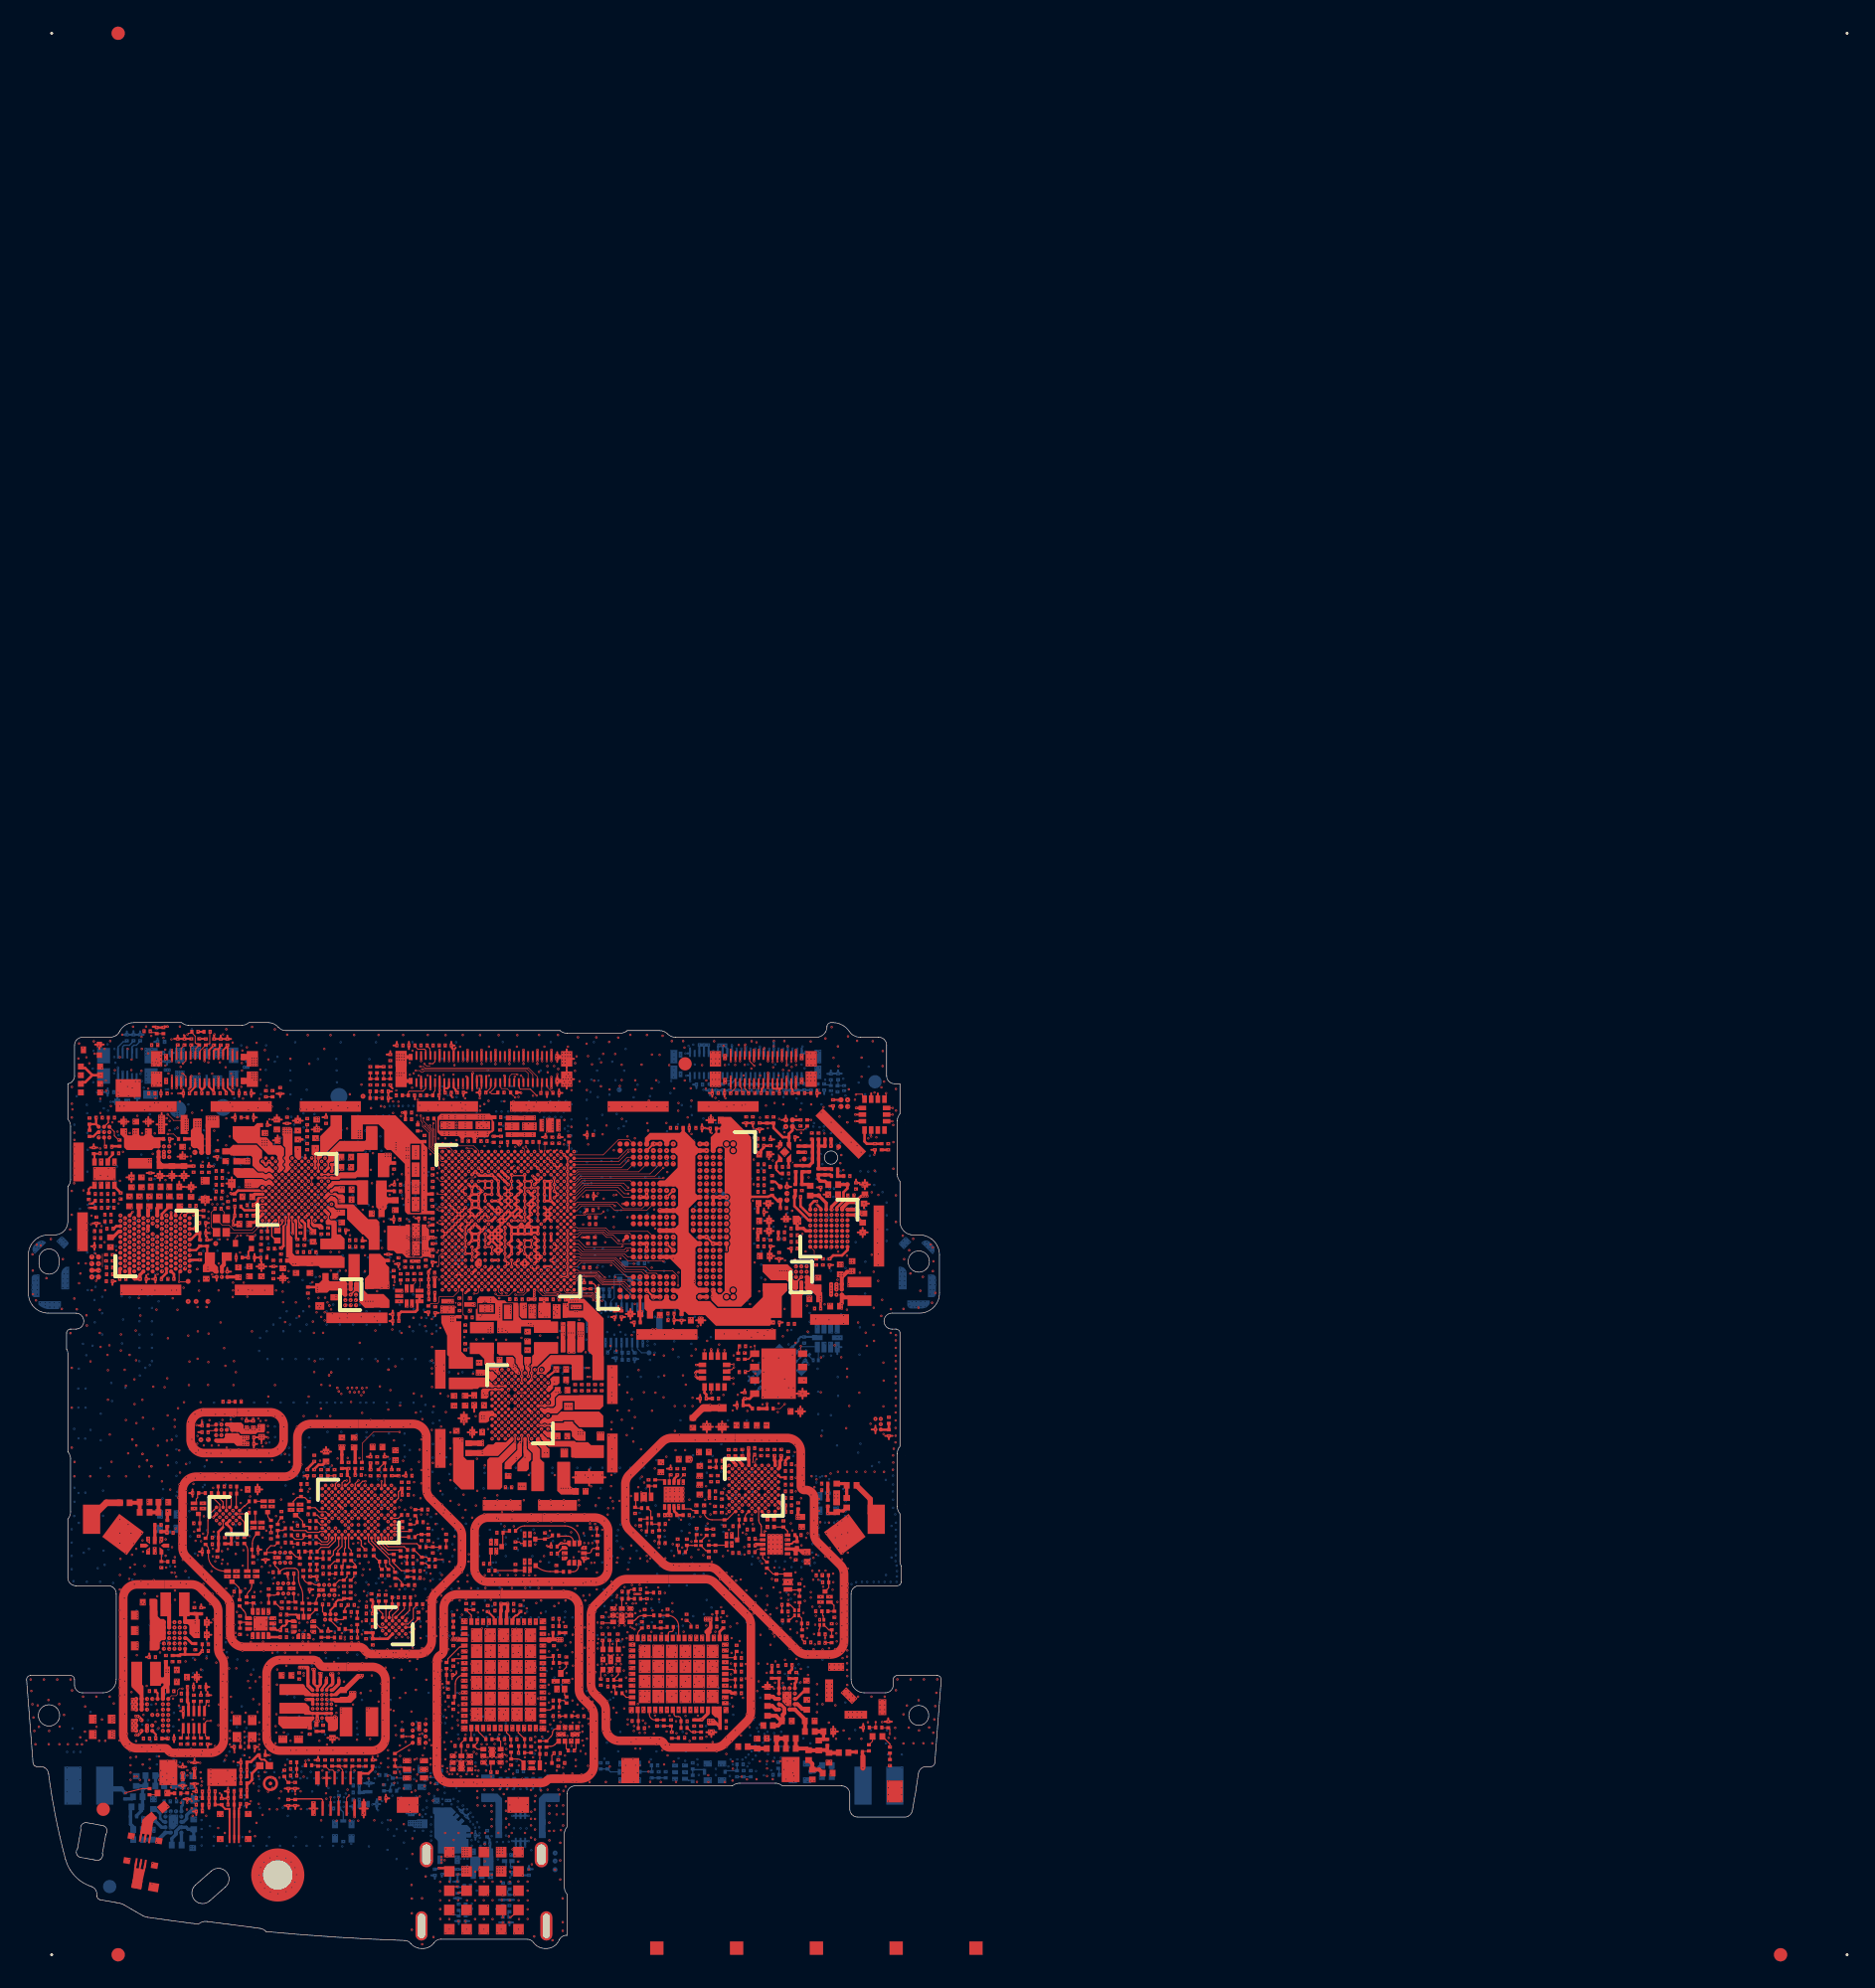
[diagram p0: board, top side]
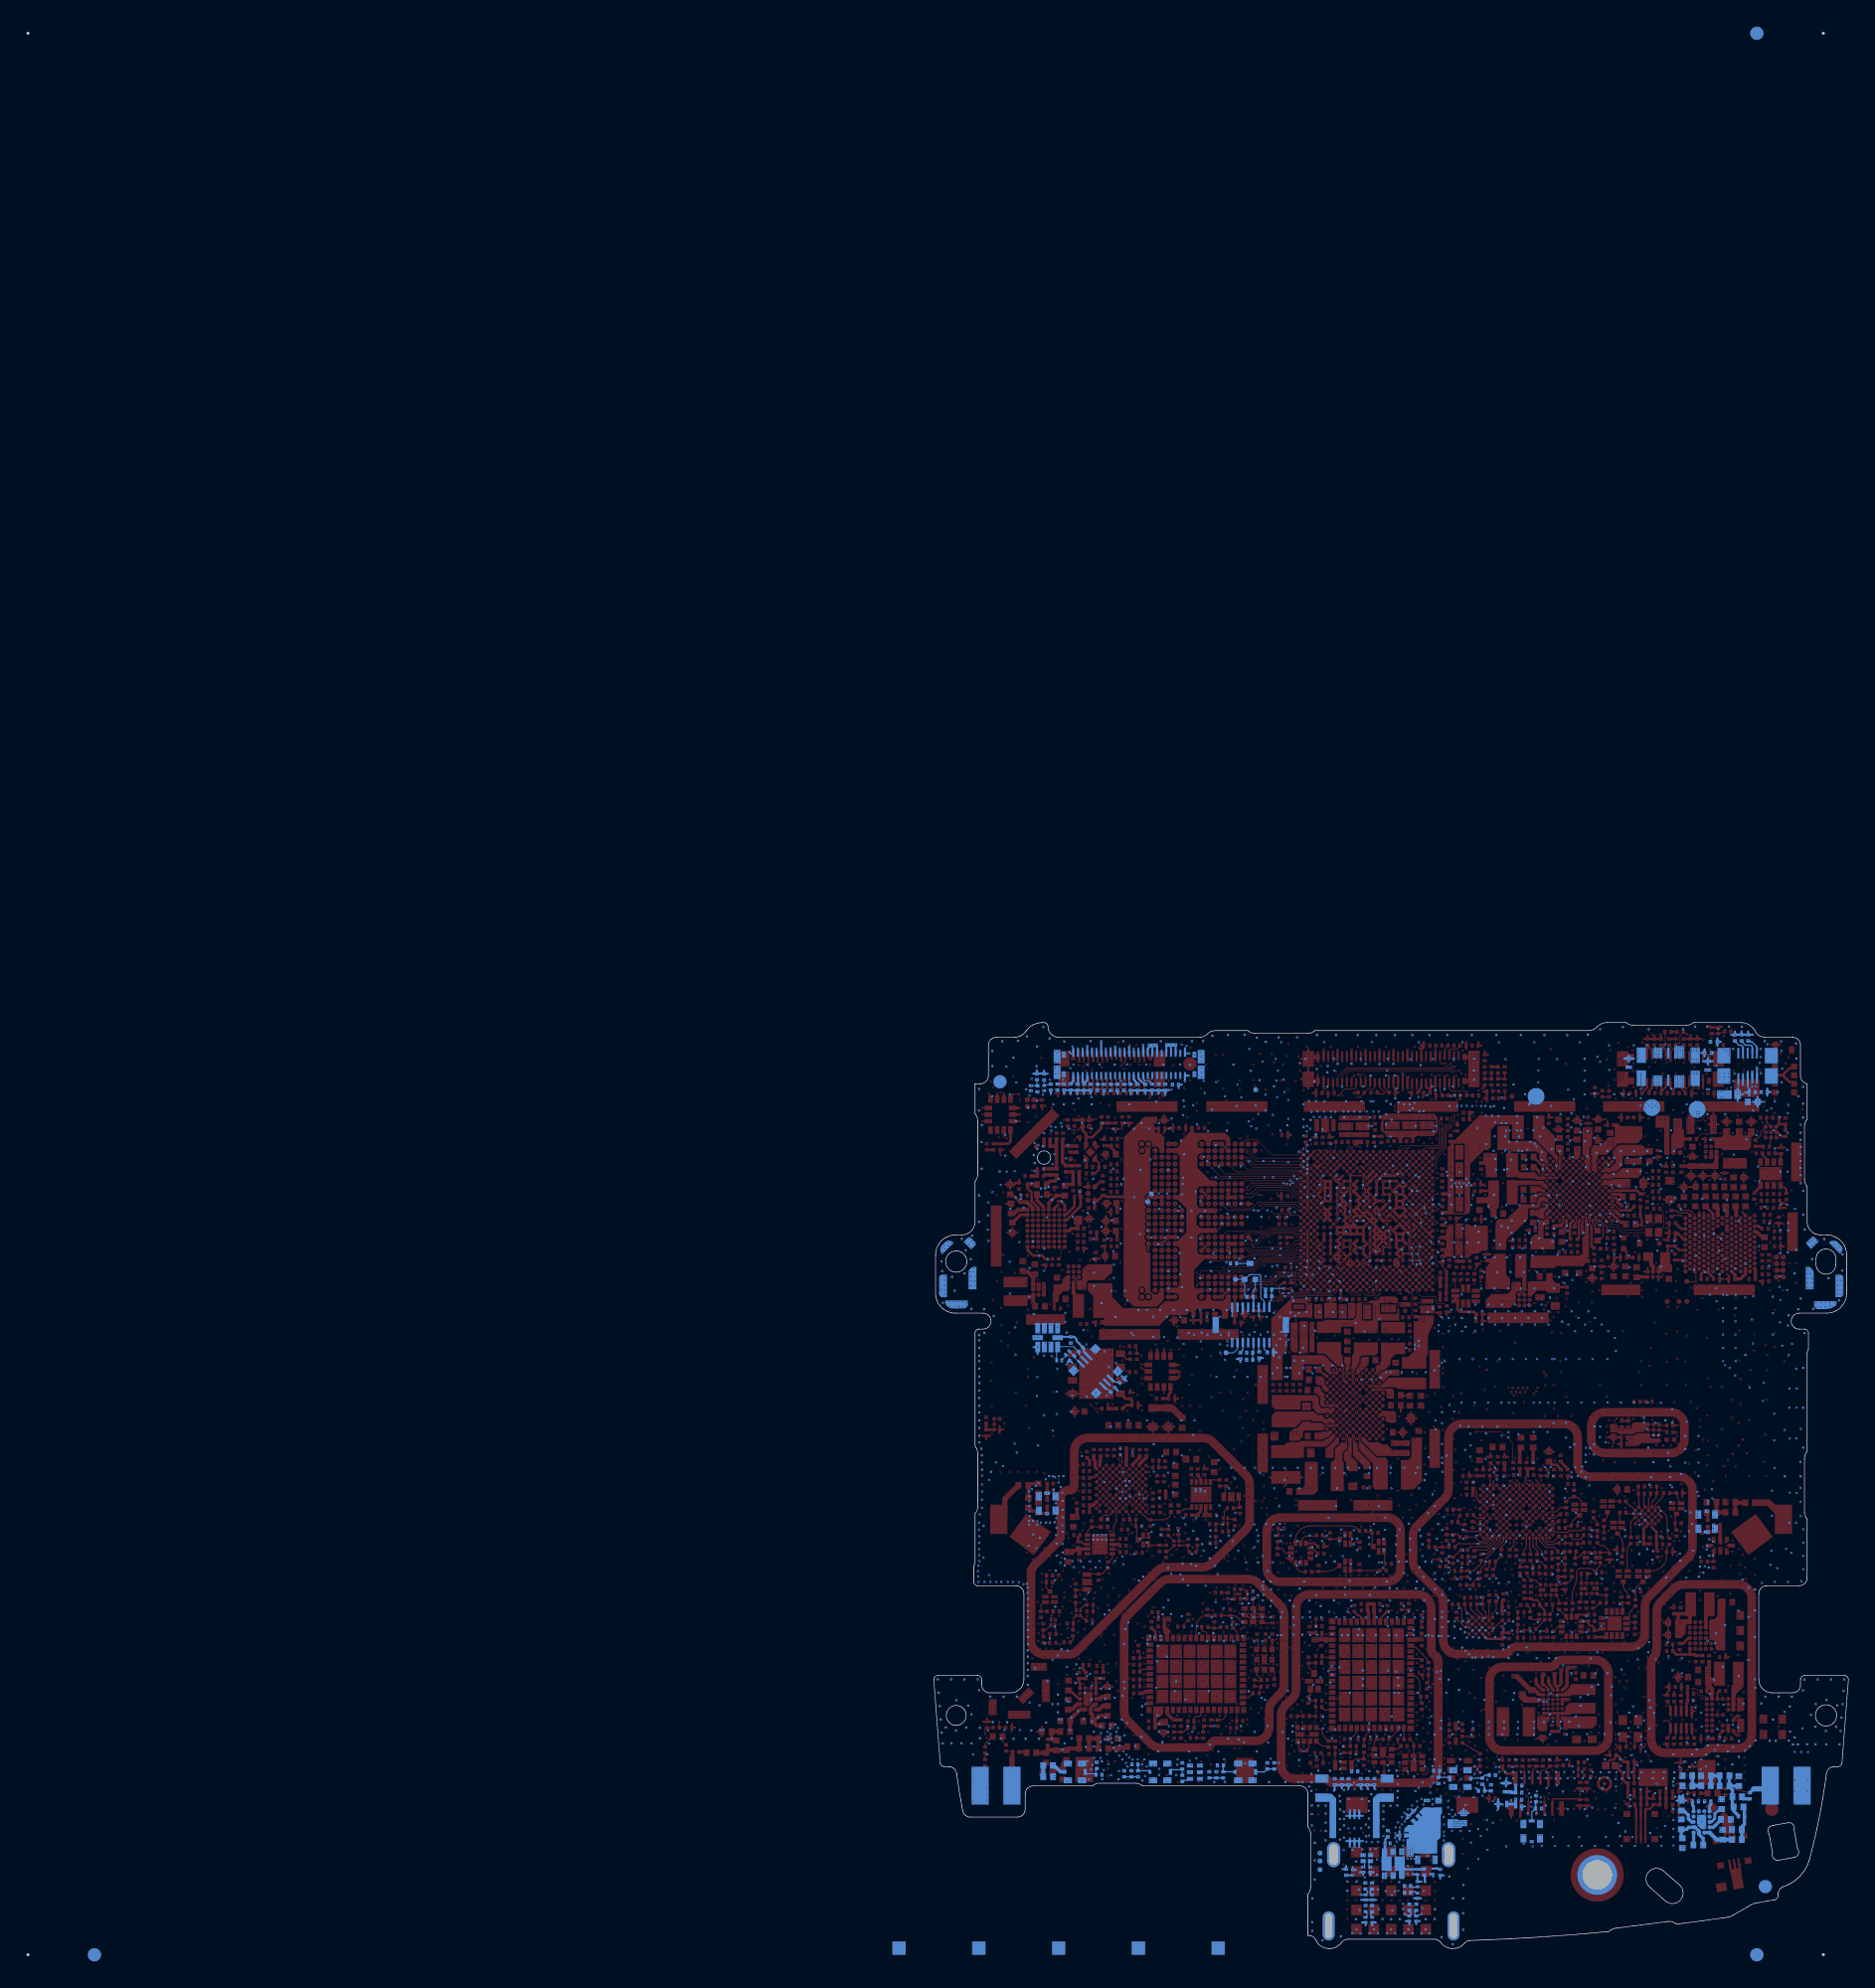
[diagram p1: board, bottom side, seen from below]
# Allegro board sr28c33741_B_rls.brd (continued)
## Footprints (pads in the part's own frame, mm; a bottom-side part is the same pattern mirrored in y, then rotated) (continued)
BGA13X11_5_B0_3_PS0_5_P254_HD
  round 0.4 smd: A1(-5.75,-4.25) A2(-5.75,-3.75) A3(-5.75,-3.25) A4(-5.75,-2.75) A5(-5.75,-2.25) A6(-5.75,-1.75) A7(-5.75,-1.25) A8(-5.75,-0.75) A9(-5.75,-0.25) A13(-5.75,1.75) A14(-5.75,2.25) A15(-5.75,2.75) A16(-5.75,3.25) A17(-5.75,3.75) A18(-5.75,4.25) AA3(4.25,-3.25) AA4(4.25,-2.75) AA5(4.25,-2.25) AA6(4.25,-1.75) AA7(4.25,-1.25) AA8(4.25,-0.75) AA9(4.25,-0.25) AA13(4.25,1.75) AA14(4.25,2.25) AA15(4.25,2.75) AA16(4.25,3.25) AB3(4.75,-3.25) AB4(4.75,-2.75) AB5(4.75,-2.25) AB6(4.75,-1.75) AB7(4.75,-1.25) AB8(4.75,-0.75) AB9(4.75,-0.25) AB13(4.75,1.75) AB14(4.75,2.25) AB15(4.75,2.75) AB16(4.75,3.25) AC1(5.25,-4.25) AC3(5.25,-3.25) AC4(5.25,-2.75) AC5(5.25,-2.25) AC6(5.25,-1.75) AC7(5.25,-1.25) AC8(5.25,-0.75) AC9(5.25,-0.25) AC13(5.25,1.75) AC14(5.25,2.25) AC15(5.25,2.75) AC16(5.25,3.25) AC18(5.25,4.25) AD1(5.75,-4.25) AD2(5.75,-3.75) AD3(5.75,-3.25) AD4(5.75,-2.75) AD5(5.75,-2.25) AD6(5.75,-1.75) AD7(5.75,-1.25) AD8(5.75,-0.75) AD9(5.75,-0.25) AD13(5.75,1.75) AD14(5.75,2.25) AD15(5.75,2.75) AD16(5.75,3.25) AD17(5.75,3.75) AD18(5.75,4.25) B1(-5.25,-4.25) B3(-5.25,-3.25) B4(-5.25,-2.75) B5(-5.25,-2.25) B6(-5.25,-1.75) B7(-5.25,-1.25) B8(-5.25,-0.75) B9(-5.25,-0.25) B13(-5.25,1.75) B14(-5.25,2.25) B15(-5.25,2.75) B16(-5.25,3.25) B18(-5.25,4.25) C3(-4.75,-3.25) C4(-4.75,-2.75) C5(-4.75,-2.25) C6(-4.75,-1.75) C7(-4.75,-1.25) C8(-4.75,-0.75) C9(-4.75,-0.25) C13(-4.75,1.75) C14(-4.75,2.25) C15(-4.75,2.75) C16(-4.75,3.25) D3(-4.25,-3.25) D4(-4.25,-2.75) D5(-4.25,-2.25) D6(-4.25,-1.75) D7(-4.25,-1.25) D8(-4.25,-0.75) D9(-4.25,-0.25) D13(-4.25,1.75) D14(-4.25,2.25) D15(-4.25,2.75) D16(-4.25,3.25) E13(-3.75,1.75) E14(-3.75,2.25) E15(-3.75,2.75) E16(-3.75,3.25) F13(-3.25,1.75) F14(-3.25,2.25) F15(-3.25,2.75) F16(-3.25,3.25) G3(-2.75,-3.25) G4(-2.75,-2.75) G5(-2.75,-2.25) G6(-2.75,-1.75) G7(-2.75,-1.25) G8(-2.75,-0.75) G9(-2.75,-0.25) G13(-2.75,1.75) G14(-2.75,2.25) G15(-2.75,2.75) G16(-2.75,3.25) H3(-2.25,-3.25) H4(-2.25,-2.75) H5(-2.25,-2.25) H6(-2.25,-1.75) H7(-2.25,-1.25) H8(-2.25,-0.75) H9(-2.25,-0.25) H13(-2.25,1.75) H14(-2.25,2.25) H15(-2.25,2.75) H16(-2.25,3.25) J3(-1.75,-3.25) J4(-1.75,-2.75) J5(-1.75,-2.25) J6(-1.75,-1.75) J7(-1.75,-1.25) J8(-1.75,-0.75) J9(-1.75,-0.25) J13(-1.75,1.75) J14(-1.75,2.25) J15(-1.75,2.75) J16(-1.75,3.25) J17(-1.75,3.75) K2(-1.25,-3.75) K3(-1.25,-3.25) K4(-1.25,-2.75) K5(-1.25,-2.25) K6(-1.25,-1.75) K7(-1.25,-1.25) K8(-1.25,-0.75) K9(-1.25,-0.25) K13(-1.25,1.75) K14(-1.25,2.25) K15(-1.25,2.75) K16(-1.25,3.25) K17(-1.25,3.75) L7(-0.75,-1.25) L8(-0.75,-0.75) L9(-0.75,-0.25) L12(-0.75,1.25) L13(-0.75,1.75) L14(-0.75,2.25) L15(-0.75,2.75) L16(-0.75,3.25) L17(-0.75,3.75) M3(-0.25,-3.25) M4(-0.25,-2.75) M5(-0.25,-2.25) M6(-0.25,-1.75) M7(-0.25,-1.25) M8(-0.25,-0.75) M9(-0.25,-0.25) M12(-0.25,1.25) M13(-0.25,1.75) M14(-0.25,2.25) M15(-0.25,2.75) M16(-0.25,3.25) M17(-0.25,3.75) N3(0.25,-3.25) N4(0.25,-2.75) N5(0.25,-2.25) N6(0.25,-1.75) N7(0.25,-1.25) N8(0.25,-0.75) N9(0.25,-0.25) N12(0.25,1.25) N13(0.25,1.75) N14(0.25,2.25) N15(0.25,2.75) N16(0.25,3.25) N17(0.25,3.75) P7(0.75,-1.25) P8(0.75,-0.75) P9(0.75,-0.25) P12(0.75,1.25) P13(0.75,1.75) P14(0.75,2.25) P15(0.75,2.75) P16(0.75,3.25) P17(0.75,3.75) R2(1.25,-3.75) R3(1.25,-3.25) R4(1.25,-2.75) R5(1.25,-2.25) R6(1.25,-1.75) R7(1.25,-1.25) R8(1.25,-0.75) R9(1.25,-0.25) R13(1.25,1.75) R14(1.25,2.25) R15(1.25,2.75) R16(1.25,3.25) R17(1.25,3.75) T3(1.75,-3.25) T4(1.75,-2.75) T5(1.75,-2.25) T6(1.75,-1.75) T7(1.75,-1.25) T8(1.75,-0.75) T9(1.75,-0.25) T13(1.75,1.75) T14(1.75,2.25) T15(1.75,2.75) T16(1.75,3.25) T17(1.75,3.75) U3(2.25,-3.25) U4(2.25,-2.75) U5(2.25,-2.25) U6(2.25,-1.75) U7(2.25,-1.25) U8(2.25,-0.75) U9(2.25,-0.25) U13(2.25,1.75) U14(2.25,2.25) U15(2.25,2.75) U16(2.25,3.25) V3(2.75,-3.25) V4(2.75,-2.75) V5(2.75,-2.25) V6(2.75,-1.75) V7(2.75,-1.25) V8(2.75,-0.75) V9(2.75,-0.25) V13(2.75,1.75) V14(2.75,2.25) V15(2.75,2.75) V16(2.75,3.25) W13(3.25,1.75) W14(3.25,2.25) W15(3.25,2.75) W16(3.25,3.25) Y13(3.75,1.75) Y14(3.75,2.25) Y15(3.75,2.75) Y16(3.75,3.25)
CAP1_2X0_7_HD
  rect 0.45x0.5 smd: 1(-0.37,0) 2(0.37,0)
CAP1_2X0_9_P3_HD
  rect 0.35x0.95 smd: 1(-0.625,0) 3(0.625,0)
  rect 0.6x1.1 smd: 2(0,0)
CAP1X0_5-HT0_5_P3_HD
  rect 0.3x0.3 smd: 1(-0.465,0) 3(0.465,0)
  rect 0.35x0.85 smd: 2(0,0)
CAP0201-HT0_33_HD
  rect 0.25x0.3 smd: 1(-0.23,0) 2(0.23,0)
CAP0201-HT0_35_HD
  rect 0.25x0.3 smd: 1(-0.23,0) 2(0.23,0)
CAP0201_HD
  rect 0.25x0.3 smd: 1(-0.23,0) 2(0.23,0)
CAP0402-HT0_6_HD
  rect 0.45x0.5 smd: 1(-0.37,0) 2(0.37,0)
CAP0402-HT0_55_HD
  rect 0.45x0.5 smd: 1(-0.37,0) 2(0.37,0)
CAP0402-HT0_65_HD
  rect 0.45x0.5 smd: 1(-0.37,0) 2(0.37,0)
CAP0402_1_2X0_7-HT0_65_HD
  rect 0.45x0.5 smd: 1(-0.37,0) 2(0.37,0)
CAP0402_1_2X0_7_HD
  rect 0.45x0.5 smd: 1(-0.37,0) 2(0.37,0)
CAP0603-HT0_6_HD
  rect 0.58x0.68 smd: 1(-0.71,0) 2(0.71,0)
CAP0603-HT1_HD
  rect 0.58x0.68 smd: 1(-0.71,0) 2(0.71,0)
COUPLER0_65X0_5_PS0_39_P4_XD
  rect 0.285x0.215 smd: 1(-0.192,-0.158) 2(0.193,-0.158) 3(0.192,0.158) 4(-0.193,0.158)
CSF1X2JSM_4G_PS1_55-HT0_9_P6_HD
  rect 0.45x0.25 smd: 1(0,-0.773)
  rect 0.3x0.25 smd: 2(0,0.777)
  rect 0.45x0.625 smd: 3(-0.625,-0.536) 4(-0.625,0.54) 5(0.625,0.54) 6(0.625,-0.536)
CSF1X6_1X7R_PS0_6-HT2_14_P13_HD
  rect 1.1x0.36 smd: 1(-1.225,-1.89) 13(-1.225,1.89)
  rect 1x0.36 smd: 2(1.075,-1.59) 12(1.075,1.59)
  rect 1.1x0.18 smd: 3(-1.225,-1.2) 5(-1.225,-0.6) 7(-1.225,0) 9(-1.225,0.6) 11(-1.225,1.2)
  rect 1x0.18 smd: 4(1.075,-0.9) 6(1.075,-0.3) 8(1.075,0.3) 10(1.075,0.9)
CSF2X3BH0_6_4G_PS0_8_P10_HD
  rect 0.71x0.8 smd: 1(-0.8,-1.05) 2(-0.8,1.05) 5(0.8,-1.05) 6(0.8,1.05)
  rect 0.18x0.85 smd: 3(0,-1.025) 4(0,1.025)
  rect 0.7x1.17 smd: G1(-2.025,-0.865) G2(-2.025,0.865) G3(2.025,-0.865) G4(2.025,0.865)
CSF2X3BH0_6_4G_PS0_35_P10_XD
  rect 0.15x0.62 smd: 1(-0.35,-0.94) 2(-0.35,0.94) 3(0,-0.94) 4(0,0.94) 5(0.35,-0.94) 6(0.35,0.94)
  rect 0.51x0.46 smd: G1(-1.055,-0.94) G2(-1.055,0.94) G3(1.055,-0.94) G4(1.055,0.94)
CSF2X3BH0_7_4G_PS0_4-HT0_88_P10_HD
  rect 0.18x0.75 smd: 1(-0.4,-1.175) 2(-0.4,1.175) 3(0,-1.175) 4(0,1.175) 5(0.4,-1.175) 6(0.4,1.175)
  rect 0.6x0.57 smd: G1(-1.15,-1.195) G2(-1.15,1.195) G3(1.15,-1.195) G4(1.15,1.195)
CSF2X3BH1_4G_PS0_35_P10_XD
  rect 0.15x0.5 smd: 1(-0.35,-0.95) 2(-0.35,0.95) 3(0,-0.95) 4(0,0.95) 5(0.35,-0.95) 6(0.35,0.95)
  rect 0.5x0.485 smd: G1(-1.63,-0.482) G2(-1.63,0.482) G3(1.63,-0.482) G4(1.63,0.482)
CSF2X5BH0_7_4G_PS0_35_P14_XD
  rect 0.15x0.8 smd: 1(-0.7,-0.95) 2(-0.7,0.95) 3(-0.35,-0.95) 4(-0.35,0.95) 5(0,-0.95) 6(0,0.95) 7(0.35,-0.95) 8(0.35,0.95) 9(0.7,-0.95) 10(0.7,0.95)
  rect 0.98x1.17 smd: G1(-1.785,-0.765) G2(-1.785,0.765) G3(1.785,-0.765) G4(1.785,0.765)
CSF2X8BH0_98_2G_PS0_4-HT1_08_P18_HD
  rect 0.18x0.73 smd: 1(-1.4,-1.325) 2(-1.4,1.325) 3(-1,-1.325) 4(-1,1.325) 5(-0.6,-1.325) 6(-0.6,1.325) 7(-0.2,-1.325) 8(-0.2,1.325) 9(0.2,-1.325) 10(0.2,1.325) 11(0.6,-1.325) 12(0.6,1.325) 13(1,-1.325) 14(1,1.325) 15(1.4,-1.325) 16(1.4,1.325)
  rect 0.48x1.2 smd: G1(-2.64,0) G2(2.64,0)
CSF2X15BH0_7_PS0_35_P38_XD
  rect 0.15x0.66 smd: 1(-2.45,-1.02) 2(-2.45,1.02) 3(-2.1,-1.02) 4(-2.1,1.02) 5(-1.75,-1.02) 6(-1.75,1.02) 7(-1.4,-1.02) 8(-1.4,1.02) 9(-1.05,-1.02) 10(-1.05,1.02) 11(-0.7,-1.02) 12(-0.7,1.02) 13(-0.35,-1.02) 14(-0.35,1.02) 15(0,-1.02) 16(0,1.02) 17(0.35,-1.02) 18(0.35,1.02) 19(0.7,-1.02) 20(0.7,1.02) 21(1.05,-1.02) 22(1.05,1.02) 23(1.4,-1.02) 24(1.4,1.02) 25(1.75,-1.02) 26(1.75,1.02) 27(2.1,-1.02) 28(2.1,1.02) 29(2.45,-1.02) 30(2.45,1.02)
  rect 0.85x1.17 smd: L1(-3.6,0.765) L2(-3.6,-0.765) R1(3.6,0.765) R2(3.6,-0.765)
  rect 0.3x0.48 smd: L3(-2.885,-0.9) L4(-2.885,0.9) R3(2.885,-0.9) R4(2.885,0.9)
CSF2X25BH0_7_8G_PS0_35_P58_XD
  rect 0.15x0.53 smd: 1(-4.2,-0.835) 2(-4.2,0.835) 3(-3.85,-0.835) 4(-3.85,0.835) 5(-3.5,-0.835) 6(-3.5,0.835) 7(-3.15,-0.835) 8(-3.15,0.835) 9(-2.8,-0.835) 10(-2.8,0.835) 11(-2.45,-0.835) 12(-2.45,0.835) 13(-2.1,-0.835) 14(-2.1,0.835) 15(-1.75,-0.835) 16(-1.75,0.835) 17(-1.4,-0.835) 18(-1.4,0.835) 19(-1.05,-0.835) 20(-1.05,0.835) 21(-0.7,-0.835) 22(-0.7,0.835) 23(-0.35,-0.835) 24(-0.35,0.835) 25(0,-0.835) 26(0,0.835) 27(0.35,-0.835) 28(0.35,0.835) 29(0.7,-0.835) 30(0.7,0.835) 31(1.05,-0.835) 32(1.05,0.835) 33(1.4,-0.835) 34(1.4,0.835) 35(1.75,-0.835) 36(1.75,0.835) 37(2.1,-0.835) 38(2.1,0.835) 39(2.45,-0.835) 40(2.45,0.835) 41(2.8,-0.835) 42(2.8,0.835) 43(3.15,-0.835) 44(3.15,0.835) 45(3.5,-0.835) 46(3.5,0.835) 47(3.85,-0.835) 48(3.85,0.835) 49(4.2,-0.835) 50(4.2,0.835)
  rect 0.52x1.02 smd: G1(-5.415,-0.59) G2(-5.415,0.59) G3(5.415,0.59) G4(5.415,-0.59)
  rect 0.28x0.45 smd: G5(-4.91,0.735) G6(-4.91,-0.735) G7(4.91,-0.735) G8(4.91,0.735)
CSF2X30BH0_7_8G_PS0_35_P68_XD
  rect 0.15x0.66 smd: 1(-5.075,-1.02) 2(-5.075,1.02) 3(-4.725,-1.02) 4(-4.725,1.02) 5(-4.375,-1.02) 6(-4.375,1.02) 7(-4.025,-1.02) 8(-4.025,1.02) 9(-3.675,-1.02) 10(-3.675,1.02) 11(-3.325,-1.02) 12(-3.325,1.02) 13(-2.975,-1.02) 14(-2.975,1.02) 15(-2.625,-1.02) 16(-2.625,1.02) 17(-2.275,-1.02) 18(-2.275,1.02) 19(-1.925,-1.02) 20(-1.925,1.02) 21(-1.575,-1.02) 22(-1.575,1.02) 23(-1.225,-1.02) 24(-1.225,1.02) 25(-0.875,-1.02) 26(-0.875,1.02) 27(-0.525,-1.02) 28(-0.525,1.02) 29(-0.175,-1.02) 30(-0.175,1.02) 31(0.175,-1.02) 32(0.175,1.02) 33(0.525,-1.02) 34(0.525,1.02) 35(0.875,-1.02) 36(0.875,1.02) 37(1.225,-1.02) 38(1.225,1.02) 39(1.575,-1.02) 40(1.575,1.02) 41(1.925,-1.02) 42(1.925,1.02) 43(2.275,-1.02) 44(2.275,1.02) 45(2.625,-1.02) 46(2.625,1.02) 47(2.975,-1.02) 48(2.975,1.02) 49(3.325,-1.02) 50(3.325,1.02) 51(3.675,-1.02) 52(3.675,1.02) 53(4.025,-1.02) 54(4.025,1.02) 55(4.375,-1.02) 56(4.375,1.02) 57(4.725,-1.02) 58(4.725,1.02) 59(5.075,-1.02) 60(5.075,1.02)
  rect 0.85x1.17 smd: L1(-6.225,0.765) L2(-6.225,-0.765) R1(6.225,0.765) R2(6.225,-0.765)
  rect 0.3x0.48 smd: L3(-5.51,-0.9) L4(-5.51,0.9) R3(5.51,-0.9) R4(5.51,0.9)
CSF5X5US_SZ11_09X8_72_4G_PS1_3X1_45_P29_HD
  rect 0.8x0.8 smd: 1(-2.6,2.89) 2(-1.3,2.89) 3(0,2.89) 4(1.3,2.89) 5(2.6,2.89) 6(-2.6,1.44) 7(-1.3,1.44) 8(0,1.44) 9(1.3,1.44) 10(2.6,1.44) 11(-2.6,-0.01) 12(-1.3,-0.01) 13(0,-0.01) 14(1.3,-0.01) 15(2.6,-0.01) 16(-2.6,-1.46) 17(-1.3,-1.46) 18(0,-1.46) 19(1.3,-1.46) 20(2.6,-1.46) 21(-2.6,-2.91) 22(-1.3,-2.91) 23(0,-2.91) 24(1.3,-2.91) 25(2.6,-2.91)
  oval 1x1.9 hole 0.6x1.5: G1(-4.32,2.7) G2(4.32,2.7)
  oval 0.9x2.2 hole 0.5x1.8: G3(4.695,-2.66) G4(-4.695,-2.66)
DFN1_7X2_CTG1_45X1_09_PS0_35_P11_XD
  rect 0.25x0.43 smd: 1(-0.7,-0.935) 2(-0.35,-0.935) 3(0,-0.935) 4(0.35,-0.935) 5(0.7,-0.935) 6(0.7,0.935) 7(0.35,0.935) 8(0,0.935) 9(-0.35,0.935) 10(-0.7,0.935)
  rect 1.55x1.19 smd: G1(0,0)
DFN1SQ_CTG0_48SQ_PS0_65_P5_HD
  custom 0.087x0.087 smd: 1(-0.325,-0.43) 2(0.325,-0.43) 3(0.325,0.43) 4(-0.325,0.43)
  rect 0.53x0.53 smd rot 45: G1(0,0)
DFN2_1X1_8_PS0_4_P10_HD
  rect 0.22x0.79 smd: 1(-0.8,-0.645) 2(-0.4,-0.645) 3(0,-0.645) 4(0.4,-0.645) 5(0.8,-0.645) 6(0.8,0.645) 7(0.4,0.645) 8(0,0.645) 9(-0.4,0.645) 10(-0.8,0.645)
DFN2SQ_CTG1_6X0_9_PS0_5_P9_HD
  rect 0.35x0.55 smd: 1(-0.75,-0.875) 2(-0.25,-0.875) 3(0.25,-0.875) 4(0.75,-0.875) 5(0.75,0.875) 6(0.25,0.875) 7(-0.25,0.875) 8(-0.75,0.875)
  rect 1.7x1 smd: G1(0,0)
DFN2SQ_PS0_65_P8_HD
  rect 0.4x0.5 smd: 1(-0.65,-0.9) 2(0,-0.9) 3(0.65,-0.9) 4(0.65,0.9) 5(0,0.9) 6(-0.65,0.9)
  rect 0.77x1.1 smd: 7(-0.49,0) 8(0.49,0)
DFN4_2X4_CTG3_8X2_6_PS1_P9_HD
  rect 0.5x0.7 smd: 1(-1.5,-1.8) 2(-0.5,-1.8) 3(0.5,-1.8) 4(1.5,-1.8) 5(1.5,1.8) 6(0.5,1.8) 7(-0.5,1.8) 8(-1.5,1.8)
  rect 3.8x2.6 smd: G1(0,0)
DIO0_6X0_3-HT0_32_HD
  rect 0.25x0.3 smd: 1(-0.23,0) 2(0.23,0)
DIO0_6X0_3_PS0_4-HT0_32_HD
  rect 0.15x0.25 smd: 1(-0.2,0) 2(0.2,0)
DIO0_6X0_3_PS0_38_HD
  rect 0.21x0.3 smd: 1(-0.19,0) 2(0.19,0)
DIO0_6X0_3_PS0_525-HT0_33_HD
  rect 0.275x0.3 smd: 1(-0.263,0) 2(0.263,0)
DIO0_6X0_3BI_HD
  rect 0.25x0.3 smd: 1(-0.23,0) 2(0.23,0)
DIO0_6X0_3BI_PS0_38_HD
  rect 0.21x0.3 smd: 1(-0.19,0) 2(0.19,0)
DIO0_62X0_32-HT0_27_HD
  rect 0.25x0.3 smd: 1(-0.23,0) 2(0.23,0)
DIO1_6X0_8K1A2_HD
  rect 1.12x0.645 smd: 1(-0.345,0)
  rect 0.49x0.71 smd: 2(0.66,0)
DIO1X0_6_PS0_65_HD
  rect 0.25x0.5 smd: 1(-0.325,0) 2(0.325,0)
DIO1X0_6BI_HD
  rect 0.25x0.5 smd: 1(-0.325,0) 2(0.325,0)
DIO1X0_6K1A2_PS0_65_HD
  rect 0.25x0.5 smd: 1(-0.325,0) 2(0.325,0)
DIO2SQ_PS1_3_P3_HD
  rect 0.4x0.65 smd: 1(-0.65,-0.825) 2(0.65,-0.825)
  custom 0.375x0.375 smd: 3(0,0.4)
FLTR0_8X1_6_P4_HD
  rect 0.75x0.325 smd: 1(0,-0.613) 3(0,0.613)
  rect 0.32x0.5 smd: 2(0.215,0) 4(-0.215,0)
FLTR0_8X1_6_PS0_5-HT0_7_P6_HD
  rect 0.45x0.3 smd: 1(-0.375,-0.5) 2(-0.375,0) 3(-0.375,0.5) 4(0.375,0.5) 5(0.375,0) 6(0.375,-0.5)
FLTR1_1X0_9-HT0_5_P5_HD
  rect 0.35x0.4 smd: 1(-0.4,0)
  rect 0.3x0.52 smd: 2(0,-0.335) 3(0.4,-0.335) 4(0.4,0.335) 5(0,0.335)
FLTR1_1X0_9_PS0_4X0_5_P5_HD
  rect 0.33x0.38 smd: 1(-0.4,0)
  rect 0.28x0.5 smd: 2(0,-0.335) 3(0.4,-0.335) 4(0.4,0.335) 5(0,0.335)
FLTR1_1X0_9_PS0_4X0_55_P5_HD
  rect 0.33x0.38 smd: 1(-0.425,0)
  rect 0.28x0.5 smd: 2(0,-0.3) 3(0.4,-0.3) 4(0.4,0.3) 5(0,0.3)
FLTR1_5X1_1_PS0_39-HT0_5_P10_HD
  round 0.31 smd: 1(-0.585,-0.385) 2(-0.195,-0.385) 3(0.195,-0.385) 4(0.585,-0.385) 6(0.585,0.385) 7(0.195,0.385) 8(-0.195,0.385) 9(-0.585,0.385)
  rect 0.49x0.28 smd: 5(0.48,0)
  rect 0.59x0.28 smd: 10(-0.43,0)
FLTR1_6X0_8-HT0_65_P3_HD
  rect 0.35x0.65 smd: 1(-0.555,0) 3(0.555,0)
  rect 0.5x0.7 smd: 2(0,0)
FLTR1_6X0_8_PS0_5-HT0_7_P8_HD
  custom 0.075x0.075 smd: 1(-0.5,-0.39) 3(0.5,-0.39) 4(0.77,0) 5(0.5,0.39) 7(-0.5,0.39) 8(-0.77,0)
  rect 0.3x0.58 smd: 2(0,-0.39) 6(0,0.39)
FLTR1_8X1_4_PS0_45_P10_HD
  round 0.32 smd: 1(-0.7,-0.485) 2(-0.225,-0.485) 3(0.225,-0.485) 4(0.7,-0.485) 6(0.7,0.485) 7(0.225,0.485) 8(-0.225,0.485) 9(-0.7,0.485)
  rect 0.7x0.3 smd: 5(0.525,0)
  rect 0.6x0.3 smd: 10(-0.575,0)
FLTR1_8X1_4_PS0_65-HT0_48_P8_HD
  rect 0.45x0.35 smd: 1(-0.65,-0.5) 3(0.65,-0.5) 4(0.65,0) 5(0.65,0.5) 6(0,0.5) 7(-0.65,0.5) 8(-0.65,0)
  rect 0.45x0.8 smd: 2(0,-0.275)
FLTR1_8X1_4_PS0_65_P8_HD
  rect 0.45x0.35 smd: 1(-0.65,-0.5) 3(0.65,-0.5) 4(0.65,0) 5(0.65,0.5) 6(0,0.5) 7(-0.65,0.5) 8(-0.65,0)
  rect 0.45x0.85 smd: 2(0,-0.25)
FLTR1_8X1_35-HT0_5_P10_HD
  rect 0.35x0.4 smd: 1(-0.705,-0.515) 2(-0.235,-0.515) 3(0.235,-0.515) 4(0.705,-0.515) 6(0.705,0.515) 7(0.235,0.515) 8(-0.235,0.515) 9(-0.705,0.515)
  rect 0.7x0.35 smd: 5(0.52,0) 10(-0.52,0)
FLTR1_35X1_05CCW-HT0_5_P5_HD
  rect 0.525x0.425 smd: 1(-0.587,0) 3(0.587,-0.287) 4(0.587,0.287)
  rect 0.35x0.625 smd: 2(0,-0.387) 5(0,0.387)
FLTR1X0_5_P4_HD
  rect 0.27x0.3 smd: 1(-0.48,0) 3(0.48,0)
  rect 0.3x0.25 smd: 2(0,0.24) 4(0,-0.24)
FLTR1X0_5_PS0_5_P4_HD
  rect 0.3x0.32 smd: 1(-0.25,-0.29) 2(0.25,-0.29) 3(0.25,0.29) 4(-0.25,0.29)
FLTR2_5X2_PS0_65_P6_HD
  rect 0.4x0.625 smd: 1(-0.65,-0.637) 2(0,-0.637) 3(0.65,-0.637) 4(0.65,0.637) 5(0,0.637) 6(-0.65,0.637)
FLTR2X1_6_PS0_76X0_58_P9_HD
  rect 0.43x0.39 smd: 1(-0.76,-0.58) 2(0,-0.58) 3(0.76,-0.58) 4(0.76,0) 5(0.76,0.58) 6(0,0.58) 7(-0.76,0.58) 8(-0.76,0)
  rect 0.71x0.39 smd: 9(0,0)
IND0_5X0_65-HT0_35_P4_HD
  rect 0.3x0.4 smd: 1(-0.225,-0.275) 2(-0.225,0.275) 3(0.225,0.275) 4(0.225,-0.275)
IND2_5X2_PS1_95_HD
  rect 0.95x2.2 smd: 1(-0.975,0) 2(0.975,0)
IND2X1_6_PS1_4_HD
  rect 0.8x1.8 smd: 1(-0.7,0) 2(0.7,0)
IND2X1_6_PS1_55_HD
  rect 0.85x1.8 smd: 1(-0.775,0) 2(0.775,0)
IND0201-HT0_33_HD
  rect 0.25x0.3 smd: 1(-0.23,0) 2(0.23,0)
IND0201-HT0_35_HD
  rect 0.25x0.3 smd: 1(-0.23,0) 2(0.23,0)
IND0603-HT0_95_HD
  rect 0.76x0.65 smd: 1(-0.635,0) 2(0.635,0)
IND0603_HD
  rect 0.76x0.65 smd: 1(-0.635,0) 2(0.635,0)
IND0603_SZ1_65X0_99-HT1_HD
  rect 0.61x0.99 smd: 1(-0.72,0) 2(0.72,0)
IND1005-HT0_6_HD
  rect 0.45x0.5 smd: 1(-0.37,0) 2(0.37,0)
INDP0402-HT0_55_HD
  rect 0.45x0.5 smd: 1(-0.37,0) 2(0.37,0)
LGA1_1X0_7-HT0_4_P6_HD
  round 0.32 smd: 1(-0.4,-0.2) 2(0,-0.2) 3(0.4,-0.2) 4(0.4,0.2) 5(0,0.2) 6(-0.4,0.2)
LGA1_6SQ_PS0_4_P12_XD
  custom 0.075x0.075 smd: 1(-0.4,-0.725) 3(0.4,-0.725) 4(0.725,-0.4) 6(0.725,0.4) 7(0.4,0.725) 9(-0.4,0.725) 10(-0.725,0.4) 12(-0.725,-0.4)
  rect 0.3x0.45 smd: 2(0,-0.725) 8(0,0.725)
  rect 0.45x0.3 smd: 5(0.725,0) 11(-0.725,0)
LGA1_6X2_CTG0_6X1_PS0_4_P15_HD
  round 0.32 smd: 1(-0.6,-0.8) 2(-0.2,-0.8) 3(0.2,-0.8) 4(0.6,-0.8) 5(0.6,-0.4) 6(0.6,0) 7(0.6,0.4) 8(0.6,0.8) 9(0.2,0.8) 10(-0.2,0.8) 11(-0.6,0.8) 12(-0.6,0.4) 13(-0.6,0) 14(-0.6,-0.4)
  custom 0.175x0.175 smd: 15(0,0)
LGA2_5X3_PS0_5_P14_HD
  rect 0.35x0.575 smd: 1(-0.75,-1.162) 2(-0.25,-1.162) 3(0.25,-1.162) 4(0.75,-1.162) 8(0.75,1.162) 9(0.25,1.162) 10(-0.25,1.162) 11(-0.75,1.162)
  rect 0.575x0.35 smd: 5(0.912,-0.5) 6(0.912,0) 7(0.912,0.5) 12(-0.912,0.5) 13(-0.912,0) 14(-0.912,-0.5)
LGA2X2_5_PS0_65-HT1_P8_HD
  rect 0.45x0.45 smd: 1(-0.725,-0.975) 2(-0.725,-0.325) 3(-0.725,0.325) 4(-0.725,0.975) 5(0.725,0.975) 6(0.725,0.325) 7(0.725,-0.325) 8(0.725,-0.975)
MECH0_7X2_83_HD
  rect 0.8x2.93 smd: 1(0,0)
MECH0_7X4_5_HD
  rect 0.8x4.6 smd: 1(0,0)
MECH1_2X2_5_HD
  rect 1.3x2.2 smd: 1(0,-0.3)
MECH1_2X3_45EL2_76_HD
  rect 1.3x2.86 smd: 1(0,-0.345)
MECH1_8X4_52-HT0_93_HD
  rect 1.9x1.35 smd: 1(0,-1.633)
MECH2_2X5_09_HD
  rect 2.3x2.15 smd: 1(0,-1.518)
MECH2_4X1_1_HD
  rect 1.64x1.2 smd: 1(0.43,0)
MECH2_97X5_472MX_HD
  custom 0.15x0.15 smd: 1(-0.015,-2.386) 2(1.185,-0.396) 5(-1.026,-0.986)
  custom 0.15x0.15 smd rot 45: 3(1.016,2.249)
  custom 0.125x0.125 smd rot 135: 4(-0.827,1.996)
MECH2_97X5_507_HD
  custom 0.15x0.15 smd: 1(-0.015,-2.454) 2(1.045,-1.004) 5(-1.185,-0.413)
  custom 0.125x0.125 smd rot 45: 3(0.851,2.001)
  custom 0.15x0.15 smd rot 135: 4(-1.005,2.268)
MECH4_5X4_1_HD
  rect 1.7x0.6 smd: 1(0.005,-1.8)
  rect 0.6x1.2 smd: 2(2,-1.232)
  rect 1.2x0.6 smd rot 135: 3(-0.501,-0.367)
  rect 1.2x0.6 smd: 4(-1.471,1.8)
  rect 0.6x1.7 smd: 5(-2,0.013)
PA7_6X6_CTG24_PS0_44_P80_HD
  rect 0.39x0.47 smd: 1(-3.555,-2.715) 17(3.555,-2.715) 29(3.555,2.715) 45(-3.555,2.715)
  rect 0.32x0.5 smd: 2(-3.08,-2.7) 3(-2.64,-2.7) 4(-2.2,-2.7) 5(-1.76,-2.7) 6(-1.32,-2.7) 7(-0.88,-2.7) 8(-0.44,-2.7) 9(0,-2.7) 10(0.44,-2.7) 11(0.88,-2.7) 12(1.32,-2.7) 13(1.76,-2.7) 14(2.2,-2.7) 15(2.64,-2.7) 16(3.08,-2.7) 30(3.08,2.7) 31(2.64,2.7) 32(2.2,2.7) 33(1.76,2.7) 34(1.32,2.7) 35(0.88,2.7) 36(0.44,2.7) 37(0,2.7) 38(-0.44,2.7) 39(-0.88,2.7) 40(-1.32,2.7) 41(-1.76,2.7) 42(-2.2,2.7) 43(-2.64,2.7) 44(-3.08,2.7)
  rect 0.5x0.32 smd: 18(3.5,-2.2) 19(3.5,-1.76) 20(3.5,-1.32) 21(3.5,-0.88) 22(3.5,-0.44) 23(3.5,0) 24(3.5,0.44) 25(3.5,0.88) 26(3.5,1.32) 27(3.5,1.76) 28(3.5,2.2) 46(-3.5,2.2) 47(-3.5,1.76) 48(-3.5,1.32) 49(-3.5,0.88) 50(-3.5,0.44) 51(-3.5,0) 52(-3.5,-0.44) 53(-3.5,-0.88) 54(-3.5,-1.32) 55(-3.5,-1.76) 56(-3.5,-2.2)
  rect 0.9x1.01 smd: G1(-2.55,1.695) G2(-1.53,1.695) G3(-0.51,1.695) G4(0.51,1.695) G5(1.53,1.695) G6(2.55,1.695) G7(-2.55,0.565) G8(-1.53,0.565) G9(-0.51,0.565) G10(0.51,0.565) G11(1.53,0.565) G12(2.55,0.565) G13(-2.55,-0.565) G14(-1.53,-0.565) G15(-0.51,-0.565) G16(0.51,-0.565) G17(1.53,-0.565) G18(2.55,-0.565) G19(-2.55,-1.695) G20(-1.53,-1.695) G21(-0.51,-1.695) G22(0.51,-1.695) G23(1.53,-1.695) G24(2.55,-1.695)
PA8_6X6_5_CTG_PS0_44_P62_HD
  rect 0.45x0.5 smd: 1(-4.025,-2.95) 19(4.025,-2.95) 32(4.025,2.95) 50(-4.025,2.95)
  rect 0.32x0.5 smd: 2(-3.52,-2.95) 3(-3.08,-2.95) 4(-2.64,-2.95) 5(-2.2,-2.95) 6(-1.76,-2.95) 7(-1.32,-2.95) 8(-0.88,-2.95) 9(-0.44,-2.95) 10(0,-2.95) 11(0.44,-2.95) 12(0.88,-2.95) 13(1.32,-2.95) 14(1.76,-2.95) 15(2.2,-2.95) 16(2.64,-2.95) 17(3.08,-2.95) 18(3.52,-2.95) 33(3.52,2.95) 34(3.08,2.95) 35(2.64,2.95) 36(2.2,2.95) 37(1.76,2.95) 38(1.32,2.95) 39(0.88,2.95) 40(0.44,2.95) 41(0,2.95) 42(-0.44,2.95) 43(-0.88,2.95) 44(-1.32,2.95) 45(-1.76,2.95) 46(-2.2,2.95) 47(-2.64,2.95) 48(-3.08,2.95) 49(-3.52,2.95)
  rect 0.5x0.32 smd: 20(4,-2.42) 21(4,-1.98) 22(4,-1.54) 23(4,-1.1) 24(4,-0.66) 25(4,-0.22) 26(4,0.22) 27(4,0.66) 28(4,1.1) 29(4,1.54) 30(4,1.98) 31(4,2.42) 51(-4,2.42) 52(-4,1.98) 53(-4,1.54) 54(-4,1.1) 55(-4,0.66) 56(-4,0.22) 57(-4,-0.22) 58(-4,-0.66) 59(-4,-1.1) 60(-4,-1.54) 61(-4,-1.98) 62(-4,-2.42)
  rect 1.05x0.86 smd: G1(-2.975,2.02) G2(-1.785,2.02) G3(-0.595,2.02) G4(0.595,2.02) G5(1.785,2.02) G6(2.975,2.02) G7(-2.975,1.01) G8(-1.785,1.01) G9(-0.595,1.01) G10(0.595,1.01) G11(1.785,1.01) G12(2.975,1.01) G13(-2.975,0) G14(-1.785,0) G15(-0.595,0) G16(0.595,0) G17(1.785,0) G18(2.975,0) G19(-2.975,-1.01) G20(-1.785,-1.01) G21(-0.595,-1.01) G22(0.595,-1.01) G23(1.785,-1.01) G24(2.975,-1.01) G25(-2.975,-2.02) G26(-1.785,-2.02) G27(-0.595,-2.02) G28(0.595,-2.02) G29(1.785,-2.02) G30(2.975,-2.02)
QFN1_8X1_4_PS0_4-HT0_55_P10_HD
  rect 0.3x0.62 smd: 1(-0.2,-0.565) 2(0.2,-0.565) 6(0.2,0.565) 7(-0.2,0.565)
  rect 0.62x0.3 smd: 3(0.765,-0.4) 4(0.765,0) 5(0.765,0.4) 8(-0.765,0.4) 9(-0.765,0) 10(-0.765,-0.4)
QFN2SQ_CTG0_98SQ_PS0_4-HT0_6_P15_HD
  custom 0.075x0.075 smd: 1(-0.4,-0.905) 3(0.4,-0.905) 4(0.905,-0.6) 7(0.905,0.6) 8(0.4,0.905) 10(-0.4,0.905) 11(-0.905,0.6) 14(-0.905,-0.6)
  rect 0.3x0.53 smd: 2(0,-0.905) 9(0,0.905)
  rect 0.53x0.3 smd: 5(0.905,-0.2) 6(0.905,0.2) 12(-0.905,0.2) 13(-0.905,-0.2)
  rect 1.08x1.08 smd: G1(0,0)
QFN2X1_5_PS0_5-HT0_6_P10_HD
  rect 0.38x0.8 smd: 1(-0.75,-0.71) 2(-0.25,-0.71) 3(0.25,-0.71) 4(0.75,-0.71) 6(0.75,0.71) 7(0.25,0.71) 8(-0.25,0.71) 9(-0.75,0.71)
  rect 0.8x0.38 smd: 5(0.75,0) 10(-0.75,0)
RES0201-HT0_26_HD
  rect 0.25x0.3 smd: 1(-0.23,0) 2(0.23,0)
RES0201-HT0_28_HD
  rect 0.25x0.3 smd: 1(-0.23,0) 2(0.23,0)
RES0201-HT0_33_HD
  rect 0.25x0.3 smd: 1(-0.23,0) 2(0.23,0)
RES0402-HT0_4_HD
  rect 0.45x0.5 smd: 1(-0.36,0) 2(0.36,0)
RES0603-HT0_6_HD
  rect 0.64x0.68 smd: 1(-0.66,0) 2(0.66,0)
RES0805-HT0_4_HD
  rect 0.53x1.45 smd: 1(-0.84,0) 2(0.84,0)
SD_L1
  round 0.1 smd: 1(0,0) 2(0,0)
SHIELD_DRX_HB_SM88C42467
  rect 0.05x0.05 smd: 1(0.117,-2.321)
SHIELD_LB_PA_SM88C42473
  rect 0.05x0.05 smd: 1(1.732,-6.294)
SHIELD_MBHB_PA_SM88C42472
  rect 0.05x0.05 smd: 1(-1.613,-7.001)
SHIELD_OVP_SM88C46177
  rect 0.05x0.05 smd: 1(0.107,-1.431)
SHIELD_QET_SM88C42471
  rect 0.05x0.05 smd: 1(-0.783,-3.391)
SHIELD_SND_BST_SM88C42469
  rect 0.05x0.05 smd: 1(0.942,-6.236)
SHIELD_WIFI_SM88C42468
  rect 0.05x0.05 smd: 1(-3.225,-1.47)
SHIELD_WTR_SM88C42466
  rect 0.05x0.05 smd: 1(0.262,-8.015)
SOT0_8X1_2RB_PS0_8-HT0_55_P3_HD
  rect 0.4x0.42 smd: 1(0.6,-0.4) 2(0.6,0.4)
  rect 0.4x0.52 smd: 3(-0.6,0)
SPACER4C_TH_HD
  round 4 hole 2.2: 1(0,0)
TPSM0_38CAU_HD
  round 0.38 smd: 1(0,0)
TPSM0_175CNG_HD
  round 0.175 smd: 1(0,0)
TPSM1_27CAU_HD
  round 1.27 smd: 1(0,0)
unnamed
  round 0.01 hole 1.2 unplated: (-1.8,-0.6) (1.8,-0.6)
unnamed#3
  round 1 smd: (0,0)
unnamed#4
  round 0.01 hole 1.2 unplated: (-1.35,-0.6) (1.35,-0.6)
WLCSP0_78X1_18_B0_22_PS0_4_P5_HD
  round 0.32 smd: A1(-0.2,-0.4) A3(-0.2,0.4) B1(0.2,-0.4) B2(0.2,0) B3(0.2,0.4)
WLCSP2_64X2_02_B0_22_PS0_35_P34_XD
  round 0.28 smd: 1(-1.05,-0.7) 2(-1.05,-0.35) 3(-1.05,0) 4(-1.05,0.35) 5(-1.05,0.7) 6(-0.7,-0.7) 7(-0.7,-0.35) 8(-0.7,0.35) 9(-0.7,0.7) 10(-0.35,-0.7) 11(-0.35,-0.35) 12(-0.35,0) 13(-0.35,0.35) 14(-0.35,0.7) 15(0,-0.7) 16(0,-0.35) 17(0,0) 18(0,0.35) 19(0,0.7) 20(0.35,-0.7) 21(0.35,-0.35) 22(0.35,0) 23(0.35,0.35) 24(0.35,0.7) 25(0.7,-0.7) 26(0.7,-0.35) 27(0.7,0) 28(0.7,0.35) 29(0.7,0.7) 30(1.05,-0.7) 31(1.05,-0.35) 32(1.05,0) 33(1.05,0.35) 34(1.05,0.7)
WLCSP4_65X5_58_PS0_35_P196_XD
  round 0.28 smd: 1(-2.104,-2.599) 2(-2.104,-2.104) 3(-2.104,-1.609) 4(-2.104,-1.114) 5(-2.104,-0.619) 6(-2.104,-0.124) 7(-2.104,0.371) 8(-2.104,0.866) 9(-2.104,1.361) 10(-2.104,1.856) 11(-2.104,2.351) 12(-1.856,-2.351) 13(-1.856,-1.856) 14(-1.856,-1.361) 15(-1.856,-0.866) 16(-1.856,-0.371) 17(-1.856,0.124) 18(-1.856,0.619) 19(-1.856,1.114) 20(-1.856,1.609) 21(-1.856,2.104) 22(-1.856,2.599) 23(-1.609,-2.599) 24(-1.609,-2.104) 25(-1.609,-1.609) 26(-1.609,-1.114) 27(-1.609,-0.619) 28(-1.609,-0.124) 29(-1.609,0.371) 30(-1.609,0.866) 31(-1.609,1.361) 32(-1.609,1.856) 33(-1.609,2.351) 34(-1.361,-2.351) 35(-1.361,-1.856) 36(-1.361,-1.361) 37(-1.361,-0.866) 38(-1.361,-0.371) 39(-1.361,0.124) 40(-1.361,0.619) 41(-1.361,1.114) 42(-1.361,1.609) 43(-1.361,2.104) 44(-1.361,2.599) 45(-1.114,-2.599) 46(-1.114,-2.104) 47(-1.114,-1.609) 48(-1.114,-1.114) 49(-1.114,-0.619) 50(-1.114,-0.124) 51(-1.114,0.371) 52(-1.114,0.866) 53(-1.114,1.361) 54(-1.114,1.856) 55(-1.114,2.351) 56(-0.866,-2.351) 57(-0.866,-1.856) 58(-0.866,-1.361) 59(-0.866,-0.866) 60(-0.866,-0.371) 61(-0.866,0.124) 62(-0.866,0.619) 63(-0.866,1.114) 64(-0.866,1.609) 65(-0.866,2.104) 66(-0.866,2.599) 67(-0.619,-2.599) 68(-0.619,-2.104) 69(-0.619,-1.609) 70(-0.619,-1.114) 71(-0.619,-0.619) 72(-0.619,-0.124) 73(-0.619,0.371) 74(-0.619,0.866) 75(-0.619,1.361) 76(-0.619,1.856) 77(-0.619,2.351) 78(-0.371,-2.351) 79(-0.371,-1.856) 80(-0.371,-1.361) 81(-0.371,-0.866) 82(-0.371,-0.371) 83(-0.371,0.124) 84(-0.371,0.619) 85(-0.371,1.114) 86(-0.371,1.609) 87(-0.371,2.104) 88(-0.371,2.599) 89(-0.124,-2.599) 90(-0.124,-2.104) 91(-0.124,-1.609) 92(-0.124,-1.114) 93(-0.124,-0.619) 94(-0.124,-0.124) 95(-0.124,0.371) 96(-0.124,0.866) 97(-0.124,1.361) 98(-0.124,1.856) 99(-0.124,2.351) 100(0.124,-2.351) 101(0.124,-1.856) 102(0.124,-1.361) 103(0.124,-0.866) 104(0.124,-0.371) 105(0.124,0.124) 106(0.124,0.619) 107(0.124,1.114) 108(0.124,1.609) 109(0.124,2.104) 110(0.124,2.599) 111(0.371,-2.599) 112(0.371,-2.104) 113(0.371,-1.609) 114(0.371,-1.114) 115(0.371,-0.619) 116(0.371,-0.124) 117(0.371,0.371) 118(0.371,0.866) 119(0.371,1.361) 120(0.371,1.856) 121(0.371,2.351) 122(0.619,-2.351) 123(0.619,-1.856) 124(0.619,-1.361) 125(0.619,-0.371) 126(0.619,0.619) 127(0.619,1.114) 128(0.619,1.609) 129(0.619,2.104) 130(0.619,2.599) 131(0.866,-2.599) 132(0.866,-2.104) 133(0.866,-1.609) 134(0.866,-1.114) 135(0.866,-0.619) 136(0.866,-0.124) 137(0.866,0.371) 138(0.866,0.866) 139(0.866,1.361) 140(0.866,1.856) 141(0.866,2.351) 142(1.114,-2.351) 143(1.114,-1.856) 144(1.114,-1.361) 145(1.114,-0.866) 146(1.114,-0.371) 147(1.114,0.124) 148(1.114,0.619) 149(1.114,1.114) 150(1.114,1.609) 151(1.114,2.104) 152(1.114,2.599) 153(1.361,-2.599) 154(1.361,-2.104) 155(1.361,-1.609) 156(1.361,-1.114) 157(1.361,-0.619) 158(1.361,-0.124) 159(1.361,0.371) 160(1.361,0.866) 161(1.361,1.361) 162(1.361,1.856) 163(1.361,2.351) 164(1.609,-2.351) 165(1.609,-1.856) 166(1.609,-1.361) 167(1.609,-0.866) 168(1.609,-0.371) 169(1.609,0.124) 170(1.609,0.619) 171(1.609,1.114) 172(1.609,1.609) 173(1.609,2.104) 174(1.609,2.599) 175(1.856,-2.599) 176(1.856,-2.104) 177(1.856,-1.609) 178(1.856,-1.114) 179(1.856,-0.619) 180(1.856,-0.124) 181(1.856,0.371) 182(1.856,0.866) 183(1.856,1.361) 184(1.856,1.856) 185(1.856,2.351) 186(2.104,-2.351) 187(2.104,-1.856) 188(2.104,-1.361) 189(2.104,-0.866) 190(2.104,-0.371) 191(2.104,0.124) 192(2.104,0.619) 193(2.104,1.114) 194(2.104,1.609) 195(2.104,2.104) 196(2.104,2.599)
WLCSP4_65X5_81_B0_27_PS0_4_P173_HD
  round 0.32 smd: A1(-2.099,-2.68) A3(-2.099,-1.987) A5(-2.099,-1.294) A7(-2.099,-0.602) A9(-2.099,0.091) A11(-2.099,0.784) A13(-2.099,1.477) A15(-2.099,2.17) AA1(1.901,-2.68) AA3(1.901,-1.987) AA5(1.901,-1.294) AA7(1.901,-0.602) AA9(1.901,0.091) AA11(1.901,0.784) AA13(1.901,1.477) AA15(1.901,2.17) AB2(2.1,-2.334) AB4(2.1,-1.641) AB6(2.1,-0.948) AB8(2.1,-0.255) AB10(2.1,0.438) AB12(2.1,1.13) AB14(2.1,1.823) AB16(2.1,2.516) B2(-1.899,-2.334) B4(-1.899,-1.641) B6(-1.899,-0.948) B8(-1.899,-0.255) B10(-1.899,0.438) B12(-1.899,1.13) B14(-1.899,1.823) B16(-1.899,2.516) C1(-1.7,-2.68) C3(-1.7,-1.987) C5(-1.7,-1.294) C7(-1.7,-0.602) C9(-1.7,0.091) C11(-1.7,0.784) C13(-1.7,1.477) C15(-1.7,2.17) D2(-1.5,-2.334) D4(-1.5,-1.641) D6(-1.5,-0.948) D8(-1.5,-0.255) D10(-1.5,0.438) D12(-1.5,1.13) D14(-1.5,1.823) D16(-1.5,2.516) E1(-1.3,-2.68) E3(-1.3,-1.987) E5(-1.3,-1.294) E7(-1.3,-0.602) E9(-1.3,0.091) E11(-1.3,0.784) E13(-1.3,1.477) E15(-1.3,2.17) F2(-1.099,-2.334) F4(-1.099,-1.641) F6(-1.099,-0.948) F10(-1.099,0.438) F12(-1.099,1.13) F14(-1.099,1.823) F16(-1.099,2.516) G1(-0.899,-2.68) G3(-0.899,-1.987) G5(-0.899,-1.294) G11(-0.899,0.784) G13(-0.899,1.477) G15(-0.899,2.17) H2(-0.7,-2.334) H4(-0.7,-1.641) H6(-0.7,-0.948) H8(-0.7,-0.255) H10(-0.7,0.438) H12(-0.7,1.13) H14(-0.7,1.823) H16(-0.7,2.516) J1(-0.499,-2.68) J3(-0.499,-1.987) J5(-0.499,-1.294) J7(-0.499,-0.602) J9(-0.499,0.091) J11(-0.499,0.784) J13(-0.499,1.477) J15(-0.499,2.17) K2(-0.299,-2.334) K4(-0.299,-1.641) K6(-0.299,-0.948) K8(-0.299,-0.255) K10(-0.299,0.438) K12(-0.299,1.13) K14(-0.299,1.823) K16(-0.299,2.516) L1(-0.1,-2.68) L3(-0.1,-1.987) L5(-0.1,-1.294) L7(-0.1,-0.602) L9(-0.1,0.091) L11(-0.1,0.784) L13(-0.1,1.477) L15(-0.1,2.17) M2(0.101,-2.334) M4(0.101,-1.641) M6(0.101,-0.948) M8(0.101,-0.255) M10(0.101,0.438) M12(0.101,1.13) M14(0.101,1.823) M16(0.101,2.516) N1(0.3,-2.68) N3(0.3,-1.987) N5(0.3,-1.294) N7(0.3,-0.602) N9(0.3,0.091) N11(0.3,0.784) N13(0.3,1.477) N15(0.3,2.17) P2(0.5,-2.334) P4(0.5,-1.641) P6(0.5,-0.948) P8(0.5,-0.255) P10(0.5,0.438) P12(0.5,1.13) P14(0.5,1.823) P16(0.5,2.516) R1(0.701,-2.68) R3(0.701,-1.987) R5(0.701,-1.294) R7(0.701,-0.602) R9(0.701,0.091) R11(0.701,0.784) R13(0.701,1.477) R15(0.701,2.17) T2(0.9,-2.334) T4(0.9,-1.641) T6(0.9,-0.948) T8(0.9,-0.255) T10(0.9,0.438) T12(0.9,1.13) T14(0.9,1.823) T16(0.9,2.516) U1(1.101,-2.68) U3(1.101,-1.987) U5(1.101,-1.294) U7(1.101,-0.602) U9(1.101,0.091) U11(1.101,0.784) U13(1.101,1.477) U15(1.101,2.17) V2(1.3,-2.334) V4(1.3,-1.641) V6(1.3,-0.948) V8(1.3,-0.255) V10(1.3,0.438) V12(1.3,1.13) V14(1.3,1.823) V16(1.3,2.516) W1(1.5,-2.68) W3(1.5,-1.987) W5(1.5,-1.294) W7(1.5,-0.602) W9(1.5,0.091) W11(1.5,0.784) W13(1.5,1.477) W15(1.5,2.17) Y2(1.7,-2.334) Y4(1.7,-1.641) Y6(1.7,-0.948) Y8(1.7,-0.255) Y10(1.7,0.438) Y12(1.7,1.13) Y14(1.7,1.823) Y16(1.7,2.516)
WLCSP5_05X5_64_PS0_35_P219_XD
  round 0.28 smd: 1(-2.351,-2.351) 2(-2.351,-1.856) 3(-2.351,-1.361) 4(-2.351,-0.866) 5(-2.351,-0.371) 6(-2.351,0.124) 7(-2.351,0.619) 8(-2.351,1.114) 9(-2.351,1.609) 10(-2.351,2.104) 11(-2.351,2.599) 12(-2.104,-2.599) 13(-2.104,-2.104) 14(-2.104,-1.609) 15(-2.104,-1.114) 16(-2.104,-0.619) 17(-2.104,-0.124) 18(-2.104,0.371) 19(-2.104,0.866) 20(-2.104,1.361) 21(-2.104,1.856) 22(-2.104,2.351) 23(-1.856,-2.351) 24(-1.856,-1.856) 25(-1.856,-1.361) 26(-1.856,-0.866) 27(-1.856,-0.371) 28(-1.856,0.124) 29(-1.856,0.619) 30(-1.856,1.114) 31(-1.856,1.609) 32(-1.856,2.104) 33(-1.856,2.599) 34(-1.609,-2.599) 35(-1.609,-2.104) 36(-1.609,-1.609) 37(-1.609,-1.114) 38(-1.609,-0.619) 39(-1.609,-0.124) 40(-1.609,0.371) 41(-1.609,0.866) 42(-1.609,1.361) 43(-1.609,1.856) 44(-1.609,2.351) 45(-1.361,-2.351) 46(-1.361,-1.856) 47(-1.361,-1.361) 48(-1.361,-0.866) 49(-1.361,-0.371) 50(-1.361,0.124) 51(-1.361,0.619) 52(-1.361,1.114) 53(-1.361,1.609) 54(-1.361,2.104) 55(-1.361,2.599) 56(-1.114,-2.599) 57(-1.114,-2.104) 58(-1.114,-1.609) 59(-1.114,-1.114) 60(-1.114,-0.619) 61(-1.114,-0.124) 62(-1.114,0.371) 63(-1.114,0.866) 64(-1.114,1.361) 65(-1.114,1.856) 66(-1.114,2.351) 67(-0.866,-2.351) 68(-0.866,-1.856) 69(-0.866,-1.361) 70(-0.866,-0.866) 71(-0.866,-0.371) 72(-0.866,0.124) 73(-0.866,0.619) 74(-0.866,1.114) 75(-0.866,1.609) 76(-0.866,2.104) 77(-0.866,2.599) 78(-0.619,-2.599) 79(-0.619,-2.104) 80(-0.619,-1.609) 81(-0.619,-1.114) 82(-0.619,-0.619) 83(-0.619,-0.124) 84(-0.619,0.371) 85(-0.619,0.866) 86(-0.619,1.856) 87(-0.619,2.351) 88(-0.371,-2.351) 89(-0.371,-1.856) 90(-0.371,-1.361) 91(-0.371,-0.866) 92(-0.371,-0.371) 93(-0.371,0.124) 94(-0.371,0.619) 95(-0.371,1.114) 96(-0.371,1.609) 97(-0.371,2.104) 98(-0.371,2.599) 99(-0.124,-2.599) 100(-0.124,-2.104) 101(-0.124,-1.609) 102(-0.124,-1.114) 103(-0.124,-0.619) 104(-0.124,-0.124) 105(-0.124,0.371) 106(-0.124,0.866) 107(-0.124,1.361) 108(-0.124,1.856) 109(-0.124,2.351) 110(0.124,-2.351) 111(0.124,-1.856) 112(0.124,-1.361) 113(0.124,-0.866) 114(0.124,-0.371) 115(0.124,0.124) 116(0.124,0.619) 117(0.124,1.114) 118(0.124,1.609) 119(0.124,2.104) 120(0.124,2.599) 121(0.371,-2.599) 122(0.371,-2.104) 123(0.371,-1.609) 124(0.371,-1.114) 125(0.371,-0.619) 126(0.371,-0.124) 127(0.371,0.371) 128(0.371,0.866) 129(0.371,1.361) 130(0.371,1.856) 131(0.371,2.351) 132(0.619,-2.351) 133(0.619,-1.856) 134(0.619,-1.361) 135(0.619,-0.866) 136(0.619,-0.371) 137(0.619,0.124) 138(0.619,0.619) 139(0.619,1.114) 140(0.619,1.609) 141(0.619,2.104) 142(0.619,2.599) 143(0.866,-2.599) 144(0.866,-2.104) 145(0.866,-1.609) 146(0.866,-1.114) 147(0.866,-0.619) 148(0.866,-0.124) 149(0.866,0.371) 150(0.866,0.866) 151(0.866,1.361) 152(0.866,1.856) 153(0.866,2.351) 154(1.114,-2.351) 155(1.114,-1.856) 156(1.114,-1.361) 157(1.114,-0.866) 158(1.114,-0.371) 159(1.114,0.124) 160(1.114,0.619) 161(1.114,1.114) 162(1.114,1.609) 163(1.114,2.104) 164(1.114,2.599) 165(1.361,-2.599) 166(1.361,-2.104) 167(1.361,-1.609) 168(1.361,-1.114) 169(1.361,-0.619) 170(1.361,-0.124) 171(1.361,0.371) 172(1.361,0.866) 173(1.361,1.361) 174(1.361,1.856) 175(1.361,2.351) 176(1.609,-2.351) 177(1.609,-1.856) 178(1.609,-1.361) 179(1.609,-0.866) 180(1.609,-0.371) 181(1.609,0.124) 182(1.609,0.619) 183(1.609,1.114) 184(1.609,1.609) 185(1.609,2.104) 186(1.609,2.599) 187(1.856,-2.599) 188(1.856,-2.104) 189(1.856,-1.609) 190(1.856,-1.114) 191(1.856,-0.619) 192(1.856,-0.124) 193(1.856,0.371) 194(1.856,0.866) 195(1.856,1.361) 196(1.856,1.856) 197(1.856,2.351) 198(2.104,-2.351) 199(2.104,-1.856) 200(2.104,-1.361) 201(2.104,-0.866) 202(2.104,-0.371) 203(2.104,0.124) 204(2.104,0.619) 205(2.104,1.114) 206(2.104,1.609) 207(2.104,2.104) 208(2.104,2.599) 209(2.351,-2.599) 210(2.351,-2.104) 211(2.351,-1.609) 212(2.351,-1.114) 213(2.351,-0.619) 214(2.351,-0.124) 215(2.351,0.371) 216(2.351,0.866) 217(2.351,1.361) 218(2.351,1.856) 219(2.351,2.351)
WLCSP5_79X4_43_B0_23_PS0_35_P180_XD
  round 0.28 smd: 1(-2.723,-1.689) 2(-2.723,-1.194) 3(-2.723,-0.699) 4(-2.723,-0.204) 5(-2.723,0.291) 6(-2.723,0.786) 7(-2.723,1.281) 8(-2.723,1.776) 9(-2.475,-1.937) 10(-2.475,-1.442) 11(-2.475,-0.947) 12(-2.475,-0.452) 13(-2.475,0.043) 14(-2.475,0.538) 15(-2.475,1.033) 16(-2.475,1.528) 17(-2.475,2.023) 18(-2.228,-1.689) 19(-2.228,-1.194) 20(-2.228,-0.699) 21(-2.228,-0.204) 22(-2.228,0.291) 23(-2.228,0.786) 24(-2.228,1.281) 25(-2.228,1.776) 26(-1.98,-1.937) 27(-1.98,-1.442) 28(-1.98,-0.947) 29(-1.98,-0.452) 30(-1.98,0.538) 31(-1.98,1.528) 32(-1.98,2.023) 33(-1.732,-1.689) 34(-1.732,-1.194) 35(-1.732,-0.699) 36(-1.732,-0.204) 37(-1.732,0.291) 38(-1.732,1.776) 39(-1.485,-1.937) 40(-1.485,-0.947) 41(-1.485,-0.452) 42(-1.485,0.043) 43(-1.485,0.538) 44(-1.485,1.033) 45(-1.485,1.528) 46(-1.485,2.023) 47(-1.238,-1.689) 48(-1.238,-1.194) 49(-1.238,-0.699) 50(-1.238,-0.204) 51(-1.238,0.291) 52(-1.238,0.786) 53(-1.238,1.281) 54(-1.238,1.776) 55(-0.99,-1.937) 56(-0.99,-1.442) 57(-0.99,-0.947) 58(-0.99,-0.452) 59(-0.99,0.043) 60(-0.99,0.538) 61(-0.99,1.033) 62(-0.99,1.528) 63(-0.99,2.023) 64(-0.743,-1.689) 65(-0.743,-1.194) 66(-0.743,-0.699) 67(-0.743,-0.204) 68(-0.743,0.291) 69(-0.743,0.786) 70(-0.743,1.281) 71(-0.743,1.776) 72(-0.495,-1.937) 73(-0.495,-1.442) 74(-0.495,-0.947) 75(-0.495,-0.452) 76(-0.495,0.043) 77(-0.495,0.538) 78(-0.495,1.033) 79(-0.495,1.528) 80(-0.495,2.023) 81(-0.247,-1.689) 82(-0.247,-1.194) 83(-0.247,-0.699) 84(-0.247,-0.204) 85(-0.247,0.291) 86(-0.247,1.776) 87(0,-1.937) 88(0,-1.442) 89(0,-0.947) 90(0,-0.452) 91(0,0.043) 92(0,0.538) 93(0,1.033) 94(0,1.528) 95(0,2.023) 96(0.247,-1.689) 97(0.247,-1.194) 98(0.247,-0.699) 99(0.247,-0.204) 100(0.247,0.291) 101(0.247,1.776) 102(0.495,-1.937) 103(0.495,-1.442) 104(0.495,-0.947) 105(0.495,-0.452) 106(0.495,0.043) 107(0.495,0.538) 108(0.495,1.033) 109(0.495,1.528) 110(0.495,2.023) 111(0.743,-1.689) 112(0.743,-1.194) 113(0.743,-0.699) 114(0.743,0.291) 115(0.743,0.786) 116(0.743,1.281) 117(0.743,1.776) 118(0.99,-1.937) 119(0.99,-1.442) 120(0.99,-0.947) 121(0.99,-0.452) 122(0.99,0.043) 123(0.99,0.538) 124(0.99,1.033) 125(0.99,1.528) 126(0.99,2.023) 127(1.238,-1.689) 128(1.238,-1.194) 129(1.238,-0.699) 130(1.238,-0.204) 131(1.238,0.291) 132(1.238,0.786) 133(1.238,1.776) 134(1.485,-1.937) 135(1.485,-1.442) 136(1.485,-0.947) 137(1.485,-0.452) 138(1.485,0.043) 139(1.485,0.538) 140(1.485,1.528) 141(1.485,2.023) 142(1.732,-1.689) 143(1.732,-1.194) 144(1.732,-0.699) 145(1.732,-0.204) 146(1.732,0.291) 147(1.732,1.281) 148(1.732,1.776) 149(1.98,-1.937) 150(1.98,-1.442) 151(1.98,-0.947) 152(1.98,-0.452) 153(1.98,0.043) 154(1.98,0.538) 155(1.98,1.528) 156(1.98,2.023) 157(2.228,-1.689) 158(2.228,-1.194) 159(2.228,-0.699) 160(2.228,-0.204) 161(2.228,0.291) 162(2.228,0.786) 163(2.228,1.281) 164(2.228,1.776) 165(2.475,-1.937) 166(2.475,-1.442) 167(2.475,-0.947) 168(2.475,-0.452) 169(2.475,0.538) 170(2.475,1.033) 171(2.475,1.528) 172(2.475,2.023) 173(2.723,-1.689) 174(2.723,-1.194) 175(2.723,-0.699) 176(2.723,-0.204) 177(2.723,0.291) 178(2.723,0.786) 179(2.723,1.281) 180(2.723,1.776)
XTAL1_6X1_2_PS1_03_P4_HD
  rect 0.67x0.57 smd: 1(-0.515,-0.365) 2(0.515,-0.365) 3(0.515,0.365) 4(-0.515,0.365)

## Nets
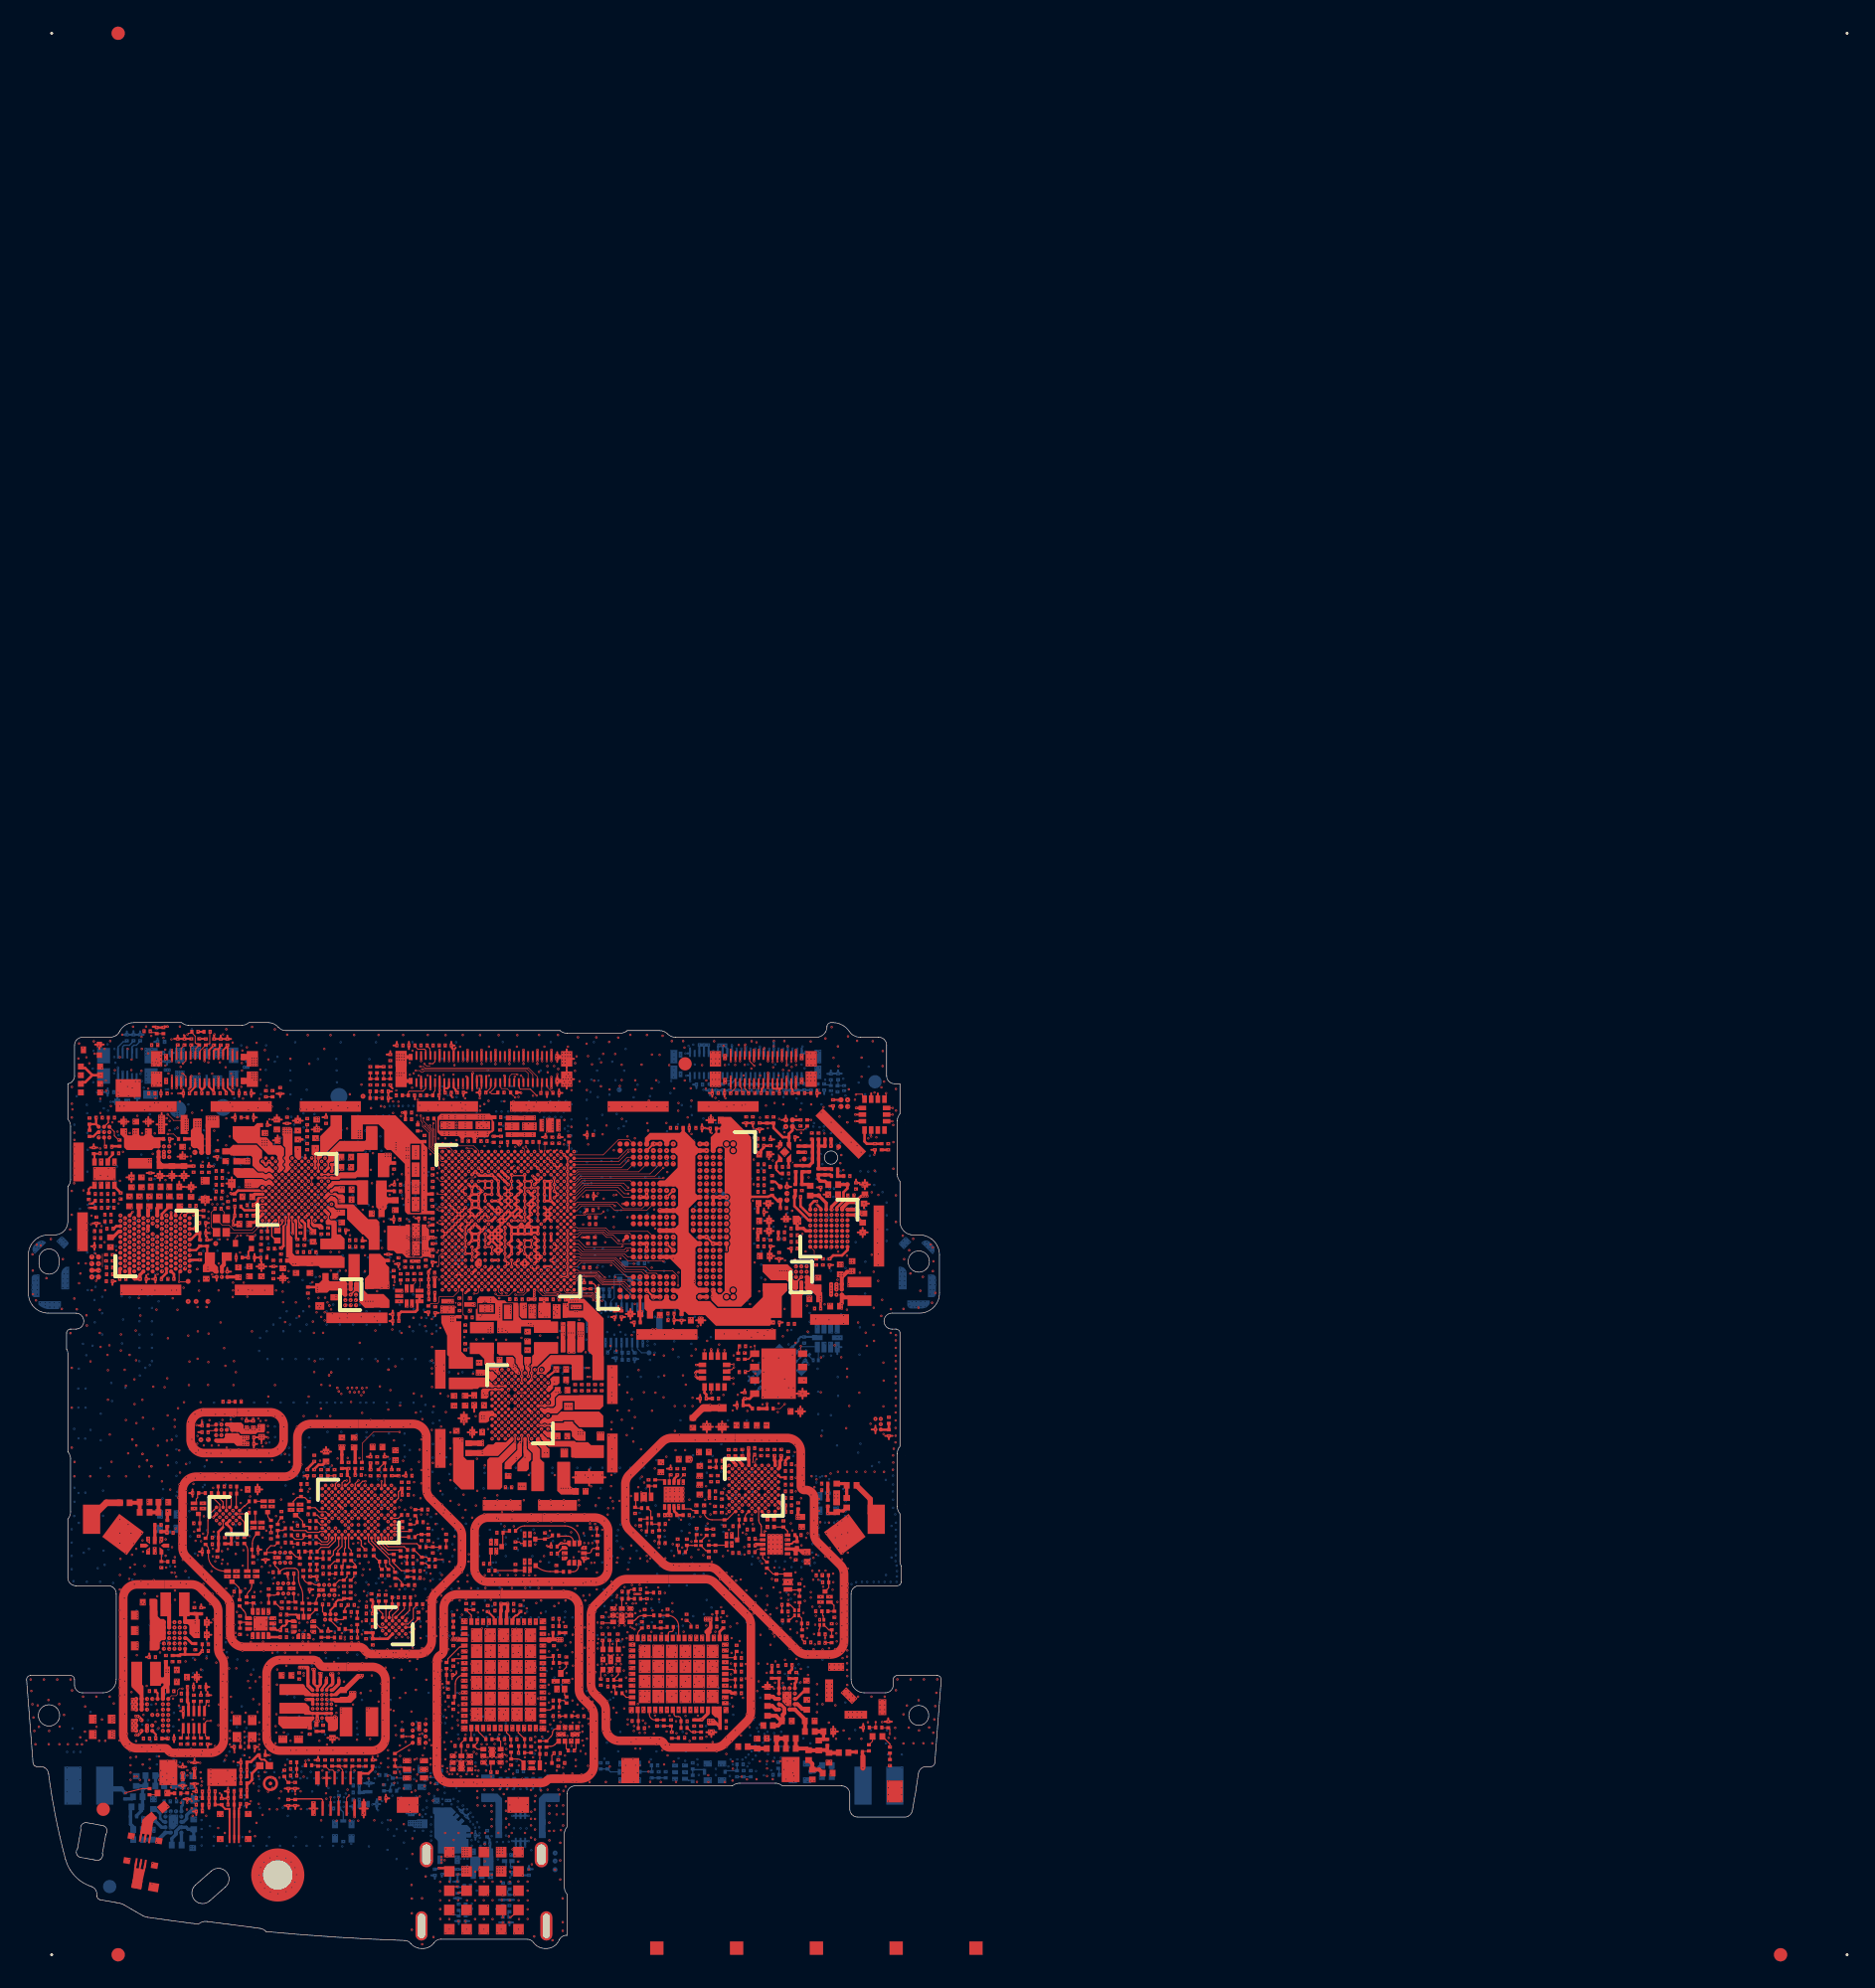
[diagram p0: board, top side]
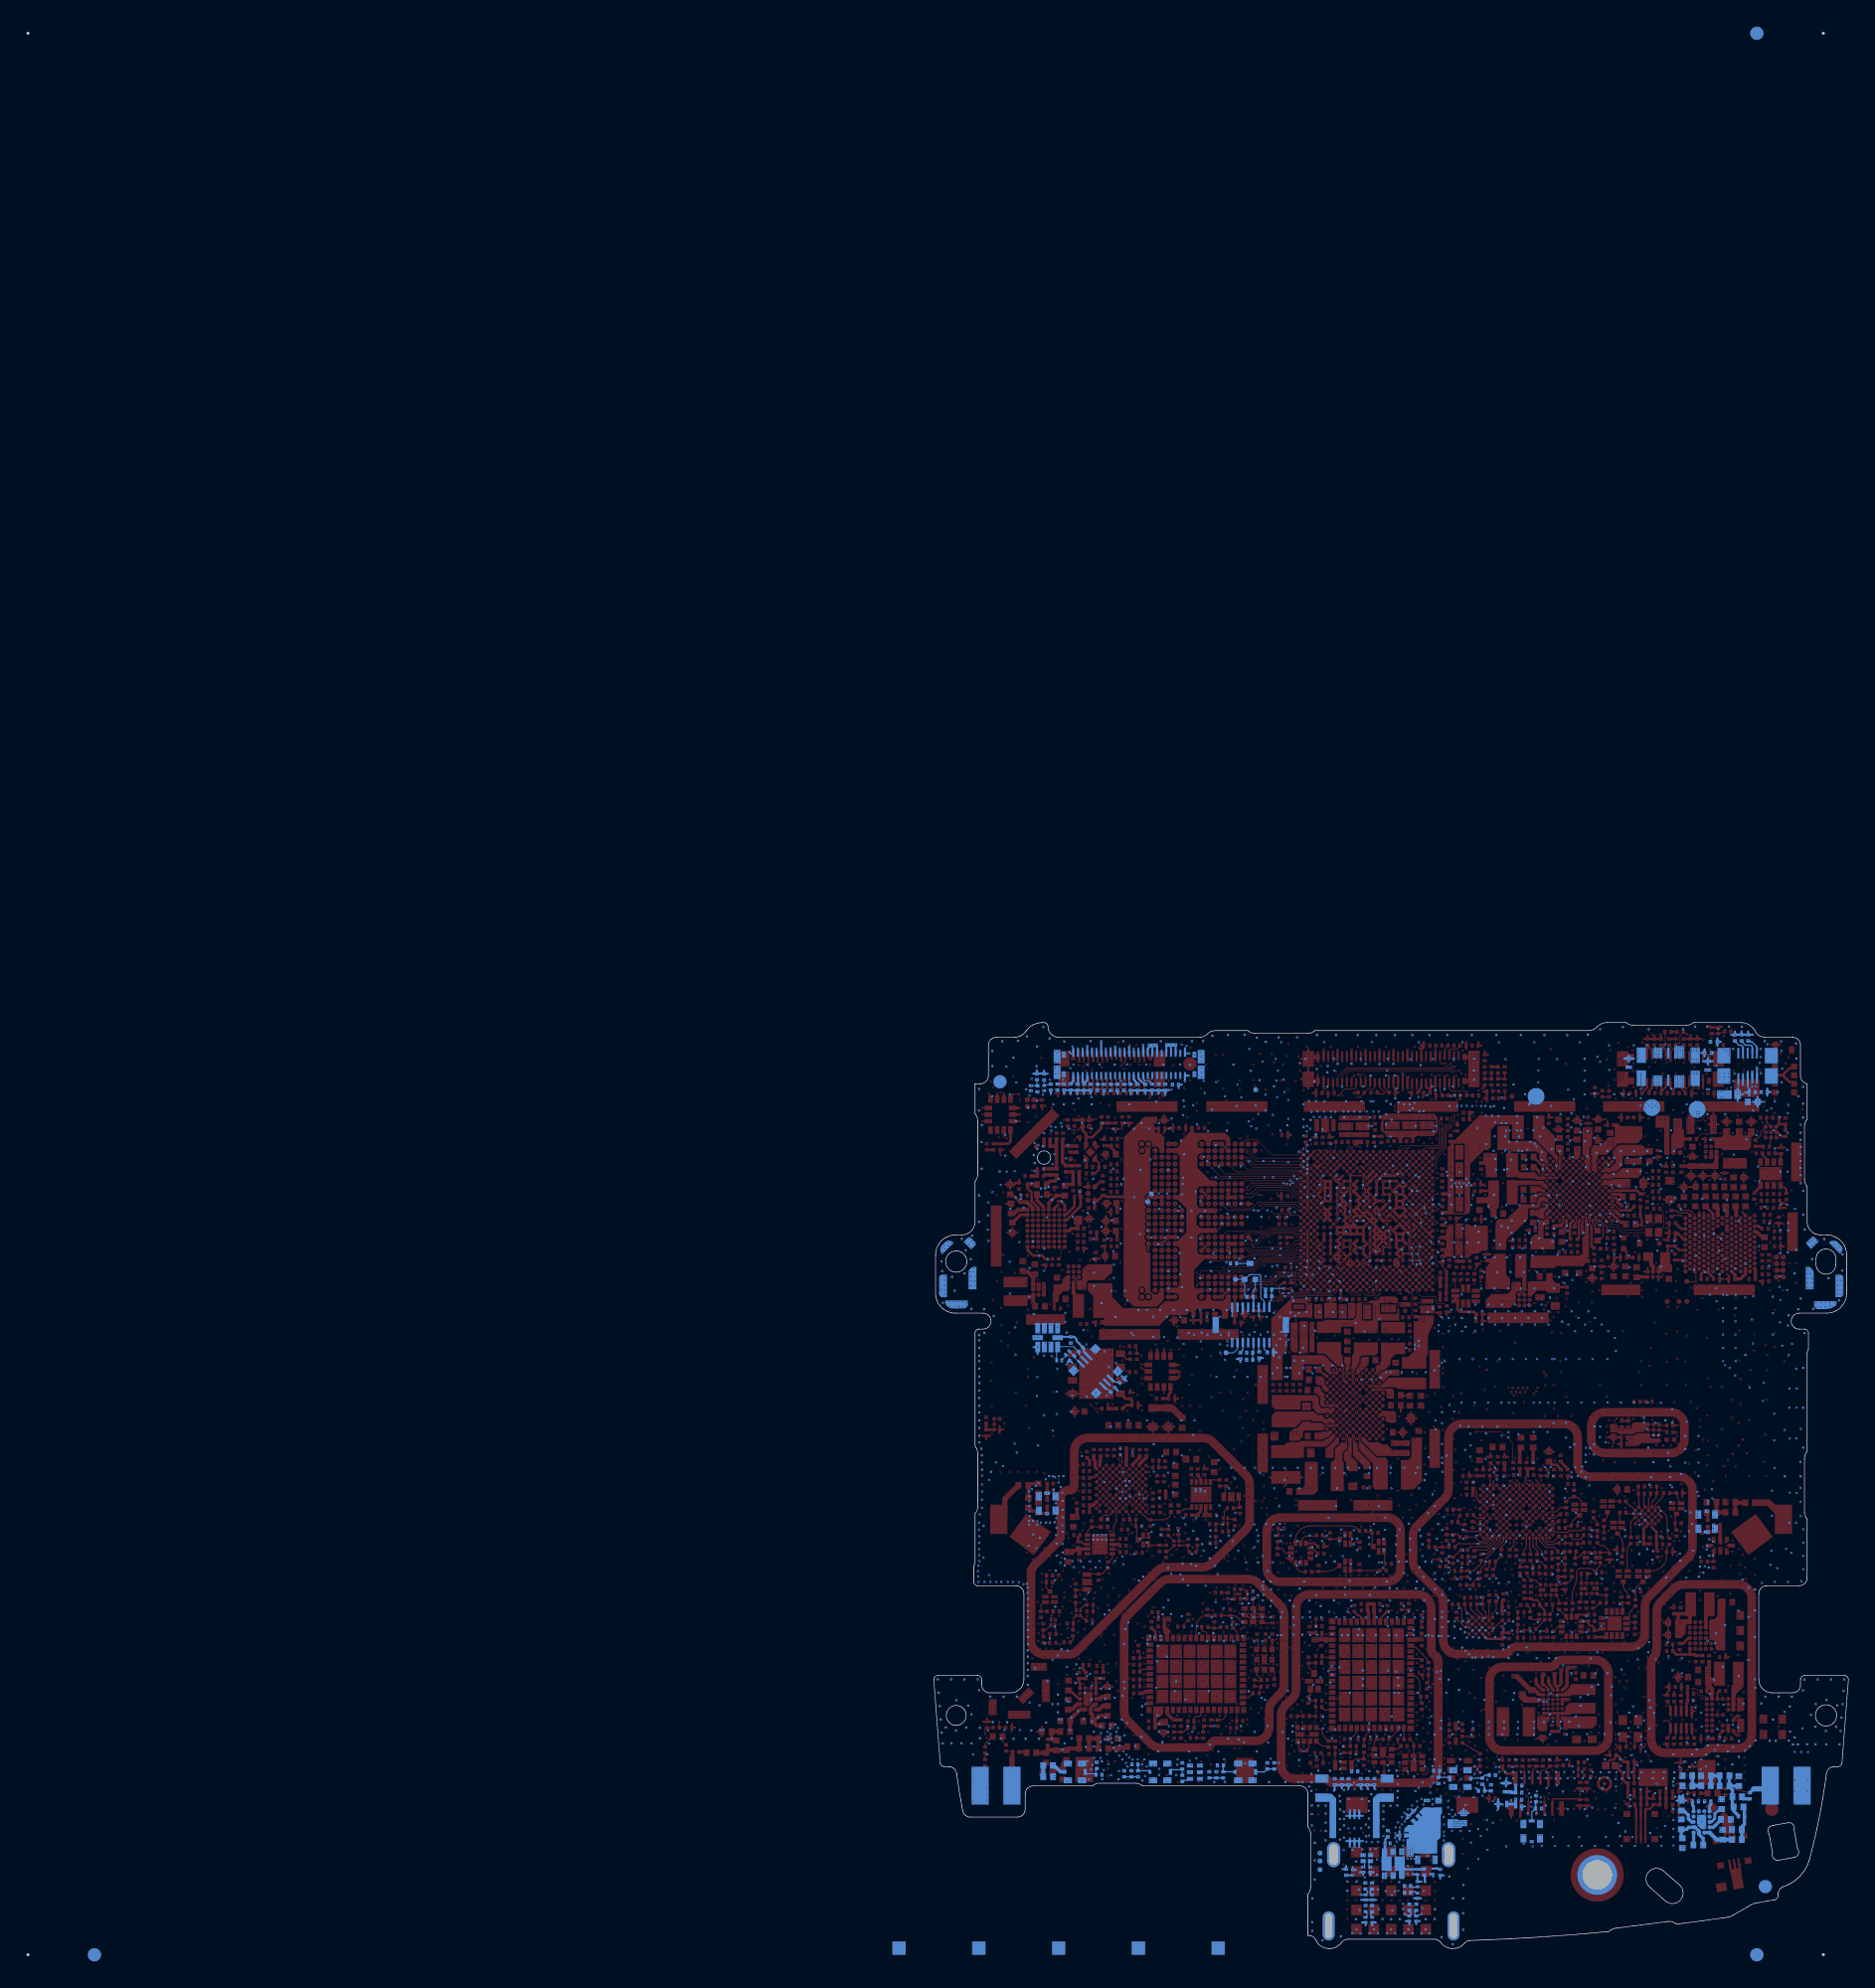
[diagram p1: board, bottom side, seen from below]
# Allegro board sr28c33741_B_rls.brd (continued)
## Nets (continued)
GND: C100.1(A<0>) C102.1(A<0>) C103.1(A<0>) C105.1(A<0>) C121.1(A<0>) C132.1(A<0>) C141.1(A<0>) C174.1(A<0>) C200.1(A<0>) C202.1(A<0>) C203.1(A<0>) C205.1(A<0>) C212.1(A<0>) C221.1(A<0>) C232.1(A<0>) C241.1(A<0>) C261.1(A<0>) C275.1(A<0>) C280.1(A<0>) C281.2(B<0>) C303.1(A<0>) C403.1(A<0>) C501.1(A<0>) C502.1(A<0>) C503.1(A<0>) C504.1(A<0>) C510.1(A<0>) C511.1(A<0>) C515.1(A<0>) C516.1(A<0>) C520.1(A<0>) C521.1(A<0>) C522.1(A<0>) C523.1(A<0>) C1001.1(A<0>) C1003.1(A<0>) C1004.1(A<0>) C1005.2(B<0>) C1007.2(B<0>) C1020.1(A<0>) C1021.1(A<0>) C1022.1(A<0>) C1023.1(A<0>) C1024.1(A<0>) C1049.1(A<0>) C1050.2(GND) C1051.2(GND) C1052.2(GND) C1053.1(A<0>) C1054.1(A<0>) C1057.2(GND) C1058.2(GND) C1059.2(GND) C1060.2(GND) C1064.1(A<0>) C1067.1(A<0>) C1068.1(A<0>) C1070.1(A<0>) C1071.2(GND) C1072.2(GND) C1075.2(GND) C1076.2(GND) C1077.1(A<0>) C1078.1(A<0>) C1080.1(A<0>) C1090.1(A<0>) C1091.1(A<0>) C1092.1(A<0>) C1093.1(A<0>) C1094.1(A<0>) C1095.1(A<0>) C1096.1(A<0>) C1097.1(A<0>) C1098.1(A<0>) C1099.1(A<0>) C1100.1(A<0>) C1101.1(A<0>) C1102.1(A<0>) C1103.1(A<0>) C1104.1(A<0>) C1105.1(A<0>) C1106.1(A<0>) C1107.2(GND) C1108.2(GND) C1109.2(GND) C1110.2(GND) C1111.1(A<0>) C1112.1(A<0>) C1114.2(GND) C1115.2(GND) C1116.2(GND) C1117.2(GND) C1119.1(A<0>) C1120.1(A<0>) C1121.1(A<0>) C1122.1(A<0>) C1123.1(A<0>) C1124.1(A<0>) C1126.1(A<0>) C1127.1(A<0>) C1128.1(A<0>) C1129.1(A<0>) C1130.1(A<0>) C1131.1(A<0>) C1132.1(A<0>) C1133.2(GND) C1140.1(A<0>) C1141.2(GND) C1150.1(A<0>) C1151.1(A<0>) C1152.1(A<0>) C1154.1(A<0>) C1155.1(A<0>) C1156.1(A<0>) C1157.1(A<0>) C1159.1(A<0>) C1164.1(A<0>) C1511.1(A<0>) C1512.1(A<0>) C1513.1(A<0>) C1514.1(A<0>) C1515.1(A<0>) C1516.1(A<0>) C1517.1(A<0>) C1518.1(A<0>) C1532.1(A<0>) C1601.1(A<0>) C1602.1(A<0>) C1603.1(A<0>) C1604.1(A<0>) C1605.1(A<0>) C1606.1(A<0>) C1607.1(A<0>) C1608.1(A<0>) C1609.1(A<0>) C1610.1(A<0>) C1611.1(A<0>) C1612.1(A<0>) C1613.1(A<0>) C1614.1(A<0>) C1615.1(A<0>) C1616.1(A<0>) C1617.1(A<0>) C1618.1(A<0>) C1619.1(A<0>) C1620.1(A<0>) C1621.1(A<0>) C1622.1(A<0>) C1623.1(A<0>) C1624.1(A<0>) C1632.1(A<0>) C1633.1(A<0>) C2002.2(B<0>) C2003.1(A<0>) C2004.1(A<0>) C2018.1(A<0>) C2020.1(A<0>) C2108.2(B<0>) C2253.1(A<0>) C2254.1(A<0>) C2255.1(A<0>) C2256.1(A<0>) C2257.1(A<0>) C2258.1(A<0>) C2262.1(A<0>) C2263.1(A<0>) C2270.1(A<0>) C2271.1(A<0>) C2272.1(A<0>) C2274.1(A<0>) C2275.1(A<0>) C2276.1(A<0>) C2277.1(A<0>) C2278.1(A<0>) C2279.1(A<0>) C2281.1(A<0>) C2282.1(A<0>) C2283.1(A<0>) C2284.1(A<0>) C2285.1(A<0>) C2286.1(A<0>) C2287.1(A<0>) C2288.1(A<0>) C2290.1(A<0>) C2291.1(A<0>) C2292.1(A<0>) C2294.1(A<0>) C2295.1(A<0>) C2296.1(A<0>) C2319.2(B<0>) C2320.2(B<0>) C2330.1(A<0>) C2331.1(A<0>) C2332.1(A<0>) C2333.1(A<0>) C2334.1(A<0>) C2335.1(A<0>) C2336.1(A<0>) C2337.1(A<0>) C2338.1(A<0>) C2339.1(A<0>) C2340.1(A<0>) C2352.1(A<0>) C2353.1(A<0>) C2354.1(A<0>) C2355.1(A<0>) C2357.1(A<0>) C2358.1(A<0>) C2359.1(A<0>) C2360.2(B<0>) C2361.2(B<0>) C2362.2(B<0>) C2363.2(B<0>) C2364.2(B<0>) C2370.1(A<0>) C2371.1(A<0>) C2372.1(A<0>) C2374.1(A<0>) C2375.1(A<0>) C2376.1(A<0>) C2377.1(A<0>) C2380.1(A<0>) C2381.1(A<0>) C2382.1(A<0>) C2383.1(A<0>) C2384.1(A<0>) C2385.1(A<0>) C2386.1(A<0>) C2396.1(A<0>) C2397.1(A<0>) C2398.1(A<0>) C2400.1(A<0>) C2403.1(A<0>) C2404.1(A<0>) C2405.1(A<0>) C2407.1(A<0>) C2409.1(A<0>) C2410.1(A<0>) C2412.1(A<0>) C2416.1(A<0>) C2417.1(A<0>) C2418.1(A<0>) C2420.1(A<0>) C2421.1(A<0>) C2422.1(A<0>) C2430.1(A<0>) C2431.1(A<0>) C2432.1(A<0>) C2433.1(A<0>) C2434.1(A<0>) C2455.1(A<0>) C2501.1(A<0>) C2502.1(A<0>) C2503.1(A<0>) C2504.1(A<0>) C2505.1(A<0>) C2506.1(A<0>) C2507.1(A<0>) C2508.1(A<0>) C2509.1(A<0>) C2510.1(A<0>) C2512.1(A<0>) C2562.1(A<0>) C2572.1(A<0>) C3001.1(A<0>) C3002.2(B<0>) C3003.1(A<0>) C3004.1(A<0>) C3005.1(A<0>) C3006.1(A<0>) C3007.1(A<0>) C3008.1(A<0>) C3009.1(A<0>) C3010.1(A<0>) C3011.1(A<0>) C3012.1(A<0>) C3013.1(A<0>) C3014.1(A<0>) C3015.1(A<0>) C3016.2(B<0>) C3018.1(A<0>) C3102.1(A<0>) C3121.1(A<0>) C3122.1(A<0>) C3123.1(A<0>) C3124.1(A<0>) C3125.1(A<0>) C4000.1(A<0>) C4001.1(A<0>) C4002.1(A<0>) C4003.1(A<0>) C4004.1(A<0>) C4005.1(A<0>) C4006.1(A<0>) C4007.1(A<0>) C4008.1(A<0>) C4009.1(A<0>) C4010.1(A<0>) C4011.1(A<0>) C4012.1(A<0>) C4013.1(A<0>) C4014.1(A<0>) C4015.1(A<0>) C4016.1(A<0>) C4017.1(A<0>) C4018.1(A<0>) C4019.1(A<0>) C4020.1(A<0>) C4021.1(A<0>) C4022.1(A<0>) C4023.1(A<0>) C4024.1(A<0>) C4025.1(A<0>) C4026.1(A<0>) C4027.1(A<0>) C4033.1(A<0>) C4082.1(A<0>) C4083.1(A<0>) C4084.1(A<0>) C4085.2(B<0>) C4086.1(A<0>) C4087.1(A<0>) C4092.1(A<0>) C4093.1(A<0>) C4094.1(A<0>) C4095.2(B<0>) C4096.1(A<0>) C4097.1(A<0>) C4100.1(A<0>) C4101.1(A<0>) C4102.1(A<0>) C4103.1(A<0>) C4105.1(A<0>) C4108.1(A<0>) C4110.1(A<0>) C4115.1(A<0>) C4126.1(A<0>) C4130.1(A<0>) C4131.1(A<0>) C4151.1(A<0>) C4161.2(B<0>) C4214.1(A<0>) C4215.1(A<0>) C4501.1(A<0>) C4502.1(A<0>) C4503.1(A<0>) C4504.1(A<0>) C4505.1(A<0>) C4506.1(A<0>) C4520.1(A<0>) C4523.1(A<0>) C4524.1(A<0>) C4600.1(A<0>) C4601.1(A<0>) C4602.1(A<0>) C4603.1(A<0>) C4604.1(A<0>) C4605.1(A<0>) C4606.1(A<0>) C4607.1(A<0>) C4608.1(A<0>) C4609.1(A<0>) C4610.1(A<0>) C4618.1(A<0>) C4670.1(A<0>) C4671.1(A<0>) C4672.1(A<0>) C4673.1(A<0>) C4674.1(A<0>) C4675.1(A<0>) C5001.1(A<0>) C5002.1(A<0>) C5306.1(A<0>) C5307.1(A<0>) C5308.1(A<0>) C5310.1(A<0>) C5311.1(A<0>) C5313.1(A<0>) C5316.1(A<0>) C5317.1(A<0>) C5318.1(A<0>) C5319.1(A<0>) C5320.1(A<0>) C5321.1(A<0>) C5322.1(A<0>) C5323.1(A<0>) C5369.1(A<0>) C5370.1(A<0>) C5374.1(A<0>) C5382.1(A<0>) C5387.1(A<0>) C5500.1(A<0>) C5501.1(A<0>) C5502.1(A<0>) C5503.1(A<0>) C5504.1(A<0>) C5505.1(A<0>) C5506.1(A<0>) C5507.1(A<0>) C5508.1(A<0>) C5509.1(A<0>) C5510.1(A<0>) C5511.1(A<0>) C5512.1(A<0>) C5513.1(A<0>) C5514.1(A<0>) C5515.1(A<0>) C5516.1(A<0>) C5517.1(A<0>) C5518.1(A<0>) C5519.1(A<0>) C5520.1(A<0>) C5521.1(A<0>) C5524.1(A<0>) C5528.1(A<0>) C5529.1(A<0>) C5530.1(A<0>) C5531.1(A<0>) C5532.1(A<0>) C5533.1(A<0>) C5534.1(A<0>) C5535.1(A<0>) C5536.1(A<0>) C5537.1(A<0>) C5538.1(A<0>) C5539.1(A<0>) C5541.2(B<0>) C5542.2(B<0>) C5549.2(B<0>) C5550.2(B<0>) C5551.2(B<0>) C5620.1(A<0>) C5680.1(A<0>) C6110.1(A<0>) C6115.1(A<0>) C6130.1(A<0>) C6140.1(A<0>) C6150.1(A<0>) C6151.1(A<0>) C6152.1(A<0>) C6153.1(A<0>) C6154.1(A<0>) C6155.1(A<0>) C6180.1(A<0>) C6181.1(A<0>) C6183.1(A<0>) C6184.1(A<0>) C6241.1(A<0>) C6242.1(A<0>) C6243.1(A<0>) C6244.1(A<0>) C6245.1(A<0>) C6260.1(A<0>) C6261.1(A<0>) C6262.1(A<0>) C6263.1(A<0>) C6264.1(A<0>) C6265.1(A<0>) C6266.1(A<0>) C6267.1(A<0>) C6268.1(A<0>) C6269.1(A<0>) C6270.1(A<0>) C6271.1(A<0>) C6283.2(B<0>) C6284.2(B<0>) C6287.2(B<0>) C6288.2(B<0>) C6291.1(A<0>) C6292.2(B<0>) C6293.1(A<0>) C6400.1(A<0>) C6401.1(A<0>) C6402.1(A<0>) C6410.1(A<0>) C6629.1(A<0>) C6630.1(A<0>) C7100.1(A<0>) C7101.1(A<0>) C7102.1(A<0>) C7103.1(A<0>) C7104.1(A<0>) C7105.1(A<0>) C7106.1(A<0>) C7107.1(A<0>) C7109.1(A<0>) C7149.1(A<0>) C7150.1(A<0>) C7151.1(A<0>) C7152.1(A<0>) C7154.1(A<0>) C7155.1(A<0>) C7157.1(A<0>) C7158.1(A<0>) C7160.1(A<0>) C7161.1(A<0>) C7162.1(A<0>) C7199.1(A<0>) C7216.1(A<0>) C7217.1(A<0>) C7218.1(A<0>) C7219.1(A<0>) C7234.2(B<0>) C7235.2(B<0>) C7238.1(A<0>) C7264.1(A<0>) C7273.1(A<0>) C7274.1(A<0>) C7326.2(B<0>) C7327.1(A<0>) C7330.1(A<0>) C7332.1(A<0>) C7335.1(A<0>) C7369.2(B<0>) C7371.2(B<0>) C7376.2(B<0>) C7500.1(A<0>) C7501.1(A<0>) C7510.1(A<0>) C7511.1(A<0>) C7520.1(A<0>) C7521.1(A<0>) C7607.2(B<0>) C7608.2(B<0>) C7613.2(B<0>) C7617.2(B<0>) C7625.1(A<0>) C7700.1(A<0>) C7701.1(A<0>) C7705.1(A<0>) C7711.1(A<0>) C7753.1(A<0>) C7755.1(A<0>) C7760.1(A<0>) C7761.1(A<0>) C7767.1(A<0>) C7768.1(A<0>) C7802.2(B<0>) C7824.2(B<0>) C7867.2(B<0>) C8200.1(A<0>) C8201.1(A<0>) C8202.1(A<0>) C8203.1(A<0>) C8204.1(A<0>) C8205.1(A<0>) C8206.1(A<0>) C8208.1(A<0>) C8209.1(A<0>) C8500.1(A<0>) C8501.1(A<0>) C8505.1(A<0>) C8510.1(A<0>) C8516.1(A<0>) D350.2(A1) D351.2(A1) D352.2(A1) D353.2(A1) D354.2(A1) D355.2(A1) D356.2(A1) D500.1(A1) D500.2(A2) D501.1(IO1) D502.1(IO1) D503.1(IO1) D504.1(IO1) D505.1(IO1) D506.1(IO1) D507.1(IO1) D508.1(IO1) D509.1(IO1) D510.2(POS) D511.1(IO1) D512.1(IO1) D513.2(POS) D514.1(IO1) D516.1(K1) D517.1(K1) D518.2(POS) E519.1(POS) E1056.1(POS) E1069.1(POS) E1073.2(NEG) E1110.1(POS) E1115.1(POS) E1116.1(POS) E2000_XOADC_GND.2(NEG) E2001.2(NEG) E2356.1(POS) E2357.1(POS) E2408.1(POS) E2451.2(NEG) E2452.2(NEG) E2453.2(NEG) E2454.1(POS) E2455.1(POS) E2560.2(NEG) E2570.1(POS) E4120.1(POS) E4520.2(NEG) E6400_GNDA.2(NEG) E6400_GNDP1.2(NEG) FL4040.2(GND) FL4050.2(GND) FL4060.2(GND1) FL4060.3(GND2) FL4060.5(GND3) FL4070.2(GND1) FL4070.3(GND2) FL4070.5(GND3) FL7001.2(GND1) FL7001.3(GND2) FL7001.5(GND3) FL7001.6(GND4) FL7001.7(GND5) FL7001.10(GND6) FL7003.2(GND1) FL7003.4(GND2) FL7003.6(GND3) FL7030.2(GND1) FL7030.3(GND2) FL7030.5(GND3) FL7030.8(GND4) FL7030.10(GND5) FL7050.2(GND1) FL7050.5(GND2) FL7050.7(GND3) FL7141.2(GND1) FL7141.4(GND2) FL7141.6(GND3) FL7150.2(GND1) FL7150.4(GND2) FL7170.2(GND1) FL7170.4(GND2) FL7260.2(GND1) FL7260.4(GND2) FL7260.5(GND3) FL7260.7(GND4) FL7260.8(GND5) FL7300.2(GND1) FL7300.4(GND2) FL7300.5(GND3) FL7300.7(GND4) FL7300.8(GND5) FL7310.2(GND1) FL7310.4(GND2) FL7310.5(GND3) FL7310.7(GND4) FL7310.8(GND5) FL7350.2(GND1) FL7350.3(GND2) FL7350.5(GND3) FL7600.2(GND4) FL7600.3(GND5) FL7600.4(GND1) FL7600.5(GND6) FL7600.7(GND2) FL7600.8(GND3) FL7600.10(GND7) FL7610.2(GND4) FL7610.3(GND5) FL7610.4(GND1) FL7610.5(GND6) FL7610.7(GND2) FL7610.8(GND3) FL7610.10(GND7) FL7620.2(GND4) FL7620.3(GND5) FL7620.4(GND1) FL7620.5(GND6) FL7620.7(GND2) FL7620.8(GND3) FL7620.10(GND7) FL7700.2(GND1) FL7700.3(GND2) FL7700.5(GND3) FL7705.2(GND1) FL7705.3(GND2) FL7705.5(GND3) FL7710.2(GND1) FL7710.3(GND2) FL7710.5(GND3) FL7715.2(GND1) FL7715.3(GND2) FL7715.5(GND3) FL7720.2(GND1) FL7720.3(GND2) FL7720.5(GND3) FL7800.2(GND1) FL7800.3(GND2) FL7800.5(GND3) FL7820.2(GND1) FL7820.3(GND2) FL7820.5(GND3) FL7830.2(GND1) FL7830.3(GND2) FL7830.5(GND3) FL8502.2(GND1) FL8502.3(GND2) FL8502.5(GND3) J110.3(G1) J110.4(G2) J110.5(G3) J110.6(G4) J130.3(G1) J130.4(G2) J130.5(G3) J130.6(G4) J210.3(G1) J210.4(G2) J210.5(G3) J210.6(G4) J230.3(G1) J230.4(G2) J230.5(G3) J230.6(G4) J250.3(G1) J250.4(G2) J250.5(G3) J250.6(G4) J300.3(G1) J300.4(G2) J300.5(G3) J300.6(G4) J350.6(X<0>) J350.G3(X<0>) J350.G4(X<0>) J400.3(G1) J400.4(G2) J400.5(G3) J400.6(G4) J510.G1(X<0>) J510.G2(X<0>) J510.G3(X<0>) J510.G4(X<0>) J4250.3(X<0>) J4250.G1(X<0>) J4250.G2(X<0>) J4250.G3(X<0>) J4250.G4(X<0>) J4500.G1(X<0>) J4500.G2(X<0>) J4500.G3(X<0>) J4500.G4(X<0>) J4700.G1(X<0>) J4700.G2(X<0>) J4700.G3(X<0>) J4700.G4(X<0>) J5300.2(X<0>) J5300.8(X<0>) J5300.14(X<0>) J5300.20(X<0>) J5300.26(X<0>) J5300.32(X<0>) J5300.49(X<0>) J5300.50(X<0>) J5300.G1(X<0>) J5300.G2(X<0>) J5300.G3(X<0>) J5300.G4(X<0>) J5300.G5(X<0>) J5300.G6(X<0>) J5300.G7(X<0>) J5300.G8(X<0>) J5500.1(X<0>) J5500.2(X<0>) J5500.7(X<0>) J5500.13(X<0>) J5500.19(X<0>) J5500.22(X<0>) J5500.25(X<0>) J5500.30(X<0>) J5500.31(X<0>) J5500.32(X<0>) J5500.34(X<0>) J5500.36(X<0>) J5500.37(X<0>) J5500.38(X<0>) J5500.43(X<0>) J5500.49(X<0>) J5500.50(X<0>) J5500.54(X<0>) J5500.58(X<0>) J5500.L1(X<0>) J5500.L2(X<0>) J5500.L3(X<0>) J5500.L4(X<0>) J5501.1(X<0>) J5501.2(X<0>) J5501.6(X<0>) J5501.7(X<0>) J5501.13(X<0>) J5501.14(X<0>) J5501.18(X<0>) J5501.19(X<0>) J5501.20(X<0>) J5501.29(X<0>) J5501.30(X<0>) J5501.L1(X<0>) J5501.L2(X<0>) J5501.L3(X<0>) J5501.L4(X<0>) J5501.R1(X<0>) J5501.R2(X<0>) J5501.R3(X<0>) J5501.R4(X<0>) J5502.3(X<0>) J5502.4(X<0>) J5502.10(X<0>) J5502.15(X<0>) J5502.22(X<0>) J5502.26(X<0>) J5502.28(X<0>) J5502.29(X<0>) J5502.30(X<0>) J5502.R1(X<0>) J5502.R2(X<0>) J5502.R3(X<0>) J5502.R4(X<0>) J6400.1(X<0>) J6400.2(X<0>) J6400.3(X<0>) J6400.4(X<0>) J6400.5(X<0>) J6400.6(X<0>) J6601.1(X<0>) J6601.10(X<0>) J6601.13(X<0>) JTAG.1(X<0>) JTAG.G1(X<0>) JTAG.G2(X<0>) L111.1(A<0>) L113.1(A<0>) L116.1(A<0>) L117.1(A<0>) L118.1(A<0>) L123.1(A<0>) L131.1(A<0>) L143.1(A<0>) L170.1(A<0>) L211.1(A<0>) L214.1(A<0>) L216.1(A<0>) L217.1(A<0>) L218.1(A<0>) L223.1(A<0>) L231.1(A<0>) L243.1(A<0>) L251.1(A<0>) L263.1(A<0>) L270.1(A<0>) L301.1(A<0>) L305.1(A<0>) L401.1(A<0>) L405.1(A<0>) L2503.2(B<0>) L3201.1(A<0>) L4041.1(A<0>) L4042.1(A<0>) L4046.1(A<0>) L4048.1(A<0>) L4051.1(A<0>) L4052.1(A<0>) L4056.1(A<0>) L4058.1(A<0>) L4061.1(A<0>) L4062.1(A<0>) L4066.1(A<0>) L4068.1(A<0>) L4071.1(A<0>) L4072.1(A<0>) L4076.1(A<0>) L4078.1(A<0>) L7001.1(A<0>) L7004.1(A<0>) L7051.1(A<0>) L7056.1(A<0>) L7111.1(A<0>) L7113.1(A<0>) L7115.1(A<0>) L7127.1(A<0>) L7130.1(A<0>) L7132.1(A<0>) L7140.1(A<0>) L7142.1(A<0>) L7144.1(A<0>) L7166.1(A<0>) L7171.1(A<0>) L7172.1(A<0>) L7173.1(A<0>) L7180.1(A<0>) L7183.1(A<0>) L7231.1(A<0>) L7233.1(A<0>) L7236.1(A<0>) L7240.1(A<0>) L7260.1(A<0>) L7262.1(A<0>) L7265.1(A<0>) L7267.1(A<0>) L7268.1(A<0>) L7301.1(A<0>) L7303.1(A<0>) L7311.1(A<0>) L7313.1(A<0>) L7317.1(A<0>) L7350.1(A<0>) L7352.1(A<0>) L7354.1(A<0>) L7505.1(A<0>) L7516.1(A<0>) L7525.1(A<0>) L7601.1(A<0>) L7611.1(A<0>) L7621.1(A<0>) L7623.1(A<0>) L7627.1(A<0>) L7629.2(B<0>) L7630.1(A<0>) L7631.1(A<0>) L7647.1(A<0>) L7648.1(A<0>) L7716.1(A<0>) L7717.1(A<0>) L7721.1(A<0>) L7722.1(A<0>) L7801.1(A<0>) L7820.1(A<0>) L7821.1(A<0>) L7831.1(A<0>) L7833.1(A<0>) L7834.2(B<0>) L8503.1(A<0>) L8504.1(A<0>) L8516.1(A<0>) M001.1(GND) M002.1(GND) M003.1(GND) M004.1(GND) M005.1(GND) M006.1(GND) M007.1(GND) M008.1(GND) M009.1(GND) M010.1(GND) M011.1(GND) M012.1(GND) M013.1(GND) M014.1(GND) M015.1(GND) M021.1(GND) M022.1(GND) M023.1(GND) M024.1(GND) M025.1(GND) M026.1(GND) M057.1(GND) M060.1(GND) M101.1(X) M201.1(X) M301.1(GND) M401.1(GND) M1001.1(GND) M1002.1(X) M1003.1(X) M1004.1(X) M1005.1(GND) M1006.1(GND) M1007.1(X) M2000.1(GND) M3001.1(PIN1) M3001.2(PIN2) M3001.3(PIN3) M3001.4(PIN4) M3001.5(PIN5) M3002.1(PIN1) M3002.2(PIN2) M3002.3(PIN3) M3002.4(PIN4) M3002.5(PIN5) M3003.1(PIN1) M3003.2(PIN2) M3003.3(PIN3) M3003.4(PIN4) M3003.5(PIN5) MK4520.3(GND) Q2031.2(S) Q2032.2(S) Q6268.1(S1) Q6268.4(S2) R500.1(A<0>) R510.2(B<0>) R520.1(A<0>) R1003.1(A<0>) R1004.1(A<0>) R1129.1(A<0>) R1130.1(A<0>) R1171.1(A<0>) R1172.1(A<0>) R1173.2(B<0>) R2016.1(A<0>) R2018.1(A<0>) R2020.1(A<0>) R2406.1(A<0>) R2410.1(A<0>) R2418.1(A<0>) R3301.1(A<0>) R4006.1(A<0>) R4010.1(A<0>) R4044.1(A<0>) R4049.1(A<0>) R4054.1(A<0>) R4059.1(A<0>) R4064.1(A<0>) R4074.1(A<0>) R4081.1(A<0>) R4092.1(A<0>) R4100.1(A<0>) R4256.1(A<0>) R4615.1(A<0>) R4618.1(A<0>) R5001.1(A<0>) R5321.1(A<0>) R5322.1(A<0>) R6181.1(A<0>) R6402.1(A<0>) R7120.1(A<0>) R7122.1(A<0>) R7176.1(A<0>) R7178.1(A<0>) R7314.1(A<0>) R7620.1(A<0>) RT515.2(NEG) RT516.2(NEG) RT1001.2(NEG) RT2401.1(POS) RT6165.2(NEG) RT7149.2(NEG) RT7199.2(NEG) SH1.1 SH2.1 SH3.1 SH4.1 SH5.1 SH6.1 SH7.1 SH8.1 TP_NFC_GND_1.1(X) TP_NFC_GND_2.1(X) TP_UART_GND.1(X) U100.7(GND1) U100.12(USID) U100.15(GND2) U200.7(GND1) U200.15(GND2) U500.1(GND1) U500.5(GND2) U500.21(GND3) U500.22(GND4) U500.23(GND5) U500.24(GND6) U500.25(GND7) U500.G1(GND8) U500.G2(GND9) U500.G3(GND11) U500.G4(GND10) U520.4(GND) U1001.A1(GND3) U1001.A23(GND2) U1001.A43(GND4) U1001.AA1(GND202) U1001.AA13(GND9) U1001.AA35(GND10) U1001.AA43(GND11) U1001.AB12(GND12) U1001.AB14(GND13) U1001.AB16(GND14) U1001.AB18(GND15) U1001.AB24(GND16) U1001.AB26(GND17) U1001.AB28(GND18) U1001.AB30(GND19) U1001.AB32(GND20) U1001.AB34(GND21) U1001.AB36(GND22) U1001.AD4(GND24) U1001.AD36(GND23) U1001.AE1(GND25) U1001.AE43(GND26) U1001.AF10(GND27) U1001.AF12(GND28) U1001.AF14(GND29) U1001.AF24(GND30) U1001.AF30(GND31) U1001.AF32(GND32) U1001.AG7(GND34) U1001.AG21(GND33) U1001.AH10(GND35) U1001.AH12(GND36) U1001.AH14(GND37) U1001.AH16(GND38) U1001.AH18(GND39) U1001.AH20(GND40) U1001.AH26(GND41) U1001.AH28(GND42) U1001.AH30(GND43) U1001.AJ1(GND44) U1001.AJ7(GND48) U1001.AJ21(GND45) U1001.AJ37(GND46) U1001.AJ43(GND47) U1001.AK6(GND51) U1001.AK10(GND49) U1001.AK22(GND50) U1001.AM10(GND52) U1001.AM22(GND53) U1001.AM30(GND54) U1001.AM32(GND55) U1001.AM34(GND56) U1001.AN1(GND57) U1001.AN7(GND61) U1001.AN23(GND58) U1001.AN37(GND59) U1001.AN43(GND60) U1001.AP8(VDD_P2) U1001.AP12(GND62) U1001.AP14(GND63) U1001.AP16(GND64) U1001.AP18(GND65) U1001.AP20(GND66) U1001.AP22(GND67) U1001.AP24(GND68) U1001.AP26(GND69) U1001.AP28(GND70) U1001.AP30(GND71) U1001.AP32(GND72) U1001.AR9(VREF_SDC) U1001.AR13(GND73) U1001.AR19(GND74) U1001.AR21(GND75) U1001.AR39(GND76) U1001.AT20(GND77) U1001.AT22(GND78) U1001.AT38(GND79) U1001.AU1(GND80) U1001.AU19(GND81) U1001.AU21(GND1) U1001.AU23(GND82) U1001.AU33(GND83) U1001.AU39(GND84) U1001.AU43(GND85) U1001.AV18(GND86) U1001.AV22(GND87) U1001.AV24(GND88) U1001.AW17(GND89) U1001.AW25(GND90) U1001.AW43(GND91) U1001.AY26(GND92) U1001.B42(GND5) U1001.BA1(GND94) U1001.BA5(GND106) U1001.BA9(GND107) U1001.BA13(GND95) U1001.BA17(GND96) U1001.BA21(GND97) U1001.BA25(GND98) U1001.BA27(GND99) U1001.BA31(GND100) U1001.BA35(GND101) U1001.BA37(GND102) U1001.BA39(GND103) U1001.BA41(GND104) U1001.BA43(GND105) U1001.C3(GND112) U1001.C5(GND118) U1001.C7(GND119) U1001.C9(GND120) U1001.C11(GND6) U1001.C13(GND7) U1001.C15(GND8) U1001.C17(GND93) U1001.C19(GND108) U1001.C25(GND109) U1001.C27(GND110) U1001.C29(GND111) U1001.C31(GND113) U1001.C33(GND114) U1001.C35(GND115) U1001.C37(GND116) U1001.C39(GND117) U1001.D2(GND121) U1001.E1(GND122) U1001.E3(GND123) U1001.E5(GND126) U1001.E39(GND124) U1001.E43(GND125) U1001.F4(GND130) U1001.F6(GND131) U1001.F14(GND127) U1001.F22(GND128) U1001.F30(GND129) U1001.G5(GND140) U1001.G7(GND141) U1001.G9(GND142) U1001.G11(GND132) U1001.G13(GND133) U1001.G15(GND134) U1001.G19(GND135) U1001.G29(GND136) U1001.G31(GND137) U1001.G33(GND138) U1001.G35(GND139) U1001.H4(GND144) U1001.H8(GND145) U1001.H30(VDD_P7) U1001.H34(GND143) U1001.J1(GND146) U1001.J3(GND147) U1001.J43(GND148) U1001.K4(GND154) U1001.K26(GND149) U1001.K28(GND150) U1001.K30(GND151) U1001.K32(GND152) U1001.K34(GND153) U1001.L5(GND155) U1001.L7(GND158) U1001.M6(GND164) U1001.M12(GND156) U1001.M14(GND157) U1001.M16(GND159) U1001.M18(GND160) U1001.M20(GND161) U1001.M22(GND162) U1001.M36(GND163) U1001.N1(GND165) U1001.N5(GND169) U1001.N37(GND166) U1001.N43(GND167) U1001.P10(GND170) U1001.P12(GND168) U1001.P28(GND171) U1001.P30(GND172) U1001.P32(GND173) U1001.P34(GND174) U1001.P36(GND175) U1001.R33(GND176) U1001.T8(GND188) U1001.T10(GND177) U1001.T12(GND178) U1001.T14(GND179) U1001.T16(GND180) U1001.T18(GND181) U1001.T20(GND182) U1001.T22(GND183) U1001.T28(GND184) U1001.T30(GND185) U1001.T32(GND186) U1001.T40(GND187) U1001.U1(GND189) U1001.U43(GND190) U1001.V22(GND191) U1001.V34(GND192) U1001.V36(GND193) U1001.W35(GND194) U1001.Y8(GND201) U1001.Y10(GND195) U1001.Y12(GND196) U1001.Y14(GND197) U1001.Y16(GND198) U1001.Y18(GND199) U1001.Y22(GND200) U1005.3(GND) U1600.AA4(VSS43) U1600.AA6(VSS44) U1600.AA8(VSS45) U1600.AA14(VSS46) U1600.AA15(VSS47) U1600.AB4(VSS48) U1600.AB5(VSS49) U1600.AB7(VSS50) U1600.AB14(VSS51) U1600.AC4(VSS52) U1600.AC6(VSS53) U1600.AC8(VSS54) U1600.B4(VSS1) U1600.B6(VSS2) U1600.B8(VSS3) U1600.C4(VSS4) U1600.C5(VSS5) U1600.C7(VSS6) U1600.C14(VSS7) U1600.D4(VSS8) U1600.D6(VSS9) U1600.D8(VSS10) U1600.D14(VSS11) U1600.D15(VSS12) U1600.E14(VSS13) U1600.F14(VSS14) U1600.G4(VSS15) U1600.G5(VSS16) U1600.G6(VSS17) U1600.G13(VSS18) U1600.G15(VSS19) U1600.H4(VSS20) U1600.H7(VSS21) U1600.H13(VSS22) U1600.H15(VSS23) U1600.J6(VSS24) U1600.K4(VSS25) U1600.K7(VSS26) U1600.K8(VSS27) U1600.K13(VSS55) U1600.K14(VSS56) U1600.K16(VSS57) U1600.L12(VSS58) U1600.L15(VSS59) U1600.L16(VSS60) U1600.M8(VSS61) U1600.M13(VSS62) U1600.M14(VSS63) U1600.N8(VSS64) U1600.N12(VSS65) U1600.N15(VSS66) U1600.N16(VSS67) U1600.P13(VSS68) U1600.P14(VSS69) U1600.R4(VSS28) U1600.R7(VSS29) U1600.R8(VSS30) U1600.R15(VSS70) U1600.R16(VSS71) U1600.R17(VSS72) U1600.T6(VSS31) U1600.U4(VSS32) U1600.U7(VSS33) U1600.U13(VSS34) U1600.U15(VSS35) U1600.V4(VSS36) U1600.V5(VSS37) U1600.V6(VSS38) U1600.V13(VSS39) U1600.V15(VSS40) U1600.W14(VSS41) U1600.Y14(VSS42) U2000.10(GND_S2_1) U2000.12(PGND_CHG_1) U2000.13(PGND_CHG_2) U2000.21(GND_S3_1) U2000.23(PGND_CHG_3) U2000.24(PGND_CHG_4) U2000.28(PGND_HAP) U2000.32(GND_S2_2) U2000.43(GND_S3_2) U2000.50(HAP_PWM_IN) U2000.58(GND_CHG_1) U2000.59(REF_GND_CHG) U2000.69(GND_CHG_2) U2000.70(GND_CHG_3) U2000.80(DC_SNS) U2000.82(GND_CHG_4) U2000.83(GND_1) U2000.84(GND_HAP) U2000.86(GND_S1_1) U2000.87(GND_S1_2) U2000.91(WIPWR_CHG_OK) U2000.93(GND_2) U2000.94(GND_3) U2000.97(GND_S6_1) U2000.103(QI_PMA_ON) U2000.104(GND_WLP_TST) U2000.105(GND_4) U2000.106(GND_5) U2000.114(GND_6) U2000.115(GND_PD_PHY) U2000.116(GND_7) U2000.124(GND_PSUB_FG) U2000.125(GND_8) U2000.126(GND_9) U2000.127(GND_10) U2000.135(GND_11) U2000.138(GND_12) U2000.144(ISNS_SMB_P) U2000.149(TEST_EN_VPP) U2000.155(ISNS_SMB_M) U2000.163(GND_S5_1) U2000.164(GND_S5_2) U2000.167(REF_GND_FG) U2000.188(GND_XO_ISO) U2000.196(GND_S4_1) U2000.199(GND_XO_1) U2000.207(GND_S4_2) U2000.209(GND_XO_2) U2000.212(GND_RF) U2210.C1(GND1) U2210.C2(GND2) U2210.C3(MODE) U2400.27(GND_FLASH_1) U2400.38(GND_FLASH_2) U2400.46(GND_S3_1) U2400.47(GND_S3_2) U2400.53(PSUB_BOB) U2400.54(GND_DISP_M) U2400.66(PGND_DISP) U2400.71(REF_GND) U2400.76(GND_DISP_P) U2400.78(GND_S4_1) U2400.79(GND_S4_2) U2400.82(GND_1) U2400.84(GND_2) U2400.85(GND_3) U2400.94(TEST_EN_VPP) U2400.95(GND_4) U2400.96(GND_5) U2400.98(GND_OLEDB) U2400.104(GND_6) U2400.105(GND_7) U2400.106(GND_8) U2400.107(WLP_TST) U2400.110(PGND_OLEDB) U2400.116(GND_9) U2400.117(GND_10) U2400.118(GND_11) U2400.119(CDC_PDM_RX1_DRE) U2400.125(GND_12) U2400.127(CDC_PDM_RX0) U2400.136(GND_CFILT) U2400.139(CDC_PDM_RX1) U2400.140(CDC_PDM_CLK) U2400.141(CDC_PDM_RX2) U2400.150(CDC_PDM_RX0_DRE) U2400.153(GND_S5_1) U2400.154(GND_S5_2) U2400.155(GND_S1_1) U2400.161(CDC_PDM_SYNC) U2400.163(GND_BOOST_1) U2400.171(GND_SPKR_PA_1) U2400.172(GND_SPKR_PA_2) U2400.177(GND_S1_2) U2400.195(GND_CP) U2400.196(GND_BOOST_2) U2401.B4(GND1) U2401.B5(GND2) U2560.C3(AGND1) U2560.E1(AGND2) U2570.C3(AGND1) U2570.E1(AGND2) U3100.1(GND68) U3100.4(GND31) U3100.8(GND35) U3100.9(GND69) U3100.12(GND22) U3100.17(GND54) U3100.19(GND23) U3100.20(GND26) U3100.21(GND37) U3100.22(GND38) U3100.23(GND55) U3100.24(GND53) U3100.28(GND25) U3100.30(GND48) U3100.31(GND52) U3100.34(GND12) U3100.36(GND39) U3100.40(GND13) U3100.41(GND36) U3100.42(GND40) U3100.44(GND65) U3100.45(GND51) U3100.48(GND24) U3100.49(GND2) U3100.51(GND58) U3100.52(GND60) U3100.55(GND33) U3100.56(GND41) U3100.58(GND3) U3100.61(GND11) U3100.62(GND50) U3100.67(GND4) U3100.76(GND59) U3100.78(GND63) U3100.79(GND49) U3100.84(GND5) U3100.89(GND7) U3100.91(GND73) U3100.92(GND47) U3100.93(GND64) U3100.94(GND66) U3100.97(GND42) U3100.98(GND6) U3100.99(GND1) U3100.100(GND30) U3100.102(GND67) U3100.105(GND15) U3100.106(GND72) U3100.109(GND16) U3100.115(GND70) U3100.116(GND10) U3100.124(GND71) U3100.125(GND17) U3100.128(GND43) U3100.129(GND14) U3100.131(GND45) U3100.134(GND44) U3100.138(GND9) U3100.139(GND46) U3100.140(GND18) U3100.145(GND56) U3100.147(GND61) U3100.151(GND57) U3100.153(GND29) U3100.155(GND19) U3100.158(GND8) U3100.160(GND28) U3100.162(GND62) U3100.163(GND20) U3100.172(GND21) U3100.174(GND32) U3100.175(GND27) U3100.180(GND34) U4000.4(GND_SEALRING4) U4000.7(GND_WL_BT_RXFE_CH0) U4000.10(GND_BT_CH2) U4000.14(GND_DPD_CH0) U4000.16(GND_FM_RXFE) U4000.17(GND_FM_VCO) U4000.19(GND_BT_BB) U4000.21(GND_WL_BT_DRV_CH0) U4000.22(FM_RX_HEADSET) U4000.24(GND_BT_FM_BBPLL_A) U4000.25(GND_BT_FM_BBPLL_B) U4000.26(GND_BT_SYNTH) U4000.28(GND_WL_2G_PA_CH0) U4000.31(GND_PM) U4000.36(GND_WL_BALUN_CH0) U4000.37(GND_SEALRING3) U4000.41(GND_ESD_0) U4000.42(GND_WL_5G_PA_CH0) U4000.44(SENS_CTS) U4000.47(GND_WL_SYNTH_CH0) U4000.49(GND_WL_5G_DRV_CH0) U4000.56(GND_WL_PDET_BE) U4000.57(GND_WL_5G_RXFE_CH0) U4000.58(GND_ISO_WL) U4000.61(GND_XTAL) U4000.65(GND_WL_2G_RXFE_CH1) U4000.67(GND_DIG) U4000.69(GND_WL_BB_CH0) U4000.72(GND_WL_PDET_FE) U4000.76(GND_ISO) U4000.79(GND_WL_2G_DRV_CH1) U4000.83(GND_WL_SYNTH_CH1) U4000.85(GND_WL_2G_PA_CH1) U4000.87(GND_IO) U4000.93(GND_WL_BALUN_CH1) U4000.98(GND_WL_BB_CH1) U4000.99(GND_ESD_1) U4000.100(GND_WL_5G_PA_CH1) U4000.107(GND_WL_5G_DRV_CH1) U4000.109(GND_SEALRING2) U4000.112(GND_SEALRING5) U4000.115(GND_WL_5G_RXFE_CH1) U4000.116(GND_SEALRING1) U4080.4(GND) U4080.G1(CTGND) U4081.2(GND1) U4081.3(GND2) U4090.4(GND) U4090.G1(CTGND) U4091.2(GND1) U4091.3(GND2) U4100.A2(GND_CDMP) U4100.B2(GND1) U4100.B4(GND_TX_1) U4100.B5(GND_TX_2) U4100.C2(GND_A) U4100.C3(GND_SUB) U4100.C4(GND2) U4100.C6(GND_ALM) U4100.C7(GND_PLL) U4100.D6(GND3) U4100.F8(UART_NRTS_HIS) U4100.G7(GND4) U4100.G8(GND_IO) U4200.1(GND) U4200.G1(CTGND) U4250.5(GND) U4250.6(OE) U4600.A1(NC1) U4600.A2(NC2) U4600.A5(PGND1) U4600.B2(GND1) U4600.B5(PGND2) U4600.C1(NC3) U4600.D1(IFMD) U4600.D2(GND2) U4600.D3(TM1) U4600.D4(TM2) U4600.E5(BGND1) U4600.F2(AD_CSN) U4600.F5(BGND2) U4600.G4(GND3) U4600.G5(BGND3) U5000.2(GND) U5000.G1(CTGND) U5300.B1(GND) U5301.B1(GND) U6110.2(SDX) U6110.3(SCX) U6110.6(GND1) U6110.7(GND2) U6115.2(SDX) U6115.3(SCX) U6115.6(GND1) U6115.7(GND2) U6130.A1(VSS) U6140.1(GND1) U6140.5(SDO) U6140.7(GND2) U6150.5(GND) U6180.7(GND) U6180.G1(CTGND) U6182.B1(GND) U6250.A1(NC1) U6250.A11(NC2) U6250.AB16(DGND8) U6250.B8(CPGND) U6250.C1(AGND1) U6250.C11(NC3) U6250.E11(NC4) U6250.F2(SUBGND1) U6250.G15(AGND2) U6250.H10(NC5) U6250.H16(SUBGND2) U6250.J5(NC7) U6250.J11(NC6) U6250.J15(DGND1) U6250.K6(NC10) U6250.K8(NC11) U6250.K10(NC8) U6250.K12(NC9) U6250.L3(NC13) U6250.L5(NC14) U6250.L7(NC15) U6250.L9(NC16) U6250.L11(NC12) U6250.L15(DGND10) U6250.M2(NC19) U6250.M4(NC20) U6250.M6(NC21) U6250.M8(NC22) U6250.M10(NC17) U6250.M12(NC18) U6250.N1(DGND5) U6250.N5(NC24) U6250.N7(NC25) U6250.N9(NC26) U6250.N11(NC23) U6250.P4(NC29) U6250.P6(NC30) U6250.P8(NC31) U6250.P10(NC27) U6250.P12(NC28) U6250.R11(NC32) U6250.U9(TRST) U6250.U15(DGND2) U6250.W5(DGND6) U6250.Y2(DGND3) U6250.Y8(DGND9) U6250.Y10(DGND7) U6250.Y14(DGND4) U6290.A1(MODE) U6290.C2(GND) U6400.D4(I2C_AD1_SPI_SCLK) U6400.E4(I2C_AD0_SPI_SS) U7100.1(GND1) U7100.3(GND2) U7100.7(GND3) U7100.9(GND4) U7100.10(GND5) U7100.11(GND6) U7100.12(GND7) U7100.17(GND8) U7100.21(GND9) U7100.25(GND10) U7100.27(GND11) U7100.28(GND12) U7100.29(GND13) U7100.31(GND14) U7100.33(GND15) U7100.34(GND16) U7100.35(GND17) U7100.40(GND18) U7100.41(GND19) U7100.42(GND20) U7100.43(GND21) U7100.45(GND22) U7100.46(GND23) U7100.48(GND24) U7100.50(GND25) U7100.52(GND26) U7100.G1(CTGND1) U7100.G2(CTGND2) U7100.G3(CTGND3) U7100.G4(CTGND4) U7100.G5(CTGND5) U7100.G6(CTGND6) U7100.G7(CTGND7) U7100.G8(CTGND8) U7100.G9(CTGND9) U7100.G10(CTGND10) U7100.G11(CTGND11) U7100.G12(CTGND12) U7100.G13(CTGND13) U7100.G14(CTGND14) U7100.G15(CTGND15) U7100.G16(CTGND16) U7100.G17(CTGND17) U7100.G18(CTGND18) U7100.G19(CTGND19) U7100.G20(CTGND20) U7100.G21(CTGND21) U7100.G22(CTGND22) U7100.G23(CTGND23) U7100.G24(CTGND24) U7150.1(GND1) U7150.2(HB_CPL_IN) U7150.3(GND2) U7150.6(GND3) U7150.8(GND4) U7150.10(GND5) U7150.12(GND6) U7150.15(GND7) U7150.17(GND8) U7150.19(GND9) U7150.21(GND10) U7150.30(GND11) U7150.32(GND12) U7150.37(GND13) U7150.40(GND14) U7150.42(GND15) U7150.44(GND16) U7150.46(GND17) U7150.48(GND18) U7150.50(GND19) U7150.53(GND20) U7150.56(GND21) U7150.58(GND22) U7150.60(GND23) U7150.62(GND24) U7150.G1(CTGND1) U7150.G2(CTGND2) U7150.G3(CTGND3) U7150.G4(CTGND4) U7150.G5(CTGND5) U7150.G6(CTGND6) U7150.G7(CTGND7) U7150.G8(CTGND8) U7150.G9(CTGND9) U7150.G10(CTGND10) U7150.G11(CTGND11) U7150.G12(CTGND12) U7150.G13(CTGND13) U7150.G14(CTGND14) U7150.G15(CTGND15) U7150.G16(CTGND16) U7150.G17(CTGND17) U7150.G18(CTGND18) U7150.G19(CTGND19) U7150.G20(CTGND20) U7150.G21(CTGND21) U7150.G22(CTGND22) U7150.G23(CTGND23) U7150.G24(CTGND24) U7150.G25(CTGND25) U7150.G26(CTGND26) U7150.G27(CTGND27) U7150.G28(CTGND28) U7150.G29(CTGND29) U7150.G30(CTGND30) U7216.A2(SW15) U7216.A4(SW14) U7216.C4(GND1) U7216.D3(GND2) U7216.E2(ID0) U7216.E4(GND3) U7216.F5(GND4) U7216.G2(LHB_HB_IN) U7230.2(GND1) U7230.6(GND2) U7230.8(GND3) U7230.9(GND4) U7500.4(GND) U7500.G1(CTGND) U7510.10(GND1) U7510.12(GND2) U7520.10(GND1) U7520.12(NC2) U7701.A2(SW15) U7701.A4(SW14) U7701.B3(SW13) U7701.C4(GND1) U7701.D3(GND2) U7701.E4(GND3) U7701.F5(GND4) U7701.G2(LHB_HB_IN) U8200.3(GND_AMP) U8200.13(GND_SUB) U8200.14(GND1) U8200.15(USID_LSB) U8200.17(GND2) U8200.22(GND3) U8200.25(GND_BOB1) U8200.31(GND_BOB2) U8200.33(GND_SW) U8501.1(GND1) U8501.4(GND2) VR510.2(POS) VR1020.2(A1) VR1021.2(A1) VR1506.1(A2) VR1507.1(A2) VR1508.1(A2) VR1509.1(A2) VR1510.1(A2) VR1511.2(K2) VR1513.2(K2) VR4251.2(A1) VR4252.2(A1) VR4253.2(A1) VR4500.1(A2) VR4501.1(A2) VR4520.1(A2) VR4521.1(A2) VR4670.1(A2) VR4671.1(A2)
GND_FG: C2408.1(A<0>) E2408.2(NEG) U2000.134(GND_FG)
GND_S2B: C2356.1(A<0>) E2356.2(NEG) E2357.2(NEG) U2400.23(GND_S2_1) U2400.45(GND_S2_2)
GND_XOADC: C2000.1(A<0>) E2000_XOADC_GND.1(POS) U2000.193(GND_XOADC) Y2000.2(THRMSTR_OUT_GND)
PGND_BOB: C2451.1(A<0>) C2452.1(A<0>) C2453.1(A<0>) E2451.1(POS) E2452.1(POS) E2453.1(POS) E2454.2(NEG) E2455.2(NEG) U2400.8(PGND_BOB_1) U2400.30(PGND_BOB_2)
VDD11D_PM: C4000.2(B<0>) U4000.80(VDD11D_PM)
VDD_WL_SYNTH_CH0_1P3: C4004.2(B<0>) R4002.2(B<0>) U4000.33(VDD13_WL_SYNTH_CH0)
VDD_WL_SYNTH_CH1_1P3: C4005.2(B<0>) R4003.2(B<0>) U4000.90(VDD13_WL_SYNTH_CH1)
VDDCORE_CDC_1P2: C6260.2(B<0>) C6262.2(B<0>) C6263.2(B<0>) C6264.2(B<0>) C6293.2(B<0>) L6292.2(B<0>) R6268.1(A<0>) U6250.AA3(DCVDD_5) U6250.AA15(DCVDD_2) U6250.AB6(DCVDD_4) U6250.AB12(DCVDD_3) U6250.D10(CPVDD2) U6250.P16(DCVDD_1) U6290.C1(FB)
VDDI__MEMORY: C1611.2(B<0>) U1600.L17(VDDI)
ACC_GYR_VDD_ISO: C6110.2(B<0>) R6110.2(B<0>) U6110.5(VDDIO) U6110.8(VDD)
ACC_GYR_VDD_ISO2: C6115.2(B<0>) R6115.2(B<0>) U6115.5(VDDIO) U6115.8(VDD)
ACCEL_INT: U1001.G41(GPIO_117) U6110.4(INT1) U6115.4(INT1)
ANT1_GPS_MBDRX_HBTRX: C130.1(A<0>) FL7001.1(ANT)
ANT1_MBDRX_HBTRX_50R: C7003.1(A<0>) FL7001.9(CELL)
ANT1_ULBLBDRX: C110.1(A<0>) C7505.1(A<0>)
ANT2_MBTRX_WLAN2GS0: C230.1(A<0>) FL7030.9(ANT) L7030.1(A<0>)
ANT2_UHBDRX_LAAPRX_WLAN5GS0: C250.1(A<0>) C4057.2(B<0>) L4058.2(B<0>)
ANT2_ULBLBTRX: C210.1(A<0>) FL7141.1(IN)
ANT3_HBDRX: C300.1(A<0>) C7526.1(A<0>) L7525.2(B<0>)
ANT4_WLANMIMO: C400.1(A<0>) FL7050.6(COMM) L7056.2(B<0>)
ANT_CSNS_CS0_N: D353.1(A2) J350.10(X<0>) R6155.1(A<0>)
ANT_CSNS_CS2_N: L175.2(B<0>) L177.2(B<0>) R6153.1(A<0>)
ANT_CSNS_CS3_N: L277.2(B<0>) L279.2(B<0>) R6150.1(A<0>)
ANT_GPS: C8503.1(A<0>) C8510.2(B<0>) FL7001.4(BEIDOU_GPS_GLONASS) L8501.2(B<0>)
ANT_HB_TRX: C7181.2(B<0>) C7182.2(B<0>) FL7003.1(HIGH_BAND)
ANT_MB_DRX: C7515.2(B<0>) FL7003.3(LOW_BAND)
ANT_MB_TRX: C7173.2(B<0>) FL7030.4(CELL) L7031.1(A<0>)
ANT_WLAN5G_S1: C4047.2(B<0>) L4048.2(B<0>) R7050.2(B<0>)
ANT_WLAN24_S0: C4067.2(B<0>) FL7030.1(PA) L4068.2(B<0>)
ANT_WLAN24_S1: C4077.2(B<0>) FL7050.1(LO_FREQ) L4078.2(B<0>)
AP_DBG_UART_RX: JTAG.13(X<0>) TP_UART_RX.1(X) U1001.W37(GPIO_5) VR1020.1(A2)
AP_DBG_UART_TX: JTAG.11(X<0>) TP_UART_TX.1(X) U1001.V38(GPIO_4) VR1021.1(A2)
APPS4_I2C_SCL: R1051.1(A<0>) U519.A2(SCL) U1001.AP10(GPIO_90) U2570.E2(SCL) U4600.G1(SCL_SCK)
APPS4_I2C_SDA: R1050.1(A<0>) U519.C1(SDA) U1001.BA3(GPIO_89) U2570.D3(SDA) U4600.F1(SDA_MOSI)
APPS10_I2C_SCL: C5528.2(B<0>) C6155.2(B<0>) J5500.4(X<0>) R1038.1(A<0>) U1001.AU27(GPIO_56) U2560.E2(SCL) U6150.1(SCL) U6400.E5(I2C_SCL_SPI_MISO)
APPS10_I2C_SDA: C5529.2(B<0>) C6154.2(B<0>) J5500.6(X<0>) R1037.1(A<0>) U1001.AT28(GPIO_55) U2560.D3(SDA) U6150.2(SDA) U6400.E3(I2C_SDA_SPI_MOSI)
AUX_THERM_BIAS: R2403.1(A<0>) U2000.145(AUX_THERM_BIAS)
B1_B3_DRX_50R: R7600.1(A<0>) U7510.2(RX1)
B1_B3_DRX_FLT_IN_50R: FL7600.1(UNBAL_PORT_LCH_HCH) L7601.2(B<0>) R7600.2(B<0>)
B1_DRX_FLT_OUT_50R: C7602.2(B<0>) C7644.2(B<0>) L7603.1(A<0>)
B2_B25_B4_DRX_50R: C7610.1(A<0>) U7510.1(RX2)
B2_B25_B4_DRX_FLT_IN_50R: C7610.2(B<0>) FL7610.1(UNBAL_PORT_LCH_HCH) L7611.2(B<0>)
B2_B25_DRX_FLT_OUT_50R: C7615.2(B<0>) C7647.2(B<0>) L7616.1(A<0>)
B3_DRX_FLT_OUT_50R: C7645.1(A<0>) FL7600.9(UNBAL_PORT_LCH) L7648.2(B<0>)
B4_B66_DRX_FLT_OUT_50R: C7646.2(B<0>) L7612.2(B<0>) L7614.1(A<0>)
B5_B26_DRX_50R: C7700.2(B<0>) R7701.1(A<0>) U7500.7(TRX6)
B5_B26_DRX_FLT_IN_50R: FL7700.1(INPUT) R7701.2(B<0>)
B5_B26_DRX_FLT_OUT_50R: C7702.1(A<0>) FL7700.4(OUTPUT)
B7_B30_DRX_SWOUT_50R: C7802.1(A<0>) C7864.1(A<0>) FL7800.4(OUTPUT)
B7_DRX_50R: R7800.1(A<0>) U7520.9(RX3)
B8_DRX_50R: C7705.2(B<0>) R7706.1(A<0>) U7500.5(TRX8)
B8_DRX_FLT_IN_50R: FL7705.1(INPUT) R7706.2(B<0>)
B8_DRX_FLT_OUT_50R: C7707.1(A<0>) FL7705.4(OUTPUT)
B12_B17_B13_DRX_50R: R7715.1(A<0>) U7500.8(TRX5)
B12_B17_B13_DRX_FLT_IN_50R: FL7715.1(UNBAL_PORT1) L7716.2(B<0>) R7715.2(B<0>)
B12_B17_B13_DRX_FLT_OUT_50R: FL7715.4(UNBAL_PORT2) L7717.2(B<0>) R7718.1(A<0>)
B13_ANT_DUP_1_50R: C7264.2(B<0>) C7267.1(A<0>) L7263.2(B<0>) L7265.2(B<0>)
B13_ANT_DUP_50R: FL7260.6(ANT) L7263.1(A<0>)
B13_ANT_DUP_FLT_50R: C7266.1(A<0>) L7267.2(B<0>)
B13_RX_DUP_50R: C7269.1(A<0>) FL7260.1(RX) L7268.2(B<0>)
B13_TX_DUP_50R: C7261.1(A<0>) FL7260.3(TX) L7262.2(B<0>)
B20_DRX_50R: R7710.1(A<0>) U7500.6(TRX7)
B20_DRX_FLT_IN_50R: C7711.2(B<0>) FL7710.1(INPUT) R7710.2(B<0>)
B20_DRX_FLT_OUT_50R: C7712.1(A<0>) FL7710.4(OUTPUT)
B25_DUP_RX_50R: FL7300.1(RX) L7306.1(A<0>)
B28_ANT_DUP_50R: L7236.2(B<0>) L7237.2(B<0>) U7230.1(ANT)
B28_ANT_DUP_MAT_50R: C7238.2(B<0>) L7237.1(A<0>) L7239.2(B<0>)
B28_DPX_CTL: C7235.1(A<0>) U3100.57(W_GRFC_0) U7230.4(VC)
B28_DRX_50R: R7720.1(A<0>) U7500.11(TRX2)
B28_DRX_FLT_IN_50R: FL7720.1(INPUT) L7721.2(B<0>) R7720.2(B<0>)
B28_DRX_FLT_OUT_50R: FL7720.4(OUTPUT) L7722.2(B<0>) R7723.1(A<0>)
B28_RX_DUP_50R: C7241.1(A<0>) L7240.2(B<0>) U7230.3(RX)
B28_TX_DUP_50R: L7232.1(A<0>) L7233.2(B<0>) U7230.7(TX)
B34_DRX_50R: C7620.1(A<0>) R7620.2(B<0>) U7510.8(RX4)
B34_DRX_FLT_IN_50R: C7620.2(B<0>) FL7620.6(PORT2) L7621.2(B<0>)
B34B39_DRX_FLT_OUT_50R: C7648.1(A<0>) FL7620.1(PORT1) L7629.1(A<0>)
B39_DRX_50R: C7622.1(A<0>) U7510.9(RX3)
B39_DRX_FLT_IN_50R: C7622.2(B<0>) FL7620.9(PORT3) L7623.2(B<0>)
B40_DRX_50R: C7822.1(A<0>) U7520.1(RX2)
B41_DRX_50R: C7830.1(A<0>) U7520.2(RX1)
B_PLUS: C2253.2(B<0>) C2254.2(B<0>) C2255.2(B<0>) C2256.2(B<0>) C2257.2(B<0>) C2258.2(B<0>) C2262.2(B<0>) C2263.2(B<0>) C2270.2(B<0>) C2275.2(B<0>) C2276.2(B<0>) C2277.2(B<0>) C2282.2(B<0>) C2283.2(B<0>) C2284.2(B<0>) C2285.2(B<0>) C2286.2(B<0>) C2287.2(B<0>) C2288.2(B<0>) C2355.2(B<0>) C2356.2(B<0>) C2357.2(B<0>) C2358.2(B<0>) C2359.2(B<0>) C2360.1(A<0>) C2361.1(A<0>) C2362.1(A<0>) C2363.1(A<0>) C2364.1(A<0>) C2404.2(B<0>) C2405.2(B<0>) C2416.2(B<0>) C2417.2(B<0>) C2455.2(B<0>) C2501.2(B<0>) C2502.2(B<0>) C2504.2(B<0>) C2507.2(B<0>) C2510.2(B<0>) C2560.2(B<0>) C2561.2(B<0>) C2562.2(B<0>) C2570.2(B<0>) C2571.2(B<0>) C2572.2(B<0>) C4100.2(B<0>) C4101.2(B<0>) C4103.2(B<0>) C4121.2(B<0>) C4601.2(B<0>) C4602.2(B<0>) C4603.2(B<0>) C4610.2(B<0>) C5524.2(B<0>) C6291.2(B<0>) C6400.2(B<0>) C6401.2(B<0>) C6402.2(B<0>) C6410.2(B<0>) C7101.2(B<0>) C7102.2(B<0>) C7150.2(B<0>) C7152.2(B<0>) C7161.2(B<0>) C7162.2(B<0>) C8203.2(B<0>) C8205.2(B<0>) J5502.L1(X<0>) J5502.L2(X<0>) J5502.L3(X<0>) J5502.L4(X<0>) L2270.1(A<0>) L2400.2(B<0>) L2501.2(B<0>) L2502.2(B<0>) L4120.1(A<0>) L4600.2(B<0>) L6400.1(A<0>) R2453.2(B<0>) R4120.2(B<0>) U2000.3(VPH_PWR_1) U2000.6(VDD_HAP) U2000.15(VPH_PWR_2) U2000.20(VDD_S3_1) U2000.25(VPH_PWR_3) U2000.33(VDD_S2_1) U2000.37(VPH_PWR_4) U2000.42(VDD_S3_2) U2000.47(VPH_PWR_5) U2000.55(VDD_S2_2) U2000.65(VDD_S1_1) U2000.66(VDD_S1_2) U2000.120(VDD_S6_1) U2000.130(VPH_PWR1) U2000.131(VDD_S5_1) U2000.141(VDD_S5_2) U2000.175(VDD_S4_1) U2000.186(VDD_S4_2) U2000.208(VDD_S4_3) U2210.A3(VIN) U2400.2(VDD_S2_1) U2400.11(VDD_DISP_M_1) U2400.17(VDD_BOB_1) U2400.21(VDD_DISP_M_2) U2400.24(VDD_S2_2) U2400.39(VDD_BOB_2) U2400.58(VPH_PWR_1) U2400.65(VDD_DISP_P) U2400.67(VDD_S3_1) U2400.68(VDD_S3_2) U2400.74(VPH_PWR_2) U2400.100(VDD_S4_1) U2400.101(VDD_S4_2) U2400.108(VDD_OLEDB) U2400.111(VDD_S4_3) U2400.152(VREG_BOOST) U2400.156(VDD_S1_1) U2400.162(BOOST_SNS) U2400.174(VSW_BOOST) U2400.176(VDD_S5_1) U2400.178(VDD_S1_2) U2400.182(VDD_SPKR_PA_1) U2400.186(VDD_S5_2) U2400.187(VDD_S5_3) U2400.192(VDD_SPKR_PA_2) U2560.A1(VIN1) U2560.B1(VIN2) U2560.C1(VIN3) U2570.A1(VIN1) U2570.B1(VIN2) U2570.C1(VIN3) U4100.A8(VBAT2) U4100.E1(VBAT1) U4120.A3(VIN) U4600.G2(VBAT) U6290.A2(VIN) U6400.A5(VP) U7100.14(VBATT) U7150.25(HB_VBATT) U7150.26(MB_VBATT) U8200.19(VDD_LDO) U8200.20(VIN_BOB) U8200.24(VDD_BAT) U8200.34(VBAT_SW)
BA_N: TP_BA_N.1(X) U2000.157(BA_N) U2400.6(BA_N)
BATT_NEG_CONN: D518.1(NEG) E518.1(POS) E521.1(POS) J510.5(X<0>) J510.6(X<0>) R510.1(A<0>) TP_BASE_BAT_NEG.1(X)
BATT_PLUS: C510.2(B<0>) C511.2(B<0>) C519.2(B<0>) C2409.2(B<0>) D510.1(NEG) E510.1(POS) J510.1(X<0>) J510.2(X<0>) Q5500.A2(S5) Q5500.A3(S4) Q5500.B1(S1) Q5500.B2(S2) Q5500.B3(S3) R5500.2(B<0>) R5501.1(A<0>) TP_BASE_BAT_POS.1(X) U519.B1(VBATT) U2000.4(VBATT_PWR_1) U2000.16(VBATT_PWR_2) U2000.26(VBATT_PWR_3) U2000.38(VBATT_PWR_4) U2000.48(VBATT_PWR_5) U2000.122(IBATT_SNS_P) U2000.133(IBATT_SNS_M) VR510.1(NEG)
BATT_PLUS_FLIP: C5509.2(B<0>) J5500.R1(X<0>) J5500.R2(X<0>) J5500.R3(X<0>) J5500.R4(X<0>) Q5500.C1(D1) Q5500.C2(D2) Q5500.C3(D3) R5501.2(B<0>)
BATT_SENSE_M: E521.2(NEG) U2000.81(VBATT_SNS_M)
BATT_SENSE_P: E510.2(NEG) U2000.102(VBATT_SNS_P)
BATT_THERM: C516.2(B<0>) R2400.2(B<0>) RT516.1(POS) U2000.166(BATT_THERM)
BATT_THERM_BIAS: R2400.1(A<0>) U2000.156(BATT_THERM_BIAS)
BOOST_EN: R4120.1(A<0>) U4100.G1(EN_5V0) U4120.B3(EN)
BOOT_CONFIG_3: TP_BOOT_CONFIG3.1(X) U1001.AA37(GPIO_133)
BT_CTS_AP_RTS: U1001.M2(GPIO_46) U4000.104(CTS)
BT_FM_SLIMBUS_CLK: U1001.AN39(LPI_GPIO_31) U4000.74(SB_CLK)
BT_FM_SLIMBUS_DATA: U1001.AP38(LPI_GPIO_30) U4000.102(SB_DATA)
BT_RFIO_CH2: R4006.2(B<0>) U4000.2(BT_RFIO_CH2)
BT_RTS_AP_CTS: U1001.M4(GPIO_45) U4000.111(RTS)
BT_RX_AP_TX: U1001.N3(GPIO_47) U4000.96(RXD)
BT_TX_AP_RX: U1001.P4(GPIO_48) U4000.103(TXD)
BUA: U1001.AV32(GPIO_113) U2000.19(GPIO_07)
CAM_F_EN: C5551.1(A<0>) J5500.57(X<0>) U2400.146(GPIO_03)
CAM_F_MCLK: E5620.1(A) U1001.AU5(GPIO_14)
CAM_F_MCLK_FL: C5620.2(B<0>) E5620.2(B) J5500.56(X<0>)
CAM_F_RST_N: J5500.14(X<0>) U1001.AT6(GPIO_9)
CAM_R_EN: C5549.1(A<0>) J5500.53(X<0>) U2400.134(GPIO_04)
CAM_R_I2C_SCL: C5505.2(B<0>) J5500.18(X<0>) R1040.1(A<0>) U1001.AT4(GPIO_18)
CAM_R_I2C_SDA: C5506.2(B<0>) J5500.20(X<0>) R1039.1(A<0>) U1001.AR1(GPIO_17)
CAM_R_MCLK: E5680.1(A) U1001.AT2(GPIO_15)
CAM_R_MCLK_FL: C5680.2(B<0>) E5680.2(B) J5500.52(X<0>)
CAM_R_RST_N: J5500.16(X<0>) U1001.Y38(GPIO_7)
CAM_VIO_EN: C5550.1(A<0>) J5500.55(X<0>) U2400.145(GPIO_02)
CC_ALERT_FLIP: J5500.8(X<0>) U1001.AY34(GPIO_49)
CC_ALERT_M: U519.B2(ALRT) U1001.L43(GPIO_123)
CC_CSN_DM: E519.2(NEG) U519.A3(CSN)
CC_CSP_DP: C517.1(A<0>) C518.1(A<0>) C519.1(A<0>) E518.2(NEG) RT517.2(NEG) U519.C3(CSP)
CDC_AIF1_BCLK: TP_SB_SCK.1(X) U6250.N15(AIF1BCLK/GPIO16) U6400.B5(ASP_BCLK)
CDC_AIF1_LRCLK: TP_SB_WS.1(X) U6250.J13(AIF1LRCLK/GPIO18) U6400.C5(ASP_FSYNC)
CDC_AIF1_RXDAT: TP_SB_RX.1(X) U6250.L13(AIF1RXDAT/GPIO17) U6400.B4(ASP_DOUT)
CDC_AIF1_TXDAT: TP_SB_TX.1(X) U6250.M14(AIF1TXDAT/GPIO15) U6400.C4(ASP_DIN)
CDC_EAR_M: C5532.2(B<0>) J5502.8(X<0>) U6250.B12(HPOUT2R)
CDC_EAR_P: C5531.2(B<0>) J5502.6(X<0>) U6250.A13(HPOUT2L)
CDC_GNDA: C6406.2(B<0>) C6407.1(A<0>) E6400_GNDA.1(POS) U6400.F2(GNDA)
CDC_GNDP1: C6403.1(A<0>) C6404.1(A<0>) C6405.1(A<0>) C6408.1(A<0>) E6400_GNDP1.1(POS) U6400.A3(GNDB1) U6400.A4(GNDB2) U6400.B3(GNDB3) U6400.C3(GNDP1) U6400.D3(GNDP2)
CDC_INT1_N: U1001.AU29(GPIO_54) U6250.H12(IRQ_N)
CDC_INT2_N: TP_CDC_DEBUG.1(X) U1001.AT14(GPIO_97) U6250.M16(GPIO1)
CDC_LP_GATE: TP_PDMDATA.1(X) U6250.AB10(SPKDAT/GPIO38) U6400.F3(SYNC_GPIO1)
CDC_MCLK2: TP_CDC_32KHZ.1(X) U2000.51(GPIO_02) U6250.AB14(MCLK2)
CDC_RST_N: TP_CDC_RST.1(X) U1001.W43(GPIO_78) U6250.G11(RESET_N)
CDC_SLIMBUS_CLK: TP_SLIMCLK.1(X) U1001.AP42(LPI_GPIO_18) U6250.V14(SLIMCLK)
CDC_SLIMBUS_DATA: TP_SLIMDAT.1(X) U1001.AN41(LPI_GPIO_20) U6250.W15(SLIMDAT1)
CDC_SPI_CLK: U1001.AE37(GPIO_67) U6250.P14(CIF1SCLK)
CDC_SPI_CS_N: U1001.AD38(GPIO_68) U6250.N13(CIF1SS_N)
CDC_SPI_MISO: U1001.AF38(GPIO_65) U6250.R15(CIF1MISO)
CDC_SPI_MOSI: U1001.AE39(GPIO_66) U6250.R13(CIF1MOSI)
CDC_SSC_WAKE: U1001.H40(GPIO_121) U6250.R7(GPIO2)
CDC_VSNSM: E4671.1(POS) U6400.E1(VSNS_N)
CDC_VSNSP: E4670.1(POS) U6400.F1(VSNS_P)
CP1C1A: C6282.1(A<0>) U6250.E7(CP1C1A)
CP1C1B: C6282.2(B<0>) U6250.D8(CP1C1B)
CP1C2A: C6285.1(A<0>) U6250.C7(CP1C2A)
CP1C2B: C6285.2(B<0>) U6250.B10(CP1C2B)
CP1VOUT1N: C6283.1(A<0>) U6250.E9(CP1VOUT1N)
CP1VOUT1P: C6284.1(A<0>) U6250.F10(CP1VOUT1P)
CP1VOUT2N: C6287.1(A<0>) U6250.A9(CP1VOUT2N)
CP1VOUT2P: C6288.1(A<0>) U6250.C9(CP1VOUT2P)
CP2CA: C6286.1(A<0>) U6250.J9(CP2CA)
CP2VOUT: C6292.1(A<0>) U6250.J7(CP2VOUT)
CXM_CMD<0>: U1001.P6(WCSS_CXM_DATA) U4000.75(COEX_DATA)
CXM_CMD<1>: U1001.R5(WCSS_CXM_CLK) U4000.88(COEX_CLK)
D_VSW_S1: L2300.1(A<0>) U2400.144(VSW_S1_1) U2400.166(VSW_S1_2) U2400.188(VSW_S1_3)
D_VSW_S2: L2301.1(A<0>) U2400.1(VSW_S2_1) U2400.12(VSW_S2_2) U2400.34(VSW_S2_3)
D_VSW_S3: L2302.1(A<0>) U2400.56(VSW_S3_1) U2400.57(VSW_S3_2) U2400.69(VSW_S3_3)
D_VSW_S4: L2303.1(A<0>) U2400.89(VSW_S4_1) U2400.90(VSW_S4_2) U2400.91(VSW_S4_3)
D_VSW_S5: L2304.1(A<0>) U2400.164(VSW_S5_1) U2400.165(VSW_S5_2) U2400.175(VSW_S5_3)
DDR_RESET_N: U1001.C41(DDR_RESET_N) U1600.AA16(RST2_N)
DDR_VDDQ: C1116.1(IN) C1116.3(OUT) C1117.1(IN) C1117.3(OUT) C1119.2(B<0>) C1120.2(B<0>) C1121.2(B<0>) C1612.2(B<0>) C1613.2(B<0>) C1614.2(B<0>) C1616.2(B<0>) C1624.2(B<0>) E1117.1(POS) L2304.2(B<0>) R1011.2(B<0>) R1603.1(A<0>) R1605.1(A<0>) U1001.H18(VDD_EBI_CC1) U1001.H20(VDD_EBI_IO1) U1001.H22(VDD_EBI_CC2) U1001.J19(VDD_EBI_IO2) U1001.J21(VDD_EBI_IO3) U1001.K18(VDD_EBI_IO4) U1001.K20(VDD_EBI_IO5) U1001.K22(VDD_EBI_IO6) U1600.A6(VDDQ1) U1600.A7(VDDQ2) U1600.A13(VDDQ3) U1600.A14(VDDQ4) U1600.AC5(VDDQ16) U1600.AD6(VDDQ17) U1600.AD7(VDDQ18) U1600.AD13(VDDQ19) U1600.AD14(VDDQ20) U1600.B5(VDDQ5) U1600.H5(VDDQ6) U1600.H9(VDDQ7) U1600.J4(VDDQ8) U1600.J5(VDDQ9) U1600.J8(VDDQ10) U1600.T4(VDDQ11) U1600.T5(VDDQ12) U1600.T8(VDDQ13) U1600.U5(VDDQ14) U1600.U9(VDDQ15)
DISP_PWR_EN: TP_DISP_PWR_EN.1(X) U1001.AV28(GPIO_106) U5300.B2(ON)
DISP_SUB_AVDD_EN: C5513.2(B<0>) J5501.22(X<0>) U1001.AW27(GPIO_105)
DISP_SUB_DSI1<0>: J5501.11(X<0>) U1001.R43(MIPI_DSI1_CLK_N)
DISP_SUB_DSI1<1>: J5501.9(X<0>) U1001.T42(MIPI_DSI1_CLK_P)
DISP_SUB_DSI1<2>: J5501.5(X<0>) U1001.V42(MIPI_DSI1_LN0_N)
DISP_SUB_DSI1<3>: J5501.3(X<0>) U1001.W41(MIPI_DSI1_LN0_P)
DISP_SUB_DSI1<4>: J5501.17(X<0>) U1001.U41(MIPI_DSI1_LN1_N)
DISP_SUB_DSI1<5>: J5501.15(X<0>) U1001.V40(MIPI_DSI1_LN1_P)
DISP_SUB_PWR_EN: C5512.2(B<0>) J5501.24(X<0>) U1001.AP6(GPIO_100)
DISP_SUB_RST_N: C5507.2(B<0>) J5501.26(X<0>) U1001.AR7(GPIO_8)
DISP_SUB_TE: C5530.2(B<0>) J5501.28(X<0>) U1001.U37(GPIO_11)
DISP_TE_FL: C5313.2(B<0>) E5302.2(B) J5300.11(X<0>)
DISP_V1_EN: D5301.1(NEG) D5302.1(NEG) TP_DISP_V1_EN.1(X) U1001.AY28(GPIO_107) U5301.B2(ON)
DISP_VCI_FL: C5322.2(B<0>) C5323.2(B<0>) J5300.1(X<0>) U5301.A1(VOUT)
DISP_VIO_FL: C5316.2(B<0>) C5317.2(B<0>) J5300.3(X<0>) U5300.A1(VOUT)
DRX_ASM_HB_50R: C7526.2(B<0>) L7627.2(B<0>) U7520.11(ANT)
DRX_ASM_MB_50R: C7517.1(A<0>) U7510.11(ANT)
DRX_ASM_ULB_LB_50R: C7505.2(B<0>) L7505.2(B<0>) U7500.9(ANT)
DRX_B7_FLT_IN_50R: FL7800.1(INPUT) L7801.2(B<0>) R7800.2(B<0>)
DRX_B40_FLT_OUT_50R: C7896.1(A<0>) FL7820.4(UNBAL_PORT2) L7820.2(B<0>)
DRX_B41FB_B38_FLT_IN_50R: C7830.2(B<0>) FL7830.1(UNBAL_PORT1) L7831.2(B<0>)
DRX_B41FB_B38_FLT_OUT_50R: C7895.1(A<0>) FL7830.4(UNBAL_PORT2) L7833.2(B<0>)
DRX_DIP_MB_MAT_50R: C7515.1(A<0>) C7517.2(B<0>) L7516.2(B<0>)
EBI0_CA<0>: U1001.D14(EBI0_CA_0) U1600.G14(CA0_A)
EBI0_CA<1>: U1001.F12(EBI0_CA_1) U1600.F13(CA1_A)
EBI0_CA<2>: U1001.E7(EBI0_CA_2) U1600.C13(CA2_A)
EBI0_CA<3>: U1001.D10(EBI0_CA_3) U1600.D13(CA3_A)
EBI0_CA<4>: U1001.E11(EBI0_CA_4) U1600.E13(CA4_A)
EBI0_CA<5>: U1001.D6(EBI0_CA_5) U1600.C15(CA5_A)
EBI0_CKE_0: U1001.F8(EBI0_CKE_0) U1600.E16(CKE0_A)
EBI0_CKE_1: U1001.E13(EBI0_CKE_1) U1600.F16(CKE1_A)
EBI0_CLK_M: U1001.E15(EBI0_CK_N) U1600.G16(CLK_C_A)
EBI0_CLK_P: U1001.F16(EBI0_CK_P) U1600.H16(CLK_T_A)
EBI0_CS_0: U1001.F10(EBI0_CS_0) U1600.E15(CS0_A)
EBI0_CS_1: U1001.D12(EBI0_CS_1) U1600.F15(CS1_A)
EBI0_DM<0>: U1001.B8(EBI0_DM_0) U1600.D5(DMI0_A)
EBI0_DM<1>: U1001.B14(EBI0_DM_1) U1600.H3(DMI1_A)
EBI0_DQ<0>: U1001.B2(EBI0_DQ_0) U1600.A3(DQ0_A)
EBI0_DQ<1>: U1001.A3(EBI0_DQ_1) U1600.B3(DQ1_A)
EBI0_DQ<2>: U1001.A5(EBI0_DQ_2) U1600.C3(DQ2_A)
EBI0_DQ<3>: U1001.A7(EBI0_DQ_3) U1600.D3(DQ3_A)
EBI0_DQ<4>: U1001.B4(EBI0_DQ_4) U1600.B7(DQ4_A)
EBI0_DQ<5>: U1001.B6(EBI0_DQ_5) U1600.C6(DQ5_A)
EBI0_DQ<6>: U1001.A9(EBI0_DQ_6) U1600.D7(DQ6_A)
EBI0_DQ<7>: U1001.B10(EBI0_DQ_7) U1600.C8(DQ7_A)
EBI0_DQ<8>: U1001.A17(EBI0_DQ_8) U1600.K5(DQ8_A)
EBI0_DQ<9>: U1001.A19(EBI0_DQ_9) U1600.K6(DQ9_A)
EBI0_DQ<10>: U1001.B18(EBI0_DQ_10) U1600.K3(DQ10_A)
EBI0_DQ<11>: U1001.B16(EBI0_DQ_11) U1600.J3(DQ11_A)
EBI0_DQ<12>: U1001.A15(EBI0_DQ_12) U1600.J7(DQ12_A)
EBI0_DQ<13>: U1001.B12(EBI0_DQ_13) U1600.G3(DQ13_A)
EBI0_DQ<14>: U1001.A13(EBI0_DQ_14) U1600.H6(DQ14_A)
EBI0_DQ<15>: U1001.A11(EBI0_DQ_15) U1600.H8(DQ15_A)
EBI0_DQS_0_M: U1001.E9(EBI0_DQS_0_N) U1600.D9(DQS0_C_A)
EBI0_DQS_0_P: U1001.D8(EBI0_DQS_0_P) U1600.C9(DQS0_T_A)
EBI0_DQS_1_M: U1001.D16(EBI0_DQS_1_N) U1600.J9(DQS1_C_A)
EBI0_DQS_1_P: U1001.E17(EBI0_DQS_1_P) U1600.K9(DQS1_T_A)
EBI1_CA<0>: U1001.D30(EBI1_CA_0) U1600.V14(CA0_B)
EBI1_CA<1>: U1001.F32(EBI1_CA_1) U1600.W13(CA1_B)
EBI1_CA<2>: U1001.E37(EBI1_CA_2) U1600.AB13(CA2_B)
EBI1_CA<3>: U1001.D34(EBI1_CA_3) U1600.AA13(CA3_B)
EBI1_CA<4>: U1001.E33(EBI1_CA_4) U1600.Y13(CA4_B)
EBI1_CA<5>: U1001.D38(EBI1_CA_5) U1600.AB15(CA5_B)
EBI1_CKE_0: U1001.F36(EBI1_CKE_0) U1600.Y16(CKE0_B)
EBI1_CKE_1: U1001.E31(EBI1_CKE_1) U1600.W16(CKE1_B)
EBI1_CLK_M: U1001.E29(EBI1_CK_N) U1600.V16(CLK_C_B)
EBI1_CLK_P: U1001.F28(EBI1_CK_P) U1600.U16(CLK_T_B)
EBI1_CS_0: U1001.F34(EBI1_CS_0) U1600.Y15(CS0_B)
EBI1_CS_1: U1001.D32(EBI1_CS_1) U1600.W15(CS1_B)
EBI1_DM<0>: U1001.A35(EBI1_DM_0) U1600.AA5(DMI0_B)
EBI1_DM<1>: U1001.A29(EBI1_DM_1) U1600.U3(DMI1_B)
EBI1_DQ<0>: U1001.A41(EBI1_DQ_0) U1600.AD3(DQ0_B)
EBI1_DQ<1>: U1001.B40(EBI1_DQ_1) U1600.AC3(DQ1_B)
EBI1_DQ<2>: U1001.B38(EBI1_DQ_2) U1600.AB3(DQ2_B)
EBI1_DQ<3>: U1001.B36(EBI1_DQ_3) U1600.AA3(DQ3_B)
EBI1_DQ<4>: U1001.A39(EBI1_DQ_4) U1600.AC7(DQ4_B)
EBI1_DQ<5>: U1001.A37(EBI1_DQ_5) U1600.AB6(DQ5_B)
EBI1_DQ<6>: U1001.B34(EBI1_DQ_6) U1600.AA7(DQ6_B)
EBI1_DQ<7>: U1001.A33(EBI1_DQ_7) U1600.AB8(DQ7_B)
EBI1_DQ<8>: U1001.B26(EBI1_DQ_8) U1600.R5(DQ8_B)
EBI1_DQ<9>: U1001.B24(EBI1_DQ_9) U1600.R6(DQ9_B)
EBI1_DQ<10>: U1001.A25(EBI1_DQ_10) U1600.R3(DQ10_B)
EBI1_DQ<11>: U1001.A27(EBI1_DQ_11) U1600.T3(DQ11_B)
EBI1_DQ<12>: U1001.B28(EBI1_DQ_12) U1600.T7(DQ12_B)
EBI1_DQ<13>: U1001.A31(EBI1_DQ_13) U1600.V3(DQ13_B)
EBI1_DQ<14>: U1001.B30(EBI1_DQ_14) U1600.U6(DQ14_B)
EBI1_DQ<15>: U1001.B32(EBI1_DQ_15) U1600.U8(DQ15_B)
EBI1_DQS_0_M: U1001.E35(EBI1_DQS_0_N) U1600.AA9(DQS0_C_B)
EBI1_DQS_0_P: U1001.D36(EBI1_DQS_0_P) U1600.AB9(DQS0_T_B)
EBI1_DQS_1_M: U1001.D28(EBI1_DQS_1_N) U1600.T9(DQS1_C_B)
EBI1_DQS_1_P: U1001.E27(EBI1_DQS_1_P) U1600.R9(DQS1_T_B)
EBI_CAL_REXT: R1011.1(A<0>) U1001.C1(EBI_CAL)
ELON1_AVDD: C5369.2(B<0>) D5302.2(POS) J5300.15(X<0>) R5321.2(B<0>) U2400.86(OLEDB_EN)
ELON2: C5370.2(B<0>) D5301.2(POS) J5300.13(X<0>) R5322.2(B<0>) U2400.10(DISP_SCTRL)
ESIM_CLK: R4216.1(A<0>) U4200.5(CLK) U4250.3(MHLPOS)
ESIM_DATA: R4215.1(A<0>) U4200.4(IO0) U4250.4(MHLNEG)
ESIM_POWER: C4214.2(B<0>) C4215.2(B<0>) R4211.1(A<0>) R4218.1(A<0>) U4200.8(VCC)
ESIM_RST: D4250.2(POS) D4251.2(POS) R4217.1(A<0>) R4251.1(A<0>) U4200.6(RST)
ESIM_SWP: R4214.1(A<0>) U4200.2(SWIO)
ETDAC_CH0_M: U3100.47(ETDAC_CH0_M) U8200.11(DAC_N)
ETDAC_CH0_P: U3100.39(ETDAC_CH0_P) U8200.12(DAC_P)
EUD: R2455.1(A<0>) U2000.52(GPIO_11) U2400.167(GPIO_08)
FAULT_N: TP_FAULT_N.1(X) U2000.217(FAULT_N) U2400.80(FAULT_N)
FLAG_N: TP_OVP_FLAG_N.1(X) U2000.63(GPIO_03) U2401.C4(FLAG_N)
FLASH_INHIBIT: J5500.10(X<0>) U1001.AW11(GPIO_135) U2400.83(GPIO_06)
FLASH_RST_N: J5500.12(X<0>) U1001.AV4(GPIO_25)
FLIP_BATT_EN_N: J5500.51(X<0>) Q2031.3(D)
FLIP_BATTPLUS_EN_N: Q2032.3(D) Q5500.A1(G) R5500.1(A<0>)
FLIP_COM_IN: C6181.2(B<0>) D355.1(A2) J350.3(X<0>) U6180.1(LCOM)
FLIP_DET_EN: U1001.AJ39(LPI_GPIO_28) U6182.D1(A2)
FLIP_DET_EN_F: R6182.2(B<0>) U6182.A1(B2)
FLIP_DET_OUT: U1001.AK38(LPI_GPIO_27) U6182.D2(A1)
FLIP_DET_OUT_F: U6180.5(OUT) U6182.A2(B1)
FLIP_REF_IN: D354.1(A2) J350.7(X<0>) U6180.3(LREF)
FLIP_SNS_IN: D356.1(A2) J350.1(X<0>) U6180.2(LSENSE)
FLLVDD: C6261.2(B<0>) R6268.2(B<0>) U6250.K16(FLLVDD)
FOCUS_GPIO1: C5541.1(A<0>) J5500.40(X<0>) R5802.1(A<0>) U1001.AY4(GPIO_22)
FOCUS_GPIO2: C5542.1(A<0>) J5500.42(X<0>) R5801.1(A<0>) U1001.AW1(GPIO_21)
FORCEFLASH: JTAG.12(X<0>) R1006.2(B<0>) U1001.AC43(GPIO_57)
FP_DRDY_N: R1524.1(A<0>) U1001.AW3(GPIO_26)
FP_PWR_1P8_R: C1516.2(B<0>) C6629.2(B<0>) C6630.2(B<0>) J6601.11(X<0>) R1526.2(B<0>) VR1511.1(K1)
FP_RST_N: R1527.1(A<0>) U1001.AY8(GPIO_91)
FP_SPI_CLK: R1528.1(A<0>) U1001.H38(GPIO_83)
FP_SPI_CLK_R: C1514.2(B<0>) J6601.9(X<0>) R1528.2(B<0>) VR1509.2(A1)
FP_SPI_CS_N: R1529.1(A<0>) U1001.J37(GPIO_84)
FP_SPI_CS_N_R: C1513.2(B<0>) J6601.4(X<0>) R1529.2(B<0>) VR1508.2(A1)
FP_SPI_IRQ: C1532.2(B<0>) J6601.5(X<0>) R1524.2(B<0>) VR1513.1(K1)
FP_SPI_MISO: R1531.1(A<0>) U1001.G37(GPIO_81)
FP_SPI_MISO_R: C1511.2(B<0>) J6601.6(X<0>) R1531.2(B<0>) VR1506.2(A1)
FP_SPI_MOSI: R1530.1(A<0>) U1001.G39(GPIO_82)
FP_SPI_MOSI_R: C1512.2(B<0>) J6601.7(X<0>) R1530.2(B<0>) VR1507.2(A1)
FP_SPI_RST: C1515.2(B<0>) J6601.8(X<0>) R1527.2(B<0>) VR1510.2(A1)
G_AVDD_BYP: C2002.1(A<0>) U2000.173(AVDD_BYP)
G_VREG_XO: C2319.1(A<0>) U2000.211(VREG_XO)
G_VSW_S1: L2200.1(A<0>) U2000.75(VSW_S1_1) U2000.76(VSW_S1_2) U2000.77(VSW_S1_3)
G_VSW_S2: L2201.1(A<0>) U2000.11(VSW_S2_1) U2000.22(VSW_S2_2) U2000.44(VSW_S2_3) U2000.54(VSW_S2_4)
G_VSW_S3: L2202.1(A<0>) U2000.9(VSW_S3_1) U2000.31(VSW_S3_2) U2000.53(VSW_S3_3)
G_VSW_S4: L2203.1(A<0>) U2000.185(VSW_S4_1) U2000.197(VSW_S4_2) U2000.219(VSW_S4_3)
G_VSW_S5: L2204.1(A<0>) U2000.142(VSW_S5_1) U2000.153(VSW_S5_2)
G_VSW_S6: L2205.1(A<0>) U2000.98(VSW_S6_1) U2000.109(VSW_S6_2)
GPIO19: R1033.1(A<0>) U1001.AP2(GPIO_19)
GPIO_4: Q6268.2(G1) U6250.T4(GPIO4)
GPIO_5: Q6268.5(G2) U6250.V2(GPIO5)
GPIO_06: R2017.1(A<0>) U2000.159(GPIO_06)
GPIO_12: R2019.1(A<0>) U2000.62(GPIO_12)
GPS_ELNA_EN: C8516.2(B<0>) R8510.1(A<0>) U3100.150(GNSS_ELNA_CTRL)
GPS_LNA_IN_50R: L8502.2(B<0>) U8501.5(AI)
GPS_LNA_OUT_1_50R: C8507.2(B<0>) FL8502.1(UNBAL_PORT1) L8504.2(B<0>)
GPS_LNA_OUT_50R: C8507.1(A<0>) L8503.2(B<0>) U8501.3(AO)
GPS_NOTCH_50R: C8501.2(B<0>) L8501.1(A<0>)
GPS_SAW_IN_50R: C8503.2(B<0>) L8502.1(A<0>)
GPSLNA_VCC: C8500.2(B<0>) C8505.2(B<0>) R8500.2(B<0>) U8501.2(VCC)
GYRO_INT: U1001.H42(GPIO_118) U6110.9(INT2) U6115.9(INT2)
HAP_INT_N: R4614.1(A<0>) U1001.AW33(GPIO_52) U4600.A4(INTN)
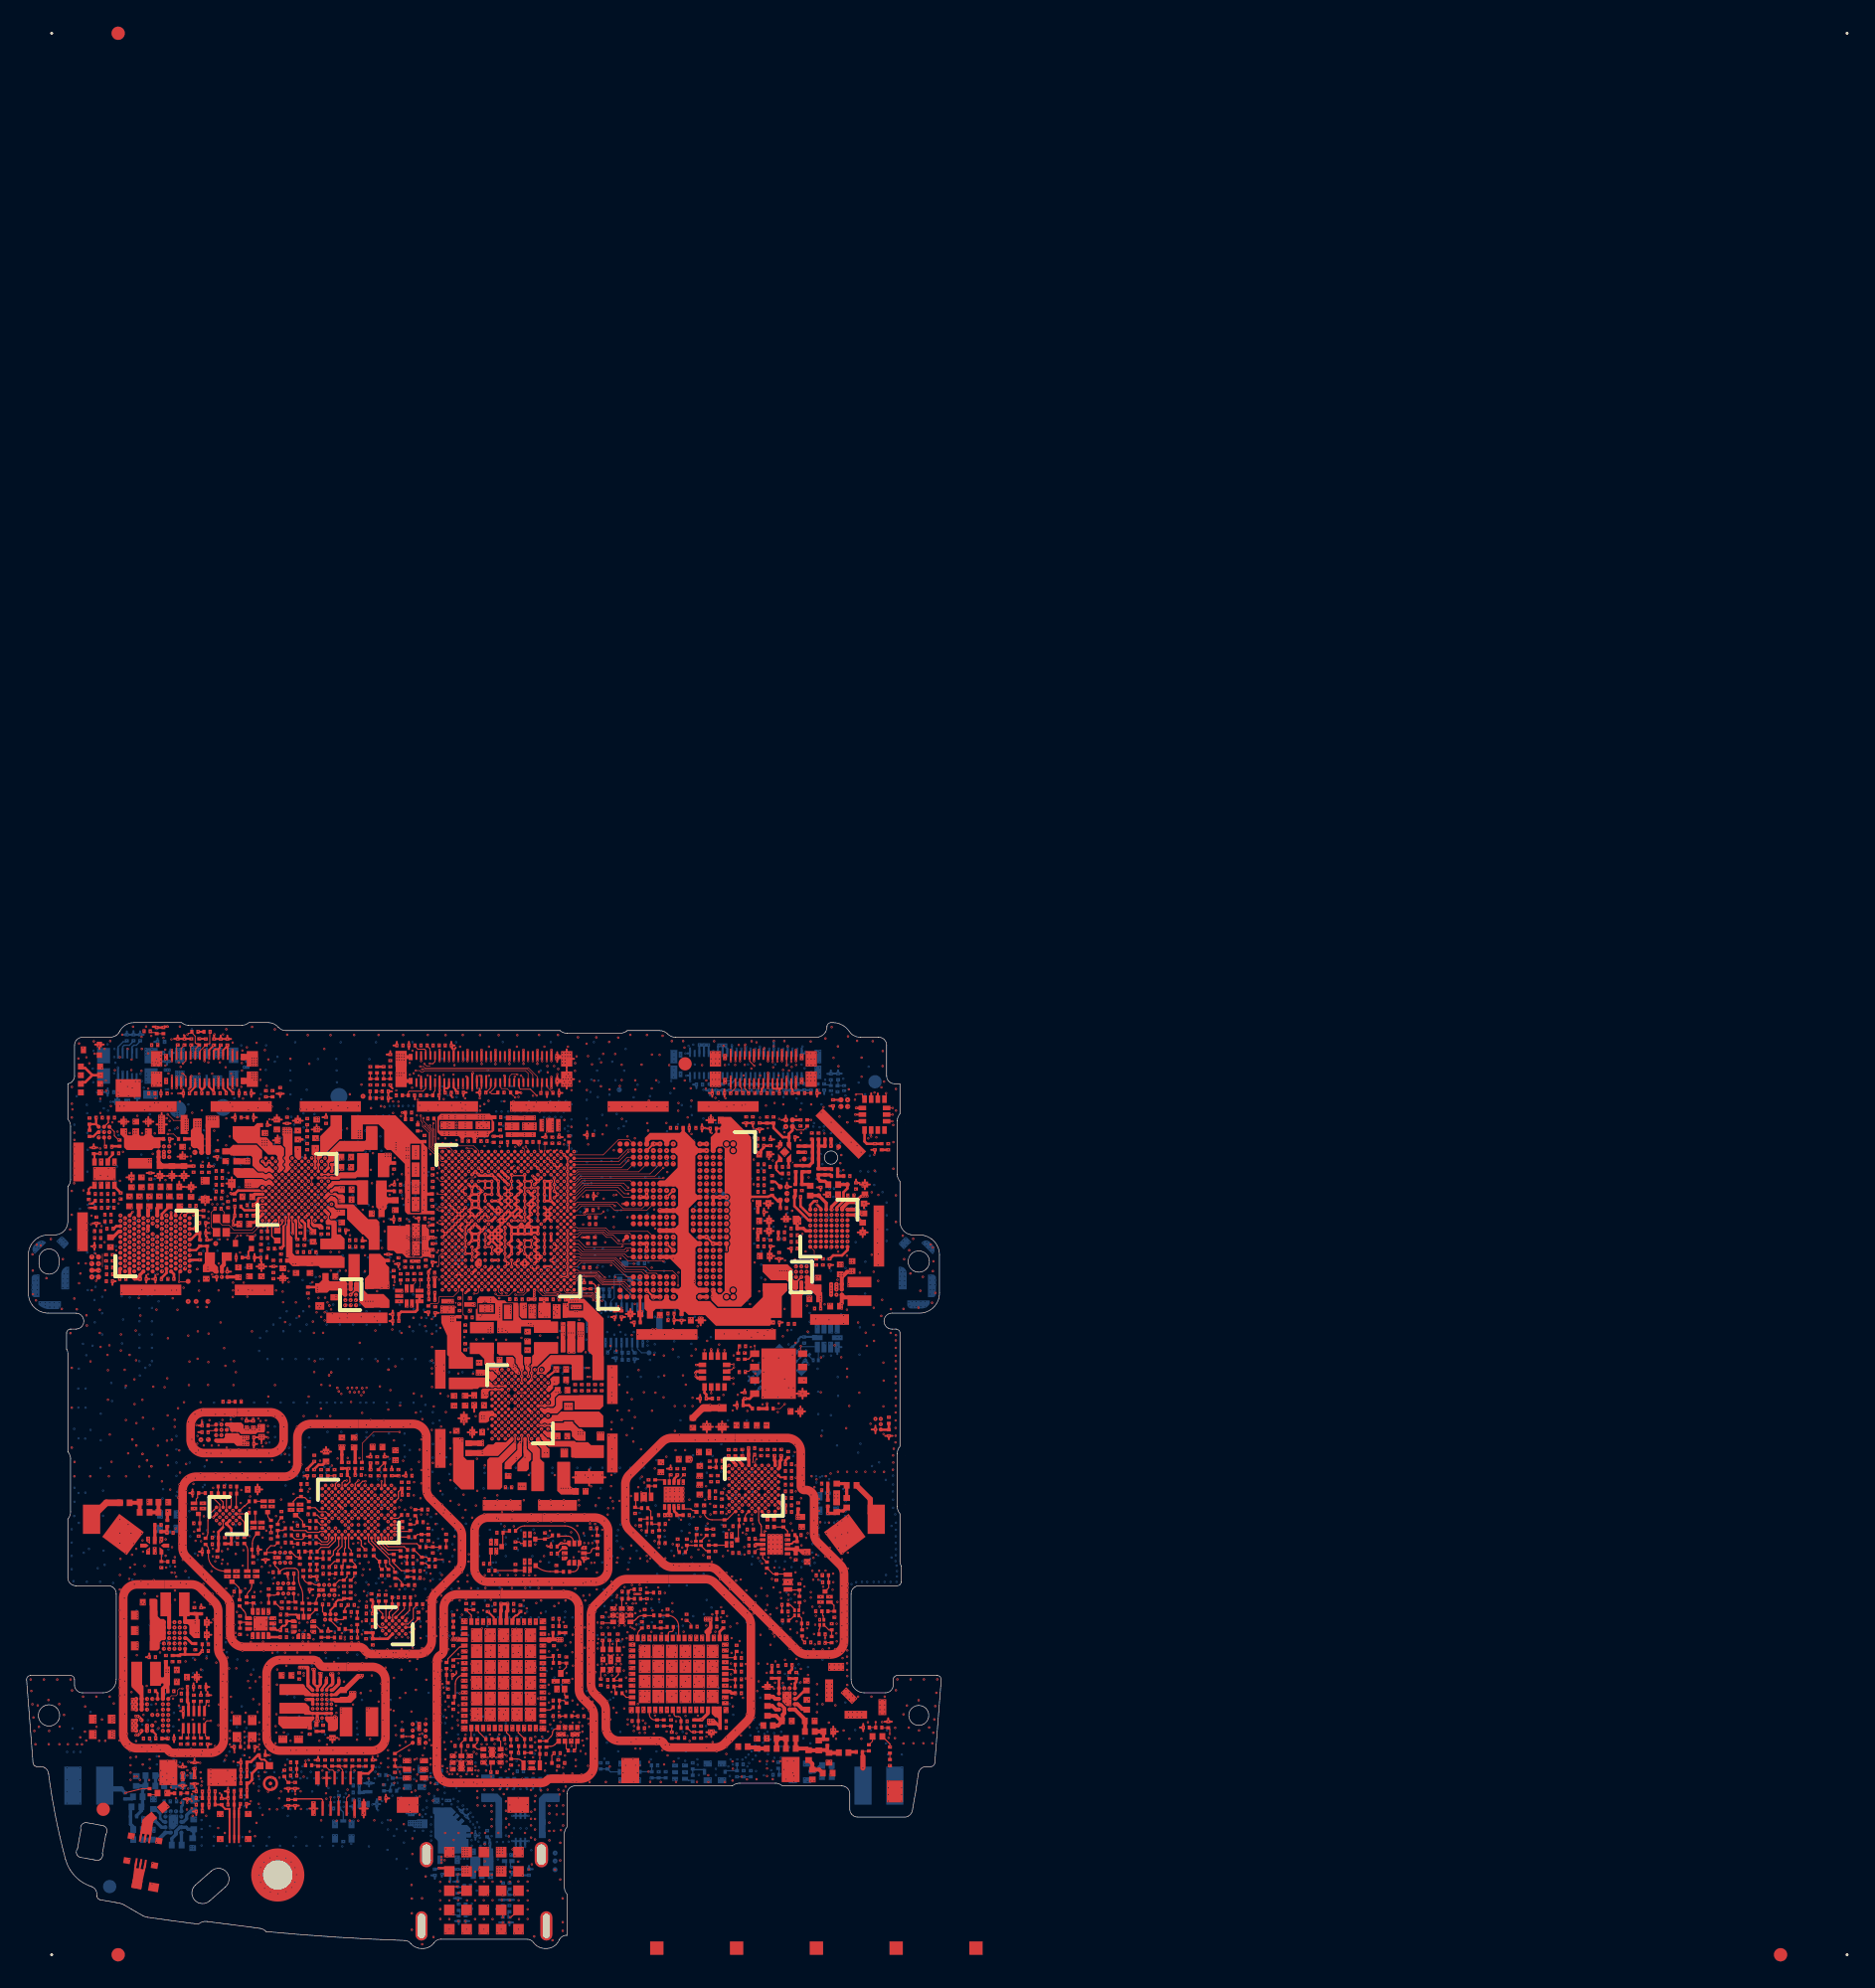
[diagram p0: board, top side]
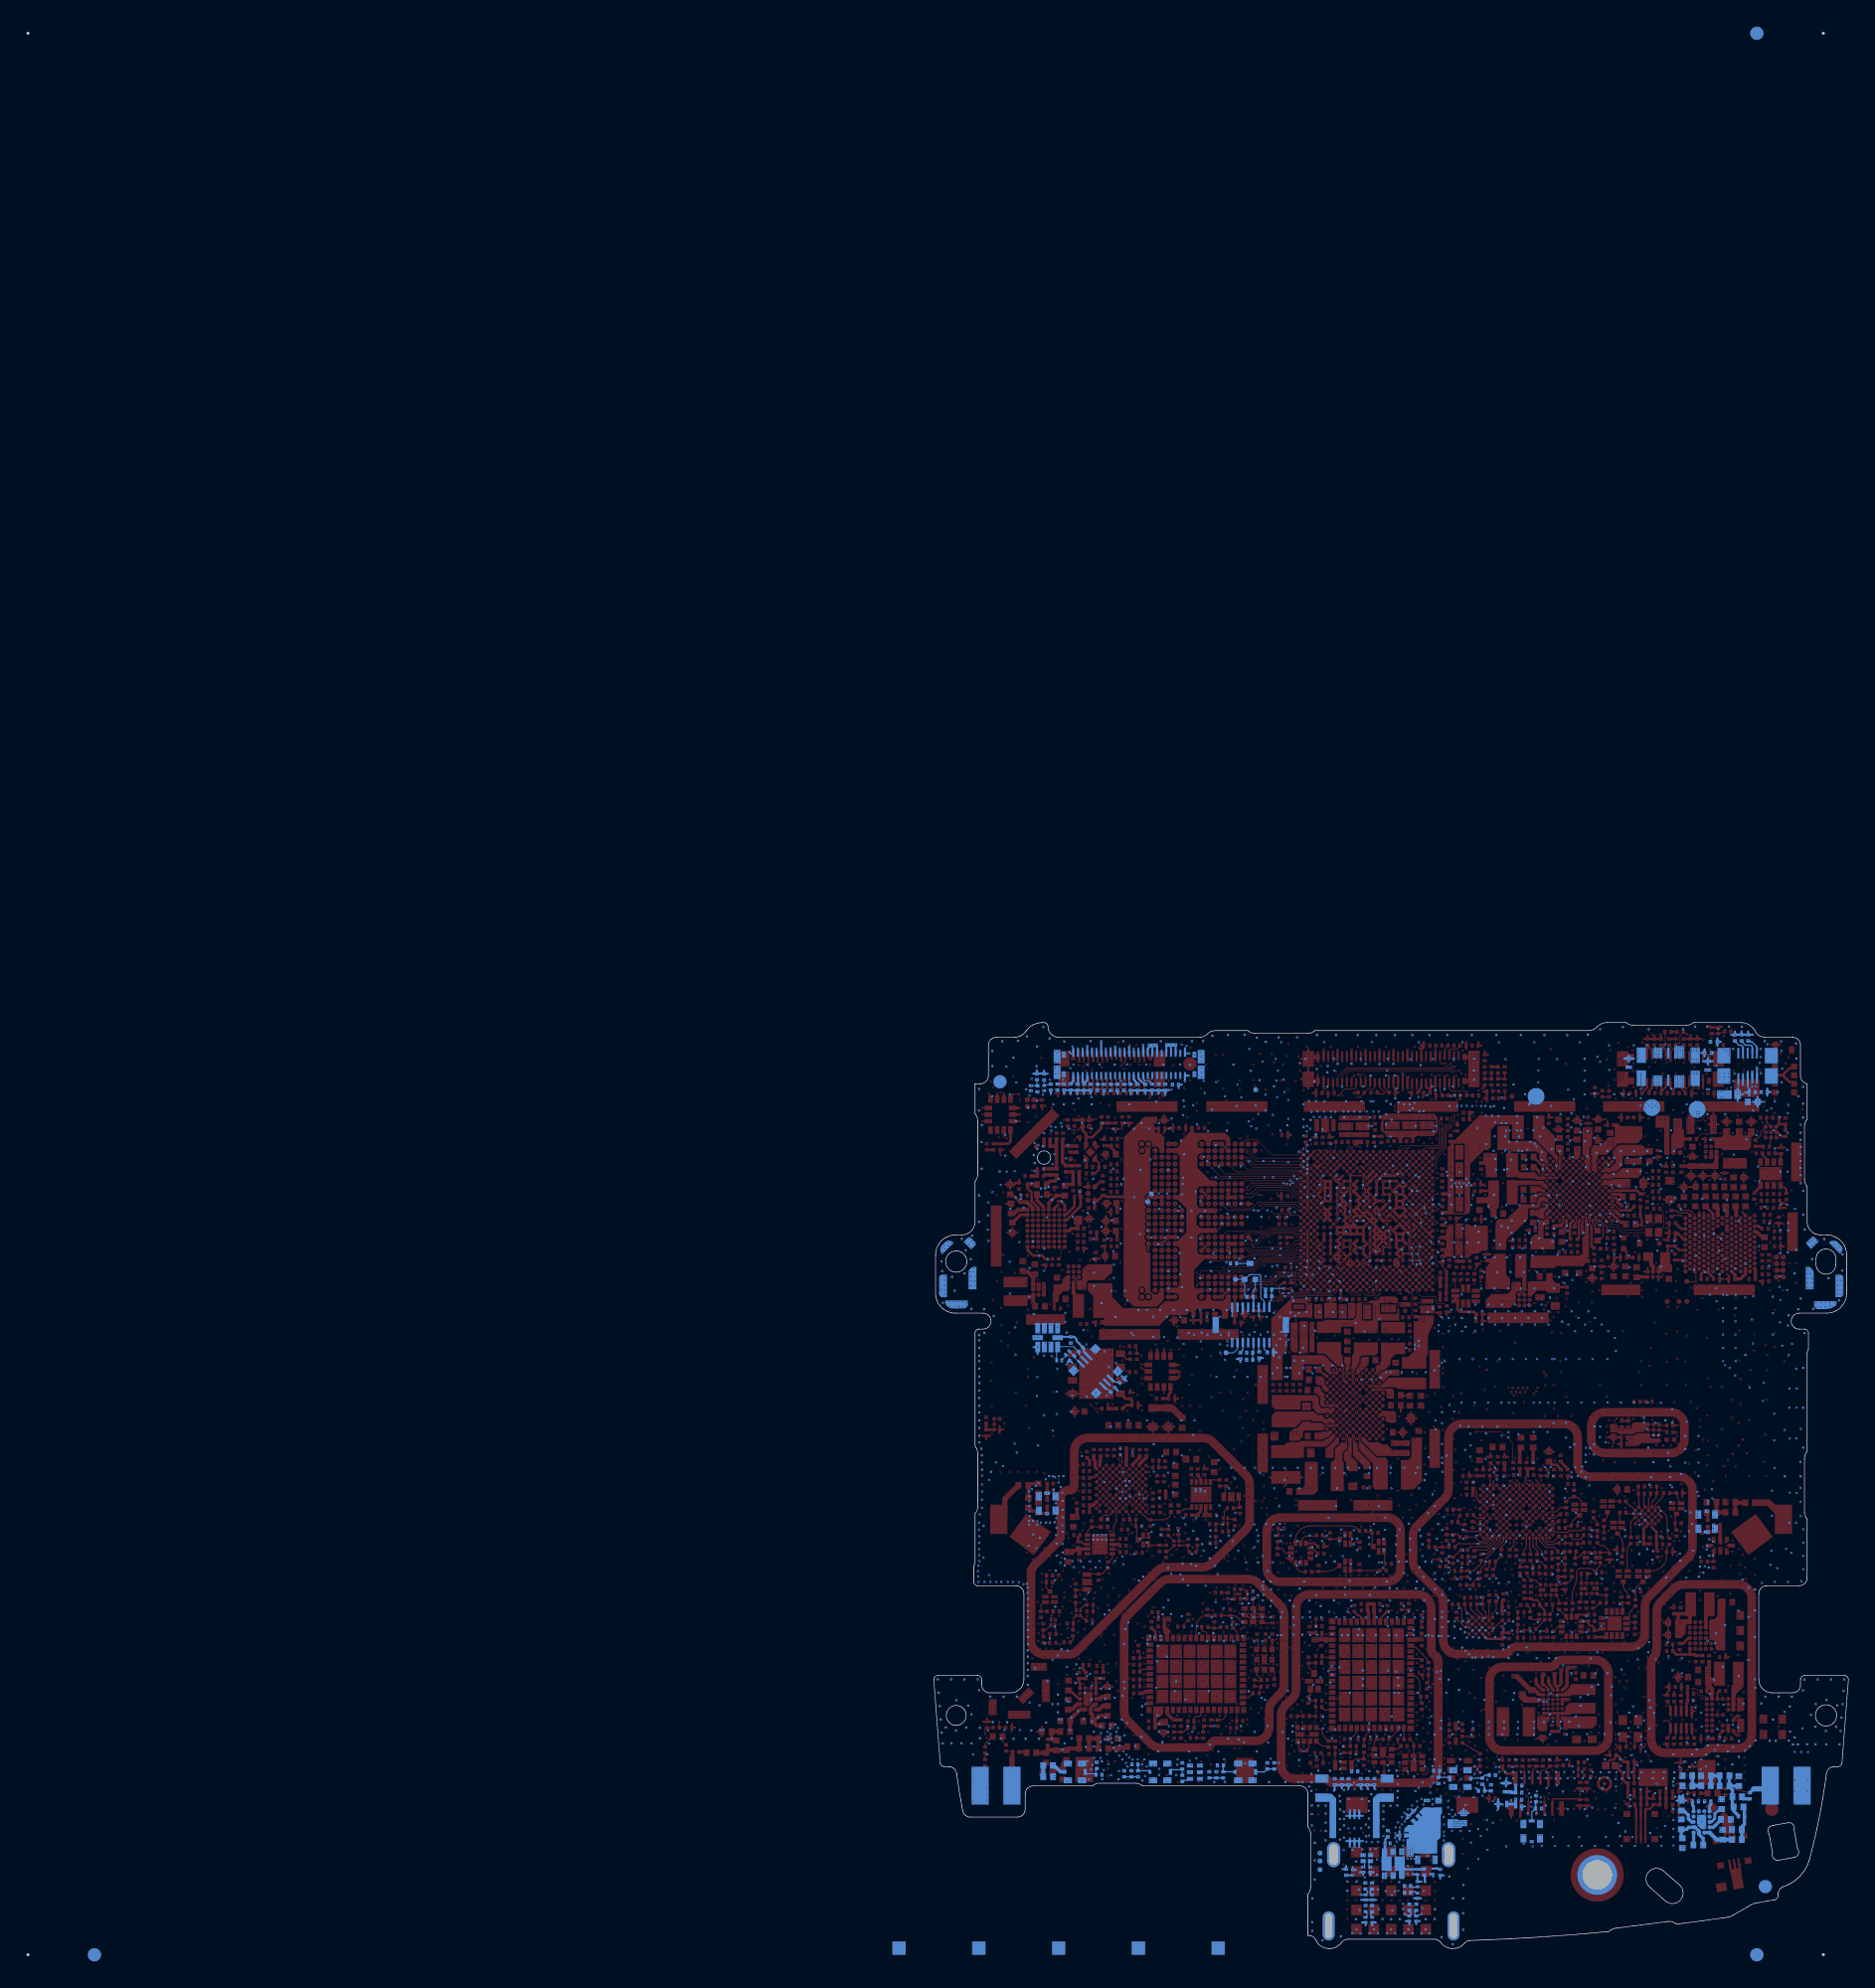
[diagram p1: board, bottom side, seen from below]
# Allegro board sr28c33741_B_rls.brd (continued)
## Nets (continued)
HAP_RESET: R4618.2(B<0>) U1001.AB40(GPIO_80) U4600.B4(RST)
HAPTIC_OUT_N: C4607.2(B<0>) C4608.2(B<0>) L4611.1(A<0>) U4600.A6(HDN)
HAPTIC_OUT_N_F: J4700.2(X<0>) J4700.4(X<0>) J4700.6(X<0>) L4611.2(B<0>)
HAPTIC_OUT_P: C4606.2(B<0>) C4609.2(B<0>) L4610.1(A<0>) U4600.C6(HDP)
HAPTIC_OUT_P_F: J4700.1(X<0>) J4700.3(X<0>) J4700.5(X<0>) L4610.2(B<0>)
HB2_SDR_DRX_50R: C7863.1(A<0>) C7864.2(B<0>) C7867.1(A<0>)
HB2_SDR_PRX_50R: C7366.1(A<0>) C7368.2(B<0>) L7367.2(B<0>)
HB_CPL_ATT_50R: R7176.2(B<0>) R7177.1(A<0>) U7150.61(HB_CPL_OUT)
HB_CPL_OUT_50R: R7177.2(B<0>) R7178.2(B<0>) U7100.5(LB_CPL_IN2)
HS_MIC_BIAS_1A: R6266.2(B<0>) U6250.B6(MICBIAS1A)
HS_MIC_BIAS_1B: R6267.2(B<0>) U6250.D6(MICBIAS1B)
HW_ID_1: R1131.2(B<0>) U1001.AM2(GPIO_29)
HW_ID_2: R1132.2(B<0>) U1001.AN3(GPIO_30)
HWID1: C1130.2(B<0>) R1127.1(A<0>) R1129.2(B<0>) R1131.1(A<0>)
HWID2: C1131.2(B<0>) R1128.1(A<0>) R1130.2(B<0>) R1132.1(A<0>)
I2C_SCL_TS_FL: C5321.2(B<0>) E5304.2(B) J5300.25(X<0>)
I2C_SDA_TS_FL: C5320.2(B<0>) E5305.2(B) J5300.23(X<0>)
JTAG_GPIO: JTAG.14(X<0>) Q1020.1(G) R1021.1(A<0>) TP_FORCEFLASH.1(X)
JTAG_PS_HOLD: JTAG.15(X<0>) U1001.AT30(PS_HOLD) U2000.206(PS_HOLD)
JTAG_RTCK: JTAG.3(X<0>) TP_JTAG_RTCK.1(X)
JTAG_SRST_N: C1007.1(A<0>) C1023.2(B<0>) C1024.2(B<0>) JTAG.16(X<0>) R1007.2(B<0>) U1001.G43(SRST_N)
JTAG_TCK: JTAG.4(X<0>) U1001.E41(TCK)
JTAG_TDI: JTAG.6(X<0>) U1001.C43(TDI)
JTAG_TDO: JTAG.2(X<0>) U1001.D42(TDO)
JTAG_TMS: C1020.2(B<0>) JTAG.5(X<0>) U1001.F42(TMS)
JTAG_TRST_N: C1021.2(B<0>) C1022.2(B<0>) JTAG.9(X<0>) U1001.F40(TRST_N)
KEY_VOL_DN: C5516.2(B<0>) J5500.26(X<0>) TP_KEY_DN.1(X) U2000.184(RESIN_N)
KEY_VOL_UP: C5517.2(B<0>) J5500.28(X<0>) R1005.1(A<0>) U1005.2(A) U2400.97(GPIO_07)
KYPD_PWR_N: C5521.2(B<0>) J5500.24(X<0>) TP_PWR_KEY.1(X) U2000.71(KPD_PWR_N)
LB_PA_IN_50R: C7114.2(B<0>) L7115.2(B<0>) U7100.26(LB_4G_IN3)
LCD_RST_N: C5308.2(B<0>) J5300.17(X<0>) U1001.W39(GPIO_6)
LCD_TE: E5302.1(A) U1001.U39(GPIO_10)
LDC_PWR_KEY: C1517.2(B<0>) J6601.2(X<0>)
LDC_PWRKEEY_COM: C1518.2(B<0>) J6601.3(X<0>)
LDSP_L_DM: C4672.2(B<0>) C4673.2(B<0>) C4675.2(B<0>) C4790.1(A<0>) E4671.2(NEG) L4671.1(A<0>) L6402.2(B<0>) VR4671.2(A1)
LDSP_P_DM: C4670.2(B<0>) C4671.2(B<0>) C4674.2(B<0>) C4790.2(B<0>) E4670.2(NEG) L4670.1(A<0>) L6401.2(B<0>) VR4670.2(A1)
LED_SOL_SRC: J5502.24(X<0>) U2400.61(RGB_RED)
LNA_EN_5G_CH0: C4086.2(B<0>) U4000.20(WL_BT_FEM_1) U4080.9(LNA_EN)
LNA_EN_5G_CH1: C4097.2(B<0>) U4000.46(WL_BT_FEM_7) U4090.9(LNA_EN)
LP4X_BUCK_MODE: U2400.133(GPIO_12) U2570.D1(VSEL)
LP4X_REG_SRC_EN: R2015.1(A<0>) U2570.D2(EN)
LV_LDO_EN: U2400.157(GPIO_11) U2560.D2(EN)
LV_LDO_VSEL: U2400.102(GPIO_01) U2560.D1(VSEL)
M4670_LDSP_L_POS: J6400.G3(X<0>) J6400.G4(X<0>) L4670.2(B<0>)
M4671_LDSP_L_NEG: J6400.G1(X<0>) J6400.G2(X<0>) L4671.2(B<0>)
MAG_DRDY: R6130.1(A<0>) U1001.J41(GPIO_119) U6130.B2(ODDRDY)
MAG_VDD_ISO: C6130.2(B<0>) R6131.1(A<0>) U6130.B1(VDD)
MB_CPL_OUT_50R: U7100.6(LB_CPL_IN1) U7150.54(MB_CPL_OUT)
MB_MAIN_POST_5G_FLT_50R: C7173.1(A<0>) FL7170.3(OUT_IN) L7172.2(B<0>)
MB_MAIN_PRE_5G_FLT_50R: C7170.2(B<0>) FL7170.1(IN_OUT) L7171.2(B<0>)
MBDRX_HBTRX_50R: C7003.2(B<0>) FL7003.5(COMMON) L7004.2(B<0>)
MEM_THERM: RT6165.1(POS) U2000.172(AMUX_2)
MIPI_CSI2_CLK_M: U1001.AC3(MIPI_CSI2_DCLK_N)
MIPI_CSI2_CLK_P: U1001.AB2(MIPI_CSI2_DCLK_P)
MIPI_CSI2_LANE0_M: U1001.AD2(MIPI_CSI2_DLN0_N)
MIPI_CSI2_LANE0_P: U1001.AC1(MIPI_CSI2_DLN0_P)
MIPI_CSI2_LANE1_M: U1001.AF4(MIPI_CSI2_DLN1_N)
MIPI_CSI2_LANE1_P: U1001.AE3(MIPI_CSI2_DLN1_P)
MIPI_CSI2_LANE2_M: U1001.AG3(MIPI_CSI2_DLN2_N)
MIPI_CSI2_LANE2_P: U1001.AF2(MIPI_CSI2_DLN2_P)
MIPI_CSI2_LANE3_M: U1001.AH2(MIPI_CSI2_DLN3_N)
MIPI_CSI2_LANE3_P: U1001.AG1(MIPI_CSI2_DLN3_P)
MIPI_CSI_FRONT<0>: J5500.47(X<0>) U1001.AM4(MIPI_CSI1_DCLK_N)
MIPI_CSI_FRONT<1>: J5500.45(X<0>) U1001.AN5(MIPI_CSI1_DCLK_P)
MIPI_CSI_FRONT<2>: J5500.41(X<0>) U1001.AL5(MIPI_CSI1_DLN0_N)
MIPI_CSI_FRONT<3>: J5500.39(X<0>) U1001.AM6(MIPI_CSI1_DLN0_P)
MIPI_CSI_FRONT<4>: J5500.35(X<0>) U1001.AJ3(MIPI_CSI1_DLN1_N)
MIPI_CSI_FRONT<5>: J5500.33(X<0>) U1001.AK4(MIPI_CSI1_DLN1_P)
MIPI_CSI_REAR<0>: J5500.29(X<0>) U1001.AF6(MIPI_CSI0_DCLK_P)
MIPI_CSI_REAR<1>: J5500.27(X<0>) U1001.AE5(MIPI_CSI0_DCLK_N)
MIPI_CSI_REAR<2>: J5500.21(X<0>) U1001.AE7(MIPI_CSI0_DLN0_P)
MIPI_CSI_REAR<3>: J5500.23(X<0>) U1001.AD6(MIPI_CSI0_DLN0_N)
MIPI_CSI_REAR<4>: J5500.17(X<0>) U1001.AC5(MIPI_CSI0_DLN1_P)
MIPI_CSI_REAR<5>: J5500.15(X<0>) U1001.AB4(MIPI_CSI0_DLN1_N)
MIPI_CSI_REAR<6>: J5500.9(X<0>) U1001.AB6(MIPI_CSI0_DLN2_P)
MIPI_CSI_REAR<7>: J5500.11(X<0>) U1001.AA5(MIPI_CSI0_DLN2_N)
MIPI_CSI_REAR<8>: J5500.5(X<0>) U1001.AA7(MIPI_CSI0_DLN3_P)
MIPI_CSI_REAR<9>: J5500.3(X<0>) U1001.Y6(MIPI_CSI0_DLN3_N)
MIPI_DSI0<0>: J5300.18(X<0>) U1001.M40(MIPI_DSI0_CLK_N)
MIPI_DSI0<1>: J5300.16(X<0>) U1001.N39(MIPI_DSI0_CLK_P)
MIPI_DSI0<2>: J5300.12(X<0>) U1001.R39(MIPI_DSI0_LN0_N)
MIPI_DSI0<3>: J5300.10(X<0>) U1001.T38(MIPI_DSI0_LN0_P)
MIPI_DSI0<4>: J5300.24(X<0>) U1001.P38(MIPI_DSI0_LN1_N)
MIPI_DSI0<5>: J5300.22(X<0>) U1001.R37(MIPI_DSI0_LN1_P)
MIPI_DSI0<6>: J5300.30(X<0>) U1001.L39(MIPI_DSI0_LN2_N)
MIPI_DSI0<7>: J5300.28(X<0>) U1001.M38(MIPI_DSI0_LN2_P)
MIPI_DSI0<8>: J5300.6(X<0>) U1001.K38(MIPI_DSI0_LN3_N)
MIPI_DSI0<9>: J5300.4(X<0>) U1001.L37(MIPI_DSI0_LN3_P)
MSS_CMD<0>: U1001.R3(GPIO_145) U4000.82(COEX_TXD)
MSS_CMD<1>: U1001.P2(GPIO_144) U4000.89(COEX_RXD)
NFC_ANT1: D351.1(A2) J350.4(X<0>) R4152.2(B<0>)
NFC_ANT2: D350.1(A2) J350.2(X<0>) R4162.2(B<0>)
NFC_CLK_IN: TP4104.1(X) U2000.137(BB_CLK3) U4100.D7(SYS_CLK)
NFC_CLK_REQ: TP4103.1(X) U2000.147(GPIO_04) U4100.G6(SYS_CLK_REQ)
NFC_EN: R4100.2(B<0>) U1001.R1(GPIO_12) U4100.H6(NRESET)
NFC_I2C_SCL: R1032.1(A<0>) U1001.U3(GPIO_42) U4100.G5(I2C_SCL)
NFC_I2C_SDA: R1031.1(A<0>) U1001.T2(GPIO_41) U4100.H5(I2C_SDA)
NFC_IRQ: TP4105.1(X) U1001.AV2(GPIO_24) U4100.F6(IRQ_OUT)
NFC_VTX: C4124.2(B<0>) C4125.2(B<0>) C4126.2(B<0>) U4100.A7(VDD_TX) U4120.A1(VOUT1) U4120.A2(VOUT2)
NFC_VTX_GND: C4121.1(A<0>) C4124.1(A<0>) C4125.1(A<0>) E4120.2(NEG) U4120.C1(GND1) U4120.C2(GND2) U4120.C3(GND3)
PA_2GHB_IN_50R: C7110.2(B<0>) L7111.2(B<0>) U7100.22(HB_2G_IN)
PA_2GLB_IN_50R: C7112.2(B<0>) L7113.2(B<0>) U7100.24(LB_2G4G_IN1)
PA_EN_5G_CH0: C4087.2(B<0>) U4000.34(WL_BT_FEM_5) U4080.7(PA_EN)
PA_EN_5G_CH1: C4096.2(B<0>) U4000.97(WL_BT_FEM_8) U4090.7(PA_EN)
PA_THERM1: C7199.2(B<0>) RT7199.1(POS) U2000.160(AMUX_3)
PA_THERM2: C7149.2(B<0>) RT7149.1(POS) U2000.171(AMUX_4)
PA_TRX_B40_50R: C7351.1(A<0>) L7350.2(B<0>) U7150.13(HB_TX2_OUT)
PA_TX_B13_50R: C7261.2(B<0>) L7260.2(B<0>) U7100.37(LB_TX3_OUT)
PA_TX_B25_50R: C7300.1(A<0>) U7150.36(MB_TX1_OUT)
PA_TX_B25_MAT_50R: C7300.2(B<0>) L7301.2(B<0>) L7302.1(A<0>)
PA_TX_B28_50R: C7230.2(B<0>) U7100.39(LB_TX1_OUT)
PA_TX_B28_MAT_50R: C7230.1(A<0>) L7231.2(B<0>) L7232.2(B<0>)
PA_TX_B34_B39_50R: C7312.1(A<0>) L7311.2(B<0>) U7150.41(MB_TX2_OUT)
PA_ULB_LB_ANT_MAT_50R: C7141.1(A<0>) L7140.2(B<0>) U7100.2(LB_ANT)
PAMID_ANT_HB_TRX_50R: C7181.1(A<0>) L7180.2(B<0>) U7150.59(HB_ANT)
PAMID_ANT_MB_TRX_50R: C7170.1(A<0>) L7173.2(B<0>) U7150.57(MB_ANT)
PAMID_PRX_B66_B4_50R: L7184.1(A<0>) U7150.38(B66_RX)
PCM_THERM: C515.2(B<0>) R2403.2(B<0>) RT515.1(POS) U2000.177(AUX_THERM)
PM670A_DIE_TEMP: U2000.183(ANA_IN) U2400.49(DIE_TEMP)
PM_PON_RESET_N: C1001.2(B<0>) U1001.AR31(RESIN_N) U2000.195(PON_RESET_N)
PM_XO_THERM: C2000.2(B<0>) U2000.182(XO_THERM) Y2000.4(THRMSTR_IN)
PM_XTAL_IN: U2000.210(XTAL_IN) Y2000.1(XTAL_IN)
PM_XTAL_OUT: U2000.198(XTAL_OUT) Y2000.3(XTAL_OUT)
PON_OPTION_1: R2015.2(B<0>) R2016.2(B<0>) R2453.1(A<0>) U2000.8(GPIO_01)
PON_OUT: TP_PON_OUT.1(X) U2000.152(PON_OUT) U2400.28(PON_1)
PRI_MIC_BIAS: C4501.2(B<0>) C4505.2(B<0>) C4506.2(B<0>) C6241.2(B<0>) J4500.1(X<0>) J4500.2(X<0>) U6250.C5(MICBIAS2A) VR4501.2(A1)
PRI_MIC_DM: C4503.2(B<0>) C6290.1(A<0>) J4500.5(X<0>) J4500.6(X<0>)
PRI_MIC_DP: C4502.2(B<0>) C4504.2(B<0>) C6289.1(A<0>) J4500.3(X<0>) J4500.4(X<0>) VR4500.2(A1)
PROX_ALS_F_INT_N: C5515.2(B<0>) J5502.23(X<0>) U1001.AR3(GPIO_20)
PROX_ALS_R_INT_N: C5520.2(B<0>) J5502.21(X<0>) U1001.K42(GPIO_120)
PRX_B1_50R: C7387.2(B<0>) U7150.39(B1_RX)
PRX_B2_50R: C7386.2(B<0>) U7150.47(B2_RX)
PRX_B3_50R: C7385.2(B<0>) U7150.45(B3_RX)
PRX_B5_B26_50R: C7285.1(A<0>) U7100.49(B26_RX)
PRX_B7_50R: C7368.1(A<0>) U7150.7(B7_RX)
PRX_B8_50R: C7290.1(A<0>) U7100.44(B8_RX)
PRX_B12_50R: C7271.1(A<0>) U7100.47(B12_RX)
PRX_B20_50R: C7280.1(A<0>) U7100.51(B20_RX)
PRX_B34_B39_50R: R7307.1(A<0>) U7150.43(MB_RX2_OUT)
PRX_B34_B39_B25_50R: C7326.1(A<0>) L7306.2(B<0>) L7326.1(A<0>) R7307.2(B<0>)
PRX_B40_50R: C7390.2(B<0>) U7150.9(HB_RX2_OUT)
PRX_B41_50R: C7389.2(B<0>) U7150.11(B41_RX)
PRX_B66_B4_50R: C7388.2(B<0>) L7184.2(B<0>)
PRX_LB2_SW_CTL1: R1023.1(A<0>) U1001.AT18(GPIO_101)
QLINK_CLK_M: U1001.BA23(QLINK_CLK_N) U3100.81(QLINK_CLK_M)
QLINK_CLK_P: U1001.AY22(QLINK_CLK_P) U3100.96(QLINK_CLK_P)
QLINK_EN: U1001.AV16(GPIO_131) U3100.143(QLINK_EN)
QLINK_REQ: U1001.AV12(GPIO_130) U3100.73(QLINK_REQ)
QLINK_RX0_M: U1001.AW21(QLINK_RXLANE1_N) U3100.88(QLINK_DL0_M)
QLINK_RX0_P: U1001.AV20(QLINK_RXLANE1_P) U3100.103(QLINK_DL0_P)
QLINK_RX1_M: U1001.AY20(QLINK_RXLANE2_N) U3100.111(QLINK_DL1_M)
QLINK_RX1_P: U1001.AW19(QLINK_RXLANE2_P) U3100.127(QLINK_DL1_P)
QLINK_RX2_M: U1001.AY18(QLINK_RXLANE3_N) U3100.135(QLINK_DL2_M)
QLINK_RX2_P: U1001.BA19(QLINK_RXLANE3_P) U3100.119(QLINK_DL2_P)
QLINK_TX_M: U1001.AW23(QLINK_TXLANE1_N) U3100.87(QLINK_UL0_M)
QLINK_TX_P: U1001.AY24(QLINK_TXLANE1_P) U3100.72(QLINK_UL0_P)
QLN_DRX_B5B26_50R: C7702.2(B<0>) U7701.H3(SW23)
QLN_DRX_B8_50R: C7707.2(B<0>) U7701.H5(SW21)
QLN_DRX_B12B13_50R: R7718.2(B<0>) U7701.A6(SW11)
QLN_DRX_B20_50R: C7712.2(B<0>) U7701.G4(SW22)
QLN_DRX_B28_50R: R7723.2(B<0>) U7701.B5(SW12)
QLN_PRX_B5B26_50R: C7285.2(B<0>) U7216.H3(SW23)
QLN_PRX_B8_50R: C7290.2(B<0>) U7216.H5(SW21)
QLN_PRX_B12_50R: C7271.2(B<0>) U7216.A6(SW11)
QLN_PRX_B13_50R: C7269.2(B<0>) U7216.B5(SW12)
QLN_PRX_B20_50R: C7280.2(B<0>) U7216.G4(SW22)
QLN_PRX_B28_50R: C7241.2(B<0>) U7216.B3(SW13)
QLN_PRX_LB1_SW_OUT_50R: C7216.2(B<0>) L7219.2(B<0>) U7216.C6(LB1_SW_OUT)
QLN_PRX_LB2_SW_OUT_50R: C7217.2(B<0>) L7274.2(B<0>) U7216.G6(LB2_SW_OUT)
QREFS_CXO_REXT: R1173.1(A<0>) U1001.AT42(QREFS_CXO_REXT)
QUAT_MIC_BIAS: C5538.2(B<0>) C6244.2(B<0>) J5502.13(X<0>) U6250.K4(MICBIAS2D)
QUAT_MIC_DM: C5536.2(B<0>) C6277.1(A<0>) J5502.5(X<0>) J5502.7(X<0>)
QUAT_MIC_DP: C5537.2(B<0>) C6276.1(A<0>) J5502.9(X<0>) J5502.11(X<0>)
REF_CSNS_CS0_N: D352.1(A2) J350.8(X<0>) R6152.1(A<0>)
REF_CSNS_CS3_N: C280.2(B<0>) R280.1(A<0>) R6151.1(A<0>)
RF_CONN_DET1: C212.2(B<0>) R210.1(A<0>) R211.2(B<0>) U1001.AY10(GPIO_114)
RF_CONN_DET2: C232.2(B<0>) R230.1(A<0>) R231.2(B<0>) U1001.AY16(GPIO_115)
RF_CONN_DET3: C132.2(B<0>) R130.1(A<0>) R131.2(B<0>) U1001.AP4(GPIO_28)
RFFE1_CLK: TP_RFFE1_CLK.1(X) U1001.AY14(GPIO_149) U3100.166(RFFE1_CLK)
RFFE1_DATA: TP_RFFE1_DATA.1(X) U1001.AW15(GPIO_148) U3100.149(RFFE1_DATA)
RFFE2_CLK_1: TP_RFFE2_CLK.1(X) U100.10(CLK) U200.10(CLK) U1001.AW9(GPIO_147)
RFFE2_DATA_1: TP_RFFE2_DATA.1(X) U100.9(DATA) U200.9(DATA) U1001.AV10(GPIO_146)
RFFE3_CLK: TP_RFFE3_CLK.1(X) U1001.AU17(GPIO_138) U7216.F3(CLK) U7701.F3(CLK)
RFFE3_DATA: TP_RFFE3_DATA.1(X) U1001.AT16(GPIO_137) U7216.F1(DATA) U7701.F1(DATA)
RFFE4_CLK: TP_RFFE4_CLK.1(X) U1001.AR15(GPIO_140) U7500.3(SCLK) U7510.6(SCLK) U7520.6(SCLK)
RFFE4_DATA: TP_RFFE4_DATA.1(X) U1001.AU15(GPIO_139) U7500.2(SDATA) U7510.5(SDATA) U7520.5(SDATA)
RFFE5_CLK: TP_RFFE5_CLK.1(X) U1001.AV14(GPIO_142) U7100.18(SCLK) U7150.22(HB_SCLK) U7150.29(MB_SCLK) U8200.27(SCLK)
RFFE5_DATA: TP_RFFE5_DATA.1(X) U1001.AW13(GPIO_141) U7100.19(SDATA) U7150.23(HB_SDATA) U7150.28(MB_SDATA) U8200.23(SDATA)
S1C_PGND: C2560.1(A<0>) C2561.1(A<0>) C2563.2(B<0>) C2564.2(B<0>) E2560.1(POS) U2560.A3(PGND1) U2560.B3(PGND2) U2560.C2(PGND3)
S2C_PGND: C2570.1(A<0>) C2571.1(A<0>) C2573.2(B<0>) C2574.2(B<0>) E2570.2(NEG) U2570.A3(PGND1) U2570.B3(PGND2) U2570.C2(PGND3)
SAR_SENSOR_INT_N: C6153.2(B<0>) R6154.1(A<0>) U1001.AY32(GPIO_40) U6150.10(NIRQ)
SB_INT_N: TP_SB_INT_N.1(X) U1001.AB42(GPIO_79) U6400.F4(INT_GPIO2)
SB_RST_N: R6402.2(B<0>) TP_SB_RST.1(X) U1001.AL1(GPIO_27) U6400.E2(RESET)
SDM_LNBBCLK1: TP_BB_CLK1.1(X) U1001.AM36(CXO) U2000.148(BB_CLK1)
SDM_LNBBCLK1_EN: R2455.2(B<0>) U2000.158(BB_CLK1_EN)
SDM_RESOUT_N: U1001.A21(RESOUT_N) U1005.1(OE)
SDM_THERM: RT1001.1(POS) U2000.161(AMUX_1)
SDR_DRX_HB1: C7835.2(B<0>) U3100.141(DRX_HB1)
SDR_DRX_HB2: C7863.2(B<0>) U3100.133(DRX_HB2)
SDR_DRX_HB3: L7825.2(B<0>) U3100.126(DRX_HB3)
SDR_DRX_HB4: L7614.2(B<0>) U3100.117(DRX_HB4)
SDR_DRX_LB2: C7750.2(B<0>) U3100.170(DRX_LB2)
SDR_DRX_LB4: C7751.2(B<0>) U3100.169(DRX_LB4)
SDR_DRX_MB1: C7606.2(B<0>) U3100.171(DRX_MB1)
SDR_DRX_MB2: L7626.2(B<0>) U3100.164(DRX_MB2)
SDR_DRX_MB3: L7616.2(B<0>) U3100.156(DRX_MB3)
SDR_DRX_MB4: L7603.2(B<0>) U3100.148(DRX_MB4)
SDR_GNSS: L8518.2(B<0>) U3100.161(GNSS_IN)
SDR_PRX_HB1: L7368.2(B<0>) U3100.46(PRX_HB1)
SDR_PRX_HB2: C7366.2(B<0>) U3100.54(PRX_HB2)
SDR_PRX_HB3: L7371.2(B<0>) U3100.63(PRX_HB3)
SDR_PRX_HB4: L7336.2(B<0>) U3100.71(PRX_HB4)
SDR_PRX_LB2: C7215.2(B<0>) U3100.15(PRX_LB2)
SDR_PRX_LB4: C7270.2(B<0>) U3100.14(PRX_LB4)
SDR_PRX_MB1: L7328.2(B<0>) U3100.16(PRX_MB1)
SDR_PRX_MB2: L7326.2(B<0>) U3100.25(PRX_MB2)
SDR_PRX_MB3: L7331.2(B<0>) U3100.32(PRX_MB3)
SDR_PRX_MB4: L7333.2(B<0>) U3100.38(PRX_MB4)
SDR_TX0_LB2: C7114.1(A<0>) U3100.27(TX_CH0_LB2)
SDR_TX_CH0_HB1: R3202.2(B<0>) U7150.20(4GHB_IN)
SDR_TX_CH0_LB1: C7112.1(A<0>) U3100.2(TX_CH0_LB1)
SDR_TX_CH0_MB1: C7165.1(A<0>) U3100.33(TX_CH0_MB1)
SDR_TX_CH0_MB2: C7110.1(A<0>) U3100.10(TX_CH0_MB2)
SDR_TX_FBRX_P: C7126.2(B<0>) R7121.2(B<0>) R7122.2(B<0>) U3100.60(TX_FBRX_P)
SDR_TXFBRX_ATT_50R: R7120.2(B<0>) R7121.1(A<0>) U7100.4(LB_CPL_OUT)
SEC_MIC_BIAS: C5535.2(B<0>) C6243.2(B<0>) J5502.20(X<0>) U6250.E5(MICBIAS2B)
SEC_MIC_DM: C5533.2(B<0>) C6273.1(A<0>) J5502.12(X<0>) J5502.14(X<0>)
SEC_MIC_DP: C5534.2(B<0>) C6272.1(A<0>) J5502.16(X<0>) J5502.18(X<0>)
SENSOR_SPI_CLK: U1001.AJ41(LPI_GPIO_4) U6110.13(SCL) U6115.13(SCL)
SENSOR_SPI_CS_N: U1001.AK42(LPI_GPIO_5) U6110.12(CS) U6115.12(CS)
SENSOR_SPI_MISO: U1001.AK40(LPI_GPIO_2) U6110.1(SDO_SA0) U6115.1(SDO_SA0)
SENSOR_SPI_MOSI: U1001.AH40(LPI_GPIO_3) U6110.14(SDA) U6115.14(SDA)
SIM_CLK: J4250.1(X<0>) U4250.1(USBPOS) VR4252.1(A2)
SIM_DATA: J4250.5(X<0>) U4250.2(USBNEG) VR4253.1(A2)
SIM_PRESENT: D4251.1(NEG) J4250.4(X<0>) R4250.1(A<0>) U4250.9(SEL)
SLB: TP_SLB.1(X) U2000.30(GPIO_08) U2400.63(GPIO_10)
SLEEP_CLK: TP_SLEEP_CLK.1(X) U1001.AU31(SLEEP_CLK) U2000.128(SLEEP_CLK) U4000.59(LF_CLK_IN)
SPK_BOOST_L: C6403.2(B<0>) C6404.2(B<0>) C6405.2(B<0>) C6408.2(B<0>) U6400.A1(VBST1) U6400.B1(VBST2) U6400.C1(VSPK1) U6400.D1(VSPK2)
SPMI_CLK: C1003.2(B<0>) U1001.AR33(SPMI_CLK) U2000.108(SPMI_CLK) U2400.64(SPMI_CLK)
SPMI_DATA: C1004.2(B<0>) U1001.AT34(SPMI_DATA) U2000.118(SPMI_DATA) U2400.75(SPMI_DATA)
SSC_I2C1_SCL: C5519.2(B<0>) J5502.25(X<0>) R1049.1(A<0>) U1001.AG41(LPI_GPIO_1) U6130.A3(SCL) U6140.4(SCK) U6250.T16(CIF2SCLK)
SSC_I2C1_SDA: C5518.2(B<0>) J5502.27(X<0>) R1048.1(A<0>) U1001.AH42(LPI_GPIO_0) U6130.B3(SDA) U6140.3(SDI) U6250.T14(CIF2SDA)
SSC_I2C2_SCL: C5514.2(B<0>) J5502.17(X<0>) R1053.1(A<0>) U1001.AA39(LPI_GPIO_15)
SSC_I2C2_SDA: C5503.2(B<0>) J5502.19(X<0>) R1052.1(A<0>) U1001.AB38(LPI_GPIO_14)
SSC_UART1_RX: U1001.AD42(LPI_GPIO_13) U4000.39(SENS_TXD)
SSC_UART1_TX: U1001.AC41(LPI_GPIO_12) U4000.45(SENS_RXD)
SSRX1_DM: C512.1(A<0>) D509.2(IO2) U500.12(SSRX1_N)
SSRX1_DP: C509.1(A<0>) D508.2(IO2) U500.11(SSRX1_P)
SSRX2_DM: C514.1(A<0>) D503.2(IO2) U500.19(SSRX2_N)
SSRX2_DP: C513.1(A<0>) D502.2(IO2) U500.20(SSRX2_P)
SSTX1_DM: C506.1(A<0>) D514.2(IO2) U500.17(SSTX1_N)
SSTX1_DP: C505.1(A<0>) D507.2(IO2) U500.16(SSTX1_P)
SSTX2_DM: C508.1(A<0>) D504.2(IO2) U500.14(SSTX2_N)
SSTX2_DP: C507.1(A<0>) D501.2(IO2) U500.15(SSTX2_P)
ST21_CDMPN: C4166.1(A<0>) C4167.1(A<0>) U4100.A3(CDMP2)
ST21_CDMPP: C4156.1(A<0>) C4157.1(A<0>) U4100.A1(CDMP1)
ST21_RXN: C4165.1(A<0>) C4169.1(A<0>) U4100.C1(RFI2)
ST21_RXP: C4159.1(A<0>) C4165.2(B<0>) U4100.B1(RFI1)
ST21_TX1: L4150.1(A<0>) TP_NFC_ST21_TX1.1(X) U4100.A6(RFO1)
ST21_TX2: L4160.1(A<0>) TP_NFC_ST21_TX2.1(X) U4100.A4(RFO2)
TER_MIC_BIAS: C4520.2(B<0>) C4523.2(B<0>) C4524.2(B<0>) C6242.2(B<0>) MK4520.1(VDD) U6250.G5(MICBIAS2C) VR4521.2(A1)
TER_MIC_DM: C4521.1(A<0>) C4522.1(A<0>) C6296.1(A<0>) E4520.1(POS)
TER_MIC_DP: C4521.2(B<0>) C4522.2(B<0>) C6295.1(A<0>) MK4520.2(OUTPUT) VR4520.2(A1)
TOUCH_INT_N_FL: C5319.2(B<0>) E5303.2(B) J5300.21(X<0>)
TRX_B13_50R: C7266.2(B<0>) C7267.2(B<0>) U7100.53(LB_TRX4)
TRX_B25_50R: FL7300.6(ANT) L7303.2(B<0>) R7316.1(A<0>)
TRX_B25_B34_50R: R7315.2(B<0>) R7316.2(B<0>) U7150.51(MB_TRX1)
TRX_B28_50R: L7239.1(A<0>) U7100.55(LB_TRX2)
TRX_B34_A_50R: FL7310.3(B34) R7314.2(B<0>) R7315.1(A<0>)
TRX_B34_B39_1_50R: C7312.2(B<0>) FL7310.6(B34_39) L7313.2(B<0>)
TRX_B39_50R: L7318.2(B<0>) U7150.52(MB_TRX2)
TRX_B39_A_50R: FL7310.1(B39) L7317.2(B<0>) L7318.1(A<0>)
TRX_B40_50R: C7355.2(B<0>) U7150.4(HB_TRX2)
TRX_B40_FLTIN_50R: C7351.2(B<0>) FL7350.1(UNBAL_PORT1) L7352.2(B<0>)
TRX_B40_FLTOUT_50R: C7353.1(A<0>) FL7350.4(UNBAL_PORT2)
TRX_B40_FLTOUT_MAT_50R: C7353.2(B<0>) C7355.1(A<0>) L7354.2(B<0>)
TS_I2C_SCL: C5500.2(B<0>) E5304.1(A) J5501.27(X<0>) R1036.1(A<0>) U1001.AW7(GPIO_94)
TS_I2C_SDA: C5501.2(B<0>) E5305.1(A) J5501.25(X<0>) R1035.1(A<0>) U1001.BA7(GPIO_93)
TS_INT_N: E5303.1(A) R5301.1(A<0>) U1001.AW5(GPIO_96)
TS_RST_N: C5318.2(B<0>) J5300.31(X<0>) U1001.AY6(GPIO_95)
TS_SUB_INT_N: C5502.2(B<0>) J5501.23(X<0>) R5502.1(A<0>) U1001.M42(GPIO_125)
TS_SUB_RST_N: J5501.21(X<0>) U1001.J39(GPIO_99)
TX_GSMHB_50R: FL7150.1(IN) L7131.2(B<0>) L7132.2(B<0>) L7142.2(B<0>)
TX_GSMHB_50R_1: FL7150.3(OUT) L7144.2(B<0>) U7150.49(2GHB_TX_IN)
TX_MB3_FLTIN_50R: C7165.2(B<0>) L7166.2(B<0>) U7150.31(4GMB_IN)
TX_PA_OUT_GSMHB_50R: L7130.2(B<0>) L7131.1(A<0>) U7100.8(HB_2G_TX)
TXDUP_B25_50R: FL7300.3(TX) L7302.2(B<0>)
U6290_SW: L6292.1(A<0>) U6290.B1(SW)
UFS_L0_RXN: U1001.E25(UFS_L0_RXN) U1600.P15(DOUT0_C)
UFS_L0_RXP: U1001.F24(UFS_L0_RXP) U1600.P16(DOUT0_T)
UFS_L0_TXN: U1001.F20(UFS_L0_TXN) U1600.M15(DIN0_C)
UFS_L0_TXP: U1001.E21(UFS_L0_TXP) U1600.M16(DIN0_T)
UFS_REF_CLK: U1001.E23(UFS_REF_CLK) U1600.P12(REF_CLK)
UFS_RESET: R1600.1(A<0>) U1001.E19(UFS_RESET)
UFS_RST_R: R1600.2(B<0>) U1600.M12(RST_N)
UIM1_CLK: R4216.2(B<0>) U1001.AV30(GPIO_110) U4250.8(DPOS)
UIM1_DATA: R4213.1(A<0>) R4215.2(B<0>) U1001.BA29(GPIO_109) U4250.7(DNEG)
UIM1_POWER: C4102.2(B<0>) R4218.2(B<0>) U4100.F2(VCC_UICC_OUT)
UIM1_RESET: D4250.1(NEG) J4250.2(X<0>) R4212.1(A<0>) R4217.2(B<0>) U1001.AY30(GPIO_111) VR4251.1(A2)
UIM1_SWP: R4214.2(B<0>) U4100.H1(SWP_UICC)
UIM_PRESENT: R4256.2(B<0>) U1001.AW31(GPIO_112)
UNNAMED_1_BUFFERSINGLETRISTATE5PIN_I58_Y: R1006.1(A<0>) U1005.4(Y)
UNNAMED_1_CAPACITOR_I6_B: C102.2(B<0>) R101.2(B<0>) U100.11(VIO)
UNNAMED_1_CAPACITOR_I9_B: C103.2(B<0>) R104.1(A<0>) U100.8(VDD)
UNNAMED_1_CAPACITOR_I19_B: C130.2(B<0>) J130.1(C1) L131.2(B<0>)
UNNAMED_1_CAPACITOR_I23_B: C110.2(B<0>) J110.1(C1) L111.2(B<0>)
UNNAMED_1_CAPACITOR_I44_A: C133.1(A<0>) J130.2(C2) R131.1(A<0>)
UNNAMED_1_CAPACITOR_I44_B: C133.2(B<0>) C140.1(A<0>)
UNNAMED_1_CAPACITOR_I55_B: L116.2(B<0>) U100.13(SW2_B)
UNNAMED_1_CAPACITOR_I82_A: C172.1(A<0>) L171.2(B<0>)
UNNAMED_1_CAPACITOR_I82_B: C172.2(B<0>) M100.1(X) R109.2(B<0>)
UNNAMED_1_CAPACITOR_I84_A: C112.2(B<0>) C115.1(A<0>) L113.2(B<0>) U100.2(C1_I) U100.14(SW2_A)
UNNAMED_1_CAPACITOR_I87_B: C3014.2(B<0>) R3002.1(A<0>) U3100.112(VDDD_1P8)
UNNAMED_1_CAPACITOR_I93_B: C174.2(B<0>) L177.1(A<0>)
UNNAMED_1_CAPACITOR_I100_A: C144.1(A<0>) L142.2(B<0>) L143.2(B<0>) L144.1(A<0>)
UNNAMED_1_CAPACITOR_I100_B: C124.2(B<0>) C144.2(B<0>) L124.2(B<0>) L144.2(B<0>) L170.2(B<0>) L171.1(A<0>)
UNNAMED_1_CAPACITOR_I101_A: C124.1(A<0>) L122.2(B<0>) L123.2(B<0>) L124.1(A<0>)
UNNAMED_1_CAPACITOR_I609_B: C518.2(B<0>) U519.B3(REG)
UNNAMED_1_CAPACITOR_I611_B: C517.2(B<0>) R519.2(B<0>) RT517.1(POS) U519.A1(AIN)
UNNAMED_1_COAXJACK6PIN4GND_I37_C2: C112.1(A<0>) J110.2(C2)
UNNAMED_1_INDUCTOR_I58_B: C140.2(B<0>) C141.2(B<0>) L142.1(A<0>)
UNNAMED_1_INDUCTOR_I61_B: L118.2(B<0>) U100.5(SW3)
UNNAMED_1_INDUCTOR_I62_B: L117.2(B<0>) U100.6(SW4)
UNNAMED_1_INDUCTOR_I65_B: C121.2(B<0>) L122.1(A<0>) U100.3(C1_O) U100.4(SW_C)
UNNAMED_1_INDUCTORPOLARITY_I96_A: L175.1(A<0>) R109.1(A<0>)
UNNAMED_1_MAX17050_I607_THRM: R519.1(A<0>) U519.C2(THRM)
UNNAMED_1_QAT3550_I85_SW1: C115.2(B<0>) U100.1(SW1)
UNNAMED_1_RESISTOR_I72_B: R1004.2(B<0>) U1001.AK2(REFGEN_REXT1)
UNNAMED_1_RESISTOR_I73_B: R1003.2(B<0>) U1001.AR43(REFGEN_REXT0)
UNNAMED_1_RESISTOR_I89_A: C3011.2(B<0>) C3012.2(B<0>) R3001.1(A<0>) U3100.64(VDDD_1P0_1) U3100.82(VDDD_1P0_2) U3100.118(VDDD_1P0_QLINK) U3100.142(VDDD_1P0_3)
UNNAMED_1_RESISTOR_I129_B: R5000.1(A<0>) R5001.2(B<0>) U5000.3(EN)
UNNAMED_1_RESISTOR_I874_B: R6153.2(B<0>) U6150.3(CSIO2)
UNNAMED_1_RESISTOR_I877_B: R6150.2(B<0>) U6150.8(CSIO3)
UNNAMED_1_RESISTOR_I902_B: R6155.2(B<0>) U6150.7(CSIO0)
UNNAMED_1_RESISTOR_I904_B: R6151.2(B<0>) U6150.9(CSIO4)
UNNAMED_1_RESISTOR_I905_B: R6152.2(B<0>) U6150.6(CSIO1)
UNNAMED_2_CAPACITOR_I8_B: FL7050.3(HI_FREQ) L7051.2(B<0>) R7050.1(A<0>)
UNNAMED_2_CAPACITOR_I18_B: C3102.2(B<0>) R3104.1(A<0>) U3100.114(XO_IN)
UNNAMED_2_FILTERSAW10PIN5GNDSADEN_I48_COIL1: FL7030.6(COIL1) L7031.2(B<0>)
UNNAMED_2_FILTERSAW10PIN5GNDSADEN_I48_COIL2: FL7030.7(COIL2) L7030.2(B<0>)
UNNAMED_2_FILTERSAW10PIN6GNDSADRM1G56AA0F0A_I35_INDUCTOR: FL7001.8(INDUCTOR) L7001.2(B<0>)
UNNAMED_2_P-CHANNELMOSFET3PIN1G1S_I241_D: Q1020.3(D) R1023.2(B<0>)
UNNAMED_2_RESISTOR_I75_B: R3102.2(B<0>) U3100.83(WMSS_RESETN)
UNNAMED_3_CAPACITOR_I2_B: C250.2(B<0>) J250.1(C1) L251.2(B<0>)
UNNAMED_3_CAPACITOR_I8_B: C230.2(B<0>) J230.1(C1) L231.2(B<0>)
UNNAMED_3_CAPACITOR_I14_B: C210.2(B<0>) J210.1(C1) L211.2(B<0>)
UNNAMED_3_CAPACITOR_I22_A: C233.1(A<0>) J230.2(C2) R231.1(A<0>)
UNNAMED_3_CAPACITOR_I22_B: C233.2(B<0>) C240.1(A<0>)
UNNAMED_3_CAPACITOR_I27_A: C213.1(A<0>) J210.2(C2) R211.1(A<0>)
UNNAMED_3_CAPACITOR_I27_B: C213.2(B<0>) C214.1(A<0>)
UNNAMED_3_CAPACITOR_I29_B: C214.2(B<0>) C215.1(A<0>) L214.2(B<0>) U200.2(C1_I) U200.14(SW2_A)
UNNAMED_3_CAPACITOR_I37_B: L216.2(B<0>) U200.13(SW2_B)
UNNAMED_3_CAPACITOR_I40_B: L217.2(B<0>) U200.6(SW4)
UNNAMED_3_CAPACITOR_I43_B: C260.2(B<0>) C261.2(B<0>) L262.1(A<0>)
UNNAMED_3_CAPACITOR_I46_B: C7106.2(B<0>) U7100.30(4G_VCC1)
UNNAMED_3_CAPACITOR_I47_A: C264.1(A<0>) L262.2(B<0>) L263.2(B<0>)
UNNAMED_3_CAPACITOR_I51_B: C7109.2(B<0>) R7108.2(B<0>)
UNNAMED_3_CAPACITOR_I52_A: C240.2(B<0>) C241.2(B<0>) L242.1(A<0>)
UNNAMED_3_CAPACITOR_I56_B: C221.2(B<0>) L222.1(A<0>) U200.3(C1_O) U200.4(SW_C)
UNNAMED_3_CAPACITOR_I59_B: C244.1(A<0>) L242.2(B<0>) L243.2(B<0>) L244.1(A<0>)
UNNAMED_3_CAPACITOR_I62_B: L3201.2(B<0>) R3201.2(B<0>) R3202.1(A<0>)
UNNAMED_3_CAPACITOR_I76_B: C202.2(B<0>) R201.2(B<0>) U200.11(VIO) U200.12(USID)
UNNAMED_3_CAPACITOR_I78_B: C203.2(B<0>) R204.1(A<0>) U200.8(VDD)
UNNAMED_3_CAPACITOR_I82_B: C7141.2(B<0>) FL7141.3(OUT)
UNNAMED_3_CAPACITOR_I83_A: C272.1(A<0>) L271.2(B<0>)
UNNAMED_3_CAPACITOR_I83_B: C272.2(B<0>) M200.1(X) R215.2(B<0>)
UNNAMED_3_CAPACITOR_I93_A: C7126.1(A<0>) L7127.2(B<0>)
UNNAMED_3_CAPACITOR_I93_B: C275.2(B<0>) L279.1(A<0>)
UNNAMED_3_CAPACITOR_I100_A: C224.1(A<0>) L222.2(B<0>) L223.2(B<0>) L224.1(A<0>)
UNNAMED_3_CAPACITOR_I100_B: C224.2(B<0>) C244.2(B<0>) C264.2(B<0>) L224.2(B<0>) L244.2(B<0>) L270.2(B<0>) L271.1(A<0>)
UNNAMED_3_CAPACITOR_I106_A: C281.1(A<0>) R280.2(B<0>) TP_REF_CSNS_CS3.1(X)
UNNAMED_3_CAPACITOR_I158_B: C4084.2(B<0>) R4084.1(A<0>) U4080.3(VCC2)
UNNAMED_3_CAPACITOR_I167_B: C4094.2(B<0>) R4085.1(A<0>) U4090.3(VCC2)
UNNAMED_3_COAXJACK6PIN4GND_I6_C2: C260.1(A<0>) J250.2(C2)
UNNAMED_3_INDUCTOR_I53_B: L218.2(B<0>) U200.5(SW3)
UNNAMED_3_INDUCTORPOLARITY_I95_A: L277.1(A<0>) R215.1(A<0>)
UNNAMED_3_QAT3550_I38_SW1: C215.2(B<0>) U200.1(SW1)
UNNAMED_3_RESISTOR_I32_B: R3301.2(B<0>) U3100.68(TX_FBRX_M)
UNNAMED_3_RESISTOR_I61_A: R3201.1(A<0>) U3100.26(TX_CH0_HB1)
UNNAMED_3_RESISTOR_I215_B: R4010.2(B<0>) U4000.32(WP_IF)
UNNAMED_5_128GBEMMC48GBLPDDR4254PINH9HQ16AECMMDAR_I204_VDDIQ1: C1632.2(B<0>) U1600.T17(VDDIQ1)
UNNAMED_5_128GBEMMC48GBLPDDR4254PINH9HQ16AECMMDAR_I204_VDDIQ2: C1633.2(B<0>) U1600.K17(VDDIQ2)
UNNAMED_5_128GBEMMC48GBLPDDR4254PINH9HQ16AECMMDAR_I204_ZQ0: R1603.2(B<0>) U1600.B16(ZQ0)
UNNAMED_5_128GBEMMC48GBLPDDR4254PINH9HQ16AECMMDAR_I204_ZQ1: R1605.2(B<0>) U1600.C16(ZQ1)
UNNAMED_5_CAPACITOR_I3_B: C400.2(B<0>) J400.1(C1) L401.2(B<0>) R400.1(A<0>)
UNNAMED_5_CAPACITOR_I3_B_1: C7335.2(B<0>) L7335.1(A<0>)
UNNAMED_5_CAPACITOR_I6_B: C7330.2(B<0>) L7332.1(A<0>)
UNNAMED_5_CAPACITOR_I8_B: C300.2(B<0>) J300.1(C1) L301.2(B<0>) R300.1(A<0>)
UNNAMED_5_CAPACITOR_I16_B: C402.2(B<0>) C403.2(B<0>) L404.1(A<0>)
UNNAMED_5_CAPACITOR_I22_B: C406.1(A<0>) L404.2(B<0>) L405.2(B<0>)
UNNAMED_5_CAPACITOR_I29_A: C305.1(A<0>) L304.2(B<0>) L305.2(B<0>)
UNNAMED_5_CAPACITOR_I31_B: C7327.2(B<0>) L7329.1(A<0>)
UNNAMED_5_CAPACITOR_I37_B: C7332.2(B<0>) L7334.1(A<0>)
UNNAMED_5_CAPACITOR_I178_A: C7371.1(A<0>) C7390.1(A<0>) L7371.1(A<0>)
UNNAMED_5_CAPACITOR_I181_A: C7376.1(A<0>) C7389.1(A<0>) L7368.1(A<0>)
UNNAMED_5_CAPACITOR_I193_A: C7369.1(A<0>) L7367.1(A<0>)
UNNAMED_5_CAPACITOR_I204_A: C7385.1(A<0>) L7328.1(A<0>) L7329.2(B<0>)
UNNAMED_5_CAPACITOR_I205_A: C7386.1(A<0>) L7331.1(A<0>) L7332.2(B<0>)
UNNAMED_5_CAPACITOR_I206_A: C7387.1(A<0>) L7333.1(A<0>) L7334.2(B<0>)
UNNAMED_5_CAPACITOR_I207_A: C7388.1(A<0>) L7335.2(B<0>) L7336.1(A<0>)
UNNAMED_5_COAXJACK6PIN4GND_I7_C2: C402.1(A<0>) J400.2(C2) R400.2(B<0>)
UNNAMED_5_COAXJACK6PIN4GND_I12_C2: C303.2(B<0>) J300.2(C2) L304.1(A<0>) R300.2(B<0>)
UNNAMED_5_CONTACT1PIN_I25_X: C406.2(B<0>) M400.1(X)
UNNAMED_5_CONTACT1PIN_I30_X: C305.2(B<0>) M300.1(X)
UNNAMED_5_LDC0851_I24_ADJ: R6180.1(A<0>) R6181.2(B<0>) U6180.4(ADJ)
UNNAMED_5_LDC0851_I24_EN: R6182.1(A<0>) U6180.6(EN)
UNNAMED_7_CAPACITOR_I143_A: C7215.1(A<0>) U7216.B1(OUT1)
UNNAMED_7_CAPACITOR_I152_A: C7270.1(A<0>) U7216.H1(OUT2)
UNNAMED_7_CAPACITOR_I226_B: C7218.2(B<0>) C7219.2(B<0>) R7200.1(A<0>) U7216.D1(VDD_1P8)
UNNAMED_7_CAPACITOR_I230_B: C7273.2(B<0>) C7274.2(B<0>) R7201.1(A<0>) U7216.C2(VDD_1P2)
UNNAMED_7_INDUCTOR_I254_A: L7219.1(A<0>) U7216.D5(LNA1_IN)
UNNAMED_7_INDUCTOR_I256_A: L7274.1(A<0>) U7216.E6(LNA2_IN)
UNNAMED_9_AW8690_I72_DVDD: C4600.2(B<0>) U4600.G3(DVDD)
UNNAMED_9_AW8690_I72_PVDD1: C4604.2(B<0>) C4605.2(B<0>) U4600.A7(PVDD1) U4600.B7(PVDD2) U4600.C7(PVDD3) U4600.E7(VBST1) U4600.F7(VBST2) U4600.G7(VBST3)
UNNAMED_9_AW8690_I72_SW1: L4600.1(A<0>) U4600.E6(SW1) U4600.F6(SW2) U4600.G6(SW3)
UNNAMED_9_AW8690_I72_TRIG1: R4615.2(B<0>) U4600.B1(TRIG1) U4600.C2(TRIG2) U4600.E2(TRIG3)
UNNAMED_10_CAPACITOR_I73_A: C6406.1(A<0>) U6400.D5(LDO_FILT_P)
UNNAMED_10_CS35L41_I10_OUTN: L6402.1(A<0>) U6400.C2(OUT_N)
UNNAMED_10_CS35L41_I10_OUTP: L6401.1(A<0>) U6400.D2(OUT_P)
UNNAMED_10_CS35L41_I10_SW1: L6400.2(B<0>) U6400.A2(SW1) U6400.B2(SW2)
UNNAMED_12_BGA7L1N6_I14_PON: R8510.2(B<0>) U8501.6(PON)
UNNAMED_12_CAPACITOR_I29_B: L8516.2(B<0>) L8519.1(A<0>)
UNNAMED_12_CAPACITOR_I67_B: C2403.2(B<0>) U2000.14(BOOT_PWR)
UNNAMED_12_CAPACITOR_I88_A: C2402.1(A<0>) L2400.1(A<0>) U2000.34(VSW_CHG_1) U2000.35(VSW_CHG_2) U2000.45(VSW_CHG_3) U2000.46(VSW_CHG_4)
UNNAMED_12_CAPACITOR_I88_B: C2402.2(B<0>) U2000.36(BOOT_CAP)
UNNAMED_12_CAPACITOR_I91_B: C2407.2(B<0>) U2000.123(VREG_FG)
UNNAMED_12_CAPACITOR_I92_B: C2408.2(B<0>) U2000.112(VARB)
UNNAMED_12_INDUCTOR_I19_B: L2270.2(B<0>) U2210.B1(SW1) U2210.B2(SW2)
UNNAMED_12_NCP3902FCCTBG_I133_RXN: R2418.2(B<0>) U2401.D5(RX_N)
UNNAMED_12_PM670_I87_BATTID: R2406.2(B<0>) U2000.113(BATT_ID)
UNNAMED_13_CAPACITOR_I12_B: C8200.2(B<0>) C8201.2(B<0>) E8200.1(A) U8200.5(VDD_AMP)
UNNAMED_13_CAPACITOR_I13_B: C2421.2(B<0>) U2400.48(AVDD_BYP)
UNNAMED_13_CAPACITOR_I15_B: C8202.2(B<0>) C8204.2(B<0>) E8200.2(B) U8200.30(VOUT_BOB) U8200.32(VBOB_SW)
UNNAMED_13_CAPACITOR_I15_B_2: C2420.2(B<0>) U2400.60(REF_BYP)
UNNAMED_13_CAPACITOR_I33_B: C8208.2(B<0>) R8201.1(A<0>)
UNNAMED_13_INDUCTOR_I40_A: L8200.1(A<0>) U8200.26(VSW2_BOB)
UNNAMED_13_INDUCTOR_I40_B: L8200.2(B<0>) U8200.21(VSW1_BOB)
UNNAMED_13_INDUCTOR_I41_A: L8201.1(A<0>) U8200.28(VSW1) U8200.29(VSW2)
UNNAMED_14_CAPACITOR_I36_A: C4063.1(A<0>) FL4060.4(UNBAL_PORT2) L4062.2(B<0>)
UNNAMED_14_CAPACITOR_I64_A: C4077.1(A<0>) L4076.2(B<0>) U4070.1(MAIN_OUT)
UNNAMED_14_CAPACITOR_I66_A: C4047.1(A<0>) L4046.2(B<0>) U4040.1(MAIN_OUT)
UNNAMED_14_CAPACITOR_I74_A: C4067.1(A<0>) L4066.2(B<0>) U4060.1(MAIN_OUT)
UNNAMED_14_CAPACITOR_I76_A: C4057.1(A<0>) L4056.2(B<0>) U4050.1(MAIN_OUT)
UNNAMED_14_COUPLER4PINLDJ0Q2G4519CH050_I39_TERMINATE: R4074.2(B<0>) U4070.4(TERMINATE)
UNNAMED_14_COUPLER4PINLDJ0Q2G4519CH050_I42_COUPLEDOUT: R4045.1(A<0>) U4040.3(COUPLED_OUT)
UNNAMED_14_COUPLER4PINLDJ0Q2G4519CH050_I42_TERMINATE: R4044.2(B<0>) U4040.4(TERMINATE)
UNNAMED_14_COUPLER4PINLDJ0Q2G4519CH050_I51_COUPLEDOUT: R4065.1(A<0>) U4060.3(COUPLED_OUT)
UNNAMED_14_COUPLER4PINLDJ0Q2G4519CH050_I51_TERMINATE: R4064.2(B<0>) U4060.4(TERMINATE)
UNNAMED_14_COUPLER4PINLDJ0Q2G4519CH050_I53_COUPLEDOUT: R4055.1(A<0>) U4050.3(COUPLED_OUT)
UNNAMED_14_COUPLER4PINLDJ0Q2G4519CH050_I53_TERMINATE: R4054.2(B<0>) U4050.4(TERMINATE)
UNNAMED_14_FAN53526_I103_SW1: L2560.1(A<0>) U2560.A2(SW1) U2560.B2(SW2)
UNNAMED_14_FAN53526_I131_SW1: L2570.1(A<0>) U2570.A2(SW1) U2570.B2(SW2)
UNNAMED_15_CAPACITOR_I12_A: L7832.1(A<0>) L7834.1(A<0>)
UNNAMED_15_CAPACITOR_I34_A: C7823.1(A<0>) C7824.1(A<0>)
UNNAMED_15_CAPACITOR_I124_B: C7822.2(B<0>) FL7820.1(UNBAL_PORT1) L7821.2(B<0>)
UNNAMED_15_CAPACITOR_I129_B: C7823.2(B<0>) C7896.2(B<0>) L7825.1(A<0>)
UNNAMED_15_CAPACITOR_I130_B: C7835.1(A<0>) C7895.2(B<0>) L7832.2(B<0>)
UNNAMED_19_CAPACITOR_I59_A: C2001.1(A<0>) E2001.1(POS) U2000.169(GND_REF)
UNNAMED_19_CAPACITOR_I59_B: C2001.2(B<0>) U2000.180(REF_BYP)
UNNAMED_19_CAPACITOR_I67_A: C2108.1(A<0>) U2000.64(VCOIN)
UNNAMED_19_CAPACITOR_I122_B: C2018.2(B<0>) Q2031.1(G) R2017.2(B<0>) R2018.2(B<0>)
UNNAMED_19_CAPACITOR_I137_B: C2020.2(B<0>) Q2032.1(G) R2019.2(B<0>) R2020.2(B<0>)
UNNAMED_20_CAPACITOR_I169_B: C4131.2(B<0>) U4100.B8(VDD_A)
UNNAMED_20_CAPACITOR_I171_B: C4130.2(B<0>) U4100.B6(VDD_ASK)
UNNAMED_20_CAPACITOR_I206_B: C4115.2(B<0>) U4100.C5(AGD)
UNNAMED_20_CAPACITOR_I208_B: C4110.2(B<0>) U4100.A5(VDD_DR) U4100.B7(VDD_RF)
UNNAMED_20_CAPACITOR_I233_B: C4154.1(A<0>) C4155.1(A<0>) C4162.1(A<0>) C4163.1(A<0>) C4166.2(B<0>) C4167.2(B<0>) R4155.1(A<0>) R4160.2(B<0>) R4162.1(A<0>)
UNNAMED_20_CAPACITOR_I242_B: C4152.1(A<0>) C4153.1(A<0>) C4154.2(B<0>) C4155.2(B<0>) C4156.2(B<0>) C4157.2(B<0>) R4150.2(B<0>) R4152.1(A<0>) R4155.2(B<0>)
UNNAMED_20_CAPACITOR_I245_A: C4161.1(A<0>) C4162.2(B<0>) C4163.2(B<0>) L4160.2(B<0>) R4161.2(B<0>)
UNNAMED_20_CAPACITOR_I251_B: C4151.2(B<0>) C4152.2(B<0>) C4153.2(B<0>) L4150.2(B<0>) R4151.2(B<0>)
UNNAMED_20_INDUCTOR_I230_B: L4120.2(B<0>) U4120.B1(SW1) U4120.B2(SW2)
UNNAMED_20_RESISTOR_I244_B: C4169.2(B<0>) R4160.1(A<0>) R4161.1(A<0>)
UNNAMED_20_RESISTOR_I252_B: C4159.2(B<0>) R4150.1(A<0>) R4151.1(A<0>)
UNNAMED_20_ST21NFCD_I157_GPIORF1: TP4101.1(X) U4100.D1(GPIO_RF1)
UNNAMED_20_ST21NFCD_I157_GPIORF2: TP4102.1(X) U4100.D2(GPIO_RF2)
UNNAMED_21_CAPACITOR_I17_B: C6295.2(B<0>) U6250.D2(IN2RP)
UNNAMED_21_CAPACITOR_I18_B: C6245.2(B<0>) U6250.A5(MICVDD)
UNNAMED_21_CAPACITOR_I20_B: C6296.2(B<0>) U6250.B2(IN2RN)
UNNAMED_21_CAPACITOR_I52_B: C6290.2(B<0>) U6250.J3(IN2ALN)
UNNAMED_21_CAPACITOR_I53_B: C6289.2(B<0>) U6250.H2(IN2ALP)
UNNAMED_21_CAPACITOR_I54_B: C6277.2(B<0>) U6250.A3(IN1ARN)
UNNAMED_21_CAPACITOR_I55_B: C6276.2(B<0>) U6250.C3(IN1ARP)
UNNAMED_21_CAPACITOR_I56_B: C6273.2(B<0>) U6250.G3(IN1ALN)
UNNAMED_21_CAPACITOR_I57_B: C6272.2(B<0>) U6250.E3(IN1ALP)
UNNAMED_21_CAPACITOR_I132_B: C6286.2(B<0>) U6250.H8(CP2CB)
UNNAMED_21_CAPACITOR_I219_B: C6274.2(B<0>) U6250.D4(IN1BRP)
UNNAMED_21_CAPACITOR_I221_B: C6275.2(B<0>) U6250.B4(IN1BRN)
UNNAMED_21_RESISTOR_I213_A: R6263.1(A<0>) U6250.D14(HPDET1)
UNNAMED_21_RESISTOR_I215_A: R6264.1(A<0>) U6250.C13(HPDET2)
UNNAMED_21_TESTPOINT_I128_X: TP_PDMCLK.1(X) U6250.W9(SPKCLK/GPIO37)
UNNAMED_23_CAPACITOR_I30_A: C7613.1(A<0>) L7612.1(A<0>)
UNNAMED_23_CAPACITOR_I78_A: C7605.2(B<0>) C7608.1(A<0>)
UNNAMED_23_CAPACITOR_I79_A: C7602.1(A<0>) C7607.1(A<0>)
UNNAMED_23_CAPACITOR_I90_A: C7615.1(A<0>) C7617.1(A<0>)
UNNAMED_23_CAPACITOR_I96_A: C7644.1(A<0>) FL7600.6(UNBAL_PORT_HCH) L7647.2(B<0>)
UNNAMED_23_CAPACITOR_I97_B: C7605.1(A<0>) C7606.1(A<0>) C7645.2(B<0>)
UNNAMED_23_CAPACITOR_I98_A: C7646.1(A<0>) FL7610.6(UNBAL_PORT_HCH) L7630.2(B<0>)
UNNAMED_23_CAPACITOR_I99_A: C7647.1(A<0>) FL7610.9(UNBAL_PORT_LCH) L7631.2(B<0>)
UNNAMED_23_CAPACITOR_I100_B: C7625.2(B<0>) C7648.2(B<0>) L7626.1(A<0>)
UNNAMED_24_CAPACITOR_I130_B: C7767.2(B<0>) C7768.2(B<0>) R7731.1(A<0>) U7701.C2(VDD_1P2)
UNNAMED_24_CAPACITOR_I146_A: C7751.1(A<0>) U7701.H1(OUT2)
UNNAMED_24_CAPACITOR_I147_A: C7750.1(A<0>) U7701.B1(OUT1)
UNNAMED_24_CAPACITOR_I151_B: C7753.2(B<0>) C7755.2(B<0>) R7730.1(A<0>) U7701.D1(VDD_1P8) U7701.E2(ID0)
UNNAMED_24_CAPACITOR_I157_B: C7761.2(B<0>) L7708.2(B<0>) U7701.G6(LB2_SW_OUT)
UNNAMED_24_CAPACITOR_I159_B: C7760.2(B<0>) L7703.2(B<0>) U7701.C6(LB1_SW_OUT)
UNNAMED_24_INDUCTOR_I148_A: L7708.1(A<0>) U7701.E6(LNA2_IN)
UNNAMED_24_INDUCTOR_I153_A: L7703.1(A<0>) U7701.D5(LNA1_IN)
UNNAMED_27_CAPACITOR_I33_B: C7155.2(B<0>) R7153.2(B<0>)
UNNAMED_27_CAPACITOR_I39_B: C7157.2(B<0>) R7156.2(B<0>)
UNNAMED_27_CAPACITOR_I115_A: C7182.1(A<0>) L7183.2(B<0>)
UNNAMED_28_INDUCTOR_I23_A: L2503.1(A<0>) U2400.22(VSW_DISP_M_1) U2400.33(VSW_DISP_M_2)
UNNAMED_28_INDUCTOR_I29_A: L2502.1(A<0>) U2400.77(VSW_DISP_P)
UNNAMED_28_INDUCTOR_I42_A: L2501.1(A<0>) U2400.121(VSW_OLEDB)
USB_AUD_SW_SEL: R520.2(B<0>) U520.5(A_LP_SEL) U1001.AV34(GPIO_50)
USB_AUDIO_DET_N: U1001.AV8(GPIO_92) U6250.D12(JACKDET1)
USB_EN: TP_USB_OVP_EN.1(X) U2000.100(USB_EN) U2401.D4(EN_N)
USB_HPOUT1L: R6263.2(B<0>) U520.3(L) U6250.A15(HPOUT1L)
USB_HPOUT1R: R6264.2(B<0>) U520.2(R) U6250.B14(HPOUT1R)
USB_HS_C_DM: FL500.4(P1) U520.6(D_N_L)
USB_HS_C_DP: FL500.3(P2) U520.7(D_P_R)
USB_HS_DM: R2402.1(A<0>) U520.1(D_N) U1001.AV38(USB_HS_DN)
USB_HS_DM_DET: R2402.2(B<0>) U2000.60(USB_DM)
USB_HS_DP: R2401.1(A<0>) U520.10(D_P) U1001.AU37(USB_HS_DP)
USB_HS_DP_DET: R2401.2(B<0>) U2000.49(USB_DP)
USB_IN_MID: C2412.2(B<0>) C2422.2(B<0>) U2000.56(USB_IN_MID_1) U2000.57(USB_IN_MID_2) U2000.67(USB_IN_MID_3) U2000.68(USB_IN_MID_4)
USB_MIC_DM: C6275.1(A<0>) D505.2(IO2) Q6268.3(D2A) Q6268.8(D2B) R6267.1(A<0>) U500.3(SBU1) U6250.E13(MICDET2/HPOUTFB2)
USB_MIC_DP: C6274.1(A<0>) D506.2(IO2) Q6268.6(D1A) Q6268.7(D1B) R6266.1(A<0>) U500.8(SBU2) U6250.F14(MICDET1/HPOUTFB1)
USB_PHY_PS: U1001.AT32(GPIO_38) U2000.39(CC_OUT)
USB_PWR: C502.2(B<0>) C2432.2(B<0>) C2433.2(B<0>) E500.2(B) U2401.A1(USBIN1) U2401.A2(USBIN2) U2401.A3(USBIN3) U2401.A4(USBIN4) U2401.A5(USBIN5) U2401.B1(USBIN6) U2401.B2(USBIN7) U2401.B3(USBIN8)
USB_SNS: C2418.2(B<0>) U2000.101(USB_SNS) U2401.C5(USB_SNS)
USB_VBUS_CONN: C501.2(B<0>) C503.2(B<0>) C504.2(B<0>) D500.3(K) D513.1(NEG) E500.1(A) R500.2(B<0>) U500.2(VBUS1) U500.4(VBUS2) U500.7(VBUS3) U500.9(VBUS4)
USB_VBUS_IN: C2400.2(B<0>) C2430.2(B<0>) C2431.2(B<0>) C2434.2(B<0>) U2000.78(USB_IN_1) U2000.79(USB_IN_2) U2000.88(USB_IN_3) U2000.89(USB_IN_4) U2401.C1(OUT1) U2401.C2(OUT2) U2401.D1(OUT3) U2401.D2(OUT4) U2401.D3(OUT5)
USBC_CC1: C522.2(B<0>) D516.2(K2) U500.6(CC1) U2000.5(CC1_ID)
USBC_CC2: C523.2(B<0>) D517.2(K2) U500.10(CC2) U2000.27(CC2)
USBC_DM: D511.2(IO2) FL500.1(S1) U500.13(HSDM)
USBC_DP: D512.2(IO2) FL500.2(S2) U500.18(HSDP)
USBC_RX1_DM: C512.2(B<0>) U1001.AY36(USB_SS_RX0_N)
USBC_RX1_DP: C509.2(B<0>) U1001.AW35(USB_SS_RX0_P)
USBC_RX2_DM: C514.2(B<0>) U1001.AV40(USB_SS_RX1_N)
USBC_RX2_DP: C513.2(B<0>) U1001.AW41(USB_SS_RX1_P)
USBC_TX1_DM: C506.2(B<0>) U1001.AW37(USB_SS_TX0_N)
USBC_TX1_DP: C505.2(B<0>) U1001.AV36(USB_SS_TX0_P)
USBC_TX2_DM: C508.2(B<0>) U1001.AW39(USB_SS_TX1_N)
USBC_TX2_DP: C507.2(B<0>) U1001.AY40(USB_SS_TX1_P)
VCONN_EN: R2410.2(B<0>) U2000.61(VCONN_EN) U2210.B3(EN)
VCONN_IN: C2279.2(B<0>) C2281.2(B<0>) C2295.2(B<0>) C2296.2(B<0>) C2410.2(B<0>) U2000.17(VCONN_IN) U2210.A1(VOUT1) U2210.A2(VOUT2)
VDISP_M_OUT: C2505.2(B<0>) C5374.2(B<0>) J5300.34(X<0>) J5300.36(X<0>) J5300.38(X<0>) U2400.32(VDISP_M_FB) U2400.44(VDISP_M_OUT)
VDISP_P_MID: C2503.2(B<0>) U2400.87(VDISP_LDO_IN) U2400.88(VDISP_P_MID)
VDISP_P_OUT: C2506.2(B<0>) C5382.2(B<0>) J5300.42(X<0>) J5300.44(X<0>) J5300.46(X<0>) U2400.55(VDISP_P_FB) U2400.99(VDISP_P_OUT)
VPA_APT: C7107.2(B<0>) C7154.2(B<0>) C7158.2(B<0>) L8201.2(B<0>) R7108.1(A<0>) R7153.1(A<0>) R7156.1(A<0>) R8201.2(B<0>) U7100.32(4G_VCC2) U7150.16(4GHB_VCC) U7150.35(4GMB_VCC) U8200.4(VAMP) U8200.6(APT_CAP_SW1) U8200.7(APT_CAP_SW2) U8200.8(BUCKIND_IN1) U8200.9(BUCKIND_IN2)
VPA_APT_GSM: C7103.2(B<0>) C7104.2(B<0>) C7105.2(B<0>) C8209.2(B<0>) U7100.15(2G_VCC1) U7100.16(2G_VCC2) U8200.1(APT_CAP1) U8200.2(APT_CAP2) U8200.18(VOUT_LDO)
VREF_MSM: C1080.2(B<0>) U1001.AG23(VDD_QREFS_1P25) U1001.AR29(VREF_UIM) U2000.151(VREF_MSM)
VREFC: C6266.2(B<0>) U6250.G1(VREFC)
VREG_BOB: C520.2(B<0>) C521.2(B<0>) C2332.2(B<0>) C2451.2(B<0>) C2452.2(B<0>) C2453.2(B<0>) U520.8(USB_SEL) U520.9(VCC) U2000.132(VDD_L15_16_17_18_19) U2000.140(VREG_BOB) U2400.4(VDD_FLASH_2) U2400.20(VREG_BOB_1) U2400.25(VDD_L2) U2400.26(VDD_FLASH_1) U2400.41(VREG_BOB_SNS) U2400.42(VREG_BOB_2) U2400.62(VDD_L4_6) U2400.73(VDD_RGB) U2400.112(VDD_L3_5_7_8_1) U2400.142(VDD_L3_5_7_8_2)
VREG_DISP_1P8: C5002.2(B<0>) C5306.2(B<0>) C5307.2(B<0>) C5508.2(B<0>) J5300.29(X<0>) J5501.4(X<0>) R1035.2(B<0>) R1036.2(B<0>) R5301.2(B<0>) R5502.2(B<0>) U1001.AP34(VDD_P6) U5000.1(OUT) U5300.A2(VIN)
VREG_L1A_1P2: C1095.2(B<0>) C1096.2(B<0>) C1097.2(B<0>) C1155.2(B<0>) C1159.2(B<0>) C2340.2(B<0>) U1001.AA9(VDD_MIPI_CSI0_1P2) U1001.AB8(VDD_MIPI_CSI1_1P2) U1001.AC7(VDD_MIPI_CSI2_1P2) U1001.AH34(VDD_USB_SS_1P2) U1001.H24(VDD_UFS_1P2) U1001.K24(VDD_P10) U1001.L23(VDD_EBI_PHY_HV) U1001.Y34(VDD_MIPI_DSI1_1P2) U1001.Y36(VDD_MIPI_DSI0_1P2) U2000.205(VREG_L1)
VREG_L1B_0P88: C1090.2(B<0>) C1091.2(B<0>) C1092.2(B<0>) C1093.2(B<0>) C1094.2(B<0>) C1154.2(B<0>) C1156.2(B<0>) C1157.2(B<0>) C2370.2(B<0>) U1001.AA11(VDD_MIPI_CSI0_0P9) U1001.AB10(VDD_MIPI_CSI1_0P9) U1001.AD8(VDD_MIPI_CSI2_0P9) U1001.AK34(VDD_USB_SS_CORE) U1001.AK36(VDD_USB_HS_CORE) U1001.AR23(VDD_QLINK) U1001.AR25(VDD_QLINK_CK) U1001.AT24(VDD_QREFS_0P9) U1001.H26(VDD_EBI_PLL) U1001.H28(VDD_UFS_CORE) U1001.R35(VDD_MIPI_DSI0_PLL) U1001.T34(VDD_MIPI_DSI1_0P9) U1001.T36(VDD_MIPI_DSI0_0P9) U1001.U35(VDD_MIPI_DSI1_PLL) U2400.14(VREG_L1)
VREG_L2A_1P0_SDR_AVDD: C2339.2(B<0>) C3001.2(B<0>) C3002.1(A<0>) C3016.1(A<0>) C3121.2(B<0>) C3122.2(B<0>) C3123.2(B<0>) C3124.2(B<0>) C3125.2(B<0>) U2000.187(VREG_L2) U3100.3(VDDA_1P0_TX0) U3100.13(VDDA_1P0_TX0_1) U3100.37(VDDA_1P0_RX2_2) U3100.43(VDDA_1P0_RX2_3) U3100.53(VDDA_1P0_RX2_1) U3100.77(VDDA_1P0_RX1) U3100.95(VDDA_1P0_RX) U3100.107(VDDA_1P0_XO) U3100.132(VDDA_1P0_RX0_1) U3100.144(VDDA_1P0_TX1) U3100.146(VDDA_1P0_GNSS) U3100.154(VDDA_1P0_RX0)
VREG_L2B_SDC2: C2371.2(B<0>) U2400.36(VREG_L2)
VREG_L3A_1P0_SDR_DVDD: C2337.2(B<0>) C3013.2(B<0>) R3001.2(B<0>) U2000.176(VREG_L3)
VREG_L3B_3P0: C2372.2(B<0>) C5310.2(B<0>) C5311.2(B<0>) C5539.2(B<0>) J5300.27(X<0>) J5501.8(X<0>) J5501.10(X<0>) J5501.12(X<0>) R5000.2(B<0>) U2400.123(VREG_L3) U5301.A2(VIN)
VREG_L4B_2P95: C1601.2(B<0>) C1602.2(B<0>) C1603.2(B<0>) U1600.M17(VCC1) U1600.N17(VCC2) U1600.P17(VCC3) U2400.51(VREG_L4)
VREG_L5A_0P8: C1123.2(B<0>) C1132.2(B<0>) C2335.2(B<0>) U1001.L9(VDD_WCSS1) U1001.M10(VDD_WCSS2) U1001.N9(VDD_WCSS_PLL) U1001.N11(VDD_WCSS3) U2000.203(VREG_L5)
VREG_L5B_2P8: C2374.2(B<0>) C5510.2(B<0>) J5500.44(X<0>) U2400.131(VREG_L5)
VREG_L6A_1P3: C1122.2(B<0>) C2338.2(B<0>) C4001.2(B<0>) C4002.2(B<0>) C4003.2(B<0>) C4006.2(B<0>) C4007.2(B<0>) C4008.2(B<0>) C4009.2(B<0>) C4010.2(B<0>) C4011.2(B<0>) R4002.1(A<0>) R4003.1(A<0>) U1001.K8(VDD_WCSS_ADCDAC1) U1001.M8(VDD_WCSS_ADCDAC2) U2000.215(VREG_L6) U4000.1(VDD13_BT_CH2) U4000.8(VDD13_FM) U4000.11(VDD13_BT_BB) U4000.12(VDD13_BT_SYNTH) U4000.18(VDD13_BT_FM_BBPLL) U4000.27(VDD13_WL_CH0) U4000.66(VDD13_PM) U4000.84(VDD13_WL_CH1)
VREG_L6B_3P3: C2375.2(B<0>) C6150.2(B<0>) C6151.2(B<0>) C6152.2(B<0>) C6180.2(B<0>) C6184.2(B<0>) R6180.2(B<0>) U2400.52(VREG_L6) U6150.4(VDD) U6180.8(VDD) U6182.B2(VCCB)
VREG_L7A_1P2_RF: C2336.2(B<0>) C3007.2(B<0>) C3008.2(B<0>) C3009.2(B<0>) C3010.2(B<0>) C3018.2(B<0>) R7201.2(B<0>) R7731.2(B<0>) U2000.216(VREG_L7) U3100.29(VDDA_1P2_TX0) U3100.70(VDDA_1P2_RX2) U3100.75(VDDA_1P2_ANA0_1) U3100.85(VDDA_1P2_FBRX) U3100.90(VDDA_1P2_ANA0_2) U3100.108(VDDA_1P2_RX1) U3100.123(VDDA_1P2_RX0_1) U3100.130(VDDA_1P2_RX0_3) U3100.137(VDDA_1P2_RX0_2)
VREG_L7B_3P125: C1105.2(B<0>) C1164.2(B<0>) C2003.2(B<0>) C2398.2(B<0>) U1001.AH36(VDD_USB_HS_3P1) U2000.72(VDD_PDPHY) U2400.143(VREG_L7)
VREG_L8A_1P8: C1604.2(B<0>) C1605.2(B<0>) C1606.2(B<0>) C1615.2(B<0>) C2380.2(B<0>) U1600.J15(VCCQ2_1) U1600.J16(VCCQ2_2) U1600.J17(VCCQ2_3) U1600.K15(VCCQ2_4) U1600.R13(VCCQ1) U1600.R14(VCCQ2) U1600.T15(VCCQ3) U1600.T16(VCCQ4) U2000.202(VREG_L8)
VREG_L8B_3P3: C2376.2(B<0>) C4017.2(B<0>) C4018.2(B<0>) C4019.2(B<0>) C4020.2(B<0>) C4092.2(B<0>) C4093.2(B<0>) C4095.1(A<0>) R4085.2(B<0>) U2400.122(VREG_L8) U4000.86(VDD33_WL_CH1) U4000.92(VDD33_WL_DRV_CH1) U4090.2(VCC1) U4090.8(VCC3)
VREG_L9A_1P8: C2381.2(B<0>) C4014.2(B<0>) C4015.2(B<0>) C4016.2(B<0>) U2000.192(VREG_L9) U4000.40(VDD18_XTAL) U4000.91(VDD18_VCO_CH1)
VREG_L9B_0P8: C1133.1(IN) C1133.3(OUT) C2397.2(B<0>) U1001.AD34(VDD_LPI_CORE1) U1001.AF34(VDD_LPI_CORE2) U2400.35(VREG_L9)
VREG_L10A_1P8: C1103.2(B<0>) C1104.2(B<0>) C2333.2(B<0>) R1033.2(B<0>) U1001.AE21(VDD_QFPROM) U1001.AF22(VDD_QREFS_1P8) U1001.AH22(VDD_APC_CS_1P8) U1001.AL37(VDD_P11) U1001.AM38(VDD_USB_HS_1P8) U2000.190(VREG_L10)
VREG_L10B_0P8: C1077.2(B<0>) C2377.2(B<0>) U1001.AH32(VDD_LPI_MEM) U2400.13(VREG_L10)
VREG_L11A_1P8: C2352.2(B<0>) U2000.178(VREG_L11)
VREG_L12A_1P8: C2353.2(B<0>) C3003.2(B<0>) C3004.2(B<0>) C3005.2(B<0>) C3006.2(B<0>) R8500.1(A<0>) U2000.201(VREG_L12) U3100.11(VDDA_1P8_TX0) U3100.35(VDDA_1P8_ANA1) U3100.50(VDDA_1P8_FBRX_1) U3100.59(VDDA_1P8_FBRX_2) U3100.69(VDDA_1P8_RX2) U3100.121(VDDA_1P8_ANA2_1) U3100.122(VDDA_1P8_ANA2_2) U3100.152(VDDA_1P8_TX1)
VREG_L13A_1P8: C100.2(B<0>) C200.2(B<0>) C1005.1(A<0>) C1098.2(B<0>) C1099.2(B<0>) C1100.2(B<0>) C1101.2(B<0>) C1102.2(B<0>) C1607.2(B<0>) C1608.2(B<0>) C1609.2(B<0>) C1610.2(B<0>) C2334.2(B<0>) C2512.2(B<0>) C3015.2(B<0>) C4012.2(B<0>) C4013.2(B<0>) C4105.2(B<0>) C4618.2(B<0>) C5504.2(B<0>) C6265.2(B<0>) C6267.2(B<0>) C6268.2(B<0>) C6269.2(B<0>) C6270.2(B<0>) C6271.2(B<0>) C6407.2(B<0>) C7100.2(B<0>) C7151.2(B<0>) C7160.2(B<0>) C7501.2(B<0>) C7510.2(B<0>) C7520.2(B<0>) C7701.2(B<0>) C8206.2(B<0>) J5501.16(X<0>) JTAG.10(X<0>) Q1020.2(S) R101.1(A<0>) R130.2(B<0>) R201.1(A<0>) R210.2(B<0>) R230.2(B<0>) R1005.2(B<0>) R1007.1(A<0>) R1021.2(B<0>) R1031.2(B<0>) R1032.2(B<0>) R1037.2(B<0>) R1038.2(B<0>) R1039.2(B<0>) R1040.2(B<0>) R1050.2(B<0>) R1051.2(B<0>) R1127.2(B<0>) R1128.2(B<0>) R3002.2(B<0>) R4614.2(B<0>) R5801.2(B<0>) R5802.2(B<0>) R6154.2(B<0>) R7200.2(B<0>) R7730.2(B<0>) U1001.AF36(VDD_P3_3) U1001.AG37(VDD_P3_1) U1001.AR11(VDD_P3_4) U1001.AR27(VDD_P3_5) U1001.AT12(VDD_P3_6) U1001.AT26(VDD_P3_7) U1001.H36(VDD_P3_8) U1001.K36(VDD_P3_2) U1001.W7(VDD_P3_9) U1005.5(VCC) U1600.A4(VDD1_1) U1600.A9(VDD1_2) U1600.A15(VDD1_3) U1600.A16(VDD1_4) U1600.AC15(VDD1_6) U1600.AD4(VDD1_7) U1600.AD9(VDD1_8) U1600.AD15(VDD1_9) U1600.AD16(VDD1_10) U1600.B15(VDD1_5) U2000.139(VDD_MSM_IO) U2000.179(VREG_L13) U2400.113(VDD_MSM_IO) U2400.149(VDD_AUDIO_IO) U4000.94(VDD18_IO) U4100.H8(VPS_IO) U6250.A7(CPVDD1) U6250.AA1(DBVDD3_1) U6250.AA5(DBVDD3_2) U6250.AA11(DBVDD2) U6250.E1(AVDD1) U6250.F16(AVDD2) U6250.V16(DBVDD1) U6290.B2(EN) U6400.F5(VA) U7100.20(VIO) U7150.24(HB_VIO) U7150.27(MB_VIO) U7500.1(VIO) U7510.4(VIO) U7520.4(VIO) U8200.16(VDD_1P8)
VREG_L14A_1P8: C2354.2(B<0>) C6140.2(B<0>) C6183.2(B<0>) R1048.2(B<0>) R1049.2(B<0>) R1052.2(B<0>) R1053.2(B<0>) R1526.1(A<0>) R6110.1(A<0>) R6115.1(A<0>) R6130.2(B<0>) R6131.2(B<0>) U2000.181(VREG_L14) U6140.2(CSB) U6140.6(VDDIO) U6140.8(VDD) U6182.C1(VCCA) U6182.C2(OE)
VREG_L15A_UIM1: C1126.2(B<0>) C1127.2(B<0>) C2386.2(B<0>) C4108.2(B<0>) J4250.6(X<0>) R4211.2(B<0>) R4212.2(B<0>) R4213.2(B<0>) R4250.2(B<0>) R4251.2(B<0>) U1001.AP36(VDD_P5) U2000.110(VREG_L15) U4100.E2(VCC_UICC_IN) U4250.10(VCC)
VREG_L16A_2P7: C105.2(B<0>) C205.2(B<0>) C2384.2(B<0>) C7234.1(A<0>) C7500.2(B<0>) C7511.2(B<0>) C7521.2(B<0>) R104.2(B<0>) R204.2(B<0>) U2000.143(VREG_L16) U7230.5(VDD) U7500.14(VDD) U7510.3(VDD) U7520.3(VDD)
VREG_L17A_UIM2: C2383.2(B<0>) U2000.154(VREG_L17)
VREG_L18A_2P7: C2382.2(B<0>) U2000.111(VREG_L18)
VREG_L19A_3P3: C2385.2(B<0>) C4021.2(B<0>) C4022.2(B<0>) C4023.2(B<0>) C4024.2(B<0>) C4025.2(B<0>) C4026.2(B<0>) C4027.2(B<0>) C4082.2(B<0>) C4083.2(B<0>) C4085.1(A<0>) R4084.2(B<0>) U2000.121(VREG_L19) U4000.6(VDD33_WL_BT_DRV_CH0) U4000.9(VDD33_BT_PA_CH2) U4000.23(VDD33_FEM) U4000.29(VDD33_WL_CH0) U4000.30(VDD33_PM_DLDO) U4000.35(VDD33_WL_5G_DRV_CH0) U4080.2(VCC1) U4080.8(VCC3)
VREG_OLEDB: C2508.2(B<0>) C2509.2(B<0>) C5387.2(B<0>) J5300.5(X<0>) J5300.7(X<0>) U2400.129(VREG_OLEDB_FB) U2400.130(VREG_OLEDB)
VREG_RFCLK: C2320.1(A<0>) U2000.200(VREG_RF_CLK)
VREG_S1A_0P752: C1050.1(IN) C1050.3(OUT) C1051.1(IN) C1051.3(OUT) C1052.1(IN) C1052.3(OUT) C1053.2(B<0>) C1054.2(B<0>) C2278.2(B<0>) E1055.1(POS) L2200.2(B<0>) U1001.AC15(VDD_APC0_1) U1001.AC17(VDD_APC0_2) U1001.AD10(VDD_APC0_3) U1001.AD12(VDD_APC0_4) U1001.AD14(VDD_APC0_5) U1001.AD16(VDD_APC0_6) U1001.AE9(VDD_APC0_7) U1001.AF8(VDD_APC0_9) U1001.AF16(VDD_APC0_8) U1001.AG19(VDD_APC0_10) U1001.AH8(VDD_APC0_11) U1001.AK8(VDD_APC0_12) U1001.AL7(VDD_APC0_13) U1001.AM8(VDD_APC0_14)
VREG_S1B_0P752: C1075.1(IN) C1075.3(OUT) C1076.1(IN) C1076.3(OUT) C1078.2(B<0>) C1106.2(B<0>) C1128.2(B<0>) C1129.2(B<0>) C1150.2(B<0>) C1151.2(B<0>) C1152.2(B<0>) E1074.2(NEG) L2300.2(B<0>) U1001.AA19(VDD_MEM15) U1001.AB20(VDD_MEM16) U1001.AB22(VDD_MEM17) U1001.AC19(VDD_MEM18) U1001.AC21(VDD_MEM19) U1001.AC23(VDD_MEM20) U1001.AC25(VDD_MEM21) U1001.AC27(VDD_MEM22) U1001.AC29(VDD_MEM23) U1001.AC31(VDD_MEM24) U1001.AD18(VDD_MEM25) U1001.AD20(VDD_MEM26) U1001.AD22(VDD_MEM27) U1001.AD24(VDD_MEM28) U1001.AD26(VDD_MEM29) U1001.AD28(VDD_MEM30) U1001.AD30(VDD_MEM31) U1001.AD32(VDD_MEM32) U1001.AE19(VDD_APC0_PLL) U1001.AE25(VDD_MEM33) U1001.AE27(VDD_MEM34) U1001.AE31(VDD_LPA_PLL) U1001.AF18(VDD_MEM35) U1001.AF20(VDD_APC1_PLL) U1001.AF26(VDD_MEM36) U1001.AF28(VDD_MEM37) U1001.AG17(VDD_MEM38) U1001.AG25(VDD_MEM39) U1001.AG27(VDD_MEM40) U1001.AG29(VDD_MEM41) U1001.G17(VDD_EBI_CC) U1001.H10(VDD_EBI_PHY1) U1001.H12(VDD_EBI_PHY2) U1001.H16(VDD_EBI_PHY3) U1001.K10(VDD_EBI_PHY4) U1001.K12(VDD_EBI_PHY5) U1001.K14(VDD_EBI_PHY6) U1001.K16(VDD_EBI_PHY7) U1001.U11(VDD_MEM1) U1001.U13(VDD_MEM2) U1001.U19(VDD_MEM3) U1001.U21(VDD_MEM4) U1001.V10(VDD_MEM5) U1001.V12(VDD_MEM6) U1001.V14(VDD_MEM7) U1001.V16(VDD_MEM8) U1001.V18(VDD_MEM9) U1001.V20(VDD_MEM10) U1001.W15(VDD_MEM11) U1001.W17(VDD_MEM12) U1001.W21(VDD_MEM13) U1001.Y20(VDD_MEM14)
VREG_S1C_1P125: C2330.2(B<0>) C2331.2(B<0>) C2396.2(B<0>) C2563.1(A<0>) C2564.1(A<0>) L2560.2(B<0>) U2000.165(VDD_L2_3) U2000.214(VDD_L5) U2400.3(VDD_L1_9_10) U2560.E3(VOUT)
VREG_S2A_S3A_0P752: C1057.1(IN) C1057.3(OUT) C1058.1(IN) C1058.3(OUT) C1059.1(IN) C1059.3(OUT) C1060.1(IN) C1060.3(OUT) C1067.2(B<0>) C1068.2(B<0>) C2271.2(B<0>) E1068.1(POS) L2201.2(B<0>) L2202.2(B<0>) U1001.AJ13(VDD_APC1_1) U1001.AJ19(VDD_APC1_2) U1001.AK12(VDD_APC1_3) U1001.AK14(VDD_APC1_4) U1001.AK16(VDD_APC1_5) U1001.AK18(VDD_APC1_6) U1001.AK20(VDD_APC1_7) U1001.AL11(VDD_APC1_8) U1001.AL21(VDD_APC1_9) U1001.AM12(VDD_APC1_10) U1001.AM14(VDD_APC1_11) U1001.AM16(VDD_APC1_12) U1001.AM18(VDD_APC1_13) U1001.AM20(VDD_APC1_14) U1001.AN11(VDD_APC1_15) U1001.AN15(VDD_APC1_16) U1001.AN19(VDD_APC1_17) U1001.AN21(VDD_APC1_18)
VREG_S2B_0P752: C1111.2(B<0>) C1112.2(B<0>) C1114.1(IN) C1114.3(OUT) C1115.1(IN) C1115.3(OUT) C1140.2(B<0>) C1141.1(IN) C1141.3(OUT) E1114.1(POS) L2301.2(B<0>) U1001.L33(VDD_GFX1) U1001.M28(VDD_GFX2) U1001.M30(VDD_GFX3) U1001.M32(VDD_GFX4) U1001.M34(VDD_GFX5) U1001.N27(VDD_GFX6) U1001.N29(VDD_GFX7) U1001.N31(VDD_GFX8) U1001.N33(VDD_GFX9) U1001.N35(VDD_GFX10) U1001.U29(VDD_GFX11) U1001.U31(VDD_GFX12) U1001.V28(VDD_GFX13) U1001.V30(VDD_GFX14) U1001.V32(VDD_GFX15)
VREG_S2C_1P125: C1124.2(B<0>) C1617.2(B<0>) C1618.2(B<0>) C1619.2(B<0>) C1620.2(B<0>) C1621.2(B<0>) C1622.2(B<0>) C1623.2(B<0>) C2573.1(A<0>) C2574.1(A<0>) E1601.1(POS) L2570.2(B<0>) U1001.G21(VDD_P1) U1600.A5(VDD2_1) U1600.A8(VDD2_2) U1600.AC9(VDD2_20) U1600.AC13(VDD2_21) U1600.AC14(VDD2_22) U1600.AD5(VDD2_23) U1600.AD8(VDD2_24) U1600.B9(VDD2_3) U1600.B13(VDD2_4) U1600.B14(VDD2_5) U1600.G7(VDD2_6) U1600.G8(VDD2_7) U1600.G9(VDD2_8) U1600.J13(ODT_A) U1600.K2(VDD2_9) U1600.L7(VDD2_10) U1600.L8(VDD2_11) U1600.L9(VDD2_12) U1600.P7(VDD2_13) U1600.P8(VDD2_14) U1600.P9(VDD2_15) U1600.R2(VDD2_16) U1600.T13(ODT_B) U1600.V7(VDD2_17) U1600.V8(VDD2_18) U1600.V9(VDD2_19)
VREG_S3B_S4B_0P752: C1107.1(IN) C1107.3(OUT) C1108.1(IN) C1108.3(OUT) C1109.1(IN) C1109.3(OUT) C1110.1(IN) C1110.3(OUT) E1109.1(POS) L2302.2(B<0>) L2303.2(B<0>) U1001.AA23(VDD_CORE1) U1001.AA29(VDD_CORE2) U1001.AA33(VDD_CORE3) U1001.M24(VDD_CORE4) U1001.M26(VDD_CORE5) U1001.N13(VDD_CORE6) U1001.N15(VDD_CORE7) U1001.N17(VDD_CORE8) U1001.P14(VDD_CORE9) U1001.P16(VDD_CORE10) U1001.P18(VDD_CORE11) U1001.P20(VDD_CORE12) U1001.P22(VDD_CORE13) U1001.P24(VDD_CORE14) U1001.P26(VDD_CORE15) U1001.R13(VDD_CORE16) U1001.R17(VDD_CORE17) U1001.R21(VDD_CORE18) U1001.R23(VDD_CORE19) U1001.T24(VDD_CORE20) U1001.T26(VDD_CORE21) U1001.U23(VDD_CORE22) U1001.V24(VDD_CORE23) U1001.V26(VDD_CORE24) U1001.Y24(VDD_CORE25) U1001.Y26(VDD_CORE26) U1001.Y28(VDD_CORE27) U1001.Y30(VDD_CORE28) U1001.Y32(VDD_CORE29)
VREG_S4A_2P04: C2004.2(B<0>) C2272.2(B<0>) C2290.2(B<0>) C2294.2(B<0>) C5001.2(B<0>) C5511.2(B<0>) J5500.46(X<0>) J5500.48(X<0>) L2203.2(B<0>) U2000.174(VREG_S4) U2000.189(VDD_XO_RFCLK) U2000.191(VDD_L8_9_10_11_12_13_14_1) U2000.213(VDD_L8_9_10_11_12_13_14_2) U2400.169(VDD_HPH) U2400.185(VDD_CP) U5000.4(IN)
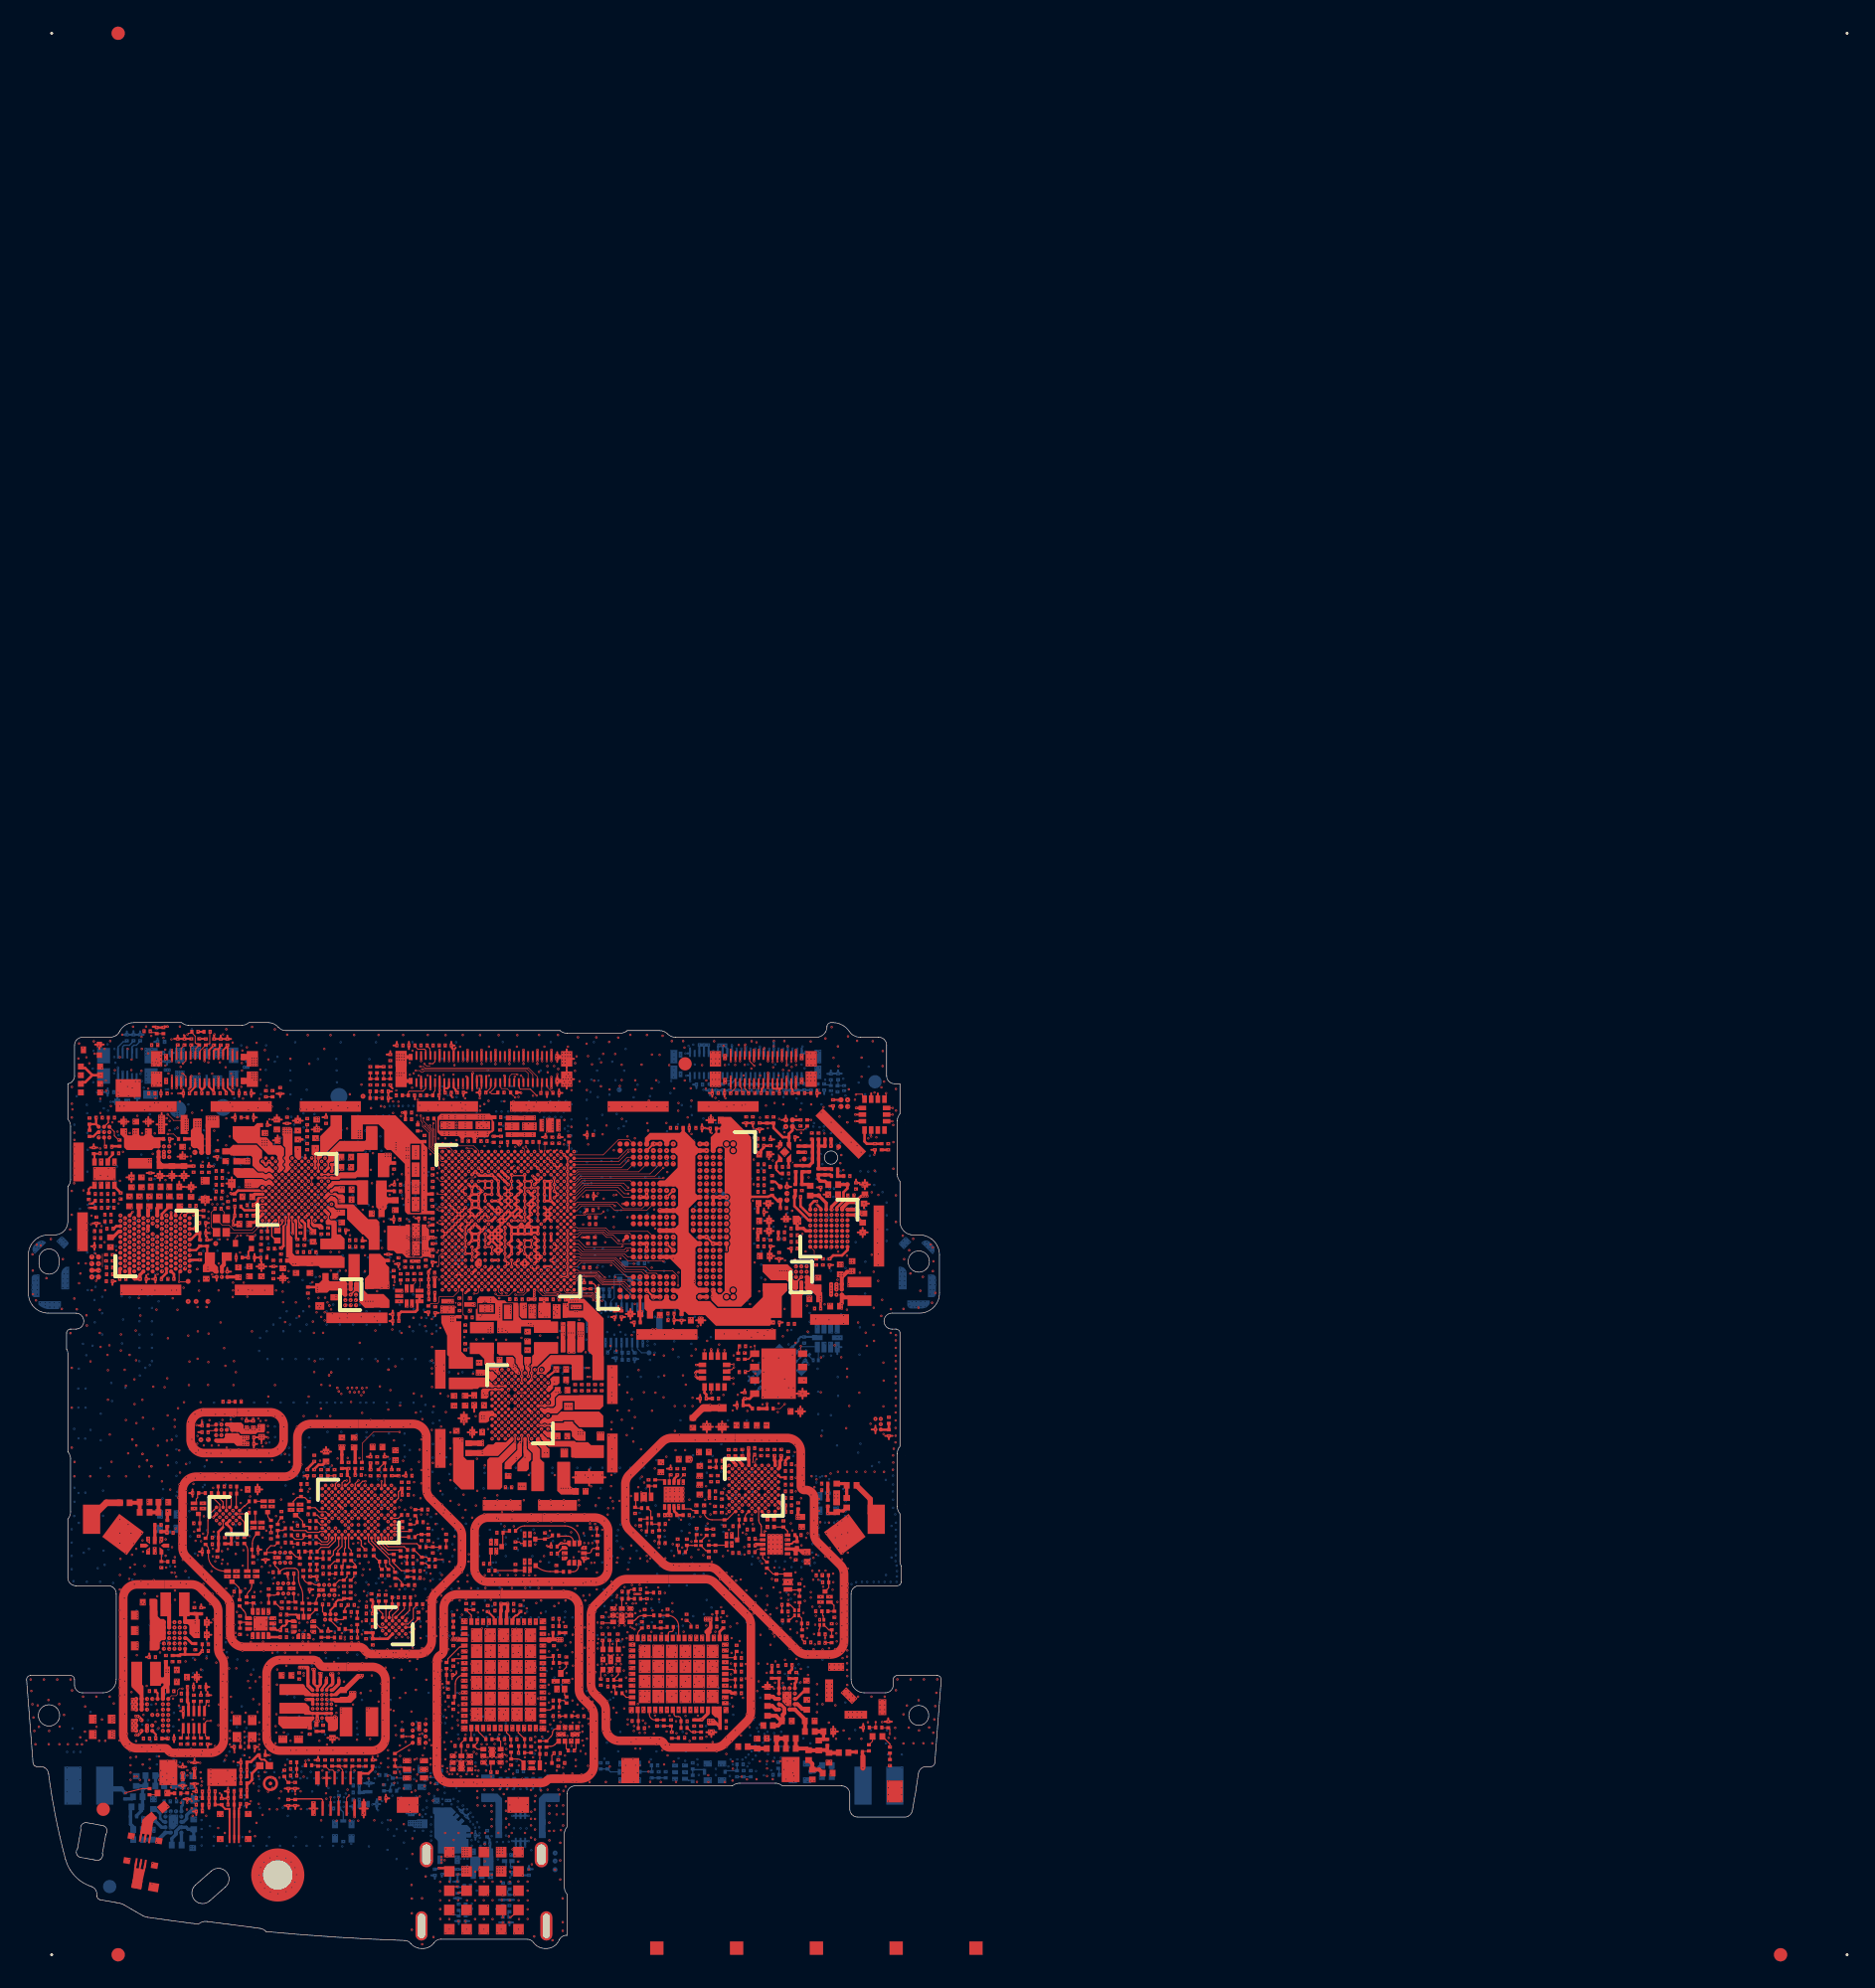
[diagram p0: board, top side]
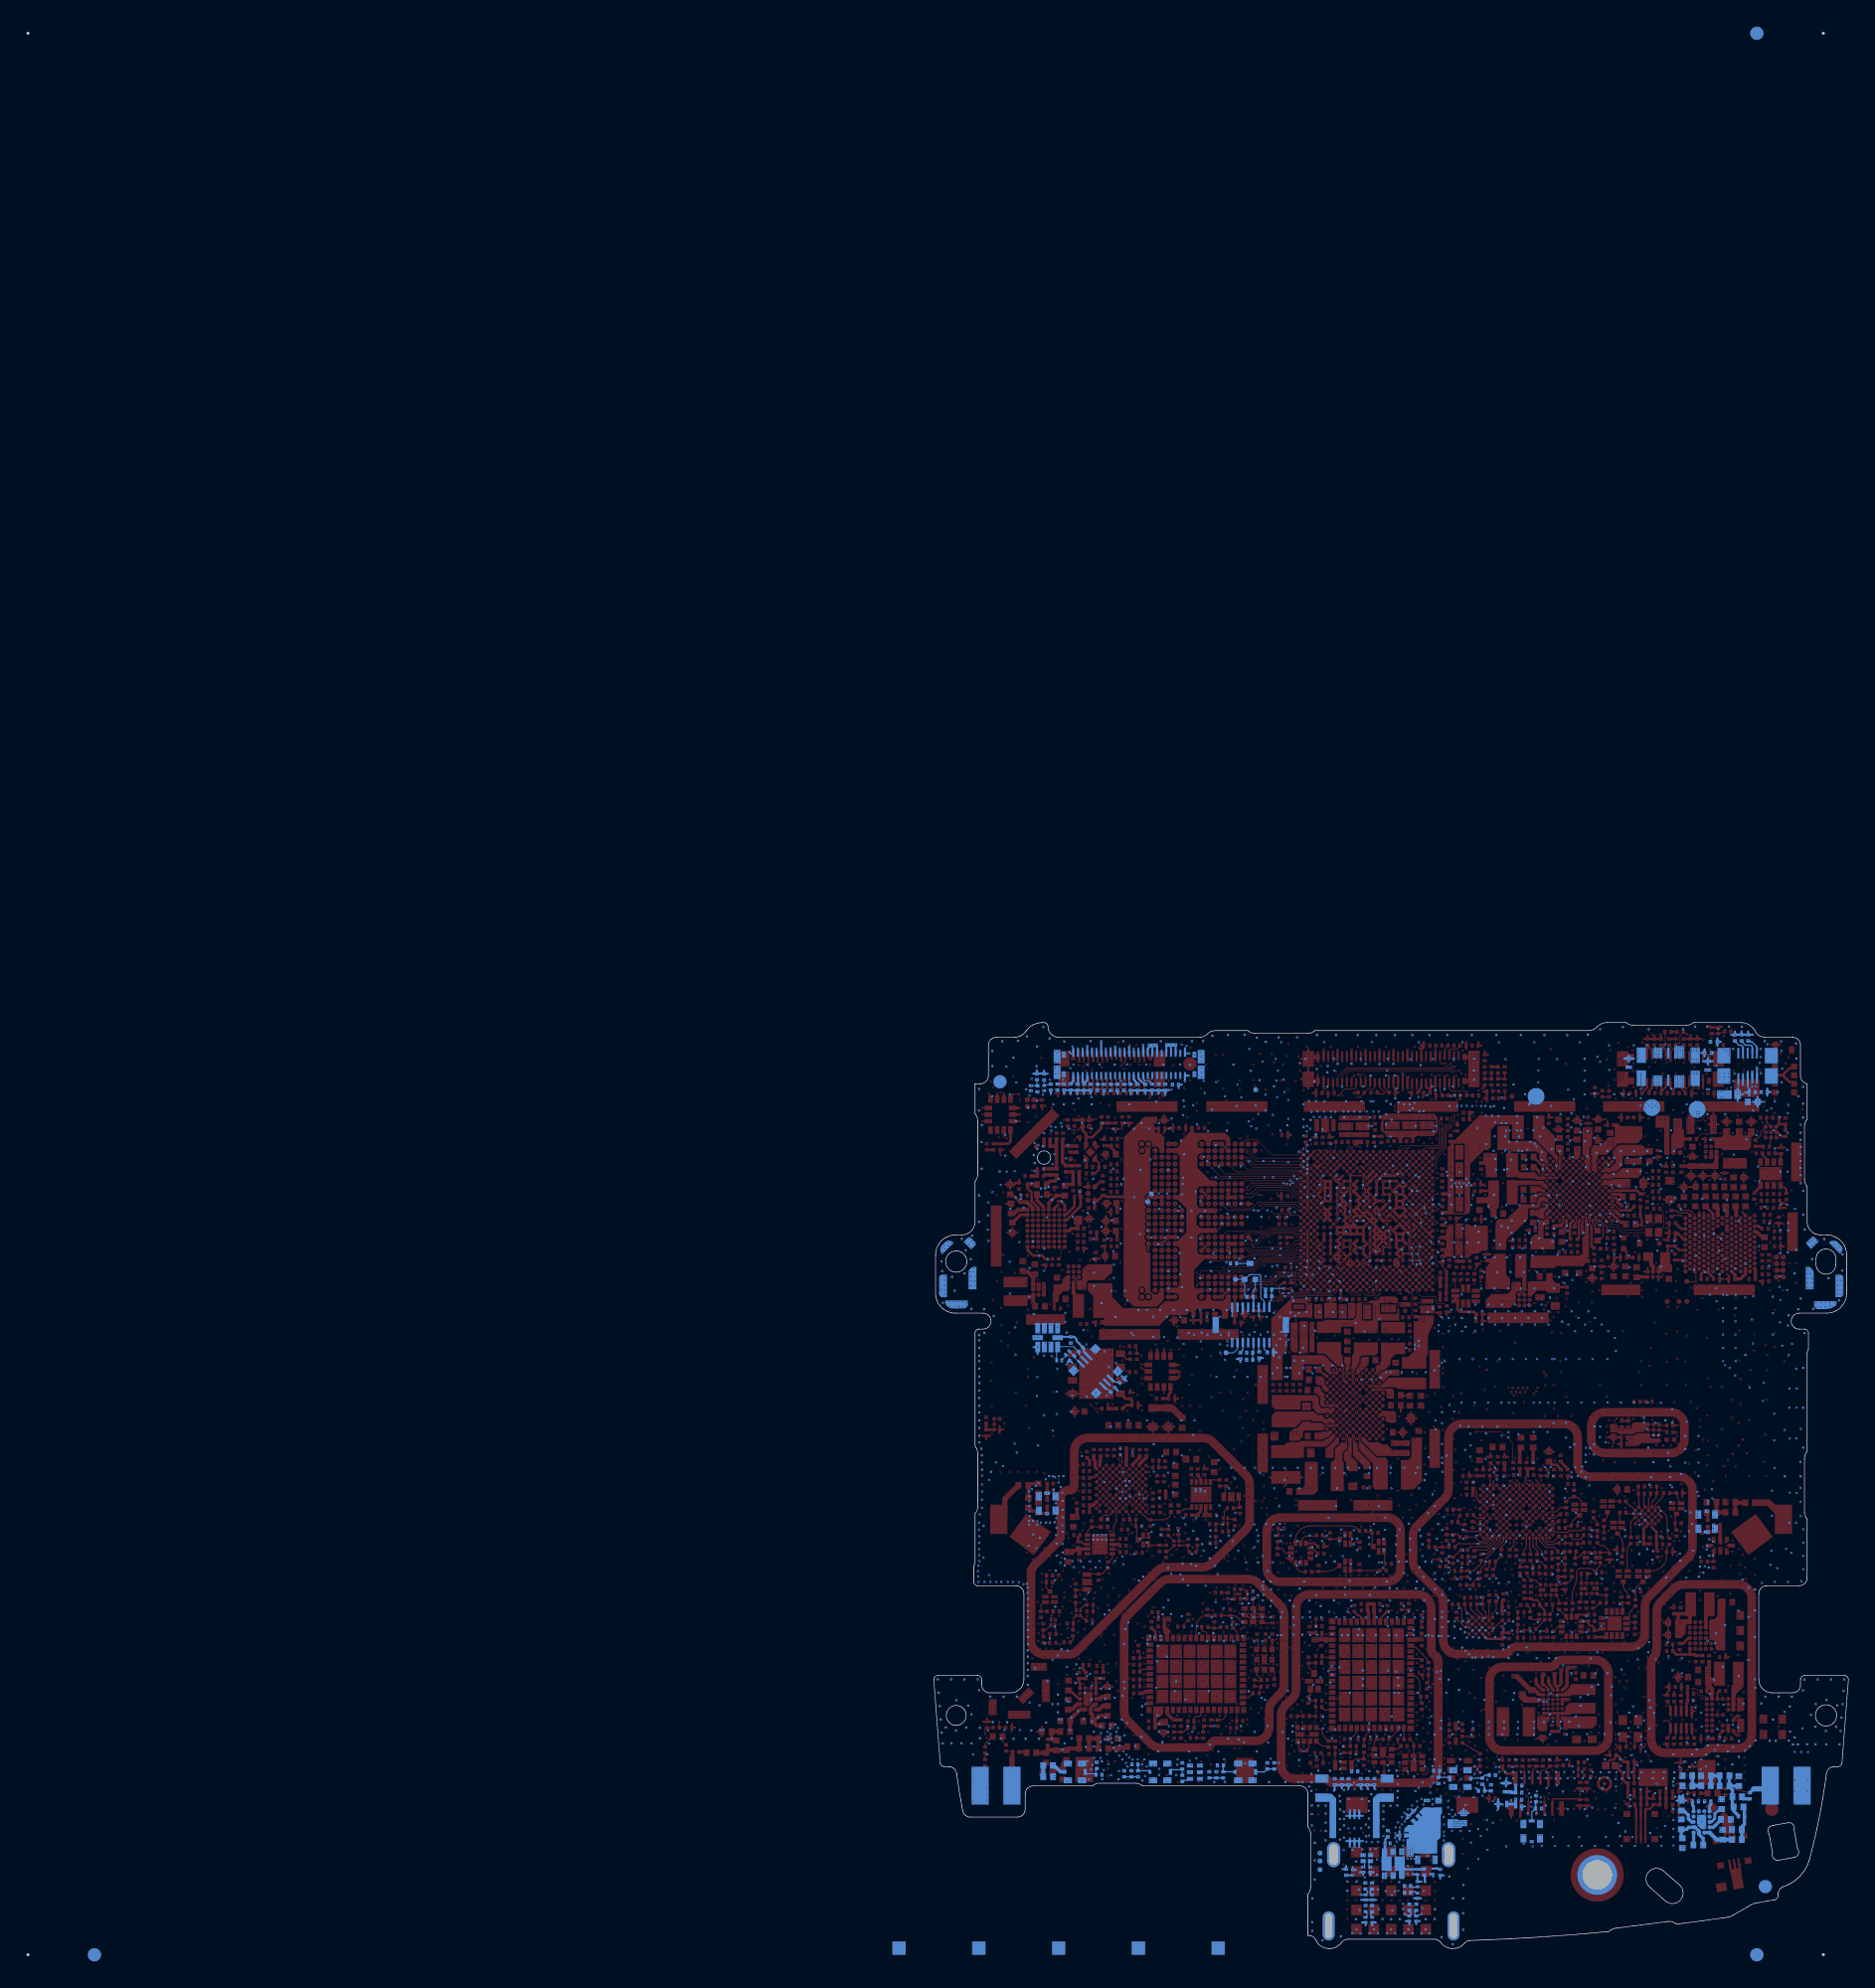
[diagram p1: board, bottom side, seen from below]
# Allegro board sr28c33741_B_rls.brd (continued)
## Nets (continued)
VREG_S5A_0P752: C1049.2(B<0>) C1064.2(B<0>) C1070.2(B<0>) C1071.1(IN) C1071.3(OUT) C1072.1(IN) C1072.3(OUT) E1070.2(NEG) L2204.2(B<0>) U1001.AH24(VDD_MODEM1) U1001.AJ25(VDD_MODEM2) U1001.AK24(VDD_MODEM3) U1001.AK26(VDD_MODEM4) U1001.AK28(VDD_MODEM5) U1001.AK30(VDD_MODEM6) U1001.AK32(VDD_MODEM7) U1001.AL23(VDD_MODEM8) U1001.AL31(VDD_MODEM9) U1001.AL33(VDD_MODEM10) U1001.AM24(VDD_MODEM11) U1001.AM26(VDD_MODEM12) U1001.AM28(VDD_MODEM13) U1001.AN25(VDD_MODEM14) U1001.AN29(VDD_MODEM15)
VREG_S6A_1P35: C2274.2(B<0>) C2291.2(B<0>) C2292.2(B<0>) L2205.2(B<0>) U2000.119(VREG_S6) U2000.194(VDD_L1_6_7_1) U2000.204(VDD_L1_6_7_2)
VSNS_DDR: E1601.2(NEG) U2570.E3(VOUT)
VSNS_S1A_M: E1056.2(NEG) U2000.107(VREF_NEG_S1)
VSNS_S1A_P: E1055.2(NEG) U2000.96(VREG_S1)
VSNS_S1B_M: E1073.1(POS) U2400.115(VREF_NEG_S1)
VSNS_S1B_P: E1074.1(POS) U2400.135(VREG_S1)
VSNS_S2A_S3A_M: E1069.2(NEG) U2000.73(VREF_NEG_S3) U2000.85(VREF_NEG_S2)
VSNS_S2A_S3A_P: E1068.2(NEG) U2000.74(VREG_S3) U2000.95(VREG_S2)
VSNS_S2B_M: E1115.2(NEG) U2400.59(VREF_NEG_S2)
VSNS_S2B_P: E1114.2(NEG) U2400.70(VREG_S2)
VSNS_S3B_S4B_M: E1110.2(NEG) U2400.81(VREF_NEG_S3) U2400.103(VREF_NEG_S4)
VSNS_S3B_S4B_P: E1109.2(NEG) U2400.93(VREG_S3) U2400.114(VREG_S4)
VSNS_S5A: E1070.1(POS) U2000.162(VREG_S5)
VSNS_S5B_M: E1116.2(NEG) U2400.132(VREF_NEG_S5)
VSNS_S5B_P: E1117.2(NEG) U2400.124(VREG_S5)
VSW_BCK_BOB: L2440.1(A<0>) U2400.7(VSW_BCK_BOB_1) U2400.18(VSW_BCK_BOB_2) U2400.29(VSW_BCK_BOB_3)
VSW_BST_BOB: L2440.2(B<0>) U2400.9(VSW_BST_BOB_1) U2400.19(VSW_BST_BOB_2) U2400.31(VSW_BST_BOB_3)
WCN_CLK_IN: C4032.1(A<0>) U2000.146(RF_CLK1)
WCN_XTALI: C4032.2(B<0>) U4000.60(XTALI)
WCSS_PWR_REQ: U1001.L3(WLAN_PWR_EN) U2000.41(GPIO_10) U2400.189(GPIO_09)
WIFI_5G_CH0_HPF_OUT_50R: R4081.2(B<0>) U4080.5(TX) U4081.4(OUT)
WIFI_5G_CH1_HPF_OUT_50R: U4090.5(TX) U4091.4(OUT)
WIFI_THERM: RT2401.2(NEG) U2000.150(AMUX_5)
WL_BB<0>: U1001.H2(WLAN2_ADC_QN) U4000.105(WL_BB_QN_CH1)
WL_BB<1>: U1001.G1(WLAN2_ADC_QP) U4000.113(WL_BB_QP_CH1)
WL_BB<2>: U1001.F2(WLAN2_ADC_IN) U4000.106(WL_BB_IN_CH1)
WL_BB<3>: U1001.G3(WLAN2_ADC_IP) U4000.114(WL_BB_IP_CH1)
WL_BB<4>: U1001.K6(WLAN1_ADC_QN) U4000.62(WL_BB_QN_CH0)
WL_BB<5>: U1001.J5(WLAN1_ADC_QP) U4000.77(WL_BB_QP_CH0)
WL_BB<6>: U1001.J7(WLAN1_ADC_IN) U4000.63(WL_BB_IN_CH0)
WL_BB<7>: U1001.H6(WLAN1_ADC_IP) U4000.70(WL_BB_IP_CH0)
WL_BT_RFIO_2G_CH0: C4060.1(A<0>) R4060.1(A<0>) U4000.15(WL_BT_RFIO_2G_CH0)
WL_BT_RFIO_2G_CH0_BYPASS: R4060.2(B<0>) R4061.1(A<0>)
WL_BT_RFIO_2G_CH0_MAT: C4060.2(B<0>) FL4060.1(UNBAL_PORT1) L4061.2(B<0>)
WL_BT_RFIO_2G_CH1: C4070.1(A<0>) R4070.1(A<0>) U4000.73(WL_BT_RFIO_2G_CH1)
WL_BT_RFIO_2G_CH1_A: C4070.2(B<0>) FL4070.1(UNBAL_PORT1) L4071.2(B<0>)
WL_BT_RFIO_2G_CH1_B: C4073.1(A<0>) FL4070.4(UNBAL_PORT2) L4072.2(B<0>)
WL_BT_RFIO_2G_CH1_BYPASS: R4070.2(B<0>) R4073.1(A<0>)
WL_BT_RFIO_2G_CH1_C: C4073.2(B<0>) R4073.2(B<0>) U4070.2(IN)
WL_CMD<0>: U1001.T6(WCSS2_BBD_DATA) U4000.95(WL_CMD_DATA_CH1) WL_CMD_DATA_CH1.1(X)
WL_CMD<1>: U1001.R7(WCSS2_BBD_CLK) U4000.110(WL_CMD_CLK_CH1)
WL_CMD<2>: U1001.U7(WCSS1_BBD_DATA) U4000.68(WL_CMD_DATA_CH0) WL_CMD_DATA_CH0.1(X)
WL_CMD<3>: U1001.U5(WCSS1_BBD_CLK) U4000.53(WL_CMD_CLK_CH0)
WL_REF_CLK_OUT_R: C4034.1(A<0>) U4000.81(CLK_OUT)
WL_REF_CLK_OUT_R_1: C4033.2(B<0>) C4034.2(B<0>) R4009.1(A<0>)
WL_RF_5G_CH0: C4050.1(A<0>) U4080.10(ANT)
WL_RF_5G_CH0_A: C4050.2(B<0>) FL4050.1(IN) L4051.2(B<0>)
WL_RF_5G_CH0_B: C4053.1(A<0>) FL4050.3(OUT) L4052.2(B<0>)
WL_RF_5G_CH1: C4040.1(A<0>) U4090.10(ANT)
WL_RF_5G_CH1_A: C4040.2(B<0>) FL4040.1(IN) L4041.2(B<0>)
WL_RF_5G_CH1_B: C4043.1(A<0>) FL4040.3(OUT) L4042.2(B<0>)
WL_RF_5G_CH1_C: C4043.2(B<0>) U4040.2(IN)
WL_RF_PDET_IN_CH0: R4055.2(B<0>) R4059.2(B<0>) R4065.2(B<0>) U4000.55(WL_RF_PDET_IN_CH0)
WL_RF_PDET_IN_CH1: R4045.2(B<0>) R4049.2(B<0>) R4075.2(B<0>) U4000.64(WL_RF_PDET_IN_CH1)
WL_RF_PDET_IN_CH1_5G: R4075.1(A<0>) U4070.3(COUPLED_OUT)
WL_RFI_5G_CH0: U4000.50(WL_RFI_5G_CH0) U4080.6(RX)
WL_RFI_5G_CH1: U4000.108(WL_RFI_5G_CH1) U4090.6(RX)
WL_RFO_5G_CH0: U4000.43(WL_RFO_5G_CH0) U4081.1(IN)
WL_RFO_5G_CH1: R4092.2(B<0>) U4000.101(WL_RFO_5G_CH1) U4091.1(IN)
WLAN1_DAC_RSET: R1171.2(B<0>) U1001.L1(WLAN1_DAC_RST)
WLAN2_4G_S1_DIP_50R: C4063.2(B<0>) R4061.2(B<0>) U4060.2(IN)
WLAN2_DAC_RSET: R1172.2(B<0>) U1001.K2(WLAN2_DAC_RST)
WLAN5G_S0_DIP_MAT_50R: C4053.2(B<0>) U4050.2(IN)
WLAN_5G_CLK_OUT: R4009.2(B<0>) U1001.V6(RF_XO_CLK)
WLAN_SW_CTRL: U2000.7(GPIO_05) U2400.40(EXT_CTRL_BOB) U4000.51(SW_CTRL)
WMSS_RESET: R3102.1(A<0>) U1001.AV26(GPIO_53)
WTR0_GPS_A_50R: FL8502.4(UNBAL_PORT2) L8518.1(A<0>) L8519.2(B<0>)
XO_SDR: R3104.2(B<0>) U2000.168(RF_CLK2)

Pads without a net: FL7050 4 8; FL7141 5; J350 5 9 G1 G2; J510 3 4; J5300 9 19 33 35 37 39 40 41 43 45 47 48; J5500 59 60; J5502 1 2; J6601 12; JTAG 7 8; M2001 1; U1001 AA3 AA41 AC37 AC39 AD40 AE41 AF40 AF42 AG5 AG39 AG43 AH4 AH6 AH38 AJ5 AL3 AL39 AL41 AL43 AM40 AM42 AP40 AR5 AR17 AR35 AR37 AR41 AT8 AT10 AT36 AT40 AU3 AU7 AU9 AU11 AU13 AU25 AU35 AU41 AV6 AV42 AW29 AY2 AY12 AY38 AY42 B20 B22 BA11 BA15 BA33 C21 C23 D18 D20 D22 D24 D26 D40 F18 F26 F38 H32 K40 L41 N19 N41 P40 P42 R41 T4 V2 V4 W1 W3 Y2 Y4 Y40 Y42; U1600 A1 A2 A17 A18 AB16 AC1 AC16 AC18 AD1 AD2 AD17 AD18 B1 B18 D16 H14 J14 L13 L14 M3 M4 M5 M6 M7 M9 N3 N4 N5 N6 N7 N9 N13 N14 T14 U14; U2000 1 2 18 29 40 90 92 99 117 129 136 170 218; U2400 5 15 16 37 43 50 72 92 109 120 126 128 137 138 147 148 151 158 159 160 168 170 173 179 180 181 183 184 190 191 193 194; U2401 C3; U3100 5 6 7 18 65 66 74 80 86 101 104 110 113 120 136 157 159 165 167 168 173 176 177 178 179; U4000 3 5 13 38 48 52 54 71 78; U4080 1; U4090 1; U4100 B3 C8 D3 D4 D5 D8 E3 E4 E5 E6 E7 E8 F1 F3 F4 F5 F7 G2 G3 G4 H2 H3 H4 H7; U4200 3 7; U4600 E1; U6110 10 11; U6115 10 11; U6250 AA7 AA9 AA13 AB2 AB4 AB8 B16 C15 D16 E15 F4 F6 F12 G13 H4 H6 H14 J1 K2 K14 L1 N3 P2 R1 R3 R5 R9 T2 T6 T8 T10 T12 U1 U3 U5 U7 U11 U13 V4 V6 V8 V10 V12 W1 W3 W7 W11 W13 Y4 Y6 Y12 Y16; U7100 13 23 36 38 54 56; U7150 5 14 18 33 34 55; U7500 10 12 13; U7510 7; U7520 7 8; U8200 10

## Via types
v1: diameter 0.175, hole 0.075, TOP to LAYER_2, 7384 vias
v2: diameter 0.175, hole 0.075, LAYER_2 to LAYER_3, 7250 vias
v3: diameter 0.175, hole 0.075, LAYER_3 to LAYER_4, 6614 vias
v4: diameter 0.175, hole 0.075, LAYER_4 to LAYER_5, 4844 vias
v5: diameter 0.175, hole 0.075, LAYER_5 to LAYER_6, 4129 vias
v6: diameter 0.175, hole 0.075, LAYER_6 to LAYER_7, 3907 vias
v7: diameter 0.175, hole 0.075, LAYER_7 to BOTTOM, 3425 vias

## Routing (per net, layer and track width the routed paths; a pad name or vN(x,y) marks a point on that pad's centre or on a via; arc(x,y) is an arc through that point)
GND: length 1319.9
  TOP w0.05: E519.1 10.18,62.43 v3(10.18,62.42) v3(10.18,62.23) v3(10.18,62.04) ; 57.56,59.06 57.65,59.15 ; v5(43.73,20.76) 43.85,20.76 43.92,20.83 ; v3(38.16,48.94) 38.16,48.93 38.13,48.89 38.13,48.86 ; 39.22,23.66 v3(39.27,23.61) ; 30.35,66.36 30.08,66.36 v1(29.91,66.53) ; 5.7,52.23 5.7,51.25 ; 40.05,61.01 v7(40.05,61.06) ; 17.95,14.82 v5(17.95,14.89) ; 46.3,21.21 46.48,21.21 ; U1001.J1 v3(39.39,60.04)
  TOP w0.075: 41.57,50.22 41.7,50.35 41.81,50.35 ; v3(54.63,36.57) 54.63,36.99 54.75,37.11 v7(54.75,37.13)
  TOP w0.088: v3(55.47,31.36) 55.51,31.39 55.62,31.38
  TOP w0.1: v7(37.95,57.2) v7(38.44,57.2) v3(38.44,56.71) v3(38.44,56.22) v3(38.44,55.72) v3(38.44,55.23) v3(38.44,54.73) ; v7(37.95,57.2) v3(37.47,57.2) ; v7(37.95,57.2) v1(37.95,57.7) ; U1001.T14 U1001.T12 U1001.T10 ; v3(35.97,51.76) v3(35.97,52.26) v3(35.97,52.75) v3(35.97,53.25) v3(35.97,53.74) U1001.AB24 ; v3(37.45,58.2) 37.38,58.12 36.54,58.12 U1001.Y8 v3(36.46,57.7) v3(36.46,57.2) ; v1(39.68,58.94) v1(39.43,59.19) U1001.J3 ; v3(39.68,57.95) v3(39.68,57.45) v3(39.68,56.96) ; 51.98,45.04 v1(51.98,45.05) ; v1(32.32,20.83) 32.32,20.68 32.21,20.57 v3(32.04,20.57) 32,20.53 32,20.23 ; 30.23,54.88 30.23,54.88 v1(30.54,54.88) ; v7(60.05,23.32) R4064.1 ; v3(37.45,52.75) v3(37.95,52.75) v3(37.95,53.25) ; v3(37.45,52.75) v3(37.45,53.25) ; v3(37.45,52.75) U1001.T32 ; v7(37.45,56.22) v3(37.45,55.72) v3(37.45,55.23) v3(37.45,54.73) v7(36.96,54.73) v7(36.46,54.73) ; 51.48,45.05 v1(51.47,45.05) ; v3(33,52.26) U1001.AP30 U1001.AP28 U1001.AP26 33,54.23 ; v3(19.22,54.74) 19.22,54.54 19.04,54.35 19.04,53.98 C2320.2 ; v1(33.99,58.69) v3(34.24,58.44) ; 34.56,65.12 34.56,64.67 ; v1(52.61,36.19) v1(52.82,36.33) ; U1001.AM34 v3(33.49,52.26) U1001.AM30 ; v1(40.18,59.93) v1(40.42,59.68) ; v3(38.69,58.44) v3(38.44,58.69) ; v1(40.67,53.99) v1(40.67,53.49) v1(40.67,53) v1(40.67,52.5) v1(40.67,52.01) v1(40.67,51.51) v1(40.67,51.02) v1(40.67,50.52) U1001.E39 ; v1(40.67,55.47) v1(40.67,55.97) U1001.C15 v1(40.67,56.96) v1(40.67,57.45) v1(40.67,57.95) v1(40.67,58.44) v7(40.67,58.94) v1(40.67,59.43) ; 33.86,65.12 33.86,64.67 ; J5500.32 34.21,64.67 ; U1001.AH26 U1001.AH28 v3(34.48,52.75) v3(34.98,52.75) U1001.AF32
  TOP w0.125: 10.11,64.59 v3(10.11,64.31) 10.11,64.03
  TOP w0.15: v3(32.04,64.01) 31.91,64.14 v3(31.91,64.3) ; 40.61,66.19 J5500.L2 ; J5500.L2 41.16,66.91 ; J5500.L2 40.61,67.62 ; v3(10.03,58.1) 10.03,58.45 ; v3(10.03,58.1) 10.03,57.75 ; v3(10.03,58.1) 9.65,58.1 ; v3(10.03,58.1) 10.4,58.1 ; v3(11.28,64.7) J5502.28 v3(11.28,65.54) ; U6110.2 64.01,64.3 ; v3(49.25,47.24) 49.52,47.24 ; v3(49.25,47.24) 48.97,47.24 ; v3(49.25,47.24) 49.25,46.99 ; 27.35,67.48 C5509.1 27.07,67.23 ; v1(45.41,47.72) 45.41,48.1 ; v1(45.41,47.72) 45.41,47.34 ; v1(45.41,47.72) 45.76,47.72 ; v1(45.41,47.72) 45.06,47.72 ; U1001.G35 U1001.H34 v3(39.68,52.01) ; 17.37,34.15 C7701.1 ; C7701.1 17.37,34.9 ; C7701.1 17.72,34.52 ; 62.64,57.58 v3(62.37,57.58) 62.37,57.83 ; C5524.1 19.34,64.28 ; C5524.1 19.07,64.03 ; C5524.1 18.79,64.28 ; v3(33.16,66.74) J5500.37 v3(33.16,67.59) ; U1001.K26 v3(38.94,53.25) v3(38.94,52.75) v3(38.94,52.26) ; 13.72,54.56 v3(13.47,54.56) 13.47,54.29 ; R510.2 10.16,62.82 ; R510.2 9.77,61.97 ; R510.2 10.55,61.97 ; 55.43,56.04 C1601.1 ; C1601.1 55.78,55.66 ; C1601.1 56.13,56.04 ; v3(33.08,65.57) 33.16,65.48 33.16,64.69 v3(33.14,64.66) ; 56.37,60.32 v1(56.67,60.32) 56.67,60.72 ; v3(35.97,51.27) U1001.AA35 v3(35.97,51.76) ; U6110.7 v3(62.32,62.21) ; 19.64,27.91 L7629.2 19.39,28.19 ; 45.01,47.49 C1101.1 44.74,47.24 ; C6629.1 20.2,10.74 C6630.1 ; C6629.1 19.4,10.74 ; C6629.1 19.68,10.49 ; C6630.1 20.48,10.74 ; C6630.1 20.2,10.49 ; 63.54,39.03 U6130.A1 ; U6130.A1 63.83,38.74 ; U6130.A1 63.83,39.32 ; 54,42.06 C4214.1 53.72,41.81 ; v5(64.84,38.55) 65.11,38.55 ; v5(64.84,38.55) 64.84,38.3 ; v5(64.84,38.55) 64.56,38.55 ; C2279.1 11.3,58.1 ; C2279.1 10.93,58.45 ; C2279.1 10.93,57.75 ; C2279.1 10.55,58.1 ; 64.51,17.06 C280.1 ; C280.1 64.79,17.31 ; C280.1 65.06,17.06 ; C4100.1 57.46,54.86 ; C4100.1 56.76,54.86 ; C4100.1 57.11,55.24 ; v3(57.15,64.69) J5501.6 v3(57.15,65.55) ; v1(11.48,57.29) 11.48,57.68 ; 26.02,14.42 C1517.1 26.29,14.17 ; 16.9,64.04 v3(16.9,64.32) ; v3(16.9,64.32) 16.9,64.6 ; v3(16.9,64.32) 17.15,64.32 ; v3(9,50.35) 9.25,50.35 ; v3(9,50.35) 9,50.07 ; v3(9,50.35) 9,50.63 ; 21.92,14.42 v3(21.92,14.17) 21.65,14.17 ; 58.19,40.01 C2288.1 ; C2288.1 57.84,40.39 ; C2288.1 58.19,40.77 ; C2288.1 58.54,40.39 ; v3(36.31,66.74) 36.31,67.16 v3(36.31,67.59) ; 15.37,15.16 v3(15.62,15.16) 15.62,14.88 ; 21.27,10.52 J6601.13 21.88,10.52 ; C7607.2 21.81,27.97 v3(21.82,27.98) 21.82,27.73 v3(21.88,27.67) ; 17.95,14.82 VR4521.1 18.2,14.54 ; J5500.L1 41.16,65.38 ; J5500.L1 40.61,64.66 ; J5500.L1 40.61,66.09 ; 29.49,54.63 C1090.1 29.24,54.91 ; 19.27,50.06 C2380.1 ; C2380.1 18.89,50.41 ; C2380.1 19.64,50.41 ; C2380.1 19.27,50.76 ; v1(32.26,50.52) v1(32.5,50.77) v1(32.75,50.52) ; L216.1 56.09,19.68 ; L216.1 55.71,20.03 ; L216.1 55.34,19.68 ; 55.12,61.37 C5306.1 ; C5306.1 54.84,61.62 ; C5306.1 55.39,61.62 ; 27.41,57.45 v1(27.66,57.45) 27.66,57.73 ; v3(27.35,64.94) 27.35,64.85 27.52,64.68 ; L2503.2 42.3,36.03 ; L2503.2 41.07,35.42 ; L2503.2 42.3,34.82 ; L2503.2 43.52,35.42 ; 58.35,41.35 U4200.1 ; U4200.1 58.35,42.11 ; U4200.1 57.87,41.73 ; U4200.1 58.82,41.73 ; 60.66,15.95 L223.1 ; L223.1 60.66,16.7 ; L223.1 61.01,16.32 ; v3(5.25,54.54) 5.52,54.54 ; v3(5.25,54.54) 4.97,54.54 ; v3(5.25,54.54) 5.25,54.29 ; 39.02,61.27 39.02,61.02 38.74,61.02 ; 17.07,62.21 v3(17.07,62.49) ; v3(17.07,62.49) 17.07,62.77 ; v3(17.07,62.49) 17.32,62.49 ; v1(40.67,59.43) v1(40.42,59.68) ; v3(34.98,57.2) v3(34.98,57.7) v7(34.48,57.7) ; v3(34.98,57.2) v3(34.98,56.71) v3(34.52,56.71) U1001.AH14 34.48,56.22 ; v3(34.98,57.2) v3(34.52,57.2) U1001.AH12 v7(34.48,57.7) ; 9.68,50.07 C6271.1 ; C6271.1 9.43,50.35 ; C6271.1 9.68,50.62 ; v1(63.03,57.45) 63.03,57.81 ; v1(63.03,57.45) 62.66,57.45 ; v1(63.03,57.45) 63.41,57.45 ; v1(63.03,57.45) 63.03,57.1 ; 60.38,51.15 C4105.1 60.65,51.4 ; 16.79,10.87 v1(16.54,10.87) 16.54,10.59 ; C6288.2 11.88,57.28 ; 13.61,19.3 C6155.1 13.88,19.05 ; v3(34.73,54.98) v3(34.48,55.23) v3(34.24,54.98) v1(33.99,54.73) ; U1001.V34 v3(36.71,51.51) v3(36.96,51.27) ; 27.53,46.91 v3(27.53,47.19) ; v3(27.53,47.19) C521.1 ; v3(27.53,47.19) 27.28,47.19 ; v1(22.52,37.36) 22.89,37.36 ; v1(22.52,37.36) 22.52,37.71 ; v1(22.52,37.36) 22.14,37.36 ; 13.58,53.53 C6263.1 13.85,53.28 ; C5680.1 31.06,64.22 v7(31.06,64.55) J5500.50 31.06,65.59 ; v3(31.94,67.91) 31.94,68.19 ; v3(31.94,67.91) 31.99,67.86 31.99,67.71 v3(32.11,67.59) ; v3(31.94,67.91) 32.19,67.91 ; v3(36.46,55.72) v3(35.97,56.22) v3(36.46,56.71) v3(36.22,56.96) ; C2360.2 51.15,39.65 ; C2360.2 51.15,38.81 ; C2360.2 51.61,39.23 ; C2360.2 50.68,39.23 ; 25.35,9.85 J6601.1 ; J6601.1 25.35,11.2 ; J6601.1 25.05,10.52 ; J6601.1 25.66,10.52 ; v3(32.11,67.59) 32.27,67.74 ; v3(32.11,67.59) J5500.43 v5(32.11,66.74) ; v3(13.38,66.74) J5502.15 v3(13.38,67.58) ; 14.29,50.21 U6290.C2 14,50.5 ; C4606.1 11.74,13.91 ; C4606.1 11.46,13.66 ; C4606.1 12.01,13.66 ; 24,53.74 C1001.1 24.25,54.02 ; J5501.18 v3(55.05,64.7) ; 9.23,22.19 R6402.1 8.98,21.91 ; C4608.1 12.9,12.39 ; C4608.1 12.63,12.14 ; C4608.1 12.35,12.39 ; v1(33.51,64.56) J5500.36 33.51,65.78 v3(33.56,65.83) ; 48.69,46.97 RT6165.2 ; RT6165.2 48.94,47.25 ; RT6165.2 v5(48.69,47.69) ; C6410.1 13.9,23.59 ; C6410.1 13.55,23.97 ; C6410.1 13.55,23.21 ; 15.43,62.49 v3(15.68,62.49) ; v3(15.68,62.49) 15.68,62.21 ; v3(15.68,62.49) 15.68,62.77 ; v7(35.93,65.64) 35.96,65.61 35.96,65.12 ; C2376.1 33.66,40.36 ; J5500.32 34.21,65.62 ; 7.51,57.99 C6292.2 ; C6292.2 7.89,57.64 ; C6292.2 7.89,58.34 ; 59.71,56.99 v3(59.71,57.24) 59.43,57.24 ; C5517.1 34.08,64.65 ; C5517.1 33.83,64.37 ; C5517.1 34.08,64.09 ; 62.87,53.5 v1(62.87,53.85) ; v1(62.87,53.85) 62.87,54.2 ; v1(62.87,53.85) 63.24,53.85 ; v1(62.87,53.85) 62.49,53.85 ; v3(39.68,56.96) v1(39.93,56.71) v3(39.68,56.46) ; 11.09,68.41 C5518.1 ; C5518.1 C5519.1 ; C5518.1 11.37,68.66 ; C2287.1 9.53,62.18 ; C2287.1 9.16,61.83 ; C2287.1 9.16,62.53 ; C2287.1 8.78,62.18 ; v3(11.74,12.25) 12.01,12.25 ; v3(11.74,12.25) v1(11.74,12.01) ; v3(11.74,12.25) 11.46,12.25 ; 13.89,15.37 C6153.1 13.62,15.12 ; v3(39.68,53) v3(39.93,52.75) v3(39.68,52.5) ; v3(38.44,51.27) U1001.N37 v3(37.95,51.27) ; v5(37.19,64.33) 37.15,64.37 C5521.1 ; v3(34.21,67.59) 34.21,67.16 v3(34.21,66.74) ; C2283.1 18.03,51.29 ; C2283.1 17.66,50.94 ; C2283.1 17.28,51.29 ; C2283.1 17.66,51.64 17.61,51.69 C2333.1 17.6,51.96 R2018.1 ; v3(15.48,65.54) J5502.4 v3(15.48,64.7) ; C5505.1 v3(27.2,64.01) v3(27.2,64.46) 27.48,64.46 ; C5505.1 27.2,63.67 ; C5505.1 27.45,63.95 ; C4607.1 12.9,13.98 ; C4607.1 12.63,14.23 ; C4607.1 12.35,13.98 ; v3(15.1,68.4) 15.1,68.65 ; v3(15.1,68.4) 15.37,68.4 ; v3(15.1,68.4) v3(14.6,68.4) ; v7(32.5,55.23) v1(32.75,54.98) ; v7(32.5,55.23) U1001.AP18 ; v7(32.5,55.23) v1(32.26,55.47) v1(32.01,55.72) v1(31.76,55.97) ; v7(32.5,55.23) v1(32.26,54.98) U1001.AV22 ; v1(32.75,54.98) v1(32.5,54.73) v3(32.26,54.48) v1(32.01,54.23) v1(31.76,53.99) v1(31.51,53.74) ; v1(32.75,54.98) U1001.AP20 ; 39.43,30.5 v3(39.43,30.23) 39.18,30.23 ; 30.82,51.61 C1049.1 30.53,51.31 30.53,51.3 ; 62.91,16.34 v5(62.91,16.62) ; v5(62.91,16.62) 62.91,16.9 ; v5(62.91,16.62) 62.66,16.62 ; v3(14.43,64.7) J5502.10 v3(14.43,65.54) ; 51.41,61.38 v3(51.41,61.66) 51.16,61.66 ; C6402.1 13.55,24.89 ; C6402.1 13.9,24.51 ; C6402.1 13.55,24.13 ; 56.76,62.31 v3(57.09,62.31) 57.09,62.64 ; 13.4,25.63 C6401.1 13.13,25.88 ; 5.48,67.64 Q2032.2 ; Q2032.2 5.8,67.98 ; Q2032.2 5.15,67.98 ; 63.34,56.02 v1(62.97,56.02) 62.97,55.67 ; v1(39.68,58.94) v1(39.93,58.69) v1(40.18,58.94) ; 9.58,58.32 v3(9.31,58.32) 9.03,58.32 ; 56.86,47.08 C1621.1 56.61,46.8 ; 57.79,60.73 v3(57.79,61.01) 58.04,61.01 ; 32.89,39.4 v1(32.89,39.87) ; v1(32.89,39.87) 33.3,39.87 ; v1(32.89,39.87) 32.47,39.87 ; v1(32.89,39.87) 32.89,40.34 ; 49.83,61.98 v1(49.83,61.7) 49.83,61.43 ; 23,15.49 v5(23,15.84) ; v5(23,15.84) 23.37,15.84 ; v5(23,15.84) 22.62,15.84 ; 22.95,23.86 v3(22.67,23.86) 22.67,24.11 ; 51.49,15.91 v1(51.49,16.26) ; v1(51.49,16.26) 51.11,16.26 ; v1(51.49,16.26) 51.86,16.26 ; v1(50.79,61.71) 51.04,61.71 ; v1(50.79,61.71) 50.79,61.99 ; v1(50.79,61.71) 50.79,61.43 ; 14.09,68.67 14.1,68.66 v3(14.1,68.4) v3(14.6,68.4) ; C5528.1 40.29,64.34 ; C5528.1 40.04,64.62 ; C5528.1 40.04,64.06 ; C1164.1 30.25,49.3 C1105.1 ; v1(20.4,62.25) 20.4,62.6 ; v1(20.4,62.25) 20.02,62.25 ; v1(20.4,62.25) 20.77,62.25 ; 27.96,51.23 v1(27.96,51.48) 27.68,51.48 ; v3(36.22,56.96) v3(35.97,56.71) v7(36.46,56.22) U1001.AB18 ; v3(36.22,56.96) v3(35.97,57.2) ; v3(36.22,56.96) v3(36.46,57.2) ; 18.83,51.29 C2334.1 18.28,51.29 ; C2417.1 7.68,62.18 ; C2417.1 7.3,61.83 ; C2417.1 6.93,62.18 ; C2417.1 7.3,62.53 ; 60.36,63.36 v5(60.64,63.36) 60.64,63.11 ; v3(39.46,65.55) J5500.2 v3(39.46,64.7) ; v3(56.8,67.59) v3(56.8,66.74) ; C1608.1 51.46,62.67 ; C1608.1 51.81,62.29 ; C1608.1 51.11,62.29 ; 11.78,17.33 U6150.5 11.54,17.86 ; 15.09,51.19 v1(15.09,50.9) 15.37,50.9 ; 10.76,60.6 v1(10.76,60.88) 11.01,60.88 ; v3(14.6,68.4) 14.6,68.66 ; 54.61,61.8 C5501.1 C5500.1 ; v3(54.7,66.73) J5501.19 v3(54.7,67.59) ; 55.94,52.56 C1624.1 56.21,52.81 ; 53.83,62.08 C5500.1 ; C5500.1 54.11,61.83 ; 28.52,35.83 v1(28.52,35.55) 28.27,35.55 ; 55.83,59.35 C1613.1 56.18,59.73 ; v1(55.45,55.38) 55.7,55.38 ; v1(55.45,55.38) 55.45,55.66 ; v1(55.45,55.38) 55.45,55.1 ; 22.24,62.51 v3(22.52,62.51) 22.52,62.76 ; v1(31.51,53.74) v1(31.27,53.99) ; v1(31.51,53.74) v1(31.27,53.49) ; R4615.1 13.49,19.95 ; R4615.1 13.74,19.67 ; R4615.1 13.49,19.39 ; v3(55.75,64.69) J5501.14 v3(55.75,65.85) ; C2434.1 17.64,38.44 v3(17.09,38.44) v3(17.09,37.94) ; C2434.1 17.67,38.12 ; C2434.1 18.04,38.47 ; 56.59,51.63 C1632.1 ; C1632.1 56.31,51.88 ; C1632.1 56.86,51.88 ; 11.82,68.69 11.88,68.64 C5519.1 ; 12.8,20.03 C2282.1 ; C2282.1 12.8,20.79 ; C2282.1 13.15,20.41 ; C2282.1 12.45,20.41 ; 57.5,57.28 v3(57.17,57.28) 57.17,57.61 ; U1001.R33 U1001.P34 ; U1001.R33 U1001.T32 ; U1001.R33 v3(37.95,52.26) ; C2286.1 21.81,61.94 ; C2286.1 21.44,61.59 ; C2286.1 22.19,61.59 ; 45.69,46.8 v1(45.69,47.08) 45.44,47.08 ; 59.44,64.05 v3(59.44,64.33) ; v3(59.44,64.33) 59.69,64.33 ; v3(59.44,64.33) 59.44,64.61 ; v3(38.41,67.59) J5500.7 v3(38.41,66.74) ; C2403.1 18.82,62.68 ; C2403.1 18.45,62.33 ; C2403.1 19.2,62.33 ; v3(55.83,53.96) 55.83,54.34 ; v3(55.83,53.96) 55.83,53.58 ; v3(55.83,53.96) 55.48,53.96 ; v3(55.83,53.96) 56.18,53.96 ; 41.9,61.18 v3(42.15,61.18) ; v3(42.15,61.18) 42.15,60.9 ; v3(42.15,61.18) 42.15,61.46 ; 34.56,65.12 34.56,65.62 ; C4502.1 15.11,11.28 VR4501.1 14.67,11.58 ; C4502.1 VR4500.1 ; C4502.1 C4504.1 ; v3(31.06,67.59) J5500.49 v3(31.06,66.74) ; 12.23,34.25 L7722.1 ; L7722.1 12.48,34.53 ; L7722.1 12.48,33.97 ; v3(13.19,38.83) 12.91,38.83 ; 53.42,40.57 C4215.1 ; C4215.1 53.17,40.85 ; C4215.1 53.42,41.13 ; C2400.1 15.43,58 ; C2400.1 15.01,57.53 ; C2400.1 15.43,57.06 ; 6.71,50.18 C6183.1 6.46,49.9 ; 12.76,10.03 v3(12.76,10.31) 12.51,10.31 ; 22.35,12.83 22.56,12.83 ; 22.56,12.83 22.78,12.83 ; 22.56,12.83 22.56,12.2 ; 43.95,47.49 C1099.1 44.23,47.24 ; 55.88,51.7 C1623.1 ; C1623.1 55.88,52.46 ; C1623.1 56.23,52.08 ; 27.18,36.98 L3201.1 26.91,37.23 ; C4504.1 15.15,12.1 ; C4504.1 14.9,11.82 ; C521.1 27.28,47.7 ; C521.1 27.53,47.98 ; C5519.1 v3(12.39,68.41) ; v3(17.09,37.94) 17.34,37.94 ; v3(17.09,37.94) 17.09,37.66 ; 29.66,65.58 J5500.58 29.66,64.66 ; 50.69,46.86 C1612.1 ; C1612.1 51.04,47.24 ; C1612.1 50.34,47.24 ; 15.86,13.99 C4523.1 ; C4523.1 v3(16.11,13.44) v1(16.11,12.94) v3(16.11,12.42) ; C4523.1 16.11,14.26 ; 18.53,60.77 C2409.1 18.88,61.15 ; J5501.20 v3(54.7,64.7) ; 21.56,27 v1(21.29,27) 21.29,26.75 ; C2416.1 12.1,59.55 ; C2416.1 11.73,59.9 ; C2416.1 11.35,59.55 ; v3(57.85,66.73) J5501.1 v3(57.85,67.59) ; 17.14,51.68 R2018.1 ; R2018.1 17.14,52.24 ; 19.86,62.05 v1(19.59,62.05) 19.31,62.05 ; 12.96,29.84 L7717.1 ; L7717.1 13.21,30.12 ; L7717.1 13.21,29.57 ; v3(27.61,54.83) 27.61,55.11 ; v3(27.61,54.83) 27.36,54.83 ; v3(27.61,54.83) 27.61,54.55 ; U1001.AN23 33,54.23 ; U1001.AN23 v1(33.49,54.73) ; U1001.AN23 v1(33,54.73) ; v3(17.4,30) 17.4,30.28 ; v3(17.4,30) 17.65,30 ; v3(17.4,30) 17.4,29.72 ; 17.69,29.24 L7648.1 ; L7648.1 18.24,29.24 ; L7648.1 17.97,28.99 ; v3(10.93,66.74) J5502.29 v5(10.93,67.58) ; 18.11,62.2 v1(18.11,61.92) 18.36,61.92 ; 12.96,56.32 v1(13.43,56.32) ; v1(13.43,56.32) 13.43,55.9 ; v1(13.43,56.32) 13.89,56.32 ; C3004.1 27.46,36.26 ; v3(31.04,64.15) 31.04,63.85 ; v3(39.46,66.74) J5500.1 v3(39.46,67.59) ; 29.93,47.86 v1(30.21,47.86) 30.21,47.61 ; v3(12.39,65.61) 12.33,65.55 J5502.22 12.33,64.76 v3(12.2,64.64) ; v3(10.93,64.7) J5502.30 v5(10.93,65.63) ; C1518.1 27.27,11.29 ; C1518.1 27.02,11.01 ; C1518.1 27.02,11.57 ; 63.51,60.06 C6110.1 63.79,59.81 ; 5.11,52.53 C6184.1 ; C6184.1 4.86,52.81 ; C6184.1 5.11,53.09 ; C2275.1 12.74,57.26 ; C2275.1 12.37,56.91 ; C2275.1 11.99,57.26 ; C2275.1 12.37,57.61 ; v3(13.48,68.4) 13.47,68.41 C5503.1 ; 31,47.8 C1106.1 30.73,47.55 ; C2361.2 52.3,39.65 ; C2361.2 52.76,39.23 ; C2361.2 51.83,39.23 ; C2361.2 52.3,38.81 ; 13.48,53.53 C6261.1 ; C6261.1 13.48,54.09 ; C6261.1 13.73,53.81 ; v3(60.28,56.7) 59.93,56.7 ; v7(34.48,57.7) v1(33.99,57.7) ; 55.48,54.72 C1602.1 ; C1602.1 55.83,55.1 ; C1602.1 56.18,54.72 ; C1602.1 55.83,54.34 ; 12.94,39.33 R2418.1 13.19,39.61 ; v3(37.36,66.74) J5500.13 v3(37.36,67.59) ; 39.9,64.87 J5500.L4 39.9,65.61 ; 33.1,64.37 v3(32.85,64.37) 32.85,64.09 ; C1152.1 42.89,56.58 ; C1152.1 42.64,56.3 ; C1152.1 42.64,56.86 ; 52.48,64.05 C5530.1 52.48,64.61 ; 55.95,61.09 C1121.1 56.22,60.84 ; J5501.13 v3(55.75,66.73) ; v3(5.05,60.23) 5.05,60.48 ; v3(5.05,60.23) 5.32,60.23 ; v3(5.05,60.23) 4.77,60.23 ; v3(35.26,66.74) J5500.25 v3(35.26,67.59) ; v7(29.2,64.16) 29.2,63.85 ; v5(52.95,64.7) J5501.30 v1(52.95,65.56) ; 14.06,59.54 v3(14.34,59.54) 14.34,59.29 ; v3(11.63,64.7) J5502.26 v3(11.63,65.54) ; 11.09,16.07 v1(11.09,15.79) 11.09,15.51 ; C1129.1 C1078.1 ; 33.17,38.82 C2501.1 ; C2501.1 33.87,38.82 ; C2501.1 33.52,38.44 ; C2501.1 33.52,39.2 ; 27.84,68.19 C5551.2 27.59,67.91 ; 19.69,11.78 C1514.1 ; C1514.1 19.41,12.03 ; C1514.1 v1(20.19,12.03) ; 12.08,10.99 C174.1 ; C174.1 12.35,11.24 ; C174.1 11.8,11.24 ; 30.37,51.1 30.22,50.95 C1104.1 30.22,50.33 C1091.1 C1156.1 ; 48.15,36.08 v2(48.43,36.08) 48.43,36.33 ; v3(57.85,65.55) J5501.2 v3(57.85,64.69) ; 50.65,41.08 v3(50.65,41.36) ; v3(50.65,41.36) 50.4,41.36 ; v3(50.65,41.36) 50.65,41.64 ; C5513.1 51.56,64.61 ; C5513.1 51.56,64.05 ; C5513.1 51.31,64.33 ; C1132.1 36.17,60.33 ; v1(13.11,19.05) 13.11,19.31 ; v1(33,57.2) 32.75,56.96 v1(33,56.71) ; U6110.3 63.51,64.31 ; 15.98,64.04 v3(15.98,64.32) 15.98,64.6 ; v5(52.95,66.73) J5501.29 v5(52.95,67.59) ; 33.86,65.12 33.86,65.62 ; 11.46,58.1 C2295.1 ; C2295.1 11.84,58.45 ; C2295.1 12.21,58.1 ; C2295.1 11.84,57.75 ; 39.9,66.67 J5500.L3 39.9,67.41 ; 21.11,35.3 v1(21.11,35.55) 20.84,35.55 ; 42.26,29.34 U7520.10 41.91,29.06 ; 27.46,52.2 C2396.1 26.91,52.2 ; 28.75,68.19 C5550.2 28.75,67.63 ; 12.56,19.39 C6150.1 12.56,19.95 ; 11.54,64.31 v3(11.79,64.31) ; v3(11.79,64.31) 11.79,64.59 ; v3(11.79,64.31) 11.79,64.03 ; 17.17,14.88 C4675.1 17.42,15.16 ; v3(16.54,39.67) v3(17.04,39.67) ; 41.64,50.07 C1007.2 41.92,50.32 ; U1001.N5 v3(38.44,58.69) ; 13.71,59.08 R2406.1 13.98,58.83 ; 57.25,52.64 R4100.1 57.5,52.36 ; 25.58,36.98 v1(25.86,36.98) 25.86,37.23 ; 25.26,53.47 RT1001.2 25.53,53.22 ; U6110.6 v3(62.31,62.71) ; 20.19,11.78 v1(20.19,12.03) ; v1(20.19,12.03) 20.47,12.03 ; C5529.1 39.13,64.02 ; v3(37.45,53.25) v3(37.95,53.25) ; 40.31,61.01 40.05,61.01 ; U1001.T14 v7(37.45,56.22) ; v3(37.45,58.2) U1001.T10 ; 12.51,11.81 v5(12.76,11.81) 12.76,12.09 ; v3(33,52.26) v3(33.49,52.26) ; v3(37.47,57.7) v1(37.95,57.7) ; v5(15.48,66.74) J5502.3 v5(15.48,67.58) ; 30.36,65.61 J5500.54 v7(30.36,64.63) ; C2374.1 33.63,41.57 C2355.1 ; 15.76,52.24 v3(15.76,51.96) 15.76,51.68
  TOP w0.175: v3(14.04,32.42) 14.04,32.45 v3(14.28,32.68) ; v1(16,54.48) v3(15.54,54.38) v3(15.54,54.73) v3(15.65,55.11) v3(15.66,55.8) ; v5(45.7,26.66) v5(46.16,26.66) ; v3(13.72,11.82) 13.72,12.13 ; v3(30.79,53.01) v3(30.61,53.01) 30.54,53.01 C1070.1 ; C1156.1 30.23,49.71 30.23,49.56 v5(30.24,49.56) v3(30.24,49.37) C1164.1 ; U2000.24 v3(18.23,59.19) U2000.23 U2000.12 ; U6115.2 51.98,45.04 ; v7(38.17,49.48) v3(38.17,49.3) v3(38.17,49.12) 38.13,48.86 ; v3(16.54,39.67) v3(16.54,39.87) ; 9.5,69.32 9.73,69.32 R2020.1 C2020.1 10.36,69.33 v7(10.61,69.33) ; v3(17.04,39.86) v3(17.04,39.67) ; v7(40.05,61.24) v7(40.05,61.06) ; U6115.3 51.48,45.05 ; v3(50.57,47.43) v3(50.77,47.43) ; v3(32.99,49.29) U1001.AN43
  TOP w0.2: U6115.7 50.46,42.89 v3(50.32,43.03) ; v3(13.72,11.82) v5(13.72,11.32) v5(13.72,10.82) 13.72,10.53 ; v1(20.4,60.84) 20.75,60.84 ; v3(50.31,43.27) 50.31,43.31 50.39,43.39 U6115.6
  TOP w0.25: v1(37.73,48.83) 38.19,48.83 C1112.1
  TOP w0.3: J5500.L3 40.48,67.04 J5500.L2 ; J5500.L4 40.48,65.24 J5500.L1 ; U4600.B5 U4600.A5
  TOP w0.4: C2509.1 C2508.1
  LAYER_2 w0.045: 4.53,54.52 4.55,54.54 v7(4.53,54.56) ; 23.26,33.75 23.39,33.62 ; 17.18,25.44 17.18,25.3 ; 29.94,52.1 29.94,52.16 30.08,52.3 30.32,52.3 ; 4.53,54.05 4.55,54.03 v7(4.53,54.01) ; v3(40.37,16.79) 40.37,16.82 ; 36.76,50.29 36.93,50.46
  LAYER_2 w0.05: 39.16,50.86 39.16,50.88 39.04,51 ; 38.27,42.26 38.45,42.06 ; 37.06,41.61 37.22,41.76 ; 21.76,57.05 22.13,57.4 ; 18.5,56.72 18.62,56.84 18.81,56.84 18.9,56.75 ; 35.53,58.94 35.68,58.72 ; 20.02,58.67 20.19,58.52 ; 36.84,41.79 36.98,41.6 ; 33.52,58.47 33.77,58.6 ; 20.01,58.79 20.17,58.93 ; 19.24,57.02 19.46,57.14
  LAYER_2 w0.1: v3(17.9,61.38) v3(18.08,61.2)
  LAYER_2 w0.175: v3(37.05,34.76) v3(37.23,34.76) v3(37.41,34.76) ; v3(21.48,50.84) v3(21.48,50.67) ; v3(24.29,59.38) v3(24.41,59.52) ; v3(36.19,35.61) v3(36.37,35.61) ; v3(21.67,21) v3(21.49,21) ; v3(22.86,20.68) v3(23.04,20.68) ; v3(16.72,59.16) v3(16.54,59.16) v3(16.54,59.34) ; v3(16.72,59.16) v3(16.72,59.34) v3(16.54,59.34) ; v3(16.72,59.16) v3(16.54,59.34) ; v5(33.52,41.44) v5(33.7,41.44) ; v3(18.66,62.3) v3(18.84,62.3) ; v3(18.48,59) v3(18.23,59.19) v3(17.99,59) v3(17.77,59.22) ; v3(9.12,33.72) v3(9.12,33.54) ; v3(22,20.71) v3(22.18,20.71) ; v7(10.56,33.46) v7(10.56,33.65) ; v3(40.24,37.55) v3(40.42,37.55) v3(40.6,37.55) ; v3(24.28,58.9) v3(24.41,58.75) ; v3(20.64,15.93) v3(20.46,15.93) v3(20.28,15.93) ; v3(58.97,12.59) v3(59.22,12.59) ; v3(22.82,15.84) v5(23,15.84) v3(23.18,15.84) ; v7(54.79,15.85) v7(54.79,15.67) ; v3(19.02,15.94) v3(19.2,15.94) v3(19.38,15.94) ; v3(23.57,54.73) v3(23.57,54.55) ; v7(55.68,15.9) v7(55.68,15.71) ; v3(33.89,44.09) v3(34.06,44.09) ; v3(24.43,57.22) v3(24.54,57.09) ; v3(19.32,20.7) v3(19.32,20.53) ; v3(35.47,44.4) v3(35.65,44.4) ; v3(27.57,55.58) v3(27.57,55.4) ; v3(32.12,40.78) v3(32.3,40.78) ; v5(9.12,16.77) v5(9.12,16.37) ; v2(34.3,38.2) v2(34.3,38.02) v2(34.3,37.84) ; v3(20.21,50.92) v3(20.21,50.74) ; v3(25.96,37.86) v3(26.14,37.86) ; v3(21.73,60.94) v3(21.85,60.81) ; v3(24.44,56.38) v3(24.44,56.2) ; v3(26.08,55.42) v3(26.08,55.24) ; v3(23.72,38.39) v3(23.87,38.29) ; v3(25.09,20.56) v3(25.27,20.56) v3(25.18,20.4) v3(25.09,20.56) ; v3(11.26,20.8) v3(11.35,20.97) v3(11.17,20.97) v3(11.26,20.8) ; v5(11.26,20.04) v3(11.35,20.21) v3(11.17,20.21) v5(11.26,20.04) ; v3(17.9,61.2) v3(18.08,61.2) v3(18.08,61.38) v3(17.9,61.38) v3(17.9,61.2)
  LAYER_3 w0.045: 22.19,37.62 24.12,37.62 24.15,37.65 24.15,37.71 v3(24.15,37.71) ; 30.04,50.6 29.67,50.97 29.1,50.97 28.95,50.82 28.95,50.76 28.92,50.72 28.16,50.72 28.04,50.84 27.44,50.84 v3(27.31,50.97) ; 30.04,50.6 29.97,50.53 29.91,50.53 ; 30.04,50.6 30.12,50.52 30.12,50.32 ; 17.48,12.22 v7(17.48,12.18) ; v3(47.52,47.49) 47.52,47.61 45.77,49.36 45.2,49.36 45.06,49.5 43.86,49.5 43.07,50.29 41.42,50.29 v7(40.95,49.82) ; 57.48,43.32 57.9,43.32 ; 23.89,54.94 23.89,56.44 23.77,56.55 23.34,56.55 23.31,56.52 22.92,56.91 22.16,56.91 22.06,56.81 21.94,56.81 21.82,56.93 21.82,57.07 22.09,57.34 22.22,57.34 22.32,57.24 23.09,57.24 23.43,56.9 23.95,56.9 ; v2(32,50.54) 32.14,50.39 32.14,50.2 31.86,49.91 31.69,49.91 31.57,50.03 v3(31.27,50.03) ; 52.92,34.75 53.08,34.75 53.25,34.58 ; 11.01,22.4 10.94,22.47 10.94,22.66 ; 11.51,15.55 11.34,15.38 10.25,15.38 ; v3(23.71,33.64) 24.03,33.64 24.25,33.42 24.25,32.9 24.05,32.7 24.05,32.55 24.16,32.44 24.22,32.44 ; v3(23.71,33.64) 23.71,33.8 23.54,33.97 23.37,33.97 23.29,34.05 ; v3(23.71,33.64) 23.41,33.64 23.29,33.76 23.29,34.05 ; 44.77,62.43 44.82,62.48 45.9,62.48 46.1,62.28 ; 44.77,62.43 v3(44.77,62.39) ; 44.77,62.43 44.72,62.48 40.61,62.48 v7(40.44,62.31) ; 24.22,32.44 24.27,32.44 24.51,32.68 v3(24.51,32.85) 24.5,32.86 24.5,33.47 23.83,34.14 23.81,34.14 23.8,34.12 v3(23.76,34.12) 23.74,34.12 23.69,34.17 23.45,34.17 23.36,34.26 23.36,34.43 23.5,34.57 23.5,34.81 23.51,34.83 23.51,34.83 23.5,34.83 ; 24.22,32.44 v5(24.22,32.16) 24.21,32.16 24.21,32.29 ; 51.19,40.7 52.38,40.7 ; 13.12,55.92 13.06,55.98 12.66,55.98 12.58,55.9 12.58,55.7 12.73,55.55 12.73,55.07 12.42,54.76 12.42,53.79 13.6,52.6 13.84,52.6 15.41,51.03 15.41,50.35 19.23,46.53 21.32,46.53 21.55,46.3 21.66,46.3 21.93,46.57 21.93,46.79 21.66,47.06 21.53,47.06 21.31,46.84 19.38,46.84 15.76,50.46 15.76,51.21 13.91,53.06 v3(13.91,53.33) 13.69,53.55 13.22,53.55 12.76,54.01 12.76,54.61 13.08,54.93 ; v7(28.79,46.76) 28.79,46.77 29.02,47 29.02,47.36 28.78,47.6 28.78,47.61 ; 39.47,43.61 39.58,43.72 40.02,43.72 40.11,43.63 v3(40.12,43.63) ; 12.55,24.81 12.5,24.76 12.5,24.34 12.6,24.24 ; v3(28.13,49.13) 28.07,49.19 28.07,49.48 28.17,49.58 28.58,49.58 28.73,49.44 28.73,48.6 28.71,48.58 ; v3(32.5,50.98) 32.44,50.93 32.44,50.09 31.96,49.61 31.58,49.61 31.53,49.66 30.54,49.66 30.45,49.75 v3(30.24,49.75) 30.19,49.75 30.17,49.77 29.55,49.77 29.28,50.04 29.19,50.04 29.02,50.2 ; v3(5.97,51.7) 6.14,51.53 6.93,51.53 ; 23.29,34.05 23.16,34.18 23.16,34.47 v3(23.1,34.53) 23.15,34.58 23.15,35.01 23,35.16 23,35.64 23.05,35.69 23.24,35.69 23.33,35.6 23.33,35.14 23.51,34.96 23.51,34.84 23.5,34.83 ; 22.63,43.74 22.69,43.8 24.93,43.8 24.99,43.74 ; v3(39.39,60.04) 39.27,59.92 39.27,59.54 39.31,59.5 v3(39.24,59.43) ; v5(17.49,13.93) 17.27,14.15 16.94,14.15 16.84,14.05 16.8,14.05 v5(16.78,14.07) ; v3(10.17,51.32) 10.17,51.32 ; 28.37,50.43 29.09,50.43 29.2,50.53 29.91,50.53 ; 28.37,50.43 28.04,50.43 28.03,50.43 27.9,50.55 24.5,50.55 v3(24.32,50.37) ; 28.37,50.43 28.37,50.28 arc(28.43,50.14) 28.57,50.08 28.61,50.08 arc(28.72,50.1) 28.81,50.16 28.84,50.19 ; v3(37.26,59.93) 37.38,59.93 37.7,60.25 37.7,60.59 v6(37.71,60.59) ; 12.02,59.91 12.08,59.97 12.08,60.52 11.97,60.63 v3(11.82,60.63) 11.71,60.52 11.71,59.97 ; 23.5,34.83 v3(23.49,34.83) ; 17.61,55.23 17.46,55.39 17.01,55.39 16.84,55.22 16.84,54.64 16.85,54.62 16.85,51.67 18.15,50.37 19,50.37 19.32,50.05 19.63,50.05 v3(19.71,50.13) ; 20.58,50.24 20.73,50.39 20.73,52.21 v3(20.67,52.27) ; 42.1,54.85 42.47,54.85 42.56,54.94 42.65,54.85 43.06,54.85 ; 28.71,48.58 29.05,48.58 29.16,48.48 29.16,47.83 28.94,47.61 28.78,47.61 ; 28.71,48.58 28.7,48.58 28.48,48.36 28.48,47.91 28.53,47.86 v7(28.55,47.86) 28.55,47.84 28.78,47.61 ; 13.05,19.84 13.21,20.01 13.21,20.77 13.11,20.87 v3(13.11,20.98) ; 30.12,50.32 30.19,50.32 30.23,50.28 v5(30.26,50.28) ; 30.12,50.32 29.91,50.53 ; v3(24.83,34.65) 24.71,34.53 v3(24.71,34.09) ; v3(21.61,35.55) 21.51,35.65 21.51,36.26 22.43,37.18 26.75,37.18 v3(26.95,36.98) 27.92,36 28,36 28,35.99 27.99,35.97 v3(27.95,35.97) ; 57.75,51.68 57.66,51.68 56.37,52.97 56.37,56.47 v3(56.42,56.47) ; 34.52,46.59 34.88,46.95 ; 49.97,54.91 50.27,54.91 ; 41.94,30.14 v3(41.91,30.14) ; 11.73,61.36 11.73,62.51 ; 36.41,47.95 v3(36.39,47.97) ; 19.2,51.15 19.42,50.93 19.44,50.93 ; 35,61.04 35,61.07 v3(35.01,61.08) ; 41.59,53.3 42.04,53.3 ; 41.89,56.46 42.33,56.46 ; 18.92,55.85 19.06,55.85 19.08,55.87 19.29,55.87 19.31,55.85 ; 24.08,42.36 23.91,42.19 ; 36.54,49.98 36.54,50.06 36.96,50.48 ; 21.24,36.66 21.24,35.12 21.36,35 21.36,34.64 v7(21.29,34.57) 21.32,34.54 ; 22.57,34.52 22.58,34.52 22.73,34.37 22.73,34.16 v3(23.02,33.87) ; 20.24,56.44 20.51,56.27 ; v3(36.34,43.92) 36.48,44.06 38.08,44.06 39.46,42.68 v3(39.46,42.63) ; 20.73,55.94 20.6,55.81 20.42,55.81 20.05,56.18 20.05,56.28 ; 38.93,47.77 38.55,48.16 ; v3(22.95,32.8) 22.96,32.8 ; 55.81,53.61 55.88,53.61 56.07,53.42 56.07,53.12 55.95,53 v3(55.95,52.84) ; v5(24.87,57.16) 24.87,57.67 24.73,57.81 24.44,57.81 24.42,57.79 21.87,57.79 21.62,57.54 21.62,57.41 21.48,57.27 ; 10.84,57.39 10.84,56.87 ; 41.69,55.13 42.13,55.13 ; 54.15,41.2 53.8,41.2 ; 60.2,60.14 arc(60.42,60.2) 60.65,60.18 ; 37.5,46.97 v3(37.5,47.14) 37.58,47.22 38.02,47.22 38.38,46.86 v3(38.38,46.75) 38.27,46.64 37.83,46.64 37.5,46.97
  LAYER_3 w0.05: 19.05,61.66 18.33,61.66 18.28,61.61 18.28,60.3 ; v3(36.49,62.04) 36.64,62.18 36.64,62.69 ; v3(37.28,60.91) 37.28,61.53 v3(37.38,61.63) ; 36.82,58.66 36.82,58.71 36.85,58.75 36.85,58.76 36.91,58.81 36.91,60.13 v3(36.95,60.17) ; v3(36.34,43.92) 36.33,43.92 36.25,44 34.27,44 ; 37.29,62.69 37.29,62.13 v3(37.38,62.04)
  LAYER_3 w0.075: v5(37.69,41.57) 38,41.57 38.21,41.36 38.45,41.36 38.52,41.43 39.22,41.43 39.24,41.41 ; 29.63,64.29 29.51,64.29 29.39,64.17 ; 24.66,30.82 24.6,30.87 24.6,31.99 24.53,32.07 ; 38.95,45.85 39.96,44.84 v3(40.79,44.84) v3(41.15,44.84) v3(42.04,44.84) ; 9.23,49.74 7.29,49.74 ; v3(35.21,42.57) 35.23,42.55 35.73,42.55 v3(35.78,42.5) 35.81,42.53 36.17,42.53 v5(36.21,42.49)
  LAYER_3 w0.1: v2(43.19,42.38) 43.05,42.33 42.82,41.77 42.47,41.41 39.24,41.41 ; v3(13.03,52.57) 13.03,52.66 11.9,53.78 v3(11.9,53.92) ; v3(36.46,41.27) 36.62,41.11 v5(36.74,41.11) v3(37.23,41.11) ; v7(41.82,49.45) 41.83,49.45 41.92,49.36 42.44,49.36 v7(42.52,49.28) ; v3(17.9,61.38) v3(18.08,61.2) ; v3(16.54,59.34) v3(16.72,59.16)
  LAYER_3 w0.175: v7(39.98,48.88) v3(40.1,48.76) ; v3(26.08,55.42) v3(26.08,55.24) ; v3(24.28,58.9) v3(24.41,58.75) ; v3(33.18,60.81) v3(33.18,60.63) ; v3(30.61,53.01) v3(30.79,53.01) ; v3(29.19,53.45) v3(29.06,53.57) ; v3(29.19,53.45) v3(29.33,53.57) ; v3(29.19,53.45) v3(29.33,53.34) ; v3(29.19,53.45) v3(29.06,53.34) ; v3(29.06,53.57) v3(29.33,53.57) ; v3(29.06,53.57) v3(29.06,53.34) ; v3(34.9,48.35) v3(34.9,48.17) v3(34.9,47.99) ; v3(33.89,44.09) v3(34.06,44.09) ; v3(31.09,52.3) v7(30.86,52.34) v3(30.96,52.5) ; v3(31.09,52.3) v3(31.27,52.46) v3(30.96,52.5) ; v3(31.09,52.3) v3(30.96,52.5) ; v3(32.99,62.12) v3(32.99,61.92) v3(32.99,61.72) ; v3(29.33,53.34) v3(29.33,53.57) ; v3(29.33,53.34) v3(29.5,53.34) ; v3(29.33,53.34) v3(29.06,53.34) ; v3(29.33,53.57) v3(29.5,53.34) ; v3(29.33,53.57) v3(29.5,53.57) v3(29.5,53.34) ; v5(39.56,62.13) v3(39.56,61.95) v3(39.56,61.77) v7(39.56,61.59) ; v3(24.29,59.38) v3(24.41,59.52) ; v3(29.31,52.5) v3(29.16,52.34) ; v3(29.31,52.5) v3(29.07,52.5) ; v3(29.31,52.5) v3(29.32,52.26) ; v3(29.31,52.5) v3(29.49,52.5) v3(29.49,52.32) v3(29.32,52.26) ; v3(29.16,52.34) v3(29.07,52.18) ; v3(29.16,52.34) v3(29.07,52.5) ; v3(29.16,52.34) v3(29.32,52.26) ; v3(10.6,52.32) v3(10.84,52.46) ; v3(17.77,59.22) v3(17.99,59) v3(18.23,59.19) v3(18.48,59) ; v3(32.97,54.27) 33.21,54.51 v3(33.21,54.52) v3(32.75,54.44) 32.7,54.48 v3(32.26,54.48) 32.2,54.48 v3(32,54.68) ; v3(32.12,40.78) v3(32.3,40.78) ; v3(29.07,52.18) v3(29.07,52.5) ; v3(29.07,52.18) v3(29.32,52.26) ; v3(42.1,43.66) v7(42.28,43.66) ; v3(35.47,44.4) v3(35.65,44.4) ; v3(23.72,38.39) v3(23.87,38.29) ; v3(22,20.71) v3(22.18,20.71) ; v3(37.38,62.04) v3(37.38,61.84) v3(37.38,61.63) ; v3(34.46,48.1) v3(34.46,47.92) ; v3(40.6,37.55) v3(40.42,37.55) v3(40.24,37.55) ; v3(24.44,56.38) v3(24.44,56.2) ; v3(20.21,50.92) v3(20.21,50.74) ; v3(19.32,20.7) v3(19.32,20.53) ; v5(60.5,49.23) v3(60.5,49.47) v5(60.5,49.65) ; v3(21.49,21) v3(21.67,21) ; v4(31.8,48.07) v4(31.8,48.25) ; v3(37.53,45) v3(37.71,45) ; v3(39.63,47.98) v3(39.88,47.73) ; v3(36.49,61.67) v3(36.49,61.85) v3(36.49,62.04) ; v3(23.57,54.73) v3(23.57,54.55) ; v7(10.56,33.46) v7(10.56,33.65) ; v3(19.02,15.94) v3(19.2,15.94) v3(19.38,15.94) ; v3(20.28,15.93) v3(20.46,15.93) v3(20.64,15.93) ; v5(33.52,41.44) v5(33.7,41.44) ; v7(54.79,15.85) v7(54.79,15.67) ; v3(27.57,55.58) v3(27.57,55.4) ; v7(55.68,15.9) v7(55.68,15.71) ; v5(9.12,16.77) v5(9.12,16.37) ; v3(29.26,57.22) v3(29.26,57.02) ; v3(29.26,57.22) v7(29.09,57.28) ; v3(29.26,57.22) v7(29.44,57.28) ; v7(40.05,61.06) v7(40.05,61.24) ; v3(18.66,62.3) v3(18.84,62.3) ; v3(24.43,57.22) v3(24.54,57.09) ; v3(21.48,50.84) v3(21.48,50.67) ; v3(58.97,12.59) v3(59.22,12.59) ; v3(38.19,62.05) v3(38.19,61.87) v3(38.19,61.69) ; v3(38.16,48.76) 38.17,48.76 v3(38.17,49.3) v7(38.17,49.48) ; v3(32.34,62.11) v3(32.34,61.91) v3(32.34,61.71) ; v3(25.96,37.86) v3(26.14,37.86) ; v3(40.92,39.65) v3(40.74,39.65) v3(40.56,39.65) v3(40.38,39.65) ; v3(22.82,15.84) v5(23,15.84) v3(23.18,15.84) ; v3(36.19,35.61) v3(36.37,35.61) ; v3(40.53,41.84) v3(40.53,42.02) ; v3(37.05,34.76) v3(37.23,34.76) v3(37.41,34.76) ; v3(9.12,33.72) v3(9.12,33.54) ; v3(21.73,60.94) v3(21.85,60.81) ; v3(22.86,20.68) v3(23.04,20.68) ; 31.79,62.01 v3(31.8,62.02) 31.73,62.02 v3(31.64,62.11) v3(31.64,61.91) v3(31.64,61.7) 31.68,61.7 v3(31.79,61.81) 31.79,62.01 ; v3(11.35,20.97) v3(11.17,20.97) v3(11.26,20.8) v3(11.35,20.97) ; v3(11.17,20.21) v5(11.26,20.04) v3(11.35,20.21) v3(11.17,20.21) ; v3(25.18,20.4) v3(25.27,20.56) v3(25.09,20.56) v3(25.18,20.4) ; v3(16.72,59.16) v3(16.54,59.16) v3(16.54,59.34) v3(16.72,59.34) v3(16.72,59.16) ; v3(17.9,61.38) v3(17.9,61.2) v3(18.08,61.2) v3(18.08,61.38) v3(17.9,61.38) ; v3(33.69,48.51) v3(33.53,48.42) v3(33.69,48.33) v3(33.69,48.51)
  LAYER_3 w0.25: v2(18.48,54.99) 18.23,54.74 v3(17.74,54.74) 17.67,54.67 v2(17.67,53.91)
  LAYER_4 w0.045: v7(46.37,24.84) 46.51,24.74 v3(46.53,24.74)
  LAYER_5 w0.045: 27.53,56.28 30.46,56.28 v5(30.47,56.27) 30.53,56.33 31.27,56.33 v7(31.28,56.32) ; 27.53,56.28 27.05,56.28 26.41,55.64 26.41,55.4 ; 27.53,56.28 26.48,55.24 ; 19.07,50.27 19.22,50.12 19.22,38.65 v5(19.13,38.56) 18.6,38.56 18.57,38.53 18.57,50.07 18.76,50.27 ; 19.07,50.27 18.76,50.27 ; 19.07,50.27 19.01,50.33 v5(18.91,50.33) ; 21.1,55.62 21.16,55.62 22.29,54.49 22.29,52.25 22.23,52.18 22.23,51.24 22.57,50.9 22.57,48.88 22.43,48.73 22.43,43.81 v5(22.12,43.5) 22.12,41.98 22.26,41.84 22.26,39.73 22.08,39.73 22.08,39.31 22.24,39.31 22.33,39.22 22.46,39.22 22.56,39.31 22.56,39.45 22.47,39.54 22.47,41.02 22.5,41.05 ; 21.1,55.62 21.1,55.5 20.86,55.26 20.86,54.96 21.31,54.51 21.51,54.51 21.61,54.42 21.61,54.2 ; 21.1,55.62 v5(21.1,56.16) ; v5(23.68,34.91) 23.65,34.94 ; 23.65,34.94 23.65,34.58 23.54,34.47 23.54,34.31 23.68,34.16 24.97,34.16 25.12,34.31 25.12,34.42 ; 23.65,34.94 23.65,35.36 23.9,35.61 23.9,36.19 25.96,38.25 25.96,54.22 27.64,55.91 30.62,55.91 30.67,55.96 30.77,55.96 v7(30.78,55.97) 30.83,56.02 31.02,56.02 31.33,55.71 31.73,55.71 32.14,55.3 32.14,55.16 31.97,54.99 31.97,54.4 31.59,54.02 31.42,54.02 31.23,53.83 30.08,53.83 30.03,53.88 27.96,53.88 27.65,53.57 27.65,37.35 25.99,35.69 25.94,35.69 25.79,35.54 25.79,35.32 25.8,35.31 25.8,34.81 25.65,34.66 25.56,34.66 ; v5(23.24,35.21) 23.3,35.27 ; 23.3,35.27 23.3,34.68 23.25,34.63 23.25,33.71 23.35,33.61 23.35,33.56 v5(23.42,33.56) ; 23.3,35.27 23.3,35.43 23.6,35.73 23.6,36.34 25.51,38.26 25.51,38.41 v7(25.56,38.45) 25.51,38.49 25.51,38.79 v7(25.56,38.83) 25.51,38.87 25.51,39.34 v5(25.55,39.37) 25.51,39.4 25.51,40.31 v5(25.56,40.35) 25.51,40.39 25.51,41.31 v5(25.55,41.34) 25.58,41.37 25.58,54.33 26.41,55.16 ; 24.42,43.2 23.67,42.45 23.67,42.26 ; 18.76,50.27 19.38,50.88 ; 20.34,54.61 20.34,54.33 20.68,53.99 21.16,53.99 ; 20.34,54.61 20.32,54.63 20.32,56.58 20.34,56.6 19.71,57.23 19.71,57.78 20.13,58.2 20.13,58.54 20.02,58.64 19.71,58.64 ; 20.34,54.61 20.54,54.61 21.16,53.99 ; 19.27,55.98 19.34,56.05 19.34,56.31 19.14,56.51 18.87,56.51 17.34,58.04 16.01,58.04 14.99,57.02 14.99,39.27 v7(15.17,39.09) 15.27,39.09 15.34,39.16 15.34,39.92 v7(15.38,39.96) 15.18,40.16 15.18,52.26 ; 19.27,55.98 19.32,55.96 19.34,55.92 19.34,55.61 19.28,55.55 19.28,53.57 v5(19.34,53.51) 19.71,53.14 19.71,51.51 20.55,50.67 20.55,49.99 21.07,49.47 21.07,37.81 20.95,37.69 v7(20.93,37.69) 20.86,37.62 20.86,36.21 20.92,36.15 20.92,35.99 20.8,35.88 20.67,35.88 20.58,35.97 20.58,36.12 20.64,36.18 20.64,37.93 ; 19.27,55.98 v5(19.08,55.98) 18.99,55.98 ; v7(21.53,47.14) 21.59,47.08 21.59,47 21.6,46.99 ; 21.53,53.8 21.35,53.8 21.16,53.99 ; 21.53,53.8 21.61,53.88 21.61,54.2 ; 21.53,53.8 21.51,53.78 21.51,52.39 21.82,52.08 21.91,52.08 22.01,51.99 22.01,51.68 21.85,51.53 21.72,51.53 21.59,51.66 21.59,51.88 21.21,52.26 21.21,53.39 21.01,53.58 20.65,53.58 19.98,54.25 19.98,56.53 19.42,57.09 19.42,58.16 19.71,58.46 19.71,58.64 ; 15.18,52.26 15.18,56.94 16.09,57.85 17.16,57.85 18.99,56.02 18.99,55.98 ; 15.18,52.26 15.23,52.26 v5(15.32,52.35) 15.51,52.54 15.51,57.1 16.14,57.73 17.11,57.73 17.24,57.6 v7(17.24,57.38) 17.24,56.4 16.91,56.07 16.91,55.72 17.05,55.58 17.05,55.58 17.09,55.53 17.09,45.53 v5(17.68,44.94) 17.75,44.87 v5(17.75,37.75) 17.75,37.74 v5(18.65,36.84) 18.74,36.75 18.74,25.11 arc(18.69,25.01) 18.59,24.96 ; v5(31.29,58.99) 31.15,58.94 30.83,58.94 30.79,58.89 26.64,58.89 26.2,59.33 26.2,60.58 26.6,60.98 v7(26.6,61.07) ; v7(31.65,47.86) 31.65,48.11 31.59,48.18 31.59,48.48 31.54,48.53 31.54,48.71 32.78,49.96 32.78,50.39 32.85,50.45 32.85,50.8 32.64,51.01 32.42,50.8 32.42,50 31.23,48.81 31.23,48.48 31.24,48.47 v7(31.24,48.26) ; 59.15,61.53 59.18,61.5 59.18,61.21 59.13,61.16 ; v7(53.32,34.15) 53.38,34.21 53.65,34.21 53.87,33.99 ; 20.64,37.93 v7(20.61,37.9) ; 20.64,37.93 20.65,37.94 20.74,37.94 20.87,38.07 20.87,49.39 20.35,49.91 20.35,50.6 19.61,51.34 19.6,51.34 ; v7(21.29,34.57) 21.35,34.57 ; 19.6,51.34 19.6,51.11 19.38,50.88 ; 19.6,51.34 19.36,51.58 v4(19.36,52.91) 18.99,53.28 ; v5(22.81,36.93) 22.81,37.13 24.11,38.43 24.11,41.22 v5(24.13,41.24) ; v5(22.81,36.93) 22.85,36.89 22.87,36.59 22.87,36.43 ; v5(22.81,36.93) 22.74,36.93 22.34,36.53 22.34,36.27 v7(22.4,36.21) ; 25.56,34.66 25.64,34.58 25.64,34.23 25.55,34.14 25.3,34.14 25.13,33.97 23.98,33.97 23.72,33.71 ; 25.56,34.66 25.44,34.66 25.31,34.8 25.31,35.63 27.26,37.58 27.26,53.69 28.04,54.48 28.1,54.48 ; 28.82,47.4 28.56,47.4 28.48,47.32 28.48,46.88 28.64,46.72 28.82,46.72 ; 28.82,47.4 28.82,46.72 ; 28.82,47.4 28.82,47.59 v7(28.55,47.86) ; v5(36.21,42.49) 36.21,42.3 36.45,42.06 ; 26.41,55.16 26.41,55.4 ; 26.41,55.16 26.48,55.24 ; 26.41,55.4 v5(26.48,55.33) 26.48,55.24 ; v5(29.06,48.69) 28.83,48.45 28.57,48.45 28.48,48.36 28.48,47.93 v7(28.55,47.86) ; 21.61,54.2 21.6,54.19 21.36,54.19 20.67,54.88 20.67,55.47 20.71,55.51 20.71,56.25 v5(20.73,56.27) 20.71,56.29 20.71,56.45 21.1,56.84 21.23,56.84 21.32,56.75 21.32,56.62 21.29,56.58 21.29,56.34 21.36,56.27 21.36,55.73 22.48,54.6 22.48,52.16 22.42,52.09 22.42,51.34 22.76,51 22.76,49.15 v5(22.85,49.06) 22.94,48.97 22.94,47.98 v5(22.84,47.88) 22.79,47.88 22.76,47.86 22.76,43.73 22.31,43.28 22.31,42.09 22.45,41.95 22.45,41.1 22.5,41.05 ; 28.1,54.48 28.1,54.5 28.27,54.66 29.88,54.66 30.04,54.5 ; 28.1,54.48 28.94,54.48 29.1,54.32 29.91,54.32 29.98,54.39 ; v7(29.09,57.28) 28.81,57.28 28.76,57.23 26.61,57.23 25.48,56.1 25.48,56.06 25.43,56.01 25.43,55.68 25.4,55.68 24.64,54.92 24.64,42.91 23.95,42.23 v5(23.71,42.23) 23.67,42.27 23.67,42.26 ; 18.91,24.22 18.91,24.07 ; 18.91,24.22 18.91,24.66 arc(18.87,24.86) v5(18.75,25.03) arc(18.67,25.01) 18.59,24.96 ; 18.91,24.22 arc(18.89,24.26) v5(18.85,24.28) 18.7,24.28 ; 18.91,24.07 18.91,21.74 ; 18.91,24.07 arc(18.84,24.22) 18.7,24.28 ; 18.99,53.28 18.99,51.13 v5(18.79,50.93) 18.19,50.33 18.19,38.13 v7(18.26,38.06) ; 18.99,53.28 18.99,55.98 ; v5(26.5,60.35) 26.52,60.33 26.52,59.35 26.78,59.09 30.72,59.09 30.85,59.22 v5(30.87,59.22) ; 58.71,45.06 58.71,44.7 ; 24.44,55.17 24.28,55.17 24,54.89 24,54.59 24.05,54.54 24.05,53.39 24,53.35 24,52.85 24.22,52.64 24.34,52.64 24.44,52.74 24.44,55.17 ; 24.44,55.17 24.44,55.31 25.01,55.89 25.01,55.96 26.89,57.84 26.94,57.84 29.82,57.84 v7(29.86,57.8) ; 35.79,43.53 35.79,42.83 v7(35.84,42.78) ; 19.86,49.38 19.86,50.54 19.76,50.63 19.76,50.7 19.62,50.84 19.57,50.84 19.53,50.88 19.38,50.88 ; 19.86,49.38 19.86,37.25 19.76,37.14 v7(19.76,37.12) v7(19.76,36.59) 19.69,36.59 20.03,36.25 20.32,36.25 20.51,36.44 20.51,49.15 20.28,49.38 19.86,49.38 ; 22.5,41.05 v7(22.57,41.05) ; v7(56.91,64.04) 56.94,64.01 57.25,64.01 57.48,63.78 57.48,63.06 ; v5(10.36,61.32) 10.3,61.26 10.3,60.94 10.7,60.54 12.98,60.54 v5(13.06,60.62) ; 28.82,46.72 28.79,46.69 28.79,35.72 35.44,29.07 v7(35.44,28.28) ; 25.93,34.01 25.75,33.83 v5(25.75,33.64) ; 21.6,46.99 21.49,46.99 21.44,46.94 21.44,46.44 21.58,46.3 v5(21.6,46.3) 21.77,46.46 21.77,46.94 21.72,46.99 21.6,46.99 ; 19.71,58.64 18.34,58.64 ; 6.21,60.41 6.21,60.06 ; v7(30.01,5.42) 30.02,5.41 31,5.41 31.81,6.22 v5(31.93,6.22) v7(33.13,6.22) v5(33.96,6.22) ; 18.91,19.52 18.91,19.09 22.22,15.78 23.71,15.78 27.29,12.2 v5(27.76,12.2) ; 7.65,55.7 7.86,55.91 7.98,55.91 ; v7(29.44,57.28) 29.67,57.28 29.88,57.49 30.6,57.49 30.71,57.38 31.13,57.38 31.22,57.29 31.86,57.29 31.99,57.42 v5(32.25,57.42) ; 23.67,42.26 v5(23.67,41.71) 23.67,41.44 v5(23.65,41.42) 23.67,41.4 v7(23.67,41.05) v5(23.67,40.69) v7(23.67,38.85) 23.67,38.4 21.78,36.51 21.78,34.33 21.63,34.18 ; 54.9,36.56 54.43,37.03 54.43,38.06 55.01,38.64 55.35,38.64 55.99,39.27 v5(55.99,40.87) ; E1073.2 32.23,48.25 v4(32.07,48.25) ; 28.55,47.84 v7(28.55,47.86) ; v7(32.27,51.75) 32.28,51.75 32.48,51.55 32.48,51.29 32.13,50.95 32.13,50.11 30.89,48.87 30.89,44.41 30.78,44.3 v7(30.78,43.8) 30.83,43.75 30.83,39.95 30.93,39.85 31.17,39.85 31.3,39.98 31.3,40.3 31.24,40.36 v5(31.24,47.86) ; v7(31.2,6.46) 31.2,6.04 30.98,5.82 30.49,5.82 ; v7(54.55,35.82) 54.55,35.86 54.45,35.96 54.45,36.22 54.54,36.31 ; 12.25,20.72 12.85,20.72 ; v7(30.16,58.13) 30.16,58.15 30.12,58.19 26.62,58.19 v5(26.59,58.15) 26.59,57.95 24.73,56.09 24.73,56.07 23.71,55.05 23.71,54.46 23.76,54.4 23.76,53.51 23.72,53.46 23.72,52.74 24.09,52.37 24.09,43.4 23.21,42.52 v7(23.21,41.05) 23.21,38.35 21.41,36.55 21.41,35.27 ; 18.7,24.28 arc(18.57,24.33) 18.52,24.46 arc(18.52,24.48) 18.52,24.5 18.52,24.79 arc(18.53,24.89) 18.59,24.96 ; v5(54.14,35.83) 54.09,35.83 53.89,36.03 53.89,36.26 v5(54.03,36.4) 54.09,36.4 54.23,36.26 54.23,35.98 54.14,35.89 v5(54.14,35.83)
  LAYER_5 w0.05: 29.98,54.39 30.04,54.45 30.04,54.5 30.48,54.5 30.69,54.29 31.06,54.29 31.5,54.73
  LAYER_5 w0.07: v5(31.37,4.98) 31.37,4.98 ; 31.37,4.98 31.37,4.98 31.21,4.82 29.7,4.82 28.35,6.17 v5(28.35,6.24) ; 31.37,4.98 31.5,5.11 31.5,5.2 31.88,5.57 34.88,5.57 v5(35.07,5.76) 35.12,5.81 35.12,7.49 v5(35.18,7.55)
  LAYER_5 w0.075: v4(31.52,54.73) 31.43,54.73 31.43,54.74 31.22,54.95 30.15,54.95 30.06,55.04 28.05,55.04 26.86,53.85 26.86,37.82 24.77,35.73 24.77,34.77 25.12,34.42 ; 15.13,14.23 15.13,14.43 9.23,20.33 v4(9.23,20.54) 9.16,20.61 9.16,34.6 v4(9.04,34.72) v4(7.11,36.65) 6.87,36.88 6.87,47.78 6.9,47.81 6.9,48.21 6.85,48.27 ; 15.13,14.23 v5(15.12,14.23) ; 15.13,14.23 15.13,13.66 ; 24.34,52.64 24.42,52.56 24.42,43.2 ; v5(21.87,16.84) 21.79,16.84 21.39,17.23 v5(21.39,17.35) ; 22.01,18.09 22.1,18.18 22.67,18.18 22.72,18.23 ; v5(22.29,10.21) 22.29,10.21 ; 22.29,10.21 v5(21.39,11.1) 21.36,11.13 17.6,11.13 v5(17.59,11.13) 17.47,11.13 15.13,13.48 15.13,13.66 ; 22.29,10.21 22.38,10.11 25.14,10.11 28.35,6.9 v5(28.35,6.78) v5(28.35,6.24) ; v5(36.21,42.49) v7(35.84,42.78) ; 15.13,13.66 v5(15.12,13.66)
  LAYER_5 w0.15: E1116.1 40.7,47.06 ; E1116.1 40.87,46.88 ; E1116.1 40.7,46.7 ; 32.26,48.04 E1073.2 32.08,48.22
  LAYER_5 w0.175: v7(12.35,7.51) v7(12.53,7.51) v7(12.53,7.69) ; v7(12.35,7.51) v7(12.53,7.69) ; v7(12.35,7.51) v7(12.35,7.69) v7(12.53,7.69) ; v7(49.09,34.56) v7(49.08,34.38) ; v7(8.11,12.93) v7(8.3,12.93) ; v7(48.73,34.56) v7(48.72,34.38) ; v7(59.68,13.01) v7(59.68,12.82)
  LAYER_6 w0.175: v7(12.35,7.51) v7(12.53,7.51) v7(12.53,7.69) ; v7(12.35,7.51) v7(12.35,7.69) v7(12.53,7.69) ; v7(12.35,7.51) v7(12.53,7.69) ; v7(59.68,13.01) v7(59.68,12.82) ; v7(8.11,12.93) v7(8.3,12.93) ; v7(40.05,61.24) v7(40.05,61.06)
  LAYER_7 w0.045: v7(22.4,36.21) 22.4,36.22 22.4,36.23 22.38,36.26 ; 20.81,35.78 20.61,35.78 20.45,35.94 20.45,36.12 v7(20.54,36.21) 20.59,36.26 22.38,36.26 ; 20.81,35.78 v7(20.83,35.8) ; 20.81,35.78 v7(22.54,35.78) 22.93,35.78 v3(23.16,36.01) 23.16,36.09 22.99,36.26 22.87,36.26 ; 20.75,39.57 21.27,39.57 ; 21.27,39.57 28.9,39.57 ; 21.27,39.57 21.24,39.54 v7(21.24,39.53) ; v7(22.81,36.2) 22.87,36.26 ; 22.87,36.26 22.38,36.26 ; 28.01,62.97 28.38,62.97 ; v7(17.83,57.41) 18.16,57.41 19.45,58.7 19.94,58.7 ; 32.38,51.64 32.38,51.46 32.26,51.34 32.08,51.34 31.42,52 30.69,52 30.55,52.14 26.63,52.14 26.51,52.02 23.86,52.02 v7(23.76,52.12) 22.3,53.58 v7(22.12,53.58) ; 32.38,51.64 32.58,51.64 32.88,51.94 32.88,52.09 32.77,52.2 32.26,52.2 31.68,52.78 26.17,52.78 25.48,53.47 24.2,53.47 24.06,53.33 24.06,52.47 24.21,52.32 26.1,52.32 26.19,52.41 30.8,52.41 v7(30.86,52.34) 31.51,52.34 32.14,51.72 32.24,51.72 v7(32.27,51.75) 32.38,51.64 ; v7(55.4,49.46) 55.4,49.09 53.15,46.85 42.29,46.85 42.23,46.78 v7(42.15,46.78) ; 7.07,49.77 7.07,49.33 ; v7(33.85,62.9) 33.49,62.54 27.36,62.54 v7(27.27,62.63) ; v7(66.39,48.32) v6(66.52,48.45) ; 8.26,50.64 8.26,50.03
  LAYER_7 w0.05: 51.72,35.64 51.71,35.63 51.71,35.44 51.82,35.32 51.85,35.32
  LAYER_7 w0.075: v7(54.06,35.15) 54,35.15 53.83,35.32 51.85,35.32 ; 51.72,35.64 51.72,36.9 v7(51.58,37.04)
  LAYER_7 w0.175: v7(15.82,66.88) v7(15.82,67.06) v7(15.82,67.24) v7(15.82,67.42) ; v7(60.05,65.33) v7(59.05,65.33) ; v7(34.89,5.54) v7(34.89,5.36) ; v7(12.35,7.51) v7(12.53,7.51) v7(12.53,7.69) ; v7(12.35,7.51) v7(12.53,7.69) ; v7(12.35,7.51) v7(12.35,7.69) v7(12.53,7.69) ; v7(33.59,7.36) v7(33.59,7.19) ; v7(59.68,13.01) v7(59.68,12.82) ; v7(8.11,12.93) v7(8.3,12.93) ; v7(10.47,64.61) v7(10.65,64.61)
  BOTTOM w0.05: 7.58,64.9 7.58,64.83 v7(7.59,64.82)
  BOTTOM w0.15: 6.1,64.12 v7(6.1,64.4) ; v7(6.1,64.4) 5.85,64.4 ; v7(6.1,64.4) 6.1,64.68 ; 7.58,64.9 J350.6 7.58,65.96 ; C501.1 33.23,10.11 ; C501.1 33.25,9.74 ; C501.1 33.06,9.94 R500.1 ; v7(38.68,11.88) 38.63,11.93 v7(38.63,12.31) v7(38.09,12.31) ; v7(26.33,10.86) 26.33,11.24 ; v7(26.33,10.86) 26.08,10.86 ; v7(26.33,10.86) 26.58,10.86 ; v7(26.33,10.86) 26.33,10.48 ; 58.98,64.26 v7(58.98,64.55) C5322.1 ; C5307.1 52.37,64.53 C5318.1 ; C5307.1 52.86,64.28 ; C5307.1 53.13,64.53 ; L116.1 12.94,11.11 ; L116.1 12.56,11.46 ; L116.1 12.19,11.11 ; C502.1 28.93,10.52 ; C502.1 29.3,10.17 ; C502.1 28.55,10.17 ; 10.19,66.72 D510.2 ; D510.2 10.94,66.72 ; D510.2 10.57,66.46 ; D510.2 10.57,66.97 ; v7(8.04,68.72) 8.04,68.99 ; v7(8.04,68.72) D354.2 ; v7(8.04,68.72) D356.2 ; 49.69,67.32 J5300.50 49.89,67.71 ; 37.28,6.11 v7(37.28,5.91) 37.03,5.91 ; 32.5,10.5 R500.1 ; R500.1 32.87,10.48 ; J6400.4 J6400.2 ; J6400.4 37.14,10.35 37.13,10.36 ; J6400.4 J6400.6 ; J6400.2 37.69,9.98 ; J6400.2 37.49,10.36 ; 60.96,44.7 v7(60.96,45.23) 61.27,45.23 ; C5311.1 51.86,64.26 ; C5311.1 51.36,64.54 C5374.1 ; C5311.1 C5318.1 ; D354.2 8.54,68.97 ; D354.2 8.81,68.72 ; C5322.1 58.48,64.26 ; C5322.1 58.47,64.54 C5316.1 ; J5300.8 v7(57.24,67.86) ; v7(38.09,12.31) 38.09,12.03 ; v7(38.09,12.31) v7(37.59,12.31) ; 42.98,44.83 VR1020.2 ; VR1020.2 43.23,45.11 ; VR1020.2 43.23,44.56 ; C5310.1 v7(53.97,64.53) 53.97,64.25 ; C5310.1 53.47,64.28 ; C5310.1 53.19,64.53 ; 35.95,5.51 v7(35.95,5.74) 35.68,5.74 ; J5300.32 53.04,67.92 v7(53.03,67.93) ; 16.13,66.92 D518.2 ; D518.2 16.51,67.18 ; D518.2 16.51,66.67 ; D518.2 16.88,66.92 ; 24.56,10.41 C1532.1 24.31,10.69 ; 36.59,8.08 J6400.5 ; J6400.5 J6400.3 ; J6400.5 36.79,7.7 ; D353.2 7.47,64.68 ; D353.2 7.47,64.12 ; D353.2 7.72,64.4 ; 58.49,67.32 J5300.2 58.29,67.71 ; 6.48,63.67 C511.1 ; C511.1 7.18,63.67 ; C511.1 6.83,63.29 ; C511.1 6.83,64.05 ; 37.31,12.31 v7(37.59,12.31) ; v7(37.59,12.31) 37.59,12.06 ; 9.85,67.91 D350.2 ; D350.2 9.59,68.18 ; D350.2 9.85,68.46 ; 32.41,5.34 D506.1 32.68,5.57 ; C504.1 34.03,8.5 ; C504.1 v7(33.75,8.59) 33.75,8.84 ; C504.1 v7(33.75,8.41) 33.75,8.18 ; 54.29,43.04 VR4253.2 ; VR4253.2 54.66,43.06 ; VR4253.2 54.27,42.67 ; C5316.1 57.98,64.24 ; C5316.1 C5387.1 ; 36.75,5.74 D512.1 36.48,5.51 ; R5321.1 60.49,65.79 R5322.1 ; R5321.1 60.48,66.03 ; R5321.1 60.2,65.78 ; J6400.1 37.69,8.08 ; J6400.1 37.49,7.7 ; J6400.1 J6400.3 ; 37.78,6.22 C523.1 38.05,5.97 ; 7.96,64.22 VR510.2 ; VR510.2 8.33,63.74 ; VR510.2 8.33,64.7 ; 45.72,44.09 v7(45.72,44.34) 46,44.34 ; 35.81,1.73 D503.1 35.53,1.96 ; v7(56.19,68.24) v7(56.19,67.67) J5300.14 ; VR1511.2 25.75,12.69 ; VR1511.2 25.75,12.18 ; VR1511.2 25.37,12.44 ; VR1511.2 26.12,12.44 ; v7(59.98,64.53) 59.98,64.25 ; D351.2 10.81,67.63 ; D351.2 11.07,67.35 ; D351.2 10.81,67.07 ; 50.37,64.69 v7(50.37,64.97) 50.12,64.97 ; 32.13,3.78 D509.1 32.68,3.78 ; D356.2 7.54,68.97 ; D356.2 7.26,68.72 ; C5387.1 v7(57.47,64.38) 57.47,64.26 ; C5387.1 C5308.1 56.97,64.27 ; C5374.1 51.08,64.54 ; C5374.1 51.36,64.29 ; J6400.3 37.14,7.69 37.13,7.69 ; v7(55.15,42.17) 55.14,42.17 54.93,41.95 ; 33.02,1.83 D514.1 33.29,2.06 ; 30.7,5.25 v7(30.7,5.5) 30.42,5.5 ; 36.58,1.96 D502.1 36.31,1.73 ; 31.23,5.4 v7(31.23,5.6) 31.48,5.6 ; 32.13,5.03 D508.1 32.41,5.26 ; 44.03,44.41 v7(44.3,44.41) 44.3,44.16 ; v7(35.59,11.98) 35.65,12.04 v7(35.65,12.31) v7(36.17,12.31) ; v7(36.67,12.31) 36.99,12.31 ; v7(36.67,12.31) 36.67,12.01 ; v7(36.67,12.31) v7(36.17,12.31) ; R5322.1 61.02,66.04 ; R5322.1 61.29,65.79 ; 52.37,64.23 52.36,64.24 C5318.1 ; v7(36.17,12.31) 36.17,12.01 ; v7(55.97,64.53) 55.97,64.23 ; 36.59,9.98 J6400.6 ; J6400.6 36.79,10.36 ; 58.35,44.04 VR4251.2 58.72,44.05 ; 49.89,65.26 J5300.49 49.69,65.65 ; J5300.20 v7(55.14,67.83) ; 32.5,1.83 D507.1 32.22,2.06 ; 36.65,3.66 v7(36.3,3.66) D504.1 35.51,3.66 ; J5300.26 v7(54.09,67.83) ; C5320.1 54.97,64.26
  BOTTOM w0.175: 12.43,11.5 12.43,11.25 L116.1 12.71,11.26 12.71,11.5
  BOTTOM w0.2: v7(43.83,49.55) C1024.1
  vias: v1(0.31,20.23) v1(0.36,19.37) v1(0.44,18.37) v1(0.44,52.2) v1(0.46,50.98) v1(0.48,49.2) v1(0.52,17.37) v1(0.59,16.36) v1(0.7,48.74) v1(0.67,15.36) v1(0.76,52.93) v1(0.84,18.28) v1(0.93,16.67) v1(1.07,52.86) v1(1.31,20.23) v1(1.5,50.41) v1(1.65,18.69) v1(1.7,16.36) v1(1.67,15.36) v1(1.82,53.35) v1(2.31,20.23) v1(2.46,18.38) v1(2.49,16.69) v1(2.47,15.36) v1(2.73,51.84) v1(2.65,48.1) v1(2.82,17.57) v1(3.11,15.36) v1(3.28,54.07) v1(3.3,46.28) v1(3.31,20.23) v1(3.41,64.79) v1(3.41,63.53) v1(3.41,62.49) v1(3.4,56.97) v1(3.4,55.18) v1(3.4,43.67) v1(3.4,40.67) v1(3.4,37.67) v1(3.42,19.41) v1(3.45,63.1) v1(3.6,61.35) v1(3.6,60.81) v1(3.6,60.28) v1(3.6,59.75) v1(3.6,59.22) v1(3.6,58.69) v1(3.6,58.16) v1(3.58,57.55) v1(3.59,48.88) v1(3.61,36.59) v1(3.6,35.51) v1(3.78,48.07) v1(3.8,15.35) v1(3.9,66.93) v1(3.91,65.67) v1(3.92,52.55) v1(3.91,51.53) v1(3.95,68.06) v1(3.95,50.03) v1(4.04,15.88) v1(4.05,50.76) v1(4.17,15.35) v1(4.28,57.01) v1(4.25,18.94) v1(4.41,18.2) v1(4.39,16.31) v1(4.5,67.02) v1(4.46,51.52) v1(4.5,47.62) v1(4.54,46.85) v1(4.49,15.64) v1(4.72,66.57) v1(4.74,56.3) v1(4.81,44.15) v1(4.79,35.51) v1(4.89,55.11) v1(4.85,54.46) v1(4.85,51.55) v1(4.91,49.5) v1(5.06,68.22) v1(5.13,57.89) v1(5.07,52.75) v1(5.15,58.65) v1(5.17,56.8) v1(5.17,17.37) v1(5.17,17.19) v1(5.17,17.01) v1(5.16,16.33) v1(5.16,16.15) v1(5.16,15.97) v1(5.25,18.94) v1(5.26,16.67) v1(5.43,67.88) v1(5.53,60.16) v1(5.51,48.03) v1(5.51,46.29) v1(5.46,15.62) v1(5.55,63.9) v1(5.55,62.83) v1(5.61,59.25) v1(5.55,58.13) v1(5.63,54.33) v1(5.57,45.24) v1(5.67,66.19) v1(5.67,17.22) v1(5.87,67.65) v1(5.87,53.12) v1(5.91,49.5) v1(5.92,15.62) v1(5.97,65.26) v1(5.98,64.5) v1(5.95,59.74) v1(6.1,58.08) v1(6.09,56.17) v1(6.04,54.13) v1(6.09,44.64) v1(6.12,43.49) v1(6.12,41.27) v1(6.16,58.67) v1(6.23,45.36) v1(6.19,35.51) v1(6.29,68.24) v1(6.34,63.35) v1(6.32,52.83) v1(6.26,38.65) v1(6.25,18.94) v1(6.39,36.6) v1(6.45,62.13) v1(6.47,50.2) v1(6.64,66.05) v1(6.6,58.66) v1(6.59,57.87) v1(6.56,18.43) v1(6.84,61.43) v1(6.75,52.5) v1(6.9,64.38) v1(6.91,64.11) v1(6.92,56.02) v1(7.02,67.03) v1(7.01,63.34) v1(7.02,57.73) v1(7.02,32.26) v1(7.02,31.24) v1(7.02,30.48) v1(7.02,28.09) v1(7.01,27) v1(7.03,25.44) v1(7.03,23.44) v1(7.03,20.24) v1(7.01,19.62) v1(7.03,19.01) v1(6.99,15.64) v1(7.07,65.19) v1(7.06,55.12) v1(7.06,54.72) v1(7.06,52.72) v1(7.1,46.18) v1(7.09,44.97) v1(7.06,29.3) v1(7.2,68.72) v1(7.15,49.3) v1(7.34,63.35) v1(7.25,59.91) v1(7.34,24.79) v1(7.4,54.12) v1(7.4,52.92) v1(7.41,51.39) v1(7.38,43.52) v1(7.36,26.35) v1(7.37,21.89) v1(7.38,20.88) v1(7.39,20.11) v1(7.37,19.08) v1(7.38,17.64) v1(7.42,15.22) v1(7.44,62.28) v1(7.44,62.06) v1(7.47,50.35) v1(7.47,42.32) v1(7.47,39.74) v1(7.48,35.51) v1(7.44,29.75) v1(7.61,67.65) v1(7.64,37.24) v1(7.64,31.89) v1(7.57,16.14) v1(7.66,64.12) v1(7.72,27.79) v1(7.73,6.72) v1(7.76,61.32) v1(7.83,57.99) v1(7.74,56.56) v1(7.75,53.12) v1(7.75,44.64) v1(7.79,28.65) v1(7.74,15.39) v1(7.78,14.87) v1(7.82,14.35) v1(7.82,13.78) v1(7.82,13.23) v1(7.82,12.68) v1(7.9,66.85) v1(7.88,66.06) v1(7.89,56.45) v1(7.86,31.23) v1(7.93,29.61) v1(7.89,19.28) v1(8.01,69.32) v1(7.95,64.72) v1(8.01,57.99) v1(8.01,8.29) v1(8.08,62.31) v1(8.08,62.11) v1(8.09,52.92) v1(8.09,52.52) v1(8.11,42.8) v1(8.12,40.94) v1(8.05,30.45) v1(8.13,28.15) v1(8.11,27.39) v1(8.19,65.2) v1(8.21,46.47) v1(8.23,44.23) v1(8.14,28.88) v1(8.33,62.62) v1(8.26,39.51) v1(8.25,30.06) v1(8.29,22.06) v1(8.24,15.6) v1(8.24,14.41) v1(8.47,65.19) v1(8.49,56.56) v1(8.44,53.52) v1(8.5,53.08) v1(8.44,52.72) v1(8.52,51.52) v1(8.44,48.92) v1(8.48,36.24) v1(8.52,12.68) v1(8.64,66) v1(8.64,56.44) v1(8.56,47.6) v1(8.61,27.62) v1(8.65,68.56) v1(8.67,67.65) v1(8.69,61.31) v1(8.67,49.53) v1(8.71,41.26) v1(8.67,31.23) v1(8.72,30.69) v1(8.68,15.16) v1(8.79,53.32) v1(8.79,52.92) v1(8.79,52.52) v1(8.75,39.92) v1(8.76,29.84) v1(8.79,17.57) v1(8.74,13.84) v1(8.87,63.06) v1(8.87,28.76) v1(8.88,26.68) v1(8.99,69.33) v1(9.03,62.3) v1(9.03,62.07) v1(9.03,19.75) v1(9.13,53.12) v1(9.13,52.72) v1(9.12,18.76) v1(9.12,18.36) v1(9.12,17.96) v1(9.07,14.82) v1(9.15,67.32) v1(9.15,64.66) v1(9.14,50.72) v1(9.22,35.5) v1(9.16,30.83) v1(9.16,30.65) v1(9.14,27.39) v1(9.19,21.91) v1(9.22,12.67) v1(9.29,63.32) v1(9.34,57.28) v1(9.24,56.56) v1(9.24,19.36) v1(9.25,15.79) v1(9.25,14.22) v1(9.27,13.57) v1(9.38,68.63) v1(9.38,56.69) v1(9.42,51.28) v1(9.39,15.15) v1(9.45,66.63) v1(9.45,66.41) v1(9.45,65.86) v1(9.49,64.9) v1(9.49,59.76) v1(9.48,54.92) v1(9.48,53.32) v1(9.48,52.92) v1(9.53,42.25) v1(9.53,39.08) v1(9.52,18.77) v1(9.45,17.57) v1(9.49,6.41) v1(9.63,65.86) v1(9.63,63.58) v1(9.64,61.3) v1(9.55,52.51) v1(9.63,30.1) v1(9.57,27.7) v1(9.68,66.63) v1(9.7,63.94) v1(9.71,50.35) v1(9.66,49.5) v1(9.7,29.74) v1(9.73,18.39) v1(9.7,17.05) v1(9.8,69.3) v1(9.83,68) v1(9.77,66.87) v1(9.75,66.4) v1(9.81,65.86) v1(9.84,65.1) v1(9.74,64.9) v1(9.83,53.12) v1(9.83,51.92) v1(9.77,48.04) v1(9.83,26.49) v1(9.82,17.92) v1(9.81,15.29) v1(9.76,7.99) v1(9.88,66.61) v1(9.9,63.61) v1(9.85,58.1) v1(9.88,52.68) v1(9.86,50.72) v1(9.88,37.82) v1(9.85,17.57) v1(9.93,16.57) v1(9.99,65.86) v1(9.99,62.6) v1(9.99,62.42) v1(9.99,62.23) v1(9.99,62.04) v1(9.99,61.85) v1(9.99,61.66) v1(10,61.47) v1(9.99,56.56) v1(10.04,22.26) v1(9.96,14.45) v1(9.97,12.68) v1(10.1,67.28) v1(10.1,67.03) v1(10.1,66.72) v1(10.1,66.39) v1(10.09,65.1) v1(10.12,53.77) v1(10.11,52.52) v1(10.13,30.77) v1(10.07,30.6) v1(10.07,28.67) v1(10.05,14.95) v1(10.09,13.38) v1(10.18,62.6) v1(10.18,61.85) v1(10.18,61.66) v1(10.19,61.47) v1(10.17,53.32) v1(10.19,52.98) v1(10.18,35.13) v1(10.17,31.86) v1(10.23,12.94) v1(10.2,12.38) v1(10.29,69.3) v1(10.3,68.48) v1(10.25,18.37) v1(10.25,17.57) v1(10.25,16.77) v1(10.25,16.37) v1(10.43,67.6) v1(10.38,42.21) v1(10.44,67.17) v1(10.44,66.89) v1(10.44,66.4) v1(10.5,65.35) v1(10.5,65.16) v1(10.45,57.79) v1(10.52,55.12) v1(10.52,54.72) v1(10.52,54.32) v1(10.49,53.47) v1(10.46,53.12) v1(10.52,52.72) v1(10.46,30.77) v1(10.46,29.54) v1(10.5,28.65) v1(10.51,22.06) v1(10.59,63.33) v1(10.63,45.89) v1(10.58,42.88) v1(10.61,40.09) v1(10.56,38.19) v1(10.58,37.09) v1(10.64,36.34) v1(10.58,14.09) v1(10.55,13.16) v1(10.54,12.67) v1(10.67,65.8) v1(10.73,60.32) v1(10.73,59.92) v1(10.73,59.52) v1(10.66,50.41) v1(10.65,17.57) v1(10.65,17.17) v1(10.65,16.3) v1(10.72,14.58) v1(10.76,62.23) v1(10.75,61.53) v1(10.77,58.23) v1(10.77,58.05) v1(10.8,34.51) v1(10.89,68.37) v1(10.92,64.3) v1(10.93,63.11) v1(10.91,49.5) v1(10.92,38.26) v1(10.91,28.27) v1(10.86,27.27) v1(10.85,12.4) v1(10.86,12.14) v1(10.94,53.32) v1(10.94,52.93) v1(10.99,48.9) v1(11.02,31.26) v1(10.94,30.18) v1(11.01,18.79) v1(11.02,12.84) v1(11.04,19.35) v1(11.15,60.48) v1(11.14,39.76) v1(11.14,39.23) v1(11.21,31.59) v1(11.15,29.43) v1(11.17,28.72) v1(11.14,28.25) v1(11.16,26.92) v1(11.16,26.22) v1(11.17,14.47) v1(11.2,14.08) v1(11.28,49.51) v1(11.25,27.96) v1(11.24,12.01) v1(11.24,11.31) v1(11.37,68.38) v1(11.41,64.3) v1(11.35,62.51) v1(11.35,61.72) v1(11.35,48.03) v1(11.39,40.63) v1(11.39,33.91) v1(11.41,14.98) v1(11.4,13.75) v1(11.53,69.33) v1(11.44,66.63) v1(11.53,63.69) v1(11.52,56.55) v1(11.48,37.46) v1(11.54,35.79) v1(11.5,34.89) v1(11.49,32.91) v1(11.49,32.13) v1(11.47,31.05) v1(11.47,30.42) v1(11.52,23.39) v1(11.53,22.87) v1(11.46,18.27) v1(11.46,17.2) v1(11.45,16.39) v1(11.59,66.3) v1(11.56,51.32) v1(11.63,29.81) v1(11.58,27.51) v1(11.64,18.66) v1(11.6,10.96) v1(11.65,19.15) v1(11.73,13.65) v1(11.83,59.67) v1(11.83,59.49) v1(11.84,58.22) v1(11.84,58.03) v1(11.8,49.69) v1(11.84,41.08) v1(11.75,29.23) v1(11.78,17.85) v1(11.87,68.38) v1(11.9,53.52) v1(11.9,53.12) v1(11.9,51.92) v1(12,36.44) v1(12,35.44) v1(12,34.44) v1(12,33.44) v1(12,32.44) v1(12,31.44) v1(11.98,30.33) v1(11.95,28.38) v1(12,27.42) v1(11.96,21.59) v1(11.96,14.47) v1(12.09,13.4) v1(12.09,13.01) v1(12.07,11.25) v1(12.08,10.95) v1(12.06,10.45) v1(12.16,46.09) v1(12.21,42.37) v1(12.17,39.61) v1(12.16,14.04) v1(12.15,12.02) v1(12.28,60.16) v1(12.25,53.72) v1(12.26,50.92) v1(12.25,44.14) v1(12.3,29.34) v1(12.34,14.47) v1(12.32,13.2) v1(12.36,66.63) v1(12.35,59.57) v1(12.35,59.23) v1(12.4,57.27) v1(12.43,38.29) v1(12.37,15.02) v1(12.42,11.08) v1(12.42,10.54) v1(12.46,62.85) v1(12.52,34.25) v1(12.49,17.21) v1(12.44,11.6) v1(12.49,9.98) v1(12.56,58.38) v1(12.55,34.94) v1(12.63,33.09) v1(12.6,31.98) v1(12.6,31.35) v1(12.62,26.03) v1(12.63,25.66) v1(12.56,19.71) v1(12.63,14.39) v1(12.73,64.3) v1(12.66,40.18) v1(12.73,37.27) v1(12.68,35.37) v1(12.71,30.66) v1(12.67,21.72) v1(12.68,20.26) v1(12.66,14.01) v1(12.69,12.35) v1(12.78,39.36) v1(12.83,37.96) v1(12.86,48.24) v1(12.88,46.41) v1(12.86,44.35) v1(12.86,38.55) v1(12.92,37.47) v1(12.89,29.57) v1(13.03,68.44) v1(12.98,65.78) v1(12.95,50.2) v1(12.97,49.47) v1(12.94,20.52) v1(13.05,52.24) v1(13.09,41.08) v1(13.09,35.72) v1(13.12,30.63) v1(13.13,25.61) v1(13.05,13.96) v1(13.09,13.25) v1(13.11,12.8) v1(13.18,63.03) v1(13.18,58.37) v1(13.15,40.47) v1(13.19,39.73) v1(13.23,39.27) v1(13.2,28.75) v1(13.22,14.85) v1(13.16,14.59) v1(13.19,12.55) v1(13.15,12.25) v1(13.24,59.16) v1(13.33,37.83) v1(13.25,33.48) v1(13.25,33.08) v1(13.33,32.5) v1(13.27,31.19) v1(13.24,29.9) v1(13.29,28.13) v1(13.3,27.42) v1(13.34,17.26) v1(13.43,56.61) v1(13.43,56.14) v1(13.35,50.38) v1(13.4,35.46) v1(13.36,26.56) v1(13.47,53.76) v1(13.54,37.28) v1(13.52,27.74) v1(13.44,23.59) v1(13.53,21.82) v1(13.51,9.98) v1(13.63,64.3) v1(13.58,53.32) v1(13.55,36.72) v1(13.56,24.65) v1(13.56,24.46) v1(13.64,23.59) v1(13.55,19.01) v1(13.58,15.38) v1(13.67,66.64) v1(13.68,55.42) v1(13.68,54.91) v1(13.68,54.19) v1(13.67,50.36) v1(13.69,46.24) v1(13.67,44.1) v1(13.65,42.38) v1(13.71,18.27) v1(13.77,58.83) v1(13.8,53.8) v1(13.76,39.73) v1(13.81,25.89) v1(13.93,37.82) v1(13.86,37.24) v1(13.91,28.37) v1(13.88,14.6) v1(13.85,13.43) v1(13.86,13.16) v1(13.85,12.86) v1(13.87,12.38) v1(13.96,65.79) v1(13.97,55.97) v1(13.95,50.69) v1(14.03,34.64) v1(13.97,30.9) v1(13.97,30.4) v1(14.01,30.06) v1(14.01,29.49) v1(13.98,26.67) v1(14.04,24.74) v1(14.13,68.75) v1(14.11,61.5) v1(14.05,58.81) v1(14.07,31.34) v1(14.21,57.49) v1(14.21,40.17) v1(14.22,35.73) v1(14.19,29.12) v1(14.17,15.23) v1(14.26,57.95) v1(14.26,56.93) v1(14.34,55.97) v1(14.3,50.5) v1(14.31,38.6) v1(14.28,32.19) v1(14.27,25.17) v1(14.26,24.25) v1(14.26,22.83) v1(14.27,21.5) v1(14.38,60.78) v1(14.34,26.73) v1(14.42,16.8) v1(14.42,12.4) v1(14.4,9.98) v1(14.41,9.06) v1(14.54,66.64) v1(14.52,53.33) v1(14.46,51.51) v1(14.44,49.49) v1(14.44,37.84) v1(14.53,32.44) v1(14.46,18.35) v1(14.46,14.8) v1(14.53,11.67) v1(14.55,64.32) v1(14.59,47.08) v1(14.62,37.24) v1(14.55,23.58) v1(14.58,8.15) v1(14.65,63.03) v1(14.73,39.75) v1(14.65,38.6) v1(14.66,36.58) v1(14.69,29.88) v1(14.68,28.94) v1(14.67,11.24) v1(14.71,9.98) v1(14.77,68.74) v1(14.8,55.98) v1(14.78,41.08) v1(14.84,35.43) v1(14.78,32.68) v1(14.74,29.23) v1(14.81,22.46) v1(14.81,20.64) v1(14.74,20.09) v1(14.74,18.87) v1(14.86,45.15) v1(14.9,40.18) v1(14.86,34.74) v1(14.93,18.01) v1(14.93,15.72) v1(14.92,14.18) v1(14.91,8.69) v1(15.02,69.13) v1(14.97,66.27) v1(15.02,62.43) v1(15.01,60.4) v1(14.95,43.82) v1(15.03,32.44) v1(15.01,27.08) v1(15.01,25.95) v1(15.03,24.97) v1(15.03,24.22) v1(15.03,23.37) v1(14.96,16.55) v1(15.02,14.5) v1(15.04,12.58) v1(15.1,56.57) v1(15.11,53.33) v1(15.05,37.66) v1(15.13,30.04) v1(15.12,28.92) v1(15.11,27.98) v1(15.11,21.88) v1(15.07,20.06) v1(15.12,13.39) v1(15.12,10.8) v1(15.18,58.34) v1(15.23,21.06) v1(15.18,11.88) v1(15.17,11.26) v1(15.3,63.6) v1(15.28,61.07) v1(15.3,57.67) v1(15.33,37.48) v1(15.33,35.73) v1(15.34,34.74) v1(15.28,32.68) v1(15.29,16.36) v1(15.29,15.81) v1(15.29,15.35) v1(15.38,65.79) v1(15.35,39.77) v1(15.37,18.93) v1(15.5,68.13) v1(15.49,63.32) v1(15.49,57.67) v1(15.53,50.08) v1(15.53,49.49) v1(15.51,49) v1(15.52,32.94) v1(15.51,26.51) v1(15.45,26.08) v1(15.47,23) v1(15.45,17.76) v1(15.45,12.91) v1(15.6,44.17) v1(15.56,42.37) v1(15.6,40.01) v1(15.6,26.84) v1(15.61,24.35) v1(15.63,14.75) v1(15.56,14.06) v1(15.7,56.26) v1(15.72,32.19) v1(15.73,29.67) v1(15.71,23.74) v1(15.71,23.42) v1(15.68,12.63) v1(15.74,43.34) v1(15.78,35.38) v1(15.78,28.38) v1(15.78,27.98) v1(15.82,25.31) v1(15.77,21.07) v1(15.93,51.35) v1(15.93,51.17) v1(15.91,49.5) v1(15.86,40.31) v1(15.86,30.93) v1(15.86,30.43) v1(15.95,37.54) v1(16.12,54.63) v1(16.11,53.62) v1(16.05,52.34) v1(16.04,36.58) v1(16.11,33.5) v1(16.05,24.99) v1(16.11,13.99) v1(16.23,67.53) v1(16.19,66.59) v1(16.2,66.02) v1(16.15,64.8) v1(16.23,56.53) v1(16.14,41.23) v1(16.2,39.83) v1(16.21,35.72) v1(16.14,34.48) v1(16.18,22.96) v1(16.23,22.4) v1(16.28,63.92) v1(16.33,50.07) v1(16.31,29.95) v1(16.26,28.79) v1(16.36,56.68) v1(16.39,17.04) v1(16.38,16.3) v1(16.39,15.89) v1(16.4,15.46) v1(16.39,14.99) v1(16.39,14.53) v1(16.54,55.9) v1(16.44,27.07) v1(16.48,17.73) v1(16.51,8.16) v1(16.57,67.77) v1(16.59,55.06) v1(16.59,53.62) v1(16.6,49.02) v1(16.6,37.48) v1(16.62,35.39) v1(16.6,27.98) v1(16.6,23.58) v1(16.59,21.65) v1(16.68,63.08) v1(16.68,49.55) v1(16.69,40.44) v1(16.72,31.06) v1(16.66,20.11) v1(16.66,10.25) v1(16.75,51.39) v1(16.75,51.2) v1(16.81,34) v1(16.77,33.12) v1(16.8,19.6) v1(16.77,14.36) v1(16.78,8.8) v1(16.91,31.69) v1(16.87,23.05) v1(16.88,20.6) v1(16.86,11.07) v1(16.96,69.31) v1(16.98,49.5) v1(16.95,46.41) v1(17.13,27.98) v1(17.13,26.8) v1(17.09,26.46) v1(17.05,18.75) v1(17.07,12.41) v1(17.2,53.65) v1(17.14,28.38) v1(17.18,24.87) v1(17.18,24.03) v1(17.22,20.09) v1(17.15,15.16) v1(17.14,14.81) v1(17.18,8.45) v1(17.3,68.11) v1(17.32,37.53) v1(17.33,22.76) v1(17.29,9.45) v1(17.4,63.21) v1(17.43,39.85) v1(17.36,34.61) v1(17.36,34.43) v1(17.41,29.65) v1(17.37,17.78) v1(17.51,63.9) v1(17.53,51.29) v1(17.53,35.39) v1(17.5,32.09) v1(17.54,20.41) v1(17.5,18.37) v1(17.5,17.01) v1(17.49,16.12) v1(17.49,15.74) v1(17.49,15.34) v1(17.49,14.97) v1(17.46,12.97) v1(17.46,11.86) v1(17.46,10.88) v1(17.58,66.1) v1(17.58,65.32) v1(17.58,52.99) v1(17.61,51.96) v1(17.59,39.67) v1(17.57,38.57) v1(17.57,38.39) v1(17.59,36.58) v1(17.62,27.49) v1(17.61,26.84) v1(17.64,26) v1(17.61,24.38) v1(17.66,53.42) v1(17.66,38) v1(17.66,31.64) v1(17.69,28.71) v1(17.75,51.29) v1(17.75,38.57) v1(17.75,38.39) v1(17.82,33.24) v1(17.75,30.9) v1(17.78,23.07) v1(17.83,22.41) v1(17.79,16.38) v1(17.75,10.05) v1(17.92,67.56) v1(17.91,49.5) v1(17.91,13.27) v1(18,39.72) v1(18.01,38.02) v1(17.99,35.71) v1(18.03,31.42) v1(17.97,29.22) v1(18.04,24.7) v1(18.04,24.22) v1(18.01,15.35) v1(18.06,64.87) v1(18.07,21.29) v1(18.13,16.83) v1(18.18,66.86) v1(18.2,56.26) v1(18.23,55.23) v1(18.18,41.51) v1(18.17,40.44) v1(18.15,39.29) v1(18.15,38.81) v1(18.16,38.41) v1(18.23,37.25) v1(18.22,28.28) v1(18.2,27.04) v1(18.14,25.16) v1(18.18,19.8) v1(18.22,19.3) v1(18.16,11.79) v1(18.24,63.61) v1(18.26,62.36) v1(18.31,28.78) v1(18.26,25.52) v1(18.24,20.43) v1(18.24,18.43) v1(18.24,17.43) v1(18.33,15.88) v1(18.29,14.55) v1(18.27,10.47) v1(18.42,33.64) v1(18.42,33.24) v1(18.38,30.82) v1(18.36,22.78) v1(18.45,63.31) v1(18.49,56.01) v1(18.46,36.73) v1(18.49,22.24) v1(18.46,12.8) v1(18.49,12.07) v1(18.62,51.33) v1(18.54,28.3) v1(18.64,27.88) v1(18.55,27.45) v1(18.6,14.97) v1(18.67,69.12) v1(18.73,58.2) v1(18.72,57.74) v1(18.68,42.37) v1(18.69,40.01) v1(18.73,16.72) v1(18.72,15.44) v1(18.77,55.7) v1(18.76,49.49) v1(18.76,32.52) v1(18.75,29.39) v1(18.81,22.77) v1(18.83,19.84) v1(18.79,17.62) v1(18.78,16.24) v1(18.83,10.46) v1(18.88,37.55) v1(18.91,27.46) v1(18.85,20.98) v1(19.01,60.97) v1(19.01,60.79) v1(19.01,60.61) v1(18.97,57.96) v1(18.97,35.38) v1(19.01,27.08) v1(19.02,21.73) v1(19.02,12.85) v1(18.99,11.29) v1(19.09,64.31) v1(19.12,50.27) v1(19.06,29.78) v1(19.06,29.01) v1(19.12,25.17) v1(19.13,24.55) v1(19.13,11.81) v1(19.22,58.15) v1(19.19,52.25) v1(19.14,51.67) v1(19.24,40.04) v1(19.14,33.76) v1(19.16,32.86) v1(19.14,30.17) v1(19.2,26.05) v1(19.28,56.71) v1(19.26,49.4) v1(19.29,48.6) v1(19.34,39.23) v1(19.25,38.15) v1(19.3,27.46) v1(19.31,26.69) v1(19.43,50.27) v1(19.43,37.19) v1(19.35,32.07) v1(19.35,16.25) v1(19.49,58) v1(19.48,57.44) v1(19.47,56.47) v1(19.44,47.11) v1(19.46,30.53) v1(19.45,29.78) v1(19.45,29.01) v1(19.46,26.37) v1(19.44,22.25) v1(19.45,13.8) v1(19.6,68.72) v1(19.59,29.39) v1(19.55,23.93) v1(19.54,23.41) v1(19.54,21.26) v1(19.65,63.15) v1(19.7,57.66) v1(19.72,57.21) v1(19.72,56.72) v1(19.7,50.94) v1(19.69,27.79) v1(19.66,27.43) v1(19.69,26.69) v1(19.69,12.04) v1(19.67,10.74) v1(19.84,66.91) v1(19.77,35.43) v1(19.76,25.63) v1(19.8,22.8) v1(19.79,21.75) v1(19.89,32.98) v1(19.84,29.01) v1(19.92,27.08) v1(19.85,15.62) v1(19.86,14.9) v1(19.85,13.5) v1(19.86,13) v1(19.96,56.97) v1(20.08,35.86) v1(20.08,34.19) v1(20.06,32.07) v1(20.06,30.19) v1(20.04,23.37) v1(20.23,57.66) v1(20.19,57.18) v1(20.21,56.72) v1(20.21,11.6) v1(20.19,10.76) v1(20.25,48.59) v1(20.34,39.23) v1(20.28,14.91) v1(20.43,58.49) v1(20.38,52.89) v1(20.39,31.75) v1(20.39,31.08) v1(20.36,22.26) v1(20.46,58.95) v1(20.46,57.46) v1(20.46,56.97) v1(20.5,47.54) v1(20.44,26.6) v1(20.52,24.49) v1(20.52,23.91) v1(20.5,20.73) v1(20.61,63.12) v1(20.56,62.13) v1(20.55,60.71) v1(20.6,53.81) v1(20.56,33.39) v1(20.56,32.98) v1(20.6,28.94) v1(20.61,11.82) v1(20.63,10.49) v1(20.69,57.17) v1(20.71,56.72) v1(20.68,36.4) v1(20.7,16.24) v1(20.76,57.69) v1(20.84,52.91) v1(20.83,52.37) v1(20.84,40.04) v1(20.77,23.07) v1(20.79,22.79) v1(20.79,21.75) v1(20.84,20.7) v1(20.84,12.92) v1(20.93,56.95) v1(20.84,20.51) v1(20.99,57.49) v1(20.95,56.47) v1(20.94,23.9) v1(21.05,63.1) v1(21.1,60.53) v1(21.1,34.92) v1(21.13,24.52) v1(21.09,14.91) v1(21.15,68.69) v1(21.23,57.24) v1(21.16,49.29) v1(21.21,48.88) v1(21.21,41.51) v1(21.17,34.36) v1(21.15,26.35) v1(21.19,23.07) v1(21.26,66.53) v1(21.26,48.28) v1(21.34,39.23) v1(21.26,25.49) v1(21.33,22.26) v1(21.24,14.16) v1(21.38,28.01) v1(21.42,24.57) v1(21.5,50.11) v1(21.52,26.56) v1(21.44,23.86) v1(21.52,18.03) v1(21.61,63.12) v1(21.54,53.15) v1(21.63,43.35) v1(21.63,37.09) v1(21.58,23.25) v1(21.63,21.52) v1(21.57,10.98) v1(21.57,10.44) v1(21.67,44.17) v1(21.7,24.67) v1(21.67,23.75) v1(21.65,10.08) v1(21.8,61.73) v1(21.8,61.55) v1(21.77,53.02) v1(21.8,52.31) v1(21.81,47.84) v1(21.84,40.04) v1(21.9,48.34) v1(21.87,18.03) v1(21.98,61.73) v1(21.98,61.55) v1(21.95,48.93) v1(22.02,48.18) v1(22.02,15.62) v1(22.05,50.53) v1(22.1,48.34) v1(22.07,36.68) v1(22.04,22.76) v1(22.04,14.91) v1(22.19,63.32) v1(22.19,59.19) v1(22.19,58.7) v1(22.19,57.71) v1(22.23,55.27) v1(22.17,53.69) v1(22.16,47.5) v1(22.17,42.39) v1(22.14,40.6) v1(22.15,35.55) v1(22.23,34.09) v1(22.24,33.54) v1(22.23,31.12) v1(22.14,26.96) v1(22.19,23.06) v1(22.22,18.73) v1(22.22,18.38) v1(22.22,17.33) v1(22.15,9.63) v1(22.3,46.3) v1(22.34,39.23) v1(22.26,28.69) v1(22.34,28.24) v1(22.3,16.82) v1(22.25,13.38) v1(22.27,12.83) v1(22.39,67.65) v1(22.42,47.84) v1(22.42,47.23) v1(22.34,37.36) v1(22.38,27.34) v1(22.37,26.55) v1(22.39,26.23) v1(22.36,24.29) v1(22.44,59.44) v1(22.44,58.95) v1(22.45,57.41) v1(22.44,55.98) v1(22.48,55.02) v1(22.45,48.94) v1(22.45,30.84) v1(22.45,24.73) v1(22.48,22.25) v1(22.44,14.17) v1(22.52,11.67) v1(22.63,48.59) v1(22.59,15.33) v1(22.55,11.26) v1(22.69,57.71) v1(22.67,53.69) v1(22.7,37.36) v1(22.73,34.09) v1(22.73,33.1) v1(22.73,32.11) v1(22.73,31.61) v1(22.68,25.87) v1(22.66,21.09) v1(22.81,42.34) v1(22.84,40.04) v1(22.75,27.75) v1(22.76,27.34) v1(22.76,26.55) v1(22.85,68.69) v1(22.91,63.09) v1(22.93,55.98) v1(22.87,52.38) v1(22.88,50.98) v1(22.9,48.06) v1(22.92,18.38) v1(22.85,12.82) v1(22.99,47.73) v1(22.96,36.32) v1(22.98,31.36) v1(23.03,26.25) v1(22.97,14.17) v1(23.12,35.21) v1(23.05,26.91) v1(23.13,21.55) v1(23.04,14.91) v1(23.22,33.1) v1(23.22,31.61) v1(23.16,27.84) v1(23.16,26.55) v1(23.18,23.73) v1(23.17,23.04) v1(23.19,22.75) v1(23.34,39.23) v1(23.25,25.21) v1(23.28,18.27) v1(23.3,17.72) v1(23.32,9.61) v1(23.43,63.37) v1(23.39,36.85) v1(23.51,52.38) v1(23.47,32.85) v1(23.47,32.35) v1(23.47,31.36) v1(23.47,27.19) v1(23.49,26.56) v1(23.47,21.11) v1(23.47,20.69) v1(23.5,15.75) v1(23.45,14.17) v1(23.46,13.39) v1(23.56,50.97) v1(23.62,48.55) v1(23.62,47.95) v1(23.55,47.4) v1(23.63,24.4) v1(23.66,35.6) v1(23.72,32.6) v1(23.66,25.82) v1(23.71,23.71) v1(23.91,48.37) v1(23.86,27.24) v1(23.87,26.78) v1(23.93,23.43) v1(23.93,23.24) v1(23.87,20.07) v1(24.01,54.06) v1(24.01,50.97) v1(23.97,31.86) v1(23.97,31.36) v1(24.1,61.66) v1(24.12,47.73) v1(24.11,47.43) v1(24.12,22.26) v1(24.1,14.72) v1(24.15,63.21) v1(24.15,36.89) v1(24.21,36.56) v1(24.17,31.62) v1(24.18,21.44) v1(24.14,11.94) v1(24.31,64.24) v1(24.32,53.64) v1(24.34,39.23) v1(24.31,9.62) v1(24.4,41.1) v1(24.36,27.24) v1(24.41,25.3) v1(24.39,24.96) v1(24.42,24.29) v1(24.42,23.37) v1(24.35,22.74) v1(24.46,34.83) v1(24.46,33.34) v1(24.46,31.36) v1(24.44,23.04) v1(24.49,14.15) v1(24.63,68.7) v1(24.6,38.28) v1(24.57,30.45) v1(24.55,18.35) v1(24.72,52.82) v1(24.71,33.59) v1(24.71,33.1) v1(24.68,32.64) v1(24.73,27.5) v1(24.73,26.58) v1(24.65,25.83) v1(24.66,13.38) v1(24.75,53.27) v1(24.77,49.1) v1(24.78,38.55) v1(24.79,38.28) v1(24.93,30.5) v1(24.85,15.7) v1(24.95,63.35) v1(25.03,36.88) v1(24.96,33.84) v1(24.96,32.85) v1(24.95,32.31) v1(24.96,31.86) v1(25.01,31.36) v1(24.97,29.53) v1(25.03,26.13) v1(24.95,25.66) v1(24.97,23.03) v1(24.99,20.92) v1(25,14.15) v1(24.94,9.61) v1(25.05,45.55) v1(25.05,28.96) v1(25.13,19.21) v1(25.18,64.97) v1(25.16,47.5) v1(25.17,41.61) v1(25.23,40.28) v1(25.16,35.61) v1(25.2,33.1) v1(25.22,24.59) v1(25.21,23.62) v1(25.28,55.55) v1(25.33,28.52) v1(25.26,28.08) v1(25.29,22.23) v1(25.25,21.46) v1(25.34,14.72) v1(25.27,10.07) v1(25.38,26.87) v1(25.4,10.19) v1(25.45,52.13) v1(25.45,50.94) v1(25.48,35.59) v1(25.45,32.85) v1(25.45,31.86) v1(25.45,31.36) v1(25.46,30.45) v1(25.48,29.53) v1(25.56,42.17) v1(25.6,26.53) v1(25.57,26.08) v1(25.55,25.7) v1(25.54,25.19) v1(25.55,21.85) v1(25.7,33.1) v1(25.72,29.05) v1(25.71,27.36) v1(25.72,12.78) v1(25.82,28.51) v1(25.83,15.76) v1(25.85,66.32) v1(25.85,64.93) v1(25.9,63.2) v1(25.88,58.56) v1(25.87,39.74) v1(25.86,35.55) v1(25.92,31.89) v1(25.86,19.38) v1(25.97,57.55) v1(26.03,55.77) v1(25.95,34.83) v1(25.95,34.33) v1(25.95,33.34) v1(25.99,31.34) v1(26.03,24.16) v1(25.96,20.53) v1(26.05,59.81) v1(26.09,22.8) v1(26.09,14.19) v1(26.16,47.5) v1(26.23,46.47) v1(26.19,34.09) v1(26.19,33.59) v1(26.19,32.6) v1(26.19,32.11) v1(26.24,22.38) v1(26.15,9.64) v1(26.34,39.23) v1(26.32,15.05) v1(26.36,49.43) v1(26.36,47.2) v1(26.4,44.17) v1(26.36,36.98) v1(26.4,31.37) v1(26.41,14.48) v1(26.43,13.12) v1(26.47,68.7) v1(26.44,33.84) v1(26.44,33.34) v1(26.44,32.85) v1(26.49,31.87) v1(26.52,26.92) v1(26.47,18.57) v1(26.57,42.27) v1(26.54,22.18) v1(26.65,63.35) v1(26.73,52.68) v1(26.69,34.09) v1(26.69,33.1) v1(26.69,21.91) v1(26.67,19.92) v1(26.71,19.2) v1(26.65,13.94) v1(26.76,27.52) v1(26.75,24.36) v1(26.77,23.9) v1(26.79,17.18) v1(26.82,12.32) v1(26.9,63.3) v1(26.86,54.68) v1(26.93,53.94) v1(26.86,39.72) v1(26.94,33.84) v1(26.94,32.35) v1(26.94,31.36) v1(26.87,18.43) v1(26.88,15.96) v1(27,21.12) v1(27.03,11.34) v1(27.04,26.91) v1(27.13,22.49) v1(27.06,21.96) v1(27.1,19.39) v1(27.22,52.21) v1(27.2,40.53) v1(27.18,34.09) v1(27.18,33.59) v1(27.18,33.1) v1(27.18,32.6) v1(27.18,32.11) v1(27.18,31.61) v1(27.21,28.05) v1(27.17,20.05) v1(27.15,15.42) v1(27.18,14.91) v1(27.19,14.3) v1(27.19,13.64) v1(27.17,12.98) v1(27.33,67.24) v1(27.3,57.34) v1(27.3,56.68) v1(27.31,24.4) v1(27.35,66.33) v1(27.36,41.99) v1(27.34,39.23) v1(27.4,35.98) v1(27.43,34.83) v1(27.43,33.34) v1(27.43,30.87) v1(27.35,27.23) v1(27.37,17.97) v1(27.36,9.64) v1(27.52,47.69) v1(27.5,46.55) v1(27.56,63.7) v1(27.56,62.83) v1(27.63,58.61) v1(27.54,58.23) v1(27.59,51.69) v1(27.62,49.88) v1(27.63,38.21) v1(27.6,37.59) v1(27.56,24.15) v1(27.57,22.24) v1(27.54,21.88) v1(27.63,20.35) v1(27.61,17.88) v1(27.67,59.45) v1(27.73,43.78) v1(27.68,37.4) v1(27.68,34.64) v1(27.68,33.1) v1(27.69,31.12) v1(27.73,23.93) v1(27.73,16.76) v1(27.7,13.25) v1(27.65,12.45) v1(27.8,64.53) v1(27.76,27.36) v1(27.76,24.39) v1(27.79,23.38) v1(27.76,22.24) v1(27.78,16.05) v1(27.83,12.86) v1(27.85,67.91) v1(27.89,57.82) v1(27.9,37.6) v1(27.89,37.37) v1(27.93,26.4) v1(27.92,11.22) v1(27.96,63.68) v1(27.97,63.36) v1(28.02,33.18) v1(27.98,24.62) v1(28.06,51.08) v1(28.13,50.73) v1(28.09,40.84) v1(28.04,26.99) v1(28.04,21.88) v1(28.08,18.85) v1(28.07,15.27) v1(28.09,14.48) v1(28.06,13.29) v1(28.16,62.6) v1(28.22,58.23) v1(28.15,56.89) v1(28.19,46.29) v1(28.21,35.06) v1(28.15,33.71) v1(28.22,28.97) v1(28.24,23.43) v1(28.21,22.52) v1(28.19,20.97) v1(28.24,17.04) v1(28.32,68.7) v1(28.27,56.4) v1(28.32,36.68) v1(28.28,23.92) v1(28.29,21.88) v1(28.25,16.41) v1(28.41,51.74) v1(28.34,39.23) v1(28.41,26.4) v1(28.39,14.24) v1(28.39,14.02) v1(28.39,12.93) v1(28.39,12.72) v1(28.36,12.03) v1(28.37,9.35) v1(28.45,33) v1(28.49,19.22) v1(28.5,15.54) v1(28.6,54.86) v1(28.58,50.74) v1(28.54,22.13) v1(28.63,21.87) v1(28.72,35.06) v1(28.7,34.12) v1(28.69,23.38) v1(28.75,67.96) v1(28.81,66.6) v1(28.82,65.7) v1(28.78,54.67) v1(28.79,22.38) v1(28.82,21.62) v1(28.76,14.91) v1(28.83,14.23) v1(28.83,14.02) v1(28.82,12.93) v1(28.83,12.72) v1(28.78,10.8) v1(28.91,51.27) v1(28.86,39.43) v1(28.93,36.02) v1(28.91,33.16) v1(28.85,32.26) v1(28.84,23.78) v1(28.94,17.82) v1(28.85,10.3) v1(29.02,67.52) v1(28.99,64.73) v1(29.01,16.88) v1(29.01,16.43) v1(28.96,11.76) v1(29.02,8.28) v1(29.01,7.11) v1(28.95,4.78) v1(28.97,3.76) v1(28.97,2.65) v1(28.97,1.41) v1(29.11,65.82) v1(29.05,56.27) v1(29.13,55.02) v1(29.07,54.32) v1(29.08,53.96) v1(29.09,53.01) v1(29.11,47.43) v1(29.12,41.74) v1(29.12,34.08) v1(29.05,29.47) v1(29.07,26.99) v1(29.04,22.63) v1(29.12,13.46) v1(29.14,35.07) v1(29.23,26.52) v1(29.16,24.03) v1(29.17,14.21) v1(29.23,11.87) v1(29.26,60.02) v1(29.26,59.82) v1(29.26,59.62) v1(29.26,58.72) v1(29.26,58.52) v1(29.26,58.32) v1(29.26,57.42) v1(29.25,55.92) v1(29.28,54.17) v1(29.26,53.77) v1(29.26,52.77) v1(29.28,40.3) v1(29.32,20.99) v1(29.28,19.45) v1(29.32,12.6) v1(29.42,63.82) v1(29.35,62.65) v1(29.38,29.22) v1(29.39,21.78) v1(29.35,14.27) v1(29.38,13.08) v1(29.42,10.8) v1(29.49,65.66) v1(29.45,56.27) v1(29.47,55.53) v1(29.49,54.86) v1(29.49,54.32) v1(29.49,53.96) v1(29.47,53.01) v1(29.48,51.23) v1(29.51,36.6) v1(29.47,15.39) v1(29.56,63.41) v1(29.56,37.51) v1(29.62,33.86) v1(29.59,27.88) v1(29.62,24.21) v1(29.63,23.34) v1(29.63,22.23) v1(29.55,16.88) v1(29.55,16.45) v1(29.54,16.11) v1(29.58,15.74) v1(29.57,11.43) v1(29.56,10.07) v1(29.66,67.91) v1(29.69,47.44) v1(29.7,41.54) v1(29.69,38.28) v1(29.69,35.98) v1(29.69,34.98) v1(29.67,32.64) v1(29.74,22.59) v1(29.74,16.17) v1(29.67,13.58) v1(29.67,13.37) v1(29.74,3.78) v1(29.76,39.81) v1(29.77,38.54) v1(29.75,30.68) v1(29.8,25.55) v1(29.8,14.53) v1(29.75,0.32) v1(29.93,61.11) v1(29.87,34.23) v1(29.91,28.43) v1(29.89,27.79) v1(29.94,16.39) v1(29.92,15.08) v1(29.94,12.23) v1(30.02,51.75) v1(29.97,46.8) v1(30.03,15.88) v1(30.11,37.42) v1(30.13,32.65) v1(30.09,26.17) v1(30.08,25.34) v1(30.09,24.59) v1(30.1,22.06) v1(30.06,20.21) v1(30.04,17.26) v1(30.1,13.58) v1(30.11,13.37) v1(30.17,68.7) v1(30.16,65.67) v1(30.21,63.02) v1(30.17,62.41) v1(30.2,54.61) v1(30.22,50.76) v1(30.22,48.86) v1(30.2,36.03) v1(30.24,35.48) v1(30.24,34.63) v1(30.19,33.04) v1(30.18,31.94) v1(30.19,26.38) v1(30.21,25.86) v1(30.29,15.68) v1(30.26,11.64) v1(30.36,59.73) v1(30.38,28.19) v1(30.36,27.65) v1(30.41,22.6) v1(30.44,15.29) v1(30.39,14.3) v1(30.39,13.83) v1(30.39,12.93) v1(30.38,12.46) v1(30.54,58.64) v1(30.48,55.83) v1(30.49,53.97) v1(30.48,47.34) v1(30.49,46.23) v1(30.49,45.23) v1(30.49,44.23) v1(30.48,43.63) v1(30.49,43.23) v1(30.49,42.23) v1(30.47,39) v1(30.51,26.96) v1(30.57,67.91) v1(30.54,57.69) v1(30.59,51.57) v1(30.62,40.76) v1(30.55,36.52) v1(30.59,33.98) v1(30.58,30.53) v1(30.55,24.16) v1(30.62,23.5) v1(30.57,21.54) v1(30.64,18.56) v1(30.62,17.13) v1(30.56,11.12) v1(30.6,0.86) v1(30.73,65.67) v1(30.73,47.81) v1(30.69,33.48) v1(30.69,28.8) v1(30.72,26.84) v1(30.65,20.87) v1(30.71,20.29) v1(30.65,19.79) v1(30.65,17.65) v1(30.72,13.72) v1(30.7,12.36) v1(30.8,32.68) v1(30.76,31.92) v1(30.82,23.5) v1(30.82,14.52) v1(30.94,63.42) v1(30.9,58.31) v1(30.91,54) v1(30.92,36.27) v1(30.84,26.07) v1(30.94,20.79) v1(30.86,15.09) v1(30.92,11.94) v1(30.97,60.91) v1(31.02,50.3) v1(31,34.98) v1(31.11,46.67) v1(31.12,41.74) v1(31.12,38.36) v1(31.09,37.2) v1(31.12,34.41) v1(31.09,24.78) v1(31.08,24.16) v1(31.12,20.5) v1(31.13,19.47) v1(31.13,18.96) v1(31.13,15.88) v1(31.1,5.01) v1(31.08,4.32) v1(31.1,3.63) v1(31.1,2.96) v1(31.11,2.22) v1(31.23,51.54) v1(31.17,39.25) v1(31.14,29.68) v1(31.23,28.09) v1(31.19,26.53) v1(31.21,21.61) v1(31.21,20.92) v1(31.14,20.15) v1(31.14,18.32) v1(31.14,17.64) v1(31.15,16.97) v1(31.23,12.46) v1(31.2,6.9) v1(31.2,6.68) v1(31.24,62.12) v1(31.24,61.72) v1(31.29,60.56) v1(31.24,59.89) v1(31.32,57.95) v1(31.27,56.96) v1(31.27,55.97) v1(31.27,54.98) v1(31.27,51.02) v1(31.27,50.52) v1(31.27,49.53) v1(31.24,48.06) v1(31.24,33.38) v1(31.29,31.54) v1(31.29,23.51) v1(31.24,22.19) v1(31.27,19.89) v1(31.28,13.72) v1(31.31,12.93) v1(31.35,65.69) v1(31.37,63.88) v1(31.37,43.89) v1(31.38,43.44) v1(31.43,32.98) v1(31.35,32.75) v1(31.38,27.59) v1(31.34,19.63) v1(31.4,19.21) v1(31.41,15.52) v1(31.44,6.64) v1(31.51,68.69) v1(31.49,60.92) v1(31.53,40.34) v1(31.5,27.11) v1(31.49,26.19) v1(31.49,25.19) v1(31.49,24.19) v1(31.49,18.58) v1(31.48,17.94) v1(31.49,14.98) v1(31.49,14.23) v1(31.48,8.69) v1(31.52,7.49) v1(31.5,1.16) v1(31.56,31.14) v1(31.57,17.35) v1(31.59,16.23) v1(31.63,13.55) v1(31.63,13.29) v1(31.64,6.95) v1(31.7,41.54) v1(31.66,23.76) v1(31.67,23.32) v1(31.73,22.5) v1(31.76,49.53) v1(31.81,29.09) v1(31.74,19) v1(31.75,18.2) v1(31.78,13.12) v1(31.79,5.04) v1(31.79,3.62) v1(31.79,2.21) v1(31.79,1.45) v1(31.92,60.57) v1(31.88,38.81) v1(31.86,37.61) v1(31.89,36.4) v1(31.88,35.22) v1(31.88,33.66) v1(31.89,32.63) v1(31.92,20.91) v1(31.93,15.56) v1(31.87,13.85) v1(31.96,63.41) v1(31.99,26.19) v1(32.03,25.05) v1(32.02,17.47) v1(32,16.57) v1(31.97,14.56) v1(31.96,14.13) v1(32,13.12) v1(32.1,65.72) v1(32.1,28.09) v1(32.09,22.77) v1(32.05,12.5) v1(32.12,8.16) v1(32.07,7.49) v1(32.07,6.99) v1(32.09,1.14) v1(32.17,66.43) v1(32.2,59.94) v1(32.18,39.05) v1(32.19,31.98) v1(32.19,30.98) v1(32.19,29.98) v1(32.22,15.24) v1(32.17,13.85) v1(32.33,60.79) v1(32.26,52.01) v1(32.26,49.53) v1(32.32,38.93) v1(32.25,28.67) v1(32.28,14.75) v1(32.27,14.44) v1(32.38,25.45) v1(32.42,17.17) v1(32.37,14.11) v1(32.4,13.12) v1(32.43,5.58) v1(32.41,5.04) v1(32.5,48.49) v1(32.47,43.24) v1(32.46,38.8) v1(32.51,33.38) v1(32.45,27.6) v1(32.52,27.09) v1(32.47,22.12) v1(32.45,21.46) v1(32.49,18.29) v1(32.48,17.75) v1(32.45,16.79) v1(32.5,15.76) v1(32.48,13.73) v1(32.48,13.45) v1(32.48,8.69) v1(32.45,3.63) v1(32.48,2.06) v1(32.6,67.82) v1(32.64,63.59) v1(32.56,47.97) v1(32.64,31.53) v1(32.64,30.68) v1(32.64,29.93) v1(32.64,28.69) v1(32.57,26.17) v1(32.57,19.19) v1(32.73,55.52) v1(32.7,14.11) v1(32.66,12.93) v1(32.8,68.7) v1(32.76,63.18) v1(32.75,57.95) v1(32.83,56.99) v1(32.83,41.62) v1(32.83,41.44) v1(32.79,39.64) v1(32.8,32.4) v1(32.74,28.3) v1(32.74,25.1) v1(32.77,24.51) v1(32.76,22.27) v1(32.77,21.09) v1(32.75,20.14) v1(32.8,19.26) v1(32.76,16.69) v1(32.76,16.43) v1(32.79,1.15) v1(32.93,46.45) v1(32.91,45.97) v1(32.86,34.13) v1(32.87,24.74) v1(32.92,18.38) v1(32.92,17.5) v1(32.91,13.66) v1(32.91,13.39) v1(32.89,12.5) v1(32.97,63.94) v1(33,63.47) v1(33,63.03) v1(33,58.2) v1(33.03,55.75) v1(32.97,55.2) v1(32.98,53.76) v1(33,53.28) v1(33,52.7) v1(33,45.03) v1(32.97,39.64) v1(33.01,32.98) v1(33.04,26.26) v1(33.01,16.07) v1(33.04,14.88) v1(33.03,14.11) v1(33.01,2.06) v1(33.05,56.2) v1(33.05,25.94) v1(33.08,24.74) v1(33.07,24.54) v1(33.08,22.4) v1(33.08,20.95) v1(33.05,20.14) v1(33.07,19.26) v1(33.07,16.43) v1(33.09,13.11) v1(33.12,3.62) v1(33.09,1.45) v1(33.2,59.94) v1(33.16,28.07) v1(33.16,27.59) v1(33.19,15.23) v1(33.14,14.63) v1(33.15,14.35) v1(33.16,13.85) v1(33.25,58.44) v1(33.25,51.02) v1(33.26,29.65) v1(33.24,29.1) v1(33.38,38.84) v1(33.38,38.65) v1(33.43,27.1) v1(33.43,17.9) v1(33.42,17.62) v1(33.42,14.13) v1(33.39,1.14) v1(33.49,57.7) v1(33.49,52.7) v1(33.48,51.83) v1(33.51,47.46) v1(33.51,32.4) v1(33.52,23.98) v1(33.53,23.17) v1(33.52,22.74) v1(33.44,21.41) v1(33.44,20.2) v1(33.49,18.54) v1(33.44,17.18) v1(33.45,14.49) v1(33.48,13.85) v1(33.51,13.11) v1(33.48,8.69) v1(33.57,43.22) v1(33.56,40.91) v1(33.56,31.54) v1(33.61,20.74) v1(33.54,19.57) v1(33.63,14.78) v1(33.61,12.5) v1(33.72,41.01) v1(33.73,17.32) v1(33.74,5.78) v1(33.74,5.03) v1(33.73,3.62) v1(33.73,2.21) v1(33.83,45.8) v1(33.77,40.03) v1(33.79,33.31) v1(33.84,19.23) v1(33.84,14.64) v1(33.76,13.7) v1(33.76,13.4) v1(33.87,36.83) v1(33.89,34.42) v1(33.94,26.59) v1(33.94,25.27) v1(33.89,22.44) v1(33.87,20.37) v1(33.85,19.77) v1(33.92,18.02) v1(33.94,17.61) v1(33.89,12.97) v1(33.88,12.37) v1(33.89,11.84) v1(33.9,11.34) v1(33.92,10.76) v1(34.03,62.1) v1(33.99,61.73) v1(33.98,31.93) v1(33.96,28.3) v1(33.96,24.57) v1(34,23.55) v1(33.95,21.4) v1(34.01,20.82) v1(34.02,17.18) v1(33.98,13.38) v1(34.1,68.69) v1(34.08,65.64) v1(34.1,64.37) v1(34.08,63.94) v1(34.11,63.35) v1(34.1,63.01) v1(34.1,19.57) v1(34.09,1.14) v1(34.22,66.52) v1(34.2,61.87) v1(34.23,60.66) v1(34.19,59.93) v1(34.22,27.6) v1(34.23,24.06) v1(34.19,23.11) v1(34.17,22.8) v1(34.16,20.41) v1(34.14,19.23) v1(34.19,18.36) v1(34.22,15.36) v1(34.19,14.62) v1(34.22,13.98) v1(34.28,50.98) v1(34.24,49.53) v1(34.33,45.85) v1(34.34,25.43) v1(34.28,14.34) v1(34.29,12.5) v1(34.42,63.5) v1(34.35,61.72) v1(34.4,33.31) v1(34.42,32.66) v1(34.4,28.99) v1(34.4,16.37) v1(34.43,11.94) v1(34.4,5.04) v1(34.38,3.63) v1(34.39,2.21) v1(34.39,1.45) v1(34.44,60.35) v1(34.53,56.25) v1(34.46,55.69) v1(34.52,53.7) v1(34.49,53.29) v1(34.46,36.33) v1(34.45,33.87) v1(34.46,28.07) v1(34.5,27.11) v1(34.52,23.98) v1(34.54,23.55) v1(34.54,22.34) v1(34.52,20.74) v1(34.52,17.93) v1(34.51,17.15) v1(34.44,10.73) v1(34.48,8.69) v1(34.45,7.85) v1(34.45,6.56) v1(34.58,62.11) v1(34.64,61.72) v1(34.57,21.6) v1(34.55,19.98) v1(34.59,19.23) v1(34.61,15.36) v1(34.55,14.12) v1(34.56,13.84) v1(34.55,13.38) v1(34.74,63.74) v1(34.73,58.44) v1(34.7,39.06) v1(34.68,25.79) v1(34.65,20.9) v1(34.69,20.38) v1(34.69,17.15) v1(34.67,14.36) v1(34.69,1.14) v1(34.77,67.82) v1(34.77,65.64) v1(34.83,16.1) v1(34.79,15.11) v1(34.79,14.81) v1(34.92,30.56) v1(34.91,26.22) v1(34.85,23.66) v1(34.89,22.43) v1(34.89,21.96) v1(34.84,19.68) v1(34.86,18.8) v1(34.86,17.61) v1(34.93,12.92) v1(34.98,54.23) v1(35.02,52.25) v1(35,38.83) v1(35,38.33) v1(35,28.08) v1(34.94,22.79) v1(35.02,17.93) v1(35,14.38) v1(34.96,10.74) v1(34.97,10.3) v1(34.97,9.72) v1(34.96,9.19) v1(34.98,5.54) v1(35.05,11.94) v1(35.04,5.03) v1(35.04,3.63) v1(35.04,2.21) v1(35.17,49.51) v1(35.2,27.58) v1(35.22,25.91) v1(35.24,25.41) v1(35.2,23.66) v1(35.18,23.13) v1(35.2,21.61) v1(35.19,20.95) v1(35.17,20.41) v1(35.19,19.97) v1(35.19,19.22) v1(35.18,18.38) v1(35.2,17.29) v1(35.19,15.38) v1(35.22,15.02) v1(35.22,14.74) v1(35.26,66.51) v1(35.28,59.96) v1(35.31,45.78) v1(35.25,33.33) v1(35.34,32.38) v1(35.26,30.39) v1(35.34,30.06) v1(35.27,29.66) v1(35.33,14.36) v1(35.4,34.08) v1(35.4,33.71) v1(35.37,31.27) v1(35.43,14.03) v1(35.41,13.32) v1(35.39,1.16) v1(35.5,68.69) v1(35.51,59.15) v1(35.52,51.3) v1(35.5,39.82) v1(35.5,39.32) v1(35.5,32.3) v1(35.52,23.98) v1(35.54,23.13) v1(35.54,22.26) v1(35.54,21.6) v1(35.53,19.56) v1(35.52,17.93) v1(35.54,17.18) v1(35.52,14.57) v1(35.48,8.69) v1(35.58,60.31) v1(35.59,28.08) v1(35.56,26.59) v1(35.57,22.79) v1(35.59,19.98) v1(35.61,18.38) v1(35.55,16.11) v1(35.67,62.51) v1(35.67,62.01) v1(35.66,61.08) v1(35.71,43.07) v1(35.72,21.18) v1(35.66,16.56) v1(35.69,14.34) v1(35.66,13.63) v1(35.67,5.04) v1(35.69,1.45) v1(35.75,43.47) v1(35.74,39.57) v1(35.74,38.58) v1(35.75,32.81) v1(35.74,27.03) v1(35.8,21.94) v1(35.77,20.42) v1(35.77,13.92) v1(35.74,3.65) v1(35.81,1.97) v1(35.93,64.38) v1(35.93,63.71) v1(35.87,23.32) v1(35.87,17.61) v1(35.9,15.73) v1(35.87,14.62) v1(35.88,11.61) v1(35.98,55.78) v1(36.03,54.17) v1(35.99,39.32) v1(36.01,34.73) v1(35.94,31.75) v1(35.94,18.84) v1(36.02,17.93) v1(36.04,17.18) v1(36,15.39) v1(36.03,13.34) v1(36,1.15) v1(36.07,61.83) v1(36.13,60.6) v1(36.06,45.78) v1(36.05,33.33) v1(36.05,22.6) v1(36.08,15) v1(36.1,14.49) v1(36.1,14.06) v1(36.12,11.98) v1(36.05,11.07) v1(36.05,10.36) v1(36.06,9.77) v1(36.05,9.11) v1(36.22,59.93) v1(36.17,51.51) v1(36.22,41.03) v1(36.19,28.08) v1(36.23,27.58) v1(36.19,23.66) v1(36.22,23.12) v1(36.16,21.57) v1(36.14,20.83) v1(36.23,20.32) v1(36.18,19.57) v1(36.19,19.17) v1(36.31,66.52) v1(36.27,49.53) v1(36.24,39.57) v1(36.24,39.07) v1(36.24,38.58) v1(36.28,13.48) v1(36.34,10.79) v1(36.28,9.33) v1(36.26,8.43) v1(36.33,5.02) v1(36.34,3.62) v1(36.3,1.97) v1(36.37,48.82) v1(36.4,48.33) v1(36.39,48.15) v1(36.39,47.79) v1(36.4,33.71) v1(36.37,13.82) v1(36.4,10.32) v1(36.35,5.79) v1(36.46,63.37) v1(36.46,63.03) v1(36.53,58.13) v1(36.49,39.82) v1(36.54,32.93) v1(36.5,32.3) v1(36.5,27.11) v1(36.52,23.98) v1(36.49,23.55) v1(36.49,20.91) v1(36.49,20.31) v1(36.49,19.79) v1(36.52,17.93) v1(36.54,17.18) v1(36.49,16.74) v1(36.48,8.69) v1(36.61,63.71) v1(36.64,31.75) v1(36.63,25.91) v1(36.63,25.46) v1(36.57,22.73) v1(36.59,22.18) v1(36.58,19.2) v1(36.58,18.38) v1(36.58,16.43) v1(36.59,13.14) v1(36.55,7.46) v1(36.73,39.58) v1(36.72,6.99) v1(36.69,1.14) v1(36.75,60.29) v1(36.74,40.6) v1(36.74,40.09) v1(36.76,30.11) v1(36.75,28.89) v1(36.78,28.08) v1(36.83,24.03) v1(36.9,68.69) v1(36.87,67.82) v1(36.88,23.55) v1(36.89,23.13) v1(36.88,21.18) v1(36.84,20.05) v1(36.88,17.61) v1(36.87,15.73) v1(36.99,64.04) v1(37,51.79) v1(36.98,41.3) v1(36.98,40.81) v1(36.98,40.31) v1(36.98,39.82) v1(36.98,38.38) v1(36.98,22.26) v1(36.99,21.61) v1(36.99,20.75) v1(36.95,18.84) v1(37.02,17.93) v1(37.04,17.18) v1(37.02,13.76) v1(36.97,12.31) v1(36.97,11.31) v1(36.95,6.53) v1(36.98,5.04) v1(37,3.62) v1(37.03,2.21) v1(36.99,1.45) v1(37.1,33.33) v1(37.1,25.84) v1(37.09,22.73) v1(37.2,49.58) v1(37.21,45.92) v1(37.23,40.6) v1(37.23,40.09) v1(37.21,39.03) v1(37.22,23.66) v1(37.16,21.95) v1(37.23,21.15) v1(37.17,20.37) v1(37.21,19.85) v1(37.22,19.17) v1(37.17,18.4) v1(37.28,27.59) v1(37.27,12.76) v1(37.27,10.29) v1(37.27,7.49) v1(37.27,6.99) v1(37.3,1.15) v1(37.37,66.53) v1(37.42,52.29) v1(37.39,33.71) v1(37.38,28.06) v1(37.38,26.17) v1(37.37,16.36) v1(37.47,56.71) v1(37.45,50.27) v1(37.52,46.31) v1(37.48,43.23) v1(37.53,42.77) v1(37.48,41.3) v1(37.48,40.31) v1(37.48,39.82) v1(37.45,31.12) v1(37.45,29.1) v1(37.5,27.11) v1(37.49,25.21) v1(37.52,23.98) v1(37.52,17.93) v1(37.54,17.18) v1(37.46,16.73) v1(37.47,14.38) v1(37.48,8.69) v1(37.56,63.42) v1(37.61,25.58) v1(37.57,23.12) v1(37.57,22.79) v1(37.58,21.57) v1(37.56,21.06) v1(37.55,20.2) v1(37.67,51.99) v1(37.68,46.39) v1(37.72,39.07) v1(37.67,32.12) v1(37.67,22.04) v1(37.66,19.64) v1(37.66,19.14) v1(37.71,18.4) v1(37.65,10.82) v1(37.67,5.03) v1(37.68,4.35) v1(37.68,3.62) v1(37.68,2.95) v1(37.68,2.22) v1(37.78,63.08) v1(37.74,62.03) v1(37.82,48.38) v1(37.77,35.61) v1(37.78,28.28) v1(37.8,28.06) v1(37.74,14.06) v1(37.74,13.49) v1(37.77,5.95) v1(37.91,48.21) v1(37.87,48.03) v1(37.87,47.85) v1(37.85,31.12) v1(37.85,30.46) v1(37.85,29.1) v1(37.85,28.65) v1(37.87,27.6) v1(37.86,24.42) v1(37.89,23.55) v1(37.89,22.37) v1(37.89,21.18) v1(37.88,19.97) v1(37.89,17.61) v1(37.87,15.75) v1(37.93,11.92) v1(37.93,9.75) v1(37.93,9.26) v1(37.93,8.34) v1(37.99,51.73) v1(38.02,48.38) v1(37.97,38.33) v1(37.95,32.66) v1(37.96,18.84) v1(38.02,17.93) v1(38.04,17.18) v1(37.99,15.21) v1(37.94,10.29) v1(37.99,6.33) v1(38.08,64.13) v1(38.07,60.65) v1(38.05,48.03) v1(38.06,47.85) v1(38.09,14.38) v1(38.11,13.17) v1(38.15,63.32) v1(38.2,59.93) v1(38.23,51.06) v1(38.23,48.38) v1(38.23,48.12) v1(38.23,47.78) v1(38.23,47.58) v1(38.23,43.04) v1(38.22,42.54) v1(38.22,39.57) v1(38.22,39.07) v1(38.2,31.23) v1(38.22,23.65) v1(38.22,23.12) v1(38.21,22.8) v1(38.21,21.96) v1(38.21,21.61) v1(38.22,20.76) v1(38.21,20.16) v1(38.21,19.55) v1(38.22,19.11) v1(38.22,14.06) v1(38.22,13.49) v1(38.22,11.07) v1(38.22,10.45) v1(38.23,9.74) v1(38.23,8.95) v1(38.23,8.2) v1(38.17,0.91) v1(38.24,58.97) v1(38.25,30.39) v1(38.25,28.05) v1(38.33,25.98) v1(38.27,21.14) v1(38.24,18.38) v1(38.25,15.92) v1(38.24,15.51) v1(38.27,14.9) v1(38.27,11.48) v1(38.41,66.53) v1(38.34,63.64) v1(38.44,27.67) v1(38.35,16.42) v1(38.53,65.92) v1(38.47,41.3) v1(38.45,32.12) v1(38.5,27.11) v1(38.45,18.8) v1(38.54,68.7) v1(38.58,62.93) v1(38.62,46.09) v1(38.55,33.71) v1(38.59,33.32) v1(38.63,29.11) v1(38.59,17.5) v1(38.69,58.94) v1(38.71,41.55) v1(38.69,26.17) v1(38.68,25.23) v1(38.67,24.74) v1(38.66,22.76) v1(38.65,19.7) v1(38.67,17) v1(38.67,16.68) v1(38.67,16.42) v1(38.83,23.63) v1(38.82,21.46) v1(38.82,20.58) v1(38.82,18.83) v1(38.77,15.93) v1(38.94,67.82) v1(38.94,53.79) v1(38.91,29.51) v1(38.97,61) v1(39.01,59.18) v1(38.94,51.76) v1(38.95,32.66) v1(38.97,24.49) v1(38.97,22.76) v1(38.96,19.69) v1(38.97,17.5) v1(38.96,16.68) v1(38.98,13.37) v1(39.12,64.38) v1(39.04,31.29) v1(39.12,30.29) v1(39.06,14.63) v1(39.04,13.93) v1(39.16,66.36) v1(39.19,65.89) v1(39.23,63.58) v1(39.17,62.37) v1(39.14,61.45) v1(39.19,49.53) v1(39.21,16.32) v1(39.18,11.94) v1(39.28,27.59) v1(39.29,22.34) v1(39.26,19.84) v1(39.3,19.17) v1(39.28,18.5) v1(39.31,10.74) v1(39.31,10.15) v1(39.31,9.47) v1(39.31,8.84) v1(39.31,8.13) v1(39.43,58.2) v1(39.43,52.75) v1(39.41,33.7) v1(39.44,33.33) v1(39.35,31.42) v1(39.37,16.85) v1(39.48,51.73) v1(39.45,32.12) v1(39.45,29.7) v1(39.5,27.11) v1(39.49,21.05) v1(39.59,60.98) v1(39.59,48.82) v1(39.58,24.8) v1(39.58,24.24) v1(39.57,18.7) v1(39.6,17.49) v1(39.55,0.62) v1(39.67,66.36) v1(39.73,58.42) v1(39.68,55.47) v1(39.72,51.52) v1(39.66,48.37) v1(39.66,47.62) v1(39.72,35.6) v1(39.69,25.75) v1(39.65,22.8) v1(39.69,20.02) v1(39.64,17.15) v1(39.66,8.85) v1(39.73,5.93) v1(39.76,63.3) v1(39.76,47.86) v1(39.78,28.78) v1(39.84,67.11) v1(39.84,66.91) v1(39.91,65.75) v1(39.9,65.23) v1(39.93,59.19) v1(39.93,54.73) v1(39.91,48.37) v1(39.91,48.12) v1(39.92,22.46) v1(39.87,16.2) v1(39.89,15.98) v1(39.87,13.38) v1(39.86,10.74) v1(39.86,10.08) v1(39.96,68.7) v1(39.98,66.14) v1(39.94,45.95) v1(39.95,32.66) v1(40.01,25.98) v1(39.99,19.38) v1(40.03,17.81) v1(39.99,14.18) v1(39.97,13.72) v1(39.99,11.94) v1(40.04,64.36) v1(40.06,22) v1(40.1,21.14) v1(40.1,14.7) v1(40.09,11.58) v1(40.13,7.95) v1(40.13,6.63) v1(40.13,5.19) v1(40.18,59.43) v1(40.15,50.49) v1(40.2,49.57) v1(40.14,17.03) v1(40.16,16.21) v1(40.18,8.9) v1(40.29,67.33) v1(40.29,67.08) v1(40.29,66.83) v1(40.29,66.58) v1(40.26,15.99) v1(40.31,3.77) v1(40.32,1.98) v1(40.32,1.33) v1(40.34,65.38) v1(40.44,65.18) v1(40.34,64.93) v1(40.41,60.47) v1(40.4,33.71) v1(40.35,33.33) v1(40.37,27.51) v1(40.38,26.92) v1(40.37,24.54) v1(40.34,20.03) v1(40.38,16.51) v1(40.34,13.6) v1(40.37,13.13) v1(40.37,12.51) v1(40.37,11.85) v1(40.35,10.76) v1(40.35,10.11) v1(40.35,9.25) v1(40.49,67.33) v1(40.49,67.08) v1(40.49,66.83) v1(40.49,66.58) v1(40.46,60.81) v1(40.53,38.51) v1(40.47,32.11) v1(40.45,30.69) v1(40.53,26.17) v1(40.52,24.21) v1(40.52,22.79) v1(40.52,21.93) v1(40.48,16.23) v1(40.48,14.51) v1(40.59,65.58) v1(40.54,65.38) v1(40.54,64.97) v1(40.61,20.71) v1(40.64,16.67) v1(40.54,12.18) v1(40.71,67.82) v1(40.69,67.33) v1(40.69,67.08) v1(40.74,65.78) v1(40.74,65.38) v1(40.69,56.51) v1(40.66,38.38) v1(40.66,15.99) v1(40.75,64.97) v1(40.81,63.3) v1(40.76,46.29) v1(40.78,20.01) v1(40.83,16.45) v1(40.89,67.33) v1(40.89,67.08) v1(40.84,65.58) v1(40.94,65.38) v1(40.84,65.18) v1(40.94,64.93) v1(40.94,46.29) v1(40.92,26.41) v1(40.9,23.02) v1(40.98,64.55) v1(40.97,61.79) v1(40.99,48.3) v1(40.95,32.66) v1(40.95,31.3) v1(40.95,15.68) v1(40.97,15.23) v1(41.11,48.17) v1(41.12,46.29) v1(41.07,23.6) v1(41.04,22.28) v1(41.09,21.27) v1(41.04,20.28) v1(41.05,18.65) v1(41.07,16.98) v1(41.06,16.53) v1(41.06,15.94) v1(41.04,13.16) v1(41.07,12.51) v1(41.24,66) v1(41.17,59.93) v1(41.17,54.48) v1(41.14,29.42) v1(41.23,24.14) v1(41.15,17.81) v1(41.21,16.23) v1(41.25,66.58) v1(41.29,48.21) v1(41.31,41.89) v1(41.31,35.59) v1(41.26,27.06) v1(41.29,21.83) v1(41.3,14.18) v1(41.3,13.71) v1(41.36,67.09) v1(41.41,31.79) v1(41.43,18.35) v1(41.41,15.98) v1(41.35,12.52) v1(41.46,68.52) v1(41.53,49.9) v1(41.47,48.21) v1(41.53,33.71) v1(41.58,65.22) v1(41.55,47.27) v1(41.55,33.33) v1(41.54,29.85) v1(41.56,17.01) v1(41.58,16.23) v1(41.65,48.17) v1(41.71,25.75) v1(41.71,25.14) v1(41.69,24.29) v1(41.72,23.61) v1(41.72,23.27) v1(41.74,23) v1(41.66,14.85) v1(41.72,13.09) v1(41.75,41.91) v1(41.76,22.17) v1(41.75,21.59) v1(41.76,20.66) v1(41.76,19.66) v1(41.76,18.65) v1(41.78,16.73) v1(41.79,16.3) v1(41.79,15.64) v1(41.84,56.54) v1(41.85,54.45) v1(41.87,51.15) v1(41.92,50.05) v1(41.93,34.55) v1(41.89,31.23) v1(41.94,30.49) v1(41.84,27.46) v1(41.87,26.53) v1(41.84,18.05) v1(41.91,17.47) v1(41.88,15.26) v1(41.99,35.6) v1(41.95,32.66) v1(42.02,29.38) v1(42.01,26.17) v1(41.98,24.14) v1(41.97,22.62) v1(42.11,68.04) v1(42.13,64.56) v1(42.13,34.55) v1(42.08,28.55) v1(42.04,27.54) v1(42.04,14.64) v1(42.22,67.11) v1(42.19,61.9) v1(42.23,60.47) v1(42.18,42.99) v1(42.23,35.41) v1(42.23,17.28) v1(42.14,15.78) v1(42.22,13.74) v1(42.27,53.02) v1(42.25,42.41) v1(42.25,30.48) v1(42.32,25.77) v1(42.32,25.07) v1(42.29,24.39) v1(42.31,23.91) v1(42.29,23.14) v1(42.29,22.58) v1(42.29,21.89) v1(42.31,21.39) v1(42.29,18.89) v1(42.29,17.89) v1(42.29,16.89) v1(42.36,42.99) v1(42.37,32.12) v1(42.37,31.94) v1(42.42,31.6) v1(42.34,26.59) v1(42.34,20.79) v1(42.34,19.94) v1(42.34,12.52) v1(42.52,66.49) v1(42.45,34.76) v1(42.47,29) v1(42.45,27.61) v1(42.5,13.08) v1(42.63,56.59) v1(42.6,55.53) v1(42.6,35.6) v1(42.54,31.04) v1(42.54,30.49) v1(42.61,23.76) v1(42.6,23.16) v1(42.57,19.37) v1(42.57,18.57) v1(42.54,16.28) v1(42.68,65.26) v1(42.71,29.01) v1(42.66,22.23) v1(42.65,18.12) v1(42.84,68.52) v1(42.8,54.49) v1(42.78,53.02) v1(42.75,42.41) v1(42.8,33.33) v1(42.75,31.93) v1(42.84,27.53) v1(42.84,25.78) v1(42.79,25.33) v1(42.79,20.78) v1(42.83,17.1) v1(42.81,15.05) v1(42.76,14.28) v1(42.89,51.2) v1(42.89,28.28) v1(42.88,27.01) v1(42.96,56.79) v1(43.02,55.66) v1(43.02,49.89) v1(42.97,29.67) v1(42.94,24.51) v1(42.99,23.28) v1(42.95,22.95) v1(42.95,22.56) v1(42.95,21.34) v1(43.09,47.97) v1(43.04,33.88) v1(43.09,19.19) v1(43.2,66.64) v1(43.19,64.84) v1(43.2,24.13) v1(43.18,19.76) v1(43.32,61.23) v1(43.28,35.6) v1(43.29,31.49) v1(43.29,24.94) v1(43.32,23.67) v1(43.31,22.08) v1(43.34,21.73) v1(43.26,21.38) v1(43.36,67.28) v1(43.4,56.39) v1(43.39,26.16) v1(43.42,17.79) v1(43.36,16.34) v1(43.53,54.98) v1(43.51,53.11) v1(43.45,32.16) v1(43.46,27.6) v1(43.5,20.55) v1(43.47,17.23) v1(43.61,61.89) v1(43.64,31.03) v1(43.64,28.83) v1(43.64,26.78) v1(43.55,26.57) v1(43.57,25.28) v1(43.6,21.38) v1(43.56,12.52) v1(43.73,33.11) v1(43.7,32.63) v1(43.71,29.95) v1(43.66,28.39) v1(43.72,24.13) v1(43.74,22.08) v1(43.73,21.09) v1(43.7,20.2) v1(43.72,19.71) v1(43.69,18.59) v1(43.81,68.18) v1(43.84,64.6) v1(43.81,63.3) v1(43.78,38.57) v1(43.84,30.09) v1(43.79,24.93) v1(43.83,23.65) v1(43.9,45.32) v1(43.91,33.9) v1(43.87,29.33) v1(43.92,21.74) v1(43.9,17.23) v1(43.9,16.29) v1(43.86,13.68) v1(43.95,51.39) v1(43.99,43.68) v1(44,41.81) v1(44,41.56) v1(44,41.06) v1(44,39.59) v1(43.97,39.04) v1(44.01,37.57) v1(44,36.06) v1(43.98,35.61) v1(43.95,34.77) v1(43.98,27.58) v1(44,27.03) v1(43.97,25.48) v1(44.01,20.86) v1(44.03,20.54) v1(43.99,19.29) v1(44.06,49.7) v1(44.05,42.95) v1(44.05,36.8) v1(44.08,33.63) v1(44.12,33.11) v1(44.07,27.26) v1(44.11,25.21) v1(44.1,24.92) v1(44.07,22.9) v1(44.1,22.08) v1(44.11,21.16) v1(44.16,60.03) v1(44.16,56.65) v1(44.15,55.02) v1(44.16,54.25) v1(44.16,47.45) v1(44.23,38.39) v1(44.16,25.65) v1(44.19,24.13) v1(44.14,18.09) v1(44.26,67.27) v1(44.27,50.5) v1(44.34,25.83) v1(44.32,25.51) v1(44.32,21.38) v1(44.35,56.68) v1(44.35,44.97) v1(44.39,29.03) v1(44.4,26.57) v1(44.38,26.39) v1(44.43,24.92) v1(44.36,17.74) v1(44.42,15.53) v1(44.49,68.5) v1(44.5,48.31) v1(44.44,40.46) v1(44.45,29.38) v1(44.44,25.19) v1(44.46,23.65) v1(44.44,22.08) v1(44.49,21.74) v1(44.61,64.86) v1(44.55,46.88) v1(44.57,42.39) v1(44.58,33.66) v1(44.54,24.61) v1(44.55,24.28) v1(44.6,12.52) v1(44.66,51.9) v1(44.74,47.5) v1(44.7,24.91) v1(44.69,21.38) v1(44.75,66.46) v1(44.75,65.31) v1(44.76,63.3) v1(44.76,39.76) v1(44.83,30.05) v1(44.75,26.89) v1(44.79,25.19) v1(44.81,23.25) v1(44.78,22.08) v1(44.91,22.67) v1(44.91,20.9) v1(44.87,14.23) v1(44.86,13.21) v1(44.97,27.18) v1(44.98,24.63) v1(44.98,24.29) v1(44.94,18.05) v1(45.13,38.61) v1(45.13,34.68) v1(45.13,33.95) v1(45.12,33.27) v1(45.12,32.27) v1(45.09,25.96) v1(45.09,25.19) v1(45.09,24.92) v1(45.13,23.33) v1(45.08,20.37) v1(45.1,19.34) v1(45.04,13.77) v1(45.19,61.07) v1(45.18,54.98) v1(45.18,41.82) v1(45.22,28.51) v1(45.21,25.71) v1(45.22,25.46) v1(45.19,23.78) v1(45.2,17.23) v1(45.2,16.85) v1(45.3,40.45) v1(45.32,21.9) v1(45.32,20.16) v1(45.4,68.71) v1(45.39,29.34) v1(45.41,25.22) v1(45.42,24.98) v1(45.41,24.19) v1(45.38,21.16) v1(45.39,18.04) v1(45.51,46.13) v1(45.51,41.31) v1(45.45,35.61) v1(45.45,34.03) v1(45.47,30.31) v1(45.52,27.34) v1(45.5,22.04) v1(45.51,17.79) v1(45.46,15.51) v1(45.54,63.32) v1(45.55,39.13) v1(45.63,38.12) v1(45.62,31.27) v1(45.58,25.94) v1(45.58,25.57) v1(45.56,24.09) v1(45.56,23.5) v1(45.56,23.24) v1(45.56,22.94) v1(45.56,22.76) v1(45.54,17.11) v1(45.61,14.24) v1(45.64,12.52) v1(45.74,60.93) v1(45.67,51.49) v1(45.74,48.47) v1(45.74,39.96) v1(45.72,24) v1(45.69,21.03) v1(45.69,20.17) v1(45.68,16.73) v1(45.66,16.36) v1(45.77,65.29) v1(45.78,64.59) v1(45.76,32.72) v1(45.8,31.82) v1(45.82,25.96) v1(45.78,25.22) v1(45.84,15.73) v1(45.79,15.04) v1(45.79,13.78) v1(45.86,24.36) v1(45.97,46.17) v1(46.02,43.5) v1(46,34.69) v1(45.97,18.39) v1(45.94,13.2) v1(46.13,60) v1(46.13,59.5) v1(46.13,59) v1(46.13,57.5) v1(46.13,57) v1(46.13,56) v1(46.13,53.5) v1(46.13,52.5) v1(46.13,52.11) v1(46.13,50.5) v1(46.13,50) v1(46.13,49.39) v1(46.1,27.35) v1(46.13,25.38) v1(46.06,22.41) v1(46.09,16.22) v1(46.09,13.78) v1(46.2,37.54) v1(46.22,34.3) v1(46.22,33.63) v1(46.14,29.34) v1(46.16,27.02) v1(46.2,22.76) v1(46.16,21.61) v1(46.16,20.86) v1(46.16,19.71) v1(46.14,19.36) v1(46.15,18.99) v1(46.14,15.03) v1(46.25,66.47) v1(46.27,35.48) v1(46.25,31.46) v1(46.31,21.23) v1(46.33,18.03) v1(46.42,41.83) v1(46.35,36.51) v1(46.39,30.24) v1(46.39,23.55) v1(46.4,23.25) v1(46.35,21.93) v1(46.41,20.25) v1(46.34,17.15) v1(46.44,35.04) v1(46.44,34.16) v1(46.48,25.49) v1(46.48,22.71) v1(46.48,22.35) v1(46.51,19.36) v1(46.48,18.95) v1(46.44,17.84) v1(46.49,16.22) v1(46.61,63.3) v1(46.63,59.5) v1(46.63,57.5) v1(46.64,52.1) v1(46.63,50) v1(46.6,33.65) v1(46.64,29.53) v1(46.61,27.15) v1(46.6,25.95) v1(46.54,16.94) v1(46.65,68.7) v1(46.68,62.07) v1(46.69,29.13) v1(46.68,27.58) v1(46.79,63.77) v1(46.74,61.51) v1(46.76,35.24) v1(46.83,23.35) v1(46.81,20.86) v1(46.81,20.46) v1(46.79,19.77) v1(46.81,19.36) v1(46.81,18.61) v1(46.81,16.67) v1(46.82,14.03) v1(46.77,13.3) v1(46.89,29.34) v1(46.91,15.83) v1(46.89,12.53) v1(47.02,67.22) v1(47.01,64.68) v1(47.01,51.2) v1(46.97,46.17) v1(47.03,40.44) v1(47,26.28) v1(46.97,23.82) v1(47.13,60) v1(47.13,59) v1(47.13,57.5) v1(47.13,56.5) v1(47.13,53) v1(47.13,52) v1(47.13,50.5) v1(47.13,49.5) v1(47.08,46.58) v1(47.1,31.31) v1(47.07,25.42) v1(47.07,21.93) v1(47.19,55.58) v1(47.19,44.65) v1(47.24,36.1) v1(47.23,30.64) v1(47.24,29.78) v1(47.16,22.75) v1(47.18,21.58) v1(47.17,20.88) v1(47.17,20.41) v1(47.16,19.71) v1(47.16,16.16) v1(47.27,54.14) v1(47.32,46.57) v1(47.29,41.8) v1(47.27,23.5) v1(47.27,23.19) v1(47.26,17.52) v1(47.35,65.29) v1(47.41,63.3) v1(47.38,37.54) v1(47.41,16.74) v1(47.36,15.36) v1(47.5,32.53) v1(47.5,27.15) v1(47.5,18.95) v1(47.6,67.2) v1(47.63,59.5) v1(47.63,57) v1(47.63,56) v1(47.63,53.5) v1(47.63,52.5) v1(47.63,50) v1(47.55,30.15) v1(47.59,26.75) v1(47.56,26.27) v1(47.56,22.35) v1(47.56,21.21) v1(47.56,20.09) v1(47.54,18.55) v1(47.58,15.74) v1(47.72,47.49) v1(47.7,36.57) v1(47.69,24.56) v1(47.71,23.18) v1(47.73,19.32) v1(47.69,12.52) v1(47.83,68.64) v1(47.83,36.44) v1(47.8,25.42) v1(47.75,23.72) v1(47.81,22.76) v1(47.81,22.03) v1(47.84,21.43) v1(47.84,20.43) v1(47.84,19.7) v1(47.8,14.92) v1(47.92,44.59) v1(47.9,41.45) v1(47.97,46.17) v1(47.95,43.09) v1(48.03,31.98) v1(47.97,31.44) v1(47.98,30.43) v1(48.03,29.34) v1(48,26.74) v1(48.03,15.32) v1(47.94,13.84) v1(48.11,62.08) v1(48.13,60) v1(48.13,59) v1(48.13,56) v1(48.13,55) v1(48.13,54.5) v1(48.13,53.5) v1(48.11,50.41) v1(48.13,49.5) v1(48.11,36.98) v1(48.09,34.56) v1(48.09,34.26) v1(48.09,33.96) v1(48.09,33.66) v1(48.13,16.32) v1(48.16,63.3) v1(48.18,58.39) v1(48.2,25.51) v1(48.17,21.92) v1(48.2,19.69) v1(48.16,18.55) v1(48.15,17.95) v1(48.2,14.52) v1(48.32,66.43) v1(48.32,32.24) v1(48.27,22.67) v1(48.34,21.43) v1(48.25,20.86) v1(48.25,20.37) v1(48.39,34.56) v1(48.38,34.38) v1(48.39,33.96) v1(48.39,33.66) v1(48.35,17.51) v1(48.36,15.32) v1(48.52,68.24) v1(48.52,21.21) v1(48.52,20.09) v1(48.52,18.95) v1(48.46,17.19) v1(48.6,46.58) v1(48.6,45.06) v1(48.59,30.41) v1(48.64,28.84) v1(48.56,25.97) v1(48.57,25.33) v1(48.7,64.68) v1(48.68,47.31) v1(48.74,40.79) v1(48.73,33.96) v1(48.73,33.66) v1(48.69,29.53) v1(48.72,21.93) v1(48.66,14.06) v1(48.75,38.92) v1(48.8,37.47) v1(48.79,22.27) v1(48.84,21.57) v1(48.84,20.47) v1(48.84,19.68) v1(48.84,19.18) v1(48.84,17.09) v1(48.83,12.52) v1(48.88,61.71) v1(48.93,36.12) v1(48.86,22.76) v1(48.87,16.19) v1(49.02,63.58) v1(49,63) v1(49.02,50.83) v1(48.96,30.79) v1(49.03,17.95) v1(49.09,38.61) v1(49.04,36.79) v1(49.09,33.96) v1(49.09,33.66) v1(49.06,33.33) v1(49.07,28.77) v1(49.16,36.94) v1(49.21,32.24) v1(49.19,19.35) v1(49.21,18.55) v1(49.27,46.17) v1(49.3,30.15) v1(49.28,24.76) v1(49.3,22.74) v1(49.26,21.97) v1(49.25,19.71) v1(49.37,68.24) v1(49.36,43.1) v1(49.43,36.08) v1(49.39,34.56) v1(49.39,34.26) v1(49.39,33.96) v1(49.39,33.66) v1(49.41,23.82) v1(49.35,21.55) v1(49.47,67.75) v1(49.49,65.28) v1(49.49,40.8) v1(49.52,37.48) v1(49.44,20.94) v1(49.5,18.11) v1(49.45,15.9) v1(49.57,42.4) v1(49.63,25.13) v1(49.54,22.35) v1(49.54,21.21) v1(49.54,20.09) v1(49.54,18.95) v1(49.55,17.49) v1(49.62,16.18) v1(49.71,62.5) v1(49.65,30.82) v1(49.67,17.09) v1(49.84,33.75) v1(49.83,32.59) v1(49.83,21.97) v1(49.83,21.58) v1(49.8,20.4) v1(49.81,19.32) v1(49.85,31.26) v1(49.87,28.77) v1(49.85,23.21) v1(49.86,22.76) v1(49.85,18.57) v1(49.91,17.95) v1(49.86,15.61) v1(49.94,64.69) v1(50,63.76) v1(50,61.25) v1(50,44.58) v1(49.95,39.11) v1(49.99,30.61) v1(49.99,29.43) v1(49.98,23.51) v1(50.13,55.5) v1(50.13,54.5) v1(50.08,41.42) v1(50.08,40.79) v1(50.09,39.26) v1(50.15,32.46) v1(50.23,22.04) v1(50.23,19.86) v1(50.21,19.3) v1(50.21,18.55) v1(50.2,16.73) v1(50.2,15.82) v1(50.32,46.17) v1(50.32,45.06) v1(50.27,38.23) v1(50.31,33.28) v1(50.3,23.5) v1(50.27,22.61) v1(50.27,21.57) v1(50.34,20.43) v1(50.42,37.48) v1(50.43,37.19) v1(50.39,31.59) v1(50.42,24.2) v1(50.42,23.24) v1(50.39,20.86) v1(50.36,18.11) v1(50.41,12.53) v1(50.45,46.79) v1(50.52,30) v1(50.48,17.51) v1(50.63,57.5) v1(50.63,56) v1(50.63,55) v1(50.63,54) v1(50.63,52.5) v1(50.63,52) v1(50.62,36.29) v1(50.57,34.01) v1(50.62,28.77) v1(50.56,22.35) v1(50.56,21.17) v1(50.56,20.09) v1(50.56,18.95) v1(50.65,57.02) v1(50.66,32.48) v1(50.73,31.12) v1(50.73,23.2) v1(50.72,16.74) v1(50.72,15.82) v1(50.79,66.43) v1(50.76,36.16) v1(50.75,34.01) v1(50.81,22.04) v1(50.84,21.43) v1(50.93,39.38) v1(50.88,33.27) v1(50.89,29.58) v1(50.85,23.51) v1(50.91,22.76) v1(50.88,20.42) v1(50.91,19.66) v1(50.9,19.34) v1(50.85,18.6) v1(51.02,33.75) v1(51.11,65.28) v1(51.08,64.66) v1(51.13,59.59) v1(51.13,59) v1(51.13,58.5) v1(51.13,58) v1(51.13,56) v1(51.13,55) v1(51.13,54) v1(51.13,51.5) v1(51.13,50.94) v1(51.13,50.5) v1(51.13,50) v1(51.13,39.38) v1(51.09,34.77) v1(51.11,24.29) v1(51.12,15.93) v1(51.17,45.7) v1(51.21,31.96) v1(51.22,18.79) v1(51.14,15.09) v1(51.3,63.32) v1(51.33,62.46) v1(51.33,39.38) v1(51.27,38.23) v1(51.31,36.67) v1(51.33,30.67) v1(51.25,22.72) v1(51.25,21.95) v1(51.34,21.57) v1(51.25,20.48) v1(51.32,19.74) v1(51.26,19.36) v1(51.32,16.39) v1(51.26,13.03) v1(51.26,12.52) v1(51.4,33.44) v1(51.42,32.65) v1(51.37,28.77) v1(51.39,20.89) v1(51.48,67.38) v1(51.47,66.9) v1(51.48,66.55) v1(51.51,61.32) v1(51.47,35.13) v1(51.53,29.07) v1(51.56,65.86) v1(51.56,65.36) v1(51.56,64.86) v1(51.56,64.27) v1(51.57,62.46) v1(51.64,59.04) v1(51.63,57.5) v1(51.63,56.94) v1(51.63,55.5) v1(51.63,54.5) v1(51.63,53.61) v1(51.63,52.5) v1(51.63,52) v1(51.63,50.5) v1(51.59,31.05) v1(51.56,25.13) v1(51.64,22.33) v1(51.58,21.21) v1(51.58,20.09) v1(51.58,18.95) v1(51.59,15.52) v1(51.7,68.23) v1(51.73,23.51) v1(51.73,23.2) v1(51.65,16.39) v1(51.81,67.37) v1(51.82,66.91) v1(51.79,66.55) v1(51.81,65.86) v1(51.81,65.36) v1(51.81,64.86) v1(51.8,63.97) v1(51.78,38.26) v1(51.81,33.87) v1(51.83,32.76) v1(51.8,29.87) v1(51.8,23.82) v1(51.9,24.2) v1(51.91,22.76) v1(51.91,21.96) v1(51.86,21.6) v1(51.91,21.16) v1(51.91,20.5) v1(51.93,19.69) v1(51.91,19.36) v1(51.89,14.84) v1(51.97,35.13) v1(51.99,18.49) v1(52.12,67.35) v1(52.1,66.9) v1(52.1,66.55) v1(52.06,65.86) v1(52.06,65.36) v1(52.06,64.86) v1(52.06,63.68) v1(52.13,56) v1(52.13,55.5) v1(52.13,54.5) v1(52.13,53.61) v1(52.07,45.42) v1(52.12,28.27) v1(52.15,39.37) v1(52.14,27.78) v1(52.23,25.66) v1(52.22,24.9) v1(52.29,34.26) v1(52.28,32.75) v1(52.41,67.88) v1(52.4,41.63) v1(52.36,39.37) v1(52.36,29.5) v1(52.36,25.29) v1(52.4,24.57) v1(52.38,22.78) v1(52.38,22.34) v1(52.51,67.15) v1(52.51,66.91) v1(52.51,66.44) v1(52.52,65.35) v1(52.52,65.1) v1(52.5,64.34) v1(52.46,46.22) v1(52.52,35.56) v1(52.46,34.58) v1(52.48,31.78) v1(52.44,26.59) v1(52.52,23.51) v1(52.53,21.53) v1(52.53,19.77) v1(52.49,18.08) v1(52.51,12.52) v1(52.55,63.94) v1(52.63,53.61) v1(52.58,39.37) v1(52.56,38.3) v1(52.62,33.11) v1(52.62,32.68) v1(52.63,31.07) v1(52.62,28.26) v1(52.58,17.05) v1(52.58,16.65) v1(52.62,15.87) v1(52.62,14.63) v1(52.65,63.32) v1(52.73,29.91) v1(52.67,25) v1(52.69,23.23) v1(52.7,22.92) v1(52.69,22.47) v1(52.66,17.8) v1(52.65,15.17) v1(52.79,37.51) v1(52.8,34.78) v1(52.82,33.36) v1(52.82,32.86) v1(52.81,31.48) v1(52.87,27.52) v1(52.89,27.03) v1(52.92,24.2) v1(53,31.22) v1(53.03,30.39) v1(53.04,27.97) v1(53.02,23.34) v1(53.01,22.23) v1(52.97,21.43) v1(52.97,20.62) v1(52.94,19.68) v1(53.03,18.86) v1(52.98,15.59) v1(53.09,40.46) v1(53.07,33.61) v1(53.11,18.21) v1(53.08,14.07) v1(53.11,13.52) v1(53.09,12.63) v1(53.18,63.43) v1(53.17,44.6) v1(53.15,42.46) v1(53.16,31.76) v1(53.19,25.84) v1(53.28,66.45) v1(53.25,39.37) v1(53.27,38.23) v1(53.29,37.51) v1(53.32,34.35) v1(53.32,33.85) v1(53.32,33.35) v1(53.3,16.4) v1(53.39,64.33) v1(53.42,40.78) v1(53.35,27.66) v1(53.43,24.45) v1(53.48,41.64) v1(53.51,39.33) v1(53.55,67.95) v1(53.56,46.22) v1(53.56,36.08) v1(53.55,33.12) v1(53.55,32.6) v1(53.56,29.75) v1(53.62,23.12) v1(53.7,27.75) v1(53.7,19.71) v1(53.72,16.02) v1(53.79,63.41) v1(53.81,34.89) v1(53.8,33.36) v1(53.78,22.26) v1(53.75,21.84) v1(53.75,20.82) v1(53.75,19.2) v1(53.77,12.92) v1(53.91,65.66) v1(53.91,31.92) v1(53.86,31.27) v1(53.87,26.52) v1(53.93,26.06) v1(53.87,18.85) v1(54,66.45) v1(53.99,41.8) v1(53.97,30.19) v1(53.98,29.63) v1(54.06,63.48) v1(54.04,62.12) v1(54.06,33.6) v1(54.11,31.16) v1(54.12,26.93) v1(54.07,21.39) v1(54.07,20.31) v1(54.18,46.49) v1(54.2,40.43) v1(54.23,38.22) v1(54.19,31.51) v1(54.2,25.23) v1(54.14,17.61) v1(54.17,12.72) v1(54.31,34.79) v1(54.26,33.35) v1(54.32,30.81) v1(54.28,30.3) v1(54.31,29.81) v1(54.4,48.46) v1(54.35,35.8) v1(54.39,25.53) v1(54.36,16.65) v1(54.52,68.23) v1(54.5,66.17) v1(54.51,45.97) v1(54.46,45.23) v1(54.44,24.34) v1(54.51,20.34) v1(54.62,56.24) v1(54.6,44.22) v1(54.55,35.14) v1(54.55,33.11) v1(54.55,32.63) v1(54.61,31.91) v1(54.62,25.77) v1(54.64,25.18) v1(54.72,64.39) v1(54.65,62.09) v1(54.66,61.67) v1(54.66,60.96) v1(54.68,59.33) v1(54.67,57.47) v1(54.67,54.13) v1(54.68,18.62) v1(54.69,18.04) v1(54.71,17.38) v1(54.75,51.59) v1(54.79,43.24) v1(54.75,38.22) v1(54.74,37.57) v1(54.76,33.85) v1(54.8,33.36) v1(54.76,32.86) v1(54.84,26.51) v1(54.79,26.02) v1(54.88,68.15) v1(54.89,12.73) v1(54.97,46.34) v1(55.01,29.37) v1(55.03,21.43) v1(54.94,19.36) v1(55.13,61.63) v1(55.09,49.42) v1(55.05,36.08) v1(55.05,34.59) v1(55.05,33.62) v1(55.05,20.09) v1(55.16,66.48) v1(55.15,65.65) v1(55.15,62.48) v1(55.19,23.59) v1(55.14,14.08) v1(55.27,38.22) v1(55.3,37.49) v1(55.27,36.29) v1(55.25,33.86) v1(55.3,33.36) v1(55.3,28.95) v1(55.25,27.1) v1(55.41,44.41) v1(55.42,43.34) v1(55.38,41.47) v1(55.34,40.92) v1(55.37,25.02) v1(55.45,59.01) v1(55.46,58.45) v1(55.46,57.9) v1(55.46,57.4) v1(55.46,56.9) v1(55.46,53.32) v1(55.45,52.8) v1(55.54,50.3) v1(55.47,46.09) v1(55.51,39.38) v1(55.6,63.39) v1(55.55,42.01) v1(55.55,35.59) v1(55.54,33.11) v1(55.57,28.2) v1(55.59,25.45) v1(55.56,19.54) v1(55.65,64.34) v1(55.72,46.49) v1(55.69,39.38) v1(55.67,37.49) v1(55.71,32.28) v1(55.71,31.7) v1(55.68,26.52) v1(55.7,25.84) v1(55.71,21.41) v1(55.66,20.73) v1(55.68,14.09) v1(55.68,13.54) v1(55.68,12.97) v1(55.74,61.69) v1(55.78,59.57) v1(55.77,56.05) v1(55.76,52.08) v1(55.75,36.35) v1(55.79,35.34) v1(55.79,34.85) v1(55.82,34.36) v1(55.79,33.38) v1(55.82,31.09) v1(55.82,30.74) v1(55.82,30.39) v1(55.82,30.04) v1(55.82,29.69) v1(55.79,29.41) v1(55.9,60.81) v1(55.91,58.78) v1(55.85,54.72) v1(55.85,38.21) v1(55.92,25.12) v1(55.93,24.85) v1(55.89,24.03) v1(55.87,19.56) v1(55.97,59.81) v1(55.98,52.08) v1(56.04,34.64) v1(55.94,22.84) v1(56.12,59.26) v1(56.06,57.1) v1(56.06,46.57) v1(56.08,36.05) v1(56.07,35.62) v1(56.04,33.61) v1(56.13,31.09) v1(56.13,30.74) v1(56.13,30.39) v1(56.13,30.04) v1(56.13,29.69) v1(56.05,27.79) v1(56.12,24.27) v1(56.11,12.73) v1(56.18,67.86) v1(56.14,66.27) v1(56.17,64.28) v1(56.18,37.49) v1(56.23,28.64) v1(56.17,27.15) v1(56.14,23.68) v1(56.2,19.54) v1(56.14,14.08) v1(56.24,63.58) v1(56.29,35.34) v1(56.33,33.37) v1(56.24,23.46) v1(56.31,21.59) v1(56.28,19.99) v1(56.38,27.7) v1(56.42,25.6) v1(56.5,41.47) v1(56.48,40.34) v1(56.44,38.21) v1(56.46,31.09) v1(56.46,30.74) v1(56.46,30.39) v1(56.46,30.04) v1(56.46,29.69) v1(56.51,21.26) v1(56.55,65.66) v1(56.59,62.39) v1(56.56,51.86) v1(56.6,47.07) v1(56.55,44.41) v1(56.55,40.99) v1(56.61,34.58) v1(56.56,33.15) v1(56.64,23.46) v1(56.58,20.78) v1(56.66,26.78) v1(56.71,24.09) v1(56.68,14.09) v1(56.84,58.78) v1(56.8,37.56) v1(56.8,32.5) v1(56.77,31.08) v1(56.77,30.74) v1(56.77,30.39) v1(56.77,30.04) v1(56.77,29.69) v1(56.74,26.35) v1(56.84,24.65) v1(56.88,66.07) v1(56.9,63.48) v1(56.87,46.04) v1(56.91,32.16) v1(56.9,27.37) v1(56.86,19.96) v1(56.92,19.23) v1(56.92,18.73) v1(56.98,68.24) v1(56.99,61.39) v1(57,60.13) v1(57,59.65) v1(57.03,51.75) v1(56.99,48.1) v1(57,42.83) v1(56.97,28.52) v1(56.94,27.75) v1(56.98,23.46) v1(57.03,21.71) v1(56.95,13.46) v1(57.1,64.39) v1(57.11,55.02) v1(57.11,54.71) v1(57.1,30.74) v1(57.1,21.32) v1(57.1,18.43) v1(57.11,12.73) v1(57.22,46.49) v1(57.18,18.98) v1(57.21,14.09) v1(57.33,66.02) v1(57.33,57.88) v1(57.3,42.17) v1(57.25,27.56) v1(57.3,26.6) v1(57.27,26.21) v1(57.29,25) v1(57.43,24.01) v1(57.39,22.53) v1(57.42,19.23) v1(57.43,18.74) v1(57.43,18.32) v1(57.53,66.3) v1(57.49,54.09) v1(57.5,53.64) v1(57.5,53.14) v1(57.49,52.65) v1(57.51,41.46) v1(57.52,36.42) v1(57.52,35.91) v1(57.52,35.33) v1(57.51,34.39) v1(57.52,33.94) v1(57.52,33.33) v1(57.54,32.83) v1(57.47,31.97) v1(57.46,29.38) v1(57.45,23.37) v1(57.5,19.89) v1(57.5,17.27) v1(57.5,16.95) v1(57.59,44.63) v1(57.56,34.94) v1(57.58,31.44) v1(57.58,27.75) v1(57.57,27.37) v1(57.61,13.2) v1(57.66,42.16) v1(57.68,14.09) v1(57.69,12.97) v1(57.68,12.55) v1(57.78,51.82) v1(57.82,45.55) v1(57.79,37.9) v1(57.77,37.33) v1(57.83,36.33) v1(57.84,35.4) v1(57.84,34.38) v1(57.84,29.26) v1(57.82,28.29) v1(57.77,26.62) v1(57.78,26.03) v1(57.82,22.88) v1(57.74,19.22) v1(57.86,66.44) v1(57.87,62.59) v1(57.86,50.56) v1(57.91,24.6) v1(57.89,21.78) v1(57.87,20.76) v1(58,33.51) v1(57.95,23.75) v1(58.1,41.82) v1(58.1,41.59) v1(58.05,40.55) v1(58.11,27.42) v1(58.2,63.08) v1(58.14,61.88) v1(58.19,60.79) v1(58.18,59.26) v1(58.15,31.6) v1(58.21,22.59) v1(58.22,21.03) v1(58.2,20.02) v1(58.27,67.18) v1(58.28,66.91) v1(58.28,65.38) v1(58.29,65.11) v1(58.3,57) v1(58.33,53.74) v1(58.34,41.73) v1(58.24,40.55) v1(58.33,35.59) v1(58.24,33.86) v1(58.24,31.09) v1(58.27,30.32) v1(58.29,27.78) v1(58.4,34.72) v1(58.4,31.6) v1(58.41,25.24) v1(58.46,37.17) v1(58.46,36.17) v1(58.46,35.17) v1(58.49,27.22) v1(58.52,26.14) v1(58.52,20.19) v1(58.58,52.42) v1(58.62,30.88) v1(58.56,29.09) v1(58.7,67.31) v1(58.72,66.9) v1(58.73,66.45) v1(58.7,65.81) v1(58.72,65.54) v1(58.71,65.27) v1(58.66,51.35) v1(58.68,48.34) v1(58.71,28.95) v1(58.69,24.08) v1(58.69,23.35) v1(58.67,18.57) v1(58.81,57.99) v1(58.74,46.39) v1(58.74,31.23) v1(58.74,24.44) v1(58.76,22.02) v1(58.76,20.57) v1(58.79,20.02) v1(58.82,18.74) v1(58.86,29.09) v1(58.96,68.21) v1(58.97,67.3) v1(59,66.89) v1(59,66.44) v1(58.97,65.8) v1(59,65.53) v1(58.98,65.26) v1(59,63.48) v1(59.03,35.52) v1(59,34.11) v1(58.97,26.8) v1(58.97,26.39) v1(58.96,23.02) v1(59.13,51.02) v1(59.09,28.4) v1(59.09,25.7) v1(59.21,33.17) v1(59.21,32.17) v1(59.21,31.17) v1(59.17,29.38) v1(59.15,27.73) v1(59.21,23.65) v1(59.18,22.5) v1(59.18,17.24) v1(59.32,67.31) v1(59.25,66.89) v1(59.3,66.45) v1(59.32,65.81) v1(59.25,65.53) v1(59.28,65.27) v1(59.34,55.63) v1(59.33,55.17) v1(59.33,54.77) v1(59.25,48.12) v1(59.24,34.69) v1(59.3,24.35) v1(59.28,22.87) v1(59.35,47.35) v1(59.4,35.28) v1(59.38,29.63) v1(59.35,25.02) v1(59.43,17.77) v1(59.37,17.24) v1(59.48,31.84) v1(59.53,27.73) v1(59.44,22.03) v1(59.44,19.88) v1(59.44,19.1) v1(59.45,18.38) v1(59.59,33.8) v1(59.6,32.91) v1(59.55,30.97) v1(59.6,28.41) v1(59.64,25.71) v1(59.6,22.99) v1(59.73,54.77) v1(59.72,41.83) v1(59.68,32.06) v1(59.71,30.17) v1(59.7,26.45) v1(59.7,26.05) v1(59.75,62.88) v1(59.74,44.45) v1(59.77,38.55) v1(59.76,34.5) v1(59.93,63.27) v1(59.86,27.54) v1(59.9,27.2) v1(59.86,22.48) v1(59.85,18.37) v1(59.99,61.29) v1(60.01,48.44) v1(60.07,68.44) v1(60.13,55.17) v1(60.13,54.77) v1(60.1,35.52) v1(60.07,29.48) v1(60.08,28.42) v1(60.06,23.59) v1(60.14,31.22) v1(60.18,19.88) v1(60.18,19.58) v1(60.18,19.23) v1(60.18,18.88) v1(60.19,14.09) v1(60.34,47.28) v1(60.34,32.03) v1(60.34,22.58) v1(60.33,16.99) v1(60.4,56.56) v1(60.37,51.41) v1(60.4,30.14) v1(60.37,26.45) v1(60.39,21.85) v1(60.39,21.33) v1(60.39,20.98) v1(60.54,69.29) v1(60.5,62.13) v1(60.53,55.17) v1(60.46,35.72) v1(60.46,29.42) v1(60.53,19.88) v1(60.53,19.58) v1(60.53,19.23) v1(60.53,18.88) v1(60.54,16.44) v1(60.48,14.09) v1(60.61,26.98) v1(60.54,24.42) v1(60.68,66.98) v1(60.65,28.19) v1(60.66,27.55) v1(60.76,45.36) v1(60.77,34.16) v1(60.77,33.89) v1(60.81,30.89) v1(60.8,24.94) v1(60.81,22.52) v1(60.74,21.33) v1(60.74,20.98) v1(60.82,18.29) v1(60.76,16.42) v1(60.93,54.77) v1(60.93,54.37) v1(60.91,24.42) v1(60.89,23.7) v1(60.92,23.1) v1(60.87,15.77) v1(61.01,67.84) v1(60.99,60.12) v1(61.02,52.4) v1(60.98,50.29) v1(61.01,35.85) v1(61,34.16) v1(61,33.89) v1(61,31.84) v1(60.97,26.06) v1(61.05,66.35) v1(61.13,62.56) v1(61.06,30.11) v1(61.09,21.33) v1(61.09,20.98) v1(61.15,63.27) v1(61.19,59.06) v1(61.25,61.38) v1(61.26,59.67) v1(61.33,54.77) v1(61.33,53.17) v1(61.26,44.46) v1(61.31,32.16) v1(61.3,31.14) v1(61.31,29.27) v1(61.31,28.27) v1(61.31,27.27) v1(61.31,26.27) v1(61.31,25.27) v1(61.31,24.27) v1(61.31,23.27) v1(61.31,22.27) v1(61.42,58.54) v1(61.35,29.71) v1(61.36,21.84) v1(61.39,21.33) v1(61.39,20.98) v1(61.37,19.25) v1(61.44,47.6) v1(61.44,47) v1(61.44,16.39) v1(61.63,39.13) v1(61.64,30.3) v1(61.61,19.5) v1(61.61,19) v1(61.73,53.57) v1(61.73,53.17) v1(61.69,52.1) v1(61.69,48.04) v1(61.7,43.6) v1(61.7,42.98) v1(61.7,35.85) v1(61.72,27.14) v1(61.71,26.75) v1(61.7,26.3) v1(61.7,25.83) v1(61.7,25.36) v1(61.7,24.89) v1(61.71,24.42) v1(61.7,23.94) v1(61.7,23.42) v1(61.7,22.88) v1(61.71,22.42) v1(61.7,21.95) v1(61.7,21.45) v1(61.7,20.95) v1(61.71,20.49) v1(61.7,19.82) v1(61.77,68.59) v1(61.83,64.61) v1(61.75,32.47) v1(61.75,31.27) v1(61.75,29.77) v1(61.75,28.57) v1(61.75,27.42) v1(61.8,17.76) v1(61.8,17.41) v1(61.86,40.8) v1(61.86,19.25) v1(61.86,18.75) v1(61.87,15.77) v1(62,60.63) v1(62.11,19) v1(62.07,18.54) v1(62.1,17.76) v1(62.1,17.41) v1(62.29,63.83) v1(62.25,56.69) v1(62.32,18.79) v1(62.4,35.85) v1(62.45,68.26) v1(62.45,60.37) v1(62.52,47.08) v1(62.52,18.94) v1(62.45,17.76) v1(62.45,17.41) v1(62.62,41.8) v1(62.66,50.82) v1(62.79,67) v1(62.79,65.56) v1(62.75,59.88) v1(62.8,17.76) v1(62.8,17.41) v1(62.77,15.77) v1(62.88,57.33) v1(63.09,46.31) v1(63.07,35.85) v1(63.18,45.32) v1(63.29,60.92) v1(63.26,17.02) v1(63.46,39.46) v1(63.52,18.94) v1(63.63,68.23) v1(63.55,56.87) v1(63.55,52.17) v1(63.7,50.89) v1(63.7,48.18) v1(63.68,46.89) v1(63.72,45.69) v1(63.76,64.37) v1(63.78,60.06) v1(63.74,59.69) v1(63.77,58.5) v1(63.83,39.04) v1(63.76,35.85) v1(63.9,61) v1(64.01,55.45) v1(64,54.08) v1(63.98,53.06) v1(64.04,52.22) v1(64.03,51.4) v1(64.03,50.21) v1(64.05,56.67) v1(64.17,18.66) v1(64.17,18.31) v1(64.17,17.96) v1(64.17,17.66) v1(64.28,64.76) v1(64.33,48.78) v1(64.27,47.57) v1(64.33,17.03) v1(64.38,67.49) v1(64.37,66.36) v1(64.42,44.06) v1(64.43,40.77) v1(64.48,65.19) v1(64.45,42.71) v1(64.44,38.69) v1(64.47,35.84) v1(64.52,18.94) v1(64.52,18.66) v1(64.52,18.31) v1(64.52,17.96) v1(64.52,17.66) v1(64.79,17.08) v1(64.82,15.84) v1(64.79,12.58) v1(64.79,12.08) v1(64.79,11.58) v1(64.79,11.08) v1(64.89,13.78) v1(64.99,48.08) v1(64.97,46.29) v1(65.17,61.93) v1(65.18,60.64) v1(65.18,58.64) v1(65.21,37.58) v1(65.16,37.08) v1(65.17,36.55) v1(65.14,36) v1(65.34,38.06) v1(65.31,16.59) v1(65.29,15.82) v1(65.37,64.64) v1(65.37,63.02) v1(65.37,56.64) v1(65.37,54.64) v1(65.37,46.13) v1(65.36,45.73) v1(65.36,45.17) v1(65.36,44.58) v1(65.36,44.17) v1(65.36,43.61) v1(65.36,43.02) v1(65.35,42.52) v1(65.36,41.96) v1(65.36,41.4) v1(65.36,40.81) v1(65.35,40.31) v1(65.35,39.71) v1(65.35,39.15) v1(65.35,38.56) v1(65.37,19.42) v1(65.47,20.24) v1(65.8,12.58) v1(65.8,12.08) v1(65.8,11.58) v1(65.8,11.08) v1(65.88,53.6) v1(65.99,51.84) v1(65.94,48.1) v1(65.94,17.61) v1(65.94,15.42) v1(66.19,18.27) v1(66.33,16.61) v1(66.37,52.51) v1(66.46,50.76) v1(66.47,20.24) v1(66.67,53.37) v1(66.69,15.43) v1(67.07,48.2) v1(67.08,18.67) v1(67.11,16.4) v1(67.2,49.46) v1(67.4,50.51) v1(67.44,15.43) v1(67.47,20.24) v1(67.86,16.62) v1(67.99,52.94) v1(68.09,48.56) v1(68.1,15.43) v1(68.15,52.71) v1(68.19,51.68) v1(68.15,50.94) v1(68.18,16.23) v1(68.33,49.31) v1(68.32,18.23) v1(68.25,17.23) v1(68.41,19.23) v1(68.47,20.24) v2(0.31,20.23) v2(0.36,19.37) v2(0.44,18.37) v2(0.44,52.2) v2(0.46,50.98) v2(0.48,49.2) v2(0.52,17.37) v2(0.59,16.36) v2(0.7,48.74) v2(0.67,15.36) v2(0.76,52.93) v2(0.84,18.28) v2(0.93,16.67) v2(1.07,52.86) v2(1.31,20.23) v2(1.5,50.41) v2(1.65,18.69) v2(1.7,16.36) v2(1.67,15.36) v2(1.82,53.35) v2(2.31,20.23) v2(2.46,18.38) v2(2.49,16.69) v2(2.47,15.36) v2(2.73,51.84) v2(2.65,48.1) v2(2.82,17.57) v2(3.11,15.36) v2(3.28,54.07) v2(3.3,46.28) v2(3.31,20.23) v2(3.41,64.79) v2(3.41,63.53) v2(3.41,62.49) v2(3.4,56.97) v2(3.4,55.18) v2(3.4,43.67) v2(3.4,40.67) v2(3.4,37.67) v2(3.42,19.41) v2(3.45,63.1) v2(3.6,61.35) v2(3.6,60.81) v2(3.6,60.28) v2(3.6,59.75) v2(3.6,59.22) v2(3.6,58.69) v2(3.6,58.16) v2(3.58,57.55) v2(3.59,48.88) v2(3.61,36.59) v2(3.6,35.51) v2(3.78,48.07) v2(3.8,15.35) v2(3.9,66.93) v2(3.91,65.67) v2(3.92,52.55) v2(3.91,51.53) v2(3.95,68.06) v2(4.04,15.88) v2(4.05,50.76) v2(4.17,15.35) v2(4.27,58.33) v2(4.28,57.01) v2(4.25,18.94) v2(4.41,18.2) v2(4.39,16.31) v2(4.5,67.02) v2(4.51,57.64) v2(4.46,51.52) v2(4.5,47.62) v2(4.54,46.85) v2(4.49,15.64) v2(4.72,66.57) v2(4.74,56.3) v2(4.81,44.15) v2(4.79,35.51) v2(4.89,55.11) v2(4.85,54.46) v2(4.85,51.55) v2(4.91,49.5) v2(5.06,68.22) v2(5.07,52.75) v2(5.17,56.8) v2(5.17,17.37) v2(5.17,17.19) v2(5.17,17.01) v2(5.16,16.33) v2(5.16,16.15) v2(5.16,15.97) v2(5.25,18.94) v2(5.26,16.67) v2(5.43,67.88) v2(5.53,60.16) v2(5.51,48.03) v2(5.51,46.29) v2(5.46,15.62) v2(5.55,63.9) v2(5.55,62.83) v2(5.61,59.25) v2(5.63,54.33) v2(5.57,45.24) v2(5.67,66.19) v2(5.67,17.22) v2(5.87,67.65) v2(5.87,53.12) v2(5.91,49.5) v2(5.92,15.62) v2(5.97,65.26) v2(5.98,64.5) v2(5.95,59.74) v2(6.1,58.08) v2(6.04,54.13) v2(6.09,44.64) v2(6.12,43.49) v2(6.12,41.27) v2(6.16,58.67) v2(6.23,45.36) v2(6.19,35.51) v2(6.29,68.24) v2(6.34,63.35) v2(6.32,52.83) v2(6.26,38.65) v2(6.25,18.94) v2(6.39,36.6) v2(6.34,15.64) v2(6.47,50.2) v2(6.56,18.43) v2(6.75,52.5) v2(6.91,64.11) v2(7.02,67.03) v2(6.94,66.05) v2(7.01,63.34) v2(7.02,57.73) v2(7.02,32.26) v2(7.02,31.24) v2(7.02,30.48) v2(7.02,28.09) v2(7.01,27) v2(7.03,25.44) v2(7.03,23.44) v2(7.03,20.24) v2(7.01,19.62) v2(7.03,19.01) v2(6.99,15.64) v2(7.06,52.72) v2(7.1,46.18) v2(7.09,44.97) v2(7.06,29.3) v2(7.2,68.72) v2(7.15,49.3) v2(7.34,63.35) v2(7.25,59.91) v2(7.4,52.92) v2(7.41,51.39) v2(7.38,43.52) v2(7.36,26.35) v2(7.37,21.89) v2(7.38,20.88) v2(7.39,20.11) v2(7.37,19.08) v2(7.38,17.64) v2(7.42,15.22) v2(7.44,62.28) v2(7.44,62.06) v2(7.47,50.35) v2(7.47,42.32) v2(7.47,39.74) v2(7.48,35.51) v2(7.44,29.75) v2(7.61,67.65) v2(7.64,37.24) v2(7.64,31.89) v2(7.57,16.14) v2(7.66,64.12) v2(7.72,27.79) v2(7.73,6.72) v2(7.83,57.99) v2(7.74,56.56) v2(7.75,44.64) v2(7.74,15.39) v2(7.78,14.87) v2(7.82,14.35) v2(7.82,13.78) v2(7.82,13.23) v2(7.82,12.68) v2(7.9,66.85) v2(7.88,66.06) v2(7.86,31.23) v2(7.93,29.61) v2(7.89,19.28) v2(8.01,69.32) v2(7.95,64.72) v2(8.01,57.99) v2(8.01,51.8) v2(7.98,25.05) v2(7.97,23.29) v2(8.01,8.29) v2(8.08,62.31) v2(8.08,62.11) v2(8.09,52.92) v2(8.11,42.8) v2(8.12,40.94) v2(8.05,30.45) v2(8.13,28.15) v2(8.11,27.39) v2(8.19,65.2) v2(8.21,46.47) v2(8.23,44.23) v2(8.14,28.88) v2(8.33,62.62) v2(8.31,52.31) v2(8.26,39.51) v2(8.25,30.06) v2(8.29,22.06) v2(8.24,15.6) v2(8.24,14.41) v2(8.47,65.19) v2(8.5,53.08) v2(8.52,51.52) v2(8.44,48.92) v2(8.48,36.24) v2(8.54,16.78) v2(8.52,12.68) v2(8.56,47.6) v2(8.61,27.62) v2(8.57,26.29) v2(8.56,18.55) v2(8.65,68.56) v2(8.67,67.65) v2(8.68,60.6) v2(8.71,41.26) v2(8.67,31.23) v2(8.72,30.69) v2(8.68,15.16) v2(8.79,53.32) v2(8.75,39.92) v2(8.76,29.84) v2(8.79,17.57) v2(8.74,13.84) v2(8.87,63.06) v2(8.87,28.76) v2(8.88,26.68) v2(8.99,69.33) v2(8.94,66) v2(9.01,64.11) v2(9.03,62.3) v2(9.03,62.07) v2(9.03,29.47) v2(9.03,19.75) v2(9.13,55.17) v2(9.12,18.76) v2(9.12,18.36) v2(9.12,17.96) v2(9.07,14.82) v2(9.15,67.32) v2(9.15,64.66) v2(9.14,50.72) v2(9.22,35.5) v2(9.16,30.83) v2(9.16,30.65) v2(9.18,29.07) v2(9.14,27.39) v2(9.19,21.91) v2(9.22,12.67) v2(9.29,63.32) v2(9.34,57.28) v2(9.24,56.56) v2(9.28,54.22) v2(9.24,19.36) v2(9.25,15.79) v2(9.25,14.22) v2(9.27,13.57) v2(9.38,68.63) v2(9.42,51.28) v2(9.41,30.29) v2(9.43,16.09) v2(9.39,15.15) v2(9.45,66.63) v2(9.45,66.41) v2(9.45,65.86) v2(9.49,64.9) v2(9.53,42.25) v2(9.53,39.08) v2(9.45,29.62) v2(9.52,18.77) v2(9.45,17.57) v2(9.49,6.41) v2(9.63,65.86) v2(9.63,63.58) v2(9.55,52.51) v2(9.64,28.34) v2(9.57,27.7) v2(9.68,66.63) v2(9.7,63.94) v2(9.71,50.35) v2(9.66,49.5) v2(9.7,29.74) v2(9.73,28.87) v2(9.73,18.39) v2(9.7,17.05) v2(9.71,12.22) v2(9.8,69.3) v2(9.83,68) v2(9.77,66.87) v2(9.75,66.4) v2(9.81,65.86) v2(9.84,65.1) v2(9.74,64.9) v2(9.78,60.65) v2(9.83,51.92) v2(9.77,48.04) v2(9.83,26.49) v2(9.82,17.92) v2(9.81,15.29) v2(9.76,7.99) v2(9.88,66.61) v2(9.9,63.61) v2(9.85,58.1) v2(9.88,52.68) v2(9.88,37.82) v2(9.9,29.48) v2(9.85,17.57) v2(9.93,16.57) v2(9.99,65.86) v2(9.99,62.6) v2(9.99,62.42) v2(9.99,62.23) v2(9.99,62.04) v2(9.99,61.85) v2(9.99,61.66) v2(10,61.47) v2(10.04,22.26) v2(9.96,14.45) v2(9.97,12.68) v2(10.1,67.28) v2(10.1,67.03) v2(10.1,66.72) v2(10.1,66.39) v2(10.09,65.1) v2(10.12,53.77) v2(10.13,30.77) v2(10.07,28.67) v2(10.05,14.95) v2(10.09,13.38) v2(10.18,62.6) v2(10.18,61.85) v2(10.18,61.66) v2(10.19,61.47) v2(10.19,52.98) v2(10.18,35.13) v2(10.17,31.86) v2(10.19,30.21) v2(10.19,22.73) v2(10.23,12.94) v2(10.2,12.38) v2(10.29,69.3) v2(10.3,68.48) v2(10.31,18.64) v2(10.25,18.37) v2(10.25,17.57) v2(10.25,16.77) v2(10.25,16.37) v2(10.32,15.93) v2(10.43,67.6) v2(10.36,56.31) v2(10.38,42.21) v2(10.44,67.17) v2(10.44,66.89) v2(10.44,66.4) v2(10.5,65.35) v2(10.5,65.16) v2(10.45,57.79) v2(10.52,54.32) v2(10.49,53.47) v2(10.46,30.77) v2(10.46,29.54) v2(10.5,28.65) v2(10.51,22.06) v2(10.63,45.89) v2(10.58,42.88) v2(10.61,40.09) v2(10.56,38.19) v2(10.58,37.09) v2(10.64,36.34) v2(10.61,30.27) v2(10.58,14.09) v2(10.55,13.16) v2(10.54,12.67) v2(10.67,65.8) v2(10.73,60.32) v2(10.73,59.92) v2(10.73,59.52) v2(10.66,50.41) v2(10.73,25.76) v2(10.65,17.57) v2(10.65,17.17) v2(10.65,16.3) v2(10.72,14.58) v2(10.76,62.23) v2(10.75,61.53) v2(10.77,58.23) v2(10.77,58.05) v2(10.83,50.82) v2(10.8,34.51) v2(10.89,68.37) v2(10.92,64.3) v2(10.93,63.11) v2(10.91,49.5) v2(10.92,38.26) v2(10.91,28.27) v2(10.86,27.27) v2(10.85,12.4) v2(10.86,12.14) v2(10.99,48.9) v2(11.02,31.26) v2(10.94,30.18) v2(11.01,18.79) v2(11.02,12.84) v2(11.04,19.35) v2(11.14,39.76) v2(11.14,39.23) v2(11.21,31.59) v2(11.15,29.43) v2(11.17,28.72) v2(11.14,28.25) v2(11.16,26.92) v2(11.16,26.22) v2(11.17,14.47) v2(11.2,14.08) v2(11.28,49.51) v2(11.25,27.96) v2(11.37,68.38) v2(11.41,64.3) v2(11.35,48.03) v2(11.39,40.63) v2(11.39,33.91) v2(11.35,25.6) v2(11.36,25.11) v2(11.41,14.98) v2(11.4,13.75) v2(11.53,69.33) v2(11.44,66.63) v2(11.53,63.69) v2(11.48,37.46) v2(11.54,35.79) v2(11.49,32.91) v2(11.49,32.13) v2(11.47,31.05) v2(11.47,30.42) v2(11.52,23.39) v2(11.53,22.87) v2(11.46,18.27) v2(11.46,17.2) v2(11.45,16.39) v2(11.59,66.3) v2(11.63,29.81) v2(11.58,27.51) v2(11.65,19.15) v2(11.73,13.65) v2(11.83,59.67) v2(11.83,59.49) v2(11.84,58.22) v2(11.84,58.03) v2(11.8,49.69) v2(11.84,41.08) v2(11.75,29.23) v2(11.78,17.85) v2(11.87,68.38) v2(11.93,62.62) v2(11.9,53.12) v2(12,36.44) v2(12,35.44) v2(11.95,28.38) v2(12,27.42) v2(11.96,21.59) v2(11.96,14.47) v2(12.07,18.01) v2(12.09,13.4) v2(12.09,13.01) v2(12.08,10.95) v2(12.06,10.45) v2(12.16,46.09) v2(12.21,42.37) v2(12.17,39.61) v2(12.16,17.01) v2(12.26,50.92) v2(12.25,44.14) v2(12.34,14.47) v2(12.32,13.2) v2(12.36,66.63) v2(12.39,64.03) v2(12.35,59.57) v2(12.4,57.27) v2(12.43,38.29) v2(12.37,15.02) v2(12.42,11.08) v2(12.42,10.54) v2(12.46,62.85) v2(12.52,34.25) v2(12.54,33.54) v2(12.48,18.17) v2(12.49,17.21) v2(12.44,11.6) v2(12.49,9.98) v2(12.56,58.38) v2(12.55,34.94) v2(12.63,33.09) v2(12.63,32.71) v2(12.6,31.98) v2(12.6,31.35) v2(12.62,26.03) v2(12.63,25.66) v2(12.56,19.71) v2(12.63,14.39) v2(12.73,65.29) v2(12.73,64.3) v2(12.66,40.18) v2(12.73,37.27) v2(12.68,35.37) v2(12.73,33.98) v2(12.71,30.66) v2(12.67,21.72) v2(12.68,20.26) v2(12.66,14.01) v2(12.86,48.24) v2(12.88,46.41) v2(12.86,44.35) v2(12.86,38.55) v2(12.92,37.47) v2(12.89,29.57) v2(13.03,68.44) v2(12.98,65.78) v2(13,61.17) v2(12.95,50.2) v2(12.97,49.47) v2(12.94,20.52) v2(13.09,41.08) v2(13.09,35.72) v2(13.12,30.63) v2(13.07,22.57) v2(13.05,13.96) v2(13.09,13.25) v2(13.11,12.8) v2(13.18,63.03) v2(13.15,40.47) v2(13.23,39.27) v2(13.2,28.75) v2(13.22,14.85) v2(13.16,14.59) v2(13.19,12.55) v2(13.15,12.25) v2(13.24,59.16) v2(13.33,37.83) v2(13.33,32.5) v2(13.27,31.19) v2(13.24,29.9) v2(13.29,28.13) v2(13.3,27.42) v2(13.34,17.26) v2(13.43,56.61) v2(13.4,35.46) v2(13.36,26.56) v2(13.47,53.76) v2(13.54,37.28) v2(13.52,27.74) v2(13.44,23.59) v2(13.53,21.82) v2(13.51,9.98) v2(13.63,64.3) v2(13.58,53.32) v2(13.55,36.72) v2(13.56,24.65) v2(13.56,24.46) v2(13.64,23.59) v2(13.55,19.01) v2(13.58,15.38) v2(13.67,66.64) v2(13.68,60.76) v2(13.68,55.42) v2(13.68,54.91) v2(13.68,54.19) v2(13.69,46.24) v2(13.67,44.1) v2(13.65,42.38) v2(13.71,18.27) v2(13.77,58.83) v2(13.8,53.8) v2(13.76,39.73) v2(13.81,25.89) v2(13.93,37.82) v2(13.86,37.24) v2(13.91,28.37) v2(13.88,14.6) v2(13.85,13.43) v2(13.86,13.16) v2(13.85,12.86) v2(13.87,12.38) v2(13.96,65.79) v2(14.04,64.04) v2(13.97,55.97) v2(13.95,50.69) v2(14.03,34.64) v2(13.97,30.9) v2(13.97,30.4) v2(14.01,30.06) v2(14.01,29.49) v2(13.98,26.67) v2(14.04,24.74) v2(14.13,68.75) v2(14.08,65.29) v2(14.05,58.81) v2(14.21,57.49) v2(14.21,40.17) v2(14.22,35.73) v2(14.19,29.12) v2(14.17,15.23) v2(14.34,55.97) v2(14.3,50.5) v2(14.31,38.6) v2(14.28,32.19) v2(14.27,25.17) v2(14.26,24.25) v2(14.38,55.38) v2(14.42,12.4) v2(14.4,9.98) v2(14.41,9.06) v2(14.54,66.64) v2(14.52,53.33) v2(14.44,49.49) v2(14.44,37.84) v2(14.53,32.44) v2(14.52,31.68) v2(14.46,14.8) v2(14.53,11.67) v2(14.47,10.75) v2(14.55,64.32) v2(14.59,47.08) v2(14.62,37.24) v2(14.58,8.15) v2(14.65,63.03) v2(14.73,39.75) v2(14.65,38.6) v2(14.66,36.58) v2(14.69,29.88) v2(14.68,28.94) v2(14.7,17.15) v2(14.67,11.24) v2(14.71,9.98) v2(14.77,68.74) v2(14.8,55.98) v2(14.78,41.08) v2(14.84,35.43) v2(14.78,32.68) v2(14.74,29.23) v2(14.81,22.46) v2(14.81,20.64) v2(14.74,20.09) v2(14.74,18.87) v2(14.86,45.15) v2(14.9,40.18) v2(14.85,39.21) v2(14.86,38.25) v2(14.86,34.74) v2(14.93,18.01) v2(14.93,15.72) v2(14.92,14.18) v2(14.91,8.69) v2(15.02,69.13) v2(14.97,66.27) v2(15.02,62.43) v2(14.95,43.82) v2(15.02,38.5) v2(15.03,32.44) v2(15.01,27.08) v2(15.01,25.95) v2(15.03,24.97) v2(15.03,24.22) v2(15.03,23.37) v2(14.96,16.55) v2(15.04,12.58) v2(15.11,53.33) v2(15.05,37.66) v2(15.13,30.04) v2(15.12,28.92) v2(15.11,27.98) v2(15.11,21.88) v2(15.07,20.06) v2(15.12,10.8) v2(15.18,58.34) v2(15.18,31.83) v2(15.18,11.88) v2(15.17,11.26) v2(15.3,63.6) v2(15.28,61.07) v2(15.3,57.67) v2(15.33,38.76) v2(15.33,37.48) v2(15.33,35.73) v2(15.34,34.74) v2(15.28,32.68) v2(15.31,32.22) v2(15.29,16.36) v2(15.29,15.81) v2(15.29,15.35) v2(15.38,65.79) v2(15.35,39.77) v2(15.4,37.75) v2(15.37,18.93) v2(15.41,8.15) v2(15.5,68.13) v2(15.49,57.67) v2(15.53,50.08) v2(15.53,49.49) v2(15.51,49) v2(15.52,32.94) v2(15.51,26.51) v2(15.45,26.08) v2(15.47,23) v2(15.45,17.76) v2(15.44,17.35) v2(15.57,53.64) v2(15.6,44.17) v2(15.56,42.37) v2(15.6,40.01) v2(15.62,37.99) v2(15.6,26.84) v2(15.61,24.35) v2(15.56,14.06) v2(15.7,56.26) v2(15.72,32.19) v2(15.72,31.84) v2(15.7,31.41) v2(15.73,29.67) v2(15.7,27.09) v2(15.71,23.74) v2(15.71,23.42) v2(15.68,12.63) v2(15.74,43.34) v2(15.8,38.28) v2(15.78,35.38) v2(15.78,28.38) v2(15.78,27.98) v2(15.82,25.31) v2(15.79,10.71) v2(15.93,51.35) v2(15.93,51.17) v2(15.91,49.5) v2(15.86,40.31) v2(15.86,38.76) v2(15.86,30.93) v2(15.97,38.54) v2(15.95,37.54) v2(16.11,53.62) v2(16.05,52.34) v2(16.09,39.35) v2(16.09,39.08) v2(16.09,38.84) v2(16.04,36.58) v2(16.05,24.99) v2(16.11,13.99) v2(16.23,67.53) v2(16.19,66.59) v2(16.2,66.02) v2(16.22,65.12) v2(16.15,64.8) v2(16.14,41.23) v2(16.2,39.83) v2(16.21,39.59) v2(16.21,35.72) v2(16.14,34.48) v2(16.14,23.86) v2(16.18,23.39) v2(16.18,22.96) v2(16.23,22.4) v2(16.28,63.92) v2(16.33,50.07) v2(16.31,29.95) v2(16.26,28.79) v2(16.42,38.76) v2(16.39,17.04) v2(16.38,16.3) v2(16.39,15.89) v2(16.4,15.46) v2(16.39,14.99) v2(16.4,11.21) v2(16.39,10.7) v2(16.44,58.37) v2(16.54,55.9) v2(16.44,27.07) v2(16.48,17.73) v2(16.51,8.16) v2(16.57,67.77) v2(16.62,60.35) v2(16.59,55.06) v2(16.6,49.02) v2(16.6,37.48) v2(16.62,35.39) v2(16.6,27.98) v2(16.6,23.58) v2(16.59,21.65) v2(16.68,63.08) v2(16.69,40.44) v2(16.71,32.24) v2(16.72,31.86) v2(16.72,31.06) v2(16.66,20.11) v2(16.66,10.25) v2(16.81,38.76) v2(16.81,34) v2(16.8,19.6) v2(16.75,12.15) v2(16.75,11.65) v2(16.78,8.8) v2(16.92,58.73) v2(16.87,23.05) v2(16.88,20.6) v2(16.86,11.07) v2(16.96,69.31) v2(16.98,49.5) v2(16.95,46.41) v2(16.97,32.63) v2(16.95,13.21) v2(17.13,27.98) v2(17.13,26.8) v2(17.09,26.46) v2(17.11,25.75) v2(17.05,18.75) v2(17.2,38.76) v2(17.14,28.38) v2(17.18,24.87) v2(17.18,24.03) v2(17.22,20.09) v2(17.15,15.16) v2(17.18,8.45) v2(17.3,68.11) v2(17.32,37.53) v2(17.29,9.45) v2(17.4,63.21) v2(17.43,39.85) v2(17.36,34.61) v2(17.36,34.43) v2(17.37,17.78) v2(17.51,63.9) v2(17.53,35.39) v2(17.5,32.09) v2(17.54,20.41) v2(17.5,18.37) v2(17.5,17.01) v2(17.49,16.12) v2(17.49,15.74) v2(17.49,15.34) v2(17.49,14.97) v2(17.46,12.97) v2(17.5,12.75) v2(17.46,11.86) v2(17.46,10.88) v2(17.58,66.1) v2(17.58,65.32) v2(17.58,52.99) v2(17.61,51.96) v2(17.59,39.67) v2(17.57,38.57) v2(17.57,38.39) v2(17.59,36.58) v2(17.62,27.49) v2(17.61,26.84) v2(17.64,26) v2(17.61,24.38) v2(17.66,38) v2(17.66,31.64) v2(17.69,28.71) v2(17.75,38.57) v2(17.75,38.39) v2(17.75,30.9) v2(17.78,23.07) v2(17.83,22.41) v2(17.75,10.05) v2(17.92,67.56) v2(17.91,49.5) v2(17.91,13.27) v2(18.01,59.43) v2(18,39.72) v2(18.01,38.02) v2(17.99,35.71) v2(18.03,31.42) v2(17.97,29.22) v2(18.04,24.7) v2(18.04,24.22) v2(18.01,15.35) v2(18.06,64.87) v2(18.07,60.13) v2(18.06,25.79) v2(18.05,25.33) v2(18.08,23.26) v2(18.07,21.29) v2(18.13,16.83) v2(18.18,66.86) v2(18.23,55.23) v2(18.18,41.51) v2(18.17,40.44) v2(18.15,39.29) v2(18.15,38.81) v2(18.16,38.41) v2(18.23,37.25) v2(18.22,28.28) v2(18.2,27.04) v2(18.21,26.31) v2(18.18,19.8) v2(18.22,19.3) v2(18.16,11.79) v2(18.24,63.61) v2(18.26,62.36) v2(18.27,61.6) v2(18.31,28.78) v2(18.26,25.52) v2(18.29,20.94) v2(18.24,20.43) v2(18.32,18.93) v2(18.24,18.43) v2(18.24,17.43) v2(18.29,14.55) v2(18.27,10.47) v2(18.39,23.24) v2(18.45,63.31) v2(18.49,56.01) v2(18.46,36.73) v2(18.48,25.53) v2(18.47,24.95) v2(18.48,24.24) v2(18.49,22.24) v2(18.46,12.8) v2(18.49,12.07) v2(18.62,51.33) v2(18.54,28.3) v2(18.64,27.88) v2(18.55,27.45) v2(18.6,14.97) v2(18.67,69.12) v2(18.72,57.74) v2(18.68,42.37) v2(18.69,40.01) v2(18.66,31.21) v2(18.73,20.58) v2(18.73,16.72) v2(18.77,55.7) v2(18.76,49.49) v2(18.75,29.39) v2(18.83,19.84) v2(18.79,17.62) v2(18.78,16.24) v2(18.83,10.46) v2(18.93,59.04) v2(18.88,37.55) v2(18.85,28.56) v2(18.91,27.46) v2(18.87,26.26) v2(18.85,20.98) v2(19.01,60.97) v2(19.01,60.79) v2(19.01,60.61) v2(18.97,35.38) v2(19.01,27.08) v2(19.02,21.73) v2(18.94,16.75) v2(19.02,12.85) v2(18.99,11.29) v2(19.09,64.31) v2(19.06,29.78) v2(19.06,29.01) v2(19.12,25.17) v2(19.13,24.55) v2(19.13,11.81) v2(19.22,58.15) v2(19.19,52.25) v2(19.14,51.67) v2(19.24,40.04) v2(19.16,32.86) v2(19.2,31.35) v2(19.14,30.17) v2(19.2,26.05) v2(19.2,18.32) v2(19.28,56.71) v2(19.26,49.4) v2(19.29,48.6) v2(19.25,38.15) v2(19.3,27.46) v2(19.31,26.69) v2(19.34,25.31) v2(19.28,18.56) v2(19.43,37.19) v2(19.35,32.07) v2(19.35,16.25) v2(19.51,61.01) v2(19.52,59.87) v2(19.44,47.11) v2(19.45,29.78) v2(19.45,29.01) v2(19.46,26.37) v2(19.44,22.25) v2(19.6,68.72) v2(19.59,29.39) v2(19.63,25.76) v2(19.54,23.41) v2(19.54,21.26) v2(19.59,20.48) v2(19.7,57.66) v2(19.7,50.94) v2(19.7,31.34) v2(19.69,27.79) v2(19.66,27.43) v2(19.69,26.69) v2(19.71,24.83) v2(19.69,12.04) v2(19.67,10.74) v2(19.84,66.91) v2(19.77,35.43) v2(19.75,24.02) v2(19.79,21.75) v2(19.82,17.23) v2(19.84,10.48) v2(19.89,32.98) v2(19.84,29.01) v2(19.85,15.62) v2(19.86,14.9) v2(19.86,13) v2(19.98,24.42) v2(20.08,35.86) v2(20.08,34.19) v2(20.06,32.07) v2(20.06,30.19) v2(20.08,29.87) v2(20.04,23.37) v2(20.19,57.18) v2(20.21,56.72) v2(20.24,24.13) v2(20.19,18.02) v2(20.21,16.57) v2(20.21,11.6) v2(20.19,10.76) v2(20.25,48.59) v2(20.3,29.57) v2(20.28,14.91) v2(20.38,52.89) v2(20.36,22.26) v2(20.46,57.46) v2(20.5,47.54) v2(20.44,26.6) v2(20.52,23.91) v2(20.5,20.73) v2(20.53,17.65) v2(20.61,63.12) v2(20.56,62.13) v2(20.55,60.71) v2(20.6,53.81) v2(20.56,33.39) v2(20.57,31.3) v2(20.6,28.94) v2(20.54,28.22) v2(20.58,24.93) v2(20.58,23.25) v2(20.54,18.59) v2(20.62,17.23) v2(20.61,11.82) v2(20.63,10.49) v2(20.69,57.17) v2(20.71,56.72) v2(20.68,36.4) v2(20.65,27.35) v2(20.73,19.49) v2(20.72,18.18) v2(20.7,16.24) v2(20.76,57.69) v2(20.84,40.04) v2(20.82,29.58) v2(20.79,21.75) v2(20.84,20.7) v2(20.84,12.92) v2(20.93,56.95) v2(20.86,24.61) v2(20.84,20.51) v2(20.99,57.49) v2(20.95,56.47) v2(21.01,32.89) v2(21.03,32.09) v2(20.94,23.9) v2(21.01,19.91) v2(20.95,17.66) v2(21.05,63.1) v2(21.1,60.53) v2(21.11,29.12) v2(21.09,28.7) v2(21.13,24.52) v2(21.09,14.91) v2(21.1,10.47) v2(21.15,68.69) v2(21.23,57.24) v2(21.16,49.29) v2(21.21,48.88) v2(21.21,41.51) v2(21.17,34.36) v2(21.15,26.35) v2(21.23,24.29) v2(21.26,66.53) v2(21.26,48.28) v2(21.26,25.49) v2(21.33,22.26) v2(21.29,18.17) v2(21.24,16.95) v2(21.24,14.16) v2(21.41,32.5) v2(21.42,24.57) v2(21.5,50.11) v2(21.52,26.56) v2(21.44,23.86) v2(21.51,19.07) v2(21.61,63.12) v2(21.63,43.35) v2(21.63,37.09) v2(21.54,31.33) v2(21.57,29.61) v2(21.54,29.12) v2(21.56,28.68) v2(21.58,23.25) v2(21.63,21.52) v2(21.57,10.98) v2(21.57,10.44) v2(21.66,59.85) v2(21.67,44.17) v2(21.7,24.67) v2(21.67,23.75) v2(21.64,17.48) v2(21.65,10.08) v2(21.8,61.73) v2(21.8,61.55) v2(21.77,53.02) v2(21.8,52.31) v2(21.81,47.84) v2(21.84,40.04) v2(21.84,32.05) v2(21.92,23.25) v2(21.98,61.73) v2(21.98,61.55) v2(21.95,48.93) v2(22.02,48.18) v2(22.02,15.62) v2(22.05,50.53) v2(22.05,29.13) v2(22.04,14.91) v2(22.19,58.7) v2(22.23,55.27) v2(22.17,53.69) v2(22.16,47.5) v2(22.17,42.39) v2(22.14,40.6) v2(22.19,31.65) v2(22.23,31.12) v2(22.15,30.14) v2(22.15,9.63) v2(22.3,46.3) v2(22.26,28.69) v2(22.34,28.24) v2(22.28,19.45) v2(22.25,13.38) v2(22.27,12.83) v2(22.39,67.65) v2(22.39,58.74) v2(22.42,47.84) v2(22.42,47.23) v2(22.38,27.34) v2(22.37,26.55) v2(22.39,26.23) v2(22.36,24.29) v2(22.43,23.64) v2(22.43,23.24) v2(22.44,58.95) v2(22.45,57.41) v2(22.44,55.98) v2(22.48,55.02) v2(22.45,48.94) v2(22.45,30.84) v2(22.52,29.55) v2(22.45,24.73) v2(22.48,22.25) v2(22.44,14.17) v2(22.52,11.67) v2(22.63,48.59) v2(22.54,34.67) v2(22.55,11.26) v2(22.67,53.69) v2(22.73,31.61) v2(22.68,25.87) v2(22.66,21.09) v2(22.81,42.34) v2(22.84,40.04) v2(22.75,27.75) v2(22.76,27.34) v2(22.76,26.55) v2(22.78,17.83) v2(22.85,68.69) v2(22.91,63.09) v2(22.91,60.61) v2(22.87,52.38) v2(22.88,50.98) v2(22.9,48.06) v2(22.93,23.25) v2(22.85,12.82) v2(22.99,47.73) v2(22.98,31.36) v2(23.03,29.65) v2(23.03,26.25) v2(22.97,14.17) v2(23.04,29.01) v2(23.13,21.55) v2(23.04,14.91) v2(23.22,31.61) v2(23.16,27.84) v2(23.16,26.55) v2(23.18,23.73) v2(23.25,25.21) v2(23.32,9.61) v2(23.43,63.37) v2(23.43,62.52) v2(23.38,23.33) v2(23.53,60.02) v2(23.51,52.38) v2(23.47,32.35) v2(23.47,31.36) v2(23.48,28.45) v2(23.48,27.95) v2(23.47,27.19) v2(23.49,26.56) v2(23.47,21.11) v2(23.47,20.69) v2(23.53,16.96) v2(23.46,16.39) v2(23.45,14.17) v2(23.46,13.39) v2(23.6,51.78) v2(23.56,50.97) v2(23.62,48.55) v2(23.62,47.95) v2(23.63,24.4) v2(23.61,19.76) v2(23.67,29.9) v2(23.65,29.41) v2(23.66,25.82) v2(23.71,23.71) v2(23.76,36.03) v2(23.88,60.36) v2(23.91,48.37) v2(23.87,35.38) v2(23.86,34.66) v2(23.86,27.24) v2(23.93,23.43) v2(23.93,23.24) v2(23.97,59.57) v2(24.01,54.06) v2(24.01,50.97) v2(23.97,31.86) v2(23.97,31.36) v2(23.94,28.92) v2(23.95,28.47) v2(23.97,27.98) v2(24.01,25.35) v2(24.1,61.66) v2(24.05,58.77) v2(24.07,57.38) v2(24.09,56.84) v2(24.12,47.73) v2(24.11,47.43) v2(24.07,29.99) v2(24.1,26.56) v2(24.04,17.98) v2(24.1,14.72) v2(24.15,63.21) v2(24.17,31.62) v2(24.16,29.41) v2(24.14,11.94) v2(24.31,64.24) v2(24.32,53.64) v2(24.31,35.74) v2(24.31,9.62) v2(24.4,41.1) v2(24.41,25.3) v2(24.42,24.29) v2(24.42,23.37) v2(24.49,35.05) v2(24.45,28.91) v2(24.44,28.47) v2(24.45,27.98) v2(24.52,27.03) v2(24.49,14.15) v2(24.63,68.7) v2(24.6,38.28) v2(24.71,55.06) v2(24.67,54.33) v2(24.72,52.82) v2(24.71,37.7) v2(24.71,33.59) v2(24.71,33.1) v2(24.68,29.42) v2(24.73,27.5) v2(24.73,26.58) v2(24.65,25.83) v2(24.66,13.38) v2(24.84,61.78) v2(24.77,49.1) v2(24.93,30.5) v2(24.85,15.7) v2(24.95,63.35) v2(24.96,33.84) v2(24.96,32.85) v2(25.01,31.36) v2(24.97,29.53) v2(24.97,28.47) v2(25.03,26.13) v2(24.99,20.92) v2(25,14.15) v2(24.94,9.61) v2(25.05,45.55) v2(25.05,28.96) v2(25.12,23.28) v2(25.11,20.01) v2(25.13,19.21) v2(25.18,64.97) v2(25.16,47.5) v2(25.17,41.61) v2(25.23,40.28) v2(25.2,33.1) v2(25.15,29.77) v2(25.22,24.59) v2(25.21,23.62) v2(25.26,57.36) v2(25.28,55.55) v2(25.33,28.52) v2(25.26,28.08) v2(25.29,22.23) v2(25.25,21.46) v2(25.34,19.97) v2(25.34,14.72) v2(25.27,10.07) v2(25.38,26.87) v2(25.4,10.19) v2(25.52,62.75) v2(25.45,52.13) v2(25.45,50.94) v2(25.48,29.53) v2(25.56,42.17) v2(25.6,26.53) v2(25.55,25.7) v2(25.56,25.43) v2(25.54,25.19) v2(25.55,21.85) v2(25.68,37.9) v2(25.69,35.83) v2(25.72,29.05) v2(25.71,27.36) v2(25.71,26.98) v2(25.67,24.5) v2(25.72,12.78) v2(25.79,29.88) v2(25.82,28.51) v2(25.83,15.76) v2(25.85,64.93) v2(25.9,63.2) v2(25.88,58.56) v2(25.87,39.74) v2(25.92,31.89) v2(25.85,23.39) v2(25.86,19.38) v2(25.97,57.55) v2(26.03,55.77) v2(25.99,31.34) v2(26.03,24.16) v2(25.96,20.53) v2(26.07,63.98) v2(26.06,36.8) v2(26.09,36.28) v2(26.08,29.06) v2(26.09,22.8) v2(26.09,14.19) v2(26.16,47.5) v2(26.23,46.47) v2(26.24,34.98) v2(26.23,26.62) v2(26.24,22.38) v2(26.15,9.64) v2(26.34,39.23) v2(26.32,15.05) v2(26.36,49.43) v2(26.4,44.17) v2(26.39,35.81) v2(26.4,31.37) v2(26.38,29.75) v2(26.36,28.52) v2(26.43,13.12) v2(26.47,68.7) v2(26.44,33.34) v2(26.49,31.87) v2(26.52,26.92) v2(26.47,18.57) v2(26.63,47.2) v2(26.57,42.27) v2(26.6,25.73) v2(26.58,25.09) v2(26.57,23.4) v2(26.54,22.18) v2(26.65,63.35) v2(26.74,51.83) v2(26.69,34.09) v2(26.69,33.1) v2(26.7,30.62) v2(26.68,30.07) v2(26.69,24.07) v2(26.69,21.91) v2(26.67,19.92) v2(26.71,19.2) v2(26.79,31.02) v2(26.77,28.79) v2(26.76,27.52) v2(26.75,26.35) v2(26.75,24.36) v2(26.77,23.9) v2(26.79,17.18) v2(26.82,12.32) v2(26.9,63.3) v2(26.86,54.68) v2(26.93,53.94) v2(26.86,39.72) v2(26.87,36.53) v2(26.87,18.43) v2(26.92,16.45) v2(26.88,15.96) v2(27,21.12) v2(27.03,11.34) v2(27.04,26.91) v2(27.13,22.49) v2(27.06,21.96) v2(27.1,19.39) v2(27.22,52.21) v2(27.2,40.53) v2(27.18,33.59) v2(27.16,29.59) v2(27.21,28.05) v2(27.17,20.05) v2(27.15,15.42) v2(27.18,14.91) v2(27.19,14.3) v2(27.19,13.64) v2(27.17,12.98) v2(27.33,67.24) v2(27.3,57.34) v2(27.3,29.07) v2(27.26,26.51) v2(27.3,26.15) v2(27.31,24.4) v2(27.29,23.38) v2(27.36,41.99) v2(27.34,39.23) v2(27.4,35.98) v2(27.34,30.15) v2(27.35,27.23) v2(27.43,24.82) v2(27.37,17.97) v2(27.36,9.64) v2(27.52,47.69) v2(27.5,46.55) v2(27.5,28.56) v2(27.56,63.7) v2(27.56,62.83) v2(27.63,58.61) v2(27.59,51.69) v2(27.62,49.88) v2(27.63,38.21) v2(27.61,35.07) v2(27.56,24.15) v2(27.57,22.24) v2(27.54,21.88) v2(27.63,20.35) v2(27.61,17.88) v2(27.73,43.78) v2(27.68,34.64) v2(27.69,31.12) v2(27.71,25.62) v2(27.73,23.93) v2(27.73,16.76) v2(27.7,13.25) v2(27.65,12.45) v2(27.8,64.53) v2(27.76,27.36) v2(27.76,24.39) v2(27.79,23.38) v2(27.76,22.24) v2(27.78,16.05) v2(27.83,12.86) v2(27.85,67.91) v2(27.9,37.6) v2(27.85,30.43) v2(27.93,26.4) v2(27.92,11.22) v2(27.96,63.68) v2(27.97,63.36) v2(27.95,32.18) v2(27.98,24.62) v2(28.09,40.84) v2(28.1,28.06) v2(28.04,26.99) v2(28.04,21.88) v2(28.08,18.85) v2(28.12,18.26) v2(28.07,15.27) v2(28.09,14.48) v2(28.09,13.75) v2(28.06,13.29) v2(28.16,62.6) v2(28.15,56.89) v2(28.19,46.29) v2(28.21,35.06) v2(28.22,28.97) v2(28.2,25.62) v2(28.24,23.43) v2(28.21,22.52) v2(28.19,20.97) v2(28.24,17.04) v2(28.32,68.7) v2(28.27,56.4) v2(28.32,30.72) v2(28.28,23.92) v2(28.29,21.88) v2(28.25,16.41) v2(28.41,51.74) v2(28.4,31.88) v2(28.4,29.74) v2(28.34,24.89) v2(28.36,18.97) v2(28.39,14.24) v2(28.39,14.02) v2(28.39,12.93) v2(28.39,12.72) v2(28.36,12.03) v2(28.37,9.35) v2(28.49,19.22) v2(28.5,15.54) v2(28.6,54.86) v2(28.57,32.84) v2(28.63,31.22) v2(28.63,26.55) v2(28.63,26.09) v2(28.54,22.13) v2(28.63,21.87) v2(28.69,62.32) v2(28.65,25.67) v2(28.69,23.38) v2(28.75,67.96) v2(28.78,54.67) v2(28.79,22.38) v2(28.82,21.62) v2(28.76,14.91) v2(28.83,14.23) v2(28.83,14.02) v2(28.82,12.93) v2(28.83,12.72) v2(28.78,10.8) v2(28.86,39.43) v2(28.91,33.16) v2(28.85,32.26) v2(28.87,30.23) v2(28.88,28.17) v2(28.84,27.63) v2(28.88,24.7) v2(28.84,23.78) v2(28.94,17.82) v2(28.85,10.3) v2(29.02,67.52) v2(29.01,16.88) v2(29.01,16.43) v2(28.96,11.76) v2(29.02,8.28) v2(29.01,7.11) v2(28.95,4.78) v2(28.97,3.76) v2(28.97,2.65) v2(28.97,1.41) v2(29.11,65.82) v2(29.05,56.27) v2(29.07,54.32) v2(29.11,47.43) v2(29.12,41.74) v2(29.13,31.75) v2(29.05,29.47) v2(29.07,26.99) v2(29.12,25.66) v2(29.04,22.63) v2(29.12,13.46) v2(29.23,26.52) v2(29.21,24.7) v2(29.16,24.03) v2(29.17,14.21) v2(29.23,11.87) v2(29.26,60.02) v2(29.26,59.62) v2(29.26,58.72) v2(29.26,58.32) v2(29.28,40.3) v2(29.32,20.99) v2(29.28,19.45) v2(29.32,12.6) v2(29.42,63.82) v2(29.35,62.65) v2(29.4,29.91) v2(29.38,29.22) v2(29.37,28.12) v2(29.35,14.27) v2(29.38,13.08) v2(29.42,10.8) v2(29.45,56.27) v2(29.47,55.53) v2(29.49,54.86) v2(29.49,54.32) v2(29.51,36.6) v2(29.48,32.77) v2(29.45,27.55) v2(29.47,15.39) v2(29.56,37.51) v2(29.62,33.86) v2(29.63,32.21) v2(29.59,27.88) v2(29.62,24.21) v2(29.63,23.34) v2(29.63,22.23) v2(29.55,16.88) v2(29.54,16.11) v2(29.58,15.74) v2(29.57,11.43) v2(29.56,10.07) v2(29.66,67.91) v2(29.68,61.74) v2(29.69,47.44) v2(29.7,41.54) v2(29.69,35.98) v2(29.69,34.98) v2(29.74,24.72) v2(29.74,22.59) v2(29.74,16.17) v2(29.67,13.58) v2(29.67,13.37) v2(29.74,3.78) v2(29.75,64.83) v2(29.76,39.81) v2(29.77,38.54) v2(29.75,30.68) v2(29.8,25.55) v2(29.8,14.53) v2(29.75,0.32) v2(29.93,61.11) v2(29.87,34.23) v2(29.92,31.58) v2(29.91,28.43) v2(29.89,27.79) v2(29.94,16.39) v2(29.92,15.08) v2(29.94,12.23) v2(29.99,54.3) v2(30.02,51.75) v2(29.97,46.8) v2(29.95,30.89) v2(30.03,15.88) v2(30.13,32.65) v2(30.09,26.17) v2(30.08,25.34) v2(30.09,24.59) v2(30.1,22.06) v2(30.06,20.21) v2(30.04,17.26) v2(30.1,13.58) v2(30.11,13.37) v2(30.17,68.7) v2(30.21,63.02) v2(30.17,62.41) v2(30.2,54.61) v2(30.22,50.76) v2(30.22,48.86) v2(30.2,36.03) v2(30.24,35.48) v2(30.24,34.63) v2(30.19,33.04) v2(30.19,26.38) v2(30.21,25.86) v2(30.28,30.4) v2(30.29,15.68) v2(30.26,11.64) v2(30.38,28.19) v2(30.36,27.65) v2(30.41,22.6) v2(30.44,15.29) v2(30.39,14.3) v2(30.39,13.83) v2(30.39,12.93) v2(30.38,12.46) v2(30.5,61.5) v2(30.49,53.97) v2(30.48,47.34) v2(30.48,43.63) v2(30.47,39) v2(30.51,26.96) v2(30.57,67.91) v2(30.59,51.57) v2(30.62,40.76) v2(30.55,36.52) v2(30.59,33.98) v2(30.58,30.53) v2(30.55,24.16) v2(30.62,23.5) v2(30.57,21.54) v2(30.64,18.56) v2(30.62,17.13) v2(30.6,0.86) v2(30.73,47.81) v2(30.69,33.48) v2(30.69,28.8) v2(30.65,20.87) v2(30.71,20.29) v2(30.65,19.79) v2(30.65,17.65) v2(30.72,13.72) v2(30.7,12.36) v2(30.8,32.68) v2(30.81,31.04) v2(30.8,29.93) v2(30.82,23.5) v2(30.82,14.52) v2(30.94,63.42) v2(30.92,36.27) v2(30.84,26.07) v2(30.94,20.79) v2(30.86,15.09) v2(30.92,11.94) v2(30.99,62.65) v2(30.97,60.91) v2(31.02,50.3) v2(31,34.98) v2(31.11,46.67) v2(31.12,41.74) v2(31.12,38.36) v2(31.09,37.2) v2(31.12,34.41) v2(31.09,24.78) v2(31.08,24.16) v2(31.12,20.5) v2(31.13,19.47) v2(31.13,18.96) v2(31.13,15.88) v2(31.1,5.01) v2(31.08,4.32) v2(31.1,3.63) v2(31.1,2.96) v2(31.11,2.22) v2(31.23,51.54) v2(31.19,51.29) v2(31.17,39.25) v2(31.14,29.68) v2(31.23,28.09) v2(31.19,26.53) v2(31.21,21.61) v2(31.21,20.92) v2(31.14,20.15) v2(31.14,18.32) v2(31.14,17.64) v2(31.15,16.97) v2(31.23,12.46) v2(31.2,6.9) v2(31.2,6.68) v2(31.24,62.12) v2(31.24,61.72) v2(31.29,60.56) v2(31.24,59.89) v2(31.27,51.02) v2(31.24,48.06) v2(31.24,33.38) v2(31.29,31.54) v2(31.29,23.51) v2(31.24,22.19) v2(31.27,19.89) v2(31.28,13.72) v2(31.31,12.93) v2(31.42,66.39) v2(31.35,65.69) v2(31.37,63.88) v2(31.37,43.89) v2(31.38,43.44) v2(31.35,32.75) v2(31.38,27.59) v2(31.34,19.63) v2(31.4,19.21) v2(31.41,15.52) v2(31.44,6.64) v2(31.51,68.69) v2(31.54,59.55) v2(31.52,52.17) v2(31.53,40.34) v2(31.5,27.11) v2(31.49,26.19) v2(31.49,25.19) v2(31.49,24.19) v2(31.49,18.58) v2(31.48,17.94) v2(31.49,14.98) v2(31.49,14.23) v2(31.48,8.69) v2(31.52,7.49) v2(31.5,1.16) v2(31.6,67.01) v2(31.56,31.14) v2(31.57,17.35) v2(31.59,16.23) v2(31.63,13.55) v2(31.63,13.29) v2(31.64,6.95) v2(31.7,41.54) v2(31.66,23.76) v2(31.67,23.32) v2(31.73,22.5) v2(31.78,52.25) v2(31.82,46.85) v2(31.81,29.09) v2(31.78,21.79) v2(31.74,19) v2(31.75,18.2) v2(31.78,13.12) v2(31.79,5.04) v2(31.79,3.62) v2(31.79,2.21) v2(31.79,1.45) v2(31.92,60.57) v2(31.88,38.81) v2(31.86,37.61) v2(31.89,36.4) v2(31.88,35.22) v2(31.88,33.66) v2(31.89,32.63) v2(31.91,30.4) v2(31.92,20.91) v2(31.94,19.76) v2(31.93,15.56) v2(31.87,13.85) v2(31.99,52.02) v2(31.99,26.19) v2(32.03,25.05) v2(31.98,19.39) v2(32.02,17.47) v2(32,16.57) v2(31.97,14.56) v2(31.96,14.13) v2(32,13.12) v2(32.1,65.72) v2(32.09,47.83) v2(32.1,28.09) v2(32.09,22.77) v2(32.05,12.5) v2(32.12,8.16) v2(32.07,7.49) v2(32.07,6.99) v2(32.09,1.14) v2(32.17,66.43) v2(32.2,59.94) v2(32.18,39.05) v2(32.19,31.98) v2(32.19,30.98) v2(32.19,29.98) v2(32.22,15.24) v2(32.17,13.85) v2(32.33,60.79) v2(32.26,52.01) v2(32.32,38.93) v2(32.25,28.67) v2(32.27,14.44) v2(32.38,25.45) v2(32.42,17.17) v2(32.37,14.11) v2(32.4,13.12) v2(32.43,5.58) v2(32.41,5.04) v2(32.52,60.11) v2(32.52,53.72) v2(32.5,48.49) v2(32.47,43.24) v2(32.46,38.8) v2(32.51,33.38) v2(32.45,27.6) v2(32.52,27.09) v2(32.49,22.92) v2(32.47,22.54) v2(32.47,22.12) v2(32.47,21.83) v2(32.45,21.46) v2(32.49,18.29) v2(32.48,17.75) v2(32.45,16.79) v2(32.5,15.76) v2(32.48,13.73) v2(32.48,13.45) v2(32.48,8.69) v2(32.45,3.63) v2(32.48,2.06) v2(32.6,67.82) v2(32.64,63.59) v2(32.64,31.53) v2(32.64,30.68) v2(32.64,29.93) v2(32.64,28.69) v2(32.57,26.17) v2(32.57,19.19) v2(32.66,67.04) v2(32.66,65.97) v2(32.7,23.14) v2(32.7,14.11) v2(32.66,12.93) v2(32.8,68.7) v2(32.78,65.03) v2(32.76,63.18) v2(32.75,57.95) v2(32.83,56.99) v2(32.83,52.21) v2(32.83,41.62) v2(32.83,41.44) v2(32.79,39.64) v2(32.8,32.4) v2(32.74,28.3) v2(32.74,25.1) v2(32.77,24.51) v2(32.76,22.27) v2(32.75,20.14) v2(32.8,19.26) v2(32.76,16.69) v2(32.76,16.43) v2(32.79,1.15) v2(32.93,46.45) v2(32.86,34.13) v2(32.87,24.74) v2(32.92,18.38) v2(32.92,17.5) v2(32.91,13.66) v2(32.91,13.39) v2(32.89,12.5) v2(32.97,63.94) v2(33,63.47) v2(33,63.03) v2(32.98,53.76) v2(33,53.28) v2(33,52.7) v2(32.97,52.01) v2(32.97,39.64) v2(33.01,32.98) v2(33.04,26.26) v2(33.01,16.07) v2(33.03,14.11) v2(33.01,2.06) v2(33.12,66.3) v2(33.13,64.18) v2(33.05,56.2) v2(33.05,25.94) v2(33.08,24.74) v2(33.07,24.54) v2(33.08,22.4) v2(33.08,20.95) v2(33.05,20.14) v2(33.07,19.26) v2(33.09,13.11) v2(33.12,3.62) v2(33.09,1.45) v2(33.2,59.94) v2(33.16,28.07) v2(33.16,27.59) v2(33.2,23.15) v2(33.18,16.62) v2(33.19,15.23) v2(33.15,14.35) v2(33.16,13.85) v2(33.33,65.27) v2(33.29,52.47) v2(33.3,47.58) v2(33.25,45.16) v2(33.24,29.1) v2(33.38,38.84) v2(33.38,38.65) v2(33.43,27.1) v2(33.43,17.9) v2(33.42,17.62) v2(33.39,1.14) v2(33.52,53.95) v2(33.49,52.7) v2(33.44,52.04) v2(33.48,51.83) v2(33.51,32.4) v2(33.53,23.17) v2(33.52,22.74) v2(33.44,21.41) v2(33.44,20.2) v2(33.49,18.54) v2(33.44,17.18) v2(33.45,14.49) v2(33.48,13.85) v2(33.51,13.11) v2(33.48,8.69) v2(33.56,31.54) v2(33.61,20.74) v2(33.54,19.57) v2(33.63,14.78) v2(33.61,12.5) v2(33.72,53.68) v2(33.72,41.01) v2(33.65,15.93) v2(33.74,5.78) v2(33.74,5.03) v2(33.73,3.62) v2(33.73,2.21) v2(33.78,52.73) v2(33.83,45.8) v2(33.77,40.03) v2(33.76,37.44) v2(33.79,33.31) v2(33.84,19.23) v2(33.86,67.1) v2(33.94,38.33) v2(33.87,36.83) v2(33.89,34.42) v2(33.94,26.59) v2(33.94,25.27) v2(33.85,22.79) v2(33.89,22.44) v2(33.87,20.37) v2(33.85,19.77) v2(33.92,18.02) v2(33.94,17.61) v2(33.89,12.97) v2(33.88,12.37) v2(33.89,11.84) v2(33.9,11.34) v2(33.92,10.76) v2(33.95,66.26) v2(34.03,62.1) v2(33.98,31.93) v2(34.01,30.98) v2(34.03,28.89) v2(33.96,28.3) v2(33.96,24.57) v2(34,23.55) v2(33.95,21.4) v2(34.01,20.82) v2(34.02,17.18) v2(33.98,13.38) v2(34.1,68.69) v2(34.08,65.64) v2(34.12,64.64) v2(34.1,64.37) v2(34.08,63.94) v2(34.11,63.35) v2(34.1,63.01) v2(34.04,54.48) v2(34.1,19.57) v2(34.09,1.14) v2(34.22,66.52) v2(34.17,65.8) v2(34.17,65.26) v2(34.2,61.87) v2(34.23,60.66) v2(34.18,58.66) v2(34.16,52.52) v2(34.19,29.83) v2(34.22,27.6) v2(34.23,24.06) v2(34.19,23.11) v2(34.17,22.8) v2(34.23,21.57) v2(34.23,21.14) v2(34.16,20.41) v2(34.14,19.23) v2(34.19,18.36) v2(34.17,16.36) v2(34.23,15.93) v2(34.22,15.36) v2(34.19,14.62) v2(34.27,54.24) v2(34.32,53.47) v2(34.3,52.69) v2(34.29,52.18) v2(34.28,50.98) v2(34.33,45.85) v2(34.34,25.43) v2(34.29,12.5) v2(34.42,63.5) v2(34.35,61.72) v2(34.4,59.93) v2(34.4,59.01) v2(34.42,46.38) v2(34.42,32.66) v2(34.4,28.99) v2(34.4,16.37) v2(34.43,11.94) v2(34.4,5.04) v2(34.38,3.63) v2(34.39,2.21) v2(34.39,1.45) v2(34.47,66.18) v2(34.44,60.35) v2(34.5,58.73) v2(34.53,56.25) v2(34.46,55.69) v2(34.52,53.7) v2(34.49,53.29) v2(34.46,36.33) v2(34.45,33.87) v2(34.46,28.07) v2(34.5,27.11) v2(34.54,23.55) v2(34.54,23.12) v2(34.54,22.34) v2(34.52,20.74) v2(34.52,17.93) v2(34.51,17.15) v2(34.44,10.73) v2(34.48,8.69) v2(34.45,7.85) v2(34.45,6.56) v2(34.58,62.11) v2(34.64,61.72) v2(34.59,59.33) v2(34.56,44.55) v2(34.61,21.97) v2(34.57,21.6) v2(34.55,19.98) v2(34.59,19.23) v2(34.55,14.12) v2(34.55,13.38) v2(34.74,63.74) v2(34.71,59.64) v2(34.72,58.94) v2(34.73,58.44) v2(34.7,39.06) v2(34.67,29.62) v2(34.68,25.79) v2(34.65,20.9) v2(34.69,20.38) v2(34.65,18.96) v2(34.69,17.15) v2(34.67,14.36) v2(34.69,1.14) v2(34.77,67.82) v2(34.81,67.03) v2(34.77,65.64) v2(34.83,63.2) v2(34.76,62.72) v2(34.76,53.92) v2(34.78,43.34) v2(34.77,15.92) v2(34.79,15.11) v2(34.79,14.81) v2(34.88,60.27) v2(34.89,54.7) v2(34.91,26.22) v2(34.85,23.66) v2(34.92,23.03) v2(34.89,22.43) v2(34.89,21.96) v2(34.84,19.68) v2(34.86,18.8) v2(34.93,12.92) v2(35.01,66.31) v2(34.99,65.08) v2(34.99,64.62) v2(34.98,63.78) v2(34.97,62.36) v2(34.99,61.68) v2(34.98,54.23) v2(35.02,52.25) v2(34.99,45.32) v2(35,28.08) v2(34.94,22.79) v2(35.02,17.93) v2(35,14.38) v2(34.96,10.74) v2(34.97,10.3) v2(34.97,9.72) v2(34.96,9.19) v2(34.98,5.54) v2(35.08,47.02) v2(35.11,36.21) v2(35.07,29.03) v2(35.05,16.35) v2(35.05,11.94) v2(35.04,5.03) v2(35.04,3.63) v2(35.04,2.21) v2(35.23,59.27) v2(35.17,49.51) v2(35.18,46.45) v2(35.22,41.51) v2(35.2,27.58) v2(35.22,25.91) v2(35.2,23.66) v2(35.18,23.13) v2(35.2,21.61) v2(35.19,20.95) v2(35.17,20.41) v2(35.19,19.97) v2(35.19,19.22) v2(35.18,18.38) v2(35.2,17.29) v2(35.24,15.93) v2(35.19,15.38) v2(35.22,15.02) v2(35.22,14.74) v2(35.26,66.51) v2(35.28,65.98) v2(35.33,58.2) v2(35.27,48.81) v2(35.3,47.27) v2(35.31,45.78) v2(35.26,30.39) v2(35.34,30.06) v2(35.27,29.66) v2(35.33,14.36) v2(35.4,34.08) v2(35.4,33.71) v2(35.37,31.27) v2(35.41,24.57) v2(35.41,13.32) v2(35.39,1.16) v2(35.5,68.69) v2(35.52,62.87) v2(35.53,62.31) v2(35.52,51.3) v2(35.53,50.52) v2(35.5,39.82) v2(35.5,32.3) v2(35.53,25.72) v2(35.54,23.13) v2(35.54,22.26) v2(35.54,21.6) v2(35.51,21.19) v2(35.53,19.56) v2(35.52,17.93) v2(35.54,17.18) v2(35.52,14.57) v2(35.48,8.69) v2(35.58,60.31) v2(35.6,46.87) v2(35.61,35.71) v2(35.59,28.08) v2(35.56,26.59) v2(35.57,22.79) v2(35.57,20.73) v2(35.59,19.98) v2(35.61,18.38) v2(35.58,16.94) v2(35.67,62.51) v2(35.67,62.01) v2(35.66,61.08) v2(35.71,58.33) v2(35.71,43.07) v2(35.72,21.18) v2(35.66,16.56) v2(35.72,15.92) v2(35.66,13.63) v2(35.67,5.04) v2(35.69,1.45) v2(35.75,43.47) v2(35.75,32.81) v2(35.74,27.03) v2(35.8,21.94) v2(35.77,20.42) v2(35.74,3.65) v2(35.81,1.97) v2(35.93,64.38) v2(35.93,63.71) v2(35.85,45.3) v2(35.85,25.1) v2(35.87,23.32) v2(35.9,15.73) v2(35.87,14.62) v2(35.88,11.61) v2(35.98,67.05) v2(35.97,66.16) v2(35.94,64.71) v2(35.98,55.78) v2(36.03,54.17) v2(36.01,34.73) v2(35.94,31.75) v2(35.98,29.62) v2(36,28.95) v2(35.94,18.84) v2(36.02,17.93) v2(35.96,16.92) v2(36,15.39) v2(36.03,13.34) v2(36,1.15) v2(36.06,58.19) v2(36.06,45.78) v2(36.06,36.99) v2(36.05,25.7) v2(36.09,24.58) v2(36.05,22.6) v2(36.08,15) v2(36.1,14.49) v2(36.1,14.06) v2(36.12,11.98) v2(36.05,11.07) v2(36.05,10.36) v2(36.06,9.77) v2(36.05,9.11) v2(36.17,51.51) v2(36.22,41.03) v2(36.19,28.08) v2(36.23,27.58) v2(36.19,23.66) v2(36.22,23.12) v2(36.16,21.57) v2(36.14,20.83) v2(36.23,20.32) v2(36.18,19.57) v2(36.19,19.17) v2(36.19,15.93) v2(36.31,66.52) v2(36.27,49.53) v2(36.24,39.07) v2(36.28,13.48) v2(36.34,10.79) v2(36.28,9.33) v2(36.26,8.43) v2(36.33,5.02) v2(36.34,3.62) v2(36.3,1.97) v2(36.37,48.82) v2(36.4,48.33) v2(36.39,48.15) v2(36.39,47.79) v2(36.4,33.71) v2(36.37,16.35) v2(36.37,13.82) v2(36.4,10.32) v2(36.35,5.79) v2(36.49,65.79) v2(36.46,63.37) v2(36.46,63.03) v2(36.53,58.13) v2(36.45,53.45) v2(36.54,32.93) v2(36.5,32.3) v2(36.5,27.11) v2(36.49,23.55) v2(36.49,20.91) v2(36.49,20.31) v2(36.49,19.79) v2(36.52,17.93) v2(36.49,16.74) v2(36.48,8.69) v2(36.56,65.12) v2(36.57,64.25) v2(36.61,63.71) v2(36.63,58.59) v2(36.59,47.23) v2(36.58,36.47) v2(36.64,31.75) v2(36.61,30.9) v2(36.63,25.91) v2(36.63,25.64) v2(36.57,22.73) v2(36.59,22.18) v2(36.58,19.2) v2(36.58,18.38) v2(36.58,16.43) v2(36.62,15.93) v2(36.59,13.14) v2(36.55,7.46) v2(36.73,39.58) v2(36.66,29.63) v2(36.73,14.98) v2(36.71,14.5) v2(36.72,6.99) v2(36.69,1.14) v2(36.83,64.77) v2(36.74,40.6) v2(36.74,40.09) v2(36.74,37.38) v2(36.76,30.11) v2(36.75,28.89) v2(36.78,28.08) v2(36.83,24.03) v2(36.9,68.69) v2(36.87,67.82) v2(36.93,66.03) v2(36.86,35.61) v2(36.89,23.13) v2(36.84,20.05) v2(36.87,15.73) v2(36.99,64.04) v2(37,51.79) v2(36.98,38.38) v2(37.04,25.11) v2(36.98,22.26) v2(36.99,21.61) v2(36.99,20.75) v2(36.95,18.84) v2(37.02,17.93) v2(37.02,13.76) v2(36.97,12.31) v2(36.97,11.31) v2(36.95,6.53) v2(36.98,5.04) v2(37,3.62) v2(37.03,2.21) v2(36.99,1.45) v2(37.1,53.79) v2(37.06,46.76) v2(37.1,25.84) v2(37.09,22.73) v2(37.18,67.02) v2(37.14,66.36) v2(37.21,45.92) v2(37.21,44.96) v2(37.23,40.6) v2(37.23,40.09) v2(37.21,39.03) v2(37.21,30.39) v2(37.21,24.66) v2(37.22,23.66) v2(37.16,21.95) v2(37.23,21.15) v2(37.17,20.37) v2(37.21,19.85) v2(37.22,19.17) v2(37.17,18.4) v2(37.21,15.91) v2(37.23,14.97) v2(37.33,65.27) v2(37.3,64.53) v2(37.28,27.59) v2(37.3,16.92) v2(37.27,12.76) v2(37.27,10.29) v2(37.27,7.49) v2(37.27,6.99) v2(37.3,1.15) v2(37.37,66.53) v2(37.39,62.83) v2(37.42,52.29) v2(37.39,33.71) v2(37.38,28.06) v2(37.38,26.17) v2(37.37,16.36) v2(37.47,56.71) v2(37.45,50.27) v2(37.52,46.31) v2(37.48,43.23) v2(37.53,42.77) v2(37.45,31.12) v2(37.45,29.1) v2(37.5,27.11) v2(37.49,25.21) v2(37.52,17.93) v2(37.47,14.38) v2(37.48,8.69) v2(37.62,67.03) v2(37.56,63.42) v2(37.57,23.12) v2(37.57,22.79) v2(37.58,21.57) v2(37.56,21.06) v2(37.55,20.2) v2(37.58,16.36) v2(37.69,66.42) v2(37.66,64.88) v2(37.67,51.99) v2(37.67,32.12) v2(37.69,31.51) v2(37.71,29.63) v2(37.67,22.04) v2(37.66,19.64) v2(37.66,19.14) v2(37.71,18.4) v2(37.68,15.93) v2(37.65,10.82) v2(37.67,5.03) v2(37.68,4.35) v2(37.68,3.62) v2(37.68,2.95) v2(37.68,2.22) v2(37.78,63.71) v2(37.78,63.08) v2(37.81,37.05) v2(37.77,35.61) v2(37.78,28.28) v2(37.8,28.06) v2(37.74,13.49) v2(37.77,5.95) v2(37.88,65.2) v2(37.91,48.21) v2(37.87,48.03) v2(37.87,47.85) v2(37.94,45.79) v2(37.85,31.12) v2(37.85,30.46) v2(37.91,29.77) v2(37.85,29.1) v2(37.85,28.65) v2(37.87,27.6) v2(37.86,24.42) v2(37.94,24.12) v2(37.89,22.37) v2(37.87,15.75) v2(37.93,11.92) v2(37.93,9.75) v2(37.93,9.26) v2(37.93,8.34) v2(37.96,66.03) v2(38,53.79) v2(37.99,51.73) v2(37.95,32.66) v2(37.96,18.84) v2(38.02,17.93) v2(37.99,15.21) v2(37.94,10.29) v2(37.99,6.33) v2(38.08,64.13) v2(38.05,48.03) v2(38.06,47.85) v2(38.12,16.36) v2(38.09,14.38) v2(38.11,13.17) v2(38.23,51.06) v2(38.23,43.04) v2(38.22,42.54) v2(38.22,39.57) v2(38.2,31.23) v2(38.22,23.65) v2(38.22,23.12) v2(38.21,22.8) v2(38.21,21.96) v2(38.21,21.61) v2(38.22,20.76) v2(38.21,20.16) v2(38.21,19.55) v2(38.22,19.11) v2(38.22,14.06) v2(38.22,13.49) v2(38.22,11.07) v2(38.22,10.45) v2(38.23,9.74) v2(38.23,8.95) v2(38.23,8.2) v2(38.17,0.91) v2(38.25,30.39) v2(38.25,28.05) v2(38.27,21.14) v2(38.24,18.38) v2(38.25,15.92) v2(38.24,15.51) v2(38.27,14.9) v2(38.27,11.48) v2(38.41,66.53) v2(38.34,63.64) v2(38.38,38.22) v2(38.44,27.67) v2(38.35,16.42) v2(38.53,65.92) v2(38.51,64.57) v2(38.45,32.12) v2(38.5,31.1) v2(38.5,27.11) v2(38.54,68.7) v2(38.58,62.93) v2(38.62,46.09) v2(38.55,33.71) v2(38.61,29.68) v2(38.63,29.11) v2(38.59,17.5) v2(38.69,58.94) v2(38.69,26.17) v2(38.67,24.74) v2(38.66,22.76) v2(38.65,19.7) v2(38.67,17) v2(38.67,16.42) v2(38.75,65) v2(38.81,37.03) v2(38.83,23.63) v2(38.82,21.46) v2(38.82,20.58) v2(38.82,18.83) v2(38.77,15.93) v2(38.94,67.82) v2(38.84,64.64) v2(38.94,53.79) v2(38.86,35.61) v2(38.91,34.75) v2(38.94,24.12) v2(38.97,67) v2(39,65.52) v2(39.01,59.18) v2(38.95,58.45) v2(38.94,51.76) v2(38.97,37.79) v2(38.95,32.66) v2(38.96,28.49) v2(38.97,24.49) v2(38.96,19.69) v2(38.97,17.5) v2(38.98,16.43) v2(38.98,13.37) v2(39.12,64.38) v2(39.04,31.29) v2(39.12,30.29) v2(39.06,14.63) v2(39.04,13.93) v2(39.16,66.36) v2(39.19,65.89) v2(39.23,63.58) v2(39.23,38.15) v2(39.21,16.32) v2(39.19,15.83) v2(39.18,11.94) v2(39.3,30.83) v2(39.29,29.08) v2(39.28,27.59) v2(39.29,22.34) v2(39.26,19.84) v2(39.3,19.17) v2(39.28,18.5) v2(39.31,15.39) v2(39.32,14.91) v2(39.31,10.74) v2(39.31,10.15) v2(39.31,9.47) v2(39.31,8.84) v2(39.31,8.13) v2(39.42,65.17) v2(39.43,58.2) v2(39.43,52.75) v2(39.34,47.07) v2(39.41,33.7) v2(39.35,31.42) v2(39.37,16.85) v2(39.36,14.38) v2(39.52,60.25) v2(39.48,51.73) v2(39.45,32.12) v2(39.48,28.7) v2(39.5,27.11) v2(39.49,21.05) v2(39.59,60.98) v2(39.6,28.15) v2(39.57,18.7) v2(39.6,17.49) v2(39.55,0.62) v2(39.67,66.36) v2(39.73,58.42) v2(39.68,55.47) v2(39.72,51.52) v2(39.72,35.6) v2(39.7,29.99) v2(39.69,25.75) v2(39.74,24.72) v2(39.65,22.8) v2(39.69,20.02) v2(39.7,16.6) v2(39.73,15.73) v2(39.66,8.85) v2(39.73,5.93) v2(39.76,47.86) v2(39.78,28.78) v2(39.75,14.98) v2(39.84,67.11) v2(39.84,66.91) v2(39.91,65.75) v2(39.9,65.23) v2(39.86,38.67) v2(39.91,34.7) v2(39.92,22.46) v2(39.87,16.2) v2(39.89,15.98) v2(39.87,13.38) v2(39.86,10.74) v2(39.86,10.08) v2(39.96,68.7) v2(39.98,66.14) v2(39.95,32.66) v2(40.01,25.98) v2(39.99,19.38) v2(40.03,17.81) v2(39.99,14.18) v2(39.97,13.72) v2(39.99,11.94) v2(40.04,64.36) v2(40.04,30.33) v2(40.11,28.16) v2(40.06,22) v2(40.1,21.14) v2(40.1,14.7) v2(40.13,7.95) v2(40.13,6.63) v2(40.13,5.19) v2(40.15,50.49) v2(40.2,49.57) v2(40.15,28.74) v2(40.14,17.03) v2(40.16,16.21) v2(40.29,67.33) v2(40.29,67.08) v2(40.29,66.83) v2(40.29,66.58) v2(40.26,15.99) v2(40.31,3.77) v2(40.32,1.98) v2(40.32,1.33) v2(40.34,65.38) v2(40.44,65.18) v2(40.34,64.93) v2(40.41,60.47) v2(40.4,55.67) v2(40.4,33.71) v2(40.37,27.51) v2(40.38,26.92) v2(40.37,24.54) v2(40.34,20.03) v2(40.38,16.51) v2(40.34,13.6) v2(40.37,13.13) v2(40.37,12.51) v2(40.37,11.85) v2(40.35,10.76) v2(40.35,10.11) v2(40.35,9.25) v2(40.49,67.33) v2(40.49,67.08) v2(40.49,66.83) v2(40.49,66.58) v2(40.46,60.81) v2(40.51,54.74) v2(40.53,38.51) v2(40.47,32.11) v2(40.45,30.69) v2(40.53,26.17) v2(40.52,24.21) v2(40.52,22.79) v2(40.52,21.93) v2(40.48,14.51) v2(40.59,65.58) v2(40.54,65.38) v2(40.54,64.97) v2(40.61,54.24) v2(40.6,29.54) v2(40.6,28.15) v2(40.61,20.71) v2(40.54,12.18) v2(40.71,67.82) v2(40.69,67.33) v2(40.69,67.08) v2(40.74,65.78) v2(40.74,65.38) v2(40.69,56.51) v2(40.69,51.69) v2(40.7,39.24) v2(40.66,38.38) v2(40.67,35.61) v2(40.73,17.79) v2(40.66,15.99) v2(40.75,64.97) v2(40.76,46.29) v2(40.89,67.33) v2(40.89,67.08) v2(40.84,65.58) v2(40.94,65.38) v2(40.84,65.18) v2(40.94,64.93) v2(40.88,54.54) v2(40.94,46.29) v2(40.93,28.93) v2(40.92,26.41) v2(40.98,64.55) v2(40.97,61.79) v2(40.98,58.24) v2(41,51.15) v2(40.99,48.3) v2(40.95,32.66) v2(40.95,31.3) v2(40.95,15.68) v2(40.97,15.23) v2(41.09,53.44) v2(41.11,48.17) v2(41.12,46.29) v2(41.05,28.15) v2(41.07,23.6) v2(41.04,22.28) v2(41.09,21.27) v2(41.04,20.28) v2(41.05,18.65) v2(41.07,16.98) v2(41.06,16.53) v2(41.06,15.94) v2(41.04,13.16) v2(41.07,12.51) v2(41.24,66) v2(41.24,55.64) v2(41.14,29.42) v2(41.23,24.14) v2(41.15,17.81) v2(41.21,16.23) v2(41.25,66.58) v2(41.26,54.96) v2(41.29,48.21) v2(41.31,41.89) v2(41.31,35.59) v2(41.26,27.06) v2(41.3,14.18) v2(41.3,13.71) v2(41.36,67.09) v2(41.41,31.79) v2(41.43,18.35) v2(41.41,15.98) v2(41.35,12.52) v2(41.46,68.52) v2(41.47,48.21) v2(41.46,43.62) v2(41.53,33.71) v2(41.58,65.22) v2(41.54,29.85) v2(41.57,28.16) v2(41.56,17.01) v2(41.58,16.23) v2(41.69,48.8) v2(41.65,48.17) v2(41.65,47.82) v2(41.71,25.75) v2(41.71,25.14) v2(41.69,24.29) v2(41.72,23.61) v2(41.72,23.27) v2(41.66,14.85) v2(41.72,13.09) v2(41.75,41.91) v2(41.79,39.66) v2(41.76,22.17) v2(41.75,21.59) v2(41.76,20.66) v2(41.76,19.66) v2(41.76,18.65) v2(41.78,16.73) v2(41.79,16.3) v2(41.79,15.64) v2(41.84,56.54) v2(41.87,51.15) v2(41.92,48.06) v2(41.93,34.55) v2(41.89,31.23) v2(41.94,30.49) v2(41.84,27.46) v2(41.84,18.05) v2(41.88,15.26) v2(41.97,37.61) v2(41.99,35.6) v2(41.95,32.66) v2(42.02,29.38) v2(42.02,28.23) v2(42.01,26.17) v2(41.98,24.14) v2(41.97,22.62) v2(42.02,16.67) v2(42.11,68.04) v2(42.13,64.56) v2(42.05,54.45) v2(42.12,46.34) v2(42.13,34.55) v2(42.08,28.55) v2(42.04,27.54) v2(42.04,14.64) v2(42.22,67.11) v2(42.19,61.9) v2(42.23,60.47) v2(42.19,46.08) v2(42.18,42.99) v2(42.23,17.28) v2(42.14,15.78) v2(42.22,13.74) v2(42.25,42.41) v2(42.25,30.48) v2(42.32,25.77) v2(42.32,25.07) v2(42.29,24.39) v2(42.31,23.91) v2(42.29,23.14) v2(42.29,22.58) v2(42.29,21.89) v2(42.31,21.39) v2(42.29,18.89) v2(42.29,17.89) v2(42.29,16.89) v2(42.43,53.52) v2(42.36,42.99) v2(42.37,32.12) v2(42.37,31.94) v2(42.42,31.6) v2(42.34,26.59) v2(42.34,20.79) v2(42.34,19.94) v2(42.34,12.52) v2(42.52,66.49) v2(42.45,34.76) v2(42.47,29) v2(42.45,27.61) v2(42.5,13.08) v2(42.63,56.59) v2(42.6,55.53) v2(42.54,55.17) v2(42.6,35.6) v2(42.54,31.04) v2(42.54,30.49) v2(42.59,29.38) v2(42.61,23.76) v2(42.57,19.37) v2(42.57,18.57) v2(42.54,16.28) v2(42.68,65.26) v2(42.72,54.12) v2(42.7,47.77) v2(42.71,29.01) v2(42.66,22.23) v2(42.65,18.12) v2(42.84,68.52) v2(42.75,42.41) v2(42.75,31.93) v2(42.84,27.53) v2(42.84,25.78) v2(42.79,25.33) v2(42.79,20.78) v2(42.83,17.1) v2(42.81,15.05) v2(42.76,14.28) v2(42.91,55.3) v2(42.89,51.2) v2(42.93,43.66) v2(42.89,28.28) v2(42.88,27.01) v2(42.88,17.85) v2(42.96,56.79) v2(43.02,55.66) v2(43,46.33) v2(42.97,29.67) v2(42.94,24.51) v2(42.99,23.28) v2(42.95,22.95) v2(42.95,22.56) v2(42.95,21.34) v2(43.04,33.88) v2(43.09,19.19) v2(43.2,66.64) v2(43.19,64.84) v2(43.22,59.22) v2(43.14,42.99) v2(43.2,24.13) v2(43.32,61.23) v2(43.28,35.6) v2(43.29,31.49) v2(43.29,24.94) v2(43.32,23.67) v2(43.31,22.08) v2(43.26,21.38) v2(43.36,67.28) v2(43.4,56.39) v2(43.4,45.92) v2(43.37,41.53) v2(43.39,26.16) v2(43.4,19.06) v2(43.42,17.79) v2(43.36,16.34) v2(43.53,54.98) v2(43.51,53.11) v2(43.45,32.16) v2(43.46,27.6) v2(43.47,17.23) v2(43.61,61.89) v2(43.64,31.03) v2(43.64,28.83) v2(43.64,26.78) v2(43.55,26.57) v2(43.57,25.28) v2(43.6,21.38) v2(43.56,12.52) v2(43.73,33.11) v2(43.7,32.63) v2(43.71,29.95) v2(43.66,28.39) v2(43.72,24.13) v2(43.74,22.08) v2(43.73,21.09) v2(43.7,20.2) v2(43.72,19.71) v2(43.69,18.59) v2(43.81,68.18) v2(43.84,64.6) v2(43.82,57.65) v2(43.78,38.57) v2(43.84,30.09) v2(43.79,24.93) v2(43.83,23.65) v2(43.9,45.32) v2(43.91,33.9) v2(43.87,29.33) v2(43.92,21.74) v2(43.9,17.23) v2(43.9,16.29) v2(43.86,13.68) v2(43.99,56.12) v2(43.95,51.39) v2(44,41.81) v2(44,41.56) v2(44,39.59) v2(43.97,39.04) v2(44.01,37.57) v2(43.98,35.61) v2(43.98,27.58) v2(44,27.03) v2(43.97,25.48) v2(44.01,20.86) v2(43.99,19.29) v2(44.11,52.49) v2(44.05,42.95) v2(44.08,33.63) v2(44.12,33.11) v2(44.07,27.26) v2(44.11,25.21) v2(44.1,24.92) v2(44.07,22.9) v2(44.1,22.08) v2(44.11,21.16) v2(44.16,60.03) v2(44.16,56.65) v2(44.15,55.02) v2(44.16,54.25) v2(44.16,47.45) v2(44.16,25.65) v2(44.19,24.13) v2(44.14,18.09) v2(44.26,67.27) v2(44.31,57.31) v2(44.34,25.83) v2(44.32,25.51) v2(44.32,21.38) v2(44.35,56.68) v2(44.35,44.97) v2(44.39,29.03) v2(44.4,26.57) v2(44.38,26.39) v2(44.43,24.92) v2(44.36,17.74) v2(44.42,15.53) v2(44.49,68.5) v2(44.5,48.31) v2(44.44,40.46) v2(44.45,29.38) v2(44.44,25.19) v2(44.46,23.65) v2(44.44,22.08) v2(44.49,21.74) v2(44.61,64.86) v2(44.55,46.88) v2(44.57,42.39) v2(44.61,35.61) v2(44.58,33.66) v2(44.54,24.61) v2(44.55,24.28) v2(44.54,20.18) v2(44.6,12.52) v2(44.66,51.9) v2(44.7,24.91) v2(44.69,21.38) v2(44.75,66.46) v2(44.75,65.31) v2(44.83,30.05) v2(44.75,26.89) v2(44.79,25.19) v2(44.81,23.25) v2(44.78,22.08) v2(44.87,14.23) v2(44.86,13.21) v2(44.97,37.59) v2(44.97,27.18) v2(44.98,24.63) v2(44.98,24.29) v2(44.94,18.05) v2(45.12,53.4) v2(45.13,38.61) v2(45.13,34.68) v2(45.13,33.95) v2(45.12,33.27) v2(45.12,32.27) v2(45.09,25.96) v2(45.09,25.19) v2(45.09,24.92) v2(45.08,20.37) v2(45.1,19.34) v2(45.04,13.77) v2(45.19,61.07) v2(45.18,54.98) v2(45.18,41.82) v2(45.22,28.51) v2(45.21,25.71) v2(45.22,25.46) v2(45.19,23.78) v2(45.2,17.23) v2(45.2,16.85) v2(45.3,40.45) v2(45.32,21.9) v2(45.32,20.16) v2(45.4,68.71) v2(45.39,29.34) v2(45.41,25.22) v2(45.42,24.98) v2(45.41,24.19) v2(45.38,21.16) v2(45.39,18.04) v2(45.51,46.13) v2(45.51,41.31) v2(45.45,35.61) v2(45.45,34.03) v2(45.47,30.31) v2(45.52,27.34) v2(45.5,22.04) v2(45.51,17.79) v2(45.46,15.51) v2(45.55,39.13) v2(45.63,38.12) v2(45.62,31.27) v2(45.58,25.94) v2(45.58,25.57) v2(45.56,24.09) v2(45.56,23.5) v2(45.56,23.24) v2(45.56,22.94) v2(45.56,22.76) v2(45.63,19.51) v2(45.54,17.11) v2(45.61,14.24) v2(45.64,12.52) v2(45.74,60.93) v2(45.73,54.25) v2(45.65,44.63) v2(45.74,39.96) v2(45.72,24) v2(45.69,21.03) v2(45.69,20.17) v2(45.68,16.73) v2(45.66,16.36) v2(45.77,65.29) v2(45.78,64.59) v2(45.76,32.72) v2(45.8,31.82) v2(45.82,25.96) v2(45.78,25.22) v2(45.84,15.73) v2(45.79,15.04) v2(45.79,13.78) v2(45.86,24.36) v2(45.94,52.78) v2(46.02,43.5) v2(46,34.69) v2(45.99,24.76) v2(45.97,18.39) v2(45.94,13.2) v2(46.13,57) v2(46.13,52.11) v2(46.13,49.39) v2(46.1,27.35) v2(46.13,25.38) v2(46.06,22.41) v2(46.09,16.22) v2(46.09,13.78) v2(46.22,34.3) v2(46.22,33.63) v2(46.14,29.34) v2(46.16,27.02) v2(46.2,22.76) v2(46.16,21.61) v2(46.16,20.86) v2(46.16,19.71) v2(46.14,19.36) v2(46.15,18.99) v2(46.24,18.6) v2(46.14,15.03) v2(46.25,66.47) v2(46.26,38.66) v2(46.27,35.48) v2(46.25,31.46) v2(46.31,21.23) v2(46.33,18.03) v2(46.42,41.83) v2(46.35,36.51) v2(46.39,30.24) v2(46.39,23.55) v2(46.4,23.25) v2(46.35,21.93) v2(46.41,20.25) v2(46.34,17.15) v2(46.35,14.88) v2(46.44,35.04) v2(46.48,25.49) v2(46.52,24.02) v2(46.48,22.71) v2(46.51,19.36) v2(46.44,17.84) v2(46.49,16.22) v2(46.64,52.1) v2(46.6,33.65) v2(46.64,29.53) v2(46.61,27.15) v2(46.6,25.95) v2(46.62,19.15) v2(46.54,16.94) v2(46.65,68.7) v2(46.68,62.07) v2(46.69,29.13) v2(46.68,27.58) v2(46.79,63.77) v2(46.74,61.51) v2(46.84,43.26) v2(46.76,35.24) v2(46.82,34.5) v2(46.83,23.35) v2(46.81,20.86) v2(46.81,20.46) v2(46.79,19.77) v2(46.81,19.36) v2(46.81,18.61) v2(46.82,17.69) v2(46.81,16.67) v2(46.81,14.86) v2(46.82,14.03) v2(46.77,13.3) v2(46.87,60.28) v2(46.89,29.34) v2(46.87,24.92) v2(46.91,15.83) v2(46.89,12.53) v2(47.02,67.22) v2(47.01,64.68) v2(46.98,53.37) v2(47.03,40.44) v2(47,26.28) v2(46.98,24.33) v2(46.97,23.82) v2(46.94,21.38) v2(47.08,46.58) v2(47.1,31.31) v2(47.07,25.42) v2(47.07,21.93) v2(47.19,55.58) v2(47.19,44.65) v2(47.21,39.57) v2(47.24,36.1) v2(47.23,30.64) v2(47.24,29.78) v2(47.16,22.75) v2(47.18,21.58) v2(47.17,20.88) v2(47.17,20.41) v2(47.16,19.71) v2(47.16,16.16) v2(47.26,57.28) v2(47.29,41.8) v2(47.27,23.5) v2(47.27,23.19) v2(47.26,17.52) v2(47.35,65.29) v2(47.43,59.26) v2(47.39,51.72) v2(47.38,37.54) v2(47.42,28.16) v2(47.42,17.94) v2(47.36,15.36) v2(47.5,32.53) v2(47.5,27.15) v2(47.5,18.95) v2(47.6,67.2) v2(47.55,30.15) v2(47.63,28.77) v2(47.59,26.75) v2(47.56,26.27) v2(47.56,22.35) v2(47.56,21.21) v2(47.56,20.09) v2(47.54,18.55) v2(47.58,15.74) v2(47.72,47.49) v2(47.69,24.56) v2(47.71,23.18) v2(47.66,22.63) v2(47.73,19.32) v2(47.7,18.81) v2(47.69,12.52) v2(47.83,68.64) v2(47.83,36.44) v2(47.8,25.42) v2(47.75,23.72) v2(47.81,22.76) v2(47.81,22.03) v2(47.84,21.43) v2(47.84,20.43) v2(47.84,19.7) v2(47.84,17.51) v2(47.8,14.92) v2(47.92,44.59) v2(47.9,41.45) v2(47.9,40.35) v2(47.95,43.09) v2(48.03,31.98) v2(47.97,31.44) v2(47.98,30.43) v2(48.03,29.34) v2(48,26.74) v2(48.03,15.32) v2(47.94,13.84) v2(48.11,62.08) v2(48.11,50.41) v2(48.11,36.98) v2(48.09,34.56) v2(48.09,34.26) v2(48.09,33.96) v2(48.09,33.66) v2(48.11,21.15) v2(48.09,19.44) v2(48.13,16.32) v2(48.2,25.51) v2(48.17,21.92) v2(48.2,19.69) v2(48.16,18.55) v2(48.15,17.95) v2(48.2,14.52) v2(48.32,66.43) v2(48.25,61.15) v2(48.33,57.69) v2(48.25,51.9) v2(48.32,32.24) v2(48.27,22.67) v2(48.34,21.43) v2(48.25,20.86) v2(48.25,20.37) v2(48.39,34.56) v2(48.38,34.38) v2(48.39,33.96) v2(48.39,33.66) v2(48.39,24.39) v2(48.35,23.76) v2(48.35,17.51) v2(48.36,15.32) v2(48.52,68.24) v2(48.52,21.21) v2(48.5,20.7) v2(48.52,20.09) v2(48.52,18.95) v2(48.46,17.19) v2(48.6,46.58) v2(48.6,45.06) v2(48.59,30.41) v2(48.64,28.84) v2(48.56,25.97) v2(48.57,25.33) v2(48.56,18.35) v2(48.7,64.68) v2(48.68,47.31) v2(48.74,40.79) v2(48.73,33.96) v2(48.73,33.66) v2(48.69,29.53) v2(48.72,21.93) v2(48.66,14.06) v2(48.75,38.92) v2(48.8,37.47) v2(48.83,23.7) v2(48.79,22.27) v2(48.84,21.57) v2(48.84,20.47) v2(48.84,19.68) v2(48.84,19.18) v2(48.84,17.09) v2(48.83,12.52) v2(48.93,36.12) v2(48.92,24.3) v2(48.86,22.76) v2(48.87,16.19) v2(48.92,15.51) v2(49.02,63.58) v2(49,63) v2(48.97,61.43) v2(49.01,51.9) v2(49.02,50.83) v2(48.96,30.79) v2(49.03,17.95) v2(49.08,54.25) v2(49.07,53.63) v2(49.09,38.61) v2(49.04,36.79) v2(49.09,33.96) v2(49.09,33.66) v2(49.06,33.33) v2(49.07,28.77) v2(49.13,22.21) v2(49.08,15.81) v2(49.16,36.94) v2(49.21,32.24) v2(49.19,19.35) v2(49.21,18.55) v2(49.21,18.15) v2(49.22,14.89) v2(49.27,55.85) v2(49.3,30.15) v2(49.28,24.76) v2(49.3,22.74) v2(49.26,21.97) v2(49.25,19.71) v2(49.37,68.24) v2(49.36,43.1) v2(49.43,36.08) v2(49.39,34.26) v2(49.39,33.96) v2(49.39,33.66) v2(49.41,23.82) v2(49.35,21.55) v2(49.47,67.75) v2(49.5,66.45) v2(49.49,65.28) v2(49.49,40.8) v2(49.52,37.48) v2(49.44,20.94) v2(49.5,18.11) v2(49.45,15.9) v2(49.6,49.9) v2(49.57,42.4) v2(49.54,22.35) v2(49.54,21.21) v2(49.54,20.09) v2(49.54,18.95) v2(49.55,17.49) v2(49.62,16.18) v2(49.71,62.5) v2(49.65,30.82) v2(49.67,17.09) v2(49.77,54.98) v2(49.84,33.75) v2(49.83,32.59) v2(49.83,21.97) v2(49.83,21.58) v2(49.8,20.4) v2(49.93,57.72) v2(49.85,31.26) v2(49.87,28.77) v2(49.91,25.05) v2(49.85,23.21) v2(49.86,22.76) v2(49.85,18.57) v2(49.91,17.95) v2(49.86,15.61) v2(49.94,64.69) v2(50,63.76) v2(49.96,60.14) v2(50,44.58) v2(49.95,39.11) v2(49.99,30.61) v2(49.99,29.43) v2(49.98,23.51) v2(50.08,41.42) v2(50.08,40.79) v2(50.09,39.26) v2(50.14,59.28) v2(50.15,32.46) v2(50.21,25.25) v2(50.23,22.04) v2(50.21,19.3) v2(50.21,18.55) v2(50.2,16.73) v2(50.2,15.82) v2(50.24,50.69) v2(50.32,45.06) v2(50.27,38.23) v2(50.31,33.28) v2(50.3,23.5) v2(50.27,22.61) v2(50.27,21.57) v2(50.42,37.48) v2(50.43,37.19) v2(50.39,31.59) v2(50.42,24.2) v2(50.42,23.24) v2(50.39,20.86) v2(50.36,18.11) v2(50.41,12.53) v2(50.45,46.79) v2(50.52,30) v2(50.48,17.51) v2(50.52,14.93) v2(50.63,55) v2(50.62,36.29) v2(50.57,34.01) v2(50.62,28.77) v2(50.56,22.35) v2(50.56,21.17) v2(50.56,20.09) v2(50.56,18.95) v2(50.65,57.02) v2(50.66,32.48) v2(50.73,31.12) v2(50.72,24.48) v2(50.73,23.2) v2(50.66,16.01) v2(50.72,15.82) v2(50.79,66.43) v2(50.83,55.59) v2(50.76,36.16) v2(50.75,34.01) v2(50.81,22.04) v2(50.84,21.43) v2(50.93,49.19) v2(50.93,39.38) v2(50.88,33.27) v2(50.89,29.58) v2(50.85,23.51) v2(50.91,22.76) v2(50.88,20.42) v2(50.91,19.66) v2(50.9,19.34) v2(50.85,18.6) v2(51.02,33.75) v2(50.96,14.92) v2(51.11,65.28) v2(51.08,64.66) v2(51.13,59.59) v2(51.13,59) v2(51.13,55) v2(51.13,50.94) v2(51.05,40.78) v2(51.13,39.38) v2(51.06,38.51) v2(51.09,34.77) v2(51.11,24.29) v2(51.12,15.93) v2(51.17,54.5) v2(51.21,31.96) v2(51.22,18.79) v2(51.14,15.09) v2(51.3,63.32) v2(51.33,62.46) v2(51.33,39.38) v2(51.27,38.23) v2(51.31,36.67) v2(51.33,30.67) v2(51.25,22.72) v2(51.25,21.95) v2(51.34,21.57) v2(51.25,20.48) v2(51.32,19.74) v2(51.26,19.36) v2(51.32,16.39) v2(51.26,13.03) v2(51.26,12.52) v2(51.4,33.44) v2(51.42,32.65) v2(51.37,28.77) v2(51.39,20.89) v2(51.48,67.38) v2(51.47,66.9) v2(51.48,66.55) v2(51.51,61.32) v2(51.44,51.88) v2(51.47,35.13) v2(51.53,29.07) v2(51.56,64.27) v2(51.57,62.46) v2(51.64,59.04) v2(51.63,57.5) v2(51.63,56.94) v2(51.63,52.5) v2(51.59,31.05) v2(51.56,25.13) v2(51.59,15.52) v2(51.7,68.23) v2(51.73,23.51) v2(51.73,23.2) v2(51.65,16.39) v2(51.81,67.37) v2(51.82,66.91) v2(51.79,66.55) v2(51.8,63.97) v2(51.78,38.26) v2(51.81,33.87) v2(51.83,32.76) v2(51.8,29.87) v2(51.8,23.82) v2(51.9,24.2) v2(51.91,22.76) v2(51.91,21.96) v2(51.86,21.6) v2(51.91,21.16) v2(51.91,20.5) v2(51.93,19.69) v2(51.91,19.36) v2(51.89,14.84) v2(51.97,37.54) v2(51.98,36.37) v2(51.97,35.13) v2(52.01,28.62) v2(51.99,18.49) v2(52.12,67.35) v2(52.1,66.9) v2(52.1,66.55) v2(52.06,63.68) v2(52.07,45.42) v2(52.06,38.51) v2(52.08,36.8) v2(52.12,28.27) v2(52.15,39.37) v2(52.14,27.78) v2(52.23,25.66) v2(52.22,24.9) v2(52.15,16.8) v2(52.33,58.28) v2(52.33,57.32) v2(52.24,50.08) v2(52.24,44.04) v2(52.24,42.44) v2(52.34,35.31) v2(52.29,34.26) v2(52.28,32.75) v2(52.41,67.88) v2(52.35,53.83) v2(52.38,51.33) v2(52.4,41.63) v2(52.36,39.37) v2(52.36,29.5) v2(52.36,25.29) v2(52.4,24.57) v2(52.38,22.78) v2(52.38,22.34) v2(52.51,67.15) v2(52.51,66.91) v2(52.51,66.44) v2(52.5,64.34) v2(52.49,36.43) v2(52.46,34.58) v2(52.48,31.78) v2(52.44,26.59) v2(52.52,23.51) v2(52.53,21.53) v2(52.53,19.77) v2(52.51,12.52) v2(52.55,63.94) v2(52.58,39.37) v2(52.56,38.3) v2(52.62,32.68) v2(52.63,31.07) v2(52.62,28.26) v2(52.58,17.05) v2(52.58,16.65) v2(52.62,15.87) v2(52.62,14.63) v2(52.73,29.91) v2(52.67,25) v2(52.69,23.23) v2(52.7,22.92) v2(52.69,22.47) v2(52.66,17.8) v2(52.65,15.17) v2(52.8,34.78) v2(52.82,33.36) v2(52.82,32.86) v2(52.81,31.48) v2(52.89,55.27) v2(52.87,27.52) v2(52.89,27.03) v2(52.92,24.2) v2(53,31.22) v2(53.03,30.39) v2(53.04,27.97) v2(53.02,23.34) v2(53.01,22.23) v2(52.97,21.43) v2(52.97,20.62) v2(52.94,19.68) v2(53.03,18.86) v2(52.98,15.59) v2(53.06,38.51) v2(53.07,33.61) v2(53.11,18.21) v2(53.11,17.82) v2(53.08,14.07) v2(53.11,13.52) v2(53.09,12.63) v2(53.18,63.43) v2(53.17,44.6) v2(53.15,42.46) v2(53.16,31.76) v2(53.19,25.84) v2(53.19,19.43) v2(53.28,66.45) v2(53.3,65.29) v2(53.25,39.37) v2(53.27,38.23) v2(53.32,34.35) v2(53.32,33.35) v2(53.3,16.4) v2(53.39,64.33) v2(53.42,40.78) v2(53.35,27.66) v2(53.43,24.45) v2(53.48,41.64) v2(53.51,39.33) v2(53.53,18.36) v2(53.55,67.95) v2(53.55,33.12) v2(53.55,32.6) v2(53.56,29.75) v2(53.62,23.12) v2(53.73,28.17) v2(53.7,27.75) v2(53.7,19.71) v2(53.72,16.02) v2(53.79,63.41) v2(53.76,39.11) v2(53.74,37.78) v2(53.84,37.29) v2(53.81,34.89) v2(53.8,33.36) v2(53.78,22.26) v2(53.75,21.84) v2(53.75,20.82) v2(53.77,12.92) v2(53.93,34.39) v2(53.91,31.92) v2(53.86,31.27) v2(53.87,26.52) v2(53.93,26.06) v2(53.87,18.85) v2(54,67.71) v2(54.01,67.07) v2(54,66.45) v2(53.99,41.8) v2(54.02,33.99) v2(53.97,30.19) v2(53.97,24.76) v2(54.06,63.48) v2(54.04,62.12) v2(54.09,36.83) v2(54.06,33.6) v2(54.11,31.16) v2(54.08,28.52) v2(54.05,27.85) v2(54.12,26.93) v2(54.07,21.39) v2(54.07,20.31) v2(54.18,46.49) v2(54.22,39.1) v2(54.23,38.22) v2(54.19,31.51) v2(54.14,17.61) v2(54.17,12.72) v2(54.31,34.79) v2(54.34,33.85) v2(54.26,33.35) v2(54.32,30.81) v2(54.28,30.3) v2(54.31,29.81) v2(54.37,65.28) v2(54.35,35.8) v2(54.41,28.2) v2(54.39,27.51) v2(54.39,25.53) v2(54.36,16.65) v2(54.52,68.23) v2(54.5,66.17) v2(54.51,45.97) v2(54.48,40.78) v2(54.44,24.34) v2(54.51,20.34) v2(54.57,67.17) v2(54.62,56.24) v2(54.62,39.06) v2(54.55,35.14) v2(54.58,34.35) v2(54.55,32.63) v2(54.61,31.91) v2(54.62,25.77) v2(54.64,25.18) v2(54.72,64.39) v2(54.65,62.09) v2(54.66,60.96) v2(54.67,57.47) v2(54.67,54.13) v2(54.68,18.62) v2(54.69,18.04) v2(54.71,17.38) v2(54.75,51.59) v2(54.75,38.22) v2(54.74,37.57) v2(54.83,34.81) v2(54.76,33.85) v2(54.76,32.86) v2(54.84,26.51) v2(54.88,68.15) v2(54.89,12.73) v2(54.97,46.34) v2(55.01,29.37) v2(54.94,28.43) v2(55.03,21.43) v2(54.94,19.36) v2(55.09,49.42) v2(55.05,36.08) v2(55.05,34.59) v2(55.05,20.09) v2(55.17,67.15) v2(55.16,66.48) v2(55.14,36.78) v2(55.19,23.59) v2(55.14,14.08) v2(55.28,65.27) v2(55.29,39.11) v2(55.27,38.22) v2(55.3,37.49) v2(55.27,36.29) v2(55.25,33.86) v2(55.3,28.95) v2(55.25,27.1) v2(55.41,44.41) v2(55.42,43.34) v2(55.38,41.47) v2(55.34,40.92) v2(55.35,25.64) v2(55.37,25.02) v2(55.54,67.44) v2(55.45,59.01) v2(55.46,58.45) v2(55.46,57.9) v2(55.46,57.4) v2(55.46,56.9) v2(55.54,50.3) v2(55.47,46.09) v2(55.51,39.38) v2(55.53,37.34) v2(55.47,32.6) v2(55.6,63.39) v2(55.55,42.01) v2(55.55,35.59) v2(55.54,33.11) v2(55.57,28.2) v2(55.59,25.45) v2(55.56,19.54) v2(55.7,67.9) v2(55.65,64.34) v2(55.72,46.49) v2(55.69,39.38) v2(55.67,37.49) v2(55.71,32.28) v2(55.71,31.7) v2(55.68,26.52) v2(55.7,25.84) v2(55.71,21.41) v2(55.66,20.73) v2(55.78,59.57) v2(55.77,56.05) v2(55.76,52.08) v2(55.75,36.35) v2(55.79,34.85) v2(55.82,34.36) v2(55.79,33.38) v2(55.82,31.09) v2(55.82,30.74) v2(55.82,30.39) v2(55.82,30.04) v2(55.82,29.69) v2(55.79,29.41) v2(55.75,27.1) v2(55.9,60.81) v2(55.91,58.78) v2(55.85,38.21) v2(55.9,36.77) v2(55.92,25.12) v2(55.93,24.85) v2(55.89,24.03) v2(55.87,19.56) v2(55.97,59.81) v2(55.98,52.08) v2(56.04,34.64) v2(55.94,22.84) v2(56.12,59.26) v2(56.06,57.1) v2(56.11,36.38) v2(56.08,36.05) v2(56.07,35.62) v2(56.04,33.61) v2(56.13,31.09) v2(56.13,30.74) v2(56.13,30.39) v2(56.13,30.04) v2(56.13,29.69) v2(56.05,27.79) v2(56.12,24.27) v2(56.11,12.73) v2(56.18,67.86) v2(56.14,66.27) v2(56.17,64.28) v2(56.18,37.49) v2(56.23,28.64) v2(56.17,27.15) v2(56.14,23.68) v2(56.2,19.54) v2(56.14,14.08) v2(56.24,63.58) v2(56.33,33.37) v2(56.24,23.46) v2(56.31,21.59) v2(56.28,19.99) v2(56.38,27.7) v2(56.42,25.6) v2(56.5,41.47) v2(56.44,38.21) v2(56.46,31.09) v2(56.46,30.74) v2(56.46,30.39) v2(56.46,30.04) v2(56.46,29.69) v2(56.51,21.26) v2(56.55,65.66) v2(56.59,62.39) v2(56.56,51.86) v2(56.6,47.07) v2(56.55,44.41) v2(56.55,36.77) v2(56.61,34.58) v2(56.58,33.33) v2(56.64,23.46) v2(56.58,20.78) v2(56.69,32.79) v2(56.66,26.78) v2(56.71,24.09) v2(56.8,37.56) v2(56.8,32.5) v2(56.77,31.08) v2(56.77,30.74) v2(56.77,30.39) v2(56.77,30.04) v2(56.77,29.69) v2(56.74,26.35) v2(56.84,24.65) v2(56.88,66.07) v2(56.9,63.48) v2(56.87,46.04) v2(56.9,27.37) v2(56.86,19.96) v2(56.92,19.23) v2(56.92,18.73) v2(56.98,68.24) v2(57,60.13) v2(57,59.65) v2(57.01,58.62) v2(57.03,51.75) v2(56.99,48.1) v2(57,42.83) v2(56.97,28.52) v2(56.94,27.75) v2(56.98,23.46) v2(57.03,21.71) v2(56.95,13.46) v2(57.1,64.39) v2(57.11,55.02) v2(57.11,54.71) v2(57.07,38.2) v2(57.1,30.74) v2(57.1,21.32) v2(57.06,20.88) v2(57.1,18.43) v2(57.11,12.73) v2(57.18,66.92) v2(57.22,46.49) v2(57.23,35.49) v2(57.21,14.09) v2(57.33,66.02) v2(57.33,57.88) v2(57.3,42.17) v2(57.25,27.56) v2(57.3,26.6) v2(57.27,26.21) v2(57.29,25) v2(57.27,20.09) v2(57.39,22.53) v2(57.42,19.23) v2(57.43,18.74) v2(57.43,18.32) v2(57.53,66.3) v2(57.49,54.09) v2(57.5,53.64) v2(57.49,52.65) v2(57.51,41.46) v2(57.52,36.42) v2(57.52,35.91) v2(57.52,35.33) v2(57.51,34.39) v2(57.52,33.94) v2(57.52,33.33) v2(57.54,32.83) v2(57.47,31.97) v2(57.46,29.38) v2(57.47,26.29) v2(57.45,23.37) v2(57.5,19.89) v2(57.5,17.27) v2(57.5,16.95) v2(57.55,54.58) v2(57.59,44.63) v2(57.56,34.94) v2(57.58,31.44) v2(57.58,27.75) v2(57.57,27.37) v2(57.61,13.2) v2(57.66,42.16) v2(57.69,13.88) v2(57.68,12.55) v2(57.78,51.82) v2(57.82,45.55) v2(57.79,37.9) v2(57.77,37.33) v2(57.83,36.33) v2(57.84,35.4) v2(57.84,34.38) v2(57.84,29.26) v2(57.82,28.29) v2(57.77,26.62) v2(57.78,26.03) v2(57.82,22.88) v2(57.74,19.22) v2(57.86,66.44) v2(57.87,62.59) v2(57.86,50.56) v2(57.91,24.6) v2(57.89,21.78) v2(57.87,20.76) v2(58.02,43.46) v2(58,33.51) v2(57.95,23.75) v2(58.1,41.82) v2(58.1,41.59) v2(58.05,40.55) v2(58.11,27.42) v2(58.2,63.08) v2(58.14,61.88) v2(58.18,59.26) v2(58.15,31.6) v2(58.18,25.74) v2(58.21,22.59) v2(58.22,21.03) v2(58.2,20.02) v2(58.27,67.18) v2(58.28,66.91) v2(58.28,65.38) v2(58.29,65.11) v2(58.34,41.73) v2(58.24,40.55) v2(58.33,35.59) v2(58.24,33.86) v2(58.24,31.09) v2(58.27,30.32) v2(58.29,27.78) v2(58.41,60.1) v2(58.4,34.72) v2(58.4,31.6) v2(58.41,25.24) v2(58.46,37.17) v2(58.46,36.17) v2(58.46,35.17) v2(58.49,27.22) v2(58.52,26.14) v2(58.58,52.42) v2(58.62,30.88) v2(58.56,29.09) v2(58.56,26.98) v2(58.7,67.31) v2(58.72,66.9) v2(58.73,66.45) v2(58.7,65.81) v2(58.72,65.54) v2(58.71,65.27) v2(58.66,51.35) v2(58.68,48.34) v2(58.71,28.95) v2(58.69,24.08) v2(58.69,23.35) v2(58.67,18.57) v2(58.81,57.99) v2(58.83,56.19) v2(58.74,46.39) v2(58.74,31.23) v2(58.77,28.21) v2(58.77,25.57) v2(58.74,24.44) v2(58.76,22.02) v2(58.76,20.57) v2(58.79,20.02) v2(58.82,18.74) v2(58.85,61.55) v2(58.92,52.81) v2(58.86,29.09) v2(58.91,27.7) v2(58.96,68.21) v2(58.97,67.3) v2(59,66.89) v2(59,66.44) v2(58.97,65.8) v2(59,65.53) v2(58.98,65.26) v2(59,63.48) v2(59.03,35.52) v2(59,34.11) v2(58.97,26.8) v2(58.97,26.39) v2(58.96,23.02) v2(59.05,61.08) v2(59.13,51.02) v2(59.09,28.4) v2(59.09,25.7) v2(59.15,59.79) v2(59.16,40.99) v2(59.21,33.17) v2(59.21,32.17) v2(59.21,31.17) v2(59.17,29.38) v2(59.15,27.73) v2(59.21,23.65) v2(59.18,22.5) v2(59.18,17.24) v2(59.32,67.31) v2(59.25,66.89) v2(59.3,66.45) v2(59.32,65.81) v2(59.25,65.53) v2(59.28,65.27) v2(59.31,61.35) v2(59.34,55.63) v2(59.33,54.77) v2(59.25,48.12) v2(59.28,38.2) v2(59.24,34.69) v2(59.3,24.35) v2(59.28,22.87) v2(59.35,47.35) v2(59.4,35.28) v2(59.38,29.63) v2(59.35,25.02) v2(59.43,17.77) v2(59.37,17.24) v2(59.48,31.84) v2(59.53,27.73) v2(59.44,22.03) v2(59.44,19.88) v2(59.44,19.1) v2(59.45,18.38) v2(59.59,33.8) v2(59.6,32.91) v2(59.56,31.19) v2(59.55,30.97) v2(59.6,28.41) v2(59.64,25.71) v2(59.6,22.99) v2(59.66,61.56) v2(59.71,59.74) v2(59.73,54.77) v2(59.72,41.83) v2(59.68,32.06) v2(59.71,30.17) v2(59.7,26.45) v2(59.7,26.05) v2(59.75,62.88) v2(59.79,56.37) v2(59.74,44.45) v2(59.77,38.55) v2(59.76,34.5) v2(59.93,63.27) v2(59.84,58.98) v2(59.88,53.44) v2(59.89,52.93) v2(59.86,27.54) v2(59.9,27.2) v2(59.86,22.48) v2(59.85,18.37) v2(60.01,48.44) v2(60.03,31.46) v2(60.07,68.44) v2(60.13,55.17) v2(60.13,54.77) v2(60.1,35.52) v2(60.07,29.48) v2(60.08,28.42) v2(60.1,27.21) v2(60.14,31.22) v2(60.19,14.09) v2(60.34,47.28) v2(60.34,32.03) v2(60.34,22.58) v2(60.33,16.99) v2(60.4,56.56) v2(60.37,51.41) v2(60.4,30.14) v2(60.37,26.45) v2(60.39,21.85) v2(60.35,19.73) v2(60.35,19.4) v2(60.35,19.04) v2(60.54,69.29) v2(60.5,62.13) v2(60.51,58.66) v2(60.53,55.17) v2(60.46,35.72) v2(60.46,29.42) v2(60.54,16.44) v2(60.48,14.09) v2(60.61,26.98) v2(60.54,24.42) v2(60.55,21.16) v2(60.68,66.98) v2(60.73,60.54) v2(60.65,28.19) v2(60.66,27.55) v2(60.76,45.36) v2(60.77,34.16) v2(60.77,33.89) v2(60.81,30.89) v2(60.8,24.94) v2(60.81,22.52) v2(60.82,18.29) v2(60.76,16.42) v2(60.93,54.77) v2(60.93,54.37) v2(60.91,24.42) v2(60.92,23.1) v2(60.91,21.16) v2(60.87,15.77) v2(61.01,67.84) v2(60.99,60.12) v2(61.02,52.4) v2(60.98,50.29) v2(61.01,35.85) v2(61,34.16) v2(61,33.89) v2(61,31.84) v2(60.97,26.06) v2(61.05,66.35) v2(61.13,62.56) v2(61.06,30.11) v2(61.15,63.27) v2(61.19,59.06) v2(61.25,61.38) v2(61.26,59.67) v2(61.33,54.77) v2(61.33,53.17) v2(61.26,44.46) v2(61.32,40.12) v2(61.31,32.16) v2(61.3,31.14) v2(61.31,29.27) v2(61.31,28.27) v2(61.31,27.27) v2(61.31,26.27) v2(61.31,25.27) v2(61.31,24.27) v2(61.31,23.27) v2(61.31,22.27) v2(61.24,21.16) v2(61.42,58.54) v2(61.35,29.71) v2(61.44,47.6) v2(61.44,47) v2(61.44,16.39) v2(61.63,39.13) v2(61.64,30.3) v2(61.61,19.26) v2(61.56,18.5) v2(61.73,53.57) v2(61.73,53.17) v2(61.69,52.1) v2(61.69,48.04) v2(61.7,43.6) v2(61.7,42.98) v2(61.7,35.85) v2(61.72,27.14) v2(61.71,26.75) v2(61.7,26.3) v2(61.7,25.83) v2(61.7,25.36) v2(61.7,24.89) v2(61.71,24.42) v2(61.7,23.94) v2(61.7,23.42) v2(61.7,22.88) v2(61.71,22.42) v2(61.7,21.95) v2(61.7,21.45) v2(61.7,20.95) v2(61.71,20.49) v2(61.7,19.82) v2(61.77,68.59) v2(61.83,64.61) v2(61.75,32.47) v2(61.75,31.27) v2(61.75,29.77) v2(61.75,28.57) v2(61.75,27.42) v2(61.86,40.8) v2(61.86,19.01) v2(61.87,15.77) v2(62,60.63) v2(61.95,17.58) v2(62.09,18.78) v2(62.29,63.83) v2(62.25,56.69) v2(62.28,17.58) v2(62.4,35.85) v2(62.45,68.26) v2(62.45,60.37) v2(62.52,47.08) v2(62.52,18.94) v2(62.56,48.79) v2(62.62,41.8) v2(62.64,17.58) v2(62.66,50.82) v2(62.79,67) v2(62.79,65.56) v2(62.75,59.88) v2(62.77,15.77) v2(62.88,57.33) v2(63.09,46.31) v2(63.07,35.85) v2(63.18,45.32) v2(63.29,60.92) v2(63.26,17.02) v2(63.39,61.54) v2(63.46,39.46) v2(63.52,18.94) v2(63.63,68.23) v2(63.55,56.87) v2(63.55,52.17) v2(63.68,63.38) v2(63.7,50.89) v2(63.7,48.18) v2(63.68,46.89) v2(63.72,45.69) v2(63.76,64.37) v2(63.77,62.11) v2(63.78,60.06) v2(63.74,59.69) v2(63.77,58.5) v2(63.83,39.04) v2(63.76,35.85) v2(63.9,61) v2(64.01,55.45) v2(64,54.08) v2(63.98,53.06) v2(64.04,52.22) v2(64.03,51.4) v2(64.03,50.21) v2(64.05,56.67) v2(64.28,64.76) v2(64.33,48.78) v2(64.27,47.57) v2(64.33,17.03) v2(64.38,67.49) v2(64.37,66.36) v2(64.36,62.98) v2(64.42,44.06) v2(64.43,40.77) v2(64.35,18.5) v2(64.35,18.14) v2(64.35,17.81) v2(64.48,65.19) v2(64.45,42.71) v2(64.44,38.69) v2(64.47,35.84) v2(64.52,18.94) v2(64.5,16.78) v2(64.82,61.47) v2(64.79,17.08) v2(64.82,15.84) v2(64.79,12.58) v2(64.79,12.08) v2(64.79,11.58) v2(64.79,11.08) v2(64.89,13.78) v2(64.99,48.08) v2(64.97,46.29) v2(65.14,63.56) v2(65.17,61.93) v2(65.18,60.64) v2(65.18,58.64) v2(65.21,37.58) v2(65.16,37.08) v2(65.17,36.55) v2(65.14,36) v2(65.34,38.06) v2(65.31,16.59) v2(65.29,15.82) v2(65.37,64.64) v2(65.37,63.02) v2(65.37,56.64) v2(65.37,54.64) v2(65.37,46.13) v2(65.36,45.73) v2(65.36,45.17) v2(65.36,44.58) v2(65.36,44.17) v2(65.36,43.61) v2(65.36,43.02) v2(65.35,42.52) v2(65.36,41.96) v2(65.36,41.4) v2(65.36,40.81) v2(65.35,40.31) v2(65.35,39.71) v2(65.35,39.15) v2(65.35,38.56) v2(65.37,19.42) v2(65.47,20.24) v2(65.8,12.58) v2(65.8,12.08) v2(65.8,11.58) v2(65.8,11.08) v2(65.88,53.6) v2(65.99,51.84) v2(65.94,48.1) v2(65.94,17.61) v2(65.94,15.42) v2(66.19,18.27) v2(66.33,16.61) v2(66.37,52.51) v2(66.46,50.76) v2(66.47,20.24) v2(66.67,53.37) v2(66.69,15.43) v2(67.07,48.2) v2(67.08,18.67) v2(67.11,16.4) v2(67.2,49.46) v2(67.4,50.51) v2(67.44,15.43) v2(67.47,20.24) v2(67.86,16.62) v2(67.99,52.94) v2(68.09,48.56) v2(68.1,15.43) v2(68.15,52.71) v2(68.19,51.68) v2(68.15,50.94) v2(68.18,16.23) v2(68.33,49.31) v2(68.32,18.23) v2(68.25,17.23) v2(68.41,19.23) v2(68.47,20.24) v3(0.31,20.23) v3(0.36,19.37) v3(0.44,18.37) v3(0.44,52.2) v3(0.46,50.98) v3(0.48,49.2) v3(0.52,17.37) v3(0.59,16.36) v3(0.7,48.74) v3(0.67,15.36) v3(0.76,52.93) v3(0.84,18.28) v3(0.93,16.67) v3(1.07,52.86) v3(1.31,20.23) v3(1.5,50.41) v3(1.65,18.69) v3(1.7,16.36) v3(1.67,15.36) v3(1.82,53.35) v3(2.31,20.23) v3(2.46,18.38) v3(2.49,16.69) v3(2.47,15.36) v3(2.73,51.84) v3(2.65,48.1) v3(2.82,17.57) v3(3.11,15.36) v3(3.28,54.07) v3(3.3,46.28) v3(3.31,20.23) v3(3.41,64.79) v3(3.41,63.53) v3(3.41,62.49) v3(3.4,56.97) v3(3.4,55.18) v3(3.4,43.67) v3(3.4,40.67) v3(3.4,37.67) v3(3.42,19.41) v3(3.45,63.1) v3(3.6,61.35) v3(3.6,60.81) v3(3.6,60.28) v3(3.6,59.75) v3(3.6,59.22) v3(3.6,58.69) v3(3.6,58.16) v3(3.58,57.55) v3(3.59,48.88) v3(3.61,36.59) v3(3.6,35.51) v3(3.78,48.07) v3(3.8,15.35) v3(3.9,66.93) v3(3.91,65.67) v3(3.92,52.55) v3(3.91,51.53) v3(3.95,68.06) v3(4.04,15.88) v3(4.05,50.76) v3(4.17,15.35) v3(4.27,58.33) v3(4.28,57.01) v3(4.25,18.94) v3(4.41,18.2) v3(4.39,16.31) v3(4.5,67.02) v3(4.51,57.64) v3(4.46,51.52) v3(4.5,47.62) v3(4.54,46.85) v3(4.49,15.64) v3(4.72,66.57) v3(4.74,56.3) v3(4.81,44.15) v3(4.79,35.51) v3(4.89,55.11) v3(4.85,54.46) v3(4.85,51.55) v3(4.91,49.5) v3(5.06,68.22) v3(5.07,52.75) v3(5.17,56.8) v3(5.17,17.37) v3(5.17,17.19) v3(5.17,17.01) v3(5.16,16.33) v3(5.16,16.15) v3(5.16,15.97) v3(5.25,18.94) v3(5.26,16.67) v3(5.43,67.88) v3(5.53,60.16) v3(5.51,48.03) v3(5.51,46.29) v3(5.46,15.62) v3(5.55,63.9) v3(5.55,62.83) v3(5.61,59.25) v3(5.63,54.33) v3(5.57,45.24) v3(5.67,66.19) v3(5.67,17.22) v3(5.87,67.65) v3(5.87,53.12) v3(5.91,49.5) v3(5.92,15.62) v3(5.97,65.26) v3(5.98,64.5) v3(5.95,59.74) v3(6.1,58.08) v3(6.04,54.13) v3(6.09,44.64) v3(6.12,43.49) v3(6.12,41.27) v3(6.16,58.67) v3(6.23,45.36) v3(6.19,35.51) v3(6.29,68.24) v3(6.34,63.35) v3(6.32,52.83) v3(6.26,38.65) v3(6.25,18.94) v3(6.39,36.6) v3(6.34,15.64) v3(6.47,50.2) v3(6.56,18.43) v3(6.75,52.5) v3(6.91,64.11) v3(7.02,67.03) v3(6.94,66.05) v3(7.01,63.34) v3(7.02,57.73) v3(7.02,32.26) v3(7.02,31.24) v3(7.02,30.48) v3(7.02,28.09) v3(7.01,27) v3(7.03,25.44) v3(7.03,23.44) v3(7.03,20.24) v3(7.01,19.62) v3(7.03,19.01) v3(6.99,15.64) v3(7.06,52.72) v3(7.1,46.18) v3(7.09,44.97) v3(7.06,29.3) v3(7.2,68.72) v3(7.15,49.3) v3(7.34,63.35) v3(7.25,59.91) v3(7.4,52.92) v3(7.41,51.39) v3(7.38,43.52) v3(7.36,26.35) v3(7.37,21.89) v3(7.38,20.88) v3(7.39,20.11) v3(7.37,19.08) v3(7.38,17.64) v3(7.42,15.22) v3(7.44,62.28) v3(7.44,62.06) v3(7.47,50.35) v3(7.47,42.32) v3(7.47,39.74) v3(7.48,35.51) v3(7.44,29.75) v3(7.61,67.65) v3(7.64,37.24) v3(7.64,31.89) v3(7.57,16.14) v3(7.66,64.12) v3(7.72,27.79) v3(7.73,6.72) v3(7.83,57.99) v3(7.74,56.56) v3(7.75,44.64) v3(7.74,15.39) v3(7.78,14.87) v3(7.82,14.35) v3(7.82,13.78) v3(7.82,13.23) v3(7.82,12.68) v3(7.9,66.85) v3(7.88,66.06) v3(7.86,31.23) v3(7.93,29.61) v3(7.89,19.28) v3(8.01,69.32) v3(7.95,64.72) v3(8.01,57.99) v3(8.01,51.8) v3(7.98,25.05) v3(7.97,23.29) v3(7.95,12.06) v3(8.01,8.29) v3(8.08,62.31) v3(8.08,62.11) v3(8.09,52.92) v3(8.11,42.8) v3(8.12,40.94) v3(8.05,30.45) v3(8.13,28.15) v3(8.11,27.39) v3(8.19,65.2) v3(8.21,46.47) v3(8.23,44.23) v3(8.14,28.88) v3(8.33,62.62) v3(8.31,52.31) v3(8.26,39.51) v3(8.25,30.06) v3(8.29,22.06) v3(8.24,15.6) v3(8.24,14.41) v3(8.47,65.19) v3(8.5,53.08) v3(8.52,51.52) v3(8.44,48.92) v3(8.48,36.24) v3(8.54,16.78) v3(8.52,12.68) v3(8.51,11.52) v3(8.56,47.6) v3(8.61,27.62) v3(8.57,26.29) v3(8.56,18.55) v3(8.65,68.56) v3(8.67,67.65) v3(8.68,60.6) v3(8.71,41.26) v3(8.67,31.23) v3(8.72,30.69) v3(8.68,15.16) v3(8.79,53.32) v3(8.75,39.92) v3(8.76,29.84) v3(8.79,17.57) v3(8.74,13.84) v3(8.87,63.06) v3(8.87,28.76) v3(8.88,26.68) v3(8.99,69.33) v3(8.94,66) v3(9.01,64.11) v3(9.03,62.3) v3(9.03,62.07) v3(9.03,29.47) v3(9.03,19.75) v3(9.13,55.17) v3(9.12,18.76) v3(9.12,18.36) v3(9.12,17.96) v3(9.07,14.82) v3(9.15,67.32) v3(9.15,64.66) v3(9.14,50.72) v3(9.22,35.5) v3(9.16,30.83) v3(9.16,30.65) v3(9.18,29.07) v3(9.14,27.39) v3(9.19,21.91) v3(9.22,12.67) v3(9.29,63.32) v3(9.34,57.28) v3(9.24,56.56) v3(9.28,54.22) v3(9.24,19.36) v3(9.25,15.79) v3(9.25,14.22) v3(9.27,13.57) v3(9.38,68.63) v3(9.42,51.28) v3(9.41,30.29) v3(9.43,16.09) v3(9.39,15.15) v3(9.45,66.63) v3(9.45,66.41) v3(9.45,65.86) v3(9.49,64.9) v3(9.53,42.25) v3(9.53,39.08) v3(9.45,29.62) v3(9.52,18.77) v3(9.45,17.57) v3(9.53,11.52) v3(9.49,6.41) v3(9.63,65.86) v3(9.63,63.58) v3(9.55,52.51) v3(9.64,28.34) v3(9.57,27.7) v3(9.68,66.63) v3(9.7,63.94) v3(9.71,50.35) v3(9.66,49.5) v3(9.7,29.74) v3(9.73,28.87) v3(9.73,18.39) v3(9.7,17.05) v3(9.71,12.22) v3(9.8,69.3) v3(9.83,68) v3(9.77,66.87) v3(9.75,66.4) v3(9.81,65.86) v3(9.84,65.1) v3(9.74,64.9) v3(9.78,60.65) v3(9.83,51.92) v3(9.77,48.04) v3(9.83,26.49) v3(9.82,17.92) v3(9.81,15.29) v3(9.76,7.99) v3(9.88,66.61) v3(9.9,63.61) v3(9.85,58.1) v3(9.88,52.68) v3(9.88,37.82) v3(9.9,29.48) v3(9.85,17.57) v3(9.93,16.57) v3(9.99,65.86) v3(9.99,62.6) v3(9.99,62.42) v3(9.99,62.23) v3(9.99,62.04) v3(9.99,61.85) v3(9.99,61.66) v3(10,61.47) v3(10.04,22.26) v3(9.96,14.45) v3(9.97,12.68) v3(10.1,67.28) v3(10.1,67.03) v3(10.1,66.72) v3(10.1,66.39) v3(10.09,65.1) v3(10.12,53.77) v3(10.13,30.77) v3(10.07,28.67) v3(10.05,14.95) v3(10.09,13.38) v3(10.18,62.6) v3(10.18,61.85) v3(10.18,61.66) v3(10.19,61.47) v3(10.19,52.98) v3(10.18,35.13) v3(10.17,31.86) v3(10.19,30.21) v3(10.19,22.73) v3(10.23,12.94) v3(10.2,12.38) v3(10.21,11.51) v3(10.29,69.3) v3(10.3,68.48) v3(10.31,18.64) v3(10.25,18.37) v3(10.25,17.57) v3(10.25,16.77) v3(10.25,16.37) v3(10.32,15.93) v3(10.43,67.6) v3(10.36,56.31) v3(10.38,42.21) v3(10.44,67.17) v3(10.44,66.89) v3(10.44,66.4) v3(10.5,65.35) v3(10.5,65.16) v3(10.45,57.79) v3(10.52,54.32) v3(10.49,53.47) v3(10.46,30.77) v3(10.46,29.54) v3(10.5,28.65) v3(10.51,22.06) v3(10.63,45.89) v3(10.58,42.88) v3(10.61,40.09) v3(10.56,38.19) v3(10.58,37.09) v3(10.64,36.34) v3(10.61,30.27) v3(10.58,14.09) v3(10.55,13.16) v3(10.54,12.67) v3(10.67,65.8) v3(10.73,60.32) v3(10.73,59.92) v3(10.73,59.52) v3(10.66,50.41) v3(10.73,25.76) v3(10.65,17.57) v3(10.65,17.17) v3(10.65,16.3) v3(10.72,14.58) v3(10.76,62.23) v3(10.75,61.53) v3(10.77,58.23) v3(10.77,58.05) v3(10.83,50.82) v3(10.8,34.51) v3(10.77,22.48) v3(10.75,11.75) v3(10.89,68.37) v3(10.92,64.3) v3(10.93,63.11) v3(10.91,49.5) v3(10.92,38.26) v3(10.91,28.27) v3(10.86,27.27) v3(10.85,23.1) v3(10.85,12.4) v3(10.86,12.14) v3(10.99,48.9) v3(11.02,31.26) v3(10.94,30.18) v3(11.02,22.32) v3(11.01,18.79) v3(11.02,12.84) v3(11.04,19.35) v3(11.14,39.76) v3(11.14,39.23) v3(11.21,31.59) v3(11.15,29.43) v3(11.17,28.72) v3(11.14,28.25) v3(11.16,26.92) v3(11.16,26.22) v3(11.17,14.47) v3(11.2,14.08) v3(11.28,49.51) v3(11.25,27.96) v3(11.37,68.38) v3(11.41,64.3) v3(11.35,48.03) v3(11.39,40.63) v3(11.39,33.91) v3(11.35,25.6) v3(11.36,25.11) v3(11.41,14.98) v3(11.4,13.75) v3(11.53,69.33) v3(11.44,66.63) v3(11.53,63.69) v3(11.48,37.46) v3(11.54,35.79) v3(11.49,32.91) v3(11.49,32.13) v3(11.47,31.05) v3(11.47,30.42) v3(11.52,23.39) v3(11.53,22.87) v3(11.46,18.27) v3(11.46,17.2) v3(11.45,16.39) v3(11.59,66.3) v3(11.63,29.81) v3(11.58,27.51) v3(11.65,19.15) v3(11.73,13.65) v3(11.83,59.67) v3(11.83,59.49) v3(11.84,58.22) v3(11.84,58.03) v3(11.8,49.69) v3(11.84,41.08) v3(11.75,29.23) v3(11.78,17.85) v3(11.87,68.38) v3(11.93,62.62) v3(11.9,53.12) v3(12,36.44) v3(12,35.44) v3(11.95,28.38) v3(12,27.42) v3(11.96,21.59) v3(11.96,14.47) v3(12.07,18.01) v3(12.09,13.4) v3(12.09,13.01) v3(12.08,10.95) v3(12.06,10.45) v3(12.16,46.09) v3(12.21,42.37) v3(12.17,39.61) v3(12.16,17.01) v3(12.26,50.92) v3(12.25,44.14) v3(12.34,14.47) v3(12.32,13.2) v3(12.36,66.63) v3(12.39,64.03) v3(12.35,59.57) v3(12.4,57.27) v3(12.43,38.29) v3(12.37,15.02) v3(12.42,11.08) v3(12.42,10.54) v3(12.46,62.85) v3(12.52,34.25) v3(12.54,33.54) v3(12.48,18.17) v3(12.49,17.21) v3(12.44,11.6) v3(12.49,9.98) v3(12.56,58.38) v3(12.55,34.94) v3(12.63,33.09) v3(12.63,32.71) v3(12.6,31.98) v3(12.6,31.35) v3(12.62,26.03) v3(12.63,25.66) v3(12.56,19.71) v3(12.63,14.39) v3(12.73,65.29) v3(12.73,64.3) v3(12.66,40.18) v3(12.73,37.27) v3(12.68,35.37) v3(12.71,30.66) v3(12.67,21.72) v3(12.68,20.26) v3(12.66,14.01) v3(12.86,48.24) v3(12.88,46.41) v3(12.86,44.35) v3(12.86,38.55) v3(12.92,37.47) v3(12.89,29.57) v3(13.03,68.44) v3(12.98,65.78) v3(13,61.17) v3(12.95,50.2) v3(12.97,49.47) v3(12.94,20.52) v3(13.09,41.08) v3(13.09,35.72) v3(13.12,30.63) v3(13.07,22.57) v3(13.05,13.96) v3(13.09,13.25) v3(13.11,12.8) v3(13.18,63.03) v3(13.15,40.47) v3(13.23,39.27) v3(13.2,28.75) v3(13.22,14.85) v3(13.16,14.59) v3(13.19,12.55) v3(13.15,12.25) v3(13.24,59.16) v3(13.33,37.83) v3(13.33,32.5) v3(13.27,31.19) v3(13.24,29.9) v3(13.29,28.13) v3(13.3,27.42) v3(13.34,17.26) v3(13.43,56.61) v3(13.4,35.46) v3(13.36,26.56) v3(13.47,53.76) v3(13.54,37.28) v3(13.52,27.74) v3(13.44,23.59) v3(13.53,21.82) v3(13.51,9.98) v3(13.63,64.3) v3(13.58,53.32) v3(13.55,36.72) v3(13.56,24.65) v3(13.56,24.46) v3(13.64,23.59) v3(13.55,19.01) v3(13.58,15.38) v3(13.67,66.64) v3(13.68,60.76) v3(13.68,55.42) v3(13.68,54.91) v3(13.68,54.19) v3(13.69,46.24) v3(13.67,44.1) v3(13.65,42.38) v3(13.71,18.27) v3(13.77,58.83) v3(13.8,53.8) v3(13.76,39.73) v3(13.81,25.89) v3(13.93,37.82) v3(13.86,37.24) v3(13.91,28.37) v3(13.88,14.6) v3(13.85,13.43) v3(13.86,13.16) v3(13.85,12.86) v3(13.87,12.38) v3(13.96,65.79) v3(14.04,64.04) v3(13.97,55.97) v3(13.95,50.69) v3(14.03,34.64) v3(13.97,30.9) v3(13.97,30.4) v3(14.01,30.06) v3(14.01,29.49) v3(13.98,26.67) v3(14.04,24.74) v3(14.13,68.75) v3(14.08,65.29) v3(14.05,58.81) v3(14.21,57.49) v3(14.21,40.17) v3(14.22,35.73) v3(14.19,29.12) v3(14.17,15.23) v3(14.27,58.41) v3(14.34,55.97) v3(14.3,50.5) v3(14.31,38.6) v3(14.28,32.19) v3(14.27,25.17) v3(14.26,24.25) v3(14.38,55.38) v3(14.42,12.4) v3(14.4,9.98) v3(14.41,9.06) v3(14.54,66.64) v3(14.52,53.33) v3(14.44,49.49) v3(14.44,37.84) v3(14.53,32.44) v3(14.52,31.68) v3(14.46,14.8) v3(14.53,11.67) v3(14.47,10.75) v3(14.55,64.32) v3(14.59,47.08) v3(14.62,37.24) v3(14.58,8.15) v3(14.65,63.03) v3(14.73,39.75) v3(14.65,38.6) v3(14.66,36.58) v3(14.69,29.88) v3(14.68,28.94) v3(14.7,17.15) v3(14.67,11.24) v3(14.71,9.98) v3(14.77,68.74) v3(14.8,55.98) v3(14.78,41.08) v3(14.84,35.43) v3(14.78,32.68) v3(14.74,29.23) v3(14.81,22.46) v3(14.81,20.64) v3(14.74,18.87) v3(14.86,45.15) v3(14.9,40.18) v3(14.85,39.21) v3(14.86,38.25) v3(14.86,34.74) v3(14.93,18.01) v3(14.93,15.72) v3(14.92,14.18) v3(14.91,8.69) v3(15.02,69.13) v3(14.97,66.27) v3(15.02,62.43) v3(14.95,43.82) v3(15.02,38.5) v3(15.03,32.44) v3(15.01,27.08) v3(15.01,25.95) v3(15.03,24.97) v3(15.03,24.22) v3(15.03,23.37) v3(14.96,16.55) v3(15.04,12.58) v3(15.11,53.33) v3(15.05,37.66) v3(15.13,30.04) v3(15.12,28.92) v3(15.11,27.98) v3(15.11,21.88) v3(15.07,20.06) v3(15.12,10.8) v3(15.18,58.34) v3(15.18,31.83) v3(15.18,11.88) v3(15.17,11.26) v3(15.3,63.6) v3(15.28,61.07) v3(15.3,57.67) v3(15.33,38.76) v3(15.33,37.48) v3(15.33,35.73) v3(15.34,34.74) v3(15.28,32.68) v3(15.31,32.22) v3(15.29,16.36) v3(15.29,15.81) v3(15.29,15.35) v3(15.38,65.79) v3(15.35,39.77) v3(15.4,37.75) v3(15.37,18.93) v3(15.41,8.15) v3(15.5,68.13) v3(15.49,57.67) v3(15.53,50.08) v3(15.53,49.49) v3(15.51,49) v3(15.52,32.94) v3(15.51,26.51) v3(15.45,26.08) v3(15.47,23) v3(15.45,17.76) v3(15.44,17.35) v3(15.57,53.64) v3(15.6,44.17) v3(15.56,42.37) v3(15.6,40.01) v3(15.62,37.99) v3(15.6,26.84) v3(15.61,24.35) v3(15.56,14.06) v3(15.7,56.26) v3(15.72,32.19) v3(15.72,31.84) v3(15.7,31.41) v3(15.73,29.67) v3(15.7,27.09) v3(15.71,23.74) v3(15.71,23.42) v3(15.68,12.63) v3(15.74,43.34) v3(15.8,38.28) v3(15.78,35.38) v3(15.78,28.38) v3(15.78,27.98) v3(15.82,25.31) v3(15.79,10.71) v3(15.93,51.35) v3(15.93,51.17) v3(15.91,49.5) v3(15.86,40.31) v3(15.86,38.76) v3(15.86,30.93) v3(15.97,38.54) v3(15.95,37.54) v3(16.11,53.62) v3(16.05,52.34) v3(16.09,39.35) v3(16.09,39.08) v3(16.09,38.84) v3(16.04,36.58) v3(16.05,24.99) v3(16.11,13.99) v3(16.11,11.42) v3(16.23,67.53) v3(16.19,66.59) v3(16.2,66.02) v3(16.22,65.12) v3(16.15,64.8) v3(16.14,41.23) v3(16.2,39.83) v3(16.21,39.59) v3(16.21,35.72) v3(16.14,34.48) v3(16.14,23.86) v3(16.18,23.39) v3(16.18,22.96) v3(16.23,22.4) v3(16.28,63.92) v3(16.33,50.07) v3(16.31,29.95) v3(16.26,28.79) v3(16.42,38.76) v3(16.39,17.04) v3(16.38,16.3) v3(16.39,15.89) v3(16.4,15.46) v3(16.39,14.99) v3(16.4,11.21) v3(16.39,10.7) v3(16.44,58.37) v3(16.54,55.9) v3(16.44,27.07) v3(16.48,17.73) v3(16.51,8.16) v3(16.57,67.77) v3(16.62,60.35) v3(16.59,55.06) v3(16.6,49.02) v3(16.6,37.48) v3(16.62,35.39) v3(16.6,27.98) v3(16.6,23.58) v3(16.59,21.65) v3(16.68,63.08) v3(16.69,40.44) v3(16.71,32.24) v3(16.72,31.86) v3(16.72,31.06) v3(16.66,20.11) v3(16.66,10.25) v3(16.81,38.76) v3(16.81,34) v3(16.8,19.6) v3(16.75,12.15) v3(16.75,11.65) v3(16.78,8.8) v3(16.92,58.73) v3(16.87,23.05) v3(16.88,20.6) v3(16.86,11.07) v3(16.96,69.31) v3(16.98,49.5) v3(16.95,46.41) v3(16.97,32.63) v3(16.95,13.21) v3(17.13,27.98) v3(17.13,26.8) v3(17.09,26.46) v3(17.11,25.75) v3(17.05,18.75) v3(17.2,38.76) v3(17.14,28.38) v3(17.18,24.87) v3(17.18,24.03) v3(17.22,20.09) v3(17.15,15.16) v3(17.18,8.45) v3(17.3,68.11) v3(17.32,37.53) v3(17.29,9.45) v3(17.4,63.21) v3(17.43,39.85) v3(17.36,34.61) v3(17.36,34.43) v3(17.37,17.78) v3(17.51,63.9) v3(17.53,35.39) v3(17.5,32.09) v3(17.54,20.41) v3(17.5,18.37) v3(17.5,17.01) v3(17.49,16.12) v3(17.49,15.74) v3(17.49,15.34) v3(17.49,14.97) v3(17.46,12.97) v3(17.5,12.75) v3(17.46,11.86) v3(17.46,10.88) v3(17.58,66.1) v3(17.58,65.32) v3(17.58,52.99) v3(17.61,51.96) v3(17.59,39.67) v3(17.57,38.57) v3(17.57,38.39) v3(17.59,36.58) v3(17.62,27.49) v3(17.61,26.84) v3(17.64,26) v3(17.61,24.38) v3(17.66,38) v3(17.66,31.64) v3(17.69,28.71) v3(17.75,38.57) v3(17.75,38.39) v3(17.75,30.9) v3(17.78,23.07) v3(17.83,22.41) v3(17.75,10.05) v3(17.92,67.56) v3(17.91,49.5) v3(17.91,13.27) v3(18.01,59.43) v3(18,39.72) v3(18.01,38.02) v3(17.99,35.71) v3(18.03,31.42) v3(17.97,29.22) v3(18.04,24.7) v3(18.04,24.22) v3(18.01,15.35) v3(18.06,64.87) v3(18.07,60.13) v3(18.06,25.79) v3(18.05,25.33) v3(18.08,23.26) v3(18.07,21.29) v3(18.13,16.83) v3(18.18,66.86) v3(18.23,55.23) v3(18.18,41.51) v3(18.17,40.44) v3(18.15,39.29) v3(18.15,38.81) v3(18.16,38.41) v3(18.23,37.25) v3(18.22,28.28) v3(18.2,27.04) v3(18.21,26.31) v3(18.18,19.8) v3(18.22,19.3) v3(18.16,11.79) v3(18.24,63.61) v3(18.26,62.36) v3(18.27,61.6) v3(18.31,28.78) v3(18.26,25.52) v3(18.29,20.94) v3(18.24,20.43) v3(18.32,18.93) v3(18.24,18.43) v3(18.24,17.43) v3(18.29,14.55) v3(18.27,10.47) v3(18.39,23.24) v3(18.45,63.31) v3(18.49,56.01) v3(18.46,36.73) v3(18.48,25.53) v3(18.47,24.95) v3(18.48,24.24) v3(18.49,22.24) v3(18.46,12.8) v3(18.49,12.07) v3(18.62,51.33) v3(18.54,28.3) v3(18.64,27.88) v3(18.55,27.45) v3(18.6,14.97) v3(18.67,69.12) v3(18.72,57.74) v3(18.68,42.37) v3(18.69,40.01) v3(18.66,31.21) v3(18.73,20.58) v3(18.73,16.72) v3(18.77,55.7) v3(18.76,49.49) v3(18.75,29.39) v3(18.83,19.84) v3(18.79,17.62) v3(18.78,16.24) v3(18.83,10.46) v3(18.93,59.04) v3(18.88,37.55) v3(18.85,28.56) v3(18.91,27.46) v3(18.87,26.26) v3(18.85,20.98) v3(19.01,60.97) v3(19.01,60.79) v3(19.01,60.61) v3(18.97,35.38) v3(19.01,27.08) v3(19.02,21.73) v3(18.94,16.75) v3(19.02,12.85) v3(18.99,11.29) v3(19.09,64.31) v3(19.06,29.78) v3(19.06,29.01) v3(19.12,25.17) v3(19.13,24.55) v3(19.13,11.81) v3(19.22,58.15) v3(19.19,52.25) v3(19.14,51.67) v3(19.24,40.04) v3(19.16,32.86) v3(19.2,31.35) v3(19.14,30.17) v3(19.2,26.05) v3(19.2,18.32) v3(19.28,56.71) v3(19.28,55.46) v3(19.26,49.4) v3(19.29,48.6) v3(19.25,38.15) v3(19.3,27.46) v3(19.31,26.69) v3(19.34,25.31) v3(19.28,18.56) v3(19.43,37.19) v3(19.35,32.07) v3(19.35,16.25) v3(19.51,61.01) v3(19.52,59.87) v3(19.44,47.11) v3(19.45,29.78) v3(19.45,29.01) v3(19.46,26.37) v3(19.44,22.25) v3(19.6,68.72) v3(19.59,29.39) v3(19.63,25.76) v3(19.54,23.41) v3(19.54,21.26) v3(19.59,20.48) v3(19.7,57.66) v3(19.72,55.73) v3(19.7,50.94) v3(19.7,31.34) v3(19.69,27.79) v3(19.66,27.43) v3(19.69,26.69) v3(19.71,24.83) v3(19.69,12.04) v3(19.67,10.74) v3(19.84,66.91) v3(19.77,35.43) v3(19.75,24.02) v3(19.79,21.75) v3(19.82,17.23) v3(19.84,10.48) v3(19.89,32.98) v3(19.84,29.01) v3(19.85,15.62) v3(19.86,14.9) v3(19.86,13) v3(19.94,55.48) v3(19.98,24.42) v3(20.08,35.86) v3(20.08,34.19) v3(20.06,32.07) v3(20.06,30.19) v3(20.08,29.87) v3(20.04,23.37) v3(20.19,57.18) v3(20.21,56.72) v3(20.24,24.13) v3(20.19,18.02) v3(20.21,16.57) v3(20.21,11.6) v3(20.19,10.76) v3(20.25,48.59) v3(20.3,29.57) v3(20.28,14.91) v3(20.38,52.89) v3(20.36,22.26) v3(20.46,57.46) v3(20.5,47.54) v3(20.44,26.6) v3(20.52,23.91) v3(20.5,20.73) v3(20.53,17.65) v3(20.61,63.12) v3(20.56,62.13) v3(20.55,60.71) v3(20.6,53.81) v3(20.56,33.39) v3(20.57,31.3) v3(20.6,28.94) v3(20.54,28.22) v3(20.58,24.93) v3(20.58,23.25) v3(20.54,18.59) v3(20.62,17.23) v3(20.61,11.82) v3(20.63,10.49) v3(20.69,57.17) v3(20.71,56.72) v3(20.71,55.24) v3(20.68,36.4) v3(20.65,27.35) v3(20.73,19.49) v3(20.72,18.18) v3(20.7,16.24) v3(20.76,57.69) v3(20.84,40.04) v3(20.82,29.58) v3(20.79,21.75) v3(20.84,20.7) v3(20.84,12.92) v3(20.93,56.95) v3(20.86,24.61) v3(20.84,20.51) v3(20.99,57.49) v3(20.95,56.47) v3(21.01,32.89) v3(21.03,32.09) v3(20.94,23.9) v3(21.01,19.91) v3(20.95,17.66) v3(21.05,63.1) v3(21.1,60.53) v3(21.11,29.12) v3(21.09,28.7) v3(21.13,24.52) v3(21.09,14.91) v3(21.1,10.47) v3(21.15,68.69) v3(21.23,57.24) v3(21.16,49.29) v3(21.21,48.88) v3(21.21,41.51) v3(21.17,34.36) v3(21.15,26.35) v3(21.23,24.29) v3(21.26,66.53) v3(21.26,48.28) v3(21.26,25.49) v3(21.33,22.26) v3(21.29,18.17) v3(21.24,16.95) v3(21.24,14.16) v3(21.41,32.5) v3(21.42,24.57) v3(21.5,50.11) v3(21.52,26.56) v3(21.44,23.86) v3(21.51,19.07) v3(21.61,63.12) v3(21.63,43.35) v3(21.63,37.09) v3(21.54,31.33) v3(21.57,29.61) v3(21.54,29.12) v3(21.56,28.68) v3(21.58,23.25) v3(21.63,21.52) v3(21.57,10.98) v3(21.57,10.44) v3(21.66,59.85) v3(21.67,44.17) v3(21.7,24.67) v3(21.67,23.75) v3(21.64,17.48) v3(21.65,10.08) v3(21.8,61.73) v3(21.8,61.55) v3(21.77,53.02) v3(21.8,52.31) v3(21.81,47.84) v3(21.84,40.04) v3(21.84,32.05) v3(21.92,23.25) v3(21.98,61.73) v3(21.98,61.55) v3(21.95,48.93) v3(22.02,48.18) v3(22.02,15.62) v3(22.05,50.53) v3(22.05,29.13) v3(22.04,14.91) v3(22.19,58.7) v3(22.23,55.27) v3(22.17,53.69) v3(22.16,47.5) v3(22.17,42.39) v3(22.14,40.6) v3(22.19,31.65) v3(22.23,31.12) v3(22.15,30.14) v3(22.15,9.63) v3(22.3,46.3) v3(22.26,28.69) v3(22.28,19.45) v3(22.25,13.38) v3(22.27,12.83) v3(22.39,67.65) v3(22.39,58.74) v3(22.42,47.84) v3(22.42,47.23) v3(22.38,27.34) v3(22.37,26.55) v3(22.39,26.23) v3(22.36,24.29) v3(22.43,23.24) v3(22.44,58.95) v3(22.45,57.41) v3(22.44,55.98) v3(22.48,55.02) v3(22.45,48.94) v3(22.45,30.84) v3(22.52,29.55) v3(22.45,24.73) v3(22.48,22.25) v3(22.44,14.17) v3(22.52,11.67) v3(22.63,48.59) v3(22.54,34.67) v3(22.55,11.26) v3(22.67,53.69) v3(22.73,31.61) v3(22.68,25.87) v3(22.66,21.09) v3(22.81,42.34) v3(22.84,40.04) v3(22.75,27.75) v3(22.76,27.34) v3(22.76,26.55) v3(22.78,17.83) v3(22.85,68.69) v3(22.91,63.09) v3(22.91,60.61) v3(22.87,52.38) v3(22.88,50.98) v3(22.9,48.06) v3(22.93,23.25) v3(22.85,12.82) v3(22.99,47.73) v3(22.98,31.36) v3(23.03,29.65) v3(23.03,26.25) v3(22.97,14.17) v3(23.04,29.01) v3(23.13,21.55) v3(23.04,14.91) v3(23.22,31.61) v3(23.16,27.84) v3(23.16,26.55) v3(23.18,23.73) v3(23.25,25.21) v3(23.32,9.61) v3(23.43,63.37) v3(23.43,62.52) v3(23.38,23.33) v3(23.53,60.02) v3(23.51,52.38) v3(23.47,32.35) v3(23.47,31.36) v3(23.48,28.45) v3(23.48,27.95) v3(23.47,27.19) v3(23.49,26.56) v3(23.47,21.11) v3(23.47,20.69) v3(23.53,16.96) v3(23.46,16.39) v3(23.45,14.17) v3(23.46,13.39) v3(23.6,51.78) v3(23.56,50.97) v3(23.62,48.55) v3(23.62,47.95) v3(23.63,24.4) v3(23.61,19.76) v3(23.67,29.9) v3(23.65,29.41) v3(23.66,25.82) v3(23.71,23.71) v3(23.76,36.03) v3(23.88,60.36) v3(23.91,48.37) v3(23.87,35.38) v3(23.86,34.66) v3(23.86,27.24) v3(23.93,23.43) v3(23.93,23.24) v3(23.97,59.57) v3(24.01,54.06) v3(24.01,50.97) v3(23.97,31.86) v3(23.97,31.36) v3(23.94,28.92) v3(23.95,28.47) v3(23.97,27.98) v3(24.01,25.35) v3(24.1,61.66) v3(24.05,58.77) v3(24.07,57.38) v3(24.09,56.84) v3(24.12,47.73) v3(24.11,47.43) v3(24.07,29.99) v3(24.1,26.56) v3(24.04,17.98) v3(24.1,14.72) v3(24.15,63.21) v3(24.17,31.62) v3(24.16,29.41) v3(24.14,11.94) v3(24.31,64.24) v3(24.32,53.64) v3(24.31,35.74) v3(24.31,9.62) v3(24.4,41.1) v3(24.41,25.3) v3(24.42,24.29) v3(24.42,23.37) v3(24.49,35.05) v3(24.45,28.91) v3(24.44,28.47) v3(24.45,27.98) v3(24.52,27.03) v3(24.49,14.15) v3(24.63,68.7) v3(24.6,38.28) v3(24.58,23.53) v3(24.71,55.06) v3(24.67,54.33) v3(24.72,52.82) v3(24.71,37.7) v3(24.71,33.59) v3(24.71,33.1) v3(24.72,28.02) v3(24.73,27.5) v3(24.73,26.58) v3(24.65,25.83) v3(24.66,13.38) v3(24.84,61.78) v3(24.77,49.1) v3(24.93,30.5) v3(24.85,15.7) v3(24.95,63.35) v3(24.96,33.84) v3(24.96,32.85) v3(25.01,31.36) v3(24.97,29.53) v3(24.97,28.47) v3(25.03,26.13) v3(24.99,20.92) v3(25,14.15) v3(24.94,9.61) v3(25.05,45.55) v3(25.05,28.96) v3(25.12,23.28) v3(25.11,20.01) v3(25.13,19.21) v3(25.18,64.97) v3(25.16,47.5) v3(25.17,41.61) v3(25.23,40.28) v3(25.2,33.1) v3(25.15,29.77) v3(25.22,24.59) v3(25.21,23.62) v3(25.26,57.36) v3(25.28,55.55) v3(25.26,28.08) v3(25.29,22.23) v3(25.25,21.46) v3(25.34,19.97) v3(25.34,14.72) v3(25.27,10.07) v3(25.38,26.87) v3(25.4,10.19) v3(25.45,52.13) v3(25.45,50.94) v3(25.48,29.53) v3(25.56,42.17) v3(25.6,26.53) v3(25.55,25.7) v3(25.56,25.43) v3(25.54,25.19) v3(25.55,21.85) v3(25.68,37.9) v3(25.69,35.83) v3(25.72,29.05) v3(25.71,27.36) v3(25.71,26.98) v3(25.67,24.5) v3(25.72,12.78) v3(25.79,29.88) v3(25.82,28.51) v3(25.83,15.76) v3(25.85,64.93) v3(25.9,63.2) v3(25.88,58.56) v3(25.87,39.74) v3(25.92,31.89) v3(25.85,23.39) v3(25.86,19.38) v3(25.97,57.55) v3(26.03,55.77) v3(25.99,31.34) v3(26.03,24.16) v3(25.96,20.53) v3(26.07,63.98) v3(26.06,36.8) v3(26.09,36.28) v3(26.09,22.8) v3(26.09,14.19) v3(26.16,47.5) v3(26.23,46.47) v3(26.24,34.98) v3(26.23,26.62) v3(26.24,22.38) v3(26.15,9.64) v3(26.34,39.23) v3(26.32,15.05) v3(26.36,49.43) v3(26.4,44.17) v3(26.39,35.81) v3(26.4,31.37) v3(26.43,13.12) v3(26.47,68.7) v3(26.44,33.34) v3(26.49,31.87) v3(26.52,26.92) v3(26.47,18.57) v3(26.63,47.2) v3(26.57,42.27) v3(26.6,25.73) v3(26.58,25.09) v3(26.57,23.4) v3(26.54,22.18) v3(26.65,63.35) v3(26.74,51.83) v3(26.69,34.09) v3(26.69,33.1) v3(26.7,30.62) v3(26.68,30.07) v3(26.69,24.07) v3(26.69,21.91) v3(26.67,19.92) v3(26.71,19.2) v3(26.79,31.02) v3(26.77,28.79) v3(26.76,27.52) v3(26.75,26.35) v3(26.75,24.36) v3(26.77,23.9) v3(26.79,17.18) v3(26.82,12.32) v3(26.9,63.3) v3(26.86,54.68) v3(26.93,53.94) v3(26.87,50.2) v3(26.86,39.72) v3(26.87,36.53) v3(26.87,18.43) v3(26.92,16.45) v3(26.88,15.96) v3(27,21.12) v3(27.03,11.34) v3(27.04,26.91) v3(27.13,22.49) v3(27.06,21.96) v3(27.1,19.39) v3(27.22,52.21) v3(27.2,40.53) v3(27.18,33.59) v3(27.16,29.59) v3(27.21,28.05) v3(27.17,20.05) v3(27.15,15.42) v3(27.18,14.91) v3(27.19,14.3) v3(27.19,13.64) v3(27.17,12.98) v3(27.33,67.24) v3(27.3,57.34) v3(27.3,29.07) v3(27.26,26.51) v3(27.3,26.15) v3(27.31,24.4) v3(27.29,23.38) v3(27.36,41.99) v3(27.34,39.23) v3(27.4,35.98) v3(27.34,30.15) v3(27.35,27.23) v3(27.43,24.82) v3(27.37,17.97) v3(27.36,9.64) v3(27.52,47.69) v3(27.5,46.55) v3(27.56,63.7) v3(27.56,62.83) v3(27.63,58.61) v3(27.59,51.69) v3(27.62,49.88) v3(27.63,38.21) v3(27.61,35.07) v3(27.56,24.15) v3(27.57,22.24) v3(27.54,21.88) v3(27.63,20.35) v3(27.61,17.88) v3(27.73,43.78) v3(27.68,34.64) v3(27.69,31.12) v3(27.71,25.62) v3(27.73,23.93) v3(27.73,16.76) v3(27.7,13.25) v3(27.65,12.45) v3(27.8,64.53) v3(27.82,52.79) v3(27.76,27.36) v3(27.76,24.39) v3(27.79,23.38) v3(27.76,22.24) v3(27.78,16.05) v3(27.83,12.86) v3(27.85,67.91) v3(27.9,37.6) v3(27.85,30.43) v3(27.93,26.4) v3(27.92,11.22) v3(27.96,63.68) v3(27.97,63.36) v3(27.95,32.18) v3(27.98,24.62) v3(28.09,40.84) v3(28.1,28.06) v3(28.04,26.99) v3(28.04,21.88) v3(28.08,18.85) v3(28.12,18.26) v3(28.07,15.27) v3(28.09,14.48) v3(28.09,13.75) v3(28.06,13.29) v3(28.16,62.6) v3(28.15,56.89) v3(28.19,46.29) v3(28.21,35.06) v3(28.22,28.97) v3(28.2,25.62) v3(28.24,23.43) v3(28.21,22.52) v3(28.19,20.97) v3(28.24,17.04) v3(28.32,68.7) v3(28.27,56.4) v3(28.32,30.72) v3(28.28,23.92) v3(28.29,21.88) v3(28.25,16.41) v3(28.41,51.74) v3(28.4,31.88) v3(28.4,29.74) v3(28.34,24.89) v3(28.36,18.97) v3(28.39,14.24) v3(28.39,14.02) v3(28.39,12.93) v3(28.39,12.72) v3(28.36,12.03) v3(28.37,9.35) v3(28.49,19.22) v3(28.5,15.54) v3(28.6,54.86) v3(28.57,32.84) v3(28.63,31.22) v3(28.63,26.55) v3(28.63,26.09) v3(28.54,22.13) v3(28.63,21.87) v3(28.69,62.32) v3(28.65,25.67) v3(28.69,23.38) v3(28.75,67.96) v3(28.78,54.67) v3(28.79,22.38) v3(28.82,21.62) v3(28.76,14.91) v3(28.83,14.23) v3(28.83,14.02) v3(28.82,12.93) v3(28.83,12.72) v3(28.78,10.8) v3(28.86,39.43) v3(28.91,33.16) v3(28.85,32.26) v3(28.88,28.17) v3(28.84,27.63) v3(28.88,24.7) v3(28.84,23.78) v3(28.94,17.82) v3(28.85,10.3) v3(29.02,67.52) v3(29.01,16.88) v3(29.01,16.43) v3(28.96,11.76) v3(29.02,8.28) v3(29.01,7.11) v3(28.95,4.78) v3(28.97,3.76) v3(28.97,2.65) v3(28.97,1.41) v3(29.11,65.82) v3(29.05,56.27) v3(29.07,54.32) v3(29.11,47.43) v3(29.12,41.74) v3(29.13,31.75) v3(29.05,29.47) v3(29.07,26.99) v3(29.12,25.66) v3(29.04,22.63) v3(29.12,13.46) v3(29.23,26.52) v3(29.21,24.7) v3(29.16,24.03) v3(29.17,14.21) v3(29.23,11.87) v3(29.26,60.02) v3(29.26,59.62) v3(29.26,58.72) v3(29.26,58.32) v3(29.28,40.3) v3(29.32,20.99) v3(29.28,19.45) v3(29.32,12.6) v3(29.42,63.82) v3(29.35,62.65) v3(29.4,29.91) v3(29.38,29.22) v3(29.37,28.12) v3(29.35,14.27) v3(29.38,13.08) v3(29.42,10.8) v3(29.45,56.27) v3(29.49,54.86) v3(29.49,54.32) v3(29.51,36.6) v3(29.48,32.77) v3(29.45,27.55) v3(29.47,15.39) v3(29.56,37.51) v3(29.62,33.86) v3(29.63,32.21) v3(29.59,27.88) v3(29.62,24.21) v3(29.63,23.34) v3(29.63,22.23) v3(29.55,16.88) v3(29.54,16.11) v3(29.58,15.74) v3(29.57,11.43) v3(29.56,10.07) v3(29.66,67.91) v3(29.68,61.74) v3(29.69,47.44) v3(29.7,41.54) v3(29.69,35.98) v3(29.69,34.98) v3(29.74,24.72) v3(29.74,22.59) v3(29.74,16.17) v3(29.67,13.58) v3(29.67,13.37) v3(29.74,3.78) v3(29.75,64.83) v3(29.76,39.81) v3(29.77,38.54) v3(29.75,30.68) v3(29.8,25.55) v3(29.8,14.53) v3(29.75,0.32) v3(29.93,61.11) v3(29.87,34.23) v3(29.92,31.58) v3(29.91,28.43) v3(29.89,27.79) v3(29.94,16.39) v3(29.92,15.08) v3(29.94,12.23) v3(29.99,54.3) v3(30.02,51.75) v3(29.97,46.8) v3(29.95,30.89) v3(30.03,15.88) v3(30.13,32.65) v3(30.09,26.17) v3(30.08,25.34) v3(30.09,24.59) v3(30.1,22.06) v3(30.06,20.21) v3(30.04,17.26) v3(30.1,13.58) v3(30.11,13.37) v3(30.17,68.7) v3(30.21,63.02) v3(30.17,62.41) v3(30.2,54.61) v3(30.22,50.76) v3(30.22,48.86) v3(30.2,36.03) v3(30.24,35.48) v3(30.24,34.63) v3(30.19,33.04) v3(30.19,26.38) v3(30.21,25.86) v3(30.28,30.4) v3(30.29,15.68) v3(30.26,11.64) v3(30.38,28.19) v3(30.36,27.65) v3(30.41,22.6) v3(30.44,15.29) v3(30.39,14.3) v3(30.39,13.83) v3(30.39,12.93) v3(30.38,12.46) v3(30.5,61.5) v3(30.49,53.97) v3(30.48,47.34) v3(30.48,43.63) v3(30.47,39) v3(30.51,26.96) v3(30.57,67.91) v3(30.59,51.57) v3(30.62,40.76) v3(30.55,36.52) v3(30.59,33.98) v3(30.58,30.53) v3(30.55,24.16) v3(30.62,23.5) v3(30.57,21.54) v3(30.64,18.56) v3(30.62,17.13) v3(30.6,0.86) v3(30.73,47.81) v3(30.69,33.48) v3(30.69,28.8) v3(30.65,20.87) v3(30.71,20.29) v3(30.65,19.79) v3(30.65,17.65) v3(30.72,13.72) v3(30.7,12.36) v3(30.8,32.68) v3(30.81,31.04) v3(30.8,29.93) v3(30.82,23.5) v3(30.82,14.52) v3(30.94,63.42) v3(30.92,36.27) v3(30.84,26.07) v3(30.94,20.79) v3(30.86,15.09) v3(30.92,11.94) v3(30.99,62.65) v3(30.97,60.91) v3(31.02,50.3) v3(31,34.98) v3(31.11,46.67) v3(31.12,41.74) v3(31.12,38.36) v3(31.09,37.2) v3(31.12,34.41) v3(31.09,24.78) v3(31.08,24.16) v3(31.12,20.5) v3(31.13,19.47) v3(31.13,18.96) v3(31.13,15.88) v3(31.1,5.01) v3(31.08,4.32) v3(31.1,3.63) v3(31.1,2.96) v3(31.11,2.22) v3(31.23,51.54) v3(31.19,51.29) v3(31.17,39.25) v3(31.14,29.68) v3(31.23,28.09) v3(31.19,26.53) v3(31.21,21.61) v3(31.21,20.92) v3(31.14,20.15) v3(31.14,18.32) v3(31.14,17.64) v3(31.15,16.97) v3(31.23,12.46) v3(31.2,6.9) v3(31.2,6.68) v3(31.24,62.12) v3(31.24,61.72) v3(31.29,60.56) v3(31.24,59.89) v3(31.27,51.02) v3(31.24,48.06) v3(31.24,33.38) v3(31.29,31.54) v3(31.29,23.51) v3(31.24,22.19) v3(31.27,19.89) v3(31.28,13.72) v3(31.31,12.93) v3(31.42,66.39) v3(31.35,65.69) v3(31.37,63.88) v3(31.37,43.89) v3(31.38,43.44) v3(31.35,32.75) v3(31.38,27.59) v3(31.34,19.63) v3(31.4,19.21) v3(31.41,15.52) v3(31.44,6.64) v3(31.51,68.69) v3(31.54,59.55) v3(31.52,52.17) v3(31.53,40.34) v3(31.5,27.11) v3(31.49,26.19) v3(31.49,25.19) v3(31.49,24.19) v3(31.54,19.7) v3(31.49,18.58) v3(31.48,17.94) v3(31.49,14.98) v3(31.49,14.23) v3(31.48,8.69) v3(31.52,7.49) v3(31.5,1.16) v3(31.6,67.01) v3(31.56,31.14) v3(31.57,17.35) v3(31.59,16.23) v3(31.63,13.55) v3(31.63,13.29) v3(31.64,6.95) v3(31.7,41.54) v3(31.66,23.76) v3(31.67,23.32) v3(31.73,22.5) v3(31.78,52.25) v3(31.82,46.85) v3(31.81,29.09) v3(31.78,21.79) v3(31.74,19) v3(31.75,18.2) v3(31.78,13.12) v3(31.79,5.04) v3(31.79,3.62) v3(31.79,2.21) v3(31.79,1.45) v3(31.92,60.57) v3(31.88,38.81) v3(31.86,37.61) v3(31.89,36.4) v3(31.88,35.22) v3(31.88,33.66) v3(31.89,32.63) v3(31.92,20.91) v3(31.94,19.76) v3(31.93,15.56) v3(31.87,13.85) v3(31.99,52.02) v3(31.99,26.19) v3(32.03,25.05) v3(31.98,19.39) v3(31.96,18.19) v3(32.02,17.47) v3(32,16.57) v3(31.97,14.56) v3(31.96,14.13) v3(32,13.12) v3(32.1,65.72) v3(32.09,47.83) v3(32.1,28.09) v3(32.09,22.77) v3(32.05,12.5) v3(32.12,8.16) v3(32.07,7.49) v3(32.07,6.99) v3(32.09,1.14) v3(32.17,66.43) v3(32.2,59.94) v3(32.18,39.05) v3(32.19,31.98) v3(32.19,30.98) v3(32.19,29.98) v3(32.22,15.24) v3(32.17,13.85) v3(32.33,60.79) v3(32.26,52.01) v3(32.32,38.93) v3(32.25,28.67) v3(32.27,14.44) v3(32.38,25.45) v3(32.42,17.17) v3(32.37,14.11) v3(32.4,13.12) v3(32.43,5.58) v3(32.41,5.04) v3(32.52,60.11) v3(32.52,53.72) v3(32.5,48.49) v3(32.47,43.24) v3(32.46,38.8) v3(32.51,33.38) v3(32.45,27.6) v3(32.52,27.09) v3(32.49,22.92) v3(32.47,22.54) v3(32.47,22.12) v3(32.47,21.83) v3(32.45,21.46) v3(32.49,18.29) v3(32.48,17.75) v3(32.45,16.79) v3(32.5,15.76) v3(32.48,13.73) v3(32.48,13.45) v3(32.48,8.69) v3(32.45,3.63) v3(32.48,2.06) v3(32.6,67.82) v3(32.64,63.59) v3(32.64,31.53) v3(32.64,30.68) v3(32.64,29.93) v3(32.64,28.69) v3(32.57,26.17) v3(32.57,19.19) v3(32.66,67.04) v3(32.66,65.97) v3(32.7,23.14) v3(32.7,14.11) v3(32.66,12.93) v3(32.8,68.7) v3(32.78,65.03) v3(32.76,63.18) v3(32.75,57.95) v3(32.83,56.99) v3(32.83,52.21) v3(32.83,41.62) v3(32.83,41.44) v3(32.79,39.64) v3(32.8,32.4) v3(32.74,28.3) v3(32.74,25.1) v3(32.77,24.51) v3(32.76,22.27) v3(32.75,20.14) v3(32.8,19.26) v3(32.76,16.69) v3(32.76,16.43) v3(32.79,1.15) v3(32.93,46.45) v3(32.86,34.13) v3(32.87,24.74) v3(32.92,18.38) v3(32.92,17.5) v3(32.91,13.66) v3(32.91,13.39) v3(32.89,12.5) v3(32.97,63.94) v3(33,63.47) v3(33,63.03) v3(32.98,53.76) v3(33,53.28) v3(33,52.7) v3(32.97,52.01) v3(32.97,39.64) v3(33.01,32.98) v3(33.04,26.26) v3(33.01,16.07) v3(33.03,14.11) v3(33.01,2.06) v3(33.12,66.3) v3(33.13,64.18) v3(33.05,56.2) v3(33.05,25.94) v3(33.08,24.74) v3(33.07,24.54) v3(33.08,22.4) v3(33.08,20.95) v3(33.05,20.14) v3(33.07,19.26) v3(33.09,13.11) v3(33.12,3.62) v3(33.09,1.45) v3(33.2,59.94) v3(33.16,28.07) v3(33.16,27.59) v3(33.2,23.15) v3(33.18,16.62) v3(33.19,15.23) v3(33.15,14.35) v3(33.16,13.85) v3(33.33,65.27) v3(33.29,52.47) v3(33.3,47.58) v3(33.25,45.16) v3(33.24,29.1) v3(33.38,38.84) v3(33.38,38.65) v3(33.43,27.1) v3(33.43,17.9) v3(33.42,17.62) v3(33.39,1.14) v3(33.52,53.95) v3(33.49,52.7) v3(33.44,52.04) v3(33.48,51.83) v3(33.51,32.4) v3(33.53,23.17) v3(33.52,22.74) v3(33.44,21.41) v3(33.44,20.2) v3(33.49,18.54) v3(33.44,17.18) v3(33.45,14.49) v3(33.48,13.85) v3(33.51,13.11) v3(33.48,8.69) v3(33.56,31.54) v3(33.61,20.74) v3(33.54,19.57) v3(33.63,14.78) v3(33.61,12.5) v3(33.72,53.68) v3(33.72,41.01) v3(33.65,15.93) v3(33.74,5.78) v3(33.74,5.03) v3(33.73,3.62) v3(33.73,2.21) v3(33.78,52.73) v3(33.83,45.8) v3(33.77,40.03) v3(33.76,37.44) v3(33.79,33.31) v3(33.84,19.23) v3(33.86,67.1) v3(33.94,38.33) v3(33.87,36.83) v3(33.89,34.42) v3(33.94,26.59) v3(33.94,25.27) v3(33.85,22.79) v3(33.89,22.44) v3(33.87,20.37) v3(33.85,19.77) v3(33.92,18.02) v3(33.94,17.61) v3(33.89,12.97) v3(33.88,12.37) v3(33.89,11.84) v3(33.9,11.34) v3(33.92,10.76) v3(33.95,66.26) v3(34.03,62.1) v3(33.98,31.93) v3(33.96,28.3) v3(33.96,24.57) v3(34,23.55) v3(33.95,21.4) v3(34.01,20.82) v3(34.02,17.18) v3(33.98,13.38) v3(34.1,68.69) v3(34.08,65.64) v3(34.12,64.64) v3(34.1,64.37) v3(34.08,63.94) v3(34.11,63.35) v3(34.1,63.01) v3(34.04,54.48) v3(34.1,19.57) v3(34.09,1.14) v3(34.22,66.52) v3(34.17,65.8) v3(34.17,65.26) v3(34.2,61.87) v3(34.23,60.66) v3(34.18,58.66) v3(34.16,52.52) v3(34.19,29.83) v3(34.22,27.6) v3(34.23,24.06) v3(34.19,23.11) v3(34.17,22.8) v3(34.23,21.57) v3(34.23,21.14) v3(34.16,20.41) v3(34.14,19.23) v3(34.19,18.36) v3(34.17,16.36) v3(34.23,15.93) v3(34.22,15.36) v3(34.19,14.62) v3(34.27,54.24) v3(34.32,53.47) v3(34.3,52.69) v3(34.29,52.18) v3(34.28,50.98) v3(34.33,45.85) v3(34.34,25.43) v3(34.29,12.5) v3(34.42,63.5) v3(34.35,61.72) v3(34.4,59.93) v3(34.4,59.01) v3(34.42,46.38) v3(34.42,32.66) v3(34.4,28.99) v3(34.4,16.37) v3(34.43,11.94) v3(34.4,5.04) v3(34.38,3.63) v3(34.39,2.21) v3(34.39,1.45) v3(34.47,66.18) v3(34.44,60.35) v3(34.5,58.73) v3(34.53,56.25) v3(34.46,55.69) v3(34.52,53.7) v3(34.49,53.29) v3(34.46,36.33) v3(34.45,33.87) v3(34.46,28.07) v3(34.5,27.11) v3(34.54,23.55) v3(34.54,23.12) v3(34.54,22.34) v3(34.52,20.74) v3(34.52,17.93) v3(34.51,17.15) v3(34.44,10.73) v3(34.48,8.69) v3(34.45,7.85) v3(34.45,6.56) v3(34.58,62.11) v3(34.64,61.72) v3(34.59,59.33) v3(34.56,44.55) v3(34.61,21.97) v3(34.57,21.6) v3(34.55,19.98) v3(34.59,19.23) v3(34.55,14.12) v3(34.55,13.38) v3(34.74,63.74) v3(34.71,59.64) v3(34.72,58.94) v3(34.73,58.44) v3(34.7,39.06) v3(34.67,29.62) v3(34.68,25.79) v3(34.65,20.9) v3(34.69,20.38) v3(34.65,18.96) v3(34.66,18.04) v3(34.69,17.15) v3(34.67,14.36) v3(34.69,1.14) v3(34.77,67.82) v3(34.81,67.03) v3(34.77,65.64) v3(34.83,63.2) v3(34.76,62.72) v3(34.76,53.92) v3(34.78,43.34) v3(34.77,15.92) v3(34.79,15.11) v3(34.79,14.81) v3(34.88,60.27) v3(34.89,54.7) v3(34.86,40.66) v3(34.91,26.22) v3(34.85,23.66) v3(34.92,23.03) v3(34.89,22.43) v3(34.89,21.96) v3(34.84,19.68) v3(34.86,18.8) v3(34.93,12.92) v3(35.01,66.31) v3(34.99,65.08) v3(34.99,64.62) v3(34.98,63.78) v3(34.97,62.36) v3(34.99,61.68) v3(34.98,54.23) v3(35.02,52.25) v3(34.99,45.32) v3(35,28.08) v3(34.94,22.79) v3(35.02,17.93) v3(35,14.38) v3(34.96,10.74) v3(34.97,10.3) v3(34.97,9.72) v3(34.96,9.19) v3(34.98,5.54) v3(35.08,47.02) v3(35.11,36.21) v3(35.07,29.03) v3(35.05,16.35) v3(35.05,11.94) v3(35.04,5.03) v3(35.04,3.63) v3(35.04,2.21) v3(35.23,59.27) v3(35.17,49.51) v3(35.18,46.45) v3(35.22,41.51) v3(35.2,27.58) v3(35.22,25.91) v3(35.2,23.66) v3(35.18,23.13) v3(35.2,21.61) v3(35.19,20.95) v3(35.17,20.41) v3(35.19,19.97) v3(35.19,19.22) v3(35.18,18.38) v3(35.2,17.29) v3(35.24,15.93) v3(35.19,15.38) v3(35.22,15.02) v3(35.22,14.74) v3(35.26,66.51) v3(35.28,65.98) v3(35.33,58.2) v3(35.27,48.81) v3(35.3,47.27) v3(35.31,45.78) v3(35.26,30.39) v3(35.34,30.06) v3(35.27,29.66) v3(35.33,14.36) v3(35.4,34.08) v3(35.4,33.71) v3(35.37,31.27) v3(35.41,24.57) v3(35.41,13.32) v3(35.39,1.16) v3(35.5,68.69) v3(35.52,62.87) v3(35.53,62.31) v3(35.52,51.3) v3(35.53,50.52) v3(35.44,43.41) v3(35.5,39.82) v3(35.5,32.3) v3(35.53,25.72) v3(35.54,23.13) v3(35.54,22.26) v3(35.54,21.6) v3(35.51,21.19) v3(35.53,19.56) v3(35.52,17.93) v3(35.54,17.18) v3(35.52,14.57) v3(35.48,8.69) v3(35.58,60.31) v3(35.6,46.87) v3(35.63,40.53) v3(35.61,35.71) v3(35.59,28.08) v3(35.56,26.59) v3(35.57,22.79) v3(35.57,20.73) v3(35.59,19.98) v3(35.61,18.38) v3(35.58,16.94) v3(35.67,62.51) v3(35.67,62.01) v3(35.66,61.08) v3(35.71,58.33) v3(35.71,43.07) v3(35.72,21.18) v3(35.66,16.56) v3(35.72,15.92) v3(35.66,13.63) v3(35.67,5.04) v3(35.69,1.45) v3(35.75,43.47) v3(35.75,32.81) v3(35.74,27.03) v3(35.8,21.94) v3(35.77,20.42) v3(35.74,3.65) v3(35.81,1.97) v3(35.93,64.38) v3(35.93,63.71) v3(35.85,45.3) v3(35.85,25.1) v3(35.87,23.32) v3(35.9,15.73) v3(35.87,14.62) v3(35.88,11.61) v3(35.98,67.05) v3(35.97,66.16) v3(35.94,64.71) v3(35.98,55.78) v3(36.03,54.17) v3(36.01,34.73) v3(35.94,31.75) v3(35.98,29.62) v3(36,28.95) v3(35.94,18.84) v3(36.02,17.93) v3(35.96,16.92) v3(36,15.39) v3(36.03,13.34) v3(36,1.15) v3(36.06,58.19) v3(36.06,45.78) v3(36.06,36.99) v3(36.05,25.7) v3(36.09,24.58) v3(36.05,22.6) v3(36.08,15) v3(36.1,14.49) v3(36.1,14.06) v3(36.12,11.98) v3(36.05,11.07) v3(36.05,10.36) v3(36.06,9.77) v3(36.05,9.11) v3(36.17,51.51) v3(36.22,41.03) v3(36.19,28.08) v3(36.23,27.58) v3(36.19,23.66) v3(36.22,23.12) v3(36.16,21.57) v3(36.14,20.83) v3(36.23,20.32) v3(36.18,19.57) v3(36.19,19.17) v3(36.19,15.93) v3(36.31,66.52) v3(36.27,49.53) v3(36.24,39.07) v3(36.28,13.48) v3(36.34,10.79) v3(36.28,9.33) v3(36.26,8.43) v3(36.33,5.02) v3(36.34,3.62) v3(36.3,1.97) v3(36.37,48.82) v3(36.4,48.33) v3(36.39,48.15) v3(36.39,47.79) v3(36.4,33.71) v3(36.37,16.35) v3(36.37,13.82) v3(36.4,10.32) v3(36.35,5.79) v3(36.49,65.79) v3(36.46,63.37) v3(36.46,63.03) v3(36.53,58.13) v3(36.45,53.45) v3(36.54,32.93) v3(36.5,32.3) v3(36.5,27.11) v3(36.49,23.55) v3(36.49,20.91) v3(36.49,20.31) v3(36.49,19.79) v3(36.52,17.93) v3(36.49,16.74) v3(36.48,8.69) v3(36.56,65.12) v3(36.57,64.25) v3(36.61,63.71) v3(36.63,58.59) v3(36.59,47.23) v3(36.62,38.38) v3(36.58,36.47) v3(36.64,31.75) v3(36.61,30.9) v3(36.63,25.91) v3(36.63,25.64) v3(36.57,22.73) v3(36.59,22.18) v3(36.58,19.2) v3(36.58,18.38) v3(36.58,16.43) v3(36.62,15.93) v3(36.59,13.14) v3(36.55,7.46) v3(36.73,39.58) v3(36.66,29.63) v3(36.73,14.98) v3(36.71,14.5) v3(36.72,6.99) v3(36.69,1.14) v3(36.83,64.77) v3(36.74,40.6) v3(36.74,40.09) v3(36.8,38.38) v3(36.74,37.38) v3(36.76,30.11) v3(36.75,28.89) v3(36.78,28.08) v3(36.83,24.03) v3(36.9,68.69) v3(36.87,67.82) v3(36.93,66.03) v3(36.86,35.61) v3(36.89,23.13) v3(36.84,20.05) v3(36.87,15.73) v3(36.99,64.04) v3(37,51.79) v3(37.02,43.04) v3(37.03,39.03) v3(36.98,38.38) v3(37.04,25.11) v3(36.98,22.26) v3(36.99,21.61) v3(36.99,20.75) v3(36.95,18.84) v3(37.02,17.93) v3(37.02,13.76) v3(36.97,12.31) v3(36.97,11.31) v3(36.95,6.53) v3(36.98,5.04) v3(37,3.62) v3(37.03,2.21) v3(36.99,1.45) v3(37.1,53.79) v3(37.06,46.76) v3(37.1,25.84) v3(37.09,22.73) v3(37.18,67.02) v3(37.14,66.36) v3(37.21,45.92) v3(37.21,44.96) v3(37.23,40.6) v3(37.23,40.09) v3(37.21,39.03) v3(37.21,30.39) v3(37.21,24.66) v3(37.22,23.66) v3(37.16,21.95) v3(37.23,21.15) v3(37.17,20.37) v3(37.21,19.85) v3(37.22,19.17) v3(37.17,18.4) v3(37.21,15.91) v3(37.23,14.97) v3(37.33,65.27) v3(37.3,64.53) v3(37.28,27.59) v3(37.3,16.92) v3(37.27,12.76) v3(37.27,10.29) v3(37.27,7.49) v3(37.27,6.99) v3(37.3,1.15) v3(37.37,66.53) v3(37.39,62.83) v3(37.42,52.29) v3(37.39,33.71) v3(37.38,28.06) v3(37.38,26.17) v3(37.37,16.36) v3(37.47,56.71) v3(37.45,50.27) v3(37.52,46.31) v3(37.48,43.23) v3(37.53,42.77) v3(37.45,31.12) v3(37.45,29.1) v3(37.5,27.11) v3(37.49,25.21) v3(37.52,17.93) v3(37.47,14.38) v3(37.48,8.69) v3(37.62,67.03) v3(37.56,63.42) v3(37.57,23.12) v3(37.57,22.79) v3(37.58,21.57) v3(37.56,21.06) v3(37.55,20.2) v3(37.58,16.36) v3(37.69,66.42) v3(37.66,64.88) v3(37.67,51.99) v3(37.67,32.12) v3(37.69,31.51) v3(37.71,29.63) v3(37.67,22.04) v3(37.66,19.64) v3(37.66,19.14) v3(37.71,18.4) v3(37.68,15.93) v3(37.65,10.82) v3(37.67,5.03) v3(37.68,4.35) v3(37.68,3.62) v3(37.68,2.95) v3(37.68,2.22) v3(37.78,63.71) v3(37.78,63.08) v3(37.81,37.05) v3(37.77,35.61) v3(37.78,28.28) v3(37.8,28.06) v3(37.74,13.49) v3(37.77,5.95) v3(37.88,65.2) v3(37.91,48.21) v3(37.87,48.03) v3(37.87,47.85) v3(37.94,45.79) v3(37.85,31.12) v3(37.85,30.46) v3(37.91,29.77) v3(37.85,29.1) v3(37.85,28.65) v3(37.87,27.6) v3(37.86,24.42) v3(37.94,24.12) v3(37.89,22.37) v3(37.87,15.75) v3(37.93,11.92) v3(37.93,9.75) v3(37.93,9.26) v3(37.93,8.34) v3(37.96,66.03) v3(38,53.79) v3(37.99,51.73) v3(37.95,32.66) v3(37.96,18.84) v3(38.02,17.93) v3(37.99,15.21) v3(37.94,10.29) v3(37.99,6.33) v3(38.08,64.13) v3(38.05,48.03) v3(38.06,47.85) v3(38.12,16.36) v3(38.09,14.38) v3(38.11,13.17) v3(38.23,51.06) v3(38.23,43.04) v3(38.22,42.54) v3(38.22,39.57) v3(38.2,31.23) v3(38.22,23.65) v3(38.22,23.12) v3(38.21,22.8) v3(38.21,21.96) v3(38.21,21.61) v3(38.22,20.76) v3(38.21,20.16) v3(38.21,19.55) v3(38.22,19.11) v3(38.22,14.06) v3(38.22,13.49) v3(38.22,11.07) v3(38.22,10.45) v3(38.23,9.74) v3(38.23,8.95) v3(38.23,8.2) v3(38.17,0.91) v3(38.25,30.39) v3(38.25,28.05) v3(38.27,21.14) v3(38.24,18.38) v3(38.25,15.92) v3(38.24,15.51) v3(38.27,14.9) v3(38.27,11.48) v3(38.41,66.53) v3(38.34,63.64) v3(38.38,38.22) v3(38.44,27.67) v3(38.35,16.42) v3(38.53,65.92) v3(38.51,64.57) v3(38.45,38.89) v3(38.45,32.12) v3(38.5,31.1) v3(38.5,27.11) v3(38.54,68.7) v3(38.58,62.93) v3(38.62,46.09) v3(38.55,33.71) v3(38.61,29.68) v3(38.63,29.11) v3(38.59,17.5) v3(38.69,58.94) v3(38.69,26.17) v3(38.67,24.74) v3(38.66,22.76) v3(38.65,19.7) v3(38.67,17) v3(38.67,16.42) v3(38.75,65) v3(38.81,37.03) v3(38.83,23.63) v3(38.82,21.46) v3(38.82,20.58) v3(38.82,18.83) v3(38.77,15.93) v3(38.94,67.82) v3(38.84,64.64) v3(38.94,53.79) v3(38.92,39.74) v3(38.86,35.61) v3(38.91,34.75) v3(38.94,24.12) v3(38.97,67) v3(39,65.52) v3(39.01,59.18) v3(38.95,58.45) v3(38.94,51.76) v3(38.97,37.79) v3(38.95,32.66) v3(38.96,28.49) v3(38.97,24.49) v3(38.96,19.69) v3(38.97,17.5) v3(38.98,16.43) v3(38.98,13.37) v3(39.12,64.38) v3(39.04,31.29) v3(39.12,30.29) v3(39.06,14.63) v3(39.04,13.93) v3(39.16,66.36) v3(39.19,65.89) v3(39.23,63.58) v3(39.23,38.15) v3(39.21,16.32) v3(39.19,15.83) v3(39.18,11.94) v3(39.3,30.83) v3(39.29,29.08) v3(39.28,27.59) v3(39.29,22.34) v3(39.26,19.84) v3(39.3,19.17) v3(39.28,18.5) v3(39.31,15.39) v3(39.32,14.91) v3(39.31,10.74) v3(39.31,10.15) v3(39.31,9.47) v3(39.31,8.84) v3(39.31,8.13) v3(39.42,65.17) v3(39.43,58.2) v3(39.43,52.75) v3(39.34,47.07) v3(39.41,33.7) v3(39.35,31.42) v3(39.37,16.85) v3(39.36,14.38) v3(39.52,60.25) v3(39.48,51.73) v3(39.5,43.27) v3(39.45,32.12) v3(39.5,27.11) v3(39.49,21.05) v3(39.59,60.98) v3(39.6,28.15) v3(39.57,18.7) v3(39.6,17.49) v3(39.55,0.62) v3(39.67,66.36) v3(39.73,58.42) v3(39.68,55.47) v3(39.72,51.52) v3(39.72,35.6) v3(39.7,29.99) v3(39.69,25.75) v3(39.74,24.72) v3(39.65,22.8) v3(39.7,16.6) v3(39.73,15.73) v3(39.66,8.85) v3(39.73,5.93) v3(39.76,47.86) v3(39.78,28.78) v3(39.75,14.98) v3(39.84,67.11) v3(39.84,66.91) v3(39.91,65.75) v3(39.9,65.23) v3(39.86,38.67) v3(39.91,34.7) v3(39.92,22.46) v3(39.87,16.2) v3(39.89,15.98) v3(39.87,13.38) v3(39.86,10.74) v3(39.86,10.08) v3(39.96,68.7) v3(39.98,66.14) v3(39.95,32.66) v3(40.01,25.98) v3(39.99,19.38) v3(40.03,17.81) v3(39.99,14.18) v3(39.97,13.72) v3(39.99,11.94) v3(40.04,64.36) v3(40.04,30.33) v3(40.11,28.16) v3(40.06,22) v3(40.1,21.14) v3(40.1,14.7) v3(40.13,7.95) v3(40.13,6.63) v3(40.13,5.19) v3(40.15,50.49) v3(40.2,49.57) v3(40.15,28.74) v3(40.14,17.03) v3(40.16,16.21) v3(40.29,67.33) v3(40.29,67.08) v3(40.29,66.83) v3(40.29,66.58) v3(40.26,15.99) v3(40.31,3.77) v3(40.32,1.98) v3(40.32,1.33) v3(40.34,65.38) v3(40.44,65.18) v3(40.34,64.93) v3(40.41,60.47) v3(40.4,55.67) v3(40.4,33.71) v3(40.37,27.51) v3(40.38,26.92) v3(40.37,24.54) v3(40.34,20.03) v3(40.38,16.51) v3(40.34,13.6) v3(40.37,13.13) v3(40.37,12.51) v3(40.37,11.85) v3(40.35,10.76) v3(40.35,10.11) v3(40.35,9.25) v3(40.49,67.33) v3(40.49,67.08) v3(40.49,66.83) v3(40.49,66.58) v3(40.46,60.81) v3(40.51,54.74) v3(40.45,43.62) v3(40.53,38.51) v3(40.47,32.11) v3(40.45,30.69) v3(40.53,26.17) v3(40.52,24.21) v3(40.52,22.79) v3(40.52,21.93) v3(40.48,14.51) v3(40.59,65.58) v3(40.54,65.38) v3(40.54,64.97) v3(40.61,54.24) v3(40.63,43.62) v3(40.6,29.54) v3(40.6,28.15) v3(40.61,20.71) v3(40.54,12.18) v3(40.71,67.82) v3(40.69,67.33) v3(40.69,67.08) v3(40.74,65.78) v3(40.74,65.38) v3(40.69,56.51) v3(40.73,53.08) v3(40.69,51.69) v3(40.7,39.24) v3(40.66,38.38) v3(40.67,35.61) v3(40.73,17.79) v3(40.66,15.99) v3(40.75,64.97) v3(40.76,46.29) v3(40.89,67.33) v3(40.89,67.08) v3(40.84,65.58) v3(40.94,65.38) v3(40.84,65.18) v3(40.94,64.93) v3(40.88,54.54) v3(40.94,46.29) v3(40.93,28.93) v3(40.92,26.41) v3(40.98,64.55) v3(40.97,61.79) v3(40.98,58.24) v3(41,51.15) v3(40.99,48.3) v3(40.94,45.81) v3(40.95,32.66) v3(40.95,31.3) v3(40.95,15.68) v3(40.97,15.23) v3(41.09,53.44) v3(41.11,48.17) v3(41.12,46.29) v3(41.05,28.15) v3(41.07,23.6) v3(41.04,22.28) v3(41.09,21.27) v3(41.04,20.28) v3(41.05,18.65) v3(41.07,16.98) v3(41.06,16.53) v3(41.06,15.94) v3(41.04,13.16) v3(41.07,12.51) v3(41.24,66) v3(41.24,55.64) v3(41.14,29.42) v3(41.23,24.14) v3(41.15,17.81) v3(41.21,16.23) v3(41.25,66.58) v3(41.26,54.96) v3(41.29,48.21) v3(41.31,41.89) v3(41.31,35.59) v3(41.26,27.06) v3(41.3,14.18) v3(41.3,13.71) v3(41.36,67.09) v3(41.41,31.79) v3(41.43,18.35) v3(41.41,15.98) v3(41.35,12.52) v3(41.46,68.52) v3(41.47,48.21) v3(41.46,43.62) v3(41.53,33.71) v3(41.46,28.8) v3(41.58,65.22) v3(41.54,29.85) v3(41.56,17.01) v3(41.58,16.23) v3(41.69,48.8) v3(41.65,48.17) v3(41.65,47.82) v3(41.71,25.75) v3(41.71,25.14) v3(41.69,24.29) v3(41.72,23.61) v3(41.72,23.27) v3(41.66,14.85) v3(41.72,13.09) v3(41.75,41.91) v3(41.79,39.66) v3(41.76,22.17) v3(41.75,21.59) v3(41.76,20.66) v3(41.76,19.66) v3(41.76,18.65) v3(41.78,16.73) v3(41.79,16.3) v3(41.79,15.64) v3(41.84,56.54) v3(41.87,51.15) v3(41.92,48.06) v3(41.93,34.55) v3(41.89,31.23) v3(41.94,30.49) v3(41.84,27.46) v3(41.84,18.05) v3(41.88,15.26) v3(41.97,37.61) v3(41.99,35.6) v3(41.95,32.66) v3(42.02,29.38) v3(42.02,28.23) v3(42.01,26.17) v3(41.98,24.14) v3(41.97,22.62) v3(42.02,16.67) v3(42.11,68.04) v3(42.13,64.56) v3(42.05,54.45) v3(42.12,46.34) v3(42.13,34.55) v3(42.08,28.55) v3(42.04,27.54) v3(42.04,14.64) v3(42.22,67.11) v3(42.19,61.9) v3(42.23,60.47) v3(42.19,46.08) v3(42.18,42.99) v3(42.23,17.28) v3(42.14,15.78) v3(42.22,13.74) v3(42.25,42.41) v3(42.25,30.48) v3(42.32,25.77) v3(42.32,25.07) v3(42.29,24.39) v3(42.31,23.91) v3(42.29,23.14) v3(42.29,22.58) v3(42.29,21.89) v3(42.31,21.39) v3(42.29,18.89) v3(42.29,17.89) v3(42.29,16.89) v3(42.43,53.52) v3(42.36,42.99) v3(42.37,32.12) v3(42.37,31.94) v3(42.42,31.6) v3(42.34,26.59) v3(42.34,20.79) v3(42.34,19.94) v3(42.34,12.52) v3(42.52,66.49) v3(42.45,34.76) v3(42.47,29) v3(42.45,27.61) v3(42.5,13.08) v3(42.63,56.59) v3(42.6,55.53) v3(42.54,55.17) v3(42.6,35.6) v3(42.54,31.04) v3(42.54,30.49) v3(42.59,29.38) v3(42.61,23.76) v3(42.57,19.37) v3(42.57,18.57) v3(42.54,16.28) v3(42.68,65.26) v3(42.72,54.12) v3(42.7,47.77) v3(42.71,29.01) v3(42.66,22.23) v3(42.65,18.12) v3(42.84,68.52) v3(42.75,42.41) v3(42.75,31.93) v3(42.84,27.53) v3(42.84,25.78) v3(42.79,25.33) v3(42.79,20.78) v3(42.83,17.1) v3(42.81,15.05) v3(42.76,14.28) v3(42.91,55.3) v3(42.89,51.2) v3(42.93,43.66) v3(42.86,39.9) v3(42.89,28.28) v3(42.88,27.01) v3(42.88,17.85) v3(42.96,56.79) v3(43.02,55.66) v3(43,46.33) v3(42.95,39.74) v3(42.97,29.67) v3(42.94,24.51) v3(42.99,23.28) v3(42.95,22.95) v3(42.95,22.56) v3(42.95,21.34) v3(43.04,39.9) v3(43.13,39.74) v3(43.04,33.88) v3(43.09,19.19) v3(43.2,66.64) v3(43.19,64.84) v3(43.22,59.22) v3(43.14,42.99) v3(43.22,39.9) v3(43.2,24.13) v3(43.32,61.23) v3(43.28,35.6) v3(43.29,31.49) v3(43.29,24.94) v3(43.32,23.67) v3(43.31,22.08) v3(43.26,21.38) v3(43.36,67.28) v3(43.4,56.39) v3(43.4,45.92) v3(43.37,41.53) v3(43.39,26.16) v3(43.4,19.06) v3(43.42,17.79) v3(43.36,16.34) v3(43.53,54.98) v3(43.51,53.11) v3(43.51,44.52) v3(43.45,32.16) v3(43.46,27.6) v3(43.47,17.23) v3(43.61,61.89) v3(43.64,31.03) v3(43.64,28.83) v3(43.64,26.78) v3(43.55,26.57) v3(43.57,25.28) v3(43.6,21.38) v3(43.56,12.52) v3(43.73,33.11) v3(43.7,32.63) v3(43.71,29.95) v3(43.66,28.39) v3(43.72,24.13) v3(43.74,22.08) v3(43.73,21.09) v3(43.7,20.2) v3(43.72,19.71) v3(43.69,18.59) v3(43.81,68.18) v3(43.84,64.6) v3(43.82,57.65) v3(43.78,38.57) v3(43.84,30.09) v3(43.79,24.93) v3(43.83,23.65) v3(43.9,45.32) v3(43.91,33.9) v3(43.87,29.33) v3(43.92,21.74) v3(43.9,17.23) v3(43.9,16.29) v3(43.86,13.68) v3(43.99,56.12) v3(43.95,51.39) v3(44,41.81) v3(44,41.56) v3(44,39.59) v3(43.97,39.04) v3(44.01,37.57) v3(43.98,35.61) v3(43.98,27.58) v3(44,27.03) v3(43.97,25.48) v3(44.01,20.86) v3(43.99,19.29) v3(44.11,52.49) v3(44.05,42.95) v3(44.08,33.63) v3(44.12,33.11) v3(44.07,27.26) v3(44.11,25.21) v3(44.07,22.9) v3(44.1,22.08) v3(44.11,21.16) v3(44.16,60.03) v3(44.16,56.65) v3(44.15,55.02) v3(44.16,54.25) v3(44.16,47.45) v3(44.16,25.65) v3(44.19,24.13) v3(44.14,18.09) v3(44.26,67.27) v3(44.31,57.31) v3(44.34,25.83) v3(44.32,25.51) v3(44.32,21.38) v3(44.35,56.68) v3(44.35,44.97) v3(44.39,29.03) v3(44.4,26.57) v3(44.38,26.39) v3(44.43,24.92) v3(44.36,17.74) v3(44.42,15.53) v3(44.49,68.5) v3(44.5,48.31) v3(44.44,40.46) v3(44.45,29.38) v3(44.44,25.19) v3(44.46,23.65) v3(44.44,22.08) v3(44.49,21.74) v3(44.61,64.86) v3(44.55,46.88) v3(44.57,42.39) v3(44.61,35.61) v3(44.58,33.66) v3(44.54,24.61) v3(44.55,24.28) v3(44.54,20.18) v3(44.6,12.52) v3(44.66,51.9) v3(44.7,24.91) v3(44.69,21.38) v3(44.75,66.46) v3(44.75,65.31) v3(44.83,30.05) v3(44.75,26.89) v3(44.79,25.19) v3(44.81,23.25) v3(44.78,22.08) v3(44.87,14.23) v3(44.86,13.21) v3(44.97,37.59) v3(44.97,27.18) v3(44.98,24.63) v3(44.98,24.29) v3(44.94,18.05) v3(45.12,53.4) v3(45.13,38.61) v3(45.13,34.68) v3(45.13,33.95) v3(45.12,33.27) v3(45.12,32.27) v3(45.09,25.96) v3(45.09,25.19) v3(45.09,24.92) v3(45.08,20.37) v3(45.1,19.34) v3(45.04,13.77) v3(45.19,61.07) v3(45.18,54.98) v3(45.18,41.82) v3(45.22,28.51) v3(45.21,25.71) v3(45.22,25.46) v3(45.19,23.78) v3(45.22,22.23) v3(45.2,17.23) v3(45.2,16.85) v3(45.3,40.45) v3(45.32,21.9) v3(45.32,20.16) v3(45.4,68.71) v3(45.39,29.34) v3(45.41,25.22) v3(45.42,24.98) v3(45.41,24.19) v3(45.38,21.16) v3(45.39,18.04) v3(45.51,46.13) v3(45.51,41.31) v3(45.45,35.61) v3(45.45,34.03) v3(45.47,30.31) v3(45.52,27.34) v3(45.5,22.04) v3(45.51,17.79) v3(45.46,15.51) v3(45.55,39.13) v3(45.63,38.12) v3(45.62,31.27) v3(45.58,25.94) v3(45.58,25.57) v3(45.56,24.09) v3(45.56,23.5) v3(45.56,23.24) v3(45.56,22.94) v3(45.56,22.76) v3(45.55,22.26) v3(45.63,19.51) v3(45.54,17.11) v3(45.61,14.24) v3(45.64,12.52) v3(45.74,60.93) v3(45.73,54.25) v3(45.65,44.63) v3(45.74,39.96) v3(45.72,24) v3(45.69,21.03) v3(45.69,20.17) v3(45.68,16.73) v3(45.66,16.36) v3(45.77,65.29) v3(45.78,64.59) v3(45.76,32.72) v3(45.8,31.82) v3(45.82,25.96) v3(45.78,25.22) v3(45.84,15.73) v3(45.79,15.04) v3(45.79,13.78) v3(45.86,24.36) v3(45.94,52.78) v3(46.02,43.5) v3(46,34.69) v3(45.99,24.76) v3(45.97,18.39) v3(45.94,13.2) v3(46.13,57) v3(46.13,52.11) v3(46.13,49.39) v3(46.1,27.35) v3(46.13,25.38) v3(46.06,22.41) v3(46.09,16.22) v3(46.09,13.78) v3(46.22,34.3) v3(46.22,33.63) v3(46.14,29.34) v3(46.16,27.02) v3(46.2,22.76) v3(46.16,21.61) v3(46.16,20.86) v3(46.16,19.71) v3(46.14,19.36) v3(46.15,18.99) v3(46.24,18.6) v3(46.14,15.03) v3(46.25,66.47) v3(46.26,38.66) v3(46.27,35.48) v3(46.25,31.46) v3(46.31,21.23) v3(46.33,18.03) v3(46.42,41.83) v3(46.35,36.51) v3(46.39,30.24) v3(46.39,23.55) v3(46.4,23.25) v3(46.35,21.93) v3(46.41,20.25) v3(46.34,17.15) v3(46.35,14.88) v3(46.52,46.81) v3(46.44,35.04) v3(46.48,25.49) v3(46.52,24.02) v3(46.48,22.71) v3(46.51,19.36) v3(46.44,17.84) v3(46.49,16.22) v3(46.64,52.1) v3(46.6,33.65) v3(46.64,29.53) v3(46.61,27.15) v3(46.6,25.95) v3(46.62,19.15) v3(46.54,16.94) v3(46.65,68.7) v3(46.68,62.07) v3(46.69,29.13) v3(46.68,27.58) v3(46.79,63.77) v3(46.74,61.51) v3(46.84,43.26) v3(46.76,35.24) v3(46.82,34.5) v3(46.83,23.35) v3(46.81,20.86) v3(46.81,20.46) v3(46.79,19.77) v3(46.81,19.36) v3(46.81,18.61) v3(46.82,17.69) v3(46.81,16.67) v3(46.81,14.86) v3(46.82,14.03) v3(46.77,13.3) v3(46.87,60.28) v3(46.89,29.34) v3(46.87,24.92) v3(46.91,15.83) v3(46.89,12.53) v3(47.02,67.22) v3(47.01,64.68) v3(46.98,53.37) v3(47.03,40.44) v3(47,26.28) v3(46.98,24.33) v3(46.97,23.82) v3(46.94,21.38) v3(47.08,46.58) v3(47.1,31.31) v3(47.07,25.42) v3(47.07,21.93) v3(47.19,55.58) v3(47.19,44.65) v3(47.21,39.57) v3(47.24,36.1) v3(47.23,30.64) v3(47.24,29.78) v3(47.16,22.75) v3(47.18,21.58) v3(47.17,20.88) v3(47.17,20.41) v3(47.16,19.71) v3(47.16,16.16) v3(47.26,57.28) v3(47.29,41.8) v3(47.27,23.5) v3(47.27,23.19) v3(47.26,17.52) v3(47.35,65.29) v3(47.43,59.26) v3(47.39,51.72) v3(47.38,37.54) v3(47.42,28.16) v3(47.42,17.94) v3(47.36,15.36) v3(47.5,32.53) v3(47.5,27.15) v3(47.5,18.95) v3(47.6,67.2) v3(47.55,30.15) v3(47.63,28.77) v3(47.59,26.75) v3(47.56,26.27) v3(47.56,22.35) v3(47.56,21.21) v3(47.56,20.09) v3(47.54,18.55) v3(47.58,15.74) v3(47.72,47.49) v3(47.69,24.56) v3(47.71,23.18) v3(47.66,22.63) v3(47.73,19.32) v3(47.7,18.81) v3(47.69,12.52) v3(47.83,68.64) v3(47.83,36.44) v3(47.8,25.42) v3(47.75,23.72) v3(47.81,22.76) v3(47.81,22.03) v3(47.84,21.43) v3(47.84,20.43) v3(47.84,19.7) v3(47.84,17.51) v3(47.8,14.92) v3(47.92,44.59) v3(47.9,41.45) v3(47.9,40.35) v3(47.95,43.09) v3(48.03,31.98) v3(47.97,31.44) v3(47.98,30.43) v3(48.03,29.34) v3(48,26.74) v3(48.03,15.32) v3(47.94,13.84) v3(48.11,62.08) v3(48.11,50.41) v3(48.11,36.98) v3(48.09,34.56) v3(48.09,34.26) v3(48.09,33.96) v3(48.09,33.66) v3(48.11,21.15) v3(48.09,19.44) v3(48.13,16.32) v3(48.2,25.51) v3(48.17,21.92) v3(48.2,19.69) v3(48.16,18.55) v3(48.15,17.95) v3(48.2,14.52) v3(48.32,66.43) v3(48.25,61.15) v3(48.33,57.69) v3(48.25,51.9) v3(48.32,32.24) v3(48.27,22.67) v3(48.34,21.43) v3(48.25,20.86) v3(48.25,20.37) v3(48.39,34.56) v3(48.38,34.38) v3(48.39,33.96) v3(48.39,33.66) v3(48.39,24.39) v3(48.35,23.76) v3(48.35,17.51) v3(48.36,15.32) v3(48.52,68.24) v3(48.52,21.21) v3(48.5,20.7) v3(48.52,20.09) v3(48.52,18.95) v3(48.46,17.19) v3(48.6,46.58) v3(48.6,45.06) v3(48.59,30.41) v3(48.64,28.84) v3(48.56,25.97) v3(48.57,25.33) v3(48.56,18.35) v3(48.7,64.68) v3(48.68,47.31) v3(48.74,40.79) v3(48.73,33.96) v3(48.73,33.66) v3(48.69,29.53) v3(48.72,21.93) v3(48.66,14.06) v3(48.75,38.92) v3(48.8,37.47) v3(48.83,23.7) v3(48.79,22.27) v3(48.84,21.57) v3(48.84,20.47) v3(48.84,19.68) v3(48.84,19.18) v3(48.84,17.09) v3(48.83,12.52) v3(48.92,24.3) v3(48.86,22.76) v3(48.87,16.19) v3(48.92,15.51) v3(49.02,63.58) v3(49,63) v3(48.97,61.43) v3(49.01,51.9) v3(49.02,50.83) v3(48.96,30.79) v3(49.03,17.95) v3(49.08,54.25) v3(49.07,53.63) v3(49.09,38.61) v3(49.04,36.79) v3(49.09,33.96) v3(49.09,33.66) v3(49.06,33.33) v3(49.07,28.77) v3(49.13,22.21) v3(49.08,15.81) v3(49.16,36.94) v3(49.21,32.24) v3(49.19,19.35) v3(49.21,18.55) v3(49.21,18.15) v3(49.22,14.89) v3(49.27,55.85) v3(49.3,30.15) v3(49.28,24.76) v3(49.3,22.74) v3(49.26,21.97) v3(49.25,19.71) v3(49.37,68.24) v3(49.36,43.1) v3(49.39,34.26) v3(49.39,33.96) v3(49.39,33.66) v3(49.41,23.82) v3(49.35,21.55) v3(49.47,67.75) v3(49.5,66.45) v3(49.49,65.28) v3(49.49,40.8) v3(49.52,37.48) v3(49.44,20.94) v3(49.5,18.11) v3(49.45,15.9) v3(49.6,49.9) v3(49.57,42.4) v3(49.54,22.35) v3(49.54,21.21) v3(49.54,20.09) v3(49.54,18.95) v3(49.55,17.49) v3(49.62,16.18) v3(49.71,62.5) v3(49.65,30.82) v3(49.67,17.09) v3(49.77,54.98) v3(49.84,33.75) v3(49.83,32.59) v3(49.83,21.97) v3(49.83,21.58) v3(49.8,20.4) v3(49.93,57.72) v3(49.85,31.26) v3(49.87,28.77) v3(49.91,25.05) v3(49.85,23.21) v3(49.86,22.76) v3(49.85,18.57) v3(49.91,17.95) v3(49.86,15.61) v3(49.94,64.69) v3(50,63.76) v3(49.96,60.14) v3(50,44.58) v3(49.95,39.11) v3(49.99,30.61) v3(49.99,29.43) v3(49.98,23.51) v3(50.08,41.42) v3(50.08,40.79) v3(50.09,39.26) v3(50.14,59.28) v3(50.15,32.46) v3(50.21,25.25) v3(50.23,22.04) v3(50.21,19.3) v3(50.21,18.55) v3(50.2,16.73) v3(50.2,15.82) v3(50.24,50.69) v3(50.32,45.06) v3(50.27,38.23) v3(50.31,33.28) v3(50.3,23.5) v3(50.27,22.61) v3(50.27,21.57) v3(50.42,37.48) v3(50.43,37.19) v3(50.39,31.59) v3(50.42,24.2) v3(50.42,23.24) v3(50.39,20.86) v3(50.36,18.11) v3(50.41,12.53) v3(50.45,46.79) v3(50.52,30) v3(50.48,17.51) v3(50.52,14.93) v3(50.63,55) v3(50.57,34.01) v3(50.62,28.77) v3(50.56,22.35) v3(50.56,21.17) v3(50.56,20.09) v3(50.56,18.95) v3(50.65,57.02) v3(50.66,32.48) v3(50.73,31.12) v3(50.73,23.2) v3(50.66,16.01) v3(50.72,15.82) v3(50.79,66.43) v3(50.83,55.59) v3(50.75,34.01) v3(50.81,22.04) v3(50.84,21.43) v3(50.93,49.19) v3(50.93,39.38) v3(50.88,33.27) v3(50.89,29.58) v3(50.85,23.51) v3(50.91,22.76) v3(50.88,20.42) v3(50.91,19.66) v3(50.9,19.34) v3(50.85,18.6) v3(50.97,41.33) v3(51.02,33.75) v3(50.96,14.92) v3(51.11,65.28) v3(51.08,64.66) v3(51.13,59.59) v3(51.13,59) v3(51.13,55) v3(51.13,50.94) v3(51.05,40.78) v3(51.13,39.38) v3(51.06,38.51) v3(51.09,34.77) v3(51.11,24.29) v3(51.12,15.93) v3(51.17,54.5) v3(51.21,31.96) v3(51.22,18.79) v3(51.14,15.09) v3(51.3,63.32) v3(51.33,62.46) v3(51.33,39.38) v3(51.27,38.23) v3(51.31,36.67) v3(51.33,30.67) v3(51.25,22.72) v3(51.25,21.95) v3(51.34,21.57) v3(51.25,20.48) v3(51.32,19.74) v3(51.26,19.36) v3(51.32,16.39) v3(51.26,13.03) v3(51.26,12.52) v3(51.36,44.74) v3(51.4,33.44) v3(51.42,32.65) v3(51.37,28.77) v3(51.39,20.89) v3(51.48,67.38) v3(51.47,66.9) v3(51.48,66.55) v3(51.51,61.32) v3(51.44,51.88) v3(51.47,35.13) v3(51.56,64.27) v3(51.57,62.46) v3(51.64,59.04) v3(51.63,57.5) v3(51.63,56.94) v3(51.63,52.5) v3(51.59,31.05) v3(51.56,25.13) v3(51.59,15.52) v3(51.7,68.23) v3(51.73,23.51) v3(51.73,23.2) v3(51.65,16.39) v3(51.81,67.37) v3(51.82,66.91) v3(51.79,66.55) v3(51.8,63.97) v3(51.78,38.26) v3(51.81,33.87) v3(51.83,32.76) v3(51.8,29.87) v3(51.8,23.82) v3(51.9,24.2) v3(51.91,22.76) v3(51.91,21.96) v3(51.86,21.6) v3(51.91,21.16) v3(51.91,20.5) v3(51.93,19.69) v3(51.91,19.36) v3(51.89,14.84) v3(51.97,37.54) v3(51.97,35.13) v3(51.99,18.49) v3(52.12,67.35) v3(52.1,66.9) v3(52.1,66.55) v3(52.06,63.68) v3(52.07,45.42) v3(52.06,38.51) v3(52.08,36.8) v3(52.12,28.27) v3(52.15,39.37) v3(52.14,27.78) v3(52.23,25.66) v3(52.22,24.9) v3(52.15,16.8) v3(52.33,58.28) v3(52.33,57.32) v3(52.24,50.08) v3(52.24,44.04) v3(52.24,42.44) v3(52.34,35.31) v3(52.29,34.26) v3(52.28,32.75) v3(52.41,67.88) v3(52.35,53.83) v3(52.38,51.33) v3(52.4,41.63) v3(52.36,39.37) v3(52.36,29.5) v3(52.36,25.29) v3(52.4,24.57) v3(52.38,22.78) v3(52.38,22.34) v3(52.51,67.15) v3(52.51,66.91) v3(52.51,66.44) v3(52.5,64.34) v3(52.49,36.43) v3(52.46,34.58) v3(52.48,31.78) v3(52.44,26.59) v3(52.52,23.51) v3(52.53,21.53) v3(52.53,19.77) v3(52.51,12.52) v3(52.55,63.94) v3(52.58,39.37) v3(52.56,38.3) v3(52.62,32.68) v3(52.63,31.07) v3(52.62,28.26) v3(52.58,17.05) v3(52.58,16.65) v3(52.62,15.87) v3(52.62,14.63) v3(52.73,29.91) v3(52.67,25) v3(52.69,23.23) v3(52.7,22.92) v3(52.69,22.47) v3(52.66,17.8) v3(52.65,15.17) v3(52.8,34.78) v3(52.82,33.36) v3(52.82,32.86) v3(52.81,31.48) v3(52.89,55.27) v3(52.87,27.52) v3(52.89,27.03) v3(52.92,24.2) v3(53,31.22) v3(53.03,30.39) v3(53.04,27.97) v3(53.02,23.34) v3(53.01,22.23) v3(52.97,21.43) v3(52.97,20.62) v3(52.94,19.68) v3(53.03,18.86) v3(52.98,15.59) v3(53.06,38.51) v3(53.07,33.61) v3(53.11,18.21) v3(53.11,17.82) v3(53.08,14.07) v3(53.11,13.52) v3(53.09,12.63) v3(53.18,63.43) v3(53.17,44.6) v3(53.15,42.46) v3(53.16,31.76) v3(53.19,25.84) v3(53.19,19.43) v3(53.28,66.45) v3(53.3,65.29) v3(53.25,39.37) v3(53.27,38.23) v3(53.32,34.35) v3(53.32,33.35) v3(53.3,16.4) v3(53.39,64.33) v3(53.42,40.78) v3(53.35,27.66) v3(53.43,24.45) v3(53.48,41.64) v3(53.51,39.33) v3(53.53,18.36) v3(53.55,67.95) v3(53.55,33.12) v3(53.55,32.6) v3(53.56,29.75) v3(53.62,23.12) v3(53.73,28.17) v3(53.7,27.75) v3(53.7,19.71) v3(53.72,16.02) v3(53.79,63.41) v3(53.76,39.11) v3(53.74,37.78) v3(53.84,37.29) v3(53.81,34.89) v3(53.8,33.36) v3(53.78,22.26) v3(53.75,21.84) v3(53.75,20.82) v3(53.77,12.92) v3(53.93,34.39) v3(53.91,31.92) v3(53.86,31.27) v3(53.87,26.52) v3(53.93,26.06) v3(53.87,18.85) v3(54,67.71) v3(54.01,67.07) v3(54,66.45) v3(53.99,41.8) v3(54.02,33.99) v3(53.97,30.19) v3(53.97,24.76) v3(54.06,63.48) v3(54.04,62.12) v3(54.09,36.83) v3(54.06,33.6) v3(54.11,31.16) v3(54.08,28.52) v3(54.05,27.85) v3(54.07,21.39) v3(54.07,20.31) v3(54.18,46.49) v3(54.22,39.1) v3(54.23,38.22) v3(54.19,31.51) v3(54.14,17.61) v3(54.17,12.72) v3(54.31,34.79) v3(54.34,33.85) v3(54.26,33.35) v3(54.32,30.81) v3(54.28,30.3) v3(54.31,29.81) v3(54.37,65.28) v3(54.35,35.8) v3(54.41,28.2) v3(54.39,27.51) v3(54.39,25.53) v3(54.36,16.65) v3(54.52,68.23) v3(54.5,66.17) v3(54.51,45.97) v3(54.48,40.78) v3(54.44,24.34) v3(54.51,20.34) v3(54.57,67.17) v3(54.62,56.24) v3(54.62,39.06) v3(54.55,35.14) v3(54.58,34.35) v3(54.55,32.63) v3(54.61,31.91) v3(54.62,25.77) v3(54.64,25.18) v3(54.72,64.39) v3(54.65,62.09) v3(54.66,60.96) v3(54.67,57.47) v3(54.67,54.13) v3(54.68,18.62) v3(54.69,18.04) v3(54.71,17.38) v3(54.75,51.59) v3(54.75,38.22) v3(54.74,37.57) v3(54.83,34.81) v3(54.76,33.85) v3(54.76,32.86) v3(54.84,26.51) v3(54.88,68.15) v3(54.89,12.73) v3(54.97,46.34) v3(55.01,29.37) v3(54.94,28.43) v3(55.03,21.43) v3(54.94,19.36) v3(55.09,49.42) v3(55.05,36.08) v3(55.05,34.59) v3(55.05,20.09) v3(55.17,67.15) v3(55.16,66.48) v3(55.14,36.78) v3(55.19,23.59) v3(55.14,14.08) v3(55.28,65.27) v3(55.28,64.69) v3(55.29,39.11) v3(55.27,38.22) v3(55.3,37.49) v3(55.27,36.29) v3(55.25,33.86) v3(55.3,28.95) v3(55.25,27.1) v3(55.41,44.41) v3(55.42,43.34) v3(55.38,41.47) v3(55.34,40.92) v3(55.37,25.02) v3(55.54,67.44) v3(55.45,59.01) v3(55.46,58.45) v3(55.46,57.9) v3(55.46,57.4) v3(55.46,56.9) v3(55.54,50.3) v3(55.47,46.09) v3(55.51,39.38) v3(55.53,37.34) v3(55.47,32.6) v3(55.6,63.39) v3(55.55,42.01) v3(55.55,35.59) v3(55.54,33.11) v3(55.57,28.2) v3(55.59,25.45) v3(55.56,19.54) v3(55.7,67.9) v3(55.65,64.34) v3(55.72,46.49) v3(55.69,39.38) v3(55.67,37.49) v3(55.71,32.28) v3(55.71,31.7) v3(55.68,26.52) v3(55.7,25.84) v3(55.71,21.41) v3(55.66,20.73) v3(55.78,59.57) v3(55.77,56.05) v3(55.76,52.08) v3(55.75,36.35) v3(55.79,34.85) v3(55.82,34.36) v3(55.79,33.38) v3(55.82,31.09) v3(55.82,30.74) v3(55.82,30.39) v3(55.82,30.04) v3(55.82,29.69) v3(55.75,27.1) v3(55.9,60.81) v3(55.91,58.78) v3(55.85,38.21) v3(55.9,36.77) v3(55.92,25.12) v3(55.93,24.85) v3(55.89,24.03) v3(55.87,19.56) v3(55.97,59.81) v3(55.98,52.08) v3(56.04,34.64) v3(55.94,22.84) v3(56.12,59.26) v3(56.06,57.1) v3(56.11,36.38) v3(56.08,36.05) v3(56.07,35.62) v3(56.04,33.61) v3(56.13,31.09) v3(56.13,30.74) v3(56.13,30.39) v3(56.13,30.04) v3(56.13,29.69) v3(56.05,27.79) v3(56.12,24.27) v3(56.11,12.73) v3(56.18,67.86) v3(56.14,66.27) v3(56.17,64.28) v3(56.23,28.64) v3(56.17,27.15) v3(56.14,23.68) v3(56.2,19.54) v3(56.14,14.08) v3(56.24,63.58) v3(56.33,33.37) v3(56.31,21.59) v3(56.28,19.99) v3(56.38,27.7) v3(56.42,25.6) v3(56.5,41.47) v3(56.44,38.21) v3(56.46,31.09) v3(56.46,30.74) v3(56.46,30.39) v3(56.46,30.04) v3(56.46,29.69) v3(56.51,21.26) v3(56.55,65.66) v3(56.59,62.39) v3(56.56,51.86) v3(56.6,47.07) v3(56.55,44.41) v3(56.55,36.77) v3(56.58,33.33) v3(56.58,20.78) v3(56.69,32.79) v3(56.66,26.78) v3(56.71,24.09) v3(56.8,37.56) v3(56.8,32.5) v3(56.77,31.08) v3(56.77,30.74) v3(56.77,30.39) v3(56.77,30.04) v3(56.77,29.69) v3(56.74,26.35) v3(56.88,66.07) v3(56.9,63.48) v3(56.87,46.04) v3(56.9,27.37) v3(56.86,19.96) v3(56.92,19.23) v3(56.92,18.73) v3(56.98,68.24) v3(57,60.13) v3(57,59.65) v3(57.01,58.62) v3(57.03,51.75) v3(56.99,48.1) v3(57,42.83) v3(56.97,28.52) v3(56.94,27.75) v3(57.03,21.71) v3(56.95,13.46) v3(57.1,64.39) v3(57.11,55.02) v3(57.11,54.71) v3(57.07,38.2) v3(57.1,30.74) v3(57.1,21.32) v3(57.06,20.88) v3(57.1,18.43) v3(57.11,12.73) v3(57.18,66.92) v3(57.22,46.49) v3(57.23,35.49) v3(57.21,14.09) v3(57.33,66.02) v3(57.33,57.88) v3(57.3,42.17) v3(57.25,27.56) v3(57.3,26.6) v3(57.27,26.21) v3(57.29,25) v3(57.27,20.09) v3(57.39,22.53) v3(57.42,19.23) v3(57.43,18.74) v3(57.43,18.32) v3(57.53,66.3) v3(57.49,54.09) v3(57.5,53.64) v3(57.49,52.65) v3(57.51,41.46) v3(57.52,36.42) v3(57.52,35.91) v3(57.52,35.33) v3(57.51,34.39) v3(57.52,33.94) v3(57.52,33.33) v3(57.54,32.83) v3(57.47,31.97) v3(57.46,29.38) v3(57.47,26.29) v3(57.45,23.37) v3(57.5,19.89) v3(57.5,17.27) v3(57.5,16.95) v3(57.55,54.58) v3(57.59,44.63) v3(57.56,34.94) v3(57.58,31.44) v3(57.58,27.75) v3(57.57,27.37) v3(57.61,13.2) v3(57.66,42.16) v3(57.69,13.88) v3(57.68,12.55) v3(57.78,51.82) v3(57.82,45.55) v3(57.79,37.9) v3(57.77,37.33) v3(57.83,36.33) v3(57.84,35.4) v3(57.84,34.38) v3(57.84,29.26) v3(57.82,28.29) v3(57.77,26.62) v3(57.78,26.03) v3(57.82,22.88) v3(57.74,19.22) v3(57.86,66.44) v3(57.87,62.59) v3(57.86,50.56) v3(57.91,24.6) v3(57.89,21.78) v3(57.87,20.76) v3(58.02,43.46) v3(58,33.51) v3(57.95,23.75) v3(58.1,41.82) v3(58.1,41.59) v3(58.05,40.55) v3(58.11,27.42) v3(58.2,63.08) v3(58.14,61.88) v3(58.18,59.26) v3(58.15,31.6) v3(58.18,25.74) v3(58.21,22.59) v3(58.22,21.03) v3(58.2,20.02) v3(58.27,67.18) v3(58.28,66.91) v3(58.28,65.38) v3(58.29,65.11) v3(58.34,41.73) v3(58.24,40.55) v3(58.33,35.59) v3(58.24,33.86) v3(58.24,31.09) v3(58.27,30.32) v3(58.29,27.78) v3(58.41,60.1) v3(58.4,34.72) v3(58.4,31.6) v3(58.41,25.24) v3(58.46,37.17) v3(58.46,36.17) v3(58.46,35.17) v3(58.49,27.22) v3(58.52,26.14) v3(58.58,52.42) v3(58.62,30.88) v3(58.56,29.09) v3(58.56,26.98) v3(58.7,67.31) v3(58.72,66.9) v3(58.73,66.45) v3(58.7,65.81) v3(58.72,65.54) v3(58.71,65.27) v3(58.66,51.35) v3(58.68,48.34) v3(58.71,28.95) v3(58.69,24.08) v3(58.69,23.35) v3(58.67,18.57) v3(58.81,57.99) v3(58.83,56.19) v3(58.74,46.39) v3(58.74,31.23) v3(58.77,25.57) v3(58.74,24.44) v3(58.76,22.02) v3(58.76,20.57) v3(58.79,20.02) v3(58.82,18.74) v3(58.85,61.55) v3(58.92,52.81) v3(58.86,29.09) v3(58.91,27.7) v3(58.96,68.21) v3(58.97,67.3) v3(59,66.89) v3(59,66.44) v3(58.97,65.8) v3(59,65.53) v3(58.98,65.26) v3(59,63.48) v3(59.03,35.52) v3(59,34.11) v3(58.97,26.8) v3(58.97,26.39) v3(58.96,23.02) v3(59.05,61.08) v3(59.13,51.02) v3(59.09,28.4) v3(59.09,25.7) v3(59.15,59.79) v3(59.16,40.99) v3(59.21,33.17) v3(59.21,32.17) v3(59.21,31.17) v3(59.17,29.38) v3(59.15,27.73) v3(59.21,23.65) v3(59.18,22.5) v3(59.18,17.24) v3(59.32,67.31) v3(59.25,66.89) v3(59.3,66.45) v3(59.32,65.81) v3(59.25,65.53) v3(59.28,65.27) v3(59.31,61.35) v3(59.34,55.63) v3(59.33,54.77) v3(59.25,48.12) v3(59.28,38.2) v3(59.24,34.69) v3(59.3,24.35) v3(59.28,22.87) v3(59.35,47.35) v3(59.4,35.28) v3(59.35,25.02) v3(59.43,17.77) v3(59.37,17.24) v3(59.48,31.84) v3(59.53,27.73) v3(59.44,22.03) v3(59.44,19.88) v3(59.44,19.1) v3(59.45,18.38) v3(59.59,33.8) v3(59.6,32.91) v3(59.56,31.19) v3(59.55,30.97) v3(59.6,28.41) v3(59.64,25.71) v3(59.6,22.99) v3(59.66,61.56) v3(59.71,59.74) v3(59.73,54.77) v3(59.72,41.83) v3(59.68,32.06) v3(59.71,30.17) v3(59.7,26.45) v3(59.75,62.88) v3(59.79,56.37) v3(59.74,44.45) v3(59.77,38.55) v3(59.76,34.5) v3(59.93,63.27) v3(59.84,58.98) v3(59.88,53.44) v3(59.89,52.93) v3(59.86,27.54) v3(59.9,27.2) v3(59.86,22.48) v3(59.85,18.37) v3(60.01,48.44) v3(60.03,31.46) v3(60.07,68.44) v3(60.13,55.17) v3(60.13,54.77) v3(60.1,35.52) v3(60.07,29.48) v3(60.08,28.42) v3(60.1,27.21) v3(60.14,31.22) v3(60.19,14.09) v3(60.34,47.28) v3(60.34,32.03) v3(60.34,22.58) v3(60.33,16.99) v3(60.4,56.56) v3(60.37,51.41) v3(60.4,30.14) v3(60.39,21.85) v3(60.54,69.29) v3(60.5,62.13) v3(60.51,58.66) v3(60.53,55.17) v3(60.5,49.89) v3(60.46,35.72) v3(60.46,29.42) v3(60.54,16.44) v3(60.48,14.09) v3(60.61,26.98) v3(60.73,60.54) v3(60.65,28.19) v3(60.66,27.55) v3(60.76,45.36) v3(60.77,34.16) v3(60.77,33.89) v3(60.81,30.89) v3(60.8,24.94) v3(60.81,22.52) v3(60.82,18.29) v3(60.76,16.42) v3(60.93,54.77) v3(60.93,54.37) v3(60.91,24.42) v3(60.92,23.1) v3(60.87,15.77) v3(61.01,67.84) v3(60.99,60.12) v3(61.02,52.4) v3(60.98,50.29) v3(61.01,35.85) v3(61,34.16) v3(61,33.89) v3(61,31.84) v3(60.97,26.06) v3(61.05,66.35) v3(61.13,62.56) v3(61.06,30.11) v3(61.15,63.27) v3(61.19,59.06) v3(61.25,61.38) v3(61.26,59.67) v3(61.33,54.77) v3(61.33,53.17) v3(61.26,44.46) v3(61.32,40.12) v3(61.31,32.16) v3(61.3,31.14) v3(61.31,29.27) v3(61.31,28.27) v3(61.31,27.27) v3(61.31,26.27) v3(61.31,25.27) v3(61.31,24.27) v3(61.31,23.27) v3(61.31,22.27) v3(61.42,58.54) v3(61.35,29.71) v3(61.44,47.6) v3(61.44,47) v3(61.44,16.39) v3(61.63,39.13) v3(61.64,30.3) v3(61.56,18.5) v3(61.73,53.57) v3(61.73,53.17) v3(61.69,52.1) v3(61.69,48.04) v3(61.7,43.6) v3(61.7,42.98) v3(61.7,35.85) v3(61.72,27.14) v3(61.71,26.75) v3(61.7,26.3) v3(61.7,25.83) v3(61.7,25.36) v3(61.7,24.89) v3(61.71,24.42) v3(61.7,23.94) v3(61.7,23.42) v3(61.7,22.88) v3(61.71,22.42) v3(61.7,21.95) v3(61.7,21.45) v3(61.7,20.95) v3(61.71,20.49) v3(61.7,19.82) v3(61.77,68.59) v3(61.83,64.61) v3(61.75,32.47) v3(61.75,31.27) v3(61.75,29.77) v3(61.75,28.57) v3(61.75,27.42) v3(61.86,40.8) v3(61.87,15.77) v3(62,60.63) v3(62.29,63.83) v3(62.25,56.69) v3(62.4,35.85) v3(62.45,68.26) v3(62.45,60.37) v3(62.52,47.08) v3(62.52,18.94) v3(62.56,48.79) v3(62.62,41.8) v3(62.66,50.82) v3(62.79,67) v3(62.79,65.56) v3(62.75,59.88) v3(62.77,15.77) v3(62.88,57.33) v3(63.09,46.31) v3(63.07,35.85) v3(63.18,45.32) v3(63.29,60.92) v3(63.26,17.02) v3(63.39,61.54) v3(63.51,49.68) v3(63.46,39.46) v3(63.52,18.94) v3(63.63,68.23) v3(63.55,56.87) v3(63.55,52.17) v3(63.68,63.38) v3(63.7,50.89) v3(63.7,48.18) v3(63.68,46.89) v3(63.72,45.69) v3(63.73,15.78) v3(63.76,64.37) v3(63.77,62.11) v3(63.78,60.06) v3(63.74,59.69) v3(63.77,58.5) v3(63.83,39.04) v3(63.76,35.85) v3(63.9,61) v3(64.01,55.45) v3(64,54.08) v3(63.98,53.06) v3(64.04,52.22) v3(64.03,51.4) v3(64.03,50.21) v3(64.05,56.67) v3(64.28,64.76) v3(64.33,48.78) v3(64.27,47.57) v3(64.33,17.03) v3(64.38,67.49) v3(64.37,66.36) v3(64.36,62.98) v3(64.42,44.06) v3(64.43,40.77) v3(64.48,65.19) v3(64.45,42.71) v3(64.44,38.69) v3(64.47,35.84) v3(64.52,18.94) v3(64.5,16.78) v3(64.63,15.42) v3(64.82,61.47) v3(64.79,17.08) v3(64.82,15.84) v3(64.79,12.58) v3(64.79,12.08) v3(64.79,11.58) v3(64.79,11.08) v3(64.89,13.78) v3(64.99,48.08) v3(64.97,46.29) v3(65.14,63.56) v3(65.17,61.93) v3(65.18,60.64) v3(65.18,58.64) v3(65.21,37.58) v3(65.16,37.08) v3(65.17,36.55) v3(65.14,36) v3(65.34,38.06) v3(65.31,16.59) v3(65.29,15.82) v3(65.37,64.64) v3(65.37,63.02) v3(65.37,56.64) v3(65.37,54.64) v3(65.37,46.13) v3(65.36,45.73) v3(65.36,45.17) v3(65.36,44.58) v3(65.36,44.17) v3(65.36,43.61) v3(65.36,43.02) v3(65.35,42.52) v3(65.36,41.96) v3(65.36,41.4) v3(65.36,40.81) v3(65.35,40.31) v3(65.35,39.71) v3(65.35,39.15) v3(65.35,38.56) v3(65.37,19.42) v3(65.47,20.24) v3(65.8,12.58) v3(65.8,12.08) v3(65.8,11.58) v3(65.8,11.08) v3(65.88,53.6) v3(65.99,51.84) v3(65.94,48.1) v3(65.94,17.61) v3(65.94,15.42) v3(66.19,18.27) v3(66.33,16.61) v3(66.37,52.51) v3(66.46,50.76) v3(66.47,20.24) v3(66.67,53.37) v3(66.69,15.43) v3(67.07,48.2) v3(67.08,18.67) v3(67.11,16.4) v3(67.2,49.46) v3(67.4,50.51) v3(67.44,15.43) v3(67.47,20.24) v3(67.86,16.62) v3(67.99,52.94) v3(68.09,48.56) v3(68.1,15.43) v3(68.15,52.71) v3(68.19,51.68) v3(68.15,50.94) v3(68.18,16.23) v3(68.33,49.31) v3(68.32,18.23) v3(68.25,17.23) v3(68.41,19.23) v3(68.47,20.24) v4(0.31,20.23) v4(0.36,19.37) v4(0.44,18.37) v4(0.44,52.2) v4(0.46,50.98) v4(0.48,49.2) v4(0.52,17.37) v4(0.59,16.36) v4(0.7,48.74) v4(0.67,15.36) v4(0.76,52.93) v4(0.84,18.28) v4(0.93,16.67) v4(1.07,52.86) v4(1.31,20.23) v4(1.5,50.41) v4(1.65,18.69) v4(1.7,16.36) v4(1.67,15.36) v4(1.82,53.35) v4(2.31,20.23) v4(2.46,18.38) v4(2.49,16.69) v4(2.47,15.36) v4(2.73,51.84) v4(2.65,48.1) v4(2.82,17.57) v4(3.11,15.36) v4(3.28,54.07) v4(3.3,46.28) v4(3.31,20.23) v4(3.41,64.79) v4(3.41,63.53) v4(3.41,62.49) v4(3.4,56.97) v4(3.4,55.18) v4(3.4,43.67) v4(3.4,40.67) v4(3.4,37.67) v4(3.42,19.41) v4(3.6,61.95) v4(3.6,61.35) v4(3.6,60.81) v4(3.6,60.28) v4(3.6,59.75) v4(3.6,59.22) v4(3.6,58.69) v4(3.6,58.16) v4(3.58,57.55) v4(3.59,48.88) v4(3.61,36.59) v4(3.6,35.51) v4(3.77,64.09) v4(3.78,48.07) v4(3.8,15.35) v4(3.9,66.93) v4(3.92,52.55) v4(3.93,43.6) v4(3.95,68.06) v4(4.01,55.62) v4(4.04,15.88) v4(4.05,50.76) v4(4.17,15.35) v4(4.25,18.94) v4(4.42,56.83) v4(4.41,38.35) v4(4.42,37.01) v4(4.41,18.2) v4(4.39,16.31) v4(4.5,67.02) v4(4.53,63.44) v4(4.5,47.62) v4(4.54,46.85) v4(4.49,44.62) v4(4.44,40.67) v4(4.49,15.64) v4(4.74,56.3) v4(4.79,35.51) v4(5.04,67.5) v4(4.98,66.17) v4(5.06,68.22) v4(5.07,52.75) v4(5.17,17.37) v4(5.17,17.19) v4(5.17,17.01) v4(5.16,16.33) v4(5.16,16.15) v4(5.16,15.97) v4(5.25,18.94) v4(5.35,48.5) v4(5.53,63.71) v4(5.53,60.16) v4(5.51,47.52) v4(5.5,46.06) v4(5.5,43.07) v4(5.5,40.39) v4(5.5,37.54) v4(5.46,15.62) v4(5.61,65.46) v4(5.55,63.9) v4(5.61,61.55) v4(5.55,36.14) v4(5.67,17.22) v4(5.81,62.73) v4(5.84,60.57) v4(5.82,56.46) v4(5.75,34.43) v4(5.87,67.65) v4(5.92,15.62) v4(5.98,49.91) v4(6.13,63.01) v4(6.11,54.32) v4(6.1,52.59) v4(6.2,55.48) v4(6.16,51.45) v4(6.19,35.51) v4(6.29,68.24) v4(6.32,65.04) v4(6.28,60.55) v4(6.25,18.94) v4(6.39,47.55) v4(6.39,46.23) v4(6.39,43.07) v4(6.39,40.12) v4(6.39,36.87) v4(6.39,36.6) v4(6.41,33.79) v4(6.51,48.51) v4(6.61,67.65) v4(6.56,63.87) v4(6.56,18.43) v4(6.71,57.69) v4(6.81,58.81) v4(6.74,49.95) v4(6.91,64.11) v4(6.92,61.16) v4(6.88,34.8) v4(6.94,56.13) v4(7.02,33.16) v4(7.02,32.26) v4(7.02,31.24) v4(7.02,30.48) v4(7.02,29.52) v4(7.02,28.52) v4(7.01,27) v4(7.03,25.44) v4(7.03,23.44) v4(7.03,20.24) v4(7.01,19.62) v4(7.03,19.01) v4(6.99,15.64) v4(7.2,68.72) v4(7.17,63.01) v4(7.31,50.77) v4(7.35,49.36) v4(7.42,15.22) v4(7.44,62.28) v4(7.44,62.06) v4(7.48,58.76) v4(7.52,47.76) v4(7.48,43.04) v4(7.47,39.74) v4(7.48,35.51) v4(7.61,67.65) v4(7.57,60.15) v4(7.57,55.45) v4(7.59,52.93) v4(7.64,63.45) v4(7.74,53.77) v4(7.75,44.64) v4(7.77,37.06) v4(7.83,33.85) v4(7.78,14.87) v4(7.9,18.41) v4(8.01,69.32) v4(7.95,64.72) v4(8.01,55.94) v4(8.06,47.51) v4(8.12,40.94) v4(8.11,19.63) v4(8.19,65.2) v4(8.21,46.47) v4(8.23,44.23) v4(8.28,58.78) v4(8.27,42.14) v4(8.26,39.51) v4(8.27,37.87) v4(8.24,15.6) v4(8.24,14.41) v4(8.29,9.18) v4(8.29,8.52) v4(8.28,8.01) v4(8.38,57.63) v4(8.41,19.32) v4(8.47,65.19) v4(8.52,51.52) v4(8.48,36.24) v4(8.53,34.45) v4(8.63,59.7) v4(8.56,47.6) v4(8.67,67.65) v4(8.66,65.23) v4(8.67,53.16) v4(8.65,50.06) v4(8.71,41.26) v4(8.68,15.16) v4(8.71,9.9) v4(8.82,64.73) v4(8.74,62.31) v4(8.82,36.8) v4(8.83,18.91) v4(8.79,17.57) v4(8.74,13.84) v4(8.99,69.33) v4(9.01,64.11) v4(9.07,14.82) v4(9.19,63.08) v4(9.14,56.28) v4(9.22,35.5) v4(9.23,10.48) v4(9.34,55.51) v4(9.3,48.6) v4(9.34,45.39) v4(9.27,43.87) v4(9.39,66.9) v4(9.39,51.68) v4(9.35,46.65) v4(9.39,18.34) v4(9.39,11.36) v4(9.39,11.11) v4(9.53,42.25) v4(9.53,39.08) v4(9.49,8) v4(9.63,57.87) v4(9.64,15.92) v4(9.55,8.42) v4(9.7,57.4) v4(9.73,52.49) v4(9.69,11.36) v4(9.69,11.11) v4(9.77,48.04) v4(9.75,37.55) v4(9.83,21.04) v4(9.82,17.92) v4(9.81,15.29) v4(9.8,13.84) v4(9.92,10.14) v4(9.93,9.59) v4(9.94,68.59) v4(9.94,8.92) v4(10.12,53.77) v4(10.08,38.12) v4(10.09,36.4) v4(10.07,11.11) v4(10.19,44.3) v4(10.19,41.95) v4(10.21,39.67) v4(10.17,32.86) v4(10.17,32.44) v4(10.17,31.86) v4(10.17,31.6) v4(10.17,31.34) v4(10.18,30.6) v4(10.19,30.21) v4(10.19,29.54) v4(10.21,26.2) v4(10.22,21.44) v4(10.43,67.6) v4(10.35,17.1) v4(10.44,66.4) v4(10.44,63.11) v4(10.52,39.08) v4(10.46,30.77) v4(10.46,29.54) v4(10.5,28.65) v4(10.51,22.06) v4(10.49,9.97) v4(10.61,40.09) v4(10.64,36.34) v4(10.61,30.27) v4(10.58,16.53) v4(10.67,60.64) v4(10.69,44.69) v4(10.69,41.84) v4(10.69,35.76) v4(10.71,24.35) v4(10.72,14.58) v4(10.71,13.7) v4(10.8,46.94) v4(10.75,43.72) v4(10.81,11.11) v4(10.78,9.98) v4(10.78,9.06) v4(10.92,38.26) v4(10.91,28.27) v4(11.04,16.7) v4(10.95,13.13) v4(10.97,10.49) v4(11.08,68.74) v4(11.12,13.46) v4(11.11,13.04) v4(11.15,31.76) v4(11.21,31.59) v4(11.15,29.43) v4(11.17,28.72) v4(11.23,26.46) v4(11.25,67.66) v4(11.25,67.47) v4(11.32,48.41) v4(11.31,32.85) v4(11.25,27.96) v4(11.28,11.11) v4(11.3,9.96) v4(11.3,9.34) v4(11.43,67.66) v4(11.43,67.47) v4(11.35,48.03) v4(11.39,40.63) v4(11.34,39.6) v4(11.35,34.34) v4(11.35,32.48) v4(11.35,25.6) v4(11.43,23.97) v4(11.41,14.98) v4(11.53,69.33) v4(11.52,47.07) v4(11.52,44.68) v4(11.53,42.7) v4(11.54,35.79) v4(11.46,24.68) v4(11.61,67.66) v4(11.61,67.47) v4(11.58,61.59) v4(11.54,34.9) v4(11.64,16.09) v4(11.59,11.51) v4(11.59,9.97) v4(11.65,41.72) v4(11.79,67.66) v4(11.79,67.47) v4(11.79,39.2) v4(11.74,31.92) v4(11.74,26.74) v4(11.78,23.23) v4(11.76,14.59) v4(11.91,22.24) v4(12.01,36.17) v4(11.96,13.67) v4(12.08,47.23) v4(12.04,43.45) v4(12.11,11.59) v4(12.06,10.45) v4(12.12,9.84) v4(12.17,68.59) v4(12.16,46.09) v4(12.21,42.37) v4(12.17,39.61) v4(12.25,44.14) v4(12.32,38) v4(12.24,32.89) v4(12.24,25.8) v4(12.33,14.06) v4(12.42,12.14) v4(12.42,11.08) v4(12.42,10.54) v4(12.44,11.6) v4(12.49,9.98) v4(12.62,18.47) v4(12.73,65.29) v4(12.68,23.08) v4(12.68,17.72) v4(12.7,13.68) v4(12.77,61.48) v4(12.86,48.24) v4(12.88,46.41) v4(12.86,44.35) v4(12.9,40.75) v4(12.86,38.55) v4(13.01,67.6) v4(12.98,65.78) v4(13.02,56.48) v4(12.95,50.2) v4(12.94,20.52) v4(13.02,11.4) v4(13.09,22.05) v4(13.09,13.25) v4(13.11,12.8) v4(13.22,17.82) v4(13.16,14.59) v4(13.19,12.55) v4(13.15,12.25) v4(13.16,10.48) v4(13.16,9.66) v4(13.16,8.99) v4(13.17,8.38) v4(13.34,61.53) v4(13.29,52.46) v4(13.33,37.83) v4(13.25,34.69) v4(13.24,19.69) v4(13.39,36.25) v4(13.4,35.46) v4(13.4,34.86) v4(13.37,33.56) v4(13.54,37.28) v4(13.52,27.74) v4(13.48,20.64) v4(13.51,9.98) v4(13.49,8.15) v4(13.55,36.72) v4(13.56,31.45) v4(13.56,28.7) v4(13.55,25.9) v4(13.56,24.65) v4(13.56,24.46) v4(13.67,66.64) v4(13.65,50.73) v4(13.66,48.51) v4(13.69,46.24) v4(13.67,44.1) v4(13.65,42.38) v4(13.67,41.44) v4(13.69,19.22) v4(13.71,18.27) v4(13.71,12.07) v4(13.77,57.32) v4(13.76,39.73) v4(13.96,65.79) v4(14.04,24.74) v4(14.01,17.67) v4(14.13,68.75) v4(14.08,65.29) v4(14.1,21.89) v4(14.1,19.81) v4(14.16,18.66) v4(14.22,13.6) v4(14.3,67.52) v4(14.31,38.6) v4(14.42,12.4) v4(14.4,9.98) v4(14.41,9.06) v4(14.54,66.64) v4(14.5,39.53) v4(14.47,20.64) v4(14.47,14.36) v4(14.53,11.67) v4(14.47,10.75) v4(14.6,61.52) v4(14.6,28.51) v4(14.61,26.02) v4(14.57,21.96) v4(14.62,17.71) v4(14.58,8.15) v4(14.73,39.75) v4(14.65,38.6) v4(14.66,36.58) v4(14.69,29.88) v4(14.66,20.34) v4(14.65,13.25) v4(14.71,9.98) v4(14.77,68.74) v4(14.84,35.43) v4(14.74,29.23) v4(14.74,18.87) v4(14.85,39.21) v4(14.86,38.25) v4(14.91,8.69) v4(15.02,69.13) v4(14.97,66.27) v4(15.01,58.55) v4(15.02,38.5) v4(15,36.21) v4(14.97,34.89) v4(14.96,16.55) v4(15.05,57.88) v4(15.05,37.66) v4(15.11,33.11) v4(15.13,30.04) v4(15.11,20.65) v4(15.07,20.06) v4(15.12,10.8) v4(15.15,31.15) v4(15.17,26.93) v4(15.17,22.75) v4(15.33,38.76) v4(15.31,32.22) v4(15.29,16.36) v4(15.38,65.79) v4(15.42,57.08) v4(15.35,39.77) v4(15.38,39.55) v4(15.38,16.9) v4(15.41,8.15) v4(15.5,68.13) v4(15.45,17.76) v4(15.64,58.46) v4(15.61,32.7) v4(15.72,32.19) v4(15.72,31.84) v4(15.68,30.6) v4(15.73,29.67) v4(15.7,27.09) v4(15.71,23.74) v4(15.71,23.42) v4(15.73,19.17) v4(15.76,57.42) v4(15.79,22.58) v4(15.75,21.94) v4(15.74,20.92) v4(15.75,20.05) v4(15.78,14.5) v4(15.79,10.71) v4(15.86,38.76) v4(15.93,18.21) v4(16.19,66.59) v4(16.2,66.02) v4(16.22,65.12) v4(16.17,57.78) v4(16.14,23.86) v4(16.18,23.39) v4(16.18,22.96) v4(16.18,21.33) v4(16.18,19.87) v4(16.28,63.92) v4(16.31,18.48) v4(16.28,14.54) v4(16.35,68.6) v4(16.36,66.92) v4(16.42,38.76) v4(16.4,11.21) v4(16.39,10.7) v4(16.54,66.92) v4(16.48,17.73) v4(16.51,8.16) v4(16.57,67.77) v4(16.62,58.46) v4(16.73,12.78) v4(16.66,10.25) v4(16.81,38.76) v4(16.77,14.77) v4(16.78,8.8) v4(16.96,69.31) v4(17.02,57.78) v4(17.2,38.76) v4(17.18,8.45) v4(17.3,68.11) v4(17.25,56.61) v4(17.29,9.45) v4(17.51,63.9) v4(17.49,15.34) v4(17.5,12.75) v4(17.55,10.58) v4(17.65,58.25) v4(17.75,56.31) v4(17.75,10.05) v4(17.92,67.56) v4(17.94,42.92) v4(17.95,40.59) v4(18.19,57.37) v4(18.23,37.25) v4(18.23,13.75) v4(18.32,68.06) v4(18.31,16.48) v4(18.27,10.47) v4(18.43,67.47) v4(18.51,56.31) v4(18.49,12.07) v4(18.55,15.62) v4(18.67,69.12) v4(18.67,39.25) v4(18.69,38.46) v4(18.82,20.43) v4(18.83,19.84) v4(18.83,10.46) v4(18.85,20.98) v4(19.02,21.73) v4(18.99,14.09) v4(19.09,64.31) v4(19.06,53) v4(19.08,39.26) v4(19.13,11.81) v4(19.14,37.93) v4(19.14,37.15) v4(19.16,13.67) v4(19.34,25.31) v4(19.27,10.59) v4(19.43,37.62) v4(19.46,26.37) v4(19.44,19.27) v4(19.6,68.72) v4(19.63,53.23) v4(19.54,21.26) v4(19.65,63.15) v4(19.7,50.94) v4(19.73,37.65) v4(19.72,33.78) v4(19.7,31.34) v4(19.71,25.01) v4(19.74,12.59) v4(19.84,66.91) v4(19.77,35.43) v4(19.82,22.21) v4(19.84,10.48) v4(19.93,51.41) v4(19.91,50.45) v4(19.93,23.61) v4(19.86,14.9) v4(19.95,49.36) v4(19.98,24.42) v4(19.98,21.71) v4(20.02,21.02) v4(20.03,13.28) v4(20.08,35.86) v4(20.15,18.9) v4(20.22,18.51) v4(20.34,35.52) v4(20.31,30.79) v4(20.31,25.76) v4(20.32,22.05) v4(20.42,58.52) v4(20.37,33.72) v4(20.5,23.47) v4(20.5,20.73) v4(20.46,19.05) v4(20.54,56.57) v4(20.55,13.62) v4(20.61,11.82) v4(20.63,10.49) v4(20.67,58.02) v4(20.71,56.72) v4(20.76,57.69) v4(20.83,35.45) v4(20.75,34.14) v4(20.84,22.62) v4(20.79,21.75) v4(20.84,20.7) v4(20.83,17.91) v4(20.86,23.44) v4(20.96,33.09) v4(21.07,13.71) v4(21.1,10.47) v4(21.15,68.69) v4(21.14,53.97) v4(21.22,40.29) v4(21.24,38.42) v4(21.17,34.36) v4(21.17,19.11) v4(21.25,67.46) v4(21.26,54.83) v4(21.33,33.88) v4(21.42,24.57) v4(21.48,11.81) v4(21.54,31.33) v4(21.54,30.75) v4(21.54,29.12) v4(21.54,23.06) v4(21.63,21.52) v4(21.55,12.62) v4(21.74,27.55) v4(21.68,19.51) v4(21.65,10.08) v4(21.81,53.21) v4(21.88,68.03) v4(21.91,66.89) v4(21.84,32.05) v4(21.93,26.07) v4(22,54.55) v4(22.01,26.9) v4(22.01,12.77) v4(22.12,45.64) v4(22.09,44.33) v4(22.12,41.81) v4(22.17,39.52) v4(22.16,38.34) v4(22.21,35.51) v4(22.24,28.12) v4(22.21,25.64) v4(22.16,18.7) v4(22.24,17.06) v4(22.15,9.63) v4(22.3,16.44) v4(22.3,15.81) v4(22.36,24.29) v4(22.41,19.19) v4(22.43,17.6) v4(22.45,50.44) v4(22.45,48.94) v4(22.45,30.84) v4(22.48,22.25) v4(22.52,21.84) v4(22.52,11.67) v4(22.63,40.34) v4(22.63,38.85) v4(22.65,65.96) v4(22.7,55.89) v4(22.73,33.74) v4(22.71,30.16) v4(22.7,29.6) v4(22.66,28.85) v4(22.68,28.4) v4(22.68,25.87) v4(22.66,21.09) v4(22.69,18.57) v4(22.7,12.07) v4(22.77,34.55) v4(22.76,26.55) v4(22.75,10.75) v4(22.85,68.69) v4(23.03,29.65) v4(23.22,39.25) v4(23.16,27.84) v4(23.16,26.55) v4(23.14,16.44) v4(23.15,11.37) v4(23.34,65.14) v4(23.34,45.24) v4(23.3,18.7) v4(23.32,9.61) v4(23.43,63.37) v4(23.43,62.52) v4(23.42,44.33) v4(23.42,29.08) v4(23.37,24.21) v4(23.38,23.33) v4(23.43,11.82) v4(23.46,60.31) v4(23.53,60.02) v4(23.48,28.45) v4(23.46,23.07) v4(23.44,21.84) v4(23.47,21.11) v4(23.6,60.53) v4(23.62,15.81) v4(23.62,10.75) v4(23.65,39.7) v4(23.69,36.53) v4(23.71,23.71) v4(23.76,28.59) v4(23.92,60.66) v4(23.88,60.36) v4(23.93,23.43) v4(23.86,11.37) v4(23.97,59.57) v4(23.94,25.67) v4(23.98,19.41) v4(24,11.66) v4(24.05,58.77) v4(24.07,57.38) v4(24.09,56.84) v4(24.13,38.59) v4(24.12,22.26) v4(24.21,23.52) v4(24.22,20.78) v4(24.19,16.3) v4(24.23,15.31) v4(24.31,64.24) v4(24.27,28.02) v4(24.31,9.62) v4(24.63,68.7) v4(24.61,61.51) v4(24.55,59.97) v4(24.55,57.98) v4(24.6,41.37) v4(24.6,38.47) v4(24.63,24.45) v4(24.63,22.85) v4(24.56,10.74) v4(24.71,55.06) v4(24.71,29.2) v4(24.72,28.02) v4(24.73,27.5) v4(24.74,23.68) v4(24.71,15.41) v4(24.72,11.28) v4(24.81,65.99) v4(24.79,61.06) v4(24.78,14.75) v4(24.92,62.61) v4(24.91,62.06) v4(24.92,61.52) v4(24.93,60.67) v4(24.85,35.62) v4(24.87,22.1) v4(24.85,15.91) v4(24.96,33.84) v4(24.99,20.92) v4(25.01,19.7) v4(25.01,17.63) v4(24.94,9.61) v4(25.09,67.5) v4(25.07,41.42) v4(25.07,38.59) v4(25.13,19.21) v4(25.09,18.23) v4(25.18,64.97) v4(25.23,30.54) v4(25.23,28.84) v4(25.22,24.59) v4(25.21,23.62) v4(25.26,57.36) v4(25.31,55.89) v4(25.26,28.08) v4(25.31,25.71) v4(25.3,23.92) v4(25.29,22.23) v4(25.3,14.93) v4(25.37,14.17) v4(25.35,10.76) v4(25.48,61.51) v4(25.51,60.67) v4(25.49,59.92) v4(25.53,41.05) v4(25.53,23.12) v4(25.52,11.28) v4(25.64,58.61) v4(25.57,53.8) v4(25.57,52.8) v4(25.57,50.8) v4(25.57,48.8) v4(25.57,46.91) v4(25.57,44.8) v4(25.57,42.8) v4(25.55,27.55) v4(25.55,21.85) v4(25.62,20.96) v4(25.62,8.94) v4(25.74,61.5) v4(25.71,31.07) v4(25.74,30.62) v4(25.72,29.05) v4(25.71,27.36) v4(25.69,26.74) v4(25.7,18.49) v4(25.76,62.06) v4(25.76,58.08) v4(25.76,32.6) v4(25.9,63.2) v4(25.88,58.56) v4(25.93,35.48) v4(25.85,23.39) v4(25.88,13.66) v4(25.94,22.49) v4(26,10.82) v4(26.07,63.98) v4(26.08,62.07) v4(26.09,32.61) v4(26.05,32.1) v4(26.1,21.39) v4(26.24,35.49) v4(26.24,34.98) v4(26.24,22.38) v4(26.14,17.15) v4(26.31,62.61) v4(26.29,27.47) v4(26.34,26.38) v4(26.33,16.31) v4(26.27,14.21) v4(26.34,8.22) v4(26.44,35.27) v4(26.43,13.12) v4(26.42,10.4) v4(26.47,68.7) v4(26.53,66.08) v4(26.49,31.87) v4(26.48,27.84) v4(26.47,18.57) v4(26.52,13.65) v4(26.58,62.12) v4(26.58,36.16) v4(26.58,25.09) v4(26.57,23.4) v4(26.65,63.35) v4(26.65,35.8) v4(26.69,34.09) v4(26.7,33.36) v4(26.66,32.36) v4(26.68,30.07) v4(26.69,29.26) v4(26.69,24.07) v4(26.69,21.91) v4(26.67,19.92) v4(26.71,19.2) v4(26.81,62.63) v4(26.82,60.11) v4(26.74,31.43) v4(26.79,31.02) v4(26.77,28.79) v4(26.76,27.52) v4(26.79,17.18) v4(26.79,10.02) v4(26.9,63.3) v4(26.93,53.94) v4(26.88,12.67) v4(26.97,27.81) v4(27,21.12) v4(27.07,57.39) v4(27.11,30.91) v4(27.06,21.96) v4(27.1,19.39) v4(27.14,34.54) v4(27.18,33.59) v4(27.18,32.34) v4(27.17,20.05) v4(27.15,15.42) v4(27.17,9.66) v4(27.17,8.95) v4(27.14,7.42) v4(27.31,63.36) v4(27.29,61.15) v4(27.29,36.82) v4(27.28,31.56) v4(27.28,23.92) v4(27.29,23.38) v4(27.35,28.52) v4(27.35,27.23) v4(27.43,24.82) v4(27.34,21.67) v4(27.41,12.16) v4(27.47,56.25) v4(27.45,31.13) v4(27.52,9.28) v4(27.62,63.36) v4(27.62,62.09) v4(27.56,24.15) v4(27.57,22.24) v4(27.54,21.88) v4(27.63,20.35) v4(27.61,17.88) v4(27.61,14.94) v4(27.7,51.54) v4(27.74,49.39) v4(27.72,47.77) v4(27.72,45.77) v4(27.73,43.78) v4(27.71,41.77) v4(27.72,39.78) v4(27.71,37.77) v4(27.68,34.64) v4(27.69,31.95) v4(27.69,31.52) v4(27.73,23.93) v4(27.73,16.76) v4(27.7,13.25) v4(27.8,64.53) v4(27.79,23.38) v4(27.82,11.73) v4(27.83,6.73) v4(27.87,35.73) v4(27.85,30.43) v4(27.86,29.95) v4(27.88,28.25) v4(27.87,27.78) v4(27.93,26.4) v4(27.84,8.98) v4(27.97,63.36) v4(27.95,54.96) v4(27.97,53.78) v4(27.95,32.18) v4(27.96,29.16) v4(28.1,61.96) v4(28.06,54.34) v4(28.04,21.88) v4(28.08,18.85) v4(28.16,66.91) v4(28.18,66.35) v4(28.21,35.06) v4(28.24,23.43) v4(28.24,17.04) v4(28.17,11.38) v4(28.32,68.7) v4(28.29,63.36) v4(28.32,30.72) v4(28.28,23.92) v4(28.29,21.88) v4(28.3,5.53) v4(28.43,62.39) v4(28.37,57.39) v4(28.42,51.53) v4(28.42,38.72) v4(28.42,37.84) v4(28.44,36.98) v4(28.4,31.88) v4(28.44,29.13) v4(28.44,28.25) v4(28.44,27.79) v4(28.39,14.02) v4(28.45,28.47) v4(28.46,27.04) v4(28.49,19.22) v4(28.51,13.5) v4(28.5,8.85) v4(28.46,8.35) v4(28.59,64.06) v4(28.54,57.55) v4(28.56,39.25) v4(28.57,32.84) v4(28.61,24.56) v4(28.54,22.13) v4(28.63,18) v4(28.71,63.37) v4(28.72,57.39) v4(28.65,25.67) v4(28.68,25.19) v4(28.69,23.38) v4(28.67,13.33) v4(28.81,61.98) v4(28.75,34.03) v4(28.77,24.19) v4(28.79,22.38) v4(28.82,21.62) v4(28.79,17.14) v4(28.78,10.8) v4(28.92,66.52) v4(28.91,57.55) v4(28.9,54.48) v4(28.87,35.23) v4(28.91,33.16) v4(28.85,32.26) v4(28.91,27.45) v4(28.84,23.78) v4(28.94,17.82) v4(28.85,10.3) v4(28.85,10.12) v4(29.02,67.52) v4(28.97,62.81) v4(29.03,24.6) v4(29.03,10.3) v4(29.03,10.12) v4(29.01,7.11) v4(29.01,6.38) v4(28.95,4.78) v4(28.97,3.76) v4(28.97,2.65) v4(28.97,1.41) v4(29.1,63.36) v4(29.07,49.18) v4(29.12,48.06) v4(29.08,28.65) v4(29.04,22.63) v4(29.07,18.52) v4(29.16,24.03) v4(29.17,14.21) v4(29.16,8.84) v4(29.17,7.64) v4(29.25,57.55) v4(29.29,25.59) v4(29.32,20.99) v4(29.28,19.45) v4(29.32,17.33) v4(29.44,66.77) v4(29.42,63.36) v4(29.43,50.22) v4(29.37,28.12) v4(29.41,27.78) v4(29.35,14.27) v4(29.42,10.8) v4(29.46,65.79) v4(29.53,19.07) v4(29.47,16.65) v4(29.47,15.39) v4(29.47,13.72) v4(29.6,64.17) v4(29.57,57.55) v4(29.62,33.86) v4(29.55,33.09) v4(29.6,24.59) v4(29.62,24.21) v4(29.63,23.34) v4(29.63,22.23) v4(29.59,17.91) v4(29.55,16.88) v4(29.54,16.11) v4(29.58,15.74) v4(29.56,10.07) v4(29.67,13.58) v4(29.67,13.37) v4(29.7,4.31) v4(29.74,3.78) v4(29.75,64.83) v4(29.81,62.38) v4(29.77,31.07) v4(29.75,30.68) v4(29.8,14.53) v4(29.8,12.54) v4(29.81,10.43) v4(29.76,9.91) v4(29.81,8.85) v4(29.75,0.32) v4(29.88,64.11) v4(29.86,57.31) v4(29.93,50.7) v4(29.87,34.23) v4(29.94,16.39) v4(29.92,15.08) v4(29.94,12.23) v4(29.94,9.59) v4(29.94,9.2) v4(29.97,65.55) v4(29.98,63.36) v4(29.98,27.04) v4(30.03,15.88) v4(30.01,10.11) v4(30.04,67.54) v4(30.04,54.47) v4(30.13,32.65) v4(30.07,29.09) v4(30.04,28.64) v4(30.06,28.25) v4(30.09,26.17) v4(30.09,24.59) v4(30.09,23.5) v4(30.1,22.06) v4(30.06,20.21) v4(30.04,17.26) v4(30.1,13.58) v4(30.11,13.37) v4(30.17,68.7) v4(30.21,63.02) v4(30.31,17.5) v4(30.29,15.68) v4(30.26,11.64) v4(30.41,32.45) v4(30.44,15.29) v4(30.39,14.3) v4(30.39,13.83) v4(30.39,12.93) v4(30.38,12.46) v4(30.42,8.79) v4(30.41,8.48) v4(30.42,8.12) v4(30.5,16.21) v4(30.55,48.51) v4(30.59,47.48) v4(30.58,44.04) v4(30.55,40.33) v4(30.56,39.51) v4(30.56,37.94) v4(30.55,36.91) v4(30.55,36.52) v4(30.58,30.53) v4(30.59,29.1) v4(30.55,28.25) v4(30.55,27.78) v4(30.55,26.59) v4(30.55,25.33) v4(30.55,25.13) v4(30.56,24.9) v4(30.55,24.16) v4(30.62,23.5) v4(30.57,21.54) v4(30.64,18.56) v4(30.62,17.13) v4(30.6,0.86) v4(30.65,20.87) v4(30.71,20.29) v4(30.65,19.79) v4(30.65,18.2) v4(30.65,17.65) v4(30.66,16.79) v4(30.72,13.72) v4(30.65,11.47) v4(30.82,46.87) v4(30.82,46.42) v4(30.8,32.68) v4(30.81,31.04) v4(30.82,23.5) v4(30.82,14.52) v4(30.87,33.23) v4(30.87,31.93) v4(30.9,22.28) v4(30.94,20.79) v4(30.91,13.22) v4(30.92,11.94) v4(31.04,39.05) v4(30.97,12.58) v4(31.06,39.71) v4(31.1,28.24) v4(31.09,27.76) v4(31.08,27.03) v4(31.09,25.98) v4(31.09,24.78) v4(31.13,19.47) v4(31.13,18.96) v4(31.13,15.88) v4(31.13,14.22) v4(31.08,4.32) v4(31.1,3.63) v4(31.1,2.96) v4(31.11,2.22) v4(31.23,51.54) v4(31.14,29.68) v4(31.14,18.32) v4(31.14,17.64) v4(31.15,16.97) v4(31.23,12.46) v4(31.2,6.9) v4(31.2,6.68) v4(31.24,48.06) v4(31.29,31.54) v4(31.29,23.51) v4(31.27,19.89) v4(31.28,13.72) v4(31.31,12.93) v4(31.27,11.24) v4(31.27,10.84) v4(31.35,32.75) v4(31.4,19.21) v4(31.41,15.52) v4(31.44,6.64) v4(31.51,68.69) v4(31.54,59.55) v4(31.5,21.18) v4(31.47,20.53) v4(31.54,19.7) v4(31.49,18.58) v4(31.48,17.94) v4(31.49,14.98) v4(31.49,14.23) v4(31.5,1.16) v4(31.55,30.52) v4(31.57,17.35) v4(31.59,16.23) v4(31.63,13.55) v4(31.63,13.29) v4(31.64,10.42) v4(31.64,6.95) v4(31.68,64.17) v4(31.7,41.54) v4(31.66,11.55) v4(31.82,46.85) v4(31.78,43.34) v4(31.79,35.68) v4(31.8,31.68) v4(31.81,29.09) v4(31.81,23.52) v4(31.78,13.12) v4(31.79,3.62) v4(31.79,2.21) v4(31.79,1.45) v4(31.94,62.97) v4(31.89,55.68) v4(31.9,50.72) v4(31.88,35.22) v4(31.87,32.23) v4(31.93,15.56) v4(31.96,27.94) v4(31.97,27.04) v4(31.98,25.33) v4(31.99,24.86) v4(31.98,19.39) v4(31.96,18.19) v4(32.02,17.47) v4(32,16.57) v4(31.97,14.56) v4(31.96,14.13) v4(31.96,10.84) v4(32.09,22.77) v4(32.11,21.75) v4(32.12,20.97) v4(32.05,12.5) v4(32.11,11.25) v4(32.09,1.14) v4(32.17,66.43) v4(32.19,55.42) v4(32.18,39.05) v4(32.22,15.24) v4(32.27,62.95) v4(32.29,58.03) v4(32.32,45.71) v4(32.32,45.34) v4(32.32,38.93) v4(32.25,28.67) v4(32.34,64.03) v4(32.4,13.12) v4(32.41,10.64) v4(32.41,5.04) v4(32.44,56.98) v4(32.47,43.24) v4(32.46,38.8) v4(32.54,35.77) v4(32.45,27.6) v4(32.52,27.09) v4(32.48,20.45) v4(32.49,18.29) v4(32.48,17.75) v4(32.45,16.79) v4(32.5,15.76) v4(32.48,13.73) v4(32.44,11.06) v4(32.52,7.88) v4(32.51,7.64) v4(32.51,7.42) v4(32.51,7.19) v4(32.51,6.97) v4(32.48,2.06) v4(32.6,67.82) v4(32.64,63.59) v4(32.55,58.14) v4(32.61,45.42) v4(32.6,45.08) v4(32.57,26.17) v4(32.61,24.89) v4(32.57,19.19) v4(32.64,6.75) v4(32.69,23.56) v4(32.7,23.14) v4(32.67,22.03) v4(32.7,21.23) v4(32.66,12.93) v4(32.69,10.31) v4(32.8,68.7) v4(32.76,63.18) v4(32.75,57.95) v4(32.83,56.99) v4(32.79,55.95) v4(32.78,43.34) v4(32.83,41.62) v4(32.83,41.44) v4(32.79,39.64) v4(32.75,29.01) v4(32.81,10.75) v4(32.78,7.89) v4(32.76,3.02) v4(32.79,1.15) v4(32.93,46.45) v4(32.86,34.13) v4(32.87,31.23) v4(32.92,17.5) v4(32.91,13.39) v4(32.89,12.5) v4(32.9,6.75) v4(32.97,63.94) v4(33,63.47) v4(33,63.03) v4(32.97,39.64) v4(33.01,16.07) v4(32.96,5.18) v4(33.01,2.06) v4(33.1,30.35) v4(33.06,25.33) v4(33.05,20.14) v4(33.07,19.26) v4(33.12,10.47) v4(33.06,9.93) v4(33.05,7.89) v4(33.09,1.45) v4(33.14,16.91) v4(33.15,14.35) v4(33.16,13.85) v4(33.17,6.75) v4(33.16,3.99) v4(33.26,47.08) v4(33.25,45.16) v4(33.24,29.1) v4(33.34,24.89) v4(33.29,7.89) v4(33.42,63.5) v4(33.41,44.5) v4(33.38,38.84) v4(33.38,38.65) v4(33.41,36.16) v4(33.42,28.23) v4(33.43,25.75) v4(33.43,17.9) v4(33.42,17.62) v4(33.39,10.21) v4(33.36,9.55) v4(33.39,1.14) v4(33.47,39.52) v4(33.48,21) v4(33.49,18.54) v4(33.51,13.11) v4(33.46,8.14) v4(33.48,7.73) v4(33.48,6.83) v4(33.48,3.37) v4(33.6,43.34) v4(33.63,14.78) v4(33.56,9.89) v4(33.58,9.33) v4(33.72,41.01) v4(33.73,2.21) v4(33.82,63.61) v4(33.77,46.62) v4(33.83,45.8) v4(33.79,33.31) v4(33.84,30.22) v4(33.81,29.09) v4(33.84,19.23) v4(33.79,16.26) v4(33.86,67.1) v4(33.94,27.08) v4(33.87,20.37) v4(33.85,19.77) v4(33.92,18.02) v4(33.94,17.61) v4(33.91,15.37) v4(33.89,12.97) v4(33.88,12.37) v4(33.89,11.84) v4(33.9,11.34) v4(33.92,10.76) v4(33.88,9.49) v4(33.99,43.91) v4(33.96,28.3) v4(33.97,24.89) v4(34,23.55) v4(34.01,20.82) v4(33.98,13.38) v4(33.98,8.04) v4(34.01,4.46) v4(34.1,68.69) v4(34.08,65.64) v4(34.08,63.94) v4(34.13,46.99) v4(34.04,9.11) v4(34.07,8.67) v4(34.08,8.33) v4(34.09,1.14) v4(34.22,66.52) v4(34.16,44.5) v4(34.19,29.83) v4(34.14,19.23) v4(34.14,7.72) v4(34.19,5.21) v4(34.26,58.83) v4(34.3,39.39) v4(34.42,63.5) v4(34.37,34.6) v4(34.4,28.99) v4(34.43,11.94) v4(34.38,3.63) v4(34.39,2.21) v4(34.39,1.45) v4(34.53,56.25) v4(34.46,55.69) v4(34.45,35.76) v4(34.5,27.11) v4(34.47,26.16) v4(34.54,23.55) v4(34.54,15.94) v4(34.44,10.73) v4(34.45,7.85) v4(34.45,6.56) v4(34.64,61.72) v4(34.56,44.55) v4(34.57,25.33) v4(34.64,24.24) v4(34.61,21.97) v4(34.55,14.12) v4(34.55,13.38) v4(34.74,63.74) v4(34.66,44) v4(34.71,27.61) v4(34.65,24.9) v4(34.65,20.9) v4(34.65,18.96) v4(34.66,18.04) v4(34.69,17.15) v4(34.7,7.02) v4(34.64,6.02) v4(34.69,1.14) v4(34.77,67.82) v4(34.77,65.64) v4(34.76,62.72) v4(34.78,43.34) v4(34.82,32.42) v4(34.77,29.32) v4(34.78,27.3) v4(34.79,15.11) v4(34.91,44.5) v4(34.89,42.31) v4(34.99,64.62) v4(34.98,54.23) v4(34.98,28.62) v4(35.01,25.75) v4(35,14.38) v4(34.96,10.74) v4(34.97,10.3) v4(34.97,9.72) v4(34.96,9.19) v4(34.97,8.46) v4(35.07,29.03) v4(35.09,13.1) v4(35.05,11.94) v4(35.05,5.22) v4(35.04,3.63) v4(35.04,2.21) v4(35.21,62.55) v4(35.26,66.51) v4(35.32,62.94) v4(35.31,45.78) v4(35.27,27.18) v4(35.41,13.32) v4(35.36,8.01) v4(35.38,4.43) v4(35.39,1.16) v4(35.5,68.69) v4(35.5,39.82) v4(35.47,15.94) v4(35.52,14.57) v4(35.47,7.18) v4(35.49,5.72) v4(35.63,64.34) v4(35.58,60.31) v4(35.58,27.14) v4(35.56,26.59) v4(35.72,63.71) v4(35.72,62.94) v4(35.67,62.51) v4(35.66,61.08) v4(35.68,31.93) v4(35.69,1.45) v4(35.8,16.15) v4(35.81,15.46) v4(35.83,8.01) v4(35.74,3.65) v4(35.81,1.97) v4(35.93,63.71) v4(35.85,61.86) v4(35.85,45.3) v4(35.91,44.5) v4(35.91,43.75) v4(35.88,11.61) v4(35.85,6.31) v4(35.97,62.5) v4(35.98,55.78) v4(36.03,54.17) v4(36.03,41.79) v4(35.98,36.16) v4(36.03,13.34) v4(35.96,7.47) v4(36,1.15) v4(36.09,61.86) v4(36.06,45.78) v4(36.06,35.75) v4(36.05,30.92) v4(36.12,11.98) v4(36.05,11.07) v4(36.05,10.36) v4(36.06,9.77) v4(36.05,9.11) v4(36.05,8.5) v4(36.07,4.62) v4(36.22,62.94) v4(36.22,41.03) v4(36.2,34.6) v4(36.32,67.1) v4(36.31,66.52) v4(36.24,39.07) v4(36.27,14.63) v4(36.28,13.48) v4(36.28,9.33) v4(36.26,8.43) v4(36.26,8.03) v4(36.31,6.8) v4(36.3,1.97) v4(36.43,43.45) v4(36.49,45.3) v4(36.5,44.3) v4(36.52,40.9) v4(36.49,23.55) v4(36.49,20.91) v4(36.49,20.31) v4(36.49,19.79) v4(36.61,63.71) v4(36.58,18.38) v4(36.55,7.46) v4(36.72,62.94) v4(36.73,39.58) v4(36.69,1.14) v4(36.74,40.09) v4(36.8,38.38) v4(36.79,36.15) v4(36.83,24.03) v4(36.9,68.69) v4(36.87,67.82) v4(36.88,23.56) v4(36.87,17.71) v4(36.98,38.38) v4(36.98,5.04) v4(37,3.62) v4(37.03,2.21) v4(36.99,1.45) v4(37.17,62.94) v4(37.21,45.92) v4(37.23,40.6) v4(37.23,40.09) v4(37.21,39.03) v4(37.21,30.39) v4(37.2,24.91) v4(37.21,24.66) v4(37.17,18.4) v4(37.3,64.53) v4(37.3,1.15) v4(37.37,66.53) v4(37.41,42.25) v4(37.41,28.9) v4(37.38,26.17) v4(37.38,25.75) v4(37.52,46.31) v4(37.61,62.94) v4(37.57,44.36) v4(37.64,25.33) v4(37.63,23.57) v4(37.6,6.08) v4(37.68,44.79) v4(37.71,40.75) v4(37.67,5.03) v4(37.68,4.35) v4(37.68,3.62) v4(37.68,2.95) v4(37.68,2.22) v4(37.78,63.71) v4(37.78,28.28) v4(37.8,28.06) v4(37.83,26.6) v4(37.77,5.95) v4(37.88,65.2) v4(37.91,48.21) v4(37.89,35.75) v4(37.87,27.6) v4(37.86,27.15) v4(37.9,24.89) v4(37.94,17.15) v4(37.93,11.92) v4(37.93,9.75) v4(37.93,9.26) v4(37.93,8.34) v4(37.96,66.03) v4(37.97,62.94) v4(37.96,43.25) v4(38.02,26.71) v4(38.03,25.89) v4(37.99,15.21) v4(37.94,10.29) v4(38.01,7.73) v4(38.01,7.02) v4(37.99,6.33) v4(38.08,64.13) v4(38.06,47.85) v4(38.12,31.51) v4(38.06,23.56) v4(38.22,39.57) v4(38.21,28.99) v4(38.22,14.06) v4(38.22,13.49) v4(38.22,11.07) v4(38.22,10.45) v4(38.23,9.74) v4(38.23,8.95) v4(38.23,8.2) v4(38.17,0.91) v4(38.25,28.05) v4(38.27,21.14) v4(38.27,11.48) v4(38.41,66.53) v4(38.38,38.22) v4(38.44,34.61) v4(38.44,27.67) v4(38.51,64.57) v4(38.51,41.65) v4(38.51,41) v4(38.5,27.11) v4(38.51,26.35) v4(38.5,24.9) v4(38.54,68.7) v4(38.58,62.93) v4(38.6,36.15) v4(38.63,29.11) v4(38.69,26.17) v4(38.68,25.57) v4(38.67,24.74) v4(38.69,19.21) v4(38.67,17) v4(38.83,23.63) v4(38.82,20.58) v4(38.82,18.83) v4(38.78,16.69) v4(38.94,67.82) v4(38.92,62.94) v4(38.91,62.52) v4(38.94,53.79) v4(38.85,21.24) v4(39.02,50.17) v4(39.02,46.46) v4(39.01,42.85) v4(38.97,24.49) v4(38.96,19.69) v4(38.98,13.37) v4(39.12,64.38) v4(39.09,32.41) v4(39.04,25.33) v4(39.07,22.49) v4(39.09,18.91) v4(39.16,66.36) v4(39.19,65.89) v4(39.19,64.81) v4(39.16,43.6) v4(39.22,41.65) v4(39.18,11.94) v4(39.31,62.53) v4(39.25,41.02) v4(39.26,19.84) v4(39.3,19.17) v4(39.3,15.63) v4(39.31,10.74) v4(39.31,10.15) v4(39.31,9.47) v4(39.31,8.84) v4(39.31,8.13) v4(39.39,63.71) v4(39.42,62.94) v4(39.34,47.07) v4(39.5,43.85) v4(39.5,43.27) v4(39.53,35.76) v4(39.47,24.03) v4(39.49,21.05) v4(39.58,39.93) v4(39.58,30.64) v4(39.56,24.67) v4(39.55,0.62) v4(39.67,66.36) v4(39.69,25.75) v4(39.65,24.9) v4(39.65,22.8) v4(39.72,21.56) v4(39.69,20.38) v4(39.71,19.57) v4(39.73,5.93) v4(39.76,62.53) v4(39.76,47.86) v4(39.81,44.6) v4(39.84,67.11) v4(39.91,65.75) v4(39.92,62.94) v4(39.86,45.05) v4(39.86,38.67) v4(39.92,23.58) v4(39.87,13.38) v4(39.86,10.74) v4(39.86,10.08) v4(39.96,68.7) v4(39.98,66.14) v4(40.03,63.72) v4(40.02,24.24) v4(40.02,22.7) v4(40.03,15.49) v4(39.99,14.43) v4(39.97,13.72) v4(39.99,11.94) v4(40.1,37.76) v4(40.13,7.95) v4(40.13,6.63) v4(40.13,5.19) v4(40.17,65.2) v4(40.2,62.53) v4(40.2,49.57) v4(40.2,22.26) v4(40.24,19.83) v4(40.29,20.33) v4(40.31,3.77) v4(40.32,1.98) v4(40.32,1.33) v4(40.39,62.92) v4(40.39,53.44) v4(40.37,13.13) v4(40.37,12.51) v4(40.37,11.85) v4(40.35,10.76) v4(40.35,10.11) v4(40.35,9.25) v4(40.47,61.65) v4(40.46,60.81) v4(40.53,26.17) v4(40.51,25.33) v4(40.48,24.9) v4(40.46,23.57) v4(40.52,22.79) v4(40.52,21.93) v4(40.5,21.12) v4(40.56,63.73) v4(40.57,45.19) v4(40.54,12.18) v4(40.71,67.82) v4(40.74,65.78) v4(40.72,61.85) v4(40.72,61.45) v4(40.67,60.4) v4(40.67,59.95) v4(40.67,59.4) v4(40.69,58.62) v4(40.72,58.3) v4(40.69,56.51) v4(40.69,51.69) v4(40.98,64.55) v4(40.98,63.49) v4(40.97,62.35) v4(40.97,61.79) v4(40.98,61.13) v4(40.97,60.15) v4(40.97,59.7) v4(40.97,59.2) v4(40.97,58.8) v4(41.09,53.44) v4(41.05,24.89) v4(41.07,23.6) v4(41.04,22.28) v4(41.04,20.28) v4(41.05,18.65) v4(41.06,16.53) v4(41.07,12.51) v4(41.24,66) v4(41.25,66.58) v4(41.3,34.6) v4(41.26,27.06) v4(41.3,14.18) v4(41.35,12.52) v4(41.46,68.52) v4(41.46,57.87) v4(41.46,28.8) v4(41.64,55.38) v4(41.6,47.58) v4(41.68,58.08) v4(41.71,25.75) v4(41.71,25.14) v4(41.73,24.9) v4(41.69,24.29) v4(41.72,23.61) v4(41.72,23.27) v4(41.78,57.59) v4(41.79,54.05) v4(41.82,48.95) v4(41.75,41.91) v4(41.78,16.73) v4(41.79,16.3) v4(41.87,51.15) v4(41.87,50.65) v4(41.84,18.05) v4(41.97,57.75) v4(41.97,57.45) v4(41.99,55.66) v4(41.95,47.82) v4(42.01,26.17) v4(42.02,16.67) v4(42.11,68.04) v4(42.13,64.56) v4(42.12,63.82) v4(42.12,62.4) v4(42.12,41.32) v4(42.22,67.11) v4(42.19,61.9) v4(42.14,59.13) v4(42.22,57.5) v4(42.18,42.99) v4(42.16,40.25) v4(42.14,39.22) v4(42.16,38.25) v4(42.14,15.78) v4(42.27,45.59) v4(42.25,42.41) v4(42.4,64.41) v4(42.43,53.52) v4(42.43,50.83) v4(42.38,49.03) v4(42.34,44.8) v4(42.36,42.99) v4(42.34,12.52) v4(42.52,66.49) v4(42.47,65.34) v4(42.59,57.14) v4(42.6,28.57) v4(42.59,25.33) v4(42.64,23.57) v4(42.54,16.28) v4(42.71,61.5) v4(42.69,52.64) v4(42.69,24.89) v4(42.7,21.2) v4(42.84,68.52) v4(42.75,52.12) v4(42.75,42.41) v4(42.75,31.93) v4(42.83,13.96) v4(42.9,66.02) v4(42.91,41.1) v4(42.86,39.45) v4(42.87,37.78) v4(42.87,32.37) v4(43,65.27) v4(42.96,64.03) v4(42.96,56.79) v4(43.03,56.16) v4(43.01,54.73) v4(43.01,53.3) v4(43.02,51.93) v4(42.96,51.37) v4(43.01,50.19) v4(43.02,48.83) v4(43.01,47.15) v4(43.03,45.35) v4(42.95,22.95) v4(43.04,33.88) v4(43.2,66.64) v4(43.19,64.84) v4(43.22,59.22) v4(43.23,45.2) v4(43.23,44.81) v4(43.17,34.6) v4(43.29,62.69) v4(43.32,61.23) v4(43.27,58) v4(43.3,36.15) v4(43.36,67.28) v4(43.36,42.6) v4(43.37,41.53) v4(43.36,40.5) v4(43.36,39.45) v4(43.41,27.01) v4(43.39,26.16) v4(43.46,43.65) v4(43.46,27.6) v4(43.46,25.75) v4(43.48,24.9) v4(43.45,14.27) v4(43.54,23.39) v4(43.56,12.52) v4(43.66,28.39) v4(43.72,19.71) v4(43.81,68.18) v4(43.83,64.21) v4(43.76,44.73) v4(43.78,38.57) v4(43.85,63.03) v4(43.92,58) v4(43.99,59.21) v4(44.01,37.57) v4(43.98,27.58) v4(44,27.03) v4(44,26.59) v4(44.03,26.17) v4(44.04,66.69) v4(44.07,27.26) v4(44.08,24.89) v4(44.08,23.1) v4(44.16,56.65) v4(44.15,55.02) v4(44.16,52.85) v4(44.14,50.12) v4(44.14,48.73) v4(44.16,47.45) v4(44.14,45.95) v4(44.24,35.76) v4(44.16,25.65) v4(44.26,67.27) v4(44.33,12.8) v4(44.37,62.76) v4(44.35,44.97) v4(44.39,29.03) v4(44.4,26.57) v4(44.49,68.5) v4(44.53,61.66) v4(44.47,59.63) v4(44.5,48.31) v4(44.53,46) v4(44.61,64.86) v4(44.59,63.4) v4(44.55,46.88) v4(44.55,44.46) v4(44.57,42.39) v4(44.61,36.15) v4(44.58,33.66) v4(44.64,26.36) v4(44.54,20.18) v4(44.6,12.52) v4(44.66,51.9) v4(44.67,25.33) v4(44.7,24.91) v4(44.69,23.09) v4(44.69,21.38) v4(44.83,30.05) v4(44.75,26.89) v4(44.82,26.24) v4(44.91,61.84) v4(44.91,52.56) v4(44.85,37.1) v4(45.09,62.2) v4(45.1,38.98) v4(45.09,25.96) v4(45.08,20.37) v4(45.1,19.34) v4(45.04,13.77) v4(45.19,61.07) v4(45.24,60.2) v4(45.16,26.64) v4(45.22,22.23) v4(45.2,17.23) v4(45.2,16.85) v4(45.24,13) v4(45.27,44.22) v4(45.3,40.45) v4(45.32,21.9) v4(45.32,20.16) v4(45.4,68.71) v4(45.38,21.16) v4(45.39,18.04) v4(45.51,41.31) v4(45.45,34.03) v4(45.44,26.33) v4(45.5,22.04) v4(45.51,17.79) v4(45.46,15.51) v4(45.56,37.8) v4(45.58,25.94) v4(45.58,25.57) v4(45.57,25.12) v4(45.57,24.54) v4(45.56,24.09) v4(45.56,23.5) v4(45.56,23.24) v4(45.56,22.94) v4(45.56,22.76) v4(45.55,22.26) v4(45.63,19.51) v4(45.54,17.11) v4(45.64,12.52) v4(45.7,58.82) v4(45.67,57.02) v4(45.68,53.59) v4(45.74,39.96) v4(45.69,21.03) v4(45.69,20.17) v4(45.68,16.73) v4(45.66,16.36) v4(45.77,65.29) v4(45.8,31.82) v4(45.84,15.73) v4(45.78,13.01) v4(45.99,63.37) v4(45.94,59.5) v4(46.02,22.04) v4(45.97,18.39) v4(46.09,62.31) v4(46.1,32.76) v4(46.04,24.37) v4(46.06,22.41) v4(46.09,16.22) v4(46.09,13.78) v4(46.14,35.35) v4(46.16,27.02) v4(46.24,23.09) v4(46.2,22.76) v4(46.16,21.61) v4(46.16,20.86) v4(46.16,19.71) v4(46.15,18.99) v4(46.25,66.47) v4(46.25,33.31) v4(46.25,31.46) v4(46.31,21.23) v4(46.33,18.03) v4(46.42,41.83) v4(46.35,26.26) v4(46.37,24.35) v4(46.39,23.55) v4(46.4,23.25) v4(46.35,21.93) v4(46.41,20.25) v4(46.34,17.15) v4(46.51,52.3) v4(46.48,22.71) v4(46.51,19.36) v4(46.44,17.84) v4(46.49,16.22) v4(46.47,13.01) v4(46.55,58.87) v4(46.54,58) v4(46.59,50.95) v4(46.6,49.55) v4(46.54,16.94) v4(46.65,68.7) v4(46.68,15.25) v4(46.79,63.77) v4(46.74,61.51) v4(46.75,60.75) v4(46.77,51.6) v4(46.75,48.01) v4(46.76,36.35) v4(46.81,20.86) v4(46.81,20.46) v4(46.79,19.77) v4(46.81,19.36) v4(46.81,18.61) v4(46.81,16.67) v4(46.79,13.03) v4(46.87,62.66) v4(46.91,15.83) v4(46.89,12.53) v4(47.03,40.44) v4(46.98,25.59) v4(47.02,24.53) v4(46.96,23.11) v4(47.07,21.93) v4(47.12,13.01) v4(47.24,43.66) v4(47.23,30.64) v4(47.16,22.75) v4(47.18,21.58) v4(47.17,20.88) v4(47.17,20.41) v4(47.16,19.71) v4(47.16,16.16) v4(47.2,13.71) v4(47.18,12.62) v4(47.27,60.22) v4(47.33,58.82) v4(47.27,23.5) v4(47.3,13.35) v4(47.42,28.16) v4(47.36,15.36) v4(47.37,14.82) v4(47.44,61.13) v4(47.45,38.17) v4(47.5,32.53) v4(47.5,18.95) v4(47.57,60.4) v4(47.57,58) v4(47.55,30.15) v4(47.63,28.77) v4(47.56,22.35) v4(47.56,21.21) v4(47.56,20.09) v4(47.54,18.55) v4(47.58,15.74) v4(47.71,23.18) v4(47.73,19.32) v4(47.69,12.52) v4(47.83,68.64) v4(47.84,55.98) v4(47.83,36.44) v4(47.75,23.72) v4(47.81,22.76) v4(47.81,22.03) v4(47.84,21.43) v4(47.84,20.43) v4(47.84,19.7) v4(47.8,14.92) v4(47.79,13.97) v4(47.79,13.47) v4(47.92,60.18) v4(47.9,58.23) v4(47.93,50.95) v4(47.92,44.59) v4(48,49.56) v4(48.03,41.99) v4(48.03,39.13) v4(48.03,31.98) v4(47.97,31.44) v4(47.98,30.43) v4(48.03,29.34) v4(48.03,15.32) v4(48.13,16.32) v4(48.16,61.46) v4(48.24,23.1) v4(48.17,21.92) v4(48.2,19.69) v4(48.16,18.55) v4(48.2,14.52) v4(48.27,37.48) v4(48.27,36.67) v4(48.33,36.06) v4(48.32,27.28) v4(48.27,22.67) v4(48.34,21.43) v4(48.25,20.86) v4(48.25,20.37) v4(48.38,34.38) v4(48.35,17.51) v4(48.36,15.32) v4(48.36,13.92) v4(48.35,13.36) v4(48.52,68.24) v4(48.47,65.24) v4(48.5,38.21) v4(48.52,21.21) v4(48.52,20.09) v4(48.52,18.95) v4(48.46,17.19) v4(48.59,30.41) v4(48.63,12.7) v4(48.7,59.39) v4(48.74,57.38) v4(48.72,56.2) v4(48.71,55.08) v4(48.74,53.37) v4(48.74,50.42) v4(48.74,41.28) v4(48.74,40.79) v4(48.74,35.66) v4(48.72,21.93) v4(48.66,14.06) v4(48.75,54.31) v4(48.76,52.81) v4(48.76,51.62) v4(48.75,49.71) v4(48.76,48.79) v4(48.75,46.85) v4(48.76,45.43) v4(48.75,44.51) v4(48.75,43.55) v4(48.75,42.44) v4(48.75,39.83) v4(48.75,38.92) v4(48.8,27.56) v4(48.83,23.7) v4(48.84,21.57) v4(48.84,20.47) v4(48.84,19.68) v4(48.84,19.18) v4(48.84,17.09) v4(48.76,13.76) v4(48.83,12.52) v4(48.87,16.19) v4(48.9,12.7) v4(48.96,30.79) v4(49.02,14.3) v4(49.02,13.02) v4(49.08,62.73) v4(49.05,32.36) v4(49.07,28.77) v4(49.19,19.35) v4(49.21,18.55) v4(49.15,13.53) v4(49.27,63.42) v4(49.33,58.78) v4(49.31,35.08) v4(49.25,19.71) v4(49.37,68.24) v4(49.38,26.17) v4(49.35,24.27) v4(49.35,21.55) v4(49.5,66.45) v4(49.5,60.24) v4(49.5,59.08) v4(49.44,20.94) v4(49.45,15.9) v4(49.51,14.11) v4(49.54,67.31) v4(49.59,65.63) v4(49.63,36.96) v4(49.64,31.51) v4(49.54,22.35) v4(49.54,21.21) v4(49.54,20.09) v4(49.54,18.95) v4(49.72,37.5) v4(49.66,32.02) v4(49.65,27.31) v4(49.72,13.52) v4(49.8,26.52) v4(49.83,21.97) v4(49.83,21.58) v4(49.8,20.4) v4(49.89,35.06) v4(49.89,13.02) v4(50,63.76) v4(49.95,63.31) v4(50.03,62.68) v4(49.96,59.73) v4(49.94,58.15) v4(49.98,23.51) v4(50.07,57.49) v4(50.12,56.71) v4(50.08,55.98) v4(50.09,55.08) v4(50.07,54.39) v4(50.07,53.1) v4(50.08,52.01) v4(50.07,50.87) v4(50.12,49.74) v4(50.07,48.54) v4(50.09,47.31) v4(50.08,46.18) v4(50.09,45.31) v4(50.08,44.76) v4(50.05,44.02) v4(50.09,43.17) v4(50.08,41.96) v4(50.08,41.42) v4(50.08,40.79) v4(50.08,40.22) v4(50.07,39.47) v4(50.08,38.53) v4(50.08,37.85) v4(50.12,37.09) v4(50.11,33.8) v4(50.05,27.76) v4(50.13,24.99) v4(50.09,13.96) v4(50.21,53.99) v4(50.15,36.43) v4(50.23,22.04) v4(50.21,19.3) v4(50.21,18.55) v4(50.27,55.8) v4(50.29,52.3) v4(50.24,50.69) v4(50.27,38.23) v4(50.27,21.57) v4(50.42,37.48) v4(50.39,20.86) v4(50.36,13.61) v4(50.41,12.53) v4(50.52,25.44) v4(50.56,22.35) v4(50.56,21.17) v4(50.56,20.09) v4(50.72,36.53) v4(50.65,26.31) v4(50.69,22.95) v4(50.75,36.17) v4(50.81,22.04) v4(50.84,21.43) v4(50.91,28.18) v4(50.88,20.42) v4(50.91,19.66) v4(50.9,19.34) v4(50.85,18.6) v4(50.97,41.33) v4(50.96,27.33) v4(50.94,25.15) v4(51.04,61.66) v4(51.08,58.02) v4(51.13,50.94) v4(51.13,37.23) v4(51.09,16.73) v4(51.17,58.56) v4(51.14,49.66) v4(51.21,47.32) v4(51.15,35.78) v4(51.19,23.19) v4(51.22,18.79) v4(51.15,16.28) v4(51.33,62.46) v4(51.3,60.52) v4(51.24,56.78) v4(51.26,54.01) v4(51.31,36.67) v4(51.25,21.95) v4(51.34,21.57) v4(51.25,20.48) v4(51.32,19.74) v4(51.26,19.36) v4(51.31,13.86) v4(51.3,13.31) v4(51.26,13.03) v4(51.26,12.52) v4(51.36,44.74) v4(51.37,27.67) v4(51.42,22.22) v4(51.39,20.89) v4(51.46,31.79) v4(51.48,31.29) v4(51.47,29.76) v4(51.53,26.55) v4(51.57,62.46) v4(51.62,35.32) v4(51.56,25.13) v4(51.59,15.52) v4(51.7,68.23) v4(51.71,39.59) v4(51.73,23.51) v4(51.73,23.2) v4(51.84,55.62) v4(51.82,35.79) v4(51.81,33.87) v4(51.83,32.76) v4(51.84,32.24) v4(51.76,29.22) v4(51.8,16.89) v4(51.84,62.07) v4(51.86,56.79) v4(51.89,52.96) v4(51.9,24.2) v4(51.91,22.76) v4(51.91,21.16) v4(51.91,20.5) v4(51.91,19.36) v4(51.89,14.84) v4(52.02,22.34) v4(52.02,14.19) v4(52.06,63.68) v4(52.08,36.8) v4(52.12,36.41) v4(52.05,25.76) v4(52.23,41.17) v4(52.18,13.53) v4(52.18,13.02) v4(52.26,47.52) v4(52.26,45.99) v4(52.28,44.99) v4(52.24,44.04) v4(52.24,42.44) v4(52.34,35.31) v4(52.3,32.24) v4(52.3,13.78) v4(52.48,59.34) v4(52.49,36.43) v4(52.52,23.51) v4(52.51,12.52) v4(52.56,61.65) v4(52.56,38.3) v4(52.59,37.31) v4(52.63,31.07) v4(52.58,30.74) v4(52.62,26.23) v4(52.62,14.63) v4(52.67,25) v4(52.69,23.23) v4(52.7,22.92) v4(52.67,20.98) v4(52.65,15.17) v4(52.84,36.01) v4(52.88,32.59) v4(52.92,24.2) v4(52.99,36.83) v4(52.99,33.84) v4(53,31.22) v4(53.03,30.39) v4(53.04,27.97) v4(53.02,23.34) v4(53.11,18.21) v4(53.08,14.07) v4(53.11,13.52) v4(53.13,13.02) v4(53.09,12.63) v4(53.23,58.56) v4(53.21,37.95) v4(53.16,31.76) v4(53.14,21.22) v4(53.16,15.92) v4(53.28,66.45) v4(53.33,36.01) v4(53.34,22.17) v4(53.35,27.66) v4(53.43,24.45) v4(53.51,39.33) v4(53.51,31.69) v4(53.49,29.31) v4(53.51,21.2) v4(53.52,14.63) v4(53.55,67.95) v4(53.55,33.12) v4(53.62,23.12) v4(53.62,15.22) v4(53.55,13.69) v4(53.72,61.65) v4(53.71,56.49) v4(53.66,31.02) v4(53.7,27.75) v4(53.68,13.15) v4(53.78,59.32) v4(53.74,52.48) v4(53.75,48.86) v4(53.75,46.11) v4(53.76,44.18) v4(53.76,42.34) v4(53.74,37.78) v4(53.84,37.29) v4(53.8,35.62) v4(53.8,33.36) v4(53.74,32.58) v4(53.78,22.26) v4(53.75,21.84) v4(53.75,20.82) v4(53.91,31.92) v4(53.86,31.27) v4(53.87,18.85) v4(53.99,38.21) v4(54.02,37.27) v4(54.02,33.99) v4(53.97,30.19) v4(53.96,13.8) v4(54.06,63.48) v4(54.04,62.12) v4(54.11,38.9) v4(54.06,33.6) v4(54.11,31.16) v4(54.08,28.52) v4(54.05,23.76) v4(54.07,21.39) v4(54.07,20.31) v4(54.22,65.64) v4(54.14,64.69) v4(54.15,13.4) v4(54.17,12.72) v4(54.26,67.42) v4(54.31,39.84) v4(54.31,34.79) v4(54.34,33.85) v4(54.26,33.35) v4(54.25,16.95) v4(54.29,14.58) v4(54.37,35.16) v4(54.43,16.03) v4(54.52,68.23) v4(54.48,47.53) v4(54.48,40.78) v4(54.54,36.32) v4(54.51,20.34) v4(54.62,39.38) v4(54.58,34.35) v4(54.61,31.91) v4(54.55,30.92) v4(54.67,57.47) v4(54.65,30.15) v4(54.65,22.31) v4(54.68,18.62) v4(54.71,17.38) v4(54.65,17.21) v4(54.75,55.64) v4(54.75,51.59) v4(54.74,37.57) v4(54.76,33.85) v4(54.76,32.86) v4(54.83,14.5) v4(54.93,43.39) v4(54.93,16.58) v4(54.85,13.34) v4(54.89,12.73) v4(55.02,52.43) v4(54.97,46.34) v4(54.94,28.43) v4(55.03,21.43) v4(55.1,48.89) v4(55.05,34.59) v4(55.05,20.09) v4(55.16,66.48) v4(55.23,56.14) v4(55.23,51.43) v4(55.17,18.86) v4(55.26,65.85) v4(55.28,65.27) v4(55.28,64.69) v4(55.28,61.64) v4(55.27,60.02) v4(55.28,58.65) v4(55.25,54.33) v4(55.26,52.44) v4(55.24,50.44) v4(55.27,36.29) v4(55.25,33.86) v4(55.26,32.28) v4(55.25,27.1) v4(55.39,48.3) v4(55.53,37.34) v4(55.59,25.45) v4(55.56,19.54) v4(55.71,32.28) v4(55.71,31.7) v4(55.7,23.3) v4(55.66,20.73) v4(55.71,16.29) v4(55.82,66.97) v4(55.82,31.09) v4(55.82,30.74) v4(55.82,30.39) v4(55.82,30.04) v4(55.82,29.69) v4(55.91,38.59) v4(55.92,25.12) v4(56.07,35.62) v4(56.13,31.09) v4(56.13,30.74) v4(56.13,30.39) v4(56.13,30.04) v4(56.13,29.69) v4(56.05,27.79) v4(56.1,26.17) v4(56.05,21.76) v4(56.11,12.73) v4(56.18,67.86) v4(56.17,27.15) v4(56.2,19.54) v4(56.23,18.61) v4(56.22,16.72) v4(56.21,16.2) v4(56.22,15.53) v4(56.14,14.08) v4(56.31,21.59) v4(56.26,20.32) v4(56.24,14.91) v4(56.37,42.98) v4(56.41,41.21) v4(56.39,39.38) v4(56.41,17.36) v4(56.46,31.09) v4(56.46,30.74) v4(56.46,30.39) v4(56.46,30.04) v4(56.46,29.69) v4(56.48,26.55) v4(56.55,47.66) v4(56.56,41.76) v4(56.55,36.77) v4(56.56,17.68) v4(56.68,66.98) v4(56.69,32.79) v4(56.73,32.02) v4(56.73,15.19) v4(56.72,14.34) v4(56.77,31.08) v4(56.77,30.74) v4(56.77,30.39) v4(56.77,30.04) v4(56.77,29.69) v4(56.74,16.3) v4(56.91,64.94) v4(56.9,63.48) v4(56.91,61.65) v4(56.92,59.83) v4(56.91,56.56) v4(56.91,54.92) v4(56.9,53.61) v4(56.92,52.28) v4(56.93,50.84) v4(56.91,49.71) v4(56.88,19.78) v4(56.92,19.23) v4(56.92,18.73) v4(56.89,17.09) v4(56.86,13.82) v4(56.98,68.24) v4(57.04,66.28) v4(57.01,58.62) v4(56.99,48.1) v4(56.98,43.54) v4(57,42.83) v4(56.95,13.46) v4(57.05,57.72) v4(57.07,48.9) v4(57.1,30.74) v4(57.1,18.43) v4(57.11,12.73) v4(57.22,67.53) v4(57.23,35.49) v4(57.21,14.09) v4(57.33,66.02) v4(57.33,46.09) v4(57.25,20.51) v4(57.42,19.23) v4(57.43,18.74) v4(57.44,59.28) v4(57.54,41.05) v4(57.45,39.28) v4(57.47,31.97) v4(57.46,29.38) v4(57.47,26.29) v4(57.5,17.27) v4(57.5,16.95) v4(57.56,24.78) v4(57.56,18.14) v4(57.61,13.2) v4(57.54,12.69) v4(57.72,53.39) v4(57.69,13.88) v4(57.68,12.55) v4(57.74,55.83) v4(57.84,42.38) v4(57.79,37.9) v4(57.81,25.27) v4(57.82,22.88) v4(57.74,19.22) v4(57.86,66.44) v4(57.89,30.85) v4(57.96,67.24) v4(57.95,64.2) v4(58.02,43.46) v4(58.04,20.63) v4(58.08,56.64) v4(58.05,40.55) v4(58.06,39.01) v4(58.06,21.37) v4(58.14,61.88) v4(58.16,44.18) v4(58.15,17.61) v4(58.28,66.07) v4(58.24,40.55) v4(58.24,33.86) v4(58.27,30.32) v4(58.3,19.13) v4(58.38,38.06) v4(58.51,66.19) v4(58.49,44.22) v4(58.49,42.01) v4(58.46,37.17) v4(58.46,36.17) v4(58.46,35.17) v4(58.5,13.8) v4(58.53,12.77) v4(58.57,67.45) v4(58.55,63.98) v4(58.59,46.65) v4(58.62,30.88) v4(58.56,29.09) v4(58.56,26.98) v4(58.68,60.44) v4(58.69,55.67) v4(58.71,28.95) v4(58.67,18.57) v4(58.72,12.54) v4(58.82,59.42) v4(58.76,41.52) v4(58.76,22.02) v4(58.76,21.17) v4(58.79,20.02) v4(58.82,18.74) v4(58.85,61.55) v4(58.91,56.87) v4(58.86,29.09) v4(58.92,14.04) v4(58.96,68.21) v4(59,63.48) v4(59.04,37.27) v4(59.03,35.52) v4(59,34.11) v4(58.97,26.8) v4(58.97,26.39) v4(59.04,24.97) v4(59.04,24.45) v4(59.09,39.27) v4(59.09,28.4) v4(59.09,25.7) v4(59.19,64.38) v4(59.2,62.08) v4(59.21,33.17) v4(59.21,32.17) v4(59.21,31.17) v4(59.17,29.38) v4(59.15,27.73) v4(59.18,22.5) v4(59.18,17.24) v4(59.34,55.63) v4(59.33,54.77) v4(59.28,51.83) v4(59.34,47) v4(59.33,44.48) v4(59.29,42.77) v4(59.24,34.69) v4(59.28,22.87) v4(59.36,66.67) v4(59.35,66.24) v4(59.4,35.28) v4(59.43,17.77) v4(59.37,17.24) v4(59.5,51.21) v4(59.44,22.03) v4(59.44,19.88) v4(59.44,19.1) v4(59.45,18.38) v4(59.63,66.24) v4(59.63,61.76) v4(59.6,42.37) v4(59.59,33.8) v4(59.6,32.91) v4(59.6,28.41) v4(59.64,25.71) v4(59.65,66.68) v4(59.66,61.56) v4(59.66,61.04) v4(59.64,60.47) v4(59.71,59.74) v4(59.68,32.06) v4(59.71,30.17) v4(59.7,26.45) v4(59.77,38.55) v4(59.76,34.5) v4(59.84,58.98) v4(59.86,54.2) v4(59.89,52.93) v4(59.9,43.92) v4(59.86,27.54) v4(59.86,22.48) v4(59.85,18.37) v4(59.94,61.5) v4(59.96,47.02) v4(60.07,68.44) v4(60.08,55.87) v4(60.1,35.52) v4(60.07,29.48) v4(60.08,28.42) v4(60.22,60.22) v4(60.33,66.06) v4(60.26,40.25) v4(60.34,32.03) v4(60.24,20.1) v4(60.33,16.99) v4(60.35,45.99) v4(60.54,69.29) v4(60.51,58.66) v4(60.46,57.43) v4(60.5,50.14) v4(60.5,48.23) v4(60.46,35.72) v4(60.46,29.42) v4(60.54,16.44) v4(60.57,64.21) v4(60.57,60.93) v4(60.7,55.87) v4(60.81,43.58) v4(60.77,34.16) v4(60.77,33.89) v4(60.81,30.89) v4(60.82,18.29) v4(60.76,16.42) v4(60.93,65.11) v4(60.93,54.77) v4(60.87,15.77) v4(61.01,67.84) v4(60.98,64.45) v4(61.02,64.23) v4(60.99,60.12) v4(61.01,51.34) v4(61.01,50.01) v4(60.96,44.54) v4(61.01,35.85) v4(61,34.16) v4(61,33.89) v4(61,31.84) v4(61.05,66.35) v4(61.06,57.13) v4(61.06,30.11) v4(61.19,59.06) v4(61.26,59.67) v4(61.33,54.77) v4(61.33,53.17) v4(61.31,32.16) v4(61.3,31.14) v4(61.54,48.63) v4(61.53,46.68) v4(61.52,44.59) v4(61.44,16.39) v4(61.64,30.3) v4(61.56,18.5) v4(61.73,53.57) v4(61.73,53.17) v4(61.7,35.85) v4(61.72,27.14) v4(61.71,26.75) v4(61.7,26.3) v4(61.7,25.83) v4(61.7,25.36) v4(61.7,24.89) v4(61.71,24.42) v4(61.7,23.94) v4(61.7,23.42) v4(61.7,22.88) v4(61.71,22.42) v4(61.7,21.95) v4(61.7,21.45) v4(61.7,20.95) v4(61.71,20.49) v4(61.7,19.82) v4(61.77,68.59) v4(61.83,64.61) v4(61.79,59.59) v4(61.75,32.47) v4(61.75,31.27) v4(61.75,29.77) v4(61.75,28.57) v4(61.75,27.42) v4(61.85,41.77) v4(61.87,15.77) v4(61.97,62.94) v4(62.04,62.06) v4(62.1,49.34) v4(62.2,59.07) v4(62.19,57.39) v4(62.25,56.69) v4(62.3,37.63) v4(62.39,58.32) v4(62.43,48.33) v4(62.42,45.52) v4(62.39,43.43) v4(62.4,35.85) v4(62.45,68.26) v4(62.45,60.37) v4(62.52,18.94) v4(62.79,67) v4(62.79,65.56) v4(62.84,59.05) v4(62.78,54.8) v4(62.77,15.77) v4(62.92,53.27) v4(62.92,50.73) v4(62.97,63.56) v4(63.03,61.04) v4(62.95,59.55) v4(62.95,56.34) v4(63.07,35.85) v4(63.26,17.02) v4(63.41,59.62) v4(63.35,43.28) v4(63.52,18.94) v4(63.63,68.23) v4(63.57,58.24) v4(63.63,44.01) v4(63.7,47.98) v4(63.68,46.89) v4(63.65,45.3) v4(63.73,42.73) v4(63.73,15.78) v4(63.83,39.04) v4(63.76,35.85) v4(64.28,64.76) v4(64.27,47.57) v4(64.28,43.61) v4(64.33,17.03) v4(64.38,67.49) v4(64.37,66.36) v4(64.36,56.88) v4(64.48,65.19) v4(64.51,59.87) v4(64.54,58.65) v4(64.5,57.83) v4(64.52,42.33) v4(64.47,35.84) v4(64.52,18.94) v4(64.64,62.45) v4(64.57,41.4) v4(64.63,15.42) v4(64.67,56.1) v4(64.68,55.14) v4(64.71,54.06) v4(64.83,53.06) v4(64.83,51.17) v4(64.82,49.56) v4(64.82,15.84) v4(64.79,12.58) v4(64.79,12.08) v4(64.79,11.58) v4(64.79,11.08) v4(64.85,39.22) v4(64.89,13.78) v4(64.99,48.08) v4(64.97,46.29) v4(65.17,61.93) v4(65.18,60.64) v4(65.18,58.64) v4(65.21,37.58) v4(65.16,37.08) v4(65.17,36.55) v4(65.14,36) v4(65.34,38.06) v4(65.31,16.59) v4(65.29,15.82) v4(65.37,64.64) v4(65.37,63.02) v4(65.37,56.64) v4(65.37,54.64) v4(65.37,46.13) v4(65.36,45.73) v4(65.36,45.17) v4(65.36,44.58) v4(65.36,44.17) v4(65.36,43.61) v4(65.36,43.02) v4(65.35,42.52) v4(65.36,41.96) v4(65.36,41.4) v4(65.36,40.81) v4(65.35,40.31) v4(65.35,39.71) v4(65.35,39.15) v4(65.35,38.56) v4(65.37,19.42) v4(65.47,20.24) v4(65.64,49) v4(65.8,12.58) v4(65.8,12.08) v4(65.8,11.58) v4(65.8,11.08) v4(65.88,53.6) v4(65.99,51.84) v4(65.94,48.1) v4(65.94,17.61) v4(65.94,15.42) v4(66.19,18.27) v4(66.33,16.61) v4(66.37,52.51) v4(66.46,50.76) v4(66.47,20.24) v4(66.67,53.37) v4(66.69,15.43) v4(67.07,48.2) v4(67.08,18.67) v4(67.11,16.4) v4(67.2,49.46) v4(67.4,50.51) v4(67.44,15.43) v4(67.47,20.24) v4(67.86,16.62) v4(67.99,52.94) v4(68.09,48.56) v4(68.1,15.43) v4(68.15,52.71) v4(68.19,51.68) v4(68.15,50.94) v4(68.18,16.23) v4(68.33,49.31) v4(68.32,18.23) v4(68.25,17.23) v4(68.41,19.23) v4(68.47,20.24) v5(0.31,20.23) v5(0.36,19.37) v5(0.44,18.37) v5(0.44,52.2) v5(0.46,50.98) v5(0.48,49.2) v5(0.52,17.37) v5(0.59,16.36) v5(0.7,48.74) v5(0.67,15.36) v5(0.76,52.93) v5(0.84,18.28) v5(0.93,16.67) v5(1.07,52.86) v5(1.31,20.23) v5(1.5,50.41) v5(1.65,18.69) v5(1.7,16.36) v5(1.67,15.36) v5(1.82,53.35) v5(2.31,20.23) v5(2.46,18.38) v5(2.49,16.69) v5(2.47,15.36) v5(2.73,51.84) v5(2.65,48.1) v5(2.82,17.57) v5(3.04,13.58) v5(3.04,12.68) v5(3.04,11.78) v5(3.04,10.92) v5(3.11,15.36) v5(3.05,14.78) v5(3.28,54.07) v5(3.3,46.28) v5(3.31,20.23) v5(3.41,64.79) v5(3.41,63.53) v5(3.41,62.49) v5(3.4,56.97) v5(3.4,55.18) v5(3.4,43.67) v5(3.4,40.67) v5(3.4,37.67) v5(3.42,19.41) v5(3.6,61.95) v5(3.6,61.35) v5(3.6,60.81) v5(3.6,60.28) v5(3.6,59.75) v5(3.6,59.22) v5(3.6,58.69) v5(3.6,58.16) v5(3.58,57.55) v5(3.59,48.88) v5(3.61,36.59) v5(3.6,35.51) v5(3.77,64.09) v5(3.78,48.07) v5(3.8,15.35) v5(3.9,66.93) v5(3.92,52.55) v5(3.93,43.6) v5(3.95,68.06) v5(4.01,55.62) v5(4.04,15.88) v5(4.04,13.58) v5(4.04,12.68) v5(4.04,11.78) v5(4.04,10.92) v5(4.05,50.76) v5(4.05,14.78) v5(4.17,15.35) v5(4.25,18.94) v5(4.42,56.83) v5(4.41,38.35) v5(4.42,37.01) v5(4.41,18.2) v5(4.39,16.31) v5(4.5,67.02) v5(4.53,63.44) v5(4.5,47.62) v5(4.54,46.85) v5(4.49,44.62) v5(4.44,40.67) v5(4.49,15.64) v5(4.74,56.3) v5(4.79,35.51) v5(5.04,67.5) v5(4.98,66.17) v5(5.06,68.22) v5(5.07,52.75) v5(5.17,17.37) v5(5.17,17.19) v5(5.17,17.01) v5(5.16,16.33) v5(5.16,16.15) v5(5.16,15.97) v5(5.25,18.94) v5(5.35,48.5) v5(5.53,63.71) v5(5.53,60.16) v5(5.51,47.52) v5(5.5,46.06) v5(5.5,43.07) v5(5.5,40.39) v5(5.5,37.54) v5(5.46,15.62) v5(5.61,65.46) v5(5.55,63.9) v5(5.61,61.55) v5(5.55,36.14) v5(5.67,17.22) v5(5.81,62.73) v5(5.84,60.57) v5(5.82,56.46) v5(5.75,34.43) v5(5.87,67.65) v5(5.92,15.62) v5(5.98,49.91) v5(6.13,63.01) v5(6.11,54.32) v5(6.1,52.59) v5(6.2,55.48) v5(6.16,51.45) v5(6.19,35.51) v5(6.29,68.24) v5(6.32,65.04) v5(6.28,60.55) v5(6.25,18.94) v5(6.39,47.55) v5(6.39,46.23) v5(6.39,43.07) v5(6.39,40.12) v5(6.39,36.87) v5(6.39,36.6) v5(6.41,33.79) v5(6.51,48.51) v5(6.61,67.65) v5(6.56,63.87) v5(6.56,18.43) v5(6.71,57.69) v5(6.81,58.81) v5(6.74,49.95) v5(6.91,64.11) v5(6.92,61.16) v5(6.88,34.8) v5(6.94,56.13) v5(7.02,33.16) v5(7.02,32.26) v5(7.02,31.24) v5(7.02,30.48) v5(7.02,29.52) v5(7.02,28.52) v5(7.01,27) v5(7.03,25.44) v5(7.03,23.44) v5(7.03,20.24) v5(7.01,19.62) v5(7.03,19.01) v5(6.99,15.64) v5(7.2,68.72) v5(7.17,63.01) v5(7.31,50.77) v5(7.35,49.36) v5(7.42,15.22) v5(7.44,62.28) v5(7.44,62.06) v5(7.48,58.76) v5(7.52,47.76) v5(7.48,43.04) v5(7.47,39.74) v5(7.48,35.51) v5(7.61,67.65) v5(7.57,60.15) v5(7.57,55.45) v5(7.59,52.93) v5(7.64,63.45) v5(7.74,53.77) v5(7.75,44.64) v5(7.77,37.06) v5(7.83,33.85) v5(7.78,14.87) v5(7.9,18.41) v5(8.01,69.32) v5(7.95,64.72) v5(8.01,55.94) v5(8.06,47.51) v5(8.12,40.94) v5(8.11,19.63) v5(8.19,65.2) v5(8.21,46.47) v5(8.23,44.23) v5(8.28,58.78) v5(8.27,42.14) v5(8.26,39.51) v5(8.27,37.87) v5(8.24,15.6) v5(8.24,14.41) v5(8.38,57.63) v5(8.41,19.32) v5(8.47,65.19) v5(8.52,51.52) v5(8.48,36.24) v5(8.53,34.45) v5(8.63,59.7) v5(8.56,47.6) v5(8.67,67.65) v5(8.66,65.23) v5(8.67,53.16) v5(8.65,50.06) v5(8.71,41.26) v5(8.68,15.16) v5(8.71,9.9) v5(8.73,9.1) v5(8.73,8.8) v5(8.82,64.73) v5(8.74,62.31) v5(8.82,36.8) v5(8.83,18.91) v5(8.79,17.57) v5(8.74,13.84) v5(8.74,9.58) v5(8.99,69.33) v5(9.01,64.11) v5(9.07,14.82) v5(9.19,63.08) v5(9.14,56.28) v5(9.22,35.5) v5(9.23,10.48) v5(9.34,55.51) v5(9.3,48.6) v5(9.34,45.39) v5(9.27,43.87) v5(9.39,66.9) v5(9.39,51.68) v5(9.35,46.65) v5(9.39,18.34) v5(9.39,11.36) v5(9.39,11.11) v5(9.53,42.25) v5(9.53,39.08) v5(9.63,57.87) v5(9.64,15.92) v5(9.59,9.06) v5(9.59,8.81) v5(9.7,57.4) v5(9.73,52.49) v5(9.69,11.36) v5(9.69,11.11) v5(9.77,48.04) v5(9.75,37.55) v5(9.83,21.04) v5(9.82,17.92) v5(9.81,15.29) v5(9.8,13.84) v5(9.92,10.14) v5(9.94,68.59) v5(10.12,53.77) v5(10.08,38.12) v5(10.09,36.4) v5(10.07,11.11) v5(10.19,44.3) v5(10.19,41.95) v5(10.21,39.67) v5(10.17,32.86) v5(10.17,32.44) v5(10.17,31.86) v5(10.17,31.6) v5(10.17,31.34) v5(10.18,30.6) v5(10.19,30.21) v5(10.19,29.54) v5(10.21,26.2) v5(10.22,21.44) v5(10.43,67.6) v5(10.35,17.1) v5(10.44,66.4) v5(10.44,63.11) v5(10.52,39.08) v5(10.46,30.77) v5(10.46,29.54) v5(10.5,28.65) v5(10.51,22.06) v5(10.49,9.97) v5(10.61,40.09) v5(10.64,36.34) v5(10.61,30.27) v5(10.58,16.53) v5(10.67,60.64) v5(10.69,44.69) v5(10.69,41.84) v5(10.69,35.76) v5(10.71,24.35) v5(10.72,14.58) v5(10.71,13.7) v5(10.8,46.94) v5(10.75,43.72) v5(10.81,11.11) v5(10.78,9.98) v5(10.78,9.06) v5(10.92,38.26) v5(10.91,28.27) v5(11.04,16.7) v5(10.95,13.13) v5(10.97,10.49) v5(11.08,68.74) v5(11.12,13.46) v5(11.11,13.04) v5(11.15,31.76) v5(11.21,31.59) v5(11.15,29.43) v5(11.17,28.72) v5(11.23,26.46) v5(11.25,67.66) v5(11.25,67.47) v5(11.32,48.41) v5(11.31,32.85) v5(11.25,27.96) v5(11.28,11.11) v5(11.3,9.96) v5(11.3,9.34) v5(11.43,67.66) v5(11.43,67.47) v5(11.35,48.03) v5(11.39,40.63) v5(11.34,39.6) v5(11.35,34.34) v5(11.35,32.48) v5(11.35,25.6) v5(11.43,23.97) v5(11.41,14.98) v5(11.53,69.33) v5(11.52,47.07) v5(11.52,44.68) v5(11.53,42.7) v5(11.54,35.79) v5(11.46,24.68) v5(11.61,67.66) v5(11.61,67.47) v5(11.58,61.59) v5(11.54,34.9) v5(11.64,16.09) v5(11.59,11.51) v5(11.59,9.97) v5(11.65,41.72) v5(11.79,67.66) v5(11.79,67.47) v5(11.79,39.2) v5(11.74,31.92) v5(11.74,26.74) v5(11.78,23.23) v5(11.76,14.59) v5(11.91,22.24) v5(12.01,36.17) v5(11.96,13.67) v5(12.08,47.23) v5(12.04,43.45) v5(12.11,11.59) v5(12.06,10.45) v5(12.12,9.84) v5(12.17,68.59) v5(12.16,46.09) v5(12.21,42.37) v5(12.17,39.61) v5(12.25,44.14) v5(12.32,38) v5(12.24,32.89) v5(12.24,25.8) v5(12.33,14.06) v5(12.42,12.14) v5(12.42,11.08) v5(12.42,10.54) v5(12.44,11.6) v5(12.49,9.98) v5(12.47,9.56) v5(12.62,18.47) v5(12.73,65.29) v5(12.68,23.08) v5(12.68,17.72) v5(12.7,13.68) v5(12.77,61.48) v5(12.86,48.24) v5(12.88,46.41) v5(12.86,44.35) v5(12.9,40.75) v5(12.86,38.55) v5(13.01,67.6) v5(12.98,65.78) v5(13.02,56.48) v5(12.95,50.2) v5(12.94,20.52) v5(13.02,11.4) v5(13.09,22.05) v5(13.09,13.25) v5(13.11,12.8) v5(13.22,17.82) v5(13.16,14.59) v5(13.19,12.55) v5(13.15,12.25) v5(13.16,10.48) v5(13.16,9.66) v5(13.16,8.99) v5(13.17,8.38) v5(13.34,61.53) v5(13.29,52.46) v5(13.33,37.83) v5(13.25,34.69) v5(13.24,19.69) v5(13.39,36.25) v5(13.4,35.46) v5(13.4,34.86) v5(13.37,33.56) v5(13.54,37.28) v5(13.52,27.74) v5(13.48,20.64) v5(13.51,9.98) v5(13.49,8.15) v5(13.55,36.72) v5(13.56,31.45) v5(13.56,28.7) v5(13.55,25.9) v5(13.56,24.65) v5(13.56,24.46) v5(13.67,66.64) v5(13.65,50.73) v5(13.66,48.51) v5(13.69,46.24) v5(13.67,44.1) v5(13.65,42.38) v5(13.67,41.44) v5(13.69,19.22) v5(13.71,18.27) v5(13.71,12.07) v5(13.77,57.32) v5(13.76,39.73) v5(13.96,65.79) v5(14.04,24.74) v5(14.01,17.67) v5(14.13,68.75) v5(14.08,65.29) v5(14.1,21.89) v5(14.1,19.81) v5(14.16,18.66) v5(14.22,13.6) v5(14.3,67.52) v5(14.31,38.6) v5(14.42,12.4) v5(14.4,9.98) v5(14.41,9.06) v5(14.54,66.64) v5(14.5,39.53) v5(14.47,20.64) v5(14.47,14.36) v5(14.53,11.67) v5(14.47,10.75) v5(14.6,61.52) v5(14.6,28.51) v5(14.61,26.02) v5(14.57,21.96) v5(14.62,17.71) v5(14.58,8.15) v5(14.73,39.75) v5(14.65,38.6) v5(14.66,36.58) v5(14.69,29.88) v5(14.66,20.34) v5(14.65,13.25) v5(14.71,9.98) v5(14.77,68.74) v5(14.84,35.43) v5(14.74,29.23) v5(14.74,18.87) v5(14.85,39.21) v5(14.86,38.25) v5(14.91,8.69) v5(15.02,69.13) v5(14.97,66.27) v5(15.01,58.55) v5(15.02,38.5) v5(15,36.21) v5(14.97,34.89) v5(14.96,16.55) v5(15.05,57.88) v5(15.05,37.66) v5(15.11,33.11) v5(15.13,30.04) v5(15.11,20.65) v5(15.07,20.06) v5(15.12,10.8) v5(15.15,31.15) v5(15.17,26.93) v5(15.17,22.75) v5(15.33,38.76) v5(15.31,32.22) v5(15.29,16.36) v5(15.38,65.79) v5(15.42,57.08) v5(15.35,39.77) v5(15.38,39.55) v5(15.38,16.9) v5(15.41,8.15) v5(15.5,68.13) v5(15.45,17.76) v5(15.64,58.46) v5(15.61,32.7) v5(15.72,32.19) v5(15.72,31.84) v5(15.68,30.6) v5(15.73,29.67) v5(15.7,27.09) v5(15.71,23.74) v5(15.71,23.42) v5(15.73,19.17) v5(15.76,57.42) v5(15.79,22.58) v5(15.75,21.94) v5(15.74,20.92) v5(15.75,20.05) v5(15.78,14.5) v5(15.79,10.71) v5(15.86,38.76) v5(15.93,18.21) v5(16.19,66.59) v5(16.2,66.02) v5(16.22,65.12) v5(16.17,57.78) v5(16.14,23.86) v5(16.18,23.39) v5(16.18,22.96) v5(16.18,21.33) v5(16.18,19.87) v5(16.28,63.92) v5(16.31,18.48) v5(16.28,14.54) v5(16.35,68.6) v5(16.36,66.92) v5(16.42,38.76) v5(16.4,11.21) v5(16.39,10.7) v5(16.54,66.92) v5(16.48,17.73) v5(16.51,8.16) v5(16.57,67.77) v5(16.62,58.46) v5(16.73,12.78) v5(16.66,10.25) v5(16.81,38.76) v5(16.77,14.77) v5(16.78,8.8) v5(16.96,69.31) v5(17.02,57.78) v5(17.2,38.76) v5(17.18,8.45) v5(17.3,68.11) v5(17.25,56.61) v5(17.29,9.45) v5(17.51,63.9) v5(17.49,15.34) v5(17.5,12.75) v5(17.55,10.58) v5(17.65,58.25) v5(17.75,56.31) v5(17.75,10.05) v5(17.92,67.56) v5(17.94,42.92) v5(17.95,40.59) v5(18.19,57.37) v5(18.23,37.25) v5(18.23,13.75) v5(18.32,68.06) v5(18.31,16.48) v5(18.27,10.47) v5(18.43,67.47) v5(18.51,56.31) v5(18.49,12.07) v5(18.55,15.62) v5(18.67,69.12) v5(18.67,39.25) v5(18.69,38.46) v5(18.82,20.43) v5(18.83,19.84) v5(18.83,10.46) v5(18.85,20.98) v5(19.02,21.73) v5(18.99,14.09) v5(19.09,64.31) v5(19.06,53) v5(19.08,39.26) v5(19.13,11.81) v5(19.14,37.93) v5(19.14,37.15) v5(19.16,13.67) v5(19.34,25.31) v5(19.27,10.59) v5(19.43,37.62) v5(19.46,26.37) v5(19.44,19.27) v5(19.6,68.72) v5(19.63,53.23) v5(19.54,21.26) v5(19.65,63.15) v5(19.7,50.94) v5(19.73,37.65) v5(19.72,33.78) v5(19.7,31.34) v5(19.71,25.01) v5(19.74,12.59) v5(19.84,66.91) v5(19.77,35.43) v5(19.82,22.21) v5(19.84,10.48) v5(19.93,51.41) v5(19.91,50.45) v5(19.93,23.61) v5(19.86,14.9) v5(19.95,49.36) v5(19.98,24.42) v5(19.98,21.71) v5(20.02,21.02) v5(20.03,13.28) v5(20.08,35.86) v5(20.15,18.9) v5(20.22,18.51) v5(20.34,35.52) v5(20.31,30.79) v5(20.31,25.76) v5(20.32,22.05) v5(20.42,58.52) v5(20.37,33.72) v5(20.5,23.47) v5(20.5,20.73) v5(20.46,19.05) v5(20.54,56.57) v5(20.55,13.62) v5(20.61,11.82) v5(20.63,10.49) v5(20.67,58.02) v5(20.71,56.72) v5(20.76,57.69) v5(20.83,35.45) v5(20.75,34.14) v5(20.84,22.62) v5(20.79,21.75) v5(20.84,20.7) v5(20.83,17.91) v5(20.86,23.44) v5(20.96,33.09) v5(21.07,13.71) v5(21.1,10.47) v5(21.15,68.69) v5(21.14,53.97) v5(21.22,40.29) v5(21.24,38.42) v5(21.17,19.11) v5(21.25,67.46) v5(21.26,54.83) v5(21.33,33.88) v5(21.42,24.57) v5(21.48,11.81) v5(21.54,31.33) v5(21.54,30.75) v5(21.54,29.12) v5(21.54,23.06) v5(21.63,21.52) v5(21.55,12.62) v5(21.74,27.55) v5(21.68,19.51) v5(21.65,10.08) v5(21.81,53.21) v5(21.88,68.03) v5(21.91,66.89) v5(21.84,32.05) v5(21.93,26.07) v5(22,54.55) v5(22.01,26.9) v5(22.01,12.77) v5(22.12,45.64) v5(22.09,44.33) v5(22.12,41.81) v5(22.17,39.52) v5(22.16,38.34) v5(22.21,35.51) v5(22.24,28.12) v5(22.21,25.64) v5(22.16,18.7) v5(22.24,17.06) v5(22.15,9.63) v5(22.3,16.44) v5(22.3,15.81) v5(22.36,24.29) v5(22.41,19.19) v5(22.43,17.6) v5(22.45,50.44) v5(22.45,48.94) v5(22.45,30.84) v5(22.48,22.25) v5(22.52,21.84) v5(22.52,11.67) v5(22.63,40.34) v5(22.63,38.85) v5(22.65,65.96) v5(22.7,55.89) v5(22.73,33.74) v5(22.71,30.16) v5(22.7,29.6) v5(22.66,28.85) v5(22.68,28.4) v5(22.68,25.87) v5(22.66,21.09) v5(22.69,18.57) v5(22.7,12.07) v5(22.77,34.55) v5(22.76,26.55) v5(22.75,10.75) v5(22.85,68.69) v5(23.03,29.65) v5(23.22,39.25) v5(23.16,27.84) v5(23.16,26.55) v5(23.14,16.44) v5(23.15,11.37) v5(23.34,65.14) v5(23.34,45.24) v5(23.3,18.7) v5(23.32,9.61) v5(23.43,63.37) v5(23.43,62.52) v5(23.42,44.33) v5(23.42,29.08) v5(23.37,24.21) v5(23.38,23.33) v5(23.43,11.82) v5(23.46,60.31) v5(23.53,60.02) v5(23.48,28.45) v5(23.46,23.07) v5(23.44,21.84) v5(23.47,21.11) v5(23.6,60.53) v5(23.62,15.81) v5(23.62,10.75) v5(23.65,39.7) v5(23.69,36.53) v5(23.71,23.71) v5(23.76,28.59) v5(23.92,60.66) v5(23.88,60.36) v5(23.93,23.43) v5(23.86,11.37) v5(23.97,59.57) v5(23.94,25.67) v5(23.98,19.41) v5(24,11.66) v5(24.05,58.77) v5(24.07,57.38) v5(24.09,56.84) v5(24.13,38.59) v5(24.12,22.26) v5(24.21,23.52) v5(24.22,20.78) v5(24.19,16.3) v5(24.23,15.31) v5(24.31,64.24) v5(24.27,28.02) v5(24.31,9.62) v5(24.63,68.7) v5(24.61,61.51) v5(24.55,59.97) v5(24.55,57.98) v5(24.6,41.37) v5(24.6,38.47) v5(24.63,24.45) v5(24.63,22.85) v5(24.56,10.74) v5(24.71,55.06) v5(24.71,29.2) v5(24.72,28.02) v5(24.73,27.5) v5(24.74,23.68) v5(24.71,15.41) v5(24.72,11.28) v5(24.81,65.99) v5(24.79,61.06) v5(24.78,14.75) v5(24.92,62.61) v5(24.91,62.06) v5(24.92,61.52) v5(24.93,60.67) v5(24.85,35.62) v5(24.87,22.1) v5(24.85,15.91) v5(24.96,33.84) v5(24.99,20.92) v5(25.01,19.7) v5(25.01,17.63) v5(24.94,9.61) v5(25.09,67.5) v5(25.07,41.42) v5(25.07,38.59) v5(25.13,19.21) v5(25.09,18.23) v5(25.18,64.97) v5(25.23,30.54) v5(25.23,28.84) v5(25.22,24.59) v5(25.21,23.62) v5(25.26,57.36) v5(25.31,55.89) v5(25.26,28.08) v5(25.31,25.71) v5(25.3,23.92) v5(25.29,22.23) v5(25.3,14.93) v5(25.41,32.16) v5(25.37,14.17) v5(25.35,10.76) v5(25.48,61.51) v5(25.51,60.67) v5(25.49,59.92) v5(25.53,41.05) v5(25.53,23.12) v5(25.52,11.28) v5(25.64,58.61) v5(25.57,53.8) v5(25.57,52.8) v5(25.57,50.8) v5(25.57,48.8) v5(25.57,46.91) v5(25.57,44.8) v5(25.57,42.8) v5(25.55,27.55) v5(25.55,21.85) v5(25.62,20.96) v5(25.62,8.94) v5(25.74,61.5) v5(25.71,31.07) v5(25.74,30.62) v5(25.72,29.05) v5(25.71,27.36) v5(25.69,26.74) v5(25.7,18.49) v5(25.76,62.06) v5(25.76,58.08) v5(25.76,32.6) v5(25.9,63.2) v5(25.88,58.56) v5(25.93,35.48) v5(25.85,23.39) v5(25.88,13.66) v5(25.94,22.49) v5(26,10.82) v5(26.07,63.98) v5(26.08,62.07) v5(26.09,32.61) v5(26.05,32.1) v5(26.1,21.39) v5(26.24,35.49) v5(26.24,34.98) v5(26.24,22.38) v5(26.14,17.15) v5(26.31,62.61) v5(26.29,27.47) v5(26.34,26.38) v5(26.33,16.31) v5(26.27,14.21) v5(26.34,8.22) v5(26.44,35.27) v5(26.43,13.12) v5(26.42,10.4) v5(26.47,68.7) v5(26.53,66.08) v5(26.49,31.87) v5(26.48,27.84) v5(26.47,18.57) v5(26.52,13.65) v5(26.58,62.12) v5(26.58,36.16) v5(26.58,25.09) v5(26.57,23.4) v5(26.65,63.35) v5(26.65,35.8) v5(26.69,34.09) v5(26.7,33.36) v5(26.66,32.36) v5(26.68,30.07) v5(26.69,29.26) v5(26.69,24.07) v5(26.69,21.91) v5(26.67,19.92) v5(26.71,19.2) v5(26.81,62.63) v5(26.82,60.11) v5(26.74,31.43) v5(26.79,31.02) v5(26.77,28.79) v5(26.76,27.52) v5(26.79,17.18) v5(26.79,10.02) v5(26.9,63.3) v5(26.93,53.94) v5(26.88,12.67) v5(26.97,27.81) v5(27,21.12) v5(27.07,57.39) v5(27.11,30.91) v5(27.06,21.96) v5(27.1,19.39) v5(27.04,13.12) v5(27.14,34.54) v5(27.18,33.59) v5(27.18,32.34) v5(27.17,20.05) v5(27.15,15.42) v5(27.17,9.66) v5(27.17,8.95) v5(27.14,7.42) v5(27.31,63.36) v5(27.29,61.15) v5(27.29,36.82) v5(27.28,31.56) v5(27.28,23.92) v5(27.29,23.38) v5(27.35,28.52) v5(27.35,27.23) v5(27.43,24.82) v5(27.34,21.67) v5(27.41,12.16) v5(27.47,56.25) v5(27.45,31.13) v5(27.52,9.28) v5(27.62,63.36) v5(27.62,62.09) v5(27.56,24.15) v5(27.57,22.24) v5(27.54,21.88) v5(27.63,20.35) v5(27.61,17.88) v5(27.61,14.94) v5(27.7,51.54) v5(27.74,49.39) v5(27.72,47.77) v5(27.72,45.77) v5(27.73,43.78) v5(27.71,41.77) v5(27.72,39.78) v5(27.71,37.77) v5(27.68,34.64) v5(27.69,31.95) v5(27.69,31.52) v5(27.73,23.93) v5(27.73,16.76) v5(27.7,13.25) v5(27.8,64.53) v5(27.79,23.38) v5(27.82,11.73) v5(27.83,6.73) v5(27.87,35.73) v5(27.85,30.43) v5(27.86,29.95) v5(27.88,28.25) v5(27.87,27.78) v5(27.93,26.4) v5(27.84,8.98) v5(27.97,63.36) v5(27.95,54.96) v5(27.97,53.78) v5(27.95,32.18) v5(27.96,29.16) v5(28.1,61.96) v5(28.06,54.34) v5(28.04,21.88) v5(28.08,18.85) v5(28.16,66.91) v5(28.18,66.35) v5(28.21,35.06) v5(28.24,23.43) v5(28.24,17.04) v5(28.17,11.38) v5(28.32,68.7) v5(28.29,63.36) v5(28.32,30.72) v5(28.28,23.92) v5(28.29,21.88) v5(28.3,5.53) v5(28.43,62.39) v5(28.37,57.39) v5(28.42,51.53) v5(28.42,38.72) v5(28.42,37.84) v5(28.44,36.98) v5(28.4,31.88) v5(28.44,29.13) v5(28.44,28.25) v5(28.44,27.79) v5(28.39,14.02) v5(28.45,28.47) v5(28.46,27.04) v5(28.49,19.22) v5(28.51,13.5) v5(28.5,8.85) v5(28.46,8.35) v5(28.59,64.06) v5(28.54,57.55) v5(28.56,39.25) v5(28.57,32.84) v5(28.61,24.56) v5(28.54,22.13) v5(28.63,18) v5(28.71,63.37) v5(28.72,57.39) v5(28.65,25.67) v5(28.68,25.19) v5(28.69,23.38) v5(28.67,13.33) v5(28.81,61.98) v5(28.75,34.03) v5(28.77,24.19) v5(28.79,22.38) v5(28.82,21.62) v5(28.79,17.14) v5(28.78,10.8) v5(28.92,66.52) v5(28.91,57.55) v5(28.9,54.48) v5(28.87,35.23) v5(28.91,33.16) v5(28.85,32.26) v5(28.91,27.45) v5(28.84,23.78) v5(28.94,17.82) v5(28.85,10.3) v5(28.85,10.12) v5(29.02,67.52) v5(28.97,62.81) v5(29.03,24.6) v5(29.03,10.3) v5(29.03,10.12) v5(29.01,7.11) v5(29.01,6.38) v5(28.95,4.78) v5(28.97,3.76) v5(28.97,2.65) v5(28.97,1.41) v5(29.1,63.36) v5(29.07,49.18) v5(29.12,48.06) v5(29.08,28.65) v5(29.04,22.63) v5(29.07,18.52) v5(29.16,24.03) v5(29.17,14.21) v5(29.16,8.84) v5(29.17,7.64) v5(29.25,57.55) v5(29.29,25.59) v5(29.32,20.99) v5(29.28,19.45) v5(29.32,17.33) v5(29.44,66.77) v5(29.42,63.36) v5(29.43,50.22) v5(29.37,28.12) v5(29.41,27.78) v5(29.35,14.27) v5(29.42,10.8) v5(29.46,65.79) v5(29.53,19.07) v5(29.47,16.65) v5(29.47,15.39) v5(29.47,13.72) v5(29.6,64.17) v5(29.57,57.55) v5(29.62,33.86) v5(29.55,33.09) v5(29.6,24.59) v5(29.62,24.21) v5(29.63,23.34) v5(29.63,22.23) v5(29.59,17.91) v5(29.55,16.88) v5(29.54,16.11) v5(29.58,15.74) v5(29.56,10.07) v5(29.67,13.58) v5(29.67,13.37) v5(29.7,4.31) v5(29.74,3.78) v5(29.75,64.83) v5(29.81,62.38) v5(29.77,31.07) v5(29.75,30.68) v5(29.8,14.53) v5(29.8,12.54) v5(29.81,10.43) v5(29.76,9.91) v5(29.81,8.85) v5(29.75,0.32) v5(29.88,64.11) v5(29.86,57.31) v5(29.93,50.7) v5(29.87,34.23) v5(29.94,16.39) v5(29.92,15.08) v5(29.94,12.23) v5(29.94,9.59) v5(29.94,9.2) v5(29.97,65.55) v5(29.98,63.36) v5(29.98,27.04) v5(30.03,15.88) v5(30.01,10.11) v5(30.04,67.54) v5(30.13,32.65) v5(30.07,29.09) v5(30.04,28.64) v5(30.06,28.25) v5(30.09,26.17) v5(30.09,24.59) v5(30.09,23.5) v5(30.1,22.06) v5(30.06,20.21) v5(30.04,17.26) v5(30.1,13.58) v5(30.11,13.37) v5(30.17,68.7) v5(30.21,63.02) v5(30.31,17.5) v5(30.29,15.68) v5(30.26,11.64) v5(30.41,32.45) v5(30.44,15.29) v5(30.39,14.3) v5(30.39,13.83) v5(30.39,12.93) v5(30.38,12.46) v5(30.42,8.79) v5(30.41,8.48) v5(30.42,8.12) v5(30.5,16.21) v5(30.55,48.51) v5(30.59,47.48) v5(30.58,44.04) v5(30.55,40.33) v5(30.56,39.51) v5(30.56,37.94) v5(30.55,36.91) v5(30.55,36.52) v5(30.58,30.53) v5(30.59,29.1) v5(30.55,28.25) v5(30.55,27.78) v5(30.55,26.59) v5(30.55,25.33) v5(30.55,25.13) v5(30.56,24.9) v5(30.55,24.16) v5(30.62,23.5) v5(30.57,21.54) v5(30.64,18.56) v5(30.62,17.13) v5(30.6,0.86) v5(30.65,20.87) v5(30.71,20.29) v5(30.65,19.79) v5(30.65,18.2) v5(30.65,17.65) v5(30.66,16.79) v5(30.72,13.72) v5(30.65,11.47) v5(30.82,46.87) v5(30.82,46.42) v5(30.8,32.68) v5(30.81,31.04) v5(30.82,23.5) v5(30.82,14.52) v5(30.87,33.23) v5(30.87,31.93) v5(30.9,22.28) v5(30.94,20.79) v5(30.91,13.22) v5(30.92,11.94) v5(31.04,39.05) v5(30.97,12.58) v5(31.06,39.71) v5(31.1,28.24) v5(31.09,27.76) v5(31.08,27.03) v5(31.09,25.98) v5(31.09,24.78) v5(31.13,19.47) v5(31.13,18.96) v5(31.13,15.88) v5(31.13,14.22) v5(31.08,4.32) v5(31.1,3.63) v5(31.1,2.96) v5(31.11,2.22) v5(31.23,51.54) v5(31.14,29.68) v5(31.14,18.32) v5(31.14,17.64) v5(31.15,16.97) v5(31.23,12.46) v5(31.2,6.9) v5(31.2,6.68) v5(31.24,48.06) v5(31.29,31.54) v5(31.29,23.51) v5(31.27,19.89) v5(31.28,13.72) v5(31.31,12.93) v5(31.27,11.24) v5(31.27,10.84) v5(31.35,32.75) v5(31.4,19.21) v5(31.41,15.52) v5(31.44,6.64) v5(31.51,68.69) v5(31.54,59.55) v5(31.5,21.18) v5(31.47,20.53) v5(31.54,19.7) v5(31.49,18.58) v5(31.48,17.94) v5(31.49,14.98) v5(31.49,14.23) v5(31.5,1.16) v5(31.55,30.52) v5(31.57,17.35) v5(31.59,16.23) v5(31.63,13.55) v5(31.63,13.29) v5(31.64,10.42) v5(31.64,6.95) v5(31.68,64.17) v5(31.7,41.54) v5(31.66,11.55) v5(31.82,46.85) v5(31.78,43.34) v5(31.79,35.68) v5(31.8,31.68) v5(31.81,29.09) v5(31.81,23.52) v5(31.78,13.12) v5(31.79,3.62) v5(31.79,2.21) v5(31.79,1.45) v5(31.94,62.97) v5(31.89,55.68) v5(31.9,50.72) v5(31.88,35.22) v5(31.87,32.23) v5(31.93,15.56) v5(31.96,27.94) v5(31.97,27.04) v5(31.98,25.33) v5(31.99,24.86) v5(31.98,19.39) v5(31.96,18.19) v5(32.02,17.47) v5(32,16.57) v5(31.97,14.56) v5(31.96,14.13) v5(31.96,10.84) v5(32.1,67.08) v5(32.09,22.77) v5(32.11,21.75) v5(32.12,20.97) v5(32.05,12.5) v5(32.11,11.25) v5(32.09,1.14) v5(32.17,66.43) v5(32.19,55.42) v5(32.18,39.05) v5(32.22,15.24) v5(32.27,62.95) v5(32.29,58.03) v5(32.32,45.71) v5(32.32,45.34) v5(32.32,38.93) v5(32.25,28.67) v5(32.34,64.03) v5(32.4,13.12) v5(32.41,10.64) v5(32.41,5.04) v5(32.44,56.98) v5(32.47,43.24) v5(32.46,38.8) v5(32.54,35.77) v5(32.45,27.6) v5(32.52,27.09) v5(32.48,20.45) v5(32.49,18.29) v5(32.48,17.75) v5(32.45,16.79) v5(32.5,15.76) v5(32.48,13.73) v5(32.44,11.06) v5(32.52,7.88) v5(32.51,7.64) v5(32.51,7.42) v5(32.51,7.19) v5(32.51,6.97) v5(32.48,2.06) v5(32.6,67.82) v5(32.64,63.59) v5(32.55,58.14) v5(32.61,45.42) v5(32.6,45.08) v5(32.57,26.17) v5(32.61,24.89) v5(32.57,19.19) v5(32.64,6.75) v5(32.69,23.56) v5(32.7,23.14) v5(32.67,22.03) v5(32.7,21.23) v5(32.66,12.93) v5(32.69,10.31) v5(32.8,68.7) v5(32.76,63.18) v5(32.75,57.95) v5(32.83,56.99) v5(32.79,55.95) v5(32.78,43.34) v5(32.83,41.62) v5(32.83,41.44) v5(32.79,39.64) v5(32.75,29.01) v5(32.81,10.75) v5(32.78,7.89) v5(32.76,3.02) v5(32.79,1.15) v5(32.93,46.45) v5(32.86,34.13) v5(32.87,31.23) v5(32.92,17.5) v5(32.91,13.39) v5(32.89,12.5) v5(32.9,6.75) v5(32.97,63.94) v5(33,63.47) v5(33,63.03) v5(32.97,39.64) v5(33.01,16.07) v5(32.96,5.18) v5(33.01,2.06) v5(33.1,30.35) v5(33.06,25.33) v5(33.05,20.14) v5(33.07,19.26) v5(33.12,10.47) v5(33.06,9.93) v5(33.05,7.89) v5(33.09,1.45) v5(33.14,16.91) v5(33.15,14.35) v5(33.16,13.85) v5(33.17,6.75) v5(33.16,3.99) v5(33.26,47.08) v5(33.25,45.16) v5(33.24,29.1) v5(33.34,24.89) v5(33.29,7.89) v5(33.42,63.5) v5(33.41,44.5) v5(33.38,38.84) v5(33.38,38.65) v5(33.41,36.16) v5(33.42,28.23) v5(33.43,25.75) v5(33.43,17.9) v5(33.42,17.62) v5(33.39,10.21) v5(33.36,9.55) v5(33.39,1.14) v5(33.47,39.52) v5(33.48,21) v5(33.49,18.54) v5(33.51,13.11) v5(33.46,8.14) v5(33.48,7.73) v5(33.48,6.83) v5(33.48,3.37) v5(33.6,43.34) v5(33.63,14.78) v5(33.56,9.89) v5(33.58,9.33) v5(33.72,41.01) v5(33.73,2.21) v5(33.82,63.61) v5(33.77,46.62) v5(33.83,45.8) v5(33.79,33.31) v5(33.84,30.22) v5(33.81,29.09) v5(33.84,19.23) v5(33.79,16.26) v5(33.86,67.1) v5(33.94,27.08) v5(33.87,20.37) v5(33.85,19.77) v5(33.92,18.02) v5(33.94,17.61) v5(33.91,15.37) v5(33.89,12.97) v5(33.88,12.37) v5(33.89,11.84) v5(33.9,11.34) v5(33.92,10.76) v5(33.88,9.49) v5(33.99,43.91) v5(33.96,28.3) v5(33.97,24.89) v5(34,23.55) v5(34.01,20.82) v5(33.98,13.38) v5(33.98,8.04) v5(34.01,4.46) v5(34.1,68.69) v5(34.08,65.64) v5(34.08,63.94) v5(34.13,46.99) v5(34.04,9.11) v5(34.07,8.67) v5(34.08,8.33) v5(34.09,1.14) v5(34.22,66.52) v5(34.16,44.5) v5(34.19,29.83) v5(34.14,19.23) v5(34.14,7.72) v5(34.19,5.21) v5(34.26,58.83) v5(34.3,39.39) v5(34.42,63.5) v5(34.37,34.6) v5(34.4,28.99) v5(34.43,11.94) v5(34.38,3.63) v5(34.39,2.21) v5(34.39,1.45) v5(34.53,56.25) v5(34.46,55.69) v5(34.45,35.76) v5(34.5,27.11) v5(34.47,26.16) v5(34.54,23.55) v5(34.54,15.94) v5(34.44,10.73) v5(34.45,7.85) v5(34.45,6.56) v5(34.64,61.72) v5(34.56,44.55) v5(34.57,25.33) v5(34.64,24.24) v5(34.61,21.97) v5(34.55,14.12) v5(34.55,13.38) v5(34.74,63.74) v5(34.66,44) v5(34.71,27.61) v5(34.65,24.9) v5(34.65,20.9) v5(34.65,18.96) v5(34.66,18.04) v5(34.69,17.15) v5(34.7,7.02) v5(34.64,6.02) v5(34.69,1.14) v5(34.77,67.82) v5(34.77,65.64) v5(34.76,62.72) v5(34.78,43.34) v5(34.82,32.42) v5(34.77,29.32) v5(34.78,27.3) v5(34.79,15.11) v5(34.91,44.5) v5(34.89,42.31) v5(34.99,64.62) v5(34.98,54.23) v5(34.98,28.62) v5(35.01,25.75) v5(35,14.38) v5(34.96,10.74) v5(34.97,10.3) v5(34.97,9.72) v5(34.96,9.19) v5(34.97,8.46) v5(35.07,29.03) v5(35.09,13.1) v5(35.05,11.94) v5(35.05,5.22) v5(35.04,3.63) v5(35.04,2.21) v5(35.21,62.55) v5(35.26,66.51) v5(35.32,62.94) v5(35.31,45.78) v5(35.27,27.18) v5(35.41,13.32) v5(35.36,8.01) v5(35.38,4.43) v5(35.39,1.16) v5(35.5,68.69) v5(35.5,39.82) v5(35.47,15.94) v5(35.52,14.57) v5(35.47,7.18) v5(35.49,5.72) v5(35.63,64.34) v5(35.58,60.31) v5(35.58,27.14) v5(35.56,26.59) v5(35.72,63.71) v5(35.72,62.94) v5(35.67,62.51) v5(35.66,61.08) v5(35.68,31.93) v5(35.69,1.45) v5(35.8,16.15) v5(35.81,15.46) v5(35.83,8.01) v5(35.74,3.65) v5(35.81,1.97) v5(35.93,63.71) v5(35.85,61.86) v5(35.85,45.3) v5(35.91,44.5) v5(35.91,43.75) v5(35.88,11.61) v5(35.85,6.31) v5(35.97,62.5) v5(35.98,55.78) v5(36.03,54.17) v5(36.03,41.79) v5(35.98,36.16) v5(36.03,13.34) v5(35.96,7.47) v5(36,1.15) v5(36.09,61.86) v5(36.06,45.78) v5(36.06,35.75) v5(36.05,30.92) v5(36.12,11.98) v5(36.05,11.07) v5(36.05,10.36) v5(36.06,9.77) v5(36.05,9.11) v5(36.05,8.5) v5(36.07,4.62) v5(36.22,62.94) v5(36.22,41.03) v5(36.2,34.6) v5(36.32,67.1) v5(36.31,66.52) v5(36.24,39.07) v5(36.27,14.63) v5(36.28,13.48) v5(36.28,9.33) v5(36.26,8.43) v5(36.26,8.03) v5(36.31,6.8) v5(36.3,1.97) v5(36.43,43.45) v5(36.49,45.3) v5(36.5,44.3) v5(36.52,40.9) v5(36.49,23.55) v5(36.49,20.91) v5(36.49,20.31) v5(36.49,19.79) v5(36.61,63.71) v5(36.58,18.38) v5(36.55,7.46) v5(36.72,62.94) v5(36.73,39.58) v5(36.69,1.14) v5(36.74,40.09) v5(36.8,38.38) v5(36.79,36.15) v5(36.83,24.03) v5(36.9,68.69) v5(36.87,67.82) v5(36.88,23.56) v5(36.87,17.71) v5(36.98,38.38) v5(36.98,5.04) v5(37,3.62) v5(37.03,2.21) v5(36.99,1.45) v5(37.17,62.94) v5(37.21,45.92) v5(37.23,40.6) v5(37.23,40.09) v5(37.21,39.03) v5(37.21,30.39) v5(37.2,24.91) v5(37.21,24.66) v5(37.17,18.4) v5(37.3,64.53) v5(37.3,1.15) v5(37.37,66.53) v5(37.41,42.25) v5(37.41,28.9) v5(37.38,26.17) v5(37.38,25.75) v5(37.61,62.94) v5(37.57,44.36) v5(37.64,25.33) v5(37.63,23.57) v5(37.6,6.08) v5(37.68,44.79) v5(37.71,40.75) v5(37.67,5.03) v5(37.68,4.35) v5(37.68,3.62) v5(37.68,2.95) v5(37.68,2.22) v5(37.78,63.71) v5(37.78,28.28) v5(37.8,28.06) v5(37.83,26.6) v5(37.77,5.95) v5(37.88,65.2) v5(37.89,35.75) v5(37.87,27.6) v5(37.86,27.15) v5(37.9,24.89) v5(37.94,17.15) v5(37.93,11.92) v5(37.93,9.75) v5(37.93,9.26) v5(37.93,8.34) v5(38.02,67.1) v5(37.96,66.03) v5(37.97,62.94) v5(37.96,43.25) v5(38.02,26.71) v5(38.03,25.89) v5(37.99,15.21) v5(37.94,10.29) v5(38.01,7.73) v5(38.01,7.02) v5(37.99,6.33) v5(38.08,64.13) v5(38.06,47.85) v5(38.12,31.51) v5(38.06,23.56) v5(38.22,39.57) v5(38.21,28.99) v5(38.22,14.06) v5(38.22,13.49) v5(38.22,11.07) v5(38.22,10.45) v5(38.23,9.74) v5(38.23,8.95) v5(38.23,8.2) v5(38.17,0.91) v5(38.25,28.05) v5(38.27,21.14) v5(38.27,11.48) v5(38.41,66.53) v5(38.38,38.22) v5(38.44,34.61) v5(38.44,27.67) v5(38.51,64.57) v5(38.51,41.65) v5(38.51,41) v5(38.5,27.11) v5(38.51,26.35) v5(38.5,24.9) v5(38.54,68.7) v5(38.58,62.93) v5(38.6,36.15) v5(38.63,29.11) v5(38.69,26.17) v5(38.68,25.57) v5(38.67,24.74) v5(38.69,19.21) v5(38.67,17) v5(38.83,23.63) v5(38.82,20.58) v5(38.82,18.83) v5(38.78,16.69) v5(38.94,67.82) v5(38.92,62.94) v5(38.91,62.52) v5(38.94,53.79) v5(38.85,21.24) v5(39.02,50.17) v5(39.01,42.85) v5(38.97,24.49) v5(38.96,19.69) v5(38.98,13.37) v5(39.12,64.38) v5(39.09,32.41) v5(39.04,25.33) v5(39.07,22.49) v5(39.09,18.91) v5(39.16,66.36) v5(39.19,65.89) v5(39.19,64.81) v5(39.16,43.6) v5(39.22,41.65) v5(39.18,11.94) v5(39.31,62.53) v5(39.25,41.02) v5(39.26,19.84) v5(39.3,19.17) v5(39.3,15.63) v5(39.31,10.74) v5(39.31,10.15) v5(39.31,9.47) v5(39.31,8.84) v5(39.31,8.13) v5(39.39,63.71) v5(39.42,62.94) v5(39.5,43.85) v5(39.5,43.27) v5(39.53,35.76) v5(39.47,24.03) v5(39.49,21.05) v5(39.58,39.93) v5(39.58,30.64) v5(39.56,24.67) v5(39.55,0.62) v5(39.67,66.36) v5(39.69,25.75) v5(39.65,24.9) v5(39.65,22.8) v5(39.72,21.56) v5(39.69,20.38) v5(39.71,19.57) v5(39.73,5.93) v5(39.76,62.53) v5(39.76,47.86) v5(39.81,44.6) v5(39.84,67.11) v5(39.91,65.75) v5(39.92,62.94) v5(39.86,45.05) v5(39.86,38.67) v5(39.92,23.58) v5(39.87,13.38) v5(39.86,10.74) v5(39.86,10.08) v5(39.96,68.7) v5(39.98,66.14) v5(40.03,63.72) v5(40.02,24.24) v5(40.02,22.7) v5(40.03,15.49) v5(39.99,14.43) v5(39.97,13.72) v5(39.99,11.94) v5(40.1,37.76) v5(40.13,7.95) v5(40.13,6.63) v5(40.13,5.19) v5(40.17,65.2) v5(40.2,62.53) v5(40.2,49.57) v5(40.2,22.26) v5(40.24,19.83) v5(40.29,20.33) v5(40.31,3.77) v5(40.32,1.98) v5(40.32,1.33) v5(40.39,62.92) v5(40.37,13.13) v5(40.37,12.51) v5(40.37,11.85) v5(40.35,10.76) v5(40.35,10.11) v5(40.35,9.25) v5(40.47,61.65) v5(40.46,60.81) v5(40.53,26.17) v5(40.51,25.33) v5(40.48,24.9) v5(40.46,23.57) v5(40.52,22.79) v5(40.52,21.93) v5(40.5,21.12) v5(40.56,63.73) v5(40.57,45.19) v5(40.54,12.18) v5(40.71,67.82) v5(40.74,65.78) v5(40.72,61.85) v5(40.72,61.45) v5(40.67,60.4) v5(40.67,59.95) v5(40.67,59.4) v5(40.69,58.62) v5(40.72,58.3) v5(40.69,56.51) v5(40.69,51.69) v5(40.98,64.55) v5(40.98,63.49) v5(40.97,62.35) v5(40.97,61.79) v5(40.98,61.13) v5(40.97,60.15) v5(40.97,59.7) v5(40.97,59.2) v5(40.97,58.8) v5(41.05,24.89) v5(41.07,23.6) v5(41.04,22.28) v5(41.04,20.28) v5(41.05,18.65) v5(41.06,16.53) v5(41.07,12.51) v5(41.24,66) v5(41.25,66.58) v5(41.3,34.6) v5(41.26,27.06) v5(41.3,14.18) v5(41.35,12.52) v5(41.46,68.52) v5(41.46,57.87) v5(41.46,28.8) v5(41.64,55.38) v5(41.6,47.58) v5(41.68,58.08) v5(41.72,36.58) v5(41.71,25.75) v5(41.71,25.14) v5(41.73,24.9) v5(41.69,24.29) v5(41.72,23.61) v5(41.72,23.27) v5(41.78,57.59) v5(41.82,48.95) v5(41.75,41.91) v5(41.78,16.73) v5(41.79,16.3) v5(41.87,51.15) v5(41.87,50.65) v5(41.84,18.05) v5(41.97,57.75) v5(41.97,57.45) v5(41.99,55.66) v5(41.95,47.82) v5(42.01,26.17) v5(42.02,16.67) v5(42.11,68.04) v5(42.13,64.56) v5(42.12,63.82) v5(42.12,62.4) v5(42.12,41.32) v5(42.22,67.11) v5(42.19,61.9) v5(42.14,59.13) v5(42.22,57.5) v5(42.18,42.99) v5(42.16,40.25) v5(42.14,39.22) v5(42.16,38.25) v5(42.14,15.78) v5(42.27,45.59) v5(42.25,42.41) v5(42.4,64.41) v5(42.43,53.52) v5(42.43,50.83) v5(42.38,49.03) v5(42.34,44.8) v5(42.36,42.99) v5(42.34,12.52) v5(42.52,66.49) v5(42.47,65.34) v5(42.59,57.14) v5(42.6,28.57) v5(42.59,25.33) v5(42.64,23.57) v5(42.54,16.28) v5(42.71,61.5) v5(42.69,52.64) v5(42.69,24.89) v5(42.7,21.2) v5(42.84,68.52) v5(42.75,52.12) v5(42.75,42.41) v5(42.75,31.93) v5(42.83,13.96) v5(42.9,66.02) v5(42.91,41.1) v5(42.86,39.45) v5(42.87,37.78) v5(42.87,32.37) v5(43,65.27) v5(42.96,64.03) v5(42.96,56.79) v5(43.03,56.16) v5(43.01,54.73) v5(43.01,53.3) v5(43.02,51.93) v5(42.96,51.37) v5(43.01,50.19) v5(43.02,48.83) v5(43.01,47.15) v5(43.03,45.35) v5(42.95,22.95) v5(43.04,33.88) v5(43.2,66.64) v5(43.19,64.84) v5(43.22,59.22) v5(43.23,45.2) v5(43.23,44.81) v5(43.17,34.6) v5(43.29,62.69) v5(43.32,61.23) v5(43.27,58) v5(43.3,36.15) v5(43.36,67.28) v5(43.36,42.6) v5(43.37,41.53) v5(43.36,40.5) v5(43.36,39.45) v5(43.41,27.01) v5(43.39,26.16) v5(43.46,43.65) v5(43.46,27.6) v5(43.46,25.75) v5(43.48,24.9) v5(43.45,14.27) v5(43.54,23.39) v5(43.56,12.52) v5(43.66,28.39) v5(43.72,19.71) v5(43.81,68.18) v5(43.83,64.21) v5(43.76,44.73) v5(43.78,38.57) v5(43.85,63.03) v5(43.92,58) v5(43.99,59.21) v5(44.01,37.57) v5(43.98,27.58) v5(44,27.03) v5(44,26.59) v5(44.03,26.17) v5(44.04,66.69) v5(44.07,27.26) v5(44.08,24.89) v5(44.08,23.1) v5(44.16,56.65) v5(44.15,55.02) v5(44.16,52.85) v5(44.14,50.12) v5(44.14,48.73) v5(44.16,47.45) v5(44.14,45.95) v5(44.24,35.76) v5(44.16,25.65) v5(44.26,67.27) v5(44.33,12.8) v5(44.37,62.76) v5(44.35,44.97) v5(44.39,29.03) v5(44.4,26.57) v5(44.49,68.5) v5(44.53,61.66) v5(44.47,59.63) v5(44.5,48.31) v5(44.53,46) v5(44.6,67.18) v5(44.61,64.86) v5(44.59,63.4) v5(44.55,46.88) v5(44.55,44.46) v5(44.57,42.39) v5(44.61,36.15) v5(44.58,33.66) v5(44.64,26.36) v5(44.54,20.18) v5(44.6,12.52) v5(44.66,51.9) v5(44.67,25.33) v5(44.7,24.91) v5(44.69,23.09) v5(44.69,21.38) v5(44.81,56.91) v5(44.83,30.05) v5(44.75,26.89) v5(44.82,26.24) v5(44.91,61.84) v5(44.91,52.56) v5(44.85,37.1) v5(45.09,62.2) v5(45.1,38.98) v5(45.09,25.96) v5(45.08,20.37) v5(45.1,19.34) v5(45.04,13.77) v5(45.19,61.07) v5(45.24,60.2) v5(45.16,26.64) v5(45.22,22.23) v5(45.2,17.23) v5(45.2,16.85) v5(45.24,13) v5(45.27,44.22) v5(45.3,40.45) v5(45.32,21.9) v5(45.32,20.16) v5(45.4,68.71) v5(45.38,21.16) v5(45.39,18.04) v5(45.51,41.31) v5(45.45,34.03) v5(45.44,26.33) v5(45.5,22.04) v5(45.51,17.79) v5(45.46,15.51) v5(45.56,37.8) v5(45.58,25.94) v5(45.58,25.57) v5(45.57,25.12) v5(45.57,24.54) v5(45.56,24.09) v5(45.56,23.5) v5(45.56,23.24) v5(45.56,22.94) v5(45.56,22.76) v5(45.55,22.26) v5(45.63,19.51) v5(45.54,17.11) v5(45.64,12.52) v5(45.7,58.82) v5(45.67,57.02) v5(45.68,53.59) v5(45.71,48.91) v5(45.74,39.96) v5(45.69,21.03) v5(45.69,20.17) v5(45.68,16.73) v5(45.66,16.36) v5(45.78,65.97) v5(45.77,65.29) v5(45.8,31.82) v5(45.84,15.73) v5(45.78,13.01) v5(45.99,63.37) v5(45.94,59.5) v5(45.99,37.18) v5(46.02,22.04) v5(45.97,18.39) v5(46.09,62.31) v5(46.1,32.76) v5(46.04,24.37) v5(46.06,22.41) v5(46.09,16.22) v5(46.09,13.78) v5(46.14,35.35) v5(46.16,27.02) v5(46.24,23.09) v5(46.2,22.76) v5(46.16,21.61) v5(46.16,20.86) v5(46.16,19.71) v5(46.15,18.99) v5(46.25,66.47) v5(46.25,33.31) v5(46.25,31.46) v5(46.31,21.23) v5(46.33,18.03) v5(46.42,41.83) v5(46.35,26.26) v5(46.37,24.35) v5(46.39,23.55) v5(46.4,23.25) v5(46.35,21.93) v5(46.41,20.25) v5(46.34,17.15) v5(46.51,57.16) v5(46.51,52.3) v5(46.48,22.71) v5(46.51,19.36) v5(46.44,17.84) v5(46.49,16.22) v5(46.47,13.01) v5(46.63,66.28) v5(46.55,58.87) v5(46.54,58) v5(46.59,50.95) v5(46.6,49.55) v5(46.54,16.94) v5(46.65,68.7) v5(46.68,15.25) v5(46.79,63.77) v5(46.74,61.51) v5(46.75,60.75) v5(46.77,51.6) v5(46.75,48.01) v5(46.76,36.35) v5(46.82,35.36) v5(46.81,20.86) v5(46.81,20.46) v5(46.79,19.77) v5(46.81,19.36) v5(46.81,18.61) v5(46.81,16.67) v5(46.79,13.03) v5(46.87,62.66) v5(46.91,15.83) v5(46.89,12.53) v5(47.03,40.44) v5(46.98,25.59) v5(47.02,24.53) v5(46.96,23.11) v5(47.07,21.93) v5(47.12,13.01) v5(47.24,43.66) v5(47.23,30.64) v5(47.16,22.75) v5(47.18,21.58) v5(47.17,20.88) v5(47.17,20.41) v5(47.16,19.71) v5(47.16,16.16) v5(47.2,13.71) v5(47.18,12.62) v5(47.27,60.22) v5(47.33,58.82) v5(47.25,39.57) v5(47.27,23.5) v5(47.3,13.35) v5(47.42,28.16) v5(47.36,15.36) v5(47.37,14.82) v5(47.44,61.13) v5(47.45,38.17) v5(47.5,32.53) v5(47.5,18.95) v5(47.57,60.4) v5(47.57,58) v5(47.55,30.15) v5(47.63,28.77) v5(47.56,22.35) v5(47.56,21.21) v5(47.56,20.09) v5(47.54,18.55) v5(47.58,15.74) v5(47.71,23.18) v5(47.73,19.32) v5(47.69,12.52) v5(47.83,68.64) v5(47.84,55.98) v5(47.76,53.7) v5(47.77,45.35) v5(47.83,36.44) v5(47.75,23.72) v5(47.81,22.76) v5(47.81,22.03) v5(47.84,21.43) v5(47.84,20.43) v5(47.84,19.7) v5(47.8,14.92) v5(47.79,13.97) v5(47.79,13.47) v5(47.92,60.18) v5(47.9,58.23) v5(47.93,50.95) v5(47.92,44.59) v5(48,49.56) v5(48.03,41.99) v5(48.03,39.13) v5(48.03,31.98) v5(47.97,31.44) v5(47.98,30.43) v5(48.03,29.34) v5(48.03,15.32) v5(48.13,16.32) v5(48.16,61.46) v5(48.24,23.1) v5(48.17,21.92) v5(48.2,19.69) v5(48.16,18.55) v5(48.2,14.52) v5(48.27,37.48) v5(48.27,36.67) v5(48.33,36.06) v5(48.32,27.28) v5(48.27,22.67) v5(48.34,21.43) v5(48.25,20.86) v5(48.25,20.37) v5(48.38,34.38) v5(48.35,17.51) v5(48.36,15.32) v5(48.36,13.92) v5(48.35,13.36) v5(48.52,68.24) v5(48.47,65.24) v5(48.5,38.21) v5(48.52,21.21) v5(48.52,20.09) v5(48.52,18.95) v5(48.46,17.19) v5(48.59,30.41) v5(48.63,12.7) v5(48.7,59.39) v5(48.74,57.38) v5(48.72,56.2) v5(48.71,55.08) v5(48.74,53.37) v5(48.74,50.42) v5(48.74,41.28) v5(48.74,40.79) v5(48.74,35.66) v5(48.72,21.93) v5(48.66,14.06) v5(48.75,54.31) v5(48.76,52.81) v5(48.76,51.62) v5(48.75,49.71) v5(48.76,48.79) v5(48.75,46.85) v5(48.76,45.43) v5(48.75,44.51) v5(48.75,43.55) v5(48.75,42.44) v5(48.75,39.83) v5(48.75,38.92) v5(48.8,27.56) v5(48.83,23.7) v5(48.84,21.57) v5(48.84,20.47) v5(48.84,19.68) v5(48.84,19.18) v5(48.84,17.09) v5(48.76,13.76) v5(48.83,12.52) v5(48.87,16.19) v5(48.9,12.7) v5(48.96,30.79) v5(49.02,14.3) v5(49.02,13.02) v5(49.08,62.73) v5(49.05,32.36) v5(49.07,28.77) v5(49.19,19.35) v5(49.21,18.55) v5(49.15,13.53) v5(49.27,63.42) v5(49.33,58.78) v5(49.31,35.08) v5(49.25,19.71) v5(49.37,68.24) v5(49.38,26.17) v5(49.35,24.27) v5(49.35,21.55) v5(49.5,66.45) v5(49.5,60.24) v5(49.5,59.08) v5(49.44,20.94) v5(49.45,15.9) v5(49.51,14.11) v5(49.54,67.31) v5(49.59,65.63) v5(49.63,36.96) v5(49.64,31.51) v5(49.54,22.35) v5(49.54,21.21) v5(49.54,20.09) v5(49.54,18.95) v5(49.72,37.5) v5(49.66,32.02) v5(49.65,27.31) v5(49.72,13.52) v5(49.8,26.52) v5(49.83,21.97) v5(49.83,21.58) v5(49.8,20.4) v5(49.89,35.06) v5(49.89,13.02) v5(50,63.76) v5(49.95,63.31) v5(50.03,62.68) v5(49.96,59.73) v5(49.94,58.15) v5(49.98,23.51) v5(50.07,57.49) v5(50.12,56.71) v5(50.08,55.98) v5(50.09,55.08) v5(50.07,54.39) v5(50.07,53.1) v5(50.08,52.01) v5(50.07,50.87) v5(50.12,49.74) v5(50.07,48.54) v5(50.09,47.31) v5(50.08,46.18) v5(50.09,45.31) v5(50.08,44.76) v5(50.05,44.02) v5(50.09,43.17) v5(50.08,41.96) v5(50.08,41.42) v5(50.08,40.79) v5(50.08,40.22) v5(50.07,39.47) v5(50.08,38.53) v5(50.08,37.85) v5(50.12,37.09) v5(50.11,33.8) v5(50.05,27.76) v5(50.13,24.99) v5(50.09,13.96) v5(50.21,53.99) v5(50.15,36.43) v5(50.23,22.04) v5(50.21,19.3) v5(50.21,18.55) v5(50.25,66.48) v5(50.27,55.8) v5(50.29,52.3) v5(50.24,50.69) v5(50.27,38.23) v5(50.27,21.57) v5(50.42,37.48) v5(50.39,20.86) v5(50.36,13.61) v5(50.41,12.53) v5(50.52,25.44) v5(50.56,22.35) v5(50.56,21.17) v5(50.56,20.09) v5(50.72,36.53) v5(50.65,26.31) v5(50.69,22.95) v5(50.75,36.17) v5(50.81,22.04) v5(50.84,21.43) v5(50.91,28.18) v5(50.88,20.42) v5(50.91,19.66) v5(50.9,19.34) v5(50.85,18.6) v5(50.97,41.33) v5(50.96,27.33) v5(50.94,25.15) v5(51.04,61.66) v5(51.08,58.02) v5(51.13,50.94) v5(51.13,37.23) v5(51.09,16.73) v5(51.17,58.56) v5(51.14,49.66) v5(51.21,47.32) v5(51.15,35.78) v5(51.19,23.19) v5(51.22,18.79) v5(51.15,16.28) v5(51.33,62.46) v5(51.3,60.52) v5(51.24,56.78) v5(51.26,54.01) v5(51.31,36.67) v5(51.25,21.95) v5(51.34,21.57) v5(51.25,20.48) v5(51.32,19.74) v5(51.26,19.36) v5(51.31,13.86) v5(51.3,13.31) v5(51.26,13.03) v5(51.26,12.52) v5(51.36,44.74) v5(51.37,27.67) v5(51.42,22.22) v5(51.39,20.89) v5(51.46,31.79) v5(51.48,31.29) v5(51.47,29.76) v5(51.53,26.55) v5(51.57,62.46) v5(51.62,35.32) v5(51.56,25.13) v5(51.59,15.52) v5(51.7,68.23) v5(51.71,39.59) v5(51.73,23.51) v5(51.73,23.2) v5(51.84,55.62) v5(51.82,35.79) v5(51.81,33.87) v5(51.83,32.76) v5(51.84,32.24) v5(51.76,29.22) v5(51.8,16.89) v5(51.84,62.07) v5(51.86,56.79) v5(51.89,52.96) v5(51.9,24.2) v5(51.91,22.76) v5(51.91,21.16) v5(51.91,20.5) v5(51.91,19.36) v5(51.89,14.84) v5(52.02,22.34) v5(52.02,14.19) v5(52.06,63.68) v5(52.08,36.8) v5(52.12,36.41) v5(52.05,25.76) v5(52.23,41.17) v5(52.18,13.53) v5(52.18,13.02) v5(52.26,47.52) v5(52.26,45.99) v5(52.28,44.99) v5(52.24,44.04) v5(52.24,42.44) v5(52.34,35.31) v5(52.3,32.24) v5(52.3,13.78) v5(52.48,59.34) v5(52.49,36.43) v5(52.52,23.51) v5(52.51,12.52) v5(52.56,61.65) v5(52.56,38.3) v5(52.59,37.31) v5(52.63,31.07) v5(52.58,30.74) v5(52.62,26.23) v5(52.62,14.63) v5(52.67,25) v5(52.69,23.23) v5(52.7,22.92) v5(52.67,20.98) v5(52.65,15.17) v5(52.8,66.48) v5(52.84,36.01) v5(52.88,32.59) v5(52.92,24.2) v5(52.99,36.83) v5(52.99,33.84) v5(53,31.22) v5(53.03,30.39) v5(53.04,27.97) v5(53.02,23.34) v5(53.11,18.21) v5(53.08,14.07) v5(53.11,13.52) v5(53.13,13.02) v5(53.09,12.63) v5(53.23,58.56) v5(53.21,37.95) v5(53.16,31.76) v5(53.14,21.22) v5(53.16,15.92) v5(53.26,67.41) v5(53.28,66.45) v5(53.33,36.01) v5(53.34,22.17) v5(53.35,27.66) v5(53.43,24.45) v5(53.51,39.33) v5(53.51,31.69) v5(53.49,29.31) v5(53.51,21.2) v5(53.52,14.63) v5(53.55,67.95) v5(53.55,33.12) v5(53.62,23.12) v5(53.62,15.22) v5(53.55,13.69) v5(53.72,61.65) v5(53.71,56.49) v5(53.66,31.02) v5(53.68,13.15) v5(53.78,59.32) v5(53.74,52.48) v5(53.75,48.86) v5(53.75,46.11) v5(53.76,44.18) v5(53.76,42.34) v5(53.74,37.78) v5(53.84,37.29) v5(53.8,35.62) v5(53.8,33.36) v5(53.74,32.58) v5(53.78,22.26) v5(53.75,21.84) v5(53.75,20.82) v5(53.91,31.92) v5(53.86,31.27) v5(53.87,18.85) v5(53.99,38.21) v5(54.02,37.27) v5(54.02,33.99) v5(53.97,30.19) v5(53.96,13.8) v5(54.06,63.48) v5(54.04,62.12) v5(54.11,38.9) v5(54.06,33.6) v5(54.11,31.16) v5(54.08,28.52) v5(54.05,23.76) v5(54.07,21.39) v5(54.07,20.31) v5(54.22,65.64) v5(54.14,64.69) v5(54.15,13.4) v5(54.17,12.72) v5(54.26,67.42) v5(54.31,39.84) v5(54.31,34.79) v5(54.34,33.85) v5(54.26,33.35) v5(54.25,16.95) v5(54.29,14.58) v5(54.37,35.16) v5(54.43,16.03) v5(54.52,68.23) v5(54.48,47.53) v5(54.48,40.78) v5(54.54,36.32) v5(54.51,20.34) v5(54.62,39.38) v5(54.58,34.35) v5(54.61,31.91) v5(54.55,30.92) v5(54.67,57.47) v5(54.65,30.15) v5(54.65,22.31) v5(54.68,18.62) v5(54.71,17.38) v5(54.65,17.21) v5(54.75,55.64) v5(54.75,51.59) v5(54.74,37.57) v5(54.76,33.85) v5(54.76,32.86) v5(54.83,14.5) v5(54.93,43.39) v5(54.93,16.58) v5(54.85,13.34) v5(54.89,12.73) v5(55.02,52.43) v5(54.97,46.34) v5(54.94,28.43) v5(55.03,21.43) v5(55.1,48.89) v5(55.05,34.59) v5(55.05,20.09) v5(55.16,66.48) v5(55.23,56.14) v5(55.23,51.43) v5(55.17,18.86) v5(55.26,65.85) v5(55.28,65.27) v5(55.28,64.69) v5(55.28,61.64) v5(55.27,60.02) v5(55.28,58.65) v5(55.25,54.33) v5(55.26,52.44) v5(55.24,50.44) v5(55.27,36.29) v5(55.25,33.86) v5(55.26,32.28) v5(55.25,27.1) v5(55.39,48.3) v5(55.53,37.34) v5(55.59,25.45) v5(55.56,19.54) v5(55.71,32.28) v5(55.71,31.7) v5(55.7,23.3) v5(55.66,20.73) v5(55.71,16.29) v5(55.82,66.97) v5(55.82,31.09) v5(55.82,30.74) v5(55.82,30.39) v5(55.82,30.04) v5(55.82,29.69) v5(55.91,38.59) v5(55.92,25.12) v5(56.07,35.62) v5(56.13,31.09) v5(56.13,30.74) v5(56.13,30.39) v5(56.13,30.04) v5(56.13,29.69) v5(56.05,27.79) v5(56.1,26.17) v5(56.05,21.76) v5(56.11,12.73) v5(56.18,67.86) v5(56.17,27.15) v5(56.2,19.54) v5(56.23,18.61) v5(56.22,16.72) v5(56.21,16.2) v5(56.22,15.53) v5(56.14,14.08) v5(56.31,21.59) v5(56.26,20.32) v5(56.24,14.91) v5(56.37,42.98) v5(56.41,41.21) v5(56.39,39.38) v5(56.41,17.36) v5(56.46,31.09) v5(56.46,30.74) v5(56.46,30.39) v5(56.46,30.04) v5(56.46,29.69) v5(56.48,26.55) v5(56.55,47.66) v5(56.56,41.76) v5(56.55,36.77) v5(56.56,17.68) v5(56.68,66.98) v5(56.69,32.79) v5(56.73,32.02) v5(56.73,15.19) v5(56.72,14.34) v5(56.77,31.08) v5(56.77,30.74) v5(56.77,30.39) v5(56.77,30.04) v5(56.77,29.69) v5(56.74,16.3) v5(56.91,64.94) v5(56.9,63.48) v5(56.91,61.65) v5(56.92,59.83) v5(56.91,56.56) v5(56.91,54.92) v5(56.9,53.61) v5(56.92,52.28) v5(56.93,50.84) v5(56.91,49.71) v5(56.88,19.78) v5(56.92,19.23) v5(56.92,18.73) v5(56.89,17.09) v5(56.86,13.82) v5(56.98,68.24) v5(57.04,66.28) v5(57.01,58.62) v5(56.99,48.1) v5(56.98,43.54) v5(57,42.83) v5(56.95,13.46) v5(57.05,57.72) v5(57.07,48.9) v5(57.1,30.74) v5(57.1,18.43) v5(57.11,12.73) v5(57.22,67.53) v5(57.23,35.49) v5(57.21,14.09) v5(57.24,66.48) v5(57.33,66.02) v5(57.33,46.09) v5(57.25,20.51) v5(57.42,19.23) v5(57.43,18.74) v5(57.44,59.28) v5(57.54,41.05) v5(57.45,39.28) v5(57.47,31.97) v5(57.46,29.38) v5(57.47,26.29) v5(57.5,17.27) v5(57.5,16.95) v5(57.6,44.51) v5(57.56,24.78) v5(57.56,18.14) v5(57.61,13.2) v5(57.54,12.69) v5(57.72,53.39) v5(57.69,13.88) v5(57.68,12.55) v5(57.74,55.83) v5(57.78,49.86) v5(57.84,42.38) v5(57.79,37.9) v5(57.81,25.27) v5(57.82,22.88) v5(57.74,19.22) v5(57.86,66.44) v5(57.89,30.85) v5(57.96,67.24) v5(57.95,64.2) v5(58.02,43.46) v5(58.04,20.63) v5(58.08,56.64) v5(58.05,40.55) v5(58.06,39.01) v5(58.06,21.37) v5(58.14,61.88) v5(58.16,44.18) v5(58.15,17.61) v5(58.28,66.48) v5(58.28,66.07) v5(58.24,40.55) v5(58.24,33.86) v5(58.27,30.32) v5(58.3,19.13) v5(58.38,38.06) v5(58.51,66.19) v5(58.49,44.22) v5(58.49,42.01) v5(58.46,37.17) v5(58.46,36.17) v5(58.46,35.17) v5(58.5,13.8) v5(58.53,12.77) v5(58.57,67.45) v5(58.55,63.98) v5(58.59,46.65) v5(58.62,30.88) v5(58.56,29.09) v5(58.56,26.98) v5(58.68,60.44) v5(58.69,55.67) v5(58.71,28.95) v5(58.67,18.57) v5(58.72,12.54) v5(58.82,59.42) v5(58.76,41.52) v5(58.76,22.02) v5(58.76,21.17) v5(58.79,20.02) v5(58.82,18.74) v5(58.85,61.55) v5(58.91,56.87) v5(58.86,29.09) v5(58.92,14.04) v5(58.96,68.21) v5(59,63.48) v5(59.04,37.27) v5(59.03,35.52) v5(59,34.11) v5(58.97,26.8) v5(58.97,26.39) v5(59.04,24.97) v5(59.04,24.45) v5(59.09,39.27) v5(59.09,28.4) v5(59.09,25.7) v5(59.19,64.38) v5(59.2,62.08) v5(59.21,33.17) v5(59.21,32.17) v5(59.21,31.17) v5(59.17,29.38) v5(59.15,27.73) v5(59.18,22.5) v5(59.18,17.24) v5(59.34,55.63) v5(59.33,54.77) v5(59.28,51.83) v5(59.34,47) v5(59.33,44.48) v5(59.29,42.77) v5(59.24,34.69) v5(59.28,22.87) v5(59.36,66.67) v5(59.35,66.24) v5(59.4,35.28) v5(59.43,17.77) v5(59.37,17.24) v5(59.5,51.21) v5(59.44,22.03) v5(59.44,19.88) v5(59.44,19.1) v5(59.45,18.38) v5(59.63,66.24) v5(59.63,61.76) v5(59.6,42.37) v5(59.59,33.8) v5(59.6,32.91) v5(59.6,28.41) v5(59.64,25.71) v5(59.65,66.68) v5(59.66,61.56) v5(59.66,61.04) v5(59.64,60.47) v5(59.71,59.74) v5(59.68,32.06) v5(59.71,30.17) v5(59.7,26.45) v5(59.84,49.93) v5(59.77,38.55) v5(59.76,34.5) v5(59.84,58.98) v5(59.86,54.2) v5(59.89,52.93) v5(59.9,43.92) v5(59.86,27.54) v5(59.86,22.48) v5(59.85,18.37) v5(59.9,15.77) v5(59.94,61.5) v5(59.96,47.02) v5(60.07,68.44) v5(60.08,55.87) v5(60.1,35.52) v5(60.07,29.48) v5(60.08,28.42) v5(60.22,60.22) v5(60.33,66.06) v5(60.26,40.25) v5(60.34,32.03) v5(60.24,20.1) v5(60.33,16.99) v5(60.35,45.99) v5(60.54,69.29) v5(60.51,58.66) v5(60.46,57.43) v5(60.5,50.14) v5(60.5,48.23) v5(60.46,35.72) v5(60.46,29.42) v5(60.54,16.44) v5(60.57,64.21) v5(60.57,60.93) v5(60.7,55.87) v5(60.81,43.58) v5(60.77,34.16) v5(60.77,33.89) v5(60.81,30.89) v5(60.82,18.29) v5(60.76,16.42) v5(60.93,65.11) v5(60.93,54.77) v5(60.87,15.77) v5(61.01,67.84) v5(60.98,64.45) v5(61.02,64.23) v5(60.99,60.12) v5(61.01,51.34) v5(61.01,50.01) v5(61.01,48.35) v5(60.96,44.54) v5(61.01,35.85) v5(61,34.16) v5(61,33.89) v5(61,31.84) v5(61.05,66.35) v5(61.06,57.13) v5(61.06,30.11) v5(61.19,59.06) v5(61.26,59.67) v5(61.33,54.77) v5(61.33,53.17) v5(61.31,32.16) v5(61.3,31.14) v5(61.54,48.63) v5(61.53,46.68) v5(61.52,44.59) v5(61.44,16.39) v5(61.64,30.3) v5(61.56,18.5) v5(61.73,53.57) v5(61.73,53.17) v5(61.7,35.85) v5(61.72,27.14) v5(61.71,26.75) v5(61.7,26.3) v5(61.7,25.83) v5(61.7,25.36) v5(61.7,24.89) v5(61.71,24.42) v5(61.7,23.94) v5(61.7,23.42) v5(61.7,22.88) v5(61.71,22.42) v5(61.7,21.95) v5(61.7,21.45) v5(61.7,20.95) v5(61.71,20.49) v5(61.7,19.82) v5(61.77,68.59) v5(61.83,64.61) v5(61.79,59.59) v5(61.75,32.47) v5(61.75,31.27) v5(61.75,29.77) v5(61.75,28.57) v5(61.75,27.42) v5(61.85,41.77) v5(61.87,15.77) v5(61.97,62.94) v5(62.04,62.06) v5(62.1,49.34) v5(62.2,59.07) v5(62.19,57.39) v5(62.25,56.69) v5(62.3,37.63) v5(62.39,58.32) v5(62.43,48.33) v5(62.42,45.52) v5(62.39,43.43) v5(62.4,35.85) v5(62.45,68.26) v5(62.45,60.37) v5(62.52,18.94) v5(62.79,67) v5(62.79,65.56) v5(62.84,59.05) v5(62.78,54.8) v5(62.77,15.77) v5(62.92,53.27) v5(62.92,50.73) v5(62.97,63.56) v5(63.03,61.04) v5(62.95,59.55) v5(62.95,56.34) v5(63.07,35.85) v5(63.26,17.02) v5(63.41,59.62) v5(63.35,43.28) v5(63.52,18.94) v5(63.63,68.23) v5(63.57,58.24) v5(63.63,44.01) v5(63.7,47.98) v5(63.68,46.89) v5(63.65,45.3) v5(63.73,42.73) v5(63.73,15.78) v5(63.83,39.04) v5(63.76,35.85) v5(64.28,64.76) v5(64.27,47.57) v5(64.28,43.61) v5(64.33,17.03) v5(64.38,67.49) v5(64.37,66.36) v5(64.36,56.88) v5(64.48,65.19) v5(64.51,59.87) v5(64.54,58.65) v5(64.5,57.83) v5(64.52,42.33) v5(64.47,35.84) v5(64.52,18.94) v5(64.64,62.45) v5(64.57,41.4) v5(64.63,15.42) v5(64.67,56.1) v5(64.68,55.14) v5(64.71,54.06) v5(64.83,53.06) v5(64.83,51.17) v5(64.82,49.56) v5(64.82,15.84) v5(64.79,12.58) v5(64.79,12.08) v5(64.79,11.58) v5(64.79,11.08) v5(64.85,39.22) v5(64.89,13.78) v5(64.99,48.08) v5(64.97,46.29) v5(65.17,61.93) v5(65.18,60.64) v5(65.18,58.64) v5(65.21,37.58) v5(65.16,37.08) v5(65.17,36.55) v5(65.14,36) v5(65.34,38.06) v5(65.31,16.59) v5(65.29,15.82) v5(65.37,64.64) v5(65.37,63.02) v5(65.37,56.64) v5(65.37,54.64) v5(65.37,46.13) v5(65.36,45.73) v5(65.36,45.17) v5(65.36,44.58) v5(65.36,44.17) v5(65.36,43.61) v5(65.36,43.02) v5(65.35,42.52) v5(65.36,41.96) v5(65.36,41.4) v5(65.36,40.81) v5(65.35,40.31) v5(65.35,39.71) v5(65.35,39.15) v5(65.35,38.56) v5(65.37,19.42) v5(65.47,20.24) v5(65.64,49) v5(65.8,12.58) v5(65.8,12.08) v5(65.8,11.58) v5(65.8,11.08) v5(65.88,53.6) v5(65.99,51.84) v5(65.94,48.1) v5(65.94,17.61) v5(65.94,15.42) v5(66.19,18.27) v5(66.33,16.61) v5(66.37,52.51) v5(66.46,50.76) v5(66.47,20.24) v5(66.67,53.37) v5(66.69,15.43) v5(67.07,48.2) v5(67.08,18.67) v5(67.11,16.4) v5(67.2,49.46) v5(67.4,50.51) v5(67.44,15.43) v5(67.47,20.24) v5(67.86,16.62) v5(67.99,52.94) v5(68.09,48.56) v5(68.1,15.43) v5(68.15,52.71) v5(68.19,51.68) v5(68.15,50.94) v5(68.18,16.23) v5(68.33,49.31) v5(68.32,18.23) v5(68.25,17.23) v5(68.41,19.23) v5(68.47,20.24) v6(0.31,20.23) v6(0.36,19.37) v6(0.44,18.37) v6(0.44,52.2) v6(0.46,50.98) v6(0.48,49.2) v6(0.52,17.37) v6(0.54,52.6) v6(0.54,50.56) v6(0.64,49.71) v6(0.64,49.37) v6(0.59,16.36) v6(0.65,50.41) v6(0.65,50.04) v6(0.64,49.09) v6(0.7,48.74) v6(0.67,15.36) v6(0.76,52.93) v6(0.78,52.53) v6(0.92,53.07) v6(0.84,18.28) v6(0.93,16.67) v6(1.07,52.86) v6(1.19,48.43) v6(1.27,53.05) v6(1.31,20.23) v6(1.5,50.41) v6(1.59,48.43) v6(1.65,18.69) v6(1.7,16.36) v6(1.67,15.36) v6(1.82,53.35) v6(1.92,48.42) v6(2.26,48.42) v6(2.31,20.23) v6(2.46,18.38) v6(2.49,16.69) v6(2.47,15.36) v6(2.57,53.25) v6(2.56,48.41) v6(2.73,51.84) v6(2.65,48.1) v6(2.74,53.07) v6(2.82,17.57) v6(2.89,52.94) v6(2.93,50.93) v6(2.93,50.53) v6(2.92,50.2) v6(2.92,49.86) v6(3.04,13.58) v6(3.04,12.68) v6(3.04,11.78) v6(3.04,10.92) v6(3.11,15.36) v6(3.05,14.78) v6(3.28,54.07) v6(3.3,46.28) v6(3.31,20.23) v6(3.41,64.79) v6(3.41,63.53) v6(3.41,62.49) v6(3.4,56.97) v6(3.4,55.18) v6(3.4,43.67) v6(3.4,40.67) v6(3.4,37.67) v6(3.39,31.52) v6(3.39,30.52) v6(3.39,29.52) v6(3.39,28.52) v6(3.42,19.41) v6(3.53,27.62) v6(3.46,16.55) v6(3.6,61.95) v6(3.6,61.35) v6(3.6,60.81) v6(3.6,60.28) v6(3.6,59.75) v6(3.6,59.22) v6(3.6,58.69) v6(3.6,58.16) v6(3.58,57.55) v6(3.59,48.88) v6(3.58,39.08) v6(3.61,36.59) v6(3.6,35.51) v6(3.6,34.64) v6(3.6,33.59) v6(3.58,32.52) v6(3.55,14.78) v6(3.77,64.09) v6(3.78,48.07) v6(3.8,15.35) v6(3.9,66.93) v6(3.92,52.55) v6(3.93,43.6) v6(3.89,42.11) v6(3.9,40.68) v6(3.91,38.37) v6(3.91,34.26) v6(3.93,32.01) v6(3.95,68.06) v6(4.01,55.62) v6(4.04,15.88) v6(4.04,13.58) v6(4.04,12.68) v6(4.04,11.78) v6(4.04,10.92) v6(4.05,50.76) v6(4.05,14.78) v6(4.17,15.35) v6(4.24,45.47) v6(4.3,29.76) v6(4.25,18.94) v6(4.41,38.35) v6(4.42,34.28) v6(4.43,32.03) v6(4.41,18.2) v6(4.39,16.31) v6(4.53,63.44) v6(4.5,47.62) v6(4.54,46.85) v6(4.49,44.62) v6(4.44,42.11) v6(4.44,40.67) v6(4.53,27.57) v6(4.49,15.64) v6(4.56,62.82) v6(4.57,61.34) v6(4.6,60.06) v6(4.58,58.42) v6(4.6,55.93) v6(4.56,52.34) v6(4.6,49.51) v6(4.69,30.05) v6(4.81,39) v6(4.79,35.51) v6(4.81,17.79) v6(5.04,67.5) v6(4.98,66.17) v6(5.02,65.14) v6(4.96,45.33) v6(5.06,68.22) v6(5.12,58.42) v6(5.11,55.94) v6(5.13,54.03) v6(5.12,52.3) v6(5.1,48.77) v6(5.13,47.09) v6(5.15,62.51) v6(5.14,61.17) v6(5.15,50.56) v6(5.18,49.76) v6(5.31,64.4) v6(5.25,18.94) v6(5.35,28.6) v6(5.53,63.71) v6(5.53,60.16) v6(5.53,27.57) v6(5.46,15.62) v6(5.61,61.55) v6(5.58,40.22) v6(5.58,38.22) v6(5.55,36.14) v6(5.69,49.01) v6(5.68,47.77) v6(5.68,46.17) v6(5.67,17.22) v6(5.81,63.18) v6(5.75,34.43) v6(5.75,32.54) v6(5.79,29.92) v6(5.87,28.85) v6(5.92,15.62) v6(5.95,54.5) v6(5.96,51.35) v6(6.09,68) v6(6.13,63.01) v6(6.29,68.24) v6(6.32,63.67) v6(6.31,55.78) v6(6.25,18.94) v6(6.37,42.53) v6(6.43,41.17) v6(6.51,27.49) v6(6.61,67.65) v6(6.6,67.04) v6(6.59,65.82) v6(6.56,18.43) v6(6.68,66.61) v6(6.71,57.69) v6(6.73,52.82) v6(6.83,63.78) v6(6.83,63.57) v6(6.81,58.81) v6(6.92,61.16) v6(6.95,64.83) v6(7.01,27) v6(7.03,25.44) v6(7.03,23.44) v6(7.03,20.24) v6(7.01,19.62) v6(7,17.9) v6(6.99,15.64) v6(7.2,68.72) v6(7.17,63.01) v6(7.16,49.05) v6(7.18,45.5) v6(7.25,64.84) v6(7.26,47.3) v6(7.43,42.17) v6(7.41,18.13) v6(7.42,15.22) v6(7.47,64.34) v6(7.51,27.13) v6(7.51,24.94) v6(7.53,21.7) v6(7.59,68.71) v6(7.68,60.84) v6(7.84,64.34) v6(7.74,51.49) v6(7.76,48.96) v6(7.75,44.64) v6(7.78,14.87) v6(7.9,18.41) v6(8.01,69.32) v6(7.96,27.74) v6(8.19,64.48) v6(8.19,64.29) v6(8.23,54.71) v6(8.27,25.41) v6(8.25,20.49) v6(8.29,16.63) v6(8.24,15.6) v6(8.24,14.41) v6(8.38,64.48) v6(8.38,64.29) v6(8.53,51.13) v6(8.48,49.16) v6(8.49,48.15) v6(8.49,47.17) v6(8.49,46.17) v6(8.49,45.17) v6(8.48,44.17) v6(8.52,43.09) v6(8.55,68.72) v6(8.57,65.78) v6(8.63,59.7) v6(8.67,67.65) v6(8.66,65.23) v6(8.7,16.84) v6(8.68,15.16) v6(8.71,9.9) v6(8.73,9.1) v6(8.73,8.8) v6(8.82,64.73) v6(8.74,13.84) v6(8.74,9.58) v6(8.93,43.67) v6(8.99,69.33) v6(8.97,67.63) v6(8.97,67.4) v6(8.98,67.16) v6(9.01,65.79) v6(9.01,65.53) v6(9,65.18) v6(9.12,49.13) v6(9.13,17.17) v6(9.07,14.82) v6(9.2,67.5) v6(9.14,56.28) v6(9.34,65.8) v6(9.34,65.53) v6(9.27,62.74) v6(9.34,55.51) v6(9.32,51.85) v6(9.27,43.87) v6(9.27,24.33) v6(9.43,67.63) v6(9.37,65.17) v6(9.43,49.17) v6(9.43,48.17) v6(9.43,47.17) v6(9.43,46.17) v6(9.43,45.17) v6(9.43,44.17) v6(9.39,18.34) v6(9.35,15.59) v6(9.39,11.36) v6(9.39,11.11) v6(9.44,21.19) v6(9.63,57.87) v6(9.6,53.41) v6(9.64,15.92) v6(9.59,9.06) v6(9.59,8.81) v6(9.71,65.79) v6(9.72,65.44) v6(9.73,52.49) v6(9.69,50.72) v6(9.69,11.36) v6(9.69,11.11) v6(9.79,69.14) v6(9.81,15.29) v6(9.79,14.46) v6(9.8,13.84) v6(9.84,68.18) v6(9.9,51.13) v6(9.93,49.67) v6(9.93,48.67) v6(9.9,32.86) v6(9.9,31.34) v6(9.85,16.49) v6(9.94,66.38) v6(9.96,23.69) v6(10.02,22.96) v6(10.12,53.77) v6(10.1,20.22) v6(10.06,14.93) v6(10.07,11.11) v6(10.22,33.84) v6(10.17,32.86) v6(10.17,32.44) v6(10.17,31.86) v6(10.17,31.6) v6(10.17,31.34) v6(10.18,30.6) v6(10.19,29.54) v6(10.27,34.54) v6(10.38,60.81) v6(10.43,49.17) v6(10.42,19.14) v6(10.51,66.71) v6(10.46,30.77) v6(10.46,29.54) v6(10.5,28.65) v6(10.53,15.96) v6(10.49,9.97) v6(10.6,62.75) v6(10.61,30.27) v6(10.58,23.14) v6(10.58,15.27) v6(10.71,66.71) v6(10.67,30.01) v6(10.72,14.58) v6(10.71,13.7) v6(10.84,53.58) v6(10.76,50.87) v6(10.8,28.75) v6(10.81,11.11) v6(10.78,9.98) v6(10.78,9.06) v6(10.85,67.3) v6(10.91,28.27) v6(11,56.38) v6(11.04,16.7) v6(10.95,13.13) v6(10.97,10.49) v6(11.04,9.52) v6(11.08,17.72) v6(11.05,14.22) v6(11.12,13.46) v6(11.11,13.04) v6(11.17,61.63) v6(11.15,31.76) v6(11.21,31.59) v6(11.15,29.43) v6(11.17,28.72) v6(11.25,67.66) v6(11.25,67.47) v6(11.24,66.88) v6(11.24,66.69) v6(11.24,65.94) v6(11.24,65.76) v6(11.27,38.54) v6(11.27,37.54) v6(11.27,36.54) v6(11.27,35.54) v6(11.27,34.04) v6(11.31,32.85) v6(11.25,27.96) v6(11.28,11.11) v6(11.3,9.96) v6(11.3,9.34) v6(11.43,67.66) v6(11.43,67.47) v6(11.42,66.88) v6(11.42,66.69) v6(11.42,65.94) v6(11.42,65.76) v6(11.35,34.34) v6(11.35,32.67) v6(11.35,32.48) v6(11.41,14.98) v6(11.53,69.33) v6(11.48,53.68) v6(11.44,52.09) v6(11.51,18.11) v6(11.61,67.66) v6(11.61,67.47) v6(11.6,66.88) v6(11.6,66.69) v6(11.6,65.94) v6(11.6,65.76) v6(11.61,51.07) v6(11.59,11.51) v6(11.59,9.97) v6(11.7,29.91) v6(11.68,18.66) v6(11.79,67.66) v6(11.79,67.47) v6(11.78,66.88) v6(11.78,66.69) v6(11.78,65.94) v6(11.78,65.76) v6(11.74,31.92) v6(11.76,14.59) v6(11.87,32.79) v6(11.99,31.38) v6(11.96,13.67) v6(12.11,11.59) v6(12.17,63.48) v6(12.17,39.61) v6(12.2,27.89) v6(12.15,15.51) v6(12.27,38.54) v6(12.27,37.54) v6(12.27,36.54) v6(12.24,32.89) v6(12.31,31) v6(12.33,14.06) v6(12.43,69.13) v6(12.39,56.94) v6(12.34,14.79) v6(12.42,12.14) v6(12.42,11.08) v6(12.46,51.67) v6(12.53,21.84) v6(12.53,20.7) v6(12.6,55.6) v6(12.59,35.66) v6(12.68,29.7) v6(12.66,29.16) v6(12.7,13.68) v6(12.71,10.99) v6(13.02,56.48) v6(13.02,11.4) v6(13.12,59.96) v6(13.12,58.96) v6(13.09,53.19) v6(13.09,13.25) v6(13.11,12.8) v6(13.23,20.92) v6(13.16,14.59) v6(13.19,12.55) v6(13.15,12.25) v6(13.16,10.48) v6(13.16,9.66) v6(13.16,8.99) v6(13.17,8.38) v6(13.16,7.75) v6(13.34,64.66) v6(13.34,61.53) v6(13.32,56.16) v6(13.29,52.46) v6(13.27,40.54) v6(13.27,39.54) v6(13.25,34.69) v6(13.39,36.25) v6(13.4,35.46) v6(13.4,34.86) v6(13.37,33.56) v6(13.54,37.28) v6(13.54,21.98) v6(13.62,59.46) v6(13.55,36.72) v6(13.56,31.45) v6(13.58,23.03) v6(13.7,27.89) v6(13.71,12.07) v6(13.81,67.94) v6(13.76,39.73) v6(13.79,9.21) v6(13.88,13.26) v6(13.92,12.8) v6(14.12,59.96) v6(14.12,58.96) v6(14.1,57.11) v6(14.1,51.28) v6(14.1,41.05) v6(14.12,32.9) v6(14.13,31) v6(14.1,8.42) v6(14.06,7.72) v6(14.31,38.6) v6(14.36,53.32) v6(14.36,52.47) v6(14.42,12.4) v6(14.5,39.53) v6(14.48,21.73) v6(14.53,11.67) v6(14.62,59.46) v6(14.62,17.71) v6(14.71,55.99) v6(14.65,38.6) v6(14.66,36.58) v6(14.69,29.88) v6(14.65,13.25) v6(14.71,12.81) v6(14.84,35.43) v6(14.74,29.23) v6(14.92,18.1) v6(14.85,14.07) v6(14.91,8.69) v6(15.02,69.13) v6(14.97,34.89) v6(14.99,23.03) v6(14.99,18.67) v6(14.96,16.55) v6(15.12,59.96) v6(15.12,58.96) v6(15.05,57.88) v6(15.11,54.62) v6(15.08,41.06) v6(15.05,37.66) v6(15.13,30.04) v6(15.06,22.28) v6(15.06,7.72) v6(15.16,67.94) v6(15.2,27.89) v6(15.31,32.22) v6(15.26,14.8) v6(15.38,39.55) v6(15.37,17.15) v6(15.62,65.87) v6(15.62,65.69) v6(15.62,65.51) v6(15.62,65.33) v6(15.62,65.15) v6(15.62,64.97) v6(15.62,64.64) v6(15.62,63.94) v6(15.62,63.39) v6(15.62,59.46) v6(15.64,58.46) v6(15.61,32.7) v6(15.59,15.94) v6(15.58,15.35) v6(15.57,13.25) v6(15.62,11.99) v6(15.72,31.84) v6(15.68,30.6) v6(15.73,29.67) v6(15.7,27.09) v6(15.76,53.22) v6(15.79,22.58) v6(15.82,16.65) v6(15.77,12.8) v6(15.9,65.96) v6(15.85,21.74) v6(15.89,13.78) v6(15.98,57.26) v6(15.94,17.46) v6(16.12,59.96) v6(16.12,58.96) v6(16.06,54.57) v6(16.12,41.06) v6(16.06,7.72) v6(16.15,67.92) v6(16.16,32.72) v6(16.2,26.89) v6(16.18,18.21) v6(16.28,14.54) v6(16.28,13.25) v6(16.24,8.38) v6(16.36,66.92) v6(16.39,11.53) v6(16.4,11.21) v6(16.39,10.7) v6(16.54,66.92) v6(16.51,52.12) v6(16.45,51.22) v6(16.48,17.73) v6(16.53,16.58) v6(16.48,12.81) v6(16.55,64.21) v6(16.62,59.46) v6(16.62,58.46) v6(16.57,15.95) v6(16.71,55.74) v6(16.77,56.11) v6(16.8,31.47) v6(16.8,30.99) v6(16.78,8.8) v6(16.92,55.16) v6(16.86,13.25) v6(16.96,69.31) v6(17.02,64.22) v6(17.04,12.78) v6(17.12,59.96) v6(17.12,58.96) v6(17.11,41.06) v6(17.06,20.98) v6(17.13,13.74) v6(17.06,7.72) v6(17.22,56.31) v6(17.14,53.54) v6(17.2,25.89) v6(17.18,14.21) v6(17.18,8.45) v6(17.26,16.12) v6(17.29,9.45) v6(17.42,54.66) v6(17.39,29.68) v6(17.39,29.23) v6(17.49,44.94) v6(17.44,13.26) v6(17.5,12.75) v6(17.62,64.24) v6(17.62,59.46) v6(17.62,52.22) v6(17.56,45.92) v6(17.55,10.58) v6(17.65,58.25) v6(17.79,19.68) v6(17.93,55.27) v6(17.85,19.06) v6(17.9,17.01) v6(18.01,67.92) v6(17.99,66.07) v6(17.96,53.99) v6(18.02,13.26) v6(18.12,59.96) v6(18.06,58.94) v6(18.06,46.42) v6(18.12,44.33) v6(18.11,41.06) v6(18.12,20.7) v6(18.1,12.83) v6(18.06,7.72) v6(18.17,54.66) v6(18.2,52.99) v6(18.2,24.89) v6(18.33,16.12) v6(18.32,14.21) v6(18.24,8.38) v6(18.52,27.8) v6(18.49,12.07) v6(18.62,60.46) v6(18.56,46.92) v6(18.58,24.24) v6(18.63,13.26) v6(18.67,69.12) v6(18.67,66.69) v6(18.67,55.16) v6(18.67,54.41) v6(18.67,39.25) v6(18.69,38.46) v6(18.71,12.79) v6(18.83,19.84) v6(18.87,67.06) v6(18.88,22.28) v6(18.96,59.84) v6(18.95,28.17) v6(19.01,20.68) v6(19.09,64.31) v6(19.12,60.96) v6(19.07,51.28) v6(19.06,47.42) v6(19.11,41.06) v6(19.08,39.26) v6(19.06,7.72) v6(19.24,44.33) v6(19.14,37.93) v6(19.14,37.15) v6(19.23,13.25) v6(19.31,46.42) v6(19.28,31.46) v6(19.3,30.99) v6(19.31,29.69) v6(19.32,29.09) v6(19.29,19.68) v6(19.27,10.59) v6(19.42,55.85) v6(19.42,55.16) v6(19.43,37.62) v6(19.37,21.81) v6(19.41,12.81) v6(19.48,34.82) v6(19.6,68.72) v6(19.62,61.46) v6(19.54,57.53) v6(19.61,54.42) v6(19.56,47.92) v6(19.58,19.08) v6(19.62,14.21) v6(19.64,9.98) v6(19.65,59.57) v6(19.74,58.79) v6(19.73,37.65) v6(19.71,25.01) v6(19.71,23.79) v6(19.65,16.12) v6(19.84,66.91) v6(19.83,66.03) v6(19.84,64.23) v6(19.81,60.7) v6(19.81,46.92) v6(19.77,35.43) v6(19.84,10.48) v6(19.85,65.27) v6(19.9,62.54) v6(19.92,53.82) v6(19.93,24.59) v6(20.02,36.24) v6(20.03,13.28) v6(19.99,12.82) v6(19.99,11.83) v6(20.12,61.96) v6(20.09,41.06) v6(20.08,35.86) v6(20.13,18.25) v6(20.06,7.72) v6(20.2,68.15) v6(20.14,61.37) v6(20.24,44.33) v6(20.15,18.9) v6(20.24,8.38) v6(20.31,47.42) v6(20.34,35.52) v6(20.31,32.07) v6(20.27,16.73) v6(20.41,50.67) v6(20.51,32.76) v6(20.5,17.46) v6(20.56,46.42) v6(20.6,12.8) v6(20.66,63.86) v6(20.74,59.51) v6(20.67,13.29) v6(20.82,62.8) v6(20.84,61.75) v6(20.76,57.69) v6(20.76,50.27) v6(20.81,47.92) v6(20.83,35.45) v6(20.78,23.8) v6(20.84,20.7) v6(20.76,13.7) v6(20.94,60.75) v6(21,17.06) v6(21.07,64.58) v6(21.06,46.92) v6(21.1,41.05) v6(21.11,12.81) v6(21.1,10.47) v6(21.06,7.72) v6(21.15,68.69) v6(21.18,54.36) v6(21.14,53.97) v6(21.21,53.23) v6(21.16,50.67) v6(21.24,44.33) v6(21.24,38.42) v6(21.19,16.1) v6(21.17,14.21) v6(21.33,33.88) v6(21.36,50.02) v6(21.42,24.57) v6(21.37,13.28) v6(21.48,52.56) v6(21.46,21.29) v6(21.48,11.81) v6(21.54,30.75) v6(21.54,29.71) v6(21.54,29.12) v6(21.62,17.07) v6(21.64,16.57) v6(21.65,62.75) v6(21.72,59.95) v6(21.73,55.9) v6(21.74,27.55) v6(21.65,12.79) v6(21.75,50.49) v6(21.91,66.89) v6(21.92,56.65) v6(21.86,52.17) v6(21.88,25.12) v6(21.92,19.03) v6(21.93,12.28) v6(22.03,60.82) v6(21.95,58.86) v6(21.98,21.84) v6(21.98,13.28) v6(22.01,12.77) v6(22.09,44.33) v6(22.1,41.05) v6(22.06,7.72) v6(22.15,54.15) v6(22.16,49.67) v6(22.17,39.52) v6(22.21,35.51) v6(22.24,28.12) v6(22.24,17.06) v6(22.24,8.38) v6(22.28,60.13) v6(22.25,53.16) v6(22.27,44.33) v6(22.28,23.8) v6(22.35,63.37) v6(22.41,31.48) v6(22.41,19.19) v6(22.43,17.6) v6(22.52,56.65) v6(22.45,48.94) v6(22.46,34.37) v6(22.52,21.84) v6(22.45,16.1) v6(22.5,14.21) v6(22.56,47.92) v6(22.56,46.92) v6(22.63,38.85) v6(22.7,55.89) v6(22.69,18.57) v6(22.72,13.27) v6(22.71,12.8) v6(22.7,12.07) v6(22.75,10.75) v6(22.79,10.06) v6(22.85,68.69) v6(22.91,54.49) v6(22.93,18.56) v6(22.91,17.04) v6(22.94,61.72) v6(22.97,58.6) v6(23,52.66) v6(23.03,29.65) v6(23.04,59.91) v6(23.08,59.29) v6(23.06,48.42) v6(23.06,47.42) v6(23.08,10.53) v6(23.07,9.62) v6(23.08,8.5) v6(23.06,7.72) v6(23.18,61.06) v6(23.22,39.25) v6(23.17,23.86) v6(23.15,11.37) v6(23.14,11.01) v6(23.19,9.36) v6(23.29,66.9) v6(23.32,66.03) v6(23.34,65.14) v6(23.32,54.73) v6(23.25,53.41) v6(23.3,18.7) v6(23.33,12.82) v6(23.32,9.61) v6(23.31,8.5) v6(23.43,62.52) v6(23.41,50.87) v6(23.42,44.33) v6(23.42,29.08) v6(23.37,24.55) v6(23.37,13.27) v6(23.43,11.82) v6(23.46,60.31) v6(23.52,56.65) v6(23.53,54.24) v6(23.44,21.84) v6(23.45,10.18) v6(23.62,68.15) v6(23.6,60.53) v6(23.61,49.63) v6(23.56,47.92) v6(23.56,46.92) v6(23.64,17.04) v6(23.69,61.55) v6(23.73,55.9) v6(23.69,36.53) v6(23.66,16.57) v6(23.65,16.1) v6(23.69,14.21) v6(23.74,7.68) v6(23.76,28.59) v6(23.92,60.66) v6(23.85,53.08) v6(23.9,23.84) v6(23.86,11.37) v6(23.85,11.02) v6(23.84,10.66) v6(24,53.8) v6(24.03,13.28) v6(23.98,12.82) v6(24,11.66) v6(24.06,48.42) v6(24.06,47.42) v6(24.12,10.17) v6(24.15,60.07) v6(24.22,59.3) v6(24.16,58.61) v6(24.24,44.33) v6(24.21,31.75) v6(24.2,22.64) v6(24.31,64.24) v6(24.32,54.73) v6(24.31,9.62) v6(24.31,8.5) v6(24.41,50.87) v6(24.42,7.87) v6(24.52,56.65) v6(24.5,52.66) v6(24.44,9.36) v6(24.63,68.7) v6(24.61,61.51) v6(24.55,59.97) v6(24.61,49.63) v6(24.56,47.92) v6(24.56,46.92) v6(24.63,23.84) v6(24.6,13.27) v6(24.57,12.81) v6(24.55,11.7) v6(24.56,10.74) v6(24.57,9.61) v6(24.56,8.5) v6(24.73,55.9) v6(24.69,51.97) v6(24.72,31.06) v6(24.71,29.2) v6(24.72,28.02) v6(24.79,61.06) v6(24.81,60) v6(24.82,38.68) v6(24.92,62.61) v6(24.91,62.06) v6(24.92,61.52) v6(24.93,60.67) v6(24.85,35.62) v6(24.87,22.1) v6(24.85,17.04) v6(24.85,16.57) v6(24.89,16.1) v6(25.03,14.21) v6(25.06,48.42) v6(25.06,47.42) v6(25.1,41.05) v6(25.13,19.21) v6(25.18,64.97) v6(25.22,53.3) v6(25.24,44.33) v6(25.22,24.59) v6(25.22,18.7) v6(25.23,13.28) v6(25.2,12.79) v6(25.32,54.73) v6(25.34,53.81) v6(25.25,52.66) v6(25.26,28.08) v6(25.3,23.92) v6(25.27,13.64) v6(25.38,59.33) v6(25.41,50.87) v6(25.41,32.16) v6(25.37,11.14) v6(25.48,61.51) v6(25.51,60.67) v6(25.49,59.92) v6(25.53,41.05) v6(25.46,33.72) v6(25.64,58.61) v6(25.6,54.2) v6(25.61,49.63) v6(25.56,47.92) v6(25.57,46.91) v6(25.55,27.55) v6(25.54,22.68) v6(25.55,21.85) v6(25.74,61.5) v6(25.73,55.9) v6(25.69,51.97) v6(25.74,30.62) v6(25.69,26.74) v6(25.71,12.82) v6(25.74,7.68) v6(25.78,66.88) v6(25.76,62.06) v6(25.8,61.07) v6(25.81,60) v6(25.76,32.6) v6(25.84,25.4) v6(25.82,24.43) v6(25.82,13.27) v6(25.77,12.45) v6(25.9,63.2) v6(25.88,58.56) v6(25.93,35.48) v6(25.9,34.78) v6(25.93,23.98) v6(25.85,23.39) v6(25.91,17.04) v6(25.91,16.57) v6(25.94,22.49) v6(26.02,16.1) v6(26,10.82) v6(26.07,63.98) v6(26.08,62.07) v6(26.09,54.33) v6(26.06,48.42) v6(26.06,47.42) v6(26.1,41.05) v6(26.07,38.57) v6(26.2,52.92) v6(26.24,44.33) v6(26.16,29.66) v6(26.23,13.29) v6(26.2,12.8) v6(26.28,68.15) v6(26.31,62.61) v6(26.28,31.06) v6(26.29,27.47) v6(26.34,26.38) v6(26.27,14.21) v6(26.27,13.64) v6(26.33,11.61) v6(26.41,50.87) v6(26.39,39.24) v6(26.44,35.27) v6(26.41,25.21) v6(26.42,10.4) v6(26.47,68.7) v6(26.51,58.57) v6(26.51,54.95) v6(26.48,27.84) v6(26.52,13.65) v6(26.58,62.12) v6(26.56,59.36) v6(26.64,53.23) v6(26.59,51.97) v6(26.61,49.63) v6(26.56,47.92) v6(26.56,46.92) v6(26.58,36.16) v6(26.57,23.4) v6(26.65,63.35) v6(26.68,59.98) v6(26.66,56.67) v6(26.65,35.8) v6(26.69,34.09) v6(26.7,33.36) v6(26.68,30.07) v6(26.69,24.07) v6(26.69,21.91) v6(26.74,11.09) v6(26.74,9.46) v6(26.81,62.63) v6(26.79,31.02) v6(26.9,63.3) v6(26.93,31.5) v6(26.88,12.31) v6(26.97,27.81) v6(27.08,55.82) v6(27.06,48.42) v6(27.06,47.42) v6(27.1,41.05) v6(27.06,21.96) v6(27.05,17.04) v6(27.04,16.57) v6(27.05,16.1) v6(27.24,44.33) v6(27.14,34.54) v6(27.18,33.59) v6(27.16,12.69) v6(27.17,9.66) v6(27.17,8.95) v6(27.14,7.42) v6(27.31,63.36) v6(27.25,60.49) v6(27.27,54.88) v6(27.25,38.73) v6(27.29,36.82) v6(27.27,29.09) v6(27.28,23.92) v6(27.29,23.38) v6(27.34,51.97) v6(27.41,50.87) v6(27.43,29.69) v6(27.43,24.82) v6(27.38,18.7) v6(27.51,39.24) v6(27.51,11.49) v6(27.62,63.36) v6(27.61,49.63) v6(27.56,47.92) v6(27.56,46.92) v6(27.56,24.15) v6(27.54,21.88) v6(27.64,8.47) v6(27.69,31.95) v6(27.69,31.52) v6(27.65,26.41) v6(27.7,25.91) v6(27.73,23.93) v6(27.7,13.25) v6(27.8,53.91) v6(27.81,53.11) v6(27.79,23.38) v6(27.8,14.21) v6(27.83,6.73) v6(27.92,61.72) v6(27.85,30.43) v6(27.88,28.25) v6(27.87,27.78) v6(27.91,13.46) v6(27.9,12.46) v6(27.84,8.98) v6(27.95,31.04) v6(28.06,54.34) v6(28.06,48.42) v6(28.06,47.42) v6(28.06,46.42) v6(28.1,41.05) v6(28.04,21.88) v6(28.1,13.72) v6(28.12,13.13) v6(28.16,66.91) v6(28.16,66.02) v6(28.15,65.33) v6(28.23,56.65) v6(28.24,44.33) v6(28.21,35.06) v6(28.24,23.43) v6(28.24,17.04) v6(28.23,16.57) v6(28.17,11.38) v6(28.32,68.7) v6(28.29,63.36) v6(28.28,23.92) v6(28.29,21.88) v6(28.37,57.39) v6(28.36,55.92) v6(28.42,38.72) v6(28.42,37.84) v6(28.44,36.98) v6(28.44,29.13) v6(28.44,28.25) v6(28.44,27.79) v6(28.35,16.09) v6(28.38,7.96) v6(28.46,27.04) v6(28.51,13.5) v6(28.5,8.85) v6(28.54,57.55) v6(28.56,39.25) v6(28.61,24.56) v6(28.54,22.13) v6(28.6,6.01) v6(28.71,63.37) v6(28.73,57.9) v6(28.72,57.39) v6(28.67,53.11) v6(28.68,25.19) v6(28.69,23.38) v6(28.67,13.33) v6(28.75,54.81) v6(28.82,37.49) v6(28.77,24.19) v6(28.79,22.38) v6(28.83,12.04) v6(28.78,10.8) v6(28.91,57.55) v6(28.84,23.78) v6(28.91,12.28) v6(28.85,10.3) v6(28.85,10.12) v6(29.02,68.16) v6(29,54.14) v6(29,31.5) v6(28.95,30.82) v6(28.95,29.96) v6(29.03,24.6) v6(29.03,10.3) v6(29.03,10.12) v6(28.95,4.78) v6(28.97,3.76) v6(28.97,2.65) v6(28.97,1.41) v6(29.1,63.36) v6(29.09,52.05) v6(29.07,49.18) v6(29.12,48.06) v6(29.06,47.42) v6(29.06,46.42) v6(29.1,41.05) v6(29.08,28.65) v6(29.04,22.63) v6(29.23,58.4) v6(29.23,56.65) v6(29.24,44.33) v6(29.2,39.3) v6(29.16,24.03) v6(29.17,14.21) v6(29.14,12.74) v6(29.16,8.84) v6(29.25,57.55) v6(29.29,25.59) v6(29.28,19.45) v6(29.32,17.04) v6(29.29,16.57) v6(29.3,11.42) v6(29.42,63.36) v6(29.37,29.14) v6(29.41,27.78) v6(29.47,13.72) v6(29.6,64.17) v6(29.57,57.55) v6(29.64,51.99) v6(29.56,46.92) v6(29.64,40.38) v6(29.6,24.59) v6(29.62,24.21) v6(29.63,23.34) v6(29.56,10.07) v6(29.69,66.89) v6(29.65,53.1) v6(29.67,13.37) v6(29.72,12.15) v6(29.74,3.78) v6(29.75,64.83) v6(29.77,31.07) v6(29.8,16.1) v6(29.81,10.43) v6(29.76,9.91) v6(29.81,8.85) v6(29.75,0.32) v6(29.88,64.11) v6(29.86,57.31) v6(29.85,55.95) v6(29.88,48.03) v6(29.94,12.23) v6(29.94,12.01) v6(29.94,9.59) v6(29.94,9.2) v6(29.98,63.36) v6(29.98,56.65) v6(29.99,40.88) v6(30.03,30.4) v6(30.03,29.51) v6(29.98,27.04) v6(30.01,10.11) v6(30.06,47.42) v6(30.06,46.42) v6(30.07,29.09) v6(30.04,28.64) v6(30.06,28.25) v6(30.09,26.17) v6(30.09,24.59) v6(30.09,23.5) v6(30.06,20.21) v6(30.09,11.11) v6(30.1,10.6) v6(30.17,68.7) v6(30.23,58.4) v6(30.23,37.06) v6(30.24,19.23) v6(30.35,44.17) v6(30.41,32.45) v6(30.39,13.18) v6(30.38,12.46) v6(30.43,9.9) v6(30.41,9.33) v6(30.42,8.79) v6(30.41,8.48) v6(30.42,8.12) v6(30.51,55.27) v6(30.48,51.75) v6(30.53,35.85) v6(30.53,31.48) v6(30.59,47.48) v6(30.58,44.04) v6(30.55,40.33) v6(30.56,39.51) v6(30.56,37.94) v6(30.55,36.91) v6(30.55,36.52) v6(30.59,29.1) v6(30.55,27.78) v6(30.55,26.59) v6(30.55,25.33) v6(30.56,24.9) v6(30.55,24.16) v6(30.62,23.5) v6(30.62,17.13) v6(30.6,0.86) v6(30.65,20.87) v6(30.71,20.29) v6(30.66,16.57) v6(30.72,13.72) v6(30.65,11.47) v6(30.69,10.98) v6(30.8,53.18) v6(30.82,46.87) v6(30.82,46.42) v6(30.82,23.5) v6(30.83,12.41) v6(30.87,31.93) v6(30.94,20.79) v6(30.84,11.11) v6(31,61.85) v6(31.04,39.05) v6(30.95,30.82) v6(30.95,29.96) v6(31,10.98) v6(31.06,39.71) v6(31.1,33.27) v6(31.1,28.24) v6(31.09,27.76) v6(31.08,27.03) v6(31.09,24.78) v6(31.11,16.1) v6(31.13,14.22) v6(31.1,2.96) v6(31.11,2.22) v6(31.18,61.47) v6(31.22,55.93) v6(31.23,51.54) v6(31.14,43.48) v6(31.23,12.46) v6(31.2,6.9) v6(31.2,6.68) v6(31.26,66.9) v6(31.3,64.83) v6(31.24,48.06) v6(31.28,34.15) v6(31.33,29.08) v6(31.29,23.51) v6(31.28,13.72) v6(31.31,12.93) v6(31.27,11.24) v6(31.27,10.84) v6(31.39,53.15) v6(31.35,51.95) v6(31.37,17.46) v6(31.44,12.17) v6(31.51,68.69) v6(31.54,19.7) v6(31.48,16.95) v6(31.5,1.16) v6(31.57,36.94) v6(31.6,32.75) v6(31.59,23.58) v6(31.57,11.12) v6(31.64,6.95) v6(31.68,64.17) v6(31.78,55.31) v6(31.78,43.34) v6(31.79,35.68) v6(31.81,29.09) v6(31.81,23.52) v6(31.75,11.12) v6(31.79,2.21) v6(31.79,1.45) v6(31.94,62.97) v6(31.89,55.68) v6(31.88,35.22) v6(31.9,26.16) v6(31.85,13.69) v6(32.03,30.4) v6(32.03,29.51) v6(31.96,27.94) v6(31.97,27.04) v6(31.98,25.33) v6(31.99,24.86) v6(31.96,10.84) v6(31.94,4.33) v6(32.05,12.5) v6(32.11,11.25) v6(32.1,5.03) v6(32.05,3.05) v6(32.09,1.14) v6(32.17,66.43) v6(32.22,52.77) v6(32.16,31.03) v6(32.3,68.15) v6(32.27,62.95) v6(32.29,58.03) v6(32.32,45.71) v6(32.32,45.34) v6(32.29,34.6) v6(32.25,31.48) v6(32.25,28.67) v6(32.31,12.08) v6(32.32,6.89) v6(32.34,64.03) v6(32.39,52.23) v6(32.41,36.17) v6(32.39,19.23) v6(32.41,10.64) v6(32.39,6.68) v6(32.39,6.46) v6(32.41,5.04) v6(32.4,3.78) v6(32.44,56.98) v6(32.47,51.44) v6(32.54,35.77) v6(32.45,27.6) v6(32.52,27.09) v6(32.45,16.1) v6(32.44,11.06) v6(32.52,7.88) v6(32.51,7.64) v6(32.51,7.42) v6(32.51,7.19) v6(32.51,6.97) v6(32.48,2.06) v6(32.64,63.59) v6(32.55,61.85) v6(32.55,58.14) v6(32.61,45.42) v6(32.6,45.08) v6(32.61,24.89) v6(32.56,11.84) v6(32.64,6.75) v6(32.69,23.95) v6(32.69,23.56) v6(32.65,14.2) v6(32.66,12.93) v6(32.69,10.31) v6(32.8,68.7) v6(32.76,63.18) v6(32.83,56.99) v6(32.79,55.95) v6(32.83,52.7) v6(32.82,52.23) v6(32.78,51.75) v6(32.78,43.34) v6(32.81,10.75) v6(32.78,7.89) v6(32.76,5.61) v6(32.79,1.15) v6(32.91,20.9) v6(32.9,6.75) v6(32.95,66.88) v6(32.97,63.94) v6(33,63.47) v6(33,63.03) v6(33.04,31.95) v6(32.95,30.82) v6(32.95,29.96) v6(33.01,2.06) v6(33.06,25.33) v6(33.13,13.29) v6(33.12,10.47) v6(33.06,9.93) v6(33.05,7.89) v6(33.09,1.45) v6(33.18,58.9) v6(33.22,55.95) v6(33.22,23.55) v6(33.17,6.75) v6(33.17,5.62) v6(33.25,45.16) v6(33.24,29.1) v6(33.34,24.89) v6(33.29,7.89) v6(33.42,63.5) v6(33.41,36.16) v6(33.42,28.23) v6(33.43,25.75) v6(33.39,10.21) v6(33.36,9.55) v6(33.39,1.14) v6(33.48,57.6) v6(33.46,8.14) v6(33.48,7.73) v6(33.48,6.83) v6(33.48,3.37) v6(33.5,2.98) v6(33.6,43.34) v6(33.56,9.89) v6(33.58,9.33) v6(33.67,16.06) v6(33.73,9.09) v6(33.73,2.21) v6(33.82,63.61) v6(33.75,31.52) v6(33.81,29.09) v6(33.84,19.23) v6(33.77,16.6) v6(33.76,13.97) v6(33.8,4.99) v6(33.88,58.25) v6(33.94,27.08) v6(33.87,20.37) v6(33.85,19.77) v6(33.89,12.97) v6(33.88,12.37) v6(33.89,11.84) v6(33.9,11.34) v6(33.92,10.76) v6(33.88,9.49) v6(33.85,4.35) v6(33.99,64.66) v6(33.98,56.9) v6(33.98,31.04) v6(34.03,30.4) v6(34.03,29.51) v6(33.97,24.89) v6(34,23.55) v6(34.01,20.82) v6(33.98,13.38) v6(33.98,8.04) v6(34.1,68.69) v6(34.08,65.64) v6(34.08,63.94) v6(34.04,9.11) v6(34.07,8.67) v6(34.08,8.33) v6(34.12,4.29) v6(34.09,1.14) v6(34.22,66.52) v6(34.14,19.23) v6(34.14,7.72) v6(34.26,58.83) v6(34.34,17.46) v6(34.29,2.88) v6(34.42,63.5) v6(34.35,62.32) v6(34.41,36.15) v6(34.37,34.6) v6(34.43,11.94) v6(34.34,4.02) v6(34.39,2.21) v6(34.39,1.45) v6(34.44,61.05) v6(34.53,56.25) v6(34.46,55.69) v6(34.45,43.34) v6(34.45,35.76) v6(34.5,27.11) v6(34.47,26.16) v6(34.54,23.55) v6(34.54,15.94) v6(34.44,10.73) v6(34.45,7.85) v6(34.64,61.72) v6(34.57,25.33) v6(34.64,24.24) v6(34.55,13.38) v6(34.65,66.91) v6(34.68,66.03) v6(34.74,63.74) v6(34.71,27.61) v6(34.65,24.9) v6(34.65,20.9) v6(34.66,13.77) v6(34.72,8.38) v6(34.69,1.14) v6(34.77,65.64) v6(34.76,62.72) v6(34.77,61.97) v6(34.83,58.25) v6(34.78,43.34) v6(34.82,32.42) v6(34.75,16.44) v6(34.8,4.32) v6(34.84,31.49) v6(34.98,54.23) v6(34.95,30.82) v6(34.95,29.96) v6(34.98,28.62) v6(35.01,25.75) v6(34.96,10.74) v6(34.97,10.3) v6(34.97,9.72) v6(34.96,9.19) v6(34.97,8.46) v6(35.07,29.03) v6(35.05,11.94) v6(35.04,2.21) v6(35.21,62.55) v6(35.23,57.9) v6(35.18,42.94) v6(35.26,66.51) v6(35.32,62.94) v6(35.32,33.28) v6(35.29,29.04) v6(35.31,2.96) v6(35.41,13.32) v6(35.36,8.01) v6(35.38,4.43) v6(35.39,1.16) v6(35.5,68.69) v6(35.45,36.15) v6(35.48,24.91) v6(35.52,23.56) v6(35.47,15.94) v6(35.52,14.57) v6(35.44,6.7) v6(35.44,5.55) v6(35.58,60.31) v6(35.58,27.14) v6(35.55,7.49) v6(35.72,63.71) v6(35.72,62.94) v6(35.66,61.08) v6(35.68,31.93) v6(35.69,1.45) v6(35.81,68.17) v6(35.83,8.01) v6(35.74,3.65) v6(35.81,1.97) v6(35.93,63.71) v6(35.85,61.86) v6(35.92,31.49) v6(35.88,11.61) v6(35.97,62.5) v6(35.98,55.78) v6(36.03,54.17) v6(35.98,36.16) v6(36.03,30.4) v6(36.03,29.51) v6(35.99,26.59) v6(36.04,16.94) v6(35.96,15.94) v6(36.03,13.34) v6(35.96,7.47) v6(36,1.15) v6(36.09,61.86) v6(36.06,35.75) v6(36.05,30.92) v6(36.06,16.45) v6(36.12,11.98) v6(36.05,11.07) v6(36.05,10.36) v6(36.06,9.77) v6(36.05,9.11) v6(36.05,8.5) v6(36.22,62.94) v6(36.2,34.6) v6(36.31,66.52) v6(36.3,24.89) v6(36.28,9.33) v6(36.26,8.43) v6(36.26,8.03) v6(36.3,1.97) v6(36.36,5.35) v6(36.48,64.83) v6(36.49,23.55) v6(36.49,20.91) v6(36.49,20.31) v6(36.49,19.79) v6(36.51,9.98) v6(36.52,8.09) v6(36.5,5.74) v6(36.61,63.71) v6(36.62,42.78) v6(36.57,11.98) v6(36.59,11.24) v6(36.55,7.46) v6(36.68,66.9) v6(36.72,62.94) v6(36.64,9.04) v6(36.69,1.14) v6(36.76,62.51) v6(36.79,36.15) v6(36.83,24.03) v6(36.79,10.42) v6(36.79,7.64) v6(36.82,4.44) v6(36.76,2.9) v6(36.9,68.69) v6(36.88,23.56) v6(36.85,15.94) v6(36.85,14.11) v6(36.95,30.82) v6(36.95,29.96) v6(37.03,6.54) v6(36.98,5.04) v6(37.03,2.21) v6(36.99,1.45) v6(37.05,14.6) v6(37.17,62.94) v6(37.18,31.45) v6(37.21,30.39) v6(37.2,24.91) v6(37.17,12.47) v6(37.14,11.99) v6(37.14,10.42) v6(37.14,9.04) v6(37.14,7.64) v6(37.31,30.79) v6(37.28,7.43) v6(37.3,1.15) v6(37.37,66.53) v6(37.41,28.9) v6(37.38,26.17) v6(37.38,25.75) v6(37.43,15.79) v6(37.51,27.65) v6(37.49,19.23) v6(37.49,10.42) v6(37.49,7.64) v6(37.61,62.94) v6(37.61,36.15) v6(37.64,25.33) v6(37.63,23.57) v6(37.63,11.98) v6(37.58,11.23) v6(37.59,9.03) v6(37.67,5.03) v6(37.68,4.35) v6(37.78,63.71) v6(37.83,26.6) v6(37.76,9.98) v6(37.76,8.08) v6(37.77,5.95) v6(37.92,62.51) v6(37.89,35.75) v6(37.87,31.06) v6(37.86,27.15) v6(37.9,24.89) v6(37.93,11.92) v6(37.93,9.75) v6(37.93,9.26) v6(37.93,8.34) v6(37.97,62.94) v6(38.03,29.51) v6(37.99,15.21) v6(37.94,10.29) v6(37.95,7.4) v6(38.08,64.79) v6(38.06,47.85) v6(38.06,43.86) v6(38.12,31.51) v6(38.06,23.56) v6(38.19,14.64) v6(38.22,14.06) v6(38.22,13.49) v6(38.22,11.07) v6(38.22,10.45) v6(38.23,9.74) v6(38.23,8.95) v6(38.23,8.2) v6(38.17,0.91) v6(38.29,30.63) v6(38.27,21.14) v6(38.27,11.48) v6(38.41,66.53) v6(38.44,34.61) v6(38.52,33.28) v6(38.5,24.9) v6(38.54,68.7) v6(38.58,62.93) v6(38.6,36.15) v6(38.63,29.11) v6(38.58,16.47) v6(38.66,66.9) v6(38.66,66.03) v6(38.69,26.17) v6(38.8,43.85) v6(38.83,23.63) v6(38.82,20.58) v6(38.92,62.94) v6(38.91,62.52) v6(38.94,53.79) v6(38.85,21.24) v6(38.84,15.78) v6(39.02,50.17) v6(38.97,20) v6(38.98,13.37) v6(39.09,32.41) v6(39.04,25.33) v6(39.1,20.86) v6(39.16,66.36) v6(39.19,65.89) v6(39.19,64.81) v6(39.23,31.05) v6(39.18,11.94) v6(39.31,62.53) v6(39.29,29.04) v6(39.31,10.74) v6(39.31,10.15) v6(39.31,9.47) v6(39.31,8.84) v6(39.31,8.13) v6(39.42,68.16) v6(39.39,63.71) v6(39.42,62.94) v6(39.5,43.85) v6(39.53,35.76) v6(39.49,17.43) v6(39.52,16.55) v6(39.54,36.15) v6(39.58,30.64) v6(39.55,0.62) v6(39.69,25.75) v6(39.65,24.9) v6(39.69,20.38) v6(39.73,5.93) v6(39.76,62.53) v6(39.76,47.86) v6(39.92,62.94) v6(39.92,23.58) v6(39.87,13.38) v6(39.86,10.74) v6(39.96,68.7) v6(39.98,66.14) v6(40.03,63.72) v6(40.03,29.51) v6(40.01,26.58) v6(40.02,24.24) v6(39.99,14.43) v6(39.99,11.94) v6(40.12,43.69) v6(40.13,7.95) v6(40.13,6.63) v6(40.13,5.19) v6(40.17,65.2) v6(40.2,62.53) v6(40.2,49.57) v6(40.24,19.83) v6(40.3,43.26) v6(40.33,30.18) v6(40.31,3.77) v6(40.32,1.98) v6(40.32,1.33) v6(40.39,62.92) v6(40.41,36.15) v6(40.37,13.13) v6(40.37,12.51) v6(40.37,11.85) v6(40.35,10.76) v6(40.35,10.11) v6(40.35,9.25) v6(40.47,61.65) v6(40.46,60.81) v6(40.51,31.06) v6(40.53,26.17) v6(40.51,25.33) v6(40.48,24.9) v6(40.46,23.57) v6(40.52,18.75) v6(40.56,63.73) v6(40.54,12.18) v6(40.72,61.85) v6(40.72,61.45) v6(40.67,60.4) v6(40.67,59.95) v6(40.67,59.4) v6(40.69,58.62) v6(40.72,58.3) v6(40.69,56.51) v6(40.69,51.69) v6(40.82,66.9) v6(40.94,27.61) v6(40.98,63.49) v6(40.97,62.35) v6(40.97,61.79) v6(40.98,61.13) v6(40.97,60.15) v6(40.97,59.7) v6(40.97,59.2) v6(40.97,58.8) v6(41.01,45.18) v6(41.03,44.19) v6(40.95,43.66) v6(40.95,14.83) v6(41.05,24.89) v6(41.07,23.6) v6(41.06,16.53) v6(41.07,12.51) v6(41.23,44.81) v6(41.25,66.58) v6(41.3,43.26) v6(41.3,34.6) v6(41.29,29.04) v6(41.26,27.06) v6(41.3,14.18) v6(41.41,36.15) v6(41.42,30.64) v6(41.34,15.48) v6(41.35,12.52) v6(41.46,68.52) v6(41.46,57.87) v6(41.46,28.8) v6(41.64,55.38) v6(41.6,47.58) v6(41.68,58.08) v6(41.74,48.71) v6(41.67,44.22) v6(41.71,25.75) v6(41.73,24.9) v6(41.69,24.29) v6(41.72,23.61) v6(41.78,57.59) v6(41.82,48.95) v6(41.78,16.73) v6(41.79,16.3) v6(41.93,51.51) v6(41.87,50.65) v6(41.97,57.75) v6(41.97,57.45) v6(41.99,55.66) v6(41.95,47.82) v6(41.95,43.66) v6(41.95,31.05) v6(42.03,29.51) v6(42.01,26.17) v6(42.12,63.82) v6(42.12,62.4) v6(42.08,50.53) v6(42.08,49.28) v6(42.09,45.79) v6(42.19,61.9) v6(42.14,59.13) v6(42.22,57.5) v6(42.2,55.02) v6(42.18,42.99) v6(42.15,19.37) v6(42.14,15.78) v6(42.29,46.11) v6(42.27,45.59) v6(42.3,45.36) v6(42.4,64.41) v6(42.43,50.83) v6(42.38,49.03) v6(42.34,44.8) v6(42.36,42.99) v6(42.4,36.15) v6(42.39,35.24) v6(42.34,12.52) v6(42.47,65.34) v6(42.59,25.33) v6(42.64,23.57) v6(42.54,16.28) v6(42.66,68.16) v6(42.71,61.5) v6(42.69,52.64) v6(42.66,46.36) v6(42.74,45.84) v6(42.66,31.48) v6(42.7,30.65) v6(42.69,24.89) v6(42.84,68.52) v6(42.75,52.12) v6(42.75,47.51) v6(42.8,44.45) v6(42.79,33.26) v6(42.75,31.93) v6(42.83,13.96) v6(42.9,66.02) v6(42.92,23.56) v6(43,65.27) v6(42.96,64.03) v6(42.99,55.73) v6(42.95,55.02) v6(42.96,51.37) v6(43.03,45.35) v6(42.95,43.66) v6(43.07,66.9) v6(43.08,50.53) v6(43.1,31.05) v6(43.19,64.84) v6(43.22,59.22) v6(43.21,47.8) v6(43.2,46.16) v6(43.23,44.81) v6(43.17,34.6) v6(43.2,31.88) v6(43.29,62.69) v6(43.27,58) v6(43.33,52.64) v6(43.33,51.28) v6(43.3,43.26) v6(43.3,36.15) v6(43.29,29.04) v6(43.41,27.01) v6(43.39,26.16) v6(43.46,27.6) v6(43.46,25.75) v6(43.48,24.9) v6(43.45,14.27) v6(43.54,23.39) v6(43.64,15.48) v6(43.56,12.52) v6(43.7,55.52) v6(43.66,46.36) v6(43.66,28.39) v6(43.68,16.73) v6(43.69,13.96) v6(43.81,68.18) v6(43.83,64.21) v6(43.83,50.53) v6(43.75,47.51) v6(43.79,31.92) v6(43.85,63.03) v6(43.92,58) v6(43.88,18.71) v6(43.99,59.21) v6(44.03,29.51) v6(43.98,27.58) v6(44,27.03) v6(44,26.59) v6(44.03,26.17) v6(44.04,66.69) v6(44.07,27.26) v6(44.08,24.89) v6(44.08,23.1) v6(44.13,18.86) v6(44.15,55.02) v6(44.14,50.12) v6(44.2,46.16) v6(44.19,42.99) v6(44.24,35.76) v6(44.28,65.3) v6(44.33,12.8) v6(44.37,62.76) v6(44.4,55.46) v6(44.38,31.05) v6(44.39,30.64) v6(44.39,29.03) v6(44.4,26.57) v6(44.49,68.5) v6(44.53,61.66) v6(44.5,53.26) v6(44.48,31.46) v6(44.49,14.83) v6(44.59,63.4) v6(44.61,36.15) v6(44.64,26.36) v6(44.62,13.79) v6(44.61,12.78) v6(44.6,12.52) v6(44.7,55.52) v6(44.66,51.9) v6(44.66,46.36) v6(44.67,31.89) v6(44.68,30.18) v6(44.67,25.33) v6(44.7,24.91) v6(44.69,23.09) v6(44.65,16.29) v6(44.75,26.89) v6(44.82,26.24) v6(44.93,66.01) v6(44.91,61.84) v6(45,12.78) v6(45.05,67.65) v6(45.09,62.2) v6(45.07,59.19) v6(45.13,49.55) v6(45.04,46.16) v6(45.09,25.96) v6(45.1,19.34) v6(45.04,13.77) v6(45.2,55.02) v6(45.19,42.99) v6(45.16,26.64) v6(45.24,13) v6(45.33,53.23) v6(45.26,44.81) v6(45.27,44.22) v6(45.29,29.04) v6(45.4,68.71) v6(45.4,36.15) v6(45.36,13.91) v6(45.44,26.33) v6(45.46,15.51) v6(45.58,25.94) v6(45.57,25.12) v6(45.57,24.54) v6(45.56,23.5) v6(45.64,12.52) v6(45.65,64.01) v6(45.7,58.82) v6(45.7,56.02) v6(45.66,46.36) v6(45.68,16.73) v6(45.81,51.86) v6(45.84,15.73) v6(45.78,13.01) v6(45.88,29.91) v6(45.94,64.95) v6(45.99,63.37) v6(46.1,32.76) v6(46.04,24.37) v6(46.09,13.78) v6(46.11,12.76) v6(46.2,55.02) v6(46.19,42.99) v6(46.14,35.35) v6(46.24,23.09) v6(46.25,66.47) v6(46.34,45.56) v6(46.25,31.46) v6(46.31,30.64) v6(46.41,36.16) v6(46.35,26.26) v6(46.37,24.35) v6(46.51,52.3) v6(46.47,13.01) v6(46.54,58) v6(46.59,50.95) v6(46.6,49.55) v6(46.57,46.32) v6(46.59,46.11) v6(46.58,34.6) v6(46.6,31.05) v6(46.64,15.78) v6(46.65,68.7) v6(46.7,56.02) v6(46.7,55.27) v6(46.7,45.66) v6(46.7,45.35) v6(46.74,61.51) v6(46.77,51.6) v6(46.75,48.01) v6(46.79,13.03) v6(46.87,64.09) v6(46.88,44.26) v6(46.89,12.53) v6(46.98,25.59) v6(47.02,24.53) v6(46.96,23.11) v6(46.94,14.23) v6(47.09,54.53) v6(47.07,31.87) v6(47.12,13.01) v6(47.2,46.16) v6(47.24,45.44) v6(47.23,44.81) v6(47.23,30.64) v6(47.18,12.62) v6(47.33,58.82) v6(47.25,47.51) v6(47.3,33.31) v6(47.37,36.72) v6(47.42,28.16) v6(47.37,14.82) v6(47.52,42.99) v6(47.5,32.53) v6(47.53,13.29) v6(47.54,65.16) v6(47.57,60.4) v6(47.57,58) v6(47.57,46.32) v6(47.55,30.15) v6(47.63,28.77) v6(47.58,26.06) v6(47.71,23.18) v6(47.68,16.73) v6(47.69,12.52) v6(47.83,68.64) v6(47.76,52.3) v6(47.75,48.01) v6(47.75,23.72) v6(47.84,63.08) v6(47.93,50.95) v6(47.89,24.91) v6(47.98,51.62) v6(48,49.56) v6(47.97,31.44) v6(47.99,30.98) v6(47.98,30.43) v6(48.03,29.34) v6(48.03,15.32) v6(48.1,19.35) v6(48.16,61.46) v6(48.22,59.21) v6(48.2,46.16) v6(48.24,23.1) v6(48.25,47.51) v6(48.32,27.28) v6(48.4,64.33) v6(48.4,55.46) v6(48.38,34.38) v6(48.52,68.24) v6(48.47,65.24) v6(48.48,59.53) v6(48.49,29.91) v6(48.63,46.31) v6(48.59,30.41) v6(48.63,12.7) v6(48.68,67.43) v6(48.68,67.06) v6(48.68,66.72) v6(48.68,66.24) v6(48.67,65.88) v6(48.67,65.53) v6(48.72,56.2) v6(48.71,55.08) v6(48.74,53.37) v6(48.74,50.42) v6(48.7,45.66) v6(48.75,48.01) v6(48.83,23.7) v6(48.76,13.76) v6(48.83,12.52) v6(48.9,12.7) v6(48.97,61.97) v6(49.02,44.48) v6(48.96,30.79) v6(48.95,24.23) v6(49.02,14.3) v6(49.05,32.36) v6(49.07,28.77) v6(49.18,67.22) v6(49.18,65.76) v6(49.2,46.16) v6(49.17,39.72) v6(49.27,63.42) v6(49.25,47.51) v6(49.26,38.61) v6(49.26,31.4) v6(49.34,16.29) v6(49.37,68.24) v6(49.4,55.46) v6(49.4,53.46) v6(49.36,29.66) v6(49.43,28.92) v6(49.35,24.27) v6(49.5,66.45) v6(49.51,14.11) v6(49.51,13.26) v6(49.54,67.31) v6(49.59,65.63) v6(49.61,46.28) v6(49.57,14.83) v6(49.65,27.31) v6(49.68,16.73) v6(49.78,67.88) v6(49.75,48.01) v6(49.9,65.22) v6(49.85,31.9) v6(49.85,18.73) v6(50,63.76) v6(49.95,63.31) v6(50.03,62.68) v6(49.96,59.73) v6(49.99,45.47) v6(49.99,32.37) v6(50.13,67.98) v6(50.04,57.97) v6(50.07,57.49) v6(50.12,56.71) v6(50.09,55.08) v6(50.12,49.74) v6(50.12,37.09) v6(50.07,28.96) v6(50.05,27.76) v6(50.13,24.99) v6(50.09,13.96) v6(50.18,60.75) v6(50.21,53.99) v6(50.17,39.72) v6(50.23,28.13) v6(50.25,66.48) v6(50.27,55.8) v6(50.29,52.3) v6(50.24,50.69) v6(50.25,47.51) v6(50.4,55.46) v6(50.4,53.46) v6(50.39,31.41) v6(50.41,12.53) v6(50.46,45.95) v6(50.44,14.23) v6(50.47,13.82) v6(50.56,20.09) v6(50.55,13.05) v6(50.72,36.53) v6(50.66,19.35) v6(50.75,48.01) v6(50.79,34.3) v6(50.9,64.58) v6(50.89,62.41) v6(50.91,28.18) v6(50.94,25.15) v6(51.01,13.78) v6(51.04,61.66) v6(51.13,50.94) v6(51.09,31.79) v6(51.09,16.73) v6(51.17,58.56) v6(51.14,49.66) v6(51.15,35.78) v6(51.14,28.62) v6(51.14,26.21) v6(51.15,16.28) v6(51.24,56.78) v6(51.26,54.01) v6(51.25,47.51) v6(51.25,21.95) v6(51.26,12.52) v6(51.35,64.54) v6(51.38,64.18) v6(51.4,53.46) v6(51.43,12.78) v6(51.5,66.48) v6(51.45,45.98) v6(51.5,25.64) v6(51.44,14.03) v6(51.56,25.13) v6(51.59,15.52) v6(51.7,68.23) v6(51.71,31.14) v6(51.73,23.51) v6(51.73,23.2) v6(51.84,55.62) v6(51.75,48.01) v6(51.81,33.87) v6(51.8,16.89) v6(51.84,16.34) v6(51.83,13.51) v6(51.83,13.05) v6(51.85,64.55) v6(51.84,62.07) v6(51.86,56.79) v6(51.89,52.96) v6(51.87,24.95) v6(51.91,22.76) v6(51.89,14.84) v6(51.99,21.6) v6(52.03,19.61) v6(51.94,17.53) v6(52.06,63.68) v6(52.1,13.79) v6(52.1,12.78) v6(52.23,35.86) v6(52.19,23.38) v6(52.26,47.52) v6(52.26,45.99) v6(52.24,37.92) v6(52.26,31.87) v6(52.3,13.78) v6(52.35,64.56) v6(52.36,64.22) v6(52.4,53.46) v6(52.39,31.34) v6(52.48,59.34) v6(52.52,23.51) v6(52.51,13.77) v6(52.47,12.78) v6(52.51,12.52) v6(52.56,61.65) v6(52.7,53.99) v6(52.69,23.23) v6(52.7,22.92) v6(52.8,66.48) v6(52.81,64.5) v6(52.75,48.01) v6(52.74,39.72) v6(52.76,30.52) v6(52.77,13.69) v6(52.89,32.39) v6(52.85,18.38) v6(52.88,12.97) v6(52.99,33.84) v6(53.04,27.97) v6(52.94,14.23) v6(53.11,18.21) v6(53.11,13.84) v6(53.09,12.63) v6(53.15,62.07) v6(53.23,58.56) v6(53.16,31.76) v6(53.23,30.79) v6(53.14,17.58) v6(53.16,15.92) v6(53.29,53.73) v6(53.38,48.01) v6(53.35,27.66) v6(53.45,64.54) v6(53.44,14.22) v6(53.62,15.22) v6(53.72,61.65) v6(53.71,56.49) v6(53.72,29.65) v6(53.75,46.11) v6(53.84,37.29) v6(53.83,14.2) v6(53.92,46.31) v6(53.92,13.37) v6(53.97,64.22) v6(54.02,33.99) v6(54.06,63.48) v6(54.08,14.37) v6(54.22,48.73) v6(54.16,39.72) v6(54.15,24.52) v6(54.2,13.69) v6(54.17,12.72) v6(54.25,66.49) v6(54.31,34.79) v6(54.34,33.85) v6(54.25,16.95) v6(54.29,14.58) v6(54.33,13.95) v6(54.43,62.08) v6(54.4,49.46) v6(54.37,35.16) v6(54.36,24.01) v6(54.43,16.03) v6(54.52,68.23) v6(54.49,57.89) v6(54.53,42.88) v6(54.53,28.9) v6(54.47,22.9) v6(54.48,20.06) v6(54.45,19.57) v6(54.52,14.84) v6(54.58,34.35) v6(54.59,29.48) v6(54.57,19) v6(54.6,14.22) v6(54.67,57.47) v6(54.65,17.21) v6(54.75,55.64) v6(54.74,37.57) v6(54.76,33.85) v6(54.79,15.28) v6(54.83,14.5) v6(54.91,64.56) v6(54.93,43.39) v6(54.93,16.58) v6(54.85,13.34) v6(54.89,12.73) v6(55.04,16.3) v6(55.01,15.97) v6(55.11,47.49) v6(55.07,44.05) v6(55.05,34.59) v6(55.12,16.85) v6(55.08,14.82) v6(55.16,66.48) v6(55.23,51.43) v6(55.16,29.14) v6(55.17,18.86) v6(55.26,65.85) v6(55.28,61.64) v6(55.28,58.65) v6(55.26,52.44) v6(55.24,50.44) v6(55.24,15.1) v6(55.38,54.77) v6(55.38,15.48) v6(55.46,39.24) v6(55.49,16.8) v6(55.53,16.53) v6(55.49,16.13) v6(55.45,15.82) v6(55.45,13.03) v6(55.6,43.73) v6(55.59,25.45) v6(55.56,19.54) v6(55.72,53.38) v6(55.71,32.28) v6(55.73,28.68) v6(55.71,16.29) v6(55.65,13.87) v6(55.76,42.59) v6(55.76,41.6) v6(55.82,31.09) v6(55.82,30.74) v6(55.75,14.62) v6(55.93,44.9) v6(55.92,25.12) v6(55.89,18.77) v6(55.87,17.37) v6(56,64.22) v6(55.95,35.07) v6(55.94,15.73) v6(55.99,13.41) v6(56.05,62.08) v6(56.13,31.09) v6(56.13,30.74) v6(56.13,13.06) v6(56.11,12.73) v6(56.17,54.27) v6(56.16,48.53) v6(56.2,19.54) v6(56.22,16.72) v6(56.21,16.2) v6(56.22,15.53) v6(56.23,14.34) v6(56.14,14.08) v6(56.3,66.49) v6(56.32,29.13) v6(56.26,20.32) v6(56.24,14.91) v6(56.41,17.36) v6(56.46,31.09) v6(56.46,30.74) v6(56.56,41.76) v6(56.6,28.66) v6(56.73,56.1) v6(56.73,51.83) v6(56.73,50.83) v6(56.73,49.83) v6(56.65,44.81) v6(56.73,15.19) v6(56.72,14.34) v6(56.79,57.88) v6(56.74,53.36) v6(56.77,31.08) v6(56.77,30.74) v6(56.74,16.3) v6(56.9,63.48) v6(56.91,61.65) v6(56.9,45.06) v6(56.86,24.43) v6(56.88,19.78) v6(56.92,18.73) v6(56.89,17.09) v6(56.86,13.82) v6(56.98,68.24) v6(56.98,65.3) v6(57.03,29.11) v6(57.03,20.66) v6(56.95,13.46) v6(57.11,12.73) v6(57.22,55.32) v6(57.15,26.77) v6(57.21,14.09) v6(57.24,66.48) v6(57.33,66.02) v6(57.3,45.43) v6(57.3,41.5) v6(57.25,20.51) v6(57.42,19.23) v6(57.35,15.15) v6(57.41,13.79) v6(57.44,59.28) v6(57.51,46.51) v6(57.52,28.68) v6(57.47,26.29) v6(57.5,17.27) v6(57.63,62.08) v6(57.54,12.69) v6(57.65,37.04) v6(57.71,29.12) v6(57.69,13.88) v6(57.68,12.55) v6(57.78,56.91) v6(57.79,21.08) v6(57.9,63.92) v6(57.92,17.85) v6(58.02,43.46) v6(58.04,20.63) v6(58.06,21.37) v6(58.09,19.96) v6(58.28,66.48) v6(58.28,63.56) v6(58.33,55.01) v6(58.26,28.68) v6(58.35,67.84) v6(58.36,41.58) v6(58.43,40.36) v6(58.36,29.13) v6(58.41,15.81) v6(58.51,66.19) v6(58.53,64.58) v6(58.49,44.22) v6(58.44,17.38) v6(58.53,16.43) v6(58.5,13.8) v6(58.53,12.77) v6(58.57,67.45) v6(58.62,61.65) v6(58.68,60.44) v6(58.73,22.4) v6(58.67,18.57) v6(58.72,12.54) v6(58.82,59.42) v6(58.79,46.32) v6(58.8,43.92) v6(58.76,21.17) v6(58.82,18.74) v6(58.89,47.79) v6(58.89,47.13) v6(58.93,29.32) v6(58.93,28.8) v6(58.92,14.04) v6(58.96,68.21) v6(59,67.26) v6(58.99,65.77) v6(59,63.48) v6(59.01,57.48) v6(58.94,45.5) v6(59.03,35.52) v6(58.94,15.43) v6(59.12,34.28) v6(59.07,33.66) v6(59.07,33) v6(59.07,32.43) v6(59.12,31.83) v6(59.09,31.36) v6(59.1,30.42) v6(59.09,29.78) v6(59.11,14.98) v6(59.2,62.08) v6(59.15,61.81) v6(59.15,56.18) v6(59.18,22.5) v6(59.18,17.24) v6(59.24,34.69) v6(59.26,29) v6(59.36,67.49) v6(59.36,66.67) v6(59.35,66.24) v6(59.38,65.78) v6(59.39,57.88) v6(59.37,35.52) v6(59.39,35.04) v6(59.43,17.77) v6(59.37,17.24) v6(59.51,67.36) v6(59.48,43.6) v6(59.52,41.88) v6(59.53,40.19) v6(59.54,29.55) v6(59.44,22.03) v6(59.44,19.1) v6(59.45,18.38) v6(59.63,66.24) v6(59.62,65.78) v6(59.63,61.76) v6(59.61,34.19) v6(59.59,33.8) v6(59.61,33.49) v6(59.61,33.13) v6(59.6,32.91) v6(59.56,32.36) v6(59.55,31.65) v6(59.58,31.09) v6(59.55,30.46) v6(59.6,28.41) v6(59.64,25.71) v6(59.66,67.49) v6(59.65,66.68) v6(59.71,59.74) v6(59.66,35.44) v6(59.68,32.06) v6(59.68,27.7) v6(59.69,24.21) v6(59.77,63.48) v6(59.83,38.95) v6(59.84,35.52) v6(59.76,34.5) v6(59.75,32.72) v6(59.84,58.98) v6(59.88,56.32) v6(59.92,44.55) v6(59.85,21.71) v6(59.85,18.37) v6(59.9,15.77) v6(59.96,61.82) v6(59.94,61.5) v6(60.04,32.03) v6(60.07,68.44) v6(60.12,57.26) v6(60.1,35.52) v6(60.19,51.84) v6(60.3,54.98) v6(60.34,32.03) v6(60.24,20.1) v6(60.33,16.99) v6(60.35,35.29) v6(60.54,69.29) v6(60.51,65.79) v6(60.48,61.31) v6(60.51,58.66) v6(60.46,52.63) v6(60.48,50.96) v6(60.49,44.59) v6(60.48,40.1) v6(60.44,22.93) v6(60.54,16.44) v6(60.57,64.21) v6(60.57,60.34) v6(60.68,56.53) v6(60.73,32.03) v6(60.77,34.16) v6(60.77,33.89) v6(60.81,30.89) v6(60.82,18.29) v6(60.76,16.42) v6(60.92,60.44) v6(60.85,52.09) v6(60.91,35) v6(60.87,15.77) v6(61.01,67.84) v6(61.02,65.8) v6(60.98,64.45) v6(61.03,63.73) v6(60.99,60.12) v6(60.96,45.94) v6(60.99,42.98) v6(61.02,41.56) v6(60.94,37.83) v6(61,34.16) v6(61,33.89) v6(61.01,33.16) v6(61,32.72) v6(60.99,32.13) v6(61,31.84) v6(61.05,66.35) v6(61.12,34.8) v6(61.06,30.11) v6(61.19,60.58) v6(61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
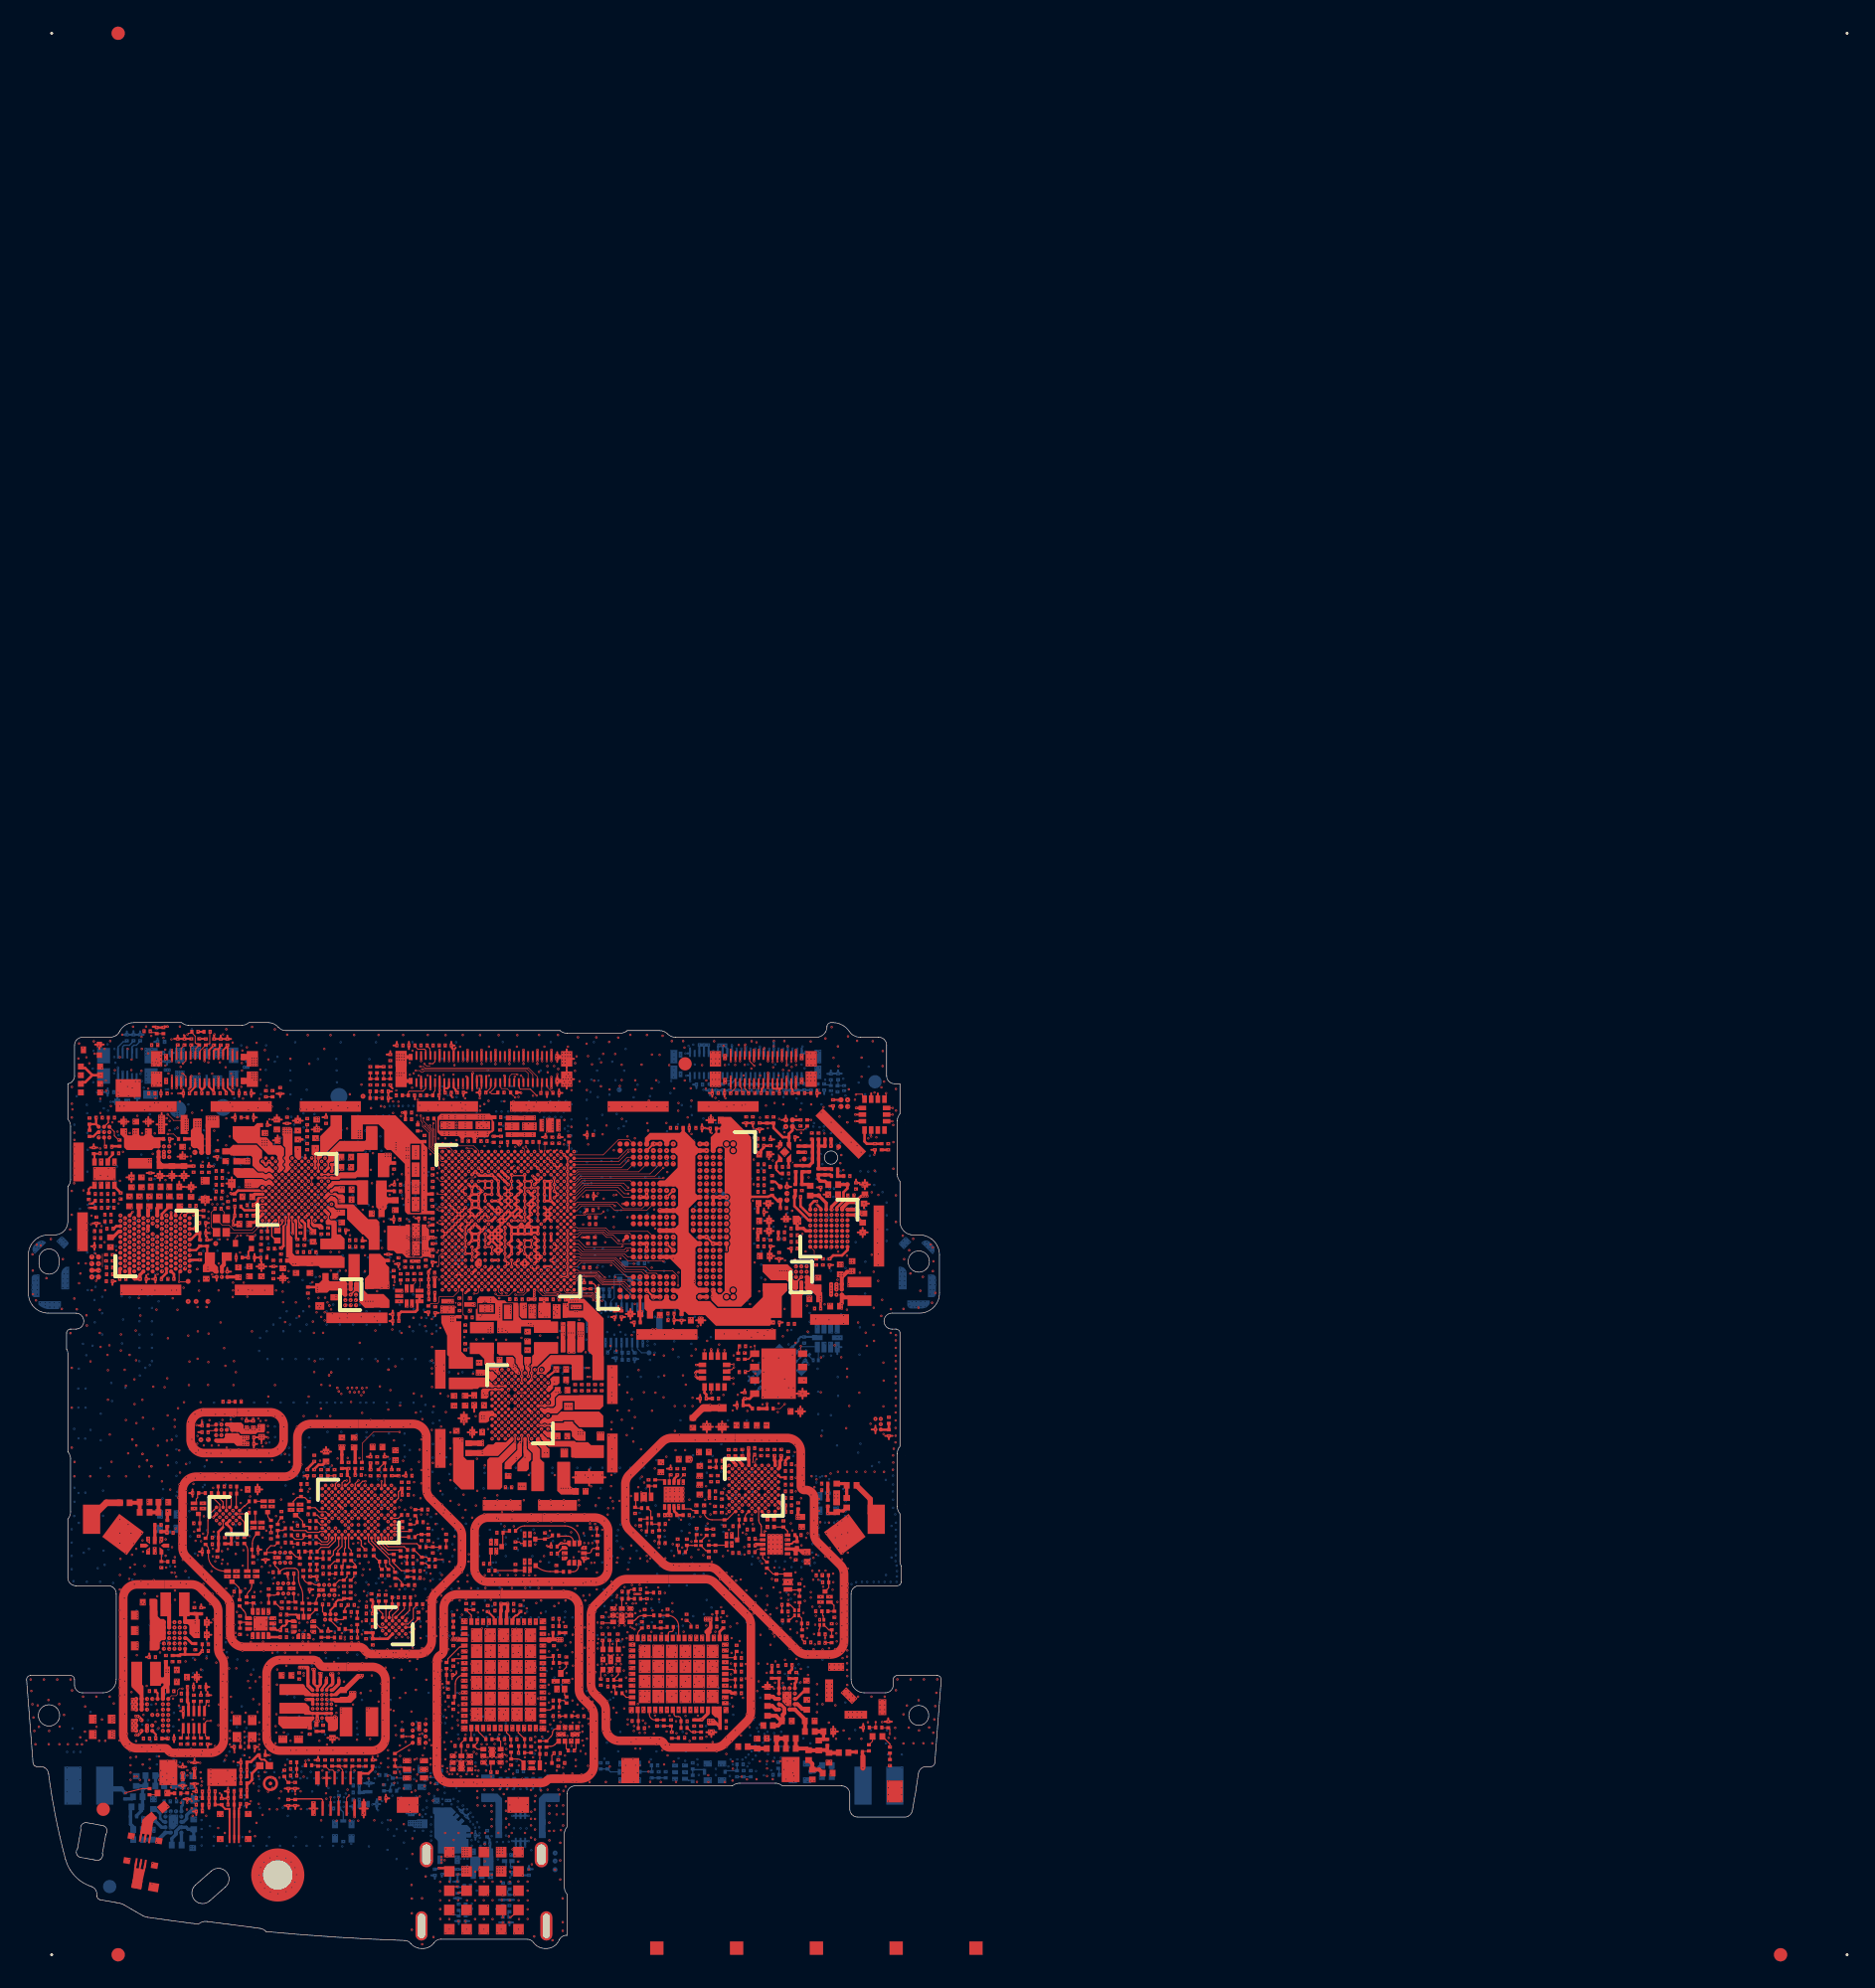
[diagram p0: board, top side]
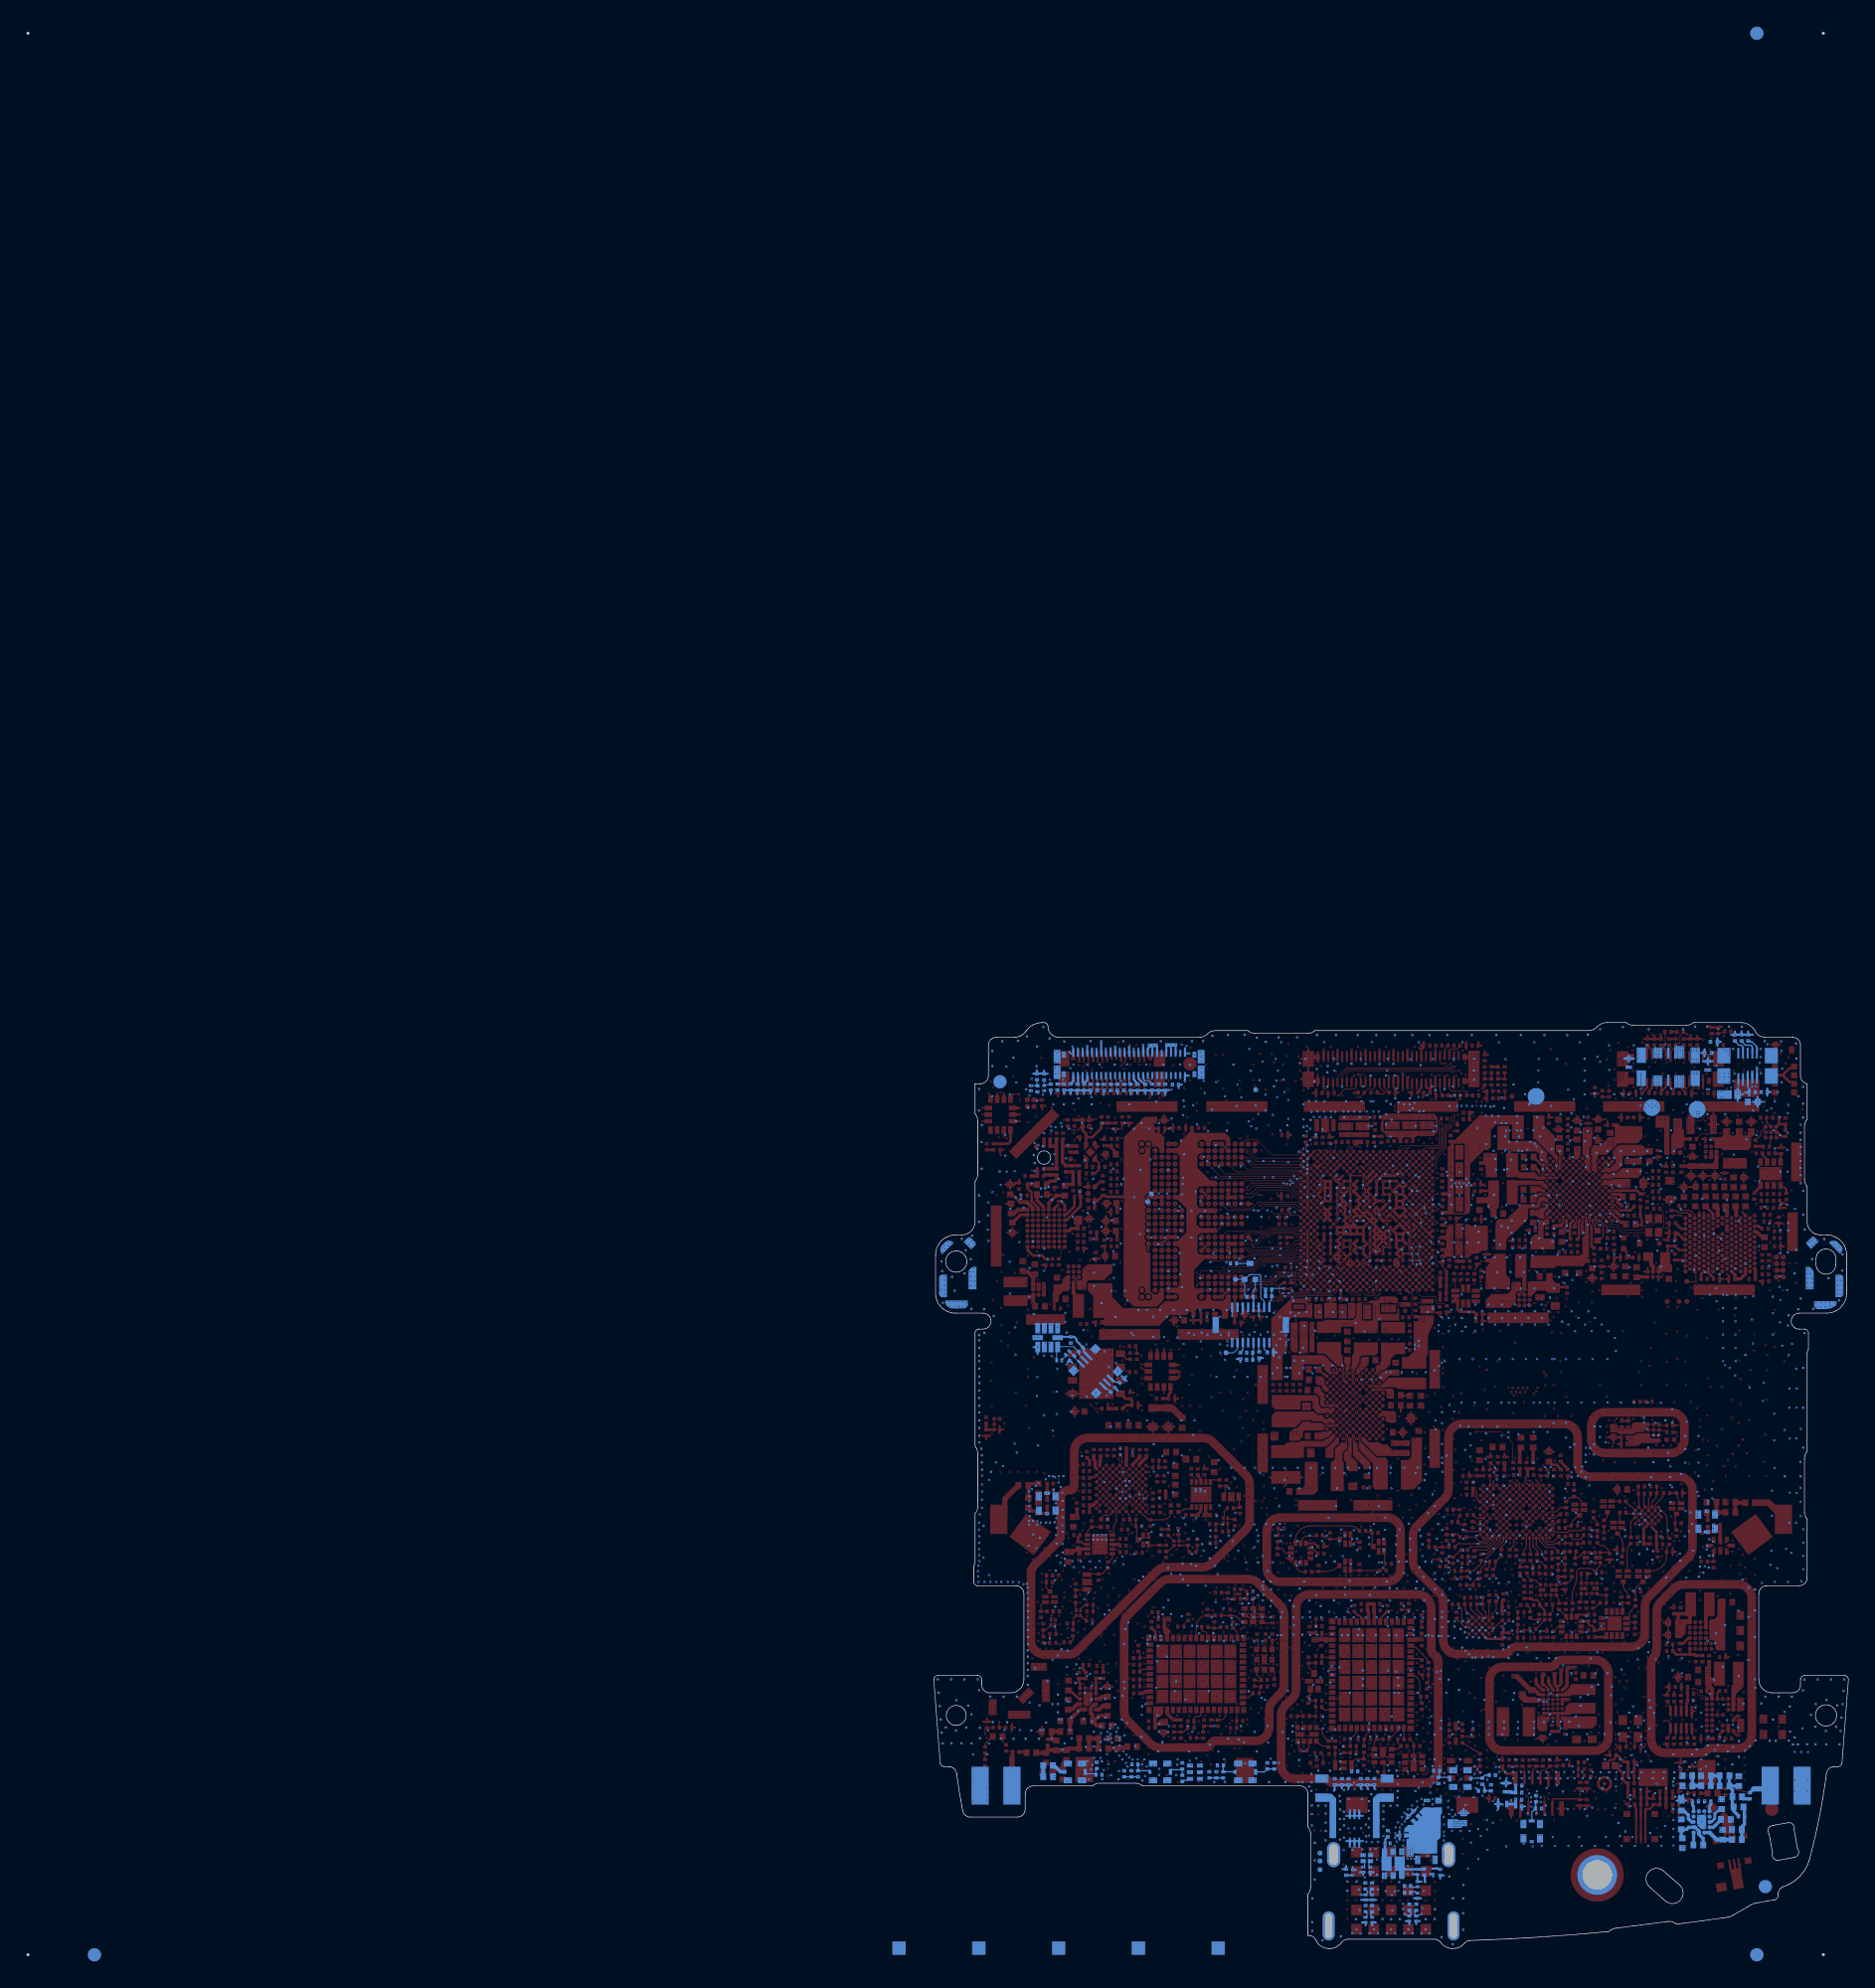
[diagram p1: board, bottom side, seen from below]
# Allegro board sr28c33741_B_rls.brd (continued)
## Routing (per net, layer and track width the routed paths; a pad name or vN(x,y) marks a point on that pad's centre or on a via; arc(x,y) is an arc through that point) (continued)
GND_FG: length 5.9
  LAYER_3 w0.045: v2(18.97,56.52) 18.9,56.46 17.93,56.46 17.69,56.7 17.66,56.72 17.35,56.72 17.08,56.99 16.19,56.99 15.88,57.3 14.7,57.3 14.27,57.73 v2(14.27,58.41)
GND_S2B: length 0.4
  LAYER_2 w0.175: v2(40.45,43.62) v2(40.63,43.62)
  LAYER_3 w0.175: v2(40.45,43.62) v2(40.63,43.62)
  vias: v1(38.26,43.53) v1(38.71,43.53)
GND_XOADC: length 8
  TOP w0.05: Y2000.2 14.88,55.02 14.88,55.36 14.66,55.58 v2(14.63,55.58)
  LAYER_3 w0.045: v2(20.71,55.24) 20.56,55.39 20.43,55.39 19.67,56.15 19.48,56.15 19.31,55.98 19.05,55.98 18.86,56.17 18.34,56.17 18.09,55.93 17.73,55.93 17.39,55.93 17.16,56.16 16.43,56.16 15.75,55.48 14.73,55.48 v2(14.63,55.58)
PGND_BOB: length 1.1
  TOP w0.05: v1(40.68,42.51) 40.63,42.51 v1(40.53,42.61)
  LAYER_3 w0.175: v2(43.13,39.74) v2(42.95,39.74) v2(42.86,39.9) v2(43.04,39.9) v2(43.22,39.9) v2(43.13,39.74)
  vias: v1(38.71,40.06) v1(39.21,40.06) v1(40.57,40.77) v1(40.75,40.77) v1(40.93,40.77) v1(42.97,38.76) v1(43.15,38.76) v1(43.33,38.76)
VDD11D_PM: length 0.9
  TOP w0.25: C4000.2 53.29,36.93 53.81,36.41 U4000.80
VDD_WL_SYNTH_CH0_1P3: length 3.2
  TOP w0.2: R4002.2 57.06,36.7 v4(57.06,36.42)
  LAYER_5 w0.2: v4(55.58,34.56) 56.24,35.22 56.49,35.22 57.06,35.79 v4(57.06,36.42)
VDD_WL_SYNTH_CH1_1P3: length 3
  TOP w0.25: R4003.2 C4005.2
  LAYER_7 w0.2: v6(51.37,33.84) 52.18,34.65 v6(53.56,34.65)
VDDCORE_CDC_1P2: length 22.9
  TOP w0.175: L6292.2 13.75,52.03 13.58,52.2 C6263.2 13.57,52.83 13.05,52.83 12.74,52.52 U6250.P16
  TOP w0.2: U6250.AB12 11.08,50.71 C6264.2
  TOP w0.25: U6250.AB6 8.53,50.66 8.53,50.37 8.54,50.36 v6(8.54,50.35) 8.12,50.35 7.75,50.72 U6250.AA3
  LAYER_2 w0.175: v6(13.63,51.23) v6(13.63,51.05)
  LAYER_3 w0.175: v6(13.63,51.23) v6(13.63,51.05)
  LAYER_3 w0.3: v2(10.24,54.53) 10.66,54.95 11.42,54.95 11.69,55.22 v2(11.69,55.89)
  LAYER_3 w0.4: v4(13.63,56.26) 12.06,56.26 v2(11.69,55.89)
  LAYER_4 w0.175: v6(13.63,51.23) v6(13.63,51.05)
  LAYER_5 w0.175: v6(13.63,51.05) v6(13.63,51.23)
  LAYER_5 w0.35: v6(13.63,51.23) v4(13.63,56.26)
  LAYER_6 w0.175: v6(13.63,51.23) v6(13.63,51.05)
  LAYER_7 w0.2: 11.99,51.23 v6(11.94,51.18) ; v6(11.04,50.35) 11.01,50.35
  LAYER_7 w0.4: v6(8.54,50.35) 11.01,50.35 11.28,50.62 13.45,50.62 13.63,50.8 v6(13.63,51.05) v6(13.63,51.23) 11.99,51.23
VDDI__MEMORY: length 2.9
  LAYER_2 w0.1: v1(55,56.89) 54.64,56.89 53.25,55.5 v1(52.62,55.5)
ACC_GYR_VDD_ISO: length 6.5
  TOP w0.2: R6110.2 v4(63.79,60.52) 63.18,60.52 63.01,60.69 U6110.8 ; v4(62.38,63.21) U6110.5
  LAYER_5 w0.175: v4(62.38,63.21) 62.38,61.02 62.88,60.52 v4(63.79,60.52)
ACC_GYR_VDD_ISO2: length 5
  TOP w0.175: U6115.5 v1(50.35,43.89)
  TOP w0.2: R6115.2 v1(51.11,41.36) 51.11,41.66 50.98,41.79 U6115.8
  LAYER_2 w0.2: v1(50.35,43.89) 50.03,43.57 50.03,42.44 v1(51.11,41.36)
ACCEL_INT: length 55.3
  TOP w0.05: U6115.4 v1(50.98,45.02)
  TOP w0.075: U6110.4 62.87,64.01 62.87,64.21 62.83,64.25 62.4,64.25 v2(62.36,64.21)
  LAYER_2 w0.045: v1(50.98,45.02) 50.74,45.02 49.5,43.79 v2(49.5,43.39) ; v2(42.87,49.02) 42.87,49.04 42.65,49.04 42.4,49.29 40.85,49.29 40.31,49.83 40.07,49.83 39.84,50.06 v1(39.72,50.06)
  LAYER_3 w0.045: v4(46.36,43.46) 46.36,43.46 49.43,43.46 v2(49.5,43.39) 49.59,43.47 50.44,43.47 50.56,43.35 53.43,43.35 53.55,43.47 53.85,43.47 54.12,43.74 58.4,43.74 59.32,44.66 61.15,44.66 63.21,46.72 63.21,48.4 64.72,49.91 64.72,57.95 64.52,58.15 64.52,62.3 64.67,62.44 64.67,63.62 64.81,63.76 64.81,64.38 64.62,64.57 62.72,64.57 v2(62.36,64.21) ; v4(46.34,47.16) 46.03,47.47 45.42,47.47 45.28,47.61 45.28,47.88 44.64,48.52 43.23,48.52 43.1,48.65 43.1,48.79 v2(42.87,49.02)
  LAYER_5 w0.045: v4(46.34,47.16) 46.59,46.91 46.59,44 46.36,43.76 v4(46.36,43.46)
ANT1_GPS_MBDRX_HBTRX: length 2.4
  LAYER_5 w0.047: v7(31.19,13.37) v4(30.04,15.42)
ANT1_MBDRX_HBTRX_50R: length 1.6
  TOP w0.088: FL7001.9 C7003.1
ANT1_ULBLBDRX: length 15.4
  LAYER_5 w0.045: v4(15.99,23.59) 15.99,18.8 arc(16.04,18.51) 16.2,18.27 22.59,11.88 arc(22.98,11.62) v7(23.44,11.53)
ANT2_MBTRX_WLAN2GS0: length 3.1
  TOP w0.088: v4(41.21,14.84) 41.19,14.86 L7030.1 41.31,15.01 41.31,15.48 FL7030.9
  LAYER_5 w0.047: v7(43.17,13.96) 42.99,14.14 arc(42.21,14.66) 41.29,14.84 v4(41.21,14.84)
ANT2_UHBDRX_LAAPRX_WLAN5GS0: length 10.1
  TOP w0.088: C4057.2 58.31,23.22 58.51,23.03 v4(58.51,23.02)
  LAYER_5 w0.047: v4(58.51,23.02) 58.51,20.86 arc(58.25,19.57) 57.52,18.48 57.32,18.28 arc(56.7,17.34) 56.48,16.24 v7(56.48,14.03)
ANT2_ULBLBTRX: length 0.7
  BOTTOM w0.088: FL7141.1 49.65,12.76 49.77,12.64 50.09,12.64 C210.1
ANT3_HBDRX: length 23.6
  TOP w0.088: L7525.2 42.88,31.16 arc(42.89,31.1) C7526.1
  LAYER_7 w0.045: v6(42.88,31.66) 50.16,31.66 arc(51.91,31.31) 53.39,30.33 54.44,29.28 arc(54.86,29) 55.35,28.9 58.45,28.9 arc(59.07,29.16) 59.33,29.78 59.33,33.87 arc(59.44,34.43) v6(59.76,34.91)
ANT4_WLANMIMO: length 1.2
  TOP w0.25: FL7050.6 9.65,30.7 C400.1 L7056.2
ANT_CSNS_CS0_N: length 57.5
  LAYER_3 w0.045: v2(12.04,15.34) 11.83,15.34 11.66,15.17 10.52,15.17 v6(10.36,15.01)
  LAYER_7 w0.045: v6(10.36,15.01) 10.35,15.02 10.35,15.64 7.31,18.67 7.31,27.12 4.21,30.23 4.21,44.97 5.45,46.21 5.45,49.11 4.91,49.66 4.91,62.58 6.54,64.21 6.85,64.21 v7(7.01,64.37) 7.17,64.53 7.74,64.53 8.14,64.93 v7(8.28,64.93)
  BOTTOM w0.075: J350.10 v7(8.28,64.93)
ANT_CSNS_CS2_N: length 10.6
  TOP w0.2: L175.2 10.61,11.67 L177.2
  LAYER_3 w0.045: v6(10.83,14.81) 10.67,14.81 10.54,14.68 9.35,14.68 9.05,14.38 9.05,13.52 v2(10.45,11.74) ; v6(11.01,16.42) 12.28,17.69 12.28,18.82 12.52,19.06 v2(12.52,19.08)
  LAYER_7 w0.045: v6(10.83,14.81) 10.83,16.24 v6(11.01,16.42)
ANT_CSNS_CS3_N: length 66.6
  TOP w0.088: L277.2 64.92,15.38 L279.2
  LAYER_3 w0.045: v2(12.6,15.34) 12.74,15.2 12.74,15.01 12.52,14.79 v6(11.23,14.79)
  LAYER_5 w0.045: v6(19.58,13.41) 19.57,13.42 19.57,14.33 17.4,16.5 v6(17.4,16.58)
  LAYER_7 w0.045: v6(11.23,14.79) 11.23,14.54 11.49,14.28 14.93,14.28 15.76,13.45 19.3,13.45 19.34,13.41 v6(19.58,13.41) ; v6(64.98,15.18) 64.98,15.34 64.24,16.08 57.29,16.08 56.32,17.05 55.05,17.05 52.51,14.51 40.38,14.51 38.75,16.14 34.43,16.14 34.29,16.28 20.05,16.28 19.7,16.63 17.45,16.63 v6(17.4,16.58)
ANT_GPS: length 9.3
  TOP w0.088: L8501.2 24.86,23.95 24.88,23.93 C8503.1 C8510.2
  LAYER_5 w0.047: v4(24.85,23.43) v4(29.96,16.92)
ANT_HB_TRX: length 8.5
  TOP w0.088: C7181.2 37,14.73 C7182.2 v2(36.99,14.68)
  LAYER_3 w0.045: v2(30.11,12.72) 35.03,12.72 arc(36.41,13.29) v2(36.99,14.68)
ANT_MB_DRX: length 11
  LAYER_5 w0.047: v4(23.65,23.41) v4(29.67,14.22)
ANT_MB_TRX: length 2
  TOP w0.088: FL7030.4 40.01,16.52 39.82,16.52 arc(39.63,16.44) 39.55,16.24 arc(39.51,16.07) 39.41,15.93 L7031.1 C7173.2
ANT_WLAN5G_S1: length 37.3
  TOP w0.088: v6(11.08,29.08) R7050.2 ; L4048.2 47.57,30.49 C4047.2
  LAYER_7 w0.045: v6(47.52,30.43) 37.84,30.43 arc(37.73,30.41) 37.63,30.34 37.57,30.29 arc(37.45,30.21) 37.32,30.18 28.94,30.18 arc(28.55,30.1) 28.21,29.88 arc(27.73,29.55) 27.16,29.44 11.94,29.44 arc(11.47,29.35) v6(11.08,29.08)
ANT_WLAN24_S0: length 21.5
  TOP w0.088: C4067.2 60.06,23 L4068.2
  LAYER_7 w0.045: v6(60.02,22.93) 57.51,20.42 arc(57.11,20.15) 56.64,20.06 55.98,20.06 arc(55.35,19.93) 54.81,19.57 51.99,16.75 arc(51.73,16.58) 51.42,16.52 v6(41.5,16.52)
ANT_WLAN24_S1: length 41.4
  TOP w0.088: L4078.2 48.96,29.93 C4077.2
  LAYER_3 w0.045: v6(10.43,30.49) 10.41,30.49 arc(10.1,30.43) 9.84,30.25 9.76,30.18 arc(9.51,30.01) 9.22,29.95 v2(9.15,29.95)
  LAYER_7 w0.045: v6(10.43,30.49) 10.71,30.49 arc(11.22,30.59) 11.66,30.88 11.73,30.95 arc(12.04,31.16) 12.4,31.23 23.85,31.23 arc(24.08,31.27) 24.27,31.4 24.48,31.61 arc(24.62,31.71) 24.79,31.74 36.88,31.74 arc(37.22,31.67) 37.51,31.48 arc(37.76,31.32) 38.04,31.26 47.69,31.26 arc(48.1,31.18) 48.45,30.94 49.01,30.39 arc(49.01,30.38) v6(49.02,30.37)
AP_DBG_UART_RX: length 112.5
  LAYER_2 w0.045: v1(36.71,50.97) 36.71,50.86 36.36,50.51 36.36,50.31 36.3,50.26 36.3,50.25 36.12,50.07 36.12,49.75 35.8,49.44 35.69,49.44 35.59,49.34 35.59,49.15 35.71,49.03 35.71,48.82 35.58,48.69 v2(35.58,48.49)
  LAYER_3 w0.045: v4(39.25,44.56) 39.25,44.67 38.52,45.4 37.11,45.4 36.85,45.66 36.85,46.16 35.74,47.27 35.74,48.33 v2(35.58,48.49) ; v7(39.74,7.18) 39.83,7.27 39.83,9.64 39.55,9.91 39.55,12.22 v4(39.49,12.28)
  LAYER_5 w0.045: v4(39.49,12.28) 39.56,12.35 39.56,15.48 42.29,18.21 42.29,28.21 v6(42.31,28.23) ; v6(39.51,44.11) 39.51,44.18 39.37,44.31 39.37,44.43 v4(39.25,44.56) ; v6(59.39,55.27) 59.53,55.13 59.53,52.86 60.71,51.67 60.71,47.59 61.22,47.08 61.22,44.4 57.7,40.88 57.7,38.29 58.7,37.3 58.7,32.13 59.65,31.18 60.31,31.18 v6(60.4,31.09)
  LAYER_7 w0.045: v6(59.39,55.27) 59.31,55.35 58.34,55.35 56.53,53.55 56.53,49.18 53.51,46.16 50.36,46.16 47.36,43.15 43.78,43.15 43.41,43.53 43.41,44.15 43.72,44.46 v7(43.72,44.75) 43.59,44.75 42.96,44.12 42.07,44.12 41.9,43.95 41.89,43.95 41.82,43.89 39.86,43.89 39.79,43.95 39.68,43.95 v6(39.51,44.11) ; v6(42.31,28.23) 42.4,28.31 43.01,28.31 43.12,28.2 45.4,28.2 47.1,26.5 57.25,26.5 60.47,29.71 60.47,31.02 v6(60.4,31.09)
  BOTTOM w0.075: VR1020.1 43.94,45.08 JTAG.13
AP_DBG_UART_TX: length 113.6
  LAYER_2 w0.045: v1(36.91,50.77) 36.75,50.77 36.45,50.47 36.45,50.27 36.4,50.22 36.4,50.22 36.23,50.05 36.23,49.73 35.92,49.42 35.92,49.15 35.82,49.05 35.82,48.71 35.75,48.64 v2(35.75,48.64)
  LAYER_3 w0.045: v4(39.73,12.29) 39.66,12.22 39.66,9.96 39.94,9.68 39.94,6.78 v7(39.74,6.58) ; v2(35.75,48.64) 35.75,48.45 35.83,48.37 35.83,47.31 36.94,46.2 36.94,45.7 37.15,45.5 38.57,45.5 v4(39.49,44.57)
  LAYER_5 w0.045: v6(39.76,44.12) 39.49,44.38 v4(39.49,44.57) ; v6(42.53,28.15) 42.39,28.01 42.39,18.17 39.66,15.44 39.66,12.36 v4(39.73,12.29) ; v6(60.48,31.31) 60.44,31.28 59.68,31.28 58.79,32.17 58.79,37.34 57.8,38.33 57.8,40.84 61.32,44.36 61.32,47.12 60.81,47.63 60.81,51.71 59.62,52.9 59.62,55.33 v6(59.61,55.34)
  LAYER_7 w0.045: v6(59.61,55.34) 59.5,55.45 58.3,55.45 56.44,53.58 56.44,49.22 53.47,46.26 50.32,46.26 47.32,43.25 43.83,43.25 43.53,43.55 43.53,44.09 44.25,44.81 v7(44.25,44.84) 44.18,44.91 43.59,44.91 42.9,44.22 42.03,44.22 41.79,43.98 39.9,43.98 v6(39.76,44.12) ; v6(60.48,31.31) 60.57,31.22 60.57,29.67 57.3,26.4 47.06,26.4 45.36,28.1 43.08,28.1 42.98,28.2 42.53,28.2 v6(42.53,28.15)
  BOTTOM w0.075: VR1021.1 44.34,44.87 JTAG.11
APPS4_I2C_SCL: length 132.3
  TOP w0.05: v4(11.72,19.54) 11.48,19.54 11.35,19.41 11.35,19.12 11.24,19.01 10.89,19.01 U4600.G1 ; U1001.AP10 33.01,57.7 33.26,57.95 33.66,57.95 v6(33.74,58.04) ; v2(29.64,62.63) 29.64,62.24 29.77,62.11 29.77,61.82 30.24,61.34 30.24,60.17 30.89,59.53 30.89,59.28 31.02,59.15 v6(31.02,58.67)
  TOP w0.075: U519.A2 5.87,60.95 5.87,60.35 v4(5.92,60.3) R1051.1
  LAYER_3 w0.045: v2(29.64,62.63) 29.64,62.72 28.9,63.46 28.9,64.89 29.48,65.47 29.69,65.47 v4(29.76,65.39) ; v4(39.97,64.99) 40.02,64.94 40.02,64.76 40.42,64.36 51.09,64.36 53.87,61.58 56.05,61.58 56.76,60.88 56.76,57.04 56.26,56.55 56.26,52.91 57.66,51.51 58.04,51.51 v2(58.26,51.29)
  LAYER_5 w0.045: v4(11.72,19.54) 11.73,19.55 11.73,19.84 11.56,20 11.56,20.71 11.56,20.71 11.56,20.73 10.2,22.08 10.2,25 11.54,26.34 11.54,31.81 11.1,32.26 11.1,34.42 10.44,35.08 10.44,36.49 9.04,37.89 9.04,46.81 8.36,47.48 8.36,48.69 7.68,49.38 7.68,50.97 6.92,51.73 6.92,55.69 7.45,56.21 7.45,56.64 7.26,56.83 7.26,57.76 5.98,59.04 5.98,60.24 v4(5.92,60.3) 5.83,60.3 5.38,60.75 5.38,62.59 5.78,62.99 5.78,64.91 6.41,65.55 8.74,65.55 9.02,65.27 12.06,65.27 12.23,65.09 15.88,65.09 16.11,64.86 v6(16.43,64.86) ; v4(29.76,65.39) 29.76,65.39 29.69,65.47 ; v4(29.76,65.39) 29.69,65.47 29.69,65.47 ; v4(29.76,65.39) 29.84,65.32 32.34,65.32 33.34,66.32 38.43,66.32 39.76,64.99 v4(39.97,64.99) ; 29.69,65.47 29.69,65.47 29.41,65.47 29.3,65.37 25.17,65.37 24.57,64.76 24.57,63.4 v6(24.66,63.31)
  LAYER_7 w0.045: v6(16.43,64.86) 16.44,64.86 16.53,64.95 20.44,64.95 22.29,63.1 24.45,63.1 v6(24.66,63.31) ; v6(33.74,58.04) 33.44,58.34 32.56,58.34 32.3,58.59 31.68,58.59 31.56,58.48 31.21,58.48 v6(31.02,58.67)
APPS4_I2C_SDA: length 128.3
  TOP w0.05: v2(29.84,62.45) 29.84,62.23 30.17,61.9 30.17,61.79 30.45,61.5 30.45,60.31 31.15,59.62 31.15,59.55 U1001.BA3
  TOP w0.075: U519.C1 6.6,61.42 6.6,61.12 6.93,60.79 R1050.1
  LAYER_2 w0.045: v2(7.87,60.4) 7.37,60.4 v4(6.94,60.83)
  LAYER_3 w0.045: v2(10.71,18.37) 10.97,18.37 11.49,18.89 11.49,19.69 v4(11.57,19.77) ; v2(7.87,60.4) 7.87,60.27 7.45,59.86 7.45,57.86 v4(7.06,57.46) ; v4(39.82,64.82) 40.38,64.26 51.05,64.26 53.82,61.48 56.01,61.48 56.66,60.83 56.66,57.08 56.17,56.59 56.17,52.87 57.63,51.41 57.88,51.41 58.02,51.27 58.02,51.18 57.86,51.02 v2(57.86,50.89) ; v2(29.84,62.45) 29.84,62.66 29,63.5 29,64.75 v4(29.53,65.28)
  LAYER_5 w0.045: v6(24.67,63.08) 24.83,63.24 24.83,63.5 24.67,63.66 24.67,64.72 25.21,65.27 29.52,65.27 v4(29.53,65.28) 29.53,65.27 29.58,65.22 32.36,65.22 33.37,66.22 38.39,66.22 39.8,64.82 v4(39.82,64.82) ; v4(6.94,60.83) 6.69,61.08 6.69,62.14 5.88,62.95 5.88,64.88 6.45,65.45 8.71,65.45 8.99,65.17 12.02,65.17 12.19,65 15.84,65 16.15,64.69 v6(16.28,64.69) ; v4(11.57,19.77) 11.47,19.87 11.47,20.67 10.11,22.03 10.11,25.05 11.45,26.39 11.45,31.77 11,32.22 11,34.38 10.34,35.04 10.34,36.45 8.94,37.85 8.94,46.78 8.26,47.45 8.26,48.66 7.58,49.34 7.58,50.93 6.83,51.68 6.83,55.73 7.35,56.25 7.35,56.57 7.14,56.79 7.14,57.38 v4(7.06,57.46)
  LAYER_7 w0.045: v6(24.67,63.08) 24.59,63.01 22.25,63.01 22.18,63.07 22.17,63.07 20.39,64.85 16.65,64.85 16.49,64.69 v6(16.28,64.69)
APPS10_I2C_SCL: length 93.7
  TOP w0.05: C5528.2 39.16,64.76 39.16,65.08 J5500.4
  TOP w0.075: C6155.2 13.5,18.48 13.5,18.31 13.38,18.19 U6150.1
  LAYER_2 w0.045: v2(24.95,47.94) 26.2,47.94 27.44,49.18 27.44,50.25 27.17,50.52 27.17,51.83 26.61,52.38 25.62,52.38 25.47,52.54 25.47,52.83 25.23,53.07 v2(25.23,53.17) ; v2(24.42,48.41) 24.42,48.16 24.49,48.09 24.49,47.45 24.61,47.33 24.61,43.78 v2(24.77,43.62)
  LAYER_3 w0.045: v2(24.42,48.41) 24.42,48.19 24.67,47.94 v2(24.95,47.94) ; v2(24.77,43.62) 24.73,43.62 24.66,43.69 22.76,43.69 22.08,43.01 11.31,43.01 11.15,43.16 v4(10.93,43.16) ; v2(13.66,18.63) 13.75,18.71 13.75,22.33 v4(13.65,22.43) 13.65,22.49 13.3,22.84 11.97,22.84 v2(11.94,22.87) ; v2(32.29,53.47) 32.26,53.45 31.86,53.45 31.78,53.53 31.12,53.53 30.94,53.71 30.29,53.71 30.17,53.84 28.79,53.84 28.72,53.91 28.38,53.91 28.19,53.71 28.19,53.46 27.9,53.17 v2(25.23,53.17) 25.2,53.14 25.08,53.14 24.87,53.35 24.87,54.39 25.48,55.01 25.48,57.47 v4(25.19,57.76)
  LAYER_5 w0.045: v4(10.93,43.16) 10.93,38.75 12.88,36.8 12.88,33.49 13.17,33.2 13.17,25.69 13.75,25.12 13.75,23.25 13.48,22.98 13.48,22.74 13.65,22.57 v4(13.65,22.43) ; v4(25.19,57.76) 25.19,64.52 25.84,65.17 29.41,65.17 29.46,65.12 32.4,65.12 33.41,66.12 37.57,66.12 39.11,64.59 39.41,64.59 v4(39.58,64.42)
APPS10_I2C_SDA: length 94.9
  TOP w0.075: C6154.2 13.02,18.5 13.02,17.9 U6150.2 ; v4(38.67,64.33) 38.73,64.39 38.73,65.09 J5500.6
  LAYER_2 w0.045: v2(25.09,43.52) 25.09,43.53 24.7,43.91 24.7,47.37 24.59,47.48 24.59,48.59 v1(24.72,48.72) 24.74,48.72 25.36,48.1 26.21,48.1 27.34,49.22 27.34,50.21 27.06,50.49 27.06,51.8 26.57,52.29 25.59,52.29 25.38,52.5 25.38,52.79 25.03,53.14 v2(25.03,53.42)
  LAYER_3 w0.045: v2(11.19,22.92) 11.33,23.06 12.02,23.06 12.14,22.94 13.52,22.94 v4(13.64,22.82) 13.84,22.62 13.84,18.58 13.73,18.47 13.25,18.47 v2(13.17,18.55) ; v2(25.09,43.52) 25.09,43.51 25.04,43.46 24.65,43.46 24.51,43.59 22.8,43.59 22.12,42.91 11.17,42.91 v4(11.09,43) ; v2(32.52,53.29) 32.52,53.47 32.35,53.63 32.22,53.63 32.13,53.54 31.9,53.54 31.81,53.62 31.16,53.62 30.98,53.8 30.33,53.8 30.21,53.93 28.83,53.93 28.76,54 28.35,54 28.1,53.75 28.1,53.5 27.86,53.27 25.36,53.27 25.29,53.33 25.12,53.33 v2(25.03,53.42) 24.97,53.48 24.97,54.34 25.59,54.96 25.59,57.61 v4(25.43,57.77)
  LAYER_5 w0.045: v4(25.43,57.77) 25.28,57.91 25.28,64.47 25.88,65.08 29.37,65.08 29.42,65.03 32.44,65.03 33.45,66.03 37.53,66.03 38.85,64.72 38.85,64.51 v4(38.67,64.33) ; v4(13.64,22.82) 13.64,22.99 13.84,23.2 13.84,25.15 13.27,25.73 13.27,33.24 12.97,33.53 12.97,36.84 11.02,38.79 11.02,42.92 11.1,43 v4(11.09,43)
AUX_THERM_BIAS: length 4.7
  LAYER_2 w0.045: v1(14.65,56.42) 14.71,56.36 15.26,56.36 15.54,56.08 16.25,56.08 16.44,56.27 17.08,56.27 17.31,56.51 17.85,56.51 18.03,56.33 18.03,56.2 18.13,56.1 18.29,56.1 18.41,56.22 v1(18.73,56.22)
B1_B3_DRX_50R: length 0.6
  TOP w0.088: 20.74,25.51 20.83,25.42 U7510.2
B1_B3_DRX_FLT_IN_50R: length 5
  TOP w0.088: R7600.2 20.77,25.96 20.77,26.55 arc(20.73,26.86) 20.62,27.16 arc(20.49,27.51) 20.45,27.88 20.45,28.29 arc(20.36,28.5) 20.15,28.59 19.56,28.59 arc(19.31,28.54) 19.11,28.4 L7601.2 18.95,28.35 18.95,28.52 18.67,28.8 FL7600.1
B1_DRX_FLT_OUT_50R: length 1
  TOP w0.088: C7602.2 21.32,29.78 L7603.1 C7644.2
B2_B25_B4_DRX_50R: length 0.8
  TOP w0.088: C7610.1 21.23,24.96 U7510.1
B2_B25_B4_DRX_FLT_IN_50R: length 1.2
  TOP w0.088: L7611.2 21.76,25.95 C7610.2 21.76,26.04 arc(21.82,26.33) FL7610.1
B2_B25_DRX_FLT_OUT_50R: length 2.6
  TOP w0.088: L7616.1 21.29,30.48 21.28,30.48 20.89,30.48 20.85,30.44
  LAYER_3 w0.045: v2(20.83,30.38) 21.13,30.07 arc(21.15,30.05) 21.16,30.02 21.16,29.68 arc(21.14,29.62) 21.11,29.56 arc(20.89,29.23) 20.81,28.85 v2(20.81,28.43)
B3_DRX_FLT_OUT_50R: length 2
  TOP w0.088: 18.05,29.78 18.07,29.8 18.07,30 18.36,30.29 18.67,30.29 C7645.1 ; 18.05,29.78 FL7600.9 ; 18.05,29.78 L7648.2
B4_B66_DRX_FLT_OUT_50R: length 1.1
  TOP w0.088: C7646.2 24.19,28.69 L7612.2 24.7,28.69 24.7,28.88 L7614.1
B5_B26_DRX_50R: length 1.2
  TOP w0.088: 17,25.34 17,25.92 C7700.2 R7701.1
B5_B26_DRX_FLT_IN_50R: length 1.3
  TOP w0.088: FL7700.1 16.93,27.31 arc(16.88,27.08) 16.76,26.89 16.71,26.85 arc(16.59,26.66) R7701.2
B5_B26_DRX_FLT_OUT_50R: length 2.2
  TOP w0.088: FL7700.4 16.64,28.42 16.64,29.92 arc(16.59,30.17) 16.44,30.39 C7702.1
B7_B30_DRX_SWOUT_50R: length 2.3
  TOP w0.088: FL7800.4 37.38,28.43 C7802.1 36.75,28.42 C7864.1
B7_DRX_50R: length 1.3
  TOP w0.088: R7800.1 41.08,28.33 arc(41.37,28.45) 41.5,28.75 41.5,29.01 U7520.9
B8_DRX_50R: length 6.4
  TOP w0.088: v2(18.38,31.28) 18.38,31.28 R7706.1
  LAYER_3 w0.045: v2(18.38,31.28) 18.38,30.62 18.38,30.62 18.38,29.47 arc(18.33,29.22) 18.19,29.01 arc(17.93,28.63) 17.85,28.19 v2(17.85,25.52)
B8_DRX_FLT_IN_50R: length 0.7
  TOP w0.088: R7706.2 18.26,32.32 arc(18.16,32.47) 18.12,32.64 FL7705.1
B8_DRX_FLT_OUT_50R: length 0.6
  TOP w0.088: C7707.1 17.81,33.63 17.82,33.64
B12_B17_B13_DRX_50R: length 1.3
  TOP w0.088: U7500.8 16.49,24.84 16.49,25.04 arc(16.45,25.24) 16.34,25.4 16.31,25.43 R7715.1
B12_B17_B13_DRX_FLT_IN_50R: length 1.7
  TOP w0.088: R7715.2 16.02,26.79 L7716.2 16,26.91 16,27.03 arc(15.98,27.1) 15.94,27.17 15.53,27.58 FL7715.1
B12_B17_B13_DRX_FLT_OUT_50R: length 3
  TOP w0.088: FL7715.4 15.06,28.38 15.04,28.37 14.92,28.37 14.91,28.38 14.88,28.38 arc(14.4,28.48) 13.99,28.75 arc(13.75,29.1) 13.67,29.52 L7717.2 13.67,30.04 arc(13.64,30.17) 13.57,30.27 R7718.1
B13_ANT_DUP_1_50R: length 1.5
  TOP w0.088: L7265.2 45.68,26.99 45.41,26.99 C7264.2 L7263.2 C7267.1
B13_ANT_DUP_50R: length 0.8
  TOP w0.088: L7263.1 44.76,26.27 FL7260.6
B13_ANT_DUP_FLT_50R: length 0.5
  TOP w0.088: C7266.1 L7267.2
B13_RX_DUP_50R: length 18.5
  TOP w0.088: FL7260.1 44.11,24.48 v2(43.29,24.48)
  LAYER_3 w0.045: v2(43.29,24.48) 40.83,26.94 arc(40.37,27.24) 39.84,27.35 30.48,27.35 arc(30.07,27.27) 29.72,27.04 arc(29.44,26.85) 29.1,26.78 27.47,26.78 arc(27.21,26.73) v2(26.99,26.58)
B13_TX_DUP_50R: length 2
  TOP w0.088: FL7260.3 45.41,24.65 45.65,24.65 arc(45.7,24.66) 45.75,24.69 45.83,24.78 45.97,24.92 arc(46.1,25) 46.25,25.03 L7262.2 47.15,25.03 C7261.1
B20_DRX_50R: length 3.7
  LAYER_3 w0.045: v2(17.39,25.36) 17.39,28.27 arc(17.31,28.66) v2(17.09,28.99)
B20_DRX_FLT_IN_50R: length 1.9
  TOP w0.088: R7710.2 16.98,29.53 16.98,30 C7711.2 16.98,30.03 16.98,30.45 arc(17.05,30.8) 17.24,31.1 FL7710.1
B20_DRX_FLT_OUT_50R: length 0.9
  TOP w0.088: C7712.1 17.2,32.04 FL7710.4
B25_DUP_RX_50R: length 17.8
  TOP w0.088: L7306.1 30.17,30.64 v4(30.15,30.64)
  LAYER_5 w0.047: v4(30.15,30.64) 30.15,29.73 arc(30.17,29.59) 30.25,29.48 arc(30.3,29.4) 30.32,29.32 30.32,22.65 arc(30.41,22.19) 30.66,21.81 30.68,21.79 arc(31.08,21.19) 31.23,20.47 arc(31.18,20.25) 31.05,20.06 arc(30.94,19.88) 30.9,19.68 30.9,17.02 arc(30.97,16.65) 31.18,16.34 31.27,16.24 arc(31.62,15.73) 31.74,15.13 31.74,14.02 arc(31.78,13.77) v4(31.93,13.56)
B28_ANT_DUP_50R: length 1.5
  TOP w0.088: U7230.1 44.5,20.6 44.16,20.26 L7236.2 44.21,20.15 44.6,20.15 L7237.2
B28_ANT_DUP_MAT_50R: length 1.1
  TOP w0.088: L7237.1 44.66,19.7 C7238.2 44.24,19.62 44.24,19.27 L7239.2
B28_DPX_CTL: length 28
  TOP w0.075: U7230.4 43.85,22.56 43.85,23.16 C7235.1
  LAYER_3 w0.045: v4(26.52,25.42) 27.44,25.42 28.46,24.4 32.59,24.4 33.15,23.84 41.9,23.84 42.26,23.48 43.49,23.48 v2(43.77,23.2)
  LAYER_5 w0.045: v4(26.52,25.42) 27.16,26.06 27.16,30.33 26.31,31.18 26.31,33.42 v4(25.94,33.79)
B28_DRX_50R: length 9.9
  LAYER_3 w0.045: v2(16.94,23.37) 16.79,23.37 arc(16.62,23.34) 16.48,23.24 arc(16.4,23.19) 16.31,23.17 15.83,23.17 arc(15.51,23.3) 15.38,23.62 15.38,24.92 arc(15.09,26.37) 14.27,27.6 arc(13.28,29.07) 12.94,30.81 v2(12.94,31.01)
B28_DRX_FLT_IN_50R: length 1.4
  TOP w0.088: R7720.2 13.03,31.56 L7721.2 13.03,32.68 FL7720.1
B28_DRX_FLT_OUT_50R: length 1.5
  TOP w0.088: R7723.1 L7722.2 12.86,34.17 12.86,33.9 12.76,33.8 12.76,33.48 FL7720.4
B28_RX_DUP_50R: length 23.2
  TOP w0.088: L7240.2 44.46,23.15 44.38,23.07 44.38,22.49 U7230.3
  LAYER_5 w0.047: v4(44.4,23.22) 44.4,25.94 arc(44.35,26.17) v6(44.22,26.37)
  LAYER_7 w0.045: v6(44.22,26.37) 44.22,26.38 29.02,26.38 arc(27.29,26.04) 25.82,25.05 v6(25.51,24.74)
B28_TX_DUP_50R: length 7.3
  TOP w0.088: U7230.7 43.18,20.81 L7233.2
  LAYER_3 w0.045: v2(46.78,24.12) 46.78,24.08 arc(46.69,23.88) 46.5,23.8 45.89,23.8 arc(45.26,23.54) 45,22.91 45,20.86 arc(44.9,20.63) 44.66,20.53 43.81,20.53 arc(43.5,20.47) v2(43.24,20.29)
B34_DRX_50R: length 3.5
  TOP w0.088: v2(19.18,25.55) 19.15,25.55 18.71,25.99 C7620.1
  LAYER_3 w0.045: v2(19.18,25.55) 19.57,25.55 arc(19.8,25.45) 19.9,25.22 arc(19.97,24.82) 20.2,24.49 20.62,24.07 arc(20.72,23.92) 20.76,23.74 20.76,23.67 arc(20.76,23.64) v2(20.78,23.62)
B34_DRX_FLT_IN_50R: length 1.3
  TOP w0.088: C7620.2 L7621.2 18.61,26.57 arc(18.77,26.6) 18.91,26.69
B34B39_DRX_FLT_OUT_50R: length 3.7
  TOP w0.088: L7629.1 20.1,27.48 FL7620.1
  LAYER_3 w0.045: v2(20.08,28.21) 20.08,29.13 arc(19.99,29.57) 19.74,29.95 arc(19.51,30.29) 19.43,30.7 v2(19.43,31.04)
B39_DRX_50R: length 2.5
  LAYER_3 w0.045: v2(21.17,23.45) 21.17,23.79 arc(21.13,23.97) 21.02,24.13 20.51,24.65 arc(20.3,24.96) 20.23,25.33 v2(20.23,25.59)
B39_DRX_FLT_IN_50R: length 1.2
  TOP w0.088: 20.08,26.69 20.11,26.67 20.11,26.17 C7622.2 L7623.2
B40_DRX_50R: length 5.8
  TOP w0.088: U7520.1 41.58,30.68 arc(41.26,31.46) 40.48,31.78 37.44,31.78 arc(37.16,31.72) 36.92,31.57 C7822.1
B41_DRX_50R: length 1.6
  TOP w0.088: C7830.1 40,31.01 40.72,31.01 arc(40.99,30.9) 41.11,30.62 41.11,30.46 U7520.2
B_PLUS: length 97.4
  TOP w0.05: v6(61.31,48.14) 61.17,48.14 C4121.2
  TOP w0.1: U2000.42 U2000.20 21.7,60.17 v4(21.73,60.2) ; v1(36.98,43.28) v1(36.73,43.53) ; 23.29,58.34 23.14,58.2 U2000.66 U2000.65 ; U2400.67 v6(37.72,43.03) ; 39.41,40.81 U2400.17 U2400.39 ; 34.58,42.04 U2400.178 U2400.156 ; 23.16,56.72 U2000.131
  TOP w0.175: U2400.2 v6(39.88,43.54)
  TOP w0.2: C2562.2 21.85,49.74 v6(21.87,49.72) ; C2255.2 23.09,58.95 U2000.33 22.98,58.9 22.98,58.5 U2000.55 ; C2570.2 59.7,48.75 v6(59.7,48.12) ; U2000.141 U2000.131 ; C2256.2 23.56,58.75 23.29,58.48 23.29,58.34
  TOP w0.25: 57.95,54.76 C4101.2 58.42,54.15 58.6,53.97 U4100.E1 ; U7150.25 36.09,25.33 C7150.2 C7152.2 C7162.2 C7161.2 35.65,25.38 U7150.26 ; C6402.2 12.81,25.18 C6400.2 ; C2277.2 9.97,60.88 ; L6400.1 11.86,25.18 C6400.2 ; C6291.2 15.91,50.5 U6290.A2 ; C6400.2 12.62,25.17 C6401.2 ; C7102.2 C7101.2 50.75,17.19 v2(50.78,17.22) 51.23,17.68 U7100.14 ; U8200.19 U8200.24 v4(21.02,18.73)
  TOP w0.3: L6400.1 11.92,25.82 U6400.A5 ; U4100.A8 62.44,55.57 62.73,55.28 C4103.2 ; C4121.2 61.17,48.4 61.3,48.53 U4120.A3 61.5,48.96 62.39,48.96 L4120.1
  TOP w0.5: C2361.1 C2360.1 50.85,40.65 C2263.2
  LAYER_2 w0.175: v6(61.31,48.5) v6(61.31,48.32) v6(61.31,48.14) ; v6(34.41,40.04) v6(34.4,39.86) v6(34.22,39.86) ; v6(34.41,40.04) v6(34.22,39.86) ; v6(34.41,40.04) v6(34.23,40.04) v6(34.22,39.86) ; v6(16.05,50.61) v6(16.05,50.43) ; v6(12.72,23.75) v6(12.9,23.75) ; v4(7.45,61.5) v4(7.45,61.32) ; v6(39.7,43.54) 39.22,43.54 v1(38.74,43.06) ; v6(39.7,43.54) v6(39.78,43.39) v6(39.88,43.54) v6(39.7,43.54) ; v6(37.02,42.75) 36.98,42.95 v1(36.98,43.28) v1(36.73,43.53) ; v6(17.64,50.6) v6(17.77,50.47) ; v6(59.69,48.68) v6(59.69,48.86) v6(59.69,49.04) ; v4(11.89,60.34) v4(11.89,60.16) ; v6(34.36,41.75) v6(34.47,41.61) v6(34.65,41.61) ; v6(16.6,50.6) v6(16.6,50.42) ; v2(24.34,19.27) v2(24.52,19.27) v2(24.7,19.27) ; v4(40.19,34.61) v4(40.36,34.61) v4(40.54,34.61) v4(40.74,34.61) v4(40.94,34.61) ; v4(9,61.31) v4(9,61.5) ; v4(23.72,58.59) v4(23.54,58.59) ; v6(37.72,43.03) 37.72,43.56 v6(37.73,43.8) v6(37.57,43.89) ; v4(23.8,59.36) v4(23.61,59.36) ; v1(36.73,43.53) v6(36.75,43.8) v6(36.6,43.89) v6(36.6,43.72) v1(36.73,43.53) ; v6(20.86,21.09) v6(20.68,21.09) v6(20.5,21.09) ; v6(57.99,54.52) v6(58.17,54.66) ; v6(12.03,20.44) v6(12.03,20.26) ; v6(21.87,49.72) v6(21.87,49.54) v6(21.87,49.36) ; v4(13.2,57.94) v4(13.2,57.74) v4(13.2,57.54) ; v6(33.88,43.17) v6(34.06,43.17) v6(34.24,43.17) ; v6(20.06,20.54) v6(20.06,20.72) ; v6(62.8,55.41) v6(62.8,55.23) ; v2(23.36,55.47) v2(23.54,55.47) ; v6(40.14,41.83) v6(39.96,41.83) v6(39.79,41.83) ; v4(23.56,56.34) v4(23.56,56.16) ; v6(34.29,39.04) v6(34.29,38.87) ; v6(32.25,41.63) v6(32.25,41.45) ; v4(23.63,57.21) v4(23.81,57.21) ; v6(12.67,24.65) v6(12.67,24.47) ; v6(32.76,38.15) v6(32.76,38.33) v6(32.58,38.33) v6(32.76,38.15)
  LAYER_2 w0.18: v4(17.72,60.59) v4(17.72,60.77) v4(17.9,60.77) v4(18.08,60.77) v4(18.08,60.59) ; v4(17.72,60.59) v4(17.72,60.41) v4(17.9,60.41) v4(18.08,60.41) v4(18.08,60.59) ; v4(17.72,60.59) v4(17.9,60.59) v4(18.08,60.59)
  LAYER_3 w0.175: v4(23.72,58.59) v4(23.54,58.59) ; v6(40.14,41.83) 39.97,41.83 v6(39.96,41.83) 39.96,41.83 v6(39.79,41.83) ; v6(12.67,24.65) v6(12.67,24.47) ; v4(23.63,57.21) v4(23.81,57.21) ; v6(59.69,49.04) v6(59.69,48.86) v6(59.69,48.68) ; v6(34.22,39.86) v6(34.23,40.04) v6(34.41,40.04) ; v6(34.22,39.86) v6(34.4,39.86) v6(34.41,40.04) ; v6(34.22,39.86) v6(34.41,40.04) ; v2(22.23,56.75) v4(22.8,56.75) ; v4(9,61.31) v4(9,61.5) ; v4(40.19,34.61) v4(40.36,34.61) v4(40.54,34.61) v4(40.74,34.61) v4(40.94,34.61) ; v6(58.17,54.66) v6(57.99,54.52) ; v6(21.87,49.72) v6(21.87,49.54) v6(21.87,49.36) ; v6(12.03,20.44) v6(12.03,20.26) ; v6(61.31,48.5) v6(61.31,48.32) v6(61.31,48.14) ; v4(13.2,57.94) v4(13.2,57.74) v4(13.2,57.54) ; v6(32.25,41.63) v6(32.25,41.45) ; v4(7.45,61.5) v4(7.45,61.32) ; v4(23.61,59.36) v4(23.8,59.36) ; v6(34.65,41.61) v6(34.47,41.61) v6(34.36,41.75) ; v4(11.89,60.34) v4(11.89,60.16) ; v6(20.06,20.54) v6(20.06,20.72) ; v6(16.6,50.6) v6(16.6,50.42) ; v6(16.05,50.61) v6(16.05,50.43) ; v6(33.88,43.17) v6(34.06,43.17) v6(34.24,43.17) ; v6(37.57,43.89) v6(37.73,43.8) ; v6(20.86,21.09) v6(20.68,21.09) v6(20.5,21.09) ; v6(62.8,55.41) v6(62.8,55.23) ; v6(34.29,39.04) v6(34.29,38.87) ; v6(17.64,50.6) v6(17.77,50.47) ; v6(12.72,23.75) v6(12.9,23.75) ; v4(23.56,56.34) v4(23.56,56.16) ; v6(32.76,38.33) v6(32.76,38.15) v6(32.58,38.33) v6(32.76,38.33) ; v6(39.88,43.54) v6(39.7,43.54) v6(39.78,43.39) v6(39.88,43.54) ; v6(36.6,43.89) v6(36.75,43.8) v6(36.6,43.72) v6(36.6,43.89)
  LAYER_3 w0.18: v4(17.72,60.59) v4(17.9,60.59) v4(18.08,60.59) ; v4(17.72,60.59) v4(17.72,60.77) v4(17.9,60.77) v4(18.08,60.77) v4(18.08,60.59) ; v4(17.72,60.59) v4(17.72,60.41) v4(17.9,60.41) v4(18.08,60.41) v4(18.08,60.59)
  LAYER_3 w0.25: v6(53.98,17.3) 52.75,17.3 52.34,17.72 51.02,17.72 50.78,17.48 v2(50.78,17.22)
  LAYER_4 w0.175: v6(39.79,41.83) v6(39.96,41.83) v6(40.14,41.83) ; v6(21.87,49.72) v6(21.87,49.54) v6(21.87,49.36) ; v6(20.86,21.09) v6(20.68,21.09) v6(20.5,21.09) ; v4(13.2,57.94) v4(13.2,57.74) v4(13.2,57.54) ; v6(17.64,50.6) v6(17.77,50.47) ; v6(61.31,48.14) v6(61.31,48.32) v6(61.31,48.5) ; v4(7.45,61.5) v4(7.45,61.32) ; v6(34.41,40.04) v6(34.4,39.86) v6(34.22,39.86) ; v6(34.41,40.04) v6(34.23,40.04) v6(34.22,39.86) ; v6(34.41,40.04) v6(34.22,39.86) ; v6(59.69,49.04) v6(59.69,48.86) v6(59.69,48.68) ; v6(20.06,20.54) v6(20.06,20.72) ; v4(11.89,60.34) v4(11.89,60.16) ; v4(40.94,34.61) v4(40.74,34.61) v4(40.54,34.61) v4(40.36,34.61) v4(40.19,34.61) ; v4(23.36,55.89) v4(23.54,55.89) ; v6(12.72,23.75) v6(12.9,23.75) ; v6(23.93,22.1) v6(23.75,22.1) v6(23.57,22.1) v6(23.39,22.1) ; v6(34.29,39.04) v6(34.29,38.87) ; v6(57.99,54.52) v6(58.17,54.66) ; v6(16.05,50.61) v6(16.05,50.43) ; v6(32.25,41.63) v6(32.25,41.45) ; v4(23.72,58.59) v4(23.54,58.59) ; v4(9,61.31) v4(9,61.5) ; v6(34.65,41.61) v6(34.47,41.61) v6(34.36,41.75) ; v6(37.73,43.8) v6(37.57,43.89) ; v4(23.61,59.36) v4(23.8,59.36) ; v4(23.63,57.21) v4(23.81,57.21) ; v6(12.67,24.65) v6(12.67,24.47) ; v6(12.03,20.44) v6(12.03,20.26) ; v6(62.8,55.41) v6(62.8,55.23) ; v4(23.56,56.34) v4(23.56,56.16) ; v6(16.6,50.6) v6(16.6,50.42) ; v6(33.88,43.17) v6(34.06,43.17) v6(34.24,43.17) ; v6(32.76,38.15) v6(32.76,38.33) v6(32.58,38.33) v6(32.76,38.15) ; v6(39.88,43.54) v6(39.7,43.54) v6(39.78,43.39) v6(39.88,43.54) ; v6(36.6,43.89) v6(36.6,43.72) v6(36.75,43.8) v6(36.6,43.89)
  LAYER_4 w0.18: v4(18.08,60.59) v4(18.08,60.41) v4(17.9,60.41) v4(17.72,60.41) v4(17.72,60.59) ; v4(18.08,60.59) v4(18.08,60.77) v4(17.9,60.77) v4(17.72,60.77) v4(17.72,60.59) ; v4(18.08,60.59) v4(17.9,60.59) v4(17.72,60.59)
  LAYER_5 w0.175: v6(62.8,55.41) v6(62.8,55.23) ; v6(34.22,39.86) v6(34.4,39.86) v6(34.41,40.04) ; v6(34.22,39.86) v6(34.41,40.04) ; v6(34.22,39.86) v6(34.23,40.04) v6(34.41,40.04) ; v6(21.87,49.36) v6(21.87,49.54) v6(21.87,49.72) ; v6(12.03,20.44) v6(12.03,20.26) ; v6(34.24,43.17) v6(34.06,43.17) v6(33.88,43.17) ; v6(34.29,39.04) v6(34.29,38.87) ; v6(12.72,23.75) v6(12.9,23.75) ; v6(23.93,22.1) v6(23.75,22.1) v6(23.57,22.1) v6(23.39,22.1) ; v6(32.25,41.63) v6(32.25,41.45) ; v6(20.5,21.09) v6(20.68,21.09) v6(20.86,21.09) ; v6(40.14,41.83) 39.97,41.83 v6(39.96,41.83) 39.96,41.83 v6(39.79,41.83) ; v6(57.99,54.52) v6(58.17,54.66) ; v6(16.05,50.61) v6(16.05,50.43) ; v6(17.64,50.6) v6(17.77,50.47) ; v6(34.65,41.61) v6(34.47,41.61) v6(34.36,41.75) ; v6(59.69,49.04) v6(59.69,48.86) v6(59.69,48.68) ; v6(16.6,50.6) v6(16.6,50.42) ; v6(61.31,48.5) v6(61.31,48.32) v6(61.31,48.14) ; v6(37.73,43.8) v6(37.57,43.89) ; v6(12.67,24.65) v6(12.67,24.47) ; v6(39.88,43.54) v6(39.7,43.54) v6(39.78,43.39) v6(39.88,43.54) ; v6(36.75,43.8) v6(36.6,43.72) v6(36.6,43.89) v6(36.75,43.8) ; v6(32.58,38.33) v6(32.76,38.15) v6(32.76,38.33) v6(32.58,38.33)
  LAYER_5 w0.25: v6(20.06,20.72) v6(20.06,20.54) 20.06,19.87 20.79,19.14 20.79,18.96 v4(21.02,18.73)
  LAYER_6 w0.175: v6(62.8,55.41) v6(62.8,55.23) ; v6(34.22,39.86) v6(34.41,40.04) ; v6(34.22,39.86) 34.22,40.04 v6(34.23,40.04) v6(34.41,40.04) ; v6(34.22,39.86) v6(34.4,39.86) 34.4,40.04 v6(34.41,40.04) ; v6(20.86,21.09) v6(20.68,21.09) v6(20.5,21.09) ; v6(21.87,49.72) v6(21.87,49.54) v6(21.87,49.36) ; v6(61.31,48.5) v6(61.31,48.32) v6(61.31,48.14) ; v6(34.65,41.61) v6(34.47,41.61) v6(34.36,41.75) ; v6(11.6,49.16) v6(11.8,49.16) v6(12,49.16) v6(12.22,49.16) v6(12.42,49.16) v6(12.62,49.16) ; v6(12.62,49.96) v6(12.42,49.96) v6(12.22,49.96) v6(12,49.96) v6(11.8,49.96) v6(11.6,49.96) ; v6(32.25,41.63) v6(32.25,41.45) ; v6(11.6,49.56) v6(11.8,49.56) v6(12,49.56) v6(12.22,49.56) v6(12.42,49.56) v6(12.62,49.56) ; v6(41.93,37.8) v6(41.73,37.8) v6(41.53,37.8) v6(41.33,37.8) v6(41.13,37.8) v6(40.93,37.8) v6(40.73,37.8) v6(40.53,37.8) ; v6(17.64,50.6) v6(17.77,50.47) ; v6(37.73,43.8) v6(37.57,43.89) ; v6(33.88,43.17) v6(34.06,43.17) v6(34.24,43.17) ; v6(12.72,23.75) v6(12.9,23.75) ; v6(39.79,41.83) v6(39.96,41.83) v6(40.14,41.83) ; v6(34.29,39.04) v6(34.29,38.87) ; v6(59.69,49.04) v6(59.69,48.86) v6(59.69,48.68) ; v6(12.62,48.76) v6(12.42,48.76) v6(12.22,48.76) v6(12,48.76) v6(11.8,48.76) v6(11.6,48.76) ; v6(16.05,50.61) v6(16.05,50.43) ; v6(20.06,20.54) v6(20.06,20.72) ; v6(57.99,54.52) v6(58.17,54.66) ; v6(16.6,50.6) v6(16.6,50.42) ; v6(12.67,24.65) v6(12.67,24.47) ; v6(23.93,22.1) v6(23.75,22.1) v6(23.57,22.1) v6(23.39,22.1) ; v6(12.03,20.44) v6(12.03,20.26) ; v6(36.6,43.89) v6(36.6,43.72) v6(36.75,43.8) v6(36.6,43.89) ; v6(32.76,38.15) v6(32.76,38.33) v6(32.58,38.33) v6(32.76,38.15) ; v6(39.7,43.54) v6(39.78,43.39) v6(39.88,43.54) v6(39.7,43.54)
  LAYER_7 w0.175: v6(34.24,43.17) v6(34.06,43.17) v6(33.88,43.17)
  vias: v1(8.06,61.49) v1(8.06,61.31) v1(8.24,61.49) v1(8.24,61.31) v1(10.49,20.95) v1(10.49,20.77) v1(10.67,20.95) v1(10.67,20.77) v1(12.37,56.66) v1(13.22,58.82) v1(16.95,66.95) v1(16.95,66.77) v1(16.95,66.59) v1(16.94,66.41) v1(16.94,65.84) v1(16.94,65.66) v1(16.94,65.48) v1(17.13,66.95) v1(17.13,66.77) v1(17.13,66.59) v1(17.13,66.41) v1(17.12,65.84) v1(17.13,65.66) v1(17.13,65.48) v1(17.12,65.3) v1(17.31,66.95) v1(17.31,66.77) v1(17.31,66.59) v1(17.31,66.41) v1(17.3,65.84) v1(17.31,65.66) v1(17.31,65.48) v1(17.3,65.3) v1(19.08,64.77) v1(20.4,60.1) v1(21.1,62.41) v1(21.79,62.47) v1(21.79,62.29) v1(21.97,62.47) v1(21.97,62.29) v1(35.5,38.38) v1(35.68,25.97) v1(35.74,39.07) v1(35.99,38.38) v1(36.19,25.97) v1(36.95,39.29) v1(37.72,40.02) v1(37.97,42.29) v1(38.02,38.79) v1(39.92,38.38) v1(51.4,40.86) v1(52.1,40.86) v1(57.31,40.54) v1(59.88,51.86) v2(8.06,61.49) v2(8.06,61.31) v2(8.24,61.49) v2(8.24,61.31) v2(10.49,20.95) v2(10.49,20.77) v2(10.67,20.95) v2(10.67,20.77) v2(12.37,56.66) v2(13.22,58.82) v2(16.95,66.95) v2(16.95,66.77) v2(16.95,66.59) v2(16.94,66.41) v2(16.94,65.84) v2(16.94,65.66) v2(16.94,65.48) v2(17.13,66.95) v2(17.13,66.77) v2(17.13,66.59) v2(17.13,66.41) v2(17.12,65.84) v2(17.13,65.66) v2(17.13,65.48) v2(17.12,65.3) v2(17.31,66.95) v2(17.31,66.77) v2(17.31,66.59) v2(17.31,66.41) v2(17.3,65.84) v2(17.31,65.66) v2(17.31,65.48) v2(17.3,65.3) v2(19.08,64.77) v2(20.4,60.1) v2(21.1,62.41) v2(21.79,62.47) v2(21.79,62.29) v2(21.97,62.47) v2(21.97,62.29) v2(35.5,38.38) v2(35.68,25.97) v2(35.74,39.07) v2(35.99,38.38) v2(36.19,25.97) v2(36.95,39.29) v2(37.72,40.02) v2(37.97,42.29) v2(38.02,38.79) v2(39.92,38.38) v2(51.4,40.86) v2(52.1,40.86) v2(57.31,40.54) v2(59.88,51.86) v3(8.06,61.49) v3(8.06,61.31) v3(8.24,61.49) v3(8.24,61.31) v3(10.49,20.95) v3(10.49,20.77) v3(10.67,20.95) v3(10.67,20.77) v3(12.37,56.66) v3(13.22,58.82) v3(16.95,66.95) v3(16.95,66.77) v3(16.95,66.59) v3(16.94,66.41) v3(16.94,65.84) v3(16.94,65.66) v3(16.94,65.48) v3(17.13,66.95) v3(17.13,66.77) v3(17.13,66.59) v3(17.13,66.41) v3(17.12,65.84) v3(17.13,65.66) v3(17.13,65.48) v3(17.12,65.3) v3(17.31,66.95) v3(17.31,66.77) v3(17.31,66.59) v3(17.31,66.41) v3(17.3,65.84) v3(17.31,65.66) v3(17.31,65.48) v3(17.3,65.3) v3(19.08,64.77) v3(20.4,60.1) v3(21.1,62.41) v3(21.79,62.47) v3(21.79,62.29) v3(21.97,62.47) v3(21.97,62.29) v3(35.5,38.38) v3(35.74,39.07) v3(35.99,38.38) v3(36.95,39.29) v3(37.72,40.02) v3(37.97,42.29) v3(38.02,38.79) v3(39.92,38.38) v3(39.87,26.65) v3(39.88,26.47) v3(40.05,26.65) v3(40.06,26.47) v3(51.4,40.86) v3(52.1,40.86) v3(57.31,40.54) v3(59.88,51.86) v4(8.06,61.49) v4(8.06,61.31) v4(8.24,61.49) v4(8.24,61.31) v4(10.49,20.95) v4(10.49,20.77) v4(10.67,20.95) v4(10.67,20.77) v4(12.37,56.66) v4(13.22,58.82) v4(16.95,66.95) v4(16.95,66.77) v4(16.95,66.59) v4(16.94,66.41) v4(16.94,65.84) v4(16.94,65.66) v4(16.94,65.48) v4(17.13,66.95) v4(17.13,66.77) v4(17.13,66.59) v4(17.13,66.41) v4(17.12,65.84) v4(17.13,65.66) v4(17.13,65.48) v4(17.12,65.3) v4(17.31,66.95) v4(17.31,66.77) v4(17.31,66.59) v4(17.31,66.41) v4(17.3,65.84) v4(17.31,65.66) v4(17.31,65.48) v4(17.3,65.3) v4(19.08,64.77) v4(20.4,60.1) v4(21.1,62.41) v4(21.79,62.47) v4(21.79,62.29) v4(21.97,62.47) v4(21.97,62.29) v4(35.5,38.38) v4(35.74,39.07) v4(35.99,38.38) v4(36.95,39.29) v4(37.72,40.02) v4(37.97,42.29) v4(38.02,38.79) v4(39.92,38.38) v4(39.87,26.65) v4(39.88,26.47) v4(40.05,26.65) v4(40.06,26.47) v4(51.4,40.86) v4(52.1,40.86) v4(57.31,40.54) v4(59.88,51.86) v5(10.49,20.95) v5(10.49,20.77) v5(10.67,20.95) v5(10.67,20.77) v5(35.5,38.38) v5(35.74,39.07) v5(35.99,38.38) v5(36.95,39.29) v5(37.72,40.02) v5(37.97,42.29) v5(38.02,38.79) v5(39.92,38.38) v5(51.4,40.86) v5(52.1,40.86) v5(57.31,40.54) v5(59.88,51.86) v6(10.49,20.95) v6(10.49,20.77) v6(10.67,20.95) v6(10.67,20.77) v6(35.5,38.38) v6(35.74,39.07) v6(35.99,38.38) v6(36.95,39.29) v6(37.72,40.02) v6(37.97,42.29) v6(38.02,38.79) v6(39.92,38.38) v6(51.4,40.86) v6(52.1,40.86) v6(57.31,40.54) v6(59.88,51.86)
BA_N: length 33.2
  LAYER_2 w0.045: v2(21.92,50.29) 21.19,50.29 20.69,50.79 20.69,51.43 v2(20.26,51.86)
  LAYER_3 w0.045: v2(20.26,51.86) 19.66,52.46 19.66,53.6 20.03,53.98 20.03,54.77 20.16,54.9 20.16,55.52 19.72,55.96 v2(19.52,55.96) ; v4(23.14,50) 23.13,50.01 22.2,50.01 v2(21.92,50.29) ; v2(39.21,41.06) 39.21,41.08 39.15,41.08 39.04,41.19 38.64,41.19 38.56,41.12 37.93,41.12 37.65,41.4 36.71,41.4 36.58,41.53 36.58,41.62 36.38,41.81 35.93,41.81 35.46,42.29 34.68,42.29 34.43,42.54 33.42,42.54 33.24,42.72 28.23,42.72 28,42.94 27.52,42.94 27.29,43.17 24.18,43.17 24.02,43.33 v4(22.91,43.33)
  LAYER_5 w0.045: v4(22.91,43.33) 22.91,43.34 23.05,43.48 23.05,47.25 23.22,47.43 23.22,49.91 v4(23.14,50)
BATT_NEG_CONN: length 2.1
  TOP w0.05: E518.1 11.57,62.27 11.81,62.03
  LAYER_3 w0.045: E521.1 12.12,61.57 v6(12.11,61.58)
  LAYER_7 w0.175: v7(16.36,66.28) 15.34,66.28
  vias: v1(11.93,62.3) v1(11.93,62.12) v1(11.93,61.94) v1(11.93,61.76) v1(11.93,61.58) v1(12.11,62.3) v1(12.11,62.12) v1(12.11,61.94) v1(12.11,61.76) v2(11.93,62.3) v2(11.93,62.12) v2(11.93,61.94) v2(11.93,61.76) v2(11.93,61.58) v2(12.11,62.3) v2(12.11,62.12) v2(12.11,61.94) v2(12.11,61.76) v3(11.93,62.3) v3(11.93,62.12) v3(11.93,61.94) v3(11.93,61.76) v3(11.93,61.58) v3(12.11,62.3) v3(12.11,62.12) v3(12.11,61.94) v3(12.11,61.76) v4(11.93,62.3) v4(11.93,62.12) v4(11.93,61.94) v4(11.93,61.76) v4(11.93,61.58) v4(12.11,62.3) v4(12.11,62.12) v4(12.11,61.94) v4(12.11,61.76) v5(11.93,62.3) v5(11.93,62.12) v5(11.93,61.94) v5(11.93,61.76) v5(11.93,61.58) v5(12.11,62.3) v5(12.11,62.12) v5(12.11,61.94) v5(12.11,61.76) v6(11.93,62.3) v6(11.93,62.12) v6(11.93,61.94) v6(11.93,61.76) v6(11.93,61.58) v6(12.11,62.3) v6(12.11,62.12) v6(12.11,61.94) v6(12.11,61.76) v7(14.07,67.65) v7(14.07,67.46) v7(14.07,67.27) v7(14.07,67.08) v7(14.07,65.55) v7(14.07,65.36) v7(14.07,65.17) v7(14.07,64.98) v7(14.25,67.65) v7(14.25,67.46) v7(14.25,67.27) v7(14.25,67.08) v7(14.25,65.55) v7(14.25,65.36) v7(14.25,65.17) v7(14.25,64.98) v7(14.27,63.24) v7(14.43,67.65) v7(14.43,67.46) v7(14.43,67.27) v7(14.43,67.08) v7(14.43,65.55) v7(14.43,65.36) v7(14.43,65.17) v7(14.43,64.98) v7(14.4,63.61) v7(14.51,63.37) v7(14.61,67.65) v7(14.61,67.46) v7(14.61,67.27) v7(14.61,67.08) v7(14.61,65.55) v7(14.61,65.36) v7(14.61,65.17) v7(14.61,64.98) v7(14.77,63.78) v7(14.77,63.49) v7(14.78,63.24) v7(15.02,63.37) v7(15.18,63.59) v7(15.31,63.24)
BATT_PLUS: length 17.5
  TOP w0.05: U2000.133 U2000.122
  TOP w0.25: Q5500.A3 12.65,60.88 R5500.2
  LAYER_3 w0.045: v4(19.04,58.45) 19.25,58.66 19.25,59.77 19.3,59.83 v4(19.3,61.33) v4(19.3,61.51) ; v2(18.23,56.77) 18.56,56.77 18.62,56.83 18.83,56.83 18.86,56.8 18.99,56.8 19.1,56.9 19.1,57.03 18.91,57.22 v4(18.87,57.22)
  LAYER_3 w0.2: v2(6.22,61.39) 6.22,61.97 v4(5.73,62.47)
  LAYER_3 w0.3: v4(10.56,63.52) 10.26,63.52 9.49,62.75 9.49,60.89 v4(8.25,59.65)
  LAYER_5 w0.045: v4(19.04,58.45) 18.87,58.28 v4(18.87,57.22)
  LAYER_5 w0.175: v4(5.73,62.47) 6.33,61.87 6.33,60.88 7.56,59.65 v4(8.25,59.65)
  vias: v1(10.6,64.28) v1(12.72,62.18) v1(12.72,62) v1(12.72,61.82) v1(12.9,62.18) v1(12.9,62) v1(12.9,61.82) v1(13.08,62.18) v1(13.08,62) v1(13.08,61.82) v1(19.3,61.69) v1(19.48,61.69) v1(19.48,61.51) v1(19.48,61.33) v1(19.65,61.69) v1(19.65,61.51) v1(19.65,61.33) v1(19.83,61.69) v1(19.83,61.51) v1(19.83,61.33) v2(10.6,64.28) v2(12.72,62.18) v2(12.72,62) v2(12.72,61.82) v2(12.9,62.18) v2(12.9,62) v2(12.9,61.82) v2(13.08,62.18) v2(13.08,62) v2(13.08,61.82) v2(19.3,61.69) v2(19.48,61.69) v2(19.48,61.51) v2(19.48,61.33) v2(19.65,61.69) v2(19.65,61.51) v2(19.65,61.33) v2(19.83,61.69) v2(19.83,61.51) v2(19.83,61.33) v3(10.6,64.28) v3(10.56,63.88) v3(10.56,63.7) v3(10.74,63.88) v3(10.74,63.7) v3(10.74,63.52) v3(10.92,63.88) v3(10.92,63.7) v3(10.92,63.52) v3(12.72,62.18) v3(12.72,62) v3(12.72,61.82) v3(12.9,62.18) v3(12.9,62) v3(12.9,61.82) v3(13.08,62.18) v3(13.08,62) v3(13.08,61.82) v3(19.3,61.69) v3(19.48,61.69) v3(19.48,61.51) v3(19.48,61.33) v3(19.65,61.69) v3(19.65,61.51) v3(19.65,61.33) v3(19.83,61.69) v3(19.83,61.51) v3(19.83,61.33) v4(10.6,64.28) v4(10.56,63.88) v4(10.56,63.7) v4(10.74,63.88) v4(10.74,63.7) v4(10.74,63.52) v4(10.92,63.88) v4(10.92,63.7) v4(10.92,63.52) v4(12.72,62.18) v4(12.72,62) v4(12.72,61.82) v4(12.9,62.18) v4(12.9,62) v4(12.9,61.82) v4(13.08,62.18) v4(13.08,62) v4(13.08,61.82) v4(19.3,61.69) v4(19.48,61.69) v4(19.48,61.51) v4(19.48,61.33) v4(19.65,61.69) v4(19.65,61.51) v4(19.65,61.33) v4(19.83,61.69) v4(19.83,61.51) v4(19.83,61.33) v5(8.11,64.01) v5(11.23,62.95) v5(11.23,62.77) v5(11.23,62.59) v5(11.41,62.95) v5(11.41,62.77) v5(11.41,62.59) v6(8.11,64.01) v6(11.23,62.95) v6(11.23,62.77) v6(11.23,62.59) v6(11.41,62.95) v6(11.41,62.77) v6(11.41,62.59) v7(7.69,63.72) v7(7.69,63.53) v7(9.44,64.45) v7(9.45,64.01) v7(9.62,64.45) v7(9.63,64) v7(9.8,64.45) v7(9.81,64) v7(10.41,66.06) v7(10.59,66.06) v7(10.77,66.06) v7(11.23,62.95) v7(11.23,62.77) v7(11.23,62.59) v7(11.41,62.95) v7(11.41,62.77) v7(11.41,62.59) v7(12.47,67.77) v7(12.47,67.59) v7(12.47,67.41) v7(12.47,67.23) v7(12.47,67.05) v7(12.47,65.56) v7(12.47,65.38) v7(12.47,65.2) v7(12.47,65.02) v7(12.47,64.84) v7(12.65,67.77) v7(12.65,67.59) v7(12.65,67.41) v7(12.65,67.23) v7(12.65,67.05) v7(12.65,65.56) v7(12.65,65.38) v7(12.65,65.2) v7(12.65,65.02) v7(12.65,64.84) v7(12.83,67.77) v7(12.83,67.59) v7(12.83,67.41) v7(12.83,67.23) v7(12.83,67.05) v7(12.83,65.56) v7(12.83,65.38) v7(12.83,65.2) v7(12.83,65.02) v7(12.83,64.84) v7(13.01,67.77) v7(13.01,67.59) v7(13.01,67.41) v7(13.01,67.23) v7(13.01,67.05) v7(13.01,65.56) v7(13.01,65.38) v7(13.01,65.2) v7(13.01,65.02) v7(13.01,64.84)
BATT_PLUS_FLIP: length 3.7
  TOP w0.05: 28.16,66.91 J5500.R2
  TOP w0.3: 28.09,67.04 28.09,67.04 J5500.R3 ; J5500.R1 28.3,65.24 J5500.R4
  TOP w0.4: 13.66,61.97 Q5500.C3 Q5500.C2 Q5500.C1
  vias: v1(13.65,62.53) v1(13.65,62.35) v1(13.83,62.53) v1(13.83,62.35) v1(14.01,62.53) v1(14.02,62.35) v1(14.19,62.53) v1(14.2,62.35) v1(27.34,66.78) v1(27.83,65.85) v1(27.83,65.65) v1(27.84,67.23) v1(27.84,67.03) v1(27.84,66.83) v1(28.02,67.23) v1(28.02,67.03) v1(28.02,66.83) v1(28.01,65.85) v1(28.01,65.65) v1(28.2,67.23) v1(28.2,67.03) v1(28.2,66.83) v1(28.19,65.85) v1(28.19,65.65) v1(28.38,67.22) v1(28.38,67.02) v1(28.38,66.82) v1(28.37,65.85) v2(13.65,62.53) v2(13.65,62.35) v2(13.83,62.53) v2(13.83,62.35) v2(14.01,62.53) v2(14.02,62.35) v2(14.19,62.53) v2(14.2,62.35) v2(27.34,66.78) v2(27.83,65.85) v2(27.83,65.65) v2(27.84,67.23) v2(27.84,67.03) v2(27.84,66.83) v2(28.02,67.23) v2(28.02,67.03) v2(28.02,66.83) v2(28.01,65.85) v2(28.01,65.65) v2(28.2,67.23) v2(28.2,67.03) v2(28.2,66.83) v2(28.19,65.85) v2(28.19,65.65) v2(28.38,67.22) v2(28.38,67.02) v2(28.38,66.82) v2(28.37,65.85) v3(13.65,62.53) v3(13.65,62.35) v3(13.83,62.53) v3(13.83,62.35) v3(14.01,62.53) v3(14.02,62.35) v3(14.19,62.53) v3(14.2,62.35) v3(19.11,63.8) v3(19.24,63.93) v3(19.23,63.67) v3(19.37,63.79) v3(19.36,63.54) v3(19.5,63.65) v3(19.49,63.41) v3(19.64,63.52) v4(13.65,62.53) v4(13.65,62.35) v4(13.83,62.53) v4(13.83,62.35) v4(14.01,62.53) v4(14.02,62.35) v4(14.19,62.53) v4(14.2,62.35) v4(19.11,63.8) v4(19.24,63.93) v4(19.23,63.67) v4(19.37,63.79) v4(19.36,63.54) v4(19.5,63.65) v4(19.49,63.41) v4(19.64,63.52) v5(13.65,62.53) v5(13.65,62.35) v5(13.83,62.53) v5(13.83,62.35) v5(14.01,62.53) v5(14.02,62.35) v5(14.19,62.53) v5(14.2,62.35) v5(19.11,63.8) v5(19.24,63.93) v5(19.23,63.67) v5(19.37,63.79) v5(19.36,63.54) v5(19.5,63.65) v5(19.49,63.41) v5(19.64,63.52) v6(13.65,62.53) v6(13.65,62.35) v6(13.83,62.53) v6(13.83,62.35) v6(14.01,62.53) v6(14.02,62.35) v6(14.19,62.53) v6(14.2,62.35) v6(19.11,63.8) v6(19.24,63.93) v6(19.23,63.67) v6(19.37,63.79) v6(19.36,63.54) v6(19.5,63.65) v6(19.49,63.41) v6(19.64,63.52)
BATT_SENSE_M: length 10.2
  LAYER_2 w0.045: v2(14.08,60.9) 14.02,60.95 13.33,60.95 v2(12.96,60.58)
  LAYER_3 w0.045: v2(12.96,60.58) 12.96,60.89 12.53,61.32 E521.2 ; v2(19.23,57.66) 19.15,57.58 17.69,57.58 16.42,58.85 14.61,58.85 13.99,59.47 13.99,60.84 14.05,60.9 v2(14.08,60.9)
BATT_SENSE_P: length 15.4
  LAYER_3 w0.045: v4(14.01,61.31) 14.01,61.06 13.93,60.98 13.93,60.98 13.89,60.94 13.89,59.43 14.57,58.75 16.39,58.75 17.66,57.48 18.99,57.48 19.24,57.23 v2(19.27,57.23)
  LAYER_5 w0.045: E510.2 8.11,63.89 9.95,62.04 10.48,62.04 11.15,61.38 12.55,61.38 12.68,61.24 13.56,61.24 13.63,61.31 v4(14.01,61.31)
BATT_THERM: length 30.5
  TOP w0.075: C516.2 RT516.1
  LAYER_2 w0.045: v1(18.2,55.69) 18.11,55.69 17.83,55.97 17.52,55.97 17.18,55.63 16.25,55.63 16.21,55.59 15.63,55.59 15.48,55.74 v2(15.2,55.74)
  LAYER_3 w0.045: v2(15.2,41.17) 15.08,41.29 11.34,41.29 v4(11.33,41.3) ; v2(15.2,55.74) 15.2,55.85 14.87,56.18 14.16,56.18 14.07,56.27 14.07,56.46 13.68,56.85 v6(13.54,56.85)
  LAYER_5 w0.045: v6(8.11,52.53) 8.05,52.47 8.05,51.74 8.36,51.43 8.36,50.01 9.12,49.24 9.12,48.27 10.28,47.11 10.28,45.89 10.43,45.74 10.43,44.57 11.34,43.66 11.34,42.85 11.21,42.72 11.21,41.42 v4(11.33,41.3)
  LAYER_7 w0.045: v6(13.54,56.85) 13.54,55.83 13.06,55.36 12.06,55.36 9.23,52.53 v6(8.11,52.53)
BATT_THERM_BIAS: length 4.4
  LAYER_2 w0.045: v1(15.17,56.17) 15.35,55.98 16.29,55.98 16.48,56.17 17.13,56.17 17.37,56.41 17.8,56.41 17.92,56.3 17.92,56.18 18.13,55.97 18.3,55.97 18.43,55.84 18.54,55.84 18.73,56.02 v1(18.98,56.02)
BOOST_EN: length 7.4
  LAYER_3 w0.045: v2(58.93,53.1) 59.29,52.74 60.27,52.74 60.41,52.88 61,52.88 61.27,52.61 61.27,51.9 60.77,51.4 ; v2(59.88,51.4) 60.06,51.22 60.5,51.22 60.68,51.4 60.77,51.4 ; 60.77,51.4 60.77,50.18 60.9,50.05 v2(60.9,49.16)
BOOT_CONFIG_3: length 2.5
  LAYER_3 w0.045: v2(35.54,48.91) 35.46,48.98 35.46,50.09 35.94,50.56 35.94,50.74 v2(36.22,51.02)
BT_CTS_AP_RTS: length 44.8
  LAYER_2 w0.045: v1(38.44,59.73) 38.56,59.85 38.56,59.87 38.7,60.01 38.71,60.01 v2(38.73,60.04)
  LAYER_3 w0.045: v2(53.07,35.14) 53.07,35.4 53.43,35.75 53.43,36.33 53.06,36.7 53.06,37.16 52.88,37.34 52.3,37.34 v4(52.2,37.44) ; v2(38.73,60.04) 38.77,60.07 38.77,60.32 39.08,60.64 39.08,61.04 39.47,61.43 39.62,61.43 39.72,61.52 39.72,62.11 arc(39.92,62.6) 40.41,62.8 46.26,62.8 46.47,62.59 47.56,62.59 48.39,63.41 v4(48.39,63.61)
  LAYER_5 w0.045: v4(52.2,37.44) 51.99,37.65 51.99,38.37 53.31,39.69 53.31,57.93 48.39,62.86 v4(48.39,63.61)
BT_FM_SLIMBUS_CLK: length 41.1
  LAYER_3 w0.045: v4(32.69,50.53) v2(33.2,50.53)
  LAYER_5 w0.045: v6(31.48,35.73) 31.48,36.03 31.38,36.12 31.38,39.54 31.49,39.65 31.49,48.41 31.44,48.46 31.44,48.75 32.62,49.92 32.62,50.36 v4(32.69,50.53)
  LAYER_7 w0.045: v6(54.07,36.13) 53.58,36.13 51.8,37.91 49.68,37.91 46.68,34.91 31.85,34.91 31.41,35.35 31.41,35.66 v6(31.48,35.73)
BT_FM_SLIMBUS_DATA: length 40.6
  LAYER_3 w0.045: v2(33,50.72) 32.7,50.72 v4(32.65,50.77)
  LAYER_5 w0.045: v6(31.29,35.92) 31.29,39.58 31.4,39.69 31.4,48.37 31.35,48.42 31.35,48.79 32.52,49.96 32.52,50.64 v4(32.65,50.77)
  LAYER_7 w0.045: v6(53.07,36.13) 53.07,36.5 51.77,37.8 49.73,37.8 46.73,34.8 31.83,34.8 31.29,35.34 v6(31.29,35.92)
BT_RFIO_CH2: length 0.6
  TOP w0.15: R4006.2 57.02,35.43 56.69,35.43 56.53,35.59
BT_RTS_AP_CTS: length 45
  LAYER_2 w0.045: v1(38.4,59.18) v2(38.4,59.45)
  LAYER_3 w0.045: v4(51.74,36.99) 51.78,37.03 52.43,37.03 52.73,36.73 52.73,36.57 52.87,36.43 52.87,35.74 52.82,35.69 v2(52.82,35.34) ; v2(38.4,59.45) 38.46,59.52 38.46,60.14 38.57,60.24 38.57,60.41 38.89,60.73 38.89,61.12 39.29,61.52 39.29,62.03 arc(39.57,62.71) 40.25,62.99 46.34,62.99 46.55,62.78 47.49,62.78 48,63.29 v4(48,63.6)
  LAYER_5 w0.045: v4(51.74,36.99) 51.68,37.05 51.68,37.35 51.77,37.44 51.77,38.41 53.12,39.76 53.12,57.86 48,62.98 v4(48,63.6)
BT_RX_AP_TX: length 45.4
  LAYER_3 w0.045: v2(53.28,35.37) 53.39,35.48 53.63,35.48 53.73,35.57 53.73,35.71 53.64,35.8 53.64,36.39 53.25,36.78 53.25,37.26 52.96,37.55 52.67,37.55 52.53,37.69 52.37,37.69 52.33,37.65 52.16,37.65 52.05,37.75 v4(51.61,37.75) ; v2(38.15,59.43) 38.15,59.46 38.37,59.68 38.37,60.18 38.47,60.28 38.47,60.45 38.79,60.78 38.79,61.16 39.2,61.56 39.2,62.04 arc(39.5,62.78) 40.24,63.09 46.38,63.09 46.59,62.88 47.45,62.88 47.84,63.26 v4(47.84,63.42)
  LAYER_5 w0.045: v4(47.84,63.42) 47.84,63.01 53.03,57.82 53.03,39.8 51.61,38.38 v4(51.61,37.75)
BT_TX_AP_RX: length 44.9
  LAYER_3 w0.045: v4(51.86,37.19) 51.92,37.12 52.46,37.12 52.83,36.76 52.83,36.62 53.23,36.22 53.23,36.01 53.04,35.82 v2(53.04,35.62) ; v4(48.2,63.47) 48.2,63.36 47.53,62.69 46.51,62.69 46.3,62.9 40.26,62.9 arc(39.64,62.64) 39.39,62.02 39.39,61.48 38.99,61.08 38.99,60.68 38.67,60.36 38.67,60.21 38.56,60.1 38.56,59.38 38.35,59.18 v2(38,59.18)
  LAYER_5 w0.045: v4(48.2,63.47) 48.2,62.91 53.22,57.89 53.22,39.72 51.88,38.38 51.88,37.21 v4(51.86,37.19)
BUA: length 17.9
  LAYER_2 w0.045: v2(24.6,53.51) 24.6,54.11 24.38,54.33 v2(24.38,54.34) ; v2(22.49,57.96) 22.49,57.96 22.49,58 22.34,58.15 22.1,58.15 22.01,58.06 21.63,58.06 21.57,58.13 21.57,58.58 21.2,58.94 v1(21.2,59.19) ; v2(30.24,53.11) 30.43,53.11 30.5,53.17 30.91,53.17 31.45,52.64 31.64,52.64 31.67,52.68 31.85,52.68 32.01,52.52 v1(32.01,52.3)
  LAYER_3 w0.045: v2(24.38,54.34) 25.08,55.04 25.08,57.62 24.79,57.91 22.54,57.91 v2(22.49,57.96) ; v2(24.6,53.51) 24.6,53.34 25.02,52.91 25.33,52.91 25.39,52.98 28.16,52.98 28.23,53.04 30.18,53.04 v2(30.24,53.11)
CAM_F_EN: length 58.6
  TOP w0.1: J5500.57 v2(29.66,66.73)
  LAYER_2 w0.045: v2(37.57,40.97) 37.59,40.95 38.46,40.95 38.55,40.86 39.26,40.86 v2(39.46,41.06)
  LAYER_3 w0.045: v2(29.66,66.73) 29.75,66.82 29.75,67.39 29.44,67.7 28.96,67.7 28.91,67.75 28.62,67.75 28.46,67.91 v2(28.31,67.91) 28.27,67.87 28.27,67.8 28.9,67.17 28.9,65.71 v4(28.98,65.62) ; v4(45.81,41.12) 45.65,40.96 39.55,40.96 v2(39.46,41.06) ; v2(35.97,41.26) 35.97,41.05 36.17,40.86 37.45,40.86 v2(37.57,40.97)
  LAYER_5 w0.045: v4(45.81,41.12) 45.9,41.21 45.9,41.8 45.59,42.11 45.59,44.49 45.44,44.64 45.44,44.95 45.49,45 45.49,46.9 45.3,47.08 45.3,47.27 45.7,47.66 45.7,48.04 45.68,48.05 45.68,48.52 45.95,48.78 45.95,57.54 44.07,59.42 44.07,60.96 43.93,61.1 43.93,62.38 44.07,62.52 44.07,66.09 42.76,67.4 31.74,67.4 30.43,66.09 29.45,66.09 v4(28.98,65.62)
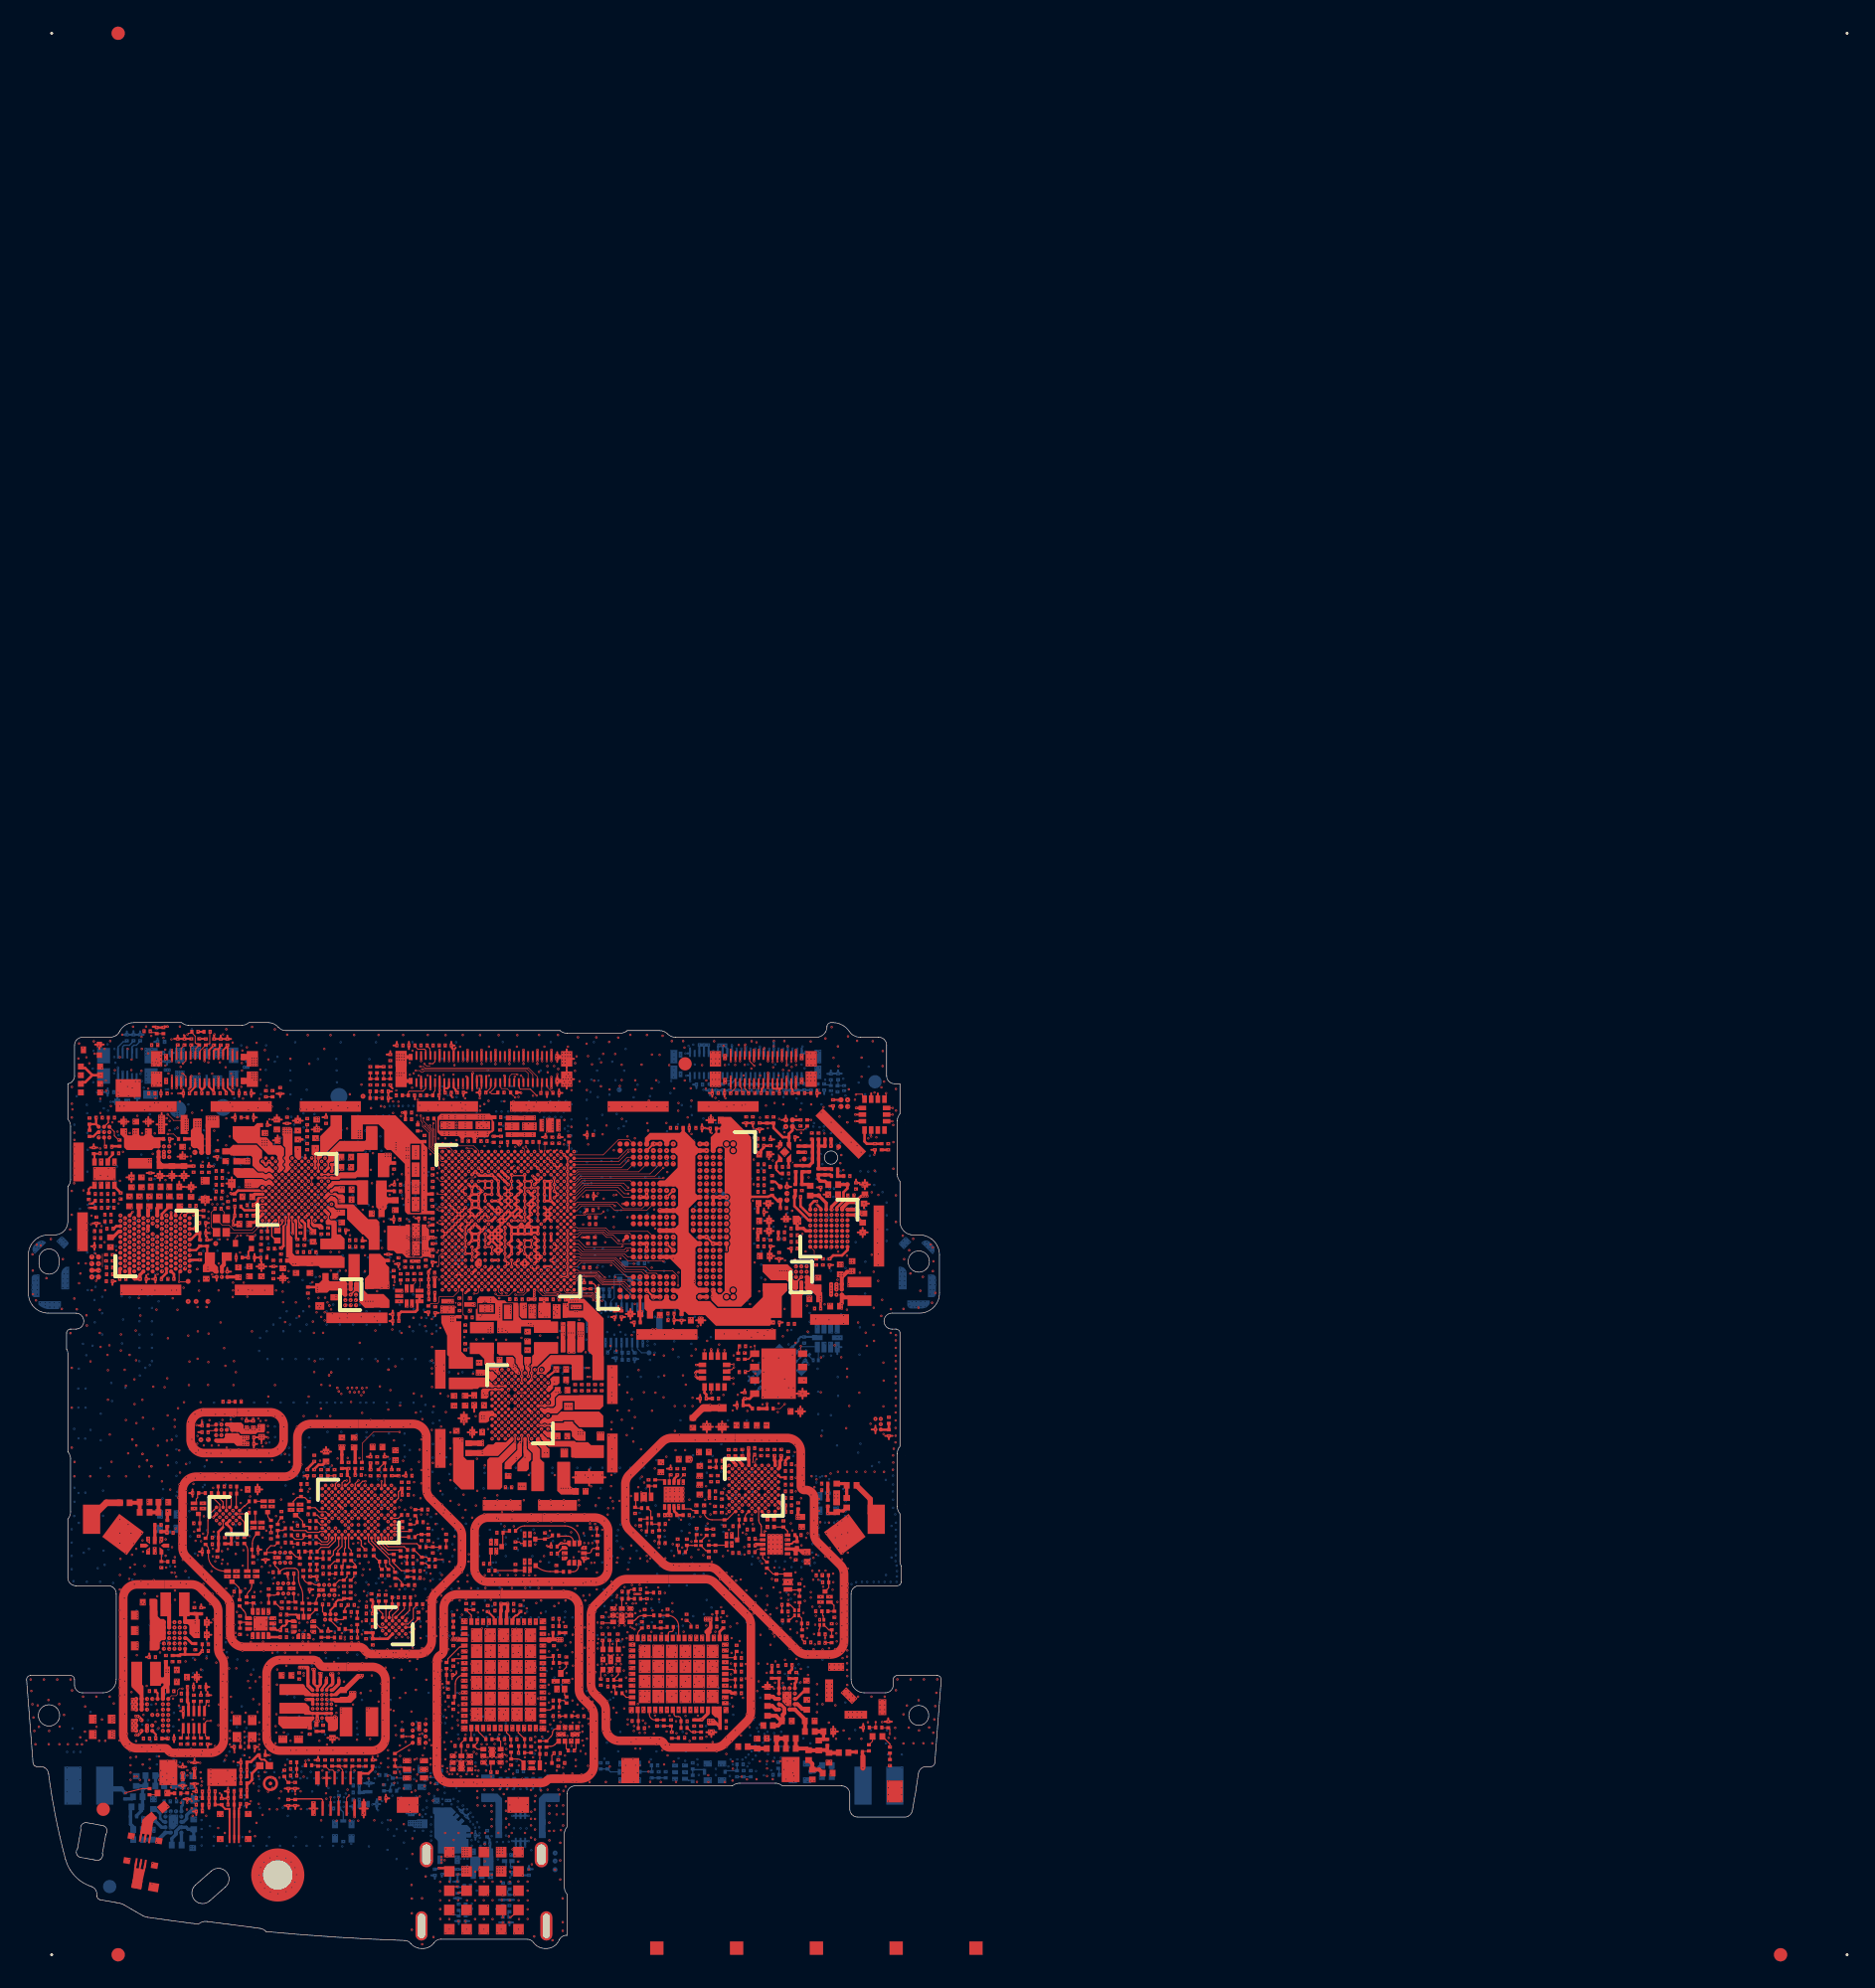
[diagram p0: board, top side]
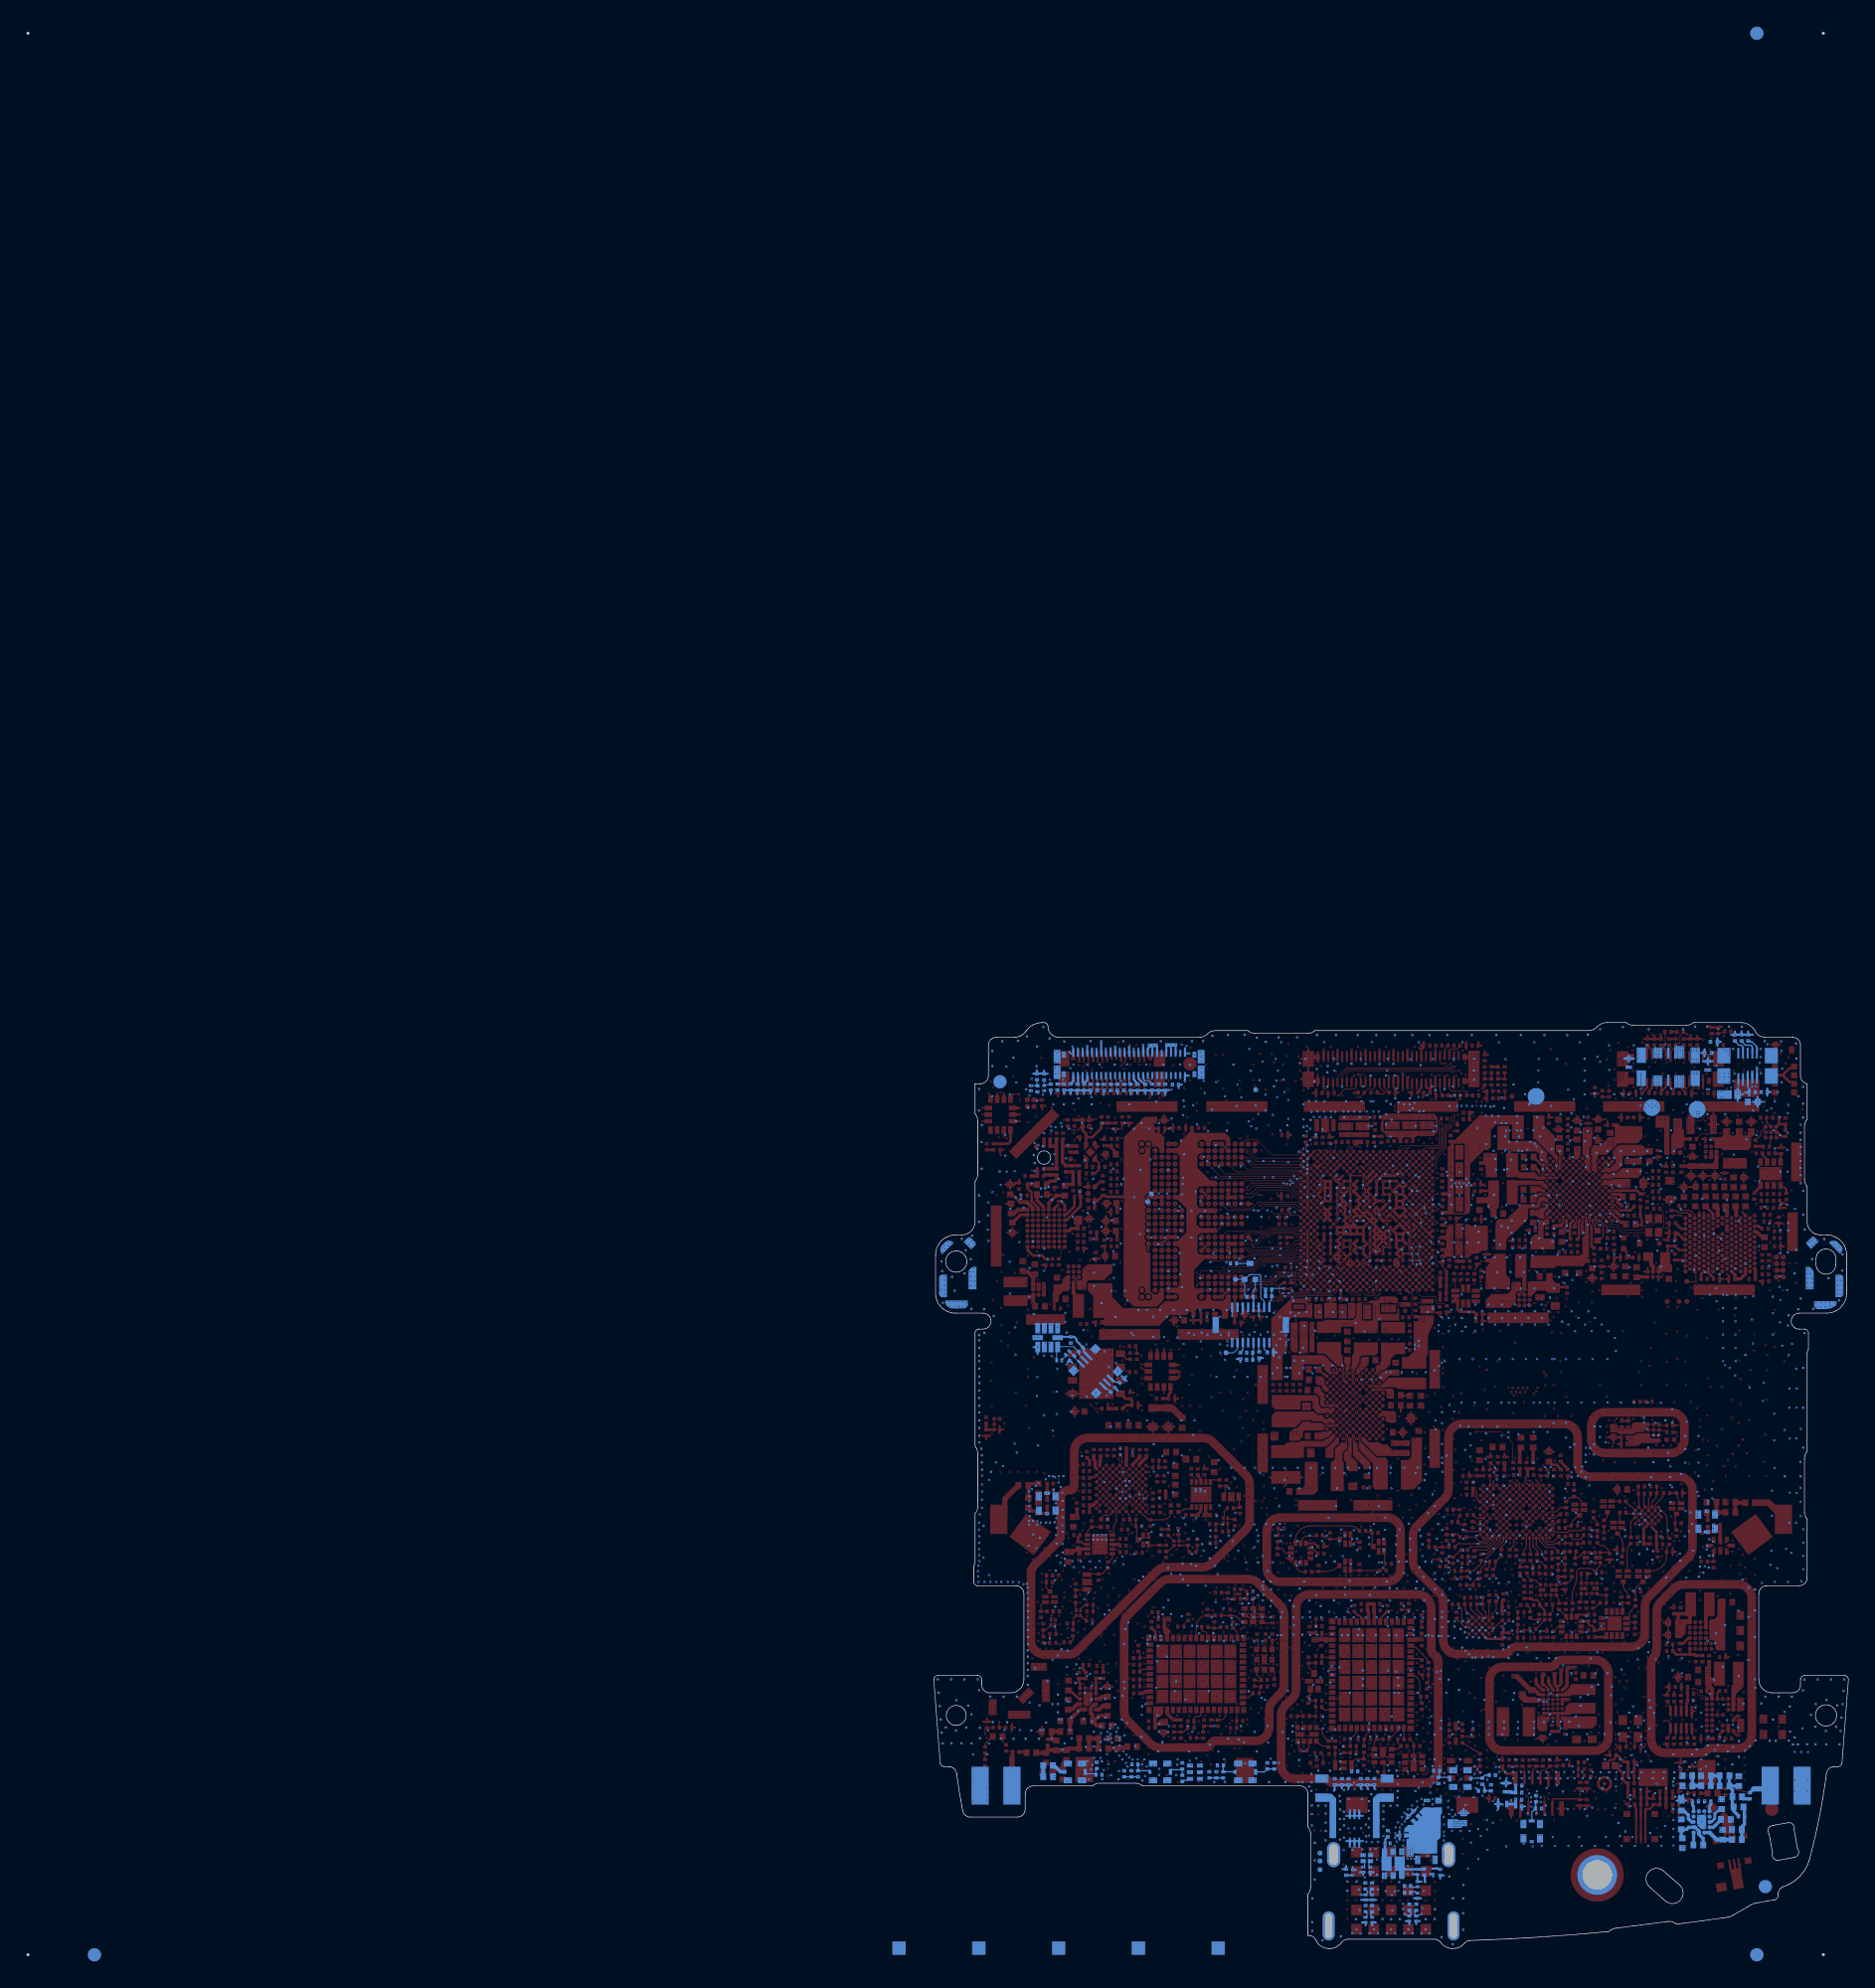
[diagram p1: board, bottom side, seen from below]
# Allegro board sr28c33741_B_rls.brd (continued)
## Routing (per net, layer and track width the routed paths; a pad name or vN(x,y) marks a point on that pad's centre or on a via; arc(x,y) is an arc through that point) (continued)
CAM_F_MCLK: length 11.8
  LAYER_3 w0.045: v2(27.76,64.13) 27.76,62.59 v4(28.04,62.31)
  LAYER_5 w0.045: v4(32.22,58.91) 32,58.91 31.86,59.05 31.5,59.05 31.41,59.15 31.15,59.15 31.03,59.03 30.79,59.03 30.75,58.98 26.7,58.98 26.31,59.38 26.31,60.46 28.04,62.19 v4(28.04,62.31)
CAM_F_MCLK_FL: length 2.6
  TOP w0.075: E5620.2 C5620.2 28.71,64.42 28.76,64.47 29.81,64.47 30.01,64.67 J5500.56
CAM_F_RST_N: length 25.1
  TOP w0.05: v2(37.17,65.64) 37.2,65.64 37.32,65.52 37.32,65.17 J5500.14
  LAYER_3 w0.045: v4(36.79,64.4) 36.79,64.5 37.03,64.74 37.03,65.5 v2(37.17,65.64)
  LAYER_5 w0.045: v4(36.79,64.4) 36.4,64.01 34.95,64.01 34.7,64.26 34.7,64.38 34.56,64.52 34.13,64.52 33.84,64.22 32.25,64.22 31.9,63.87 31.24,63.87 31.11,63.75 27.43,63.75 27.3,63.87 27.17,63.87 26.86,63.57 26.6,63.57 26.48,63.44 26.48,63.24 26.6,63.12 26.6,62.46 26.36,62.22 26.36,61.45 25.89,60.98 25.89,59.23 26.51,58.61 30.71,58.61 31.1,58.22 31.71,58.22 31.96,58.46 32.32,58.46 v4(32.5,58.64)
CAM_R_EN: length 73.4
  TOP w0.075: J5500.53 30.33,67.19 30.33,67.67 v2(30.09,67.91)
  LAYER_2 w0.045: v1(36.25,42) 35.97,42 35.61,41.64 35.61,41.64 35.54,41.57 35.54,41.45 35.38,41.3 35.25,41.3 34.83,40.88 34.83,40.8 34.83,40.7 34.71,40.58 34.22,40.58 34.03,40.76 v4(33.8,40.76)
  LAYER_3 w0.045: v4(36.05,32.75) 36.2,32.6 36.84,32.6 37.09,32.85 42.78,32.85 42.81,32.83 44.63,32.83 44.69,32.88 44.72,32.88 v4(44.78,32.83) ; v6(30.49,64.2) 30.12,64.56 30.12,66.16 29.96,66.32 29.96,67.78 v2(30.09,67.91)
  LAYER_5 w0.045: v4(36.05,32.75) 36.08,32.78 36.08,33.19 33.75,35.52 33.75,40.71 v4(33.8,40.76) ; v4(44.78,32.83) 44.78,32.91 44.92,33.05 44.92,35.14 48.51,38.73 48.51,42.34 48.4,42.45 48.4,47.2 48.43,47.22 48.43,47.44 48.29,47.58 48.29,55.99 47.31,56.97 47.31,57.77 44.73,60.35 44.73,61.23 v6(44.79,61.3)
  LAYER_7 w0.045: v6(44.79,61.3) 44.79,61.3 44.71,61.23 44.46,61.23 44.18,61.51 43.99,61.51 41.14,64.37 31.58,64.37 31.48,64.26 30.55,64.26 v6(30.49,64.2)
CAM_R_I2C_SCL: length 19.6
  TOP w0.05: J5500.18 36.71,65.17 v4(36.71,65.58) ; R1040.1 C5505.2
  LAYER_3 w0.045: v4(29.36,64.39) 29.39,64.42 29.76,64.42 29.95,64.23 29.95,63.94 30.92,62.97 31.25,62.97 31.52,62.7 31.52,62.35 31.44,62.27 31.44,61.63 31.6,61.47 31.6,61.1 31.84,60.86 31.9,60.86 32.22,60.54 32.33,60.54 32.7,60.16 32.7,60.04 32.64,59.98 32.64,59.85 32.94,59.55 32.94,59.34 32.78,59.19 v2(32.56,59.19)
  LAYER_5 w0.045: v4(26.7,64.01) 26.92,64.23 28.95,64.23 29.11,64.39 v4(29.36,64.39) 29.39,64.42 29.84,64.42 30.25,64.84 32.52,64.84 33.53,65.84 36.61,65.84 36.71,65.74 v4(36.71,65.58)
CAM_R_I2C_SDA: length 19.3
  TOP w0.05: v4(36.9,65.73) 36.88,65.75 36.48,65.75 36.31,65.59 J5500.20 ; R1039.1 C5506.2
  LAYER_3 w0.045: v2(32.8,59.91) 32.8,60.2 32.37,60.63 32.26,60.63 31.96,60.93 31.96,62.72 31.61,63.07 30.96,63.07 30.05,63.98 30.05,64.29 29.74,64.6 29.44,64.6 v4(29.43,64.61)
  LAYER_5 w0.045: v4(26.7,64.4) 26.76,64.34 28.9,64.34 29.17,64.61 v4(29.43,64.61) 29.52,64.52 29.8,64.52 30.21,64.93 32.48,64.93 33.49,65.94 36.69,65.94 v4(36.9,65.73)
CAM_R_MCLK: length 5.8
  TOP w0.05: v2(32.47,59.72) 32.47,59.71 32.5,59.71 U1001.AT2
  LAYER_3 w0.045: v2(29.59,64.1) 29.59,63.92 30.73,62.77 30.73,62.48 31.03,62.19 31.03,61.12 31.78,60.37 32.02,60.37 32.36,60.03 32.36,59.83 v2(32.47,59.72)
CAM_R_MCLK_FL: length 1.5
  TOP w0.075: J5500.52 30.71,64.5 30.62,64.4 30.62,64.23 C5680.2 30.08,64.16
CAM_R_RST_N: length 52
  TOP w0.075: J5500.16 37.05,65.09 37.05,64.71 37.14,64.62 37.88,64.62 v4(38.36,64.14)
  LAYER_5 w0.045: v6(57.48,56.6) 57.55,56.67 57.55,58.33 v6(57.47,58.41) ; v4(38.36,64.14) 38.5,64 39.78,64 40.21,64.42 v6(40.21,64.64)
  LAYER_7 w0.045: v6(57.47,58.41) 57.41,58.35 55.17,58.35 54.32,59.2 53.43,59.2 53.29,59.06 50.35,59.06 48.92,60.5 48.19,60.5 47.46,61.23 45.23,61.23 41.9,64.56 40.29,64.56 v6(40.21,64.64) ; v6(57.48,56.6) 57.41,56.53 57.41,56.26 57.08,55.92 57.01,55.92 55.59,54.5 55.59,54.34 55.21,53.97 54.74,53.97 52.33,51.55 50.24,51.55 48.89,50.2 45.1,50.2 43.4,51.9 42.68,51.9 42.28,52.3 41.35,52.3 41.17,52.48 39.14,52.48 38.77,52.11 37.36,52.11 36.91,51.66 36.91,51.3 v6(36.43,50.81)
CAM_VIO_EN: length 73.3
  TOP w0.075: J5500.55 30.01,67.55 29.93,67.63 29.42,67.63 29.21,67.84 C5550.1
  LAYER_2 w0.045: v4(33.97,40.6) 34.09,40.48 34.75,40.48 34.93,40.66 34.93,40.84 35.29,41.2 35.69,41.2 35.99,41.5 v1(35.99,41.75)
  LAYER_3 w0.045: v4(44.57,32.98) 44.57,32.92 42.85,32.92 42.82,32.95 37.05,32.95 36.81,32.71 36.36,32.71 v4(36.31,32.76) ; v6(30.23,64.22) 30.23,64.28 30.03,64.48 30.03,66.11 29.86,66.28 29.86,67.45 29.41,67.9 v2(29.18,67.9)
  LAYER_5 w0.045: v4(33.97,40.6) 33.84,40.48 33.84,35.58 36.18,33.24 36.18,32.89 v4(36.31,32.76) ; v4(44.57,32.98) 44.71,32.98 44.83,33.1 44.83,35.18 48.41,38.77 48.41,41.91 48.18,42.14 48.18,47.07 48.11,47.14 48.11,47.38 48.19,47.46 48.19,55.94 47.2,56.92 47.2,57.73 44.63,60.31 44.63,61.37 v6(44.59,61.41)
  LAYER_7 w0.045: v6(30.23,64.22) 30.37,64.36 31.44,64.36 31.54,64.46 41.18,64.46 44.03,61.61 44.23,61.61 44.43,61.41 v6(44.59,61.41)
CC_ALERT_FLIP: length 96
  TOP w0.05: v2(29.6,66.33) 29.84,66.33 29.94,66.23 37.74,66.23 38.41,65.56 J5500.8
  LAYER_2 w0.045: v2(5.22,44.46) 7.62,44.46 v2(8.19,43.89) ; v2(22.68,47.4) 22.68,45.22 21.91,44.45 v2(21.91,43.17) ; v1(31.52,51.8) 31.5,51.82 30.33,51.82 v2(30.24,51.91)
  LAYER_3 w0.045: v2(30.24,51.91) 29.84,51.91 29.74,51.81 29.47,51.81 29.08,51.42 v4(28.77,51.42) ; v2(5.22,44.46) 5.08,44.59 5.08,45 5.14,45.06 5.14,47.96 3.6,49.5 3.6,57.02 3.79,57.21 3.79,64.59 4.09,64.89 4.09,67.34 v4(4.53,67.78) ; v2(22.68,47.4) 23.01,47.4 23.33,47.72 23.33,48.99 24.8,50.46 27.87,50.46 27.99,50.34 28,50.33 28.07,50.33 28.51,49.89 v4(28.57,49.89) ; v4(28.76,67.58) 28.76,67.47 28.94,67.29 29.12,67.29 29.38,67.03 29.38,66.55 v2(29.6,66.33) ; v2(8.19,43.89) 10.57,43.89 11.35,43.11 21.85,43.11 21.91,43.16 v2(21.91,43.17)
  LAYER_5 w0.045: v4(28.77,51.42) 28.77,51.21 28.69,51.13 28.69,51.13 28.52,50.97 28.52,50.97 28.45,50.89 28.45,50.19 28.57,50.07 v4(28.57,49.89) ; v4(28.76,67.58) 28.63,67.7 18.17,67.7 17.51,68.36 15.46,68.36 14.85,68.97 9.17,68.97 8.94,68.74 8.94,68.18 8.71,67.95 5.06,67.95 4.89,67.78 v4(4.53,67.78)
CC_ALERT_M: length 68.4
  TOP w0.05: v1(39.93,49.22) 39.94,49.22 39.94,49.23 39.92,49.21 38.97,49.21 38.69,49.48 U1001.L43
  LAYER_2 w0.045: v4(9.54,44.61) 15.34,44.61 v2(15.47,44.75) ; v2(42.52,48.34) 42.52,48.47 41.98,49.01 40.73,49.01 40.52,49.22 39.94,49.22 39.94,49.22 v1(39.93,49.22)
  LAYER_3 w0.045: v2(15.47,44.75) 15.5,44.73 15.5,44.55 15.62,44.42 25.51,44.42 25.77,44.67 31.98,44.67 32.23,44.92 36.06,44.92 36.43,44.55 38.29,44.55 38.3,44.55 38.31,44.55 38.84,44.02 42.27,44.02 42.98,43.31 45.83,43.31 v4(45.85,43.29) ; v4(45.79,46.66) 45.72,46.73 45.16,46.73 43.94,47.94 42.73,47.94 42.54,48.13 42.54,48.34 v2(42.52,48.34)
  LAYER_5 w0.045: v4(45.79,46.66) 45.68,46.55 45.68,44.92 45.63,44.87 45.63,44.73 45.79,44.57 45.79,43.35 v4(45.85,43.29) ; v4(5.88,61.44) 5.88,60.82 6.08,60.62 6.08,59.09 7.36,57.81 7.36,56.86 7.54,56.68 7.54,56.17 7.02,55.65 7.02,51.77 7.78,51.01 7.78,49.42 8.46,48.74 8.46,47.98 9.61,46.83 9.61,44.68 v4(9.54,44.61)
CC_CSN_DM: length 9.5
  LAYER_3 w0.045: v4(8.26,64.69) 7.99,64.41 6.56,64.41 5.11,62.95 5.11,62.41 5.56,61.96 5.56,61.64 5.47,61.55 v2(5.47,61.04)
  LAYER_5 w0.045: v4(10.55,62.43) 10.22,62.76 9.85,62.76 8.21,64.39 8.21,64.64 v4(8.26,64.69)
CC_CSP_DP: length 10.5
  TOP w0.05: E518.2 10.63,62.71 v4(10.62,62.71)
  TOP w0.175: 5.23,61.99 U519.C3 ; 5.23,61.99 4.73,61.99 C517.1 4.73,61.74 4.74,61.73 C518.1 ; 5.23,61.99 C519.1
  LAYER_2 w0.045: v4(8.38,64.46) 9.05,64.46 v1(9.2,64.31)
  LAYER_3 w0.045: v2(5.27,62.48) 5.27,62.98 6.6,64.31 8.04,64.31 8.19,64.46 v4(8.38,64.46)
  LAYER_5 w0.045: v4(10.62,62.71) 10.42,62.71 10.27,62.86 9.88,62.86 8.5,64.24 8.5,64.34 v4(8.38,64.46)
CDC_AIF1_BCLK: length 38
  LAYER_3 w0.045: v2(11.9,52.72) 11.51,52.72 11.38,52.86 10.76,52.86 10.4,52.5 10.4,52.21 12.76,49.85 12.76,48.47 10.1,45.81 7.65,45.81 6.84,45 6.84,39.14 8.14,37.83 v2(8.25,37.83) 8.73,37.35 8.82,37.35 9.53,36.64 9.62,36.64 10.44,35.81 10.97,35.81 12.12,34.67 12.12,30.7 12.58,28.91 12.58,26.59 11.92,25.93 11.92,24.19 v2(11.86,24.13)
CDC_AIF1_LRCLK: length 39
  LAYER_3 w0.045: v2(11.29,53.52) 10.99,53.23 10.71,53.23 10.11,52.63 10.11,52.09 12.47,49.73 12.47,48.59 10,46.12 7.54,46.12 6.55,45.12 6.55,38.98 9.27,36.26 v2(9.39,36.26) 9.59,36.26 10.32,35.53 10.86,35.53 11.84,34.55 11.84,30.62 12.29,28.84 12.29,26.73 11.62,26.05 11.62,24.46 11.35,24.19 11.35,23.73 11.45,23.63 11.76,23.63 v2(11.85,23.72)
CDC_AIF1_RXDAT: length 37.8
  LAYER_3 w0.045: v2(11.51,24.12) 11.51,24.16 11.72,24.38 11.72,26.02 12.39,26.68 12.39,28.85 11.93,30.64 11.93,34.59 10.9,35.62 10.36,35.62 9.54,36.45 9.32,36.45 v2(9.06,36.71) 8.95,36.71 6.64,39.02 6.64,45.09 7.57,46.02 10.03,46.02 12.57,48.55 12.57,49.77 10.21,52.13 10.21,52.59 10.74,53.12 v2(11.29,53.12)
CDC_AIF1_TXDAT: length 38.3
  LAYER_3 w0.045: v2(11.52,23.79) 11.7,23.97 11.7,24.2 11.82,24.32 11.82,25.97 12.48,26.64 12.48,28.87 12.03,30.66 12.03,34.63 10.93,35.72 10.41,35.72 9.58,36.55 9.47,36.55 9.13,36.89 9.02,36.89 v2(8.72,37.19) 8.63,37.19 6.74,39.08 6.74,45.04 7.61,45.91 10.07,45.91 12.66,48.51 12.66,49.81 10.3,52.17 10.3,52.54 10.72,52.95 11.6,52.95 v2(11.63,52.93)
CDC_EAR_M: length 13.4
  TOP w0.15: v2(15.01,64.32) 15.01,64.45 14.78,64.68 J5502.8
  TOP w0.2: v2(10.86,55.35) 10.87,55.34 U6250.B12
  LAYER_3 w0.3: v2(10.86,55.35) 10.86,56.21 11.09,56.44 11.09,62.76 12.04,63.71 14.4,63.71 v2(15.01,64.32)
CDC_EAR_P: length 13.3
  TOP w0.15: J5502.6 15.13,64.74 15.52,64.35 C5531.2
  TOP w0.2: v2(11.21,55.37) U6250.A13
  LAYER_3 w0.3: v2(15.52,64.31) 14.56,63.35 12.21,63.35 11.46,62.6 11.46,56.31 11.21,56.07 v2(11.21,55.37)
CDC_GNDA:
  vias: v1(10.77,22.48) v1(11.48,21.55) v1(12.63,22.44) v2(10.77,22.48)
CDC_GNDP1: length 1.4
  TOP w0.175: v1(8.33,23) v1(8.33,22.81) v1(8.33,22.63)
  LAYER_3 w0.175: v3(8.32,24.18) v3(8.32,24) v3(8.32,23.82) v3(8.32,23.64)
  LAYER_4 w0.1: v3(8.32,23.64) v3(8.32,23.82) v3(8.32,24) v3(8.32,24.18)
  vias: v1(8.33,25.22) v1(8.33,25.04) v1(8.33,24.86) v1(8.61,25.89) v1(8.74,26.03) v1(8.87,25.9) v1(11.12,24.52) v1(11.12,24.12) v1(11.12,23.72) v1(11.12,23.32) v1(11.52,24.52)
CDC_INT1_N: length 34.8
  LAYER_3 w0.045: v4(23.34,45.55) 23.25,45.46 16.27,45.46 15.02,46.71 15.02,50.87 13.68,52.21 12.7,52.21 11.95,52.96 11.84,52.96 11.47,53.33 11.47,53.58 11.36,53.69 10.93,53.69 v2(10.92,53.68) ; v2(32.21,53.01) 31.36,53.01 31.19,53.17 30.53,53.17 30.31,52.95 28.3,52.95 27.96,52.6 24.55,52.6 24.14,52.19 23.34,52.19 v4(23.25,52.28)
  LAYER_5 w0.045: v4(23.34,45.55) 23.33,45.55 23.33,45.88 23.51,46.06 23.51,52.02 v4(23.25,52.28)
CDC_INT2_N: length 41.6
  LAYER_2 w0.045: v2(12.25,52.92) 12.37,53.04 v1(14.23,53.04)
  LAYER_3 w0.045: v2(12.25,52.92) 12.25,52.79 12.74,52.31 13.72,52.31 15.12,50.91 15.12,46.75 16.31,45.56 23.07,45.56 23.28,45.76 v4(23.59,45.76) ; v3(31.67,53.37) 31.61,53.43 31.09,53.43 30.9,53.62 30.25,53.62 30.13,53.74 28.75,53.74 28.68,53.81 28.42,53.81 28.29,53.67 28.29,53.42 27.94,53.08 25.36,53.08 25.29,53.01 25.07,53.01 24.76,53.33 24.76,53.58 24.47,53.86 23.37,53.86 v4(23.31,53.8)
  LAYER_4 w0.045: v4(31.52,53.76) 31.67,53.61 v3(31.67,53.37)
  LAYER_4 w0.175: v3(32.5,56.76) v4(32.67,56.81)
  LAYER_5 w0.045: v4(23.31,53.8) 23.31,52.58 23.7,52.19 23.7,45.87 v4(23.59,45.76) ; v4(32.67,56.81) 32.83,56.81 33.04,56.6 33.04,55.37 32.73,55.06 32.49,55.06 32.2,54.77 32.2,54.32 31.64,53.76 v4(31.52,53.76)
CDC_LP_GATE: length 37.4
  LAYER_3 w0.045: v4(11.93,22.62) 11.74,22.43 11.28,22.43 v2(11.12,22.59) ; v4(11.29,34.87) 10.73,35.43 10.29,35.43 9.63,36.09 9.3,36.09 6.45,38.94 6.45,45.17 7.5,46.22 9.97,46.22 12.15,48.4 v2(12.15,48.67) 12.13,48.69 12.13,49.81 10.9,51.03 10.27,51.03 v2(10.22,50.98)
  LAYER_5 w0.045: v4(11.29,34.87) 11.63,34.53 11.63,32.8 11.94,32.49 11.94,26.21 11.71,25.98 11.71,24.17 11.99,23.89 11.99,22.68 v4(11.93,22.62)
CDC_MCLK2: length 19.8
  TOP w0.075: TP_CDC_32KHZ.1 12.11,50.13 v2(11.47,50.13) 11.47,50.83 U6250.AB14
  LAYER_2 w0.045: v2(19.26,57.89) 19.32,57.83 20.16,57.83 20.78,58.45 v1(20.95,58.45)
  LAYER_3 w0.045: v6(9.54,52.02) 9.54,51.43 9.61,51.36 9.61,51.03 9.99,50.65 10.29,50.65 10.47,50.47 10.47,50.3 10.75,50.02 11.36,50.02 v2(11.47,50.13) ; v4(17.84,57.94) 19.21,57.94 v2(19.26,57.89)
  LAYER_5 w0.045: v6(16.08,58.27) 17.33,58.27 17.66,57.94 v4(17.84,57.94)
  LAYER_7 w0.045: v6(9.54,52.02) 9.56,52.02 12.35,54.81 13.25,54.81 16.08,57.65 v6(16.08,58.27)
CDC_RST_N: length 35.8
  TOP w0.05: v2(35.27,49.23) 35.42,49.08 36.25,49.08 36.63,49.46 36.64,49.46 U1001.W43
  LAYER_2 w0.045: v1(10.52,53.93) 10.7,53.75 10.7,52.83 v2(10.84,52.69)
  LAYER_3 w0.045: v2(35.27,49.23) 35.09,49.05 35.09,47.47 33.3,45.69 32.42,45.69 31.79,45.06 25.61,45.06 25.34,44.8 15.97,44.8 13.84,46.94 13.84,48.55 v2(13.72,48.67) 13.83,48.78 13.83,49.84 13.02,50.65 13.02,51.16 12.91,51.26 12.4,51.26 11.76,51.91 11.33,51.91 11.02,52.22 11.02,52.51 v2(10.84,52.69)
CDC_SLIMBUS_CLK: length 30.5
  LAYER_2 w0.045: v1(33.04,49.75) 33.16,49.63 33.16,49.22 32.91,48.97 32.91,47.9 32.48,47.48 32.48,45.75 32.41,45.67 32.41,45.38 v2(32.45,45.34)
  LAYER_3 w0.045: v2(11.58,51.66) 11.58,51.31 13.46,49.43 13.46,48.56 13.54,48.48 v2(13.54,48.24) 13.64,48.14 13.64,46.86 15.89,44.61 25.42,44.61 25.69,44.87 31.9,44.87 32.36,45.34 v2(32.45,45.34)
CDC_SLIMBUS_DATA: length 30.5
  LAYER_2 w0.045: v1(33.29,50) 33.29,49.21 33.01,48.93 33.01,47.85 32.58,47.42 v2(32.58,45.53)
  LAYER_3 w0.045: v2(32.58,45.53) 32.42,45.53 31.85,44.97 25.65,44.97 25.38,44.7 15.93,44.7 13.74,46.9 13.74,48.42 13.56,48.6 13.56,49.97 12.92,50.61 12.92,51.01 v2(12.84,51.09) 12.78,51.15 12.36,51.15 12.01,51.5 11.91,51.5 v2(11.91,51.52)
CDC_SPI_CLK: length 33
  LAYER_3 w0.045: v2(11.5,52.49) 11.5,52.36 11.66,52.2 11.89,52.2 12.53,51.55 13.03,51.55 13.32,51.26 13.32,51.25 13.32,50.77 13.33,50.76 13.33,50.76 14.14,49.95 14.14,47.05 16.1,45.08 25.23,45.08 25.49,45.34 31.65,45.34 32.3,45.99 33.19,45.99 33.96,46.76 33.96,47.6 34.3,47.94 34.3,49.13 34.96,49.79 34.96,50.57 35.23,50.84 v2(35.23,50.97)
CDC_SPI_CS_N: length 34
  LAYER_3 w0.045: v2(11.27,52.69) 11.12,52.54 11.12,52.26 11.38,52 11.81,52 12.45,51.36 12.95,51.36 13.11,51.2 13.11,50.69 13.94,49.87 13.94,46.97 16.01,44.89 25.3,44.89 25.57,45.16 31.74,45.16 32.38,45.79 33.27,45.79 34.73,47.25 34.73,49.29 35.15,49.71 35.15,50.26 35.35,50.46 35.35,50.59 v2(35.53,50.77)
CDC_SPI_MISO: length 32
  LAYER_3 w0.045: v2(11.97,52.34) 11.97,52.26 12.58,51.65 13.07,51.65 13.41,51.3 13.42,51.29 13.42,50.81 14.24,49.99 14.24,47.09 16.15,45.18 25.19,45.18 25.45,45.44 31.61,45.44 32.26,46.09 33.15,46.09 33.86,46.79 33.86,47.64 34.19,47.97 34.19,49.16 34.86,49.83 34.86,50.71 v2(34.93,50.78)
CDC_SPI_MOSI: length 32.8
  LAYER_3 w0.045: v2(11.29,52.32) 11.51,52.1 11.85,52.1 12.49,51.45 12.99,51.45 13.22,51.22 13.22,50.73 13.24,50.71 13.24,50.7 14.04,49.91 14.04,47.01 16.06,44.99 25.26,44.99 25.53,45.25 31.7,45.25 32.34,45.89 33.22,45.89 34.63,47.3 34.63,49.33 35.05,49.75 35.05,50.41 v2(35.18,50.53)
CDC_SSC_WAKE: length 57.2
  LAYER_2 w0.045: v2(10.74,52.11) 10.07,52.11 9.85,52.32 v1(9.13,52.32)
  LAYER_3 w0.045: v2(10.74,52.11) 10.74,52.01 13.15,49.6 13.15,46.27 15.48,43.94 22.01,43.94 22.29,44.23 25.6,44.23 25.86,44.48 32.06,44.48 32.31,44.73 35.99,44.73 36.36,44.36 38.23,44.36 38.76,43.83 41.55,43.83 42.17,43.2 45.67,43.2 45.74,43.13 v4(46.49,43.13) ; v4(46.48,47.77) 46.52,47.81 46.52,47.9 45.56,48.86 45,48.86 44.84,49.02 43.65,49.02 42.86,49.81 41.76,49.81 41.2,49.26 40.75,49.26 40.06,49.94 39.83,49.94 v2(39.5,50.28)
  LAYER_5 w0.045: v4(46.48,47.77) 46.52,47.73 46.52,47.12 46.69,46.95 46.69,43.96 46.55,43.82 46.55,43.2 v4(46.49,43.13)
CDC_VSNSM: length 36
  LAYER_5 w0.045: E4671.1 35.76,14.53 35.69,14.46 35.69,13.09 35.3,12.7 33.76,12.7 v6(33.67,12.79)
  LAYER_7 w0.045: v6(33.67,12.79) 33.5,12.62 33.25,12.62 31.95,13.92 16.46,13.92 15.21,15.17 15.21,16.52 15.59,16.9 15.59,17.75 15.01,18.33 11.53,18.33 9.79,20.07 9.79,22.2 10.36,22.77 10.36,22.88 10.38,22.9 v6(10.39,22.9)
CDC_VSNSP: length 35.6
  LAYER_5 w0.045: v6(33.41,12.79) 33.6,12.6 35.34,12.6 35.79,13.05 35.79,14.37 E4670.1
  LAYER_7 w0.045: v6(33.41,12.79) 33.36,12.74 33.27,12.74 31.99,14.02 16.5,14.02 15.32,15.2 15.32,16.47 15.7,16.85 15.7,17.8 15.06,18.44 11.58,18.44 9.9,20.12 9.9,22.17 10.25,22.52 10.35,22.52 10.37,22.54 v6(10.39,22.54)
CP1C1A: length 5
  TOP w0.25: v4(9.09,53.93) 9.14,53.98 9.14,54.32 U6250.E7
  LAYER_5 w0.045: 8.99,53.93 v4(9.09,53.93)
  LAYER_5 w0.3: v4(8.75,58.09) 8.75,55.3 8.45,55 8.45,54.47 8.99,53.93
CP1C1B: length 2.9
  LAYER_3 w0.3: v2(8.79,57.15) 8.79,56.48 9.53,55.74 v2(9.53,54.53)
CP1C2A: length 2.5
  LAYER_7 w0.3: v6(10.59,56.69) 10.59,56.15 v6(9.2,54.76)
CP1C2B: length 1.1
  TOP w0.2: C6285.2 10.74,55.8 10.17,55.24 U6250.B10
CP1VOUT1N: length 3
  LAYER_3 w0.25: v4(9.76,57.08) v2(9.96,57.28)
  LAYER_5 w0.3: v4(9.76,57.08) v4(9.76,54.32)
CP1VOUT1P: length 3.3
  LAYER_7 w0.3: v6(10.13,54.07) 9.13,54.07 8.57,54.62 8.57,55.25 8.14,55.69 v6(7.9,55.69)
CP1VOUT2N: length 0.8
  TOP w0.3: U6250.A9 9.83,55.66 C6287.1
CP1VOUT2P: length 2.7
  LAYER_3 w0.3: v2(9.88,54.77) 9.88,56.41 v2(10.59,57.13)
CP2CA: length 4
  LAYER_3 w0.1: v2(6.48,51.71) 6.63,51.86 6.82,51.86 7.5,52.54 8.57,52.54 9.55,53.52 v2(9.76,53.52)
CP2VOUT: length 5.2
  LAYER_5 w0.3: v4(9.09,53.56) 8.49,53.56 7.71,54.33 7.71,55.02 7.93,55.24 8.15,55.24 8.38,55.47 8.38,56.95 v4(8.05,57.28)
CXM_CMD<0>: length 45.8
  LAYER_3 w0.045: v2(38,58.69) 38.12,58.81 38.26,58.81 38.75,59.3 38.75,59.69 39,59.94 39,60.27 39.28,60.55 39.28,60.96 39.56,61.24 39.72,61.24 39.91,61.43 39.91,62.08 arc(40.06,62.46) 40.43,62.61 46.19,62.61 46.4,62.4 47.64,62.4 48.53,63.29 48.62,63.29 48.71,63.38 48.71,63.45 v4(48.72,63.61) ; v4(52.25,37.81) 52.56,37.81 52.72,37.65 52.99,37.65 53.34,37.3 53.34,36.81 53.74,36.42 53.74,36.17 54.06,35.85 v2(54.06,35.59)
  LAYER_5 w0.045: v4(52.25,37.81) 52.25,38.34 53.5,39.6 53.5,58.01 48.72,62.8 v4(48.72,63.61)
CXM_CMD<1>: length 45.3
  LAYER_3 w0.045: v4(52.44,37.53) 52.52,37.45 52.92,37.45 53.15,37.22 53.15,36.74 53.54,36.35 53.54,35.67 v2(53.57,35.64) ; v4(48.55,63.45) 47.6,62.5 46.43,62.5 46.22,62.7 40.42,62.7 arc(39.99,62.53) 39.81,62.09 39.81,61.48 39.66,61.34 39.51,61.34 39.18,61 39.18,60.59 38.9,60.31 38.9,59.97 38.66,59.73 38.66,59.34 38.26,58.95 37.77,58.95 v2(37.76,58.94)
  LAYER_5 w0.045: v4(52.44,37.53) 52.37,37.6 52.19,37.6 52.09,37.7 52.09,38.32 53.41,39.64 53.41,57.97 48.55,62.82 v4(48.55,63.45)
D_VSW_S1: length 1
  TOP w0.1: U2400.188 U2400.166 U2400.144
D_VSW_S2: length 1.1
  TOP w0.1: U2400.12 U2400.34 38.47,43.63 38.68,43.84
D_VSW_S3: length 2.2
  TOP w0.1: v1(37.97,43.75) v1(37.97,43.28) U2400.57
  TOP w0.2: U2400.57 U2400.69
  LAYER_2 w0.175: v1(37.97,42.84) v1(37.97,43.28) v1(37.97,43.75)
D_VSW_S4: length 1.9
  TOP w0.1: v1(37.23,43.53) v1(37.23,43.03) U2400.91
  LAYER_2 w0.175: v1(37.23,43.53) v1(37.23,43.03) 37.24,43.02 37.24,42.6 v1(37.23,42.59)
D_VSW_S5: length 0.8
  LAYER_2 w0.175: v1(35.25,43.48) v1(35.5,43.28) 35.47,43.26 35.44,42.85 v1(35.46,42.82)
DDR_RESET_N: length 12.8
  LAYER_3 w0.045: v2(40.71,50.07) 41.03,50.39 43.12,50.39 43.82,49.69 45.02,49.69 45.16,49.54 45.57,49.54 45.61,49.59 47.07,49.59 47.41,49.25 50.63,49.25 51.09,49.71 51.76,49.71 51.94,49.89 51.94,50.31 v2(52.13,50.5)
DDR_VDDQ: length 25.3
  TOP w0.15: v6(48.63,57) U1600.J8 ; U1600.T8 U1600.U9 ; U1600.AC5 U1600.AD6 ; U1600.A6 U1600.B5
  TOP w0.2: U1001.J19 38.94,55.23 U1001.J21 ; U1001.J19 U1001.K18 ; U1001.J19 39.43,55.23 U1001.J21 ; U1001.J19 U1001.H18 ; U1001.J21 U1001.K22 ; U1001.J21 U1001.H22 ; v2(55.89,60.37) v2(55.43,60.37) 55.43,60.22 55.22,60.01 55.22,59.86 v2(55.09,59.73)
  TOP w0.25: U1600.AD13 U1600.AD14 ; U1600.U5 U1600.T5 U1600.T4 ; U1600.AD6 U1600.AD7 ; U1600.H5 U1600.J5 U1600.J4 ; v6(47.24,60.5) v2(47.63,60.5) ; v2(50.63,60.5) v2(51.13,60.5)
  LAYER_2 w0.175: 40.4,46.87 v5(40.23,47.05) v5(40.23,46.87) 40.4,46.87 ; 40.4,46.87 v5(40.41,46.87) ; v2(49.81,47.39) v2(50,47.39) ; v5(40.24,46.31) v5(40.42,46.31) v5(40.42,46.13)
  LAYER_3 w0.175: 40.4,46.87 v5(40.23,47.05) v5(40.23,46.87) 40.4,46.87 ; 40.4,46.87 v5(40.41,46.87) ; v5(40.42,46.13) v5(40.24,46.31) v5(40.42,46.31) v5(40.42,46.13)
  LAYER_3 w0.18: v5(34.89,46.53) v5(34.71,46.53) v5(34.71,46.35) v5(34.89,46.35) v5(34.89,46.53) ; v5(34.89,46.53) v5(34.89,46.71)
  LAYER_3 w0.2: v6(42.64,61.18) 42.37,60.91 41.91,60.91 41.71,61.11 v2(40.85,61.11)
  LAYER_4 w0.175: v5(40.24,46.31) v5(40.42,46.31) v5(40.42,46.13) ; 40.4,46.87 v5(40.41,46.87) ; 40.4,46.87 v5(40.23,46.87) v5(40.23,47.05) 40.4,46.87
  LAYER_4 w0.18: v5(34.89,46.53) v5(34.89,46.35) v5(34.71,46.35) v5(34.71,46.53) v5(34.89,46.53) ; v5(34.89,46.53) v5(34.89,46.71)
  LAYER_5 w0.175: v5(40.23,47.05) 40.4,46.87 ; v5(40.23,47.05) v5(40.23,46.88) 40.4,46.87 ; v5(40.23,47.05) E1117.1 ; 40.4,46.87 v5(40.41,46.87) ; v5(40.24,46.31) v5(40.42,46.13) v5(40.42,46.31) v5(40.24,46.31)
  LAYER_5 w0.18: v5(34.89,46.53) v5(34.71,46.53) v5(34.71,46.35) v5(34.89,46.35) v5(34.89,46.53) ; v5(34.89,46.53) v5(34.89,46.71)
  LAYER_7 w0.25: v6(47.24,60.5) 43.31,60.5 v6(42.64,61.18)
  vias: v1(38.91,55.76) v1(38.89,55.21) v1(38.9,54.7) v1(39.19,55.46) v1(39.19,54.96) v1(39.42,55.77) v1(39.49,55.21) v1(39.48,54.7) v1(41.49,46.38) v1(41.49,46.2) v1(41.58,46.05) v1(41.67,46.38) v1(41.67,46.2) v1(41.76,46.05) v1(41.85,46.38) v1(41.85,46.2) v1(42.79,53.58) v1(46.2,56.59) v1(46.21,52.93) v1(46.63,56.89) v1(46.63,56.61) v1(46.63,52.89) v1(46.62,52.61) v1(46.64,49.39) v1(47.13,48.89) v1(47.63,48.89) v1(48.2,56.58) v1(48.21,52.92) v1(48.23,47.75) v1(48.62,52.58) v1(50.33,61.65) v1(50.63,48.89) v1(51.08,48.88) v1(55.43,60.83) v1(55.88,53.27) v2(38.91,55.76) v2(38.89,55.21) v2(38.9,54.7) v2(39.19,55.46) v2(39.19,54.96) v2(39.42,55.77) v2(39.49,55.21) v2(39.48,54.7) v2(41.49,46.38) v2(41.49,46.2) v2(41.58,46.05) v2(41.67,46.38) v2(41.67,46.2) v2(41.76,46.05) v2(41.85,46.38) v2(41.85,46.2) v2(42.79,53.58) v2(46.2,56.59) v2(46.21,52.93) v2(46.63,56.89) v2(46.63,56.61) v2(46.63,52.89) v2(46.62,52.61) v2(46.64,49.39) v2(47.13,48.89) v2(47.63,48.89) v2(48.2,56.58) v2(48.21,52.92) v2(48.23,47.75) v2(48.62,52.58) v2(50.33,61.65) v2(50.63,48.89) v2(51.08,48.88) v2(55.43,60.83) v2(55.88,53.27) v3(38.91,55.76) v3(38.89,55.21) v3(38.9,54.7) v3(39.19,55.46) v3(39.19,54.96) v3(39.42,55.77) v3(39.49,55.21) v3(39.48,54.7) v3(41.49,46.38) v3(41.49,46.2) v3(41.58,46.05) v3(41.67,46.38) v3(41.67,46.2) v3(41.76,46.05) v3(41.85,46.38) v3(41.85,46.2) v3(42.79,53.58) v3(46.63,56.89) v3(46.63,56.61) v3(46.63,52.89) v3(46.62,52.61) v3(48.62,52.58) v4(38.91,55.76) v4(38.89,55.21) v4(38.9,54.7) v4(39.19,55.46) v4(39.19,54.96) v4(39.42,55.77) v4(39.49,55.21) v4(39.48,54.7) v4(41.49,46.38) v4(41.49,46.2) v4(41.58,46.05) v4(41.67,46.38) v4(41.67,46.2) v4(41.76,46.05) v4(41.85,46.38) v4(41.85,46.2) v4(42.79,53.58) v4(46.63,56.89) v4(46.63,56.61) v4(46.63,52.89) v4(46.62,52.61) v4(48.62,52.58) v5(38.91,55.76) v5(38.89,55.21) v5(38.9,54.7) v5(39.19,55.46) v5(39.19,54.96) v5(39.42,55.77) v5(39.49,55.21) v5(39.48,54.7) v5(41.49,46.38) v5(41.49,46.2) v5(41.58,46.05) v5(41.67,46.38) v5(41.67,46.2) v5(41.76,46.05) v5(41.85,46.38) v5(41.85,46.2) v5(42.79,53.58) v5(46.63,56.89) v5(46.63,56.61) v5(46.63,52.89) v5(46.62,52.61) v5(48.62,52.58) v6(38.91,55.76) v6(38.89,55.21) v6(38.9,54.7) v6(39.19,55.46) v6(39.19,54.96) v6(39.19,54.42) v6(39.42,55.77) v6(39.49,55.21) v6(39.48,54.7) v6(39.58,54.11) v6(40.08,54.11) v6(40.52,55.62) v6(40.58,54.11) v6(41.1,55.22) v6(41.09,54.73) v6(41.08,54.11) v6(42.79,53.58) v6(46.63,56.89) v6(46.63,56.61) v6(46.63,52.89) v6(46.62,52.61) v6(48.62,52.58)
DISP_PWR_EN: length 37.3
  LAYER_2 w0.045: v1(32.01,53.29) 32.29,53.29 32.45,53.13 32.58,53.13 32.98,53.53 v6(33.28,53.53)
  LAYER_3 w0.045: v2(57.09,61.81) 57.77,61.81 v2(58.24,61.33) 58.44,61.13 58.44,60.86 v4(58.55,60.74)
  LAYER_5 w0.045: v6(59.16,56.75) 59.16,60.26 58.67,60.74 v4(58.55,60.74)
  LAYER_7 w0.045: v6(33.28,53.53) 34.46,53.53 34.59,53.66 34.81,53.66 34.84,53.63 41.68,53.63 41.87,53.45 42.26,53.45 42.56,53.14 44.14,53.14 45.87,51.41 48.66,51.41 50.95,53.7 52.91,53.7 53.27,54.06 55.18,54.06 55.5,54.38 55.5,54.54 56.98,56.02 57.03,56.02 57.32,56.31 57.32,56.66 57.42,56.76 57.58,56.76 57.64,56.7 59.11,56.7 v6(59.16,56.75)
DISP_SUB_AVDD_EN: length 50.5
  TOP w0.075: J5501.22 v2(54.35,64.7)
  LAYER_2 w0.045: v1(31.77,53.53) 31.77,53.73 31.28,54.22 30.95,54.22 30.22,54.95 v2(30.22,55.11)
  LAYER_3 w0.045: v4(24.2,58.39) 24.26,58.33 25.86,58.33 27.3,56.89 27.54,56.89 28.74,55.69 29.87,55.69 29.97,55.58 29.97,55.35 v2(30.22,55.11) ; v2(54.35,64.7) 54.15,64.9 52.56,64.9 v2(52,64.34) 51.88,64.46 46.27,64.46 v4(46.2,64.53)
  LAYER_5 w0.045: v4(24.2,58.39) 24.26,58.45 24.26,62.07 24,62.33 24,63.08 23.75,63.34 23.75,64.61 24.99,65.85 28.55,65.85 29.2,66.5 30,66.5 30.3,66.8 30.85,66.8 31.66,67.61 43.48,67.61 45.53,65.56 45.53,65.2 v4(46.2,64.53)
DISP_SUB_DSI1<0>: length 49.5
  TOP w0.05: v2(36.76,49.17) 36.8,49.13 37.36,49.13 37.7,49.47 U1001.R43
  TOP w0.088: J5501.11 56.1,66.67 v2(56.1,66.66)
  LAYER_3 w0.045: v2(36.76,49.17) 36.76,49.07 36.58,48.89 36.58,48.59 36.61,48.55 36.61,47.52 37.7,46.44 38.59,46.44 39.99,45.03 43.2,45.03 43.39,44.84 43.96,44.84 v4(44.03,44.91) ; v4(42.33,65.77) 42.4,65.84 55.11,65.84 55.51,66.24 55.51,66.98 55.88,67.34 56.06,67.34 56.23,67.18 56.23,66.78 v2(56.1,66.66)
  LAYER_5 w0.045: v4(42.33,65.77) 42.25,65.69 42.25,65.32 41.9,64.97 41.9,59.07 43.92,57.05 43.92,45.36 44,45.28 44,44.94 v4(44.03,44.91)
DISP_SUB_DSI1<1>: length 49.4
  TOP w0.05: U1001.T42 37.45,49.43 37.32,49.29 37.05,49.29 36.99,49.35 36.97,49.35 v2(36.96,49.36)
  TOP w0.088: J5501.9 56.45,66.72 v2(56.46,66.71)
  LAYER_3 w0.045: v2(56.46,66.71) 56.46,66.71 56.32,66.85 56.32,67.21 56.1,67.44 55.84,67.44 55.42,67.02 55.42,66.28 55.08,65.94 42.25,65.94 v4(42.09,65.78) ; v2(36.96,49.36) 36.96,49.12 36.68,48.84 36.68,48.84 36.68,48.62 36.71,48.59 36.71,47.56 37.73,46.54 38.62,46.54 40.03,45.13 43.24,45.13 43.43,44.93 43.73,44.93 v4(43.82,45.02)
  LAYER_5 w0.045: v4(43.82,45.02) 43.82,45.02 43.9,45.1 43.9,45.24 43.82,45.32 43.82,57.01 41.8,59.03 41.8,65.01 42.15,65.36 42.15,65.72 v4(42.09,65.78)
DISP_SUB_DSI1<2>: length 48.5
  TOP w0.088: v2(57.16,66.4) 57.15,66.41 J5501.5
  LAYER_3 w0.045: v4(43.5,45.09) 43.49,45.09 43.31,45.27 40.18,45.27 38.11,47.34 37.26,47.34 36.84,47.77 36.84,48.54 37,48.7 37,48.97 37.21,49.19 37.21,49.59 37.08,49.73 v2(36.96,49.73) ; v4(41.88,65.37) 41.9,65.39 41.9,65.41 41.95,65.45 42.47,65.45 42.55,65.53 56.02,65.53 57.07,66.58 57.29,66.58 57.36,66.52 57.36,66.45 57.3,66.39 57.17,66.39 v2(57.16,66.4)
  LAYER_5 w0.045: v4(43.5,45.09) 43.65,45.24 43.65,56.95 41.59,59.01 41.59,65.19 41.77,65.37 v4(41.88,65.37)
DISP_SUB_DSI1<3>: length 48.2
  TOP w0.088: v2(57.5,66.68) 57.5,67.16 J5501.3
  LAYER_3 w0.045: v4(41.88,65.63) 41.96,65.55 42.43,65.55 42.51,65.62 55.98,65.62 57.03,66.68 v2(57.5,66.68) ; v2(36.76,50.03) 36.89,49.9 37.04,49.9 37.31,49.63 37.31,49.15 37.09,48.93 37.09,48.66 36.93,48.5 36.93,47.81 37.3,47.44 38.15,47.44 40.22,45.37 43.45,45.37 v4(43.48,45.34)
  LAYER_5 w0.045: v4(43.48,45.34) 43.55,45.4 43.55,56.91 41.49,58.97 41.49,65.23 v4(41.88,65.63)
DISP_SUB_DSI1<4>: length 51.6
  TOP w0.088: v2(55.06,67.58) 55.06,67.17 J5501.17
  LAYER_3 w0.045: v4(43.38,45.62) 43.27,45.62 43.15,45.49 40.3,45.49 38.23,47.56 37.38,47.56 37.07,47.88 37.07,48.44 37.23,48.6 37.36,48.6 37.51,48.74 37.51,49.71 v2(37.19,50.02) ; v2(55.06,67.58) 55.06,67.47 55.14,67.39 55.25,67.39 55.32,67.46 55.32,67.59 55.11,67.79 54.5,67.79 54.35,67.64 54.35,66.35 54.11,66.11 48.07,66.11 47.95,66.24 47.95,66.87 47.89,66.92 47.82,66.92 47.76,66.87 47.76,66.2 47.68,66.11 47.52,66.11 47.39,66.24 47.39,66.87 47.34,66.92 47.27,66.92 47.21,66.87 47.21,66.2 47.12,66.11 46.97,66.11 46.84,66.24 46.84,66.87 46.79,66.92 46.71,66.92 46.66,66.87 46.66,66.2 46.57,66.11 42.09,66.11 41.55,65.57 v4(41.55,65.57)
  LAYER_5 w0.045: v4(41.55,65.57) 41.49,65.57 41.3,65.37 41.3,58.91 43.35,56.86 43.35,45.65 v4(43.38,45.62)
DISP_SUB_DSI1<5>: length 51.7
  TOP w0.088: J5501.15 55.4,67.64 v2(55.47,67.71)
  LAYER_3 w0.045: v4(41.52,65.8) 41.54,65.78 41.62,65.78 42.05,66.21 46.53,66.21 46.57,66.24 46.57,66.91 46.67,67.02 46.83,67.02 46.94,66.91 46.94,66.28 47.01,66.21 47.08,66.21 47.12,66.24 47.12,66.91 47.23,67.02 47.38,67.02 47.49,66.91 47.49,66.28 47.56,66.21 47.64,66.21 47.67,66.24 47.67,66.91 47.78,67.02 47.93,67.02 48.04,66.91 48.04,66.28 48.11,66.21 54.08,66.21 54.26,66.39 54.26,67.68 54.47,67.89 55.15,67.89 55.33,67.71 v2(55.47,67.71) ; v4(43.18,45.75) 43.17,45.74 43.17,45.72 43.17,45.72 43.17,45.66 43.11,45.59 40.34,45.59 38.27,47.66 37.42,47.66 37.16,47.92 37.16,48.4 37.26,48.5 37.4,48.5 37.6,48.7 37.6,49.75 37.4,49.95 37.4,50.07 37.24,50.24 v2(37,50.24)
  LAYER_5 w0.045: v4(43.18,45.75) 43.25,45.82 43.25,56.82 41.2,58.87 41.2,65.41 41.38,65.6 41.38,65.67 v4(41.52,65.8)
DISP_SUB_PWR_EN: length 36.9
  TOP w0.075: J5501.24 54,64.69 54.21,64.48 54.21,64.34 v4(54.27,64.28)
  LAYER_3 w0.045: v2(33.04,58.73) 33.04,58.89 33.16,59.01 33.16,59.34 33.04,59.46 33.04,60.01 32.94,60.11 32.94,60.2 32.5,60.64 32.5,60.88 32.38,61 32.27,61 32.06,61.21 32.06,62.78 31.38,63.45 v6(31.38,63.52)
  LAYER_5 w0.045: v6(53.61,59.03) 53.52,59.12 53.52,62.47 53.88,62.83 53.88,63.9 v4(54.27,64.28)
  LAYER_7 w0.045: v6(53.61,59.03) 53.53,58.96 50.32,58.96 48.88,60.4 48.15,60.4 47.42,61.13 44.42,61.13 44.15,61.4 43.97,61.4 41.11,64.26 32.12,64.26 v6(31.38,63.52)
DISP_SUB_RST_N: length 48.6
  TOP w0.075: v4(53.85,64.34) 53.76,64.43 53.76,64.7 53.68,64.78 53.68,65.09 J5501.26
  LAYER_5 w0.045: v6(53.92,58.25) 53.74,58.43 53.74,58.61 53.43,58.92 53.43,62.52 53.79,62.88 53.79,64.28 v4(53.85,64.34) ; v6(26.1,61.45) 26.1,61.36 25.79,61.05 25.79,59.19 26.47,58.51 30.67,58.51 30.98,58.19 30.98,58.19 31.06,58.12 31.75,58.12 31.99,58.36 32.38,58.36 32.5,58.48 v4(32.72,58.48)
  LAYER_7 w0.045: v6(53.92,58.25) 53.85,58.18 50.39,58.18 48.65,59.92 43.1,59.92 41.81,61.21 41.81,61.36 41.81,62.05 40.53,63.33 34.8,63.33 33.7,62.23 30.54,62.23 30.29,61.98 27.25,61.98 26.63,61.36 26.18,61.36 v6(26.1,61.45)
DISP_SUB_TE: length 40.9
  TOP w0.075: C5530.2 v4(52.98,64.29) 52.98,64.39 53.3,64.71 53.3,65.12
  LAYER_3 w0.045: v4(58.77,61.02) 58.64,61.14 58.64,62.51 58.26,62.89 56.46,62.89 56.17,63.18 v4(53.34,63.18)
  LAYER_5 w0.045: v4(58.77,61.02) 58.77,60.79 59.26,60.3 59.26,56.88 59.39,56.75 v6(59.39,56.74) ; v4(52.98,64.29) 53.03,64.29 53.34,63.98 v4(53.34,63.18)
  LAYER_7 w0.045: v6(59.39,56.74) 59.24,56.59 58.04,56.59 57.18,55.73 57.09,55.73 55.78,54.42 55.78,54.26 55.29,53.77 54.83,53.77 52.41,51.36 50.32,51.36 48.97,50 45.03,50 43.32,51.71 42.6,51.71 42.21,52.1 41.28,52.1 41.09,52.29 39.22,52.29 38.85,51.92 37.44,51.92 37.1,51.58 37.1,51.08 v6(37.16,51.03)
DISP_TE_FL: length 3.7
  LAYER_7 w0.045: v7(56.54,65.39) 56.88,65.74 58.38,65.74 59.01,65.11 v7(59.01,65.02)
  BOTTOM w0.05: J5300.11 v7(56.54,65.39)
  BOTTOM w0.075: E5302.2 59.02,65.01 v7(59.01,65.02)
DISP_V1_EN: length 53.1
  LAYER_3 w0.045: v6(34.47,55) 34.61,54.86 34.61,54.7 34.41,54.51 34.31,54.51 33.57,53.77 33.25,53.77 32.61,53.13 32.37,53.13 32.2,53.3 31.95,53.3 31.83,53.18 31.55,53.18 v2(31.47,53.26)
  LAYER_5 w0.045: v6(58.81,64.71) 58.78,64.68 58.78,63.92 58.63,63.77 58.63,62.09 57.94,61.4 57.94,57.15 v6(58.03,57.05) ; v4(61.84,63.32) 61.72,63.2 v4(61.72,62.13) 61.72,60.53 61.99,60.26 61.99,57.78 60.9,56.69 v6(60.9,56.34)
  LAYER_7 w0.045: v6(60.9,56.34) 60.29,56.34 59.49,57.14 58.69,57.14 58.6,57.05 v6(58.03,57.05) 57.95,57.13 55.35,57.13 55.22,57 49.88,57 48.43,58.45 41.77,58.45 40.12,56.8 36.27,56.8 v6(34.47,55) ; v7(60.54,64.52) 60.81,64.25 61.19,64.25 v7(61.45,64.5) 60.93,65.02 60.13,65.02 59.99,64.88 59.86,64.88 59.7,65.04 59.4,65.04 59.11,64.75 58.85,64.75 v6(58.81,64.71)
DISP_VCI_FL: length 3.9
  TOP w0.15: v2(60.64,63.82) U5301.A1
  LAYER_3 w0.2: v7(58.52,64.98) 59.47,64.98 v2(60.64,63.82)
  BOTTOM w0.15: J5300.1 58.29,65.24 58.48,65.05 C5322.2
DISP_VIO_FL: length 4.1
  TOP w0.2: v4(58.2,62.29) 58.18,62.31 U5300.A1
  LAYER_5 w0.2: v4(58.2,62.29) 58.26,62.35 58.26,64.53 58.04,64.75 v7(58.04,65.03)
  BOTTOM w0.15: J5300.3 57.94,65.04 C5316.2
DRX_ASM_HB_50R: length 1.7
  TOP w0.088: 42.92,30.09 C7526.2 ; 42.92,30.09 42.64,30.09 arc(42.52,30.04) 42.48,29.93 arc(42.42,29.79) 42.28,29.74 U7520.11 ; 42.92,30.09 L7627.2
DRX_ASM_MB_50R: length 0.8
  TOP w0.088: U7510.11 21.81,24.21 C7517.1
DRX_ASM_ULB_LB_50R: length 1.1
  TOP w0.088: U7500.9 16.6,24.53 L7505.2 C7505.2
DRX_B7_FLT_IN_50R: length 2.2
  TOP w0.088: R7800.2 39.86,28.33 L7801.2 39.35,28.35 arc(38.77,28.47) FL7800.1
DRX_B40_FLT_OUT_50R: length 12.6
  TOP w0.088: L7820.2 34.89,28.99 34.89,29.86 FL7820.4
  LAYER_7 w0.045: v6(34.84,28.88) 34.74,28.88 34.74,28.88 23.55,28.88 arc(23.38,28.85) v6(23.24,28.75)
DRX_B41FB_B38_FLT_IN_50R: length 1.4
  TOP w0.088: FL7830.1 L7831.2 39.05,30.86 39.17,30.86 arc(39.31,30.89) 39.44,30.97 C7830.2
DRX_B41FB_B38_FLT_OUT_50R: length 14.9
  TOP w0.088: L7833.2 37.05,30.57 37.15,30.47 37.33,30.47 37.35,30.46 FL7830.4
  LAYER_7 w0.045: v6(22.8,29.86) 27.12,29.86 arc(27.54,29.94) 27.9,30.18 arc(28.37,30.5) 28.93,30.61 v6(36.75,30.61)
DRX_DIP_MB_MAT_50R: length 1
  TOP w0.088: C7517.2 22.17,23.4 L7516.2 23.15,23.4 C7515.1
EBI0_CA<0>: length 11.6
  LAYER_3 w0.045: v2(51.13,57.61) 50.93,57.8 50.33,57.8 50.14,58 48.27,58 48.06,57.79 47.64,57.79 47.42,58.01 43.87,58.01 42.82,56.97 40.79,56.97 40.54,56.71 v2(40.42,56.71)
EBI0_CA<1>: length 11.4
  LAYER_3 w0.045: v2(50.57,58.06) 50.32,58.31 43.88,58.31 42.75,57.18 40.66,57.18 40.5,57.02 40.34,57.02 40.24,57.12 40.24,57.12 40.15,57.2 v2(39.93,57.2)
EBI0_CA<2>: length 11.1
  LAYER_3 w0.045: v2(50.63,59.5) 50.35,59.78 46.81,59.78 46.69,59.66 44.09,59.66 42.96,58.53 40.26,58.53 v2(40.18,58.44)
EBI0_CA<3>: length 10.7
  LAYER_3 w0.045: v2(50.57,58.95) 50.52,58.9 43.9,58.9 42.63,57.63 40.49,57.63 v2(40.42,57.7)
EBI0_CA<4>: length 10.9
  LAYER_3 w0.045: v2(50.58,58.55) 50.51,58.62 43.91,58.62 42.7,57.41 40.24,57.41 40.19,57.45 v2(40.18,57.45)
EBI0_CA<5>: length 11.9
  LAYER_3 w0.045: v2(51.61,59.4) 50.97,59.4 50.48,59.89 46.78,59.89 46.64,59.76 44.06,59.76 42.94,58.64 40.47,58.64 v2(40.42,58.69)
EBI0_CKE_0: length 13.2
  LAYER_3 w0.045: v2(52.13,58.5) 51.79,58.84 51.57,58.84 51.14,59.27 50.94,59.27 50.87,59.34 50.55,59.34 50.23,59.67 46.86,59.67 46.75,59.56 44.13,59.56 43,58.43 40.39,58.43 40.15,58.2 v2(39.98,58.2)
EBI0_CKE_1: length 12.7
  LAYER_3 w0.045: v2(40.18,56.96) 40.26,56.87 40.51,56.87 40.71,57.07 42.78,57.07 43.88,58.17 50.15,58.17 50.43,57.9 51.64,57.9 51.74,58 v2(52.13,58)
EBI0_CLK_M: length 12.8
  LAYER_3 w0.045: v2(40.18,56.46) 40.5,56.46 40.62,56.34 42.81,56.34 44.13,57.66 47.36,57.66 47.55,57.47 50.73,57.47 50.93,57.27 51.89,57.27 v2(52.13,57.5)
EBI0_CLK_P: length 12.9
  LAYER_3 w0.045: v2(52.13,57.11) 52.09,57.15 50.88,57.15 50.65,57.38 47.51,57.38 47.32,57.56 44.18,57.56 42.86,56.25 40.58,56.25 40.5,56.33 40.3,56.33 40.22,56.24 v2(39.98,56.24)
EBI0_CS_0: length 12.3
  LAYER_3 w0.045: v2(39.93,57.7) 40.18,57.7 40.35,57.53 42.69,57.53 43.92,58.76 50.66,58.76 50.92,58.5 v2(51.53,58.5)
EBI0_CS_1: length 11.9
  LAYER_3 w0.045: v2(51.63,58.11) 50.76,58.11 50.41,58.46 43.88,58.46 42.72,57.29 40.51,57.29 v2(40.42,57.2)
EBI0_DM<0>: length 6
  TOP w0.05: U1001.B8 41.25,58.2 41.47,58.41 46.03,58.41 U1600.D5
EBI0_DM<1>: length 5.2
  TOP w0.05: U1600.H3 45.07,57 44.69,57.39 41.91,57.39 41.23,56.71 U1001.B14
EBI0_DQ<0>: length 5.3
  TOP w0.05: U1600.A3 45.3,60.83 44.51,60.83 43.36,59.68 U1001.B2
EBI0_DQ<1>: length 4.8
  TOP w0.05: U1600.B3 45.52,60.11 45.19,60.11 44.51,59.43 U1001.A3
EBI0_DQ<2>: length 4.7
  TOP w0.05: U1001.A5 44.6,58.94 45.17,59.5 U1600.C3
EBI0_DQ<3>: length 4.7
  TOP w0.05: U1001.A7 41.3,58.44 41.42,58.56 45.18,58.56 U1600.D3
EBI0_DQ<4>: length 7.1
  TOP w0.05: v2(45.27,59.93) 45.26,59.93 44.51,59.19 U1001.B4
  LAYER_3 w0.045: v2(45.27,59.93) 45.34,59.86 46.58,59.86 46.73,60.01 47.59,60.01 v2(47.63,60.05)
EBI0_DQ<5>: length 6.5
  TOP w0.05: v2(45.26,59.27) 44.71,58.72 40.95,58.72 U1001.B6
  LAYER_3 w0.045: v2(47.13,59.39) 47.09,59.35 45.35,59.35 v2(45.26,59.27)
EBI0_DQ<6>: length 6.9
  TOP w0.05: U1600.D7 46.87,58.25 41.53,58.25 41.22,57.95 U1001.A9
EBI0_DQ<7>: length 8.2
  TOP w0.05: U1001.B10 41.26,57.7 41.64,58.08 47.25,58.08 v1(47.88,58.71)
  LAYER_2 w0.045: v1(47.88,58.71) 47.88,59.14 v1(48.13,59.39)
EBI0_DQ<8>: length 5.9
  TOP w0.05: U1600.K5 46.26,55.64 44.87,55.64 44.38,56.13 41.4,56.13 41.23,55.97 U1001.A17
EBI0_DQ<9>: length 6.5
  TOP w0.05: U1001.A19 41.36,55.47 41.74,55.85 43.88,55.85 44.21,55.52 46.65,55.52 47.13,56 U1600.K6
EBI0_DQ<10>: length 5
  TOP w0.05: v2(44.24,55.84) 44.09,55.99 41.59,55.99 41.32,55.72 U1001.B18
  LAYER_3 w0.045: v2(44.24,55.84) 44.4,55.68 45.4,55.68 v2(45.63,55.91)
EBI0_DQ<11>: length 5.3
  TOP w0.05: U1600.J3 44.87,56.5 44.34,57.04 42.05,57.04 41.23,56.22 U1001.B16
EBI0_DQ<12>: length 7.2
  TOP w0.05: U1001.A15 41.22,56.46 41.99,57.23 44.49,57.23 44.96,56.76 v2(45.24,56.76)
  LAYER_3 w0.045: v2(45.24,56.76) 45.79,56.76 46.14,56.41 47.53,56.41 v2(47.63,56.5)
EBI0_DQ<13>: length 5
  TOP w0.05: U1600.G3 45.39,57.74 41.78,57.74 41.24,57.2 U1001.B12
EBI0_DQ<14>: length 6.4
  TOP w0.05: v2(45.24,57.22) 44.9,57.56 41.82,57.56 41.21,56.96 U1001.A13
  LAYER_3 w0.045: v2(47.13,57) 46.91,57.22 v2(45.24,57.22)
EBI0_DQ<15>: length 8
  TOP w0.05: U1001.A11 41.23,57.45 41.71,57.93 47.87,57.93 v4(47.89,57.95)
  LAYER_5 w0.045: v4(48.13,57) 48.13,57.71 v4(47.89,57.95)
EBI0_DQS_0_M: length 8.9
  LAYER_3 w0.045: v2(40.18,57.95) 42.81,57.95 43.88,59.02 48.54,59.02 v2(48.63,59.11)
EBI0_DQS_0_P: length 8.9
  LAYER_3 w0.045: v2(48.62,59.51) 48.49,59.56 46.89,59.56 46.8,59.47 44.2,59.47 42.77,58.05 40.57,58.05 v2(40.42,58.2)
EBI0_DQS_1_M: length 8.7
  LAYER_3 w0.045: v2(40.41,56.16) 40.6,55.97 43.37,55.97 43.83,56.43 45.74,56.43 46.03,56.13 48.37,56.13 v2(48.63,56.39)
EBI0_DQS_1_P: length 8.8
  LAYER_3 w0.045: v2(40.18,55.97) 40.27,55.88 43.43,55.88 43.89,56.34 45.69,56.34 46,56.02 48.61,56.02 v2(48.63,56)
EBI1_CA<0>: length 11.4
  LAYER_3 w0.045: v2(51.13,51.89) 51.01,51.77 50.46,51.77 50.2,51.51 44.79,51.51 43.87,52.43 40.78,52.43 40.46,52.75 40.42,52.75 v2(40.39,52.72)
EBI1_CA<1>: length 11.2
  LAYER_3 w0.045: v2(39.93,52.26) 39.97,52.21 40.21,52.21 40.28,52.13 43.76,52.13 44.68,51.22 50.39,51.22 50.57,51.39 v2(50.63,51.39)
EBI1_CA<2>: length 11.1
  LAYER_3 w0.045: v2(50.63,49.89) 50.4,49.66 47.94,49.66 47.3,50.3 44.17,50.3 43.6,50.87 40.63,50.87 40.48,51.02 v2(40.23,51.02)
EBI1_CA<3>: length 10.9
  LAYER_3 w0.045: v2(40.43,51.71) 40.66,51.94 43.69,51.94 44.6,51.03 50.36,51.03 50.64,50.76 v2(50.64,50.61)
EBI1_CA<4>: length 10.9
  LAYER_3 w0.045: v2(40.13,52.01) 40.16,52.04 43.72,52.04 44.64,51.12 50.51,51.12 v2(50.63,51)
EBI1_CA<5>: length 11.8
  LAYER_3 w0.045: v2(40.46,50.81) 40.5,50.77 43.56,50.77 44.13,50.2 47.24,50.2 47.89,49.55 50.52,49.55 50.98,50.01 51.49,50.01 v2(51.55,50.07)
EBI1_CKE_0: length 14.4
  LAYER_3 w0.045: v2(52.13,51) 51.83,50.7 51.83,49.93 51.71,49.81 51.06,49.81 50.59,49.34 47.45,49.34 47.11,49.69 45.56,49.69 45.51,49.64 45.2,49.64 45.06,49.78 43.87,49.78 43.13,50.52 40.36,50.52 39.96,50.91 39.96,51.24 v2(39.9,51.3)
EBI1_CKE_1: length 12.5
  LAYER_3 w0.045: v2(52.13,51.5) 51.9,51.5 51.74,51.67 50.51,51.67 50.25,51.41 44.76,51.41 43.84,52.33 40.7,52.33 40.52,52.5 v2(40.23,52.5)
EBI1_CLK_M: length 12.7
  LAYER_3 w0.045: v2(40.14,52.97) 40.22,52.89 40.49,52.89 40.67,52.71 44.26,52.71 45.12,51.84 47.05,51.84 47.29,52.09 50.79,52.09 50.93,52.23 51.9,52.23 52.04,52.09 52.04,52.09 v2(52.13,52)
EBI1_CLK_P: length 12.9
  LAYER_3 w0.045: v2(39.93,53.19) 39.99,53.13 40.2,53.13 40.35,52.98 40.53,52.98 40.71,52.81 44.31,52.81 45.18,51.94 46.98,51.94 47.23,52.18 50.75,52.18 50.89,52.33 52.06,52.33 v2(52.12,52.39)
EBI1_CS_0: length 14.3
  LAYER_3 w0.045: v2(39.93,51.76) 40.06,51.63 40.06,50.95 40.37,50.64 43.54,50.64 44.08,50.1 47.2,50.1 47.86,49.44 50.56,49.44 51.03,49.91 51.64,49.91 51.73,49.99 51.73,50.93 v2(51.71,50.95)
EBI1_CS_1: length 11.7
  LAYER_3 w0.045: v2(51.63,51.5) 51.56,51.57 50.54,51.57 50.28,51.31 44.72,51.31 43.8,52.23 40.51,52.23 v2(40.43,52.31)
EBI1_DM<0>: length 6
  TOP w0.05: U1600.AA5 46.63,50.52 46.28,50.87 44.98,50.87 44.15,51.7 41.51,51.7 41.32,51.51 U1001.A35
EBI1_DM<1>: length 4.8
  TOP w0.05: U1600.U3 45.45,52.68 45.07,52.68 44.95,52.55 41.94,52.55 41.49,53 U1001.A29
EBI1_DQ<0>: length 5.3
  TOP w0.05: U1600.AD3 44.72,49.91 43.3,49.91 42.71,50.5 41.63,50.5 U1001.A41
EBI1_DQ<1>: length 5.3
  TOP w0.05: U1001.B40 41.24,50.27 41.57,50.6 42.78,50.6 43.36,50.02 44.85,50.02 45.36,49.5 U1600.AC3
EBI1_DQ<2>: length 5.1
  TOP w0.05: U1001.B38 41.23,50.77 41.27,50.81 42.88,50.81 43.43,50.26 45.37,50.26 U1600.AB3
EBI1_DQ<3>: length 5.3
  TOP w0.05: 40.92,51.27 41.37,51.27 41.7,51.59 44.03,51.59 45.11,50.5 U1600.AA3
EBI1_DQ<4>: length 6.9
  TOP w0.05: U1001.A39 41.22,50.52 41.41,50.7 42.82,50.7 43.39,50.14 44.97,50.14 v2(45.31,49.8)
  LAYER_3 w0.045: v2(47.53,49.53) 47.28,49.78 45.31,49.78 v2(45.31,49.8)
EBI1_DQ<5>: length 6.3
  TOP w0.05: v2(43.49,50.45) 43.02,50.92 41.53,50.92 41.43,51.02 U1001.A37
  LAYER_3 w0.045: v2(43.49,50.45) 43.94,50 46.99,50 v2(47.05,49.94)
EBI1_DQ<6>: length 7.3
  TOP w0.05: U1600.AA7 47.35,50.78 46.66,50.78 46.39,51.06 45.03,51.06 44.27,51.82 41.37,51.82 41.31,51.76 U1001.B34
EBI1_DQ<7>: length 10.1
  TOP w0.05: v2(48.99,49.85) 48.99,50.55 48.57,50.97 46.85,50.97 46.56,51.26 45.01,51.26 44.32,51.95 41.65,51.95 41.59,52.01 U1001.A33
  LAYER_3 w0.045: v2(48.13,50) 48.35,49.78 48.92,49.78 v2(48.99,49.85)
EBI1_DQ<8>: length 6.3
  TOP w0.05: U1001.B26 41.46,53.74 41.62,53.9 43.38,53.9 43.64,53.64 44.12,53.64 v2(44.55,53.21)
  LAYER_3 w0.045: v2(46.63,53.39) 46.49,53.25 45.44,53.25 45.23,53.04 44.72,53.04 v2(44.55,53.21)
EBI1_DQ<9>: length 6.5
  TOP w0.05: U1600.R6 47.13,53.52 46.72,53.93 43.81,53.93 43.57,54.17 41.42,54.17 41.35,54.23 U1001.B24
EBI1_DQ<10>: length 4.7
  TOP w0.05: U1001.A25 41.5,53.99 41.55,54.04 43.46,54.04 43.72,53.78 45.35,53.78 U1600.R3
EBI1_DQ<11>: length 4.9
  TOP w0.05: U1600.T3 44.46,53 43.98,53.48 43.61,53.48 43.32,53.77 41.7,53.77 41.42,53.49 U1001.A27
EBI1_DQ<12>: length 7.1
  TOP w0.05: v2(44.82,52.83) 44.72,52.73 42.04,52.73 41.52,53.25 U1001.B28
  LAYER_3 w0.045: v2(44.82,52.83) 44.92,52.93 45.27,52.93 45.49,53.15 47.59,53.15 v2(47.63,53.11)
EBI1_DQ<13>: length 4.7
  TOP w0.05: U1600.V3 45.2,52 44.97,52.24 41.75,52.24 41.48,52.5 U1001.A31
EBI1_DQ<14>: length 6.4
  TOP w0.05: v2(45.21,52.51) 45.1,52.4 41.81,52.4 41.46,52.75 U1001.B30
  LAYER_3 w0.045: v2(47.05,52.57) 46.9,52.42 46.41,52.42 46.32,52.51 v2(45.21,52.51)
EBI1_DQ<15>: length 8.1
  TOP w0.05: U1001.B32 41.55,52.26 41.7,52.11 44.83,52.11 45.22,51.72 47.87,51.72 47.89,51.7 v4(47.89,51.68)
  LAYER_5 w0.045: v4(48.02,52.51) 48.02,51.8 v4(47.89,51.68)
EBI1_DQS_0_M: length 9
  LAYER_3 w0.045: v2(40.23,51.52) 40.28,51.46 40.86,51.46 41.05,51.65 43.43,51.65 44.38,50.7 48.26,50.7 48.46,50.5 v2(48.63,50.5)
EBI1_DQS_0_P: length 9
  LAYER_3 w0.045: v2(40.42,51.27) 40.81,51.27 41.09,51.54 43.4,51.54 44.34,50.61 48.21,50.61 48.63,50.19 v2(48.63,50.11)
EBI1_DQS_1_M: length 8.8
  LAYER_3 w0.045: v2(48.63,53.12) 48.14,53.61 43.51,53.61 42.98,53.07 41.02,53.07 40.69,53.4 40.58,53.4 v2(40.46,53.28)
EBI1_DQS_1_P: length 8.9
  LAYER_3 w0.045: v2(40.2,53.51) 40.74,53.51 41.08,53.17 42.93,53.17 43.46,53.7 48.21,53.7 48.4,53.5 v2(48.63,53.5)
EBI_CAL_REXT: length 0.8
  TOP w0.1: R1011.1 40.79,60.05 40.67,59.93
ELON1_AVDD: length 54.6
  LAYER_3 w0.045: v2(37.48,39.27) 37.63,39.12 38.22,39.12 38.46,39.35 40.12,39.35 41.48,37.99 45.04,37.99 48.11,41.05 48.12,41.05 48.19,41.12 52.24,41.12 52.28,41.08 54.94,41.08 55.16,41.29 56.56,41.29 57.01,41.75 57.51,41.75 57.98,42.21 v4(58.07,42.21)
  LAYER_5 w0.045: v4(58.07,42.21) 58.2,42.34 58.2,43.26 58.8,43.86 58.8,44.41 58.93,44.54 58.93,56.38 58.03,57.28 58.03,61.36 58.72,62.05 58.72,63.72 58.88,63.87 58.88,64.53 59.36,65.01 60.16,65.01 v7(60.47,65.32)
  LAYER_7 w0.045: v7(59.93,65.04) 59.83,65.13 59.34,65.13 59.07,64.86 58.94,64.86 58.85,64.96 58.85,65.14 58.36,65.63 57,65.63 56.6,65.23 56.02,65.23 55.86,65.39 v7(55.84,65.39)
  BOTTOM w0.05: J5300.15 v7(55.84,65.39)
  BOTTOM w0.075: C5369.2 60.04,64.95 60.42,64.95 D5302.2 R5321.2
ELON2: length 54
  LAYER_3 w0.045: v2(39.22,39.03) 39.44,39.25 40.08,39.25 41.43,37.89 45.1,37.89 48.23,41.02 52.2,41.02 52.25,40.98 54.98,40.98 55.19,41.19 56.59,41.19 57.05,41.65 57.56,41.65 57.96,42.05 58.19,42.05 v4(58.3,42.16)
  LAYER_5 w0.045: v7(61.44,64.88) 61.41,64.91 59.4,64.91 58.98,64.49 58.98,63.84 58.82,63.68 58.82,62.01 58.13,61.32 58.13,57.32 59.03,56.41 59.03,44.5 58.89,44.36 58.89,43.8 58.3,43.2 v4(58.3,42.16)
  LAYER_7 w0.045: v7(56.19,65.39) 56.63,65.84 58.43,65.84 58.77,65.5 60.85,65.5 v7(61.02,65.33)
  BOTTOM w0.05: J5300.13 v7(56.19,65.39)
  BOTTOM w0.075: v7(61.02,65.33) 61.02,64.92 60.99,64.89 ; 60.99,64.89 C5370.2 ; 60.99,64.89 D5301.2
ESIM_CLK: length 7.8
  TOP w0.05: U4200.5 v2(54.75,45.33)
  TOP w0.1: R4216.1 54.28,44.32 54.69,44.73 U4200.5
  LAYER_3 w0.045: v2(54.75,45.33) 57.99,45.33 58.49,45.83 60.21,45.83 60.56,46.17 v7(60.56,46.34)
ESIM_DATA: length 8
  TOP w0.05: U4200.4 58.21,44.86 v2(58.21,45.3)
  LAYER_3 w0.045: v7(60.86,46.34) 60.25,45.74 58.65,45.74 58.22,45.3 v2(58.21,45.3) 58.13,45.22 54.86,45.22 54.81,45.17 54.18,45.17 v2(54.06,45.29)
ESIM_POWER: length 10.4
  TOP w0.2: U4200.8 54.37,41.35 C4214.2 ; v2(54.02,41.38) 53.88,41.24 C4215.2 54.33,40.85 R4211.1
  LAYER_3 w0.2: v4(56.72,42.05) 56.41,41.74 54.38,41.74 v2(54.02,41.38)
  LAYER_5 w0.2: v4(56.72,42.05) 56.72,46.41 v4(57.28,46.97)
ESIM_RST: length 8.5
  TOP w0.075: U4200.6 54.63,43.73 54.31,43.41 v2(54.02,43.41)
  LAYER_3 w0.045: v7(59.15,44.24) 59.03,44.24 58.45,43.65 54.26,43.65 v2(54.02,43.41)
  LAYER_7 w0.045: v7(58.47,45.53) 59.15,44.84 v7(59.15,44.24)
  BOTTOM w0.075: v7(59.15,44.24) 58.84,44.55 D4250.2
ESIM_SWP: length 9
  LAYER_5 w0.045: v4(58.47,42.75) 58.47,43.23 58.99,43.75 58.99,44.32 59.13,44.46 59.13,51.23 v4(59.34,51.43)
ETDAC_CH0_M: length 18.2
  LAYER_5 w0.045: v4(26.23,34.62) 26.19,34.62 24.93,33.36 24.93,25.45 22.91,23.43 22.91,18.21 22.68,17.98 v4(22.57,17.98)
ETDAC_CH0_P: length 19.1
  LAYER_5 w0.045: v4(26.41,34.8) 26.41,34.67 26.42,34.66 26.42,34.57 26.31,34.45 26.18,34.45 25.03,33.3 25.03,25.39 23.01,23.37 23.01,18.16 22.67,17.82 22.44,17.82 v4(22.26,18)
EUD: length 31.6
  TOP w0.075: v2(27.67,50.12) 27.67,50.45 R2455.1
  LAYER_2 w0.045: v2(27.67,50.12) 27.67,50.15 27.26,50.55 27.26,51.88 26.65,52.49 25.65,52.49 25.57,52.58 25.57,52.87 25.39,53.05 25.39,53.24 25.24,53.39 v2(25.24,53.54) ; v2(27.25,42.85) 26.91,43.2 v2(26.91,47.24) ; v1(21.41,58.45) 21.41,58.1 21.55,57.96 22.14,57.96 v2(22.16,57.98)
  LAYER_3 w0.045: v2(25.24,53.54) 25.06,53.72 25.06,54.27 25.69,54.89 25.69,57.75 25.41,58.03 22.64,58.03 22.55,58.12 22.3,58.12 v2(22.16,57.98) ; v2(27.67,50.12) 27.16,50.12 27.1,50.06 27.09,50.06 26.91,49.88 26.91,49.88 26.91,49.87 v2(26.91,47.24) ; v2(35.55,41.8) 35.26,42.09 34.61,42.09 34.35,42.35 33.34,42.35 33.16,42.52 28.15,42.52 27.92,42.75 27.35,42.75 v2(27.25,42.85)
FAULT_N: length 28.1
  LAYER_2 w0.045: v2(27.07,46.81) 27,46.75 27,43.73 v2(27.21,43.53) ; v1(21.67,54.71) 21.33,54.37 21.33,54.15 21.22,54.04 21.22,53.55 21.31,53.46 21.31,52.59 21.46,52.44 21.46,51.94 21.28,51.77 21.28,51.47 21.45,51.3 v2(21.55,51.3)
  LAYER_3 w0.045: v2(27.21,43.53) 27.35,43.53 27.65,43.23 28.12,43.23 28.34,43 33.38,43 33.54,42.84 34.42,42.84 34.65,43.06 35.44,43.06 35.62,43.24 35.76,43.24 35.77,43.23 35.77,43.23 35.84,43.16 36.35,43.16 37.18,42.33 v2(37.48,42.33) ; v2(21.55,51.3) 21.74,51.11 21.74,50.06 21.46,49.78 21.46,47.91 22.55,46.82 27.05,46.82 27.06,46.81 v2(27.07,46.81)
FLAG_N: length 94.2
  LAYER_3 w0.045: v6(36.8,32.95) 36.89,33.04 42.88,33.04 v4(42.92,33.08) ; v6(24.65,62.67) 23.74,61.76 23.74,60.63 21.36,58.25 v2(21.19,58.25) ; v4(12.58,37.6) 12.58,37.6 12.58,37.69 12.99,38.1 13.18,38.1 13.43,38.35 v2(13.62,38.35) 13.77,38.5 13.9,38.5 14.4,39 v2(14.65,39)
  LAYER_5 w0.045: v4(42.92,33.08) 43,33.17 43,33.53 43.49,34.02 43.49,36.71 46.01,39.22 46.01,41.83 45.68,42.16 45.68,44.53 45.53,44.69 45.53,44.91 45.58,44.96 45.58,46.94 45.4,47.12 45.4,47.23 45.79,47.62 45.79,48.08 45.78,48.09 45.78,48.45 46.05,48.73 46.05,57.57 44.16,59.46 44.16,61.02 44.1,61.08 v6(44.1,61.22) ; v6(13.23,35.1) 13.16,35.1 13.16,36.92 12.58,37.5 v4(12.58,37.6)
  LAYER_7 w0.045: v6(13.23,35.1) 26.15,35.1 28.3,32.95 v6(36.8,32.95) ; v6(44.1,61.22) 44.06,61.26 43.97,61.26 41.07,64.16 32.79,64.16 31.73,63.09 27.44,63.09 27.16,62.81 24.79,62.81 v6(24.65,62.67)
FLASH_INHIBIT: length 61.2
  TOP w0.05: v2(29.75,66.12) 37.66,66.12 38.06,65.72 J5500.10
  LAYER_2 w0.045: v1(37.48,40.76) 37.3,40.76 37.07,40.99 36.94,40.99 36.76,40.81 35.83,40.81 35.59,41.05 35.39,41.05 v2(35.12,40.78)
  LAYER_3 w0.045: v4(23.87,42.41) 23.96,42.51 26.66,42.51 26.98,42.18 27.68,42.18 27.91,41.95 32.93,41.95 33.1,41.78 33.67,41.78 34.3,41.15 34.75,41.15 v2(35.12,40.78) ; v4(29.75,65.65) v2(29.75,66.12) ; v4(24.72,55.34) 24.76,55.38 24.76,56.53 v4(24.25,57.04)
  LAYER_5 w0.045: v4(23.87,42.41) 24.54,43.09 24.54,55.16 v4(24.72,55.34) 25.11,55.73 25.11,55.92 26.93,57.74 29.65,57.74 29.75,57.64 30.66,57.64 30.72,57.58 31.68,57.58 31.74,57.52 v4(31.74,57.49) ; v4(29.75,65.65) 29.66,65.56 29.37,65.56 29.27,65.46 25.14,65.46 24.48,64.8 24.48,62.22 24.36,62.1 24.36,57.94 24.27,57.85 24.27,57.06 v4(24.25,57.04)
FLASH_RST_N: length 22.7
  TOP w0.05: J5500.12 37.71,65.81 37.52,66.01 29.91,66.01 29.82,65.92 29.67,65.92 29.56,66.02 v2(29.26,66.02)
  LAYER_3 w0.045: v4(28.63,62.57) 28.6,62.6 28.6,65.01 29.31,65.72 29.31,65.98 v2(29.26,66.02)
  LAYER_5 w0.045: v4(28.63,62.57) 28.63,62.2 26.63,60.2 26.63,59.44 26.88,59.19 30.59,59.19 30.78,59.38 30.97,59.38 31.1,59.25 31.45,59.25 31.52,59.18 31.95,59.18 v4(32.01,59.24)
FLIP_BATT_EN_N: length 25.5
  TOP w0.05: Q2031.3 15.71,53.44 v6(15.86,53.59)
  TOP w0.075: J5500.51 30.71,66.7 30.55,66.54 30.33,66.54 v4(30.32,66.55)
  LAYER_5 w0.045: v4(30.32,66.55) 30.16,66.39 29.22,66.39 28.58,65.75 25.02,65.75 23.84,64.57 23.84,63.4 24.12,63.13 24.12,62.47 v6(24.22,62.36)
  LAYER_7 w0.045: v6(24.22,62.36) 22.98,62.36 21.37,60.75 21.37,59.41 20.23,58.27 19.59,58.27 17.9,56.58 16.8,56.58 15.53,55.31 15.53,53.92 v6(15.86,53.59)
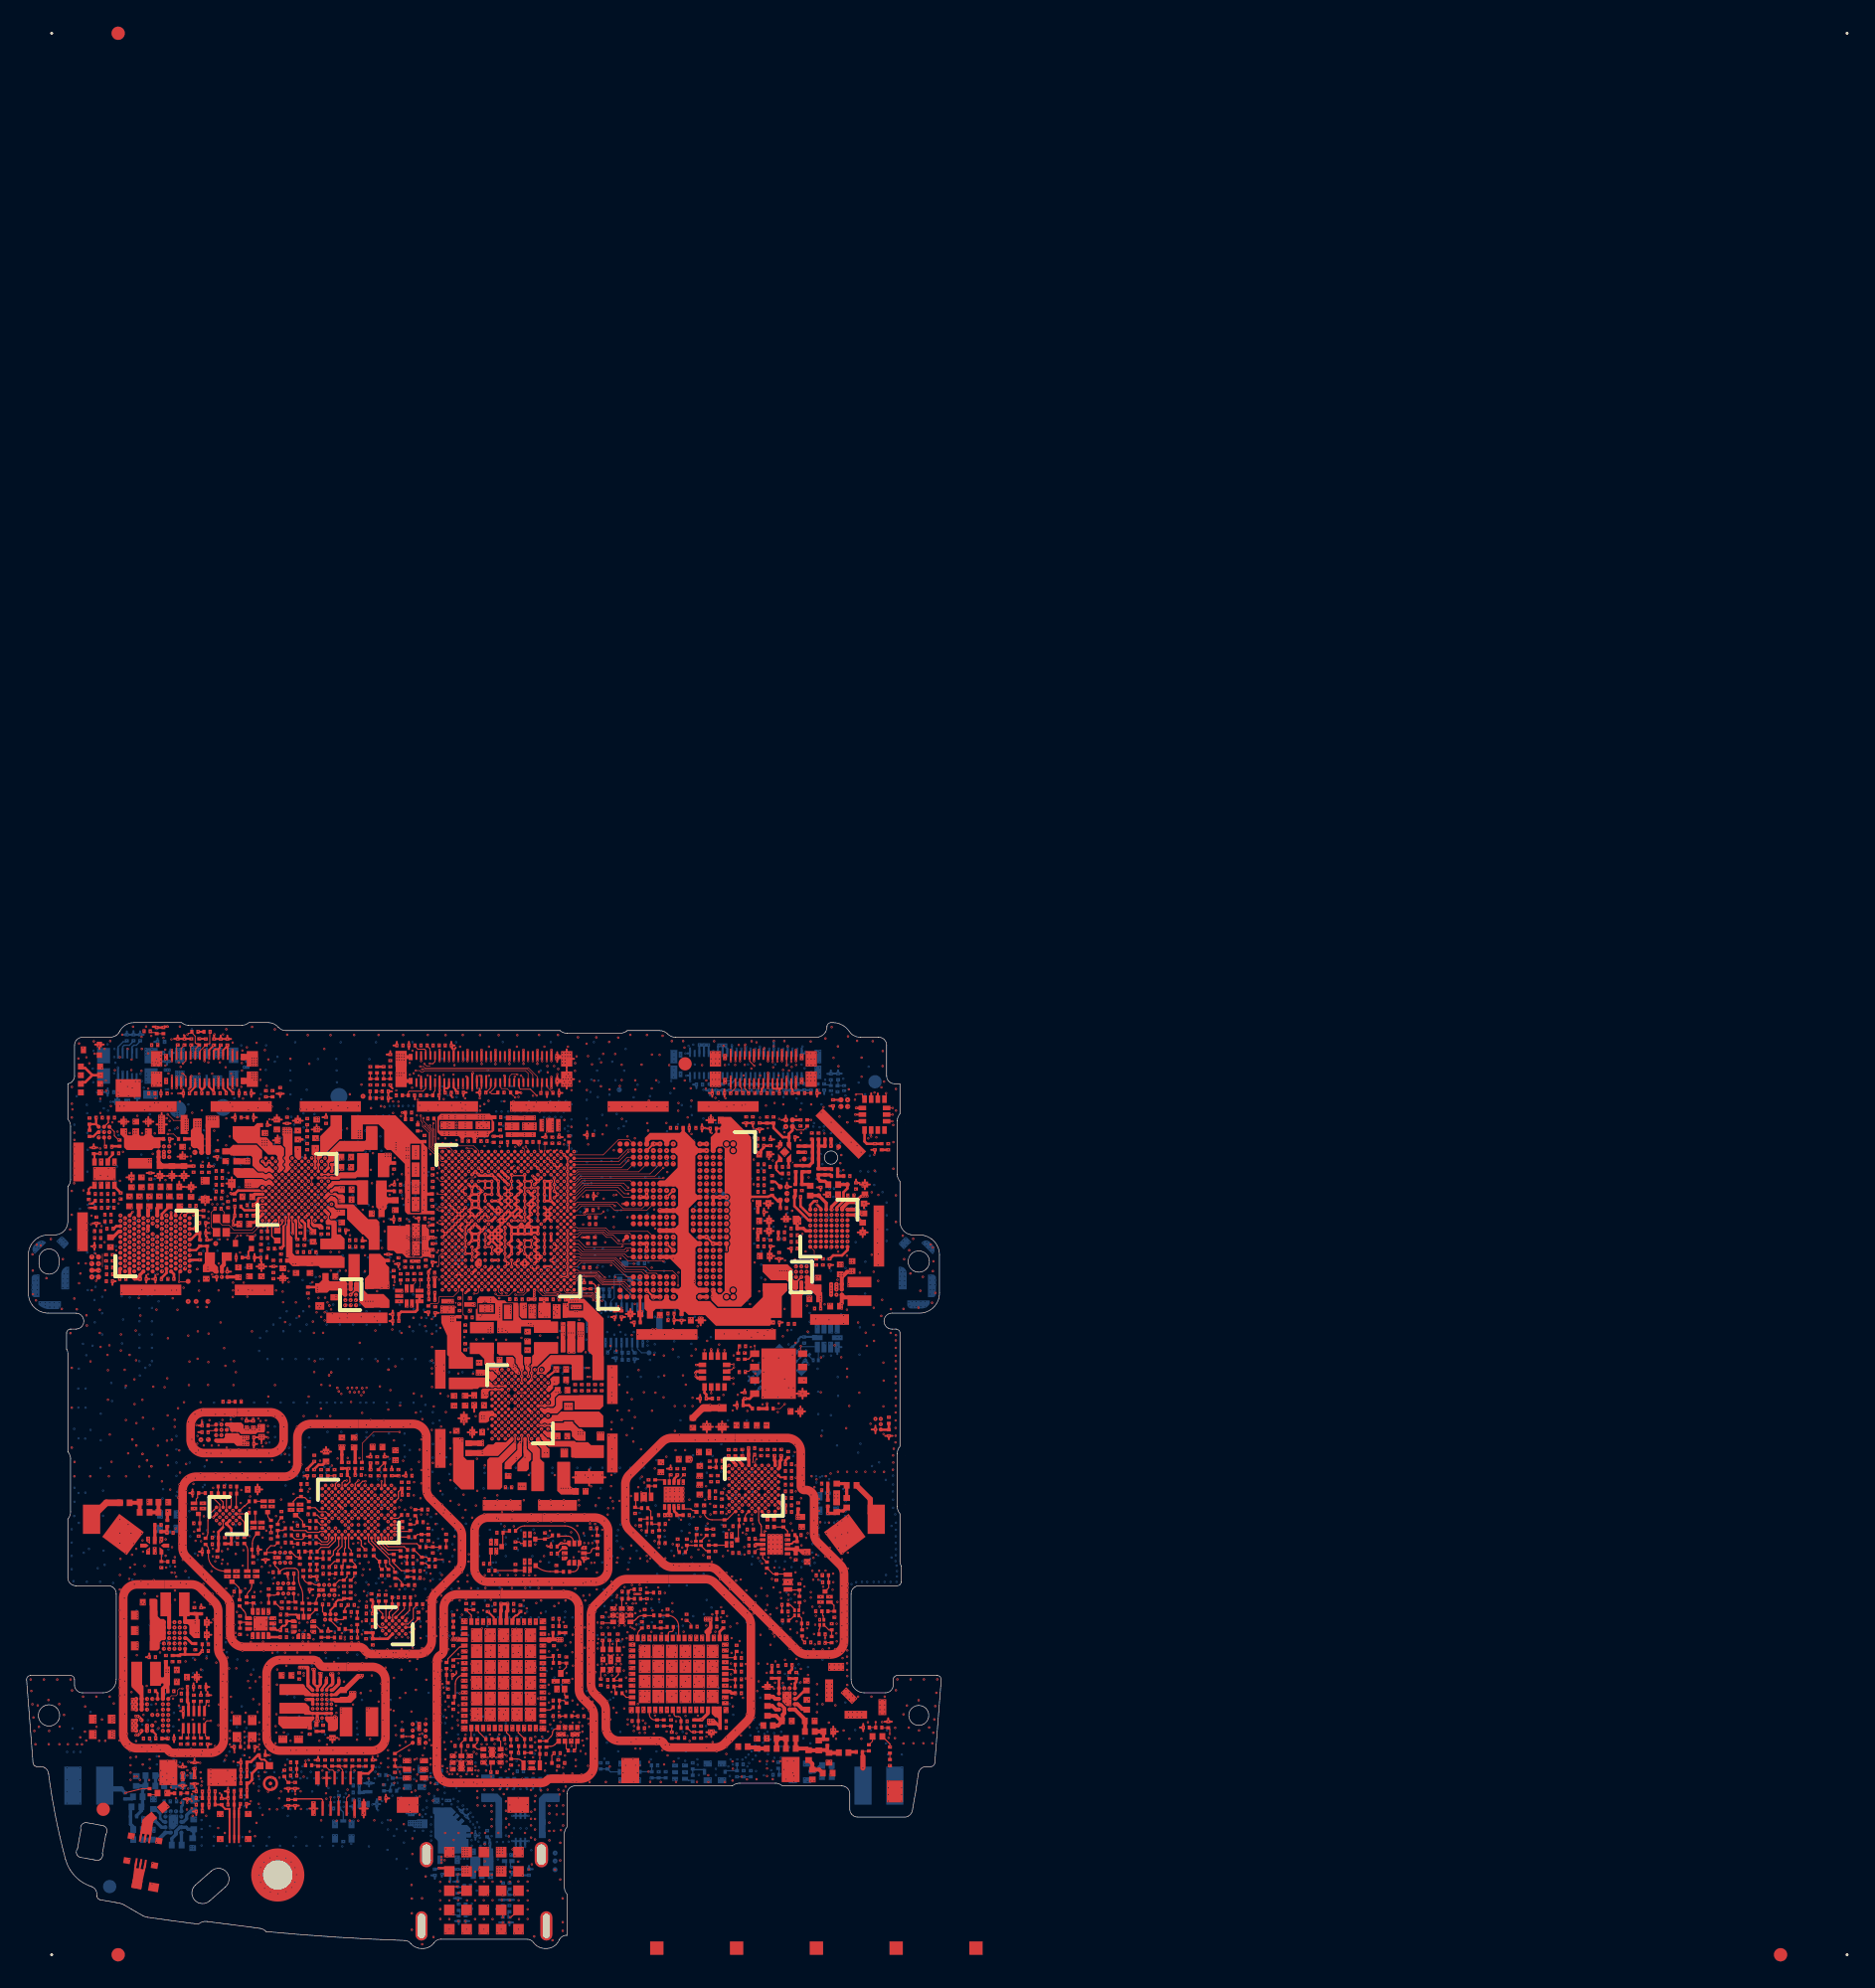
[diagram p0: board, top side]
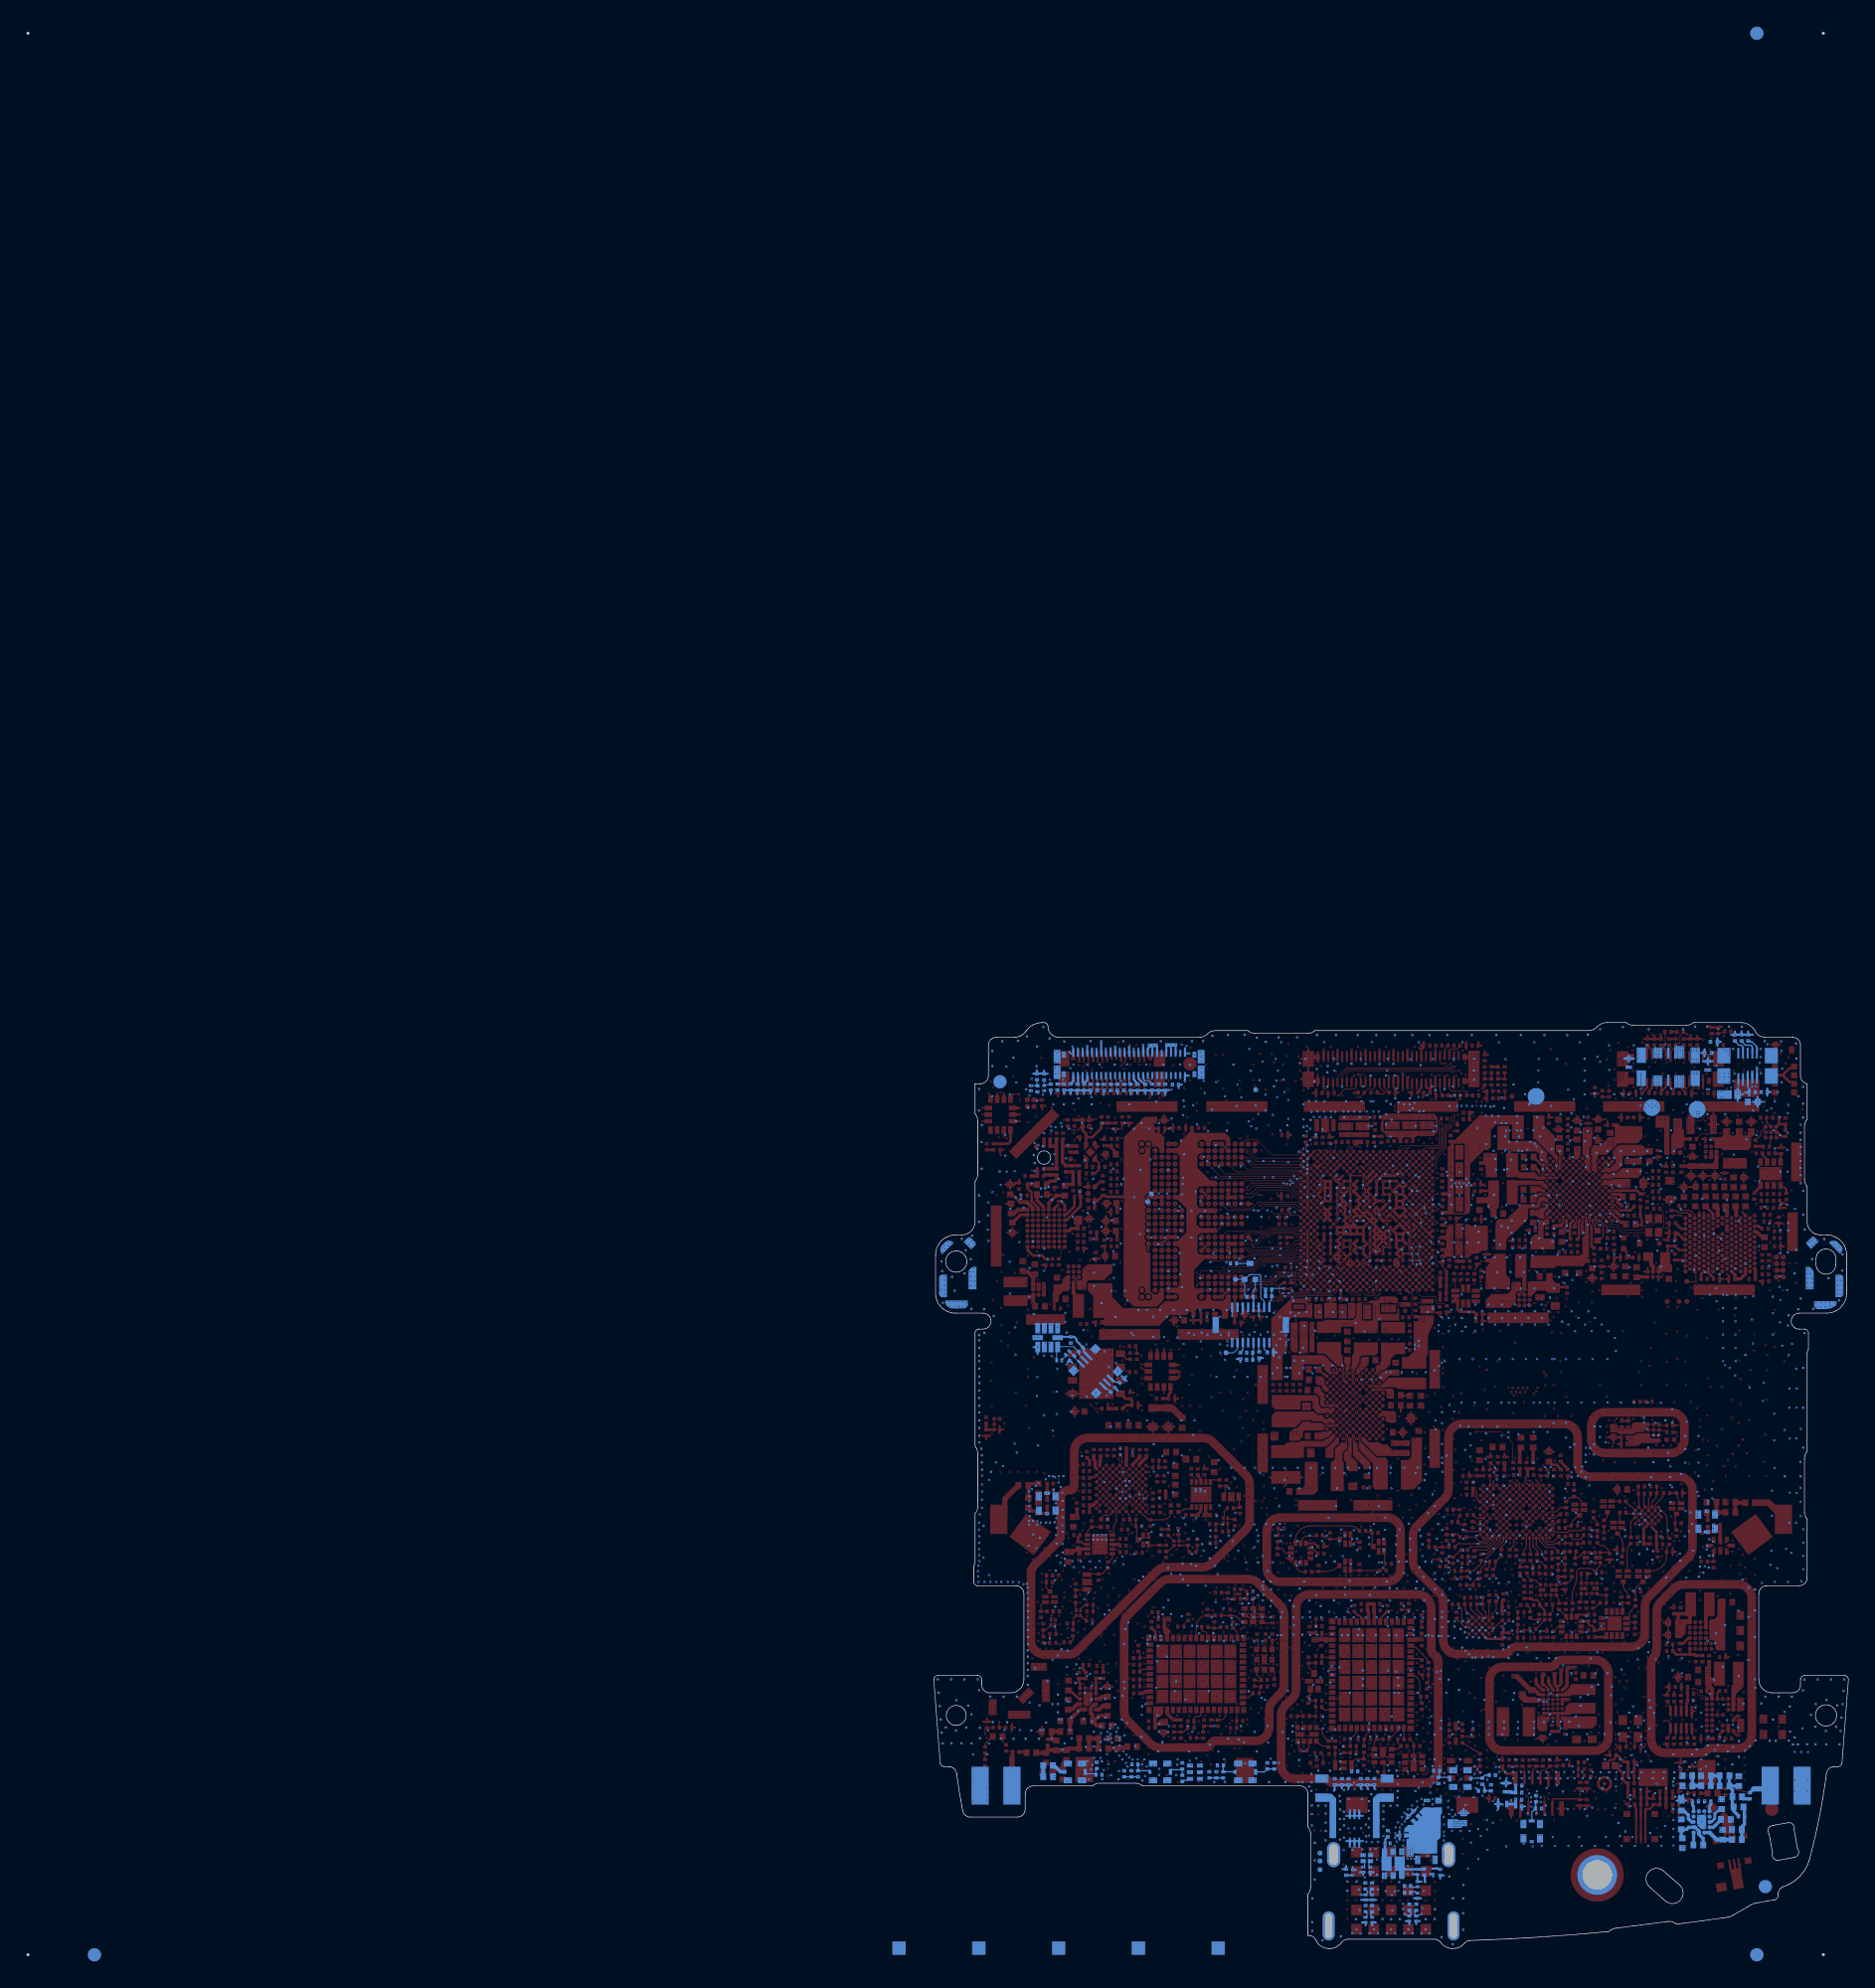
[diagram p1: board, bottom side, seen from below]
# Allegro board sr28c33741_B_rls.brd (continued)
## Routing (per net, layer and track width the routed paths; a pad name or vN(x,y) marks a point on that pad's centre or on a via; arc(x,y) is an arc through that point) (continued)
FLIP_BATTPLUS_EN_N: length 14.5
  TOP w0.05: v4(10.62,61.25) 11.06,61.25 R5500.1
  LAYER_3 w0.045: v4(12.58,60.93) v2(12.58,59.88)
  LAYER_5 w0.045: v6(6.37,64.76) 6.68,64.76 9.8,61.64 10.3,61.64 10.62,61.32 v4(10.62,61.25) 10.87,61 11.96,61 12.1,60.86 12.51,60.86 v4(12.58,60.93)
  LAYER_7 w0.045: v6(6.37,64.76) 5.05,64.76 4.25,65.56 v6(4.25,67.74)
FLIP_COM_IN: length 16.3
  TOP w0.15: C6181.2 4.68,57.12 4.8,57.24 5.11,57.24 U6180.1
  LAYER_3 w0.15: v7(8.04,68.29) 7.81,68.52 7.45,68.52 7.3,68.37 7.3,68.05 6.96,67.71 6.27,67.71 4.58,66.02 4.58,64.6 4.13,64.15 4.13,59.1 5.19,58.04 v2(5.19,57.58)
  BOTTOM w0.1: D355.1 8.04,68.23 7.74,67.93 7.34,67.93 7.23,67.82 J350.3
FLIP_DET_EN: length 36.3
  LAYER_2 w0.045: v2(33.82,49.83) 33.82,49.83 33.82,49.84 33.83,49.85 33.83,49.94 34.13,50.24 34.13,50.47 v1(34.18,50.52) ; v2(10.1,47.3) 12.41,44.99 14.2,44.99 15.33,46.12 16.25,46.12 v2(16.31,46.06)
  LAYER_3 w0.045: v2(10.1,47.3) 6.69,47.3 6.19,47.8 6.19,48.55 5.05,49.69 5.05,50.35 v2(4.91,50.49) ; v2(33.82,49.83) 33.73,49.83 33.73,49.83 33.6,49.83 33.59,49.83 33.19,49.43 33.19,49.26 32.9,48.97 32.9,48.34 32.69,48.13 32.69,48.09 32.39,47.79 32.39,47.26 32.39,46.94 31.36,45.92 23.92,45.92 23.73,46.11 23.18,46.11 22.91,45.84 16.42,45.84 16.31,45.96 v2(16.31,46.06)
FLIP_DET_EN_F: length 10.8
  LAYER_3 w0.045: v2(6.93,59.8) 6.75,59.62 6.75,59.35 6.45,59.04 6.45,57.48 6.28,57.31 4.17,57.31 3.79,56.94 3.79,53.03 4.72,52.1 v2(4.91,52.1)
FLIP_DET_OUT: length 42.4
  TOP w0.05: U6182.D2 v2(5.23,50.21)
  LAYER_2 w0.045: v2(31.12,46.39) v2(31.12,43.16) ; v2(32.44,48.25) 32.65,48.25 32.8,48.4 32.8,49.74 33.24,50.18 33.58,50.18 33.91,50.51 33.91,50.63 v1(33.99,50.71)
  LAYER_3 w0.045: v2(31.12,43.16) 31.06,43.09 28.38,43.09 28.16,43.32 27.69,43.32 27.32,43.69 27.13,43.69 26.9,43.47 25.83,43.47 25.7,43.6 25.57,43.6 25.33,43.37 24.61,43.37 24.48,43.5 22.84,43.5 22.16,42.82 11.02,42.82 10.48,43.36 v4(9.64,43.36) ; v2(5.23,50.21) 5.16,50.14 5.16,49.73 5.85,49.04 8.14,49.04 v4(8.26,49.16) ; v2(31.12,46.39) 31.5,46.76 31.5,47.47 32.06,48.03 32.22,48.03 v2(32.44,48.25)
  LAYER_5 w0.045: v4(8.26,49.16) 8.55,48.87 8.55,48.02 9.7,46.87 9.7,43.43 v4(9.64,43.36)
FLIP_DET_OUT_F: length 10.2
  TOP w0.05: U6182.A2 v2(5.16,52.27)
  LAYER_3 w0.045: v2(6.61,58.97) 6.55,58.91 6.55,57.44 6.32,57.22 4.21,57.22 3.89,56.9 3.89,53.09 4.71,52.27 v2(5.16,52.27)
FLIP_REF_IN: length 15.1
  LAYER_3 w0.15: v2(6.03,57.58) 6.03,57.78 4.53,59.28 4.53,63.93 4.98,64.38 4.98,65.84 6.44,67.3 7.84,67.3 8.54,68 v7(8.54,68.29)
  BOTTOM w0.1: D354.1 8.54,68.22 8.25,67.93 8.06,67.93 7.93,67.8 J350.7
FLIP_SNS_IN: length 14.3
  LAYER_3 w0.15: v2(5.52,57.58) 5.52,58 4.33,59.19 4.33,64.04 4.78,64.49 4.78,65.93 6.36,67.51 7.07,67.51 7.54,67.98 v7(7.54,68.29)
  BOTTOM w0.1: J350.1 6.88,67.8 7.27,68.19 7.47,68.19 D356.1
FLLVDD: length 1.5
  TOP w0.2: 13.02,53.8 13.02,53.32 R6268.2 ; 13.02,53.8 12.98,53.76 12.8,53.76 12.36,53.32 U6250.K16 ; 13.02,53.8 C6261.2
FOCUS_GPIO1: length 17.5
  TOP w0.05: v2(29.96,61.87) 29.96,61.83 30.35,61.44 30.35,60.27 31.04,59.58 31.04,59.33 31.19,59.18 31.34,59.18 31.34,59.19 31.51,59.19
  TOP w0.075: J5500.40 v2(32.81,64.69)
  LAYER_3 w0.045: v2(29.96,61.87) 29.96,61.88 29.5,62.34 28.97,62.34 v2(28.95,62.36) 28.95,62.52 28.7,62.77 28.7,64.97 29.42,65.69 29.42,66.11 29.18,66.35 29.18,66.75 v4(29.11,66.82) ; v4(31.45,67.96) 31.44,67.96 31.26,67.78 30.99,67.78 30.87,67.66 30.87,66.64 v2(32.81,64.69)
  LAYER_5 w0.045: v4(31.45,67.96) 31.25,67.96 31.09,67.8 30.03,67.8 29.22,66.99 29.22,66.92 v4(29.11,66.82)
FOCUS_GPIO2: length 16.4
  TOP w0.05: v2(30.34,61.89) 30.34,61.77 30.56,61.55 30.56,60.39 30.8,60.15 31.54,60.15 U1001.AW1
  TOP w0.075: 32.46,65.12 v2(32.46,64.69)
  LAYER_3 w0.045: v2(32.46,64.69) 32.46,64.91 30.77,66.6 30.77,67.71 31,67.94 v4(31,67.97) ; v2(30.34,61.89) 30.18,62.05 29.92,62.05 29.53,62.44 29.23,62.44 28.95,62.72 v2(28.95,62.86) 28.79,63.02 28.79,64.92 29.52,65.65 29.52,66.15 29.28,66.39 29.28,66.9 29.09,67.09 v4(29.07,67.09)
  LAYER_5 w0.045: v4(31,67.97) 30.94,67.91 30.01,67.91 29.19,67.09 v4(29.07,67.09)
FORCEFLASH: length 43.7
  TOP w0.05: v2(36.09,49.26) 36,49.35 35.93,49.35 35.74,49.53 35.72,49.53
  LAYER_2 w0.045: v1(56.01,58.15) 56.01,57.83 56.33,57.51 v4(57.39,57.51)
  LAYER_3 w0.045: v2(36.09,49.26) 36.09,48.9 36.13,48.85 36.13,47.41 37.44,46.1 38.14,46.1 38.34,45.9 38.67,45.9 39.89,44.68 43,44.68 43.41,44.27 45.26,44.27 v4(45.42,44.43) ; v4(45.32,46.38) 45.61,46.38 45.86,46.13 46.37,46.13 46.99,46.75 50.1,46.75 50.4,47.05 52.21,47.05 54.8,49.64 56.4,49.64 57.44,48.61 57.44,48.51 57.58,48.37 v4(57.58,48.34)
  LAYER_5 w0.045: v4(57.39,57.51) 57.46,57.44 57.46,56.8 57.32,56.66 57.32,56.53 57.38,56.47 57.38,56.2 57.31,56.13 57.31,48.73 57.44,48.61 57.44,48.48 v4(57.58,48.34) ; v6(45.37,47.6) 45.2,47.43 45.2,47.02 45.32,46.9 v4(45.32,46.38) 45.38,46.32 45.38,45.02 45.34,44.98 45.34,44.51 v4(45.42,44.43)
  LAYER_7 w0.045: v6(45.37,47.6) v7(44.34,47.6)
  BOTTOM w0.05: 44.34,48.22 v7(44.34,47.6)
FP_DRDY_N: length 114.8
  LAYER_3 w0.045: v4(43.17,33.09) 43.02,33.24 42.84,33.24 42.77,33.17 42.76,33.17 42.73,33.14 34.35,33.14 28.29,39.19 27.67,39.19 26.38,40.48 22.56,40.48 22.2,40.84 16.72,40.84 16.44,40.56 15.83,40.56 15.64,40.37 14.05,40.37 11.75,38.07 v4(11.75,37.55) ; v4(13.09,24.18) 13.11,24.16 13.64,24.16 14.32,23.48 14.32,16.95 14.53,16.73 14.53,15.54 15.5,14.58 17.58,14.58 18.14,14.01 19.59,14.01 19.82,13.77 19.86,13.77 v4(19.92,13.72)
  LAYER_5 w0.045: v4(43.17,33.09) 43.1,33.16 43.1,33.49 43.59,33.98 43.59,36.67 46.1,39.18 46.1,43.83 46.33,44.05 46.33,44.27 46.14,44.46 46.14,46.16 46.2,46.22 46.2,46.36 46.18,46.38 46.18,46.95 46.07,47.05 46.07,47.72 46.01,47.78 46.01,48.01 46.16,48.15 46.16,57.6 46.15,57.61 46.15,57.61 45.06,58.7 v6(45.06,58.82) ; v4(31.76,59.39) 31.8,59.43 32.04,59.43 v6(32.75,58.73) ; v4(13.09,24.18) 13.26,24.36 13.26,25.33 12.98,25.61 12.98,33.12 12.69,33.41 12.69,36.5 11.75,37.45 v4(11.75,37.55) ; v4(19.92,13.72) 20.63,13.01 20.9,13.01 22.75,11.16 24.12,11.16 v6(24.21,11.25)
  LAYER_7 w0.045: v7(24.56,11.19) 24.5,11.25 v6(24.21,11.25) ; v6(45.06,58.82) 44.98,58.74 41.66,58.74 41.65,58.73 41.64,58.73 40.54,57.62 37.56,57.62 37.16,58.02 37.16,58.6 36.94,58.82 36.62,58.82 36.44,58.64 32.84,58.64 v6(32.75,58.73)
FP_PWR_1P8_R: length 11.2
  TOP w0.1: J6601.11 22.26,11.16 22.18,11.25 20.25,11.25 C6630.2 19.68,11.2 v2(19.68,11.21)
  LAYER_3 w0.175: v2(19.68,11.21) 19.87,11.02 21.08,11.02 21.38,10.72 24.32,10.72 25.02,11.42 v7(25.02,12.25)
  BOTTOM w0.2: v7(25.02,12.25) C1516.2
  BOTTOM w0.25: 25.75,11.79 25.4,11.79 25.35,11.73 C1516.2
FP_RST_N: length 69.1
  TOP w0.075: R1527.1 v2(20.98,14.12)
  LAYER_2 w0.045: v1(31.51,58.2) 31.26,58.2 31.11,58.05 31.11,57.97 31.1,57.95 v4(31.09,57.95)
  LAYER_3 w0.045: v4(22.64,40.64) 22.34,40.94 16.68,40.94 16.4,40.66 15.79,40.66 15.6,40.47 14.01,40.47 11.57,38.03 v4(11.57,37.72) ; v2(20.98,14.12) 20.84,13.98 20.47,13.98 20.24,14.21 18.22,14.21 17.66,14.77 15.58,14.77 14.72,15.62 14.72,16.83 14.51,17.04 14.51,23.61 13.78,24.34 13.78,24.76 13.28,25.26 v4(13.06,25.26)
  LAYER_5 w0.045: v4(31.09,57.95) 30.64,58.41 26.48,58.41 26.32,58.24 26.32,57.96 25.05,56.7 24.69,56.7 24.42,56.43 24.42,56.18 23.15,54.91 23.15,52.6 23.6,52.15 23.6,46.02 23.43,45.84 23.43,45.69 23.7,45.41 23.7,43.67 22.73,42.7 22.73,40.73 v4(22.64,40.64) ; v4(13.06,25.26) 12.89,25.43 12.89,33.08 12.59,33.37 12.59,36.45 11.57,37.47 v4(11.57,37.72)
FP_SPI_CLK: length 93
  LAYER_3 w0.045: v2(19.43,13.44) 19.43,13.66 19.36,13.72 18.03,13.72 17.46,14.29 15.38,14.29 14.25,15.42 14.25,16.62 14.03,16.83 14.03,22.8 13.7,23.14 12.53,23.14 12.21,23.46 12.21,25.04 v4(12.36,25.19) ; v2(39.39,50.76) 39.39,50.75 39.56,50.58 39.56,50.5 39.67,50.38 39.67,50.29 39.91,50.05 40.1,50.05 40.79,49.35 41.15,49.35 41.7,49.91 42.91,49.91 43.7,49.12 44.88,49.12 45.03,48.97 45.59,48.97 46.65,47.91 46.65,47.66 46.59,47.61 46.59,47.31 v4(46.68,47.23) ; v4(43.62,33.76) 43.47,33.76 43.35,33.64 42.7,33.64 42.58,33.52 34.51,33.52 28.44,39.59 27.84,39.59 26.56,40.88 23.03,40.88 22.59,41.31 16.51,41.31 16.23,41.04 15.63,41.04 15.44,40.84 13.85,40.84 11,38 v4(10.92,38)
  LAYER_5 w0.045: v4(43.62,33.76) 43.69,33.83 43.69,36.63 46.2,39.14 46.2,40.42 46.65,40.87 46.65,43.78 46.78,43.92 46.78,47.12 v4(46.68,47.23) ; v4(10.92,38) 10.87,37.95 10.87,37.6 12.21,36.25 12.21,33.21 12.51,32.92 12.51,25.74 12.36,25.59 v4(12.36,25.19)
FP_SPI_CLK_R: length 5.4
  TOP w0.075: VR1509.2 v2(20.14,12.49) C1514.2 19.49,12.69 19.49,12.83 R1528.2 ; J6601.9 v2(22.86,11.38)
  LAYER_3 w0.045: v2(22.86,11.38) 22.77,11.47 20.66,11.47 20.14,11.99 v2(20.14,12.49)
FP_SPI_CS_N: length 98.4
  LAYER_3 w0.045: v2(25.44,14.14) 25.42,14.14 25.22,14.34 23.9,14.34 23.44,13.88 20.42,13.88 20.19,14.11 18.18,14.11 17.62,14.67 15.54,14.67 14.63,15.58 14.63,16.78 14.41,17 14.41,23.53 13.67,24.27 13.38,24.27 v4(13.1,24.55) ; v4(43.41,33.32) 43.4,33.32 43.29,33.44 42.76,33.44 42.65,33.33 34.43,33.33 28.36,39.39 27.76,39.39 26.48,40.67 22.96,40.67 22.51,41.12 16.6,41.12 16.32,40.84 15.71,40.84 15.52,40.66 13.93,40.66 11.25,37.97 v4(11.25,37.85) ; v2(39.24,51.04) 39.33,51.04 39.64,50.74 39.77,50.74 39.89,50.62 39.89,50.34 39.99,50.23 40.18,50.23 40.87,49.54 41.07,49.54 41.62,50.09 42.99,50.09 43.78,49.3 44.96,49.3 45.1,49.16 45.67,49.16 46.85,47.98 46.85,47.68 v4(46.91,47.62)
  LAYER_5 w0.045: v4(43.41,33.32) 43.55,33.32 43.89,33.66 43.89,36.56 46.4,39.07 46.4,40.34 46.84,40.78 46.84,43.7 46.97,43.84 46.97,47.55 v4(46.91,47.62) ; v4(11.25,37.85) 11.41,37.69 11.41,37.49 12.5,36.39 12.5,33.33 12.79,33.04 12.79,25.29 13.15,24.93 13.15,24.59 v4(13.1,24.55)
FP_SPI_CS_N_R: length 1.9
  TOP w0.075: J6601.4 24.39,12.85 24.39,13.61 VR1508.2 C1513.2 R1529.2
FP_SPI_IRQ: length 3.1
  TOP w0.075: v6(24.24,11.51) 24.06,11.32 24.06,10.52
  LAYER_7 w0.045: v6(24.24,11.51) 24.36,11.39 24.82,11.39 v7(25.02,11.19)
  BOTTOM w0.2: v7(25.02,11.19) 25.02,10.86 ; 25.02,10.86 VR1513.1 ; 25.02,10.86 C1532.2
FP_SPI_MISO: length 98
  LAYER_3 w0.045: v4(12.63,25.4) 12.63,25.35 12.55,25.26 12.55,25.15 12.3,24.9 12.3,23.5 12.57,23.23 13.75,23.23 14.13,22.86 14.13,16.87 14.34,16.66 14.34,15.46 15.42,14.38 17.5,14.38 18.07,13.82 18.12,13.82 19.45,13.82 19.82,13.45 20.05,13.45 20.37,13.77 23.56,13.77 v2(23.93,14.14) ; v4(43.39,33.09) 43.39,33.09 43.39,33.12 43.17,33.34 42.8,33.34 42.69,33.23 34.39,33.23 28.33,39.29 27.72,39.29 26.43,40.58 22.92,40.58 22.47,41.03 16.64,41.03 16.36,40.75 15.75,40.75 15.56,40.56 13.97,40.56 11.41,38 11.41,37.73 11.29,37.61 v4(11.23,37.61) ; v2(39.66,50.98) 39.8,50.84 39.81,50.84 39.99,50.66 39.99,50.4 40.05,50.33 40.21,50.33 40.91,49.63 41.03,49.63 41.59,50.19 43.03,50.19 43.82,49.4 45,49.4 45.14,49.26 45.72,49.26 47.02,47.96 v4(47.02,47.82)
  LAYER_5 w0.045: v4(12.63,25.4) 12.63,25.58 12.7,25.65 12.7,33 12.4,33.29 12.4,36.35 11.23,37.53 v4(11.23,37.61) ; v4(43.39,33.09) 43.46,33.09 44,33.64 44,36.54 46.5,39.03 46.5,40.31 46.93,40.75 46.93,43.66 47.07,43.8 47.07,47.72 47.04,47.75 47.04,47.8 v4(47.02,47.82)
FP_SPI_MISO_R: length 2.5
  TOP w0.075: R1531.2 23.98,13.71 VR1506.2 22.97,13.71 22.97,13.71 23.47,13.71 23.76,13.42 J6601.6
FP_SPI_MOSI: length 93.6
  LAYER_3 w0.045: v4(12.71,25.12) 12.67,25.12 12.4,24.84 12.4,23.53 12.6,23.33 13.79,23.33 14.22,22.9 14.22,16.91 14.44,16.7 14.44,15.5 15.46,14.48 17.54,14.48 18.1,13.91 19.49,13.91 19.86,13.55 20.01,13.55 20.1,13.64 20.1,13.83 19.98,13.95 v2(19.9,13.95) ; v4(46.75,47.45) 46.75,47.45 46.75,47.94 45.62,49.06 45.07,49.06 44.92,49.21 43.74,49.21 42.95,50 41.66,50 41.11,49.45 40.83,49.45 40.14,50.14 39.95,50.14 39.8,50.3 39.8,50.49 v2(39.72,50.57) ; v4(11.04,37.75) 11.08,37.79 11.08,37.94 13.89,40.75 15.48,40.75 15.67,40.94 16.27,40.94 16.55,41.22 22.55,41.22 23,40.77 26.52,40.77 27.8,39.49 28.4,39.49 34.47,33.42 34.47,33.42 34.48,33.42 42.61,33.42 42.73,33.54 v4(43.52,33.54)
  LAYER_5 w0.045: v4(46.75,47.45) 46.88,47.33 46.88,43.88 46.74,43.74 46.74,40.82 46.3,40.38 46.3,39.1 43.79,36.6 43.79,33.69 43.64,33.54 v4(43.52,33.54) ; v4(11.04,37.75) 11.04,37.57 12.31,36.3 12.31,33.25 12.6,32.96 12.6,25.69 12.47,25.55 12.47,25.32 12.67,25.12 v4(12.71,25.12)
FP_SPI_MOSI_R: length 6.1
  TOP w0.075: v2(20.32,13) 20.32,13.5 ; 20.32,13.5 20.32,13.57 ; 20.32,13.5 C1512.2 20.31,13.57 20.32,13.57 ; 20.32,13.57 R1530.2 ; J6601.7 v2(23.46,11.37)
  LAYER_3 w0.045: v2(23.46,11.37) 22.96,11.87 20.83,11.87 20.48,12.22 20.48,12.83 20.32,12.99 v2(20.32,13)
FP_SPI_RST: length 2.4
  TOP w0.075: 23.16,12.83 23.16,13.29 23.03,13.42 22.77,13.42 22.47,13.71 21.92,13.71 21.85,13.78 R1527.2
G_AVDD_BYP: length 2.1
  LAYER_2 w0.075: v1(22.62,54.14) 22.26,54.5 22.19,54.5 21.56,55.13 21.56,55.27 21.67,55.38 v1(21.67,55.7)
G_VREG_XO: length 1.1
  TOP w0.1: C2319.1 18.12,54.23 18.62,54.74 U2000.211
G_VSW_S1: length 1
  TOP w0.1: U2000.77 U2000.76 U2000.75
G_VSW_S2: length 0.8
  TOP w0.1: U2000.44 U2000.22
  TOP w0.2: U2000.44 U2000.54
G_VSW_S3: length 1
  TOP w0.1: U2000.53 U2000.31 U2000.9
G_VSW_S4: length 0.8
  TOP w0.105: U2000.197 U2000.219
  TOP w0.25: U2000.185 U2000.197
GPIO19: length 4.5
  TOP w0.05: R1033.1 v2(29.69,61.48)
  LAYER_2 w0.045: v1(33,59.68) 32.88,59.56 32.25,59.56 31.95,59.86 v2(31.95,59.91)
  LAYER_3 w0.045: v2(31.95,59.91) 31.81,60.05 31.53,60.05 30.1,61.48 v2(29.69,61.48)
GPIO_4: length 65.1
  LAYER_3 w0.045: v2(8.09,52.12) v4(7.63,52.12) ; v4(12.46,22.16) 12.46,20.75 v4(12.68,20.53)
  LAYER_5 w0.045: v4(12.46,22.16) 12.19,22.43 12.19,23.96 11.9,24.25 11.9,25.9 12.13,26.13 12.13,32.57 11.82,32.88 11.82,35.91 9.88,37.86 9.88,42.46 9.99,42.57 9.99,47 8.84,48.15 8.84,49.12 8.07,49.89 8.07,51.26 7.63,51.7 v4(7.63,52.12) ; v4(12.68,20.53) 12.53,20.39 12.53,20.06 13.5,19.09 13.5,17.73 16.57,14.67 16.57,13.86 16.89,13.54 18.3,13.54 18.92,12.91 20.85,12.91 22.7,11.06 25.46,11.06 29.3,7.23 29.3,6.36 29.95,5.7 31.01,5.7 31.83,6.52 34,6.52 34.15,6.67 v7(34.15,7.13)
GPIO_5: length 65.1
  LAYER_3 w0.045: v4(12.44,20.53) 12.37,20.6 12.37,22.02 v4(12.22,22.17)
  LAYER_5 w0.045: v4(7.47,51.73) 7.98,51.22 7.98,49.85 8.74,49.08 8.74,48.11 9.89,46.96 9.89,42.61 9.79,42.5 9.79,37.82 11.73,35.87 11.73,32.84 12.03,32.53 12.03,26.17 11.8,25.94 11.8,24.21 12.1,23.92 12.1,22.3 12.22,22.18 v4(12.22,22.17) ; v6(34.44,6.29) 34.31,6.42 31.86,6.42 31.05,5.61 29.92,5.61 29.2,6.32 29.2,7.19 25.42,10.97 22.67,10.97 20.82,12.82 18.88,12.82 18.25,13.45 16.85,13.45 16.47,13.82 16.47,14.63 13.41,17.69 13.41,19.05 12.44,20.02 v4(12.44,20.53)
  LAYER_7 w0.045: v6(34.44,6.29) 34.44,5.68 v7(34.24,5.48)
GPIO_06: length 8.6
  LAYER_2 w0.045: v1(18.56,50.39) 18.85,50.39 18.95,50.49 19.51,50.49 19.63,50.37 20.31,50.37 20.59,50.65 20.59,51.37 20.31,51.65 20.19,51.65 20.08,51.76 20.08,51.95 20.63,52.5 v2(20.63,52.7) ; v1(20.46,55.98) 20.46,55.78 20.88,55.36 20.88,55.12 20.83,55.07 20.83,54.96 21.1,54.69 v2(21.1,54.33)
  LAYER_3 w0.045: v2(21.1,54.33) 20.91,54.14 20.91,53.56 20.72,53.37 20.72,53.02 20.63,52.93 v2(20.63,52.7)
GPIO_12: length 32.6
  LAYER_3 w0.045: v4(23.81,62.88) 20.89,62.88 20.58,62.57 19.77,62.57 19.65,62.69 19.52,62.69 19.43,62.6 17.44,62.6 16.87,62.03 14.89,62.03 v4(14.33,61.47) ; v6(7.6,69.02) v2(8.83,69.02) ; v4(23.91,61.06) 23.84,60.99 23.84,60.6 21.33,58.09 20.8,58.09 v2(20.73,58.16)
  LAYER_5 w0.045: v4(23.91,61.06) 23.91,62.78 v4(23.81,62.88) ; v4(14.33,61.47) 14.33,61.4 14.08,61.15 13.9,61.15 13.85,61.2 13.68,61.2 13.63,61.15 12.63,61.15 12.5,61.28 11.11,61.28 10.44,61.94 9.91,61.94 7.1,64.76 7.1,65.26 7.02,65.34 6.75,65.34 v6(6.58,65.17)
  LAYER_7 w0.045: v6(6.58,65.17) 6.31,65.44 6.31,67.67 6.58,67.94 6.71,67.94 7.39,68.62 7.39,68.81 v6(7.6,69.02)
GPS_ELNA_EN: length 10.1
  TOP w0.1: R8510.1 23.93,25.5 arc(23.94,25.58) 23.99,25.64 C8516.2
  LAYER_3 w0.045: v2(22.93,34.32) 23.06,34.19 23.06,34.14 23.19,34.01 23.19,33.72 23.43,33.48 23.95,33.48 v4(23.97,33.46)
  LAYER_5 w0.045: v4(23.97,33.46) 23.97,33.09 24.49,32.57 24.49,26.17 v4(24.21,25.89)
GPS_LNA_IN_50R: length 1
  TOP w0.088: L8502.2 22.85,24.68 U8501.5
GPS_LNA_OUT_1_50R: length 1.6
  TOP w0.088: FL8502.1 20.3,32.59 20.76,32.13 20.76,31.89 L8504.2 20.9,31.75 21.17,31.75 C8507.2
GPS_LNA_OUT_50R: length 6.6
  TOP w0.088: L8503.2 22.26,25.32 U8501.3
  LAYER_5 w0.047: v4(21.8,31.56) 21.81,31.55 21.81,28.38 arc(21.84,28.22) 21.93,28.09 arc(22.19,27.7) 22.28,27.25 v4(22.28,25.91)
GPS_NOTCH_50R: length 0.5
  TOP w0.088: 24.87,24.91 C8501.2 ; 24.87,24.91 24.86,24.9 24.86,24.87 ; 24.87,24.91 24.87,24.88 24.86,24.87 ; 24.86,24.87 L8501.1
GPS_SAW_IN_50R: length 0.6
  TOP w0.088: L8502.1 23.96,23.95 24.42,23.95 C8503.2
GPSLNA_VCC: length 2.3
  TOP w0.15: U8501.2 22.85,25.44 23.2,25.79 C8500.2 23.25,25.87 23.25,26.04 23.42,26.21 23.76,26.21 C8505.2 R8500.2
GYRO_INT: length 47.1
  TOP w0.075: v2(63.51,61.06) U6110.9 ; U6115.9 v4(51.48,41.76)
  LAYER_2 w0.045: v2(40.17,49.05) 39.88,49.05 39.46,49.47 39.46,49.71 v1(39.4,49.77)
  LAYER_3 w0.045: v4(46.04,46.29) 46.04,46.4 45.99,46.45 45.99,46.7 45.87,46.82 45.2,46.82 43.98,48.04 42.78,48.04 42.68,48.14 42.68,48.44 42.05,49.06 40.67,49.06 40.6,49.14 40.26,49.14 v2(40.17,49.05) ; v2(63.51,61.06) 64.04,60.53 64.04,57.93 64.24,57.72 64.24,50.1 62.73,48.6 62.73,46.92 60.96,45.14 59.12,45.14 58.2,44.22 53.91,44.22 53.78,44.09 53.09,44.09 52.84,43.84 51.53,43.84 v4(51.48,43.89) 51.42,43.83 50.8,43.83 50.67,43.96 46.62,43.96 46.44,44.14 v4(46.17,44.14)
  LAYER_5 w0.045: v4(46.17,44.14) 46.04,44.26 46.04,46.29 v4(46.04,46.29) ; v4(51.48,41.76) v4(51.48,43.89)
HAP_INT_N: length 63.9
  TOP w0.15: U4600.A4 9.72,16.11 v2(9.72,15.85) R4614.1
  LAYER_2 w0.045: v2(30.13,52.12) 29.89,51.88 28.91,51.88 v4(28.66,51.63)
  LAYER_3 w0.045: v2(9.72,15.85) 9.72,16.77 10.09,17.14 10.09,17.96 10.26,18.13 10.87,18.13 11.87,19.13 11.87,19.36 12.49,19.97 12.94,19.97 13.1,20.13 13.1,20.68 12.87,20.92 12.87,22.32 12.68,22.51 v4(12.46,22.51) ; v2(31.76,52.02) 31.61,52.02 31.55,51.96 30.87,51.96 30.78,52.05 30.78,52.05 30.6,52.22 30.27,52.22 30.17,52.12 v2(30.13,52.12) ; v4(10.28,38.84) 10.28,40.99 11.4,42.11 22.61,42.11 23.32,41.4 26.8,41.4 27.89,40.31 v4(28.25,40.31)
  LAYER_5 w0.045: v4(28.66,51.63) 28.63,51.61 28.61,51.61 28.61,51.19 28.35,50.93 28.35,49.88 28.5,49.73 28.5,48.94 28.02,48.46 28.02,46.47 28.36,46.14 28.36,40.43 28.25,40.32 v4(28.25,40.31) ; v4(12.46,22.51) 12.29,22.68 12.29,24 11.99,24.29 11.99,25.86 12.22,26.09 12.22,32.61 11.92,32.91 11.92,35.96 10.28,37.6 v4(10.28,38.84)
HAP_RESET: length 73.9
  LAYER_2 w0.045: v2(16.55,46.07) 16.4,46.22 15.28,46.22 14.15,45.09 12.56,45.09 v2(12.49,45.16) ; v2(34.29,50.32) 34.41,50.44 34.62,50.44 34.8,50.62 35.04,50.62 35.13,50.71 35.22,50.71 35.44,50.93 35.98,50.93 36.12,50.79 36.12,50.67 35.97,50.52 v1(35.97,50.33)
  LAYER_3 w0.045: v2(9.39,16.77) 9.39,16.35 v2(8.82,15.78) 8.81,15.78 8.81,15.76 9.07,15.5 11.21,15.5 11.44,15.73 13.88,15.73 14.15,16 14.15,16.56 13.7,17.01 13.7,17.98 13.94,18.22 13.94,22.76 13.66,23.04 12.49,23.04 12.11,23.42 12.11,23.49 12.11,25.83 12.77,26.49 12.77,28.94 12.31,30.72 12.31,34.75 11.05,36.01 10.53,36.01 7.04,39.5 7.04,44.49 7.76,45.22 12.43,45.22 v2(12.49,45.16) ; v2(16.55,46.07) 16.68,45.94 22.86,45.94 23.13,46.2 23.77,46.2 23.96,46.02 31.33,46.02 32.29,46.98 32.29,47.83 32.6,48.13 32.6,48.17 32.81,48.38 32.81,49.34 32.95,49.48 33.09,49.48 33.54,49.93 33.69,49.93 33.76,49.99 33.91,49.99 34.2,50.29 34.22,50.29 34.25,50.32 v2(34.29,50.32)
HAPTIC_OUT_N: length 16
  TOP w0.05: v2(12.5,13.52) C4607.2
  TOP w0.175: U4600.A6 8.65,16.3 v4(8.51,16.16) 8.4,16.05 v4(8.37,16.05) v4(8.19,16.05)
  TOP w0.25: C4608.2 C4607.2
  LAYER_2 w0.175: v2(12.68,13.52) v2(12.5,13.52) ; v4(8.58,16.37) 8.58,16.23 v4(8.51,16.16) 8.4,16.05 v4(8.37,16.05) v4(8.19,16.05)
  LAYER_3 w0.175: v4(8.19,16.05) v4(8.37,16.05) 8.4,16.05 v4(8.51,16.16) 8.58,16.23 v4(8.58,16.37)
  LAYER_3 w0.5: 12.42,12.71 11.92,11.62 11.56,10.93 v2(9.44,4.87)
  LAYER_4 w0.175: v4(11.67,13.97) v4(11.67,14.16) ; v4(8.58,16.37) v4(8.51,16.16) 8.4,16.05 v4(8.37,16.05) v4(8.19,16.05)
  LAYER_5 w0.175: v4(8.19,16.05) v4(8.37,16.05) 8.4,16.05 v4(8.51,16.16) 8.58,16.23 v4(8.58,16.37)
  LAYER_5 w0.5: 10.97,14.04 10.85,14.16 10.29,14.16 8.4,16.05
  vias: v1(12.63,12.85) v2(12.63,12.85)
HAPTIC_OUT_N_F: length 1.5
  TOP w0.15: J4700.6 8.16,6.02 ; J4700.4 8.5,5.94 ; J4700.2 8.84,5.89
HAPTIC_OUT_P: length 10
  TOP w0.175: v4(8.59,17.17) 8.59,17.3 v4(8.51,17.38) 8.41,17.48 v4(8.36,17.48) v4(8.18,17.48)
  TOP w0.25: C4606.2 C4609.2
  LAYER_2 w0.175: v2(11.8,13.23) v2(11.63,13.17) ; v4(8.59,17.17) 8.59,17.3 v4(8.51,17.38) 8.41,17.48 v4(8.36,17.48) v4(8.18,17.48)
  LAYER_3 w0.175: v4(8.59,17.17) 8.59,17.3 v4(8.51,17.38) 8.41,17.48 v4(8.36,17.48) v4(8.18,17.48)
  LAYER_3 w0.5: v2(10.63,10.66) 10.92,11.12 11.29,11.79 11.29,12.4
  LAYER_4 w0.175: v4(8.59,17.17) v4(8.51,17.38) 8.41,17.48 v4(8.36,17.48) v4(8.18,17.48) ; v4(9.52,14.15) v4(9.44,13.99)
  LAYER_5 w0.075: v4(8.51,17.38) 8.36,17.27
  LAYER_5 w0.175: v4(8.18,17.48) v4(8.36,17.48) 8.41,17.48 v4(8.51,17.38) 8.59,17.3 v4(8.59,17.17)
  LAYER_5 w0.5: 8.36,17.27 7.61,16.52 7.61,15.66 9.03,14.23
  vias: v1(11.68,12.68) v2(11.68,12.68)
HAPTIC_OUT_P_F: length 1.9
  TOP w0.15: J4700.3 8.9,8.28 8.98,8.67 ; 8.98,8.67 8.98,8.67 9.32,8.61 J4700.1 ; 8.98,8.67 8.98,8.67 8.63,8.73 J4700.5
HB2_SDR_DRX_50R: length 12.9
  TOP w0.088: C7863.1 23.34,29.11 23.14,29.11 22.77,28.73 22.77,28.7 C7867.1
  LAYER_7 w0.045: v6(22.8,28.63) 22.85,28.58 arc(23.18,28.35) 23.58,28.25 arc(23.68,28.25) 23.79,28.25 arc(24.08,28.3) 24.38,28.35 arc(24.84,28.42) 25.31,28.44 v6(34.74,28.44)
HB2_SDR_PRX_50R: length 2
  TOP w0.088: C7366.1 27.61,28.98 28.18,28.41 L7367.2 29.13,28.41 C7368.2
HB_CPL_ATT_50R: length 3.2
  TOP w0.088: R7177.1 40.27,17.48 40.26,17.47 40.21,17.47 40.15,17.41 v2(40.03,17.41)
  LAYER_3 w0.045: v2(40.03,17.41) 40.03,17.2 39.45,16.62 v2(37.86,16.62)
HB_CPL_OUT_50R: length 6.3
  TOP w0.088: 41.47,17.49 R7178.2 ; 41.47,17.49 v2(41.48,17.49) ; 41.47,17.49 41.39,17.49 41.38,17.48 R7177.2
  LAYER_3 w0.045: v2(41.48,17.49) 46.8,17.49 arc(46.89,17.51) 46.97,17.56 v2(47.2,17.79)
HS_MIC_BIAS_1A: length 70.6
  LAYER_3 w0.15: v4(6.56,48.24) 6.96,48.64 v4(9.83,48.64)
  LAYER_5 w0.09: v4(6.56,48.24) 6.54,48.22 6.54,47.72 6.6,47.66 6.6,36.69 8.88,34.41 8.88,20.29 14.8,14.37 14.8,13.42 17.41,10.81 17.52,10.81 21.23,10.81 22.2,9.84 25.02,9.84 28.03,6.83 28.03,6.11 29.59,4.54 31.39,4.54 v7(31.85,5)
  LAYER_5 w0.15: v4(9.83,48.64) 9.8,48.67 9.8,50.73 9.14,51.39 9.14,52.91 9.59,53.36 9.59,54.05 8.86,54.78 v4(8.86,54.92)
  BOTTOM w0.175: v7(31.85,5) 31.85,5.48 R6266.2
HS_MIC_BIAS_1B: length 76.2
  LAYER_3 w0.15: v4(6.73,48.02) 6.74,48.02 6.74,48.03 7.13,48.43 v4(9.59,48.43)
  LAYER_5 w0.09: v7(34.64,8.86) 34.64,8.37 35.39,7.62 35.39,7.42 35.25,7.29 35.25,5.68 35.23,5.67 35.23,5.67 35.01,5.44 31.94,5.44 31.65,5.15 31.65,5 31.33,4.69 29.65,4.69 28.17,6.17 28.17,6.77 28.17,6.89 25.07,9.98 22.25,9.98 21.28,10.95 17.46,10.95 14.94,13.47 14.94,14.42 9.02,20.35 9.02,34.47 6.74,36.74 6.74,47.72 6.68,47.78 6.68,47.97 v4(6.73,48.02)
  LAYER_5 w0.15: v4(8.85,54.48) 9.39,53.94 9.39,53.45 8.93,52.99 8.93,51.28 9.59,50.61 v4(9.59,48.43)
HW_ID_1: length 11.3
  TOP w0.05: U1001.AM2 33.46,59.68 v2(33.45,59.67)
  LAYER_3 w0.045: v4(27.24,63.71) 27.25,63.71 27.4,63.86 27.4,64.54 27.15,64.78 27.02,64.78 v2(26.88,64.93) ; v2(33.45,59.67) 33.49,59.71 33.49,60.16 33.19,60.46 33.12,60.46 33.02,60.56 33.02,60.92 32.8,61.13 32.8,62.89 32.32,63.36 v4(32.32,63.5)
  LAYER_5 w0.045: v4(27.24,63.71) 27.25,63.71 27.25,63.7 27.3,63.65 31.15,63.65 31.28,63.77 31.92,63.77 32.02,63.67 32.16,63.67 v4(32.32,63.5)
HW_ID_2: length 11.8
  LAYER_3 w0.045: v2(33.25,59.48) 33.25,59.72 33.38,59.85 33.38,60.13 33.14,60.37 33.08,60.37 32.92,60.52 32.92,60.87 32.71,61.09 32.71,62.83 32.06,63.48 v4(32.06,63.5) ; v2(26.34,64.93) 26.34,64.72 26.31,64.69 26.31,63.87 26.61,63.57 27.04,63.57 v4(27.1,63.51)
  LAYER_5 w0.045: v4(27.1,63.51) 27.14,63.55 31.19,63.55 31.32,63.68 31.88,63.68 v4(32.06,63.5)
HWID1: length 1.4
  TOP w0.075: R1129.2 C1130.2 R1131.1 R1127.1
HWID2: length 1.4
  TOP w0.075: R1128.1 R1132.1 R1130.2 C1131.2
I2C_SCL_TS_FL: length 1.2
  BOTTOM w0.079: J5300.25 54.09,65.11 C5321.2 E5304.2
I2C_SDA_TS_FL: length 1.5
  BOTTOM w0.05: C5320.2 54.72,65.24 54.56,65.24 54.48,65.32 54.48,65.61 J5300.23
  BOTTOM w0.079: E5305.2 C5320.2
JTAG_GPIO: length 6
  BOTTOM w0.075: Q1020.1 45.38,50.32 45.03,50.68 44.27,50.68 44.19,50.6 44.19,48.92 43.94,48.67 43.94,48.22 ; Q1020.1 45.39,49.16 R1021.1 ; Q1020.1 45.4,50.32 TP_FORCEFLASH.1
JTAG_PS_HOLD: length 46.6
  LAYER_2 w0.045: v4(23.35,47.17) 22.77,46.59 22.77,45.18 22.09,44.5 22.09,44.26 v2(22.08,44.25)
  LAYER_3 w0.045: v2(22.08,44.25) 22.15,44.32 25.56,44.32 25.81,44.58 32.02,44.58 32.27,44.83 36.02,44.83 36.39,44.45 38.25,44.45 38.26,44.45 38.27,44.45 38.8,43.92 41.6,43.92 42.14,43.38 v4(42.63,43.38) ; v2(22,54.99) 22.36,54.63 22.36,53.24 22.55,53.05 22.55,52.26 23.18,51.63 23.23,51.63 v4(23.33,51.73) 23.33,51.57 26.89,51.57 27.73,52.41 28.03,52.41 28.04,52.42 28.06,52.42 28.39,52.76 31.64,52.76 31.86,52.53 32.09,52.53 32.2,52.64 32.45,52.64 v2(32.51,52.7)
  LAYER_5 w0.045: v4(23.35,47.17) 23.41,47.24 23.41,51.64 v4(23.33,51.73) ; v6(42.62,45.56) 42.63,45.55 v4(42.63,43.38)
  LAYER_7 w0.045: v7(43.55,45.56) v6(42.62,45.56)
  BOTTOM w0.05: JTAG.15 v7(43.55,45.56)
JTAG_RTCK: length 1.5
  BOTTOM w0.075: TP_JTAG_RTCK.1 46.8,44.8 46.24,44.8 45.94,45.1 JTAG.3
JTAG_SRST_N: length 5.4
  TOP w0.1: v2(41.98,49.64) 42.01,49.61 R1007.2
  LAYER_3 w0.045: v2(39.72,49.49) 40.06,49.49 40.14,49.41 40.46,49.41 40.71,49.16 41.24,49.16 41.72,49.64 v2(41.98,49.64)
  BOTTOM w0.075: C1023.2 43.28,49.64 v7(42.48,49.64)
  BOTTOM w0.088: 43.54,48.22 43.54,48.63 43.37,48.8 C1024.2 C1023.2
JTAG_TCK: length 6.9
  LAYER_2 w0.045: v1(40.17,50.09) 40.32,50.09 40.93,49.48 42.63,49.48 v2(42.79,49.64)
  LAYER_3 w0.045: v7(45.94,48.16) 45.34,48.76 44.97,48.76 44.81,48.92 43.61,48.92 42.89,49.64 v2(42.79,49.64)
  BOTTOM w0.075: 45.94,48.22 45.94,48.29 45.96,48.29 45.96,48.18 v7(45.94,48.16)
JTAG_TDI: length 6.1
  TOP w0.05: v2(43.17,48.98) 43.16,48.97 42.93,48.97 42.58,49.31 41.07,49.31 40.85,49.53 U1001.C43
  LAYER_3 w0.045: v7(45.54,47.76) 45.54,47.9 44.72,48.72 43.52,48.72 43.26,48.98 v2(43.17,48.98)
  BOTTOM w0.075: v7(45.54,47.76) 45.54,48.22
JTAG_TDO: length 8.1
  TOP w0.05: U1001.D42 40.42,49.47 40.58,49.31 40.93,49.31 41.03,49.21 42.54,49.21 42.9,48.85 42.9,48.85 43,48.75 43,48.74 43.04,48.71 v2(43.27,48.71)
  LAYER_3 w0.045: v2(43.27,48.71) 43.36,48.62 44.68,48.62 45.38,47.92 45.38,47.66 45.47,47.57 46.07,47.57 46.25,47.39 v4(46.34,47.39)
  LAYER_5 w0.045: v7(46.34,47.58) v4(46.34,47.39)
  BOTTOM w0.075: v7(46.34,47.58) 46.34,48.22
JTAG_TMS: length 10.9
  LAYER_2 w0.045: v1(39.87,49.79) 39.93,49.73 40.27,49.73 40.81,49.2 42.05,49.2 42.13,49.12 v2(42.34,49.12)
  LAYER_3 w0.045: v4(45.8,47.17) 45.8,47.27 45.72,47.35 45.21,47.35 44.13,48.43 43.19,48.43 43,48.61 43,48.75 42.89,48.86 42.8,48.86 42.54,49.12 v2(42.34,49.12)
  LAYER_5 w0.045: v7(45.79,44.8) 45.77,44.81 45.77,46.39 45.98,46.59 45.98,46.88 45.88,46.98 45.88,47.09 v4(45.8,47.17)
  BOTTOM w0.05: 45.54,45.05 v7(45.79,44.8)
  BOTTOM w0.075: C1020.2 45.54,44.98 JTAG.5
JTAG_TRST_N: length 12.5
  LAYER_2 w0.045: v1(39.93,50.27) 39.93,50.1 40.11,49.93 40.35,49.93 40.89,49.38 42.52,49.38 42.73,49.18 43.03,49.18 v2(43.07,49.22)
  LAYER_3 w0.045: v4(46.34,46.6) 46.34,46.9 46.5,47.05 46.5,47.49 46.43,47.56 46.29,47.56 45.19,48.66 44.92,48.66 44.76,48.81 43.56,48.81 43.16,49.22 v2(43.07,49.22)
  LAYER_5 w0.045: v4(46.34,46.6) 46.34,46.08 v6(46.32,46.08)
  LAYER_7 w0.045: v7(44.74,45.56) 45.25,46.08 v6(46.32,46.08)
  BOTTOM w0.075: v7(44.74,45.56) 44.74,44.86 C1022.2 C1021.2
KEY_VOL_DN: length 33.1
  TOP w0.075: C5516.2 35.34,64.27 34.97,64.27 v4(34.86,64.38) 35.23,64.75 35.23,65.09 35.26,65.12
  LAYER_2 w0.045: v1(21.99,55.51) 22.47,55.51 v4(22.51,55.47)
  LAYER_5 w0.045: v6(40.53,65.09) 40.39,65.09 40.03,64.73 40.03,64.38 39.73,64.09 38.65,64.09 38,64.74 35.51,64.74 35.15,64.38 v4(34.86,64.38) 34.63,64.61 34.09,64.61 33.8,64.32 32.22,64.32 31.86,63.97 31.2,63.97 31.07,63.84 27.47,63.84 27.34,63.97 27.13,63.97 26.83,63.66 26.56,63.66 26.56,63.66 26.38,63.48 26.38,63.2 26.51,63.08 26.51,62.5 26.26,62.25 26.26,61.83 25.94,61.51 25.94,61.37 25.7,61.13 25.7,59.15 26.21,58.64 26.21,57.99 25.01,56.8 24.65,56.8 24.32,56.47 24.32,56.45 24.32,56.22 23.58,55.47 v4(22.51,55.47)
  LAYER_7 w0.045: v7(44.49,64.59) 42.95,64.59 42.45,65.09 v6(40.53,65.09)
KEY_VOL_UP: length 77.7
  TOP w0.075: J5500.28 34.88,65.09 34.88,64.71 C5517.2
  LAYER_3 w0.045: v4(45.01,64.9) 44.84,65.07 42.99,65.07 42.8,64.88 41.22,64.88 41.08,64.74 40.64,64.74 v4(40.64,64.72) ; v4(50.38,41.38) 50.22,41.22 48.13,41.22 44.99,38.08 41.52,38.08 40.16,39.45 38.42,39.45 38.18,39.21 37.78,39.21 37.56,39.43 37.37,39.43 v2(37.27,39.53) ; v2(57.28,56.79) 56.92,56.79 56.8,56.67 56.8,56.03 v2(57.12,55.71) 57.25,55.84 58.07,55.84 v4(58.47,55.44) ; v4(58,42.67) 57.92,42.59 56.42,42.59 56.38,42.64 56.01,42.64 55.93,42.56 54.01,42.56 53.68,42.23 50.44,42.23 v4(50.38,42.29)
  LAYER_5 w0.045: v4(34.51,64.31) 34.92,63.9 39.82,63.9 v4(40.64,64.72) ; v4(58.47,55.44) 58.84,55.07 58.84,44.58 58.7,44.45 58.7,43.91 58,43.21 v4(58,42.67) ; v4(45.01,64.9) 45.01,63.96 50.59,58.38 50.59,42.5 v4(50.38,42.29) v4(50.38,41.38)
KYPD_PWR_N: length 28.4
  TOP w0.05: v2(36.74,64) 36.58,64.16 36.55,64.16 36.4,64.31 C5521.2 36.4,64.4 36.14,64.66 35.74,64.66 35.66,64.74 35.66,65.08 J5500.24
  LAYER_2 w0.045: v2(21.63,59.15) 21.45,59.33 21.3,59.33 21.27,59.36 21.12,59.36 20.77,59.01 20.77,58.58 20.22,58.03 20.01,58.03 v1(19.98,58)
  LAYER_3 w0.045: v7(24.01,63.47) 23.97,63.43 23.97,62.44 23.43,61.9 23.43,60.77 21.82,59.15 v2(21.63,59.15) ; v2(36.74,64) 36.74,64.12 36.95,64.33 36.95,64.5 37.14,64.69 37.14,65.35 37.4,65.61 v6(37.4,65.64)
  LAYER_5 w0.045: v7(24.01,63.47) 24.01,64.61 25.06,65.66 28.63,65.66 29.26,66.28 30.35,66.28 30.57,66.5 v6(30.57,66.62)
  LAYER_7 w0.045: v6(30.57,66.62) 30.97,66.22 36.82,66.22 v6(37.4,65.64)
  BOTTOM w0.175: v7(24.01,63.47) TP_PWR_KEY.1
LB_PA_IN_50R: length 1.3
  TOP w0.088: C7114.2 53.29,22.24 L7115.2 53.27,21.87 52.63,21.87 U7100.26
LCD_RST_N: length 37.1
  LAYER_5 w0.045: v6(57.14,64.4) 57.28,64.4 57.59,64.1 57.59,63.59 57.65,63.53 57.65,56.45 57.59,56.39 57.58,56.39 57.57,56.39 v6(57.57,56.38)
  LAYER_7 w0.045: v7(55.49,65.39) 55.7,65.18 55.93,65.18 55.98,65.13 56.78,65.13 v7(56.91,65) 56.77,64.86 56.77,64.48 56.88,64.37 57.11,64.37 v6(57.14,64.4) ; v6(57.57,56.38) 57.57,56.27 57.13,55.83 57.05,55.83 55.69,54.46 55.69,54.3 55.25,53.87 54.79,53.87 54.79,53.87 52.37,51.45 50.28,51.45 48.93,50.1 45.06,50.1 43.36,51.8 42.64,51.8 42.24,52.2 41.31,52.2 41.13,52.38 39.18,52.38 38.81,52.02 37.4,52.02 37.01,51.62 37.01,51.11 37,51.1 37,50.96 36.99,50.96 36.94,50.96 36.7,50.72 v6(36.7,50.48)
  BOTTOM w0.05: J5300.17 v7(55.49,65.39)
LCD_TE: length 35.3
  LAYER_5 w0.045: v6(59.61,56.46) 59.64,56.5 59.64,56.85 59.45,57.04 59.45,60.4 59.28,60.57 59.28,61.86 59.54,62.12 59.54,64.58 v7(59.55,64.59)
  LAYER_7 w0.045: v6(37.23,50.48) 37.23,50.48 37.55,50.48 39.26,52.19 41.06,52.19 41.24,52.01 42.17,52.01 42.56,51.62 43.28,51.62 45,49.9 49.01,49.9 50.36,51.26 52.45,51.26 54.87,53.67 54.87,53.68 54.87,53.68 55.33,53.68 55.88,54.22 55.88,54.38 57.13,55.64 57.22,55.64 58.08,56.5 59.57,56.5 v6(59.61,56.46)
LDC_PWR_KEY: length 1.7
  TOP w0.2: C1517.2 26.02,13.47 25.71,13.16 25.05,13.16 J6601.2
LDC_PWRKEEY_COM: length 1.3
  TOP w0.175: v1(24.66,11.17) v1(24.66,9.88)
  vias: v1(26.56,11.29)
LDSP_L_DM: length 25.5
  TOP w0.1: C4675.2 16.71,15.65 L6402.2
  LAYER_2 w0.175: v6(16.88,15.73) v6(17.02,15.62)
  LAYER_3 w0.175: v6(16.88,15.73) v6(17.02,15.62)
  LAYER_4 w0.175: v6(16.88,15.73) v6(17.02,15.62)
  LAYER_5 w0.175: v6(16.88,15.73) v6(17.02,15.62)
  LAYER_6 w0.175: v6(16.88,15.73) v6(17.02,15.62)
  LAYER_7 w0.045: v6(35.76,14.7) 35.8,14.74 36.64,14.74 37.17,14.21 37.35,14.21 37.61,13.95
  LAYER_7 w0.75: 37.61,13.8 37.61,14.82 37.04,15.39 33.56,15.39 33.38,15.57 17.36,15.57
  vias: v7(37.36,13.33) v7(37.59,12.77) v7(38.09,12.77) v7(38.63,12.77) v7(39.19,12.95) v7(39.19,12.77) v7(39.19,12.58)
LDSP_P_DM: length 25.2
  TOP w0.1: C4674.2 16.08,15.66 v6(16.05,15.69)
  LAYER_2 w0.175: v6(15.93,15.82) v6(16.05,15.69)
  LAYER_3 w0.175: v6(15.93,15.82) v6(16.05,15.69)
  LAYER_4 w0.175: v6(15.93,15.82) v6(16.05,15.69)
  LAYER_5 w0.175: v6(15.93,15.82) v6(16.05,15.69)
  LAYER_6 w0.175: v6(15.93,15.82) v6(16.05,15.69)
  LAYER_7 w0.045: v6(35.99,14.57) 36.03,14.61 36.63,14.61 37.05,14.19 37.05,13.84 36.74,13.53 36.74,13.35
  LAYER_7 w0.75: 36.74,13.45 36.3,13.89 35.32,13.89 34.63,14.58 33.18,14.58 33,14.76 16.96,14.76 16.12,15.6
  vias: v7(35.08,12.93) v7(35.08,12.75) v7(35.08,12.57) v7(35.65,12.77) v7(36.17,12.77) v7(36.67,12.77) v7(36.9,13.33)
LED_SOL_SRC: length 57.6
  TOP w0.075: v2(11.72,65.8) 11.76,65.8 11.98,65.58 J5502.24
  LAYER_2 w0.045: v2(37.81,40.67) 37.82,40.67 v1(37.94,40.79)
  LAYER_3 w0.045: v4(6.5,59.47) 6.55,59.52 6.55,59.81 7.69,60.95 7.69,62.51 10.05,64.87 10.5,64.87 11.11,65.47 11.11,65.66 11.25,65.8 v2(11.72,65.8) ; v4(9.72,43.14) 9.84,43.26 10.43,43.26 10.97,42.73 22.24,42.73 22.31,42.8 26.77,42.8 27.1,42.47 27.8,42.47 28.03,42.24 33.04,42.24 33.22,42.07 33.78,42.07 34.4,41.45 34.86,41.45 35.17,41.14 35.61,41.14 36.31,40.44 37.58,40.44 v2(37.81,40.67)
  LAYER_5 w0.045: v4(9.72,43.14) 9.8,43.22 9.8,46.91 8.65,48.06 8.65,49.03 7.88,49.8 7.88,51.06 7.11,51.83 7.11,55.61 7.64,56.14 7.64,56.72 7.46,56.9 7.46,57.85 6.5,58.81 v4(6.5,59.47)
LNA_EN_5G_CH0: length 6.2
  TOP w0.05: v2(54.76,29.84) 54.97,30.04 U4080.9
  LAYER_3 w0.045: v2(56.04,34.1) 55.79,34.1 55.66,34.23 55.52,34.23 55.43,34.14 55.43,34 55.47,33.96 55.47,33.83 55.02,33.39 55.02,31.42 54.63,31.02 54.63,30.64 54.48,30.49 54.48,30.12 v2(54.76,29.84)
LNA_EN_5G_CH1: length 9
  TOP w0.05: U4090.9 48.33,35.52 C4097.2
  LAYER_3 w0.045: v2(48.48,35.65) 48.78,35.95 49.16,35.95 49.33,35.78 49.33,35.59 49.42,35.5 49.56,35.5 49.9,35.84 50.98,35.84 51.1,35.72 51.1,35.09 51.37,34.83 52.44,34.83 52.59,34.97 52.87,34.97 52.96,34.88 53.12,34.88 53.28,34.71 53.29,34.71 53.4,34.6 53.4,34.58 53.5,34.49 53.66,34.49 54.15,34.97 54.64,34.97 54.68,35.01 55.02,35.01 v2(55.05,35.04)
LP4X_BUCK_MODE: length 34
  LAYER_2 w0.045: v1(36.24,42.53) 36.45,42.53 36.62,42.36 36.75,42.36 36.89,42.5 37.07,42.5 v2(37.48,42.09)
  LAYER_3 w0.045: v4(58.68,42.63) 58.55,42.5 56.39,42.5 56.35,42.54 56.05,42.54 55.97,42.47 54.05,42.47 53.72,42.13 48.47,42.13 48.35,42.01 43.91,42.01 43.35,42.57 41.94,42.57 41.65,42.86 40.19,42.86 39.68,42.34 38.67,42.34 38.54,42.46 38.39,42.46 38.06,42.13 37.86,42.13 37.84,42.16 37.55,42.16 v2(37.48,42.09) ; v2(58.67,50.89) 58.92,50.65 59.68,50.65 v4(59.79,50.76)
  LAYER_5 w0.045: v4(58.68,42.63) 58.68,43.28 59.63,44.23 59.63,47.36 60.13,47.86 60.13,50.03 59.79,50.37 v4(59.79,50.76)
LP4X_REG_SRC_EN: length 68.4
  LAYER_3 w0.045: v2(21.09,61.04) 21.29,60.84 21.29,59.77 20.72,59.2 20.72,58.64 v4(20.7,58.62) ; v4(22.56,42.95) 22.63,42.89 26.81,42.89 27.14,42.56 27.84,42.56 28.07,42.34 33.08,42.34 33.26,42.16 34.27,42.16 34.53,41.9 35.06,41.9 35.57,41.39 35.87,41.39 35.91,41.42 36.07,41.42 36.54,40.95 37.31,40.95 37.49,41.13 37.64,41.13 37.84,40.92 38.37,40.92 38.43,40.87 46.17,40.87 46.2,40.9 46.82,40.9 47.82,41.91 48.38,41.91 48.51,42.04 53.77,42.04 54.11,42.37 56.03,42.37 56.1,42.45 56.3,42.45 56.35,42.4 v4(58.69,42.4) ; v2(58.26,50.89) 58.41,50.89 58.76,50.54 v4(59.96,50.54)
  LAYER_5 w0.045: v4(59.96,50.54) 59.96,50.34 60.23,50.07 60.23,47.82 59.73,47.32 59.73,44.19 58.85,43.31 58.85,42.56 v4(58.69,42.4) ; v4(20.7,58.62) 20.88,58.45 20.88,58.32 22.35,56.85 22.35,55.4 22.96,54.79 22.96,52.15 23.06,52.05 23.06,51.59 23.22,51.43 23.22,50.46 22.95,50.19 22.95,49.92 23.13,49.75 23.13,47.46 22.95,47.29 22.95,43.63 22.56,43.24 v4(22.56,42.95)
LV_LDO_EN: length 18.3
  LAYER_2 w0.045: v2(23.92,43.05) 23.92,47.92 24.24,48.24 24.24,48.63 v1(24.34,48.73)
  LAYER_3 w0.045: v2(35.77,41.55) 35.54,41.55 35.09,42 34.57,42 34.31,42.26 33.3,42.26 33.12,42.43 28.11,42.43 27.88,42.66 27.18,42.66 26.85,42.98 24.01,42.98 23.94,43.05 v2(23.92,43.05)
LV_LDO_VSEL: length 19.2
  LAYER_2 w0.045: v2(24.39,43.34) 24.39,43.34 24.51,43.47 24.51,47.16 v2(24.41,47.26) ; v1(36.98,42.29) 36.98,42.1 36.8,41.92 36.56,41.92 36.15,42.33 v2(36,42.33)
  LAYER_3 w0.045: v2(23.97,48.72) 24.08,48.61 24.08,48.06 24.41,47.73 v2(24.41,47.26) ; v2(36,42.33) 35.95,42.28 35.6,42.28 35.49,42.39 34.72,42.39 34.47,42.64 33.46,42.64 33.29,42.81 28.26,42.81 28.04,43.04 27.56,43.04 27.33,43.27 24.39,43.27 v2(24.39,43.34)
MAG_DRDY: length 73.3
  LAYER_2 w0.045: v1(39.2,50.07) 39.46,50.07 39.7,49.84 39.7,49.74 39.82,49.62 39.93,49.62 40.14,49.41 40.46,49.41 40.77,49.1 42.02,49.1 42.84,48.28 v2(42.84,48.22)
  LAYER_3 w0.045: v2(64.23,39.43) 64.39,39.59 64.39,40.1 64.86,40.57 64.86,44.25 63.49,45.61 63.49,48.28 65,49.79 65,58.07 64.81,58.27 64.81,58.82 64.94,58.95 64.94,59.33 64.62,59.65 64.62,60.35 v2(64.79,60.52) 64.62,60.69 64.62,62.25 64.77,62.4 64.77,63.56 64.91,63.7 64.91,64.44 64.37,64.98 61.69,64.98 61.02,64.31 61.02,63.44 60.65,63.07 59.85,63.07 59.24,63.67 v4(57.75,63.67) ; v2(42.84,48.22) 42.93,48.13 44.02,48.13 45.24,46.91 45.91,46.91 46.08,46.74 46.08,46.49 46.23,46.34 46.45,46.34 46.51,46.4 46.95,46.84 50.06,46.84 50.36,47.15 52.17,47.15 54.76,49.73 56.44,49.73 v4(57.6,48.58)
  LAYER_5 w0.045: v4(57.6,48.58) 57.41,48.77 57.41,55.96 57.75,56.3 v4(57.75,63.67)
MAG_VDD_ISO: length 1.1
  TOP w0.2: U6130.B1 64.25,39.01 C6130.2 R6131.1
MB_CPL_OUT_50R: length 15
  LAYER_3 w0.045: v6(45.92,15.25) 47.48,16.8 arc(47.6,16.99) 47.65,17.2 v2(47.65,17.79)
  LAYER_7 w0.045: v6(34.77,16.7) 39.03,16.7 40.48,15.25 v6(45.92,15.25)
MB_MAIN_POST_5G_FLT_50R: length 1.4
  TOP w0.088: C7173.1 38.58,14.64 L7172.2 38.6,14.33 38.59,14.33 FL7170.3
MB_MAIN_PRE_5G_FLT_50R: length 1.7
  TOP w0.088: C7170.2 36.44,14.75 L7171.2 36.89,14.25 arc(37.22,14.11) FL7170.1
MBDRX_HBTRX_50R: length 1.5
  TOP w0.088: FL7003.5 28.45,13.63 27.77,13.63 L7004.2 27.7,14.2 C7003.2
MEM_THERM: length 47.5
  LAYER_2 w0.045: v2(26.75,46.66) 26.81,46.59 26.81,44.25 26.71,44.14 v2(26.71,44.13)
  LAYER_3 w0.045: v2(26.75,46.66) 26.68,46.73 22.49,46.73 21.2,48.02 20.4,48.02 19.66,48.76 19.66,49.51 20.62,50.46 20.62,52.01 19.96,52.67 19.96,53.47 20.32,53.83 20.32,54.66 20.41,54.75 21.1,54.75 21.57,55.22 21.57,55.52 21.32,55.76 v2(21.23,55.76) ; v2(26.71,44.13) 26.8,44.13 26.87,44.2 32.45,44.2 32.67,44.42 34.18,44.42 34.4,44.2 36.13,44.2 36.2,44.27 38.17,44.27 39.39,43.05 41.73,43.05 42.02,42.76 43.44,42.76 44,42.2 45.75,42.2 45.78,42.23 45.78,42.24 45.87,42.33 46.07,42.33 46.29,42.11 48.2,42.11 v4(48.34,42.24)
  LAYER_5 w0.045: v4(48.34,42.24) 48.31,42.27 48.31,47.08 48.27,47.12 v4(48.27,47.29)
MIPI_CSI_FRONT<0>: length 9.2
  TOP w0.088: J5500.47 v2(31.41,66.74)
  LAYER_3 w0.045: v2(31.41,66.74) 31.52,66.63 31.53,66.63 33.22,64.94 arc(33.32,64.79) 33.36,64.61 33.36,63.97 33.22,63.84 33.22,61.01 33.35,60.88 33.35,60.48 33.66,60.16 33.66,59.64 33.36,59.33 33.36,59.22 33.39,59.19 v2(33.45,59.19)
MIPI_CSI_FRONT<1>: length 9.4
  TOP w0.088: J5500.45 v2(31.76,66.73)
  LAYER_3 w0.045: v2(33.3,58.93) 33.38,59.01 33.52,59.01 33.62,59.12 33.62,59.47 33.76,59.6 33.76,60.2 33.45,60.51 33.45,60.92 33.32,61.05 33.32,63.8 33.45,63.93 arc(33.45,63.94) 33.45,63.95 33.45,64.61 arc(33.41,64.83) 33.29,65.01 31.76,66.53 v2(31.76,66.73)
MIPI_CSI_FRONT<2>: length 9.1
  TOP w0.088: J5500.41 v2(32.46,66.73)
  LAYER_3 w0.045: v2(33.76,58.91) 33.76,59.39 33.86,59.5 33.86,60.29 33.57,60.58 33.57,61.12 33.46,61.23 33.46,63.74 33.55,63.83 33.55,65.2 arc(33.52,65.38) 33.41,65.54 32.75,66.2 arc(32.65,66.35) 32.62,66.53 32.62,66.78 32.58,66.82 32.49,66.82 32.46,66.8 v2(32.46,66.73)
MIPI_CSI_FRONT<3>: length 9.4
  TOP w0.088: 32.81,67.16 v2(32.81,66.74)
  LAYER_3 w0.045: v2(33.54,58.71) 33.8,58.71 33.92,58.83 33.92,58.84 33.92,59.05 33.86,59.11 33.86,59.36 33.96,59.46 33.96,60.33 33.66,60.62 33.66,61.16 33.56,61.27 33.56,63.7 33.65,63.79 33.65,65.2 arc(33.6,65.42) 33.48,65.6 32.87,66.22 arc(32.78,66.35) 32.75,66.51 32.75,66.67 v2(32.81,66.74)
MIPI_CSI_FRONT<4>: length 9.2
  TOP w0.088: 33.51,67.16 v2(33.51,66.73)
  LAYER_3 w0.045: v2(34.18,59.43) 34.16,59.43 34.09,59.51 34.09,60.35 33.95,60.49 33.95,60.81 34.11,60.97 34.11,61.32 arc(34.07,61.5) 33.97,61.65 33.97,61.66 33.84,61.79 arc(33.72,61.96) 33.68,62.17 33.68,63.62 33.76,63.7 33.76,65.99 33.7,66.04 33.46,66.04 33.36,66.15 33.36,66.38 33.46,66.48 33.73,66.48 33.76,66.52 33.76,66.61 33.7,66.67 33.7,66.88 33.67,66.91 33.57,66.91 33.51,66.86 v2(33.51,66.73)
MIPI_CSI_FRONT<5>: length 9.2
  TOP w0.088: J5500.33 v2(33.86,66.73)
  LAYER_3 w0.045: v2(34.04,59.18) 34.25,59.18 34.37,59.3 34.37,59.51 34.19,59.69 34.19,60.39 34.05,60.53 34.05,60.77 34.21,60.93 34.21,61.32 arc(34.16,61.54) 34.04,61.72 34.04,61.72 33.91,61.85 arc(33.81,62) 33.78,62.17 33.78,63.58 33.85,63.66 33.85,66.03 33.74,66.14 33.5,66.14 33.45,66.19 33.45,66.34 33.5,66.39 33.76,66.39 33.85,66.48 33.85,66.65 33.85,66.66 33.85,66.72 v2(33.86,66.73)
MIPI_CSI_REAR<0>: length 9.4
  TOP w0.088: J5500.29 v2(34.56,66.73)
  LAYER_3 w0.045: v2(34.56,66.73) 34.69,66.61 34.69,66.28 arc(34.72,66.1) 34.83,65.94 34.91,65.85 arc(35.14,65.52) 35.22,65.12 35.22,63.57 35.2,63.57 arc(35.04,63.41) 35.2,63.24 arc(35.21,63.24) 35.22,63.23 35.22,63.11 35.2,63.11 arc(35.04,62.95) 35.2,62.78 arc(35.21,62.78) 35.22,62.77 35.22,62.19 35.2,62.19 arc(35.04,62.02) 35.2,61.86 arc(35.21,61.85) 35.22,61.84 35.22,60.39 arc(35.19,60.25) 35.11,60.13 arc(34.98,59.93) 34.93,59.7 34.93,58.8 arc(34.94,58.74) v2(34.98,58.69)
MIPI_CSI_REAR<1>: length 9.2
  TOP w0.088: 34.91,67.16 v2(34.91,66.73)
  LAYER_3 w0.045: v2(34.91,66.73) 34.78,66.61 34.78,66.34 34.78,66.28 arc(34.81,66.13) 34.89,66.01 34.98,65.92 arc(35.22,65.55) 35.31,65.12 35.31,63.57 arc(35.28,63.5) 35.22,63.48 35.2,63.48 arc(35.13,63.41) 35.2,63.34 arc(35.28,63.31) 35.31,63.23 35.31,63.1 arc(35.28,63.04) 35.22,63.01 35.2,63.01 arc(35.13,62.95) 35.2,62.88 arc(35.28,62.85) 35.31,62.77 35.31,62.14 arc(35.3,62.1) 35.27,62.09 35.2,62.09 arc(35.13,62.02) 35.2,61.95 arc(35.28,61.92) 35.31,61.84 35.31,60.39 arc(35.28,60.21) 35.18,60.06 arc(35.06,59.89) 35.03,59.7 35.03,59.08 arc(35.06,59) 35.15,58.96 v2(35.18,58.96)
MIPI_CSI_REAR<2>: length 9.3
  TOP w0.088: J5500.21 v2(35.96,66.73)
  LAYER_3 w0.045: v2(35.96,66.73) 35.96,66.64 arc(35.94,66.52) 35.88,66.43 35.84,66.4 arc(35.74,66.25) 35.71,66.07 35.71,63.39 arc(35.75,63.15) 35.88,62.96 arc(35.94,62.87) 35.97,62.76 35.97,60.49 arc(35.93,60.3) 35.82,60.13 35.61,59.92 arc(35.54,59.83) 35.52,59.72 35.52,58.99 arc(35.53,58.91) 35.58,58.83 arc(35.58,58.83) 35.58,58.82 arc(35.59,58.82) 35.6,58.81 arc(35.64,58.59) 35.45,58.47 v2(35.27,58.47)
MIPI_CSI_REAR<3>: length 9.3
  TOP w0.088: 35.61,67.16 v2(35.61,66.73)
  LAYER_3 w0.045: v2(35.43,58.7) 35.4,58.72 arc(35.36,58.81) 35.37,58.9 arc(35.41,59.01) 35.43,59.12 35.43,59.75 arc(35.46,59.88) 35.54,59.99 35.75,60.2 arc(35.84,60.33) 35.87,60.49 35.87,62.76 arc(35.86,62.83) 35.82,62.89 arc(35.66,63.12) 35.61,63.39 35.61,66.17 arc(35.65,66.36) 35.76,66.53 35.78,66.55 35.78,66.89 arc(35.76,66.93) 35.73,66.94 35.66,66.94 arc(35.62,66.93) 35.61,66.89 v2(35.61,66.73)
MIPI_CSI_REAR<4>: length 9.5
  TOP w0.088: J5500.17 v2(36.66,66.74)
  LAYER_3 w0.045: v2(35.77,58.95) 35.77,59.62 arc(35.8,59.8) 35.91,59.96 arc(36.08,60.22) 36.14,60.53 36.14,63.83 arc(36.16,63.88) 36.22,63.91 arc(36.23,63.91) 36.23,63.91 arc(36.29,63.98) 36.23,64.04 arc(36.23,64.04) 36.22,64.04 36.22,64.04 arc(36.16,64.07) 36.14,64.12 36.14,64.29 arc(36.16,64.35) 36.22,64.37 arc(36.23,64.37) 36.23,64.37 arc(36.29,64.44) 36.23,64.5 arc(36.23,64.5) 36.22,64.5 36.22,64.5 arc(36.16,64.53) 36.14,64.58 36.14,64.75 arc(36.16,64.81) 36.22,64.83 arc(36.23,64.83) 36.23,64.83 arc(36.29,64.9) 36.23,64.97 arc(36.23,64.97) 36.22,64.97 36.22,64.97 arc(36.16,64.99) 36.14,65.04 36.14,65.29 36.23,65.29 arc(36.29,65.36) 36.23,65.43 36.14,65.43 36.14,65.88 arc(36.21,66.05) 36.38,66.12 arc(36.69,66.24) 36.82,66.56 36.82,66.58 v2(36.66,66.74)
MIPI_CSI_REAR<5>: length 9.2
  TOP w0.088: J5500.15 v2(37.01,66.74)
  LAYER_3 w0.045: v2(37.01,66.74) 36.92,66.64 36.92,66.56 arc(36.76,66.18) 36.38,66.02 arc(36.28,65.98) 36.24,65.88 36.24,65.52 arc(36.39,65.36) 36.24,65.2 36.24,65.06 arc(36.39,64.9) 36.24,64.74 36.24,64.6 arc(36.39,64.44) 36.24,64.27 36.24,64.14 arc(36.39,63.98) 36.24,63.81 36.24,60.53 arc(36.17,60.18) 35.97,59.89 arc(35.89,59.77) 35.86,59.62 35.86,59.28 35.92,59.23 v2(35.97,59.23)
MIPI_CSI_REAR<6>: length 9.4
  TOP w0.088: J5500.9 v2(38.06,66.73)
  LAYER_3 w0.045: v2(35.97,58.69) 36.05,58.69 arc(36.15,58.71) 36.23,58.76 36.31,58.84 arc(36.33,58.87) 36.34,58.91 36.34,59.55 arc(36.35,59.6) 36.37,59.64 arc(36.43,59.73) 36.46,59.84 36.46,60.21 arc(36.53,60.59) 36.74,60.91 arc(36.84,61.05) 36.88,61.23 36.88,62.51 arc(37.08,63.54) 37.66,64.41 37.89,64.63 arc(38.21,65.12) 38.33,65.69 38.33,65.78 arc(38.31,65.93) 38.27,66.07 arc(38.2,66.22) 38.1,66.34 arc(38.07,66.38) 38.06,66.42 v2(38.06,66.73)
MIPI_CSI_REAR<7>: length 9.3
  TOP w0.088: J5500.11 v2(37.71,66.74)
  LAYER_3 w0.045: v2(36.16,58.96) 36.24,59.04 36.24,59.55 arc(36.26,59.64) 36.31,59.71 arc(36.35,59.77) 36.36,59.84 36.36,60.21 arc(36.44,60.63) 36.68,60.97 arc(36.75,61.09) 36.78,61.23 36.78,62.51 arc(36.99,63.57) 37.6,64.47 37.82,64.7 arc(38.12,65.15) 38.23,65.69 arc(38.22,65.87) 38.18,66.04 arc(38.12,66.16) 38.03,66.27 arc(37.92,66.44) 37.88,66.64 37.88,66.86 arc(37.86,66.89) 37.84,66.9 arc(37.75,66.86) 37.71,66.78 v2(37.71,66.74)
MIPI_CSI_REAR<8>: length 9.5
  TOP w0.088: J5500.5 v2(38.76,66.73)
  LAYER_3 w0.045: v2(38.76,66.73) 38.8,66.69 38.81,66.62 arc(38.81,66.54) 38.81,66.46 arc(38.8,66.35) 38.8,66.24 arc(38.56,65.32) 38.02,64.54 37.85,64.37 arc(37.23,63.44) 37.01,62.35 37.01,61.08 arc(36.99,60.97) 36.93,60.88 36.88,60.83 arc(36.68,60.54) 36.62,60.2 36.62,59.14 arc(36.6,59.08) 36.57,59.03 arc(36.51,58.96) 36.48,58.87 arc(36.46,58.72) 36.37,58.6 v2(36.22,58.44)
MIPI_CSI_REAR<9>: length 9.3
  TOP w0.088: U1001.Y6 v2(36.68,58.87) ; J5500.3 v2(39.11,66.73)
  LAYER_3 w0.045: v2(36.68,58.87) 36.71,58.9 36.71,59.14 arc(36.71,59.14) 36.71,59.14 36.71,60.2 arc(36.77,60.51) 36.94,60.76 36.99,60.81 arc(37.08,60.94) 37.11,61.08 37.11,62.35 arc(37.32,63.41) 37.92,64.31 38.09,64.48 arc(38.65,65.28) 38.89,66.23 arc(38.9,66.43) 38.91,66.62 38.91,66.62 39.02,66.73 v2(39.11,66.73)
MIPI_DSI0<0>: length 43.3
  LAYER_2 w0.045: v2(38.45,49.7) 38.31,49.7 38.26,49.75 38.26,49.96 38.4,50.1 v1(38.4,50.24)
  LAYER_3 w0.045: v4(55.6,47.86) 54.96,47.86 52.82,45.71 51.13,45.71 50.78,45.36 47.5,45.36 47.1,44.96 44.83,44.96 43.11,46.67 39.99,46.67 39.75,46.91 39.75,47.29 38.5,48.55 38.5,49.65 38.45,49.7 v2(38.45,49.7)
  LAYER_5 w0.045: v4(55.6,47.86) 55.58,47.86 55.49,47.95 55.49,48.04 55.58,48.13 55.73,48.13 55.82,48.03 55.82,47.94 55.86,47.91 55.94,47.91 56.04,48.02 56.04,67.06 55.61,67.49 55.61,67.6 55.53,67.67 v7(55.49,67.67)
  BOTTOM w0.088: J5300.18 v7(55.49,67.67)
MIPI_DSI0<1>: length 43.3
  LAYER_2 w0.045: v1(38.2,50.47) v2(38.16,50.24)
  LAYER_3 w0.045: v2(38.16,50.24) 38.17,50.24 38.29,50.12 38.29,49.63 38.4,49.52 38.4,48.51 39.66,47.25 39.66,46.87 39.95,46.57 43.08,46.57 44.79,44.86 47.13,44.86 47.54,45.27 50.82,45.27 51.16,45.61 52.85,45.61 55,47.76 55.47,47.76 55.54,47.7 55.54,47.7 v4(55.61,47.63)
  LAYER_5 w0.045: v4(55.61,47.63) 55.77,47.79 55.98,47.79 56.14,47.96 56.14,67.1 55.71,67.53 55.71,67.6 55.79,67.67 v7(55.84,67.67)
  BOTTOM w0.088: J5300.16 v7(55.84,67.67)
MIPI_DSI0<2>: length 43.7
  LAYER_3 w0.045: v4(56.62,47.99) 56.56,48.05 54.9,48.05 52.7,45.86 51.05,45.86 50.72,45.53 47.45,45.53 47,45.08 44.9,45.08 43.16,46.81 40.74,46.81 40.08,47.47 39.76,47.47 38.64,48.58 38.64,49.75 38.44,49.95 38.44,50.2 38.19,50.45 37.75,50.45 v2(37.66,50.54)
  LAYER_5 w0.045: v4(56.62,47.99) 56.54,48.06 56.54,48.06 56.44,48.16 56.44,48.23 56.31,48.36 56.31,67.18 56.66,67.52 56.66,67.6 56.58,67.67 v7(56.54,67.67)
  BOTTOM w0.088: J5300.12 v7(56.54,67.67)
MIPI_DSI0<3>: length 43.7
  LAYER_3 w0.045: v4(56.61,48.23) 56.52,48.14 54.86,48.14 52.67,45.95 51.01,45.95 50.68,45.63 47.42,45.63 46.97,45.18 44.93,45.18 43.2,46.91 40.78,46.91 40.12,47.56 39.8,47.56 38.73,48.62 38.73,49.79 38.54,49.99 38.54,50.24 38.22,50.55 37.89,50.55 37.7,50.74 37.47,50.74 v2(37.46,50.73)
  LAYER_5 w0.045: v4(56.61,48.23) 56.59,48.23 56.41,48.41 56.41,67.13 56.76,67.48 56.76,67.6 56.84,67.67 v7(56.89,67.67)
  BOTTOM w0.088: J5300.10 v7(56.89,67.67)
MIPI_DSI0<4>: length 42.3
  LAYER_3 w0.045: v4(55.69,48.43) 55.53,48.43 55.52,48.43 54.93,48.43 52.61,46.11 50.93,46.11 50.61,45.79 47.36,45.79 46.87,45.3 45,45.3 43.28,47.02 40.82,47.02 39.08,48.76 39.08,48.98 38.89,49.17 38.89,49.78 38.64,50.03 38.64,50.27 38.15,50.76 v2(37.96,50.76)
  LAYER_5 w0.045: v4(55.69,48.43) 55.7,48.44 55.7,48.67 55.77,48.75 55.77,66.56 55.02,67.32 54.67,67.32 54.56,67.43 54.56,67.6 54.48,67.67 v7(54.44,67.67)
  BOTTOM w0.088: J5300.24 v7(54.44,67.67)
MIPI_DSI0<5>: length 42.7
  LAYER_3 w0.045: v2(37.74,50.98) 37.79,50.93 38.11,50.93 38.18,50.86 38.19,50.86 38.74,50.31 38.74,50.07 38.99,49.82 38.99,49.21 39.18,49.02 39.18,48.8 40.86,47.12 43.32,47.12 45.04,45.4 46.84,45.4 47.32,45.89 50.57,45.89 50.89,46.2 52.57,46.2 54.9,48.53 55.49,48.53 55.55,48.59 55.76,48.59 55.86,48.59 v4(55.86,48.59)
  LAYER_5 w0.045: v4(55.86,48.59) 55.84,48.59 55.8,48.63 55.87,48.7 55.87,66.6 55.06,67.42 54.71,67.42 54.66,67.47 54.66,67.6 54.74,67.67 v7(54.79,67.67)
  BOTTOM w0.088: J5300.22 v7(54.79,67.67)
MIPI_DSI0<6>: length 42.6
  LAYER_3 w0.045: v2(38.72,50.57) 38.84,50.45 38.84,50.11 39.13,49.82 39.13,49.22 39.3,49.05 39.3,48.86 40.91,47.24 43.36,47.24 45.09,45.51 46.75,45.51 47.27,46.03 50.5,46.03 50.84,46.37 52.51,46.37 54.88,48.73 55.32,48.73 55.33,48.73 55.4,48.73 v4(55.41,48.72)
  LAYER_5 w0.045: v4(55.41,48.72) 55.41,48.96 55.51,49.06 55.51,57.25 55.45,57.31 55.04,57.31 54.92,57.43 54.92,57.59 55.04,57.71 55.45,57.71 55.51,57.77 55.51,66.44 54.91,67.04 53.93,67.04 53.5,67.47 53.5,67.61 53.43,67.67 v7(53.39,67.67)
  BOTTOM w0.088: J5300.30 v7(53.39,67.67)
MIPI_DSI0<7>: length 43
  LAYER_3 w0.045: v2(38.47,50.82) 38.54,50.75 38.77,50.75 38.94,50.58 38.94,50.15 39.23,49.86 39.23,49.25 39.39,49.09 39.39,48.89 40.95,47.34 43.4,47.34 45.13,45.61 46.71,45.61 47.23,46.13 50.47,46.13 50.8,46.46 52.47,46.46 54.84,48.83 55.29,48.83 55.35,48.89 v4(55.58,48.89)
  LAYER_5 w0.045: v7(53.74,67.67) 53.69,67.67 53.6,67.59 53.6,67.51 53.97,67.14 54.95,67.14 55.61,66.48 55.61,57.73 55.49,57.61 55.08,57.61 55.02,57.55 55.02,57.47 55.08,57.41 55.49,57.41 55.61,57.29 55.61,48.92 v4(55.58,48.89)
  BOTTOM w0.088: J5300.28 v7(53.74,67.67)
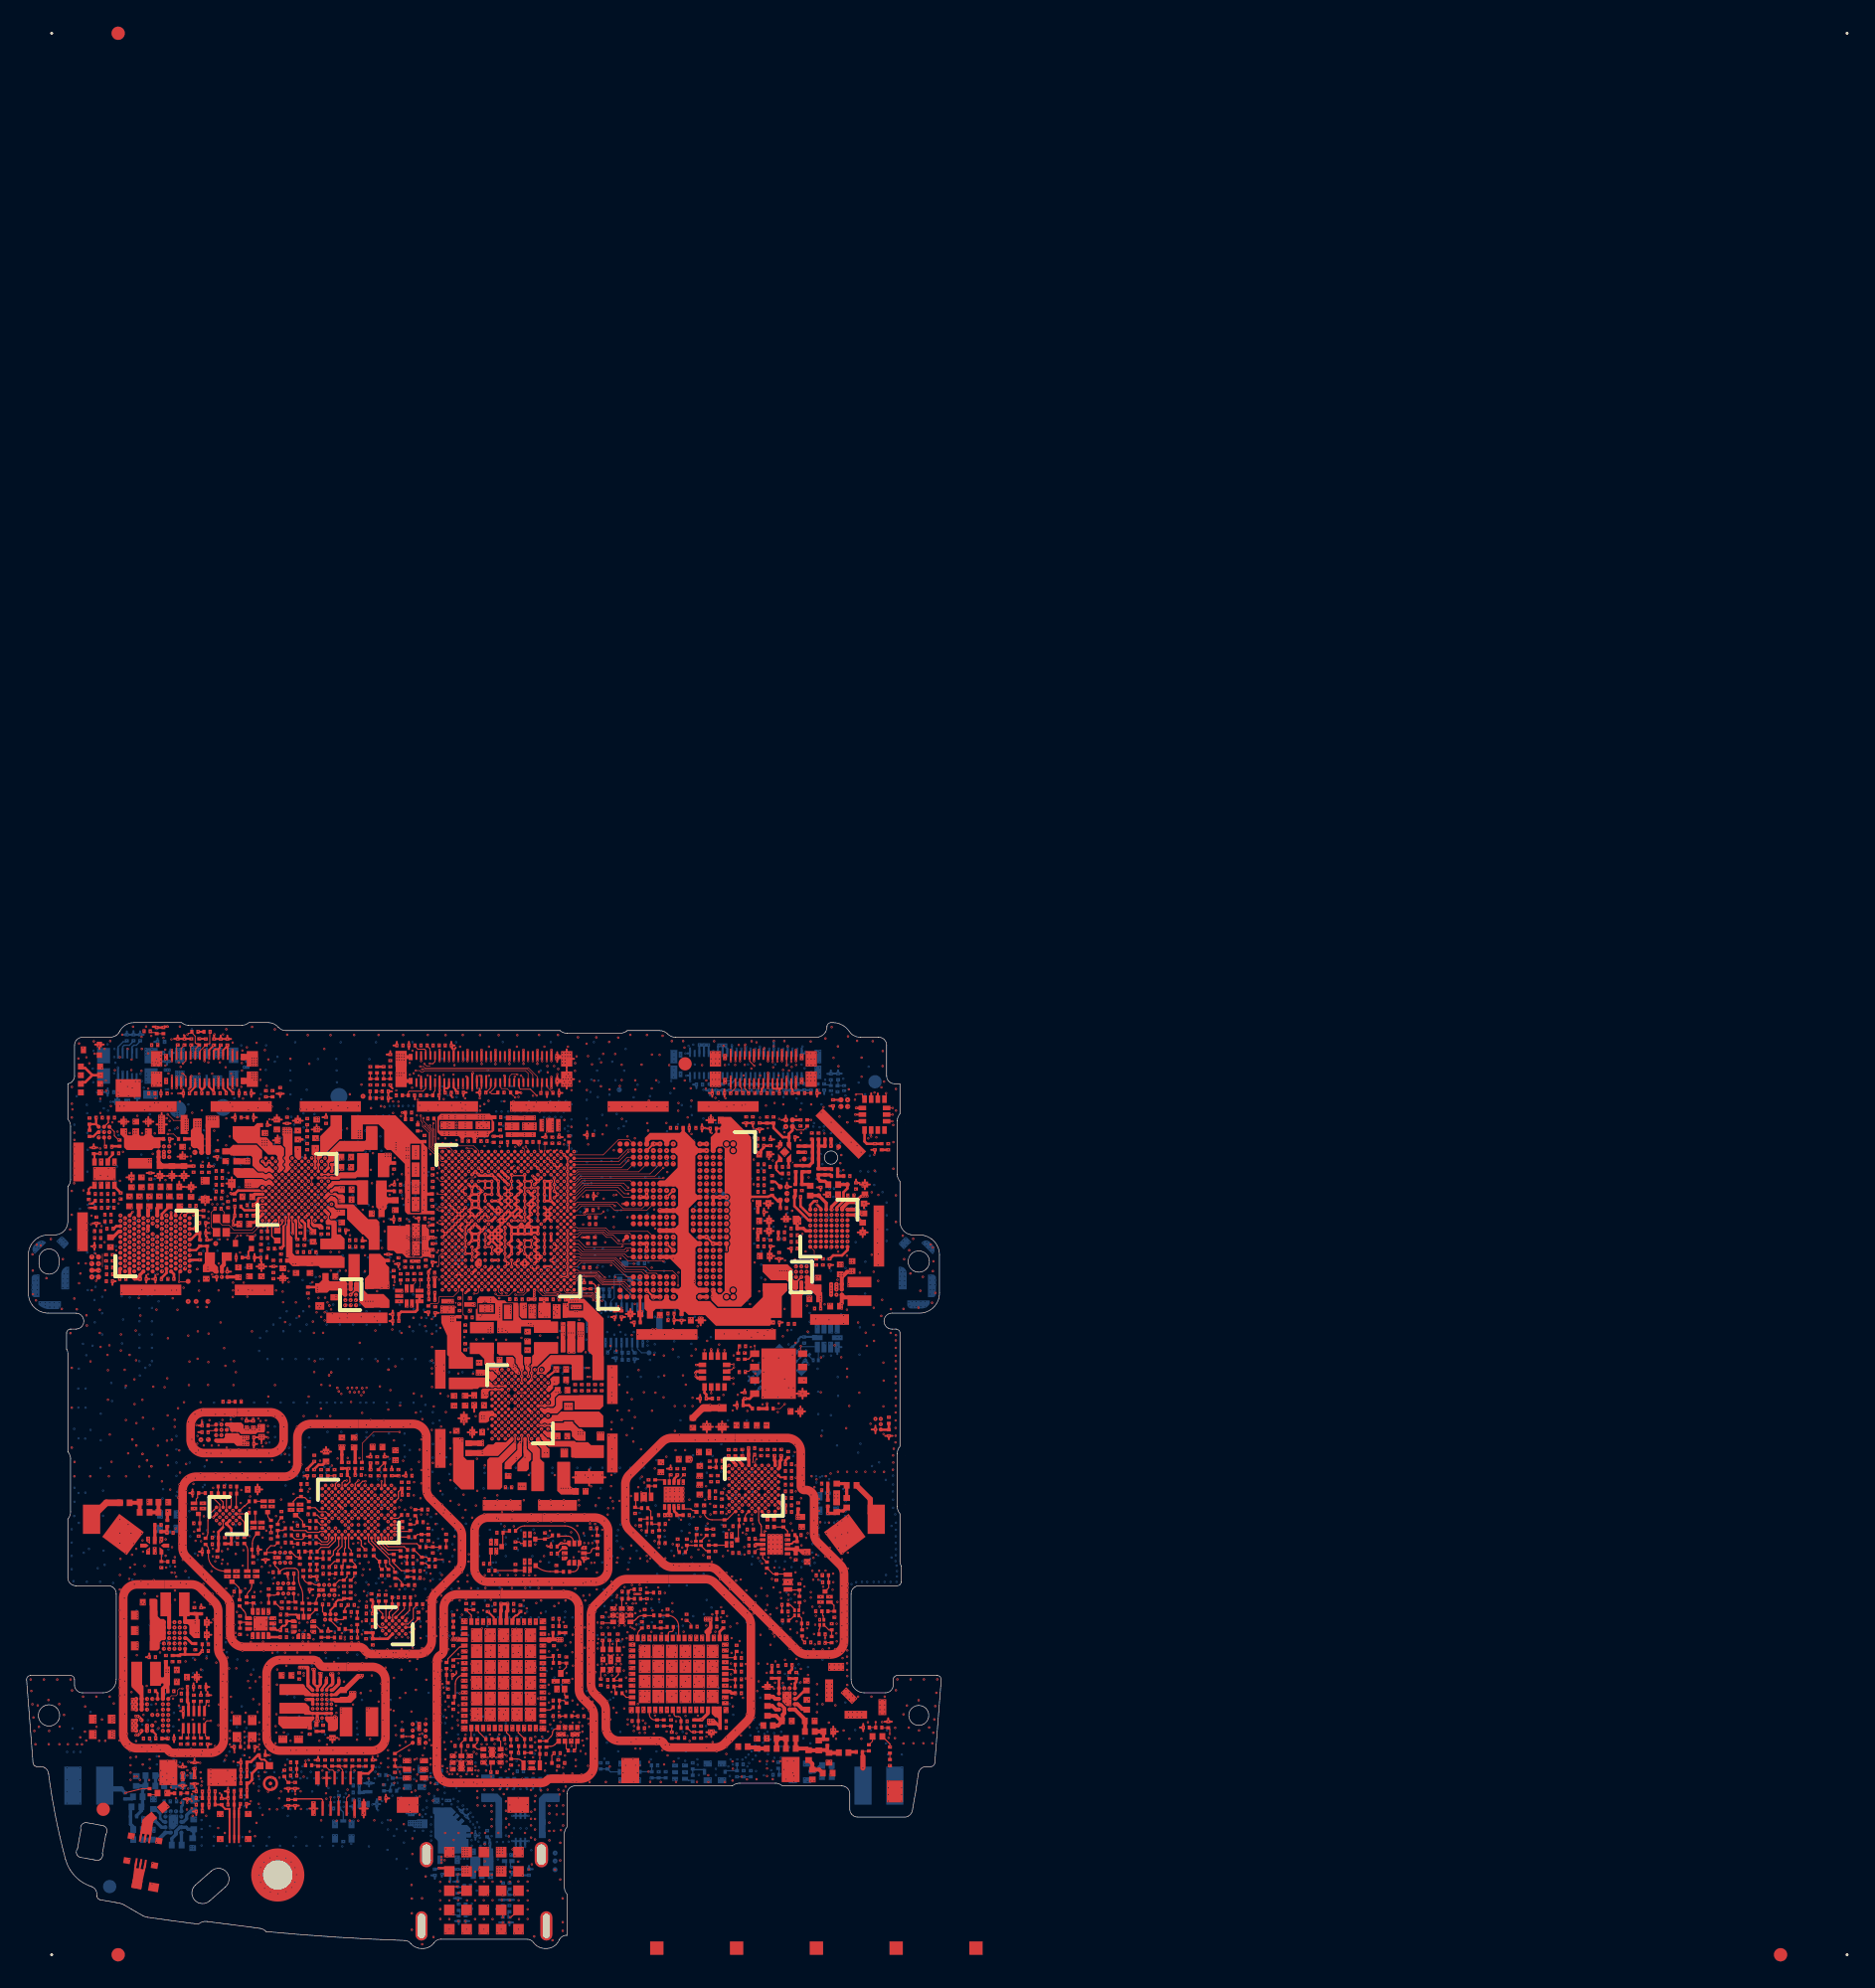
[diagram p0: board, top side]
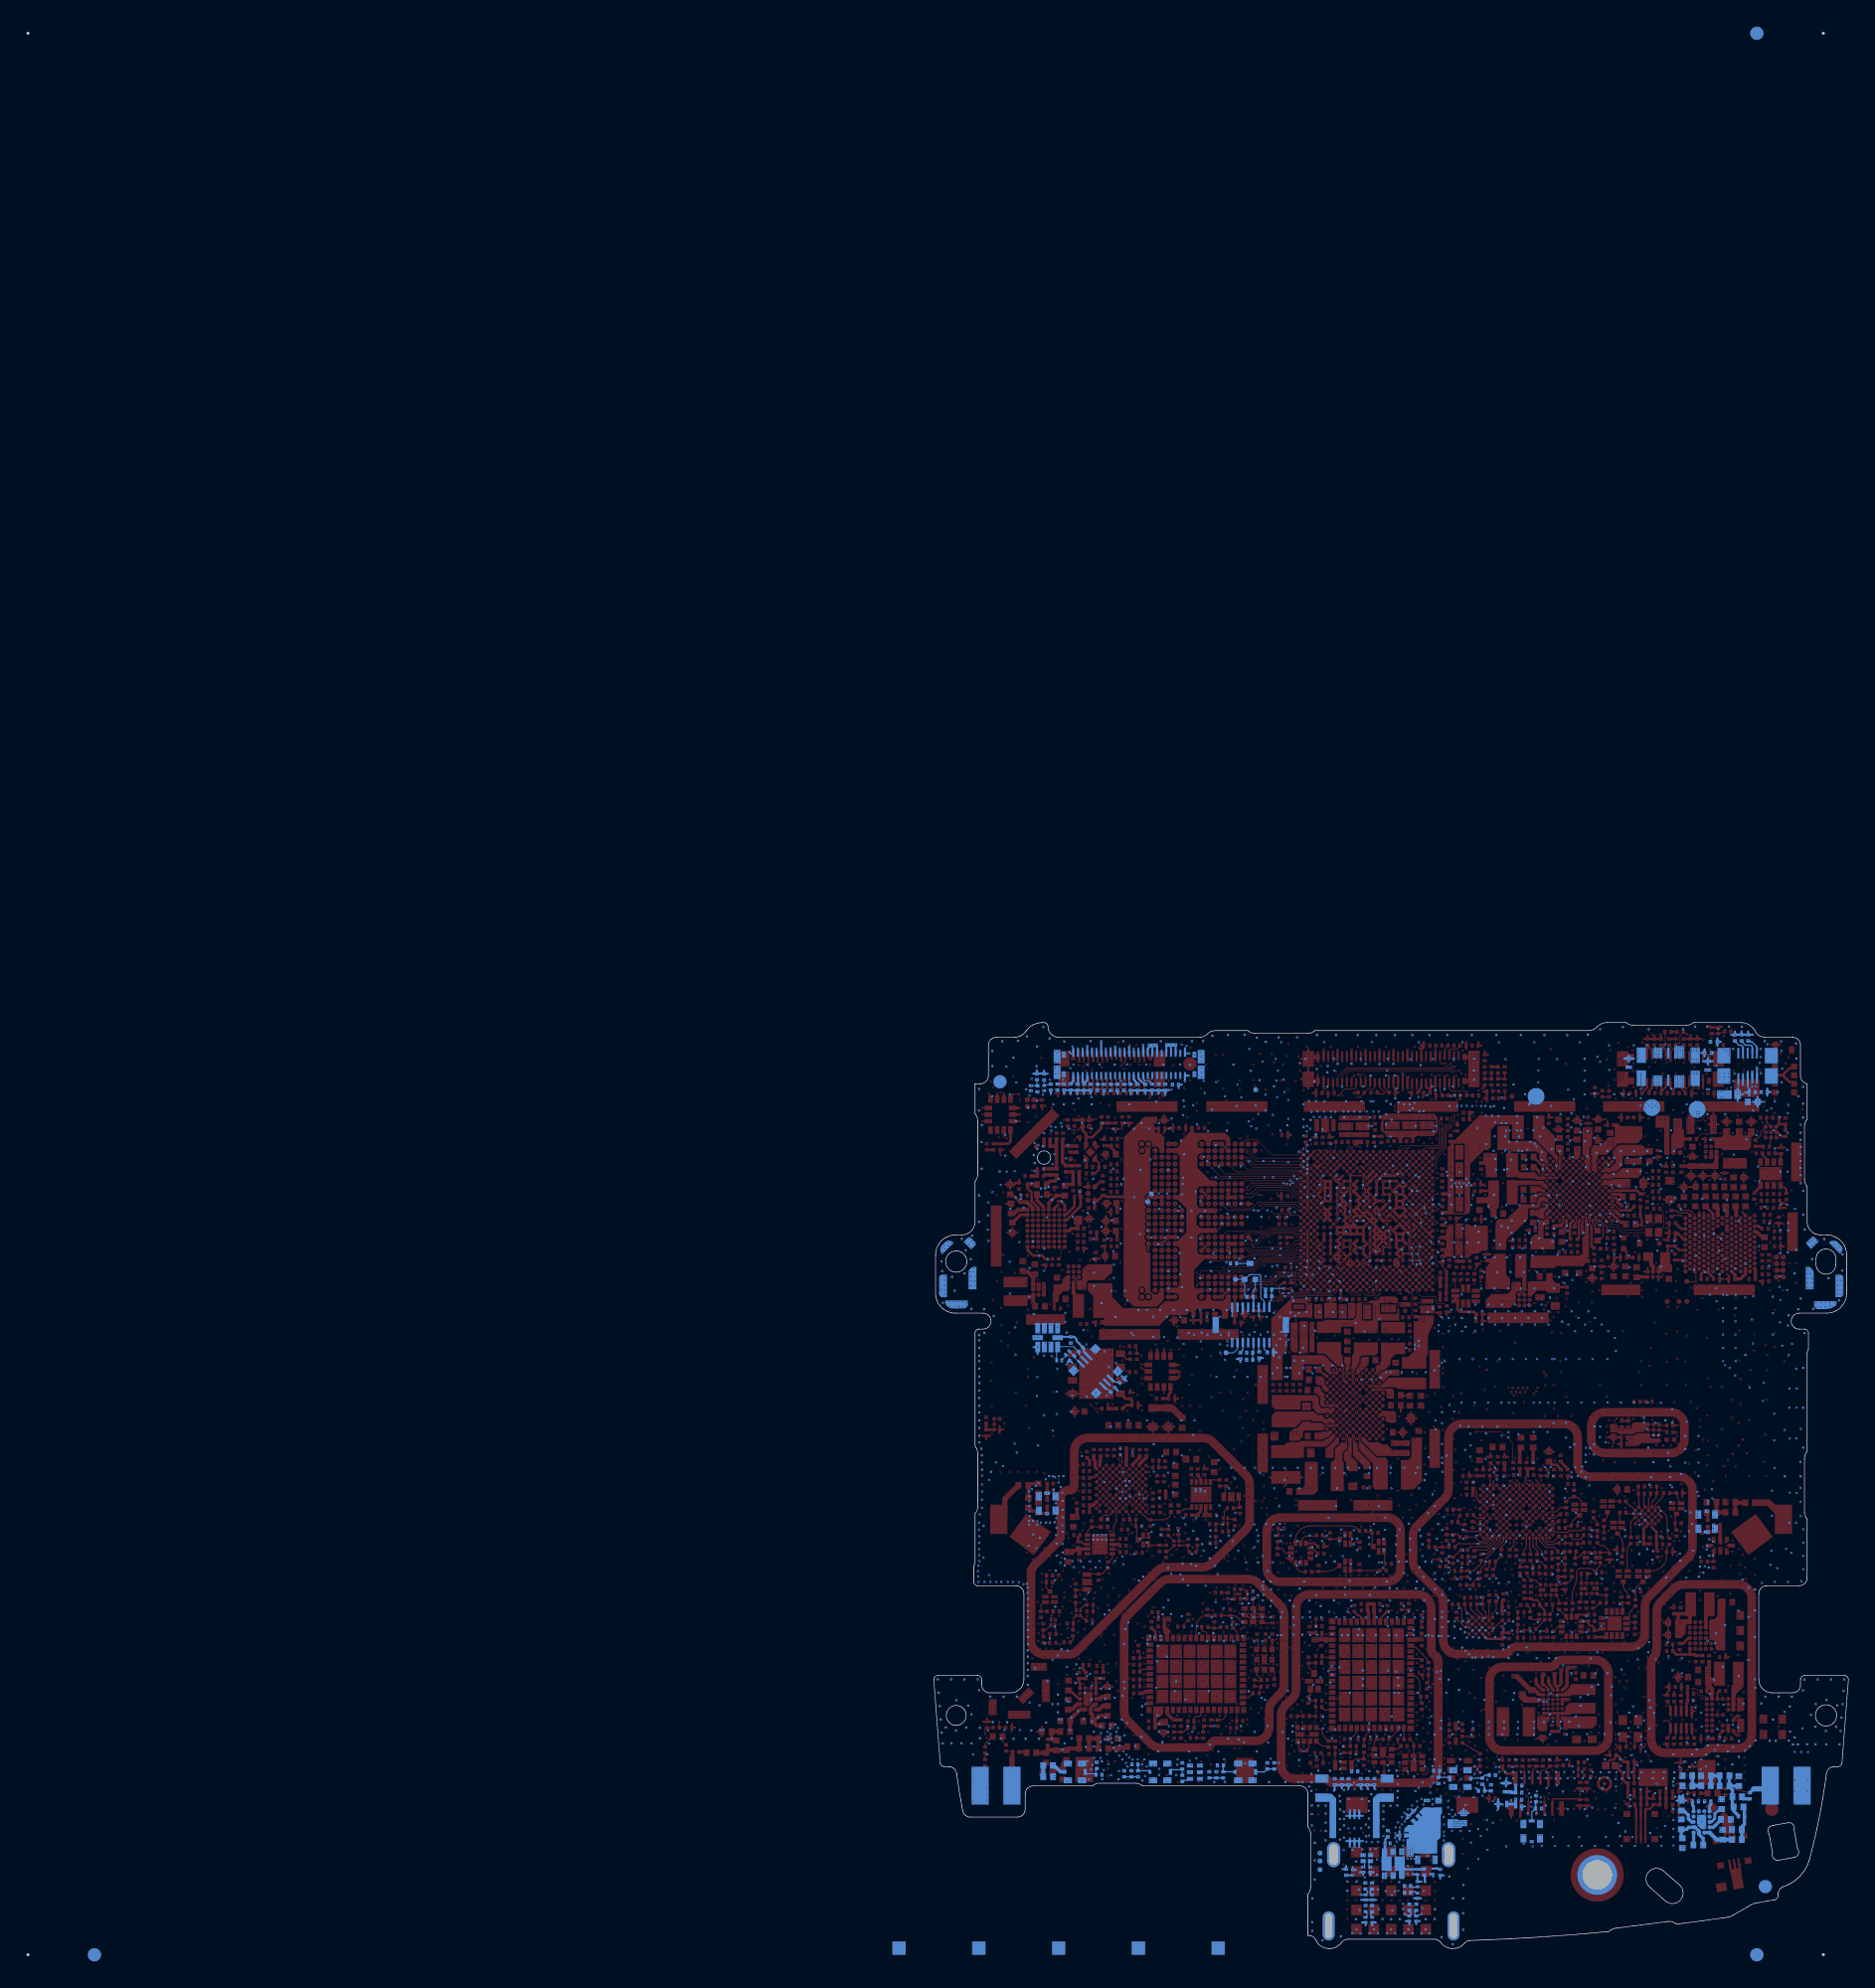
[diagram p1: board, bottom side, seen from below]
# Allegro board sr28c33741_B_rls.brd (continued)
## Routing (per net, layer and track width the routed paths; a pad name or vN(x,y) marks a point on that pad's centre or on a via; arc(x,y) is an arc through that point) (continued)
MIPI_DSI0<8>: length 42.7
  LAYER_3 w0.045: v4(56.89,48.43) 56.88,48.43 56.87,48.44 56.87,48.46 56.82,48.5 56.35,48.5 55.76,49.09 54.86,49.09 52.4,46.63 50.74,46.63 50.38,46.27 47.17,46.27 46.62,45.72 45.23,45.72 43.48,47.47 40.98,47.47 39.53,48.93 39.53,49.1 39.33,49.3 39.33,49.9 39.04,50.19 39.04,50.7 38.96,50.78 v2(38.96,50.8)
  LAYER_5 w0.045: v4(56.89,48.43) 56.59,48.72 56.59,66.41 57.71,67.53 57.71,67.6 57.63,67.67 v7(57.59,67.67)
  BOTTOM w0.088: J5300.6 v7(57.59,67.67)
MIPI_DSI0<9>: length 42.9
  LAYER_3 w0.045: v4(56.89,48.67) 56.87,48.65 56.87,48.64 56.83,48.6 56.39,48.6 55.8,49.19 54.83,49.19 52.37,46.73 50.71,46.73 50.35,46.37 47.14,46.37 46.59,45.82 45.27,45.82 43.52,47.57 41.02,47.57 39.62,48.97 39.62,49.14 39.42,49.34 39.42,49.94 39.14,50.23 39.14,50.85 39.01,50.97 v2(38.7,50.97)
  LAYER_5 w0.045: v4(56.89,48.67) 56.87,48.65 56.8,48.65 56.69,48.77 56.69,66.37 57.81,67.49 57.81,67.6 57.89,67.67 v7(57.94,67.67)
  BOTTOM w0.088: J5300.4 v7(57.94,67.67)
MSS_CMD<0>: length 45.7
  LAYER_3 w0.045: v4(47.67,63.6) 47.67,63.23 47.41,62.97 46.63,62.97 46.42,63.18 40.23,63.18 arc(39.43,62.85) 39.1,62.05 39.1,61.6 38.7,61.2 38.7,60.82 38.37,60.49 38.37,60.32 38.27,60.22 38.27,59.78 37.92,59.43 v2(37.76,59.43)
  LAYER_5 w0.045: v4(47.67,63.6) 47.67,63.04 52.93,57.78 52.93,39.84 51.47,38.38 51.47,37.84 51.45,37.82 51.45,37.68 51.57,37.56 51.57,36.49 52.55,35.51 53.59,35.51 v4(53.81,35.29)
MSS_CMD<1>: length 45
  TOP w0.05: v2(37.97,59.71) 37.95,59.71 U1001.P2
  LAYER_3 w0.045: v4(47.51,63.42) 47.51,63.2 47.37,63.06 46.67,63.06 46.46,63.27 40.22,63.27 arc(39.36,62.92) 39.01,62.06 39.01,61.64 38.6,61.23 38.6,60.85 38.28,60.53 38.28,60.36 38.18,60.26 38.18,59.92 v2(37.97,59.71) ; v4(53.57,35.31) 53.57,35.27 53.59,35.25 v2(53.59,35.13)
  LAYER_5 w0.045: v4(53.57,35.31) 53.46,35.41 52.51,35.41 51.48,36.45 51.48,37.52 51.35,37.64 51.35,37.86 51.37,37.88 51.37,38.42 52.84,39.88 52.84,57.74 47.51,63.07 v4(47.51,63.42)
Net_82:
  vias: v1(17.48,5.52) v1(17.6,6.09) v1(17.6,4.97) v1(17.86,6.49) v1(17.9,4.53) v1(18.31,6.81) v1(18.33,4.24) v1(18.85,6.94) v1(18.91,4.12) v1(19.5,6.8) v1(19.52,4.27) v1(19.9,6.51) v1(19.94,4.59) v1(20.19,6.08) v1(20.19,4.99) v1(20.3,5.55)
NFC_ANT1: length 57.2
  LAYER_7 w0.045: v7(10.3,67.34) 10.34,67.34
  LAYER_7 w0.4: v7(7.23,65.95) 7.44,66.16 9.16,66.16 11.31,68.31 18.17,68.31 19.19,67.29 44.22,67.29 50.69,60.82 59.12,60.82 v6(59.6,61.3)
  BOTTOM w0.15: J350.4 v7(7.23,65.95)
NFC_ANT2: length 57.2
  LAYER_7 w0.045: v7(10.39,68.14) 10.39,68.03
  LAYER_7 w0.4: v6(59.02,61.36) 58.94,61.28 50.87,61.28 44.39,67.76 19.39,67.76 18.39,68.76 11.12,68.76 8.97,66.61 7.23,66.61 v7(6.88,66.26)
  BOTTOM w0.15: J350.2 v7(6.88,66.26)
NFC_CLK_IN: length 51.1
  LAYER_3 w0.045: v6(20.01,57.67) 20.01,57.65 20.47,57.19 v2(20.47,56.52)
  LAYER_5 w0.045: v7(62.24,56.39) 62.24,55.28 v4(61.33,54.37)
  LAYER_7 w0.045: v7(62.24,56.39) 61.9,56.73 60.33,56.73 59.37,57.69 50.07,57.69 48.33,59.43 42.89,59.43 41.29,61.03 41.29,61.75 40.3,62.74 35.07,62.74 33.99,61.66 31.08,61.66 30.98,61.56 27.45,61.56 26.77,60.88 23.68,60.88 20.47,57.67 v6(20.01,57.67)
NFC_CLK_REQ: length 58.1
  LAYER_2 w0.045: v6(17.47,56.24) 17.63,56.08 17.86,56.08 18.07,55.87 18.25,55.87 18.38,55.74 18.58,55.74 18.7,55.86 19.1,55.86 19.51,56.27 v1(19.73,56.27)
  LAYER_5 w0.045: v7(60.39,57.16) 60.39,55.9 60.14,55.65 60.14,54.03 v4(60.93,53.24) ; v6(23.75,62.2) v6(23.75,61.26)
  LAYER_7 w0.045: v6(23.75,62.2) 22.99,62.2 21.47,60.68 21.47,59.36 20.27,58.16 19.62,58.16 17.7,56.24 v6(17.47,56.24) ; v7(60.39,57.16) 60.39,57.32 59.65,58.06 54.41,58.06 54.34,57.99 50.28,57.99 48.54,59.73 43.02,59.73 41.62,61.13 41.62,61.21 41.62,61.44 41.62,61.44 41.62,61.97 40.45,63.14 34.88,63.14 33.78,62.04 30.92,62.04 30.77,61.89 27.33,61.89 26.69,61.25 23.75,61.25 v6(23.75,61.26)
NFC_EN: length 36.2
  TOP w0.05: U1001.R1 37.7,60.11 37.54,60.27 v2(37.54,60.32)
  LAYER_2 w0.045: v2(57.92,52.58) 57.92,52.59 57.66,52.85 56.64,52.85 56.21,53.28 56.21,53.53 v2(55.98,53.76)
  LAYER_3 w0.045: v2(55.98,53.76) 56.07,53.85 56.07,56.14 55.82,56.39 55.82,57.69 56.36,58.23 56.36,60.7 55.87,61.2 53.69,61.2 50.93,63.96 39.71,63.96 arc(39.37,63.89) 39.08,63.7 38.02,62.63 38.02,61.5 37.89,61.37 37.89,61 37.55,60.66 37.55,60.38 37.54,60.37 v2(37.54,60.32) ; v2(60.93,52.71) 60.76,52.54 58.8,52.54 58.71,52.63 57.99,52.63 57.93,52.58 v2(57.92,52.58)
NFC_I2C_SCL: length 36.5
  LAYER_2 w0.045: v1(37.15,59.43) v2(37.15,59.72) ; v2(56.42,57.09) v2(57.02,57.09)
  LAYER_3 w0.045: v2(60.53,53.23) 59.08,53.23 59.04,53.27 58.85,53.27 58.41,52.84 57.77,52.84 56.99,53.62 v2(56.99,53.86) 56.96,53.86 56.82,54 56.82,55.28 56.92,55.38 56.92,55.73 56.7,55.95 56.7,56.72 56.95,56.96 56.95,57.02 v2(57.02,57.09) ; v2(37.15,59.72) 37.1,59.77 37.1,60 37.17,60.07 37.17,60.29 37.28,60.4 37.28,60.43 37.36,60.5 37.36,60.74 37.7,61.08 37.7,61.45 37.82,61.57 37.82,62.75 38.89,63.82 arc(39.27,64.07) 39.72,64.16 51.01,64.16 53.7,61.47 53.7,61.47 53.78,61.39 55.96,61.39 56.56,60.79 56.56,57.23 v2(56.42,57.09)
NFC_I2C_SDA: length 35.9
  TOP w0.05: U1001.T2 37.45,60.09 v2(37.33,60.22)
  LAYER_2 w0.045: v2(56.39,58.03) v2(56.92,58.03)
  LAYER_3 w0.045: v2(37.33,60.22) 37.38,60.27 37.38,60.39 37.45,60.47 37.45,60.7 37.79,61.04 37.79,61.41 37.92,61.54 37.92,62.67 37.96,62.71 37.96,62.71 39.02,63.78 arc(39.33,63.99) 39.7,64.06 50.97,64.06 53.74,61.29 55.92,61.29 56.04,61.17 56.04,61.17 56.46,60.75 56.46,58.09 v2(56.4,58.03) ; v2(60.48,52.72) 60.39,52.63 58.84,52.63 58.74,52.74 57.71,52.74 57.09,53.36 v2(56.97,53.36) 56.72,53.61 56.72,55.31 56.83,55.42 56.83,55.69 56.61,55.91 56.61,56.76 56.85,57 56.85,58.01 56.88,58.03 v2(56.92,58.03)
NFC_IRQ: length 41.3
  TOP w0.05: v6(30.6,62.06) 30.57,62.03 30.57,61.68 30.66,61.59 30.66,61.06 30.67,61.06 30.67,60.45 30.86,60.25 31.79,60.25 32.01,60.04 32.01,59.83 U1001.AV2
  LAYER_5 w0.045: v4(60.94,53.64) 60.69,53.64 60.25,54.08 60.25,55.62 60.48,55.86 60.48,56.91 v7(60.72,57.15)
  LAYER_7 w0.045: v7(60.72,57.15) 60.69,57.15 59.68,58.16 54.37,58.16 54.3,58.09 50.33,58.09 48.59,59.83 43.06,59.83 41.72,61.17 41.72,61.4 41.72,62.01 40.49,63.23 34.84,63.23 33.74,62.14 30.67,62.14 v6(30.6,62.06)
NFC_VTX: length 6.7
  TOP w0.2: 62.3,56.13 62.76,56.59 62.88,56.59 63.01,56.72
  TOP w0.3: 63.01,56.72 C4126.2 ; 61.3,50.48 61.7,50.88 62.01,50.88 C4125.2 ; 61.3,50.48 61.3,50.58 C4124.2 ; 61.3,50.48 U4120.A1 U4120.A2 ; U4100.A7 61.33,55.69 61.77,56.13 62.3,56.13
  LAYER_2 w0.175: v2(61.34,50.75) v2(61.34,50.57) v2(61.16,50.57) ; v2(61.34,50.75) v2(61.16,50.57) ; v2(61.34,50.75) v2(61.16,50.75) v2(61.16,50.57) ; v2(62.88,56.58) v2(63.06,56.58) v2(63.24,56.58) ; v2(62.1,51) v2(61.92,51) v2(61.92,50.82) ; v2(62.1,51) v2(62.1,50.82) v2(61.92,50.82) ; v2(62.1,51) v2(61.92,50.82)
NFC_VTX_GND: length 1
  TOP w0.3: U4120.C1 v2(60.5,49.89) v2(60.5,49.65) U4120.C2 v2(60.5,49.47) v2(60.5,49.23) U4120.C3
  LAYER_3 w0.175: v2(60.5,49.89) v2(60.5,49.65)
  vias: v1(60.3,48.46) v1(60.48,48.46) v1(61.16,51.49) v1(61.16,51.31) v1(61.34,51.49) v1(61.34,51.31) v1(61.92,51.74) v1(61.92,51.56) v1(62.1,51.74) v1(62.1,51.56)
PA_2GHB_IN_50R: length 1.3
  TOP w0.088: U7100.22 53.26,20.21 C7110.2 L7111.2
PA_2GLB_IN_50R: length 1.4
  TOP w0.088: C7112.2 L7113.2 53.26,20.82 53.09,20.99 52.63,20.99 U7100.24
PA_EN_5G_CH0: length 4.2
  TOP w0.05: U4080.7 54.85,30.74 C4087.2
  LAYER_3 w0.045: v2(55.59,34.07) 55.57,34.05 55.57,33.79 55.12,33.34 55.12,31.38 54.79,31.05 v2(54.79,30.83)
PA_EN_5G_CH1: length 5.6
  TOP w0.05: U4090.7 49.13,35.17 49.13,35.32 C4096.2
  LAYER_3 w0.045: v2(49.49,35.66) 49.77,35.94 51.02,35.94 51.2,35.76 51.2,35.13 51.41,34.92 52.4,34.92 52.55,35.07 52.91,35.07 53,34.98 53.25,34.98 v2(53.36,34.87)
PA_THERM1: length 46.4
  TOP w0.088: v4(40.04,24.8) C7199.2 RT7199.1
  LAYER_2 w0.045: v2(25.27,46.47) 25.34,46.47 25.45,46.36 25.45,42.8 v2(26.08,42.17)
  LAYER_3 w0.045: v2(21,55.95) 21,55.76 21.11,55.65 21.11,55.39 20.7,54.98 20.37,54.98 20.13,54.74 20.13,53.92 19.76,53.55 19.76,52.59 20.42,51.93 20.42,50.53 19.47,49.59 19.47,48.69 20.34,47.82 21.12,47.82 22.4,46.54 25.2,46.54 v2(25.27,46.47) ; v2(26.08,42.17) 26.5,41.75 27.44,41.75 35.28,33.91 38.67,33.91 38.68,33.92 v4(38.71,33.92)
  LAYER_5 w0.045: v4(40.04,24.8) 39.38,25.46 39.38,33.26 v4(38.71,33.92)
PA_THERM2: length 86.4
  TOP w0.05: RT7149.1 49.96,24.4 49.69,24.67 C7149.2 49.63,24.69 v6(49.57,24.69)
  LAYER_3 w0.045: v6(15.44,58.3) 15.56,58.18 16.82,58.18 17.62,57.38 18.95,57.38 19.05,57.29 19.05,57.22 19.2,57.07 19.34,57.07 19.36,57.09 19.5,57.09 19.65,56.95 19.65,56.44 20.4,55.68 20.71,55.68 v2(20.76,55.73)
  LAYER_5 w0.045: v6(7.46,58.3) 7.46,58.19 7.56,58.09 7.56,56.93 7.73,56.76 7.73,56.17 7.73,56.1 7.21,55.57 7.21,52.85 7.85,52.21 7.85,51.66 8.17,51.34 8.17,49.93 8.93,49.16 8.93,48.19 10.09,47.03 10.09,44.77 11.25,43.62 11.25,42.89 11.12,42.76 11.12,38.83 13.07,36.88 13.07,33.57 13.36,33.27 13.36,28.28 v6(13.43,28.28)
  LAYER_7 w0.045: v6(15.44,58.3) 15.42,58.3 v6(7.46,58.3) ; v6(13.43,28.28) 18.44,28.28 18.96,27.77 26.26,27.77 26.46,27.57 31.88,27.57 32.18,27.87 41.41,27.87 41.49,27.8 44.47,27.8 46.48,25.79 48.47,25.79 v6(49.57,24.69)
PA_TRX_B40_50R: length 1.3
  TOP w0.088: U7150.13 39.5,21.9 L7350.2 39.61,21.99 C7351.1
PA_TX_B13_50R: length 2.7
  TOP w0.088: U7100.37 49.03,24.21 arc(48.79,24.81) L7260.2 C7261.2
PA_TX_B25_50R: length 2
  TOP w0.088: C7300.1 31.68,21.62 31.68,21.79 32.54,22.65 arc(32.57,22.67) 32.61,22.68 32.92,22.68 U7150.36
PA_TX_B25_MAT_50R: length 1.1
  TOP w0.088: C7300.2 L7301.2 31.58,20.08 L7302.1
PA_TX_B28_50R: length 1.2
  TOP w0.088: U7100.39 48.26,23.35 48.26,23.69 arc(48.3,23.79) 48.4,23.83 48.5,23.83 arc(48.59,23.87) 48.63,23.96 C7230.2
PA_TX_B28_MAT_50R: length 1.1
  TOP w0.088: C7230.1 48.17,24.1 L7231.2 47.21,24.1 L7232.2
PA_TX_B34_B39_50R: length 2.6
  TOP w0.088: C7312.1 32.17,18.45 L7311.2 32.24,19.01 32.24,19.9 arc(32.43,20.38) U7150.41
PA_ULB_LB_ANT_MAT_50R: length 1.4
  TOP w0.088: U7100.2 46,17.91 L7140.2 C7141.1
PAMID_ANT_HB_TRX_50R: length 1.6
  TOP w0.088: U7150.59 36.97,16.23 L7180.2 37.46,15.74 C7181.1
PAMID_ANT_MB_TRX_50R: length 1.5
  TOP w0.088: C7170.1 36.43,15.71 L7173.2 36.33,15.81 36.33,15.99 36.09,16.23 U7150.57
PAMID_PRX_B66_B4_50R: length 0.9
  TOP w0.088: L7184.1 32.08,21.69 32.18,21.79 32.81,21.79 U7150.38
PCM_THERM: length 13.9
  TOP w0.05: C515.2 16.12,62.49 16.1,62.48 v2(16.1,62.43)
  TOP w0.075: RT515.1 C515.2
  LAYER_2 w0.045: v1(18.48,55.48) 18.17,55.48 17.78,55.87 17.56,55.87 17.22,55.53 16.29,55.53 16.25,55.5 15.59,55.5 15.51,55.57 14.93,55.57 14.56,55.94 14.56,56.03 14.23,56.36 v2(14.23,56.36)
  LAYER_3 w0.045: v2(14.23,56.36) 14.22,56.36 14.22,56.44 13.67,57 13.67,58.16 13.46,58.37 13.46,61.26 13.92,61.73 14.45,61.73 14.85,62.12 15.8,62.12 v2(16.1,62.43)
PM670A_DIE_TEMP: length 32
  LAYER_2 w0.045: v2(25.63,43.44) 25.55,43.52 25.55,46.49 v2(25.48,46.56)
  LAYER_3 w0.045: v2(38.27,41.57) 38.15,41.69 37.9,41.69 37.76,41.83 37.51,41.83 36.98,42.36 36.62,42.36 36.52,42.46 36.52,42.49 36.09,42.91 35.46,42.91 35.4,42.97 34.69,42.97 34.46,42.74 33.5,42.74 33.33,42.91 28.3,42.91 28.08,43.13 27.6,43.13 27.37,43.37 25.7,43.37 v2(25.63,43.44) ; v2(21.41,55.45) 21.41,55.19 21.08,54.87 20.39,54.87 20.22,54.7 20.22,53.88 19.86,53.51 19.86,52.63 20.52,51.97 20.52,50.5 19.57,49.55 19.57,48.72 20.37,47.92 21.16,47.92 22.45,46.63 25.41,46.63 v2(25.48,46.56)
PM_PON_RESET_N: length 14.9
  LAYER_2 w0.045: v1(21.74,55.2) 22.04,55.2 22.4,54.84 22.74,54.84 v2(23.5,54.08)
  LAYER_3 w0.045: v2(23.5,54.08) 23.34,54.08 23.08,53.82 23.08,52.19 23.19,52.08 24.16,52.08 24.59,52.51 27.99,52.51 28.34,52.85 31.68,52.85 31.9,52.63 32.03,52.63 32.15,52.75 32.33,52.75 32.44,52.86 32.57,52.86 32.75,52.68 v2(32.75,52.46)
PM_XO_THERM: length 9.9
  TOP w0.05: Y2000.4 13.88,54.26 13.88,55.35 v2(14.17,55.64)
  LAYER_3 w0.045: v2(20.95,55.52) 20.43,55.52 19.7,56.25 19.52,56.25 19.44,56.25 19.27,56.08 19.08,56.08 18.89,56.27 18.3,56.27 18.05,56.02 17.43,56.02 17.21,56.25 16.39,56.25 15.71,55.57 14.88,55.57 14.72,55.74 14.27,55.74 v2(14.17,55.64)
PM_XTAL_IN: length 3.7
  TOP w0.05: Y2000.1 15.05,53.82 17.03,53.82 17.44,54.23 17.82,54.23 18.23,54.65 U2000.210
PM_XTAL_OUT: length 4.7
  TOP w0.05: Y2000.3 14.28,54.83 14.71,54.4 15.22,54.4 15.58,54.04 16.95,54.04 17.34,54.43 17.76,54.43 17.98,54.66 U2000.198
PON_OPTION_1: length 4.8
  TOP w0.05: 21.1,61.5 21.1,61.5 21.09,61.52 21.09,61.93 21.1,61.95 21.1,61.95
  LAYER_3 w0.045: v2(21.45,59.49) 21.4,59.54 21.4,61.64 v2(21.09,61.95) 20.57,62.47 19.65,62.47 v2(19.59,62.53)
PON_OUT: length 31
  LAYER_3 w0.045: v2(38.71,41.03) 38.7,41.02 37.89,41.02 37.61,41.3 36.67,41.3 36.48,41.48 36.48,41.58 36.34,41.72 35.89,41.72 35.42,42.2 34.64,42.2 34.39,42.45 33.38,42.45 33.2,42.62 28.19,42.62 27.96,42.85 27.48,42.85 27.25,43.08 24.14,43.08 24.01,43.21 23.22,43.21 23.12,43.11 v4(22.75,43.11) ; v4(22.7,55.31) 22.7,55.31 22.67,55.35 22.67,56 22.43,56.24 v2(22.24,56.24)
  LAYER_5 w0.045: v4(22.7,55.31) 22.71,55.31 23.06,54.96 23.06,52.19 23.16,52.09 23.16,51.63 23.32,51.47 23.32,47.38 23.14,47.2 23.14,43.32 22.94,43.11 v4(22.75,43.11)
PRI_MIC_BIAS: length 58.6
  TOP w0.15: C4505.2 C4501.2 C4506.2 VR4501.2 14.67,10.76 14.93,10.5 15.26,10.5 J4500.2 15.26,8.23
  LAYER_3 w0.15: v2(8.44,54.78) 8.44,54.81 8.09,55.17 7.91,55.17 7.89,55.19 7.89,55.19 7.85,55.23 7.85,55.23 7.51,55.56 7.51,55.57 6.69,56.38 5.94,56.38 v2(5.64,56.69)
  LAYER_3 w0.175: v4(4.52,56.5) 4.58,56.56 5.51,56.56 v2(5.64,56.69)
  LAYER_5 w0.175: v4(14.17,11.82) 14.17,12.58 11.44,15.3 10.78,15.3 9.58,16.51 9.58,17.15 7.28,19.45 7.28,33.38 4.8,35.86 4.8,48.02 4.28,48.54 4.28,56.26 v4(4.52,56.5)
PRI_MIC_DM: length 50.7
  TOP w0.15: 15.96,8.23 J4500.6 15.96,10.52 16.04,10.6 v4(16.04,10.93)
  LAYER_5 w0.175: v4(16.04,10.93) 16.04,11.62 14.78,12.88 14.51,12.88 11.61,15.77 10.95,15.77 10.03,16.7 10.03,17.34 7.73,19.64 7.73,33.57 5.25,36.05 5.25,48.21 4.73,48.73 4.73,53.11 v4(5.11,53.49)
PRI_MIC_DP: length 51.2
  TOP w0.05: C6289.1 5.08,53.91 v4(5.08,53.9)
  TOP w0.15: 15.61,8.23 J4500.4 15.61,10.81 VR4500.2 C4502.2 C4504.2
  LAYER_5 w0.175: v4(5.08,53.9) 4.5,53.33 4.5,48.64 5.02,48.12 5.02,35.95 7.5,33.47 7.5,19.54 9.8,17.25 9.8,16.6 10.86,15.54 11.53,15.54 14.42,12.65 14.69,12.65 v4(15.58,11.76)
PROX_ALS_F_INT_N: length 35.5
  TOP w0.075: v2(11.76,66.55) 11.77,66.55 11.98,66.76 J5502.23
  LAYER_3 w0.045: v4(16.78,68.59) 16.79,68.58 16.79,67.52 16.45,67.18 v4(16.45,64.27) ; v2(32.71,59.4) 32.45,59.4 32.29,59.56 32.2,59.56 32.01,59.75 31.88,59.75 31.68,59.95 31.49,59.95 30.08,61.36 29.84,61.36 29.8,61.32 29.42,61.32 28.47,62.27 28.47,62.66 28.5,62.69 28.5,65.29 28.8,65.58 28.8,67.14 28.22,67.72 27.56,67.72 v4(27.4,67.88) ; v2(11.76,66.55) 11.77,66.55 11.83,66.49 11.83,66.01 11.89,65.95 11.89,65.48 v4(11.37,64.96)
  LAYER_5 w0.045: v4(11.37,64.96) 11.61,64.72 15.71,64.72 16.09,64.34 16.38,64.34 v4(16.45,64.27) ; v4(27.4,67.88) 27.32,67.8 18.21,67.8 17.55,68.46 16.91,68.46 v4(16.78,68.59)
PROX_ALS_R_INT_N: length 79.7
  TOP w0.05: v2(42.84,48.68) 42.84,48.76 42.49,49.1 40.99,49.1 40.88,49.21 40.19,49.21 40.01,49.39 39.86,49.39 39.78,49.31 39.06,49.31 38.94,49.44 U1001.K42
  TOP w0.075: J5502.21 12.33,67.89 C5520.2
  LAYER_3 w0.045: v4(10.26,45.49) 10.33,45.42 12.97,45.42 14.83,43.56 22.12,43.56 22.46,43.9 26.71,43.9 26.91,44.1 32.48,44.1 32.71,44.33 34.14,44.33 34.36,44.1 36.17,44.1 36.24,44.17 38.13,44.17 39.35,42.95 41.69,42.95 41.98,42.66 43.38,42.66 43.94,42.11 45.88,42.11 v4(45.94,42.17) ; v2(12.33,67.92) 12.11,67.7 12.11,66.14 12.18,66.07 12.18,64.93 11.75,64.5 10.85,64.5 10.74,64.61 10.05,64.61 8.58,63.13 8.58,60.84 7.56,59.83 7.56,58.34 v4(7.69,58.22) ; v4(45.57,47.18) 45.24,47.18 44.1,48.32 43.15,48.32 42.84,48.63 v2(42.84,48.68)
  LAYER_5 w0.045: v4(7.69,58.22) 7.66,58.19 7.66,56.97 7.83,56.8 7.83,56.06 7.3,55.53 7.3,52.89 7.95,52.25 7.95,51.71 8.26,51.39 8.26,49.97 9.03,49.2 9.03,48.23 10.19,47.07 10.19,45.56 v4(10.26,45.49) ; v4(45.94,42.17) 46.01,42.23 46.01,43.41 45.95,43.48 45.95,46.11 45.87,46.19 45.87,46.35 46.08,46.56 46.08,46.91 45.98,47.02 45.98,47.24 45.87,47.35 45.74,47.35 v4(45.57,47.18)
PRX_B1_50R: length 8.8
  TOP w0.088: C7387.2 v4(31.3,29.25)
  LAYER_5 w0.047: v4(32.94,21.53) 32.94,23.74 arc(32.86,24.11) 32.65,24.43 32.63,24.45 arc(32.31,24.92) 32.21,25.46 32.21,27.89 arc(32.12,28.3) 31.88,28.66 v4(31.3,29.25)
PRX_B2_50R: length 12.9
  LAYER_5 w0.047: v4(30.59,29.73) 30.75,29.57 arc(30.8,29.48) 30.83,29.38 30.83,29.31 arc(30.87,29.1) 30.99,28.92 31.12,28.79 31.57,28.34 arc(31.69,28.15) 31.74,27.93 31.74,24 arc(31.71,23.88) 31.64,23.78 31.63,23.76 arc(31.55,23.65) 31.53,23.51 31.53,23.08 arc(31.59,22.77) 31.76,22.5 32.3,21.97 arc(32.41,21.79) 32.46,21.59 32.46,21.04 arc(32.42,20.86) 32.31,20.7 arc(32.24,20.59) 32.22,20.46 32.22,19.39 arc(32.3,18.98) 32.53,18.64 32.59,18.58 arc(32.71,18.39) 32.76,18.17 v4(32.76,17.87)
PRX_B3_50R: length 14.9
  LAYER_5 w0.047: v4(29.84,32.01) 29.84,31.46 arc(29.93,31.24) 30.15,31.15 arc(30.37,31.11) 30.56,30.98 31.95,29.58 arc(32.58,28.65) 32.8,27.55 32.8,25.36 arc(32.86,25.04) 33.04,24.77 arc(33.28,24.41) 33.37,23.99 33.37,21.6 arc(33.28,21.15) 33.02,20.77 32.9,20.64 arc(32.73,20.39) 32.67,20.08 32.67,19.77 arc(32.71,19.47) 32.82,19.19 32.99,18.91 arc(33,18.87) v4(33.01,18.84)
PRX_B5_B26_50R: length 20.6
  TOP w0.088: C7285.1 29.44,25.26 29.4,25.26 v6(29.39,25.25)
  LAYER_5 w0.047: v4(45.38,21.47) 45.48,21.58 arc(45.71,21.92) 45.8,22.33 45.8,25.17 arc(45.78,25.26) v6(45.73,25.34)
  LAYER_7 w0.045: v6(29.39,25.25) 29.54,25.4 arc(29.69,25.5) 29.88,25.54 45.38,25.54 arc(45.51,25.51) 45.63,25.44 v6(45.73,25.34)
PRX_B7_50R: length 18.2
  LAYER_3 w0.045: v2(29.59,28.39) arc(30.18,27.99) 30.89,27.85 33.33,27.85 38.02,27.85 arc(38.04,27.85) v4(38.05,27.84)
  LAYER_5 w0.047: v4(38.05,27.84) arc(38.2,27.61) 38.26,27.33 38.26,24.86 arc(38.48,23.74) 39.11,22.79 39.56,22.34 arc(39.9,21.84) 40.02,21.25 40.02,20.78 arc(39.91,20.27) 39.63,19.84 39.12,19.33 arc(39.04,19.28) v4(38.95,19.26)
PRX_B8_50R: length 0.9
  TOP w0.088: C7290.1 46.06,23.89 arc(45.98,23.78) 45.95,23.64 U7100.44
PRX_B12_50R: length 22.7
  LAYER_5 w0.047: v6(44.88,26.53) 45.19,26.22 arc(45.3,26.05) 45.34,25.86 45.34,22.58 arc(45.35,22.52) v4(45.38,22.48)
  LAYER_7 w0.045: v6(26.54,26.61) arc(27.51,26.76) 28.49,26.81 44.2,26.81 arc(44.57,26.74) v6(44.88,26.53)
PRX_B20_50R: length 20.6
  TOP w0.088: C7280.1 29.82,25.92 29.82,25.93 v6(29.83,25.95)
  LAYER_5 w0.047: v4(45.38,20.64) 45.19,20.83 arc(44.99,21.12) 44.93,21.46 44.93,25.68 arc(44.9,25.83) v6(44.82,25.95)
  LAYER_7 w0.045: v6(29.83,25.95) 29.84,25.96 44.81,25.96 v6(44.82,25.95)
PRX_B34_B39_50R: length 13.6
  LAYER_5 w0.047: v4(33.08,19.77) 33.08,19.77 33.32,20.02 arc(33.65,20.51) 33.77,21.1 33.77,24.53 arc(33.69,24.92) 33.47,25.25 33.41,25.31 arc(33.24,25.55) 33.19,25.84 33.19,27.93 arc(32.92,29.28) 32.16,30.42 31.49,31.08 arc(30.94,31.45) v4(30.29,31.58)
PRX_B34_B39_B25_50R: length 1.1
  TOP w0.088: L7326.1 29.4,31.14 C7326.1 29.72,31.14 29.73,31.14 L7306.2
PRX_B40_50R: length 16
  LAYER_5 w0.047: v4(29.2,27.29) 29.14,27.24 arc(28.99,27.02) 28.94,26.76 28.94,25.3 arc(28.98,25.11) 29.09,24.95 29.15,24.88 arc(29.33,24.62) 29.39,24.31 29.39,21.89 arc(29.52,21.27) 29.87,20.75 v6(30.46,20.16)
  LAYER_7 w0.045: v6(38.69,20.07) 30.67,20.07 arc(30.56,20.09) v6(30.46,20.16)
PRX_B41_50R: length 17.3
  LAYER_5 w0.047: v4(29.11,29.03) 29.27,28.87 arc(29.56,28.44) 29.66,27.94 29.66,27.09 arc(29.62,26.91) 29.52,26.77 29.48,26.72 arc(29.41,26.62) 29.39,26.5 29.39,26.01 arc(29.42,25.84) 29.51,25.71 29.74,25.47 arc(29.83,25.35) 29.86,25.2 29.86,21.74 arc(29.93,21.36) 30.15,21.04 30.55,20.63 arc(30.64,20.57) v6(30.76,20.55)
  LAYER_7 w0.045: v6(30.76,20.55) 37.62,20.55 arc(38.21,20.67) v6(38.71,21)
PRX_B66_B4_50R: length 11.7
  LAYER_5 w0.047: v4(32.03,21.26) 31.47,21.82 arc(31.16,22.28) 31.06,22.83 31.06,23.52 arc(31.09,23.71) 31.2,23.88 arc(31.28,23.99) 31.31,24.12 31.31,27.86 arc(31.3,27.92) v6(31.27,27.96)
  LAYER_7 w0.045: v6(26.71,28.02) 31.12,28.02 arc(31.2,28) v6(31.27,27.96)
PRX_LB2_SW_CTL1: length 15.7
  LAYER_7 w0.045: v7(46.47,51.58) 45.84,51.58 44.18,53.24 42.61,53.24 42.31,53.54 41.91,53.54 41.72,53.73 39.32,53.73 38.63,54.42 33.77,54.42 v6(32.51,55.68)
QLINK_CLK_M: length 24.6
  TOP w0.05: v4(30.89,54.6) 30.9,54.6 31.02,54.48 31.05,54.48 U1001.BA23
  LAYER_5 w0.05: v4(30.89,54.6) 30.8,54.69 30.05,54.69 29.95,54.79 28.18,54.79 27.12,53.73 27.12,37.64 25.18,35.7 25.18,34.66 v4(25.2,34.63)
QLINK_CLK_P: length 25.2
  TOP w0.05: v4(31.08,54.73) U1001.AY22
  TOP w0.088: U3100.96 24.71,34.96 v4(24.95,35.2)
  LAYER_5 w0.05: v4(31.08,54.73) 31.01,54.73 30.94,54.8 30.09,54.8 30,54.89 28.13,54.89 27.02,53.77 27.02,37.68 25.07,35.73 25.07,35.33 v4(24.95,35.2)
QLINK_EN: length 29
  LAYER_2 w0.045: v1(23.24,34.04) v4(23.47,33.81)
  LAYER_4 w0.045: v3(31.97,56.18) v4(31.84,56.05)
  LAYER_5 w0.045: v4(31.84,56.05) 31.79,56 31.36,56 31.13,56.23 30.66,56.23 30.54,56.11 27.55,56.11 25.76,54.31 25.76,38.36 23.7,36.3 23.7,35.69 23.42,35.41 23.42,34.66 23.35,34.59 23.35,34.21 23.47,34.09 v4(23.47,33.81)
QLINK_REQ: length 32.8
  LAYER_5 w0.045: v4(25.48,34.3) 25.27,34.3 25.03,34.07 23.64,34.07 23.44,34.27 23.44,34.53 23.52,34.6 23.52,35.37 23.8,35.65 23.8,36.23 25.86,38.29 25.86,54.28 27.59,56.01 30.58,56.01 30.7,56.13 31.09,56.13 31.33,55.89 32.04,55.89 32.14,55.79 32.31,55.79 32.94,56.42 32.94,56.55 32.84,56.65 32.54,56.65 32.06,57.13 v4(32.06,57.2)
QLINK_RX0_M: length 26.3
  LAYER_5 w0.05: v4(31.77,55.03) 31.72,55.03 31.68,55 31.39,55 31.26,55.13 31.11,55.13 31.08,55.1 30.27,55.1 30.18,55.19 27.92,55.19 26.72,53.98 26.72,37.89 24.62,35.8 24.62,34.62 v4(24.91,34.34)
QLINK_RX0_P: length 26.6
  LAYER_5 w0.05: v4(31.97,55.23) 31.72,55.23 31.59,55.1 31.43,55.1 31.31,55.23 31.07,55.23 31.04,55.2 30.31,55.2 30.21,55.29 27.88,55.29 26.61,54.03 26.61,37.93 24.52,35.84 24.52,34.36 v4(24.51,34.35)
QLINK_RX1_M: length 26.7
  TOP w0.05: U1001.AY20 31.51,55.23 v4(31.51,55.28)
  LAYER_5 w0.05: v4(24.18,34.62) 24.21,34.59 24.31,34.59 24.36,34.64 24.36,34.84 24.33,34.87 24.14,34.87 24.12,34.89 24.12,34.97 24.14,34.99 24.33,34.99 24.37,35.04 24.37,35.93 26.48,38.03 26.48,54.08 27.83,55.42 30.27,55.42 30.37,55.33 30.98,55.33 31.02,55.36 31.43,55.36 v4(31.51,55.28)
QLINK_RX1_P: length 26.7
  TOP w0.088: U3100.127 23.72,35.01 23.9,35.19 v4(24.07,35.19)
  LAYER_5 w0.05: v4(31.73,55.44) 31.69,55.48 31,55.48 30.94,55.43 30.41,55.43 30.31,55.53 27.78,55.53 26.38,54.12 26.38,38.07 24.27,35.97 24.27,35.39 v4(24.07,35.19)
QLINK_RX2_M: length 27.2
  TOP w0.05: v4(31.02,55.76) 31.02,55.77 31.08,55.72 U1001.AY18
  LAYER_3 w0.045: v4(23.71,34.38) 23.67,34.34 v2(23.53,34.34)
  LAYER_5 w0.05: v4(31.02,55.76) 31.01,55.77 30.38,55.77 30.38,55.77 27.68,55.77 26.12,54.2 26.12,38.21 24.03,36.12 24.03,35.55 23.79,35.32 23.79,35.08 23.85,35.02 23.85,34.52 v4(23.71,34.38)
QLINK_RX2_P: length 26.6
  TOP w0.05: U1001.BA19 30.99,55.47 30.9,55.57 30.89,55.57 v4(30.86,55.6)
  LAYER_5 w0.05: v4(23.97,34.33) 23.97,35.05 23.89,35.12 23.89,35.28 24.13,35.51 24.13,36.08 26.22,38.17 26.22,54.16 27.72,55.67 30.38,55.67 30.45,55.6 v4(30.86,55.6)
QLINK_TX_M: length 24.7
  TOP w0.088: v4(25.48,35.14) 25.27,35.14 U3100.87
  LAYER_5 w0.05: v4(25.48,35.14) 25.56,35.22 25.56,35.63 27.39,37.46 27.39,53.64 27.86,54.11 30.15,54.11 30.21,54.06 31.09,54.06 31.45,54.42 31.75,54.42 v4(31.76,54.43)
QLINK_TX_P: length 24
  LAYER_5 w0.05: v4(31.53,54.25) 31.47,54.25 31.18,53.96 30.14,53.96 30.08,54.01 27.9,54.01 27.49,53.6 27.49,37.42 25.66,35.6 25.66,34.9 25.63,34.86 v4(25.49,34.86)
QLN_DRX_B5B26_50R: length 1.7
  TOP w0.088: C7702.2 16.37,31.97 arc(16.35,32.07) 16.29,32.16 U7701.H3
QLN_DRX_B8_50R: length 1
  TOP w0.088: U7701.H5 16.36,33.28 16.41,33.28 16.74,33.61 C7707.2
QLN_DRX_B12B13_50R: length 2.6
  TOP w0.088: U7701.A6 13.89,32.79 arc(13.7,32.51) 13.64,32.18 13.64,31.29 arc(13.59,31.05) R7718.2
QLN_DRX_B20_50R: length 1.1
  TOP w0.088: U7701.G4 16.74,32.68 C7712.2
QLN_DRX_B28_50R: length 1.6
  TOP w0.088: U7701.B5 14.53,33.39 13.97,33.95 13.97,34.18 R7723.2
QLN_PRX_B5B26_50R: length 1.3
  TOP w0.088: C7285.2 29.46,24.8 28.81,24.15 U7216.H3
QLN_PRX_B8_50R: length 18.1
  TOP w0.088: U7216.H5 v6(28.61,24.84)
  LAYER_7 w0.045: v6(28.61,24.84) 29.4,24.84 arc(29.55,24.87) 29.69,24.96 29.76,25.04 arc(29.85,25.1) 29.97,25.12 45,25.12 arc(45.24,25.07) 45.44,24.94 45.57,24.8 arc(45.81,24.65) 46.09,24.59 v6(46.22,24.59)
QLN_PRX_B12_50R: length 1.3
  TOP w0.088: C7271.2 26.48,25.46 26.77,25.17 U7216.A6
QLN_PRX_B13_50R: length 1.5
  TOP w0.088: C7269.2 27.02,26.1 U7216.B5
QLN_PRX_B20_50R: length 2.2
  TOP w0.088: U7216.G4 28.68,24.39 29.08,24.79 29.08,25.56 29.32,25.81 C7280.2
QLN_PRX_B28_50R: length 1.2
  TOP w0.088: U7216.B3 26.58,24.15 26.04,24.68 C7241.2
QLN_PRX_LB1_SW_OUT_50R: length 1.6
  TOP w0.088: U7216.C6 27.26,25.28 27.49,25.5 L7219.2 C7216.2
QLN_PRX_LB2_SW_OUT_50R: length 1.8
  TOP w0.088: C7217.2 28.87,25.89 L7274.2 28.8,25.89 28.8,25.43 U7216.G6
QREFS_CXO_REXT: length 3.3
  TOP w0.05: R1173.1 30.21,48.33 30.39,48.51 30.91,48.51 31.02,48.62 31.02,48.98 31.06,49.02 32.09,49.02 32.5,49.44 U1001.AT42
QUAT_MIC_BIAS: length 24.9
  TOP w0.15: C5538.2 13.73,67.57 J5502.13
  LAYER_3 w0.1: v2(8.1,53.39) 8.1,53.79 8.56,54.26 8.56,54.42 8.4,54.58 8.28,54.58 8.13,54.73 7.96,54.73 7.76,54.93 7.76,55.04 6.88,55.92 6.86,55.92 v4(6.61,56.17)
  LAYER_5 w0.15: v4(6.61,56.17) 6.38,56.4 6.38,56.98 5.06,58.3 5.06,62.96 5.26,63.16 5.26,65.51 5.93,66.19 9.82,66.19 10.46,66.82 13.28,66.82 14.04,67.58 v4(14.04,67.91)
QUAT_MIC_DM: length 22.5
  TOP w0.15: 15.13,67.75 14.98,67.75 14.78,67.55 J5502.7 ; 15.13,67.75 15.13,67.91 v4(15.1,67.94) ; 15.13,67.75 J5502.5
  LAYER_5 w0.15: v4(6.14,56.8) 6.14,56.93 4.85,58.22 4.85,63.06 5.05,63.26 5.05,65.59 5.86,66.4 9.74,66.4 10.37,67.03 13.18,67.03 13.83,67.68 13.83,67.99 13.95,68.12 14.13,68.12 14.25,67.99 14.25,67.99 14.5,67.75 14.91,67.75 v4(15.1,67.94)
QUAT_MIC_DP: length 23.4
  TOP w0.15: J5502.9 14.43,67.63 ; 14.43,67.63 14.52,67.73 14.52,67.87 C5537.2 ; 14.43,67.63 14.2,67.63 14.08,67.51 J5502.11
  LAYER_5 w0.15: v4(14.59,67.96) 14.23,68.32 13.87,68.32 13.63,68.08 13.63,67.76 13.09,67.23 10.28,67.23 9.66,66.61 5.78,66.61 4.84,65.67 4.84,63.37 4.64,63.17 4.64,58.09 5.92,56.8 5.92,56.7 6.1,56.53 v4(6.1,55.77)
REF_CSNS_CS0_N: length 56.9
  LAYER_3 w0.045: v6(10.19,15.17) 10.36,15.17 10.46,15.27 11.53,15.27 v2(11.61,15.35)
  LAYER_7 w0.045: v7(7.93,64.94) 7.93,64.86 7.7,64.63 7.04,64.63 6.78,64.37 v7(6.56,64.37) 4.81,62.62 4.81,49.61 5.35,49.07 5.35,46.25 4.12,45.01 4.12,30.19 7.22,27.09 7.22,18.62 10.25,15.59 10.25,15.23 v6(10.19,15.17)
  BOTTOM w0.075: J350.8 v7(7.93,64.94)
REF_CSNS_CS3_N: length 66.3
  TOP w0.075: R280.1 64.33,16.6 C280.2 64.91,16.48 v6(64.91,16.13)
  LAYER_3 w0.045: v6(11.41,14.6) 11.5,14.69 12.57,14.69 12.84,14.96 12.84,15.1 v2(13.07,15.34)
  LAYER_5 w0.045: v6(17.19,16.68) 17.19,16.56 19.47,14.28 19.47,13.63 v6(19.41,13.57)
  LAYER_7 w0.045: v6(19.41,13.57) 19.39,13.55 15.79,13.55 14.94,14.4 11.61,14.4 v6(11.41,14.6) ; v6(17.19,16.68) 17.25,16.74 19.74,16.74 20.1,16.38 34.33,16.38 34.47,16.24 38.79,16.24 40.42,14.61 52.47,14.61 55.01,17.15 56.35,17.15 57.32,16.18 64.29,16.18 64.75,15.72 64.88,15.72 64.96,15.8 64.96,16.07 v6(64.91,16.13)
RF_CONN_DET1: length 89.3
  TOP w0.05: v4(30.86,57.94) 31.1,57.7 U1001.AY10
  LAYER_3 w0.045: v7(53.42,12.91) 52.49,12.91 52.3,12.73 39.24,12.73 36.51,10 31.88,10 v4(31.79,9.9)
  LAYER_5 w0.045: v4(30.86,57.94) 30.86,57.98 30.53,58.31 26.52,58.31 26.42,58.21 26.42,57.93 24.62,56.13 24.62,56.11 23.62,55.11 23.62,54.4 23.67,54.35 23.67,53.58 23.62,53.53 23.62,52.7 23.98,52.33 23.98,43.54 23.02,42.58 23.02,38.31 21.26,36.55 21.26,34.97 20.11,33.82 20.11,24.62 20.66,24.07 20.66,22.69 19.24,21.27 19.24,19.19 22.2,16.22 23.86,16.22 24.37,15.71 27.27,15.71 29.22,13.76 29.22,12.37 31.32,10.27 31.42,10.27 v4(31.79,9.9)
  BOTTOM w0.075: v7(53.42,12.91) C212.2 R210.1
RF_CONN_DET2: length 80.9
  LAYER_3 w0.045: v4(46.17,12.91) 46.08,12.82 39.2,12.82 36.47,10.09 v4(31.36,10.09)
  LAYER_5 w0.045: v4(46.17,12.91) 46.28,12.8 v7(46.95,12.8) ; v4(31.36,10.09) 29.13,12.32 29.13,13.72 27.23,15.61 24.33,15.61 23.82,16.12 22.16,16.12 19.14,19.15 19.14,21.31 19.61,21.77 19.61,24.35 20.01,24.75 20.01,33.86 21.16,35.02 21.16,36.59 22.92,38.35 22.92,42.62 23.89,43.58 23.89,52.29 23.53,52.66 23.53,53.63 23.57,53.68 23.57,54.29 23.44,54.43 v6(23.44,54.52)
  LAYER_7 w0.045: v6(23.44,54.52) 26.56,54.52 28.2,56.16 31.46,56.16 v6(31.48,56.18)
  BOTTOM w0.1: R230.1 C232.2 R231.2
RF_CONN_DET3: length 62.1
  LAYER_5 w0.045: v6(24.77,56.53) 24.52,56.28 24.52,56.14 23.28,54.9 23.28,54.42 23.47,54.22 23.47,53.71 23.43,53.67 23.43,52.62 23.79,52.26 23.79,43.63 22.83,42.67 22.83,38.39 21.07,36.63 21.07,35.06 19.91,33.9 19.91,24.81 19.51,24.41 19.51,21.82 19.05,21.35 19.05,19.11 22.13,16.03 23.78,16.03 27.43,12.38 v7(27.58,12.38)
  LAYER_7 w0.045: v6(24.77,56.53) 24.84,56.45 26.75,56.45 29.13,58.84 31.51,58.84 31.72,59.05 31.87,59.05 32.02,58.9 32.76,58.9 v6(33,59.13)
  BOTTOM w0.1: C132.2 26.91,11.85 26.92,11.86 R130.1 27.36,12.18 R131.2
RFFE1_CLK: length 28.9
  TOP w0.05: U1001.AY14 30.95,56.71 v4(30.88,56.78)
  LAYER_5 w0.045: v4(30.88,56.78) 30.81,56.72 26.85,56.72 25.95,55.81 25.95,55.44 25.11,54.61 25.11,42.62 24.82,42.33 v4(24.82,42.16) 24.82,41.75 24.78,41.71 24.78,38.37 23.2,36.79 23.2,35.88 22.79,35.48 22.79,34.95 22.56,34.72 22.56,34.35 v4(22.54,34.33)
RFFE1_DATA: length 28.5
  TOP w0.05: U3100.149 22.95,34.85 v4(22.93,34.85)
  LAYER_5 w0.045: v4(31.76,56.51) 31.58,56.7 31.09,56.7 31.01,56.62 26.89,56.62 26.06,55.79 26.06,55.41 25.21,54.56 25.21,42.58 24.99,42.36 v4(24.99,41.85) 24.99,41.77 24.88,41.66 24.88,38.33 23.3,36.75 23.3,35.85 22.89,35.44 22.89,34.89 v4(22.93,34.85)
RFFE2_CLK_1: length 107.1
  LAYER_3 w0.045: v4(17.01,13.92) 17.14,13.79 17.14,11.06 16.82,10.74 v4(16.7,10.74)
  LAYER_5 w0.045: v6(16.07,16.49) 16.09,16.47 16.09,16.28 16.42,15.95 16.42,15.54 17.08,14.88 17.08,13.99 v4(17.01,13.92) ; v6(19.59,19.51) 19.56,19.54 19.56,20.97 21.08,22.5 21.08,24.29 20.5,24.87 20.5,33.45 21.56,34.51 21.56,36.56 23.38,38.39 23.38,41.52 23.32,41.58 23.32,42.11 v4(23.37,42.16) 23.37,42.52 24.19,43.34 24.19,52.4 23.81,52.77 23.81,53.43 23.86,53.47 23.86,54.45 23.81,54.5 23.81,55 24.82,56.02 24.82,56.04 26.84,58.06 26.89,58.05 29.98,58.05 30.14,57.9 30.67,57.9 30.79,57.78 31.57,57.78 v4(31.72,57.93) ; v4(16.7,10.74) 16.7,10.7 16.26,10.26 11.24,10.26 v7(11.18,10.32)
  LAYER_7 w0.045: 19.59,19.59 v6(19.59,19.51) ; 19.59,19.59 19.47,19.59 19.29,19.41 17.67,19.41 16.18,17.92 16.18,16.6 v6(16.07,16.49) ; 19.59,19.59 19.71,19.59 19.93,19.38 19.93,17.72 20.79,16.86 30.69,16.86 31.09,17.26 39.24,17.26 40.42,16.08 51.9,16.08 55.17,19.34 56.84,19.34 v6(57.03,19.53)
RFFE2_DATA_1: length 107.7
  LAYER_3 w0.045: v4(17.24,13.93) 17.24,11.02 16.9,10.68 v4(16.9,10.56)
  LAYER_5 w0.045: v6(16.29,16.39) 16.29,16.22 16.52,15.99 16.52,15.58 17.19,14.91 17.19,13.98 v4(17.24,13.93) ; v4(16.9,10.56) 16.7,10.56 16.3,10.16 10.94,10.16 v7(10.85,10.25) ; v4(32.06,57.67) 32.05,57.68 30.76,57.68 30.64,57.8 30.1,57.8 29.94,57.96 26.88,57.96 24.92,56 24.92,55.97 23.9,54.95 23.9,54.55 23.95,54.49 23.95,53.43 23.91,53.39 23.91,52.81 24.29,52.44 24.29,43.29 23.53,42.53 23.53,41.95 v4(23.48,41.9) 23.48,38.34 21.66,36.52 21.66,34.47 20.6,33.41 20.6,24.91 21.18,24.33 21.18,22.45 19.66,20.93 19.66,19.68 19.76,19.58 19.76,19.34 v6(19.73,19.31)
  LAYER_7 w0.045: v6(57.32,19.52) 57.04,19.24 55.23,19.24 51.97,15.98 40.39,15.98 39.21,17.16 31.13,17.16 30.73,16.77 20.69,16.77 19.81,17.65 19.81,19.23 v6(19.73,19.31) 17.74,19.31 16.29,17.86 v6(16.29,16.39)
RFFE3_CLK: length 54
  LAYER_3 w0.045: v6(27.61,23.56) 27.97,23.92 v2(27.97,24.12)
  LAYER_5 w0.045: v6(23.05,24.15) 23.05,25.28 24.07,26.3 24.07,31.95 23.64,32.38 v6(23.64,32.44) 23.55,32.44 23.15,32.84 23.15,34.71 23.18,34.74 23.18,34.96 23.08,35.06 23.08,35.35 23.5,35.77 23.5,36.61 25.35,38.46 v4(25.35,41.84) 25.35,41.98 25.4,42.03 25.4,54.47 26.26,55.33 26.26,55.72 26.97,56.43 31.1,56.43 31.17,56.5 31.39,56.5 31.66,56.23 32.05,56.23 32.21,56.07 v4(32.21,55.95)
  LAYER_7 w0.045: v6(23.05,24.15) 24.62,24.15 25.18,23.59 25.26,23.59 27.42,23.59 27.45,23.56 v6(27.61,23.56) ; v6(23.64,32.44) v6(15.57,32.44)
RFFE3_DATA: length 54.2
  LAYER_5 w0.045: v4(32.47,56.25) 32.22,56.25 32.12,56.35 31.7,56.35 31.45,56.6 31.13,56.6 31.05,56.52 26.93,56.52 26.16,55.76 26.16,55.37 25.3,54.52 25.3,42.41 25.24,42.34 v4(25.24,42.14) 25.17,42.07 25.17,41.78 25.25,41.7 25.25,38.5 23.4,36.65 23.4,35.81 22.98,35.4 22.98,35.02 23.09,34.92 23.09,34.78 23.06,34.75 23.06,32.79 23.49,32.36 v6(23.49,32.26) 23.62,32.26 23.97,31.9 23.97,26.37 22.94,25.33 22.94,24.44 v6(22.85,24.35)
  LAYER_7 w0.045: v6(22.85,24.35) 23.21,24.35 23.3,24.26 24.65,24.26 25.22,23.69 27.51,23.69 27.54,23.72 27.67,23.72 27.74,23.65 v6(27.96,23.65) ; v6(15.52,31.99) 15.52,32.12 15.74,32.34 23.41,32.34 v6(23.49,32.26)
RFFE4_CLK: length 65.8
  LAYER_3 w0.045: v2(40.38,29.4) 40.22,29.56 40.22,29.76 39.5,30.48 39.2,30.48 38.71,30.97 38.71,31.42 38.32,31.81 v6(38.13,31.81)
  LAYER_5 w0.045: v4(32.78,56.48) 32.52,56.48 31.84,57.17 31.17,57.17 31.11,57.23 30.67,57.23 30.55,57.12 26.71,57.12 25.55,55.95 25.55,55.6 24.73,54.79 24.73,42.83 24.15,42.24 v4(24.15,42.15) 24.15,41.82 23.84,41.51 23.84,38.43 21.9,36.49 21.9,34.21 21.56,33.87 v6(21.56,33.62) 21.63,33.55 21.63,33.22 20.89,32.49 20.89,25.62 21.06,25.46 v6(21.06,25.01)
  LAYER_7 w0.045: v6(21.06,25.01) 20.99,25.01 20.86,24.88 20.86,24.55 20.29,23.98 20.11,23.98 20,23.87 v6(19.98,23.87) 19.07,24.78 v6(18.68,24.78) ; v6(38.13,31.81) 37.89,31.81 37.57,32.13 27.5,32.13 25.63,34 22.45,34 22.07,33.62 v6(21.56,33.62)
RFFE4_DATA: length 65.5
  LAYER_3 w0.045: v2(40.38,29.68) 40.31,29.68 40.31,29.8 39.53,30.58 39.25,30.58 38.84,30.99 38.84,31.44 38.31,31.97 v6(37.97,31.97)
  LAYER_5 w0.045: v6(21.22,25.22) 21.22,25.44 20.99,25.67 20.99,32.45 21.73,33.19 v6(21.73,33.81) 21.73,33.9 22,34.17 22,36.45 23.93,38.39 23.93,41.48 v4(24.31,41.85) 24.31,42.25 24.83,42.77 24.83,54.74 25.65,55.56 25.65,55.92 26.75,57.02 30.59,57.02 30.71,57.14 31.07,57.14 31.14,57.07 31.8,57.07 32.29,56.59 v4(32.29,56.43)
  LAYER_7 w0.045: v6(18.69,24.49) 18.52,24.66 18.52,24.86 18.6,24.94 19.08,24.94 19.86,24.16 v6(19.98,24.16) 20.05,24.09 20.25,24.09 20.76,24.6 20.76,24.97 21.01,25.22 v6(21.22,25.22) ; v6(21.73,33.81) 21.82,33.72 22.03,33.72 22.41,34.1 25.67,34.1 27.54,32.23 37.65,32.23 37.91,31.97 v6(37.97,31.97)
RFFE5_CLK: length 86
  LAYER_3 w0.045: v2(34.4,24.45) 34.6,24.25 37.16,24.25 v4(37.34,24.43)
  LAYER_5 w0.045: v6(22.18,19.05) 22.11,19.12 22.11,25.21 21.36,25.96 21.36,31.87 22.38,32.89 22.38,35.2 23.1,35.92 23.1,37.14 24.41,38.45 24.41,41.59 v4(24.66,41.83) 24.66,42.03 24.64,42.05 24.64,42.28 25.02,42.66 25.02,54.65 25.85,55.48 25.85,55.85 26.83,56.83 30.67,56.83 30.78,56.94 30.97,56.94 31.1,56.81 31.6,56.81 31.68,56.73 31.92,56.73 v4(31.98,56.67) ; v4(37.34,24.43) 37.26,24.35 37.26,23.42 39.27,21.41 39.27,20.51 v6(39.33,20.45)
  LAYER_7 w0.045: v6(52.54,18.52) 52.54,18.89 52.28,19.15 40.63,19.15 v6(39.33,20.45) 39.28,20.45 39.17,20.34 39.17,19.78 38.92,19.53 29.7,19.53 29.16,19 22.23,19 v6(22.18,19.05)
RFFE5_DATA: length 85.3
  LAYER_3 w0.045: v2(34.75,24.45) 34.83,24.37 36.95,24.37 v4(37.04,24.46)
  LAYER_5 w0.045: 24.46,42.16 24.49,42.14 24.49,41.79 24.32,41.62 24.32,38.5 23,37.18 23,35.95 22.28,35.23 22.28,32.92 21.26,31.91 21.26,25.93 22.02,25.17 22.02,18.89 v6(21.9,18.77) ; 24.46,42.16 v4(24.47,42.16) ; 24.46,42.16 24.46,42.26 24.92,42.71 24.92,54.7 25.75,55.52 25.75,55.88 26.79,56.93 30.63,56.93 30.74,57.04 31.01,57.04 31.14,56.91 31.74,56.91 v4(31.75,56.9) ; v4(37.04,24.46) 37.16,24.34 37.16,23.37 39.17,21.36 39.17,20.38 39.33,20.22 v6(39.33,20.21)
  LAYER_7 w0.045: v6(21.9,18.77) 22.16,18.77 22.29,18.9 29.21,18.9 29.74,19.43 38.96,19.43 39.27,19.74 39.27,20.15 v6(39.33,20.21) 39.43,20.21 40.6,19.04 52.16,19.04 v6(52.38,18.82)
S1C_PGND: length 2.2
  TOP w0.135: v1(24.37,49.17) U2560.B3
  LAYER_4 w0.175: v3(25.03,50.05) v3(25.03,49.87) v3(25.21,49.87) ; v3(25.03,50.05) v3(25.21,50.05) v3(25.39,50.05) ; v3(25.03,50.05) v3(25.21,49.87) ; v3(25.21,49.87) v3(25.39,49.87) v3(25.39,50.05) ; v3(25.21,49.87) v3(25.39,50.05)
  vias: v1(23.18,50.38) v1(23.27,49.11) v1(23.27,48.93) v1(23.36,50.56) v1(23.36,50.38) v1(23.45,49.02) v1(25.5,48.67) v1(25.68,48.67) v1(25.86,48.67) v1(26.04,48.67)
S2C_PGND: length 2.6
  TOP w0.135: v1(58.26,50.49) U2570.B3
  TOP w0.3: 57.86,49.69 U2570.B3
  LAYER_4 w0.175: v3(57.23,49.8) v3(57.23,49.62) v3(57.41,49.62) ; v3(57.23,49.8) v3(57.41,49.62) ; v3(57.23,49.8) v3(57.41,49.8) v3(57.59,49.8) ; v3(57.41,49.62) v3(57.59,49.62) v3(57.59,49.8) ; v3(57.41,49.62) v3(57.59,49.8)
  vias: v1(56.63,50.96) v1(56.81,50.96) v1(56.99,50.96) v1(57.17,50.96) v1(58.77,49.01) v1(58.86,48.85) v1(58.95,49.01) v1(59.36,50.51) v1(59.36,50.33) v1(59.54,50.5)
SAR_SENSOR_INT_N: length 64.9
  TOP w0.05: 31.51,52.26 31.2,52.26 31.01,52.06 31.01,51.39 v4(30.92,51.31)
  TOP w0.075: C6153.2 13.45,16 13.45,16.5 U6150.10 13.45,16.63 13.45,17.01 13.56,17.12 v2(13.86,17.12)
  LAYER_3 w0.045: v2(13.86,17.12) 13.87,17.13 v4(13.87,17.91) ; v4(28.59,39.98) 28.09,39.98 26.77,41.3 23.28,41.3 22.56,42.02 11.44,42.02 10.76,41.33 v4(10.76,41.12) ; v4(12.62,22.33) 12.14,22.33 11.55,21.74 11.12,21.74 v2(10.92,21.54) 11.1,21.36 11.56,21.36 11.69,21.24 11.69,20.13 11.9,19.92 12.3,19.92 12.45,20.07 12.77,20.07 v4(12.94,20.24)
  LAYER_5 w0.045: v4(28.59,39.98) 28.65,40.04 28.65,46.26 28.31,46.59 28.31,48.34 28.64,48.66 28.64,48.67 28.8,48.83 28.8,49.19 29.04,49.43 29.04,50 29.05,50.01 29.05,50.66 29.24,50.85 29.7,50.85 29.85,51 30.57,51 30.87,51.31 v4(30.92,51.31) ; v4(12.94,20.24) 13.04,20.14 13.12,20.14 13.97,19.29 13.97,18.01 v4(13.87,17.91) ; v4(10.76,41.12) 10.82,41.06 10.82,38.72 12.78,36.75 12.78,33.45 13.08,33.16 13.08,25.65 13.36,25.37 13.36,24.3 13.26,24.2 13.26,23.35 12.87,22.96 12.87,22.58 v4(12.62,22.33)
SB_INT_N: length 59.8
  TOP w0.05: U1001.AB42 35.95,49.8 35.93,49.8 35.92,49.79 v2(35.92,49.78)
  LAYER_2 w0.045: v2(13.7,44.44) 13.76,44.5 15.54,44.5 v2(15.66,44.61)
  LAYER_3 w0.045: v2(11.52,22.59) 11.35,22.76 11.12,22.76 11.03,22.85 11.03,22.99 11.21,23.17 11.71,23.17 12.02,23.48 12.02,23.53 12.02,25.87 12.67,26.53 12.67,28.92 12.22,30.71 12.22,34.71 11.01,35.91 10.5,35.91 8.13,38.28 v2(7.95,38.28) 6.94,39.29 6.94,44.53 7.73,45.32 12.9,45.32 13.7,44.52 v2(13.7,44.44) ; v2(15.66,44.61) 15.76,44.51 25.47,44.51 25.73,44.77 31.95,44.77 32.2,45.02 32.76,45.02 33.26,45.52 33.26,45.52 35.18,47.44 35.18,48.32 35.7,48.84 35.7,49.03 35.56,49.17 35.56,50.05 35.65,50.14 35.78,50.14 35.92,50.01 v2(35.92,49.78)
SB_RST_N: length 80.8
  TOP w0.05: v2(33.1,60.18) 33.49,60.18 U1001.AL1
  LAYER_2 w0.045: v2(5.24,44.84) 6.27,44.84 v2(6.27,44.83)
  LAYER_3 w0.045: v6(31.81,63.49) 31.96,63.34 32.06,63.34 32.6,62.8 32.6,60.68 v2(33.1,60.18) ; v2(5.24,44.84) 5.24,44.84 5.24,48 3.7,49.54 3.7,56.98 4.13,57.41 6.25,57.41 6.35,57.52 6.35,59.09 6.66,59.39 6.66,59.78 7.79,60.91 7.79,62.48 10.07,64.76 10.65,64.76 v4(10.67,64.78) ; v2(9.69,21.91) 10.01,21.91 10.58,22.48 10.58,22.79 v2(10.67,22.88) 10.67,22.92 10.27,23.32 10.27,24.87 12.2,26.8 12.2,28.82 11.74,30.6 11.74,30.61 11.74,34.51 11.54,34.71 11.2,34.71 10.58,35.33 10.23,35.33 9.57,35.99 9.26,35.99 6.35,38.91 6.35,44.75 v2(6.27,44.83)
  LAYER_5 w0.045: v6(16.14,64.15) 15.67,64.62 11.55,64.62 11.39,64.78 v4(10.67,64.78)
  LAYER_7 w0.045: v6(16.14,64.15) 16.14,64.18 16.71,64.75 20.36,64.75 22.2,62.91 27.1,62.91 27.38,63.19 31.54,63.19 31.81,63.47 v6(31.81,63.49)
SDM_LNBBCLK1: length 16.1
  LAYER_3 w0.045: v2(33.46,51.23) 33.37,51.14 32.94,51.14 32.69,51.38 32.28,51.38 v7(32.17,51.5) ; v4(20.51,55.99) 20.29,56.21 v2(20.26,56.21)
  LAYER_5 w0.045: v6(21.44,53.96) 20.51,54.89 v4(20.51,55.99)
  LAYER_7 w0.045: v6(21.44,53.96) 22.26,53.96 24.05,52.17 26.42,52.17 26.51,52.26 30.63,52.26 30.73,52.16 31.48,52.16 32.14,51.5 v7(32.17,51.5)
SDM_LNBBCLK1_EN: length 11.2
  LAYER_2 w0.045: v2(20.48,54.59) 20.34,54.73 20.34,55.42 20.18,55.58 20.18,55.76 v1(19.99,55.95)
  LAYER_3 w0.045: v2(27.61,51.01) 27.45,51.17 22.84,51.17 22.25,51.77 22.25,52.82 21.8,53.27 21.8,53.9 21.05,54.65 20.54,54.65 v2(20.48,54.59)
SDM_RESOUT_N: length 16.6
  TOP w0.05: v2(43.39,55.42) 43.22,55.25 42.12,55.25 42.01,55.14 41.33,55.14 U1001.A21
  LAYER_3 w0.045: v6(51.46,55.42) 51.37,55.33 43.48,55.33 v2(43.39,55.42)
  LAYER_7 w0.045: v6(57.16,56.39) 55.8,56.39 54.83,55.42 v6(51.46,55.42)
SDM_THERM: length 8.2
  LAYER_2 w0.045: v1(21.45,55.98) 21.66,55.98 21.84,55.8 21.99,55.8 22.06,55.87 22.27,55.87 v2(22.43,55.71) ; v2(25.22,52.34) v1(25.22,52.72)
  LAYER_3 w0.045: v2(25.22,52.34) 25.16,52.4 24.62,52.4 24.2,51.98 22.97,51.98 22.65,52.3 22.65,53.08 22.45,53.28 22.45,54.67 22.19,54.93 22.19,55.08 22.04,55.23 22.04,55.32 v2(22.43,55.71)
SDR_DRX_HB1: length 1.9
  TOP w0.088: U3100.141 23.47,30.29 23.08,29.89 23.08,29.62 C7835.2
SDR_DRX_HB2: length 1.6
  TOP w0.088: U3100.133 23.72,30.23 23.41,29.92 C7863.2
SDR_DRX_HB3: length 1.3
  TOP w0.088: U3100.126 23.97,30.55 23.97,30.55 23.97,30.12 23.91,30.06 L7825.2
SDR_DRX_HB4: length 1.6
  TOP w0.088: U3100.117 24.21,30.14 24.41,29.95 L7614.2
SDR_DRX_LB2: length 0.8
  TOP w0.088: U3100.170 22.11,31.86 21.82,32.15 C7750.2
SDR_DRX_LB4: length 1
  TOP w0.088: C7751.2 21.71,32.59 21.86,32.59 22.09,32.35 U3100.169
SDR_DRX_MB1: length 2.7
  TOP w0.088: U3100.171 22.05,31.36 21.99,31.3 21.13,31.3 21,31.43 20.08,31.43 C7606.2
SDR_DRX_MB2: length 1.6
  TOP w0.088: U3100.164 22.73,31.02 22.72,31.01 22.72,30.7 22.6,30.58 22.2,30.58 21.79,30.98 L7626.2
SDR_DRX_MB3: length 1.5
  TOP w0.088: U3100.156 22.98,30.71 22.65,30.38 22.14,30.38 22.03,30.48 L7616.2
SDR_DRX_MB4: length 2.2
  TOP w0.088: U3100.148 23.22,30.67 22.73,30.17 22.14,30.17 21.85,29.88 L7603.2
SDR_GNSS: length 1.7
  TOP w0.088: U3100.161 22.49,32.84 22.01,32.84 21.7,33.15 L8518.2
SDR_PRX_HB1: length 2.2
  TOP w0.088: L7368.2 28.06,29.97 27.16,29.97 26.44,30.69 U3100.46
SDR_PRX_HB2: length 2.3
  TOP w0.088: C7366.2 27.21,29.64 26.19,30.66 U3100.54
SDR_PRX_HB3: length 3.3
  TOP w0.088: U3100.63 25.95,30.64 27.29,29.3 27.29,28.92 27.62,28.59 27.62,28.39 L7371.2
SDR_PRX_HB4: length 1.3
  TOP w0.088: L7336.2 26.1,30.07 26.09,30.07 26.09,30.21 25.7,30.61 U3100.71
SDR_PRX_LB2: length 0.9
  TOP w0.088: C7215.2 28.25,32.07 28.06,32.07 27.84,31.86 U3100.15
SDR_PRX_LB4: length 0.9
  TOP w0.088: C7270.2 27.95,32.35 U3100.14
SDR_PRX_MB1: length 1.4
  TOP w0.088: L7328.2 28.77,31.36 U3100.16
SDR_PRX_MB2: length 2.1
  TOP w0.088: U3100.25 27.18,30.75 27.34,30.6 27.75,30.6 28.09,30.94 L7326.2
SDR_PRX_MB3: length 3
  TOP w0.088: L7331.2 29.58,30.21 29.35,30.44 27.22,30.44 26.94,30.73 U3100.32
SDR_PRX_MB4: length 2.7
  TOP w0.088: U3100.38 26.69,30.71 27.18,30.22 28.4,30.22 L7333.2
SDR_TX0_LB2: length 34
  LAYER_5 w0.047: v6(50.53,28.16) 51.62,27.07 arc(52.93,25.11) v4(53.39,22.8) ; v4(26.93,34.34) 26.93,31.82 arc(26.98,31.52) v6(27.15,31.27)
  LAYER_7 w0.045: v6(50.53,28.16) 50.54,28.16 48.07,30.63 arc(47.82,30.79) 47.53,30.85 37.9,30.85 arc(37.62,30.91) 37.38,31.06 arc(37.15,31.22) 36.89,31.27 v6(27.15,31.27)
SDR_TX_CH0_HB1: length 18.5
  LAYER_3 w0.045: v4(34.34,25.09) arc(34.56,24.94) 34.82,24.89 37.63,24.89 arc(37.99,24.82) v2(38.29,24.62)
  LAYER_5 w0.047: v4(26.52,35.54) 27.85,35.39 arc(28.42,35.22) 28.91,34.88 33.12,30.66 arc(33.93,29.46) 34.21,28.03 34.22,27.75 34.22,25.38 arc(34.25,25.22) v4(34.34,25.09)
SDR_TX_CH0_LB1: length 33.7
  LAYER_5 w0.047: v4(27.71,34.03) 28.91,32.83 arc(29.03,32.64) 29.08,32.42 29.08,29.9 arc(29.13,29.77) v6(29.26,29.72) ; v6(49.87,27.5) 49.87,27.49 51.74,25.62 arc(52.11,25.06) 52.25,24.4 52.25,23.87 arc(52.43,22.95) 52.95,22.16 v4(53.72,21.4)
  LAYER_7 w0.045: v6(29.26,29.72) 45.06,29.72 arc(47.45,29.25) 49.47,27.89 v6(49.87,27.5)
SDR_TX_CH0_MB1: length 13.1
  TOP w0.088: U3100.33 v4(26.69,35.14)
  LAYER_5 w0.047: v4(33.66,25.97) 33.66,28 arc(33.38,29.4) 32.59,30.58 28.97,34.19 arc(27.92,34.89) v4(26.69,35.14)
SDR_TX_CH0_MB2: length 34.8
  LAYER_5 w0.047: v6(48.39,27.56) 49.81,26.14 arc(50.24,25.49) 50.4,24.72 50.4,24.33 arc(50.53,23.67) 50.9,23.12 v4(53.72,20.3) ; v6(29.83,29.3) arc(29.72,29.34) 29.68,29.45 29.68,30.22 arc(29.64,30.4) 29.54,30.55 arc(29.46,30.66) 29.44,30.8 29.44,32.63 arc(29.37,32.94) 29.2,33.21 29.06,33.34 28.14,34.26 arc(27.97,34.38) 27.77,34.42 27.55,34.42 arc(27.5,34.41) v4(27.46,34.38)
  LAYER_7 w0.045: v6(48.39,27.56) 47.63,28.32 arc(46.54,29.05) 45.26,29.3 v6(29.83,29.3)
SDR_TX_FBRX_P: length 36.9
  TOP w0.088: R7121.2 R7122.2 48.51,16.68 v4(48.51,16.27) C7126.2
  LAYER_5 w0.047: v4(48.51,16.27) 45.84,18.94 arc(44.3,21.24) 43.76,23.96 v6(43.76,27.37) ; v6(26.03,27.39) 26.04,27.4 25.79,27.64 arc(25.55,28.01) 25.47,28.43 25.47,31.29 arc(25.58,31.84) 25.89,32.31 v4(25.94,32.36)
  LAYER_7 w0.045: v6(43.76,27.37) 43.75,27.37 32.34,27.37 arc(32.26,27.36) 32.2,27.31 arc(32.14,27.27) 32.07,27.26 26.36,27.26 arc(26.18,27.3) v6(26.03,27.39)
SDR_TXFBRX_ATT_50R: length 1.7
  TOP w0.088: U7100.4 46.83,17.61 arc(46.95,17.31) 47.25,17.19 R7120.2 R7121.1
SEC_MIC_BIAS: length 30.9
  TOP w0.15: J5502.20 12.68,64.8 v2(12.24,64.37)
  LAYER_3 w0.1: v2(8.38,54.34) 7.84,53.8 7.64,53.8 7.46,53.98 7.01,53.98 6.52,54.47 6.29,54.47 6.08,54.68 6.08,54.69 6.08,54.79 5.92,54.94 5.72,54.94 5.62,55.04 v4(5.31,55.04)
  LAYER_3 w0.15: v4(12.71,68.33) 12.71,66.43 13.29,65.85 13.29,65.25 12.4,64.37 v2(12.24,64.37)
  LAYER_5 w0.15: v4(5.31,55.04) 5.32,55.05 5.32,56.03 5.12,56.23 5.12,56.49 3.84,57.78 3.84,63.69 4.04,63.89 4.04,66.15 5.29,67.4 8.89,67.4 9.82,68.33 v4(12.71,68.33)
SEC_MIC_DM: length 27.5
  TOP w0.15: v2(14.06,64.37) 14.06,64.47 13.97,64.56 ; C5533.2 14.08,64.33 14.08,64.66 ; J5502.14 13.73,64.8 13.97,64.56 ; 14.08,64.66 J5502.12 ; 14.08,64.66 13.97,64.56
  LAYER_3 w0.15: v4(13.16,67.89) 13.12,67.85 13.12,66.59 13.69,66.02 13.69,64.74 v2(14.06,64.37)
  LAYER_5 w0.15: v4(5.86,54.74) 6.07,54.95 6.07,55.22 5.72,55.57 5.72,56.21 5.56,56.37 5.56,56.64 4.24,57.96 4.24,63.52 4.44,63.72 4.44,65.98 5.45,67 9.09,67 10,67.91 12.8,67.91 12.81,67.9 13.15,67.9 v4(13.16,67.89)
SEC_MIC_DP: length 26.9
  TOP w0.15: J5502.16 13.38,64.76 13.24,64.62 13.15,64.62 ; 13.15,64.62 13.03,64.74 J5502.18 ; 13.15,64.62 v2(13.15,64.38)
  LAYER_3 w0.15: v2(13.15,64.38) 13.49,64.72 13.49,65.94 12.91,66.52 12.91,68.08 v4(12.94,68.11)
  LAYER_5 w0.15: v4(5.85,55.13) 5.85,55.13 5.52,55.47 5.52,56.12 5.34,56.3 5.34,56.56 4.04,57.86 4.04,63.61 4.24,63.81 4.24,66.07 5.37,67.2 8.98,67.2 9.89,68.12 12.93,68.12 v4(12.94,68.11)
SENSOR_SPI_CLK: length 56
  TOP w0.075: U6110.13 v4(65.12,62.71) ; U6115.13 52.78,43.53 53.02,43.53 v2(53.19,43.7)
  LAYER_3 w0.045: v2(34.27,49.99) 34.21,49.93 34.21,49.7 33.92,49.41 33.58,49.41 33.49,49.32 33.49,49.18 33.58,49.09 33.58,48.84 33.27,48.53 33.27,48.29 32.99,48.01 32.99,47.5 v4(32.89,47.4) ; v4(64.24,62.71) 64.09,62.56 64.09,62.13 64.23,61.99 64.23,58.01 64.43,57.8 64.43,50.03 62.92,48.52 62.92,46.84 61.03,44.95 59.2,44.95 58.28,44.03 53.99,44.03 53.86,43.9 53.39,43.9 v2(53.19,43.7) 53.15,43.7 53.08,43.64 50.71,43.64 50.59,43.76 50.58,43.76 50.57,43.77 46.55,43.77 46.43,43.88 43.24,43.88 42.82,44.3 38.96,44.3 38.43,44.83 38.05,45.21 36.72,45.21 36.42,45.51 34.21,45.51 v4(33.93,45.22)
  LAYER_5 w0.045: v4(64.24,62.71) v4(65.12,62.71) ; v4(33.93,45.22) 33.93,45.31 33.12,46.12 33.12,46.5 32.95,46.67 32.95,47.34 v4(32.89,47.4)
SENSOR_SPI_CS_N: length 55.4
  TOP w0.05: U1001.AK42 33.99,49.36 33.88,49.25 v2(33.65,49.25)
  TOP w0.075: U6110.12 v4(65.1,62.21) ; U6115.12 v1(53.14,42.89)
  LAYER_2 w0.045: v2(53.44,43.72) 53.44,43.49 53.14,43.19 v1(53.14,42.89)
  LAYER_3 w0.045: v4(34.17,45.23) 34.29,45.11 36.14,45.11 36.51,44.74 38.38,44.74 38.92,44.2 42.78,44.2 43.2,43.79 46.39,43.79 46.51,43.67 50.54,43.67 50.67,43.54 53.26,43.54 v2(53.44,43.72) 53.53,43.72 53.62,43.8 53.9,43.8 54.03,43.93 58.32,43.93 59.24,44.86 61.07,44.86 63.02,46.8 63.02,48.48 64.53,49.99 64.53,57.84 64.32,58.05 64.32,62.13 64.26,62.2 v4(64.26,62.21) ; v4(33.13,47.38) 33.14,47.38 33.14,47.39 33.09,47.44 33.09,47.97 33.37,48.25 33.37,48.49 33.67,48.8 33.67,49.22 v2(33.65,49.25)
  LAYER_5 w0.045: v4(34.17,45.23) 34.02,45.38 33.99,45.38 33.21,46.16 33.21,46.54 33.04,46.71 33.04,47.3 v4(33.13,47.38) ; v4(64.26,62.21) v4(65.1,62.21)
SENSOR_SPI_MISO: length 59.1
  TOP w0.075: v2(64.63,64.32) 64.63,63.99 U6110.1 ; U6115.1 v1(52.48,45)
  LAYER_2 w0.045: v2(33.66,49.67) 33.66,49.67 33.66,50 33.95,50.29 v1(33.95,50.29) ; v1(52.48,45) 53.17,44.31 53.17,44.25 53.77,43.65 v2(53.77,43.65)
  LAYER_3 w0.045: v4(33.49,45.24) 33.53,45.24 33.75,45.02 36.1,45.02 36.47,44.65 38.33,44.65 38.34,44.64 38.35,44.64 38.88,44.11 42.74,44.11 43.16,43.69 46.35,43.69 46.47,43.57 50.49,43.57 50.61,43.45 53.39,43.45 53.59,43.65 v2(53.77,43.65) 53.77,43.66 53.9,43.66 54.08,43.84 58.36,43.84 59.28,44.76 61.11,44.76 63.11,46.76 63.11,48.44 64.62,49.95 64.62,57.88 64.43,58.08 64.43,62.35 64.57,62.49 64.57,63.68 64.7,63.81 64.7,64.25 v2(64.63,64.32) ; v4(32.61,47.78) 32.79,47.96 32.79,48.09 33,48.3 33,48.93 33.3,49.22 33.3,49.4 33.5,49.6 33.59,49.6 v2(33.66,49.67)
  LAYER_5 w0.045: v4(32.61,47.78) 32.46,47.63 32.46,46.51 33.49,45.48 v4(33.49,45.24)
SENSOR_SPI_MOSI: length 57.3
  TOP w0.075: U6110.14 v4(65.13,63.21) ; U6115.14 52.68,43.93 v2(53.17,43.93)
  LAYER_3 w0.045: 53.17,43.94 53.15,43.95 52.93,43.73 50.76,43.73 50.63,43.86 46.59,43.86 46.47,43.98 43.28,43.98 42.86,44.4 39,44.4 38.46,44.93 38.09,45.3 36.76,45.3 36.46,45.6 34.01,45.6 v4(33.71,45.3) ; 53.17,43.94 53.19,43.94 53.24,44 53.82,44 53.95,44.12 58.24,44.12 59.16,45.05 60.99,45.05 62.83,46.88 62.83,48.56 64.34,50.06 64.34,57.76 64.13,57.97 64.13,61.93 63.99,62.08 v4(63.99,63.21) ; 53.17,43.94 v2(53.17,43.93) ; v2(34.53,50.27) 34.52,50.27 34.4,50.15 34.2,50.15 34.09,50.04 34.09,49.71 33.88,49.51 33.54,49.51 33.39,49.36 33.39,49.19 33.1,48.9 33.1,48.27 32.89,48.05 32.89,47.74 v4(32.75,47.6)
  LAYER_5 w0.045: v4(63.99,63.21) v4(65.13,63.21) ; v4(32.75,47.6) 32.6,47.6 32.56,47.56 32.56,46.54 33.71,45.39 v4(33.71,45.3)
SIM_CLK: length 8
  LAYER_7 w0.045: v7(59.44,46.73) 58.29,46.73 55.4,43.84 55.4,42 v7(55.51,41.89)
  BOTTOM w0.075: VR4252.1 55.68,42.05 55.71,42.05 55.98,42.31 J4250.1
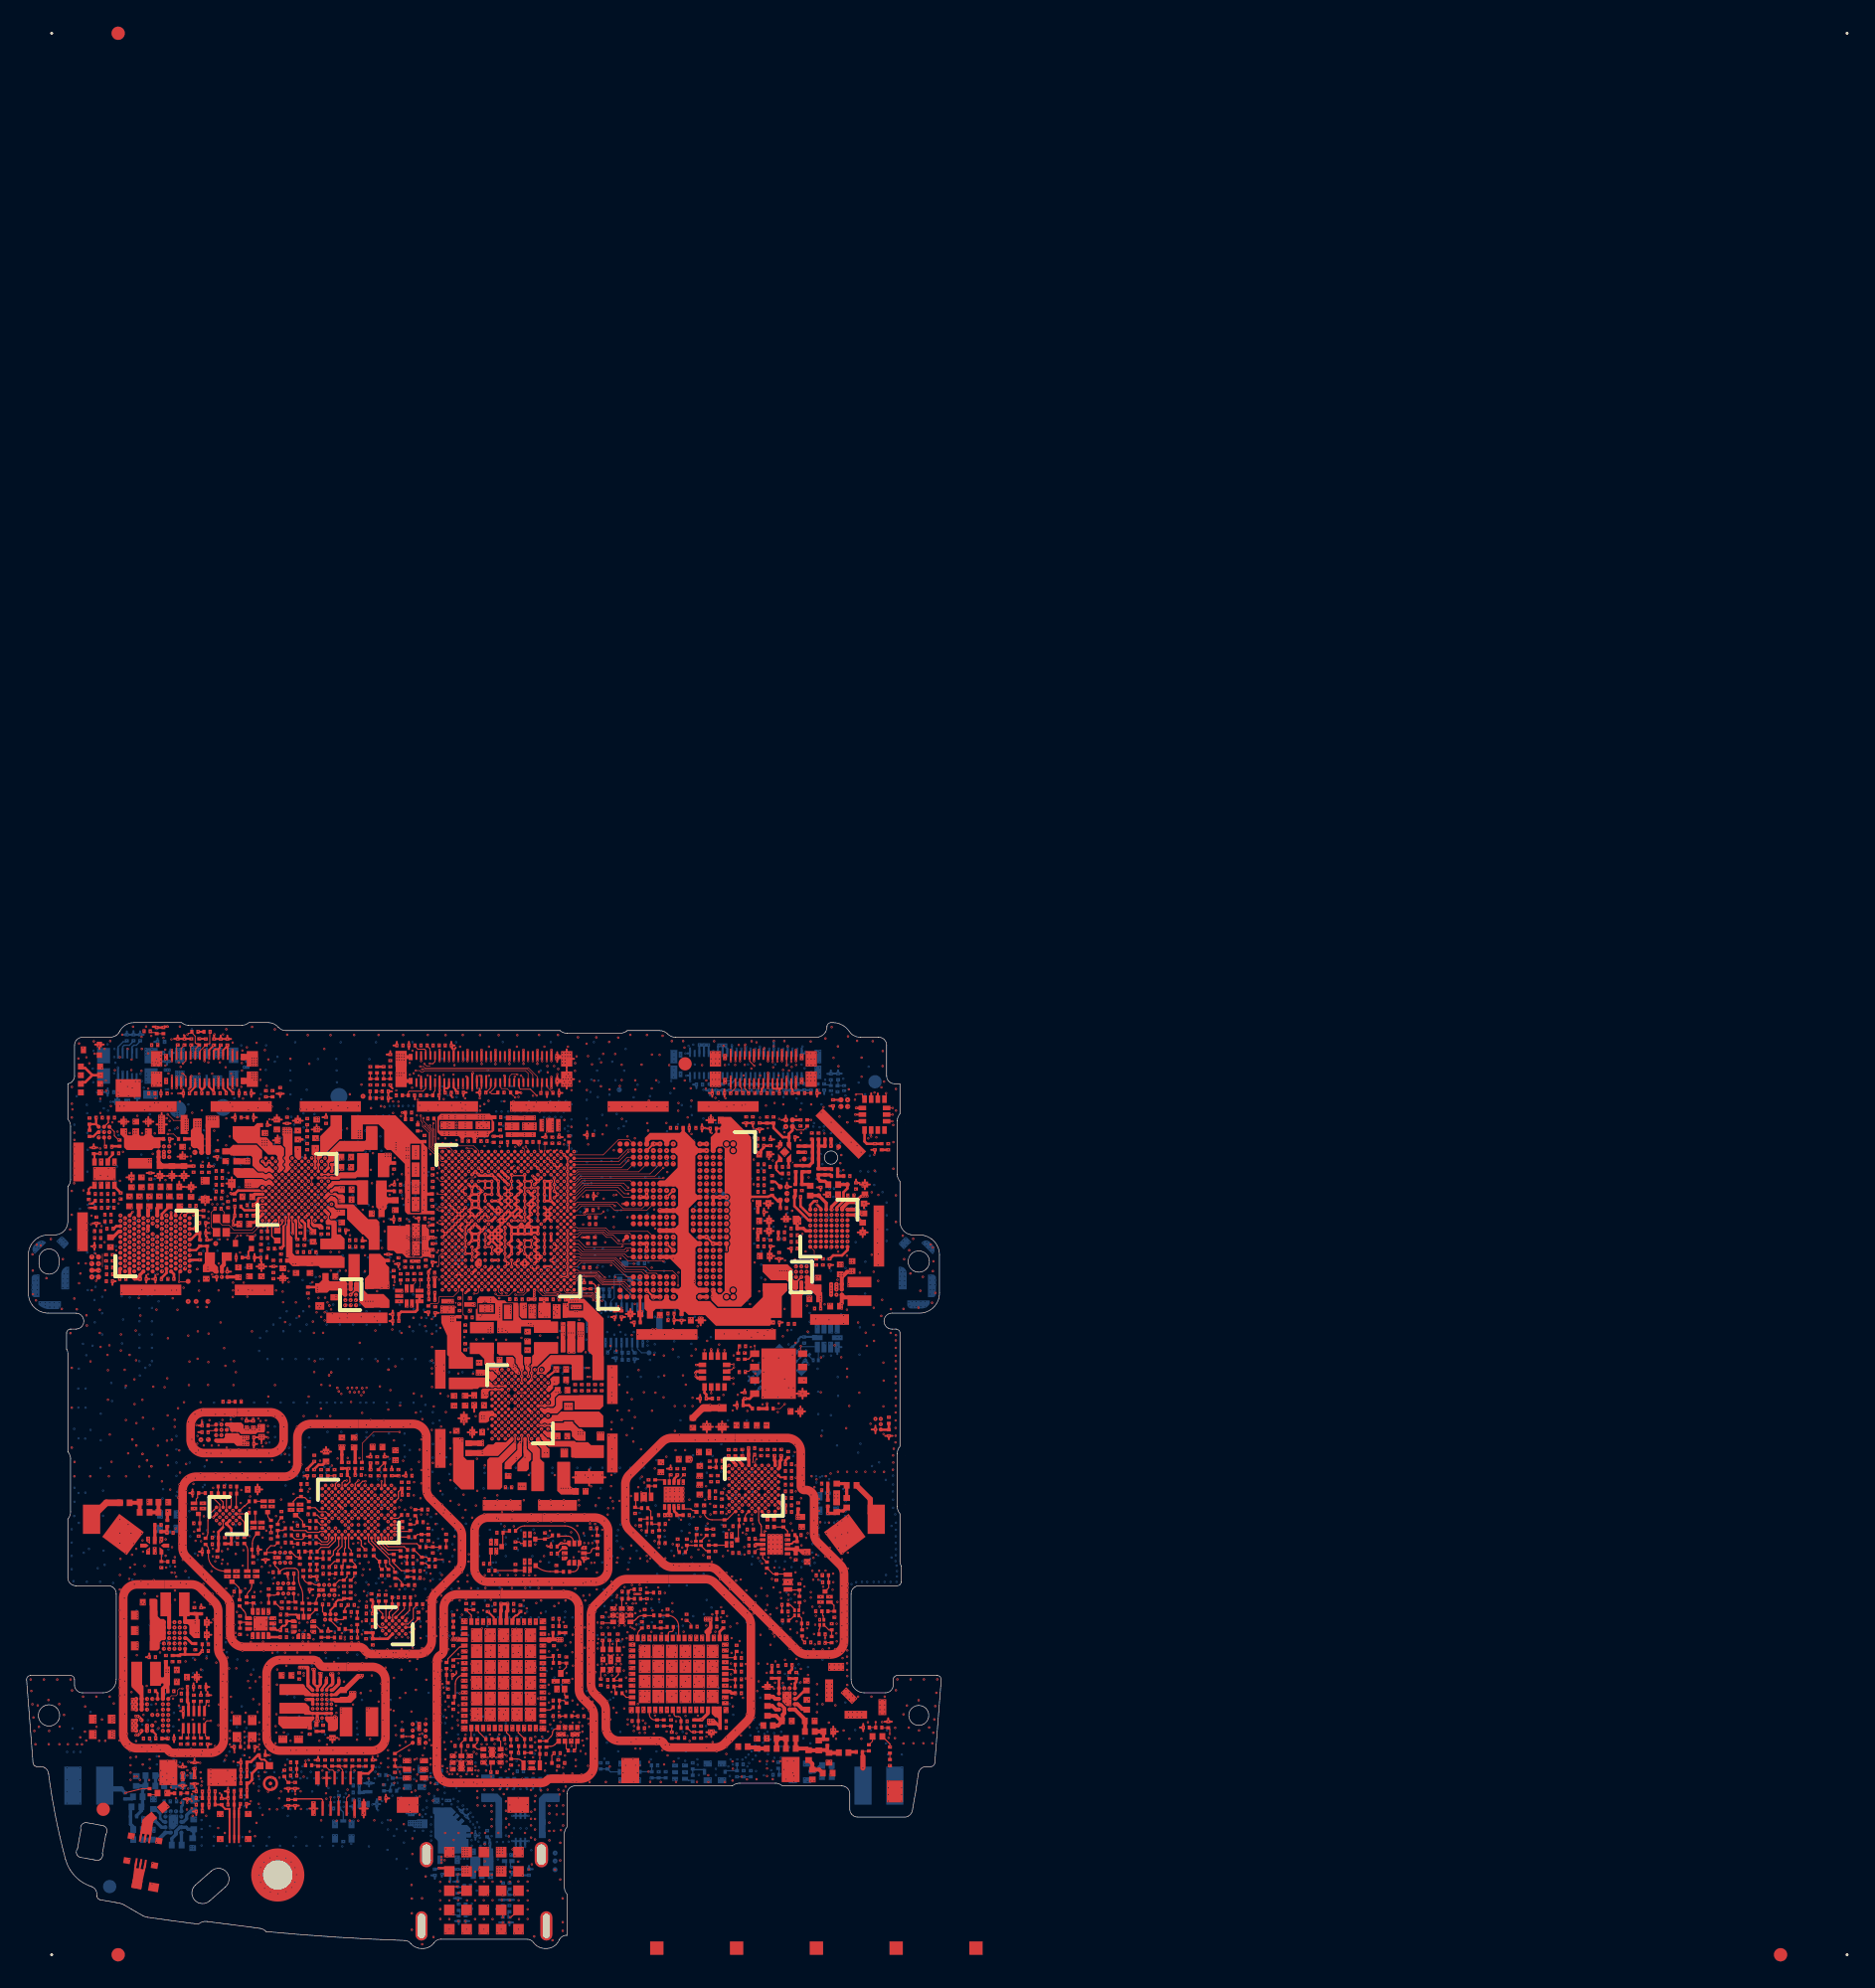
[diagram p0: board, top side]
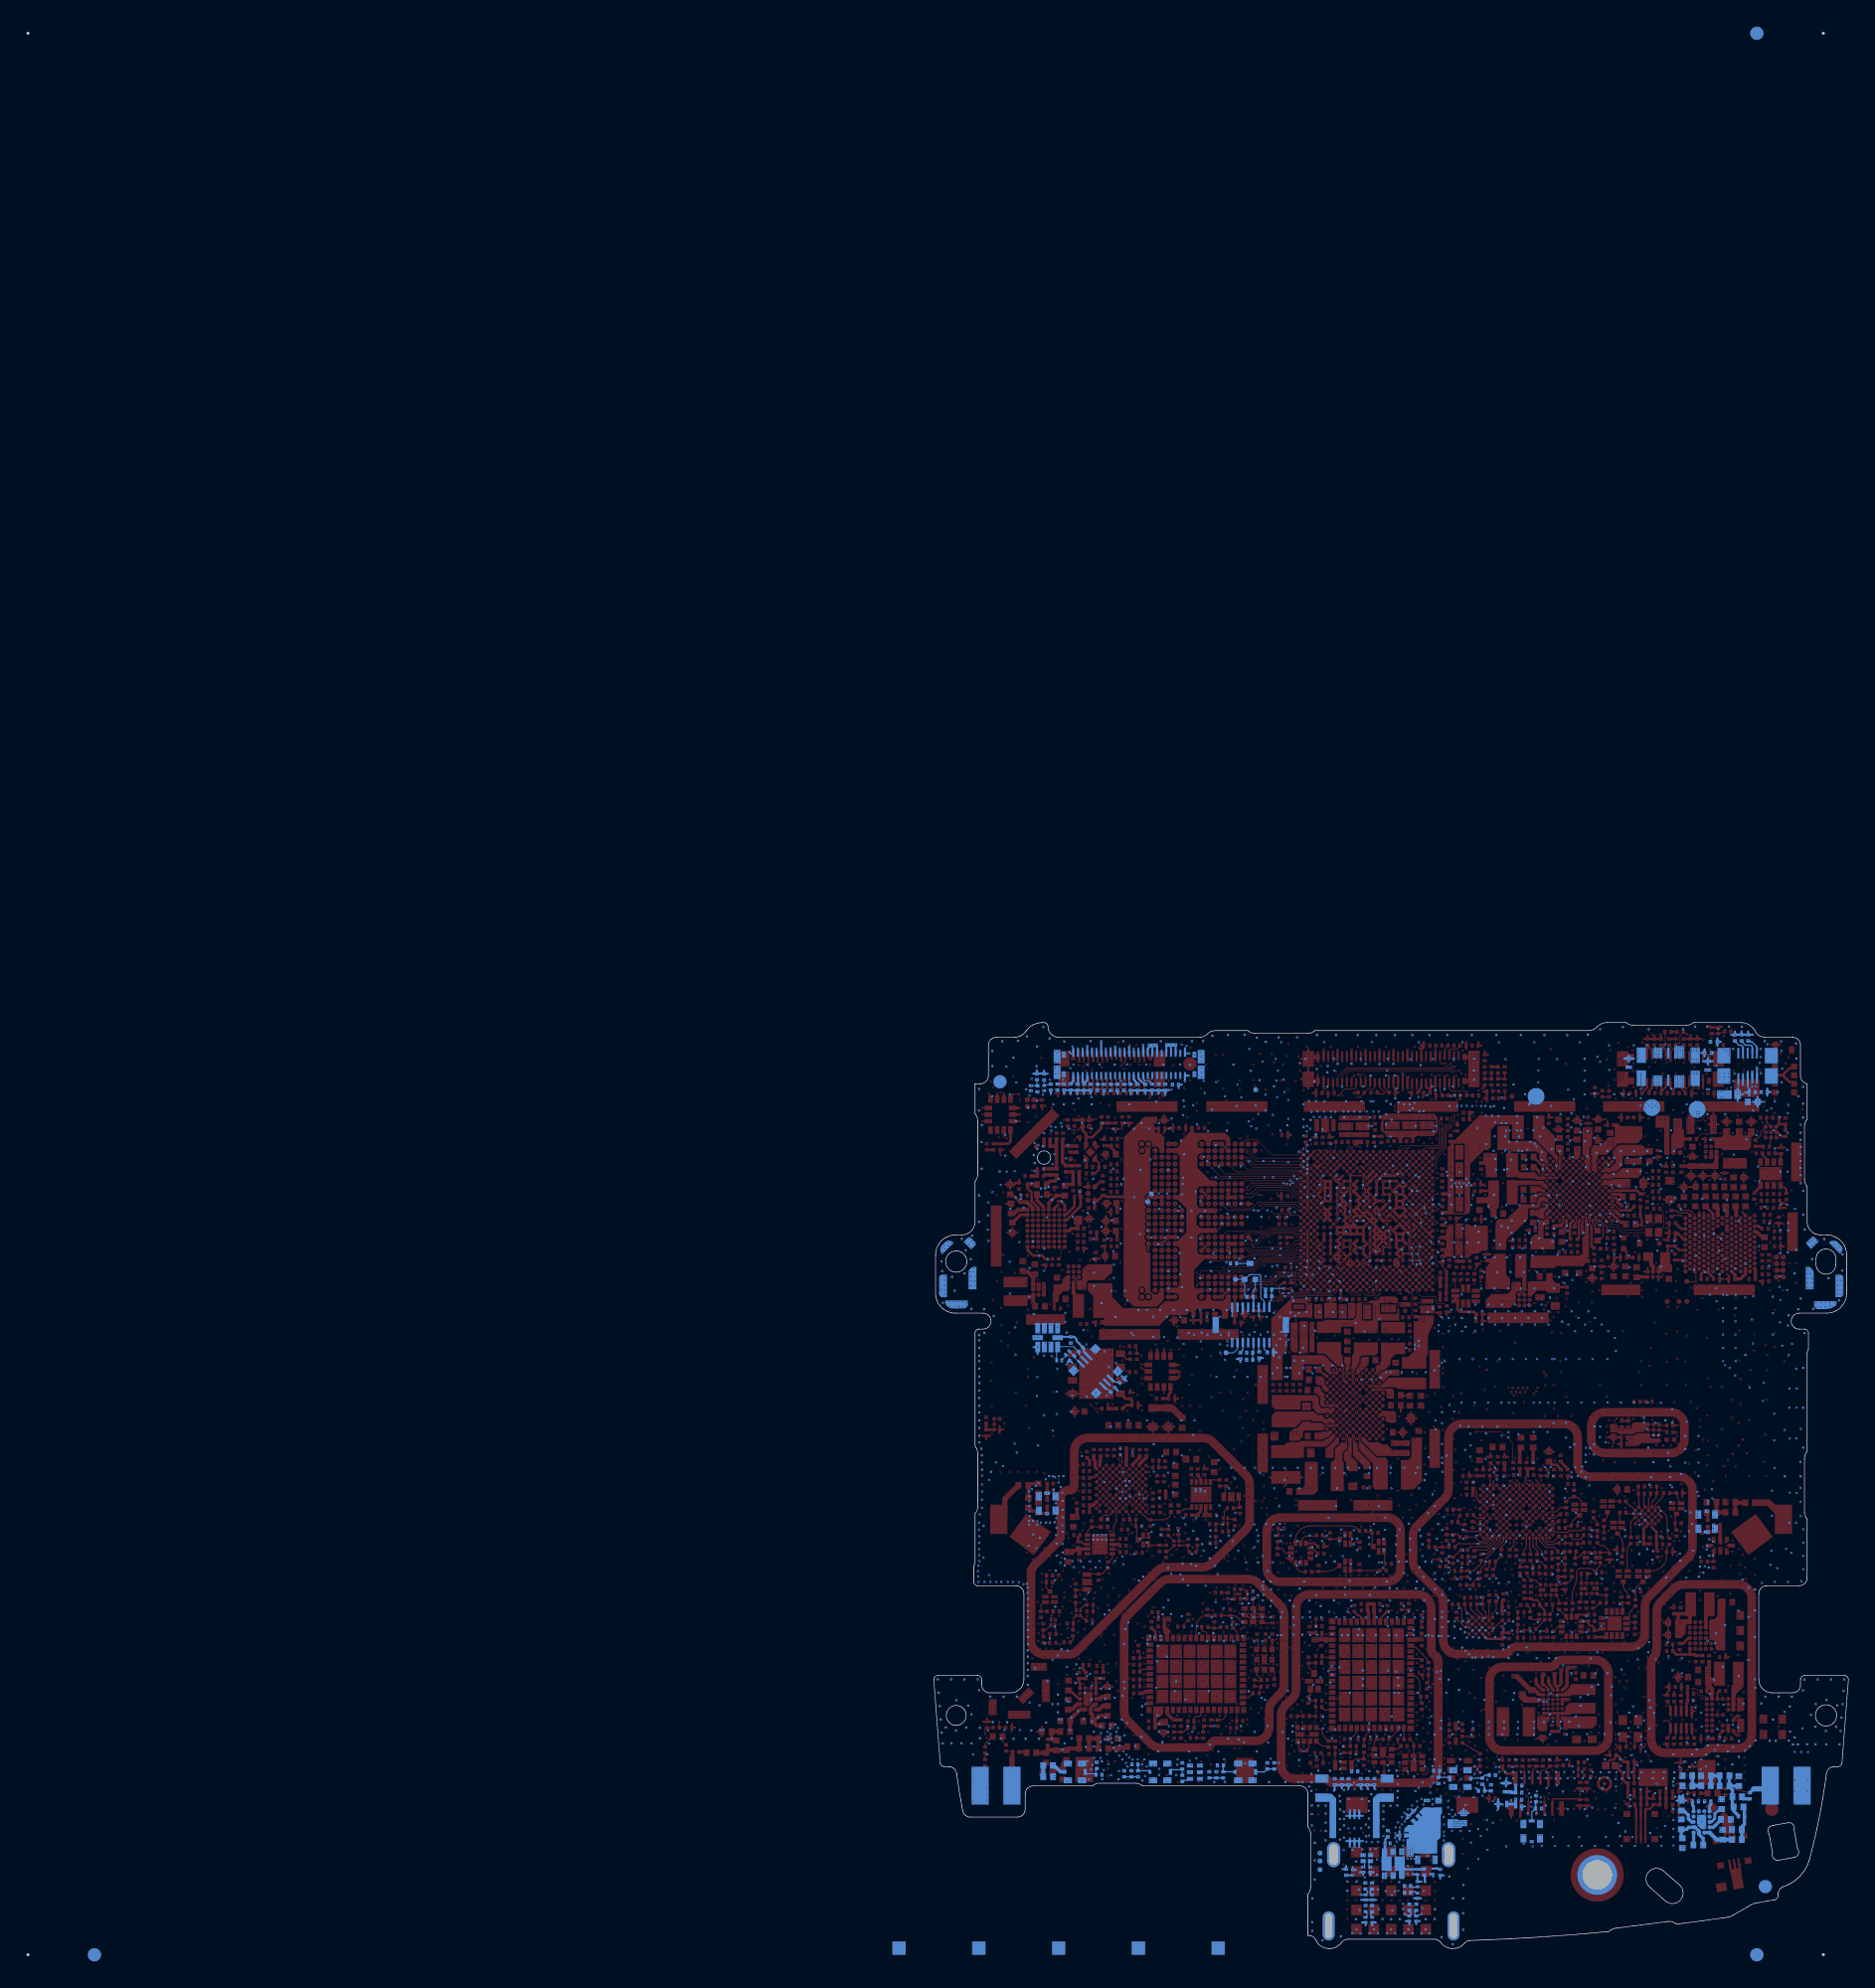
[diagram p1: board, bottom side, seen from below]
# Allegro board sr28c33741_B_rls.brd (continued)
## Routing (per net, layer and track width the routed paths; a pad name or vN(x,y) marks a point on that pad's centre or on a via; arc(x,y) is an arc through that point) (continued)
SIM_DATA: length 8.2
  LAYER_7 w0.045: v7(54.83,42.58) 55.3,43.05 55.3,43.89 58.24,46.83 59.3,46.83 59.38,46.91 v7(59.95,46.91)
  BOTTOM w0.075: J4250.5 55.41,42.87 55.13,42.59 54.84,42.59 VR4253.1
SIM_PRESENT: length 3.6
  BOTTOM w0.075: D4251.1 59.53,45.15 U4250.9 59.43,45.26 58.27,45.26 R4250.1 57.88,44.71 J4250.4
SLB: length 42.1
  LAYER_3 w0.045: v4(22.48,42.46) 22.62,42.6 26.7,42.6 27.02,42.28 27.72,42.28 27.95,42.05 32.96,42.05 33.14,41.88 33.7,41.88 34.33,41.25 34.79,41.25 35.09,40.95 35.54,40.95 36.24,40.25 37.76,40.25 38.01,40.01 v2(38.01,39.86) ; v4(20.71,58.39) 20.71,58.39 21.27,58.95 v2(21.45,58.95) 21.75,58.95 23.53,60.72 23.53,61.85 24.08,62.4 24.08,62.89 v2(25.28,64.09)
  LAYER_5 w0.045: v4(20.71,58.39) 20.71,58.38 20.78,58.31 20.78,58.28 22.25,56.82 22.25,55.35 22.87,54.73 22.87,52.1 22.96,52.01 22.96,51.55 23.13,51.38 23.13,50.51 22.86,50.24 22.86,49.88 23.03,49.7 23.03,47.5 22.86,47.33 22.86,43.66 22.4,43.21 22.4,42.54 v4(22.48,42.46)
SLEEP_CLK: length 69.3
  LAYER_5 w0.045: v6(22.4,39.38) 22.35,39.42 22.35,41.9 22.21,42.04 22.21,43.36 22.67,43.81 22.67,47.99 22.77,48.09 v4(22.77,48.35) 22.77,48.87 22.67,48.97 22.67,50.94 22.32,51.29 22.32,52.13 22.39,52.2 22.39,54.56 21.26,55.69 21.26,56.23 21.16,56.32 v4(21.16,56.68) 21.1,56.68 20.92,56.5 20.92,55.5 20.76,55.34 20.76,54.92 21.33,54.35 v6(21.45,54.35)
  LAYER_7 w0.045: v6(32.25,52.46) 31.81,52.9 26.59,52.9 25.47,54.02 23.01,54.02 22.68,54.35 v6(21.45,54.35) ; v6(54.61,36.07) 54.45,36.23 54.45,37.45 53.34,38.56 49.48,38.56 46.88,35.96 32.25,35.96 28.92,39.29 arc(28.75,39.4) 28.55,39.44 22.65,39.44 22.59,39.38 v6(22.4,39.38)
SPMI_CLK: length 34.7
  LAYER_3 w0.045: v2(37.97,39.37) 37.97,39.57 37.84,39.7 37.7,39.7 37.49,39.91 36.55,39.91 36.16,39.52 33.93,39.52 33.48,39.97 31.4,39.97 v4(31.12,40.25) ; 24.19,55.02 v4(24.27,54.94)
  LAYER_3 w0.05: 24.19,55.02 24.12,55.1 24.12,56.53 23.86,56.78 23.37,56.78 23.03,57.13 22.21,57.13 v2(22.16,57.18)
  LAYER_5 w0.045: v4(24.27,54.94) 24.33,54.89 24.33,53.27 v6(24.26,53.2) ; v6(32.69,52) 32.68,51.99 32.68,51.2 32.33,50.85 32.33,50.04 31.08,48.79 31.08,40.29 v4(31.12,40.25)
  LAYER_7 w0.045: v6(32.69,52) 32.66,52.04 32.21,52.04 31.6,52.64 25.86,52.64 25.43,53.08 24.4,53.08 24.27,53.2 v6(24.26,53.2)
SPMI_DATA: length 34.6
  LAYER_3 w0.045: v4(24.17,54.73) 24.17,54.74 24.02,54.89 24.02,56.48 ; v4(31.08,40.01) 31.22,40.01 31.36,39.87 33.44,39.87 33.89,39.42 36.2,39.42 36.59,39.81 37.45,39.81 37.72,39.54 v2(37.77,39.54)
  LAYER_3 w0.05: v2(21.98,57) 22.1,57 22.11,57.02 22.98,57.02 23.31,56.68 23.82,56.68 24.02,56.48
  LAYER_5 w0.045: v4(24.17,54.73) 24.17,53.36 24.1,53.29 24.1,52.99 v6(24.26,52.83) ; v6(32.52,51.81) 32.58,51.75 32.58,51.24 32.23,50.89 32.23,50.07 30.98,48.83 30.98,40.35 30.95,40.32 30.95,40.14 v4(31.08,40.01)
  LAYER_7 w0.045: v6(24.26,52.83) 24.4,52.97 25.39,52.97 25.83,52.53 31.56,52.53 32.15,51.94 32.39,51.94 v6(32.52,51.81)
SSC_I2C1_SCL: length 143.8
  TOP w0.05: v6(12.31,52.16) 12.27,52.12 U6250.T16
  TOP w0.075: J5502.25 11.63,67.69 11.82,67.88 v2(11.82,67.92)
  LAYER_2 w0.045: v2(63.47,59.06) 63.55,59.14 64.6,59.14 v2(64.68,59.06)
  LAYER_3 w0.045: v4(11.64,64.96) 11.64,65.08 11.98,65.42 11.98,65.44 11.98,65.44 11.98,65.99 11.92,66.05 11.92,67.81 v2(11.82,67.92) 11.6,67.92 11.5,67.82 11.23,67.82 11,68.05 10.57,68.05 7.24,64.72 5.86,64.72 v2(5.65,64.51) ; v6(12.31,52.16) 12.46,52.01 13.59,52.01 14.82,50.79 14.82,46.64 16.19,45.27 25.15,45.27 25.41,45.54 31.56,45.54 32.22,46.19 33.12,46.19 33.76,46.83 33.76,47.68 34.09,48.01 34.09,49.2 34.69,49.81 34.74,49.92 v2(34.7,50.02) ; v2(63.83,39.83) 64.67,40.67 64.67,44.17 63.3,45.54 63.3,48.36 64.81,49.87 64.81,57.99 64.62,58.18 64.62,59 64.67,59.05 64.67,59.06 v2(64.68,59.06) ; v2(63.47,59.06) 63.45,59.06 63.38,59.13 62.91,59.13 61.17,60.86 59.61,60.86 59.06,60.31 57.45,60.31 56.09,61.67 54.21,61.67 54.14,61.74 v4(54.08,61.74)
  LAYER_5 w0.045: v4(11.64,64.96) 11.79,64.81 15.76,64.81 16.13,64.44 16.68,64.44 v6(16.77,64.35) ; v4(54.08,61.74) 54.11,61.7 54.11,58.71 54.14,58.69 54.14,58.3 v6(54.19,58.25)
  LAYER_6 w0.045: v6(21,61.05) 21.38,61.05 v6(21.39,61.04)
  LAYER_7 w0.045: v6(21,61.05) 21.07,61.12 21.07,63.73 20.26,64.54 18.76,64.54 18.5,64.28 18.25,64.28 18.05,64.48 v6(18.04,64.48) 18.04,64.49 16.91,64.49 v6(16.77,64.35) ; v6(12.31,52.16) 12.31,52.97 12.79,53.45 13.53,53.45 16.76,56.68 17.86,56.68 19.55,58.37 20.19,58.37 21.27,59.45 21.27,60.92 v6(21.39,61.04) 23.06,62.71 24.12,62.71 24.5,62.33 33.66,62.33 34.76,63.42 40.57,63.42 41.91,62.09 41.91,61.25 43.14,60.02 48.68,60.02 50.42,58.27 53.71,58.27 53.85,58.41 54.03,58.41 v6(54.19,58.25)
SSC_I2C1_SDA: length 143.9
  TOP w0.075: J5502.27 11.28,67.9 v2(11.36,67.98)
  LAYER_2 w0.045: v1(11.61,52.17) v6(11.71,52.39) ; v2(64.69,59.31) 64.61,59.23 63.51,59.23 v2(63.44,59.31)
  LAYER_3 w0.045: v2(5.64,64.92) 5.74,64.82 7.2,64.82 10.54,68.16 11.18,68.16 v2(11.36,67.98) 11.47,68.09 11.9,68.09 12.02,67.97 12.02,66.09 12.08,66.03 12.08,65.4 12.07,65.4 12.07,65.38 11.94,65.25 v4(11.94,64.97) ; v2(64.23,39.83) 64.23,40.1 64.76,40.63 64.76,44.21 63.4,45.57 63.4,48.32 64.91,49.83 64.91,58.03 64.71,58.23 64.71,58.86 64.84,58.99 64.84,59.16 v2(64.69,59.31) ; v6(11.71,52.39) 11.82,52.5 12.27,52.5 12.65,52.12 13.62,52.12 14.92,50.82 14.92,46.68 16.23,45.37 25.11,45.37 25.37,45.63 31.52,45.63 32.18,46.29 33.08,46.29 33.66,46.87 33.66,47.72 33.99,48.05 33.99,49.34 v2(34.43,49.78) ; v2(63.44,59.31) 63.44,59.29 63.38,59.23 62.94,59.23 61.21,60.96 59.57,60.96 59.02,60.41 57.49,60.41 56.13,61.77 54.3,61.77 54.17,61.9 53.91,61.9 v4(53.88,61.87)
  LAYER_5 w0.045: v6(53.96,58.58) 54.02,58.64 54.02,61.55 53.92,61.65 53.92,61.83 v4(53.88,61.87) ; v4(11.94,64.97) 11.94,64.91 15.79,64.91 16.17,64.53 16.72,64.53 v6(16.78,64.59)
  LAYER_7 w0.045: v6(16.78,64.59) 16.87,64.59 16.92,64.64 18.29,64.64 v6(18.45,64.48) 18.6,64.64 20.31,64.64 21.17,63.77 21.17,61.27 ; 21.17,61.27 21.17,59.49 20.15,58.47 19.5,58.47 17.81,56.77 16.71,56.77 13.48,53.55 12.73,53.55 11.71,52.53 v6(11.71,52.39) ; 21.17,61.27 21.48,61.27 23.02,62.81 24.17,62.81 24.56,62.42 33.63,62.42 34.73,63.52 40.61,63.52 42,62.12 42,61.29 43.18,60.11 48.73,60.11 50.47,58.37 53.67,58.37 53.88,58.58 v6(53.96,58.58)
SSC_I2C2_SCL: length 58.5
  TOP w0.075: J5502.17 13.06,67.2 13.06,67.53 C5514.2 13.56,68.03 13.72,68.03 13.78,68.09 13.78,68.92 v2(13.8,68.94)
  LAYER_2 w0.045: v2(12.08,54.42) 12.07,54.42 11.87,54.62 11.87,56.96 v2(12.01,57.1) ; v2(33.72,48.01) 33.72,48.02 33.73,48.03 33.89,48.03 34.08,48.22 34.08,48.74 35.5,50.16 36.06,50.16 36.19,50.29 v1(36.19,50.49)
  LAYER_3 w0.045: v2(13.8,68.94) 13.55,68.69 12.33,68.69 12.21,68.57 10.81,68.57 7.22,64.98 v4(6.78,64.98) ; v4(12.18,61.03) 12.19,61.03 12.2,61.02 12.2,59.86 12.03,59.69 12.03,57.12 v2(12.01,57.1) ; v2(12.08,54.42) 12.19,54.31 12.19,53.74 13.52,52.41 13.75,52.41 15.21,50.95 15.21,46.79 16.35,45.65 23.03,45.65 23.3,45.92 23.65,45.92 23.84,45.73 31.47,45.73 32.36,46.62 33.27,46.62 33.56,46.91 33.56,47.76 33.72,47.92 v2(33.72,48.01)
  LAYER_5 w0.045: v4(6.78,64.98) 6.78,64.8 9.84,61.74 10.37,61.74 11.02,61.09 12.13,61.09 12.16,61.05 12.16,61.03 v4(12.18,61.03)
SSC_I2C2_SDA: length 57.1
  TOP w0.075: v2(12.09,68.73) 12.19,68.83 12.32,68.83 R1052.1 12.43,68.86 12.68,68.61 12.68,68.11 12.75,68.04 12.89,68.04 C5503.2 12.98,67.93 12.71,67.67 12.71,67.2 J5502.19
  LAYER_2 w0.045: v2(12.19,56.96) 12.19,56.89 11.96,56.66 11.96,54.73 12.08,54.62 v2(12.21,54.62) ; v2(33.83,48.75) 33.98,48.75 33.98,48.78 35.5,50.3 35.58,50.3 35.94,50.66 v1(35.94,50.74)
  LAYER_3 w0.045: v4(6.92,65.17) 7.26,65.17 10.76,68.67 12.03,68.67 v2(12.09,68.73) ; v2(33.83,48.75) 33.85,48.73 33.85,48.26 33.75,48.17 33.65,48.17 33.56,48.08 33.56,47.9 33.46,47.8 33.46,46.95 33.23,46.72 32.32,46.72 31.42,45.83 23.88,45.83 23.69,46.02 23.25,46.02 22.98,45.75 16.38,45.75 15.31,46.83 15.31,50.99 13.79,52.5 13.57,52.5 12.29,53.78 12.29,54.54 v2(12.21,54.62) ; v4(12.43,61.12) 12.43,61.04 12.3,60.91 12.3,59.82 12.13,59.65 12.13,57.21 12.19,57.15 v2(12.19,56.96)
  LAYER_5 w0.045: v4(12.43,61.12) 12.36,61.19 11.06,61.19 10.41,61.84 9.88,61.84 6.96,64.76 6.96,65.13 v4(6.92,65.17)
SSC_UART1_RX: length 36.8
  TOP w0.05: U1001.AD42 35.47,49.4 35.62,49.25 v2(35.75,49.25)
  LAYER_3 w0.045: v2(35.75,49.25) 35.8,49.2 35.8,48.86 35.94,48.72 35.94,47.34 37.04,46.24 37.04,45.74 37.19,45.59 38.71,45.59 39.81,44.49 42.9,44.49 43.32,44.08 45.88,44.08 46.1,44.3 47.29,44.3 47.77,44.77 50.97,44.77 51.35,45.16 53.06,45.16 53.59,45.69 55.58,45.69 55.64,45.62 55.83,45.62 v4(55.99,45.78)
  LAYER_5 w0.045: v4(55.99,45.78) 55.81,45.6 55.81,39.32 55.23,38.75 54.98,38.75 54.32,38.09 54.32,36.96 55.15,36.13 55.15,35.77 55.26,35.66 55.26,35.43 v4(55.3,35.39)
SSC_UART1_TX: length 35.7
  LAYER_3 w0.045: v4(55.71,45.78) 53.55,45.78 53.02,45.25 51.31,45.25 50.93,44.87 47.73,44.87 47.25,44.4 46.06,44.4 45.84,44.17 43.36,44.17 42.94,44.59 39.85,44.59 38.64,45.79 38.31,45.79 38.1,46.01 37.4,46.01 36.03,47.38 36.03,48.79 35.92,48.9 35.92,49.35 35.72,49.55 v2(35.72,49.98)
  LAYER_5 w0.045: v4(55.71,45.78) 55.71,39.36 55.19,38.84 54.94,38.84 54.22,38.13 54.22,36.92 55.04,36.1 55.04,35.64 v4(55.1,35.58)
SSRX1_DM: length 1.2
  TOP w0.088: U500.12 32.92,4.18 v7(32.47,4.18)
  BOTTOM w0.088: v7(32.47,4.18) 32.57,4.28 32.85,4.28 C512.1
SSRX1_DP: length 1.5
  TOP w0.088: U500.11 31.79,4.65 v7(32.41,4.65)
  BOTTOM w0.088: C509.1 32.82,4.61 32.45,4.61 v7(32.41,4.65)
SSRX2_DM: length 1.1
  TOP w0.088: U500.19 35.81,2.78 v7(35.81,2.34)
  BOTTOM w0.088: C514.1 35.91,2.67 35.91,2.44 v7(35.81,2.34)
SSRX2_DP: length 1.4
  TOP w0.088: U500.20 36.98,2.83 36.38,2.34 v7(36.37,2.34)
  BOTTOM w0.088: D502.2 36.21,2.44 36.21,2.67 C513.1
SSTX1_DM: length 0.9
  BOTTOM w0.088: C506.1 32.91,2.76 32.91,2.55 D514.2 33.08,2.5 33.27,2.5 v7(33.37,2.6)
SSTX1_DP: length 1
  BOTTOM w0.088: v7(32.09,2.6) 32.42,2.46 32.48,2.46 D507.2 32.6,2.54 32.6,2.77 C505.1
SSTX2_DM: length 0.6
  BOTTOM w0.088: v7(35.8,4.03) D504.2 35.96,4.2 35.96,4.33 C508.1
SSTX2_DP: length 0.9
  BOTTOM w0.088: C507.1 36.16,4.31 36.16,4.18 D501.2 v7(36.68,4.04)
ST21_CDMPN: length 5.3
  TOP w0.2: v2(59.43,55.94) 59.73,55.65 U4100.A3
  TOP w0.25: C4167.1 58.05,59.88 58.05,59.88 C4166.1
  LAYER_3 w0.2: v2(58.59,59.88) 59.15,59.32 59.15,56.14 59.35,55.94 v2(59.43,55.94)
ST21_CDMPP: length 6.5
  TOP w0.2: U4100.A1 58.93,55.92 59.2,56.2 59.42,56.2 v2(59.44,56.21)
  TOP w0.25: C4157.1 60.49,60.34 60.49,60.85 C4156.1
  LAYER_3 w0.2: v2(59.44,56.21) 59.44,59.99 59.85,60.4 v2(60.47,60.4)
ST21_RXN: length 2.8
  TOP w0.2: C4165.1 57.74,55.83 58.8,54.77 U4100.C1
  TOP w0.25: C4169.1 57.8,56.58 C4165.1
ST21_RXP: length 7.4
  TOP w0.2: U4100.B1 58.85,55.17 58.2,55.82 v2(58.2,56.52)
  LAYER_3 w0.15: v2(58.2,56.52) 58.2,56.38 59.2,55.38 59.74,55.38 61.9,57.54 v2(61.9,58.07)
ST21_TX1: length 2.9
  TOP w0.2: U4100.A6 60.93,55.72 61.43,56.22 61.43,56.87 61.72,57.16 TP_NFC_ST21_TX1.1
  TOP w0.25: TP_NFC_ST21_TX1.1 L4150.1
ST21_TX2: length 1.9
  TOP w0.25: U4100.A4 60.13,56.06 TP_NFC_ST21_TX2.1 L4160.1
TER_MIC_BIAS: length 51.4
  TOP w0.15: MK4520.1 18.25,13.84 17.89,14.2 17.65,14.2 17.53,14.31 17.53,14.49 VR4521.2
  TOP w0.2: C4520.2 v2(16.57,13.44) C4523.2 16.62,14.04 16.88,14.04 17.38,14.54 VR4521.2
  LAYER_3 w0.15: v2(8.44,53.86) 8.44,53.37 8.25,53.17 7.06,53.17 6.46,52.57 6.32,52.57 6,52.25 v4(6,52.14)
  LAYER_3 w0.175: v4(14.21,14.43) 14.23,14.43 15.55,13.11 16.24,13.11 v2(16.57,13.44)
  LAYER_5 w0.15: v4(6,52.14) 5.61,51.75 5.61,49.15 6.15,48.61 6.15,36.46 8.52,34.09 8.52,20.13 14.21,14.44 v4(14.21,14.43)
TER_MIC_DM: length 50.1
  TOP w0.175: v4(4.76,56.02) 4.96,56.02 C6296.1
  TOP w0.2: C4521.1 v2(16.11,11.42)
  LAYER_3 w0.175: v4(14.21,14.11) 14.21,13.77 15.8,12.17 15.9,12.17 v2(16.1,11.98)
  LAYER_5 w0.15: v4(4.76,56.02) 4.93,55.85 4.93,54.88 5.7,54.11 5.7,52.18 5.38,51.87 5.38,49.09 5.95,48.53 5.95,36.38 8.32,34.01 8.32,20.05 13.97,14.39 13.97,14.34 v4(14.21,14.11)
TER_MIC_DP: length 52.8
  TOP w0.175: C6295.1 v4(4.71,55.7)
  TOP w0.2: C4522.2 v2(16.57,11.92) VR4520.2 16.7,12.42 16.95,12.67 16.95,13.16 MK4520.2
  LAYER_3 w0.175: v2(16.57,11.92) 16.38,12.12 16.38,12.52 16.03,12.87 15.45,12.87 v4(14.44,13.88)
  LAYER_5 w0.15: v4(14.44,13.88) 14.13,13.88 13.75,14.26 13.75,14.34 8.12,19.96 8.12,33.92 5.75,36.3 5.75,48.44 5.16,49.03 5.16,51.94 5.5,52.28 5.5,54.03 4.73,54.8 4.73,54.8 4.71,54.82 v4(4.71,55.7)
TOUCH_INT_N_FL: length 2.1
  LAYER_7 w0.045: v7(55.91,64.96) 55.82,65.05 55.54,65.05 55.19,65.39 v7(54.79,65.39)
  BOTTOM w0.05: J5300.21 v7(54.79,65.39)
  BOTTOM w0.075: E5303.2 C5319.2
TRX_B13_50R: length 7.3
  TOP w0.088: C7267.2 v4(46.65,26.3)
  LAYER_5 w0.047: v4(45.69,19.83) 45.85,19.99 arc(46.06,20.23) 46.24,20.5 arc(46.6,21.32) 46.73,22.2 46.73,26.11 arc(46.7,26.21) v4(46.65,26.3)
TRX_B25_50R: length 1.4
  TOP w0.088: R7316.1 32.68,15.45 L7303.2 32.68,15.21 32.7,15.2 FL7300.6
TRX_B25_B34_50R: length 0.9
  TOP w0.088: R7315.2 33.43,16.58 U7150.51
TRX_B28_50R: length 0.9
  TOP w0.088: L7239.1 45.09,18.89 U7100.55
TRX_B34_A_50R: length 1.4
  TOP w0.088: FL7310.3 33.89,14.99 R7314.2 33.89,15.47 R7315.1
TRX_B34_B39_1_50R: length 6.4
  TOP w0.088: L7313.2 34.92,13.99 FL7310.6
  LAYER_5 w0.047: v4(34.89,13.32) 34.89,13.46 arc(34.64,14.68) 33.95,15.71 32.48,17.19 arc(32.23,17.56) v4(32.15,17.99)
TRX_B39_50R: length 1.2
  TOP w0.088: U7150.52 33.99,16.58 33.99,16.29 L7318.2
TRX_B39_A_50R: length 1.3
  TOP w0.088: L7318.1 35.47,15.74 L7317.2 35.65,15.57 FL7310.1
TRX_B40_50R: length 0.9
  TOP w0.088: C7355.2 39.39,17.94 U7150.4
TRX_B40_FLTIN_50R: length 1.5
  TOP w0.088: C7351.2 40.57,21.48 L7352.2 40.59,21.16 40.17,20.74 FL7350.1
TRX_B40_FLTOUT_50R: length 0.7
  TOP w0.088: C7353.1 40.45,19.06 FL7350.4
TRX_B40_FLTOUT_MAT_50R: length 1.1
  TOP w0.088: C7355.1 L7354.2 40.41,18.65 C7353.2
TS_I2C_SCL: length 51.7
  TOP w0.05: R1036.1 v2(56.11,62.53)
  TOP w0.1: 53.3,67.16 v4(53.3,66.73)
  LAYER_3 w0.045: v2(56.11,62.53) 55.98,62.4 55.65,62.4 55.59,62.45 54.73,62.45 54.66,62.39 54.3,62.39 v4(54.16,62.53)
  LAYER_5 w0.045: v6(27.95,62.74) 27.91,62.74 26.08,60.91 26.08,59.31 26.59,58.8 30.88,58.8 30.93,58.84 31.1,58.84 31.13,58.81 31.57,58.81 31.69,58.68 31.69,58.56 v4(31.76,58.49) ; v4(53.3,66.73) 53.47,66.56 53.66,66.56 54.41,65.81 v7(54.41,64.57) 54.47,64.51 54.47,63.33 54.23,63.09 54.23,62.6 v4(54.16,62.53) 54.46,62.23 54.46,58.83 54.41,58.78 54.41,58.62 v6(54.55,58.48)
  LAYER_7 w0.045: v6(27.95,62.74) 28.04,62.65 28.25,62.65 28.26,62.66 33.3,62.66 34.61,63.96 40.99,63.96 44.01,60.94 47.34,60.94 48.07,60.2 48.79,60.2 50.24,58.76 53.72,58.76 53.8,58.84 54.18,58.84 v6(54.55,58.48)
TS_I2C_SDA: length 51
  TOP w0.1: J5501.25 v4(53.65,66.73)
  LAYER_3 w0.045: v4(54.6,62.55) 55.71,62.55 v2(55.72,62.56)
  LAYER_5 w0.045: v4(53.65,66.73) 54.57,65.81 v6(54.57,65.02) 54.57,63.29 54.33,63.05 54.33,62.82 v4(54.6,62.55) 54.55,62.51 54.55,58.73 v6(54.57,58.71) ; v4(31.3,58.4) 31.06,58.4 30.76,58.7 26.55,58.7 25.98,59.27 25.98,60.95 27.75,62.71 27.75,62.78 27.88,62.91 28.09,62.91 v6(28.19,62.81)
  LAYER_7 w0.045: v7(55.47,64.53) 54.98,65.02 v6(54.57,65.02) ; v6(54.57,58.71) 54.34,58.94 53.77,58.94 53.68,58.86 50.28,58.86 48.83,60.3 48.11,60.3 47.38,61.04 44.05,61.04 41.03,64.06 34.56,64.06 33.26,62.75 28.21,62.75 28.19,62.77 v6(28.19,62.81)
TS_INT_N: length 38.8
  TOP w0.05: v4(58.99,62.31) R5301.1
  LAYER_3 w0.045: v4(58.99,62.31) 58.99,62.62 58.33,63.28 57.63,63.28 57.36,63.55 57.36,64 v6(57.19,64.17)
  LAYER_5 w0.045: v4(58.99,62.31) 58.95,62.27 58.95,61.99 58.22,61.27 58.22,57.45 v6(58.36,57.32)
  LAYER_7 w0.045: v6(58.36,57.32) 55.28,57.32 55.15,57.19 49.97,57.19 48.51,58.65 41.7,58.65 40.07,57.01 37.76,57.01 37.07,57.7 37.07,58.56 36.9,58.72 36.66,58.72 36.48,58.55 32.64,58.55 32.38,58.8 31.88,58.8 v6(31.79,58.9) ; v6(57.19,64.17) 57.13,64.23 56.77,64.23 v7(56.49,64.52)
TS_RST_N: length 45.2
  LAYER_5 w0.045: v6(53.57,58.55) 53.33,58.79 53.33,62.58 53.69,62.93 53.69,64.26 52.91,65.04 v7(52.42,65.04) ; v6(58.76,57.36) 58.76,58.18 v6(58.58,58.36)
  LAYER_7 w0.045: v6(53.57,58.55) 53.67,58.55 53.86,58.74 54.08,58.74 54.34,58.49 54.34,58.44 54.53,58.25 58.45,58.25 58.56,58.36 v6(58.58,58.36) ; v6(31.5,58.64) 31.55,58.69 32.36,58.69 32.6,58.45 36.52,58.45 36.7,58.63 36.84,58.63 36.97,58.49 36.97,57.67 37.72,56.91 40.1,56.91 41.74,58.55 48.47,58.55 49.92,57.09 55.18,57.09 55.31,57.23 58.18,57.23 58.25,57.16 58.56,57.16 v6(58.76,57.36)
  BOTTOM w0.079: J5300.31 52.99,65.6 52.99,65.34 52.9,65.25 52.61,65.25 C5318.2
TS_SUB_INT_N: length 49.1
  TOP w0.05: v2(42.61,48.75) 42.61,48.84 42.45,48.99 40.94,48.99 40.83,49.1 40.05,49.1 40,49.05 39.86,49.05 39.83,49.09 38.8,49.09 38.44,49.45 U1001.M42
  TOP w0.075: v4(54.04,67.98) 54,67.94 J5501.23 ; C5502.2 v2(58.51,64.33)
  LAYER_3 w0.045: v2(58.51,64.33) 58.07,63.89 v4(57.86,63.89) ; v4(57.6,48.82) 57.51,48.82 56.5,49.83 54.72,49.83 52.13,47.24 50.33,47.24 50.03,46.94 46.91,46.94 46.41,46.44 46.27,46.44 46.18,46.53 46.18,46.78 45.95,47.01 45.28,47.01 44.06,48.23 43.06,48.23 42.61,48.68 v2(42.61,48.75)
  LAYER_5 w0.045: v4(54.04,67.98) 54.11,68.05 58.14,68.05 58.32,67.87 58.32,67.23 57.53,66.44 57.53,64.36 57.73,64.16 57.73,64.02 v4(57.86,63.89) 57.91,63.84 57.91,63.58 57.84,63.52 57.84,56.26 57.5,55.92 57.5,48.91 v4(57.6,48.82)
TS_SUB_RST_N: length 39
  TOP w0.075: v4(54.72,66.38) 54.38,66.72 54.38,67.13 J5501.21
  LAYER_2 w0.1: v1(39.21,50.48) v3(39.39,50.52)
  LAYER_3 w0.045: v4(58.96,60.86) 58.94,60.84 58.71,60.84 58.54,61.01 58.54,62.48 58.22,62.8 56.41,62.8 56.12,63.08 54.6,63.08 v4(54.5,62.98)
  LAYER_4 w0.045: v3(39.39,50.52) v6(39.85,50.52)
  LAYER_5 w0.045: v6(59.42,56.3) 59.42,56.54 59.55,56.67 59.55,56.81 59.35,57 59.35,60.36 58.96,60.75 v4(58.96,60.86) ; v4(54.72,66.38) 54.67,66.33 54.67,65.18 54.74,65.11 54.74,64.86 54.67,64.78 54.67,63.15 v4(54.5,62.98)
  LAYER_7 w0.045: v6(39.85,50.52) 40.22,50.15 43.72,50.15 44.07,49.8 49.05,49.8 50.41,51.16 52.5,51.16 54.91,53.57 54.91,53.58 54.92,53.59 55.37,53.59 55.97,54.18 55.97,54.34 57.17,55.55 57.26,55.54 58.12,56.4 59.32,56.4 v6(59.42,56.3)
TX_GSMHB_50R: length 11.5
  TOP w0.088: L7132.2 v2(50.2,16.28) 49.99,16.28 49.68,16.59 L7131.2
  LAYER_3 w0.045: v2(40.47,13.96) 44.59,13.96 arc(47.63,14.56) v2(50.2,16.28)
TX_GSMHB_50R_1: length 9.3
  TOP w0.088: FL7150.3 39.5,14.51 v2(39.67,14.68)
  LAYER_3 w0.045: v2(32.97,16.99) 32.97,16.56 arc(33.09,16.26) 33.39,16.14 38.96,16.14 arc(39.36,15.98) 39.53,15.58 39.53,15.02 arc(39.56,14.84) v2(39.67,14.68)
TX_MB3_FLTIN_50R: length 1.6
  TOP w0.088: U7150.31 33.45,25.06 33.05,25.45 L7166.2 33.6,25.48 C7165.2
TX_PA_OUT_GSMHB_50R: length 1.8
  TOP w0.088: U7100.8 48.69,17.95 48.69,17.61 arc(48.73,17.49) 48.85,17.45 49.01,17.45 arc(49.15,17.39) 49.21,17.25 L7130.2 L7131.1
TXDUP_B25_50R: length 6.4
  LAYER_5 w0.047: v4(33.47,13.55) 33.47,13.75 arc(33.16,15.28) 32.29,16.59 arc(32.27,16.61) 32.24,16.64 arc(31.86,17.21) 31.73,17.88 v4(31.73,19.5)
U6290_SW: length 1.4
  TOP w0.3: U6290.B1 14.69,51.27 14.84,51.42 14.84,52.03 15.05,52.03
UFS_L0_RXN: length 12.6
  LAYER_3 w0.045: v2(40.18,53.94) 40.18,53.97 40.23,54.02 40.36,54.02 40.43,53.95 41.75,53.95 arc(41.76,53.95) 41.77,53.94 41.94,53.77 42.8,53.77 43,53.98 49.23,53.98 arc(49.41,53.94) 49.56,53.84 arc(49.79,53.69) 50.07,53.63 arc(50.32,53.69) 50.54,53.83 50.58,53.88 arc(50.63,53.92) 50.68,53.96 arc(50.69,53.97) 50.69,53.97 arc(50.98,54.13) 51.3,54.21 51.76,54.21 51.85,54.12 51.85,54.01 51.77,53.93 51.7,53.93 v2(51.63,54)
UFS_L0_RXP: length 12.7
  LAYER_3 w0.045: v2(39.93,54.19) 39.97,54.19 40.04,54.12 40.4,54.12 40.47,54.05 41.8,54.05 41.98,53.87 42.76,53.87 42.96,54.07 49.24,54.07 arc(49.45,54.03) 49.62,53.91 arc(49.83,53.78) 50.07,53.73 arc(50.29,53.77) 50.48,53.9 50.52,53.94 arc(50.92,54.21) 51.41,54.31 51.81,54.31 v2(52.05,54.07)
UFS_L0_TXN: length 12.7
  LAYER_3 w0.045: v2(51.71,55.06) 51.79,55.14 51.85,55.14 51.89,55.09 51.89,54.88 51.8,54.79 43.71,54.79 43.66,54.73 41.12,54.73 40.7,55.16 39.99,55.16 39.97,55.18 v2(39.93,55.18)
UFS_L0_TXP: length 12.6
  LAYER_3 w0.045: v2(40.16,54.94) 40.28,55.06 40.66,55.06 41.08,54.64 43.69,54.64 43.75,54.7 51.86,54.7 51.99,54.82 51.99,55.08 52.05,55.14 52.15,55.14 v2(52.19,55.1)
UFS_REF_CLK: length 10.2
  LAYER_3 w0.045: v2(40.23,54.49) 40.64,54.49 40.79,54.34 41.9,54.34 42.11,54.13 42.46,54.13 42.69,54.36 43.99,54.36 44.06,54.43 49.71,54.43 v2(50.06,54.08)
UFS_RESET: length 2.3
  LAYER_3 w0.045: v2(42.3,55.04) 42.26,55 41.59,55 41.09,55.5 40.21,55.5 v2(40.19,55.52)
UFS_RST_R: length 7.5
  LAYER_3 w0.045: v2(50.13,55.11) 50.02,55.22 43.46,55.22 43.28,55.04 v2(42.8,55.04)
UIM1_CLK: length 38.4
  LAYER_3 w0.045: v4(52.09,44.72) 52.16,44.8 53.92,44.8 v2(53.95,44.82) 54.1,44.98 54.89,44.98 54.94,45.03 58.3,45.03 58.82,45.55 59.99,45.55 v7(60.06,45.48) ; v2(31.97,52.79) 32.02,52.85 32.28,52.85 32.39,52.95 32.62,52.95 32.72,52.86 33.09,52.86 33.15,52.8 33.32,52.8 33.88,53.36 34.12,53.36 v6(34.43,53.05)
  LAYER_5 w0.045: v4(52.09,44.72) 52.09,52.46 v6(52.03,52.52)
  LAYER_7 w0.045: v6(34.43,53.05) 34.72,53.34 34.72,53.34 34.81,53.43 41.61,53.43 41.78,53.26 42.18,53.26 42.48,52.95 44.02,52.95 45.75,51.23 48.75,51.23 50.13,52.61 51.73,52.61 51.82,52.52 v6(52.03,52.52)
UIM1_DATA: length 40.4
  TOP w0.075: v2(53.63,45.23) 53.51,45.11 R4213.1
  LAYER_2 w0.045: v6(34.66,53.5) 34.66,53.23 34.46,53.04 33.36,53.04 33.28,53.12 33.14,53.12 32.89,52.87 32.71,52.87 32.54,53.04 32.41,53.04 32.28,53.17 32.15,53.17 32.11,53.13 31.58,53.13 31.44,53 v1(31.32,53)
  LAYER_3 w0.045: v4(51.84,44.74) 51.99,44.89 53.29,44.89 v2(53.63,45.23) 53.78,45.07 54.85,45.07 54.9,45.12 58.26,45.12 58.78,45.64 60.21,45.64 v7(60.37,45.48)
  LAYER_5 w0.045: v4(51.84,44.74) 51.99,44.89 51.99,52.33 51.87,52.45 v6(51.87,52.7)
  LAYER_7 w0.045: v6(51.87,52.7) 50.09,52.7 48.71,51.32 45.82,51.32 44.09,53.05 42.52,53.05 42.22,53.35 41.83,53.35 41.64,53.54 34.69,53.54 v6(34.66,53.5)
UIM1_POWER: length 7.9
  LAYER_3 w0.2: v4(57.99,53.19) 58.17,53.19 58.65,53.67 59.25,53.67 v2(59.32,53.6)
  LAYER_5 w0.2: v4(57.99,53.19) 57.99,50.12 58.07,50.04 58.07,47.9 57.74,47.57 v4(57.74,46.97)
UIM1_RESET: length 44.9
  TOP w0.05: R4212.1 56.67,40.6 v4(57.01,40.94)
  LAYER_2 w0.045: v1(31.52,52.8) 31.68,52.96 32.03,52.96 32.15,52.84 32.41,52.84 32.44,52.86 32.57,52.86 32.65,52.78 32.67,52.78 32.91,52.54 33.07,52.54 33.46,52.93 34.64,52.93 v6(34.68,52.97)
  LAYER_3 w0.045: v4(51.97,43.18) 52.02,43.23 53.54,43.23 v2(53.62,43.31) 53.68,43.25 54.12,43.25 54.42,43.55 57.61,43.55 v4(57.69,43.48)
  LAYER_5 w0.045: v4(51.97,43.18) 51.97,44.36 51.66,44.67 51.66,44.8 51.87,45.01 51.87,52.27 51.74,52.4 v6(51.71,52.4) ; v4(57.01,40.94) 57.15,40.94 57.63,41.42 57.63,43.42 v4(57.69,43.48) 57.69,44.03 v7(58.54,44.88)
  LAYER_7 w0.045: v6(34.68,52.97) 34.68,53.12 34.89,53.34 41.56,53.34 41.74,53.16 42.14,53.16 42.44,52.86 43.97,52.86 45.7,51.13 48.8,51.13 50.18,52.51 51.6,52.51 v6(51.71,52.4)
  BOTTOM w0.075: J4250.2 58.22,44.48 VR4251.1 D4250.1
UIM1_SWP: length 1.1
  TOP w0.05: U4100.H1 59.23,52.47 59.23,52.01 R4214.2
UIM_PRESENT: length 4.2
  LAYER_2 w0.175: v2(31.61,52.42) v1(31.76,52.5)
  LAYER_3 w0.045: v2(28.02,51.97) 28.07,51.92 28.51,51.92 28.6,51.83 28.94,51.83 28.99,51.88 29.27,51.88 29.3,51.91 29.69,51.91 30.1,52.32 30.64,52.32 30.82,52.14 31.23,52.14 31.47,52.38 31.57,52.38 v2(31.61,52.42)
UNNAMED_1_BUFFERSINGLETRISTATE5PIN_I58_Y: length 0.8
  TOP w0.175: R1006.1 56.29,57.66 56.66,57.28 U1005.4
UNNAMED_1_CAPACITOR_I6_B: length 1.8
  LAYER_5 w0.175: v4(12.74,11.35) 12,11.35 v7(11.77,11.12)
  BOTTOM w0.2: C102.2 11.73,10.78 11.64,10.68 U100.11
UNNAMED_1_CAPACITOR_I9_B: length 3.3
  LAYER_5 w0.175: v4(12.76,10.81) 12.17,10.81 12.06,10.7 11.43,10.7 11.31,10.82 10.52,10.82 v7(10.35,10.99)
  BOTTOM w0.2: v7(10.35,10.99) 10.35,10.82 10.44,10.73 U100.8
UNNAMED_1_CAPACITOR_I19_B: length 1.5
  BOTTOM w0.088: J130.1 30.05,12.87 L131.2 30.77,12.93 30.77,13.33 C130.2
UNNAMED_1_CAPACITOR_I23_B: length 1.6
  BOTTOM w0.088: J110.1 23.81,10.26 L111.2 23.54,10.98 C110.2
UNNAMED_1_CAPACITOR_I44_A: length 1.5
  BOTTOM w0.088: C133.1 27.33,13.04 27.53,12.84 R131.1 28.37,12.81 J130.2
UNNAMED_1_CAPACITOR_I44_B: length 13.9
  LAYER_7 w0.045: v7(26.54,13.04) v7(12.6,13.04)
UNNAMED_1_CAPACITOR_I55_B: length 1.4
  BOTTOM w0.25: L116.2 12.38,10.37 12.04,10.03 12.04,9.76 11.79,9.52 U100.13
UNNAMED_1_CAPACITOR_I82_A: length 0.7
  BOTTOM w0.25: C172.1 7.93,11.25 8,11.33 L171.2
UNNAMED_1_CAPACITOR_I82_B: length 3.8
  TOP w0.075: v7(7.43,11.71) 8.69,12.02 R109.2
  BOTTOM w0.25: C172.2 7.12,12
  BOTTOM w0.4: 7.12,12 5.88,12 M100.1
UNNAMED_1_CAPACITOR_I84_A: length 3.4
  BOTTOM w0.25: L113.2 12.56,8.37 C112.2 12.15,8.97 12,9.12 U100.14 11.52,9.12 11.24,8.83 U100.2 11.24,8.59 10.92,8.27 C115.1
UNNAMED_1_CAPACITOR_I87_B: length 2.2
  TOP w0.2: R3002.1 24.7,36.09 C3014.2
  LAYER_3 w0.1: v2(24.21,34.09) 24.21,34.36 24.72,34.86 v2(24.72,35.56)
UNNAMED_1_CAPACITOR_I93_B: length 0.5
  TOP w0.075: L177.1 12.05,11.67 C174.2
UNNAMED_1_CAPACITOR_I100_A: length 2.2
  BOTTOM w0.25: L143.2 10.32,13 C144.1 9.67,13 9.7,12.98 9.7,12.23 L144.1
  BOTTOM w0.3: L143.2 10.35,12.98 L142.2
UNNAMED_1_CAPACITOR_I100_B: length 4.1
  BOTTOM w0.25: C144.2 8.94,12.98 8.96,12.97 8.96,12.23 L144.2 ; L170.2 L144.2 ; L144.2 8.96,12.22 8.98,12.2 8.98,12.18 8.72,11.93 L171.1 8.72,10.74 C124.2 8.63,10.36 8.28,10 L124.2
UNNAMED_1_CAPACITOR_I101_A: length 2.6
  BOTTOM w0.25: L122.2 8.02,8.19 L123.2 8.02,9.15 7.82,9.35 L124.1 7.82,10.57 C124.1
UNNAMED_1_CAPACITOR_I609_B: length 0.8
  TOP w0.175: C518.2 5.03,61.07 5.35,61.39 U519.B3
UNNAMED_1_CAPACITOR_I611_B: length 9.1
  LAYER_2 w0.045: v1(4.73,62.45) 4.73,62.3 v2(5.22,61.81) ; v2(7.83,63.89) 9.23,63.89 v1(9.66,64.31)
  LAYER_3 w0.045: v2(5.22,61.81) 5.11,61.7 5.11,60.89 5.3,60.7 5.93,60.7 v2(6.22,60.99) 6.3,60.99 6.61,61.3 v2(6.61,62.48) 6.61,63.24 6.93,63.56 7.51,63.56 v2(7.83,63.89)
UNNAMED_1_COAXJACK6PIN4GND_I37_C2: length 11.6
  LAYER_7 w0.045: v7(23.82,8.07) 16.82,8.07 arc(14.6,8.51) v7(12.72,9.77)
UNNAMED_1_INDUCTOR_I58_B: length 1.4
  BOTTOM w0.25: C140.2 11.75,12.98 11.73,12.96 C141.2
  BOTTOM w0.3: L142.1 11.72,12.24 C141.2
UNNAMED_1_INDUCTOR_I61_B: length 1.1
  BOTTOM w0.25: L118.2 9.58,9.69 10.15,9.12 U100.5
UNNAMED_1_INDUCTOR_I62_B: length 1.5
  BOTTOM w0.2: L117.2 9.69,10.49 10.05,10.13 10.05,9.77 10.3,9.52 U100.6
UNNAMED_1_INDUCTOR_I65_B: length 2.3
  BOTTOM w0.25: U100.3 U100.4
  BOTTOM w0.3: U100.4 9.91,8.19 C121.2 L122.1
UNNAMED_1_INDUCTORPOLARITY_I96_A: length 0.7
  TOP w0.075: R109.1 9.72,11.56 L175.1
UNNAMED_1_MAX17050_I607_THRM: length 0.8
  TOP w0.1: R519.1 6.15,62.11 U519.C2
UNNAMED_1_QAT3550_I85_SW1: length 0.9
  BOTTOM w0.25: C115.2 11.64,7.8 U100.1
UNNAMED_1_RESISTOR_I72_B: length 5.7
  TOP w0.05: R1004.2 30.63,62.39 30.77,62.24 30.77,60.54 30.96,60.36 33.62,60.36 33.99,59.99 U1001.AK2
UNNAMED_1_RESISTOR_I73_B: length 2.2
  TOP w0.05: U1001.AR43 32.8,49.49 32.8,49.18 32.82,49.16 32.82,47.69 R1003.2
UNNAMED_1_RESISTOR_I89_A: length 7.3
  TOP w0.1: v2(23.5,35.23) 23.22,34.96 U3100.142 ; U3100.118 24.04,34.83 24.31,35.09 24.31,35.41 C3011.2
  TOP w0.2: C3011.2 24.12,36.01 C3012.2 R3001.1
  LAYER_3 w0.1: v2(25.24,34.12) 25.24,34.36 25.46,34.58 25.65,34.58 ; v2(24.21,36.06) 23.5,35.35 v2(23.5,35.23)
  LAYER_3 w0.15: v2(25.65,34.58) 25.72,34.65 25.72,35.3 24.96,36.06 v2(24.21,36.06)
UNNAMED_1_RESISTOR_I129_B: length 1.6
  TOP w0.15: U5000.3 56.67,59.41 56.37,59.1 R5001.2 56.37,58.56 56.65,58.28 R5000.1
UNNAMED_1_RESISTOR_I874_B: length 0.7
  TOP w0.075: U6150.3 12.58,18.59 R6153.2
UNNAMED_1_RESISTOR_I877_B: length 0.7
  TOP w0.075: R6150.2 12.58,15.85 U6150.8
UNNAMED_1_RESISTOR_I902_B: length 0.8
  TOP w0.075: U6150.7 12.18,15.91 R6155.2
UNNAMED_1_RESISTOR_I904_B: length 0.9
  TOP w0.075: R6151.2 13.01,15.83 13.01,16.54 U6150.9
UNNAMED_1_RESISTOR_I905_B: length 0.8
  TOP w0.075: R6152.2 11.71,15.94 11.71,16.5 U6150.6
UNNAMED_2_CAPACITOR_I8_B: length 1.3
  TOP w0.088: FL7050.3 L7051.2 10.15,29.09 R7050.1
UNNAMED_2_CAPACITOR_I18_B: length 4.1
  TOP w0.088: R3104.1 23.16,35.55 C3102.2
  LAYER_3 w0.045: v2(24.23,32.65) 24.24,32.65 24.35,32.76 24.35,33.46 23.93,33.88 23.77,33.88 23.58,34.07 23.41,34.07 23.26,34.22 23.26,34.47 23.3,34.51 23.3,35.01 23.17,35.14 v2(23.17,35.52)
UNNAMED_2_FILTERSAW10PIN5GNDSADEN_I48_COIL1: length 1.1
  TOP w0.088: L7031.2 39.15,15.2 39.4,15.2 arc(39.58,15.24) 39.72,15.34 39.98,15.59 FL7030.6
UNNAMED_2_FILTERSAW10PIN5GNDSADEN_I48_COIL2: length 0.8
  TOP w0.088: L7030.2 40.58,15.04 40.58,15.49 FL7030.7
UNNAMED_2_FILTERSAW10PIN6GNDSADRM1G56AA0F0A_I35_INDUCTOR: length 0.8
  TOP w0.088: L7001.2 28.54,15.95 28.54,15.95 FL7001.8
UNNAMED_2_P-CHANNELMOSFET3PIN1G1S_I241_D: length 1
  BOTTOM w0.075: Q1020.3 46,51.52 R1023.2
UNNAMED_2_RESISTOR_I75_B: length 3
  LAYER_3 w0.045: v2(25.2,33.59) 25.2,33.8 25.87,34.46 25.87,35.37 25.38,35.86 25.38,35.96 v2(25.27,36.07)
UNNAMED_3_CAPACITOR_I2_B: length 1.5
  BOTTOM w0.088: C250.2 56.59,13.47 L251.2 56.65,13.13 57.38,13.13 J250.1
UNNAMED_3_CAPACITOR_I8_B: length 1.5
  BOTTOM w0.088: J230.1 43.91,13.28 L231.2 C230.2
UNNAMED_3_CAPACITOR_I14_B: length 1.5
  BOTTOM w0.088: 50.09,13.45 50.98,13.45 J210.1 ; 50.09,13.45 L211.2 ; 50.09,13.45 50.09,13.03 C210.2
UNNAMED_3_CAPACITOR_I22_A: length 1.4
  BOTTOM w0.088: J230.2 46.12,13.29 R231.1 47.01,13.73 47.01,13.75 C233.1
UNNAMED_3_CAPACITOR_I22_B: length 6.6
  LAYER_5 w0.047: v4(53.39,15.03) 52.97,14.61 arc(51.48,13.62) 49.73,13.27 49.02,13.27 arc(48.83,13.31) 48.67,13.41 48.59,13.5 arc(48.35,13.65) 48.07,13.71 v7(47.48,13.71)
UNNAMED_3_CAPACITOR_I27_A: length 1.5
  BOTTOM w0.088: C213.1 53.42,13.85 R211.1 52.53,13.37 J210.2
UNNAMED_3_CAPACITOR_I27_B: length 3.2
  LAYER_7 w0.045: v7(53.87,13.85) 53.88,13.85 54.48,14.45 arc(55.06,15.31) 55.27,16.34 v6(55.27,16.62)
UNNAMED_3_CAPACITOR_I29_B: length 3.7
  TOP w0.25: U200.14 56.62,18.32 56.74,18.32 56.97,18.09 U200.2
  TOP w0.3: L214.2 56.8,17.06 56.51,16.77 C214.2 ; L214.2 56.75,17.11 56.36,17.5 C215.1 ; L214.2 56.86,17.17 56.86,17.58 56.97,17.7 U200.2
UNNAMED_3_CAPACITOR_I37_B: length 0.9
  TOP w0.3: U200.13 56.29,18.77 56.13,18.94 L216.2
UNNAMED_3_CAPACITOR_I40_B: length 1.1
  TOP w0.2: U200.6 57.87,18.77 58.5,19.41 58.64,19.41
UNNAMED_3_CAPACITOR_I43_B: length 0.8
  BOTTOM w0.3: C260.2 60.54,12.93 C261.2
  vias: v1(60.49,13.03) v2(60.49,13.03) v3(60.49,13.03) v4(60.49,13.03) v5(60.49,13.03) v6(60.49,13.03) v7(60.49,13.03)
UNNAMED_3_CAPACITOR_I46_B: length 0.9
  TOP w0.2: C7106.2 52.11,23.83 U7100.30
UNNAMED_3_CAPACITOR_I47_A: length 1.7
  TOP w0.3: C264.1 59.09,13.89 L263.2 59.61,13.45 L262.2
UNNAMED_3_CAPACITOR_I51_B: length 0.5
  TOP w0.1: R7108.2 C7109.2
UNNAMED_3_CAPACITOR_I52_A: length 1.5
  TOP w0.3: C240.2 54.29,15.12 54.85,15.12 C241.2 L242.1
UNNAMED_3_CAPACITOR_I56_B: length 2.4
  TOP w0.3: U200.3 U200.4 58.52,17.23 C221.2 58.54,17.09 58.54,16.33 L222.1
UNNAMED_3_CAPACITOR_I59_B: length 2.2
  TOP w0.3: C244.1 L244.1 L243.2 L242.2
UNNAMED_3_CAPACITOR_I62_B: length 1.2
  TOP w0.088: R3202.1 26.46,36.07 L3201.2 26.96,36.47 R3201.2
UNNAMED_3_CAPACITOR_I76_B: length 1.7
  TOP w0.2: U200.12 U200.11 56.57,20.32 C202.2 R201.2
UNNAMED_3_CAPACITOR_I78_B: length 1.3
  TOP w0.2: R204.1 C203.2 57.87,20.05 57.77,19.95 U200.8
UNNAMED_3_CAPACITOR_I82_B: length 4
  LAYER_5 w0.045: v4(46.46,16.57) 49.09,13.94 arc(49.22,13.85) v7(49.38,13.82)
UNNAMED_3_CAPACITOR_I83_A: length 0.6
  TOP w0.25: L271.2 61.85,14.78 C272.1
UNNAMED_3_CAPACITOR_I83_B: length 1.8
  TOP w0.075: C272.2 62.89,14.83 63.34,14.83 R215.2
  TOP w0.25: C272.2 62.85,14.47 62.89,14.43
  TOP w0.4: v7(62.89,13.58) 62.89,14.43
UNNAMED_3_CAPACITOR_I93_A: length 0.5
  TOP w0.088: L7127.2 48.99,15.81 C7126.1
UNNAMED_3_CAPACITOR_I93_B: length 0.5
  TOP w0.075: C275.2 L279.1
UNNAMED_3_CAPACITOR_I100_A: length 1.9
  TOP w0.25: 59.93,15.73 L224.1 ; 59.93,15.73 59.66,15.73 C224.1 ; 59.93,15.73 59.93,16.31 L223.2
  TOP w0.3: L222.2 L223.2
UNNAMED_3_CAPACITOR_I100_B: length 4.5
  TOP w0.25: 60.12,14.92 60.22,15.02 L224.2
  TOP w0.3: L271.1 61.06,14.71 L270.2 60.12,14.92 59.59,14.92 C224.2 58.81,14.9 C264.2 58.67,15.04 C244.2 L244.2
UNNAMED_3_CAPACITOR_I106_A: length 0.9
  TOP w0.075: TP_REF_CSNS_CS3.1 R280.2 C281.1
UNNAMED_3_CAPACITOR_I158_B: length 1.3
  TOP w0.15: 57.22,30.39 57.27,30.44 57.54,30.44 57.7,30.6 R4084.1
  TOP w0.2: R4084.1 57.93,30.93 57.78,31.08 C4084.2
UNNAMED_3_CAPACITOR_I167_B: length 1.2
  TOP w0.2: C4094.2 R4085.1 48.87,32.62 48.87,32.72 48.7,32.89 48.7,33.19 U4090.3
UNNAMED_3_COAXJACK6PIN4GND_I6_C2: length 1.1
  BOTTOM w0.25: J250.2 59.24,13.28 59.71,13.76 C260.1
UNNAMED_3_INDUCTOR_I53_B: length 1.1
  TOP w0.3: U200.5 57.97,18.37 58.33,18.02 58.66,18.02 L218.2
UNNAMED_3_INDUCTORPOLARITY_I95_A: length 0.7
  TOP w0.075: R215.1 63.61,15.59 L277.1
UNNAMED_3_QAT3550_I38_SW1: length 1
  TOP w0.3: C215.2 56.08,18.24 56.34,17.97 U200.1
UNNAMED_3_RESISTOR_I32_B: length 4.7
  LAYER_3 w0.045: v2(26.35,36.48) 27.02,35.81 27.02,34.7 26.42,34.1 26.42,33.55 25.7,32.83 v2(25.7,32.65)
UNNAMED_3_RESISTOR_I61_A: length 0.7
  TOP w0.088: U3100.26 26.94,35.53 R3201.1
UNNAMED_3_RESISTOR_I215_B: length 1.9
  LAYER_3 w0.045: v2(55.59,35.08) 55.59,35.16 55.86,35.43 56.59,35.43 v2(57.07,35.91)
UNNAMED_5_128GBEMMC48GBLPDDR4254PINH9HQ16AECMMDAR_I204_VDDIQ1: length 4.5
  TOP w0.15: U1600.T17 v1(52.63,52.49)
  LAYER_2 w0.15: v1(56.56,52.32) 56.39,52.49 v1(52.63,52.49)
UNNAMED_5_128GBEMMC48GBLPDDR4254PINH9HQ16AECMMDAR_I204_VDDIQ2: length 2.9
  LAYER_2 w0.1: v1(55,57.38) 54.87,57.25 54.51,57.25 53.26,56 v1(52.63,56)
UNNAMED_5_128GBEMMC48GBLPDDR4254PINH9HQ16AECMMDAR_I204_ZQ0: length 3.3
  LAYER_2 w0.045: v1(52.2,59.93) 52.33,59.8 52.97,59.8 53.9,60.73 54.8,60.73 v1(54.97,60.89)
UNNAMED_5_128GBEMMC48GBLPDDR4254PINH9HQ16AECMMDAR_I204_ZQ1: length 3.3
  LAYER_2 w0.045: v1(52.21,59.59) 52.32,59.7 53.02,59.7 53.95,60.63 54.71,60.63 v1(54.97,60.37)
UNNAMED_5_CAPACITOR_I3_B: length 1
  TOP w0.25: R400.1 10.56,31.71 v7(10.56,31.31) L401.2 10.47,31.35 C400.2
UNNAMED_5_CAPACITOR_I3_B_1: length 0.7
  TOP w0.088: L7335.1 27,28.72 C7335.2
UNNAMED_5_CAPACITOR_I6_B: length 0.5
  TOP w0.088: C7330.2 L7332.1
UNNAMED_5_CAPACITOR_I8_B: length 1.2
  TOP w0.25: R300.1 v7(60.25,34.21) L301.2 C300.2
UNNAMED_5_CAPACITOR_I16_B: length 1.4
  TOP w0.3: C403.2 C402.2 9.25,32.8 L404.1
UNNAMED_5_CAPACITOR_I22_B: length 1.6
  TOP w0.3: C406.1 8.46,33.52 L405.2 L404.2
UNNAMED_5_CAPACITOR_I29_A: length 1.8
  TOP w0.25: L305.2 61.54,34.96 C305.1 L304.2
UNNAMED_5_CAPACITOR_I31_B: length 0.5
  TOP w0.088: L7329.1 29.23,33.01 29.24,33.01 C7327.2
UNNAMED_5_CAPACITOR_I37_B: length 0.6
  TOP w0.088: C7332.2 30.03,28.97 L7334.1
UNNAMED_5_CAPACITOR_I178_A: length 1.3
  TOP w0.088: C7390.1 28.23,27.33 C7371.1 28.19,27.37 28.19,27.56 27.91,27.84 L7371.1
UNNAMED_5_CAPACITOR_I181_A: length 1
  TOP w0.088: C7389.1 C7376.1 28.58,29.46 L7368.1
UNNAMED_5_CAPACITOR_I193_A: length 0.6
  TOP w0.088: C7369.1 29.13,27.95 L7367.1
UNNAMED_5_CAPACITOR_I204_A: length 1.2
  TOP w0.088: L7328.1 28.87,31.9 28.9,31.87 29.21,31.87 29.36,32.02 29.36,32.41 L7329.2
UNNAMED_5_CAPACITOR_I205_A: length 1.1
  TOP w0.088: 30.59,30.17 30.33,30.17 30.3,30.19 L7331.1 ; 30.59,30.17 30.6,30.18 L7332.2 ; 30.59,30.17 C7386.1
UNNAMED_5_CAPACITOR_I206_A: length 1.5
  TOP w0.088: L7333.1 29.15,29.97 29.69,29.43 L7334.2 30.08,29.43 C7387.1
UNNAMED_5_CAPACITOR_I207_A: length 1.3
  TOP w0.088: L7336.1 26.53,29.1 L7335.2 26.54,28.68 C7388.1
UNNAMED_5_COAXJACK6PIN4GND_I7_C2: length 0.6
  TOP w0.25: C402.1 10.59,32.73 R400.2
  vias: v1(10.6,32.88) v2(10.6,32.88) v3(10.6,32.88) v4(10.6,32.88) v5(10.6,32.88) v6(10.6,32.88) v7(10.6,32.88)
UNNAMED_5_COAXJACK6PIN4GND_I12_C2: length 2.1
  TOP w0.25: R300.2 v7(60.25,32.72) 60.82,32.72 C303.2 61.01,32.91 61.42,32.91 L304.1
UNNAMED_5_CONTACT1PIN_I25_X: length 2.7
  TOP w0.25: C406.2 7.02,33.52
  TOP w0.5: 7.02,33.52 6,33.52 4.89,32.41 M400.1
UNNAMED_5_CONTACT1PIN_I30_X: length 3.2
  TOP w0.4: M300.1 63.44,32.73 63.44,33.8 C305.2
UNNAMED_5_LDC0851_I24_ADJ: length 3.5
  TOP w0.2: U6180.4 6.61,57.3 v1(7.09,56.82)
  LAYER_2 w0.2: v1(7.09,56.82) 7.29,57.02 7.29,57.16 7.81,57.68 9.12,57.68 v1(9.31,57.87)
UNNAMED_5_LDC0851_I24_EN: length 0.8
  TOP w0.15: U6180.6 6.2,59.23 6.2,59.42 6.47,59.69 R6182.1
UNNAMED_7_CAPACITOR_I143_A: length 8.4
  LAYER_5 w0.047: v4(26.99,23.62) 26.99,24.59 arc(27.05,24.9) 27.23,25.17 27.36,25.3 arc(27.53,25.55) 27.59,25.86 27.59,30.2 arc(27.75,31) 28.2,31.68 v4(28.2,31.69)
UNNAMED_7_CAPACITOR_I152_A: length 9.1
  LAYER_5 w0.047: v4(28.53,23.69) 28.53,24.1 arc(28.49,24.28) 28.39,24.43 28.33,24.49 arc(28.21,24.66) 28.18,24.85 28.18,29.74 arc(28.22,29.96) 28.35,30.15 arc(28.55,30.46) 28.63,30.83 v4(28.63,32.54)
UNNAMED_7_CAPACITOR_I226_B: length 2.6
  TOP w0.2: U7216.D1 27.15,23.29 C7219.2 C7218.2 26.02,23.75 R7200.1
UNNAMED_7_CAPACITOR_I230_B: length 3.1
  TOP w0.2: R7201.1 26.04,26.11 26.04,25.73 C7274.2 26.06,25.65 26.06,25.25 v2(26,25.19)
  LAYER_3 w0.2: v2(26,25.19) 26.55,24.64 26.88,24.64 27.03,24.49 27.03,24.21 v2(27.3,23.94)
UNNAMED_7_INDUCTOR_I254_A: length 1.4
  TOP w0.088: U7216.D5 27.51,25.06 27.95,25.49 L7219.1
UNNAMED_7_INDUCTOR_I256_A: length 1.3
  TOP w0.088: L7274.1 28.4,25.53 U7216.E6
UNNAMED_9_AW8690_I72_DVDD: length 0.7
  TOP w0.15: U4600.G3 9.85,19.21 9.7,19.36 C4600.2
UNNAMED_9_AW8690_I72_PVDD1:
  vias: v1(6.43,16.34) v1(6.43,16.16) v1(6.43,15.98) v1(6.44,17.37) v1(6.44,17.19) v1(6.44,17.01) v1(6.6,17.45) v1(6.6,17.27) v1(6.6,17.09) v1(6.59,16.27) v1(6.59,16.09) v1(6.59,15.91) v1(7.94,18.76) v1(7.94,18.36) v1(7.94,17.96) v1(7.94,17.08) v1(7.94,16.77) v1(7.94,16.44) v1(8.06,18.56) v1(8.05,18.17) v1(8.06,16.93) v1(8.05,16.6) v1(8.18,18.77) v1(8.18,18.37) v1(8.18,17.97) v1(8.18,17.08) v1(8.18,16.77) v1(8.18,16.44) v2(6.43,16.34) v2(6.43,16.16) v2(6.43,15.98) v2(6.44,17.37) v2(6.44,17.19) v2(6.44,17.01) v2(6.6,17.45) v2(6.6,17.27) v2(6.6,17.09) v2(6.59,16.27) v2(6.59,16.09) v2(6.59,15.91) v2(7.94,18.76) v2(7.94,18.36) v2(7.94,17.96) v2(7.94,17.08) v2(7.94,16.77) v2(7.94,16.44) v2(8.06,18.56) v2(8.05,18.17) v2(8.06,16.93) v2(8.05,16.6) v2(8.18,18.77) v2(8.18,18.37) v2(8.18,17.97) v2(8.18,17.08) v2(8.18,16.77) v2(8.18,16.44)
UNNAMED_9_AW8690_I72_SW1: length 0.8
  TOP w0.3: U4600.G6 U4600.F6 U4600.E6
UNNAMED_9_AW8690_I72_TRIG1: length 4.9
  LAYER_3 w0.045: v2(12.99,19.61) 12.89,19.51 12.24,19.51 11.97,19.24 11.97,19.09 10.88,18 10.36,18 v2(10.31,17.95) 10.44,17.83 10.44,17.26 v2(10.3,17.12) 10.58,16.84 v2(10.66,16.84)
UNNAMED_10_CAPACITOR_I73_A: length 0.9
  TOP w0.2: C6406.1 12.43,22.93 12.03,23.34 U6400.D5
UNNAMED_10_CS35L41_I10_OUTN: length 11
  LAYER_2 w0.175: v2(16.88,17.45) v2(17.06,17.45)
  LAYER_3 w0.4: 16.97,17.64 16.97,17.9 16.27,18.6 16.27,20.75 15.52,21.5 14.97,21.5
  LAYER_4 w0.175: v4(14.91,21.59) v4(14.91,21.41)
  LAYER_5 w0.3: 11.09,23.76 v4(10.78,23.76)
  LAYER_5 w0.4: 11.09,23.76 11.41,23.44 11.41,22.22 12.13,21.5 14.76,21.5
UNNAMED_10_CS35L41_I10_OUTP: length 9.9
  LAYER_2 w0.175: v2(15.73,17.45) v2(15.91,17.45)
  LAYER_3 w0.4: 15.82,17.67 15.82,20.55 15.35,21.02 14.97,21.02
  LAYER_4 w0.175: v4(14.91,21.11) v4(14.91,20.93)
  LAYER_5 w0.3: 10.92,23.16 v4(10.74,23.34)
  LAYER_5 w0.4: 10.92,23.16 10.92,22.06 11.96,21.02 14.78,21.02
UNNAMED_10_CS35L41_I10_SW1: length 2
  TOP w0.3: U6400.B2 U6400.A2 10.72,25.88 L6400.2
UNNAMED_12_BGA7L1N6_I14_PON: length 0.7
  TOP w0.088: U8501.6 23.79,24.73 R8510.2
UNNAMED_12_CAPACITOR_I29_B: length 0.5
  TOP w0.05: L8516.2 L8519.1
UNNAMED_12_CAPACITOR_I67_B: length 0.2
  LAYER_2 w0.175: v2(18.67,61.47) v2(18.85,61.47)
  vias: v1(18.73,59.24) v2(18.73,59.24)
UNNAMED_12_CAPACITOR_I88_B: length 4.8
  LAYER_3 w0.175: 15.13,59.4 v2(15.13,59.34)
  LAYER_3 w0.4: 15.13,59.4 15.66,59.93 17.06,59.93 17.4,59.59 17.4,59.34 17.4,59.33 17.4,59.05 17.81,58.64 18.68,58.64 v2(18.73,58.69)
UNNAMED_12_CAPACITOR_I91_B: length 4.4
  LAYER_3 w0.09: v2(14.76,57.48) 14.8,57.44 15.91,57.44 16.23,57.12 17.13,57.12 17.41,56.84 17.72,56.84 17.98,56.58 18.63,56.58 v2(18.72,56.67)
UNNAMED_12_CAPACITOR_I92_B: length 4.8
  LAYER_3 w0.1: v2(18.93,56.96) 18.72,56.96 18.44,57.24 17.59,57.24 16.79,58.04 15.12,58.04 v2(14.75,58.41)
UNNAMED_12_INDUCTOR_I19_B: length 0.4
  TOP w0.3: v2(10.33,59.72) v2(10.33,59.52)
  LAYER_2 w0.175: v2(10.33,59.72) v2(10.33,59.52)
  vias: v1(9.18,59.33) v1(9.18,59.15) v1(9.36,59.33) v1(9.36,59.15) v1(10.33,59.92) v2(9.18,59.33) v2(9.18,59.15) v2(9.36,59.33) v2(9.36,59.15) v2(10.33,59.92)
UNNAMED_12_NCP3902FCCTBG_I133_RXN: length 0.6
  TOP w0.075: R2418.2 14.18,39.33 U2401.D5
UNNAMED_12_PM670_I87_BATTID: length 7.8
  LAYER_3 w0.045: v2(13.77,58.34) 13.77,57.2 13.99,56.98 14.65,56.98 14.7,57.03 14.96,57.03 15.13,57.2 15.84,57.2 16.15,56.89 17.04,56.89 17.31,56.62 17.62,56.62 17.89,56.36 19.07,56.36 19.19,56.48 19.34,56.48 19.45,56.59 19.45,56.92 v2(19.43,56.93)
UNNAMED_13_CAPACITOR_I13_B: length 4.3
  LAYER_3 w0.15: v2(42.19,41.91) 41.88,41.6 38.55,41.6 38.22,41.93 v2(38.22,42.04)
UNNAMED_13_CAPACITOR_I15_B: length 9.3
  TOP w0.05: 22.55,20.34 v2(22.56,20.35)
  TOP w0.2: C8204.2 22.55,20.35 v2(22.56,20.35) ; v4(23.48,20.35) C8202.2
  LAYER_3 w0.2: v4(24.52,16.12) v2(21.3,16.12) ; v4(23.48,20.35) v2(22.56,20.35)
  LAYER_5 w0.2: v4(24.52,16.12) 24.52,19.31 v4(23.48,20.35)
UNNAMED_13_CAPACITOR_I15_B_2: length 5.7
  LAYER_3 w0.075: v2(37.95,41.35) 38.07,41.23 38.51,41.23 38.58,41.3 39.13,41.3 39.19,41.25
  LAYER_3 w0.1: v2(43.25,41.95) 42.55,41.25 39.19,41.25
UNNAMED_13_CAPACITOR_I33_B: length 0.5
  TOP w0.2: R8201.1 C8208.2
UNNAMED_13_INDUCTOR_I40_A: length 0.6
  LAYER_2 w0.175: v2(25.59,18.05) v2(25.77,18.05) v2(25.59,17.87) v2(25.59,18.05)
  vias: v1(22.58,19.13) v2(22.58,19.13)
UNNAMED_13_INDUCTOR_I40_B: length 0.4
  LAYER_2 w0.175: v2(23.66,17.69) v2(23.66,17.87) v2(23.66,18.05)
  vias: v1(22.62,18.74) v2(22.62,18.74)
UNNAMED_14_CAPACITOR_I36_A: length 1.4
  TOP w0.088: FL4060.4 60.46,26.05 60.71,25.8 60.71,25.36 ; L4062.2 60.71,25.36 ; 60.71,25.36 C4063.1
UNNAMED_14_CAPACITOR_I64_A: length 1.2
  TOP w0.088: 49.67,30.32 49.67,29.96 49.54,29.83 C4077.1 ; 49.67,30.32 50.03,30.32 50.04,30.31 U4070.1 ; 49.67,30.32 L4076.2
UNNAMED_14_CAPACITOR_I66_A: length 1.1
  TOP w0.088: C4047.1 L4046.2 47.05,31.92 U4040.1
UNNAMED_14_CAPACITOR_I74_A: length 1.2
  TOP w0.088: C4067.1 L4066.2 60.32,23.96 U4060.1
UNNAMED_14_CAPACITOR_I76_A: length 1.2
  TOP w0.088: U4050.1 58.28,24.83 L4056.2 58.28,23.99 C4057.1
UNNAMED_14_COUPLER4PINLDJ0Q2G4519CH050_I39_TERMINATE: length 0.5
  TOP w0.088: U4070.4 50.32,31.07 R4074.2
UNNAMED_14_COUPLER4PINLDJ0Q2G4519CH050_I42_COUPLEDOUT: length 0.6
  TOP w0.088: R4045.1 46.19,32.3 46.62,32.3 U4040.3
UNNAMED_14_COUPLER4PINLDJ0Q2G4519CH050_I42_TERMINATE: length 0.6
  TOP w0.088: R4044.2 46.68,31.43 U4040.4
UNNAMED_14_COUPLER4PINLDJ0Q2G4519CH050_I51_COUPLEDOUT: length 2.5
  LAYER_5 w0.047: v4(59.64,24.72) 58.77,24.72 arc(57.96,24.88) v4(57.27,25.34)
UNNAMED_14_COUPLER4PINLDJ0Q2G4519CH050_I51_TERMINATE: length 0.7
  TOP w0.088: R4064.2 59.59,23.99 59.64,24.04 U4060.4
UNNAMED_14_COUPLER4PINLDJ0Q2G4519CH050_I53_COUPLEDOUT: length 0.7
  TOP w0.088: R4055.1 57.42,25.85 57.75,25.52 U4050.3
UNNAMED_14_COUPLER4PINLDJ0Q2G4519CH050_I53_TERMINATE: length 0.6
  TOP w0.088: R4054.2 57.4,24.76 57.46,24.76 U4050.4
UNNAMED_14_FAN53526_I103_SW1: length 1.9
  TOP w0.3: L2560.1 24.63,50.86 24.37,50.6 U2560.A2 U2560.B2
UNNAMED_14_FAN53526_I131_SW1: length 1.9
  TOP w0.3: U2570.B2 58.26,49.26 57.9,48.91 57.9,48.33
UNNAMED_15_CAPACITOR_I12_A: length 0.5
  TOP w0.088: L7834.1 21.82,28.89 L7832.1
UNNAMED_15_CAPACITOR_I34_A: length 0.5
  TOP w0.088: C7823.1 23.25,28.19 23.23,28.18 C7824.1
UNNAMED_15_CAPACITOR_I124_B: length 1.7
  TOP w0.088: FL7820.1 35.81,30.31 35.81,31.27 L7821.2 35.83,31.34 36.31,31.34 C7822.2
UNNAMED_15_CAPACITOR_I129_B: length 1.1
  TOP w0.088: L7825.1 23.9,29.18 23.8,29.07 23.8,28.79 C7896.2 C7823.2
UNNAMED_15_CAPACITOR_I130_B: length 1
  TOP w0.088: L7832.2 22.24,29.36 22.3,29.3 ; 22.3,29.3 C7835.1 ; 22.3,29.3 22.3,29.8 C7895.2
UNNAMED_19_CAPACITOR_I59_A: length 3.7
  LAYER_3 w0.1: v2(19.72,55.73) 19.63,55.64 19.63,54.17 v2(18.14,52.68)
UNNAMED_19_CAPACITOR_I59_B: length 3.4
  LAYER_2 w0.15: v1(19.93,55.46) 19.93,54.02 18.75,52.84 v1(18.75,52.57)
UNNAMED_19_CAPACITOR_I67_A: length 4.1
  LAYER_2 w0.075: v1(21.73,58.24) 21.73,58.91 21.89,59.07 v2(21.89,59.74)
  LAYER_3 w0.075: v2(21.89,59.74) 22.52,60.37 v2(22.52,62.05)
UNNAMED_19_CAPACITOR_I122_B: length 3.7
  TOP w0.15: Q2031.1 16.68,52.4 R2018.2 v1(16.67,51.96) C2018.2
  LAYER_2 w0.045: v1(16.67,51.96) 17.04,51.59 17.04,51.44 17.41,51.07 18.32,51.07 v1(18.56,50.83)
UNNAMED_19_CAPACITOR_I137_B: length 7.9
  TOP w0.05: Q2032.1 5.37,67.29 v2(5.12,67.29)
  TOP w0.075: v2(9.3,68.98) 9.32,68.98 9.42,68.88 9.71,68.88 R2020.2 C2020.2
  LAYER_3 w0.045: v4(4.52,67.45) 4.68,67.29 v2(5.12,67.29) ; v4(9.1,68.67) v2(9.3,68.98)
  LAYER_5 w0.045: v4(4.52,67.45) 4.75,67.68 4.94,67.68 5.11,67.85 8.75,67.85 9.04,68.14 9.04,68.61 v4(9.1,68.67)
UNNAMED_20_CAPACITOR_I169_B: length 1.4
  TOP w0.25: U4100.B8 62.26,55.17 62.84,54.59 C4131.2
UNNAMED_20_CAPACITOR_I171_B: length 1.7
  LAYER_5 w0.2: v4(61.78,56.57) 61.78,55.95 v4(61,55.17)
UNNAMED_20_CAPACITOR_I206_B: length 3.4
  LAYER_5 w0.1: v4(60.59,54.78) 60.59,55.38 61.31,56.1 61.31,56.65 61.75,57.09 v4(62.31,57.09)
UNNAMED_20_CAPACITOR_I208_B: length 2.3
  TOP w0.25: C4110.2 61.02,56.27 60.53,55.78 U4100.A5
  LAYER_3 w0.25: v2(61.33,55.24) 61.33,55.34 61.1,55.57 v2(60.6,55.57)
UNNAMED_20_CAPACITOR_I233_B: length 4.2
  TOP w0.25: C4166.2 58.53,60.34 C4167.2 59.05,60.34 C4155.1 ; C4155.1 C4154.1 R4155.1 59.1,59.12 C4163.1 58.87,58.87 58.36,58.87 C4162.1 R4160.2 ; C4155.1 59.1,60.81 R4162.1
UNNAMED_20_CAPACITOR_I242_B: length 4.3
  TOP w0.25: C4155.2 C4154.2 R4155.2 59.56,58.66 C4153.1 C4152.1 60.49,58.64 R4150.2 ; C4155.2 59.59,60.34 C4157.2 60.03,60.34 60.03,60.85 C4156.2 ; C4155.2 59.56,60.85 R4152.1
UNNAMED_20_CAPACITOR_I245_A: length 2.2
  TOP w0.25: C4163.2 58.85,58.41 58.35,58.41 C4162.2 58.35,58.4 58.3,58.35 R4161.2 C4161.1 58.83,57.46 L4160.2
UNNAMED_20_CAPACITOR_I251_B: length 2.3
  TOP w0.25: L4150.2 60.04,57.7 C4151.2 59.54,57.87 C4153.2 C4152.2 60.44,58.18 R4151.2
UNNAMED_20_INDUCTOR_I230_B: length 0.4
  TOP w0.3: v1(60.9,49.56) v1(60.9,49.76) v1(60.9,49.96)
  vias: v1(61.82,49.99) v1(61.82,49.81)
UNNAMED_20_RESISTOR_I244_B: length 1
  TOP w0.25: C4169.2 57.8,57.49 57.84,57.53 R4161.1 R4160.1
UNNAMED_20_RESISTOR_I252_B: length 1
  TOP w0.25: R4150.1 R4151.1 C4159.2
UNNAMED_20_ST21NFCD_I157_GPIORF1: length 2
  LAYER_3 w0.045: v2(58.93,54.37) 58.34,54.37 58.13,54.16 57.82,54.16 57.68,54.3 v2(57.07,54.3)
UNNAMED_20_ST21NFCD_I157_GPIORF2: length 2.3
  LAYER_3 w0.045: v2(59.33,54.37) 59.26,54.44 59.26,54.54 58.73,55.07 57.98,55.07 v2(57.57,55.48)
UNNAMED_21_CAPACITOR_I17_B: length 2.2
  LAYER_3 w0.15: v2(5.65,55.69) 5.91,55.43 6,55.43 6.09,55.34 6.57,55.34 v2(7.35,54.56)
UNNAMED_21_CAPACITOR_I18_B: length 0.7
  TOP w0.3: U6250.A5 8.44,55.78 C6245.2
UNNAMED_21_CAPACITOR_I20_B: length 2.4
  LAYER_3 w0.15: v2(5.65,56.28) 5.78,56.15 6.02,56.15 6.37,55.8 6.37,55.68 6.51,55.54 6.69,55.54 v2(7.35,54.88)
UNNAMED_21_CAPACITOR_I52_B: length 2.1
  LAYER_3 w0.15: v2(5.61,53.47) v2(7.71,53.47)
UNNAMED_21_CAPACITOR_I53_B: length 1.9
  LAYER_3 w0.15: v2(5.61,53.98) 5.61,53.96 5.87,53.7 v2(7.34,53.7)
UNNAMED_21_CAPACITOR_I54_B: length 2.6
  TOP w0.15: v2(7.98,55.4) U6250.A3
  LAYER_3 w0.1: v2(6.54,56.68) 7.03,56.68 7.69,56.02 7.69,55.63 7.92,55.4 v2(7.98,55.4)
UNNAMED_21_CAPACITOR_I55_B: length 1.7
  LAYER_3 w0.1: v2(6.6,55.77) 6.81,55.77 7.61,54.98 7.61,54.78 v2(7.72,54.67)
UNNAMED_21_CAPACITOR_I56_B: length 1.7
  LAYER_3 w0.1: v2(6.35,54.68) 6.53,54.68 7.08,54.13 7.62,54.13 v2(7.76,53.99)
UNNAMED_21_CAPACITOR_I57_B: length 1.8
  LAYER_3 w0.1: v2(6.32,55.12) 7.11,54.32 v2(7.75,54.32)
UNNAMED_21_CAPACITOR_I132_B: length 3.8
  LAYER_3 w0.1: v2(9.53,53.71) 8.53,52.71 7.42,52.71 6.74,52.03 6.61,52.03 v2(6.49,52.15)
UNNAMED_21_CAPACITOR_I219_B: length 4
  LAYER_7 w0.1: v6(8.03,54.52) 6.48,52.97 v6(6.48,51.15)
UNNAMED_21_CAPACITOR_I221_B: length 5
  LAYER_7 w0.1: v6(8.03,54.93) 7.79,54.69 7.79,54.51 6.29,53.01 6.29,50.97 v6(6.51,50.75)
UNNAMED_21_RESISTOR_I213_A: length 2
  TOP w0.088: v2(12.54,55.13) 13.21,55.13 R6263.1
  LAYER_3 w0.045: v2(12.54,55.13) 12.38,55.13 11.76,54.51 v2(11.63,54.51)
UNNAMED_21_RESISTOR_I215_A: length 1.8
  LAYER_3 w0.045: v2(12.28,55.85) 12.28,55.38 11.66,54.76 11.33,54.62 v2(11.22,54.66)
UNNAMED_21_TESTPOINT_I128_X: length 4.5
  LAYER_2 w0.045: v1(12.74,48.67) 12.58,48.83 12.45,48.83 v2(12.3,48.98)
  LAYER_3 w0.045: v2(9.9,51.52) 10.55,51.52 12.3,49.77 v2(12.3,48.98)
UNNAMED_23_CAPACITOR_I30_A: length 0.7
  TOP w0.088: L7612.1 24.6,28.14 24.6,27.93 C7613.1
UNNAMED_23_CAPACITOR_I78_A: length 0.6
  TOP w0.088: C7608.1 19.04,32.28 arc(18.92,32.11) 18.88,31.9 C7605.2
UNNAMED_23_CAPACITOR_I79_A: length 0.5
  TOP w0.088: C7607.1 C7602.1
UNNAMED_23_CAPACITOR_I90_A: length 0.5
  TOP w0.088: C7615.1 20.01,30.44 C7617.1
UNNAMED_23_CAPACITOR_I96_A: length 1.4
  TOP w0.088: FL7600.6 19.94,29.78 20.28,29.44 20.47,29.44 L7647.2 20.55,29.78 C7644.1
UNNAMED_23_CAPACITOR_I97_B: length 1.1
  TOP w0.088: C7606.1 19.3,31.44 C7605.1 18.89,31.44 C7645.2
UNNAMED_23_CAPACITOR_I98_A: length 1.5
  TOP w0.088: FL7610.6 23.51,27.7 L7630.2 24.1,27.94 24.1,28.14 C7646.1
UNNAMED_23_CAPACITOR_I99_A: length 1.5
  TOP w0.088: C7647.1 20.82,27.96 20.82,27.93 arc(20.96,27.6) L7631.2 21.46,27.46 arc(21.53,27.45) 21.59,27.41 arc(21.66,27.36) 21.75,27.34 FL7610.9
UNNAMED_23_CAPACITOR_I100_B: length 1.8
  TOP w0.088: C7625.2 20.85,30.98 ; 20.85,30.98 20.85,30.94 arc(20.8,30.82) 20.68,30.77 20.26,30.77 arc(20.19,30.78) 20.13,30.82 19.92,31.04 C7648.2 ; 20.85,30.98 20.87,31.01 21.28,31.01 L7626.1
UNNAMED_24_CAPACITOR_I130_B: length 2.9
  TOP w0.088: 14.77,32.19 14.77,31.68 ; 14.43,30.5 14.42,30.51 14.42,30.89 C7768.2
  TOP w0.2: 14.77,31.68 14.43,31.33 C7768.2 C7767.2 14.43,29.97 14.36,29.91 R7731.1
UNNAMED_24_CAPACITOR_I146_A: length 5.3
  LAYER_3 w0.045: v2(16.02,31.99) 16.32,32.3 arc(16.47,32.4) 16.64,32.43 17.41,32.43 arc(17.53,32.45) 17.62,32.52 arc(17.73,32.59) 17.84,32.61 v2(21.14,32.61)
UNNAMED_24_CAPACITOR_I147_A: length 7.1
  LAYER_3 w0.045: v2(14.53,31.94) arc(14.91,31.69) 15.35,31.6 17,31.6 arc(17.26,31.65) 17.48,31.8 17.75,32.06 arc(17.99,32.22) 18.27,32.28 21.1,32.28 arc(21.19,32.26) v2(21.27,32.21)
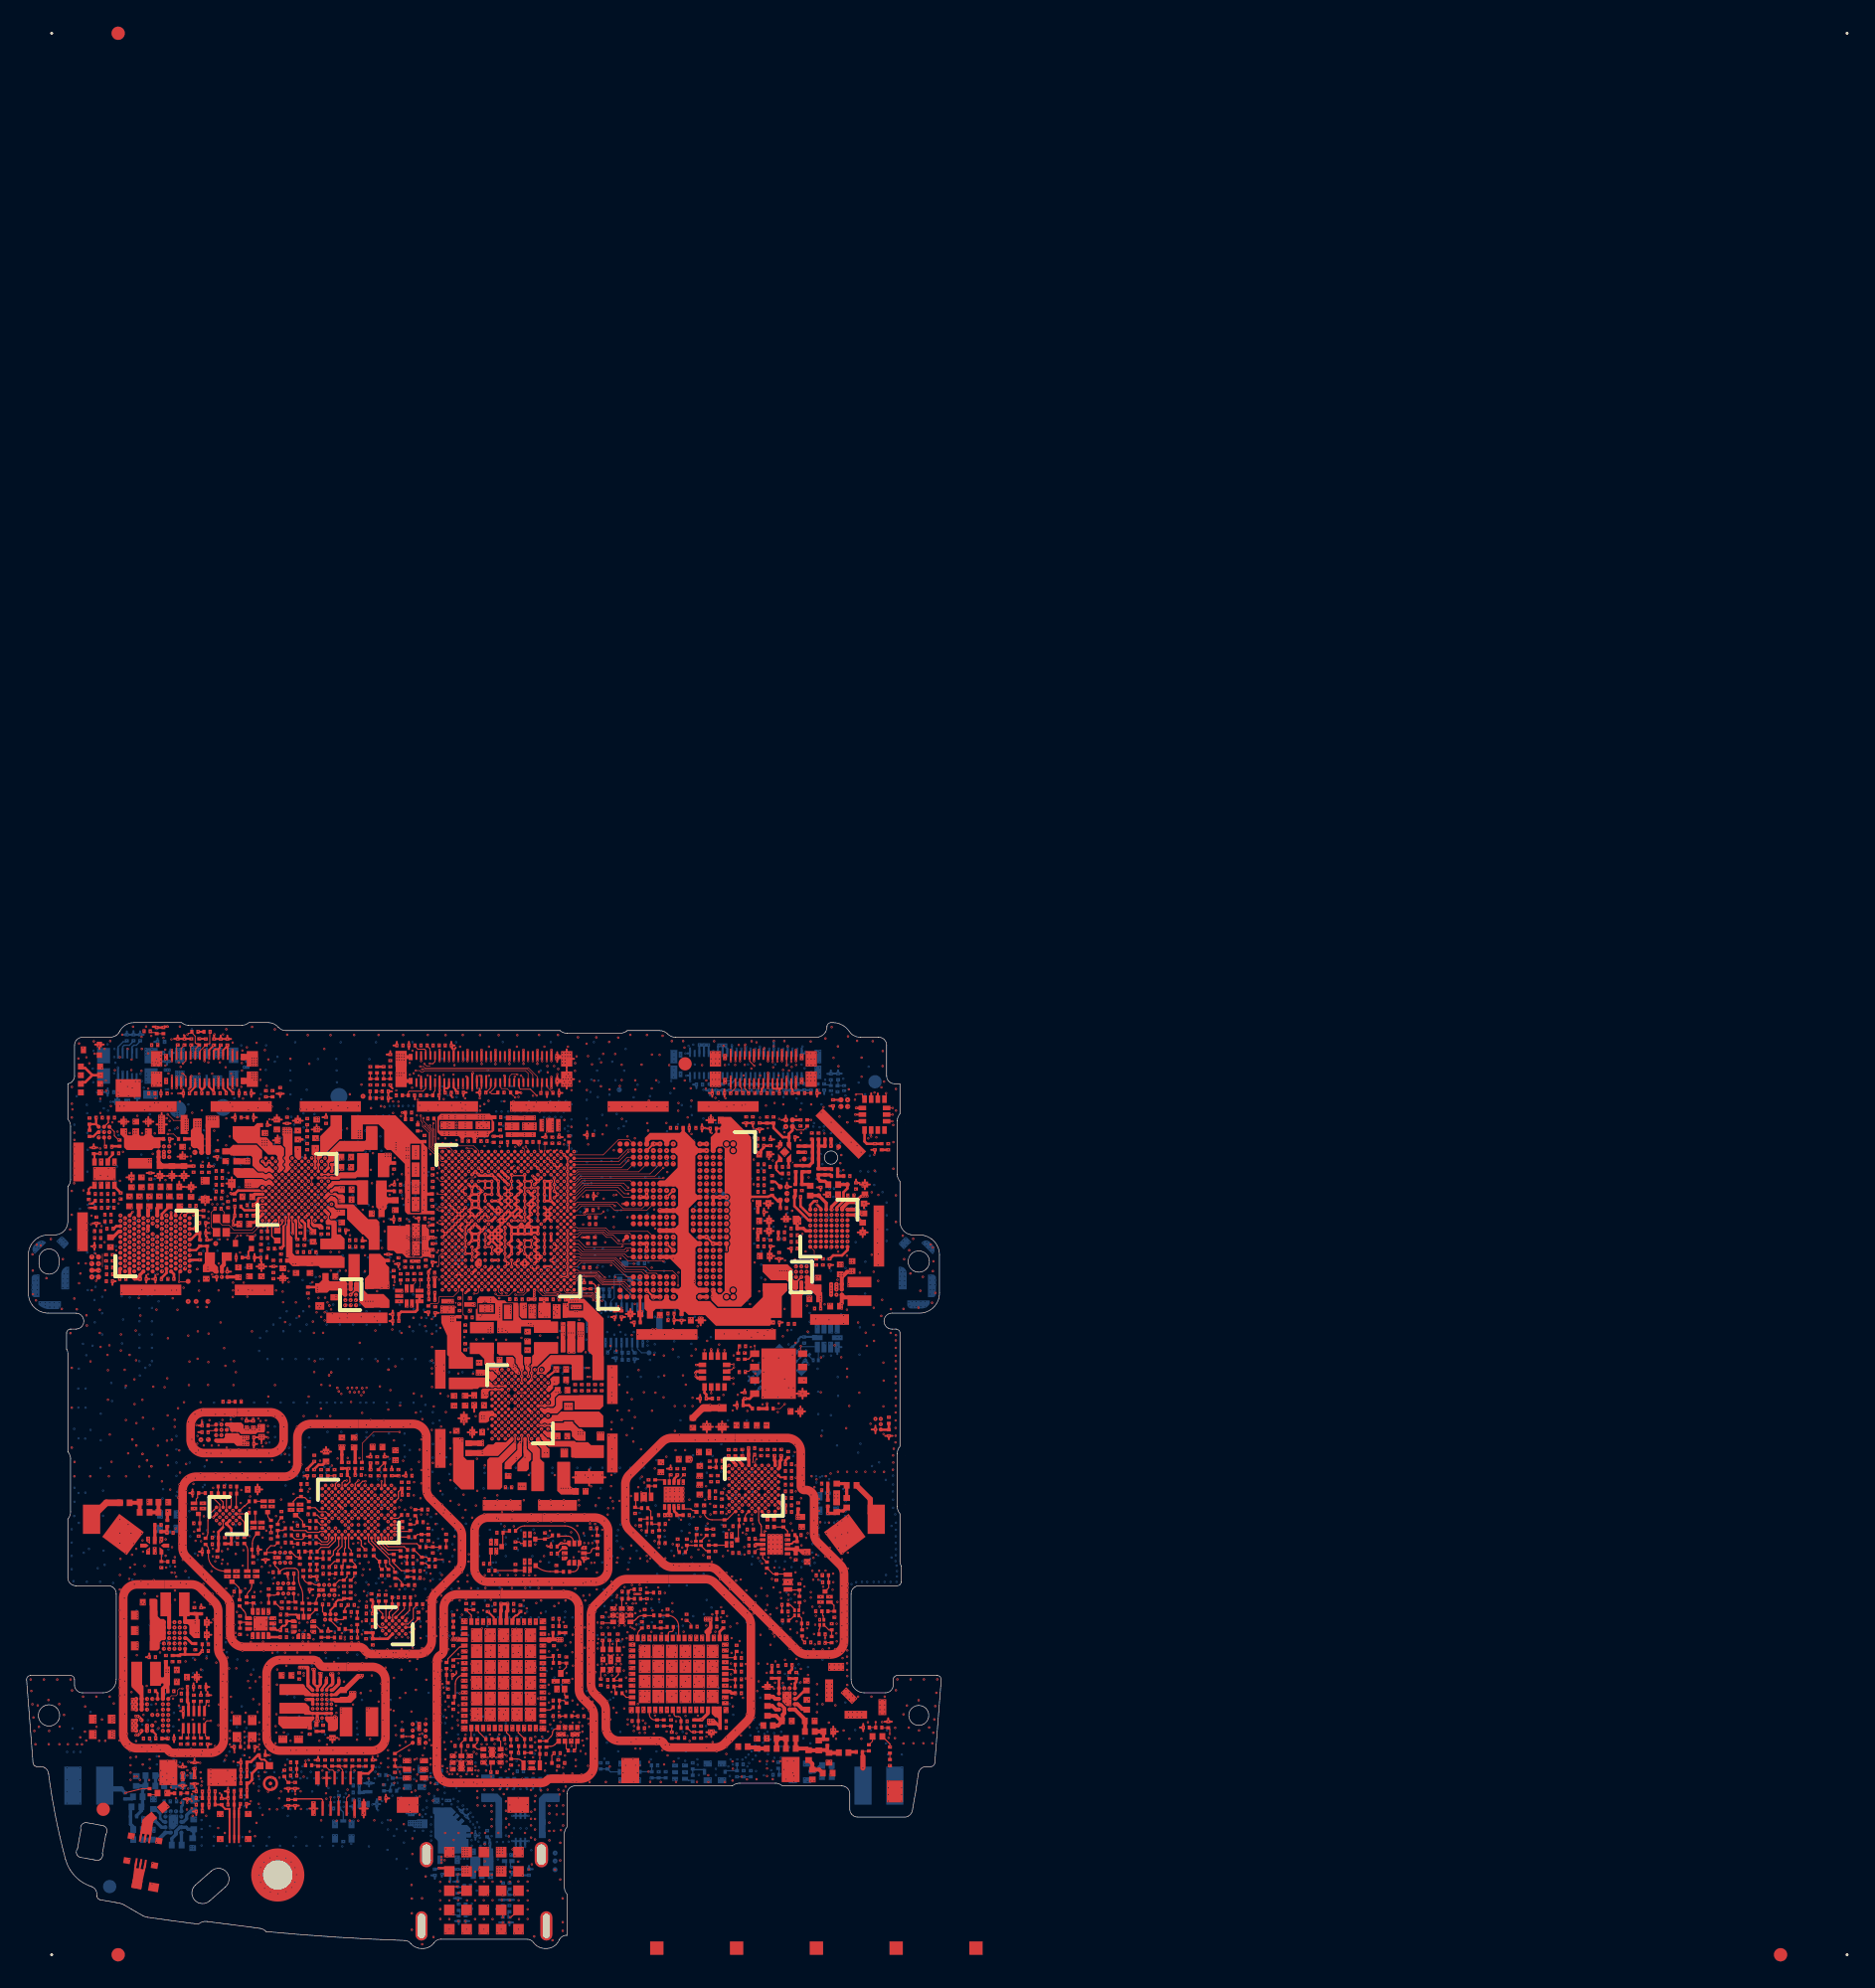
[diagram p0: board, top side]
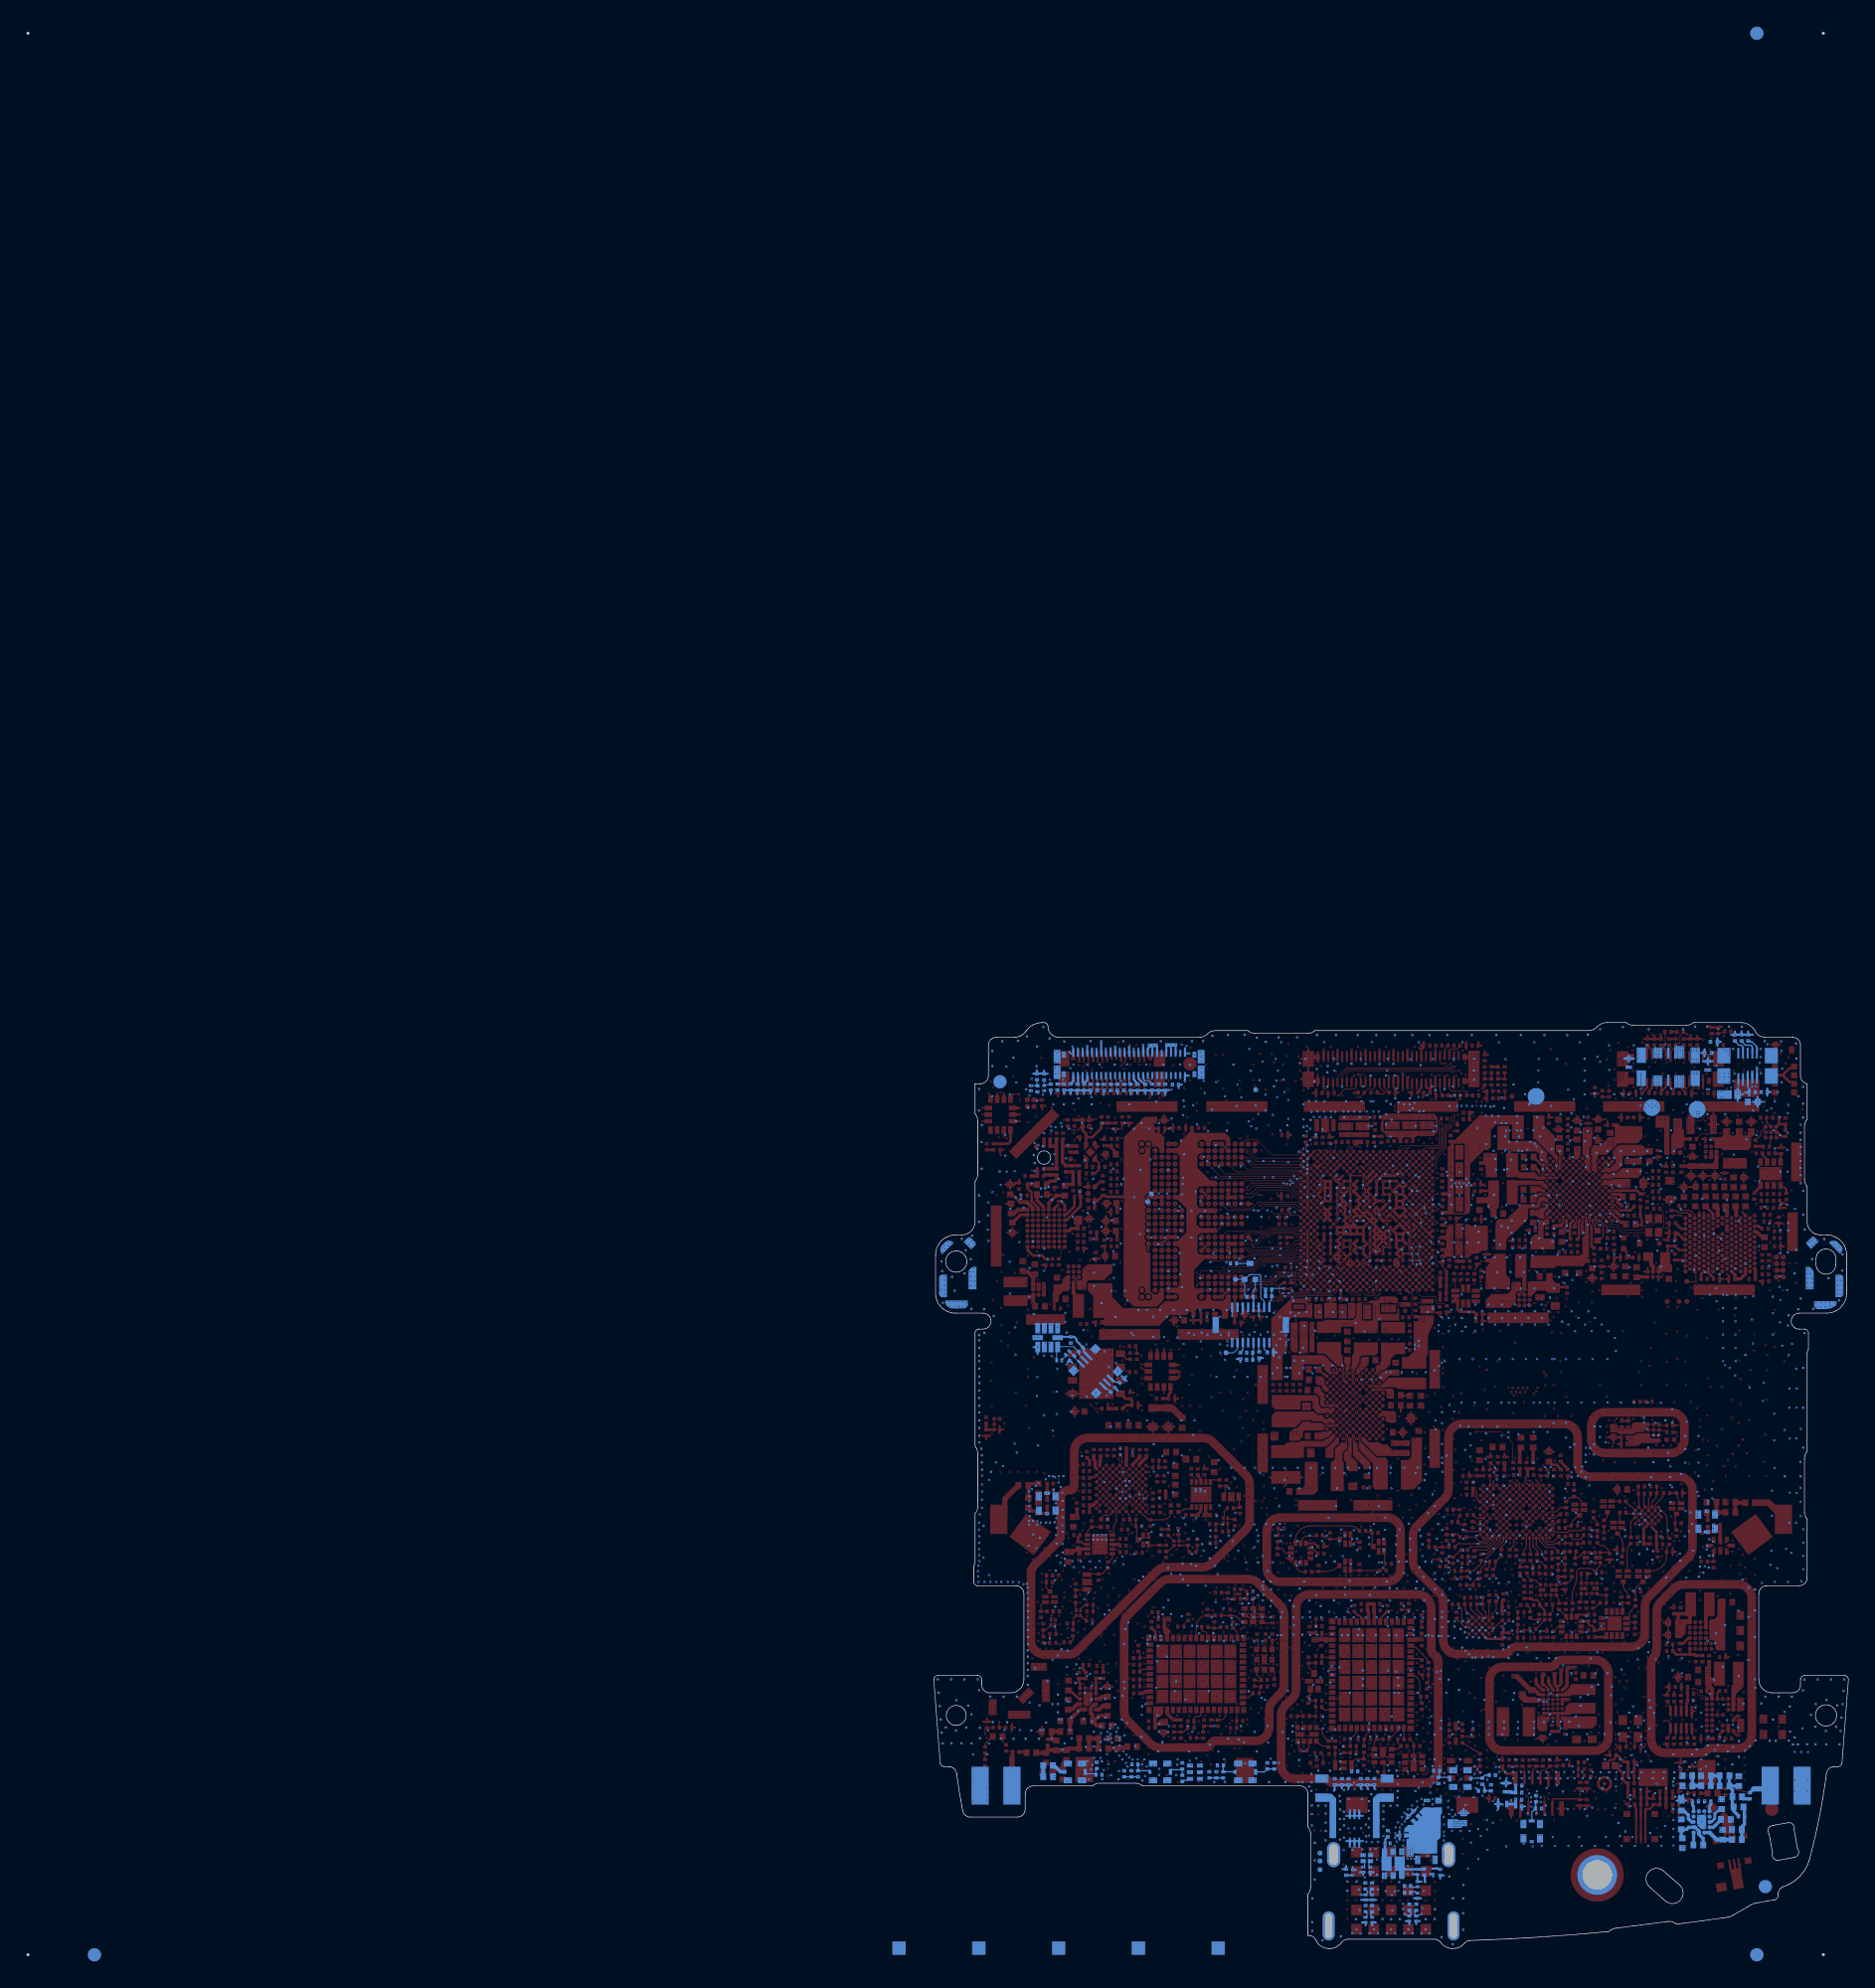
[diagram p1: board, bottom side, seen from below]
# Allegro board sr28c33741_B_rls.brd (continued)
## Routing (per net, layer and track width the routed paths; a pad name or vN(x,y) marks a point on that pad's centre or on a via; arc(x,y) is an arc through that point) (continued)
UNNAMED_24_CAPACITOR_I151_B: length 2.5
  TOP w0.2: R7730.1 15.39,30.44 C7753.2 C7755.2 15.4,31.57 U7701.D1 U7701.E2
UNNAMED_24_CAPACITOR_I157_B: length 1.6
  TOP w0.088: C7761.2 L7708.2 15.76,34.18 U7701.G6
UNNAMED_24_CAPACITOR_I159_B: length 1.7
  TOP w0.088: 14.77,33.18 14.77,33.58 14.46,33.89 14.46,34.18 L7703.2 14.41,34.74 C7760.2
UNNAMED_24_INDUCTOR_I148_A: length 1.1
  TOP w0.088: L7708.1 15.39,34.16 15.39,33.3 U7701.E6
UNNAMED_24_INDUCTOR_I153_A: length 1.4
  TOP w0.088: U7701.D5 15.02,33.81 14.92,33.91 14.92,34.17 L7703.1
UNNAMED_27_CAPACITOR_I33_B: length 0.4
  TOP w0.1: R7153.2 C7155.2
UNNAMED_27_CAPACITOR_I39_B: length 0.5
  TOP w0.2: C7157.2 40.51,23.74 R7156.2
UNNAMED_27_CAPACITOR_I115_A: length 0.5
  TOP w0.088: L7183.2 37.93,14.72 C7182.1
UNNAMED_28_INDUCTOR_I29_A: length 1
  TOP w0.1: v1(37.72,38.53) 37.72,38.17 37.77,38.13
  LAYER_2 w0.175: v1(37.72,38.53) 37.72,38.09 v1(37.8,38.02)
UNNAMED_28_INDUCTOR_I42_A: length 0.8
  TOP w0.1: 36.73,38.17 36.73,38.52 v1(36.73,38.53)
  LAYER_2 w0.175: v1(36.73,38.53) v1(36.73,38.06)
USB_AUD_SW_SEL: length 7.4
  TOP w0.05: v2(28.13,49.98) R520.2
  LAYER_2 w0.045: v4(30.54,51.23) 31.02,51.7 31.34,51.7 31.4,51.64 31.6,51.64 31.72,51.76 v1(31.97,51.76) ; v2(28.13,49.98) 27.9,49.76 27.9,48.78 v1(28.01,48.67)
  LAYER_3 w0.045: v4(28.88,49.5) 28.84,49.5 28.61,49.73 28.38,49.73 v2(28.13,49.98)
  LAYER_5 w0.045: v4(28.88,49.5) 28.88,49.65 28.94,49.72 28.94,50.04 28.96,50.05 28.96,50.7 29.2,50.95 29.66,50.95 29.81,51.1 30.42,51.1 v4(30.54,51.23)
USB_AUDIO_DET_N: length 27.4
  LAYER_3 w0.045: v6(12.72,52.61) 12.7,52.63 12.7,52.8 11.74,53.76 11.74,54.21 11.65,54.3 11.48,54.3 11.28,54.5 10.89,54.5 v2(10.87,54.52)
  LAYER_7 w0.045: v6(12.72,52.61) 12.89,52.78 21.08,52.78 21.41,53.11 21.41,53.42 20.93,53.9 20.93,54.63 20.82,54.73 20.82,55.11 21.5,55.79 21.5,56.2 21.66,56.36 26.8,56.36 29.18,58.74 30.72,58.74 31.08,58.38 31.85,58.38 v6(32.06,58.17)
USB_EN: length 34.7
  LAYER_2 w0.045: v1(18.23,57.21) 18,56.98 15.94,56.98 15.61,57.31 14.45,57.31 v6(14.41,57.35)
  LAYER_3 w0.045: v6(7.64,44.05) 7.7,43.98 7.7,42.59 8.38,41.92 8.38,39.76 11.02,37.12 11.97,37.12 12.39,37.54 12.39,37.64 13.01,38.26 v2(13.11,38.26) 13.32,38.47 13.49,38.47 13.62,38.6 13.85,38.6 v2(14.65,39.4)
  LAYER_7 w0.045: v6(7.64,44.05) 7.45,44.24 7.45,48.99 7.19,49.25 7.19,51.36 8.25,52.43 9.26,52.43 12.1,55.26 13.1,55.26 14.41,56.57 v6(14.41,57.35)
USB_HPOUT1L: length 25.7
  TOP w0.1: U6250.A15 12.11,55.33 12.77,55.33 12.93,55.49 v2(13.27,55.49)
  LAYER_3 w0.045: v2(13.27,55.49) 13.11,55.49 12.94,55.33 12.94,54.97 12.64,54.67 12.64,53.88 13.71,52.81 13.93,52.81 15.62,51.12 15.62,50.45 19.34,46.73 21.53,46.73 v6(21.6,46.8) ; v6(28.66,47.21) 28.66,47.35 28.29,47.72 28.29,48.47 28.53,48.71 28.53,49.11 v2(28.23,49.41)
  LAYER_7 w0.045: v6(28.66,47.21) 28.66,47.19 28.61,47.14 28.07,47.14 27.65,46.72 21.68,46.72 v6(21.6,46.8)
USB_HPOUT1R: length 26.6
  TOP w0.088: v2(12.75,55.82) 12.68,55.75 12.68,55.64 12.56,55.52 12,55.52 11.9,55.42 11.79,55.42 11.56,55.19 U6250.B14
  LAYER_3 w0.045: v2(12.75,55.82) 12.85,55.72 12.85,55.01 12.54,54.7 12.54,53.83 13.67,52.7 13.89,52.7 15.52,51.07 15.52,50.4 19.29,46.63 21.53,46.63 v6(21.6,46.56) ; v2(28.52,49.42) 28.63,49.31 28.63,48.67 28.38,48.43 28.38,47.77 28.82,47.33 28.82,47.12 28.68,46.98 v6(28.66,46.98)
  LAYER_7 w0.045: v6(28.66,46.98) 28.66,47.02 28.64,47.04 28.12,47.04 27.7,46.62 21.66,46.62 v6(21.6,46.56)
USB_HS_C_DM: length 45.4
  LAYER_5 w0.045: v4(28.64,48.29) 28.73,48.2 28.73,47.99 29,47.72 29,35.75 35.81,28.94 35.81,26.24 34.87,25.3 34.87,17.44 36.5,15.81 36.5,7.93 36.2,7.63 36.2,7.23 v7(36.05,7.08)
USB_HS_C_DP: length 45.4
  LAYER_5 w0.045: v7(36.39,7.08) 36.3,7.17 36.3,7.59 36.6,7.89 36.6,15.85 34.97,17.48 34.97,25.26 35.91,26.2 35.91,28.98 29.1,35.79 29.1,47.76 28.83,48.03 28.83,48.2 v4(28.92,48.29)
USB_HS_DM: length 5
  TOP w0.05: U520.1 29.08,49.73 29.08,49.92 29.24,50.09 29.24,50.19 R2402.1
  LAYER_3 w0.045: v2(32.06,50.77) 32.25,50.58 32.25,50.17 31.89,49.81 31.65,49.81 31.6,49.86 30.68,49.86 30.48,50.06 30.15,50.06 29.78,50.43 29.37,50.43 v2(29.2,50.26)
USB_HS_DM_DET: length 15.8
  LAYER_3 w0.045: v4(21.79,51.69) 21.79,51.61 22.74,50.65 27.95,50.65 28.08,50.52 29.02,50.52 v2(29.21,50.71)
  LAYER_5 w0.045: v4(19.75,58.24) 19.51,58 19.51,57.14 20.08,56.58 20.08,54.3 20.7,53.68 21.05,53.68 21.31,53.42 21.31,52.3 21.69,51.92 21.69,51.79 v4(21.79,51.69)
USB_HS_DP: length 4.8
  TOP w0.05: 29.54,49.47 29.54,49.75 29.58,49.78 v2(29.58,50.26)
  LAYER_3 w0.045: v2(32.26,50.97) 32.35,50.88 32.35,50.13 31.98,49.76 31.97,49.76 31.93,49.72 31.61,49.72 31.57,49.76 30.59,49.76 30.41,49.94 30.13,49.94 29.81,50.26 v2(29.58,50.26)
USB_HS_DP_DET: length 16.4
  LAYER_3 w0.045: v2(29.58,50.72) 29.43,50.87 29.14,50.87 29.05,50.78 29.05,50.7 28.97,50.62 28.11,50.62 27.98,50.75 22.78,50.75 21.95,51.58 21.95,51.82 v4(21.85,51.92)
  LAYER_5 w0.045: v4(19.97,58.47) 19.94,58.44 19.94,58.19 19.61,57.86 19.61,57.19 20.18,56.62 20.18,54.34 20.74,53.78 21.08,53.78 21.41,53.45 21.41,52.36 v4(21.85,51.92)
USB_MIC_DM: length 77.1
  LAYER_3 w0.045: v2(11.21,54.32) 10.93,54.32 10.2,53.59 10.2,53.45 9.57,52.81 9.39,52.81 7.78,51.2 7.18,51.2 6.97,51.41 5.99,51.41 5.86,51.28 5.86,51.09 6.01,50.93 v4(6.01,50.76)
  LAYER_5 w0.15: v4(34.7,7.56) 34.7,7.72 v7(34.83,7.86) 34.96,7.73 34.96,5.98 34.71,5.73 31.81,5.73 31.06,4.98 29.77,4.98 28.57,6.19 28.57,6.96 25.23,10.29 22.52,10.29 21.45,11.36 17.5,11.36 15.34,13.52 15.34,14.45 9.45,20.34 9.45,20.66 9.33,20.78 9.33,34.76 7.07,37.02 7.07,37.03 7.04,37.06 7.04,47.71 7.07,47.74 7.07,48.32 6.29,49.09 6.29,50.3 6.01,50.58 v4(6.01,50.76)
  BOTTOM w0.15: R6267.1 34.82,8.22 34.82,7.94 D505.2
  BOTTOM w0.2: Q6268.3 34.85,7.32 D505.2
  BOTTOM w0.4: Q6268.3 34.89,6.54 Q6268.8
USB_MIC_DP: length 74.1
  LAYER_3 w0.045: v4(6.02,51.21) 6.12,51.31 6.92,51.31 7.12,51.11 7.82,51.11 9.44,52.72 9.61,52.72 10.3,53.41 10.3,53.56 10.86,54.12 v2(11.56,54.12)
  LAYER_5 w0.15: v4(34.08,5.97) 34.06,5.95 v7(32.42,5.95) 31.75,5.95 30.98,5.18 29.85,5.18 28.77,6.27 28.77,7.04 25.32,10.49 22.61,10.49 21.54,11.56 17.58,11.56 15.54,13.61 15.54,14.36 15.54,14.53 9.65,20.42 9.65,20.74 9.53,20.86 9.53,34.67 9.53,34.67 9.53,34.84 9.48,34.89 9.48,34.9 7.24,37.14 7.24,47.63 7.27,47.66 7.27,48.41 6.49,49.18 6.49,50.41 6.23,50.68 6.23,51 v4(6.02,51.21)
  BOTTOM w0.175: R6266.1 31.93,5.96 32.4,5.96 D506.2 v7(32.42,5.95) 33.53,5.95 33.59,6.01
  BOTTOM w0.4: Q6268.7 33.59,6.22 Q6268.6
USB_PHY_PS: length 19.3
  LAYER_3 w0.045: v2(32.51,52.21) 32.05,52.21 31.6,52.66 28.45,52.66 28.1,52.31 27.76,52.31 26.92,51.47 23.2,51.47 22.45,52.22 22.45,52.9 22,53.35 22,54.01 21.45,54.55 21.45,54.81 21.77,55.13 21.77,55.55 22.06,55.83 22.06,56.4 22.1,56.45 22.1,56.59 22,56.69 21.48,56.69 20.33,57.84 20.33,58.29 20.23,58.39 v2(20.23,58.74)
USB_PWR:
  vias: v1(16.27,38.5) v1(16.27,38.32) v1(16.27,38.06) v1(16.27,37.88) v1(16.45,38.5) v1(16.45,38.32) v1(16.45,38.06) v1(16.45,37.88) v1(16.63,38.5) v1(16.63,38.32) v1(16.63,38.06) v1(16.63,37.88) v2(16.27,38.5) v2(16.27,38.32) v2(16.27,38.06) v2(16.27,37.88) v2(16.45,38.5) v2(16.45,38.32) v2(16.45,38.06) v2(16.45,37.88) v2(16.63,38.5) v2(16.63,38.32) v2(16.63,38.06) v2(16.63,37.88) v3(16.27,38.5) v3(16.27,38.32) v3(16.27,38.06) v3(16.27,37.88) v3(16.45,38.5) v3(16.45,38.32) v3(16.45,38.06) v3(16.45,37.88) v3(16.63,38.5) v3(16.63,38.32) v3(16.63,38.06) v3(16.63,37.88) v4(16.27,38.5) v4(16.27,38.32) v4(16.27,38.06) v4(16.27,37.88) v4(16.45,38.5) v4(16.45,38.32) v4(16.45,38.06) v4(16.45,37.88) v4(16.63,38.5) v4(16.63,38.32) v4(16.63,38.06) v4(16.63,37.88) v5(28.77,9.56) v5(28.77,9.38) v5(28.95,9.56) v5(28.95,9.38) v5(29.13,9.56) v5(29.13,9.38) v5(29.13,9.2) v5(29.31,9.56) v5(29.31,9.38) v5(29.31,9.2) v5(29.49,9.56) v5(29.49,9.38) v5(29.49,9.2) v5(29.67,9.56) v5(29.67,9.38) v5(29.67,9.2) v6(28.77,9.56) v6(28.77,9.38) v6(28.95,9.56) v6(28.95,9.38) v6(29.13,9.56) v6(29.13,9.38) v6(29.13,9.2) v6(29.31,9.56) v6(29.31,9.38) v6(29.31,9.2) v6(29.49,9.56) v6(29.49,9.38) v6(29.49,9.2) v6(29.67,9.56) v6(29.67,9.38) v6(29.67,9.2) v7(28.77,9.56) v7(28.77,9.38) v7(28.95,9.56) v7(28.95,9.38) v7(29.13,9.56) v7(29.13,9.38) v7(29.13,9.2) v7(29.31,9.56) v7(29.31,9.38) v7(29.31,9.2) v7(29.49,9.56) v7(29.49,9.38) v7(29.49,9.2) v7(29.67,9.56) v7(29.67,9.38) v7(29.67,9.2)
USB_SNS: length 34.1
  TOP w0.075: U2401.C5 14.19,38.94 13.76,38.94 C2418.2
  LAYER_2 w0.045: v6(14.59,57.15) 14.65,57.21 15.57,57.21 15.91,56.87 18.05,56.87 18.23,57.05 18.32,57.05 18.48,57.21 v1(18.73,57.21)
  LAYER_3 w0.045: v2(13.64,38.78) 13.64,38.77 13.46,38.59 13.21,38.59 12.3,37.68 12.3,37.58 11.93,37.22 11.05,37.22 8.47,39.8 8.47,41.95 7.8,42.63 7.8,44.12 v6(7.64,44.28)
  LAYER_7 w0.045: v6(7.64,44.28) 7.55,44.37 7.55,49.04 7.29,49.3 7.29,51.33 8.29,52.33 9.3,52.33 12.13,55.16 13.14,55.16 14.52,56.54 14.52,57.08 v6(14.59,57.15)
USB_VBUS_CONN:
  vias: v1(32.78,7.56) v1(32.78,7.38) v1(32.78,7.2) v1(32.78,7.02) v1(32.79,6.11) v1(32.79,5.91) v1(32.79,5.71) v1(32.96,7.56) v1(32.96,7.38) v1(32.96,7.2) v1(32.96,7.02) v1(32.99,6.11) v1(32.99,5.91) v1(32.99,5.71) v1(33.14,7.56) v1(33.14,7.38) v1(33.14,7.2) v1(33.14,7.02) v1(33.19,6.11) v1(33.19,5.91) v1(33.19,5.71) v1(35.39,7.56) v1(35.39,7.36) v1(35.39,7.16) v1(35.39,6.11) v1(35.39,5.91) v1(35.39,5.71) v1(35.59,7.56) v1(35.59,7.36) v1(35.59,7.16) v1(35.59,6.11) v1(35.59,5.91) v1(35.59,5.71) v1(35.79,7.56) v1(35.79,7.36) v1(35.79,7.16) v1(35.79,6.11) v1(35.79,5.91) v1(35.79,5.71) v2(32.78,7.56) v2(32.78,7.38) v2(32.78,7.2) v2(32.78,7.02) v2(32.79,6.11) v2(32.79,5.91) v2(32.79,5.71) v2(32.96,7.56) v2(32.96,7.38) v2(32.96,7.2) v2(32.96,7.02) v2(32.99,6.11) v2(32.99,5.91) v2(32.99,5.71) v2(33.14,7.56) v2(33.14,7.38) v2(33.14,7.2) v2(33.14,7.02) v2(33.19,6.11) v2(33.19,5.91) v2(33.19,5.71) v2(35.39,7.56) v2(35.39,7.36) v2(35.39,7.16) v2(35.39,6.11) v2(35.39,5.91) v2(35.39,5.71) v2(35.59,7.56) v2(35.59,7.36) v2(35.59,7.16) v2(35.59,6.11) v2(35.59,5.91) v2(35.59,5.71) v2(35.79,7.56) v2(35.79,7.36) v2(35.79,7.16) v2(35.79,6.11) v2(35.79,5.91) v2(35.79,5.71) v3(32.78,7.56) v3(32.78,7.38) v3(32.78,7.2) v3(32.78,7.02) v3(32.96,7.56) v3(32.96,7.38) v3(32.96,7.2) v3(32.96,7.02) v3(33.14,7.56) v3(33.14,7.38) v3(33.14,7.2) v3(33.14,7.02) v4(32.78,7.56) v4(32.78,7.38) v4(32.78,7.2) v4(32.78,7.02) v4(32.96,7.56) v4(32.96,7.38) v4(32.96,7.2) v4(32.96,7.02) v4(33.14,7.56) v4(33.14,7.38) v4(33.14,7.2) v4(33.14,7.02) v5(32.78,7.56) v5(32.78,7.38) v5(32.78,7.2) v5(32.78,7.02) v5(32.96,7.56) v5(32.96,7.38) v5(32.96,7.2) v5(32.96,7.02) v5(33.14,7.56) v5(33.14,7.38) v5(33.14,7.2) v5(33.14,7.02) v6(32.78,7.56) v6(32.78,7.38) v6(32.78,7.2) v6(32.78,7.02) v6(32.96,7.56) v6(32.96,7.38) v6(32.96,7.2) v6(32.96,7.02) v6(33.14,7.56) v6(33.14,7.38) v6(33.14,7.2) v6(33.14,7.02) v7(32.78,7.56) v7(32.78,7.38) v7(32.78,7.2) v7(32.78,7.02) v7(32.96,7.56) v7(32.96,7.38) v7(32.96,7.2) v7(32.96,7.02) v7(33.14,7.56) v7(33.14,7.38) v7(33.14,7.2) v7(33.14,7.02)
USB_VBUS_IN: length 3.2
  LAYER_2 w0.18: v4(16.47,57.32) v4(16.47,57.5) v4(16.65,57.5) v4(16.83,57.5) v4(16.83,57.32) v4(16.65,57.32) v4(16.47,57.32)
  LAYER_3 w0.18: v4(16.65,57.5) v4(16.47,57.5) v4(16.47,57.32) v4(16.65,57.32) v4(16.83,57.32) v4(16.83,57.5) v4(16.65,57.5)
  LAYER_4 w0.18: v4(16.65,57.5) v4(16.47,57.5) v4(16.47,57.32) v4(16.65,57.32) v4(16.83,57.32) v4(16.83,57.5) v4(16.65,57.5)
  vias: v1(16.48,39.21) v1(16.48,39.03) v1(16.66,39.21) v1(16.66,39.03) v1(16.98,39.21) v1(16.98,39.03) v1(17.16,39.21) v1(17.16,39.03) v1(17.51,39.35) v1(17.51,39.17) v1(17.51,38.99) v2(16.48,39.21) v2(16.48,39.03) v2(16.66,39.21) v2(16.66,39.03) v2(16.98,39.21) v2(16.98,39.03) v2(17.16,39.21) v2(17.16,39.03) v2(17.51,39.35) v2(17.51,39.17) v2(17.51,38.99) v3(16.48,39.21) v3(16.48,39.03) v3(16.66,39.21) v3(16.66,39.03) v3(16.98,39.21) v3(16.98,39.03) v3(17.16,39.21) v3(17.16,39.03) v3(17.51,39.35) v3(17.51,39.17) v3(17.51,38.99) v4(16.48,39.21) v4(16.48,39.03) v4(16.66,39.21) v4(16.66,39.03) v4(16.98,39.21) v4(16.98,39.03) v4(17.16,39.21) v4(17.16,39.03) v4(17.51,39.35) v4(17.51,39.17) v4(17.51,38.99)
USBC_CC1: length 82.7
  TOP w0.175: U500.6 31.54,6.05 v7(30.98,6.05)
  LAYER_3 w0.15: v4(25.97,15.2) 23.61,15.2 23.44,15.37 18.9,15.37 17.51,16.76 15.66,16.76 15.18,17.24 v6(15.18,17.36)
  LAYER_5 w0.15: v4(25.97,15.2) 26.42,15.2 28.72,12.9 28.72,12.18 30.96,9.94 30.96,6.4 30.66,6.1 v7(30.66,6)
  LAYER_7 w0.15: v6(15.18,17.36) 15.04,17.22 10.86,17.22 7.74,20.33 7.74,27.31 5.07,29.99 5.07,40.87 8.04,43.84 8.04,49.08 7.62,49.5 7.62,50.92 8.28,51.58 9.72,51.58 12.43,54.29 13.35,54.29 16.97,57.91 18.13,57.91 19.54,59.32 19.79,59.32 v6(19.91,59.44)
  BOTTOM w0.15: D516.2 31.03,6 v7(30.98,6.05) 30.93,6 v7(30.66,6) C522.2
USBC_CC2: length 88.5
  LAYER_3 w0.15: v6(14.94,17.44) 14.95,17.43 14.95,17.18 15.57,16.56 17.42,16.56 18.81,15.17 23.34,15.17 23.54,14.97 v4(25.98,14.97) ; v7(37.78,5.51) 37.49,5.8 36.98,5.8 36.46,5.28 31.11,5.28 30.74,5.65 v4(30.74,6.49)
  LAYER_5 w0.15: v4(30.74,6.49) 30.74,9.87 28.52,12.09 28.52,12.81 26.36,14.97 v4(25.98,14.97)
  LAYER_7 w0.15: v6(19.96,59) 19.85,59.11 19.61,59.11 18.21,57.71 17.06,57.71 13.43,54.08 12.51,54.08 9.81,51.38 8.37,51.38 7.83,50.84 7.83,49.6 8.24,49.19 8.24,43.74 5.27,40.77 5.27,30.08 7.95,27.4 7.95,20.44 10.95,17.44 v6(14.94,17.44)
  BOTTOM w0.15: v7(37.78,5.51) v7(37.28,5.51)
USBC_DM: length 4.3
  LAYER_7 w0.045: v6(34.67,4.04) 34.67,3.72 34.71,3.67 34.77,3.67 35.07,3.96 35.07,4.77 35.79,5.49 36.05,5.49 36.19,5.63 36.19,5.89 v7(35.95,6.12)
  BOTTOM w0.088: FL500.1 36.05,6.47 36.05,6.21 v7(35.95,6.12)
USBC_DP: length 4.4
  LAYER_7 w0.045: v7(36.48,6.12) 36.28,5.92 36.28,5.59 36.08,5.39 35.82,5.39 35.16,4.73 35.16,3.93 34.81,3.58 34.71,3.58 34.67,3.53 v6(34.67,3.21)
  BOTTOM w0.088: v7(36.48,6.12) 36.39,6.21 36.39,6.47 FL500.2
USBC_RX1_DM: length 54.2
  LAYER_5 w0.045: v4(31.47,51.3) 31.4,51.23 31.4,51.15 30.95,50.7 30.38,50.7 29.42,49.75 29.42,35.87 36.22,29.08 36.22,26.08 35.29,25.15 35.29,17.59 36.89,15.99 36.89,6.89 35.81,5.81 35.81,5.53 34.96,4.69 33.92,4.69 33.65,4.42 33.5,4.42 v7(33.36,4.27)
USBC_RX1_DP: length 54.6
  LAYER_5 w0.045: v7(33.35,4.68) 33.51,4.52 33.61,4.52 33.88,4.79 34.92,4.79 35.71,5.57 35.71,5.85 36.79,6.93 36.79,15.95 35.19,17.55 35.19,25.19 36.12,26.12 36.12,29.04 29.32,35.83 29.32,49.79 30.33,50.8 30.91,50.8 31.29,51.18 31.29,51.36 31.4,51.47 31.76,51.47 v4(31.77,51.46)
USBC_RX2_DM: length 52.4
  LAYER_5 w0.045: v7(35.81,3.23) 36.03,3.45 36.03,4.23 36.53,4.74 36.53,5.51 37.61,6.59 37.61,16.48 36.18,17.91 36.18,24.82 37.06,25.7 37.06,29.43 30.23,36.26 30.23,48.74 31.59,50.1 31.59,50.12 31.75,50.28 v4(31.97,50.28)
USBC_RX2_DP: length 52
  LAYER_5 w0.045: v4(31.79,50.07) 31.74,50.03 31.66,50.03 30.33,48.7 30.33,36.3 37.16,29.47 37.16,25.66 36.28,24.78 36.28,17.95 37.71,16.52 37.71,6.54 36.63,5.46 36.63,4.7 36.13,4.19 36.13,3.41 v7(36.31,3.23)
USBC_TX1_DM: length 55.5
  LAYER_5 w0.045: v4(31.78,51.07) 31.78,50.92 31.57,50.71 31.46,50.71 30.86,50.12 30.5,50.12 29.69,49.31 29.69,36.07 36.54,29.22 36.54,25.87 35.65,24.98 35.65,17.67 37.16,16.16 37.16,6.75 36.07,5.65 36.07,5.42 35.05,4.4 34.42,4.4 33.66,3.64 32.87,3.64 32.8,3.57 32.8,3.45 v7(32.96,3.29)
USBC_TX1_DP: length 55.8
  LAYER_5 w0.045: v7(32.55,3.3) 32.7,3.45 32.7,3.61 32.82,3.74 33.61,3.74 34.38,4.5 35.01,4.5 35.97,5.46 35.97,5.69 37.06,6.79 37.06,16.11 35.55,17.63 35.55,25.02 36.44,25.91 36.44,29.18 29.59,36.03 29.59,49.35 30.46,50.22 30.82,50.22 31.59,50.99 31.59,51.13 31.7,51.25 v4(31.96,51.25)
USBC_TX2_DM: length 50.9
  LAYER_5 w0.045: v4(31.74,50.49) 31.46,50.49 31.27,50.29 31.27,50.19 29.92,48.83 29.92,36.13 36.74,29.3 36.74,25.78 35.88,24.92 35.88,17.76 37.34,16.3 37.34,6.68 36.23,5.57 36.23,5.28 36.02,5.07 36.02,4.96 35.95,4.9 v7(35.88,4.9)
USBC_TX2_DP: length 50.4
  LAYER_5 w0.045: v4(31.5,50.27) 30.02,48.79 30.02,36.17 36.84,29.35 36.84,25.74 35.98,24.88 35.98,17.8 37.44,16.34 37.44,6.64 36.33,5.53 36.33,5.24 36.12,5.03 36.12,4.95 36.17,4.9 v7(36.27,4.9)
VCONN_EN: length 13.9
  LAYER_3 w0.045: v4(13.77,61.05) 13.77,61.3 13.94,61.47 14.08,61.47 14.24,61.31 14.24,60.83 14.1,60.69 14.1,60.15 v2(14.28,59.97) 14.08,59.78 14.08,59.51 14.65,58.95 16.97,58.95 17.63,58.3 19.11,58.3 19.13,58.32 19.35,58.32 19.62,58.06 19.81,58.06 19.96,58.21 v2(20.16,58.21) ; v2(10.33,60.32) 10.33,60.82 v4(10.53,61.02)
  LAYER_5 w0.045: v4(13.77,61.05) 12.92,61.05 12.64,60.76 12.06,60.76 11.92,60.9 10.65,60.9 v4(10.53,61.02)
VCONN_IN: length 16.3
  TOP w0.25: v2(12.56,58.84) C2295.2
  TOP w0.3: U2210.A2 U2210.A1 9.93,59.14 10.03,59.04 C2296.2
  TOP w0.4: C2295.2 C2279.2 C2296.2
  LAYER_2 w0.3: v2(12.89,60.03) 13.31,60.03 13.71,60.43 14.55,60.43 v2(14.78,60.67) ; v2(19.8,60.29) 19.8,60.02 20.21,59.6 v1(20.21,59.19)
  LAYER_3 w0.3: v2(12.56,58.84) 12.56,59.3 12.89,59.63 v2(12.89,60.03)
  LAYER_3 w0.4: v2(14.78,60.67) 16.26,60.67 17.55,61.96 19.04,61.96 19.11,62.03 20.02,62.03 20.4,61.65 v2(20.4,61.51)
  LAYER_3 w0.5: v2(19.8,60.29) 19.8,60.57 20.4,61.17 v2(20.4,61.51)
VDISP_M_OUT: length 64.1
  LAYER_2 w0.175: v2(38.95,37.29) v2(39.15,37.29)
  LAYER_3 w0.045: v2(38.71,39.02) 38.71,37.52 v2(38.95,37.29)
  LAYER_3 w0.175: v2(39.15,37.29) v2(38.95,37.29)
  LAYER_3 w0.4: 39.14,37.34 39.18,37.3
  LAYER_3 w0.5: v6(60.55,40.56) 58.89,40.56 58.29,39.95 56.88,39.95 56.49,40.35 48.75,40.35 45.55,37.15 39.33,37.15 39.18,37.3
  LAYER_4 w0.175: v6(60.67,40.7) v6(60.43,40.7) v6(60.55,40.56) v6(60.67,40.7)
  LAYER_5 w0.175: v6(60.55,40.56) v6(60.67,40.7) v6(60.43,40.7) v6(60.55,40.56)
  LAYER_6 w0.175: v6(51.64,63.18) v6(51.8,63.27) v6(51.8,63.09) v6(51.64,63.18) ; v6(60.43,40.7) v6(60.55,40.56) v6(60.67,40.7) v6(60.43,40.7)
  LAYER_7 w0.175: v6(60.67,40.7) v6(60.55,40.56) v6(60.43,40.7)
  LAYER_7 w0.5: v6(60.55,40.56) 60.55,43.21 62.2,44.86 62.2,46.94 62.62,47.36 62.62,51.87 64.05,53.29 64.05,56.48 62.24,58.29 62.24,60.92 60.09,63.06 51.7,63.06
  BOTTOM w0.15: v7(52.57,67.93) 52.57,67.79 52.69,67.67 J5300.34 ; J5300.36 52.34,67.91 v7(52.32,67.93) ; J5300.38 51.99,67.81 v7(52.11,67.93)
  vias: v5(51.36,65) v6(51.36,65) v7(51.36,65)
VDISP_P_MID: length 2.9
  TOP w0.25: U2400.88 37.48,37.31
  LAYER_2 w0.175: v1(37.48,38.78) v1(37.48,36.93)
VDISP_P_OUT: length 68.2
  TOP w0.1: v1(37.13,38.04) 37.23,38.14 37.23,38.53 v1(37.23,38.53)
  TOP w0.25: v1(37.13,38.04) 37.13,37.55
  LAYER_2 w0.175: v2(36.82,36.92) v2(36.82,36.74) ; v1(37.23,38.53) 37.23,38.14 v1(37.13,38.04)
  LAYER_3 w0.045: v2(36.82,36.92) 36.82,37.12 v2(38.25,38.55)
  LAYER_3 w0.175: v2(36.82,36.92) v2(36.82,36.74)
  LAYER_3 w0.5: v2(36.82,36.92) 37.15,36.59 45.78,36.59 48.99,39.8 56.22,39.8 56.61,39.4 58.53,39.4 59.11,39.98 v6(59.97,39.98)
  LAYER_4 w0.175: v6(59.86,40.12) v6(59.84,39.87) v6(59.97,39.98) v6(59.86,40.12)
  LAYER_5 w0.175: v6(59.86,40.12) v6(59.84,39.87) v6(59.97,39.98) v6(59.86,40.12)
  LAYER_6 w0.175: v6(59.97,39.98) v6(59.86,40.12) v6(59.84,39.87) v6(59.97,39.98) ; v6(50.93,63.1) v6(51.02,63.26) v6(51.12,63.1) v6(50.93,63.1)
  LAYER_7 w0.175: v6(59.84,39.87) v6(59.97,39.98) v6(59.86,40.12)
  LAYER_7 w0.5: 51.13,62.79 51.42,62.5 59.87,62.5 61.69,60.69 61.69,58.04 63.48,56.25 63.48,53.53 62.03,52.09 62.03,47.61 61.63,47.2 61.63,45.09 59.97,43.43 v6(59.97,39.98)
  BOTTOM w0.15: J5300.44 v7(50.94,67.96) ; J5300.42 51.29,67.94 v7(51.28,67.95) ; J5300.46 v7(50.59,67.97)
  vias: v5(50.83,64.97) v6(50.83,64.97) v7(50.83,64.97)
VPA_APT: length 3.1
  TOP w0.1: C7154.2 R7153.1 ; 39.58,23.3 39.58,23.23
  TOP w0.2: C7158.2 39.58,23.3 39.58,23.74
  LAYER_2 w0.175: v4(21.87,17.28) v4(21.95,17.11) v4(21.77,17.11) v4(21.87,17.28)
  LAYER_3 w0.175: v4(21.77,17.11) v4(21.95,17.11) v4(21.87,17.28) v4(21.77,17.11)
  LAYER_4 w0.175: v4(21.95,17.11) v4(21.87,17.28) v4(21.77,17.11) v4(21.95,17.11)
  LAYER_6 w0.175: v6(21.69,17.5) v6(21.87,17.5) v6(22.05,17.5)
  vias: v1(31.97,23.19) v1(32.05,23.34) v1(32.23,23.34) v1(32.15,23.19) v1(32.33,23.19) v1(32.41,23.34) v1(39.91,23.31) v1(39.91,23.13) v1(40.09,23.31) v1(40.09,23.13) v1(40.27,23.31) v1(40.27,23.13) v1(51.04,24.85) v1(51.04,24.67) v1(51.21,24.85) v1(51.21,24.67) v1(51.39,24.85) v1(51.39,24.67) v2(31.97,23.19) v2(32.05,23.34) v2(32.23,23.34) v2(32.15,23.19) v2(32.33,23.19) v2(32.41,23.34) v2(39.91,23.31) v2(39.91,23.13) v2(40.09,23.31) v2(40.09,23.13) v2(40.27,23.31) v2(40.27,23.13) v2(51.04,24.85) v2(51.04,24.67) v2(51.21,24.85) v2(51.21,24.67) v2(51.39,24.85) v2(51.39,24.67) v3(31.97,23.19) v3(32.05,23.34) v3(32.23,23.34) v3(32.15,23.19) v3(32.33,23.19) v3(32.41,23.34) v3(39.91,23.31) v3(39.91,23.13) v3(40.09,23.31) v3(40.09,23.13) v3(40.27,23.31) v3(40.27,23.13) v3(51.04,24.85) v3(51.04,24.67) v3(51.21,24.85) v3(51.21,24.67) v3(51.39,24.85) v3(51.39,24.67) v4(31.97,23.19) v4(32.05,23.34) v4(32.23,23.34) v4(32.15,23.19) v4(32.33,23.19) v4(32.41,23.34) v4(39.91,23.31) v4(39.91,23.13) v4(40.09,23.31) v4(40.09,23.13) v4(40.27,23.31) v4(40.27,23.13) v4(51.04,24.85) v4(51.04,24.67) v4(51.21,24.85) v4(51.21,24.67) v4(51.39,24.85) v4(51.39,24.67) v5(31.97,23.19) v5(32.05,23.34) v5(32.23,23.34) v5(32.15,23.19) v5(32.33,23.19) v5(32.41,23.34) v5(39.91,23.31) v5(39.91,23.13) v5(40.09,23.31) v5(40.09,23.13) v5(40.27,23.31) v5(40.27,23.13) v5(51.04,24.85) v5(51.04,24.67) v5(51.21,24.85) v5(51.21,24.67) v5(51.39,24.85) v5(51.39,24.67) v6(31.97,23.19) v6(32.05,23.34) v6(32.23,23.34) v6(32.15,23.19) v6(32.33,23.19) v6(32.41,23.34) v6(39.91,23.31) v6(39.91,23.13) v6(40.09,23.31) v6(40.09,23.13) v6(40.27,23.31) v6(40.27,23.13) v6(51.04,24.85) v6(51.04,24.67) v6(51.21,24.85) v6(51.21,24.67) v6(51.39,24.85) v6(51.39,24.67)
VPA_APT_GSM: length 2.1
  LAYER_2 w0.175: v6(23.16,17.3) v6(23.31,17.37) v6(23.18,17.48) v6(23.16,17.3)
  LAYER_4 w0.175: v6(23.18,17.48) v6(23.16,17.3) v6(23.31,17.37) v6(23.18,17.48)
  LAYER_5 w0.175: v6(23.18,17.48) v6(23.31,17.37) v6(23.16,17.3) v6(23.18,17.48)
  LAYER_6 w0.175: v6(23.16,17.3) v6(23.31,17.37) v6(23.18,17.48) v6(23.16,17.3)
  vias: v1(21.87,18.33) v1(51.25,17.19) v1(51.25,17.01) v1(51.43,17.19) v1(51.43,17.01) v1(51.61,17.19) v2(21.87,18.33) v2(51.25,17.19) v2(51.25,17.01) v2(51.43,17.19) v2(51.43,17.01) v2(51.61,17.19) v3(51.25,17.19) v3(51.25,17.01) v3(51.43,17.19) v3(51.43,17.01) v3(51.61,17.19) v4(51.25,17.19) v4(51.25,17.01) v4(51.43,17.19) v4(51.43,17.01) v4(51.61,17.19) v5(51.25,17.19) v5(51.25,17.01) v5(51.43,17.19) v5(51.43,17.01) v5(51.61,17.19) v6(51.25,17.19) v6(51.25,17.01) v6(51.43,17.19) v6(51.43,17.01) v6(51.61,17.19)
VREF_MSM: length 16.8
  LAYER_3 w0.1: v2(34.73,54.48) 34.73,54.22 34,53.49 33.52,53.49 33.46,53.43 33.26,53.23 33.22,53.23 33.02,53.03 v6(32.79,53.03)
  LAYER_3 w0.175: v6(29.29,54.48) 29.06,54.71 29.06,54.78 28.69,55.15 28.55,55.15 27.6,56.1 v6(27.1,56.1)
  LAYER_7 w0.175: v6(21.7,56.17) 27.03,56.17 v6(27.1,56.1) 28.11,57.11 v6(28.11,57.39) ; v6(32.79,53.03) 32.24,53.03 31.34,53.93 29.84,53.93 v6(29.29,54.48)
VREFC: length 0.9
  TOP w0.25: 6.31,53.48 6.49,53.48 6.93,53.92 U6250.G1
VREG_BOB: length 16.4
  TOP w0.1: U2400.42 v1(38.51,39.32) v1(38.96,39.32) v1(39.53,39.32) 39.55,39.3 39.59,39.3 ; U2000.132 17.43,56.47
  TOP w0.2: v2(27.99,47.19) C521.2 28.17,47.88 29.24,47.88 29.39,48.03 29.39,48.67 29.54,48.67 29.54,49.07 ; U2400.73 v4(37.97,40.31)
  LAYER_2 w0.175: v6(17.09,55.99) v6(17.09,55.81)
  LAYER_2 w0.25: v1(38.51,39.32) v1(38.96,39.32) v1(39.53,39.32)
  LAYER_3 w0.045: v2(38.47,39.77) 38.69,39.55 40.21,39.55 40.31,39.45 41.33,39.45 41.62,39.16 41.62,38.86 v4(41.65,38.86) v4(41.83,38.86)
  LAYER_3 w0.175: v6(17.09,55.99) v6(17.09,55.81)
  LAYER_3 w0.2: v6(30.73,47.14) 30.06,46.47 28.44,46.47 27.99,46.92 v2(27.99,47.19)
  LAYER_4 w0.175: v6(17.09,55.99) v6(17.09,55.81)
  LAYER_6 w0.175: v6(18.6,56.01) v6(18.78,56.01) ; v6(17.92,55.68) v6(18.1,55.68) ; v6(17.09,55.99) v6(17.09,55.81)
  LAYER_7 w0.175: v6(17.09,55.99) v6(17.09,55.81) ; 30.56,45.74 30.56,46.97 v6(30.73,47.14)
  vias: v1(21.94,56.52) v1(35.96,43.32) v1(36.7,43.07) v1(38.76,42.51) v1(38.75,42.08) v1(39.7,42.61) v1(41.47,38.86) v1(41.47,38.68) v1(41.65,38.68) v1(41.83,38.68) v2(21.94,56.52) v2(35.96,43.32) v2(36.7,43.07) v2(38.76,42.51) v2(38.75,42.08) v2(39.7,42.61) v2(41.47,38.86) v2(41.47,38.68) v2(41.65,38.68) v2(41.83,38.68) v3(21.94,56.52) v3(35.96,43.32) v3(36.7,43.07) v3(38.76,42.51) v3(38.75,42.08) v3(39.7,42.61) v3(41.47,38.86) v3(41.47,38.68) v3(41.65,38.68) v3(41.83,38.68) v4(21.94,56.52) v4(35.96,43.32) v4(36.7,43.07) v4(38.76,42.51) v4(38.75,42.08) v4(39.7,42.61) v4(41.47,38.86) v4(41.47,38.68) v4(41.65,38.68) v4(41.83,38.68) v5(17.7,45.62) v5(17.7,45.41) v5(17.69,45.19) v5(17.88,45.62) v5(17.88,45.41) v5(17.87,45.2) v5(20.06,57.15) v5(35.96,43.32) v5(36.7,43.07) v5(40.15,44.79) v5(40.15,44.47) v5(40.33,44.79) v5(40.33,44.47) v5(40.68,44.79) v5(40.68,44.47) v5(40.86,44.79) v5(40.86,44.47) v6(17.7,45.62) v6(17.7,45.41) v6(17.69,45.19) v6(17.88,45.62) v6(17.88,45.41) v6(17.87,45.2) v6(20.06,57.15) v6(35.96,43.32) v6(36.7,43.07) v6(40.15,44.79) v6(40.15,44.47) v6(40.33,44.79) v6(40.33,44.47) v6(40.68,44.79) v6(40.68,44.47) v6(40.86,44.79) v6(40.86,44.47)
VREG_DISP_1P8: length 48.9
  TOP w0.075: R5301.2 58.7,61.83 58.42,61.56 57.91,61.56 57.65,61.81 U5300.A2
  TOP w0.15: R5502.2 v2(57.59,64.33) 57.59,64.61 57.5,64.7 J5501.4
  TOP w0.175: v4(55.13,62.12) 55.18,62.07 R1035.2
  TOP w0.2: R1035.2 R1036.2 56.17,61.7 56.86,61.01 C5002.2 ; C5002.2 57.33,60.33 U5000.1 ; C5002.2 57.33,61.27 57.59,61.53 U5300.A2
  LAYER_3 w0.175: v6(55.13,63.86) 55.66,63.86 55.92,64.12 55.92,64.49 56.4,64.97 57.36,64.97 57.59,64.75 v2(57.59,64.33)
  LAYER_5 w0.175: v4(55.13,62.12) 55,62 55,58.32 54.38,57.69 54.38,56.59 53.95,56.16 v6(53.95,53.69)
  LAYER_5 w0.2: v4(55.13,62.12) v6(55.13,63.86)
  LAYER_6 w0.175: v6(33.67,52.05) 33.35,52.05 v5(33.05,51.75)
  LAYER_7 w0.175: v6(33.67,52.05) 35.59,52.05 36.54,53 41.42,53 41.6,52.82 42.02,52.82 42.46,52.38 43.51,52.38 45.18,50.71 48.87,50.71 50.09,51.93 52.19,51.93 v6(53.95,53.69)
  LAYER_7 w0.2: v7(52.87,64.96) 53.12,64.71 53.12,64.38 53.54,63.95 55.04,63.95 55.13,63.87 v6(55.13,63.86)
  BOTTOM w0.15: C5307.2 52.93,64.99 53.39,65.45 J5300.29
VREG_L1A_1P2: length 54.6
  TOP w0.1: U1001.Y36 36.46,51.69 36.44,51.72 v2(36.43,51.72)
  TOP w0.105: U2000.205 21.45,54.56 21.46,54.55
  TOP w0.2: U1001.AC7 U1001.AB8 U1001.AA9 ; 21.64,54.37 21.46,54.55
  LAYER_3 w0.175: v6(36.43,51.29) v2(36.43,51.72)
  LAYER_3 w0.2: v4(39.82,54.46) v2(39.43,54.23) v2(38.94,54.23) v2(38.73,54.46)
  LAYER_3 w0.25: v6(34.49,51.75) 34.36,51.88 33.94,51.88 33.64,51.57 v6(33.26,51.57)
  LAYER_5 w0.175: v4(22.13,54.15) v6(22.13,52.34)
  LAYER_5 w0.2: v4(42.38,51.19) 42.38,52.05 41.93,52.5 41.92,52.5 v6(41.91,52.52) ; v4(39.82,54.46) v4(42.3,54.46)
  LAYER_5 w0.25: v6(35.67,61.56) 36.04,61.19 36.04,58.55 36.17,58.42 v4(36.17,57.94) ; v6(40.48,58.09) 41.4,57.18 41.4,56.68 42.36,55.72 42.36,54.7 42.3,54.64 v4(42.3,54.46) 42.3,53.79 42.12,53.61 42.12,53.09 41.93,52.9 41.93,52.5
  LAYER_7 w0.045: 30.05,51.24 v6(30.08,51.27)
  LAYER_7 w0.25: v6(36.84,48.77) 36.84,48.78 ; v6(22.13,52.34) 22.14,52.33 22.18,52.33 23.32,51.19 27.71,51.19 28.12,51.59 ; v6(35.67,61.56) 39.16,61.56 40.37,60.35 40.37,58.21 v6(40.48,58.09)
  LAYER_7 w0.3: v6(41.91,52.52) 41.48,52.52 41.29,52.71 38.98,52.71 38.71,52.44 37.31,52.44 36.43,51.56 v6(36.43,51.29) ; 28.12,51.59 28.72,51.59 28.92,51.39 29.89,51.39 30.05,51.24 31.54,51.24 31.82,50.96 32.65,50.96 v6(33.26,51.57) ; v6(36.84,48.77) 36.19,48.77 34.77,50.2 34.77,51.47 v6(34.49,51.75)
  LAYER_7 w0.35: v6(36.43,51.29) 36.06,50.92 36.06,49.56 36.84,48.78
VREG_L1B_0P88: length 70.8
  TOP w0.175: v4(41.78,53.48) C1092.2
  TOP w0.2: U1001.AD8 v5(35.78,57.89) U1001.AB10 v2(36.22,57.45) ; 32.75,53.99 32.5,54.23 32.75,54.48 ; v6(30.59,50.47) v6(30.77,50.47) 30.69,50.39 C1091.2 ; U1001.H28 v4(39.43,53.74) ; U1001.R35 U1001.T36 U1001.U35 U1001.T34 U1001.R35
  TOP w0.25: C1156.2 C1091.2
  LAYER_2 w0.175: v6(30.59,50.47) v6(30.77,50.47)
  LAYER_2 w0.2: v2(34.06,51.61) v6(34.03,51.27)
  LAYER_2 w0.3: v1(38.96,42.29) 39.8,42.29 40.46,42.95 40.73,42.95 v4(41.27,42.41)
  LAYER_3 w0.175: v6(37.44,51.67) v6(37.46,51.28) ; v6(30.59,50.47) v6(30.77,50.47)
  LAYER_3 w0.2: v6(29.79,54.48) 29.79,54.65 v2(29.99,54.85) 30.3,54.85 30.47,54.68 30.47,54.63 30.91,54.19 31.21,54.19 31.4,54 31.73,54 31.96,54.24 v6(32.55,54.24)
  LAYER_3 w0.25: v5(35.78,57.89) v2(36.22,57.45)
  LAYER_4 w0.175: v6(30.59,50.47) v6(30.77,50.47)
  LAYER_5 w0.175: v6(30.59,50.47) v6(30.77,50.47)
  LAYER_5 w0.2: 40.94,46.38 v6(40.94,46.48)
  LAYER_5 w0.25: v6(42.09,51.81) 41.6,52.3 41.6,53.09 41.78,53.27 v4(41.78,53.48) 41.52,53.74 v4(39.43,53.74) ; v6(28.12,53.52) 28.12,51.61 27.94,51.43 v6(27.94,50.91) v6(27.94,49.62) ; v6(37.3,48.76) 36.82,48.28 36.82,47.8 v6(37.13,47.49)
  LAYER_5 w0.4: v4(41.27,42.41) 41.27,45.51 40.94,45.84 40.94,46.38
  LAYER_6 w0.175: v6(30.59,50.47) v6(30.77,50.47)
  LAYER_6 w0.4: v5(35.78,57.89) 34.59,59.08 v5(34.59,60.71) 34.3,60.71 33.84,60.25 33.84,58.87 33.11,58.14 v6(33.11,57.71)
  LAYER_7 w0.2: v6(27.94,50.91) 28.26,50.91
  LAYER_7 w0.25: 29.79,54.95 30.74,54.95 31.79,56 31.79,56.31 31.5,56.6 30.47,56.6 30.15,56.92 30.15,57.7 30.48,58.04 v6(30.48,58.13) ; 29.79,54.95 v6(29.79,54.48) 30.03,54.24 v6(32.55,54.24) ; 29.79,54.95 29.32,54.95 28.12,53.75 v6(28.12,53.52) ; v6(42.09,51.81) 41.13,51.81 40.96,51.98 39.34,51.98 37.83,50.47 37.83,49.35 37.25,48.77
  LAYER_7 w0.3: v6(33.11,57.71) 30.91,57.71 v6(30.48,58.13) ; v6(27.94,49.62) 29.1,49.62 29.52,49.2 33.95,49.2 35.66,47.49 v6(37.13,47.49) 37.41,47.21 40.04,47.21 40.77,46.48 v6(40.94,46.48)
  vias: v1(28.41,51.26) v2(28.41,51.26) v3(28.41,51.26) v4(28.41,51.26) v5(28.41,51.26) v6(28.41,51.26)
VREG_L2A_1P0_SDR_AVDD: length 97.4
  TOP w0.1: C3002.1 25.17,30.3 25.17,30.66 U3100.95 ; C3125.2 28.21,34.59 28.2,34.59 27.97,34.36 27.97,34.36 27.96,34.35 27.96,33.87 U3100.3
  TOP w0.2: C3122.2 21.63,36.6 21.11,36.08 C3123.2 ; C3125.2 28.24,34.57 v2(28.24,34.12)
  TOP w0.22: U2000.187 17.74,55.2 17.14,54.6 16.86,54.6 C2339.2
  LAYER_2 w0.1: v2(25.38,32.15) 25.37,32.16 25.37,32.17 25.04,32.5 24.84,32.5 24.69,32.36 v1(24.51,32.36) ; v2(21.51,34.2) 21.94,33.77 22.43,33.77 22.55,33.65 23.1,33.65 v1(23.19,33.56)
  LAYER_2 w0.175: v2(16.6,54.28) v2(16.6,54.46) v2(16.6,54.64)
  LAYER_3 w0.045: v4(18.78,49.79) 19.01,50.02 v4(19.01,50.06)
  LAYER_3 w0.1: v2(26.44,32.35) 26.73,32.35 26.91,32.53 26.91,32.6 ; v2(21.51,34.2) 21.51,35.05 21.37,35.19 21.37,36.36 21.61,36.61 v2(21.61,36.65) ; v2(21.06,35.99) 20.89,35.99 20.79,35.89 20.79,34.07 22.69,32.17 23.13,32.17 23.28,32.32 v2(23.28,32.6) ; v2(21.06,35.99) 21.06,35.89 20.95,35.78 20.95,34.13 22.72,32.36 v2(23.03,32.36) ; v2(21.06,35.99) 21.06,36.1 21,36.16 20.82,36.16 20.64,35.98 20.64,34 22.64,32 23.61,32 v2(23.72,32.11)
  LAYER_3 w0.12: 26.91,32.6 26.93,32.6 27.05,32.48 27.05,32.42 26.73,32.1 26.42,32.1 25.77,31.44 25.56,31.44 25.38,31.62 v2(25.38,32.15)
  LAYER_3 w0.15: v2(25.42,32.39) 25.02,32.39 24.77,32.14 24.77,31.01 25.31,30.47 25.31,30.21 v2(25.51,30.01)
  LAYER_3 w0.175: v4(18.89,39.81) v4(18.89,39.64) v4(18.89,39.46) ; v2(27.43,32.85) 28.74,34.15 v2(28.74,34.58) ; v2(26.69,32.6) 26.91,32.6 27.15,32.84 27.15,32.91 28.24,34 v2(28.24,34.12) ; v2(26.25,31.61) 26.56,31.61 29.03,34.08 v2(29.03,35.57)
  LAYER_3 w0.2: 27.96,36.75 27.87,36.75 v2(27.84,36.78) ; 27.96,36.75 28.35,36.75 29.03,36.07 v2(29.03,35.57) ; 27.96,36.75 28.74,35.97 v2(28.74,34.58) ; v2(27.84,36.78) v2(27.84,36.6) 27.84,36.46 28.45,35.85 28.45,34.33 v2(28.24,34.12) ; v2(27.84,36.78) 28.09,37.03 28.46,37.03 29.32,36.16 29.32,33.96 25.65,30.28 25.65,30.15 v2(25.51,30.01)
  LAYER_3 w0.25: v2(27.66,36.78) 27.54,36.78 26.94,37.38 22.34,37.38 v2(21.61,36.65)
  LAYER_3 w0.5: v2(27.84,36.78) 27.84,37.08 27.36,37.56 27.36,37.91 26.5,38.77 25.35,38.77 24.49,39.63 18.89,39.63 v4(18.89,39.63) ; 16.53,54.49 16.53,51.51 17.17,50.87 17.17,50.41 17.65,49.93 18.88,49.93 v4(18.89,49.93)
  LAYER_4 w0.175: v4(18.78,49.79) v4(18.89,49.93) v4(19.01,50.06) ; v4(18.89,39.81) v4(18.89,39.64) v4(18.89,39.46)
  LAYER_5 w0.175: v4(18.78,49.79) v4(18.89,49.93) v4(19.01,50.06) ; v4(18.89,39.64) v4(18.89,39.46)
  LAYER_5 w0.5: v4(18.89,39.64) v4(18.89,39.81) v4(18.89,49.93)
  vias: v1(27.66,36.6) v2(27.66,36.6)
VREG_L2B_SDC2: length 5
  LAYER_3 w0.2: v2(42.69,42) 42.52,42.16 41.05,42.16 40.75,42.47 40.16,42.47 39.83,42.14 39.74,42.14 39.44,41.84 38.63,41.84 38.47,42 38.47,42.18 38.47,42.18 v2(38.47,42.29)
VREG_L3A_1P0_SDR_DVDD: length 23.2
  TOP w0.1: 17.53,55.48 U2000.176
  TOP w0.175: C2337.2 17.1,55.05 v2(17.19,55.05)
  TOP w0.25: R3001.2 23.71,37.14 23.7,37.14 C3013.2 ; 17.53,55.48 17.16,55.11 C2337.2
  LAYER_2 w0.175: v2(23.54,37.83) v2(23.72,37.83) v2(23.9,37.83) ; v2(17.01,55.05) v2(17.19,55.05)
  LAYER_3 w0.045: v4(19.62,50.41) 19.45,50.41 v4(19.44,50.42) ; v2(17.01,55.05) 17.06,55 17.12,55 17.17,55.05
  LAYER_3 w0.175: v2(17.19,55.05) v2(17.01,55.05)
  LAYER_3 w0.5: v4(19.44,50.42) 19.14,50.71 18.27,50.71 17.19,51.8 v2(17.19,55.05)
  LAYER_4 w0.175: v4(19.62,50.41) v4(19.44,50.42) v4(19.3,50.53) ; v4(19.54,38.09) v4(19.69,38) v4(19.69,38.18) v4(19.54,38.09)
  LAYER_5 w0.175: v4(19.3,50.53) v4(19.44,50.42) v4(19.62,50.41)
  LAYER_5 w0.5: v4(19.44,50.42) 19.54,50.32 19.54,38.52 19.54,38.51 v4(19.54,38.09)
VREG_L3B_3P0: length 65.4
  TOP w0.1: v2(56.61,64.27) C5539.2 v2(56.61,64.45)
  TOP w0.15: J5501.10 56.45,64.66 56.45,64.66 ; 56.61,64.66 56.73,64.66 56.8,64.72 56.8,65.12 ; 56.61,64.66 56.45,64.66 ; 56.61,64.66 v2(56.61,64.45) ; 56.45,64.66 56.17,64.66 56.1,64.73 J5501.12
  LAYER_2 w0.175: v2(56.61,64.45) v2(56.61,64.27) ; v6(37.5,45.79) v6(37.68,45.79)
  LAYER_3 w0.15: v2(61.74,63.82) 61.41,63.49 61.41,62.46 v4(60.26,61.31) ; v6(57.23,60) 57.67,59.56 57.67,58.65 v2(57.3,58.28)
  LAYER_3 w0.175: v6(37.5,45.79) v6(37.68,45.79)
  LAYER_3 w0.3: v4(57.1,63.77) v2(56.61,64.27) v2(56.61,64.45)
  LAYER_4 w0.175: v6(37.5,45.79) v6(37.68,45.79)
  LAYER_5 w0.15: v6(52.3,60.21) 52.31,60.21 52.31,64.61 v7(51.92,65)
  LAYER_5 w0.175: v4(60.26,61.31) 59.94,61 v6(59.94,60.64) 60.86,60.64 61.54,59.96 61.54,58.92 59.96,57.34 59.96,57.03 60.03,56.95 60.03,56.22 59.67,55.85 v6(59.67,55.85)
  LAYER_5 w0.3: v4(57.1,63.77) 57.23,63.65 v6(57.23,60)
  LAYER_6 w0.175: v6(37.68,45.79) 37.67,45.79 v6(37.5,45.79)
  LAYER_7 w0.15: v7(51.92,65) 52.28,65.36 53.06,65.36 v7(53.43,64.99)
  LAYER_7 w0.175: 37.56,45.83 v6(37.5,45.79) v6(37.68,45.79)
  LAYER_7 w0.25: v6(59.67,55.85) 58.17,55.85 56.08,53.76 56.08,49.39 53.33,46.64 42.42,46.64 41.93,46.15 39.18,46.15 38.85,45.83 37.56,45.83
  LAYER_7 w0.3: v6(52.3,60.21) 57.02,60.21 v6(57.23,60)
  LAYER_7 w0.5: v6(57.23,60) 59.31,60 v6(59.94,60.64)
  BOTTOM w0.15: J5300.27 53.74,65.34 53.47,65.07 C5310.2
  vias: v1(36.49,42.79) v2(36.49,42.79) v3(36.49,42.79) v4(36.49,42.79)
VREG_L4B_2P95: length 29.9
  TOP w0.25: C1603.2 54.99,55.99 C1601.2
  LAYER_3 w0.175: v6(55,54.75) v6(55,54.57)
  LAYER_3 w0.3: v4(43.93,40.55) 38.3,40.55 v2(38.25,40.6)
  LAYER_4 w0.175: v6(55,54.75) v6(55,54.57)
  LAYER_5 w0.175: v6(55,54.75) v6(55,54.57)
  LAYER_5 w0.5: v6(47.6,45.84) 47.6,48.27 47.18,48.69 47.18,54.43 v6(47.58,54.83)
  LAYER_6 w0.175: v6(55,54.75) v6(55,54.57)
  LAYER_7 w0.175: v6(55,54.57) v6(55,54.75)
  LAYER_7 w0.5: v6(55,54.57) 47.84,54.57 v6(47.58,54.83) ; v6(47.6,45.84) 48.12,45.32 48.12,44.8 47.08,43.77 v6(44.06,43.77)
  vias: v1(52.63,55) v1(52.63,54.5) v1(52.63,54) v1(54.91,55.89)
VREG_L5A_0P8: length 4.4
  TOP w0.105: 20.53,54.52 20.46,54.64 U2000.203
  TOP w0.2: U1001.N9 38.31,57.83 ; 38.31,57.83 v2(38.44,57.7) ; 38.31,57.83 38.31,57.83 v6(38.04,58.11) ; v2(38.2,57.45) v2(38.44,57.7) ; v2(38.44,57.7) U1001.L9
  LAYER_2 w0.175: v6(38.04,58.11) v6(38.16,57.98) ; v6(20.54,54.36) v6(20.66,54.23) ; v6(37.15,60.6) v6(37.06,60.41)
  LAYER_3 w0.175: v6(37.15,60.6) v6(37.06,60.41) ; v6(20.54,54.36) v6(20.66,54.23)
  LAYER_4 w0.175: v6(38.04,58.11) v6(38.16,57.98) ; v6(20.54,54.36) v6(20.66,54.23)
  LAYER_5 w0.175: v6(20.54,54.36) v6(20.66,54.23) ; v6(37.15,60.6) v6(37.06,60.41) ; v6(38.04,58.11) v6(38.16,57.98)
  LAYER_6 w0.175: v6(38.04,58.11) v6(38.16,57.98) ; v6(20.54,54.36) v6(20.66,54.23) ; v6(37.15,60.6) v6(37.06,60.41)
  LAYER_7 w0.045: 38.16,57.99 v6(38.16,57.98)
  vias: v1(38.65,57.9) v2(38.65,57.9)
VREG_L5B_2P8: length 74.6
  TOP w0.15: J5500.44 32.11,64.74 32.27,64.59 32.27,64.49 C5510.2
  LAYER_2 w0.2: v2(33.11,40.96) 33.11,43.22 33.65,43.77 35.98,43.77 v1(36.2,43.55)
  LAYER_3 w0.175: v4(42.88,34.19) 39.09,34.19 38.96,34.32 35.53,34.32 30.19,39.66 30.19,40.72 30.57,41.1 31.98,41.1 32.06,41.02 33.02,41.02 33.08,40.96 v2(33.11,40.96) ; v2(32.36,64.32) 32.29,64.32 30.99,65.62 v4(30.99,65.87)
  LAYER_5 w0.175: v4(42.88,34.19) 42.88,37.23 44.84,39.19 44.84,47.66 45.3,48.12 45.3,57 43.57,58.73 43.57,65.87 42.58,66.86 33.29,66.86 32.29,65.87 v4(30.99,65.87)
VREG_L6A_1P3: length 91.8
  TOP w0.05: v6(49.99,36.8) 49.99,36.79
  TOP w0.1: v6(38.91,58.2) 38.92,58.2 38.92,58.2 U1001.K8
  TOP w0.2: C2338.2 20.9,53.37 20.94,53.41 20.94,54.51 U2000.215
  TOP w0.25: C4009.2 56.24,36.7 56.29,36.65 U4000.8 ; v4(56.74,37.06) 56.74,36.75 56.64,36.65 56.64,36.18 U4000.1 ; v2(54.29,37.63) C4008.2 54.29,36.76 54.31,36.73 U4000.66
  LAYER_2 w0.175: v6(49.94,36.63) v6(49.99,36.8) v6(49.82,36.76) v6(49.94,36.63)
  LAYER_3 w0.175: v6(38.91,58.2) 38.49,58.2 v2(38.45,58.24) ; v4(56.44,37.36) v2(56.28,37.08) ; v6(49.94,36.63) v6(49.82,36.76) v6(49.99,36.8) v6(49.94,36.63)
  LAYER_3 w0.2: v2(54.29,37.63) 54.55,37.89 v4(55.1,37.89) ; 57.03,34.84 57.03,35.01 56.95,35.09 v2(56.04,35.09) ; 57.03,34.84 v6(57.06,34.82) ; 57.03,34.84 v2(56.29,34.84) ; v6(52.2,33.77) 52.2,33.93 v2(51.8,34.33) ; v6(57.06,33.93) 56.49,33.93 56.41,33.85 v2(55.79,33.85) ; v2(56.29,34.33) 56.74,34.33 56.79,34.38 v6(57.06,34.38)
  LAYER_4 w0.175: v6(49.94,36.63) v6(49.99,36.8) v6(49.82,36.76) v6(49.94,36.63)
  LAYER_5 w0.175: v6(49.94,36.63) v6(49.82,36.76) v6(49.99,36.8) v6(49.94,36.63)
  LAYER_5 w0.2: v4(53.81,33.8) 53.44,33.8 53.12,33.48 52.49,33.48 v6(52.2,33.77)
  LAYER_5 w0.4: v6(21.14,37.36) 21.72,37.93 21.72,45.85 22.05,46.18 22.05,49.06 22.2,49.22 22.2,50.09 21.69,50.61 21.69,51.17 21.31,51.55 21.31,51.77 20.93,52.15 v6(20.93,53.28)
  LAYER_6 w0.175: v6(49.82,36.76) v6(49.94,36.63) v6(49.99,36.8) v6(49.82,36.76)
  LAYER_7 w0.175: 20.9,53.31 20.9,53.28 v6(20.93,53.28)
  LAYER_7 w0.3: v6(38.91,58.2) 39.54,58.83 v6(39.54,60.6) 39.04,61.1 36.16,61.1 35.76,60.7 35.46,60.7 35.16,60.4 28.14,60.4 26.7,58.96 22.84,58.96 20.01,56.13 20.01,54.39 20.9,53.5 20.9,53.31
  LAYER_7 w0.5: 49.94,36.57 47.08,33.71 31.09,33.71 27.44,37.36 v6(21.14,37.36)
  vias: v1(57.27,37.37) v2(57.27,37.37) v3(57.27,37.37) v4(57.27,37.37)
VREG_L6B_3P3: length 114.3
  TOP w0.15: v4(5.5,59.8) 5.47,59.77 C2375.2 5.11,59.71 U6180.8
  TOP w0.2: U6150.4 12.18,18.44 12.1,18.52 C6152.2 C6151.2 C6150.2
  LAYER_2 w0.175: v6(12.13,19.17) 12.13,19.18 v1(12.13,19.61)
  LAYER_2 w0.2: v2(7.82,41.53) v2(5.27,41.53)
  LAYER_3 w0.175: 4.36,49.67 5.82,48.2 5.82,42.09 v2(5.27,41.53) ; v4(6.69,57.23) 6.49,57.03 4.69,57.03 4.27,56.62 4.27,53.38
  LAYER_3 w0.2: v4(42.42,32.39) 37.55,32.39 37.19,32.03 34.56,32.03 28.37,38.22 27.97,38.22 26.19,40 25.12,40 24.82,40.3 18.48,40.3 18.33,40.15 v4(17.97,40.15) 16.14,40.15 15.6,39.61 15.6,38.58 14.57,37.55 13.43,37.55 12.58,36.7 10.58,36.7 7.82,39.46 v2(7.82,41.53) ; 4.27,53.38 4.63,53.03 5.35,53.03 v2(5.57,52.81) 5.58,52.8 5.58,51.68 v2(5.41,51.51) 5.23,51.51 4.36,50.64 4.36,49.67 ; v4(42.47,39.48) 41.94,40.01 38.23,40.01 v2(38.18,40.06)
  LAYER_5 w0.175: v4(7.02,56.4) 6.78,56.64 6.78,57.14 v4(6.69,57.23) 5.5,58.42 v4(5.5,59.8)
  LAYER_5 w0.2: v4(42.42,32.39) 42.42,37.86 42.47,37.91 v4(42.47,39.48) ; v6(19.16,22.02) 19.16,25.08 18.97,25.27 18.97,36.94 17.97,37.94 v4(17.97,40.15)
  LAYER_7 w0.2: v6(12.13,19.17) 12.81,19.85 12.81,22.51 13.06,22.76 15.06,22.76 15.8,22.02 v6(19.16,22.02)
VREG_L7A_1P2_RF: length 78.5
  TOP w0.2: C3018.2 21.61,36.04 21.96,36.38 22.27,36.38 C3007.2 ; C2336.2 21.54,53.96 21.2,54.29 U2000.216 ; U3100.130 U3100.137
  TOP w0.25: C3009.2 C3010.2
  LAYER_2 w0.175: v6(22.52,36.49) v6(22.68,36.57) ; v2(21.56,53.76) v2(21.38,53.76) v2(21.38,53.94)
  LAYER_3 w0.045: v2(21.38,53.94) v2(21.38,53.76) v2(21.56,53.76)
  LAYER_3 w0.1: v2(25.86,36.5) 26.06,36.5 26.24,36.68 26.43,36.68 27.16,35.95 27.16,34.63 27.12,34.59 27.12,34.2 26.72,33.8 26.67,33.8 26.55,33.68 26.55,33.51 26.71,33.34 v2(26.94,33.34) ; v2(25.91,36.01) 26.48,36.01 26.89,35.6 26.89,34.75 26.28,34.14 26.28,33.59 25.49,32.8 25.49,32.59 25.6,32.47 25.6,32.31 25.57,32.27 25.57,31.74 v2(25.67,31.64) ; v2(25.91,36.01) 25.91,35.51 26,35.42 26,34.4 25.45,33.86 v2(25.45,33.34) ; v2(25.91,36.01) 26.21,35.71 26.21,35.31 26.62,34.9 26.62,34.73 26.13,34.25 26.13,33.65 25.2,32.73 v2(25.2,32.65)
  LAYER_3 w0.15: v2(24.96,33.34) v2(25.45,33.34) ; v2(23.69,33.06) 23.28,33.06 23.13,33.21 22.76,33.21 22.1,33.87 22.1,35.67 21.78,35.99 21.68,35.99 v2(21.67,36) 21.66,35.99 21.66,35.81 21.89,35.58 21.89,33.8 22.67,33.02 23.04,33.02 23.24,32.82 23.45,32.82 v2(23.91,32.35) ; v2(24.42,31.86) 24.42,30.68 24.92,30.18 v2(24.92,30.02)
  LAYER_3 w0.2: v4(26.05,28.19) 26.05,26.84 v2(25.88,26.67) ; v2(24.92,30.02) 24.61,30.02 24.31,30.32 v6(23.2,30.32) 23.2,30.71 22.49,31.42 22.49,31.84 20.38,33.95 20.38,36.38 v6(20.19,36.57) ; v2(14.34,29.45) 14.34,30.05 14.62,30.32 v6(14.86,30.32)
  LAYER_3 w0.5: v2(21.38,53.76) 21.38,52.81 21.07,52.5 21.07,50.16 20.18,49.28 v4(20.18,49.2) v4(20.18,49.02)
  LAYER_4 w0.175: v4(20.18,49.2) v4(20.18,49.02) v4(20.18,48.84) ; v6(22.52,36.49) v6(22.68,36.57)
  LAYER_5 w0.15: v6(20.33,36.68) 20.3,36.68 v6(20.19,36.57)
  LAYER_5 w0.175: v6(22.52,36.49) v6(22.68,36.57) ; v4(20.18,49.02) v4(20.18,49.2)
  LAYER_5 w0.2: v6(26.31,30.32) 26.31,28.45 v4(26.05,28.19)
  LAYER_5 w0.5: v4(20.18,49.02) v4(20.18,48.84) 20.18,38.25 20.19,38.25 v6(20.19,36.57)
  LAYER_6 w0.175: v6(20.19,36.57) v6(20.33,36.68) ; v6(22.52,36.49) v6(22.68,36.57)
  LAYER_7 w0.2: v6(14.86,30.32) v6(23.2,30.32) v6(26.31,30.32)
VREG_L7B_3P125: length 34.7
  TOP w0.2: v6(30.7,48.7) v2(30.7,49.31)
  LAYER_3 w0.1: v2(20.51,57.93) 20.49,57.95 20.49,58.3 20.42,58.37 20.42,59.41 20.87,59.86 21.06,59.86 21.1,59.9 v2(21.1,60.07)
  LAYER_3 w0.175: v4(34.69,42.7) 34.79,42.8 35.35,42.8 35.4,42.75 v2(36.03,42.75)
  LAYER_3 w0.2: v4(19.46,58.46) 19.63,58.63 19.63,59.5 19.81,59.69 20.36,59.69 20.74,60.07 v2(21.1,60.07)
  LAYER_5 w0.2: v4(19.46,58.46) 19.25,58.25 19.25,58.08 19.25,57.01 19.79,56.47 19.79,54.19 20.58,53.4 20.58,52 20.96,51.62 20.96,51.4 21.34,51.02 21.34,50.44 v6(21.59,50.19)
  LAYER_5 w0.25: v6(32.97,45.45) 32.97,44.47 33.31,44.13 33.31,43.1 33.7,42.7 v4(34.69,42.7)
  LAYER_7 w0.2: v6(32.97,45.45) 31.62,46.8 31.62,47.34 30.7,48.26 v6(30.7,48.7) 28.81,48.7 28.39,49.12 23.06,49.12 21.99,50.19 v6(21.59,50.19)
  vias: v1(34.44,51.27) v2(34.44,51.27)
VREG_L8A_1P8: length 57.3
  TOP w0.05: 20,54.54 20.02,54.49
  TOP w0.105: U2000.202 19.96,54.57 20,54.54
  TOP w0.15: U1600.T15 v1(51.13,53.5)
  TOP w0.2: 20.02,54.49 v1(20.02,53.75)
  TOP w0.25: U1600.R13 v1(51.13,53.5) ; U1600.K15 U1600.J15 v1(52.13,56.5) v1(52.63,56.5) ; C1605.2 54.99,53.86 v1(54.99,53.32) ; U1600.T15 v1(52.13,53)
  LAYER_2 w0.25: v6(19.42,51.19) 19.56,51.33 19.56,52.1 19.86,52.4 19.86,53.59 v1(20.02,53.75)
  LAYER_3 w0.3: 55.22,54.03 55.5,54.31 55.5,55.59 55.02,56.07 v2(55.02,57.93) v2(55.02,58.45) ; 55.22,54.03 v4(55.04,53.85) v4(55.04,54.03) 55.22,54.03
  LAYER_4 w0.175: v4(55.04,53.85) v4(55.04,54.03)
  LAYER_5 w0.3: v6(55.04,53.11) v4(55.04,53.85) v4(55.04,54.03)
  LAYER_7 w0.3: v6(19.42,51.19) 22.07,51.19 22.38,50.88 22.38,50.55 22.96,49.97 29.24,49.97 29.66,49.55 34.12,49.55 35.83,47.84 37.3,47.84 37.57,47.56 40.95,47.56 41.43,47.09 53.04,47.09 55.06,49.11 55.06,49.59 55.57,50.11 55.57,52.71 55.18,53.11 v6(55.04,53.11)
  vias: v1(51.61,53)
VREG_L8B_3P3: length 35.8
  TOP w0.2: v2(48.93,35.62) 48.93,35.55 48.7,35.32 48.7,35.09 U4090.8 ; v4(34.31,40.97) v4(34.44,40.85)
  LAYER_2 w0.175: v4(47.85,35.7) v4(47.67,35.7) v4(47.49,35.7) ; v4(48.44,32.59) v4(48.22,32.59) v4(47.99,32.59) ; v2(50.78,34.75) v2(50.6,34.75) v2(50.42,34.75) ; v2(50.42,35.42) v2(50.6,35.42) v2(50.78,35.42) ; v1(36.44,43.28) 36.24,43.28 36.05,43.09 36.05,43.09 35.17,42.21
  LAYER_2 w0.35: v4(34.44,40.85) v4(34.31,40.97) 34.03,41.25 34.03,41.95 34.29,42.21 35.17,42.21
  LAYER_3 w0.175: v4(47.85,35.7) v4(47.67,35.7) v4(47.49,35.7) ; v4(35.74,35.3) v4(35.87,35.18) ; 45.83,35.18 45.75,35.11 v4(45.61,35.11) ; v4(48.63,35.18) 48.93,35.48 v2(48.93,35.62) ; v4(47.99,32.59) v4(48.22,32.59) v4(48.44,32.59) ; v4(45.97,35.11) v4(45.79,35.11)
  LAYER_3 w0.2: v4(34.31,40.97) v4(34.44,40.85)
  LAYER_3 w0.5: 45.83,35.18 v4(35.87,35.18)
  LAYER_4 w0.175: v4(34.31,40.97) v4(34.44,40.85) ; v4(48.44,32.59) v4(48.22,32.59) v4(47.99,32.59) ; v4(35.74,35.3) v4(35.87,35.18) ; v4(47.49,35.7) v4(47.67,35.7) v4(47.85,35.7) ; v4(45.97,35.11) v4(45.79,35.11) v4(45.61,35.11)
  LAYER_5 w0.045: v4(34.31,40.97) 34.47,40.97 ; 34.47,40.97 34.48,40.98 ; 34.47,40.97 34.44,40.94 v4(34.44,40.85)
  LAYER_5 w0.175: v4(35.74,35.3) v4(35.87,35.18)
  LAYER_5 w0.2: v4(53.57,33.55) 53.19,33.17 52.35,33.17 v4(52.23,33.29) 52.22,33.28 51.93,33.58 51.17,33.58 50.25,34.5 v4(50.05,34.5) 50.05,34.3 51.06,33.29 v4(51.71,33.29) 52.13,32.86 v4(53.76,32.86)
  LAYER_5 w0.5: 34.48,40.98 34.92,40.54 34.92,36.13 v4(35.87,35.18)
  vias: v3(49.92,34.63) v3(49.98,34.8) v3(50.11,34.67) v3(50.24,34.54) v3(50.19,34.37) v4(49.92,34.63) v4(49.98,34.8) v4(50.11,34.67) v4(50.24,34.54) v4(50.19,34.37)
VREG_L9A_1P8: length 63.1
  LAYER_2 w0.15: v4(19.94,50.76) 19.94,51.22 19.82,51.34 19.82,51.92 v1(20.32,52.43) 20.11,52.64 20.11,53.49 20.27,53.65 20.27,53.88 20.18,53.97 v1(20.18,55.22)
  LAYER_5 w0.2: v6(20.7,38.15) 20.7,49.29 20.16,49.83 20.16,50.54 v4(19.94,50.76)
  LAYER_7 w0.2: v6(20.7,38.15) 27.69,38.15 31.52,34.32 46.74,34.32 49.84,37.43 v6(51.3,37.43) ; v6(51.3,37.43) 51.54,37.43 51.91,37.06 v6(51.91,35.53) ; v6(51.3,37.43) 51.3,36.93 51.53,36.7 v6(51.53,35.6) 51.53,35.35 51.76,35.12 53.73,35.12 54.02,34.83 54.02,34.5 v6(53.57,34.05)
  LAYER_7 w0.25: v6(55.26,34.84) 54.57,35.53 v6(51.91,35.53)
VREG_L9B_0P8: length 2.4
  TOP w0.2: v4(35.43,51.76) v4(35.01,51.76) U1001.AF34
  LAYER_2 w0.175: v6(33.4,48.02) v6(33.27,47.9) ; v6(33.26,48.83) v6(33.42,48.91)
  LAYER_3 w0.175: v6(33.26,48.83) v6(33.42,48.91) ; v6(32.76,47.11) v2(33.01,46.92) ; v6(33.27,47.9) v6(33.4,48.02)
  LAYER_4 w0.175: v6(33.26,48.83) v6(33.42,48.91) ; v6(33.27,47.9) v6(33.4,48.02)
  LAYER_6 w0.175: v6(38.8,46.26) v6(38.67,46.13) ; v6(33.26,48.83) v6(33.42,48.91) ; v6(33.4,48.02) v6(33.27,47.9)
  vias: v1(38.47,42.79) v2(38.47,42.79) v3(38.47,42.79) v4(38.47,42.79)
VREG_L10A_1P8: length 54.9
  TOP w0.105: U1001.AF22 U1001.AH22
  TOP w0.15: C2333.2 18.09,51.97 v6(18.09,52.13)
  TOP w0.2: 33.74,51.02 U1001.AM38 ; U1001.AE21 U1001.AF22 ; v6(29.42,62.15) R1033.2
  LAYER_2 w0.15: v1(19.2,55.2) 19.01,55.01 19.01,53.9 17.91,52.8 17.91,52.31 v6(18.09,52.13)
  LAYER_2 w0.175: v6(18.09,52.13) 18.09,52.03 17.77,51.71 17.5,51.71 16.14,53.07 v6(16.14,53.32)
  LAYER_3 w0.125: 32.65,51.18 32.18,51.18 31.81,50.82
  LAYER_3 w0.15: v2(34.45,54.77) 34.39,54.71 33.72,54.71 32.99,53.98 32.03,53.98 31.96,53.91 31.82,53.77 31.25,53.77 31.07,53.96 30.81,53.96 30.59,54.18 30.4,54.18 30.29,54.08 28.89,54.08 28.77,54.2
  LAYER_3 w0.2: 32.65,51.18 32.87,50.96 33.3,50.96 v2(33.46,50.8) ; v6(27.85,51.74) 27.85,51.42 28.27,50.99 28.54,50.99 28.71,51.16 29.76,51.16 29.91,51.01 30.43,51.01 30.48,50.96 30.49,50.96 v2(30.69,50.76) 30.7,50.75 31.75,50.75 31.81,50.82 ; v4(27.85,53.54) 27.85,54.59 v2(28.03,54.77) 28.6,54.2 28.77,54.2
  LAYER_5 w0.175: v6(27.85,51.74) v4(27.85,53.54)
  LAYER_7 w0.1: v6(16.14,53.32) 16.25,53.43 16.25,53.93 15.84,54.34 15.84,55.16 16.12,55.44 17.27,55.44 17.5,55.67 17.5,55.86 19.67,58.03 20.34,58.03 21.99,59.68 21.99,60.21 23.57,61.79 26.57,61.79 26.93,62.15 v6(29.42,62.15)
  LAYER_7 w0.175: v6(18.09,52.13) 18.14,52.18 21.47,52.18 21.9,52.61 22.34,52.61 23.48,51.47 27.58,51.47 v6(27.85,51.74)
VREG_L10B_0P8: length 18.9
  LAYER_2 w0.3: v1(38.96,42.79) 39.13,42.95 39.9,42.95 40.25,43.3 40.91,43.3 v4(41.81,42.4)
  LAYER_5 w0.4: v4(41.81,42.4) v6(41.81,45.55)
  LAYER_7 w0.045: 32.5,48.77 v6(32.5,48.88)
  LAYER_7 w0.4: v6(41.81,45.55) 41.59,45.77 39.39,45.77 39.07,45.45 33.86,45.45 32.36,46.95 32.36,48.63 32.5,48.77
  vias: v1(34.54,52.25) v2(34.54,52.25) v3(34.54,52.25) v4(34.54,52.25)
VREG_L11A_1P8: length 2.4
  LAYER_3 w0.15: v2(18.08,53.45) 19.01,54.38 v2(19.01,55.45)
VREG_L12A_1P8: length 67.6
  TOP w0.105: U2000.201 19.47,54.46 19.32,54.31
  TOP w0.2: 19.32,54.31 19.32,52.83 19.18,52.69 19.18,52.65 v4(19.17,52.64) ; C3004.2 C3006.2
  LAYER_2 w0.15: v2(22.98,33.43) 23.07,33.34 23.96,33.34 ; 23.96,33.34 v1(23.97,33.34) ; 23.96,33.34 23.96,32.89 v1(23.93,32.85)
  LAYER_2 w0.25: v2(27.52,35.55) 27.52,35.65 27.68,35.81 27.68,36.16 27.36,36.48 27.36,37.1 v2(26.63,37.83)
  LAYER_3 w0.1: 26.37,32.92 26.21,32.75 26.05,32.75 25.95,32.85 v2(25.95,32.85) ; 26.37,32.92 v2(26.19,33.1) ; 26.37,32.92 26.38,32.91 26.4,32.91 26.42,32.89 ; v2(27.43,33.84) 27.47,33.87 27.47,34.08 27.87,34.48 27.87,35.2 v2(27.52,35.55) 27.45,35.55 27.39,35.48 27.39,34.64 27.27,34.52 27.27,34.08 26.78,33.59 v2(26.74,33.59) ; v2(25.76,32.11) 26.07,32.11 26.17,32.2 26.17,32.38 26.42,32.63 26.42,32.89 ; v2(28.02,35.51) 28.02,34.35 27.94,34.27 27.94,33.97 26.86,32.89 26.42,32.89 26.42,32.89
  LAYER_3 w0.12: v2(22.98,33.43) 22.85,33.43 22.28,33.99 22.28,35.76 22.15,35.9 v2(22.15,36.01)
  LAYER_3 w0.15: v2(22.15,36.01) 22.15,36.66 22.52,37.03 26.56,37.03 26.84,36.75 26.96,36.75 27.62,36.09 27.62,35.66 27.52,35.56 v2(27.52,35.55)
  LAYER_3 w0.175: v2(24.31,26.82) 20.79,26.82 20.56,27.05 v4(19.43,27.05)
  LAYER_3 w0.2: v4(18.39,39.03) 24.23,39.03 25.1,38.16 26.3,38.16 v2(26.63,37.83)
  LAYER_5 w0.2: v4(19.17,52.64) 19.17,50.95 18.39,50.17 v4(18.39,39.03) 18.39,38.32 19.43,37.28 v4(19.43,27.05)
VREG_L13A_1P8: length 394.2
  TOP w0.05: v6(18.47,51.75) C2334.2 ; C1101.2 v7(44.74,48.18)
  TOP w0.075: R1037.2 13.21,22.37 R1038.2
  TOP w0.088: 19.6,24.6 19.61,24.62 19.61,24.62
  TOP w0.1: U7520.4 40.46,30.06 40.25,30.06 39.91,29.72 C7520.2 ; R1007.1 42.49,50 42.64,50 42.79,49.85 v6(42.79,49.35) ; R1040.2 v4(25.83,64.46)
  TOP w0.15: U7150.24 36.61,24.66 36.61,24.88 36.77,25.04 36.87,25.04 37.14,25.31 C7160.2 ; 38.94,51.27 38.99,51.31 39.39,51.31 39.43,51.27 ; 51.87,61.33 C1609.2 52.17,61.66 ; J5501.16 55.4,64.76 55.28,64.64 55.28,64.38 v2(55.23,64.33) ; U7500.1 18.72,24.04 18.83,23.93 C7501.2 19.14,23.97 19.14,24.15 19.26,24.27 19.43,24.27 19.55,24.39 C7510.2 19.6,24.6 19.61,24.62 U7510.4 ; C7151.2 34.75,25.26 34.77,25.26 35.13,24.9 35.13,24.66 U7150.27 ; v2(39.87,29.64) 39.87,29.66 C7520.2
  TOP w0.175: R101.1 C100.2
  TOP w0.2: U6250.V16 12.31,51.78 C6270.2 ; U6250.AA11 10.52,50.8 10.15,50.43 10.15,50.33 v2(10.12,50.3) ; U6250.F16 12.57,54.12 13.01,54.56 C6268.2 ; v2(28.23,62.86) R5801.2 R5802.2 ; C1099.2 C1101.2 ; U6400.F5 11.92,22.54 11.92,22.11 ; 11.92,22.11 12.94,22.11 R1038.2 ; 11.92,22.11 11.56,22.11 C6407.2 R6154.2 ; v6(32.7,53.54) U1001.AT26 ; U1600.AD4 46.13,47.74 C1607.2 C1610.2 ; U1001.AG37 U1001.AF36 ; R1032.2 56.53,53.39 ; 56.53,53.39 v2(56.55,53.41) ; 56.53,53.39 R1031.2 ; C4618.2 R4614.2 ; 54.47,56.53 55.74,56.53 56,56.64 C1005.1 56.51,56.18 56.57,56.18 U1005.5 56.67,56.18 56.68,56.18 R1005.2 ; U4100.H8 61.73,52.53 61.32,52.12 60.65,52.12 v2(60.39,51.86) ; U6250.E1 6.74,54.32 6.55,54.13 C6267.2 ; R1050.2 6.44,60.33 R1051.2 ; 32.75,57.45 U1001.AT12 ; R1127.2 R1128.2 ; R201.1 56.05,20.8 v2(56.05,21.26)
  TOP w0.25: U6250.AA1 7.01,51.07 v4(7.01,50.35) ; R3002.2 24.71,37.6 C3015.2 ; C7100.2 53.02,19.2 52.89,19.33 U7100.20 ; U4000.94 53.32,36.4 52.79,36.93 v4(52.79,37.05)
  TOP w0.3: U6250.A7 9.13,55.72 C6265.2
  LAYER_2 w0.2: v2(13.78,16.2) 13.88,16.1 13.88,15.21 v2(13.56,14.89)
  LAYER_2 w0.25: v1(48.63,60.5) 48.63,61.49 v2(48.41,61.71)
  LAYER_2 w0.3: v6(18.65,51.75) v6(18.47,51.75) 18.46,51.76 18.46,52.95 19.59,54.08 19.59,55.33 v1(19.49,55.43)
  LAYER_3 w0.1: v2(39.87,29.64) 39.74,29.77 v4(38.96,29.77) ; v2(28.23,62.86) 28.34,62.96 v4(28.34,64.71) 28.34,65.3 28.64,65.6 v4(28.64,66.56)
  LAYER_3 w0.15: v4(6.39,60.23) 6.39,60.23 6.39,60.84 7.03,61.49 7.03,62.5 8.89,64.35 8.89,65.03 9.44,65.58 10.08,65.58 v4(10.88,66.38) ; v4(7.92,58.79) 8.29,58.42 8.29,57.77 8.48,57.58 8.48,56.3 v6(9.09,55.7) ; v2(24.47,37.81) 24.47,38.06 23.9,38.63 19.13,38.63 18.93,38.43
  LAYER_3 w0.175: v2(34.95,51.3) 34.77,51.48 34.77,52.34 34.58,52.53 v6(34.51,52.53) ; v6(18.47,51.75) v6(18.65,51.75) ; v6(13,51.82) 13.45,51.82 14.64,50.63 v2(14.64,50.5)
  LAYER_3 w0.2: v2(10.67,15.85) 11.08,15.85 11.32,16.1 13.67,16.1 v2(13.78,16.2) 13.78,16.3 12.76,17.32 12.76,18.73 13.41,19.38 13.41,21.47 13.24,21.64 v6(13.24,22.31) ; v2(60.39,51.86) 60.11,52.14 57.48,52.14 56.55,53.07 v2(56.55,53.41) 56.55,55.51 v2(56.66,55.62) ; v2(25.53,23.29) 25.23,22.99 18.66,22.99 ; v4(26.79,13.76) 26.79,15.38 25.52,16.66 20.75,16.66 19.85,17.56 19.85,19.07 20.56,19.78 v4(20.56,20.22) 20.36,20.22 20.26,20.12 v6(18.72,20.12) ; v2(16.63,34.52) 16.63,34.38 15.95,33.71 v4(14.82,33.71) ; v4(17.88,67.16) 17.88,65.16 17.41,64.69 17.41,64.24 16.08,62.91 15.07,62.91 14.69,62.53 14.69,62.21 14.38,61.9 13.85,61.9 13.27,61.32 13.27,59.53 12.98,59.24 12.98,58.4 12.72,58.14 v6(12.72,57.26) ; v2(13.21,11.81) 13.56,12.16 v2(13.56,14.89) ; 18.66,22.99 18.66,23.58 v2(19.06,23.98) ; 18.66,22.99 18.1,22.99 17.79,22.68 v4(15.54,22.68) ; v2(8.5,51.1) 8.04,50.64 7.3,50.64 v4(7.01,50.35) 7.42,49.94 9.76,49.94 v2(10.12,50.3) ; v2(34.74,25.37) 37.07,25.37 v2(37.08,25.38) 37.35,25.65 v4(38.96,25.65) ; v4(38.96,27.88) 50.4,27.88 56.05,22.23 v2(56.05,21.26) 55.84,21.06 55.58,21.06 53.92,19.39 53.58,19.39 v2(53.33,19.14) 53.33,18.97 54.44,17.86 54.44,17.11 54.02,16.69 53.03,16.69 52.25,15.91 v4(52.25,15.67) 52.25,14.73 50.81,13.29 v7(48.1,13.29)
  LAYER_3 w0.25: v2(46.2,60.5) 47.4,61.71 v2(48.41,61.71) ; v2(55.23,64.33) 55.05,64.33 54.56,63.84 v4(52.88,63.84)
  LAYER_3 w0.3: 17.01,36.9 17.4,36.9 18.93,38.43 ; 17.01,36.9 17.01,34.9 v2(16.63,34.52) ; 17.01,36.9 v4(13.89,36.9) ; v2(48.41,61.71) 48.84,62.14 v2(52.07,62.14) 52.07,62.13 v4(52.88,61.32)
  LAYER_4 w0.175: v6(18.47,51.75) v6(18.65,51.75)
  LAYER_5 w0.1: v4(28.34,64.71) 28.3,64.75 26.12,64.75 v4(25.83,64.46) ; v4(26.85,66.34) 27.08,66.34 27.3,66.56 v4(28.64,66.56) ; v6(22.97,50.6) 22.97,51.32 22.83,51.46 22.83,51.95 22.74,52.04 22.74,54.68 22.09,55.33 22.09,56.05 21.77,56.36 21.51,56.36 v4(21.45,56.42)
  LAYER_5 w0.15: v4(6.39,60.23) 7.83,58.79 v4(7.92,58.79)
  LAYER_5 w0.175: v6(18.47,51.75) v6(18.65,51.75) ; v4(52.25,15.67) 53.74,15.67 54.03,15.38 54.03,14.44 54.5,13.97 v7(54.5,13.37) ; v4(10.88,66.38) 14.68,66.38 15.77,67.47 17.57,67.47 v4(17.88,67.16) 22.11,67.16 22.93,66.34 v4(26.85,66.34) ; v4(26.79,13.76) 28.02,12.53 v7(28.02,12.05)
  LAYER_5 w0.2: v4(38.96,25.65) v4(38.96,27.88) v4(38.96,29.77) 38.68,30.05 38.68,32.56 v4(36.52,34.72) 36.52,39.34 v4(35.99,39.86) 37.21,41.07 37.21,41.71 36.69,42.23 v4(36.69,42.52) 36.87,42.52 36.93,42.46 37.17,42.46 37.47,42.76 37.47,43.16 37.97,43.66 37.97,46.11 38.38,46.52 38.38,47.22 38.23,47.37 37.73,47.37 37.12,47.98 v6(37.12,48.13) ; v4(20.56,20.22) 21.48,19.3 21.48,18.57 21.68,18.37 v4(22.52,18.37) ; v4(15.54,22.68) 15.44,22.78 15.44,30.38 v4(14.92,30.9) 14.82,31 v4(14.82,33.71) ; v4(7.01,50.35) 7.01,50.99 6.46,51.54 v4(6.46,54.07) v6(6.46,55.46)
  LAYER_5 w0.25: v4(52.79,37.05) 52.91,37.17 52.91,38.1 53.99,39.18 v4(53.99,39.24) 53.99,40.03 54.12,40.16 v6(54.12,49.09) ; v6(13,55.87) v4(13,54.56) v6(13,51.82)
  LAYER_5 w0.3: v6(14.37,22.31) 14.37,25.74 13.89,26.22 v4(13.89,36.9) 13.89,37.75 13.29,38.35 13.29,50.34 13,50.63 v6(13,51.82) ; v4(52.88,63.84) v4(52.88,61.32)
  LAYER_6 w0.175: v6(18.47,51.75) v6(18.65,51.75)
  LAYER_7 w0.045: 29.32,50.43 29.22,50.33 28.7,50.33 28.63,50.26 v6(28.61,50.26) ; v6(37.12,48.13) 37.29,48.3
  LAYER_7 w0.2: v6(13.24,22.31) v6(14.37,22.31) 14.62,22.31 16.81,20.12 v6(18.72,20.12) ; 39.4,48.28 39.4,50.04 39.4,50.04 v6(39.4,51.23) ; v6(9.09,55.7) 8.61,56.18 7.18,56.18 v6(6.46,55.46)
  LAYER_7 w0.25: 34.33,50 34.44,50.11 34.44,51.33 34.16,51.61 33.71,51.61 33.29,52.02 33.29,53.11 ; v6(34.51,52.53) 34.17,52.53 33.58,53.11 33.29,53.11 ; 33.29,53.11 32.86,53.54 v6(32.7,53.54) 32.7,53.89 32.88,54.06 32.88,54.37 32.2,55.05 32.2,56.36 31.65,56.91 30.62,56.91 30.49,57.04 v6(30.49,57.28) 30.5,57.29 v6(32.58,57.29) 35.69,57.29 v6(36.77,58.37) ; v6(13,55.87) 12.72,56.15 v6(12.72,57.26) 10.32,57.26 9.88,56.82 9.88,56.49 v6(9.09,55.7)
  LAYER_7 w0.5: 42.49,48.28 39.4,48.28 39.37,48.3 36.02,48.3 34.33,50 29.87,50 29.44,50.43 23.14,50.43 v6(22.97,50.6) 22.97,50.93 22.15,51.75 v6(18.65,51.75) v6(18.47,51.75) 18.4,51.68 14.47,51.68 14.33,51.82 v6(13,51.82)
  BOTTOM w0.075: Q1020.2 44.59,49.62 44.78,49.44 R1021.2
  BOTTOM w0.1: R130.2 28.01,12.05 v7(28.02,12.05) ; 44.74,48.22 44.74,48.94 44.78,48.98 R1021.2
  vias: v1(46.27,47.89) v1(48.63,49) v1(51.52,49.5) v1(51.52,49) v2(46.27,47.89) v2(48.63,49) v2(51.52,49.5) v2(51.52,49) v3(46.27,47.89) v3(48.63,49) v3(51.52,49.5) v3(51.52,49) v4(46.27,47.89) v4(48.63,49) v4(51.52,49.5) v4(51.52,49) v5(46.27,47.89) v5(48.63,49) v5(51.52,49.5) v5(51.52,49) v6(46.27,47.89) v6(48.63,49) v6(51.52,49.5) v6(51.52,49)
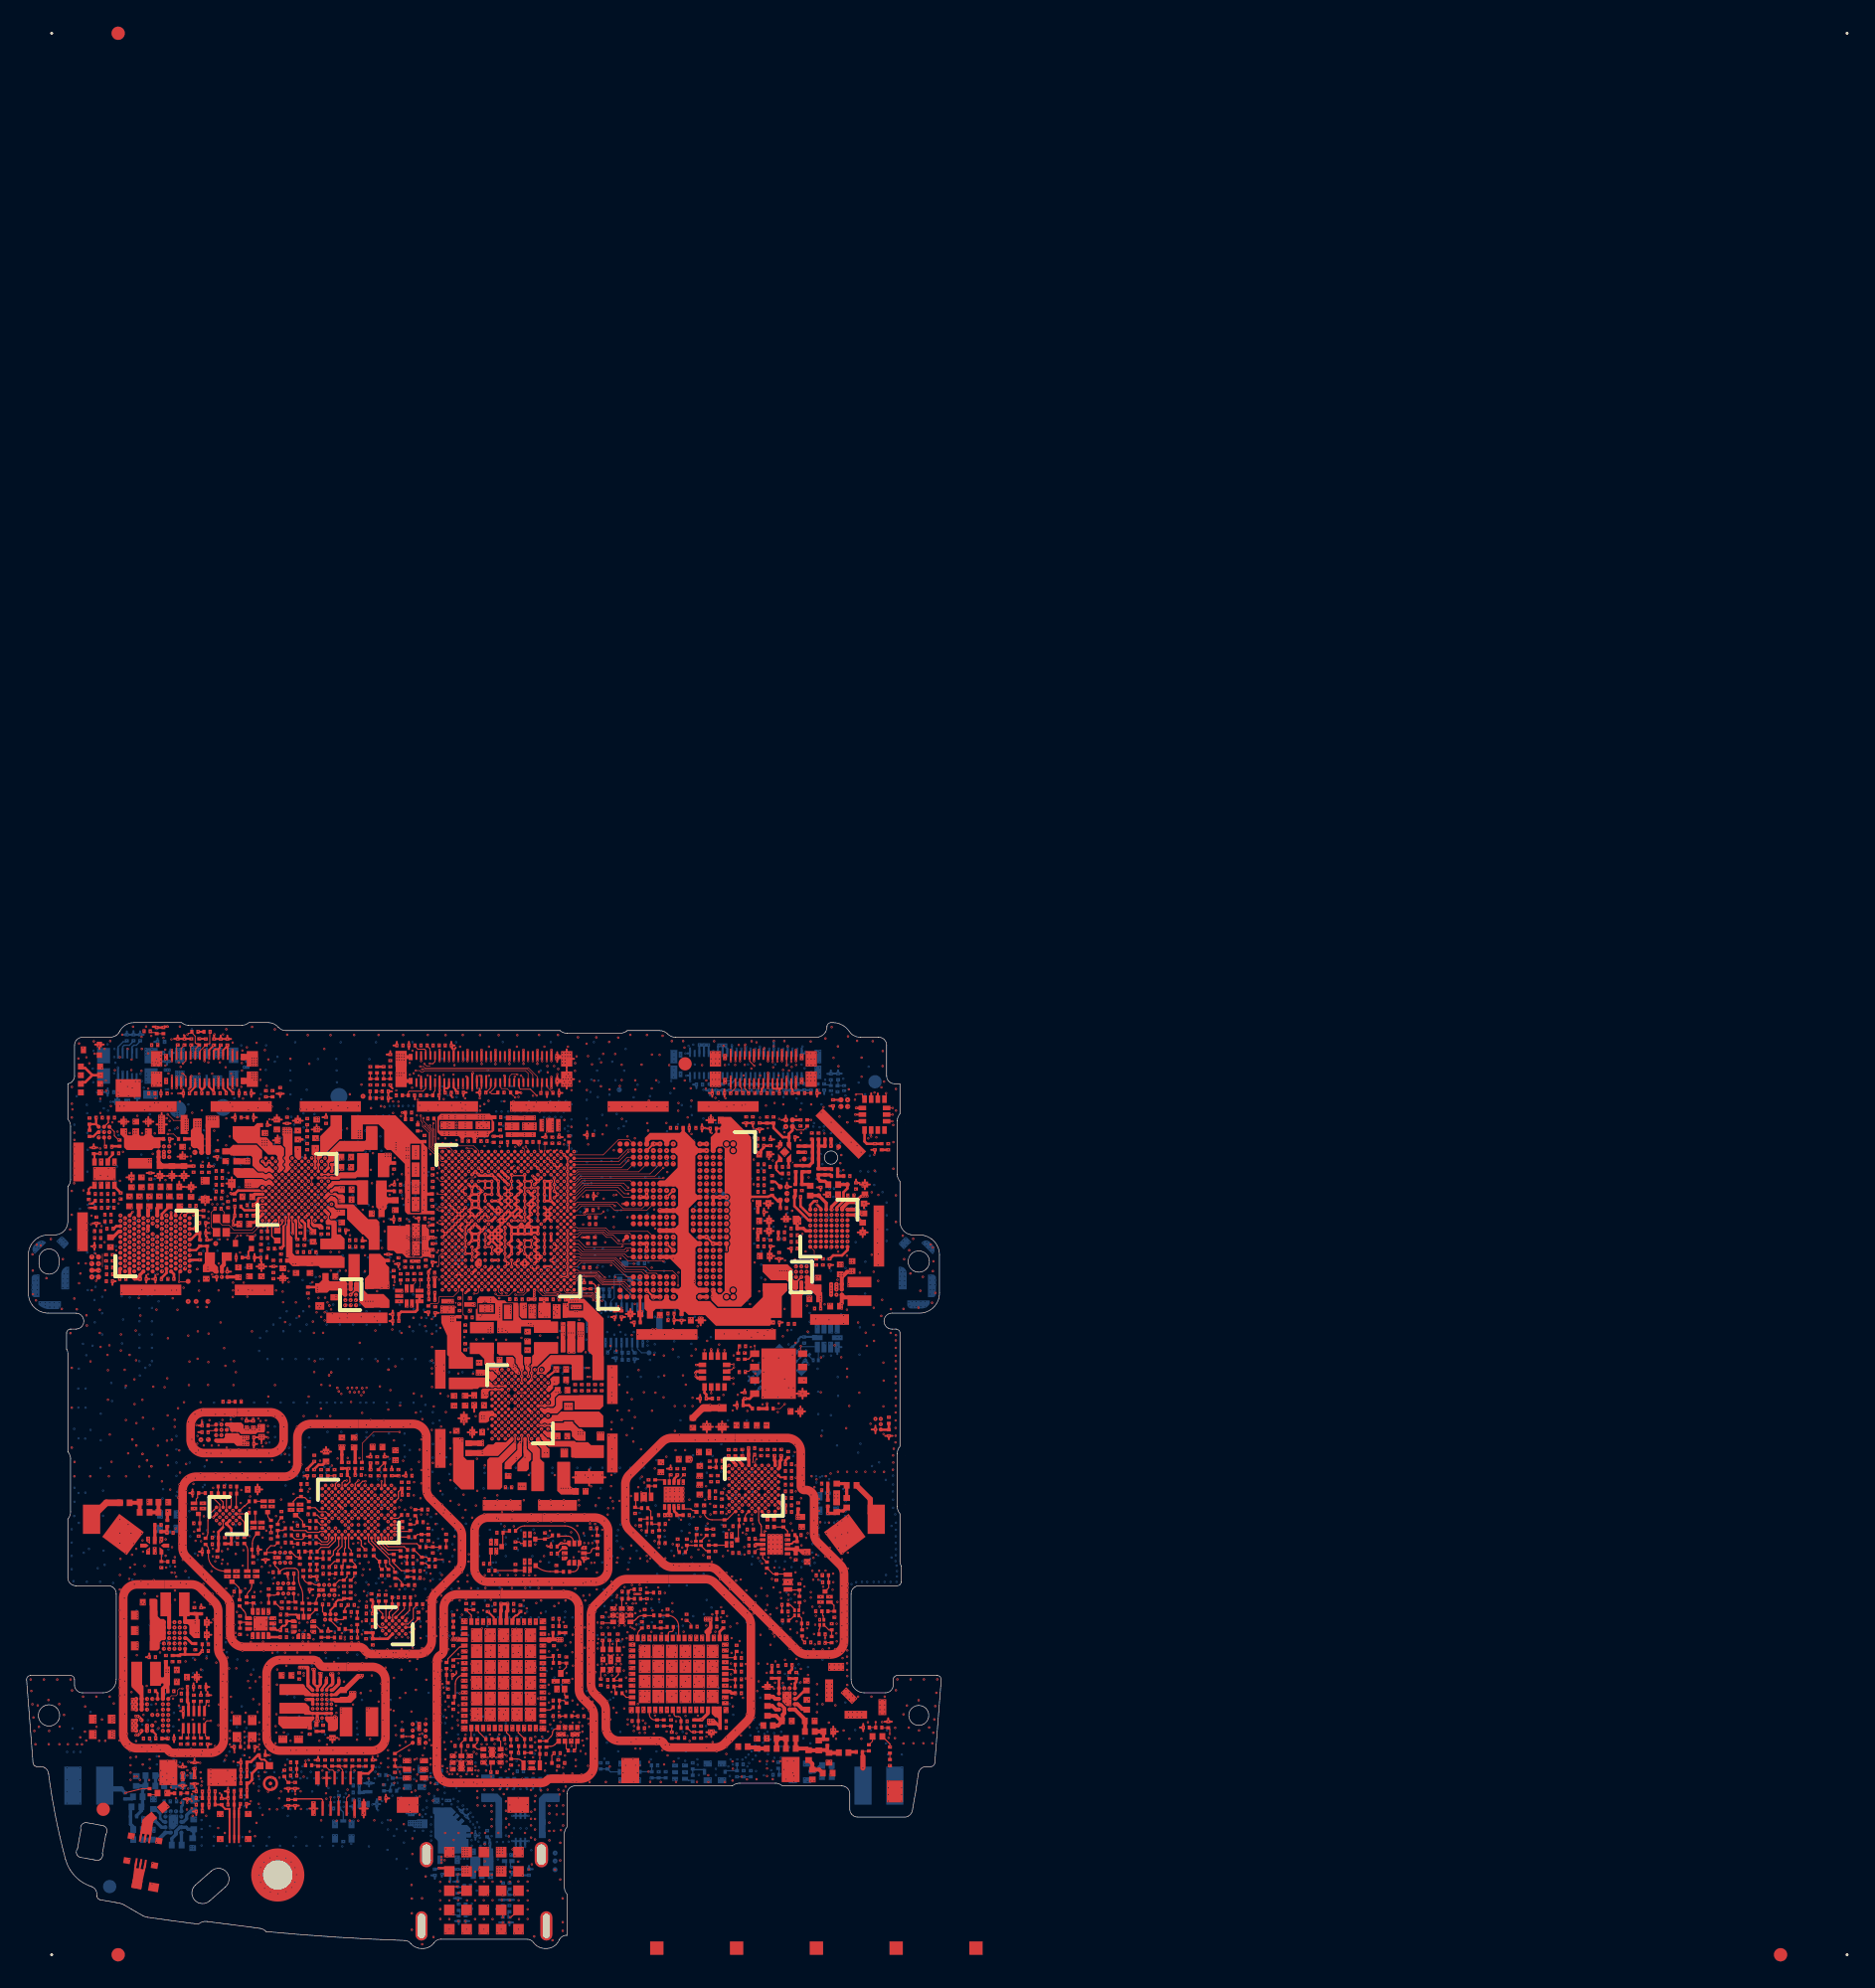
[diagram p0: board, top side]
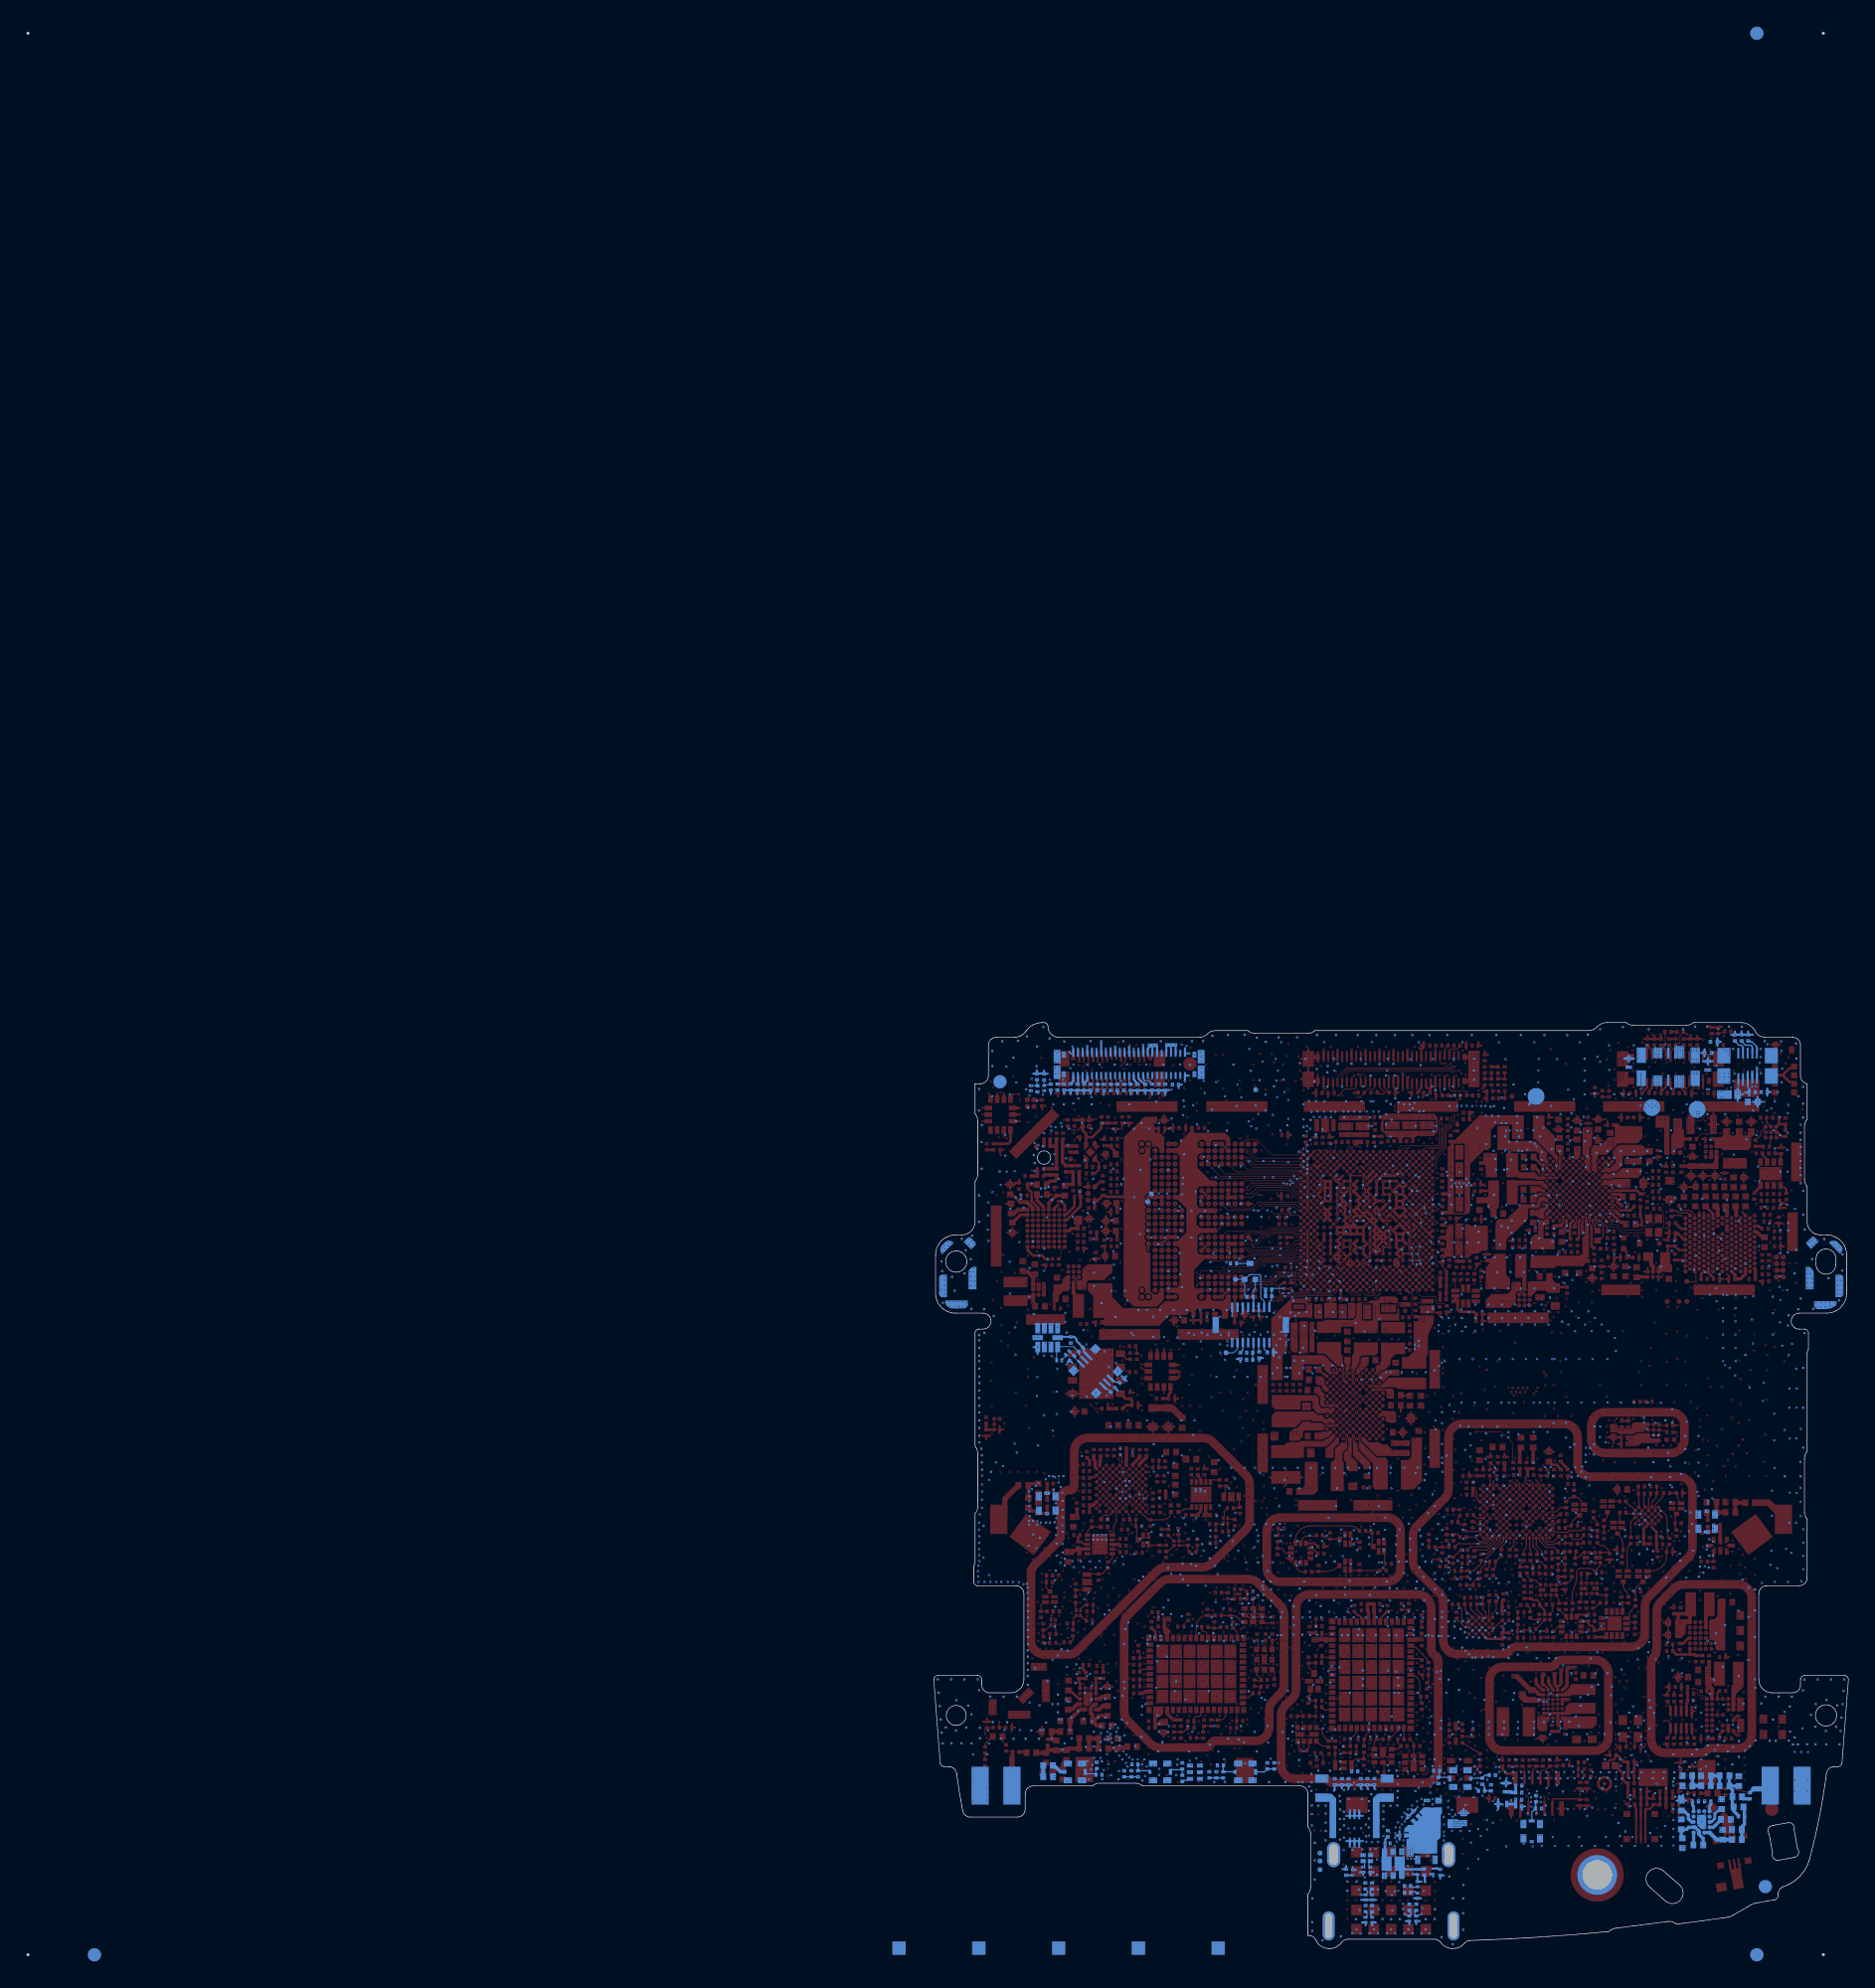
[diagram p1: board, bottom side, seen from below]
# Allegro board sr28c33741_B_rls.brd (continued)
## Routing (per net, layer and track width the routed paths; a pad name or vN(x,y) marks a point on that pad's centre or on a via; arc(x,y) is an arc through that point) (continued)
VREG_L14A_1P8: length 191.9
  TOP w0.075: v4(18,64.06) R1049.2 R1048.2
  TOP w0.15: R1053.2 R1052.2
  TOP w0.2: U6182.C1 U6182.C2 ; 4.94,65.67 5.53,65.67 ; 4.94,65.67 4.41,65.14 4.2,65.14 U6140.6 ; 4.94,65.67 4.41,66.21 4.2,66.21 U6140.8 ; v4(64.79,60.06) R6110.1
  LAYER_2 w0.15: v1(20.49,55.5) 20.49,54.9 20.87,54.52 20.87,53.65 21.15,53.37 21.15,52.52 v1(21.3,52.37) 21.3,52.07 21.13,51.91 21.13,51.26 21.31,51.08 21.77,51.08 v6(22.03,50.82)
  LAYER_2 w0.175: v2(9.41,67.94) 7.16,65.69 v1(5.56,65.69)
  LAYER_3 w0.15: v2(12.9,68.99) 10.46,68.99 v2(9.41,67.94) ; v6(6.88,49.56) v6(9.05,49.56)
  LAYER_3 w0.175: v2(5.5,50.96) 5.5,50.69 v6(6,50.19) ; v2(9.41,67.94) 7.77,66.3 6.6,66.3 v4(6.01,65.72) 5.77,65.72 5.2,65.14 5.2,64.28 4.75,63.83 4.75,59.42 5.62,58.55 v6(5.92,58.55) ; v4(20.86,12.3) v7(24.54,12.3)
  LAYER_3 w0.2: v4(63.97,43.29) 58.35,43.29 58.17,43.11 55.93,43.11 55.72,42.9 53.83,42.9 53.69,42.76 v4(51.95,42.76) 49.55,42.76 49.44,42.65 v4(47.47,42.65)
  LAYER_5 w0.075: v4(6.01,65.72) 6.14,65.84 12.5,65.84 12.8,65.54 16.32,65.54 17.8,64.06 v4(18,64.06)
  LAYER_5 w0.175: v4(20.86,12.3) 18.9,12.3 18.13,13.07 16.71,13.07 16.04,13.74 16.04,14.61 12.94,17.71 12.94,17.84 12.79,17.99 12.69,17.99 10.09,20.59 10.09,21.16 9.94,21.31 9.94,35.27 7.73,37.48 7.73,43.33 8.5,44.1 8.5,46.61 7.8,47.31 7.8,48.53 6.88,49.45 v6(6.88,49.56) ; v4(64.79,60.06) 64.9,59.95 64.9,57.65 65.11,57.44 65.11,49.42 63.97,48.28 v4(63.97,43.29) 64.84,42.42 v4(64.84,39.96)
  LAYER_5 w0.2: v6(47.56,45.07) 47.56,43.4 47.47,43.31 v4(47.47,42.65) ; v4(51.99,41.36) 51.95,41.4 v4(51.95,42.76)
  LAYER_7 w0.15: 41.77,45.07 41.4,45.44 39.54,45.44 39.22,45.12 33.69,45.12 31.99,46.82 31.99,48.56 31.62,48.92 28.97,48.92 28.55,49.34 23.18,49.34 22.03,50.5 v6(22.03,50.82) 21.94,50.91 15.03,50.91 14.35,50.23 11.4,50.23 10.6,49.43 9.18,49.43 v6(9.05,49.56) ; v6(5.92,58.55) 5.69,58.33 5.69,50.49 v6(6,50.19) 6.25,50.19 v6(6.88,49.56)
  LAYER_7 w0.175: v6(47.56,45.07) 41.77,45.07
VREG_L15A_UIM1: length 93
  TOP w0.1: 17.49,57 17.57,56.97 17.98,56.97 U2000.110
  TOP w0.15: v2(55.68,41) R4212.2
  TOP w0.2: v4(15.34,56.81) 15.4,56.75 C2386.2 15.9,57 17.49,57
  TOP w0.25: C1127.2 C1126.2 ; R4212.2 R4211.2
  LAYER_2 w0.2: v6(29.05,51.7) 29.18,51.57 29.18,51.12 28.87,50.81 28.87,50.08 v2(29.13,49.81) ; v2(29.41,46.98) 29.41,41.41 v6(31.72,39.1)
  LAYER_3 w0.15: v2(55.68,41) 56.72,41 v4(57.09,41.37)
  LAYER_3 w0.175: v2(33,51.32) 32.73,51.59 32.42,51.59 32.24,51.77 31.79,51.77 31.76,51.8 30.49,51.8 30.2,51.5 29.69,51.5 v2(29.54,51.65)
  LAYER_3 w0.2: v2(59.33,53.97) 59.28,53.92 58.54,53.92 58.26,53.64 v4(57.99,53.64) ; v4(47.81,44.32) v2(53.56,44.32) 53.65,44.41 54.88,44.41 55.15,44.68 v4(57.26,44.68) ; v2(29.41,46.98) 29.41,49.54 v2(29.13,49.81)
  LAYER_5 w0.15: v4(57.09,41.37) 57.26,41.54 v4(57.26,44.68) 57.26,44.85 v7(58.41,46) 58.26,46.15 58.26,47.31 58.49,47.54 58.49,53.31 58.16,53.64 v4(57.99,53.64)
  LAYER_5 w0.175: v4(15.34,56.81) v6(15.34,52.61)
  LAYER_5 w0.2: v4(47.81,44.32) 47.81,43.19 47.75,43.13 47.75,38.91 v6(46.23,37.39)
  LAYER_7 w0.175: v6(29.05,51.7) 28.77,51.98 27.71,51.98 27.44,51.71 23.57,51.71 22.44,52.84 21.39,52.84 21.15,52.61 15.34,52.61 v6(15.34,52.61)
  LAYER_7 w0.2: v6(46.23,37.39) 33.33,37.39 arc(32.9,37.48) 32.53,37.72 31.72,38.54 v6(31.72,39.1)
  BOTTOM w0.15: U4250.10 59.4,46 v7(58.41,46) 58.22,46 58.05,45.83 58.05,45.69 R4250.2 57.48,45.12 57.48,44.87 57.14,44.54 J4250.6
VREG_L16A_2P7: length 127.6
  TOP w0.15: C7511.2 20.26,25.11 U7510.3 ; C7521.2 40.15,30.48 v2(40.24,30.48) 40.25,30.46 U7520.3 ; U7230.5 43.34,23.05 v4(43.25,23.14)
  TOP w0.175: R104.2 13.22,10.39 v2(13.25,10.36)
  TOP w0.2: U7500.14 18.2,23.41 v2(19.08,23.41) ; C205.2 57.56,21 57.36,20.8 R204.2
  LAYER_2 w0.2: v2(19.08,23.41) v2(19.08,22.53)
  LAYER_3 w0.15: v2(19.08,23.41) 19.45,23.78 19.45,24.97 v2(19.52,25.04)
  LAYER_3 w0.175: 34.01,29.36 39.57,29.36 39.94,28.99 40.57,28.99 40.86,29.28 40.86,29.55 41.02,29.71 ; v2(17.74,56.25) 17.74,56.29 17.56,56.47 17.24,56.47 16.98,56.73 16.09,56.73 15.78,57.04 15.2,57.04 15.03,56.87 v4(14.77,56.87) ; v2(40.24,30.48) 41,29.71 41.02,29.71 ; v4(43.1,28.64) 42.38,28.64 41.3,29.71 41.02,29.71 ; 25.95,23.06 29.81,23.06 v4(30.81,24.06) ; v4(19.04,13.32) 18.75,13.03 18.75,11.66 17.05,9.96 15.87,9.96 15.47,10.36 v2(13.25,10.36)
  LAYER_3 w0.2: 25.95,23.06 25.42,22.53 v2(19.08,22.53) 18.39,22.53 17.99,22.13 15.39,22.13 v4(15.12,22.4) ; v4(30.81,28.52) 31.67,28.52 32.51,29.36 34.01,29.36
  LAYER_5 w0.2: v4(19.04,13.32) 18.63,13.73 18.63,14.61 16.69,16.55 16.69,16.94 15.42,18.2 15.42,22.1 v4(15.12,22.4) 14.9,22.63 14.9,28.66 14.39,29.17 14.39,38.1 14,38.49 14,39.42 14.77,40.19 v4(14.77,56.87) ; 44.45,19.45 48.3,15.6 51.03,15.6 56.69,21.26 v4(57.59,21.26) ; v4(30.81,24.06) v4(30.81,28.52)
  LAYER_5 w0.25: v4(43.1,28.64) 43.1,23.29 v4(43.25,23.14) 43.25,20.65 44.45,19.45
VREG_L17A_UIM2: length 2.2
  TOP w0.1: 17.17,55.52 17.62,55.98 U2000.154
  TOP w0.175: C2383.2 16.12,55.76 16.38,55.52
  TOP w0.2: 16.38,55.52 17.17,55.52
VREG_L18A_2P7: length 4.2
  LAYER_3 w0.1: v2(14.7,57.94) 14.75,57.89 16.72,57.89 17.52,57.09 18.29,57.09 v2(18.45,56.93)
VREG_L19A_3P3: length 77.9
  TOP w0.2: v2(57.06,32.83) C4025.2
  TOP w0.25: C4024.2 58.01,33.04 58.01,32.49 58.07,32.43 ; U4080.8 54.86,30.39 C4085.1 ; U2000.121 17.15,56.72 C2385.2 ; C4025.2 56.81,33.33 U4000.6
  LAYER_2 w0.175: v6(54.86,39.19) v6(55.04,39.19) ; v6(58.54,29.68) v6(58.54,29.86) v6(58.72,29.68) v6(58.54,29.68)
  LAYER_3 w0.175: v6(54.86,39.19) v6(55.04,39.19) ; v6(58.54,29.86) v6(58.72,29.68) v6(58.54,29.68) v6(58.54,29.86)
  LAYER_3 w0.2: v2(57.06,32.83) 56.82,33.07 55.99,33.07 v2(55.79,32.86)
  LAYER_3 w0.25: 14.37,56.73 v4(14.52,56.58) 14.56,56.54 15.91,56.54 15.99,56.46 v2(16.85,56.46) ; 14.37,56.73 v4(14.24,56.73) ; 14.37,56.73 v4(14.42,56.73)
  LAYER_4 w0.175: v4(14.24,56.73) v4(14.42,56.73) v4(14.52,56.58) ; v6(54.86,39.19) v6(55.04,39.19) ; v6(58.72,29.68) v6(58.54,29.68) v6(58.54,29.86) v6(58.72,29.68)
  LAYER_5 w0.175: v6(55.79,37.06) 56.29,36.56 v4(56.29,35.83) ; v4(14.52,56.58) v4(14.42,56.73) v4(14.24,56.73) ; v6(54.86,39.19) v6(55.04,39.19) ; v4(55.81,35.88) 55.81,36.67 55.42,37.06 v6(55.29,37.06) 55.29,36.81 55.53,36.57 v4(55.53,36.09) ; v6(58.72,29.68) v6(58.54,29.68) v6(58.54,29.86) v6(58.72,29.68)
  LAYER_5 w0.2: v6(14.06,40.53) v6(14.24,40.52) v6(14.42,40.52)
  LAYER_5 w0.3: v4(55.58,33.57) 56.38,33.57 56.63,33.32 v4(57.05,33.32) 57.11,33.32 v6(57.92,32.51)
  LAYER_5 w0.75: v4(14.24,56.73) v6(14.24,40.52)
  LAYER_6 w0.175: v6(14.42,40.52) v6(14.24,40.52) v6(14.06,40.53) ; v6(54.86,39.19) v6(55.04,39.19) ; v6(58.72,29.68) v6(58.54,29.68) v6(58.54,29.86) v6(58.72,29.68)
  LAYER_7 w0.2: v6(14.24,40.52) 14.23,40.53 v6(14.06,40.53)
  LAYER_7 w0.75: 53.63,39.2 49.08,39.2 46.58,36.7 33.21,36.7 arc(32.62,36.82) 32.13,37.15 29.55,39.72 arc(29.17,39.98) 28.71,40.07 16.09,40.07 15.64,40.52 v6(14.42,40.52) v6(14.24,40.52)
  vias: v1(54.81,30.36) v1(57.92,32.33) v1(58.1,32.51) v1(58.1,32.33) v2(54.81,30.36) v2(57.92,32.33) v2(58.1,32.51) v2(58.1,32.33) v3(54.81,30.36) v3(57.92,32.33) v3(58.1,32.51) v3(58.1,32.33) v4(54.81,30.36) v4(57.92,32.33) v4(58.1,32.51) v4(58.1,32.33) v5(54.81,30.36) v5(57.92,32.33) v5(58.1,32.51) v5(58.1,32.33) v6(54.81,30.36) v6(57.92,32.33) v6(58.1,32.51) v6(58.1,32.33)
VREG_OLEDB: length 64.1
  LAYER_2 w0.045: v1(36.49,38.83) 36.49,38.15 35.37,37.03 34.83,37.03 34.48,37.38 v2(34.27,37.38)
  LAYER_2 w0.175: v2(34.27,37.38) v2(34.27,37.2)
  LAYER_3 w0.175: 34.27,37.22 v2(34.27,37.38)
  LAYER_3 w0.5: 34.27,37.22 v2(34.27,37.2) 34.85,36.62 35.33,36.62 35.92,36.03 46.54,36.03 48.43,37.92 49.36,37.92 50.37,38.93 53.24,38.93 53.53,38.64 v4(58.39,38.64)
  LAYER_4 w0.175: v4(58.65,38.64) v4(58.52,38.52) v4(58.39,38.64)
  LAYER_5 w0.5: v4(58.52,38.52) 58.52,40.23 61.97,43.68 61.97,48.55 63.38,49.96 63.38,57.31 62.99,57.7 v6(62.99,58.62)
  LAYER_6 w0.175: v6(63.12,58.75) v6(62.99,58.62) v6(62.85,58.76)
  LAYER_7 w0.15: v7(57.53,65.07) 57.43,64.97 v7(57.38,64.97)
  LAYER_7 w0.5: 62.98,58.78 62.98,61.2 60.18,64 58.44,64 57.53,64.91 v7(57.53,65.07)
  BOTTOM w0.15: 57.4,65.14 57.57,65.14 57.59,65.13 ; 57.4,65.14 57.4,65.07 C5387.2 ; 57.4,65.14 57.24,65.3 J5300.7 ; 57.59,65.13 v7(57.53,65.07) ; 57.59,65.13 J5300.5
VREG_RFCLK: length 2.4
  TOP w0.105: U2000.200 18.97,54.57 18.81,54.4 18.52,54.4 18.44,54.32 18.44,53.57 18.77,53.24 C2320.1
VREG_S1A_0P752: length 17.9
  TOP w0.2: 35.47,56.22 U1001.AC17 ; 35.47,56.22 U1001.AC15 U1001.AD14 v4(35.47,57.2) v4(35.47,57.7) v4(35.23,57.95) U1001.AF8 34.91,58.12 34.56,58.12 v4(34.48,58.2) 34.41,58.12 34.06,58.12 U1001.AL7 33.49,58.2 ; 35.47,56.22 34.98,56.22
  LAYER_2 w0.175: v4(33.84,60.97) v4(33.93,61.2) v4(33.93,61.38) v4(33.74,61.38) ; v4(31.42,61.38) v4(31.42,61.2) ; v4(33,62.62) v4(33,62.45) ; v4(32.33,61.38) v4(32.33,61.2) ; v6(34.65,61.38) v4(34.65,61.2) ; v4(31.76,62.62) v4(31.76,62.45) ; v4(33,61.38) v4(33,61.2) ; v4(33.98,62.63) v4(33.98,62.45) ; v4(31.27,62.62) v4(31.27,62.45) ; v4(32.23,62.45) 32.23,62.46 v4(32.23,62.63) ; v4(31.76,61.38) v4(31.76,61.2)
  LAYER_2 w0.18: v4(27.17,59.57) v4(26.97,59.57) v4(26.97,59.75) v4(27.17,59.75) ; v4(27.17,59.57) v4(27.35,59.57) v4(27.35,59.75) v4(27.17,59.75) ; v4(27.17,59.57) v4(27.17,59.75)
  LAYER_3 w0.175: v4(34.42,62.63) v4(34.24,62.63) v4(34.24,62.45) ; v4(34.42,62.63) v4(34.24,62.45) ; v4(34.42,62.63) v4(34.42,62.45) v4(34.24,62.45) ; v4(33,62.62) v4(33,62.45) ; v4(33.98,62.63) v4(33.98,62.45) ; v4(31.76,62.45) v4(31.76,62.62) ; v4(32.23,62.63) 32.23,62.63 v4(32.23,62.45) ; v4(32.33,61.38) v4(32.33,61.2) ; v6(34.65,61.38) v4(34.65,61.2) ; v4(31.76,61.2) v4(31.76,61.38) ; v4(31.27,62.45) v4(31.27,62.62) ; v4(31.42,61.38) v4(31.42,61.2) ; v4(33.74,61.38) v4(33.93,61.38) v4(33.93,61.2) v4(33.84,60.97) ; v4(33,61.38) v4(33,61.2)
  LAYER_3 w0.18: v4(27.17,59.75) v4(27.35,59.75) v4(27.35,59.57) v4(27.17,59.57) ; v4(27.17,59.75) v4(27.17,59.57) ; v4(27.17,59.75) v4(26.97,59.75) v4(26.97,59.57) v4(27.17,59.57)
  LAYER_4 w0.175: v4(34.42,62.63) v4(34.42,62.45) v4(34.24,62.45) ; v4(34.42,62.63) v4(34.24,62.45) ; v4(34.42,62.63) v4(34.24,62.63) v4(34.24,62.45) ; v4(33.93,61.2) v4(33.93,61.38) v4(33.74,61.38) ; v4(31.76,61.38) v4(31.76,61.2) ; v4(31.42,61.38) v4(31.42,61.2) ; v4(32.33,61.38) v4(32.33,61.2) ; v4(31.27,62.62) v4(31.27,62.45) ; v4(33.98,62.63) v4(33.98,62.45) ; v4(33,62.62) v4(33,62.45) ; v4(32.23,62.63) v4(32.23,62.45) ; v4(31.76,62.62) v4(31.76,62.45) ; v4(33,61.38) v4(33,61.2) ; v6(34.65,61.38) v4(34.65,61.2)
  LAYER_4 w0.18: v4(27.17,59.57) v4(27.35,59.57) v4(27.35,59.75) v4(27.17,59.75) ; v4(27.17,59.57) v4(27.17,59.75) ; v4(27.17,59.57) v4(26.97,59.57) v4(26.97,59.75) v4(27.17,59.75)
  vias: v1(32.76,60.79) v1(33.53,58.24) v1(33.75,58.39) v1(33.96,58.24) v1(34.69,55.51) v1(34.95,58.16) v1(35.01,56.26) v1(35.43,56.75) v1(35.44,56.25) v1(35.74,56.52) v2(32.76,60.79) v2(33.53,58.24) v2(33.75,58.39) v2(33.96,58.24) v2(34.69,55.51) v2(34.95,58.16) v2(35.01,56.26) v2(35.43,56.75) v2(35.44,56.25) v2(35.74,56.52) v3(32.76,60.79) v3(33.53,58.24) v3(33.75,58.39) v3(33.96,58.24) v3(34.69,55.51) v3(34.95,58.16) v3(35.01,56.26) v3(35.43,56.75) v3(35.44,56.25) v3(35.74,56.52) v4(32.76,60.79) v4(33.53,58.24) v4(33.75,58.39) v4(33.96,58.24) v4(34.69,55.51) v4(34.95,58.16) v4(35.01,56.26) v4(35.43,56.75) v4(35.44,56.25) v4(35.74,56.52)
VREG_S1B_0P752: length 33.9
  TOP w0.05: v5(31.9,47.16) v5(31.9,47.34) 31.9,47.37 ; 31.9,47.56 v5(31.9,47.52) 31.9,47.37 ; 31.9,47.37 31.88,47.39 ; 32.05,47.36 32.05,47.36 32.09,47.33
  TOP w0.175: C1151.2 30.54,54.38 30.3,54.38 v5(30.25,54.33)
  TOP w0.2: v5(35.47,53.25) 35.72,53.49 v5(35.47,53.74) ; v5(35.47,53.25) 35.72,53 U1001.AD30 ; v5(35.47,53.25) U1001.AE27 ; U1001.AB22 U1001.AC23 ; U1001.AB22 U1001.Y20 ; U1001.AB22 U1001.AC21 ; U1001.AC23 U1001.AD24 ; U1001.AC23 U1001.AD22 U1001.AC21 ; U1001.AE19 U1001.AD20 U1001.AC19 U1001.AD18 U1001.AE19 ; U1001.AE19 U1001.AF18 34.73,55.97 ; U1001.Y20 U1001.AA19 U1001.AB20 U1001.AC21 ; U1001.Y20 v5(36.96,55.72) ; U1001.Y20 U1001.W21 v5(36.96,55.23) ; v5(34.98,53.25) U1001.AG27 v5(34.98,53.74) ; v5(34.98,53.25) U1001.AD30 ; v5(34.98,53.25) U1001.AG29 ; v5(34.98,53.25) U1001.AE27 ; v5(36.96,55.72) U1001.U19 v5(36.96,55.23) ; v5(36.96,55.72) U1001.W17 v5(36.96,56.22) U1001.W15 v5(36.96,56.71) U1001.U13 v5(36.96,57.2) U1001.U11 v5(36.96,57.7) ; U1001.AG25 v5(34.98,53.74) ; v5(34.98,53.74) U1001.AE25 ; v5(34.98,53.74) U1001.AE27 ; U1001.AE25 v5(35.47,53.74) ; U1001.AE25 U1001.AD24 ; U1001.AD30 U1001.AE31 U1001.AD32 35.72,52.5 U1001.AD30 ; U1001.AD24 U1001.AC25 v5(35.47,53.74) ; U1001.H16 v5(38.94,56.22) v5(38.94,56.71) v5(38.94,57.2) ; U1001.H16 39.36,56.29 39.36,57.13 v5(39.43,57.2) ; U1001.H16 U1001.G17 ; v5(35.47,53.74) U1001.AE27 ; v5(38.94,57.2) U1001.K10 v5(39.43,57.7) 39.36,57.63 39.36,57.28 v5(39.43,57.2) ; v5(38.94,57.2) v5(39.43,57.2) ; v5(36.96,55.23) U1001.U21
  LAYER_2 w0.175: v5(40.07,61.52) v5(40.07,61.7) v5(40.07,61.89) v5(40.07,62.06) ; v5(31.91,48.59) v5(31.73,48.59) ; v5(31.91,48.59) v5(32.01,48.75) v5(32.09,48.59) v5(31.91,48.59) ; v5(38.82,62.26) v5(38.82,62.08) v5(38.82,61.9) v5(38.82,61.72)
  LAYER_3 w0.175: v5(40.07,62.06) v5(40.07,61.89) v5(40.07,61.7) v5(40.07,61.52) ; v5(31.91,48.59) v5(32.09,48.59) v5(32.01,48.75) v5(31.91,48.59) ; v5(31.91,48.59) v5(31.73,48.59) ; v5(38.82,62.26) v5(38.82,62.08) v5(38.82,61.9) v5(38.82,61.72)
  LAYER_4 w0.175: v5(31.73,48.59) v5(31.91,48.59) ; v5(31.91,48.59) v5(32.01,48.75) v5(32.09,48.59) v5(31.91,48.59) ; v5(38.82,62.26) v5(38.82,62.08) v5(38.82,61.9) v5(38.82,61.72) ; v5(40.07,61.52) v5(40.07,61.7) v5(40.07,61.89) v5(40.07,62.06)
  LAYER_5 w0.045: v5(32.09,48.59) 32.13,48.55 E1074.2
  LAYER_5 w0.175: v5(31.91,48.59) v5(32.09,48.59) v5(32.01,48.75) v5(31.91,48.59) ; v5(31.91,48.59) v5(31.73,48.59) ; v5(40.07,62.06) v5(40.07,61.89) v5(40.07,61.7) v5(40.07,61.52) ; v5(38.82,62.26) v5(38.82,62.08) v5(38.82,61.9) v5(38.82,61.72)
  LAYER_6 w0.2: v5(31.9,47.34) 31.4,47.34 30.71,48.03 v5(30.71,48.31)
  vias: v1(32.08,47.52) v1(32.08,47.34) v1(32.08,47.16) v1(34.77,55.93) v1(34.99,60.62) v1(34.98,55.17) v1(35.21,55.5) v1(35.43,55.71) v1(35.46,55.18) v1(35.44,54.7) v1(35.44,54.2) v1(35.47,52.8) v1(35.47,52.21) v1(35.67,60.65) v1(35.68,55.01) v1(35.74,55.47) v1(35.75,54.44) v1(36.02,55.2) v1(36,54.77) v1(36.26,55.51) v1(36.51,55.19) v1(38.97,57.67) v1(39.41,56.25) v1(40.06,60.6) v1(42.14,56.62) v2(32.08,47.52) v2(32.08,47.34) v2(32.08,47.16) v2(34.77,55.93) v2(34.99,60.62) v2(34.98,55.17) v2(35.21,55.5) v2(35.43,55.71) v2(35.46,55.18) v2(35.44,54.7) v2(35.44,54.2) v2(35.47,52.8) v2(35.47,52.21) v2(35.67,60.65) v2(35.68,55.01) v2(35.74,55.47) v2(35.75,54.44) v2(36.02,55.2) v2(36,54.77) v2(36.26,55.51) v2(36.51,55.19) v2(38.97,57.67) v2(39.41,56.25) v2(40.06,60.6) v2(42.14,56.62) v3(32.08,47.52) v3(32.08,47.34) v3(32.08,47.16) v3(34.77,55.93) v3(34.99,60.62) v3(34.98,55.17) v3(35.21,55.5) v3(35.43,55.71) v3(35.46,55.18) v3(35.44,54.7) v3(35.44,54.2) v3(35.47,52.8) v3(35.47,52.21) v3(35.67,60.65) v3(35.68,55.01) v3(35.74,55.47) v3(35.75,54.44) v3(36.02,55.2) v3(36,54.77) v3(36.26,55.51) v3(36.51,55.19) v3(38.97,57.67) v3(39.41,56.25) v3(40.06,60.6) v3(42.14,56.62) v4(32.08,47.52) v4(32.08,47.34) v4(32.08,47.16) v4(34.77,55.93) v4(34.99,60.62) v4(34.98,55.17) v4(35.21,55.5) v4(35.43,55.71) v4(35.46,55.18) v4(35.44,54.7) v4(35.44,54.2) v4(35.47,52.8) v4(35.47,52.21) v4(35.67,60.65) v4(35.68,55.01) v4(35.74,55.47) v4(35.75,54.44) v4(36.02,55.2) v4(36,54.77) v4(36.26,55.51) v4(36.51,55.19) v4(38.97,57.67) v4(39.41,56.25) v4(40.06,60.6) v4(42.14,56.62) v5(32.08,47.52) v5(32.08,47.34) v5(32.08,47.16) v5(34.77,55.93) v5(34.99,60.62) v5(34.98,55.17) v5(35.21,55.5) v5(35.43,55.71) v5(35.46,55.18) v5(35.44,54.7) v5(35.44,54.2) v5(35.47,52.8) v5(35.47,52.21) v5(35.67,60.65) v5(35.68,55.01) v5(35.74,55.47) v5(35.75,54.44) v5(36.02,55.2) v5(36,54.77) v5(36.26,55.51) v5(36.51,55.19) v5(38.97,57.67) v5(39.41,56.25) v5(40.06,60.6) v5(42.14,56.62)
VREG_S1C_1P125: length 40.8
  TOP w0.05: C2564.1 26.52,49.89 v2(26.71,49.7) ; 20.34,53.34 20.33,53.33 v6(20.33,53.3)
  TOP w0.175: 20.34,53.34 20.27,53.41 20.27,54.59 U2000.214
  TOP w0.25: C2396.2 26.87,51.74
  LAYER_2 w0.175: v2(27.18,49.69) v2(27.18,49.87)
  LAYER_2 w0.2: v1(17.71,55.7) 17.36,55.35 16.36,55.35 v6(16.12,55.11)
  LAYER_3 w0.175: v2(39.22,42.58) 39.14,42.58 39.07,42.65
  LAYER_3 w0.2: v2(26.71,49.7) 26.71,49.35 25.76,48.4 v2(24.82,48.4)
  LAYER_3 w0.3: v4(32.78,43.64) 34.38,43.64 34.51,43.77 36.06,43.77 36.4,43.43 36.85,43.43 36.96,43.53 37.59,43.53 37.61,43.51 38.2,43.51 39.07,42.65
  LAYER_5 w0.175: 20.24,53.21 v6(20.33,53.3)
  LAYER_5 w0.25: v4(32.78,43.64) 31.99,44.43 v6(31.99,45.95)
  LAYER_5 w0.3: v6(21.57,47.65) 21.57,49.76 21.04,50.29 21.04,50.88 20.66,51.26 20.66,51.49 20.24,51.91 20.24,53.21
  LAYER_7 w0.25: v6(20.33,53.3) 17.93,53.3 v6(16.12,55.11)
  LAYER_7 w0.3: v6(31.99,45.95) 31.29,46.65 31.29,47.24 30.14,48.39 28.62,48.39 28.22,48.79 v6(27.89,48.79) 22.93,48.79 21.79,47.65 v6(21.57,47.65)
VREG_S2A_S3A_0P752: length 11.7
  TOP w0.2: v2(33.49,56.22) U1001.AN15 U1001.AM14 ; v2(33.49,56.22) v2(33.99,56.22) ; v2(33.49,56.22) U1001.AM18 ; v2(33.99,56.22) U1001.AK18 ; v2(33.99,56.22) v2(33.99,56.71) ; U1001.AK18 U1001.AJ19 U1001.AK20 U1001.AL21 U1001.AM20 ; U1001.AK18 U1001.AM18 ; U1001.AM12 U1001.AL11 v2(33.99,57.2) U1001.AJ13 v2(33.99,56.71) ; U1001.AM12 U1001.AN11 ; U1001.AM12 U1001.AM14 ; U1001.AM18 U1001.AN19 U1001.AM20 ; v2(33.99,56.71) U1001.AM14 ; U1001.AM20 U1001.AN21
  LAYER_2 w0.175: v2(27.77,60.06) v2(27.77,60.24) v2(27.77,60.42) v2(27.77,60.6) ; v2(24.94,61.51) v2(25.12,61.33) ; v2(24.94,61.51) v2(24.94,61.33) ; v2(24.94,61.51) v2(25.12,61.51) v2(25.12,61.33) ; v2(25.12,61.33) v2(24.94,61.33) ; v2(25.12,61.33) v2(24.94,61.15) ; v2(25.12,61.33) v2(25.12,61.15) ; v2(25.12,61.15) v2(25.12,60.97) ; v2(25.12,61.15) v2(24.94,61.15) ; v2(25.12,60.97) v2(24.94,60.97) v2(24.94,61.15) ; v2(25.12,60.97) v2(24.94,61.15) ; v2(24.94,61.33) v2(24.94,61.15) ; v2(28.71,56.31) v2(28.71,56.11)
  vias: v1(28.53,60.21) v1(28.54,60.03) v1(28.54,59.62) v1(28.54,59.44) v1(28.71,60.21) v1(28.71,60.03) v1(28.72,59.62) v1(28.72,59.44) v1(28.71,58.72) v1(28.71,58.32) v1(28.71,57.42) v1(28.71,57.02) v1(29.8,55.53) v1(29.88,60.02) v1(29.88,59.62) v1(29.88,58.72) v1(29.88,58.32) v1(29.88,57.42) v1(29.88,57.02) v1(29.88,56.3) v1(29.88,55.91) v1(33.22,57.49) v1(33.21,56.49) v1(33.22,55.51) v1(33.21,54.94) v1(33.46,57.18) v1(33.5,56.77) v1(33.52,55.77) v1(33.49,55.23) v1(33.72,57.5) v1(33.75,54.93) v1(33.97,55.77) v1(34,55.23) v1(34.29,56.96) v1(34.27,55.52) v2(28.53,60.21) v2(28.54,60.03) v2(28.54,59.62) v2(28.54,59.44) v2(28.71,60.21) v2(28.71,60.03) v2(28.72,59.62) v2(28.72,59.44) v2(28.71,58.72) v2(28.71,58.32) v2(28.71,57.42) v2(28.71,57.02) v2(29.8,55.53) v2(29.88,60.02) v2(29.88,59.62) v2(29.88,58.72) v2(29.88,58.32) v2(29.88,57.42) v2(29.88,57.02) v2(29.88,56.3) v2(29.88,55.91) v2(33.22,57.49) v2(33.21,56.49) v2(33.22,55.51) v2(33.21,54.94) v2(33.46,57.18) v2(33.5,56.77) v2(33.52,55.77) v2(33.49,55.23) v2(33.72,57.5) v2(33.75,54.93) v2(33.97,55.77) v2(34,55.23) v2(34.29,56.96) v2(34.27,55.52)
VREG_S2B_0P752: length 13.7
  TOP w0.2: v4(38.2,53.49) U1001.M28 U1001.N29 U1001.M30 U1001.N31 U1001.M32 ; U1001.M34 U1001.N33 U1001.M32 ; U1001.M34 U1001.N35 ; U1001.M34 U1001.L33 U1001.M32 ; U1001.V32 v4(37.21,52.5) U1001.V30 U1001.U29 U1001.V28
  LAYER_2 w0.175: v4(41.44,48.68) v4(41.26,48.68) v4(41.08,48.68) v4(40.9,48.68) ; v4(41.23,47.91) v4(41.4,47.91) ; v4(38.96,47.49) v4(39.13,47.49) ; v4(38.9,48.9) v4(38.9,48.72) ; v4(38.56,47.9) v4(38.68,47.77) ; v4(37.38,48.11) v4(37.35,48.29) v4(37.51,48.37) v4(37.54,48.19) v4(37.38,48.11) ; v4(40.66,48.28) v4(40.4,48.45) v4(40.57,48.45) v4(40.66,48.28)
  LAYER_3 w0.175: v4(41.23,47.91) v4(41.4,47.91) ; v4(38.96,47.49) v4(39.13,47.49) ; v4(38.56,47.9) v4(38.68,47.77) ; v4(40.9,48.68) v4(41.08,48.68) v4(41.26,48.68) v4(41.44,48.68) ; v4(38.9,48.9) v4(38.9,48.72) ; v4(37.38,48.11) v4(37.54,48.19) v4(37.51,48.37) v4(37.35,48.29) v4(37.38,48.11) ; v4(40.4,48.45) v4(40.66,48.28) v4(40.57,48.45) v4(40.4,48.45)
  LAYER_4 w0.175: v4(41.44,48.68) v4(41.26,48.68) v4(41.08,48.68) v4(40.9,48.68) ; v4(38.56,47.9) v4(38.68,47.77) ; v4(41.4,47.91) v4(41.23,47.91) ; v4(38.96,47.49) v4(39.13,47.49) ; v4(38.9,48.9) v4(38.9,48.72) ; v4(37.35,48.29) v4(37.38,48.11) v4(37.54,48.19) v4(37.51,48.37) v4(37.35,48.29) ; v4(40.57,48.45) v4(40.4,48.45) v4(40.66,48.28) v4(40.57,48.45)
  LAYER_5 w0.175: v4(37.51,48.37) v4(37.54,48.19) v4(37.38,48.11) v4(37.35,48.29) 37.6,48.41
  vias: v1(36.93,53.28) v1(36.92,52.78) v1(36.93,52.22) v1(37.26,53) v1(38.15,53) v1(38.16,52.54) v1(38.15,52.01) v1(38.16,51.48) v1(38.5,53.24) v1(38.5,52.75) v1(38.46,52.29) v1(38.47,51.71) v1(38.74,52.01) v1(40.48,48.77) v2(36.93,53.28) v2(36.92,52.78) v2(36.93,52.22) v2(37.26,53) v2(38.15,53) v2(38.16,52.54) v2(38.15,52.01) v2(38.16,51.48) v2(38.5,53.24) v2(38.5,52.75) v2(38.46,52.29) v2(38.47,51.71) v2(38.74,52.01) v2(40.48,48.77) v3(36.93,53.28) v3(36.92,52.78) v3(36.93,52.22) v3(37.26,53) v3(38.15,53) v3(38.16,52.54) v3(38.15,52.01) v3(38.16,51.48) v3(38.5,53.24) v3(38.5,52.75) v3(38.46,52.29) v3(38.47,51.71) v3(38.74,52.01) v3(40.48,48.77) v4(36.93,53.28) v4(36.92,52.78) v4(36.93,52.22) v4(37.26,53) v4(38.15,53) v4(38.16,52.54) v4(38.15,52.01) v4(38.16,51.48) v4(38.5,53.24) v4(38.5,52.75) v4(38.46,52.29) v4(38.47,51.71) v4(38.74,52.01) v4(40.48,48.77)
VREG_S2C_1P125: length 19.9
  TOP w0.15: C1124.2 42.14,55.52 v6(41.93,55.31)
  TOP w0.175: v6(44.84,56) U1600.K2 ; U1600.R2 44.87,53.24 v6(44.87,53.21)
  LAYER_2 w0.175: v6(50.21,50.24) v6(50.21,50.06) ; v6(55.01,52.1) v6(55.01,51.92)
  LAYER_2 w0.2: v1(51.13,60) 51.37,60 52.39,58.99 v1(54.98,58.99)
  LAYER_3 w0.175: v6(50.21,50.24) v6(50.21,50.06) ; v6(55.01,52.1) v6(55.01,51.92)
  LAYER_4 w0.175: v6(55.01,52.1) v6(55.01,51.92) ; v6(50.21,50.24) v6(50.21,50.06)
  LAYER_5 w0.15: v6(41.93,55.31) 41.59,54.98 v4(39.72,54.98)
  LAYER_5 w0.175: v6(55.01,52.1) v6(55.01,51.92) ; v6(50.21,50.24) v6(50.21,50.06)
  LAYER_6 w0.175: v6(55.01,52.1) v6(55.01,51.92) ; v6(50.21,50.24) v6(50.21,50.06)
  LAYER_7 w0.25: v6(41.93,55.31) 43.08,55.31 43.77,56 v6(44.84,56) 45.24,55.6 v6(47.63,55.6) ; v6(48.63,51.89) 48.5,52.02 46.06,52.02 v6(44.87,53.21)
  vias: v1(55.03,52.74) v2(55.03,52.74) v3(55.03,52.74) v4(55.03,52.74) v5(55.03,52.74) v6(55.03,52.74)
VREG_S3B_S4B_0P752: length 26.2
  TOP w0.175: v4(37.92,46.82) v4(38.1,46.82)
  TOP w0.2: U1001.R23 v4(37.45,54.23) ; U1001.R23 v4(37.95,54.73) U1001.R21 v4(37.95,55.23) 37.95,55.27 37.84,55.38 37.84,55.61 U1001.P18 ; U1001.R23 v4(37.95,54.23) ; v4(37.45,54.23) v4(37.95,54.23) ; v4(37.45,54.23) v4(36.96,54.23) ; v4(37.45,54.23) U1001.T26 ; v4(37.45,54.23) U1001.U23 v4(36.96,54.23) ; v4(37.95,54.23) U1001.P26 ; v4(37.95,54.23) U1001.M24 U1001.M26 38.35,53.83 38.04,53.83 U1001.P26 ; 37.95,56.22 v4(37.7,55.97) U1001.P18 ; 37.95,56.22 v4(38.2,55.97) U1001.P18 ; 37.95,56.22 v4(38.2,56.46) U1001.P14 ; U1001.V26 U1001.T26 ; U1001.V26 v4(36.96,54.23) ; U1001.V26 v4(36.46,53.74) ; U1001.T26 U1001.P26 ; v4(36.96,54.23) U1001.Y24 ; U1001.AA33 v4(36.46,52.26) U1001.Y30 v4(36.22,53) U1001.Y28 v4(36.46,53.74) ; v4(36.46,53.74) U1001.Y24 ; U1001.P14 v4(38.2,56.96) ; U1001.P14 v4(37.7,56.96) ; U1001.Y24 U1001.AA23
  LAYER_2 w0.175: v4(37.46,62.55) v4(37.46,62.37) ; v4(36.48,61.29) v4(36.48,61.11) ; v4(37.92,47) v4(37.74,47) v4(37.92,46.82) ; v4(37.92,47) v4(38.1,46.82) v4(37.92,46.82) ; v4(37.92,47) v4(37.92,46.82) ; v4(35.48,46.59) v4(35.48,46.41) ; v4(38.2,62.55) v4(38.2,62.37) ; v4(36.45,62.55) v4(36.45,62.37) ; v4(34.12,47.51) v4(34.24,47.64) ; v4(35.58,48.21) v4(35.58,48.03) v4(35.58,47.85) v4(35.58,47.67) v4(35.58,47.49) ; v4(35.76,46.6) v4(35.76,46.42) ; v4(34.9,48.85) v4(34.9,48.67) ; v4(37.45,61.29) v4(37.45,61.11) ; v4(38.05,61.29) v4(38.05,61.11) ; v4(36.03,46.48) v4(36.16,46.36)
  LAYER_3 w0.175: v4(35.48,46.41) v4(35.48,46.59) ; v4(34.9,48.85) v4(34.9,48.67) ; v4(38.05,61.29) v4(38.05,61.11) ; v4(34.12,47.51) v4(34.24,47.64) ; v4(35.76,46.42) v4(35.76,46.6) ; v4(36.45,62.55) v4(36.45,62.37) ; v4(38.2,62.55) v4(38.2,62.37) ; v4(37.92,46.82) v4(38.1,46.82) v4(37.92,47) ; v4(37.92,46.82) v4(37.74,47) v4(37.92,47) ; v4(37.92,46.82) v4(37.92,47) ; v4(37.46,62.55) v4(37.46,62.37) ; v4(37.45,61.29) v4(37.45,61.11) ; v4(36.03,46.48) v4(36.16,46.36) ; v4(35.58,47.49) v4(35.58,47.67) v4(35.58,47.85) v4(35.58,48.03) v4(35.58,48.21) ; v4(36.48,61.29) v4(36.48,61.11)
  LAYER_4 w0.175: v4(37.92,47) v4(37.74,47) v4(37.92,46.82) ; v4(37.92,47) v4(38.1,46.82) v4(37.92,46.82) ; v4(37.92,47) v4(37.92,46.82) ; v4(36.48,61.29) v4(36.48,61.11) ; v4(37.45,61.29) v4(37.45,61.11) ; v4(35.58,48.21) v4(35.58,48.03) v4(35.58,47.85) v4(35.58,47.67) v4(35.58,47.49) ; v4(38.2,62.55) v4(38.2,62.37) ; v4(34.9,48.85) v4(34.9,48.67) ; v4(36.45,62.55) v4(36.45,62.37) ; v4(35.48,46.41) v4(35.48,46.59) ; v4(36.16,46.36) v4(36.03,46.48) ; v4(35.76,46.42) v4(35.76,46.6) ; v4(37.46,62.55) v4(37.46,62.37) ; v4(38.05,61.29) v4(38.05,61.11) ; v4(34.12,47.51) v4(34.24,47.64)
  vias: v1(36.18,51.97) v1(36.25,54.45) v1(37.46,53.77) v1(38.49,53.77) v2(36.18,51.97) v2(36.25,54.45) v2(37.46,53.77) v2(38.49,53.77) v3(36.18,51.97) v3(36.25,54.45) v3(37.46,53.77) v3(38.49,53.77) v4(36.18,51.97) v4(36.25,54.45) v4(37.46,53.77) v4(38.49,53.77)
VREG_S4A_2P04: length 105.9
  TOP w0.105: U2000.213 U2000.191
  TOP w0.15: v2(31.48,64.36) 31.41,64.42 31.41,64.7 ; J5500.48 31.41,64.7 ; 31.41,64.7 31.42,64.69 31.65,64.69 31.76,64.8 J5500.46
  TOP w0.2: C5001.2 57.3,59.44 U5000.4
  LAYER_2 w0.175: v2(20.04,51.49) v4(20.23,51.49)
  LAYER_3 w0.045: v4(21.74,52.55) 21.62,52.43 21.62,51.68 v2(21.47,51.53) ; v2(22.17,55.68) 21.87,55.38 21.87,55.09 21.63,54.85 v4(21.63,54.74)
  LAYER_3 w0.175: v4(20.23,51.49) v2(20.04,51.49)
  LAYER_3 w0.2: v2(20.04,51.49) 19.52,52.01 18.99,52.01 18.63,52.37 17.78,52.37 v2(17.67,52.48) 17.67,52.65 17.84,52.82 17.84,53.55 18.77,54.48 v2(18.77,55.2) ; v2(35.25,38.63) 33.98,38.63 33.41,39.2 32.67,39.2 32.36,39.51 30.95,39.51 v6(30.69,39.77) 30.66,39.8 30.66,40.4 30.94,40.68 31.59,40.68 31.93,40.34 35.03,40.34 35.46,40.77 v2(35.47,40.77)
  LAYER_3 w0.25: v2(31.48,64.36) 31.48,64.51 30.55,65.44 v6(30.55,65.68)
  LAYER_3 w0.3: v6(19.56,65.68) 18.77,64.89 18.77,63.58 19.26,63.09 19.85,63.09 v6(19.97,62.97)
  LAYER_5 w0.045: v4(21.74,52.55) 21.61,52.68 21.61,53.74 21.71,53.84 21.71,54.66 v4(21.63,54.74)
  LAYER_5 w0.2: v6(21.26,40.78) 21.26,49.6 20.73,50.13 20.73,50.75 20.34,51.14 20.34,51.38 v4(20.23,51.49) 19.92,51.8 19.92,53.66 19.54,54.04 19.54,56.36 19.18,56.72 18.91,56.72 18.49,57.14 18.49,57.91 v6(17.99,58.41)
  LAYER_7 w0.2: v6(21.26,40.78) 29.68,40.78 v6(30.69,39.77)
  LAYER_7 w0.3: v6(17.99,58.41) 20.47,60.89 20.47,62.47 v6(19.97,62.97) ; v6(19.56,65.68) v6(30.55,65.68) 31.04,65.19 39.56,65.19 40.08,65.71 44.43,65.71 50.47,59.67 56.44,59.67 v6(57.27,58.84)
VREG_S5A_0P752: length 17.9
  TOP w0.175: v4(30.79,53.45) v4(30.61,53.45)
  TOP w0.2: 33.74,52.01 33.99,52.26 33.74,52.5 U1001.AK30 U1001.AK28 ; U1001.AM26 U1001.AN25 U1001.AL23 v4(34.24,53.99) ; U1001.AM26 U1001.AK26 ; U1001.AM26 U1001.AM28 ; U1001.AK28 U1001.AM28 ; U1001.AK28 U1001.AK26 ; U1001.AK26 v4(34.24,53.99) ; v4(34.24,53.99) U1001.AH24 ; U1001.AM28 U1001.AN29
  LAYER_2 w0.175: v2(29.81,52.3) v4(29.81,52.48) v4(29.99,52.48) v4(30.17,52.48) ; v4(28.58,52.24) v4(28.58,52.42) v4(28.74,52.5) v4(28.74,52.33) ; v4(28.58,52.24) v4(28.74,52.1) v4(28.74,52.33) ; v4(28.58,52.24) v4(28.74,52.33) ; v4(30.43,53.45) v4(30.61,53.45) v4(30.79,53.45) ; v4(30.63,52.49) v4(30.45,52.49) ; v4(28.74,53.51) 28.73,53.51 v4(28.58,53.41) ; v4(28.74,53.51) v4(28.59,53.6) v4(28.58,53.41) ; v4(28.74,53.51) v4(28.74,53.32) v4(28.58,53.41) ; v4(29.81,53.34) v4(29.81,53.52) v4(29.99,53.52) v4(29.99,53.34) v4(29.81,53.34)
  LAYER_3 w0.175: v4(28.74,53.51) 28.73,53.51 v4(28.58,53.41) ; v4(28.74,53.51) v4(28.74,53.32) v4(28.58,53.41) ; v4(28.74,53.51) v4(28.59,53.6) v4(28.58,53.41) ; v4(28.74,52.33) v4(28.58,52.24) ; v4(28.74,52.33) v4(28.74,52.5) v4(28.58,52.42) v4(28.58,52.24) ; v4(28.74,52.33) v4(28.74,52.1) v4(28.58,52.24) ; v4(30.45,52.49) v4(30.63,52.49) ; v4(30.43,53.45) v4(30.61,53.45) v4(30.79,53.45) ; v4(30.17,52.48) v4(29.99,52.48) v4(29.81,52.48) v2(29.81,52.3) ; v4(29.81,53.34) v4(29.81,53.52) v4(29.99,53.52) v4(29.99,53.34) v4(29.81,53.34)
  LAYER_4 w0.175: v4(28.74,53.51) v4(28.74,53.32) v4(28.58,53.41) ; v4(28.74,53.51) v4(28.59,53.6) v4(28.58,53.41) ; v4(28.74,53.51) 28.73,53.51 v4(28.58,53.41) ; v4(28.74,52.33) v4(28.58,52.24) ; v4(28.74,52.33) v4(28.74,52.1) v4(28.58,52.24) ; v4(28.74,52.33) v4(28.74,52.5) v4(28.58,52.42) v4(28.58,52.24) ; v4(30.17,52.48) v4(29.99,52.48) v4(29.81,52.48) ; v4(30.43,53.45) v4(30.61,53.45) v4(30.79,53.45) ; v4(30.45,52.49) v4(30.63,52.49) ; v4(29.81,53.34) v4(29.81,53.52) v4(29.99,53.52) v4(29.99,53.34) v4(29.81,53.34)
  vias: v1(30.48,52.06) v1(33.22,52.96) v1(33.26,53.94) v1(33.53,53.24) v1(33.54,54.21) v1(33.7,52.49) v1(33.71,52.04) v1(33.78,54.45) v1(33.95,53.71) v1(34,53.2) v1(34.04,52.75) v1(34.04,52.27) v1(34.52,54.27) v2(30.48,52.06) v2(33.22,52.96) v2(33.26,53.94) v2(33.53,53.24) v2(33.54,54.21) v2(33.7,52.49) v2(33.71,52.04) v2(33.78,54.45) v2(33.95,53.71) v2(34,53.2) v2(34.04,52.75) v2(34.04,52.27) v2(34.52,54.27) v3(30.48,52.06) v3(33.22,52.96) v3(33.26,53.94) v3(33.53,53.24) v3(33.54,54.21) v3(33.7,52.49) v3(33.71,52.04) v3(33.78,54.45) v3(33.95,53.71) v3(34,53.2) v3(34.04,52.75) v3(34.04,52.27) v3(34.52,54.27) v4(30.48,52.06) v4(33.22,52.96) v4(33.26,53.94) v4(33.53,53.24) v4(33.54,54.21) v4(33.7,52.49) v4(33.71,52.04) v4(33.78,54.45) v4(33.95,53.71) v4(34,53.2) v4(34.04,52.75) v4(34.04,52.27) v4(34.52,54.27)
VREG_S6A_1P35: length 5.9
  TOP w0.2: C2274.2 27.62,56.98 26.95,56.98 26.68,56.71 ; U2000.204 U2000.194
  LAYER_2 w0.175: v6(26.62,55.6) v6(26.79,55.78) ; v6(21.02,55.03) v6(21.17,55.2)
  LAYER_2 w0.2: v1(22.44,56.97) 22.7,56.71 v2(22.7,56.38)
  LAYER_3 w0.175: v6(21.02,55.03) v6(21.17,55.2) ; v6(26.62,55.6) v6(26.79,55.78)
  LAYER_3 w0.2: v6(22.96,55.31) 22.96,56.12 v2(22.7,56.38)
  LAYER_4 w0.175: v6(21.02,55.03) v6(21.17,55.2) ; v6(26.62,55.6) v6(26.79,55.78)
  LAYER_5 w0.175: v6(21.02,55.03) v6(21.17,55.2) ; v6(26.62,55.6) v6(26.79,55.78)
  LAYER_6 w0.175: v6(26.62,55.6) v6(26.79,55.78) ; v6(21.02,55.03) v6(21.17,55.2)
  LAYER_7 w0.175: v6(21.02,55.03) v6(21.17,55.2)
VSNS_DDR: length 5.9
  LAYER_3 w0.045: v2(57.8,51.24) 57.7,51.13 57.7,50.82 57.79,50.73 57.95,50.73 58.25,50.43 58.25,48.38 57.4,47.53 56.62,47.53 v2(56.16,47.07)
VSNS_S1A_M: length 16.6
  LAYER_3 w0.045: v4(24.62,57.63) 24.57,57.68 21.9,57.68 21.75,57.53 21.75,57.31 v2(21.7,57.26)
  LAYER_5 w0.045: v6(24.69,60.46) 24.69,60.19 24.75,60.13 24.75,57.76 v4(24.62,57.63)
  LAYER_7 w0.045: 34.19,61.27 E1056.2
  LAYER_7 w0.05: 34.19,61.27 27.61,61.27 26.8,60.46 v6(24.69,60.46)
VSNS_S1A_P: length 16.1
  LAYER_3 w0.045: v4(24.64,57.36) 24.42,57.58 22.03,57.58 v2(21.92,57.47)
  LAYER_5 w0.045: v6(24.85,60.29) 24.86,60.28 24.86,57.58 v4(24.64,57.36)
  LAYER_7 w0.05: v6(24.85,60.29) 24.9,60.34 26.83,60.34 27.66,61.17 34.27,61.17 34.48,61.38 E1055.2
VSNS_S1B_M: length 9.6
  LAYER_5 w0.045: E1073.1 32.53,48.22 33.47,47.27 33.47,46.43 35.17,44.74 35.17,42.19 36.12,41.24 36.46,41.24 36.59,41.37 36.59,41.5 36.67,41.58 v4(36.77,41.58)
VSNS_S1B_P: length 9.5
  LAYER_5 w0.045: v4(36.29,41.55) 36.43,41.55 36.49,41.49 36.49,41.41 36.41,41.34 36.17,41.34 35.28,42.23 35.28,44.78 33.57,46.49 33.57,47.31 32.55,48.33 32.5,48.33 E1074.1
VSNS_S2A_S3A_M: length 10
  TOP w0.05: U2000.73 v2(21.2,57.71)
  LAYER_3 w0.045: E1069.2 29.3,55.53 29.23,55.59 28.7,55.59 27.5,56.79 27.26,56.79 25.82,58.23 22.72,58.23 22.63,58.31 22.1,58.31 21.49,57.71 v2(21.2,57.71)
VSNS_S2A_S3A_P: length 10.4
  TOP w0.05: U2000.95 U2000.74
  LAYER_3 w0.045: E1068.2 29.61,55.34 29.32,55.34 29.16,55.5 28.66,55.5 27.47,56.68 27.23,56.68 25.78,58.13 22.68,58.13 22.59,58.22 22.13,58.22 v2(21.42,57.5)
VSNS_S2B_M: length 7.4
  LAYER_5 w0.045: v4(37.97,41.85) 37.97,42.05 37.81,42.22 37.81,42.38 38.28,42.85 38.28,46.02 38.66,46.4 38.66,47.41 38.41,47.66 37.99,47.66 37.81,47.84 37.81,48.11 E1115.2
VSNS_S2B_P: length 7.2
  LAYER_5 w0.045: E1114.2 37.7,48.02 37.7,47.79 37.94,47.56 38.37,47.56 38.56,47.37 38.56,46.43 38.18,46.06 38.18,42.89 37.71,42.41 37.71,42.18 37.75,42.15 v4(37.75,42)
VSNS_S3B_S4B_M: length 9.1
  TOP w0.05: U2400.103 U2400.81
  LAYER_3 w0.045: v4(35.96,42.04) 36.09,41.91 36.64,41.91 36.72,41.83 v2(37.02,41.83)
  LAYER_5 w0.045: v4(34.47,48.34) 34.39,48.26 34.39,48.22 33.82,47.65 33.82,46.86 34.02,46.65 34.02,46.4 35.56,44.87 35.56,42.56 35.96,42.16 v4(35.96,42.04)
VSNS_S3B_S4B_P: length 9.4
  LAYER_3 w0.045: v2(37.28,41.56) 37.28,41.8 37.07,42 36.78,42 v2(36.7,42.08) v4(36.19,42.08)
  LAYER_5 w0.045: v4(34.47,48.67) 34.63,48.51 34.63,48.27 34.49,48.13 34.44,48.13 33.92,47.61 33.92,46.9 34.13,46.69 34.13,46.44 35.65,44.91 35.65,42.61 v4(36.19,42.08)
VSNS_S5A: length 12.5
  LAYER_3 w0.045: v4(22.6,51.82) 23.04,51.38 26.96,51.38 27.79,52.21 28.25,52.21 28.44,52.02 28.55,52.02 28.64,51.93 28.9,51.93 28.95,51.98 29.24,51.98 29.26,52.01 29.65,52.01 29.81,52.16 E1070.1
  LAYER_5 w0.045: v4(21.9,55.97) 21.9,55.34 21.9,55.32 22.59,54.63 22.59,51.83 v4(22.6,51.82)
VSNS_S5B_M: length 8
  LAYER_5 w0.045: v6(39.87,46.62) 39.94,46.69 40.51,46.69 E1116.2 ; v6(36.93,46.51) 36.87,46.45 36.87,45.98 36.21,45.33 36.21,43.06 v4(36.28,43)
  LAYER_7 w0.045: v6(39.87,46.62) 39.81,46.56 39.16,46.56 38.99,46.73 36.97,46.73 36.88,46.63 36.88,46.56 v6(36.93,46.51)
VSNS_S5B_P: length 8.3
  LAYER_5 w0.045: v6(36.69,46.51) 36.69,46.5 36.75,46.44 36.75,46 36.12,45.37 36.12,42.84 36.44,42.52 v4(36.44,42.31) ; E1117.2 39.84,46.87 39.71,46.74 v6(39.58,46.74)
  LAYER_7 w0.045: v6(36.69,46.51) 36.69,46.52 36.75,46.58 36.75,46.64 36.93,46.82 39.03,46.82 39.2,46.66 39.5,46.66 v6(39.58,46.74)
WCN_CLK_IN: length 64.5
  LAYER_5 w0.045: v4(19.18,56.24) 18.98,56.24 17.27,57.95 16.05,57.95 15.08,56.98 15.08,39.41 v6(15.17,39.33)
  LAYER_7 w0.045: v6(53.87,37.55) 53.19,38.23 49.58,38.23 46.9,35.55 32.2,35.55 28.7,39.05 15.45,39.05 v6(15.17,39.33)
WCN_XTALI: length 1.8
  LAYER_5 w0.045: v4(54.56,35.53) 54.34,35.75 54.34,36.38 53.87,36.85 v4(53.87,37.02)
WCSS_PWR_REQ: length 75.6
  TOP w0.05: U2400.189 v2(34.94,41.63)
  LAYER_2 w0.045: v2(38.95,59.66) 38.88,59.59 38.85,59.59 v1(38.73,59.46)
  LAYER_3 w0.045: v2(34.94,41.63) 34.94,41.55 35.25,41.23 35.65,41.23 36.13,40.76 37.67,40.76 37.74,40.83 37.87,40.83 37.88,40.82 38.34,40.82 38.39,40.77 46.23,40.77 v4(46.27,40.74) ; v2(21.2,58.64) 21.26,58.7 21.65,58.7 23.64,60.68 23.64,61.81 24.19,62.36 24.19,62.74 v4(24.28,62.83) ; v2(38.95,59.66) 39.1,59.81 39.1,60.24 39.38,60.52 39.38,60.67 39.48,60.77 39.77,60.77 39.86,60.86 40.13,60.86 40.41,61.14 40.41,61.92 40.78,62.29 44.08,62.29 v4(44.11,62.26)
  LAYER_5 w0.045: v4(46.27,40.74) 46.2,40.81 46.2,43.76 46.5,44.06 46.5,46.77 46.18,47.09 46.18,47.75 46.11,47.82 46.11,47.96 46.25,48.1 46.25,57.65 45.22,58.68 45.22,58.89 45.09,59.01 44.76,59.01 44.26,59.51 44.26,61.29 44.04,61.51 44.04,62.19 v4(44.11,62.26) 44.17,62.32 44.17,66.13 42.79,67.5 31.71,67.5 30.39,66.19 29.3,66.19 28.67,65.56 25.1,65.56 24.13,64.59 24.13,63.59 24.28,63.44 v4(24.28,62.83)
WIFI_5G_CH0_HPF_OUT_50R: length 1.4
  TOP w0.088: U4081.4 R4081.2 57.22,31.39 57.22,31.09
WIFI_5G_CH1_HPF_OUT_50R: length 1.3
  TOP w0.088: U4091.4 50.37,32.94 50.07,32.94 49.95,33.06 49.44,33.06 49.38,33.12 U4090.5
WIFI_THERM: length 57.4
  LAYER_3 w0.045: v4(28.8,50.88) 28.74,50.82 28.19,50.82 28.07,50.94 27.92,50.94 27.59,51.27 22.88,51.27 22.35,51.8 22.35,52.86 21.9,53.31 21.9,53.97 21.36,54.51 21.36,54.86 21.66,55.16 21.66,55.77 v2(21.21,56.23)
  LAYER_5 w0.045: v4(28.8,50.88) 28.8,50.77 28.86,50.7 28.86,50.12 28.84,50.1 28.84,49.77 28.69,49.62 28.69,48.86 28.21,48.38 28.21,46.55 28.55,46.22 28.55,40.17 28.3,39.92 28.3,39.21 28.64,38.87 28.64,35.73 35.25,29.12 v6(35.25,28.63)
  LAYER_7 w0.045: v6(35.25,28.63) 35.29,28.59 46.02,28.59 47.63,26.98 50.33,26.98 v6(53.1,29.75)
WL_BB<0>: length 40.5
  LAYER_3 w0.045: v2(39.48,59.68) 39.49,59.68 39.49,59.68 39.62,59.68 39.71,59.77 39.71,60.13 39.83,60.25 42.64,60.25 44.57,62.18 44.96,62.18 45.13,62.35 45.7,62.35 v4(45.8,62.25)
  LAYER_5 w0.045: v4(45.8,62.25) 45.85,62.2 45.85,60.48 46.91,59.42 47.57,59.42 49.33,57.66 49.33,38.19 48.85,37.7 48.85,36.39 49.6,35.64 50.19,35.64 51.26,34.57 v4(53.03,34.57)
WL_BB<1>: length 40.2
  TOP w0.088: U1001.G1 39.87,60.04 v2(39.88,60.05)
  LAYER_3 w0.045: v2(39.88,60.05) 39.88,60.05 39.89,60.05 39.9,60.05 39.9,60.07 39.98,60.15 42.68,60.15 44.61,62.08 45,62.08 45.17,62.25 45.57,62.25 45.73,62.09 45.73,62.04 45.7,62.01 v4(45.59,62.01)
  LAYER_5 w0.045: v4(52.8,34.39) 52.8,34.4 52.73,34.47 51.22,34.47 50.15,35.54 49.56,35.54 48.75,36.35 48.75,37.74 49.23,38.23 49.23,57.61 47.53,59.32 46.87,59.32 45.75,60.44 45.75,62.07 45.68,62.14 45.62,62.14 45.59,62.11 v4(45.59,62.01)
WL_BB<2>: length 39.9
  LAYER_3 w0.045: v2(39.95,59.65) 40.1,59.65 40.16,59.7 40.16,59.84 40.19,59.87 42.76,59.87 44.74,61.85 v4(45.21,61.85)
  LAYER_5 w0.045: v4(45.21,61.85) 45.24,61.88 45.31,61.88 45.46,61.73 45.46,60.3 46.72,59.03 47.42,59.03 48.97,57.47 48.97,38.36 48.49,37.87 48.49,36.22 49.43,35.28 50.04,35.28 51.12,34.2 52.31,34.2 52.57,33.94 52.77,33.94 52.82,33.99 52.82,34.16 52.88,34.22 52.99,34.22 53.03,34.18 v4(53.03,34.13)
WL_BB<3>: length 40.1
  TOP w0.088: v4(52.63,34.11) U4000.114
  LAYER_3 w0.045: v4(45.34,62.08) 45.15,62.08 45.02,61.95 44.7,61.95 42.72,59.97 40.15,59.97 40.01,59.82 39.9,59.82 39.75,59.67 39.75,59.44 v2(39.71,59.4)
  LAYER_5 w0.045: v4(52.63,34.11) 52.44,34.3 51.17,34.3 50.09,35.38 49.47,35.38 48.59,36.26 48.59,37.83 49.07,38.32 49.07,57.52 47.46,59.13 46.77,59.13 45.56,60.34 45.56,61.79 45.34,62.01 v4(45.34,62.08)
WL_BB<4>: length 42.1
  LAYER_3 w0.045: v2(38.89,58.72) 39.27,58.72 39.53,58.97 39.77,58.97 40.4,59.6 42.87,59.6 44.83,61.56 45.59,61.56 45.9,61.86 45.97,61.86 v4(46.03,61.8)
  LAYER_5 w0.045: v4(54.53,34.64) 54.46,34.57 54.22,34.57 54.13,34.48 53.99,34.48 53.63,34.84 53.38,34.84 53.22,34.99 51.46,34.99 50.36,36.09 49.76,36.09 49.3,36.56 49.3,37.51 49.75,37.97 49.75,57.87 47.73,59.89 47.13,59.89 46.43,60.6 46.43,61.7 46.33,61.8 v4(46.03,61.8)
WL_BB<5>: length 41.7
  LAYER_3 w0.045: v2(39.22,58.9) 39.15,58.97 39.15,59.04 39.18,59.07 39.73,59.07 40.36,59.7 42.83,59.7 44.79,61.65 45.55,61.65 45.88,61.98 46.14,61.98 v4(46.16,62)
  LAYER_5 w0.045: v4(46.16,62) 46.21,62.05 46.3,62.05 46.37,61.98 46.37,61.9 46.53,61.74 46.53,60.64 47.18,59.99 47.78,59.99 49.85,57.91 49.85,37.93 49.4,37.47 49.4,36.6 49.8,36.2 50.4,36.2 51.5,35.09 53.26,35.09 53.42,34.94 54.05,34.94 54.12,34.87 54.12,34.71 v4(54.06,34.65)
WL_BB<6>: length 41.6
  LAYER_3 w0.045: v4(46.07,61.44) 46.06,61.44 45.99,61.5 45.89,61.5 45.7,61.32 44.95,61.32 42.94,59.31 40.56,59.31 39.92,58.67 39.7,58.67 39.53,58.5 39.46,58.5 v2(39.19,58.5)
  LAYER_5 w0.045: v4(54.5,34.09) 54.21,34.09 54.08,34.22 53.87,34.22 53.72,34.37 53.38,34.37 53.21,34.54 53.21,34.62 53.09,34.73 51.57,34.73 51.35,34.73 51.34,34.73 50.25,35.82 49.64,35.82 49.01,36.46 49.01,37.6 49.49,38.09 49.49,57.74 47.64,59.6 47.02,59.6 46.13,60.49 46.13,61.37 v4(46.07,61.44)
WL_BB<7>: length 41.5
  LAYER_3 w0.045: v2(39.46,58.66) 39.57,58.77 39.88,58.77 40.52,59.41 42.9,59.41 44.91,61.41 45.66,61.41 45.85,61.6 46.2,61.6 v4(46.22,61.62)
  LAYER_5 w0.045: v4(46.22,61.62) 46.23,61.6 46.23,60.53 47.07,59.7 47.68,59.7 49.59,57.79 49.59,38.05 49.11,37.56 49.11,36.5 49.68,35.92 50.29,35.92 51.38,34.83 51.4,34.83 53.13,34.83 53.31,34.66 53.31,34.59 53.43,34.47 53.77,34.47 53.92,34.32 54.12,34.32 54.22,34.22 54.35,34.22 54.39,34.26 54.39,34.32 v4(54.31,34.4)
WL_BT_RFIO_2G_CH0: length 6.1
  LAYER_5 w0.047: v4(59.84,28.13) 59.84,28.31 arc(59.66,29.19) 59.17,29.93 v4(56.29,32.81)
WL_BT_RFIO_2G_CH0_BYPASS: length 2.6
  LAYER_5 w0.047: v4(59.37,28.02) v4(59.37,25.41)
WL_BT_RFIO_2G_CH0_MAT: length 1.3
  TOP w0.088: C4060.2 60.3,27.56 L4061.2 60.32,27.13 FL4060.1
WL_BT_RFIO_2G_CH1: length 0.7
  TOP w0.088: U4000.73 54.13,32.69 arc(54.06,32.58) 54.04,32.45 C4070.1
WL_BT_RFIO_2G_CH1_A: length 1.6
  TOP w0.088: C4070.2 L4071.2 53.52,31.7 53.52,30.82 FL4070.1
WL_BT_RFIO_2G_CH1_B: length 1.4
  TOP w0.088: FL4070.4 52.63,30.33 L4072.2 C4073.1
WL_BT_RFIO_2G_CH1_BYPASS: length 4.4
  LAYER_5 w0.047: v4(54.5,32.26) arc(54.48,32.16) 54.42,32.07 54.3,31.95 arc(54.18,31.85) 54.06,31.76 53.89,31.66 arc(53.88,31.65) 53.86,31.63 51.88,29.65 arc(51.61,29.47) v4(51.3,29.41)
WL_BT_RFIO_2G_CH1_C: length 0.8
  TOP w0.088: C4073.2 51.3,29.92 51.08,29.92 50.71,30.29 U4070.2
WL_CMD<0>: length 47.2
  LAYER_2 w0.045: v1(37.51,58.69) v2(37.73,58.69)
  LAYER_3 w0.045: v2(37.73,58.69) 37.59,58.82 37.59,59.57 38.08,60.05 38.08,60.3 38.18,60.4 38.18,60.57 38.51,60.89 38.51,61.35 38.65,61.49 38.65,62.19 arc(38.68,62.36) 38.77,62.5 39.24,62.96 arc(39.69,63.26) 40.22,63.37 46.5,63.37 46.71,63.16 47.19,63.16 47.35,63.31 v4(47.35,63.6) ; v2(53.27,35.82) 53.32,35.88 53.32,36.3 52.96,36.66 52.96,37.12 52.85,37.23 52.06,37.23 51.94,37.35 51.79,37.35 51.54,37.1 50.89,37.1 v4(50.86,37.13)
  LAYER_5 w0.045: v4(47.35,63.6) 47.35,63.09 52.74,57.7 52.74,56.31 v7(52.67,56.25) 52.68,56.25 52.74,56.19 52.74,39.92 51.28,38.46 51.28,37.92 50.86,37.51 v4(50.86,37.13)
WL_CMD<1>: length 47.4
  TOP w0.05: U4000.110 v2(52.59,35.83)
  LAYER_3 w0.045: v2(52.59,35.83) 52.56,35.86 51.77,35.86 51.48,36.15 51.48,36.28 51.54,36.34 51.7,36.34 51.76,36.4 51.76,36.66 51.45,36.97 50.73,36.97 50.65,36.89 50.65,36.77 50.7,36.72 v4(50.89,36.72) ; v2(37.7,58.45) 37.5,58.65 37.5,59.61 37.99,60.09 37.99,60.34 38.09,60.44 38.09,60.61 38.41,60.93 38.41,61.39 38.55,61.53 38.55,62.19 arc(38.59,62.39) 38.7,62.56 39.17,63.03 arc(39.17,63.03) 39.18,63.04 39.22,63.08 arc(39.61,63.35) 40.07,63.46 arc(40.09,63.46) 40.11,63.46 arc(40.12,63.46) 40.14,63.46 arc(40.18,63.46) 40.22,63.47 46.54,63.47 46.75,63.26 47.06,63.26 v4(47.18,63.37)
  LAYER_5 w0.045: v4(50.89,36.72) 50.7,36.91 50.7,37.48 51.18,37.96 51.18,38.5 52.65,39.96 52.65,55.98 52.5,56.13 52.5,56.47 52.64,56.61 52.64,57.66 47.18,63.13 v4(47.18,63.37)
WL_CMD<2>: length 48
  LAYER_3 w0.045: v2(54.31,35.39) 54.31,35.57 54.19,35.69 54.19,36.02 54.23,36.06 54.23,36.2 54.13,36.29 54,36.29 53.44,36.85 53.44,37.35 53.03,37.76 52.77,37.76 52.56,37.97 52.18,37.97 52.13,37.92 50.88,37.92 v4(50.82,37.86) ; v2(37.26,58.44) 37.4,58.59 37.4,59.64 37.89,60.13 37.89,60.38 37.99,60.48 37.99,60.65 38.32,60.97 38.32,61.44 38.46,61.58 38.46,62.19 arc(38.5,62.43) 38.64,62.63 39.1,63.1 arc(39.11,63.1) 39.11,63.11 39.16,63.15 arc(39.5,63.4) 39.9,63.53 arc(40.04,63.55) 40.19,63.56 46.58,63.56 46.79,63.35 46.93,63.35 47.09,63.51 v4(47.09,63.59)
  LAYER_5 w0.045: v4(50.82,37.86) 50.91,37.86 51.09,38.04 51.09,38.54 52.55,40 52.55,55.9 52.38,56.06 52.38,56.61 v7(52.45,56.67) 52.45,57.72 47.02,63.15 47.02,63.47 47.09,63.54 v4(47.09,63.59)
WL_CMD<3>: length 48
  LAYER_3 w0.045: v2(54.8,35.39) 54.8,35.59 54.33,36.06 54.33,36.23 54.17,36.39 54.04,36.39 53.53,36.9 53.53,37.4 53.07,37.86 52.8,37.86 52.59,38.06 52.14,38.06 52.09,38.02 50.96,38.02 50.93,38.05 50.93,38.15 50.89,38.19 50.81,38.19 v4(50.72,38.1) ; v4(46.87,63.53) 46.86,63.54 46.73,63.54 46.62,63.66 40.16,63.66 arc(39.91,63.63) 39.65,63.57 arc(39.35,63.43) 39.09,63.22 39.05,63.17 arc(39.04,63.17) 39.04,63.16 38.57,62.7 arc(38.41,62.47) 38.36,62.19 38.36,61.62 38.22,61.48 38.22,61.01 37.9,60.69 37.9,60.52 37.8,60.42 37.8,60.17 37.31,59.68 37.31,58.74 37.28,58.71 37.25,58.71 37.15,58.81 v2(37.15,58.94)
  LAYER_5 w0.045: v4(46.87,63.53) 46.87,63.16 52.28,57.74 52.28,56.01 52.46,55.84 52.46,40.04 50.99,38.57 50.99,38.09 50.95,38.05 50.77,38.05 v4(50.72,38.1)
WL_REF_CLK_OUT_R: length 1.7
  LAYER_5 w0.045: v4(52.33,36.22) 52.75,35.8 53.41,35.8 53.48,35.87 v4(53.8,35.87)
WL_REF_CLK_OUT_R_1: length 1
  TOP w0.088: R4009.1 C4034.2 C4033.2
WL_RF_5G_CH0: length 0.8
  TOP w0.088: U4080.10 55.35,29.35 55.64,29.06 C4050.1
WL_RF_5G_CH0_A: length 1.8
  TOP w0.088: FL4050.1 57.2,28.16 L4051.2 56.13,28.16 55.69,28.6 C4050.2
WL_RF_5G_CH0_B: length 1.4
  TOP w0.088: C4053.1 58.11,26.48 L4052.2 57.29,26.96 FL4050.3
WL_RF_5G_CH1: length 0.9
  TOP w0.088: C4040.1 47.98,35.24 U4090.10
WL_RF_5G_CH1_A: length 1.4
  TOP w0.088: FL4040.1 46.86,34.08 46.86,34.69 L4041.2 C4040.2
WL_RF_5G_CH1_B: length 1.4
  TOP w0.088: FL4040.3 45.81,33.92 45.81,33.23 L4042.2 45.76,33.12 C4043.1
WL_RF_5G_CH1_C: length 0.9
  TOP w0.088: C4043.2 46.94,32.89 46.94,32.36 46.99,32.36
WL_RF_PDET_IN_CH0: length 10.1
  TOP w0.088: R4065.2 56.8,25.34 R4055.2
  LAYER_5 w0.047: v4(56.8,25.85) 55.49,27.15 arc(54.58,28.52) 54.26,30.14 54.26,30.67 arc(54.35,31.15) v4(54.63,31.56) arc(54.92,32) 55.03,32.53 55.03,33.93 arc(54.98,34.15) v4(54.85,34.35)
WL_RF_PDET_IN_CH1: length 10.1
  TOP w0.088: v4(51.62,31.54) R4049.2 51.63,31.53 R4075.2
  LAYER_5 w0.047: v4(46.08,31.76) 50,31.76 arc(50.2,31.72) 50.37,31.61 arc(50.44,31.56) 50.53,31.54 v4(51.62,31.54) arc(51.92,31.6) 52.17,31.77 52.24,31.84 arc(52.6,32.08) 53.02,32.16 53.25,32.16 arc(53.66,32.24) 54.01,32.48 54.1,32.56 arc(54.4,33.01) 54.51,33.55 v4(54.51,33.61)
WL_RF_PDET_IN_CH1_5G: length 0.6
  TOP w0.088: R4075.1 50.71,30.64 U4070.3
WL_RFI_5G_CH0: length 2.2
  TOP w0.088: U4000.50 55.05,32.22 arc(55.08,32.04) 55.19,31.89 arc(55.23,31.82) 55.25,31.75 55.25,31.09 U4080.6
WL_RFI_5G_CH1: length 4.7
  LAYER_3 w0.045: v2(53.02,33.11) 52.84,33.11 arc(52.77,33.1) 52.71,33.05 52.67,33.02 arc(52.59,32.96) 52.49,32.94 51.71,32.94 arc(51.57,32.97) 51.44,33.05 51.01,33.49 arc(50.85,33.59) 50.67,33.63 50.62,33.63 arc(50.34,33.69) 50.1,33.84 49.5,34.45 arc(49.39,34.62) 49.35,34.82 v2(49.35,34.96)
WL_RFO_5G_CH0: length 1.2
  TOP w0.088: U4000.43 55.46,32.7 arc(55.59,32.61) 55.75,32.58 55.92,32.58 arc(56.06,32.52) 56.12,32.39 56.12,32.28 U4081.1
WL_RFO_5G_CH1: length 3
  TOP w0.088: U4000.101 53.27,32.86 52.7,32.3 arc(52.64,32.25) 52.57,32.24 R4092.2 51.54,32.24 arc(51.12,32.41) U4091.1
WLAN1_DAC_RSET: length 0.8
  TOP w0.05: 38.69,59.93 38.53,60.09 38.53,60.65
WLAN2_4G_S1_DIP_50R: length 0.7
  TOP w0.088: U4060.2 59.91,24.76 59.91,25.01 59.86,25.06 59.86,25.36 C4063.2
WLAN2_DAC_RSET: length 0.9
  TOP w0.05: R1172.2 38.97,60.51 38.97,60.02 38.94,59.99 U1001.K2
WLAN5G_S0_DIP_MAT_50R: length 0.6
  TOP w0.088: U4050.2 58.11,25.48 58.11,25.75 58.12,25.75 C4053.2
WLAN_5G_CLK_OUT: length 41.9
  LAYER_3 w0.045: v2(37.02,58.69) 37,58.67 37,58.16 37.3,57.86 37.3,56.62 37.53,56.39 v6(37.71,56.39)
  LAYER_5 w0.045: v4(52.28,36.63) 53.07,36.63 53.41,36.98 53.41,37.93 54.43,38.94 54.43,39.65 54.74,39.96 54.74,51.24 54.41,51.57 v6(54.41,55.82)
  LAYER_7 w0.045: v6(37.71,56.39) 40.28,56.39 42.07,58.18 48.18,58.18 50.54,55.82 v6(54.41,55.82)
WLAN_SW_CTRL: length 82.3
  TOP w0.05: v6(20.96,59.67) 20.96,59.62 U2000.7 ; v4(54.89,36.81) 54.8,36.73 U4000.51
  LAYER_3 w0.045: v6(8.14,43.06) 8.57,42.63 22.28,42.63 22.35,42.7 26.73,42.7 27.06,42.37 27.76,42.37 27.99,42.15 33,42.15 33.18,41.97 33.74,41.97 34.36,41.35 34.83,41.35 35.13,41.05 35.57,41.05 36.27,40.34 37.77,40.34 37.9,40.47 38.05,40.47 38.26,40.26 v2(38.47,40.26) 46.32,40.26 47.86,41.8 48.41,41.8 48.55,41.94 53.83,41.94 54.16,42.27 56.19,42.27 v4(56.19,42.28)
  LAYER_5 w0.045: v4(54.89,36.81) 54.8,36.81 54.54,37.07 54.54,38.01 55.07,38.54 55.48,38.54 56.19,39.24 v4(56.19,42.28)
  LAYER_7 w0.045: v6(8.14,43.06) 8.69,43.61 8.69,49.41 8.15,49.95 8.15,50.71 8.37,50.93 9.97,50.93 12.69,53.65 13.44,53.65 16.68,56.88 17.78,56.88 19.47,58.57 20.1,58.57 20.96,59.42 v6(20.96,59.67)
WMSS_RESET: length 25
  TOP w0.05: R3102.1 25.25,36.6 25.25,38 26.09,38.84 v4(28.05,38.84)
  LAYER_5 w0.045: v4(28.05,38.84) 28.2,39 28.2,39.98 28.45,40.23 28.45,46.17 28.12,46.51 28.12,48.42 28.59,48.9 28.59,49.67 28.74,49.81 28.74,50.16 28.77,50.19 28.77,50.66 28.62,50.81 28.62,50.93 28.73,51.04 29.62,51.04 30.02,51.44 30.08,51.44 v6(30.17,51.53)
  LAYER_7 w0.045: v6(30.17,51.53) 30.9,51.53 31.1,51.72 31.45,51.72 31.93,51.24 32.54,51.24 33.03,51.73 33.03,53.02 32.77,53.28 32.47,53.28 v6(32.05,53.7)
WTR0_GPS_A_50R: length 1.9
  TOP w0.088: L8518.1 20.93,33.91 20.72,33.91 L8519.2 20.57,33.92 20.36,33.92 20.06,33.62 20.06,33.39 19.89,33.39
XO_SDR: length 22.4
  LAYER_5 w0.045: v4(19.18,55.71) 19.18,53.33 19.56,52.95 19.56,51.52 20.45,50.63 20.45,49.95 20.96,49.43 20.96,37.99 20.74,37.76 v6(20.74,36.04)
  LAYER_7 w0.045: v6(22.59,36.04) v6(20.74,36.04)

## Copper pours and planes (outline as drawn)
GND on TOP (solid shape): 41.26,44.77 40.66,44.77 40.66,47.16 41.26,47.16
GND on TOP (solid shape): 25.37,20.59 25.37,20.45 25.22,20.3 25.05,20.3 24.08,19.33 24.08,19.21 23.59,19.21 23.35,18.97 22.88,18.97 22.81,19.04 22.81,19.13 22.87,19.19 23.12,19.19 23.59,19.67 23.86,19.67 24.85,20.65 25.31,20.65
GND on TOP (solid shape): 21.74,21.05 21.74,19.89 21.81,19.83 21.92,19.83 21.96,19.88 21.96,20.58 21.91,20.63 21.91,20.75 21.96,20.8 22.25,20.8 22.25,20.35 22.21,20.31 22.21,20.3 22.21,19.83 21.97,19.53 21.97,19.36 21.93,19.32 21.81,19.32 21.76,19.37 21.76,19.62 21.49,19.89 21.49,20.87 21.4,20.96 21.4,21.06 21.49,21.11 21.69,21.11
